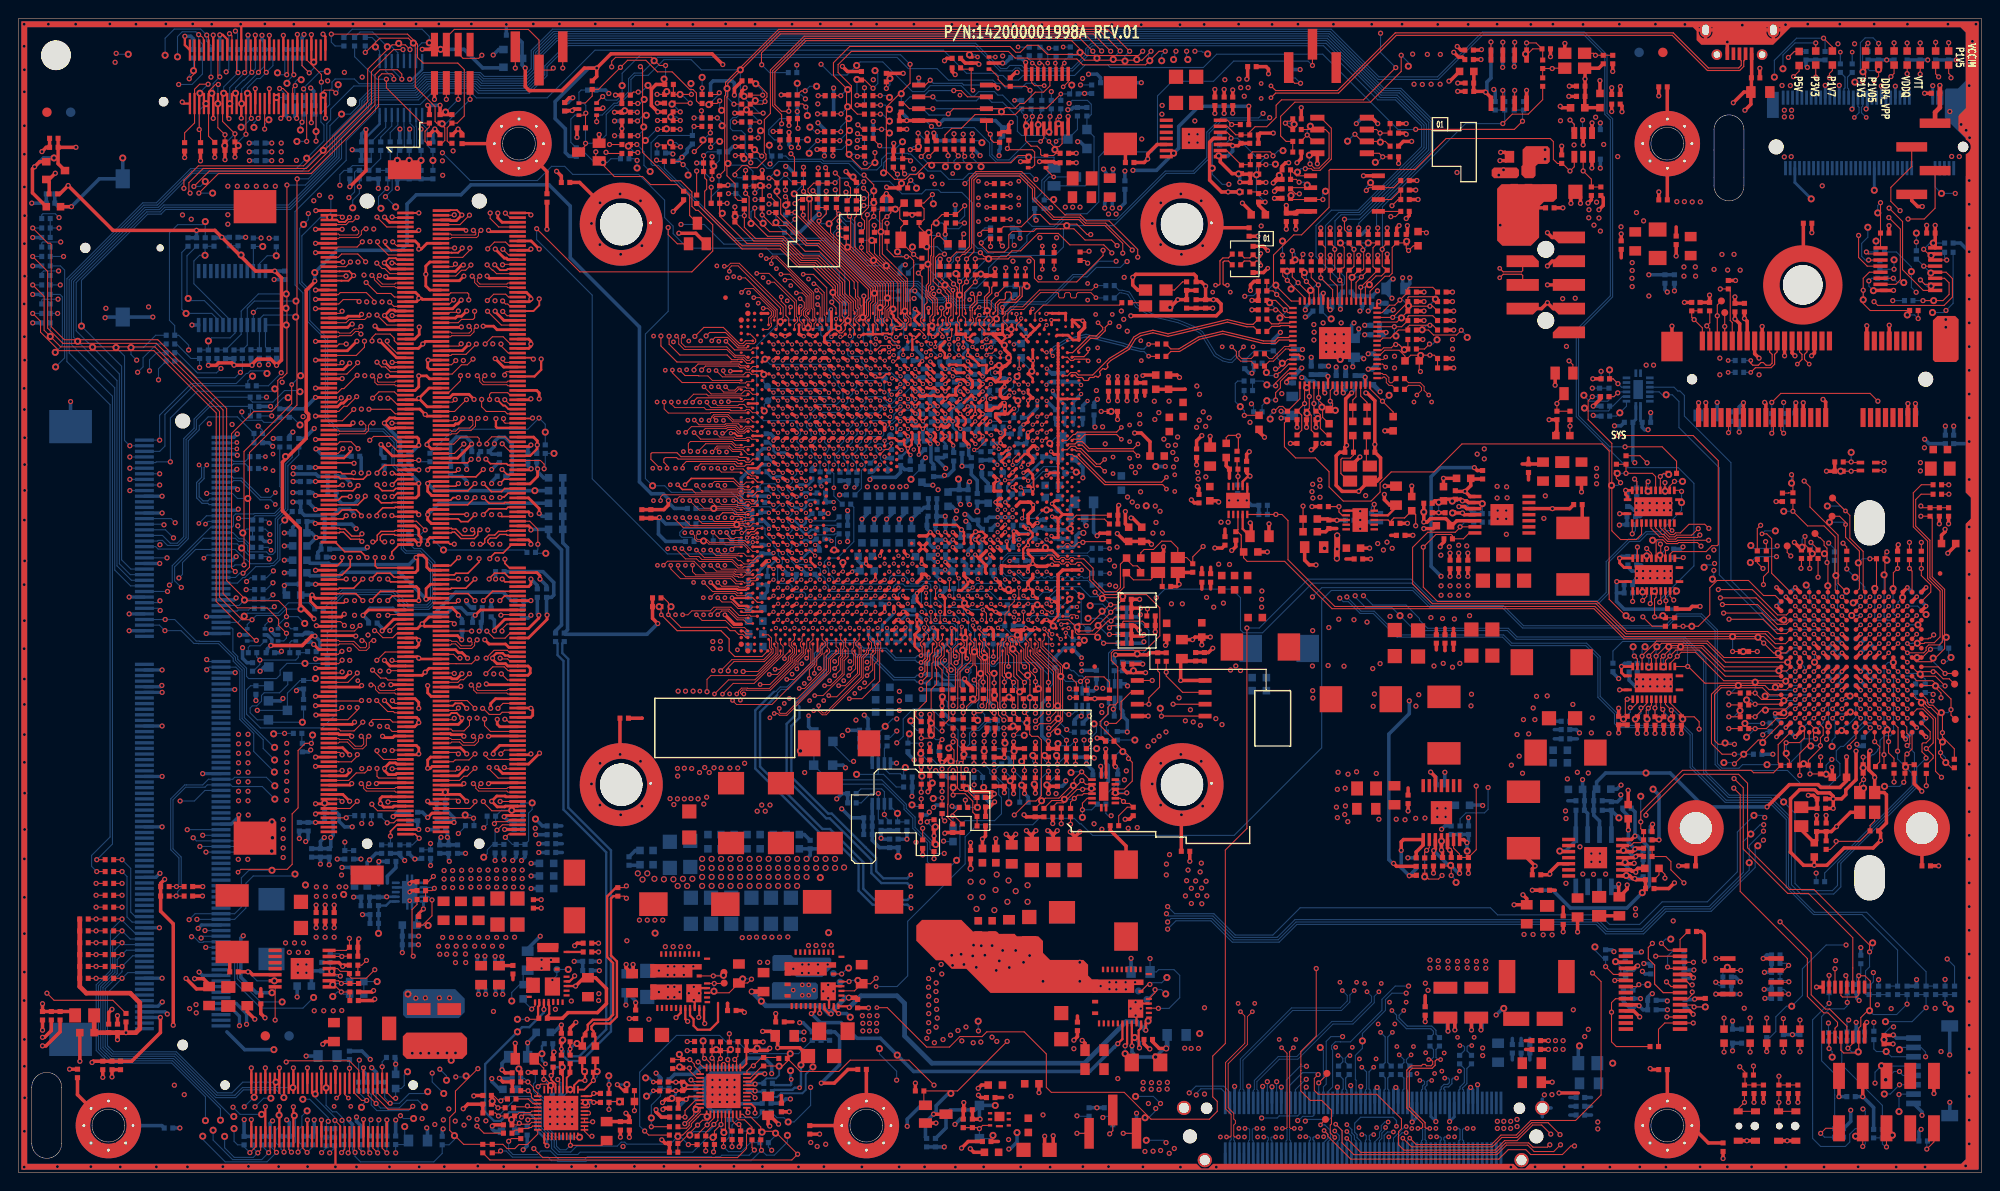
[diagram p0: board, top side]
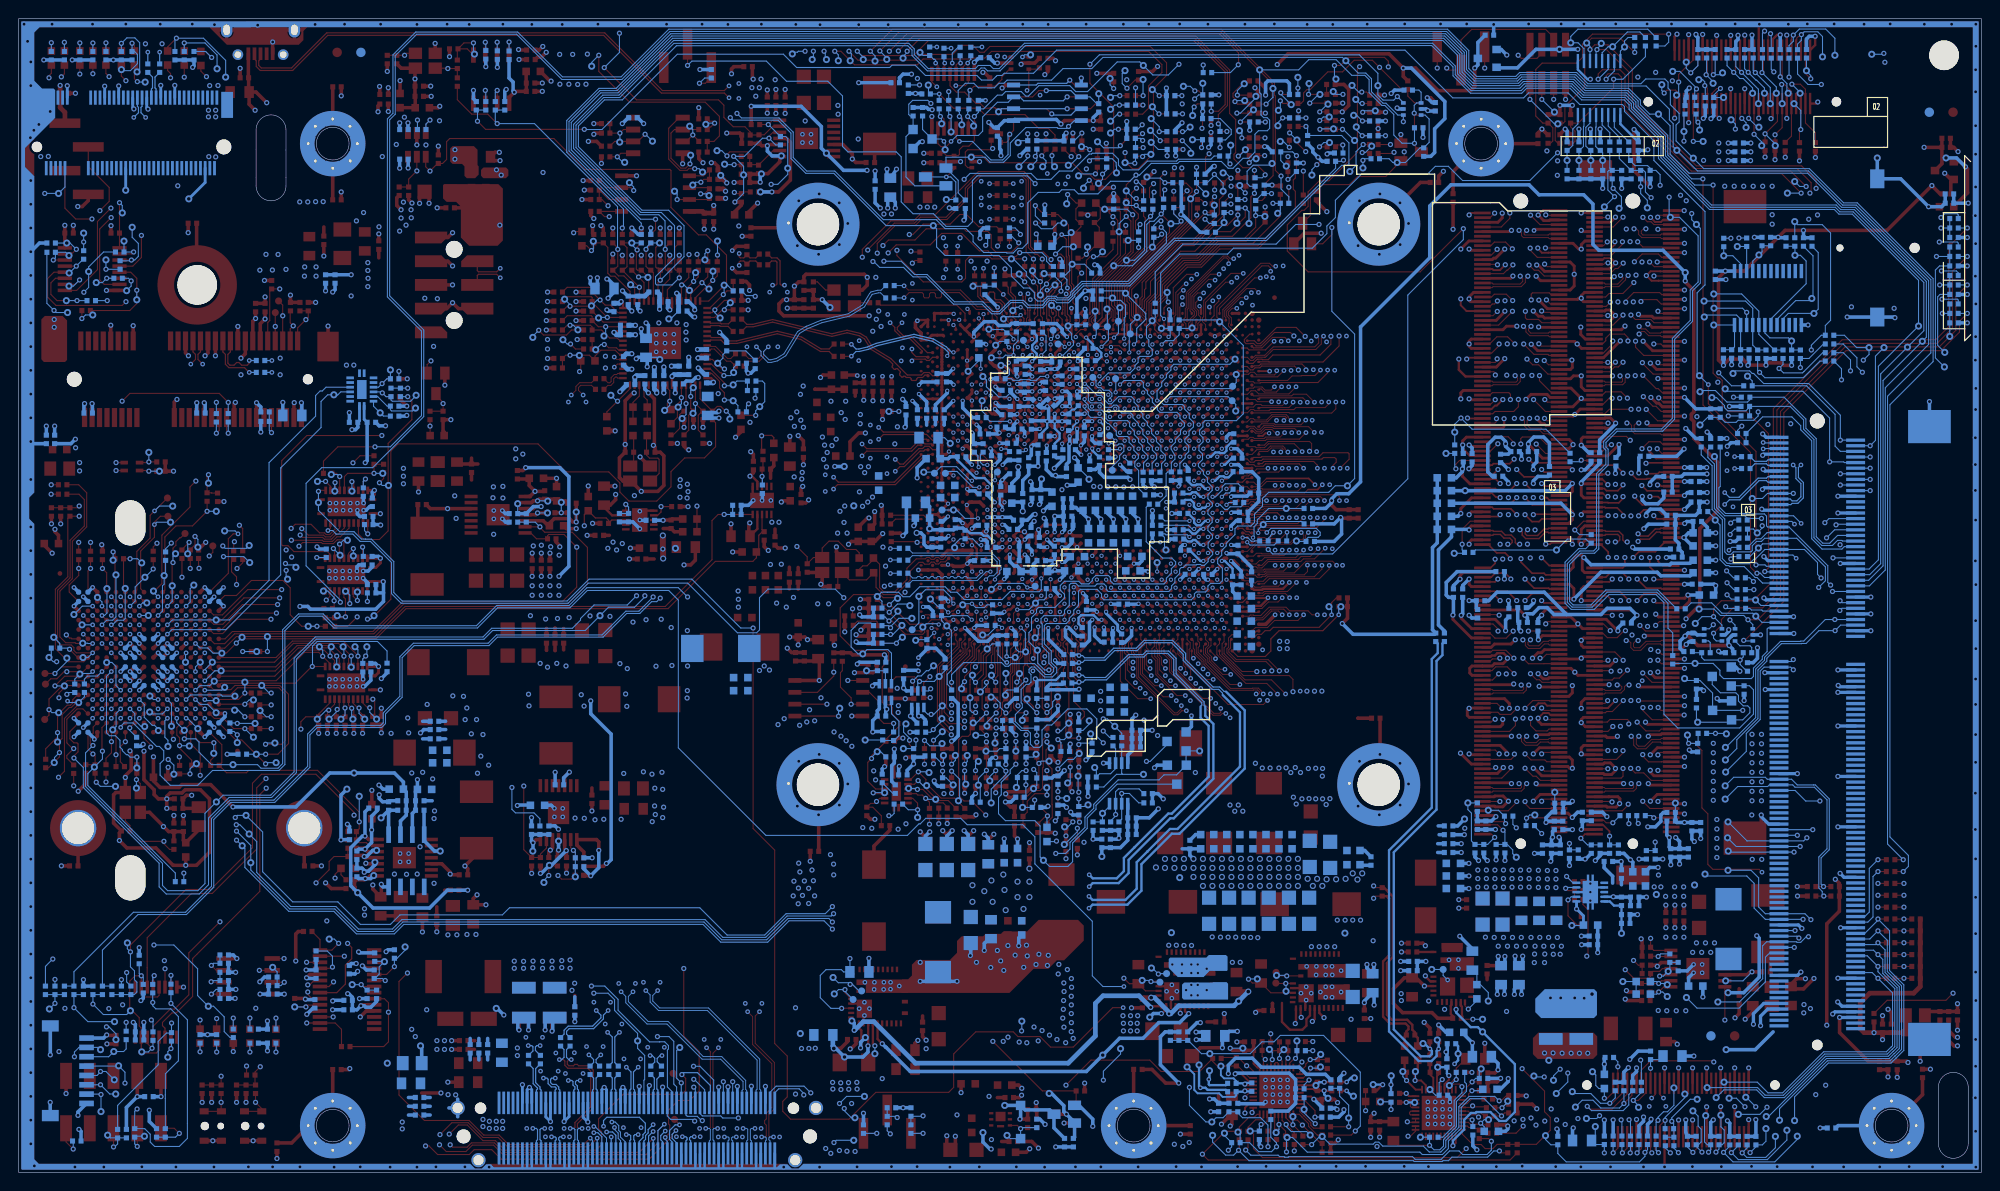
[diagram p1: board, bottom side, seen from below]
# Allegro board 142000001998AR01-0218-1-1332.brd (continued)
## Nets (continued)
GND: BA1.1(-) C1.2 C2.2 C3.2 C4.2 C5.2 C6.2 C7.2 C8.2 C9.1 C10.1 C11.2 C12.2 C13.2 C14.1 C15.2 C16.2 C17.2 C18.2 C19.2 C20.2 C21.1 C22.1 C25.1 C27.2 C28.2 C29.2 C30.2 C31.2 C33.2 C35.2 C36.2 C38.2 C39.2 C41.2 C42.1 C51.2 C52.2 C54.2 C55.2 C58.2 C59.2 C61.2 C63.2 C64.2 C65.2 C66.2 C67.2 C68.1 C69.1 C70.2 C74.1 C75.1 C76.1 C77.1 C78.1 C81.1 C82.2 C83.2 C84.2 C87.1 C88.2 C89.2 C91.2 C92.2 C93.2 C94.2 C96.2 C97.2 C98.2 C99.2 C100.2 C101.2 C102.1 C103.2 C104.2 C105.2 C106.2 C107.2 C108.2 C109.2 C111.2 C112.2 C113.2 C114.2 C115.2 C116.2 C117.2 C118.2 C119.1 C120.1 C121.2 C123.2 C124.1 C125.C C126.2 C127.2 C128.2 C130.2 C131.C C132.C C133.C C134.2 C135.2 C136.2 C137.2 C138.1 C139.2 C140.2 C141.1 C142.1 C143.2 C144.2 C145.2 C146.2 C147.2 C148.2 C149.2 C150.2 C151.2 C152.2 C153.2 C154.2 C155.1 C157.C C158.2 C161.1 C162.1 C163.1 C164.2 C165.2 C166.2 C167.C C168.2 C169.2 C170.1 C171.1 C172.2 C173.2 C174.2 C175.2 C177.1 C181.1 C182.1 C183.1 C184.1 C185.2 C186.2 C187.2 C188.2 C190.2 C191.2 C192.2 C193.2 C194.2 C195.2 C196.2 C197.2 C198.1 C199.2 C200.2 C201.2 C202.2 C203.2 C204.2 C205.1 C206.2 C207.2 C208.2 C209.2 C210.2 C211.2 C212.2 C216.2 C217.2 C218.2 C219.2 C222.2 C224.2 C225.2 C226.1 C227.2 C228.2 C233.2 C234.2 C235.2 C236.2 C239.1 C240.1 C241.2 C242.2 C248.1 C249.1 C250.2 C251.2 C252.2 C253.2 C255.1 C256.1 C257.2 C258.1 C259.2 C260.2 C262.2 C263.2 C264.2 C265.2 C266.2 C267.2 C268.2 C269.2 C270.2 C271.2 C272.1 C273.1 C274.2 C275.2 C278.2 C279.C C280.C C283.2 C284.2 C285.1 C286.1 C287.2 C289.1 C292.1 C293.1 C294.1 C295.1 C296.1 C297.1 C299.1 C300.1 C301.1 C302.1 C303.1 C304.1 C305.1 C306.1 C307.1 C308.1 C309.1 C310.1 C311.1 C312.1 C313.1 C314.1 C315.1 C316.1 C317.1 C318.2 C319.2 C320.1 C321.1 C322.2 C323.1 C324.1 C325.1 C326.1 C327.1 C328.2 C329.1 C330.1 C331.1 C332.2 C333.1 C334.1 C335.2 C336.2 C337.1 C338.1 C339.2 C341.1 C342.1 C343.2 C344.2 C345.2 C346.2 C347.2 C348.2 C349.1 C350.2 C351.1 C352.1 C353.2 C355.2 C356.2 C357.2 C358.2 C359.2 C360.2 C361.1 C362.1 C363.2 C364.1 C365.2 C366.1 C367.1 C368.1 C369.2 C370.2 C371.2 C372.1 C373.2 C374.1 C375.2 C376.2 C377.2 C378.2 C379.1 C380.1 C381.1 C382.1 C383.2 C384.1 C385.1 C386.1 C387.2 C388.1 C389.2 C390.2 C391.2 C392.2 C393.2 C394.2 C395.2 C396.2 C397.1 C398.2 C399.2 C400.2 C401.2 C402.2 C403.2 C404.1 C405.2 C406.1 C407.2 C408.2 C409.1 C410.2 C411.2 C412.2 C413.2 C414.2 C415.1 C416.1 C417.2 C418.1 C419.2 C420.2 C421.2 C422.1 C423.2 C424.2 C425.2 C426.2 C427.2 C428.2 C429.2 C430.1 C431.2 C432.1 C433.1 C434.1 C435.2 C436.2 C437.2 C438.2 C439.2 C441.2 C442.2 C443.2 C444.2 C445.2 C446.2 C447.1 C448.2 C449.2 C450.2 C452.2 C453.2 C454.2 C456.2 C457.2 C458.2 C459.2 C460.2 C461.2 C463.2 C464.2 C465.2 C466.2 C467.2 C468.2 C469.1 C470.2 C471.2 C473.2 C474.2 C475.2 C476.2 C477.2 C478.2 C479.2 C480.2 C481.1 C482.1 C483.2 C484.2 C485.2 C486.2 C487.2 C488.2 C489.1 C490.1 C491.2 C492.1 C493.1 C494.2 C495.1 C496.1 C497.1 C498.2 C499.2 C500.2 C501.2 C502.2 C503.2 C504.1 C505.2 C506.2 C507.2 C508.2 C509.2 C510.2 C511.2 C512.2 C514.2 C515.1 C516.2 C517.1 C518.2 C519.2 C520.2 C521.2 C522.2 C523.2 C524.2 C525.1 C526.2 C527.2 C528.2 C529.2 C530.1 C531.2 C532.2 C533.2 C534.2 C535.2 C536.2 C537.2 C538.2 C539.1 C540.1 C541.2 C542.2 C543.2 C544.2 C545.2 C546.2 C547.2 C548.2 C549.1 C550.2 C551.2 C552.2 C553.2 C554.2 C555.2 C556.2 C557.2 C558.2 C559.2 C560.2 C561.2 C562.2 C563.1 C564.1 C565.1 C566.1 C567.2 C568.2 C569.2 C570.2 C571.2 C572.1 C573.2 C574.2 C575.2 C576.2 C577.2 C578.2 C579.2 C580.2 C581.2 C582.1 C583.1 C584.1 C585.2 C586.2 C587.2 C588.1 C589.2 C590.1 C591.2 C592.2 C595.1 C596.2 C597.1 C598.1 C599.1 C600.2 C601.2 C602.2 C603.2 C604.2 C605.2 C606.2 C607.1 C609.2 C610.2 C611.1 C612.2 C613.1 C614.2 C615.2 C616.2 C627.2 C629.2 C631.2 C632.1 C633.2 C634.2 C635.1 C637.2 C638.1 C639.1 C640.2 C647.1 C648.2 C649.2 C650.1 C651.2 C652.2 C701.2 C702.2 C707.2 C708.2 C900.2 C901.2 C902.2 C903.C C904.2 C905.2 C906.C C907.C C908.2 C909.2 C910.2 C911.1 C912.2 C913.1 C914.1 C915.1 C925.1 C926.1 C927.1 C928.1 C929.1 C930.1 C931.1 C933.1 C934.1 C935.1 C936.1 C937.1 C938.1 C939.1 C941.1 C942.1 C943.1 C944.1 C945.1 C959.1 C960.1 C961.1 C963.2 C964.1 C965.C C966.C C967.2 C968.2 C969.2 C970.2 C971.2 C972.2 C973.2 C974.2 C975.2 C976.2 CONN1.5(GND) CONN1.G1 CONN1.G2 CONN1.G3 CONN1.G4 CONN1.G5 CONN1.G6 CONN3.2 CONN4.1 CONN4.2 CONN4.7 CONN4.8 CONN4.13 CONN4.14 CONN4.19 CONN4.20 CONN4.25 CONN4.26 CONN4.31 CONN4.32 CONN4.37 CONN4.38 CONN4.49 CONN4.50 CONN4.59 CONN4.60 CONN5.1 CONN5.3 CONN5.5 CONN5.7 CONN5.8 CONN6.4(GND1) CONN6.9(GND2) CONN6.15(GND3) CONN6.18(GND4) CONN6.21(GND5) CONN6.26(GND6) CONN6.27(GND7) CONN6.29(GND8) CONN6.34(GND9) CONN6.35(GND10) CONN6.37(GND13) CONN6.40(GND11) CONN6.50(GND12) CONN6.G1 CONN6.G2 CONN7.1(VSS_1) CONN7.2(VSS_2) CONN7.5(VSS_3) CONN7.6(VSS_4) CONN7.9(VSS_5) CONN7.10(VSS_6) CONN7.14(VSS_7) CONN7.15(VSS_8) CONN7.18(VSS_9) CONN7.19(VSS_10) CONN7.22(VSS_11) CONN7.23(VSS_12) CONN7.26(VSS_13) CONN7.27(VSS_14) CONN7.30(VSS_15) CONN7.31(VSS_16) CONN7.35(VSS_17) CONN7.36(VSS_18) CONN7.39(VSS_19) CONN7.40(VSS_20) CONN7.43(VSS_21) CONN7.44(VSS_22) CONN7.47(VSS_23) CONN7.48(VSS_24) CONN7.51(VSS_25) CONN7.52(VSS_26) CONN7.56(VSS_27) CONN7.57(VSS_28) CONN7.60(VSS_29) CONN7.61(VSS_30) CONN7.64(VSS_31) CONN7.65(VSS_32) CONN7.68(VSS_33) CONN7.69(VSS_34) CONN7.72(VSS_35) CONN7.73(VSS_36) CONN7.77(VSS_37) CONN7.78(VSS_38) CONN7.81(VSS_39) CONN7.82(VSS_40) CONN7.85(VSS_41) CONN7.86(VSS_42) CONN7.89(VSS_43) CONN7.90(VSS_44) CONN7.93(VSS_45) CONN7.94(VSS_46) CONN7.98(VSS_47) CONN7.99(VSS_48) CONN7.102(VSS_49) CONN7.103(VSS_50) CONN7.106(VSS_51) CONN7.107(VSS_52) CONN7.167(VSS_53) CONN7.168(VSS_54) CONN7.171(VSS_55) CONN7.172(VSS_56) CONN7.175(VSS_57) CONN7.176(VSS_58) CONN7.180(VSS_59) CONN7.181(VSS_60) CONN7.184(VSS_61) CONN7.185(VSS_62) CONN7.188(VSS_63) CONN7.189(VSS_64) CONN7.192(VSS_65) CONN7.193(VSS_66) CONN7.196(VSS_67) CONN7.197(VSS_68) CONN7.201(VSS_69) CONN7.202(VSS_70) CONN7.205(VSS_71) CONN7.206(VSS_72) CONN7.209(VSS_73) CONN7.210(VSS_74) CONN7.213(VSS_75) CONN7.214(VSS_76) CONN7.217(VSS_77) CONN7.218(VSS_78) CONN7.222(VSS_79) CONN7.223(VSS_80) CONN7.226(VSS_81) CONN7.227(VSS_82) CONN7.230(VSS_83) CONN7.231(VSS_84) CONN7.234(VSS_85) CONN7.235(VSS_86) CONN7.238(VSS_87) CONN7.239(VSS_88) CONN7.243(VSS_89) CONN7.244(VSS_90) CONN7.247(VSS_91) CONN7.248(VSS_92) CONN7.251(VSS_93) CONN7.252(VSS_94) CONN7.G1 CONN7.G2 CONN8.1(VSS_1) CONN8.2(VSS_2) CONN8.5(VSS_3) CONN8.6(VSS_4) CONN8.9(VSS_5) CONN8.10(VSS_6) CONN8.14(VSS_7) CONN8.15(VSS_8) CONN8.18(VSS_9) CONN8.19(VSS_10) CONN8.22(VSS_11) CONN8.23(VSS_12) CONN8.26(VSS_13) CONN8.27(VSS_14) CONN8.30(VSS_15) CONN8.31(VSS_16) CONN8.35(VSS_17) CONN8.36(VSS_18) CONN8.39(VSS_19) CONN8.40(VSS_20) CONN8.43(VSS_21) CONN8.44(VSS_22) CONN8.47(VSS_23) CONN8.48(VSS_24) CONN8.51(VSS_25) CONN8.52(VSS_26) CONN8.56(VSS_27) CONN8.57(VSS_28) CONN8.60(VSS_29) CONN8.61(VSS_30) CONN8.64(VSS_31) CONN8.65(VSS_32) CONN8.68(VSS_33) CONN8.69(VSS_34) CONN8.72(VSS_35) CONN8.73(VSS_36) CONN8.77(VSS_37) CONN8.78(VSS_38) CONN8.81(VSS_39) CONN8.82(VSS_40) CONN8.85(VSS_41) CONN8.86(VSS_42) CONN8.89(VSS_43) CONN8.90(VSS_44) CONN8.93(VSS_45) CONN8.94(VSS_46) CONN8.98(VSS_47) CONN8.99(VSS_48) CONN8.102(VSS_49) CONN8.103(VSS_50) CONN8.106(VSS_51) CONN8.107(VSS_52) CONN8.167(VSS_53) CONN8.168(VSS_54) CONN8.171(VSS_55) CONN8.172(VSS_56) CONN8.175(VSS_57) CONN8.176(VSS_58) CONN8.180(VSS_59) CONN8.181(VSS_60) CONN8.184(VSS_61) CONN8.185(VSS_62) CONN8.188(VSS_63) CONN8.189(VSS_64) CONN8.192(VSS_65) CONN8.193(VSS_66) CONN8.196(VSS_67) CONN8.197(VSS_68) CONN8.201(VSS_69) CONN8.202(VSS_70) CONN8.205(VSS_71) CONN8.206(VSS_72) CONN8.209(VSS_73) CONN8.210(VSS_74) CONN8.213(VSS_75) CONN8.214(VSS_76) CONN8.217(VSS_77) CONN8.218(VSS_78) CONN8.222(VSS_79) CONN8.223(VSS_80) CONN8.226(VSS_81) CONN8.227(VSS_82) CONN8.230(VSS_83) CONN8.231(VSS_84) CONN8.234(VSS_85) CONN8.235(VSS_86) CONN8.238(VSS_87) CONN8.239(VSS_88) CONN8.243(VSS_89) CONN8.244(VSS_90) CONN8.247(VSS_91) CONN8.248(VSS_92) CONN8.251(VSS_93) CONN8.252(VSS_94) CONN8.G1 CONN8.G2 CONN9.2 CONN9.10 CONN11.1 CONN11.2 CONN11.7 CONN11.8 CONN11.13 CONN11.14 CONN11.19 CONN11.20 CONN11.25 CONN11.26 CONN11.31 CONN11.32 CONN11.37 CONN11.38 CONN11.49 CONN11.50 CONN11.59 CONN13.1(PRESENCE_IND(GND)) CONN13.3(GND_1) CONN13.5(GND_2) CONN13.11(GND_3) CONN13.27(GND_4) CONN13.33(GND_5) CONN13.39(GND_6) CONN13.45(GND_7) CONN13.51(GND_8) CONN13.57(GND_9) CONN13.71(GND_10) CONN13.73(GND_11) CONN13.75(USB3.0_IND(OC-USB3.0/GND-OTHER)) CONN13.G1 CONN13.G2 CONN14.1 CONN14.7 CONN14.13 CONN14.19 CONN14.22 CONN14.27 CONN14.28 CONN14.45 CONN14.46 CONN14.58 CONN14.59 CONN14.64 CONN14.65 CONN14.70 CONN14.71 CONN14.76 CONN14.77 CONN14.82 CONN14.83 CONN14.84 CONN14.96 CONN14.113 CONN14.114 CONN14.131 CONN14.132 CONN14.150 CONN14.167 CONN14.168 CONN14.185 CONN14.186 CONN14.195 CONN14.196 CONN14.197 CONN14.198 CONN14.G1 CONN14.G2 CONN15.8 CONN15.G1 CONN15.G2 CONN16.11 CONN16.12 CONN16.13 CONN16.14 CONN16.15 CONN16.16 CONN16.21 CONN16.22 CONN16.23 CONN16.24 CONN16.29 CONN16.30 CONN16.31 CONN16.32 CONN16.37 CONN16.38 CONN16.39 CONN16.40 CONN16.45 CONN16.47 CONN16.53 CONN16.55 CONN16.61 CONN16.65 CONN16.71 CONN16.80 CONN16.86 CONN16.88 CONN16.90 CONN16.95 CONN16.96 CONN16.98 CONN16.99 CONN16.103 CONN16.104 CONN16.106 CONN16.109 CONN16.112 CONN16.114 CONN16.115 CONN16.120 CONN16.G1 CONN16.G2 CONN16.G3 CONN16.G4 CONN18.4 OSC1.2(GND) OSC2.2(GND) OSC4.2(GND) OSC5.2(GND1) OSC5.4(GND2) OSC6.2(GND1) OSC6.4(GND2) Q2.S Q4.S Q5.S Q6.S Q8.S Q9.2(GND) Q10.2(GND) Q11.S Q12.S Q13.S Q14.S Q16.S QFN1.1(CSIN-) QFN1.2(CSIN+) QFN1.4(PGND1) QFN1.12(PGND2) QFN1.13(PGND3) QFN1.21(LGND) QFN1.22(REFIN) R36.2 R42.1 R43.2 R64.2 R71.1 R96.1 R97.1 R99.2 R142.2 R143.2 R152.1 R153.1 R157.1 R169.1 R173.1 R196.1 R199.1 R200.2 R202.2 R211.2 R213.2 R215.2 R216.2 R217.2 R218.1 R220.2 R222.1 R232.2 R245.2 R258.2 R259.2 R260.1 R266.2 R267.1 R268.1 R274.2 R275.2 R282.1 R283.2 R287.2 R289.2 R307.2 R308.1 R310.2 R311.2 R314.1 R318.2 R319.2 R323.2 R334.2 R337.1 R367.1 R377.1 R382.1 R402.2 R417.2 R437.2 R445.2 R458.2 R468.1 R492.1 R515.2 R518.1 R519.2 R520.2 R524.1 R526.1 R527.1 R535.1 R541.2 R542.2 R544.2 R545.2 R547.2 R548.2 R549.2 R550.1 R553.2 R554.2 R555.1 R556.1 R558.1 R561.1 R564.2 R565.2 R568.2 R573.1 R575.1 R578.1 R582.1 R584.2 R586.2 R593.1 R594.2 R595.2 R596.2 R598.2 R599.2 R605.1 R609.2 R612.1 R615.2 R620.2 R623.2 R624.2 R625.2 R627.2 R630.1 R632.1 R637.2 R644.1 R645.2 R672.1 R673.1 R677.1 R679.2 R680.2 R682.2 R685.2 R688.2 R690.2 R692.2 R693.2 R694.1 R700.2 R703.2 R709.2 R720.2 R727.2 R734.2 R737.2 R743.2 R745.1 R746.2 R752.1 R755.2 R757.2 R764.2 R780.2 R785.2 R787.1 R795.2 R797.2 R799.2 R800.2 R821.1 R848.1 R855.1 R856.1 R857.1 R862.1 R863.1 R864.1 R869.2 R882.1 R902.1 R906.2 R948.1 R953.2 R954.2 R955.1 R957.1 R960.1 R970.2 R982.1 R1012.1 R1031.1 R1033.1 R1035.1 R1037.1 R1039.1 R1041.1 R1044.1 R1045.1 R1046.2 R1047.2 R1050.1 R1051.1 R1052.1 R1054.1 R1056.2 R1058.1 R1060.1 R1062.1 R1064.1 R1071.1 R1072.1 R1081.2 R1082.1 R1089.1 R1090.1 R1091.1 R1094.1 R1095.1 SW1.1 SW1.2 SW2.1 SW2.2 U1.4(GND) U2.2(GND) U4.8(PGND1) U4.9(PGND2) U4.G1(PWGD) U5.4(GND) U6.G1(GND) U7.8(GND) U8.6(GND1) U8.G1(GND2) U9.A3(VSS_4) U9.A5(VSS_6) U9.A6(VSS_7) U9.A20(VSS_3) U9.A77(VSS_9) U9.AA12(VSS_537) U9.AA14(VSS_21) U9.AA16(VSS_25) U9.AA19(VSS_518) U9.AA21(VSS_478) U9.AA23(VSS_10) U9.AA25(VSS_11) U9.AA56(VSS_14) U9.AA60(VSS_15) U9.AA62(VSS_16) U9.AA69(VSS_17) U9.AB5(VSS_18) U9.AB74(VSS_19) U9.AC2(VSS_23) U9.AC12(VSS_20) U9.AC16(VSS_22) U9.AC18(VSS_434) U9.AC27(VSS_24) U9.AC58(VSS_26) U9.AD5(VSS_28) U9.AE7(VSS_34) U9.AE11(VSS_29) U9.AE14(VSS_535) U9.AE19(VSS_30) U9.AE23(VSS_31) U9.AE64(VSS_32) U9.AE67(VSS_33) U9.AE71(VSS_35) U9.AF5(VSS_36) U9.AF9(VSS_40) U9.AF74(VSS_37) U9.AF76(VSS_38) U9.AF78(VSS_39) U9.AG12(VSS_536) U9.AG16(VSS_534) U9.AG21(VSS_2) U9.AG62(VSS_41) U9.AH3(VSS_50) U9.AH5(VSS_52) U9.AH12(VSS_42) U9.AH16(VSS_44) U9.AH18(VSS_45) U9.AH19(VSS_46) U9.AH25(VSS_47) U9.AH27(VSS_48) U9.AH28(VSS_49) U9.AH30(VSS_51) U9.AH53(VSS_53) U9.AH56(VSS_55) U9.AH66(VSS_56) U9.AH69(VSS_57) U9.AH74(VSS_58) U9.AK12(VSS_1) U9.AK16(VSS_59) U9.AK19(VSS_60) U9.AK60(VSS_63) U9.AK75(VSS_64) U9.AK77(VSS_65) U9.AL7(VSS_69) U9.AL11(VSS_66) U9.AL64(VSS_67) U9.AL67(VSS_68) U9.AL71(VSS_70) U9.AM9(VSS_75) U9.AM19(VSS_71) U9.AM21(VSS_72) U9.AM28(VSS_73) U9.AM30(VSS_74) U9.AN5(VSS_76) U9.AN74(VSS_77) U9.AN76(VSS_78) U9.AP14(VSS_79) U9.AP19(VSS_80) U9.AP23(VSS_81) U9.AP53(VSS_118) U9.AR1(VSS_84) U9.AR3(VSS_88) U9.AR5(VSS_89) U9.AR12(VSS_85) U9.AR19(VSS_86) U9.AR25(VSS_87) U9.AR53(VSS_125) U9.AR55(VSS_90) U9.AR56(VSS_431) U9.AR60(VSS_91) U9.AU1(VSS_94) U9.AU3(VSS_99) U9.AU5(VSS_101) U9.AU19(VSS_95) U9.AU23(VSS_96) U9.AU25(VSS_97) U9.AU28(VSS_98) U9.AU30(VSS_100) U9.AU53(VSS_192) U9.AU55(VSS_102) U9.AU56(VSS_103) U9.AU58(VSS_104) U9.AU62(VSS_105) U9.AU66(VSS_106) U9.AU69(VSS_107) U9.AU72(VSS_108) U9.AU74(VSS_109) U9.AU76(VSS_54) U9.AU78(VSS_541) U9.AV2(VSS_538) U9.AV64(VSS_110) U9.AV67(VSS_111) U9.AV71(VSS_112) U9.AV75(VSS_113) U9.AV77(VSS_114) U9.AW5(VSS_115) U9.AW9(VSS_116) U9.B2(VSS_117) U9.B3(VSS_530) U9.B48(VSS_531) U9.B61(VSS_5) U9.B74(VSS_93) U9.B76(VSS_256) U9.B77(VSS_119) U9.B78(VSS_120) U9.BA3(VSS_124) U9.BA12(VSS_121) U9.BA16(VSS_122) U9.BA28(VSS_123) U9.BA56(VSS_126) U9.BB2(VSS_533) U9.BB19(VSS_127) U9.BB33(VSS_8) U9.BB35(VSS_128) U9.BD1(VSS_129) U9.BD5(VSS_132) U9.BD14(VSS_130) U9.BD33(VSS_131) U9.BE9(VSS_140) U9.BE28(VSS_133) U9.BE35(VSS_134) U9.BE66(VSS_135) U9.BE69(VSS_136) U9.BE72(VSS_137) U9.BE75(VSS_138) U9.BE77(VSS_139) U9.BF5(VSS_143) U9.BF26(VSS_141) U9.BF30(VSS_142) U9.BF56(VSS_144) U9.BF64(VSS_145) U9.BF67(VSS_146) U9.BF71(VSS_147) U9.BF74(VSS_148) U9.BF76(VSS_149) U9.BF78(VSS_150) U9.BG24(VSS_151) U9.BG35(VSS_152) U9.BG62(VSS_153) U9.BG69(VSS_154) U9.BH3(VSS_158) U9.BH5(VSS_160) U9.BH11(VSS_155) U9.BH14(VSS_156) U9.BH18(VSS_157) U9.BH30(VSS_159) U9.BH60(VSS_161) U9.BH64(VSS_162) U9.BH74(VSS_163) U9.BJ24(VSS_164) U9.BJ35(VSS_165) U9.BJ58(VSS_166) U9.BJ69(VSS_167) U9.BK1(VSS_168) U9.BK5(VSS_170) U9.BK37(VSS_169) U9.BK74(VSS_171) U9.BL30(VSS_172) U9.BL56(VSS_173) U9.BL64(VSS_174) U9.BM9(VSS_182) U9.BM13(VSS_175) U9.BM16(VSS_176) U9.BM20(VSS_177) U9.BM24(VSS_178) U9.BM35(VSS_179) U9.BM58(VSS_193) U9.BM69(VSS_180) U9.BM74(VSS_181) U9.BN30(VSS_183) U9.BN37(VSS_184) U9.BN56(VSS_205) U9.BN60(VSS_185) U9.BN64(VSS_186) U9.BN75(VSS_187) U9.BN77(VSS_188) U9.BP3(VSS_190) U9.BP24(VSS_189) U9.BP35(VSS_191) U9.BP62(VSS_194) U9.BP69(VSS_195) U9.BP74(VSS_196) U9.BR11(VSS_197) U9.BR14(VSS_198) U9.BR18(VSS_199) U9.BR22(VSS_200) U9.BR30(VSS_201) U9.BR64(VSS_202) U9.BT24(VSS_203) U9.BT35(VSS_204) U9.BT56(VSS_206) U9.BT58(VSS_519) U9.BT69(VSS_207) U9.BT74(VSS_208) U9.BU2(VSS_209) U9.BU4(VSS_212) U9.BU30(VSS_210) U9.BU37(VSS_211) U9.BU64(VSS_213) U9.BV9(VSS_220) U9.BV13(VSS_214) U9.BV24(VSS_215) U9.BV35(VSS_216) U9.BV56(VSS_520) U9.BV58(VSS_217) U9.BV62(VSS_218) U9.BV69(VSS_219) U9.BW5(VSS_231) U9.BW7(VSS_238) U9.BW11(VSS_221) U9.BW14(VSS_222) U9.BW30(VSS_223) U9.BW39(VSS_224) U9.BW40(VSS_225) U9.BW42(VSS_226) U9.BW43(VSS_227) U9.BW45(VSS_228) U9.BW47(VSS_229) U9.BW49(VSS_230) U9.BW50(VSS_232) U9.BW52(VSS_233) U9.BW54(VSS_234) U9.BW55(VSS_235) U9.BW60(VSS_236) U9.BW64(VSS_237) U9.BW74(VSS_239) U9.BY16(VSS_240) U9.BY20(VSS_241) U9.BY24(VSS_242) U9.BY28(VSS_243) U9.BY35(VSS_244) U9.BY39(VSS_245) U9.BY43(VSS_246) U9.BY54(VSS_247) U9.BY58(VSS_248) U9.BY62(VSS_249) U9.BY66(VSS_250) U9.BY69(VSS_251) U9.BY72(VSS_252) U9.C1(VSS_253) U9.C2(VSS_254) U9.C20(VSS_255) U9.C77(VSS_257) U9.C78(VSS_258) U9.CA5(VSS_268) U9.CA11(VSS_259) U9.CA18(VSS_260) U9.CA22(VSS_261) U9.CA26(VSS_262) U9.CA30(VSS_263) U9.CA41(VSS_264) U9.CA45(VSS_265) U9.CA46(VSS_266) U9.CA49(VSS_267) U9.CA51(VSS_269) U9.CA52(VSS_270) U9.CA56(VSS_271) U9.CA60(VSS_272) U9.CA64(VSS_273) U9.CA67(VSS_274) U9.CA71(VSS_275) U9.CA74(VSS_276) U9.CA76(VSS_277) U9.CA78(VSS_278) U9.CB16(VSS_279) U9.CB32(VSS_280) U9.CB35(VSS_281) U9.CB47(VSS_282) U9.CB51(VSS_283) U9.CB54(VSS_284) U9.CB58(VSS_285) U9.CB62(VSS_286) U9.CC5(VSS_293) U9.CC11(VSS_287) U9.CC30(VSS_288) U9.CC33(VSS_289) U9.CC37(VSS_290) U9.CC41(VSS_291) U9.CC45(VSS_292) U9.CC74(VSS_294) U9.CD16(VSS_295) U9.CD43(VSS_296) U9.CD47(VSS_297) U9.CD62(VSS_298) U9.CE1(VSS_299) U9.CE3(VSS_300) U9.CE5(VSS_301) U9.CE74(VSS_302) U9.CF11(VSS_303) U9.CF30(VSS_304) U9.CG5(VSS_309) U9.CG16(VSS_305) U9.CG20(VSS_306) U9.CG24(VSS_307) U9.CG28(VSS_308) U9.CG62(VSS_310) U9.CG66(VSS_311) U9.CG69(VSS_312) U9.CG72(VSS_313) U9.CG74(VSS_314) U9.CH11(VSS_315) U9.CH18(VSS_316) U9.CH22(VSS_317) U9.CH26(VSS_318) U9.CH30(VSS_319) U9.CH64(VSS_320) U9.CH67(VSS_321) U9.CH71(VSS_322) U9.CH75(VSS_323) U9.CH77(VSS_324) U9.CJ5(VSS_326) U9.CJ16(VSS_325) U9.CJ62(VSS_327) U9.CJ74(VSS_328) U9.CK11(VSS_329) U9.CK30(VSS_330) U9.CL5(VSS_332) U9.CL16(VSS_331) U9.CL62(VSS_333) U9.CL74(VSS_334) U9.CM1(VSS_335) U9.CM11(VSS_336) U9.CM30(VSS_337) U9.CN5(VSS_338) U9.CN74(VSS_339) U9.CP1(VSS_340) U9.CP2(VSS_345) U9.CP7(VSS_356) U9.CP9(VSS_361) U9.CP12(VSS_341) U9.CP14(VSS_342) U9.CP16(VSS_343) U9.CP18(VSS_344) U9.CP20(VSS_346) U9.CP23(VSS_347) U9.CP25(VSS_348) U9.CP27(VSS_349) U9.CP29(VSS_350) U9.CP31(VSS_351) U9.CP34(VSS_352) U9.CP36(VSS_353) U9.CP64(VSS_354) U9.CP66(VSS_355) U9.CP70(VSS_357) U9.CP72(VSS_358) U9.CP77(VSS_359) U9.CP78(VSS_360) U9.CR1(VSS_362) U9.CR2(VSS_363) U9.CR3(VSS_365) U9.CR5(VSS_367) U9.CR21(VSS_364) U9.CR37(VSS_366) U9.CR77(VSS_368) U9.CR78(VSS_369) U9.CT14(VSS_370) U9.CT29(VSS_371) U9.CT70(VSS_372) U9.CU1(VSS_373) U9.CU2(VSS_374) U9.CU3(VSS_376) U9.CU21(VSS_375) U9.CU37(VSS_377) U9.CU77(VSS_378) U9.CU78(VSS_379) U9.CV2(VSS_381) U9.CV3(VSS_383) U9.CV5(VSS_384) U9.CV6(VSS_385) U9.CV14(VSS_380) U9.CV29(VSS_382) U9.CV70(VSS_386) U9.CV73(VSS_387) U9.CV74(VSS_388) U9.CV76(VSS_389) U9.CV77(VSS_390) U9.D5(VSS_529) U9.D48(VSS_532) U9.D61(VSS_391) U9.E1(VSS_392) U9.E2(VSS_397) U9.E5(VSS_412) U9.E7(VSS_422) U9.E9(VSS_428) U9.E12(VSS_393) U9.E14(VSS_394) U9.E16(VSS_395) U9.E18(VSS_396) U9.E20(VSS_398) U9.E23(VSS_399) U9.E25(VSS_400) U9.E27(VSS_401) U9.E29(VSS_402) U9.E31(VSS_403) U9.E34(VSS_404) U9.E36(VSS_405) U9.E38(VSS_406) U9.E40(VSS_407) U9.E42(VSS_408) U9.E44(VSS_409) U9.E47(VSS_410) U9.E49(VSS_411) U9.E51(VSS_413) U9.E53(VSS_414) U9.E58(VSS_416) U9.E60(VSS_417) U9.E62(VSS_418) U9.E64(VSS_419) U9.E66(VSS_420) U9.E68(VSS_421) U9.E70(VSS_423) U9.E74(VSS_425) U9.E77(VSS_426) U9.E78(VSS_427) U9.F1(VSS_429) U9.F3(VSS_12) U9.F72(VSS_415) U9.F78(VSS_92) U9.H56(VSS_424) U9.H60(VSS_432) U9.H67(VSS_433) U9.J3(VSS_27) U9.J72(VSS_436) U9.J74(VSS_437) U9.K4(VSS_43) U9.K56(VSS_430) U9.K60(VSS_438) U9.K67(VSS_439) U9.L1(VSS_61) U9.L3(VSS_13) U9.L5(VSS_450) U9.L9(VSS_456) U9.L13(VSS_440) U9.L16(VSS_441) U9.L20(VSS_442) U9.L24(VSS_443) U9.L28(VSS_444) U9.L32(VSS_445) U9.L35(VSS_446) U9.L39(VSS_447) U9.L43(VSS_448) U9.L47(VSS_449) U9.L51(VSS_451) U9.L58(VSS_452) U9.L62(VSS_453) U9.L66(VSS_454) U9.L69(VSS_435) U9.L74(VSS_455) U9.M7(VSS_472) U9.M11(VSS_457) U9.M14(VSS_458) U9.M18(VSS_459) U9.M22(VSS_460) U9.M26(VSS_461) U9.M30(VSS_462) U9.M33(VSS_463) U9.M37(VSS_464) U9.M41(VSS_465) U9.M45(VSS_466) U9.M49(VSS_467) U9.M52(VSS_468) U9.M56(VSS_469) U9.M60(VSS_470) U9.M64(VSS_471) U9.M71(VSS_473) U9.N5(VSS_474) U9.N66(VSS_475) U9.N74(VSS_476) U9.N76(VSS_477) U9.P52(VSS_479) U9.P60(VSS_480) U9.R35(VSS_481) U9.R37(VSS_482) U9.R40(VSS_483) U9.R42(VSS_484) U9.R46(VSS_83) U9.R54(VSS_485) U9.R66(VSS_486) U9.R69(VSS_487) U9.T5(VSS_491) U9.T11(VSS_488) U9.T33(VSS_489) U9.T39(VSS_490) U9.T60(VSS_492) U9.T74(VSS_493) U9.U9(VSS_501) U9.U13(VSS_494) U9.U16(VSS_495) U9.U20(VSS_496) U9.U24(VSS_497) U9.U28(VSS_498) U9.U32(VSS_499) U9.U66(VSS_500) U9.V1(VSS_82) U9.V3(VSS_62) U9.V5(VSS_511) U9.V7(VSS_516) U9.V14(VSS_502) U9.V18(VSS_503) U9.V22(VSS_504) U9.V26(VSS_505) U9.V30(VSS_506) U9.V35(VSS_507) U9.V42(VSS_508) U9.V44(VSS_509) U9.V46(VSS_510) U9.V55(VSS_512) U9.V60(VSS_513) U9.V62(VSS_514) U9.V64(VSS_515) U9.V71(VSS_517) U9.W13(VSS_539) U9.W16(VSS_540) U9.W24(VSS_528) U9.Y5(VSS_524) U9.Y39(VSS_521) U9.Y40(VSS_522) U9.Y42(VSS_523) U9.Y55(VSS_525) U9.Y74(VSS_526) U9.Y76(VSS_527) U10.11(GND1) U10.12(GND2) U10.13(GND3) U10.G1 U11.6(GND1) U11.G1(GND2) U12.A1(GNDIO_1) U12.A16(GNDIO_2) U12.B2(GNDIO_4) U12.B15(GNDIO_3) U12.G5(GNDIO_6) U12.G7(GNDIO_7) U12.G8(GNDIO_8) U12.G9(GNDIO_9) U12.G10(GNDIO_5) U12.H7(GNDINT_1) U12.H9(GNDINT_2) U12.J8(GNDINT_4) U12.J10(GNDINT_3) U12.K7(GNDIO_11) U12.K8(GNDIO_12) U12.K9(GNDIO_13) U12.K10(GNDIO_10) U12.R2(GNDIO_15) U12.R15(GNDIO_14) U12.T1(GNDIO_16) U12.T16(GNDIO_17) U13.11(GND1) U13.12(GND2) U13.13(GND3) U13.G1 U14.11(GND1) U14.12(GND2) U14.13(GND3) U14.G1 U15.8(PGND1) U15.9(PGND2) U15.G1(PWGD) U16.4(GND) U17.4(GND_1) U17.11(GND_2) U17.18(GND_3) U18.8(GND1) U18.9(GND2) U18.14(2O\E\) U18.15(1O\E\) U18.G1 U19.4(GND) U20.4(GND) U21.8(GND) U22.8(PGND1) U22.9(PGND2) U22.G1(PWGD) U23.8(PGND1) U23.9(PGND2) U23.G1(PWGD) U24.4(PGND1) U24.16(PGND2) U24.17(PGND3) U24.28(LGND) U24.31(PGND4) U25.4(PGND1) U25.16(PGND2) U25.17(PGND3) U25.28(LGND) U25.31(PGND4) U26.4(PGND1) U26.16(PGND2) U26.17(PGND3) U26.28(LGND) U26.31(PGND4) U27.8(PGND1) U27.9(PGND2) U27.G1(PWGD) U28.23(PWM3) U28.24(PWM4) U28.G1(GND) U29.22(PWM2) U29.23(PWM3) U29.24(PWM2_L2) U29.25(PWM1_L2) U29.G1 U31.4(GND) U32.2(GND) U33.12(GND) U34.8(GND1) U34.9(GND2) U34.14(2O\E\) U34.15(1O\E\) U34.G1 U35.5(GND1) U35.6(GND2) U35.7(GND3) U35.8(GND4) U36.4(GND) U37.4(PGND) U37.8(GND) U37.11(PWPD) U38.2(GND) U39.4(GND) U40.2(GND) U41.2(GND) U42.2(GND) U43.8(GND) U44.2(GND) U45.8(VSS)
GND_SCREW1: C234.1 C637.1 H7.1 H7.2 H7.3 H7.4 H7.5 H7.6 H7.7 H7.8
GND_SCREW2: C3.1 C36.1 H2.1 H2.2 H2.3 H2.4 H2.5 H2.6 H2.7 H2.8
GND_SCREW3: C228.1 C257.1 H8.1 H8.2 H8.3 H8.4 H8.5 H8.6 H8.7 H8.8
GND_SCREW4: C15.1 C35.1 H1.1 H1.2 H1.3 H1.4 H1.5 H1.6 H1.7 H1.8
GND_SCREW5: C227.1 C253.1 H9.1 H9.2 H9.3 H9.4 H9.5 H9.6 H9.7 H9.8
P0V6_VTT: C520.1 C521.1 C523.1 C524.1 C564.2 C566.2 C568.1 C569.1 CONN7.258(VTT) CONN8.258(VTT) U37.3(VO) U37.5(VOSNS)
P0V9_A_L_I210: C933.2 C934.2 C935.2 C936.2 C937.2 C938.2 C939.2 C959.2 U6.11(VDD0P9_11) U6.32(VDD0P9_32) U6.38(VDD0P9_OUT) U6.42(VDD0P9_42) U6.59(VDD0P9_59)
P1V2_VDD_BOOST: QFN1.17(BOOST) R710.2
P1V2_VDD_BOOST_R: C594.2 R710.1
P1V2_VDDQ: C161.2 C162.2 C163.2 C165.1 C166.1 C328.1 C335.1 C336.1 C339.1 C343.1 C344.1 C345.1 C346.1 C347.1 C348.1 C350.1 C353.1 C359.1 C360.1 C363.1 C365.1 C369.1 C370.1 C371.1 C373.1 C376.1 C377.1 C378.1 C383.1 C387.1 C389.1 C395.1 C400.1 C401.1 C403.1 C405.1 C407.1 C408.1 C410.1 C420.1 C421.1 C423.1 C429.1 C439.1 C442.1 C444.1 C446.1 C450.1 C459.1 C463.1 C465.1 C466.1 C467.1 C468.1 C470.1 C471.1 C473.1 C474.1 C475.1 C476.1 C483.1 C484.1 C485.1 C486.1 C487.1 C488.1 C491.1 C494.1 C498.1 C525.2 C530.2 C539.2 C549.2 C565.2 C572.2 C574.1 C575.1 C582.2 C583.2 C584.2 C586.1 C587.1 CONN7.111(VDD_1) CONN7.112(VDD_2) CONN7.117(VDD_3) CONN7.118(VDD_4) CONN7.123(VDD_5) CONN7.124(VDD_6) CONN7.129(VDD_7) CONN7.130(VDD_8) CONN7.135(VDD_9) CONN7.136(VDD_10) CONN7.141(VDD_11) CONN7.142(VDD_12) CONN7.147(VDD_13) CONN7.148(VDD_14) CONN7.153(VDD_15) CONN7.154(VDD_16) CONN7.159(VDD_17) CONN7.160(VDD_18) CONN7.163(VDD_19) CONN8.111(VDD_1) CONN8.112(VDD_2) CONN8.117(VDD_3) CONN8.118(VDD_4) CONN8.123(VDD_5) CONN8.124(VDD_6) CONN8.129(VDD_7) CONN8.130(VDD_8) CONN8.135(VDD_9) CONN8.136(VDD_10) CONN8.141(VDD_11) CONN8.142(VDD_12) CONN8.147(VDD_13) CONN8.148(VDD_14) CONN8.153(VDD_15) CONN8.154(VDD_16) CONN8.159(VDD_17) CONN8.160(VDD_18) CONN8.163(VDD_19) L14.2 R333.1 R350.1 R580.1 R592.1 R693.1 R699.1 U9.CF60(VCCD_14) U9.CG43(VCCD_1) U9.CG51(VCCD_2) U9.CG54(VCCD_12) U9.CG58(VCCD_3) U9.CH33(VCCD_4) U9.CH37(VCCD_5) U9.CH41(VCCD_6) U9.CH45(VCCD_7) U9.CH49(VCCD_8) U9.CH56(VCCD_10) U9.CJ39(VCCD_13) U9.CK52(VCCD_34) U9.CK60(VCCD_11) U9.CL35(VCCD_9) U9.CL58(VCCD_37) U9.CP38(VCCD_15) U9.CP40(VCCD_16) U9.CP42(VCCD_17) U9.CP44(VCCD_18) U9.CP47(VCCD_19) U9.CP49(VCCD_20) U9.CP51(VCCD_21) U9.CP53(VCCD_22) U9.CP55(VCCD_23) U9.CP58(VCCD_24) U9.CP60(VCCD_25) U9.CP62(VCCD_38) U9.CP68(VCCD_39) U9.CT55(VCCD_26) U9.CU39(VCCD_27) U9.CU43(VCCD_28) U9.CU48(VCCD_29) U9.CU52(VCCD_30) U9.CU59(VCCD_31) U9.CU63(VCCD_32) U9.CU65(VCCD_35) U9.CU67(VCCD_33) U9.CU69(VCCD_36) U37.2(VLDOIN)
P1V2_VDDQ_IRQ_VRHOT_N: U12.P11(IO_4_P11/DIFFIO_B21P) U29.16(VRHOT_CRIT)
P1V05: C52.1 C100.1 C114.1 C128.1 C143.1 C144.1 C145.1 C146.1 C147.1 C148.1 C149.1 C150.1 C151.1 C152.1 C279.A C291.1 C318.1 C385.2 C396.1 C443.1 C509.1 C510.1 C511.1 C512.1 C545.1 C546.1 C547.1 C548.1 C555.1 C556.1 C557.1 C558.1 C559.1 C560.1 C906.A C974.1 L7.1 L8.1 L9.1 L10.1 L17.2 L32.1 L33.1 Q9.6(VCCB) Q10.1(VCCA) R20.1 R58.2 R59.2 R60.2 R148.2 R203.2 R204.2 R206.2 R208.2 R209.2 R210.2 R214.2 R219.1 R237.2 R244.2 R250.2 R251.2 R261.1 R262.1 R263.1 R264.1 R269.2 R270.2 R271.2 R272.2 R276.1 R284.1 R285.2 R290.2 R291.2 R292.2 R294.2 R295.2 R296.2 R305.1 R306.2 R309.2 R369.1 R374.2 R379.2 R453.1 R463.1 R563.2 R572.1 R583.1 R587.1 R590.2 R597.2 R602.1 R604.2 R610.1 R614.1 R616.1 R617.2 R626.1 R628.2 R633.1 R635.1 R636.1 R638.1 R639.1 R642.1 R643.1 R725.1 R726.2 R730.2 R738.2 R739.2 R749.1 R760.2 R765.2 R766.2 R767.2 R768.2 R769.2 R771.2 R772.2 R773.2 R774.2 R793.2 R794.1 R796.1 R798.1 R1048.1 R1049.2 R1053.2 U10.1(VCCA) U13.23(VCCB1) U13.24(VCCB2) U14.1(VCCA) U18.16(VCCB) U34.1(VCCA) U36.1(VCCA)
P1V5_A_L_I210: C941.2 C942.2 C943.2 C944.2 C945.2 C960.2 U6.39(VDD1P5_OUT) U6.47(VDD1P5_47) U6.51(VDD3P3_51)
P1V05_PCH: C68.2 C69.2 C74.2 C75.2 C76.2 C77.2 C78.2 C299.2 C300.2 C302.2 C311.2 C313.2 C314.2 C315.2 C316.2 C317.2 C331.2 L7.2 L34.1 U9.AC23(VCCCLK_4) U9.AC25(VCCCLK_2) U9.AE21(VCCCLK_1) U9.AE25(VCCCLK_6) U9.AG25(VCCCLK_8) U9.AG27(VCCIO_5) U9.AH21(VCCIO_1) U9.AH23(VCCCLK_5) U9.AK18(VCCIO_2) U9.AK27(VCCIO_6) U9.AM14(VCCUSBPLL) U9.AM16(VCCIO_3) U9.AM18(VCCIO_4) U9.AM27(VCCIO_7) U9.AP27(VCCIO_8) U9.AR27(VCCIO_9) U9.AU27(VCCIO_10) U9.AW27(VCCIO_11)
P1V5_PCH: C87.2 C88.1 C90.2 C93.1 C94.1 C303.2 C322.1 C323.2 C325.2 C330.2 C338.2 C341.2 C349.2 C352.2 R5.1 R180.1 R192.2 R487.1 R543.1 U9.AC28(VCCVRM_10) U9.AC30(VCCVRM_2) U9.AE28(VCCVRM_5) U9.AE30(VCCVRM_6) U9.AG19(VCCADAC1_5) U9.AK28(VCCVRM_8) U9.AK30(VCCVRM_9) U9.AW28(VCCVRM_1) U9.AW30(VCCVRM_7) U9.BA30(VCCVRM_4) U9.BB30(VCCVRM_3) U9.BD30(SATA_IREF) U9.V33(SOC_IREF) U9.W20(ICLK_IREF) U9.W28(PCIE_IREF) U11.9(OUT1) U11.10(OUT2)
P1V05_PCH_FLT: C305.2 C310.2 C362.2 L33.2 U9.AC21(VCCCLK_3) U9.AG23(VCCCLK_7)
P1V05_VCC_PCH: C308.2 C309.2 C320.2 C321.2 C326.2 C334.2 L8.2 U9.AK21(VCC_1) U9.AK23(VCC_2) U9.AK25(VCC_3) U9.AM23(VCC_4) U9.AM25(VCC_5) U9.AP25(VCC_6)
P1V05_VCCGBE: C104.1 C105.1 C106.1 C107.1 C419.1 C456.1 C457.1 C458.1 C965.A C966.A C967.1 C968.1 C969.1 C970.1 C971.1 C972.1 C973.1 C975.1 C976.1 L10.2 L30.2 L35.2 U9.AA58(VCCGBE_1) U9.R58(VCCGBE_11) U9.T51(VCCGBE_6) U9.T53(VCCGBE_7) U9.V51(VCCGBE_8) U9.V53(VCCGBE_9) U9.V56(VCCGBE_2) U9.V58(VCCGBE_3) U9.Y53(VCCGBE_10) U9.Y56(VCCGBE_4) U9.Y58(VCCGBE_5)
P1V05_VCCION: C306.2 C329.2 C386.2 C397.2 C404.2 C415.2 C416.2 C422.2 C430.2 C447.2 L9.2 U9.AC53(VCCIOIN_10) U9.AC55(VCCIOIN_11) U9.AH55(VCCIOIN_6) U9.AK53(VCCIOIN_7) U9.AK55(VCCIOIN_8) U9.AM53(VCCIOIN_9) U9.AP18(VCCIOIN_5) U9.AP21(VCCIOIN_1) U9.AR18(VCCIOIN_4) U9.AR21(VCCIOIN_2) U9.AR23(VCCIOIN_3) U9.BB25(P1V05_PROC_IO)
P1V05_VCCSCSUS: C372.2 C374.2 C384.2 C406.2 L32.2 U9.R48(VCCSCSUS_1) U9.R49(VCCSCSUS_2) U9.T48(VCCSCSUS_3) U9.T49(VCCSCSUS_4) U9.V48(VCCSCSUS_5) U9.V49(VCCSCSUS_6)
P1V7_AGND: C156.2 R310.1 R698.2 U22.5(GND)
P1V7_SS: R316.1 U22.4(SS)
P1V7_SS_C: C156.1 R316.2
P1V7_SW: C159.1 L13.1 U22.10(SW1) U22.11(SW2)
P1V7_VBST: C159.2 U22.12(VBST)
P1V7_VO: C160.1 R328.1 R330.2 U22.1(VO)
P1V7_VO_R: R324.1 R328.2
P1V7_VREG: C571.1 R697.2 U22.3(VREG5)
P3V3: C11.1 C30.1 C31.1 C54.1 C58.1 C61.1 C111.1 C112.1 C113.1 C153.1 C154.1 C183.2 C184.2 C185.1 C187.1 C188.1 C262.1 C267.1 C269.1 C271.1 C280.A C319.1 C464.1 C469.2 C508.1 C515.2 C516.1 C517.2 C544.1 C589.1 C592.1 C640.1 C647.2 C901.1 C902.1 C903.A C910.1 C911.2 C912.1 C913.2 C914.2 C915.2 CONN4.43 CONN4.44 CONN6.2(3.3VAUX_0) CONN6.24(3.3VAUX_1) CONN6.39(3.3VAUX_2) CONN6.41(3.3VAUX_3) CONN6.52(3.3VAUX_4) CONN15.1 CONN18.1 L6.2 L20.2 L29.2 L31.2 L36.2 L42.1 LED11.A LED15.A Q7.A2 Q9.1(VCCA) R22.1 R24.2 R30.1 R33.1 R39.2 R50.2 R55.2 R56.2 R57.2 R90.2 R94.1 R95.2 R108.2 R109.2 R156.2 R164.2 R188.2 R201.2 R212.2 R234.2 R235.2 R249.1 R293.2 R298.1 R300.1 R312.2 R313.2 R383.1 R414.2 R415.2 R416.2 R418.2 R419.2 R420.2 R421.2 R422.2 R429.1 R430.2 R432.2 R433.2 R436.2 R438.2 R442.2 R443.2 R446.2 R447.1 R448.2 R449.2 R452.2 R454.1 R456.2 R457.2 R459.1 R461.2 R467.2 R470.2 R478.2 R481.2 R483.1 R485.1 R501.1 R502.2 R516.1 R521.1 R523.1 R577.2 R601.1 R603.1 R607.1 R618.1 R631.2 R651.2 R660.2 R661.1 R663.2 R686.1 R687.2 R717.2 R718.2 R721.2 R722.2 R761.2 R849.1 R875.1 R883.1 R901.1 R905.1 R922.1 R931.1 R932.1 R933.1 R934.1 R935.1 R942.1 R943.1 R1057.1 R1059.1 R1061.1 R1063.1 R1065.1 R1066.1 R1067.2 R1068.2 R1083.1 R1084.1 R1085.1 U2.5(VCC) U7.16(VCC) U13.1(VCCA) U16.8(VCC) U17.10(VDD_2) U17.24(VDD_4) U18.1(VCCA) U19.8(VCC) U20.8(VCC) U32.5(VCC) U34.16(VCCB) U38.1(VCCA) U42.5(VCC) U43.16(VCC) U44.5(VCC)
P3V3_A: C55.1 C59.1 C83.1 C115.1 C116.1 C117.1 C119.2 C120.2 C196.1 C197.1 C198.2 C250.1 C251.1 C278.1 C283.1 C290.2 C298.2 C355.1 C356.1 C357.1 C358.1 C398.1 C399.1 C411.1 C414.1 C435.1 C438.1 C452.1 C453.1 C477.1 C478.1 C479.1 C480.1 C500.1 C502.1 C567.1 C570.1 C590.2 C707.1 C904.1 C907.A CONN9.4 L5.1 L11.2 L22.1 L49.1 R93.1 R155.2 R187.1 R277.1 R375.1 R390.1 R391.1 R404.1 R405.1 R406.1 R407.1 R408.1 R409.1 R410.1 R411.1 R412.1 R413.1 R491.2 R494.2 R495.1 R496.1 R503.1 R525.2 R528.2 R530.2 R532.2 R533.2 R608.2 R646.1 R654.1 R657.1 R658.1 R659.1 R665.2 R675.1 R678.2 R681.2 R683.2 R684.2 R689.2 R691.2 R705.1 R707.1 R712.1 R753.2 R783.2 R910.1 R921.1 U12.A3(VCCIO2_4) U12.A14(VCCIO2_1) U12.C1(VCCIO1_1) U12.C16(VCCIO3_4) U12.F8(VCCIO2_3) U12.F9(VCCIO2_2) U12.H6(VCCIO1_2) U12.H11(VCCIO3_3) U12.J6(VCCIO1_3) U12.J11(VCCIO3_2) U12.L8(VCCIO4_2) U12.L9(VCCIO4_3) U12.P1(VCCIO1_4) U12.P16(VCCIO3_1) U12.T3(VCCIO4_1) U12.T14(VCCIO4_4) U21.16(VCC) U33.24(VDD) U35.2(VIN)
P3V3_A_L_I210: C6.1 C7.1 C16.1 C17.1 C284.1 C288.2 C290.1 C298.1 C648.1 C651.1 C708.1 C925.2 C926.2 C927.2 C928.2 C929.2 C930.2 C931.2 C961.2 C963.1 L1.1 L3.2 L49.2 LED18.A R801.2 R802.1 R807.1 R808.1 R813.2 R814.2 R815.2 R816.2 R817.2 R818.2 R822.2 R828.2 R829.2 R920.2 R961.1 R975.2 R976.2 R977.2 R978.2 R979.1 R999.1 R1001.1 R1003.1 R1005.1 R1007.1 R1009.1 R1011.1 R1034.1 R1038.1 R1040.1 R1042.1 R1043.1 U6.10(VDD3P3_10) U6.27(VDD3P3_27) U6.41(VDD3P3_41) U6.64(VDD3P3_64) U38.6(VCCB) U39.8(VCC)
P3V3_A_Q3: Q3.A2 R93.2
P3V3_AB: R391.2 R729.2 R758.2 U29.28(VCC)
P3V3_BATT: C14.2 C21.2 C297.2 Q3.C R117.1 R140.2 R499.2 R505.2 U9.AW14(VCCRTC)
P3V3_L_PCH: C236.1 C239.2 L42.2 U30.1(D1) U30.2(D2) U30.5(D3) U30.6(D4) U30.8(D5)
P3V3_LED13: LED13.A R721.1
P3V3_LED14: LED14.A R722.1
P3V3_PCH: C256.2 C259.1 C286.2 C289.2 C292.2 C293.2 C294.2 C295.2 C296.2 C304.2 C324.2 C333.2 C351.2 C375.1 C445.1 C499.1 C905.1 L41.2 Q10.6(VCCB) R9.1 R10.2 R11.2 R14.2 R17.1 R23.1 R28.2 R53.1 R63.1 R84.2 R85.2 R89.2 R91.2 R431.1 R466.2 R473.2 R567.1 U9.AC14(VCCCLK3_3_3) U9.AC19(VCCADACBG3_3) U9.AE12(VCCCLK3_3_4) U9.AE16(VCCCLK3_3_1) U9.AE18(VCCCLK3_3_2) U9.AG14(VCCCLK3_3_6) U9.AG18(VCC3_3_5) U9.AG28(VCC3_3_6) U9.AG30(VCC3_3_7) U9.AH14(VCCCLK3_3_5) U9.AM12(VCC3_3_1) U9.AU12(VCC3_3_4) U9.AW25(VCC3_3_2) U9.BA25(VCC3_3_3) U10.23(VCCB1) U10.24(VCCB2) U14.23(VCCB1) U14.24(VCCB2)
P3V3_PCH_IDT_G: C249.2 D1.A R386.1 R752.2 U30.3(G)
P3V3_PCH_L: L41.1 U30.4(S1) U30.7(S2)
P3V3_Q4_Q2: Q2.G Q4.D R94.2
P3V3_STBY: C204.1 C205.2 C207.1 C908.1 C909.1 C964.2 CONN14.199 CONN14.201 CONN14.202 CONN14.203 CONN14.204 L22.2 R317.1 R322.1 R346.1 R504.2 R510.2 R511.2 R512.2 R513.2 R514.2 R914.2 R917.1 R918.1 R940.2 R941.2 R946.1 R947.1 R1077.2 R1078.1 R1079.1 R1080.2 U40.5(VCC) U41.5(VCC) U45.16(VDD)
P3V3_STBY_CLKBUF: C18.1 C19.1 L3.1 R465.2 U5.1(VDD)
P3V3_STBY_OSC: C266.1 C268.1 C270.1 L1.2 OSC1.4(VDD) R62.1
P3V3_STBY_OSC_R: OSC1.1(\\S\T/OE) R36.1 R62.2
P3V3A_OSC: C66.1 C67.1 C70.1 L5.2 OSC4.4(VDD) R171.2
P3V3A_OSC_R: OSC4.1(OE) R171.1 R1054.2
P5V: C1.1 C2.1 C4.1 C5.1 C8.1 C9.2 C10.2 C84.1 C99.1 C172.1 C265.1 C288.1 C291.2 C595.2 C597.2 CONN1.1(VBUS) L2.2 L19.2 L28.2 R87.1 R342.1 R343.2 R715.1 U8.4(BIAS) U11.4(BIAS)
P5V_A: C193.1 C194.1 R342.2 U25.1(VCC) U25.2(VDRV) U25.27(ZCD_EN#) U26.1(VCC) U26.2(VDRV) U26.27(ZCD_EN#)
P5V_B: C199.1 R715.2 U24.1(VCC) U24.2(VDRV) U24.27(ZCD_EN#)
P5V_CONN: C609.1 C610.1 C611.2 C612.1 CONN16.1 CONN16.3 CONN16.5 L37.1
P5V_STBY: C224.1 C225.1 C226.2 C287.1 C627.1 C629.1 C631.1 C634.1 CONN14.200 L37.2 L50.2
P5VA: QFN1.3(VCC) QFN1.20(BBRK#) R343.1 R347.2
V0P6_VTT_VIN: L36.1 R1087.1 U37.10(VIN)
V1P5_FB: C90.1 R193.2 R558.2 U11.8(FB)
V1P5_FB_R: R192.1 R193.1
V1P5_SS: C89.1 U11.7(SS)
V1P8A: C109.1 C412.1 C413.1 C436.1 C437.1 C505.1 C507.1 R611.1 U12.H8(VCCINT_1) U12.H10(VCCINT_2) U12.J7(VCCINT_3) U12.J9(VCCINT_4) U35.3(VOUT)
V1P8A_EN: R608.1 U35.1(EN)
V1P35_FB: C95.1 R197.2 R555.2 U8.8(FB)
V1P35_FB_R: R197.1 R198.1
V1P35_SS: C96.1 U8.7(SS)
V3P3_EN: C626.1 R731.2 R732.2 U27.7(EN)
V3P3_PCH_EN: C241.1 D1.C Q14.D R386.2 R779.2
V3P3_PCH_EN_N: Q6.D Q14.G R778.2
V3P3_R: C636.1 R383.2 R388.1 U27.1(VO)
V3P3_R_R: R384.1 R388.2
V3P3_SF100: CONN3.1 Q7.A1
V3P3_SPI: C13.1 C260.1 C263.1 Q7.C R4.1 R6.1 R21.1 R427.1 R435.1 R440.1 R460.1 R936.1 R949.1 R950.1 R951.1 U1.8(VCC) U31.8(VCC)
V3P3_SS: R380.1 U27.4(SS)
V3P3_SS_C: C243.1 R380.2
V3P3_SW: C608.1 L20.1 U27.10(SW1) U27.11(SW2)
V3P3_VBST: C608.2 U27.12(VBST)
V3P3_VREG: C242.1 R381.2 U27.3(VREG5)
V3P3A_EN: R233.1 R1088.2 U15.7(EN)
V3P3A_R: C513.1 R277.2 R278.1 U15.1(VO)
V3P3A_R_R: R278.2 R279.1
V3P3A_SS: R280.1 U15.4(SS)
V3P3A_SS_C: C129.1 R280.2
V3P3A_SW: C110.1 L11.1 U15.10(SW1) U15.11(SW2)
V3P3A_VBST: C110.2 U15.12(VBST)
V3P3A_VREG: C514.1 R281.2 U15.3(VREG5)
V5A_PM_P1V7: C173.1 C174.1 L19.1 U22.13(VIN1) U22.14(VIN2)
V5A_SS: R92.1 U4.4(SS)
V5A_SS_C: C34.1 R92.2
V5A_SW: C23.1 L2.1 U4.10(SW1) U4.11(SW2)
V5A_VBST: C23.2 U4.12(VBST)
V5A_VO: C24.1 R77.1 R87.2 U4.1(VO)
V5A_VO_R: R74.1 R77.2
V5A_VREG: C20.1 R46.2 U4.3(VREG5)
V12A_CONN: C210.1 C212.1 C222.1 C235.1 CONN16.2 CONN16.4 CONN16.6 CONN16.7 CONN16.8 CONN16.9 CONN16.10 L23.1
V12A_CONN_R: L23.2 R340.2
V12A_DDR: C177.2 C181.2 C182.2 C202.1 C203.1 C598.2 C599.2 C602.1 C603.1 C614.1 L24.2 QFN1.14(VIN1) QFN1.15(VIN2) QFN1.16(VIN3) R362.1
V12A_PM_V3P3A: C118.1 C121.1 L12.1 L50.1 R233.2 U15.13(VIN1) U15.14(VIN2)
V12A_V3P3: C211.1 C216.1 L27.1 U27.13(VIN1) U27.14(VIN2)
V12A_V5A: C27.1 C28.1 C29.1 L4.1 R34.2 U4.13(VIN1) U4.14(VIN2)
VCC1P5_OSC25M: C51.1 OSC2.4(VDD) R148.1 R154.1
VCC12A: C33.1 C123.1 C158.1 C164.1 C175.1 C190.1 C206.1 C219.1 C573.1 C585.1 C591.1 L4.2 L12.2 L21.2 L24.1 L25.1 L26.1 L27.2 R340.1 R778.1 R779.1
VCC12A_PM_DDR4_VPP: C191.1 C192.1 L21.1 U23.13(VIN1) U23.14(VIN2)
VCC_EUSB: C264.1 C900.1 CONN5.2 L28.1 L29.1
VCCAXCK_DCB: C380.2 C381.2 L34.2 U9.AE27(VCCAXCK1_05)
VCCGBE_FLT: C388.2 C409.2 C418.2 L35.1 R569.1 U9.T56(VCCKRLCPLL)
VCCGBE_FLT2: C327.2 C342.2 C379.2 L30.1 U9.T46(VCCSCPLL)
VCCIN: C125.A C131.A C132.A C133.A C134.1 C157.A C390.1 C391.1 C392.1 C393.1 C394.1 C424.1 C425.1 C426.1 C427.1 C428.1 C432.2 C448.1 C449.1 C460.1 C461.1 C481.2 C482.2 C492.2 C493.2 C495.2 C496.2 C497.2 C501.1 C503.1 C504.2 C506.1 C531.1 C532.1 C533.1 C534.1 C535.1 C536.1 C537.1 C538.1 C540.2 C553.1 C554.1 C561.1 C562.1 C563.2 C576.1 C577.1 C578.1 C579.1 C580.1 C581.1 L15.2 L16.2 R600.1 U9.AG53(VCCIN_58) U9.AG55(VCCIN_59) U9.AV60(VCCIN_1) U9.AW55(VCCIN_2) U9.AW56(VCCIN_3) U9.AW58(VCCIN_4) U9.AW62(VCCIN_5) U9.AW66(VCCIN_6) U9.AW69(VCCIN_7) U9.AW72(VCCIN_8) U9.AW74(VCCIN_9) U9.AW76(VCCIN_10) U9.AW78(VCCIN_11) U9.AY60(VCCIN_12) U9.AY64(VCCIN_13) U9.AY67(VCCIN_14) U9.AY71(VCCIN_15) U9.AY75(VCCIN_16) U9.AY77(VCCIN_17) U9.BA58(VCCIN_18) U9.BA62(VCCIN_19) U9.BA66(VCCIN_20) U9.BA69(VCCIN_21) U9.BA72(VCCIN_22) U9.BA74(VCCIN_23) U9.BA76(VCCIN_24) U9.BA78(VCCIN_25) U9.BB36(VCCIN_26) U9.BB56(VCCIN_27) U9.BB60(VCCIN_28) U9.BB64(VCCIN_29) U9.BB67(VCCIN_30) U9.BB71(VCCIN_31) U9.BB75(VCCIN_32) U9.BB77(VCCIN_33) U9.BC58(VCCIN_34) U9.BC62(VCCIN_35) U9.BC66(VCCIN_36) U9.BC69(VCCIN_37) U9.BC72(VCCIN_38) U9.BD36(VCCIN_39) U9.BD37(VCCIN_40) U9.BD56(VCCIN_41) U9.BD60(VCCIN_42) U9.BD64(VCCIN_43) U9.BD67(VCCIN_44) U9.BD71(VCCIN_45) U9.BD74(VCCIN_46) U9.BD76(VCCIN_47) U9.BD78(VCCIN_48) U9.BE37(VCCIN_49) U9.BE58(VCCIN_50) U9.BE62(VCCIN_51) U9.BF60(VCCIN_52) U9.BG37(VCCIN_53) U9.BG58(VCCIN_54) U9.BH37(VCCIN_55) U9.BH56(VCCIN_56) U9.BJ56(VCCIN_57)
VCCIN_P1V05_VCC: C240.2 C632.2 R375.2 R735.2 R740.2 R744.2 R747.2 R750.2 U28.28(VCC)
VCCKRHV: C91.1 C92.1 C95.2 C97.1 C417.1 C433.2 C434.2 R198.2 U8.9(OUT1) U8.10(OUT2) U9.N51(VCCKX4PLL) U9.N58(VCCKRHV)
VCCSCFUSESUS: C82.1 C101.1 C135.1 C136.1 C137.1 C139.1 C140.1 C141.2 C142.2 C441.1 L13.2 R330.1 U8.1(IN1) U8.2(IN2) U9.AA53(VCCSCFUSESUS_3) U9.AA55(VCCSCFUSESUS_4) U9.AE53(VCCSCFUSESUS_1) U9.AE55(VCCSCFUSESUS_2) U11.1(IN1) U11.2(IN2)
VCCSCSUS_SENSE: U9.AR76(VCCSCSUS_SENSE)
VCCSUS3_3: C307.2 C312.2 C361.2 L31.1 U9.AP12(VCCSUS3_3_4) U9.AP16(VCCSUS3_3_7) U9.AR14(VCCSUS3_3_8) U9.AR16(VCCSUS3_3_2) U9.AR28(VCCSUS3_3_5) U9.AR30(VCCSUS3_3_6) U9.AU18(VCCSUS3_3_3) U9.AW18(VCCSUS3_3_9) U9.AW23(VCCSUS3_3_1)
VDD1P5_56: U6.56(VDD1P5_56)
VDDQ_ADDR_PROT: C254.1 R756.1 U29.18(ADDR_PROT)
VDDQ_CPU_SEN_N: R349.1 R358.2 R593.2
VDDQ_CPU_SEN_N_R: C231.2 R358.1 U29.5(VRTN)
VDDQ_CPU_SEN_P: R350.2 R359.2 R592.2
VDDQ_CPU_SEN_P_R: C231.1 R359.1 U29.4(VSEN)
VDDQ_RCSM: R320.2 R348.2 R356.2
VDDQ_RCSM_R: C232.2 R356.1 U29.2(RCSM)
VDDQ_RCSP: R320.1 R348.1 R357.2
VDDQ_RCSP_R: C232.1 R357.1 U29.1(RCSP)
VDDQ_SVADDR: C238.1 R742.1 U29.12(VDDIO/SV_ADDR)
VDDQ_TSEN_N: R326.2 R723.2
VDDQ_TSEN_P: C221.1 R326.1 R728.1 U29.7(TSEN1)
VDDQ_VINSEN: C625.1 R362.2 R363.1 U29.11(VINSEN)
VSS_VCCSCSUS_SENSE: U9.AR74(VSS_VCCSCSUS_SENSE)
1PPS_CPU: CONN16.89 U9.BA5(GPIO25)
10G_KR_C_RX0_N: C462.2 U9.N62(LAN_KR_RX0_N)
10G_KR_C_RX0_P: C472.2 U9.R62(LAN_KR_RX0_P)
10G_KR_C_RX1_N: C440.2 U9.T64(LAN_KR_RX1_N)
10G_KR_C_RX1_P: C455.2 U9.P64(LAN_KR_RX1_P)
10G_KR_RX0_N: C462.1 CONN16.108
10G_KR_RX0_P: C472.1 CONN16.110
10G_KR_RX1_N: C440.1 CONN16.100
10G_KR_RX1_P: C455.1 CONN16.102
10G_KR_TX0_N: CONN16.116 U9.J62(LAN_KR_TX0_N)
10G_KR_TX0_P: CONN16.118 U9.F62(LAN_KR_TX0_P)
10G_KR_TX1_N: CONN16.92 U9.J66(LAN_KR_TX1_N)
10G_KR_TX1_P: CONN16.94 U9.F66(LAN_KR_TX1_P)
A_VCCDUSBSUS_P1V05: C301.2 U9.AK14(DCPSUS2)
ADR_MCU_INIT: R479.1 U12.C7(IO_2_C7/DIFFIO_T5N)
ADR_STATUS_CLR: R482.1 U12.D13(IO_3_D13)
ADR_STATUS_CLR_R: R115.2 R482.2 R516.2 U9.BL2(SATA3GP_GPIO37)
ADR_STATUS_RD_R: R38.2 R450.2 R521.2 U9.BT1(SATA2GP_GPIO36)
ALL_POWER_OFF: CONN14.40 R939.1 R941.1
ALL_POWER_RESET: CONN14.38 R938.1 R940.1
B2B_PROCHOT_N: CONN16.85 U12.M7(IO_4_M7/DIFFIO_B8N)
B2B_THERMTRIP_N: CONN16.44 U12.L11(IO_3_L11/DIFFIO_R18N)
BDX_BIOS_SPI_CLK: R926.2 U43.6(2B2)
BDX_BIOS_SPI_MISO: R930.2 U43.13(4B2)
BDX_BIOS_SPI_MOSI: R928.2 U43.10(3B2)
BDX_CATERR_N: R210.1 U9.Y67(CATERR_N) U14.9(A7)
BDX_CPLD_INT_CPU: R876.1 R921.2 R937.2 U9.AV7(TACH4_GPIO68)
BDX_CPLD_INT_CPU_R: R876.2 U12.A7(IO_2_A7/DIFFIO_T10P)
BDX_CPLD_JTAG_ENABLE: R131.1 R665.1 R869.1 U21.2(1OE) U21.5(2OE) U21.12(3OE) U21.15(4OE)
BDX_CPLD_JTAG_ENABLE_R: R114.2 R500.2 U9.BJ4(GPIO8_OCS)
BDX_CPLD_JTAG_MUX_ENABLE: R500.1 R849.2 U7.1(S)
BDX_CPLD_JTAG_R_TCK: R124.2 R490.2 U9.BD3(OC7_N_GPIO14)
BDX_CPLD_JTAG_R_TDI: R104.2 R475.2 U9.BF3(OC5_N_GPIO9)
BDX_CPLD_JTAG_R_TDO: R121.2 R489.2 U9.BF1(OC6_N_GPIO10)
BDX_CPLD_JTAG_R_TMS: R27.2 R444.2 U9.BN4(SRC1CLKRQ_N_GPIO18)
BDX_CPLD_JTAG_TCK: R133.1 U21.3(1A)
BDX_CPLD_JTAG_TCK_MUX: R124.1 U7.4(1A)
BDX_CPLD_JTAG_TCK_R: R133.2 U7.3(1B2)
BDX_CPLD_JTAG_TDI: R149.1 U21.14(4A)
BDX_CPLD_JTAG_TDI_MUX: R475.1 U7.9(3A)
BDX_CPLD_JTAG_TDI_R: R149.2 U7.10(3B2)
BDX_CPLD_JTAG_TDO: R151.1 U21.6(2A)
BDX_CPLD_JTAG_TDO_MUX: R121.1 U7.12(4A)
BDX_CPLD_JTAG_TDO_R: R151.2 U7.13(4B2)
BDX_CPLD_JTAG_TMS: R135.1 U21.11(3A)
BDX_CPLD_JTAG_TMS_MUX: R27.1 U7.7(2A)
BDX_CPLD_JTAG_TMS_R: R135.2 U7.6(2B2)
BDX_CPU2PCH_THROT: R275.1 R284.2 U9.AL74(THROTTLE_PECI_ID2) U10.9(A7)
BDX_CPU_ERROR_0: R204.1 R241.1 U14.5(A3)
BDX_CPU_ERROR_1: R206.1 R254.1 U14.6(A4)
BDX_CPU_ERROR_2: R208.1 R247.1 U14.7(A5)
BDX_CPU_PROCHOT_N: Q13.D R214.1 R265.2 U14.10(A8)
BDX_CPU_RSMRST_N: R253.2 U13.18(B4)
BDX_CPU_RSTN_R: CONN11.46 R736.2
BDX_CPU_THERMTRIP_N: R209.1 U9.AF72(THERMTRIP_N) U14.8(A6)
BDX_DDR01_MEMHOT: Q12.D R219.2 U9.CC56(MEM_HOT_N) U10.8(A6)
BDX_DDR01_RCOMP0: R568.1 U9.CC52(DDR_RCOMP_0)
BDX_DDR01_RCOMP1: R565.1 U9.CD51(DDR_RCOMP_1)
BDX_DDR01_RCOMP2: R564.1 U9.CC49(DDR_RCOMP_2)
BDX_DDR01_RESET_N: R546.2 R551.2 U9.CR43(DDR_RESET_N)
BDX_DMI_RCOMP: R180.2 U9.AA28(SOC_RCOMP)
BDX_DRAM01_PWROK: R20.2 R439.2 U9.BA9(DRAMPWROK_PCH)
BDX_DRAM01_PWROK_R: R439.1 U9.CV55(DRAM_PWR_OK)
BDX_EXT_BGREF: R276.2 R623.1 U9.AK66(RSVD_16)
BDX_EXT_SC_BGREF: R217.1 R587.2 U9.E72(RSVD_17)
BDX_FIVR_FAULT: U9.AP69(FIVR_FAULT) U14.3(A1)
BDX_FM_CPU_PROCHOT_N: R86.2 R469.2 U9.BM1(SATA5GP_GPIO49)
BDX_FM_NMI_EVENT_N: R91.1 R101.2 R474.2 U9.BP1(GPIO15_NMI_N)
BDX_FM_SMI_ACTIVE_N: R73.2 R75.2 R459.2 U9.BR4(GPIO20_SMI_N)
BDX_FM_THROTTLE_N: R107.2 R477.2 U9.BN2(SATA4GP_GPIO16)
BDX_INTRUDER_N: R140.1 R916.2 U9.AK2(INTRUDER_N)
BDX_INTRUDER_N_R: CONN14.39 R916.1
BDX_INTVRMEN: R505.1 R518.2 U9.AP2(INTVRMEN)
BDX_PCI_RCOMP: R543.2 U9.AA27(PCIE_RCOMP)
BDX_PECI_CPU: R560.2 U9.AL78(PECI_CPU)
BDX_PECI_PCH: C364.2 R560.1 U9.BG16(PECI_PCH) U10.10(A8)
BDX_PECI_PCH_3V3: R915.2 U10.14(B8)
BDX_PECI_PCH_3V3_R: CONN14.35 R915.1
BDX_PECID0: R586.1 R749.2 U9.L72(PECI_ID0)
BDX_PWRGOOD_CPU: R32.1 R453.2 R537.1 U10.4(A2)
BDX_PWRGOOD_CPU_R: R32.2 U9.BU11(PROCPWRGD_PCH)
BDX_RTCRST_N: CONN17.2 R118.2 U9.AP9(RTCRST_N)
BDX_SATA1_ACTIVITY_LED1: C605.1 LED14.C U12.N14(IO_3_N14/DIFFIO_R22N)
BDX_SATA2_ACTIVITY_LED2: C604.1 LED13.C U12.P14(IO_3_P14/DIFFIO_R24N)
BDX_SC_PWRGOOD: R239.2 R609.1 R610.2 R775.2 U13.19(B3)
BDX_SCLOCK: R37.2 U12.C8(IO_2_C8/DIFFIO_T9P)
BDX_SDATAOUT0: R44.1 U12.E14(IO_3_E14/DIFFIO_R1P)
BDX_SDATAOUT1: R67.1 U12.C14(IO_3_C14/DIFFIO_R1N)
BDX_SERIRQ_DATA: Q10.3(A) U9.AE75(SERIRQ_DATA)
BDX_SERIRQ_DIR: Q10.5(DIR) R794.2 R795.1 U9.AD74(SERIRQ_DIR)
BDX_SLOAD: R451.2 U12.N10(IO_4_N10)
BDX_SLP_S3_CPU_N: R303.2 R642.2 U9.AC71(SLP_S3_CPU_N)
BDX_SLP_S3_CPU_N_R: R303.1 R307.1 R667.1
BDX_SPI_MUX_SEL: CONN14.119 R931.2 R933.2 U43.1(S) U44.6(S)
BDX_SPKR: R9.2 U9.BP20(SPKR)
BDX_SRTCRST_N: C274.1 R117.2 R118.1 U9.AP4(SRTCRST_N)
BDX_TCK_SCLK: CONN16.64 R132.1
BDX_TCK_SCLK_R: R132.2 U7.2(1B1)
BDX_TDI_MOSI: CONN16.77 R147.1
BDX_TDI_MOSI_R: R147.2 U7.11(3B1)
BDX_TDO_MISO: CONN16.66 R150.1
BDX_TDO_MISO_R: R150.2 U7.14(4B1)
BDX_TMS_CS_N: CONN16.72 R134.1
BDX_TMS_CS_N_R: R134.2 U7.5(2B1)
BIOS_CPU_SPI2_CS_TPM: TP19.1(TP) U9.BJ9(SPI_CS2_N)
BIOS_SPI1_CS: CONN2.1 R949.2 U1.1(\\C\S\) U43.4(1A)
BIOS_SPI2_CS: CONN2.3 Q1.S R936.2 U31.1(\\C\S\)
BIOS_SPI2_CS_SWITCH: Q1.D R935.2 U44.4(A)
BIOS_SPI_C_CLK: CONN3.4 U1.6(SCLK) U31.6(SCLK) U43.7(2A)
BIOS_SPI_C_MISO: CONN3.5 U1.2(SO/SIO1) U31.2(SO/SIO1) U43.12(4A)
BIOS_SPI_C_MOSI: CONN3.6 U1.5(SI/SIO0) U31.5(SI/SIO0) U43.9(3A)
BIOS_SPI_CI_N: R924.1 U2.1(B1) U32.3(B0)
BIOS_SPI_CI_N_R: R924.2 U43.3(1B2)
BIOS_SPI_CLK: R52.2 R427.2 R926.1
BIOS_SPI_CLK_R: R52.1 U9.BG13(SPI_CLK)
BIOS_SPI_CS0_N: R6.2 R15.1 U2.4(A)
BIOS_SPI_CS0_N_R: R15.2 U9.BN7(SPI_CS0_N)
BIOS_SPI_CS1_N: R70.1 R460.2 U32.4(A)
BIOS_SPI_CS1_N_R: R70.2 U9.BT13(SPI_CS1_N)
BIOS_SPI_HOLD_N: R21.2 U1.7(H\O\L\D\/SIO3) U31.7(H\O\L\D\/SIO3)
BIOS_SPI_KGI_N: U2.3(B0) U32.1(B1) U44.1(B1)
BIOS_SPI_MISO: R4.2 R930.1 U9.BJ20(SPI_MISO_IO1)
BIOS_SPI_MOSI: R435.2 R462.1 R928.1
BIOS_SPI_MOSI_R: R462.2 U9.BL11(SPI_MOSI_IO0)
BIOS_SPI_WP_N: R440.2 U1.3(W\P\/SIO2) U31.3(W\P\/SIO2)
BIST_ENABLE: R308.2 U9.AM69(BIST_ENABLE)
BMC_BTN_LOCKED_N: CONN14.184 R341.2
BMC_FAULT_LED: R336.1 R513.1 U12.P6(IO_4_P6/DIFFIO_B4P)
BMC_ID_BTN: R327.2 U12.M4(IO_1_M4/DIFFIO_L20N)
BMC_ID_LED: R338.1 R514.1 U12.N7(IO_4_N7/DIFFIO_B7N)
BMC_LOCK_BTN: R341.1 R512.1 U12.P7(IO_4_P7/DIFFIO_B6N)
BMC_NMI_BTN: R332.1 R511.1 U12.M8(IO_4_M8/DEV_OE/DIFFIO_B15P)
BMC_PRESENT_BDX_GPIO17: R913.2 U9.AN3(TACH0_GPIO17) U12.A8(IO_2_A8/DIFFIO_T11P)
BMC_PWR_BTN: R331.1 R510.1 U12.P5(IO_4_P5/DIFFIO_B2N)
BMC_READY_CPU_ENABLE: R952.2 R953.1 U12.R11(IO_4_R11/DIFFIO_B17P)
BMC_READY_CPU_ENABLE_R: CONN14.44 R952.1
BMC_RST_BTN: R329.1 R504.1 U12.M3(IO_1_M3/DIFFIO_L18P)
BMC_SPI_CLK: CONN14.135 R925.1
BMC_SPI_CLK_R: R925.2 U43.5(2B1)
BMC_SPI_CS0: R923.1 R951.2 U42.1(B1)
BMC_SPI_CS0_R: R923.2 U43.2(1B1)
BMC_SPI_CS1: R950.2 U42.3(B0) U44.3(B0)
BMC_SPI_CS_N: CONN14.133 U42.4(A)
BMC_SPI_DI: CONN14.139 R929.1
BMC_SPI_DI_R: R929.2 U43.14(4B1)
BMC_SPI_DO: CONN14.137 R927.1
BMC_SPI_DO_R: R927.2 U43.11(3B1)
BMC_SPI_OUT_SEL: CONN14.141 R922.2 U42.6(S)
BMC_UART0_DIR_SEL: R152.2 R912.2 U12.L2(IO_1_L2/DIFFIO_L16P)
BMC_UART0_DIR_SEL_R: CONN14.30 R912.1
BMC_UART0_RX: CONN14.165 R315.2
BMC_UART0_TX: CONN14.163 R321.2
BMC_UART1_RX: CONN14.166 R539.1
BMC_UART1_TX: CONN14.164 R378.1
BMCINIT: R291.1 U9.AD69(BMCINIT)
BMM_CD3_INT0: R1073.2 R1078.2 R1090.2 R1111.2
BMM_CD3_INT0_R: R1073.1 U12.N1(IO_1_N1/DIFFIO_L19P)
BMM_CLK3: R1065.2 R1069.2 R1097.1 R1098.1
BMM_CLK_I2C_BUS: R1098.2 U45.3(SCL_MST0)
BMM_CLK_I2C_MUX: R1097.2 U40.3(B0)
BMM_DATA3: R1066.2 R1070.2 R1099.1 R1100.1
BMM_DATA_I2C_BUS: R1100.2 U45.2(SDA_MST0)
BMM_DATA_I2C_MUX: R1099.2 U41.3(B0)
BMM_MB_ID0: CONN14.115 R317.2 R318.1
BMM_MB_ID1: CONN14.117 R322.2 R323.1
BMM_SCL1: CONN14.61 R581.1
BMM_SCL2: CONN14.60 R576.1
BMM_SCL3: CONN14.67 R1069.1
BMM_SCL4: CONN14.66 R786.1
BMM_SCL5: CONN14.73 R791.1
BMM_SDA1: CONN14.63 R585.1
BMM_SDA2: CONN14.62 R579.1
BMM_SDA3: CONN14.69 R1070.1
BMM_SDA4: CONN14.68 R788.1
BMM_SDA5: CONN14.75 R792.1
BUS_RESET: R1114.2 U45.4(R\E\S\E\T\)
C33_BDX_PWRGOOD_CPU: U10.20(B2) U12.H4(IO_1_H4/DIFFIO_L12P)
C33_P1V5_PCH_EN: C402.1 R561.2 U11.5(EN) U12.G1(IO_1_G1/DIFFIO_L9P)
C33_P1V05_PCH_EN: R387.2 R734.1 R735.1 U12.P10(IO_4_P10/DIFFIO_B18N)
C33_PVCCKRHV_EN: C332.1 R550.2 U8.5(EN) U12.H3(IO_1_H3/DIFFIO_L11P)
C33_PVCCSCFUSESUS_EN: R692.1 U12.F1(IO_1_F1/DIFFIO_L7P) U22.7(EN)
C33_UART_BDX_B2B_RX0: CONN16.63 CONN18.3 R842.2 R871.1
C33_UART_BDX_B2B_TX0: CONN16.75 CONN18.2 R844.2 R872.1
C33_UART_BDX_CPLD_RX0: R662.2 U12.B1(IO_2_B1/DIFFIO_T1N)
C33_UART_BDX_CPLD_TX0: R870.2 U12.A2(IO_2_A2/DIFFIO_T2P)
C33_UART_BDX_RX0: R662.1 R842.1 U13.7(A5)
C33_UART_BDX_RX1: R378.2 U13.8(A6)
C33_UART_BDX_TX0: R844.1 R870.1 U10.18(B4)
C33_UART_BDX_TX1: R539.2 R552.1
C33_UART_BDX_TX1_R: R552.2 U10.17(B5)
C105_BDX_PWRGOOD_CPU: R252.2 R537.2 R538.1 R613.2 R615.1 R776.2
C105_BDX_PWRGOOD_CPU_R: R173.2 R538.2 U34.4(1A1)
C105_CPU_PCH__R_PLTRST_N: R240.1 R517.1 U9.L76(RESET_CPU_N)
C105_CPU_PCH_PLTRST_N: R240.2 R536.1 R736.1
C105_CPU_PCH_PLTRST_N_R: R169.2 R536.2 U34.5(1A2)
C105_PCHHOT_N: R238.2 R572.2 U13.14(B8)
C105_PCHHOT_N_R: R238.1 U9.AL76(PCHHOT_CPU_N)
CI_KGI_SELECT: CONN2.2 CONN3.3
CLK_33M_BMM: CONN14.10 R128.1
CLK_33M_BMM_R: R128.2 U9.Y11(CLKOUT_PCI_4)
CLK_33M_CPLD: R123.1 R641.2 U12.F16(IO_3_F16/DIFFIO_R9P)
CLK_33M_LPC: R141.1 R507.1 U9.AC67(SERIRQ_CLK)
CLK_33M_LPC_PORT80: CONN15.3 R641.1
CLK_33M_LPC_R: R507.2 R906.1
CLK_33M_LPC_TPM: R486.1 U17.21(LCLK)
CLK_33M_R_CPLD: R123.2 U9.V11(CLKOUT_PCI_3)
CLK_33M_R_LPC: R141.2 U9.AA4(CLKOUT_PCI_2)
CLK_33M_R_TPM: R122.2 U9.Y7(CLKOUT_PCI_1)
CLK_33M_TPM: R122.1 R486.2
CLK_50M: C22.2 R78.2 U5.5(ICLK)
CLK_50M_R: OSC1.3(OUT) R78.1 R853.1
CLK_100M_XDPCPU_N: CONN11.42 R130.1
CLK_100M_XDPCPU_P: CONN11.40 R129.1
CLK_100M_XDPCPU_R_N: R130.2 U9.H2(CLKOUT_ITPXDP_DN)
CLK_100M_XDPCPU_R_P: R129.2 U9.H4(CLKOUT_ITPXDP_DP)
CLK_BUF_50M_BMM: C41.1 CONN14.47 R119.1
CLK_BUF_50M_BMM_R: R119.2 U5.3(Q1)
CLK_BUF_EN: R465.1 U5.8(OE)
CLK_BUF_Q2_RSV: R1045.2 U5.6(Q2)
CLK_BUF_Q3_RSV: R468.2 U5.7(Q3)
CLK_M2_SUSCLK: R41.2 U9.BD11(SUSCLK_GPIO62)
CLR CMOS: CONN17.3 R800.1
CONN12_GND: CONN12.1 R745.2
CPLD23_INT_CPU: CONN16.91 R48.1 U12.K6(IO_1_K6)
CPLD23_INT_CPU_R: R48.2 R501.2 U9.BA21(GPIO45)
CPLD_ADR_STATUS_RD: R450.1 U12.D11(IO_2_D11/DIFFIO_T18P)
CPLD_BDX_CPU_RSMRST: U12.J3(IO_1_J3/DIFFIO_L14P) U13.6(A4)
CPLD_BDX_PWRGOOD_CPU: U12.F7(IO_2_F7/DIFFIO_T8P) U34.13(1B1)
CPLD_CLK_25M: R172.1 U12.J12(IO_3_J12/CLK2)
CPLD_CLK_25M_R: OSC4.3(OUT) R172.2
CPLD_CONFIG_CLK: R82.1 U12.D9(IO_2_D9)
CPLD_CONFIG_CLK_R: R82.2 R83.2 R470.1 U9.BG4(OC2_N_GPIO41)
CPLD_CONFIG_DATA: R103.1 U12.C13(IO_2_C13/DIFFIO_T21P)
CPLD_CONFIG_DATA_R: R102.2 R103.2 R481.1 U9.BG2(OC3_N_GPIO42)
CPLD_CPU2PCH_THROT: U10.15(B7) U12.G4(IO_1_G4/DIFFIO_L9N)
CPLD_CPU_CATERR_N: U12.K2(IO_1_K2/DIFFIO_L14N) U14.15(B7)
CPLD_CPU_ERROR_0: U12.H2(IO_1_H2/DIFFIO_L10P) U14.19(B3)
CPLD_CPU_ERROR_1: U12.J1(IO_1_J1/DIFFIO_L11N) U14.18(B4)
CPLD_CPU_ERROR_2: U12.J2(IO_1_J2/DIFFIO_L12N) U14.17(B5)
CPLD_CPU_PCH_PLTRST_N: U12.E7(IO_2_E7/DIFFIO_T7N) U34.12(1B2)
CPLD_CPU_PROCHOT_N: CONN14.29 R567.2 U12.L1(IO_1_L1/DIFFIO_L15N) U14.14(B8)
CPLD_CPU_THERMTRIP_N: CONN14.31 U12.K1(IO_1_K1/DIFFIO_L13N) U14.16(B6)
CPLD_DDR01_MEMHOT: U10.16(B6) U12.G3(IO_1_G3/DIFFIO_L8N)
CPLD_DDR_EVENT_N: Q11.D R607.2 U12.N8(IO_4_N8/DIFFIO_B11P)
CPLD_FIVR_FAULT: U12.H1(IO_1_H1/DIFFIO_L10N) U14.21(B1)
CPLD_INTERRUPT_R: CONN14.36 R937.1
CPLD_JTAG_TCK: R664.2 U21.4(1Y)
CPLD_JTAG_TDI: R843.2 U21.13(4Y)
CPLD_JTAG_TDO: R695.2 U21.7(2Y)
CPLD_JTAG_TMS: R696.2 U21.10(3Y)
CPLD_LED1_DEBUG: TP5.1(TP) U12.J15(IO_3_J15/DIFFIO_R14N)
CPLD_LED2_DEBUG: LED19.C2 U12.K16(IO_3_K16/DIFFIO_R15P)
CPLD_LED2_DEBUG_R: LED19.A2 R883.2
CPLD_LED3_DEBUG: TP7.1(TP) U12.K15(IO_3_K15/DIFFIO_R16P)
CPLD_LED4_DEBUG: LED19.C1 U12.L16(IO_3_L16/DIFFIO_R17P)
CPLD_LED4_DEBUG_R: LED19.A1 R875.2
CPLD_PCH_APWROK: R184.1 U12.F4(IO_1_F4/DIFFIO_L5N)
CPLD_PCH_PWROK: R189.2 U12.F3(IO_1_F3/DIFFIO_L4N)
CPLD_PCH_THERMTRIP_N: R212.1 U12.K4(IO_1_K4/DIFFIO_L16N) U13.9(A7)
CPLD_PCHHOT_N: U12.K3(IO_1_K3) U13.10(A8)
CPLD_SC_PWRGOOD: U12.J4(IO_1_J4/DIFFIO_L13P) U13.5(A3)
CPU_DDR_PWRGD: R613.1 U9.CR39(DDR_PWRGOOD)
CPU_JTAG_RST: CONN16.70 R49.1 U12.L12(IO_3_L12/DIFFIO_R19N)
CPU_JTAG_RST_R: R49.2 U9.BA19(GPIO46)
CPU_PWR_DEBUG_N: C639.2 CONN11.45 R760.1 U9.U77(PWR_DEBUG_N)
CPU_PWRGD_CPU: R252.1 U9.V76(PWRGOOD_CPU)
CPU_SV: R63.2 R458.1 U9.BP16(GPIO52)
CPU_XDP_HOOK0: R754.2 R775.1 R776.1 U12.N3(IO_1_N3/DIFFIO_L21P)
CPU_XDP_SYSPWROK: CONN11.47 R761.1 U12.P13(IO_4_P13/DIFFIO_B24N)
CSN1_VDDQ_CH01: C630.1 R333.2 R368.2
CSN1_VDDQ_CH01_R: R368.1 U29.40(IRTN1)
CSP1_VDDQ_CH01: R335.2 R365.2
CSP1_VDDQ_CH01_C: C630.2 R372.1 R373.2
CSP1_VDDQ_CH01_R: R373.1 U29.39(ISEN1)
CSP1_VDDQ_CH01_R_R: R365.1 R372.2
DA/DSS: CONN6.49(DA/DSS) R97.2
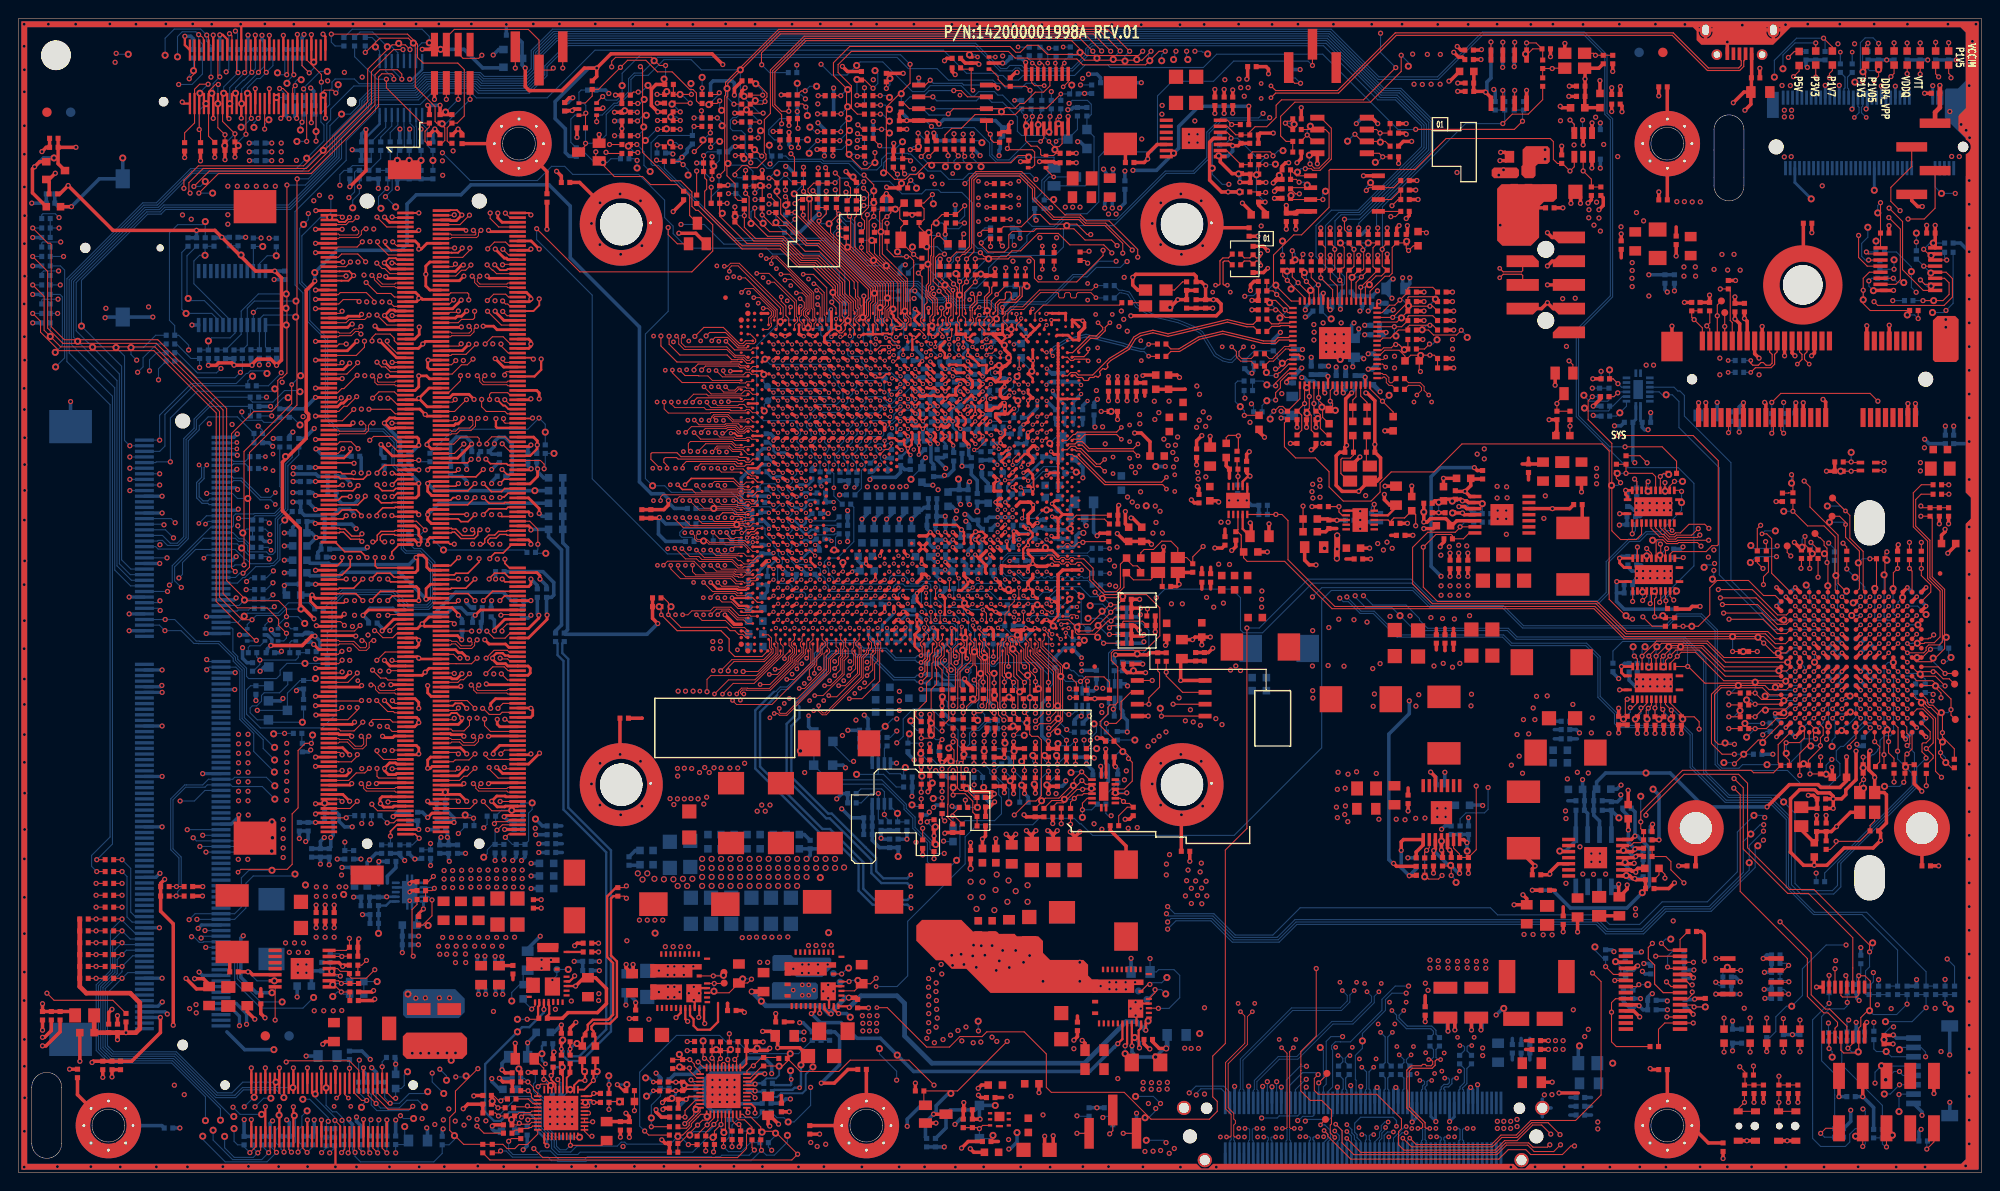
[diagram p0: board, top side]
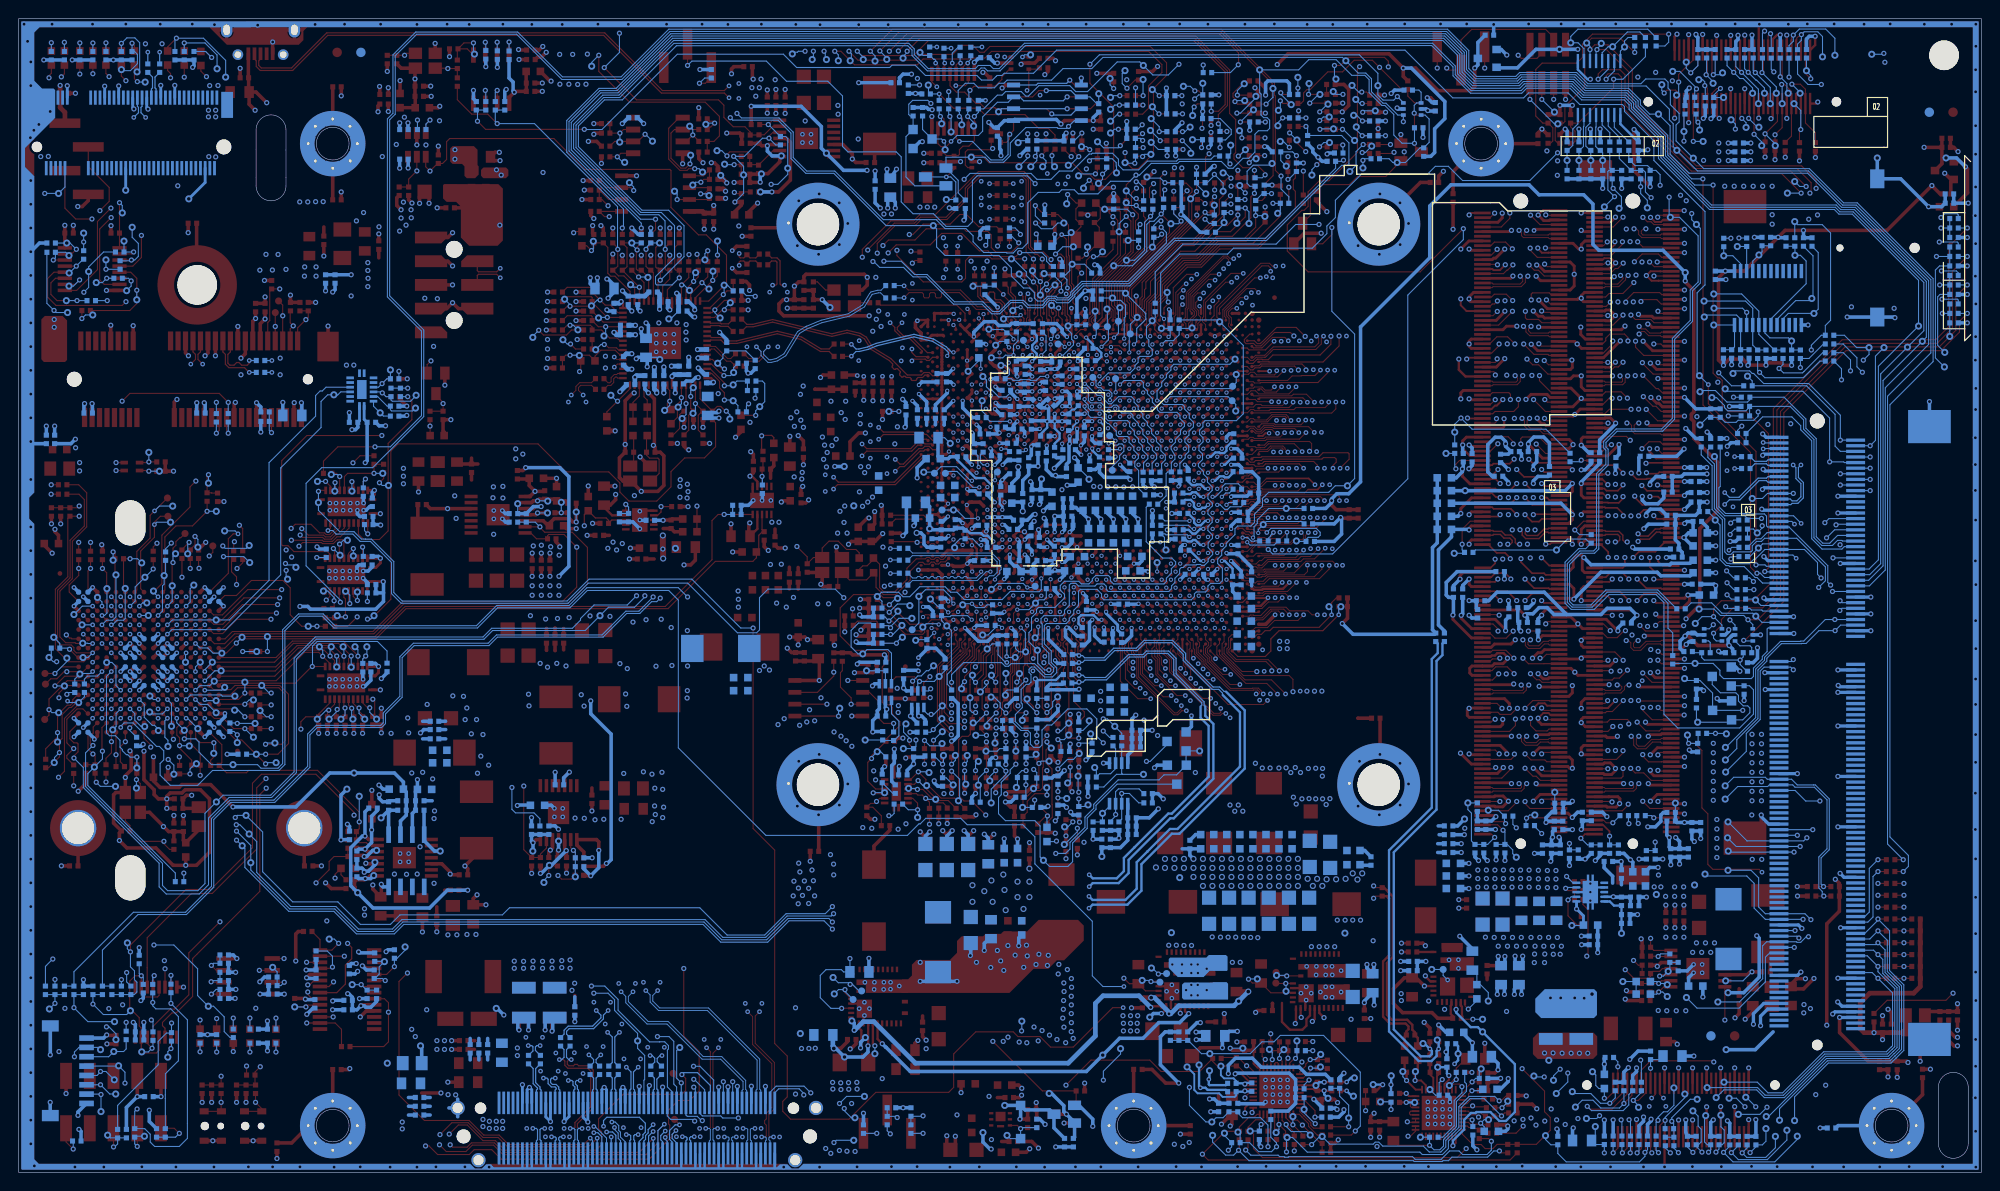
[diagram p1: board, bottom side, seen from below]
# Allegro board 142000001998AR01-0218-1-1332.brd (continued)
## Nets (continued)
DCPSUSBYP_C: C382.2 U9.AU21(DCPSUSBYP_1) U9.AW21(DCPSUSBYP_2)
DDR0_CLK_DN_1: R559.2 U9.CM45(DDR0_CLK_DN_1)
DDR0_CLK_DN_3: R557.2 U9.CL43(DDR0_CLK_DN_3)
DDR0_CLK_DP_1: R559.1 U9.CK45(DDR0_CLK_DP_1)
DDR0_CLK_DP_3: R557.1 U9.CJ43(DDR0_CLK_DP_3)
DDR1_CLK_DN_1: R571.2 U9.CR54(DDR1_CLK_DN_1)
DDR1_CLK_DN_3: R566.2 U9.CT53(DDR1_CLK_DN_3)
DDR1_CLK_DP_1: R571.1 U9.CU54(DDR1_CLK_DP_1)
DDR1_CLK_DP_3: R566.1 U9.CV53(DDR1_CLK_DP_3)
DDR01_CPU_VREFCA: R562.1 U9.CR52(DDR_VREF)
DDR01_VREFCA: C98.1 C489.2 C490.2 CONN7.164(VREFCA) CONN8.164(VREFCA) R200.1 R562.2 R580.2
DDR4_EVENT_MOS: Q8.D Q11.G R603.2
DDR4_VPP: C167.A C168.1 C169.1 C170.2 C171.2 C541.1 C542.1 C543.1 C550.1 C551.1 C552.1 CONN7.257(VPP_1) CONN7.259(VPP_2) CONN8.257(VPP_1) CONN8.259(VPP_2) L18.2 R345.1 R606.1 R652.1 R655.1 R676.1 R877.1 R878.1 R879.1 R880.2
DDR4_VPP_AGND: C176.2 R344.2 R709.1 U23.5(GND)
DDR4_VPP_SS: R339.1 U23.4(SS)
DDR4_VPP_SS_C: C176.1 R339.2
DDR4_VPP_SW: C178.1 L18.1 U23.10(SW1) U23.11(SW2)
DDR4_VPP_VBST: C178.2 U23.12(VBST)
DDR4_VPP_VO: C189.1 R345.2 R711.1 U23.1(VO)
DDR4_VPP_VO_R: R708.1 R711.2
DDR4_VPP_VREG: C596.1 R701.2 U23.3(VREG5)
DDR_EVENT_1V2_N: Q8.G R570.2 R574.2 R606.2
DEV_OFF_N_R: R960.2 R961.2 U6.28(DEV_OFF_N)
DIFF_XCLK_BIASREF: R487.2 U9.AA18(DIFFCLK_BIASREF)
DIMM1_SPD: C527.1 C528.1 CONN7.255(VDDSPD) R646.2 R652.2
DIMM2_SPD: C518.1 C519.1 CONN8.255(VDDSPD) R654.2 R655.2
EN_OSC_25M: OSC2.1(EN) R154.2
ENTER/EXIT_SLEEP: CONN6.44(ENTER/EXIT SLEEP) R156.1 R157.2
EXT_UART1_CTS: CONN16.79 TP11.1(TP)
EXT_UART1_RTS: CONN16.76 TP12.1(TP)
FAULT_LED_OUT_N: CONN14.176 R336.2
FB_V1P8A: R611.2 R612.2 U35.4(FB)
FM_BIOS_RCRV_BOOT_N: R43.1 R454.2 U9.BU22(GPIO55)
FM_CPLD_P0V6_VTT_DIMM_EN: R325.2 U12.L4(IO_1_L4/DIFFIO_L18N)
FM_CPLD_P0V9_LAN1_EN: R185.1 U12.A12(IO_2_A12/DIFFIO_T16N)
FM_CPLD_P0V9_LAN_EN: R223.1 U12.M16(IO_3_M16/DIFFIO_R19P)
FM_CPLD_P1V8_LAN1_EN: R224.2 U12.T11(IO_4_T11/DIFFIO_B17N)
FM_CPLD_P1V8_LAN_EN: R225.2 U12.R5(IO_4_R5/DIFFIO_B6P)
FM_CPLD_V3P3_PCH_EN: Q6.G R367.2 U12.N13(IO_3_N13/DIFFIO_R24P)
FM_CPU_PROCHOT_PCH_N: CONN4.30 R86.1
FM_DDR4_VPP_CPLD_EN: R334.1 U12.L3(IO_1_L3/DIFFIO_L19N) U23.7(EN)
FM_ME_RCRV_N: R30.2 R445.1 U9.BP9(GPIO57_MGPIO5)
FM_NMI_EVENT_CPLD_N: R474.1 U12.D12(IO_2_D12/DIFFIO_T19P)
FM_NMI_EVENT_PCH_N: CONN4.6 R101.1 R442.1
FM_PROCHOT_N: R469.1 U12.C11(IO_2_C11)
FM_SMI_ACTIVE_CPLD_N: R75.1 R466.1 U12.E12(IO_3_E12)
FM_SMI_ACTIVE_PCH_N: CONN4.36 R73.1
FM_THROTTLE_N: R107.1 U12.C12(IO_2_C12/DIFFIO_T20N)
FM_THROTTLE_PCH_N: CONN4.28 R473.1 R477.1
FORCE_MEMPROCHOT: Q12.G Q13.G U12.K5(IO_1_K5/DIFFIO_L15P)
FP_LED9_N: LED17.C U12.M14(IO_3_M14/DIFFIO_R23P)
FP_LED9_N_R: LED17.A R718.1
FP_LED10_N: LED16.C U12.M12(IO_4_M12)
FP_LED10_N_R: LED16.A R717.1
GPIO33: R520.1 R523.2 U9.AN11(GPIO33)
GPIO61_JTAG_EN_R: R131.2 U9.BB18(SUS_STAT_N_GPIO61)
HS1_PIN1: C25.2 HS1.1
HS1_PIN2: C42.2 HS1.2
HS1_PIN3: C124.2 HS1.3
HS1_PIN4: C138.2 HS1.4
HW_BMC_PRESENT: CONN14.32 R913.1 R914.1
I2C_BUS-A0: R1057.2 R1058.2 U45.9(AD0)
I2C_BUS-A1: R1059.2 R1060.2 U45.10(AD1)
I2C_BUS-A2: R1061.2 R1062.2 U45.11(AD2)
I2C_BUS-A3: R1063.2 R1064.2 U45.12(AD3)
I2C_BUS_RESET: R1075.2 R1080.1 R1081.1 R1114.1
I2C_BUS_RESET_R: R1075.1 U12.M2(IO_1_M2/DIFFIO_L17N)
I2C_MULTIPLEXER_SELECT: CONN14.34 R917.2 R918.2 R1071.2 R1072.2 R1109.2 R1110.2
I2C_MUX_S1: R1109.1 U40.6(S)
I2C_MUX_S2: R1110.1 U41.6(S)
I210_JTAG_CLK: R977.1 U6.19(JTAG_CLK)
I210_JTAG_TDI: R978.1 U6.29(JTAG_TDI)
I210_JTAG_TDO: R975.1 U6.4(JTAG_TDO)
I210_JTAG_TMS: R976.1 U6.18(JTAG_TMS)
I210_LAN_PWR_GOOD: R963.1 U12.R16(IO_4_R16/DIFFIO_B24P)
I210_LAN_PWR_GOOD_R: R821.2 R822.1 R963.2 U6.1(LAN_PWR_GOOD)
I210_LINK_STATUS: CONN14.56 U12.F15(IO_3_F15/DIFFIO_R8P)
I210_RESET_N_R: R957.2 U6.48(RSET)
I210_RST_L: R881.1 U12.R4(IO_4_R4)
I210_RST_L_R: R881.2 R882.2 R979.2 U6.17(PE_RST_N)
I210_SDP0: R1037.2 R1038.2 U6.63(SDP0)
I210_SDP1: R1039.2 R1040.2 U6.61(SDP1/PCIE_DIS)
I210_SDP2: R1041.2 R1042.2 U6.62(SDP2)
I210_SDP3: R1043.2 R1044.2 U6.60(SDP3)
I210_SMB_ALRT_R: R1034.2 R1035.2 U6.35(SMB_ALRT_N)
I210_SMB_SCL: R807.2 R1033.2 U6.34(SMB_CLK)
I210_SMB_SDA: R808.2 R1031.2 U6.36(SMB_DAT)
I210_XTAL_I: R956.1 R962.2 U6.46(XTAL1)
I210_XTAL_I_R: C650.2 OSC6.1 R962.1
I210_XTAL_O: R806.2 R956.2 U6.45(XTAL2)
I210_XTAL_O_R: C649.1 OSC6.3 R806.1
ID_BTN_BMC_N: CONN14.173 R327.1
ID_LED STATUS SENSE: CONN14.41 R947.2 U12.E9(IO_2_E9/DIFFIO_T12P)
ID_LED_BMC_N: CONN14.178 R338.2
INT0: R1111.1 U45.1(I\N\T\0\)
INT1: R1112.1 U45.7(I\N\T\1\)
INT-IN: R1113.1 U45.15(I\N\T\_\I\N\)
IP_UART0_SIN: CONN16.62 R12.1
IP_UART0_SIN_R: R12.2 U9.AY11(SUSWARN_N_SUSPWRDNACK_GPIO30)
IP_UART0_SOUT: CONN16.93 R26.1
IP_UART0_SOUT_R: R26.2 U9.BB12(SLP_WLAN_N_GPIO29_MGPIO3)
IR3570_RRES: R743.1 U29.6(RRES)
IR3570_V18A: C218.1 C233.1 R729.1 U29.8(V18A)
IRQ_PCH_WHEA_N: R84.1 U9.BB28(BMBUSY_N_GPIO0)
JTAG_TCK: R664.1 R702.2 U12.P3(TCK)
JTAG_TCK_R: CONN9.1 R702.1 R703.1
JTAG_TDI: CONN9.9 R707.2 R843.1 U12.L6(TDI)
JTAG_TDO: R695.1 R704.2 U12.M5(TDO)
JTAG_TDO_R: CONN9.3 R704.1
JTAG_TMS: R696.1 R706.2 U12.N4(TMS)
JTAG_TMS_R: CONN9.5 R705.2 R706.1
KR_EPHY_DFTANA_0: R271.1 R630.2 U9.H71(RSVD_2)
KR_EPHY_DFTANA_1: R222.2 R590.1 U9.K71(RSVD_1)
KR_EPHY_DFTDIG_0: R582.2 U9.J69(RSVD_4)
LAN_NCSI_CRS_DV: R785.1 U9.V74(LAN_NCSI_CRS_DV)
LAN_NCSI_TRI_EN: R787.2 R793.1 U9.AD78(LAN_NCSI_TRI_EN_PECI_ID1)
LAN_PWR_GD: R239.1 U9.AE77(LAN_PWRGOOD)
LAN_SDP0_0: R617.1 U9.G74(LAN_SDP0_0)
LAN_SDP0_1: R598.1 U9.C76(LAN_SDP0_1)
LAN_SDP1_0: R272.1 U9.F76(LAN_SDP1_0)
LAN_SDP1_1: R584.1 U9.N69(LAN_SDP1_1)
LGSPARE4_DDR_STRAP: R262.2 R524.2 U9.AK69(DDR3_4_STRAP)
LM75_A0_CH3: R313.1 R314.2 U20.7(A0)
LM75_A1_CH3: R312.1 U20.6(A1)
LM75_A2_CH3: R311.1 U20.5(A2)
LM75BD2_INT: R298.2 R299.2 U12.L13(IO_3_L13/DIFFIO_R20P)
LM75BD2_INT_R: R299.1 U20.3(OS)
LM75BD2_SCLK_C: C130.1 R297.1
LPC_DEBUG_RST: CONN14.2 U12.T6(IO_4_T6/DIFFIO_B9P)
LPC_LFRAME_N: CONN14.12 CONN15.2 R136.1 U12.C2(IO_1_C2/DIFFIO_L1N) U17.22(LFRAME#)
LPC_LFRAME_N_R: R136.2 U9.AH1(LFRAME_N)
LPC_PD: CONN14.4 R346.2
LPC_PME_N: CONN14.6 R540.2
MAC_INT_L: CONN16.73 R35.1 R910.2 U12.R10(IO_4_R10/DIFFIO_B16P)
MAC_INT_L_R: R35.2 U9.BD18(GPIO44)
MAC_MDC0: CONN16.101 R846.2
MAC_MDC0_R: R828.1 R846.1 U6.55(MDI_PLUS[1])
MAC_MDIO0: CONN16.97 R847.2
MAC_MDIO0_R: R829.1 R847.1 U6.57(MDI_MINUS[0])
MAC_SGMII_RX_N: C665.1 CONN16.107
MAC_SGMII_RX_N_R: C665.2 U6.49(MDI_MINUS[3])
MAC_SGMII_RX_P: C664.1 CONN16.105
MAC_SGMII_RX_P_R: C664.2 U6.50(MDI_PLUS[3])
MAC_SGMII_TX_N: CONN16.111 U6.52(MDI_MINUS[2])
MAC_SGMII_TX_P: CONN16.113 U6.53(MDI_PLUS[2])
MAC_WAKE_N: R801.1 U6.16(PE_WAKE_N) U38.4(B)
MANF_MODE_STRAP: R22.2 U9.BD22(MFG_MODE_STRAP)
MANU_RST: CONN16.52 R713.1 R845.1
MANU_RST_R: R845.2 U12.P15(IO_3_P15/DIFFIO_R23N)
MB_LM75BD_CLK: CONN16.119 R674.2 R686.2
MB_LM75BD_DATA: CONN16.117 R661.2 R668.2
MSATA_NC19: CONN6.43(NC19) R902.2
MSATA_SMB_PCU_CLK_P3V3: CONN6.30(SMB_CLK) R159.2
MSATA_SMB_PCU_DATA_P3V3: CONN6.32(SMB_DATA) R158.2
NC_TEST_EAR_N: R583.2 U9.AH62(EAR_N)
NIC1_DEV_OFF_N_R: TP51.1(TP) U12.A6(IO_2_A6/DIFFIO_T8N)
NIC1_LAN_PWR_GOOD: TP50.1(TP) U12.D5(IO_2_D5)
NIC1_NCSI_CLKIN: C275.1 R120.1 R853.2 R1011.2 R1012.2 U6.2(NC_SI_CLK_IN)
NIC1_NCSI_CLKIN_R: R120.2 U5.2(Q0)
NIC1_NCSI_CRS_DV: CONN14.54 R860.1
NIC1_NCSI_CRS_DV_R: R860.2 R864.2 R1009.2 U6.3(NC_SI_CRS_DV)
NIC1_NCSI_RXD0: CONN14.49 R858.1
NIC1_NCSI_RXD0_R: R858.2 R862.2 R999.2 U6.6(NC_SI_RXD0)
NIC1_NCSI_RXD1: CONN14.51 R859.1
NIC1_NCSI_RXD1_R: R859.2 R863.2 R1001.2 U6.5(NC_SI_RXD1)
NIC1_NCSI_TXD0: CONN14.50 R855.2 R1003.2 U6.9(NC_SI_TXD0)
NIC1_NCSI_TXD1: CONN14.52 R856.2 R1005.2 U6.8(NC_SI_TXD1)
NIC1_NCSI_TXEN: CONN14.48 R857.2 R1007.2 U6.7(NC_SI_TX_EN)
NIC2_CBOT: C841.2 U6.37(CBOT)
NIC2_CTOP: C841.1 U6.40(CTOP)
NIC2_LAN_PWR_GOOD: R187.2 U12.A13(IO_2_A13)
NMI_BTN_IN_BMC: CONN14.175 R908.2
NMI_BTN_IN_BMC_R: R908.1 U12.H16(IO_3_H16/DIFFIO_R12N)
NMI_BTN_OUT_BMC_N: CONN14.174 R332.2
NOUSED_IRTN1_L2: U29.31(ISEN1_L2) U29.32(IRTN1_L2)
NOUSED_IRTN2: U29.37(ISNE2) U29.38(IRTN2)
NOUSED_IRTN2_L2: U29.33(ISEN2_L2) U29.34(IRTN2_L2)
NOUSED_IRTN3: U29.35(ISEN3) U29.36(IRTN3)
NUT1_GND: C12.1 NUT1.1
NUT2_GND: C127.1 NUT2.1
NUT3_GND: C126.1 NUT3.1
NV_SAVE_CH0_D1: TP4.1(TP) U12.J16(IO_3_J16/DIFFIO_R13N)
NV_SAVE_CH1_D1: R885.2 U12.H15(IO_3_H15/DIFFIO_R11N)
P0_1_SCL_R: R531.1 R532.1 U33.5(SC0)
P0_1_SDA_R: R533.1 R534.1 U33.4(SD0)
P0_LINKLED_L: R944.1 U12.F13(IO_3_F13/DIFFIO_R4N)
P0_LINKLED_L_R: R868.1 R944.2 U6.30(LED1)
P0_SPD100LED_L: R945.1 U12.F14(IO_3_F14/DIFFIO_R3N)
P0_SPD100LED_L_R: R945.2 U6.31(LED0)
P0_SPD1000LED_L: R919.1 U12.F12(IO_3_F12/DIFFIO_R5N)
P0_SPD1000LED_L_R: R919.2 U6.33(LED2)
P1_1_SCL_R: R493.1 R494.1 U33.7(SC1)
P1_1_SDA_R: R529.1 R530.1 U33.6(SD1)
P3_SC2: R495.2 U33.9(SC2)
P3_SD2: R496.2 U33.8(SD2)
P1014_RST: CONN16.68 R231.2
P1014_RST_R: R231.1 R503.2 U12.T15(IO_4_T15/DIFFIO_B23N)
PCA9517_VCCB: C522.1 C526.1 C529.1 R675.2 R676.2 U36.8(VCCB)
PCA9548_1_A0: R527.2 R528.1 U33.1(A0)
PCA9548_1_A1: R525.1 R526.2 U33.2(A1)
PCA9548_1_A2: R491.1 R492.2 U33.21(A2)
PCA9548_RESET_N: U12.F5(IO_1_F5/DIFFIO_L6N) U33.3(R\E\S\E\T\)
PCH_A20GATE: R10.1 U9.BL14(RSVD_15)
PCH_APWROK: R184.2 U9.BE13(APWROK)
PCH_BATLOW: R478.1 U9.BB4(GPIO72)
PCH_CPU2PCH_R_THROT: R186.1 U12.C6(IO_2_C6/DIFFIO_T3N)
PCH_CPU2PCH_THROT: R65.1 R186.2
PCH_CPU2PCH_THROT_R: R65.2 U9.BL22(PIRQG_N_GPIO4)
PCH_DPWROK: R71.2 R464.1 U9.AV4(DPWROK)
PCH_PLTRST_N: R66.1 R228.1
PCH_PLTRST_N_R: R66.2 U9.BE24(PLTRST_N)
PCH_PLTRST_R_N: R228.2 U12.M10(IO_4_M10/DIFFIO_B16N)
PCH_PM_SYNC: R47.2 U9.BT9(PM_SYNC_PCH)
PCH_PM_SYNC_R: R47.1 U9.H77(PMSYNC_CPU)
PCH_PME_N: R50.1 R540.1 U9.BE16(PME_N)
PCH_PWRBTN_N: R109.1 R423.2 R759.2 U9.AW3(PWRBTN_N) U12.C5(IO_2_C5/DIFFIO_T2N)
PCH_PWROK: R189.1 U9.AN1(PCH_PWROK)
PCH_RSMRST_N: R64.1 R72.2 R464.2 U12.C4(IO_2_C4)
PCH_RSMRST_N_R: R72.1 U9.AR7(RSMRST_N)
PCH_SERIRQ: CONN14.8 Q10.4(B) R28.1 U9.BU14(SERIRQ) U17.27(SERIRQ)
PCH_SLP_S3_N: R125.1 R221.2 R667.2
PCH_SLP_S3_N_R: R125.2 U9.AY2(SLP_S3_N)
PCH_SLP_S3_R_N: R221.1 U12.P2(IO_1_P2/DIFFIO_L21N)
PCH_SLP_S4_N: R126.1 R182.1
PCH_SLP_S4_N_R: R126.2 U9.AW1(SLP_S4_N)
PCH_SLP_S4_R_N: R182.2 U12.D6(IO_2_D6/DIFFIO_T4N)
PCH_SYS_PWROK: R18.2 R218.2 R438.1 U12.E5(IO_1_E5)
PCH_SYS_PWROK_R: R18.1 U9.BP5(SYS_PWROK)
PCH_SYSRESET_N: R85.1 R105.2 R195.1
PCH_SYSRESET_N_R: R195.2 U12.B16(IO_2_B16/DIFFIO_T21N)
PCH_SYSRESET_R_N: R105.1 U9.BL4(SYS_RESET_N)
PCH_THERMTRIP_N: R69.2 R463.2 U13.15(B7)
PCH_THERMTRIP_N_R: R69.1 U9.BJ16(THERMTRIP_PCH_N)
PCH_WAKE_N: Q2.D R110.2 R447.2 R803.2
PCH_WAKE_N_R: R110.1 U9.BA1(W\A\K\E\)
PCH_WAKE_R_N: R803.1 U38.3(A)
PCH_XDP_NCLK1: CONN4.4 R114.1
PCIE2_MGMT_MAC_C_TX0_N: C57.1 U9.J9(PCIE_TX_DN_1)
PCIE2_MGMT_MAC_C_TX0_P: C60.1 U9.F9(PCIE_TX_DP_1)
PCIE2_MGMT_MAC_RX0_N: C644.2 U9.D15(PCIE_RX_DN_1)
PCIE2_MGMT_MAC_RX0_N_R: C644.1 U6.20(PE_TN)
PCIE2_MGMT_MAC_RX0_P: C643.2 U9.B15(PCIE_RX_DP_1)
PCIE2_MGMT_MAC_RX0_P_R: C643.1 U6.21(PE_TP)
PCIE2_MGMT_MAC_TX0_N: C57.2 U6.23(PE_RN)
PCIE2_MGMT_MAC_TX0_P: C60.2 U6.24(PE_RP)
PCIE3_100G_C_TX_DN_0: C620.1 U9.D30(PE1_TX_DN_0)
PCIE3_100G_C_TX_DN_1: C621.1 U9.C31(PE1_TX_DN_1)
PCIE3_100G_C_TX_DN_2: C247.1 U9.D32(PE1_TX_DN_2)
PCIE3_100G_C_TX_DN_3: C623.1 U9.C34(PE1_TX_DN_3)
PCIE3_100G_C_TX_DP_0: C619.1 U9.B30(PE1_TX_DP_0)
PCIE3_100G_C_TX_DP_1: C622.1 U9.A31(PE1_TX_DP_1)
PCIE3_100G_C_TX_DP_2: C246.1 U9.B32(PE1_TX_DP_2)
PCIE3_100G_C_TX_DP_3: C624.1 U9.A34(PE1_TX_DP_3)
PCIE3_100G_RX_DN_0: CONN16.35 U9.J24(PE1_RX_DN_0)
PCIE3_100G_RX_DN_1: CONN16.27 U9.K26(PE1_RX_DN_1)
PCIE3_100G_RX_DN_2: CONN16.26 U9.J28(PE1_RX_DN_2)
PCIE3_100G_RX_DN_3: CONN16.18 U9.K30(PE1_RX_DN_3)
PCIE3_100G_RX_DP_0: CONN16.33 U9.F24(PE1_RX_DP_0)
PCIE3_100G_RX_DP_1: CONN16.25 U9.H26(PE1_RX_DP_1)
PCIE3_100G_RX_DP_2: CONN16.28 U9.F28(PE1_RX_DP_2)
PCIE3_100G_RX_DP_3: CONN16.20 U9.H30(PE1_RX_DP_3)
PCIE3_100G_TX_DN_0: C620.2 CONN16.49
PCIE3_100G_TX_DN_1: C621.2 CONN16.43
PCIE3_100G_TX_DN_2: C247.2 CONN16.34
PCIE3_100G_TX_DN_3: C623.2 CONN16.19
PCIE3_100G_TX_DP_0: C619.2 CONN16.51
PCIE3_100G_TX_DP_1: C622.2 CONN16.41
PCIE3_100G_TX_DP_2: C246.2 CONN16.36
PCIE3_100G_TX_DP_3: C624.2 CONN16.17
PCIE_BMM_RX_N: CONN14.5 U9.C9(PCIE_RX_DN_6)
PCIE_BMM_RX_P: CONN14.3 U9.A9(PCIE_RX_DP_6)
PCIE_BMM_TX_C_N: C354.1 U9.R16(PCIE_TX_DN_6)
PCIE_BMM_TX_C_P: C340.1 U9.N16(PCIE_TX_DP_6)
PCIE_BMM_TX_N: C354.2 CONN14.11
PCIE_BMM_TX_P: C340.2 CONN14.9
PCIE_CLK_B2B_CONN_N: CONN16.58 R1092.1 R1095.2
PCIE_CLK_B2B_CONN_P: CONN16.60 R1093.1 R1094.2
PCIE_CLK_BMM_N: CONN14.17 R144.1
PCIE_CLK_BMM_P: CONN14.15 R145.1
PCIE_CLK_MAC_N: C704.2 R509.1
PCIE_CLK_MAC_N_R: C704.1 U6.25(PECLKN)
PCIE_CLK_MAC_P: C703.2 R508.1
PCIE_CLK_MAC_P_R: C703.1 U6.26(PECLKP)
PCIE_CLK_R_B2B_CONN_N: R1092.2 U9.R2(CLKOUT_PCIE_DN_5)
PCIE_CLK_R_B2B_CONN_P: R1093.2 U9.R4(CLKOUT_PCIE_DP_5)
PCIE_CLK_R_BMM_N: R144.2 U9.Y1(CLKOUT_PCIE_DN_1)
PCIE_CLK_R_BMM_P: R145.2 U9.Y3(CLKOUT_PCIE_DP_1)
PCIE_CLK_R_MAC_N: R509.2 U9.U2(CLKOUT_PCIE_DN_0)
PCIE_CLK_R_MAC_P: R508.2 U9.U4(CLKOUT_PCIE_DP_0)
PCIE_OOB_RX_N: CONN16.57 U9.D10(PCIE_RX_DN_5)
PCIE_OOB_RX_P: CONN16.59 U9.B10(PCIE_RX_DP_5)
PCIE_OOB_TX_C_N: C245.1 U9.T18(PCIE_TX_DN_5)
PCIE_OOB_TX_C_P: C244.1 U9.P18(PCIE_TX_DP_5)
PCIE_OOB_TX_N: C245.2 CONN16.67
PCIE_OOB_TX_P: C244.2 CONN16.69
PCIE_RST_N: CONN14.21 CONN16.74 Q5.G U12.P4(IO_4_P4/DIFFIO_B1N)
PD_BDX_SPARE1: R263.2 R289.1 U9.AC64(RSVD_22)
PD_BDX_SPARE2: R258.1 R616.2 U9.AN78(RSVD_21)
PD_BDX_SPARE3: R264.2 R625.1 U9.AG67(RSVD_20)
PD_BDX_SPARE4: R266.1 R626.2 U9.AJ67(RSVD_19)
PD_CPU_TSTCLK_DN: R274.1 U9.F54(RSVD_26)
PD_CPU_TSTCLK_DP: R627.1 U9.J54(RSVD_25)
PD_CPU_TSTSTRAP0: R202.1 U9.E55(RSVD_27)
PD_FIVR_CLKREF: R259.1 U9.AP75(RSVD_47)
PD_GPIO53: R554.1 U9.BT20(GPIO53)
PD_LAN_NCSI_CLKIN: R578.2 U9.AA72(LAN_NCSI_CLK_IN)
PD_N1_BB_DCMI_FRU_A0: R677.2 R687.1 U19.1(A0)
PD_N1_BB_DCMI_FRU_A1: R660.1 R672.2 U19.2(A1)
PD_N1_BB_DCMI_FRU_WP: R663.1 R673.2 U19.7(WP)
PD_NCSI_RXD1: R268.2 R293.1 U9.W72(LAN_NCSI_RXD1)
PD_TD_IREF: R535.2 U9.P11(TD_IREF)
PD_TSTCLK_SC_DN: R213.1 U9.A73(RSVD_6)
PD_TSTCLK_SC_DP: R216.1 U9.A74(RSVD_5)
PE_WAKE_R_N: R256.1 U9.AD76(WAKELAN_N)
PE_WAKELAN_N: Q4.G R256.2 R614.2
PHSFLT_VDDQ: QFN1.18(PHSFLT#) R347.1
PLD_TPM_PP: R631.1 R954.1 R1086.2 U17.7(PP)
PLD_TPM_PP_R: R1086.1 U12.R13(IO_4_R13/DIFFIO_B21N)
PM_P1V7_FB: C160.2 R324.2 R698.1 U22.2(VFB)
PM_V1P1_FB: C189.2 R344.1 R708.2 U23.2(VFB)
PM_V3P3_FB: C636.2 R384.2 R748.1 U27.2(VFB)
PM_V3P3A_FB: C513.2 R279.2 R629.1 U15.2(VFB)
PM_V5A_FB: C24.2 R68.1 R74.2 U4.2(VFB)
PM_VDDQ_EN_R: R319.1 R325.1 U37.7(EN)
PRESENSE DETECT: CONN6.51(PRESENCE DECTION) R95.1 R96.2
PRGD_PLTRST_DIR1: R542.1 U34.2(1DIR)
PRGD_PLTRST_DIR2: R541.1 U34.3(2DIR)
PS_12V_LVIN1: C186.1 C195.1 C200.1 C209.1 C600.1 C606.1 C615.1 C616.1 C652.1 C701.1 L25.2 R719.2 U25.18(VIN1) U25.19(VIN2) U25.20(VIN3) U25.21(VIN4) U25.22(VIN5) U25.23(VIN6) U26.18(VIN1) U26.19(VIN2) U26.20(VIN3) U26.21(VIN4) U26.22(VIN5) U26.23(VIN6)
PS_12V_LVIN3: C201.1 C208.1 C217.1 C702.1 L26.2 U24.18(VIN1) U24.19(VIN2) U24.20(VIN3) U24.21(VIN4) U24.22(VIN5) U24.23(VIN6)
PS_PWR_GD: R226.1 U12.R3(IO_4_R3/DIFFIO_B3P)
PS_PWROK: CONN14.37 R946.2 U12.E8(IO_2_E8)
PSHBTN_SYS_RESET_N: C601.1 R712.2 R713.2 R714.1 U12.L14(IO_3_L14/DIFFIO_R21P)
PU_ADR_IN_RSV: R290.1 R632.2 U9.AD66(ADR_IN)
PU_BDX_SPARE5: R244.1 U9.D71(RSVD_18)
PU_DSWODVREN: R127.1 U9.AL1(DSWODVREN)
PU_DSWODVREN_R: R127.2 R499.1
PU_GPIO51: R57.1 U9.BL18(GPIO51)
PU_KR_EPHY_RBIAS: R569.2 U9.P56(LAN_RBIAS)
PU_LAN_I2C_SCL0: R270.1 U9.R72(LAN_I2C_SCL0)
PU_LAN_I2C_SCL1: R269.1 U9.P71(LAN_I2C_SCL1)
PU_LAN_I2C_SDA0: R294.1 U9.U72(LAN_I2C_SDA0)
PU_LAN_I2C_SDA1: R295.1 U9.T71(LAN_I2C_SDA1)
PU_N1_BB_DCMI_FRU_A2: R644.2 R651.1 U19.3(A2)
PU_NCSI_RXD0: R267.2 R292.1 R502.1 U9.Y71(LAN_NCSI_RXD0)
PU_NIC1_NVM_HOLD: R818.1 U39.7(/HOLD)
PU_NIC1_NVM_WP: R817.1 U39.3(/WP)
PU_PCH_RI_N: R24.1 U9.BF11(RI_N)
PU_PCH_SUSACK_N: R108.1 U9.AY4(SUSACK_N)
PU_PE_HP_SCL: R309.1 U9.AR67(PE_HP_SCL)
PU_PE_HP_SDA: R306.1 U9.AN67(PE_HP_SDA)
PU_PIRQA: R17.2 U9.BG20(PIRQA_N)
PU_PIRQB: R23.2 U9.BF22(PIRQB_N)
PU_PIRQC: R53.2 U9.AR11(PIRQC_N)
PU_PIRQD: R431.2 U9.BH22(PIRQD_N)
PU_SATA_RCOMP: R5.2 U9.BB32(SATA_RCOMP)
PU_SGPIO22_SATA_CLOCK: R37.1 R449.1 U9.BN14(SCLOCK_GPIO22)
PU_SGPIO38_PCH_SLOAD_R: R39.1 R451.1 U9.BP13(SLOAD_GPIO38)
PU_SGPIO39_SATA_DATAOUT0: R44.2 U9.BU18(SDATAOUT0_GPIO39)
PU_SGPIO48_SATA_DATAOUT1: R67.2 U9.BT16(SDATAOUT1_GPIO48)
PU_TXT_AGENT: R261.2 R624.1 U9.AM72(TXT_AGENT)
PU_TXT_PLTEN: R305.2 R645.1 U9.AP72(TXT_PLTEN)
PWM1_VDDQ_CH01: QFN1.19(PWM) U29.21(PWM1)
PWR_BTN_IN_BMC_N: CONN14.171 R911.2
PWR_BTN_IN_BMC_N_R: R911.1 U12.J14(IO_3_J14/DIFFIO_R14P)
PWR_BTN_OUT_BMC_N: CONN14.172 R331.2
PWRGD_DDR4_VPP: R337.2 R701.1 U12.K12(IO_3_K12/DIFFIO_R15N) U23.6(PG)
PWRGD_DDR4_VPP_LED5: LED5.C U12.B8(IO_2_B8/DIFFIO_T10N)
PWRGD_DDR4_VPP_R: LED5.A R409.2
PWRGD_P0V6_VTT_DIMM: R1087.2 U12.K11(IO_3_K11) U37.9(PGOOD)
PWRGD_P0V6_VTT_DIMM_LED7: LED7.C U12.B10(IO_2_B10/DIFFIO_T14P)
PWRGD_P0V6_VTT_DIMM_R: LED7.A R411.2
PWRGD_P0V9_LAN: R223.2 U12.M15(IO_3_M15)
PWRGD_P0V9_LAN1: R185.2 U12.A11(IO_2_A11/DIFFIO_T15N)
PWRGD_P1V5_PCH: C102.2 R201.1 U11.3(PG) U12.G2(IO_1_G2/DIFFIO_L8P)
PWRGD_P1V05_PCH: R740.1 U12.P8(IO_4_P8/DIFFIO_B10P) U28.3(VRDY2)
PWRGD_P1V05_PCH_LED4: LED4.C U12.B7(IO_2_B7)
PWRGD_P1V5_PCH_LED8: LED8.C U12.B11(IO_2_B11/DIFFIO_T16P)
PWRGD_P1V05_PCH_R: LED4.A R408.2
PWRGD_P1V5_PCH_R: LED8.A R412.2
PWRGD_P1V8_LAN: R225.1 U12.T4(IO_4_T4/DIFFIO_B5P)
PWRGD_P1V8_LAN1: R224.1 U12.T12(IO_4_T12/DIFFIO_B18P)
PWRGD_P3V3: R381.1 R382.2 U12.E6(IO_2_E6) U27.6(PG)
PWRGD_P3V3_A: CONN14.43 R226.2 R281.1 R282.2 U12.T2(IO_4_T2/DIFFIO_B2P) U15.6(PG)
PWRGD_P3V3_LED1: LED1.C U12.B4(IO_2_B4/DIFFIO_T4P)
PWRGD_P3V3_R: LED1.A R405.2
PWRGD_P5V_STBY: R42.2 R46.1 U4.6(PG) U12.F11(IO_3_F11/DIFFIO_R6N)
PWRGD_P5V_STBY_LED10: LED10.C U12.B3(IO_2_B3/DIFFIO_T3P)
PWRGD_P5V_STBY_R: LED10.A R404.2
PWRGD_PVCCIN: R744.1 U12.L7(IO_4_L7/DIFFIO_B9N) U28.9(VRDY1)
PWRGD_PVCCIN_LED9: LED9.C U12.B12(IO_2_B12/DIFFIO_T17N)
PWRGD_PVCCIN_R: LED9.A R413.2
PWRGD_PVCCKRHV: C81.2 R188.1 U8.3(PG) U12.J5(IO_1_J5/CLK1)
PWRGD_PVCCKRHV_LED3: LED3.C U12.B6(IO_2_B6/DIFFIO_T7P)
PWRGD_PVCCKRHV_R: LED3.A R407.2
PWRGD_PVCCSCFUSESUS: R694.2 R697.1 U12.F2(IO_1_F2) U22.6(PG)
PWRGD_PVCCSCFUSESUS_LED2: LED2.C U12.B5(IO_2_B5)
PWRGD_PVCCSCFUSESUS_R: LED2.A R406.2
RESET_MAC: CONN16.46 R7.1 U12.D15(IO_3_D15/DIFFIO_R4P)
RESET_MAC_R: R7.2 R901.2 U9.BD26(LAN_PHY_PWR_CTRL_GPIO12)
RP_1.05V_BOOST: C593.1 U24.3(BOOST)
RP_1.05V_LGATE1: TP36.1 U24.5(LGATE1)
RP_1.05V_LGATE2: TP34.1 U24.32(LGATE2)
RP_1.05V_R_I2C_SCL: R397.1 R770.2 R783.1 R784.1 U28.20(SM_CLK)
RP_1.05V_R_I2C_SCL_CONN12: CONN12.3 R784.2
RP_1.05V_R_I2C_SDA: R392.2 R396.1 R751.1 R753.1 U28.19(SM_DIO)
RP_1.05V_R_I2C_SDA_CONN12: CONN12.2 R751.2
RP_1.05V_R_REG_EN: R387.1 U28.10(EN_L2/INMODE/CAT_FLT)
RP_1.05V_R_SENSE_N: C628.2 R741.2 U28.26(VRTN_L2)
RP_1.05V_R_SENSE_P: C628.1 R733.2 U28.27(VSEN_L2)
RP_1.05V_REG_IOUT: R354.1 U24.26(IOUT)
RP_1.05V_REG_PHASE: C593.2 L17.1 U24.6(SW1) U24.7(SW2) U24.8(SW3) U24.9(SW4) U24.10(SW5) U24.11(SW6) U24.12(SW7) U24.13(SW8) U24.14(SW9) U24.15(SW10)
RP_1.05V_REG_PWM: U24.29(PWM) U28.25(PWM1_L2)
RP_1.05V_REG_R_IOUT: C213.2 R352.1 R354.2 U28.31(ISEN1_L2)
RP_1.05V_REG_RCSM: C220.1 R360.2 U28.29(RCSM_L2)
RP_1.05V_REG_RSCP: C220.2 R360.1 U28.30(RCSP_L2)
RP_1.05V_SENSE_N: R605.2 R741.1 U9.AP77(VSS_VCCGBE_SENSE)
RP_1.05V_SENSE_P: R604.1 R733.1 U9.AR78(VCCGBE_SENSE)
RP_1.8V_PHASE1_BOOST: C180.1 U25.3(BOOST)
RP_1.8V_PHASE1_LGATE1: TP37.1 U25.5(LGATE1)
RP_1.8V_PHASE1_LGATE2: TP35.1 U25.32(LGATE2)
RP_1.8V_PHASE2_BOOST: C179.1 U26.3(BOOST)
RP_1.8V_PHASE2_LGATE1: TP10.1 U26.5(LGATE1)
RP_1.8V_PHASE2_LGATE2: TP9.1 U26.32(LGATE2)
RP_1.8V_REG_IOUT1: R351.1 U25.26(IOUT)
RP_1.8V_REG_IOUT2: R355.1 U26.26(IOUT)
RP_1.8V_REG_ISEN3: U28.35(ISEN3) U28.36(IRTN3)
RP_1.8V_REG_ISEN4: U28.33(ISEN4) U28.34(IRTN4)
RP_1.8V_REG_PHASE1: C180.2 L15.1 U25.6(SW1) U25.7(SW2) U25.8(SW3) U25.9(SW4) U25.10(SW5) U25.11(SW6) U25.12(SW7) U25.13(SW8) U25.14(SW9) U25.15(SW10)
RP_1.8V_REG_PHASE2: C179.2 L16.1 U26.6(SW1) U26.7(SW2) U26.8(SW3) U26.9(SW4) U26.10(SW5) U26.11(SW6) U26.12(SW7) U26.13(SW8) U26.14(SW9) U26.15(SW10)
RP_1.8V_REG_PWM1: U25.29(PWM) U28.21(PWM1)
RP_1.8V_REG_PWM2: U26.29(PWM) U28.22(PWM2)
RP_1.8V_REG_R_EN: R395.1 U28.17(EN)
RP_1.8V_REG_R_HOT_OC: R394.1 U28.16(VR_HOT_ICRIT)
RP_1.8V_REG_R_IOUT1: C214.2 R351.2 R724.1 U28.39(ISEN1)
RP_1.8V_REG_R_IOUT2: C215.2 R353.1 R355.2 U28.37(ISEN2)
RP_1.8V_REG_R_TOUT: C633.1 R371.1 R377.2 U28.7(TSEN1)
RP_1.8V_REG_R_VINSEN: R393.1 U28.11(VINSEN)
RP_1.8V_REG_SV_ADDR: C258.2 R402.1 U28.12(SV_ADDR)
RP_1.8V_REG_TOUT: R371.2 U24.25(TOUT/FLT) U25.25(TOUT/FLT) U26.25(TOUT/FLT)
RP_1.8V_REG_V18A: C213.1 C214.1 C215.1 C248.2 C635.2 R352.2 R353.2 R724.2 U24.30(REFIN) U25.30(REFIN) U26.30(REFIN) U28.8(V18A) U28.32(IRTN1_L2) U28.38(IRTN2) U28.40(IRTN1)
RP_1.8V_REG_VINSEN: C607.2 R393.2 R719.1 R720.1
RP_1.8V_SENSE_N: R366.2 R599.1 U9.AT75(VSS_VCCIN_SENSE)
RP_1.8V_SENSE_N_R: C237.1 R366.1 U28.5(VRTN)
RP_1.8V_SENSE_P: R364.2 R600.2 U9.AT77(VCCIN_SENSE)
RP_1.8V_SENSE_P_R: C237.2 R364.1 U28.4(VSEN)
RP_3.3V_LVCC: C63.1 C64.1 C65.1 CONN13.2(3.3V_1) CONN13.4(3.3V_2) CONN13.70(3.3V_3) CONN13.72(3.3V_4) CONN13.74(3.3V_5) L6.1
RP_B_ERROR0: R241.2 U9.AC77(ERROR_N_0)
RP_B_ERROR1: R254.2 U9.AC75(ERROR_N_1)
RP_B_ERROR2: R247.2 U9.AB76(ERROR_N_2)
RP_BAT_3.3V: BA1.2(+) C272.2 C273.2 R113.1
RP_BAT_3.3V_QA: Q3.A1 R113.2
RP_CLKIN_GND_1_N: R548.1 U9.Y30(CLKIN_GND1_DN)
RP_CLKIN_GND_1_P: R549.1 U9.AA30(CLKIN_GND1_DP)
RP_CLKIN_GND_2_N: R545.1 U9.N35(CLKIN_GND2_DN)
RP_CLKIN_GND_2_P: R544.1 U9.P33(CLKIN_GND2_DP)
RP_CLKIN_GND_3_N: R142.1 U9.AB1(CLKIN_GND3_DN)
RP_CLKIN_GND_3_P: R143.1 U9.AB3(CLKIN_GND3_DP)
RP_CLKIN_GND_N4: R547.1 U9.BG32(CLKIN_GND4_DN)
RP_CLKIN_GND_P4: R553.1 U9.BH33(CLKIN_GND4_DP)
RP_CORE_1.8V_REG_RCSM: C223.2 R361.1 U28.2(RCSM)
RP_CORE_1.8V_REG_RSCP: C223.1 R361.2 U28.1(RCSP)
RP_DDR4_DIMM1_ACT_L: CONN7.114(ACT _N) U9.CF33(DDR0_ACT_N_MA_15)
RP_DDR4_DIMM1_ALERT_L: CONN7.116(ALERT _N) U9.CK33(DDR0_ALERT_N_PAR_ERR_N)
RP_DDR4_DIMM1_BA0: CONN7.150(BA0) U9.CH52(DDR0_BA_0)
RP_DDR4_DIMM1_BA1: CONN7.145(BA1) U9.CL51(DDR0_BA_1)
RP_DDR4_DIMM1_BG0: CONN7.115(BG0) U9.CM33(DDR0_BG0_BA_2)
RP_DDR4_DIMM1_BG1: CONN7.113(BG1) U9.CD35(DDR0_BG1_MA_14)
RP_DDR4_DIMM1_CKE0_L: CONN7.109(CKE0) U9.CD32(DDR0_CKE_0)
RP_DDR4_DIMM1_CKE1_L: CONN7.110(CKE1) U9.CG32(DDR0_CKE_1)
RP_DDR4_DIMM1_CLK0_N: CONN7.139(CK0N) U9.CJ47(DDR0_CLK_DN_0)
RP_DDR4_DIMM1_CLK0_P: CONN7.137(CK0P) U9.CL47(DDR0_CLK_DP_0)
RP_DDR4_DIMM1_CLK1_N: CONN7.140(CK1N) U9.CG47(DDR0_CLK_DN_2)
RP_DDR4_DIMM1_CLK1_P: CONN7.138(CK1P) U9.CF45(DDR0_CLK_DP_2)
RP_DDR4_DIMM1_CS0_L: CONN7.149(CS0_N) U9.CL54(DDR0_CS_N_0)
RP_DDR4_DIMM1_CS1_L: CONN7.157(CS1_N) U9.CJ58(DDR0_CS_N_1)
RP_DDR4_DIMM1_DQ0: CONN7.8(DQ0) U9.BY2(DDR0_DQ_0)
RP_DDR4_DIMM1_DQ1: CONN7.7(DQ1) U9.BY4(DDR0_DQ_1)
RP_DDR4_DIMM1_DQ2: CONN7.20(DQ2) U9.CD2(DDR0_DQ_2)
RP_DDR4_DIMM1_DQ3: CONN7.21(DQ3) U9.CD4(DDR0_DQ_3)
RP_DDR4_DIMM1_DQ4: CONN7.4(DQ4) U9.BW1(DDR0_DQ_4)
RP_DDR4_DIMM1_DQ5: CONN7.3(DQ5) U9.BW3(DDR0_DQ_5)
RP_DDR4_DIMM1_DQ6: CONN7.16(DQ6) U9.CC1(DDR0_DQ_6)
RP_DDR4_DIMM1_DQ7: CONN7.17(DQ7) U9.CC3(DDR0_DQ_7)
RP_DDR4_DIMM1_DQ8: CONN7.28(DQ8) U9.CC7(DDR0_DQ_8)
RP_DDR4_DIMM1_DQ9: CONN7.29(DQ9) U9.CB9(DDR0_DQ_9)
RP_DDR4_DIMM1_DQ10: CONN7.41(DQ10) U9.CM7(DDR0_DQ_10)
RP_DDR4_DIMM1_DQ11: CONN7.42(DQ11) U9.CL9(DDR0_DQ_11)
RP_DDR4_DIMM1_DQ12: CONN7.24(DQ12) U9.CA7(DDR0_DQ_12)
RP_DDR4_DIMM1_DQ13: CONN7.25(DQ13) U9.BY9(DDR0_DQ_13)
RP_DDR4_DIMM1_DQ14: CONN7.38(DQ14) U9.CK7(DDR0_DQ_14)
RP_DDR4_DIMM1_DQ15: CONN7.37(DQ15) U9.CJ9(DDR0_DQ_15)
RP_DDR4_DIMM1_DQ16: CONN7.50(DQ16) U9.CB13(DDR0_DQ_16)
RP_DDR4_DIMM1_DQ17: CONN7.49(DQ17) U9.CC14(DDR0_DQ_17)
RP_DDR4_DIMM1_DQ18: CONN7.62(DQ18) U9.CL13(DDR0_DQ_18)
RP_DDR4_DIMM1_DQ19: CONN7.63(DQ19) U9.CM14(DDR0_DQ_19)
RP_DDR4_DIMM1_DQ20: CONN7.46(DQ20) U9.BY13(DDR0_DQ_20)
RP_DDR4_DIMM1_DQ21: CONN7.45(DQ21) U9.CA14(DDR0_DQ_21)
RP_DDR4_DIMM1_DQ22: CONN7.58(DQ22) U9.CJ13(DDR0_DQ_22)
RP_DDR4_DIMM1_DQ23: CONN7.59(DQ23) U9.CK14(DDR0_DQ_23)
RP_DDR4_DIMM1_DQ24: CONN7.70(DQ24) U9.CD20(DDR0_DQ_24)
RP_DDR4_DIMM1_DQ25: CONN7.71(DQ25) U9.CB20(DDR0_DQ_25)
RP_DDR4_DIMM1_DQ26: CONN7.83(DQ26) U9.CD28(DDR0_DQ_26)
RP_DDR4_DIMM1_DQ27: CONN7.84(DQ27) U9.CB28(DDR0_DQ_27)
RP_DDR4_DIMM1_DQ28: CONN7.66(DQ28) U9.CF18(DDR0_DQ_28)
RP_DDR4_DIMM1_DQ29: CONN7.67(DQ29) U9.CC18(DDR0_DQ_29)
RP_DDR4_DIMM1_DQ30: CONN7.79(DQ30) U9.CF26(DDR0_DQ_30)
RP_DDR4_DIMM1_DQ31: CONN7.80(DQ31) U9.CC26(DDR0_DQ_31)
RP_DDR4_DIMM1_DQ32: CONN7.174(DQ32) U9.CD66(DDR0_DQ_32)
RP_DDR4_DIMM1_DQ33: CONN7.173(DQ33) U9.CB66(DDR0_DQ_33)
RP_DDR4_DIMM1_DQ34: CONN7.187(DQ34) U9.CD72(DDR0_DQ_34)
RP_DDR4_DIMM1_DQ35: CONN7.186(DQ35) U9.CB72(DDR0_DQ_35)
RP_DDR4_DIMM1_DQ36: CONN7.170(DQ36) U9.CF64(DDR0_DQ_36)
RP_DDR4_DIMM1_DQ37: CONN7.169(DQ37) U9.CC64(DDR0_DQ_37)
RP_DDR4_DIMM1_DQ38: CONN7.183(DQ38) U9.CF71(DDR0_DQ_38)
RP_DDR4_DIMM1_DQ39: CONN7.182(DQ39) U9.CC71(DDR0_DQ_39)
RP_DDR4_DIMM1_DQ40: CONN7.195(DQ40) U9.CL66(DDR0_DQ_40)
RP_DDR4_DIMM1_DQ41: CONN7.194(DQ41) U9.CJ66(DDR0_DQ_41)
RP_DDR4_DIMM1_DQ42: CONN7.207(DQ42) U9.CL72(DDR0_DQ_42)
RP_DDR4_DIMM1_DQ43: CONN7.208(DQ43) U9.CJ72(DDR0_DQ_43)
RP_DDR4_DIMM1_DQ44: CONN7.191(DQ44) U9.CM64(DDR0_DQ_44)
RP_DDR4_DIMM1_DQ45: CONN7.190(DQ45) U9.CK64(DDR0_DQ_45)
RP_DDR4_DIMM1_DQ46: CONN7.203(DQ46) U9.CM71(DDR0_DQ_46)
RP_DDR4_DIMM1_DQ47: CONN7.204(DQ47) U9.CK71(DDR0_DQ_47)
RP_DDR4_DIMM1_DQ48: CONN7.216(DQ48) U9.BT72(DDR0_DQ_48)
RP_DDR4_DIMM1_DQ49: CONN7.215(DQ49) U9.BU71(DDR0_DQ_49)
RP_DDR4_DIMM1_DQ50: CONN7.228(DQ50) U9.BG72(DDR0_DQ_50)
RP_DDR4_DIMM1_DQ51: CONN7.229(DQ51) U9.BH71(DDR0_DQ_51)
RP_DDR4_DIMM1_DQ52: CONN7.211(DQ52) U9.BV72(DDR0_DQ_52)
RP_DDR4_DIMM1_DQ53: CONN7.212(DQ53) U9.BW71(DDR0_DQ_53)
RP_DDR4_DIMM1_DQ54: CONN7.224(DQ54) U9.BJ72(DDR0_DQ_54)
RP_DDR4_DIMM1_DQ55: CONN7.225(DQ55) U9.BL71(DDR0_DQ_55)
RP_DDR4_DIMM1_DQ56: CONN7.237(DQ56) U9.BU67(DDR0_DQ_56)
RP_DDR4_DIMM1_DQ57: CONN7.236(DQ57) U9.BT66(DDR0_DQ_57)
RP_DDR4_DIMM1_DQ58: CONN7.249(DQ58) U9.BH67(DDR0_DQ_58)
RP_DDR4_DIMM1_DQ59: CONN7.250(DQ59) U9.BG66(DDR0_DQ_59)
RP_DDR4_DIMM1_DQ60: CONN7.232(DQ60) U9.BW67(DDR0_DQ_60)
RP_DDR4_DIMM1_DQ61: CONN7.233(DQ61) U9.BV66(DDR0_DQ_61)
RP_DDR4_DIMM1_DQ62: CONN7.245(DQ62) U9.BL67(DDR0_DQ_62)
RP_DDR4_DIMM1_DQ63: CONN7.246(DQ63) U9.BJ66(DDR0_DQ_63)
RP_DDR4_DIMM1_DQS0_N: CONN7.11(DQS0N) U9.CB4(DDR0_DQS_DN_0)
RP_DDR4_DIMM1_DQS0_P: CONN7.13(DQS0P) U9.CB2(DDR0_DQS_DP_0)
RP_DDR4_DIMM1_DQS1_N: CONN7.32(DQS1N) U9.CH7(DDR0_DQS_DN_1)
RP_DDR4_DIMM1_DQS1_P: CONN7.34(DQS1P) U9.CG9(DDR0_DQS_DP_1)
RP_DDR4_DIMM1_DQS2_N: CONN7.53(DQS2N) U9.CG13(DDR0_DQS_DN_2)
RP_DDR4_DIMM1_DQS2_P: CONN7.55(DQS2P) U9.CH14(DDR0_DQS_DP_2)
RP_DDR4_DIMM1_DQS3_N: CONN7.74(DQS3N) U9.CD24(DDR0_DQS_DN_3)
RP_DDR4_DIMM1_DQS3_P: CONN7.76(DQS3P) U9.CB24(DDR0_DQS_DP_3)
RP_DDR4_DIMM1_DQS4_N: CONN7.177(DQS4N) U9.CD69(DDR0_DQS_DN_4)
RP_DDR4_DIMM1_DQS4_P: CONN7.179(DQS4P) U9.CB69(DDR0_DQS_DP_4)
RP_DDR4_DIMM1_DQS5_N: CONN7.198(DQS5N) U9.CL69(DDR0_DQS_DN_5)
RP_DDR4_DIMM1_DQS5_P: CONN7.200(DQS5P) U9.CJ69(DDR0_DQS_DP_5)
RP_DDR4_DIMM1_DQS6_N: CONN7.219(DQS6N) U9.BM72(DDR0_DQS_DN_6)
RP_DDR4_DIMM1_DQS6_P: CONN7.221(DQS6P) U9.BN71(DDR0_DQS_DP_6)
RP_DDR4_DIMM1_DQS7_N: CONN7.240(DQS7N) U9.BN67(DDR0_DQS_DN_7)
RP_DDR4_DIMM1_DQS7_P: CONN7.242(DQS7P) U9.BM66(DDR0_DQS_DP_7)
RP_DDR4_DIMM1_DQS8_N: CONN7.95(DQS8N) U9.CL24(DDR0_DQS_DN_8)
RP_DDR4_DIMM1_DQS8_P: CONN7.97(DQS8P) U9.CJ24(DDR0_DQS_DP_8)
RP_DDR4_DIMM1_ECC0: CONN7.92(CB0 / NC) U9.CL20(DDR0_ECC_0)
RP_DDR4_DIMM1_ECC1: CONN7.91(CB1 / NC) U9.CJ20(DDR0_ECC_1)
RP_DDR4_DIMM1_ECC2: CONN7.101(CB2 / NC) U9.CL28(DDR0_ECC_2)
RP_DDR4_DIMM1_ECC3: CONN7.105(CB3 / NC) U9.CJ28(DDR0_ECC_3)
RP_DDR4_DIMM1_ECC4: CONN7.88(CB4 / NC) U9.CM18(DDR0_ECC_4)
RP_DDR4_DIMM1_ECC5: CONN7.87(CB5 / NC) U9.CK18(DDR0_ECC_5)
RP_DDR4_DIMM1_ECC6: CONN7.100(CB6 / NC) U9.CM26(DDR0_ECC_6)
RP_DDR4_DIMM1_ECC7: CONN7.104(CB7 / NC) U9.CK26(DDR0_ECC_7)
RP_DDR4_DIMM1_MA0: CONN7.144(A0) U9.CK49(DDR0_MA_0)
RP_DDR4_DIMM1_MA1: CONN7.133(A1) U9.CK41(DDR0_MA_1)
RP_DDR4_DIMM1_MA2: CONN7.132(A2) U9.CM41(DDR0_MA_2)
RP_DDR4_DIMM1_MA3: CONN7.131(A3) U9.CF41(DDR0_MA_3)
RP_DDR4_DIMM1_MA4: CONN7.128(A4) U9.CL39(DDR0_MA_4)
RP_DDR4_DIMM1_MA5: CONN7.126(A5) U9.CG39(DDR0_MA_5)
RP_DDR4_DIMM1_MA6: CONN7.127(A6) U9.CK37(DDR0_MA_6)
RP_DDR4_DIMM1_MA7: CONN7.122(A7) U9.CD39(DDR0_MA_7)
RP_DDR4_DIMM1_MA8: CONN7.125(A8) U9.CM37(DDR0_MA_8)
RP_DDR4_DIMM1_MA9: CONN7.121(A9) U9.CJ35(DDR0_MA_9)
RP_DDR4_DIMM1_MA10: CONN7.146(A10/AP) U9.CJ51(DDR0_MA_10)
RP_DDR4_DIMM1_MA11: CONN7.120(A11) U9.CG35(DDR0_MA_11)
RP_DDR4_DIMM1_MA12: CONN7.119(A12) U9.CF37(DDR0_MA_12)
RP_DDR4_DIMM1_MA13: CONN7.158(A13) U9.CK56(DDR0_MA_13)
RP_DDR4_DIMM1_MA14: CONN7.151(A14_WE_N) U9.CM52(DDR0_MA14_WE_N)
RP_DDR4_DIMM1_MA15: CONN7.156(A15_CAS_N) U9.CJ54(DDR0_MA15_CAS_N)
RP_DDR4_DIMM1_MA16: CONN7.152(A16_RAS_N) U9.CF49(DDR0_MA16_RAS_N)
RP_DDR4_DIMM1_ODT0: CONN7.155(ODT_0) U9.CF56(DDR0_ODT_0)
RP_DDR4_DIMM1_ODT1: CONN7.161(ODT_1) U9.CM60(DDR0_ODT_1)
RP_DDR4_DIMM1_PAR: CONN7.143(PAR) U9.CM49(DDR0_PAR)
RP_DDR4_DIMM1_R_EVENT_L: CONN7.134(EVENT _N) R570.1
RP_DDR4_DIMM1_R_RST_L: CONN7.108(RESET _N) R551.1
RP_DDR4_DIMM1_SA0: CONN7.256(SA0) R682.1 R683.1
RP_DDR4_DIMM1_SA1: CONN7.260(SA1) R684.1 R685.1
RP_DDR4_DIMM1_SA2: CONN7.166(SA2) R690.1 R691.1
RP_DDR4_DIMM2_ACT_L: CONN8.114(ACT _N) U9.CU41(DDR1_ACT_N_MA_15)
RP_DDR4_DIMM2_ALERT_L: CONN8.116(ALERT _N) U9.CT42(DDR1_ALERT_N_PAR_ERR_N)
RP_DDR4_DIMM2_BA0: CONN8.150(BA0) U9.CR61(DDR1_BA_0)
RP_DDR4_DIMM2_BA1: CONN8.145(BA1) U9.CT60(DDR1_BA_1)
RP_DDR4_DIMM2_BG0: CONN8.115(BG0) U9.CR41(DDR1_BG0_BA_2)
RP_DDR4_DIMM2_BG1: CONN8.113(BG1) U9.CV42(DDR1_BG1_MA_14)
RP_DDR4_DIMM2_CKE0_L: CONN8.109(CKE0) U9.CT40(DDR1_CKE_0)
RP_DDR4_DIMM2_CKE1_L: CONN8.110(CKE1) U9.CV38(DDR1_CKE_1)
RP_DDR4_DIMM2_CLK0_N: CONN8.139(CK0N) U9.CT58(DDR1_CLK_DN_0)
RP_DDR4_DIMM2_CLK0_P: CONN8.137(CK0P) U9.CV58(DDR1_CLK_DP_0)
RP_DDR4_DIMM2_CLK1_N: CONN8.140(CK1N) U9.CR57(DDR1_CLK_DN_2)
RP_DDR4_DIMM2_CLK1_P: CONN8.138(CK1P) U9.CU57(DDR1_CLK_DP_2)
RP_DDR4_DIMM2_CS0_L: CONN8.149(CS0_N) U9.CR63(DDR1_CS_N_0)
RP_DDR4_DIMM2_CS1_L: CONN8.157(CS1_N) U9.CV66(DDR1_CS_N_1)
RP_DDR4_DIMM2_DQ0: CONN8.8(DQ0) U9.CG1(DDR1_DQ_0)
RP_DDR4_DIMM2_DQ1: CONN8.7(DQ1) U9.CG3(DDR1_DQ_1)
RP_DDR4_DIMM2_DQ2: CONN8.20(DQ2) U9.CM3(DDR1_DQ_2)
RP_DDR4_DIMM2_DQ3: CONN8.21(DQ3) U9.CN4(DDR1_DQ_3)
RP_DDR4_DIMM2_DQ4: CONN8.4(DQ4) U9.CF2(DDR1_DQ_4)
RP_DDR4_DIMM2_DQ5: CONN8.3(DQ5) U9.CF4(DDR1_DQ_5)
RP_DDR4_DIMM2_DQ6: CONN8.16(DQ6) U9.CL2(DDR1_DQ_6)
RP_DDR4_DIMM2_DQ7: CONN8.17(DQ7) U9.CK4(DDR1_DQ_7)
RP_DDR4_DIMM2_DQ8: CONN8.28(DQ8) U9.CU8(DDR1_DQ_8)
RP_DDR4_DIMM2_DQ9: CONN8.29(DQ9) U9.CR8(DDR1_DQ_9)
RP_DDR4_DIMM2_DQ10: CONN8.41(DQ10) U9.CU13(DDR1_DQ_10)
RP_DDR4_DIMM2_DQ11: CONN8.42(DQ11) U9.CR13(DDR1_DQ_11)
RP_DDR4_DIMM2_DQ12: CONN8.24(DQ12) U9.CU5(DDR1_DQ_12)
RP_DDR4_DIMM2_DQ13: CONN8.25(DQ13) U9.CT7(DDR1_DQ_13)
RP_DDR4_DIMM2_DQ14: CONN8.38(DQ14) U9.CV12(DDR1_DQ_14)
RP_DDR4_DIMM2_DQ15: CONN8.37(DQ15) U9.CT12(DDR1_DQ_15)
RP_DDR4_DIMM2_DQ16: CONN8.50(DQ16) U9.CV16(DDR1_DQ_16)
RP_DDR4_DIMM2_DQ17: CONN8.49(DQ17) U9.CT16(DDR1_DQ_17)
RP_DDR4_DIMM2_DQ18: CONN8.62(DQ18) U9.CV20(DDR1_DQ_18)
RP_DDR4_DIMM2_DQ19: CONN8.63(DQ19) U9.CT20(DDR1_DQ_19)
RP_DDR4_DIMM2_DQ20: CONN8.46(DQ20) U9.CU15(DDR1_DQ_20)
RP_DDR4_DIMM2_DQ21: CONN8.45(DQ21) U9.CR15(DDR1_DQ_21)
RP_DDR4_DIMM2_DQ22: CONN8.58(DQ22) U9.CU19(DDR1_DQ_22)
RP_DDR4_DIMM2_DQ23: CONN8.59(DQ23) U9.CR19(DDR1_DQ_23)
RP_DDR4_DIMM2_DQ24: CONN8.70(DQ24) U9.CU24(DDR1_DQ_24)
RP_DDR4_DIMM2_DQ25: CONN8.71(DQ25) U9.CR24(DDR1_DQ_25)
RP_DDR4_DIMM2_DQ26: CONN8.83(DQ26) U9.CU28(DDR1_DQ_26)
RP_DDR4_DIMM2_DQ27: CONN8.84(DQ27) U9.CR28(DDR1_DQ_27)
RP_DDR4_DIMM2_DQ28: CONN8.66(DQ28) U9.CV23(DDR1_DQ_28)
RP_DDR4_DIMM2_DQ29: CONN8.67(DQ29) U9.CT23(DDR1_DQ_29)
RP_DDR4_DIMM2_DQ30: CONN8.79(DQ30) U9.CV27(DDR1_DQ_30)
RP_DDR4_DIMM2_DQ31: CONN8.80(DQ31) U9.CT27(DDR1_DQ_31)
RP_DDR4_DIMM2_DQ32: CONN8.174(DQ32) U9.CT73(DDR1_DQ_32)
RP_DDR4_DIMM2_DQ33: CONN8.173(DQ33) U9.CU74(DDR1_DQ_33)
RP_DDR4_DIMM2_DQ34: CONN8.187(DQ34) U9.CJ78(DDR1_DQ_34)
RP_DDR4_DIMM2_DQ35: CONN8.186(DQ35) U9.CJ76(DDR1_DQ_35)
RP_DDR4_DIMM2_DQ36: CONN8.170(DQ36) U9.CU71(DDR1_DQ_36)
RP_DDR4_DIMM2_DQ37: CONN8.169(DQ37) U9.CR71(DDR1_DQ_37)
RP_DDR4_DIMM2_DQ38: CONN8.183(DQ38) U9.CL77(DDR1_DQ_38)
RP_DDR4_DIMM2_DQ39: CONN8.182(DQ39) U9.CK75(DDR1_DQ_39)
RP_DDR4_DIMM2_DQ40: CONN8.195(DQ40) U9.CF77(DDR1_DQ_40)
RP_DDR4_DIMM2_DQ41: CONN8.194(DQ41) U9.CF75(DDR1_DQ_41)
RP_DDR4_DIMM2_DQ42: CONN8.207(DQ42) U9.CB77(DDR1_DQ_42)
RP_DDR4_DIMM2_DQ43: CONN8.208(DQ43) U9.CB75(DDR1_DQ_43)
RP_DDR4_DIMM2_DQ44: CONN8.191(DQ44) U9.CG78(DDR1_DQ_44)
RP_DDR4_DIMM2_DQ45: CONN8.190(DQ45) U9.CG76(DDR1_DQ_45)
RP_DDR4_DIMM2_DQ46: CONN8.203(DQ46) U9.CC78(DDR1_DQ_46)
RP_DDR4_DIMM2_DQ47: CONN8.204(DQ47) U9.CC76(DDR1_DQ_47)
RP_DDR4_DIMM2_DQ48: CONN8.216(DQ48) U9.BW78(DDR1_DQ_48)
RP_DDR4_DIMM2_DQ49: CONN8.215(DQ49) U9.BW76(DDR1_DQ_49)
RP_DDR4_DIMM2_DQ50: CONN8.228(DQ50) U9.BP78(DDR1_DQ_50)
RP_DDR4_DIMM2_DQ51: CONN8.229(DQ51) U9.BP76(DDR1_DQ_51)
RP_DDR4_DIMM2_DQ52: CONN8.211(DQ52) U9.BY77(DDR1_DQ_52)
RP_DDR4_DIMM2_DQ53: CONN8.212(DQ53) U9.BY75(DDR1_DQ_53)
RP_DDR4_DIMM2_DQ54: CONN8.224(DQ54) U9.BR77(DDR1_DQ_54)
RP_DDR4_DIMM2_DQ55: CONN8.225(DQ55) U9.BR75(DDR1_DQ_55)
RP_DDR4_DIMM2_DQ56: CONN8.237(DQ56) U9.BL77(DDR1_DQ_56)
RP_DDR4_DIMM2_DQ57: CONN8.236(DQ57) U9.BL75(DDR1_DQ_57)
RP_DDR4_DIMM2_DQ58: CONN8.249(DQ58) U9.BG77(DDR1_DQ_58)
RP_DDR4_DIMM2_DQ59: CONN8.250(DQ59) U9.BG75(DDR1_DQ_59)
RP_DDR4_DIMM2_DQ60: CONN8.232(DQ60) U9.BM78(DDR1_DQ_60)
RP_DDR4_DIMM2_DQ61: CONN8.233(DQ61) U9.BM76(DDR1_DQ_61)
RP_DDR4_DIMM2_DQ62: CONN8.245(DQ62) U9.BH78(DDR1_DQ_62)
RP_DDR4_DIMM2_DQ63: CONN8.246(DQ63) U9.BH76(DDR1_DQ_63)
RP_DDR4_DIMM2_DQS0_N: CONN8.11(DQS0N) U9.CJ1(DDR1_DQS_DN_0)
RP_DDR4_DIMM2_DQS0_P: CONN8.13(DQS0P) U9.CJ3(DDR1_DQS_DP_0)
RP_DDR4_DIMM2_DQS1_N: CONN8.32(DQS1N) U9.CU10(DDR1_DQS_DN_1)
RP_DDR4_DIMM2_DQS1_P: CONN8.34(DQS1P) U9.CR10(DDR1_DQS_DP_1)
RP_DDR4_DIMM2_DQS2_N: CONN8.53(DQS2N) U9.CV18(DDR1_DQS_DN_2)
RP_DDR4_DIMM2_DQS2_P: CONN8.55(DQS2P) U9.CT18(DDR1_DQS_DP_2)
RP_DDR4_DIMM2_DQS3_N: CONN8.74(DQS3N) U9.CU26(DDR1_DQS_DN_3)
RP_DDR4_DIMM2_DQS3_P: CONN8.76(DQS3P) U9.CR26(DDR1_DQS_DP_3)
RP_DDR4_DIMM2_DQS4_N: CONN8.177(DQS4N) U9.CM76(DDR1_DQS_DN_4)
RP_DDR4_DIMM2_DQS4_P: CONN8.179(DQS4P) U9.CN75(DDR1_DQS_DP_4)
RP_DDR4_DIMM2_DQS5_N: CONN8.198(DQS5N) U9.CD77(DDR1_DQS_DN_5)
RP_DDR4_DIMM2_DQS5_P: CONN8.200(DQS5P) U9.CD75(DDR1_DQS_DP_5)
RP_DDR4_DIMM2_DQS6_N: CONN8.219(DQS6N) U9.BT78(DDR1_DQS_DN_6)
RP_DDR4_DIMM2_DQS6_P: CONN8.221(DQS6P) U9.BT76(DDR1_DQS_DP_6)
RP_DDR4_DIMM2_DQS7_N: CONN8.240(DQS7N) U9.BJ77(DDR1_DQS_DN_7)
RP_DDR4_DIMM2_DQS7_P: CONN8.242(DQS7P) U9.BJ75(DDR1_DQS_DP_7)
RP_DDR4_DIMM2_DQS8_N: CONN8.95(DQS8N) U9.CV34(DDR1_DQS_DN_8)
RP_DDR4_DIMM2_DQS8_P: CONN8.97(DQS8P) U9.CT34(DDR1_DQS_DP_8)
RP_DDR4_DIMM2_ECC0: CONN8.92(CB0 / NC) U9.CV31(DDR1_ECC_0)
RP_DDR4_DIMM2_ECC1: CONN8.91(CB1 / NC) U9.CT31(DDR1_ECC_1)
RP_DDR4_DIMM2_ECC2: CONN8.101(CB2 / NC) U9.CV36(DDR1_ECC_2)
RP_DDR4_DIMM2_ECC3: CONN8.105(CB3 / NC) U9.CT36(DDR1_ECC_3)
RP_DDR4_DIMM2_ECC4: CONN8.88(CB4 / NC) U9.CU30(DDR1_ECC_4)
RP_DDR4_DIMM2_ECC5: CONN8.87(CB5 / NC) U9.CR30(DDR1_ECC_5)
RP_DDR4_DIMM2_ECC6: CONN8.100(CB6 / NC) U9.CU35(DDR1_ECC_6)
RP_DDR4_DIMM2_ECC7: CONN8.104(CB7 / NC) U9.CR35(DDR1_ECC_7)
RP_DDR4_DIMM2_I2C_SCL: CONN8.253(SCL) R656.1
RP_DDR4_DIMM2_I2C_SDA: CONN8.254(SDA) R649.1
RP_DDR4_DIMM2_MA0: CONN8.144(A0) U9.CV60(DDR1_MA_0)
RP_DDR4_DIMM2_MA1: CONN8.133(A1) U9.CU50(DDR1_MA_1)
RP_DDR4_DIMM2_MA2: CONN8.132(A2) U9.CR50(DDR1_MA_2)
RP_DDR4_DIMM2_MA3: CONN8.131(A3) U9.CT49(DDR1_MA_3)
RP_DDR4_DIMM2_MA4: CONN8.128(A4) U9.CV49(DDR1_MA_4)
RP_DDR4_DIMM2_MA5: CONN8.126(A5) U9.CR48(DDR1_MA_5)
RP_DDR4_DIMM2_MA6: CONN8.127(A6) U9.CT47(DDR1_MA_6)
RP_DDR4_DIMM2_MA7: CONN8.122(A7) U9.CR46(DDR1_MA_7)
RP_DDR4_DIMM2_MA8: CONN8.125(A8) U9.CV47(DDR1_MA_8)
RP_DDR4_DIMM2_MA9: CONN8.121(A9) U9.CT44(DDR1_MA_9)
RP_DDR4_DIMM2_MA10: CONN8.146(A10/AP) U9.CU61(DDR1_MA_10)
RP_DDR4_DIMM2_MA11: CONN8.120(A11) U9.CU46(DDR1_MA_11)
RP_DDR4_DIMM2_MA12: CONN8.119(A12) U9.CV44(DDR1_MA_12)
RP_DDR4_DIMM2_MA13: CONN8.158(A13) U9.CT66(DDR1_MA_13)
RP_DDR4_DIMM2_MA14: CONN8.151(A14_WE_N) U9.CV62(DDR1_MA14_WE_N)
RP_DDR4_DIMM2_MA15: CONN8.156(A15_CAS_N) U9.CT64(DDR1_MA15_CAS_N)
RP_DDR4_DIMM2_MA16: CONN8.152(A16_RAS_N) U9.CT62(DDR1_MA16_RAS_N)
RP_DDR4_DIMM2_ODT0: CONN8.155(ODT_0) U9.CV64(DDR1_ODT_0)
RP_DDR4_DIMM2_ODT1: CONN8.161(ODT_1) U9.CR69(DDR1_ODT_1)
RP_DDR4_DIMM2_R_EVENT_L: CONN8.134(EVENT _N) R574.1
RP_DDR4_DIMM2_R_RST_L: CONN8.108(RESET _N) R546.1
RP_DDR4_DIMM2_SA0: CONN8.256(SA0) R678.1 R679.1
RP_DDR4_DIMM2_SA1: CONN8.260(SA1) R680.1 R681.1 R880.1
RP_DDR4_DIMM2_SA2: CONN8.166(SA2) R688.1 R689.1
RP_DDR4_DMIM2_PAR: CONN8.143(PAR) U9.CR59(DDR1_PAR)
RP_DDR4_I2C_SCL: R647.2 R656.2 R657.2 R877.2 U36.7(SCLB)
RP_DDR4_I2C_SDA: R648.2 R649.2 R658.2 R878.2 U36.6(SDAB)
RP_DDR4_R_0_I2C_SCL: CONN7.253(SCL) R647.1
RP_DDR4_R_0_I2C_SDA: CONN7.254(SDA) R648.1
RP_DDR_I2C_EN: R659.2 R879.2 U36.5(EN)
RP_DDR_I2C_SCL: R621.2 R638.2 U36.2(SCLA)
RP_DDR_I2C_SDA: R622.2 R633.2 U36.3(SDAA)
RP_DDR_R_I2C_SCL: R621.1 U9.CD58(DDR_SCL)
RP_DDR_R_I2C_SDA: R622.1 U9.CC60(DDR_SDA)
RP_JTAG_R_CPU_TCK: R255.1 U9.T76(JTAG_TCK_CPU)
RP_JTAG_R_CPU_TDI: R248.1 U9.V78(JTAG_TDI_CPU)
RP_JTAG_R_CPU_TDO: R243.2 U9.T78(JTAG_TDO_CPU)
RP_JTAG_R_CPU_TMS: R242.1 U9.R75(JTAG_TMS_CPU)
RP_JTAG_R_CPU_TRST_L: R246.2 U9.U75(JTAG_TRST_N_CPU)
RP_JTAG_TCK_PCH: R476.2 U9.BM3(JTAG_TCK_PCH)
RP_JTAG_TDI_PCH: R116.1 U9.BM5(JTAG_TDI_PCH)
RP_JTAG_TDO_PCH: R88.2 U9.BK3(JTAG_TDO_PCH)
RP_JTAG_TMS_PCH: R106.1 U9.BJ2(JTAG_TMS_PCH)
RP_LAN_MDIO_DIR_CTL_0: R232.1 R597.1 U9.E75(LAN_MDIO_DIR_CTL_0)
RP_LAN_MDIO_DIR_CTL_1: R296.1 R637.1 U9.N72(LAN_MDIO_DIR_CTL_1)
RP_LAN_NCSI_ARB_OUT: R245.1 R251.1 U9.AB78(LAN_NCSI_ARB_OUT)
RP_LAN_NCSI_TX0: R596.1 U9.W77(LAN_NCSI_TXD0)
RP_LAN_NCSI_TX1: R595.1 U9.Y78(LAN_NCSI_TXD1)
RP_LAN_NCSI_TX_EN: R594.1 U9.AA75(LAN_NCSI_TX_EN)
RP_LAN_XTAL_I: R205.1 R207.1 U9.J58(LAN_XTAL_IN)
RP_LAN_XTAL_O: C108.1 OSC5.3 R207.2 U9.F58(LAN_XTAL_OUT)
RP_LAN_XTAL_R_I: C103.1 OSC5.1 R205.2
RP_LPC_LAD0: CONN14.14 CONN15.7 R138.1 U12.D2(IO_1_D2/DIFFIO_L3P) U17.26(LAD0)
RP_LPC_LAD1: CONN14.16 CONN15.6 R137.1 U12.D1(IO_1_D1/DIFFIO_L4P) U17.23(LAD1)
RP_LPC_LAD2: CONN14.18 CONN15.5 R506.1 U12.E1(IO_1_E1/DIFFIO_L6P) U17.20(LAD2)
RP_LPC_LAD3: CONN14.20 CONN15.4 R139.1 U12.E2(IO_1_E2/DIFFIO_L5P) U17.17(LAD3)
RP_LPC_LCLK: R522.1 U9.AC7(CLKIN_PCILOOPBACK)
RP_LPC_R_LAD0: R138.2 U9.AF3(LAD_0)
RP_LPC_R_LAD1: R137.2 U9.AG4(LAD_1)
RP_LPC_R_LAD2: R506.2 U9.AL3(LAD_2)
RP_LPC_R_LAD3: R139.2 U9.AF1(LAD_3)
RP_LPC_R_LCLK: R522.2 U9.AA9(CLKOUT_PCI_0)
RP_MS_INT1_R_L: R13.1 U9.BH7(SMBALERT_N_GPIO11)
RP_OSC 25MHZ_I: R1096.1 U9.K2(XTAL25_IN)
RP_OSC 25MHZ_O: OSC2.3(OUT) R1096.2
RP_PROCHOT_L: R265.1 U9.AG71(PROCHOT_N)
RP_PWR_ADDR_POT: C255.2 R757.1 U28.18(ADDR_PROT)
RP_REFCLK14IN: R519.1 U9.W9(REFCLK14IN)
RP_RSMRST_CPU_R_L: R253.1 U9.R77(RSMRST_CPU_N)
RP_RTC_X1: C39.1 R100.2 U9.AT2(RTCX1) X1.1
RP_RTC_X2: R146.1 U9.AT4(RTCX2)
RP_RTC_X2_R: C38.1 R100.1 R146.2 X1.2
RP_SPI_IO2: TP21.1(TP) U9.BF18(SPI_IO2)
RP_SPI_IO3: TP22.1(TP) U9.BE20(SPI_IO3)
RP_SPI_LAN_HOLD: R235.1 U16.7(/HOLD)
RP_SPI_LAN_WP: R234.1 U16.3(/WP)
RP_SSD_LED_A: CONN13.10(\\L\E\D\1\/DAS/\D\S\S\\) R716.2
RP_SSD_LED_C: LED15.C R716.1
RP_STBY_1.05V_R: C613.2 CONN11.44 R725.2
RP_STBY_R_1.05V: C638.2 CONN11.43 R765.1
RP_SVID_R_ALERT: R286.2 U9.AK72(SVIDALERT_N)
RP_SVID_R_CLK: R634.2 U9.AH72(SVIDCLK)
RP_SVID_R_DATA: R304.2 U9.AJ71(SVIDDATA)
RP_TACH6: R11.1 U9.AU14(TACH6_GPIO70)
RP_TACH7: R89.1 U9.AM2(TACH7_GPIO71)
RP_USB_RBIAS: R515.1 U9.AG11(USB2_RBIAS) U9.AJ11(USB2_RBIAS_N)
RST_BTN_IN_BMC_N: CONN14.169 R909.2
RST_BTN_IN_BMC_N_R: R909.1 U12.J13(IO_3_J13/DIFFIO_R13P)
RST_BTN_OUT_BMC_N: CONN14.170 R329.2
RSVD_96: U9.A76(RSVD_96)
RSVD_97: U9.AR71(RSVD_97)
RSVD_98: U9.BT62(RSVD_98)
SAFE_MODE_BOOT: R635.2 U9.AF69(SAFE_MODE_BOOT)
SATA3_C_RX0_N: C32.2 U9.CA33(SATA_RX_DN_0)
SATA3_C_RX0_P: C26.2 U9.BY32(SATA_RX_DP_0)
SATA3_C_RX1_N: C40.2 U9.BW33(SATA_RX_DN_1)
SATA3_C_RX1_P: C37.2 U9.BV32(SATA_RX_DP_1)
SATA3_C_TX0_N: C277.1 U9.BV28(SATA_TX_DN_0)
SATA3_C_TX0_P: C276.1 U9.BW26(SATA_TX_DP_0)
SATA3_C_TX1_N: C282.1 U9.BT28(SATA_TX_DN_1)
SATA3_C_TX1_P: C281.1 U9.BU26(SATA_TX_DP_1)
SATA3_RX0_N: C32.1 CONN6.25(B-)
SATA3_RX0_P: C26.1 CONN6.23(B+)
SATA3_RX1_N: C40.1 CONN13.43(PERP0/SATA_B_N)
SATA3_RX1_P: C37.1 CONN13.41(PERN0/SATA_B_P)
SATA3_TX0_N: C277.2 CONN6.31(A-)
SATA3_TX0_P: C276.2 CONN6.33(A+)
SATA3_TX1_N: C282.2 CONN13.47(PETN0/SATA_A_N)
SATA3_TX1_P: C281.2 CONN13.49(PETP0/SATA_A_P)
SF100_IO3: CONN3.8 Q1.G Q16.G R934.2
SLB_GND: R1082.2 U17.25(GND_4)
SLB_GPIO: R249.2 R955.2 U17.6(GPIO)
SLB_NC-RST: R1055.1 U17.9(NC5)
SLB_TPM: R1085.2 U17.28(NC10)
SLB_VDD_1: R1083.2 U17.5(VDD_1)
SLB_VDD_3: R1084.2 U17.19(VDD_3)
SMB_10GBE_ALERT: R285.1 U9.AN71(LAN_SMBALRT_N)
SMB_10GBE_CLK: R237.1 U9.AM75(LAN_SMBCLK)
SMB_10GBE_DATA: R250.1 U9.AM77(LAN_SMBDATA)
SMB_9548_I_SCL: R497.2 U33.22(SCL)
SMB_9548_I_SDA: R498.2 U33.23(SDA)
SMB_9548_SCL0: CONN16.50 R531.2 R786.2
SMB_9548_SCL1: CONN16.87 R493.2 R791.2
SMB_9548_SDA0: CONN16.48 R534.2 R788.2
SMB_9548_SDA1: CONN16.81 R529.2 R792.2
SMB_CLK_CPLD: R900.2 U12.C10(IO_2_C10)
SMB_DATA_CPLD: R488.2 U12.C9(IO_2_C9/DIFFIO_T13N)
SMB_FRU_PCU_CLK_P3V3: R650.2 U19.6(SCL)
SMB_FRU_PCU_DATA_P3V3: R671.2 U19.5(SDA)
SMB_LM75BD_CLK_P3V3: R297.2 R666.2 R674.1 U20.2(SCLK)
SMB_LM75BD_DATA_P3V3: R668.1 R669.2 U20.1(SDA)
SMB_LVC3_ALERT: R13.2 R230.2 R432.1
SMB_LVC3_ALERT_R: R230.1 U12.D8(IO_2_D8/DIFFIO_T9N)
SMB_PCU_CD_P3V3_INT-IN: R1076.2 R1077.1 R1089.2 R1113.2
SMB_PCU_CD_P3V3_INT-IN_R: R1076.1 U12.L5(IO_1_L5)
SMB_PCU_CD_P3V3_SW_INT1: R1074.2 R1079.2 R1091.2 R1112.2
SMB_PCU_CD_P3V3_SW_INT1_R: R1074.1 U12.N2(IO_1_N2/DIFFIO_L20P)
SMB_PCU_CLK_I2C_BUS: R1105.1 U45.13(SCL_SLAVE)
SMB_PCU_CLK_I2C_MUX: R1106.1 U40.4(A)
SMB_PCU_CLK_P3V3: R159.1 R425.2 R497.1 R650.1 R653.1 R666.1 R763.2 R900.1 R1067.1 R1105.2 R1106.2
SMB_PCU_CLK_P3V3_SWITCH: R45.2 R942.2 R1101.1 R1102.1
SMB_PCU_CLK_P3V3_SWITCH_R: R45.1 U9.BN11(SMBCLK)
SMB_PCU_CLK_SW_I2C_BUS: R1102.2 U45.5(SCL_MST1)
SMB_PCU_CLK_SW_I2C_MUX: R1101.2 U40.1(B1)
SMB_PCU_DATA_I2C_BUS: R1107.1 U45.14(SDA_SLAVE)
SMB_PCU_DATA_I2C_MUX: R1108.1 U41.4(A)
SMB_PCU_DATA_P3V3: R158.1 R426.2 R488.1 R498.1 R669.1 R670.1 R671.1 R762.2 R1068.1 R1107.2 R1108.2
SMB_PCU_DATA_P3V3_SWITCH: R40.2 R943.2 R1103.1 R1104.1
SMB_PCU_DATA_P3V3_SWITCH_R: R40.1 U9.BJ13(SMBDATA)
SMB_PCU_DATA_SW_I2C_BUS: R1104.2 U45.6(SDA_MST1)
SMB_PCU_DATA_SW_I2C_MUX: R1103.2 U41.1(B1)
SMB_PWR_ALERT_N: R31.2 R194.1 R446.1
SMB_PWR_ALERT_N_R: R31.1 U9.BC9(GPIO31_MGPIO2)
SMB_PWR_ALERT_R_N: R194.2 U12.A15(IO_2_A15/DIFFIO_T20P)
SMB_VR_P1V2_SCL: R403.1 R770.1 U29.20(SM_CLK)
SMB_VR_P1V2_SDA: R392.1 R398.1 U29.19(SM_DIO)
SMB_VR_SCL: R397.2 R403.2 R653.2
SMB_VR_SDA: R396.2 R398.2 R670.2
SML0_ALERT_N_R: R485.2 U9.BL7(SML0ALERT_N_GPIO60_MGPIO4)
SML0_CLK: R8.1 R430.1 R581.2
SML0_CLK_R: R8.2 U9.BR7(SML0CLK)
SML0_DATA: R25.1 R443.1 R585.2
SML0_DATA_R: R25.2 U9.BN18(SML0DATA)
SML1_ALERT: R483.2 U9.BF7(SML1ALERT_N_PCHHOT_N_GPIO74)
SML1_CLK: R452.1 R576.2 R790.2
SML1_CLK_R: R790.1 U9.BG9(SML1CLK_GPIO58_MGPIO11)
SML1_DATA: R448.1 R579.2 R789.2
SML1_DATA_R: R789.1 U9.BB11(SML1DATA_GPIO75_MGPIO12)
SMP_TESTDDR01_VIEWDIG0: R211.1 U9.CU76(TEST0)
SMP_TESTDDR01_VIEWDIG1: R215.1 U9.CM78(TEST1)
SOC_FPGA_CLK: R51.2 R457.1 U12.C3(IO_1_C3/DIFFIO_L2P)
SOC_FPGA_CLK_R: R51.1 U9.BA23(GPIO15)
SOC_FPGA_DIN: R54.2 R456.1 U12.E3(IO_1_E3/DIFFIO_L2N)
SOC_FPGA_DIN_R: R54.1 U9.BB16(GPIO27_MGPIO6)
SOC_FPGA_DOUT: R61.2 R461.1 U12.E13(IO_3_E13/DIFFIO_R2N)
SOC_FPGA_DOUT_R: R61.1 U9.BB23(GPIO28_MGPIO7)
SPI_10GBE_1T45_DIR: Q9.5(DIR) R601.2 R602.2
SPI_10GBE_CLK: R273.2 R1052.2 R1053.1 U18.11(2B1)
SPI_10GBE_CLK_LVC3V3: R640.1 U16.6(CLK)
SPI_10GBE_CLK_LVC3V3_R: R640.2 U18.6(2A1)
SPI_10GBE_CLK_R: R273.1 U9.M67(LAN_FLSH_CLK)
SPI_10GBE_CS_N: R628.1 R1051.2 U9.P67(LAN_FLSH_CS_N) U18.13(1B1)
SPI_10GBE_CS_N_LVC3V3: R300.2 R301.1 U16.1(/CS)
SPI_10GBE_CS_N_LVC3V3_R: R301.2 U18.4(1A1)
SPI_10GBE_DIR_1: R283.1 U18.2(1DIR)
SPI_10GBE_DIR_2: R287.1 U18.3(2DIR)
SPI_10GBE_MISO: R220.1 R589.2 R1048.2 U9.D74(LAN_FLSH_DO)
SPI_10GBE_MISO_LVC3V3: Q9.3(A) R618.2 R619.2
SPI_10GBE_MISO_LVC3V3_R: R619.1 U16.2(DO)
SPI_10GBE_MISO_R: Q9.4(B) R589.1
SPI_10GBE_MOSI: R236.2 R1049.1 R1050.2 U18.12(1B2)
SPI_10GBE_MOSI_LVC3V3: R302.1 U16.5(DI)
SPI_10GBE_MOSI_LVC3V3_R: R302.2 U18.5(1A2)
SPI_10GBE_MOSI_R: R236.1 U9.C73(LAN_FLSH_DI)
SPI_CS_SELECT: R33.2 R429.2 U2.6(S) U12.M9(IO_4_M9/DEV_CLRN/DIFFIO_B15N) U32.6(S)
SPI_MUX_OE_N: Q16.D R932.2 U43.15(\\O\\E\)
SPI_NIC1_NVM_CS: R811.2 R816.1 U39.1(/CS)
SPI_NIC1_NVM_CS_R_N: R811.1 U6.15(NVM_CS_N)
SPI_NIC1_NVM_SCK: R812.2 R815.1 U39.6(CLK)
SPI_NIC1_NVM_SCK_R: R812.1 U6.13(NVM_SK)
SPI_NIC1_NVM_SI: R809.2 R813.1 R1046.1 U39.5(DI)
SPI_NIC1_NVM_SI_R: R809.1 U6.12(NVM_SI)
SPI_NIC1_NVM_SO: R814.1 R989.2 R1047.1 U39.2(DO)
SPI_NIC1_NVM_SO_R: R989.1 U6.14(NVM_SO)
SRDS_SIG_DET: R972.1 U12.R14(IO_4_R14/DIFFIO_B22N)
SRDS_SIG_DET_R: R920.1 R970.1 R972.2 U6.54(MDI_MINUS[1])
SUSCLK_32K_CPLD: R41.1 U12.H5(IO_1_H5/CLK0)
SVID_ALERT: R286.1 R369.2 R370.2 R401.2 R636.2
SVID_ALERT_DDR_R: R370.1 U29.13(SVT/SV_ALERT)
SVID_ALERT_VCORE: R401.1 U28.13(SV_ALERT#)
SVID_CLK: R374.1 R376.2 R399.1 R634.1 R639.2
SVID_CLK_DDR_R: R376.1 U29.14(SV_CLK/VIDSEL1)
SVID_CLK_VCORE: R399.2 U28.14(SV_CLK/VIDSEL1)
SVID_DATA: R304.1 R379.1 R385.2 R400.2 R643.2
SVID_DATA_CORE: R400.1 U28.15(SV_DIO/VIDSEL0)
SVID_DATA_DDR_R: R385.1 U29.15(SV_DIO/VIDSEL0)
SW1_OE_N: R848.2 U7.15(\\O\\E\)
SW1_SYS_RESET_N: R714.2 SW1.3 SW1.4
SW2_SYS_RESET_N: R389.2 SW2.3 SW2.4
SW_VDDQ_CH01: C594.1 L14.1 QFN1.6(SW1) QFN1.7(SW2) QFN1.8(SW3) QFN1.9(SW4) QFN1.10(SW5) QFN1.11(SW6) R335.1
SYS_CPLD_INT_CPU: CONN16.56 R19.1 U12.T9(IO_4_T9/DIFFIO_B13P)
SYS_CPLD_INT_CPU_R: R19.2 R905.2 U9.BB14(GPIO26)
SYS_PWRBTN_N: C252.1 R389.1 R390.2 U12.K14(IO_3_K14/DIFFIO_R17N)
SYSLED: Q5.D R163.2 R164.1
SYSLED_R: LED11.C R163.1
TEST_NET1: TP60.1(TP) U12.A10(IO_2_A10/DIFFIO_T13P)
TEST_NET2: TP61.1(TP) U12.A9(IO_2_A9/DIFFIO_T11N)
TEST_NOA_COMP: R260.2 U9.AA66(RSVD_89)
TEST_RCIN_N: R14.1 U9.BA27(NCTF/TP_5)
TGND_VDDQ_CH01: QFN1.24(TGND) TP33.1(TP)
TP_ADR_COMPLETE: TP31.1(TP) U9.AF66(ADR_COMPLETE)
TP_BDX_CPU_RESET_N: R517.2 U9.BU7(PLTRST_PROC_N)
TP_BDX_GP50: TP24.1(TP) U9.BV20(GPIO50)
TP_DDR_VREFDQ_0: C431.1 U9.CV51(DDR_VREFDQ_0)
TP_DDR_VREFDQ_1: C454.1 U9.CT51(DDR_VREFDQ_1)
TP_GPIO54: TP23.1(TP) U9.BW18(GPIO54)
TP_HDA_SYNC: TP20.1(TP) U9.AN7(NCTF/TP_7)
TP_KR_EPHY_DFTDIG_1: TP32.1(TP) U9.F69(RSVD_3)
TP_LDRQ0_N: TP18.1(TP) U9.AK4(LDRQ0_N)
TP_PE_HSCLK_DN: R196.2 U9.C49(RSVD_95)
TP_PE_HSCLK_DP: R199.2 U9.A49(RSVD_94)
TP_PMTEST_RST: TP16.1(TP) U9.BD7(NCTF/TP_14)
TP_SATA_PLLOBS0: TP26.1(TP) U9.BF33(NCTF/TP_2)
TP_SATA_PLLOBS1: TP25.1(TP) U9.BE32(NCTF/TP_1)
TP_SLP_A_N: TP14.1(TP) U9.BB7(SLP_A_N)
TP_SLP_SUS_N: TP15.1(TP) U9.AY7(SLP_SUS_N)
TP_TEST_PE_AMONI: TP29.1(TP) U9.N43(RSVD_93)
TP_TEST_PE_AMONV: TP30.1(TP) U9.N47(RSVD_92)
TP_TEST_PE_DFX_DN: TP27.1(TP) U9.R39(RSVD_91)
TP_TEST_PE_DFX_DP: TP28.1(TP) U9.N39(RSVD_90)
TP_USB2_PLLMON_DN: TP17.1(TP) U9.AD9(NCTF/TP_4)
TP_USB2_PLLMON_DP: U9.AC11(NCTF/TP_3)
TP_VCCRTCEXT: C366.2 U9.AW16(DCPRTC)
TP_VCCSST: C368.2 U9.AW19(DCPSST)
TP_VCCSUS_1P05: C367.2 U9.AU16(DCPSUS1)
TP_VCCUSB3SUS: C337.2 U9.AP28(DCPSUS3_1) U9.AP30(DCPSUS3_2)
TPM_DET_N: CONN14.33 R948.2 U12.F10(IO_2_F10/DIFFIO_T14N)
TPM_RESET_N: R229.2 R1055.2 U17.16(LRESET#)
TPM_RESET_R_N: R229.1 U12.R12(IO_4_R12/DIFFIO_B19P)
U10_DIR: R563.1 U10.2(DIR)
U10_OE_N: R556.2 U10.22(\\O\\E)
U13_DIR: R577.1 U13.2(DIR)
U13_OE_N: R573.2 U13.22(\\O\\E)
U14_DIR: R203.1 U14.2(DIR)
U14_OE_N: R575.2 U14.22(\\O\\E)
UART_BDX_RX0: U9.AG77(UART_RXD_0) U13.17(B5)
UART_BDX_RX1: U9.AH78(UART_RXD_1) U13.16(B6)
UART_BDX_TX0: R288.1 R796.2 R797.1 U10.6(A4)
UART_BDX_TX1: R257.1 R798.2 R799.1 U10.7(A5)
UART_CPLD_B2B_RX0: R871.2 U12.G15(IO_3_G15/DIFFIO_R9N)
UART_CPLD_B2B_TX0: R872.2 U12.G14(IO_3_G14/DIFFIO_R7N)
UART_CPLD_BMC_RX0: R321.1 U12.R1(IO_4_R1/DIFFIO_B1P)
UART_CPLD_BMC_TX0: R315.1 U12.M1(IO_1_M1/DIFFIO_L17P)
UART_TXD_R_0: R288.2 U9.AG75(UART_TXD_0)
UART_TXD_R_1: R257.2 U9.AH76(UART_TXD_1)
UCD9090_ALERT_L: CONN16.78 U12.N16(IO_3_N16/DIFFIO_R20N)
UIM_PWR: CONN13.36(UIM_PWR)
USB1_PWRFAULT: CONN16.54 R471.1 R939.2 U12.D14(IO_3_D14/DIFFIO_R3P)
USB1_VBUS: CONN16.42 R29.2 R938.2 U12.P9(IO_4_P9/DIFFIO_B14P)
USB1_VBUS_R: R29.1 U9.BB21(GPIO24_MGPIO0)
USB2_DEBUG_DN: CONN1.2(D-) U9.AK9(USB2_DN_1)
USB2_DEBUG_DP: CONN1.3(D+) U9.AH9(USB2_DP_1)
USB2_DN_3: CONN14.25 U9.AG7(USB2_DN_3)
USB2_DP_3: CONN14.23 U9.AJ7(USB2_DP_3)
USB2_EUSB_DN: CONN5.4 U9.AE4(USB2_DN_2)
USB2_EUSB_DP: CONN5.6 U9.AE2(USB2_DP_2)
USB2_FRONT_DN: CONN16.84 U9.AD3(USB2_DN_0)
USB2_FRONT_DP: CONN16.82 U9.AD1(USB2_DP_0)
USB2_OC0_REAR_N: R80.1 R467.1 R471.2
USB2_OC0_REAR_R_N: R79.2 R80.2 U9.BH1(OC0_N_GPIO59)
USB3_OC1_REAR_N: R90.1 R112.1
USB3_OC1_REAR_R_N: R112.2 R480.2 U9.BE2(OC1_N_GPIO40)
VENDER1: CONN6.45(VENDOR1) TP2.1
VENDER2: CONN6.47(VENDOR2) TP1.1
VR_P1V2_VDDQ_PWRGD: R758.1 U12.L10(IO_4_L10) U29.9(VR_RDY1)
VR_P1V2_VDDQ_PWRGD_LED6: LED6.C U12.B9(IO_2_B9/DIFFIO_T12N)
VR_P1V2_VDDQ_PWRGD_R: LED6.A R410.2
VR_P1V05_PCH_VRHOT_N: R777.1 U12.N12(IO_4_N12/DIFFIO_B22P)
VR_P1V05_PCH_VSP_NC: C285.2 U9.BT5(VCC_SENSE)
VR_P3V3_CPLD_EN: R732.1 U12.F6(IO_1_F6/DIFFIO_L7N)
VR_P5V_STBY_EN: R34.1 R455.2 U4.7(EN) U12.D4(IO_2_D4/DIFFIO_T1P)
VR_PVCCIN_EN: R395.2 R746.1 R747.1 U12.N9(IO_4_N9/DIFFIO_B12P)
VR_PVCCIN_VRHOT_N: R394.2 R750.1 R777.2 U12.P12(IO_4_P12/DIFFIO_B23P)
VR_PWREN_PVDDR: R755.1 U12.N11(IO_4_N11/DIFFIO_B20P) U29.17(EN)
VTT_REFIN: C588.2 R699.2 R700.1 U37.1(REFIN)
VTT_REFOUT: C155.2 U37.6(REFOUT)
WAKEL_DIR: R802.2 R982.2 U38.5(DIR)
WATCHDOG_IND: R153.2 R155.1 R885.1 U9.AM4(TACH1_GPIO1)
XDP_CPU_MBP<2>: CONN11.9 R773.1 U9.N78(BPM_N_2)
XDP_CPU_MBP<3>: CONN11.11 R774.1 U9.M75(BPM_N_3)
XDP_CPU_MBP<4>: CONN11.15 R766.1 U9.J78(BPM_N_4)
XDP_CPU_MBP<5>: CONN11.17 R767.1 U9.H75(BPM_N_5)
XDP_CPU_MBP<6>: CONN11.21 R768.1 U9.K75(BPM_N_6)
XDP_CPU_MBP<7>: CONN11.23 R769.1 U9.J76(BPM_N_7)
XDP_CPU_PRDY_N: CONN11.5 R772.1 U9.L78(PRDY_N)
XDP_CPU_PREQ_N: CONN11.3 R771.1 U9.K77(PREQ_N)
XDP_CPU_PRESENT_N: CONN11.60 R730.1 U9.M77(DEBUG_EN_N)
XDP_CPU_PWRBTN_N: CONN11.41 R759.1
XDP_CPU_SDA: CONN4.51 R426.1
XDP_CPU_TCK0: CONN11.57 R255.2 R764.1
XDP_CPU_TDI: CONN11.56 R248.2 R739.1
XDP_CPU_TDO: CONN11.52 R243.1 R738.1
XDP_CPU_TMS: CONN11.58 R242.2 R726.1
XDP_CPU_TRST_N: CONN11.54 R246.1 R737.1
XDP_NOA0_PCH: CONN4.9 R79.1
XDP_NOA1_PCH: CONN4.11 R416.1 R480.1
XDP_NOA2_PCH: CONN4.15 R83.1 R415.1
XDP_NOA3_PCH: CONN4.17 R102.1 R414.1
XDP_NOA4_PCH: CONN4.27 R111.1 R421.1
XDP_NOA4_PCH_R: R111.2 R479.2 U9.BE4(OC4_N_GPIO43)
XDP_NOA5_PCH: CONN4.29 R104.1 R420.1
XDP_NOA6_PCH: CONN4.33 R419.1 R489.1
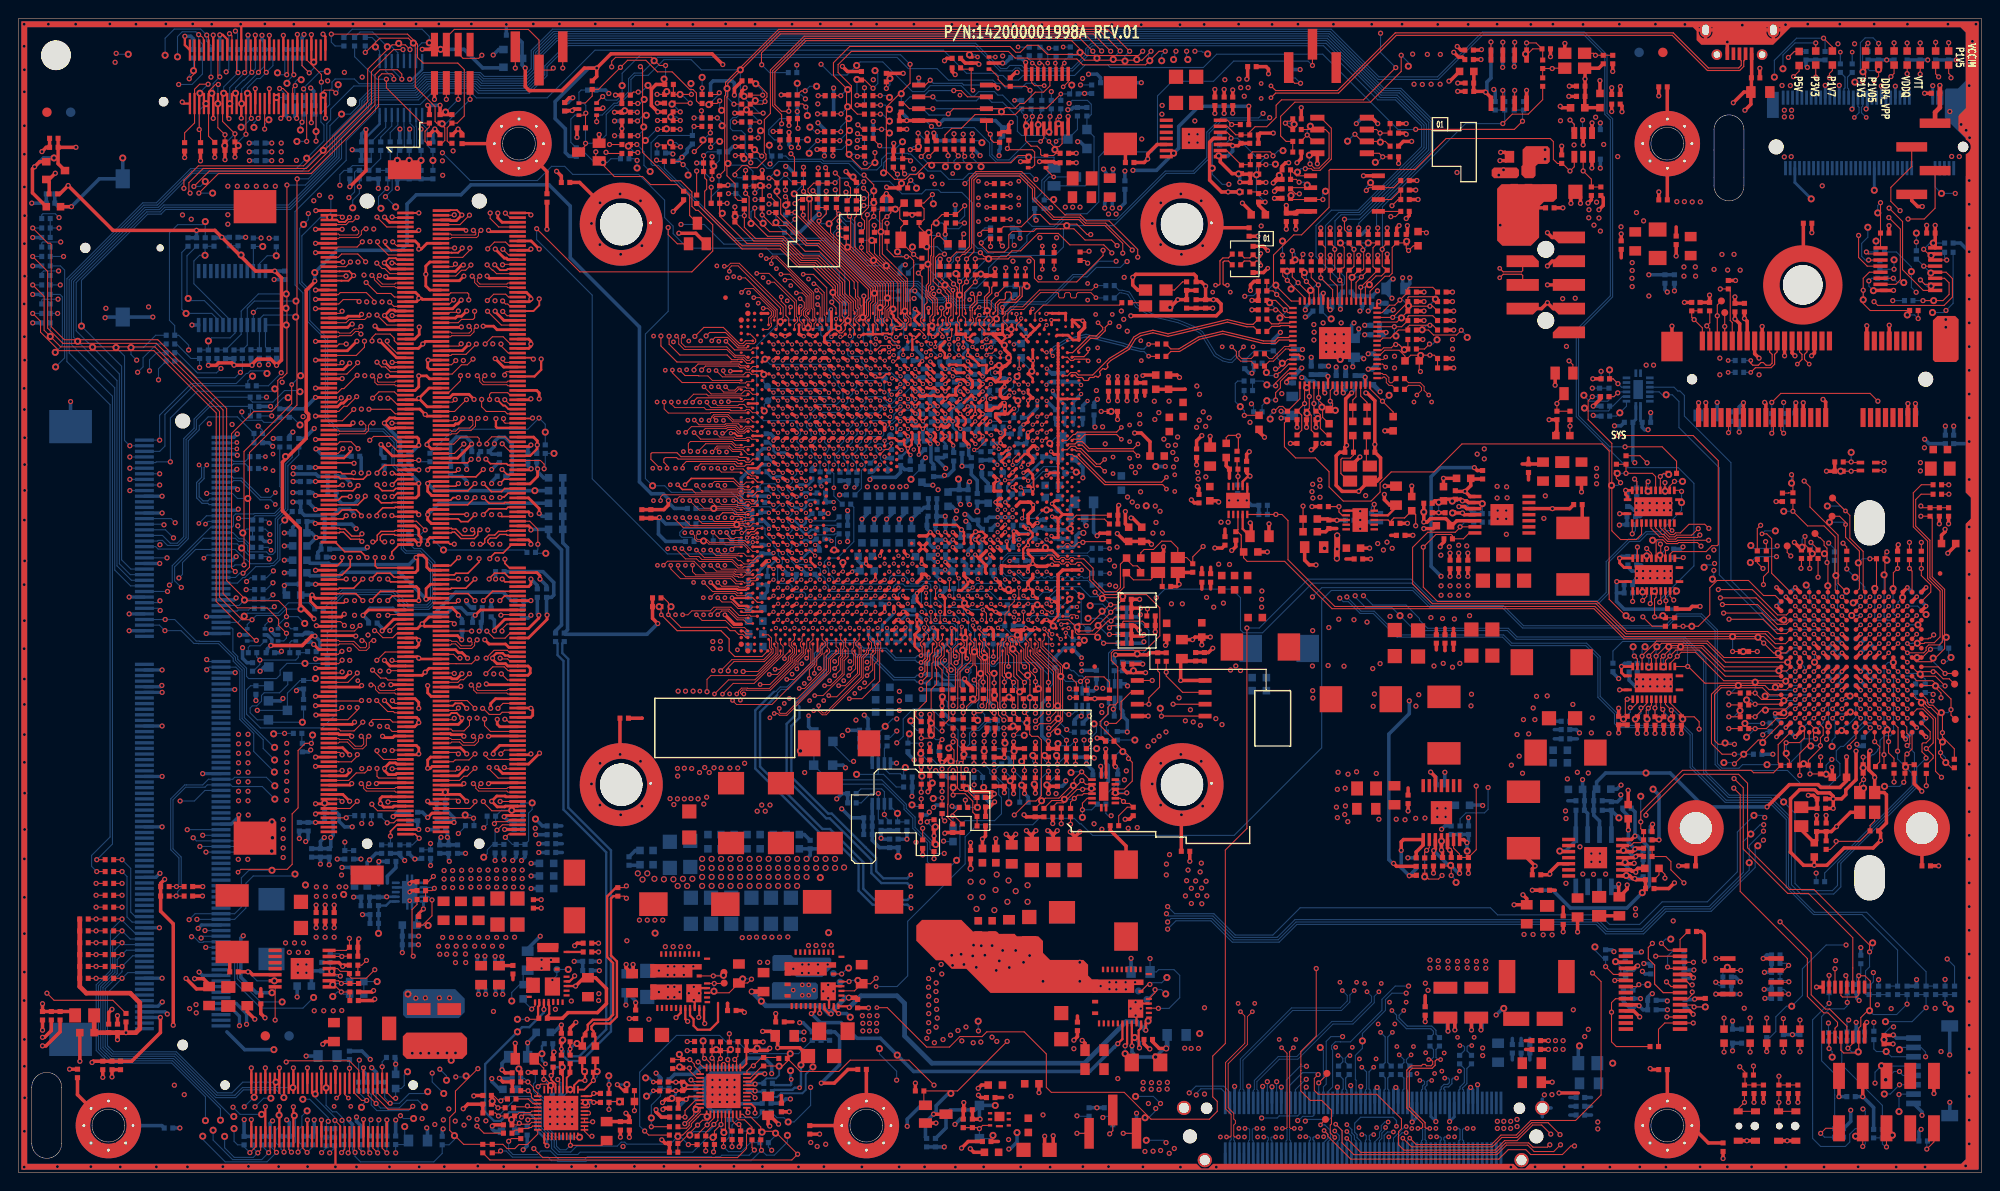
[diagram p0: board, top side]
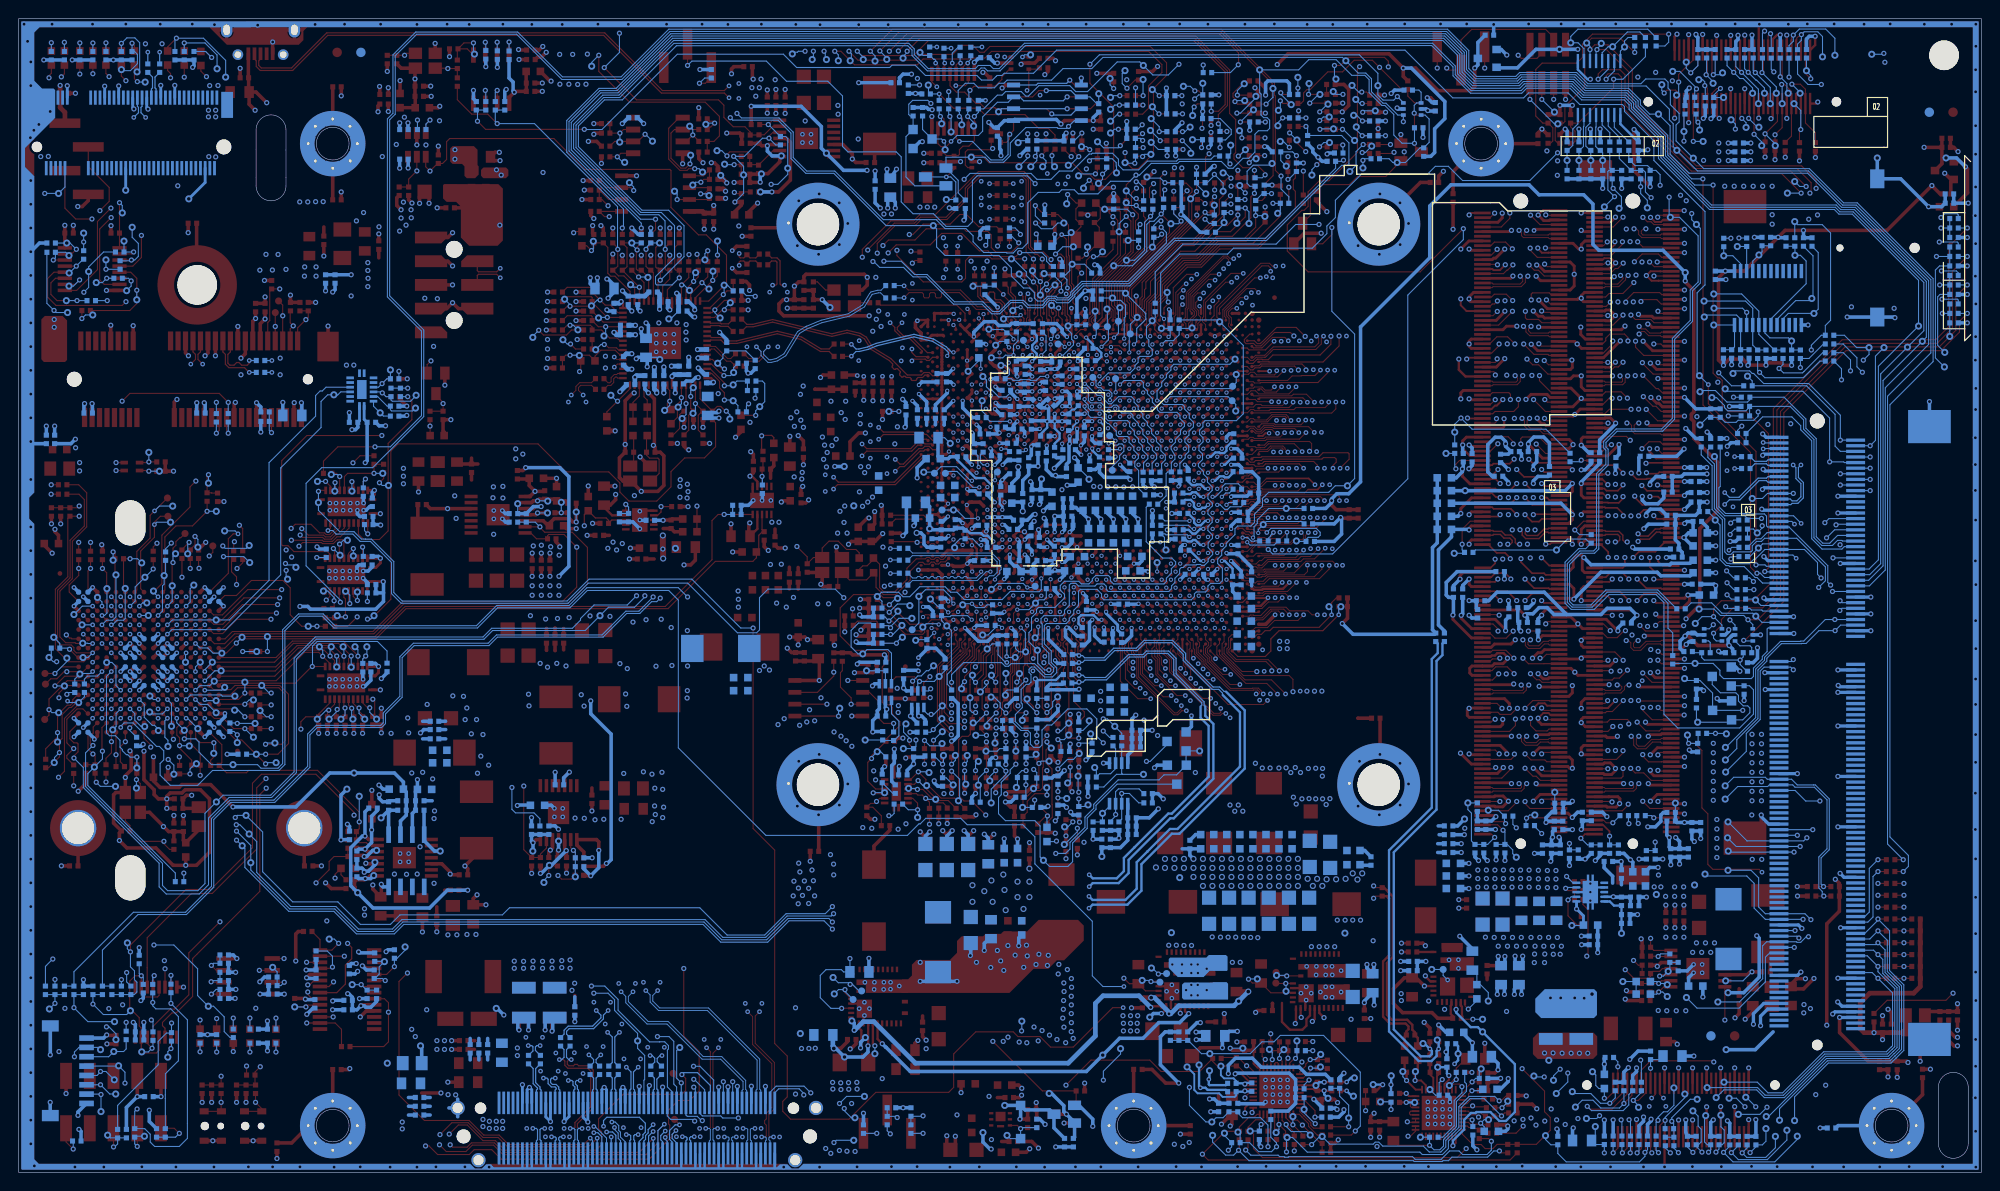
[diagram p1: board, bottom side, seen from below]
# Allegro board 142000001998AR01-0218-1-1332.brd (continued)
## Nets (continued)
XDP_NOA7_PCH: CONN4.35 R418.1 R490.1
XDP_NOA8_PCH: R98.1 U9.BR2(SATA0GP_GPIO21)
XDP_NOA8_PCH_R: CONN4.10 R98.2
XDP_NOA9_PCH: R433.1 R441.1 U9.BT3(SATA1GP_GPIO19)
XDP_NOA9_PCH_R: CONN4.12 R441.2
XDP_NOA10_PCH: CONN4.16 R38.1 R437.1
XDP_NOA11_PCH: CONN4.18 R115.1 R436.1
XDP_NOA14_PCH: CONN4.34 R444.1
XDP_PCH_CPU_PWRGD: CONN4.46 R56.1 U12.M6(IO_4_M6/DIFFIO_B5N)
XDP_PCH_PWRBTN_N: CONN4.41 R423.1
XDP_PCH_PWRGD: R424.2 U12.N5(IO_4_N5/DIFFIO_B3N)
XDP_PCH_PWRGD_R: CONN4.39 R424.1
XDP_PCH_RSMRST: CONN4.47 R422.1 U12.N6(IO_4_N6/DIFFIO_B4N)
XDP_PCH_SCL: CONN11.53 R763.1
XDP_PCH_SDA: CONN11.51 R762.1
XDP_PCH_SYSRST_N: CONN4.48 CONN11.48 R55.1 U12.M11(IO_4_M11/DIFFIO_B19N)
XDP_PCH_TCK0: CONN4.57 R417.1 R476.1
XDP_PCH_TDI: CONN4.56 R60.1 R116.2
XDP_PCH_TDO: CONN4.52 R58.1 R88.1
XDP_PCH_TMS: CONN4.58 R59.1 R106.2
XDP_PCU_SCL: CONN4.53 R425.1
XDP_SC_PWRGD_R: CONN11.39 R754.1
N21811685: LED18.C R868.2
N22142198: CONN14.53 R1056.1

Pads without a net: CONN1 4; CONN3 7; CONN4 3 5 21 22 23 24 40 42 45 54 55; CONN5 9; CONN6 1 3 5 6 7 8 10 11 12 13 14 16 17 19 20 22 28 36 38 42 46 48; CONN7 12 33 54 75 96 162 165 178 199 220 241; CONN8 12 33 54 75 96 162 165 178 199 220 241; CONN9 6 7 8; CONN11 4 6 10 12 16 18 22 24 27 28 29 30 33 34 35 36 55; CONN13 6 7 8 9 20 21 22 23 24 25 26 28 29 30 31 32 34 35 37 38 40 42 44 46 48 50 52 53 54 55 56 58 59 60 61 62 63 64 65 66 67 68 69; CONN14 24 26 42 55 57 72 74 78 79 80 81 85 86 87 88 89 90 91 92 93 94 95 97 98 99 100 101 102 103 104 105 106 107 108 109 110 111 112 116 118 120 121 122 123 124 125 126 127 128 129 130 134 136 138 140 142 143 144 145 146 147 148 149 151 152 153 154 155 156 157 158 159 160 161 162 177 179 180 181 182 183 187 188 189 190 191 192 193 194; CONN16 83; CONN17 1; QFN1 5 23 25; U6 22 43 44 58; U9 A12 A14 A16 A18 A23 A25 A27 A29 A36 A38 A40 A42 A44 A47 A51 A53 A55 A58 A60 A62 A64 A66 A68 A70 AA2 AA77 AC4 AC56 AC60 AC62 AD72 AE56 AE58 AE60 AE62 AG2 AG56 AG58 AG60 AG64 AH58 AH60 AJ64 AK56 AK58 AK62 AL5 AM55 AM56 AM58 AM60 AM62 AM66 AN64 AP55 AP56 AP58 AP60 AP62 AP66 AR64 AU9 AV11 AW12 B5 B8 B13 B17 B19 B21 B24 B26 B28 B35 B37 B39 B41 B43 B46 B50 B52 B54 B57 B59 B63 B65 B67 B69 B71 BA14 BA18 BB27 BF14 BG28 BH26 BJ28 BJ32 BJ62 BK76 BK78 BL26 BL33 BL37 BL60 BM28 BM32 BM62 BN22 BN26 BN33 BP28 BP32 BP37 BP56 BP58 BP66 BP72 BR26 BR33 BR60 BR67 BR71 BT32 BT37 BU33 BU60 BU75 BU77 BV16 BW22 BW37 C3 C7 C12 C14 C16 C18 C23 C25 C27 C29 C36 C38 C40 C42 C44 C47 C51 C53 C55 C58 C60 C62 C64 C66 C68 C70 CA1 CA3 CA37 CB39 CB43 CC22 CC67 CD9 CD13 CD54 CE76 CE78 CF7 CF14 CF22 CF52 CF67 CH2 CH4 CH60 CJ32 CK22 CK67 CL32 CM22 CM56 CM67 CR17 CR32 CR65 CR67 CR74 CR76 CT9 CT25 CT38 CT68 CU17 CU32 CV9 CV25 CV40 CV68 D8 D13 D17 D19 D21 D24 D26 D28 D35 D37 D39 D41 D43 D46 D50 D52 D54 D57 D59 D63 D65 D67 D69 E4 F13 F16 F20 F32 F35 F39 F43 F47 F51 G5 H7 H11 H14 H18 H22 H33 H37 H41 H45 H49 H52 H64 J1 J5 J13 J16 J20 J32 J35 J39 J43 J47 J51 K7 K11 K14 K18 K22 K33 K37 K41 K45 K49 K52 K64 L54 M2 M4 N1 N3 N9 N13 N20 N24 N28 N32 N54 P7 P14 P22 P26 P30 R9 R13 R20 R24 R28 R32 R44 T1 T3 T7 T14 T22 T26 T30 T35 T37 T40 T42 T44 T67 U69 V37 V39 V40 V67 W2 W4 W66 W69 W75 Y32 Y33 Y35 Y37 Y60 Y62 Y64; U10 3 5 19 21; U12 A4 A5 B13 B14 C15 D3 D7 D10 D16 E4 E10 E11 E15 E16 G6 G11 G12 G13 G16 H12 H13 H14 K13 L15 M13 N15 R6 R7 R8 R9 T5 T7 T8 T10 T13; U13 3 4 20 21; U14 4 20; U17 1 2 3 8 12 13 14 15; U18 7 10; U21 1 9; U24 24; U25 24; U26 24; U28 6; U29 3 10 26 27 29 30; U33 10 11 13 14 15 16 17 18 19 20; U34 6 7 10 11

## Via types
v1: diameter 0.762, hole 0.381, TOP to BOTTOM, 756 vias
v2: diameter 0.559, hole 0.305, TOP to BOTTOM, 3583 vias
v3: diameter 0.508, hole 0.254, TOP to BOTTOM, 849 vias
v4: diameter 0.457, hole 0.254, TOP to BOTTOM, 752 vias
v5: diameter 0.457, hole 0.203, TOP to BOTTOM, 2 vias
v6: diameter 0.66, hole 0.406, TOP to BOTTOM, 86 vias

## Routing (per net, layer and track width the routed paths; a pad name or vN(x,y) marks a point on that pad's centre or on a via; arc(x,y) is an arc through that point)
AGND_V3P3: length 6.5
  TOP w0.381: C243.2 153.28,34.32 v2(153.11,34.49) 152.88,34.72 U27.5
  BOTTOM w0.381: C626.2 152.62,37.1 v2(152.25,36.73) ; R731.1 v2(155.13,37.97) ; R748.2 v2(148.64,33.67) ; R727.1 155.27,39.32 156.59,39.32 v2(156.64,39.27)
AGND_V3P3A: length 9.5
  TOP w0.381: v2(172.24,36.65) 172.21,36.68 R620.1 ; C129.2 173.05,34.7 v2(172.95,34.59) 172.68,34.33 U15.5
  BOTTOM w0.381: R629.2 173.61,34.59 v2(172.95,34.59) 172.24,35.31 v2(172.24,36.65) 172.24,38.12 171.63,38.73 R1088.1
AGND_V5A: length 16.5
  TOP w0.114: R68.2 v2(133.5,108.76) ; v2(129.72,110.7) 129.72,110.9 129.3,111.33 U4.5
  TOP w0.381: R99.1 133.4,102.82 132.67,103.54 C34.2 v2(133.37,103.87)
  BOTTOM w0.114: v2(133.37,103.87) 132.44,104.8 v1(132.44,106.78) 132.44,107.7 v2(133.5,108.76) 132.36,108.76 130.42,110.7 v2(129.72,110.7) 129,109.98 R455.1
AGND_VDDQ: length 13.2
  TOP w0.381: C221.2 57.18,12.78 v2(57.28,12.88) ; R349.2 v2(58.06,15.77) ; C254.2 50.8,5.08 v2(50.67,4.95) ; v2(51.44,10.06) 51.82,9.68 R363.2 C238.2
  BOTTOM w0.381: v2(58.06,15.77) 57.28,14.99 R780.1 ; R742.2 51.46,8.89 50.62,9.73 v2(50.62,10.03) ; C221.2 57.18,12.78 v2(57.28,12.88) 57.15,13.01 R723.1 ; v2(50.67,4.95) 50.67,4.64 50.91,4.39 R756.2 ; C625.2 v2(51.44,10.06)
GND: length 2249.5
  TOP w0.127: U9.AC2 102.8,90.72 103.3,90.22 U9.AB5 ; U9.BD5 93.54,89.88 93.54,90.37 93.75,90.58 94.24,90.58 U9.BA3 ; U9.CV70 77.39,59.94 78.46,59.94 U9.CT70 ; 78.49,57.63 77.85,57.63 77.53,57.96 U9.CV74 ; U9.AA19 U9.AA21 ; U9.BU4 87.45,90.22 87.81,89.87 88.09,89.87 88.45,90.22 U9.BP3
  TOP w0.152: U9.AF78 101.45,55.95 101.45,56.93 U9.AF76
  TOP w0.203: CONN7.2 v2(42.81,102.7) ; CONN7.43 v2(31.76,92.45) ; CONN8.64 54.92,87.2 v2(55.07,87.06) ; CONN7.22 40.5,97.7 40.35,97.86 39.63,97.86 v2(39.13,97.36) ; CONN8.209 46.09,48.95 46.3,49.17 46.86,49.17 v2(47.42,48.61) ; v2(50.93,97.16) 51.5,96.59 52.2,96.59 52.31,96.7 CONN8.26 ; U9.U66 105.83,62 106.15,62 106.44,62.3 U9.R66 ; v2(39.14,50.51) 39.95,49.7 CONN7.206 ; v2(47.42,102.48) 46.89,103.01 46.18,103.01 46.12,102.95 CONN8.1 ; U9.CV29 76.89,78.84 76.61,79.12 v4(76.2,79.12) ; CONN8.205 46.46,49.95 46.72,50.21 47.39,50.21 v2(47.94,49.67) ; U9.BD14 92.84,85.48 92.44,85.08 91.77,85.08 v4(91.66,85.19) ; U9.AH74 100.1,58.28 v4(99.83,58.28) U9.AK75 U9.AK77 ; v3(76.15,85.77) U9.CV14 ; U9.CT14 U9.CP14 ; U9.CA78 U9.CA76 ; CONN8.44 55.08,92.2 55.7,92.83 55.7,93.49 v2(55.7,93.5) ; v2(39.21,99.63) 39.21,99.32 39.83,98.7 CONN7.18 ; v2(54.98,80.75) 54.94,80.7 CONN8.90 ; CONN8.86 52.41,81.7 52.03,82.08 51.84,82.08 v2(51.2,82.73) ; v2(54.8,102.49) 54.59,102.7 CONN8.2 ; U9.BD5 93.12,89.73 93.04,89.81 92.49,89.81 U9.BF5 ; U9.L39 108.58,74.23 108.58,73.23 v4(108.5,73.15) ; v2(47.46,98.95) 47.46,98.89 47.01,98.44 46.33,98.44 46.32,98.45 CONN8.19 ; CONN7.5 34.06,101.95 34.28,101.74 34.91,101.74 v2(35.39,102.22) ; CONN7.31 34.52,95.45 34.53,95.44 35.28,95.44 v2(35.84,96) 35.38,96.46 34.35,96.46 34.34,96.45 CONN7.27 ; CONN7.23 v2(34.68,97.45)
  TOP w0.249: QFN1.4 58.95,20.44 59.49,20.98 v2(59.49,21.03) ; U25.4 86.76,19.92 v3(86.61,20.06) ; v3(119.51,18.21) 119.65,18.07 U24.4 ; U26.4 72.38,19.72 v3(72.24,19.86) ; U26.28 72.33,18.34 v3(72.24,18.44) ; v3(119.51,16.79) 119.6,16.69 U24.28 ; U25.28 86.71,18.55 v3(86.61,18.64)
  TOP w0.254: v3(101.45,55.01) 101.32,55.14 U9.AF78 ; U9.CT29 U9.CP29 ; CONN11.25 v2(30.89,5.6) ; CONN8.106 54.72,76.7 55.47,77.46 55.47,77.85 v2(55.49,77.87) ; U9.AG12 U9.AH12 100.27,86.47 99.63,86.47 U9.AK12 ; U9.R40 106.73,73.73 v4(106.35,73.35) 106.75,72.95 U9.R42 ; U9.E2 110.52,91.24 110.52,91.24 v4(110.49,91.24) 110.49,91.21 110.51,91.19 U9.F3 ; U9.U13 U9.W13 104.28,86.08 104.04,86.08 U9.AA14 U9.AA12 U9.AC12 102.75,86.51 U9.AE11 ; U9.AH27 v4(100.75,79.59) ; U9.E38 U9.E36 ; U9.U28 105.54,79.46 105.54,78.97 105.18,78.61 U9.V30 ; CONN4.25 v2(26.82,121.71) ; U9.AA69 103.88,60.25 104.15,60.25 104.39,60.01 v4(104.54,60.01) ; U9.BH5 U9.BK5 v4(89.93,89.5) ; U9.BH5 U9.BF5 ; U9.BH5 U9.BH3 ; U9.AU28 U9.AU30 v4(96.35,77.82) 96.35,76.87 v4(96.31,76.82) ; v4(101.57,60.01) 101.44,60.14 101.38,60.14 100.94,60.58 U9.AH69 ; U9.M26 108.01,80.69 U9.L24 ; CONN11.8 v2(26.39,11.18) ; U9.AR3 U9.AR5 97.54,89.73 v4(97.84,89.43) 98.05,89.43 U9.AN5 ; CONN11.20 v2(29.39,11.18) ; U9.R35 106.88,76.13 107.65,76.89 U9.M33 ; U9.BU4 U9.BW5 ; CONN4.59 17.78,120.68 v2(17.78,121.62) ; U9.V55 v4(104.75,67.73) ; U9.AU78 95.87,56.32 U9.AV77 U9.AV75 U9.AU76 ; U9.BR14 v4(88.69,85.19) ; U9.CE1 83.5,92.57 v4(83.65,92.72) ; U9.CP36 U9.CR37 U9.CU37 ; CONN11.1 v2(24.89,5.64) ; v2(35.5,77.46) 35.5,77.15 34.8,76.45 CONN7.107 ; U9.AG21 101.15,82.43 101.49,82.77 101.52,82.77 U9.AE19 ; U9.AR1 v3(97.36,92.51) ; v4(92.16,87.77) 92.44,88.05 U9.BE9 ; CONN4.37 23.82,122.84 v2(23.75,122.91) ; CONN8.72 55.19,85.2 55.91,85.92 v2(55.91,87.06) ; CONN4.13 v2(29.82,121.82) ; U9.L16 108.5,84.98 U9.M14 ; U9.M52 U9.P52 ; U8.6 143.48,70.83 v3(143.54,70.77) ; v4(109.96,91.9) 109.98,91.92 109.98,91.95 110.01,91.98 110.57,91.98 U9.F1 ; U11.6 131.46,71.99 v3(131.4,71.93) ; CONN11.2 v2(24.89,11.18) ; CONN4.1 32.82,121.59 v2(32.56,121.84) ; U9.CB58 84.73,65.37 U9.CA60 ; v2(50.7,55.04) 50.7,55.16 51.11,55.57 51.79,55.57 52.05,55.32 52.39,55.32 52.51,55.2 CONN8.184 ; v2(17.5,114.58) 17.67,114.41 CONN4.60 ; v3(95.92,92.42) 96.37,91.97 U9.AU1 95.87,91.46 U9.AV2 U9.AU3 ; U9.AE67 101.85,61.44 v4(101.57,61.73) ; CONN11.38 v2(33.89,11.18) ; v2(51.06,80.68) 51.06,79.82 51.18,79.7 CONN8.94 ; CONN4.31 v2(25.32,121.74) ; v4(95.78,89.36) 95.62,89.2 U9.AW9 ; v4(95.78,89.36) 95.99,89.36 U9.AU5 ; v4(95.78,89.36) 95.41,89.73 U9.AW5 ; CONN4.26 v2(26.82,116) ; U9.AH5 U9.AH3 ; U9.V1 105.28,92.59 v3(105.26,92.61) ; CONN11.59 v2(39.39,5.61) ; U9.AG16 101.06,84.89 100.44,84.89 U9.AH16 ; CONN11.32 v2(32.39,11.18) ; CONN11.14 v2(27.89,11.18) ; CONN4.20 28.32,113.1 v2(28.04,112.83) ; U9.CU21 U9.CR21 ; U9.AR19 97.27,83.19 97.35,83.11 97.75,83.11 97.83,83.19 U9.AP19 98.09,83.05 98.61,83.05 U9.AM19 v4(99.15,82.79) ; U9.AK16 v4(99.15,84.39) ; CONN4.8 v2(31.32,112.37) ; v4(100.75,84.39) U9.AH18 ; U9.M22 108.01,82.62 v4(108.01,82.62) ; U9.AL71 U9.AL67 ; CONN11.49 v2(36.89,5.66) ; U9.AH30 U9.AH28 ; v4(97.87,58.32) 97.95,58.32 98.22,58.05 U9.AN74 U9.AN76 ; CONN11.50 v2(36.89,11.18) ; U9.AM9 98.74,88.05 99.09,87.7 U9.AL11 99.31,87.19 v4(99.59,87.48) ; CONN4.32 v2(25.32,116) ; CONN11.13 v2(27.89,7.04) ; U9.L1 108.25,92.2 v4(108.48,92.44) ; CONN4.14 29.82,112.9 v2(29.74,112.83) ; CONN11.26 v2(30.89,11.18) ; U9.E70 111.22,59.61 110.81,59.2 110.81,59.19 U9.F72 ; U9.B74 U9.B76 ; U9.CE3 U9.CE5 ; U9.CT70 U9.CP70 ; CONN4.2 v2(32.82,112.85) ; v4(105.77,89.5) 105.19,88.91 U9.V7 ; v4(96.12,62) U9.AV67 ; v2(39.15,86.73) 39.18,86.73 39.74,86.17 40.22,86.17 40.25,86.2 CONN7.68 ; CONN4.49 v2(20.82,121.74) ; U9.T33 105.92,76.89 105.79,76.76 105.78,76.76 U9.V35 105.54,75.74 105.55,75.74 v4(105.56,75.73) ; v2(90.43,93.8) U9.BK1 ; CONN4.50 v2(20.82,112.83) ; U9.AR25 97.15,80.79 96.77,80.4 v4(96.75,80.4) 96.71,80.4 96.35,80.77 U9.AU25 96.46,80.9 96.46,81.49 U9.AU23 ; CONN11.7 v2(26.39,7.04) ; v3(113.84,91.16) 113.76,91.24 U9.B2 ; CONN11.37 v2(33.89,0.58) ; CONN4.38 v2(23.82,112.85) ; U9.BD1 93.62,91.72 93.62,91.48 U9.BB2 U9.BA3 ; CONN11.19 v2(29.39,7.01) ; CONN4.7 v2(31.32,121.79) ; U9.A20 U9.C20 ; CONN4.19 v2(28.32,121.71) ; U9.AF9 v4(101.57,87.48) ; CONN11.31 v2(32.39,5.6)
  TOP w0.279: U9.BG62 91.66,63.63 v4(91.66,63.44) U9.BH64 ; U9.BU64 v4(87.7,63.44) ; U9.BM69 v4(90.18,60.87) ; U9.BP69 v4(89.19,60.87) ; U9.BR64 v4(88.69,63.44) ; U9.BP62 v4(89.19,64.3) ; U9.BN64 v4(89.68,63.44) ; U9.BY69 v4(86.21,60.87) ; U9.BT69 v4(88.2,60.87) ; U9.BL64 v4(90.67,63.44) ; U9.BV69 v4(87.2,60.87)
  TOP w0.305: U9.M56 108.01,66.23 U9.L58 v4(108.5,65.16) ; U9.K4 U9.L3 ; U9.K4 U9.L5 107.98,89.46 v4(107.8,89.46) ; U9.K4 U9.J3 ; U9.E49 U9.D48 ; U9.E49 111.02,70.13 110.65,70.13 v4(110.57,70.2) ; U9.E49 111.22,69.64 U9.E51 111.22,68.65 U9.E53 110.69,67.95 v4(110.52,68.12) ; U9.D48 U9.E47 v4(110.56,71.57) 110.9,71.91 U9.E44 ; U9.D48 U9.B48 ; v2(31.76,98.45) CONN7.19 ; v2(40.06,38.08) 40.18,38.2 CONN7.252 ; CONN8.193 46.24,52.95 46.35,52.83 46.89,52.83 47.42,53.36 v2(47.42,53.38) ; U9.BW7 86.21,89.48 U9.BW5 ; CONN8.103 44.14,77.45 v2(43.69,77.9) 43.69,78.04 44.1,78.45 CONN8.99 ; v2(43.17,58.71) 43.43,58.45 CONN8.171 ; v2(43.17,58.71) 43.91,59.45 CONN8.167 ; v2(43.17,58.71) 42.66,58.2 CONN7.172 ; v2(35.77,80.23) 35.5,79.95 CONN7.93 ; v2(35.42,53.49) 35.42,53.47 34.9,52.95 CONN7.193 ; CONN8.252 52.07,38.2 v2(51.94,38.07) ; CONN8.78 55.43,83.7 55.7,83.43 v2(55.7,82.8) ; v4(84.98,89.5) 85.25,89.5 U9.CA5 ; CONN8.230 54.56,43.7 v2(55.73,44.87) ; v2(54.81,82.8) 54.71,82.7 CONN8.82 ; v2(39.28,95.89) 39.46,95.7 CONN7.30 ; CONN8.61 46.12,87.95 46.12,87.96 47.47,87.96 v2(48.16,88.65) ; U9.H60 110.12,65 110.51,65 v4(110.57,65.06) 110.65,64.98 U9.E60 ; CONN7.184 42.64,55.2 v2(42.81,55.04) 42.89,54.95 CONN8.185 ; v2(50.27,100.84) 50.41,100.7 CONN8.10 ; v2(47.63,95.94) 47.15,95.45 CONN8.31 ; U9.E74 110.48,58.78 U9.F72 ; CONN8.5 46.17,101.95 46.24,101.88 46.82,101.88 v2(47.42,102.48) ; CONN8.197 47.23,51.95 v2(47.31,52.03) ; CONN8.57 43.52,88.95 v2(43.24,88.67) 42.77,88.2 CONN7.60 ; CONN7.210 42.57,48.7 42.81,48.46 v2(42.81,48.14) 42.37,47.7 CONN7.214 ; v2(38.89,57.97) 38.9,57.97 40.13,59.2 CONN7.168 ; U9.E5 111.11,89.62 U9.D5 112.29,89.62 112.8,89.11 U9.A6 ; U9.AU69 96.62,60.66 96.12,61.15 96.12,61.44 U9.AV67 ; CONN7.180 42.57,56.2 42.81,56.44 v2(42.81,56.95) 42.56,57.2 CONN7.176 ; CONN8.47 46.74,91.45 46.93,91.65 47.38,91.65 v2(47.94,92.21) ; v2(42.81,49.67) 42.81,50.31 42.42,50.7 CONN7.202 ; U9.M41 108.19,73.46 v4(108.5,73.15) ; U9.CM1 U9.CP1 ; CONN8.234 51.78,42.7 51.15,43.33 v2(51.15,43.33) ; v2(51.21,48.49) 51.21,47.97 51.47,47.7 CONN8.214 ; CONN7.235 35.04,42.45 35.42,42.84 v2(35.42,43.04) ; U9.W16 U9.U16 105.49,84.57 v4(105.49,84.1) 105.33,84.1 105.04,83.8 U9.V18 ; U9.W16 105.04,85.11 U9.V14 ; U9.W16 104.17,84.99 103.74,84.99 U9.AA16 ; v2(51.26,102.68) 51.26,102.17 51.73,101.7 CONN8.6 ; CONN7.73 34.59,84.95 v2(34.61,84.97) ; CONN7.86 42.93,81.7 v2(43.5,81.13) 43.68,80.95 CONN8.89 ; v2(36.18,88.97) 35.16,87.95 CONN7.61 ; CONN8.210 54.78,48.7 55,48.92 55,49.48 v2(54.81,49.67) 54.77,49.7 CONN8.206 ; CONN7.44 40.28,92.2 40.17,92.32 39.74,92.32 v2(39.15,91.72) 39.71,91.16 40.19,91.16 40.23,91.2 CONN7.48 ; v2(50.9,57.98) 50.9,58.09 52.01,59.2 CONN8.168 ; U9.AU72 96.33,59.15 v4(96.12,59.15) ; v4(107.8,89.46) 107.8,89.12 U9.M7 ; v4(107.8,89.46) 107.53,89.46 U9.N5 ; v2(49.7,90.58) 50.81,90.58 51.18,90.2 CONN8.52 ; CONN7.26 39.78,96.7 v2(39.13,97.36) ; v2(31.76,80.95) CONN7.89 ; v2(31.76,94.45) CONN7.35 ; v2(54.81,44.79) 54.72,44.7 CONN8.226 ; U9.AH25 100.53,80.61 100.53,80.18 U9.AH27 ; U9.V14 105.04,85.84 U9.U13 ; U9.V14 104.89,85.62 v4(104.5,85.62) ; CONN7.196 39.82,52.2 v2(39.83,52.2) ; CONN7.82 42.66,82.7 v2(42.81,82.85) ; v2(55.49,77.87) 55.49,78.3 55.09,78.7 CONN8.98 ; U9.B3 U9.B2 U9.A3 ; CONN8.248 52.08,39.2 52,39.13 51.2,39.13 v2(50.6,39.72) 51.16,40.28 52.04,40.28 52.13,40.2 CONN8.244 ; CONN7.102 42.67,77.7 v2(42.81,77.84) 42.81,78.51 42.61,78.7 CONN7.98 ; v2(48.46,77.96) 46.95,76.45 CONN8.107 ; CONN8.239 47.47,41.45 v2(47.63,41.61) ; U9.BA12 94.76,86.39 v4(95.16,85.99) ; v2(47.94,43.26) 47.84,43.26 47.03,42.45 CONN8.235 ; v2(38.93,46.68) 39.07,46.54 40.03,46.54 40.19,46.7 CONN7.218 ; v2(34.84,59.76) 34.54,59.45 CONN7.167 ; U9.E58 110.59,66.6 110,66.6 U9.H56 ; CONN8.22 52.34,97.7 52.18,97.87 51.96,97.87 51,98.83 v2(51,98.84) ; CONN7.223 34.66,45.45 v2(35.42,44.7) ; CONN8.202 51.02,50.7 50.5,50.18 v2(50.5,49.67) ; CONN7.106 39.97,76.7 v2(38.76,77.91) ; CONN7.14 42.41,99.7 42.81,99.31 v2(42.81,98.84) 43.07,98.84 43.69,99.45 CONN8.15 ; U9.M37 108.5,74.68 U9.L39 ; U9.E42 U9.E40 111.22,74.18 U9.E38 110.36,74.88 110.08,74.6 v4(109.98,74.6) ; CONN8.9 47.74,100.95 v3(47.86,100.83) ; v2(42.86,90.48) 42.86,89.69 42.37,89.2 CONN7.56 ; v4(96.12,59.15) U9.AV71 ; v4(96.12,59.15) 96.12,58.46 96.37,58.22 U9.AU74 U9.AV75 ; v2(35.94,48.19) 35.69,47.95 CONN7.213 ; v2(43.76,52.1) 43.76,51.33 44.13,50.95 CONN8.201 ; v2(31.57,56.51) 32.13,55.95 CONN7.181 ; v2(35.41,86.62) 34.74,85.95 CONN7.69 ; v2(49.87,57.01) 50.33,56.55 52.09,56.55 52.45,56.2 CONN8.180 ; U9.AF5 101.32,89.45 v4(101.57,89.2) 102.1,89.73 U9.AD5 ; v2(43.76,39.72) 43.76,39.69 44,39.45 CONN8.247 ; CONN7.47 35.05,91.45 35.24,91.65 36.48,91.65 v2(36.68,91.85) ; CONN8.175 46.96,57.45 v2(47.4,57.01) ; CONN8.30 50.37,95.7 v2(50.12,95.95) ; v2(42.81,93.58) 42.81,93.85 42.45,94.2 CONN7.36 ; v2(42.81,93.58) 42.81,93.44 42.57,93.2 CONN7.40 ; v2(42.81,93.58) 43.07,93.58 43.2,93.45 CONN8.39 ; CONN8.77 43.91,83.95 v2(42.81,82.85) ; v2(47.94,44.79) 47.28,45.45 CONN8.223 ; CONN8.189 43.91,53.95 v2(43.5,53.54) 43.16,53.2 CONN7.192 ; v2(47.52,80.74) 47.52,80.62 47.03,80.13 46.75,80.13 46.58,79.95 CONN8.93 ; CONN8.36 54.32,94.2 54.81,93.72 v2(54.81,93.5) 54.81,93.37 54.64,93.2 CONN8.40 ; CONN8.102 54.65,77.7 v2(54.81,77.86) ; v2(31.85,58.52) 31.92,58.45 CONN7.171 ; v2(56.54,59.65) 56.54,59.2 54.55,57.2 CONN8.176 ; CONN7.248 40.14,39.2 40.03,39.09 39.08,39.09 v2(38.7,39.47) 38.67,39.51 38.67,39.99 38.89,40.21 39.85,40.21 39.86,40.2 CONN7.244 ; v2(31.76,50.95) CONN7.201 ; v4(110.46,77.17) 110.77,76.86 U9.E34 ; U9.F1 U9.E1 U9.C1 U9.C2 ; v2(54.81,98.84) 54.67,98.7 CONN8.18 ; CONN8.68 51.9,86.2 51,87.11 v2(50.99,87.11) ; CONN7.78 42.42,83.7 42.81,84.09 v2(42.81,85.26) 43.64,85.26 43.95,84.95 CONN8.73 ; v2(31.79,102.95) CONN7.1 ; v2(39.13,54.81) 39.74,54.2 CONN7.188 ; v2(42.81,100.84) 42.67,100.7 CONN7.10 ; v2(31.76,78.45) CONN7.99 ; CONN7.238 38.36,41.7 v2(38.27,41.61) ; U9.V3 U9.V5 105.51,89.5 v4(105.77,89.5) 106.04,89.5 U9.T5 ; CONN7.251 31.85,38.45 v2(31.76,38.36) ; v2(47.57,97.13) 47.42,97.13 46.74,96.45 CONN8.27 ; CONN8.238 50.36,41.7 v2(50.27,41.61) ; v4(108.53,86.9) 108.31,86.9 U9.M11 ; v4(108.53,86.9) 108.53,86.36 U9.L13 108.5,85.97 U9.M14 ; v4(108.53,86.9) 108.5,86.92 U9.L9 ; U9.E68 110.97,61.02 110.87,61.11 v4(110.54,61.11) 110.54,61.16 110.26,61.44 U9.H67 ; v2(48.72,82.74) 48.18,83.28 46.46,83.28 46.13,82.95 CONN8.81 ; U9.V7 105.04,88.84 105.53,88.35 U9.U9 ; v2(47.35,93.37) 46.42,92.45 CONN8.43 ; CONN7.6 39.68,101.7 39.15,102.24 v2(39.15,102.25) ; U9.E34 U9.E31 111.22,78.14 U9.E29 111.22,79.54 U9.E27 111.22,80.12 U9.E25 U9.E23 U9.E20 ; U9.E34 U9.E36 ; v4(101.57,63.44) 101.57,62.98 100.88,62.3 U9.AH66 ; v2(55.65,59.63) 55.65,59.32 54.53,58.2 CONN8.172 ; v2(42.81,82.85) 43.71,81.95 CONN8.85 ; v2(31.76,100.95) CONN7.9 v2(34.61,100.95) ; v2(35.63,46.68) 35.46,46.85 34.29,46.85 34.19,46.95 CONN7.217 ; v2(36.69,52.11) 36.53,51.95 CONN7.197 ; CONN8.218 50.3,46.7 v2(50.27,46.68) ; v2(31.76,93.45) CONN7.39 ; CONN8.196 50.11,52.2 v2(50.04,52.28) ; CONN8.222 51.48,45.7 50.77,45 v2(50.77,44.79) ; v2(35.36,82.95) 34.75,82.35 34.51,82.35 34.12,81.95 CONN7.85 ; U9.E20 U9.E18 111.22,84.08 111.22,84.49 111.22,84.49 U9.E16 U9.E14 111.22,86.06 111.22,86.47 111.22,86.47 U9.E12 111.22,87.05 U9.E9 111.22,88.04 U9.E7 ; U9.E20 U9.C20 ; v2(31.76,99.45) CONN7.15 ; v2(50.7,55.04) 50.7,54.92 51.18,54.45 52.09,54.45 52.34,54.2 CONN8.188 54.5,54.2 54.74,53.96 54.74,53.46 54.48,53.2 CONN8.192 ; v2(50.98,92.19) 50.98,92.14 51.92,91.2 CONN8.48 ; CONN7.72 39.53,85.2 v2(39.47,85.26) ; CONN7.234 40.45,42.7 40.33,42.58 39.57,42.58 39.15,43 v2(39.15,43.23) 39.15,43.29 39.69,43.83 40.32,43.83 40.45,43.7 CONN7.230 ; CONN7.239 35.47,41.45 v2(35.63,41.61) ; CONN7.226 42.72,44.7 v2(42.81,44.79) 42.81,44.8 42.81,45.43 42.54,45.7 CONN7.222 ; U9.L69 108.51,60.57 108.51,60.05 v4(108.48,60.02) 108.18,59.72 U9.M71 ; v4(106.52,81.75) 106.41,81.75 105.85,81.19 U9.U24 ; v2(31.76,86.95) CONN7.65 ; v4(86.92,92.38) 86.96,92.34 U9.BU2 U9.BU4 ; CONN7.175 36.01,57.45 v2(36.06,57.4) ; v2(35.69,90.81) 35.56,90.81 35.21,90.45 CONN7.51 ; CONN8.35 43.99,94.45 43.56,94.88 v2(43.56,96.14) 43.56,97.02 44,97.45 CONN8.23 ; CONN8.56 54.58,89.2 54.81,88.97 v2(54.81,88.67) 54.81,88.44 54.57,88.2 CONN8.60 ; v2(31.76,88.95) CONN7.57 ; U9.AF74 U9.AF76 ; v2(35.41,39.73) 34.68,40.45 CONN7.243 ; v2(47.94,39.72) 47.21,40.45 CONN8.243 ; v2(38.62,89.01) 38.63,89.01 40.43,87.2 CONN7.64 ; v2(55.7,98.84) 54.83,99.7 CONN8.14 ; CONN8.217 46.19,46.95 46.29,46.85 47.46,46.85 v2(47.63,46.68) ; CONN8.65 v2(43.81,86.95) 43.76,86.9 43.76,86.15 43.96,85.95 CONN8.69 ; v2(31.76,44.45) CONN7.227 ; CONN8.51 47.32,90.45 v2(47.37,90.5) ; U9.Y5 104.25,89.76 103.33,89.76 U9.AB5 ; U9.M18 108.01,83.4 U9.L20 ; v2(31.76,54.95) CONN7.185 ; CONN8.181 46.74,55.95 47.06,55.63 47.44,55.63 v2(48.03,55.04) ; v2(38.13,90.59) 38.51,90.2 CONN7.52 ; v2(31.76,43.45) CONN7.231 ; CONN7.103 31.81,77.45 v2(31.8,77.44) ; v2(31.76,39.45) CONN7.247 ; v2(43.76,37.99) 44.23,38.45 CONN8.251 ; v2(31.76,83.95) CONN7.77 ; CONN8.227 44.08,44.45 43.76,44.13 v2(43.76,43.26) 44.05,43.26 44.25,43.45 CONN8.231 ; U9.AH18 100.23,83.87 100.23,83.31 U9.AH19 U9.AK19 ; v2(31.76,49.95) CONN7.205 ; CONN7.90 40.31,80.7 40.25,80.76 39.69,80.76 v2(39.13,80.2) 39.15,80.2 39.71,79.64 40.22,79.64 40.27,79.7 CONN7.94 ; CONN7.209 v2(31.8,48.95) ; v2(31.76,53.95) CONN7.189 ; CONN8.213 47.05,47.95 47.42,48.32 v2(47.42,48.61) ; 108.01,69.49 108.17,69.49 U9.L51 ; v2(31.76,82.95) CONN7.81
  TOP w0.33: U9.L35 v4(108.01,75.75) ; U9.V30 105,78.58 105,78.11 v4(105.07,78.05) 105.36,77.75 U9.U32 ; U9.BA56 94.75,66.37 v4(95.13,65.99) ; v4(101.55,84.39) U9.AG16 ; U9.T39 v4(106.35,74.93) U9.R37 ; U9.BA28 v4(95.15,78.79) ; v4(104.75,74.13) 104.75,74.13 U9.Y40 ; U9.K67 v4(108.5,61.73) ; U9.AM28 v4(99.15,78.79) ; U9.BF64 92.64,63.44 v4(92.65,63.44) ; U9.Y55 v4(103.95,67.73) ; U9.AR19 97.09,83.19 96.96,83.07 96.47,83.07 U9.AU19 ; U9.BF56 92.16,66.05 v4(92.16,66) ; U9.M26 v4(107.51,80.04) ; U9.AA62 103.43,64.25 103.43,64.81 U9.AA60 U9.AC58 v4(102.35,66.13) ; U9.AP23 v4(98.34,81.21) ; v4(99.95,66.93) U9.AH56 ; U9.BB19 93.95,83.21 94.32,83.58 v4(94.34,83.58) ; v4(99.15,82.79) U9.AK19 ; v4(92.65,61.73) U9.BF67 ; U9.U66 v4(105.04,62.58) ; v4(108.01,62.58) U9.L66 ; U9.AG12 v4(101.55,85.99) ; U9.BA16 95.14,84.41 v4(95.14,84.39) ; U9.AC16 v4(103.15,84.39) ; v4(103.15,80.39) U9.AC27 ; v4(108,79.19) 108.03,79.19 U9.L28 ; U9.AR12 v4(97.55,85.99) U9.AP14 ; U9.BE69 92.65,60.58 v4(92.65,60.01) U9.BF71 ; U9.AR53 v4(97.55,68.53) U9.AP53 ; v4(102.35,82.79) U9.AE19 ; U9.L43 v4(108.5,73.15) ; U9.AE23 v4(101.55,81.19) ; U9.K60 v4(108.5,65.16) U9.M60 U9.P60 U9.T60 105.62,64.87 105.57,64.93 U9.V60 ; U9.M37 v4(107.51,74.89)
  TOP w0.356: U9.CG69 v4(83.24,60.87) ; U9.R69 106.76,60.58 v4(107.04,60.86) ; U9.N76 U9.N74 ; U9.V42 U9.Y42 U9.Y40 ; U9.AF5 100.8,89.73 100.8,89.73 100.36,89.73 100.35,89.73 U9.AH5 ; U9.CJ16 v4(82.25,84.33) ; U9.CG24 v4(83.24,80.9) ; v4(107.75,58.28) U9.L74 ; U9.CG66 v4(83.24,62.58) ; U9.CL16 v4(81.26,84.33) ; U9.CH64 v4(82.75,63.44) ; v4(109.99,59.15) U9.F72 ; U9.CG20 v4(83.24,82.62) ; U9.CA71 v4(85.72,60.01) ; U9.N66 107.72,62.3 v4(108.01,62.58) ; U9.CH71 v4(82.75,60.01) ; U9.J74 v4(108.74,58.28) ; U9.AL7 98.6,88.42 U9.AM9 ; U9.CH18 v4(82.75,83.47) ; U9.Y76 U9.Y74 104.06,58.28 v4(103.79,58.28) 103.56,58.05 U9.AB74 ; U9.CH22 v4(82.75,81.76) ; U9.CH67 v4(82.75,61.73) ; U9.CG16 v4(83.24,84.33) ; U9.H56 U9.K56 ; U9.B61 U9.D61 ; U9.AA25 v4(103.15,80.39)
  TOP w0.381: v4(96.75,66.93) U9.AR56 ; v4(96.75,66.93) 96.35,67.33 U9.AU55 ; v4(96.75,66.93) U9.AU56 ; v4(96.75,66.93) 97.15,67.33 U9.AR55 ; R268.1 R267.1 v2(106.45,46.08) ; R319.2 42,30.16 v3(41.83,30) ; U9.BM13 v4(90.18,86.05) ; U9.V46 105,71.48 104.78,71.48 v4(104.52,71.73) 104.92,72.13 U9.V44 ; U9.BT24 v4(88.2,80.9) ; v4(85.72,78.32) 86.01,78.61 U9.BW30 ; C96.2 v2(138.38,71.27) ; U9.U9 106.03,87.56 U9.T11 106.03,86.75 105.62,86.34 U9.U13 ; v2(25.27,16.39) 24.46,17.2 C191.2 ; v2(192.13,32.87) C70.2 ; v2(192.13,32.87) 193.47,32.87 195.33,34.72 198.42,34.72 v2(199.22,35.52) 199.22,36.33 R1054.1 199.85,37.39 199.85,40.42 199.61,40.66 OSC4.2 v2(198.59,42.27) 198.59,42.45 197.97,43.08 197.97,44.98 v2(198.09,45.11) ; v2(192.13,32.87) 190.98,32.87 189.59,34.26 189.59,39.98 190.56,40.96 192.18,40.96 192.52,40.61 193.79,40.61 194.16,40.25 v2(194.16,39.98) ; C102.1 v2(133.6,66.41) ; U9.BY20 v4(86.21,82.62) ; 166.87,8.49 v2(164.82,8.49) ; v2(142.62,83.44) 141.99,82.8 141.99,77.93 v2(142.09,77.83) 141.91,77.65 C649.2 141.35,77.09 140.97,76.71 140.97,73.53 141.6,72.9 v2(143.38,72.9) 144.49,74 OSC6.4 145.34,74 145.72,74.38 145.72,76.48 C650.1 v2(145.11,77.92) 145.11,82.6 144.27,83.44 v2(144.15,83.44) ; v2(147.7,101.35) 147.45,101.09 R821.1 ; CONN5.3 164.09,97.54 v2(163.58,97.03) ; U12.G7 v3(194.09,56.61) ; C155.1 42.03,31.11 v3(41.83,30.91) ; v4(108.01,62.58) 108.01,62.58 U9.M64 108.5,63.65 U9.L62 ; U12.J8 v3(195.09,53.61) ; R173.1 169.26,82.8 v2(168.48,82.02) ; CONN6.15 v2(197.75,90.63) ; U9.V26 104.54,80.82 U9.W24 U9.U24 105.53,81.71 v4(105.54,81.71) 105.54,82.3 v4(105.46,82.37) 105.28,82.37 105.04,82.13 U9.V22 104.83,81.84 104.34,81.84 104.1,81.59 U9.AA23 U9.AA21 ; C152.2 112.98,35.89 ; 112.98,35.89 v2(113.54,36.45) ; 112.98,35.89 112.98,35.99 v2(112.52,36.45) ; C182.1 52.86,22.12 C177.1 ; CONN6.50 180.55,82.37 v2(180.52,82.4) ; v4(84.23,84.33) 84.02,84.33 U9.CD16 ; C59.2 v2(194.16,38.96) v2(194.16,39.98) ; v4(86.71,78.32) 87,78.61 U9.BU30 ; C204.2 9.63,17.1 v2(9.98,17.45) ; U9.CA11 85.01,87.19 v4(84.73,86.91) ; v2(194.16,39.98) 195.05,39.98 195.5,40.44 195.5,40.94 196.6,42.04 v2(196.6,45.09) ; v2(194.16,39.98) C55.2 ; U9.CJ5 v4(82.01,89.5) U9.CG5 ; v2(156.46,15.24) 156.46,16.26 156.16,16.56 C175.2 155.75,16.56 155.45,16.26 v2(155.45,15.24) ; U9.AH53 v4(99.95,68.53) ; C970.2 122.83,56.54 v2(122.71,56.41) ; C208.2 114.1,13.82 v2(113.79,14.12) ; C38.2 95.48,102.59 v2(95.61,102.46) 95.73,102.59 C39.2 ; v2(106.68,36.2) 106.25,35.77 106.25,35.61 ; U12.K9 v3(197.09,52.61) ; R202.2 115.67,68.42 v2(115.39,68.15) ; v3(75.56,59.68) 76.57,58.67 U9.CV73 ; C283.2 177.35,101.2 ; C201.2 113.28,14.53 v2(112.9,14.15) ; U12.H9 v3(197.09,55.61) ; v2(118.39,37.8) 118.87,37.8 R1052.1 ; v2(2.55,13.54) 2.92,13.54 4.43,15.05 C198.1 ; C169.2 v2(31.83,26.19) ; R1091.1 46.4,111.07 v2(47.02,111.68) 47.44,111.26 C15.2 ; v2(117.35,43.43) 117.22,43.56 C128.2 ; CONN18.4 202.55,104.03 203.19,103.39 v2(203.68,103.39) ; v2(160.01,28.64) C287.2 161.36,29.3 v2(160.95,29.71) ; v2(183.64,93.71) C30.2 C31.2 ; C17.2 156.46,120.14 v2(156.51,120.19) ; C616.2 83.57,13.34 v2(81.2,13.34) 81.2,14.35 C209.2 80.47,15.09 v2(79.6,15.09) ; C8.2 v2(127.99,113.36) ; C183.1 151.69,58.22 ; C82.2 v2(149.17,68.19) ; v2(2.55,14.45) 2.77,14.45 3.49,15.17 C197.2 ; v4(86.71,86.91) 86.42,87.19 U9.BW11 86.01,87.19 v4(85.72,86.91) ; v4(82.75,78.32) 83.03,78.61 U9.CF30 ; U9.BF30 91.95,78.61 v4(91.66,78.32) ; v2(2.49,109.27) 2.95,109.73 C21.1 C14.1 ; U9.BW7 v4(86.71,88.63) ; U1.4 104.39,116.4 104.72,116.08 v2(104.78,116.08) ; R36.2 v2(170.56,117.86) ; v2(99.09,36.3) 99.16,36.38 R524.1 R307.2 ; U9.CC30 84.02,78.61 v4(83.74,78.32) ; v4(83.24,79.18) 82.96,79.47 U9.CG28 ; C142.1 v2(155.06,66.28) ; R289.2 101.54,41.33 102.13,40.74 104.17,40.74 v2(104.39,40.51) 104.01,40.13 R799.2 ; U9.A6 U9.A5 113.44,89.82 114.05,90.42 114.05,90.96 v3(113.84,91.16) ; v4(87.7,78.32) 87.99,78.61 U9.BR30 ; R1039.1 v2(150.37,92.2) ; U9.CH11 82.04,87.19 v4(81.76,86.91) ; C173.2 162.9,75.83 C174.2 ; R797.2 103.45,36.01 v2(103.12,35.69) C146.2 ; C206.2 32.82,14 v2(32.54,13.72) ; U9.AL67 99.09,61.47 98.84,61.73 v4(98.6,61.73) ; U9.AM21 v4(99.15,82.79) ; v2(172.11,30.76) 172.11,30.33 C123.2 171.2,29.56 v2(171.2,30.84) ; R308.1 v2(96.72,33.99) ; U19.4 v2(186.66,22.89) ; v4(104.75,74.13) 104.35,74.53 U9.Y39 ; v4(85.72,80.04) 85.43,80.33 U9.CA26 ; 108.41,35.99 108.41,36.15 v2(108.84,36.58) ; 108.41,35.99 C150.2 ; 108.41,35.99 v2(107.82,36.58) ; C196.2 v2(2.55,15.21) ; U5.4 v2(161.34,115.82) ; U9.L35 108.5,76.4 U9.M33 108.01,77.26 U9.L32 108.71,77.75 v4(109,77.46) ; C469.1 v2(204.16,101.38) ; U9.BJ24 v4(91.17,80.9) ; U9.V18 105.04,83.14 105.28,82.9 U9.U20 105.74,82.9 v4(105.99,83.16) ; U12.B15 v3(203.09,61.61) ; v2(118.41,70.74) 118.41,69.42 C967.2 ; U9.M30 107.98,78.64 107.98,79.17 v4(108,79.19) ; 187.75,121.31 CONN1.G6 ; CONN1.G6 188.54,122.3 ; CONN1.G6 186.96,122.3 ; U12.G9 v3(197.09,56.61) ; v2(119,91.69) 128.14,91.69 128.65,92.2 128.65,92.96 128.2,93.42 v2(127.84,93.42) C52.2 ; v4(107.98,64.31) 108.01,64.34 U9.M60 ; v2(131.8,94.41) 131.8,95 132.18,95.38 R882.1 ; C94.2 125.8,71.66 v2(125.48,71.98) ; R287.2 R283.2 107.79,38.05 v2(107.57,38.28) ; 110.69,36.15 110.26,36.58 v2(110.11,36.58) ; 110.69,36.15 v2(111.12,36.58) ; 110.69,36.15 C151.2 ; U44.2 v2(107.19,108.2) ; C87.1 126.03,78.31 v2(126.59,78.87) ; U9.AR60 v4(96.61,65.16) 96.62,65.16 U9.AU58 ; U9.BY24 v4(86.21,80.9) ; v2(103.31,46.81) 103.61,47.11 R245.2 ; R311.2 v2(147.65,108) ; v2(190.06,87.41) 189.75,87.72 CONN6.27 ; v2(101.82,2.52) 102.2,2.15 C259.2 ; C109.2 194.06,43.31 v2(194.01,43.36) ; U9.BV9 v4(87.2,87.77) ; R232.2 R222.1 ; R222.1 R220.2 119.41,58.52 v2(119.89,58.04) ; R222.1 119.22,57.4 120.24,57.4 v2(120.4,57.56) ; v2(152.1,66.96) 152.1,67.09 152.5,67.49 R692.2 ; U9.K56 U9.M56 ; v4(90.67,78.32) 90.96,78.61 U9.BH30 ; v2(36.4,24.99) 36.29,24.89 R334.2 R337.1 ; U38.2 v2(167.4,109.99) ; v2(173.23,22.1) 173.1,22.1 172.84,21.84 U17.4 ; R71.1 93.59,109.33 R64.2 v2(93.63,110.16) ; C252.2 v2(189.36,7.49) ; C963.2 v2(136.65,100.97) ; v4(108.74,58.28) 108.51,58.05 U9.L74 ; 124.46,57.02 v2(125.6,57.02) 125.88,57.3 C975.2 ; U9.BH11 v4(91.66,86.91) ; v2(115.39,46.48) 115.95,46.48 R1051.1 ; C140.2 v2(154.08,66.28) ; C184.1 152.61,58.26 152.6,58.27 ; U16.4 v2(120.86,48.84) ; 66.7,48.62 66.7,48.61 C138.1 ; U9.AE64 v4(101.57,63.44) 101.15,63.86 U9.AG62 ; v2(127.76,56.11) 127.3,55.65 C113.2 C112.2 ; C89.2 131.39,76.86 v2(131.67,77.15) ; C974.2 C52.2 ; C52.2 v2(127,94.87) 126.55,95.32 C51.2 125.98,95.91 125.76,96.14 119.53,96.14 v2(119.2,95.81) 119.2,94.98 119.74,94.45 OSC2.2 ; v2(121.03,13.21) 120.95,13.21 120.41,13.75 C199.2 ; C257.2 v2(182.37,1.48) ; Q5.S v2(164.4,84.27) ; R96.1 R97.1 v2(180.92,93.91) ; U12.G10 v3(198.09,56.61) ; v2(143.51,76.58) 142.53,75.6 OSC6.2 ; U12.K10 v3(198.09,52.61) ; C258.1 R402.2 69.19,3.1 v2(68.81,3.48) ; C912.2 v2(113.16,108.08) ; U9.R46 107.16,71.74 U9.M45 108.26,71.74 v4(108.55,71.44) 108.55,70.93 U9.L47 108.01,70.39 U9.M49 108.01,69.49 ; CONN5.8 162.94,92.46 v2(163.58,93.09) 164.21,92.46 CONN5.7 ; C92.2 v2(144.55,66.82) ; CONN6.35 v2(186.55,90.55) ; C640.2 v2(203.93,115.52) ; C88.2 v2(127.49,78.79) ; R1031.1 v2(138.81,79.76) ; C174.2 161.55,76.46 ; C174.2 160.87,75.83 ; U9.V60 U9.V62 ; U12.T16 v3(204.09,46.61) ; v2(65.74,22.25) 65.74,21.36 C186.2 65,21.89 v2(65,22.25) ; C12.2 v2(191.87,100.59) ; v4(85.22,77.46) 84.94,77.75 U9.CB32 ; U9.BM24 v4(90.18,80.9) ; v4(97.11,62.63) 96.86,62.63 96.62,62.39 U9.AU66 96.42,62.3 v4(96.12,62) ; R864.1 v2(145.41,98.17) ; v2(158.5,108.31) 159.11,108.31 C265.2 159.03,109.19 v2(158.57,109.19) ; v2(104.47,96.71) R143.2 R142.2 ; C651.2 v2(135.64,100.97) ; v2(173.45,16.63) 172.8,17.28 U17.11 ; CONN6.26 v2(190.15,82.39) ; C141.1 v2(153.16,66.28) ; U9.BJ58 90.67,65.26 90.67,65.25 90.67,65.16 v4(90.67,65.16) 90.96,64.87 U9.BH60 ; C1.2 v2(186.31,118.19) ; U9.K60 U9.H60 ; v2(130.94,103.76) 131.87,102.82 R99.2 ; C105.2 127.54,64.77 ; U9.AE7 v4(101.57,89.2) ; C205.1 v2(10.57,16.77) ; v2(57.56,107.16) 58.06,106.66 C124.1 ; C68.1 120.43,85.35 120.37,85.29 v3(120.27,85.29) ; C227.2 88.74,11.01 87.27,9.55 v2(85.88,9.55) ; C108.2 123.93,62.71 v2(124.17,62.95) 124.03,63.1 OSC5.4 125.61,64.22 C103.2 ; C195.2 v2(65.33,16.46) ; CONN1.5 v2(182.82,121.01) ; C83.2 207.26,67.13 v2(206.42,66.28) ; v2(70.64,100.53) 72.44,100.53 Q4.S ; C218.2 v2(53.13,13.82) ; v2(119.02,70.05) 119.18,70.05 C968.2 ; R857.1 v2(141.35,98.17) ; v2(127.99,66.83) 128.77,66.83 C101.2 ; OSC1.2 165.43,120.84 v2(165.44,120.85) ; U9.CK11 81.05,87.19 v4(80.77,86.91) ; v2(148.46,111.12) 148.34,111.25 R314.1 ; U12.A1 v3(188.09,62.61) ; C25.1 v2(132.59,100.21) ; CONN6.40 v2(184.55,82.39) ; R855.1 v2(139.32,98.17) ; U9.BL30 89.97,78.61 v4(89.68,78.32) ; R1047.2 v2(149.48,105.16) ; v4(93.12,62.59) 92.83,62.3 U9.BE66 ; C67.2 v2(193.4,38.2) ; C234.2 v2(5.44,11.04) ; v2(186.22,87.16) 185.75,87.63 CONN6.37 ; C171.1 v2(33.76,26.19) ; C256.1 101.6,3.3 v2(100.89,2.59) ; v3(133.65,98.67) 133.19,99.13 R1094.1 ; C78.1 v3(116.61,85.22) ; U12.R2 v3(189.09,47.61) ; R982.1 168.28,104.11 v2(167.92,103.76) ; C93.2 128.27,71.89 v2(128.4,71.75) ; U9.D61 U9.E62 U9.E64 111.22,62.71 U9.E66 111.22,61.72 U9.E68 111.22,60.73 U9.E70 ; v2(179.17,16.92) 178.8,17.28 U17.18 ; C97.2 137.6,65.53 138.11,65.02 v2(138.81,65.02) ; C228.2 174.68,11 v2(174.57,11.1) ; C20.2 R42.1 132.84,111.25 v2(134.24,111.25) ; v3(133.65,96.78) 133.19,96.32 R1095.1 ; U9.V7 104.29,89.66 U9.Y5 104.58,89.73 U9.V5 ; C255.1 77.25,2.9 v2(77.09,2.74) ; C6.2 171.55,114.16 v2(171.55,113.54) ; C185.2 153.53,58.21 153.52,58.22 ; v4(80.77,78.32) 81.05,78.61 U9.CK30 ; C100.2 v2(171.2,49.68) ; v2(167.11,103.73) 167.11,104.43 C900.2 166.09,104.49 v2(166.09,103.73) ; CONN9.10 v2(204.93,8.43) ; C210.2 v2(163.68,14.1) ; CONN9.2 v2(194.77,8.1) ; U9.BM16 v4(90.18,84.33) ; v4(109.99,59.15) 109.78,59.15 U9.J72 ; v2(68.55,70.1) 68.48,70.03 R200.2 C98.2 ; U9.R54 106.46,67.51 106.46,68.59 v4(106.48,68.61) 106.72,68.61 U9.P52 ; C3.2 v2(175.49,115.24) ; v2(102.67,8.99) 103.02,9.34 C236.2 ; v2(9.99,10.21) C225.2 C226.1 ; C170.1 v2(32.79,26.19) ; U12.K8 v3(195.09,52.61) ; C99.2 v2(133.78,69.42) ; C147.2 106.25,35.61 ; 106.25,35.61 v2(105.66,36.2) ; C77.1 v3(118.59,85.21) ; v2(166.8,25.73) C121.2 ; C19.2 v2(153.97,116.61) ; v2(68.38,58.75) 67.82,59.31 R215.2 R211.2 ; v2(62.51,113.94) 62.4,113.83 U2.2 ; C266.2 165.11,113.96 v2(164.95,114.12) ; C69.1 123.94,85.35 v2(124.21,85.09) ; v2(200.56,13.74) C153.2 ; v2(189.99,67.44) 190.75,66.67 R218.1 ; C239.1 102.95,8 v2(102.69,8.26) ; U12.G8 v3(195.09,56.61) ; U20.4 v2(138.96,107.97) ; U9.AL64 v4(98.6,63.44) ; v4(104.55,63.5) 104.89,63.16 U9.V64 v4(105.04,62.58) ; C172.2 v2(167.22,72.83) ; SW1.1 v2(184.91,3.38) SW1.2 ; v4(84.73,78.32) 85.01,78.61 U9.CA30 ; R43.2 v2(82.42,111.33) ; U12.R15 v3(203.09,47.61) ; U9.BW14 v4(86.71,85.19) ; v2(120.57,53.49) 118.59,53.49 118.19,53.89 C114.2 ; C66.2 v2(192.38,38.2) ; CONN6.4 v2(202.15,82.3) ; C81.1 v2(149.06,73.47) ; v2(68.2,6.71) 68.2,6.48 68.76,5.91 C248.1 ; C200.2 v2(81,16.99) ; R260.1 v2(105.46,44.4) 104.42,44.4 R266.2 ; C545.2 v2(101.84,35.3) ; v4(87.2,86.05) 86.92,86.34 U9.BV13 ; U12.K7 v3(194.09,52.61) ; CONN6.18 193.35,82.46 v2(193.07,82.74) ; R1041.1 v2(150.37,93.22) ; v4(81.76,78.32) 82.04,78.61 U9.CH30 ; C36.2 v2(175.49,104.95) ; R216.2 R213.2 v2(119.94,61.34) ; R216.2 v2(120.02,60.4) ; R216.2 R217.2 ; v2(97.49,49.02) 97.48,49.02 R259.2 R258.2 ; C35.2 v2(56.52,100.96) ; U9.AM30 v4(99.15,78.79) ; C235.2 v2(164.08,9.65) ; U9.BN30 88.98,78.61 v4(88.69,78.32) ; C975.2 v2(126.59,56.46) ; C975.2 v2(127.51,57.3) ; C250.2 v2(64.38,3.76) ; SW2.1 v2(189.23,3.38) SW2.2 ; v4(82.75,86.91) 83.03,87.19 U9.CF11 ; C601.2 v2(185.67,7.49) ; U43.8 v2(112.29,113.03) ; v2(18.82,20.73) 19.76,20.73 20.37,20.12 C190.2 20.12,19.63 19.02,19.63 v2(17.91,20.75) ; U12.T1 v3(188.09,46.61) ; CONN7.G2 23.55,37.28 v2(23.55,38.25) ; C126.2 v2(205.43,32.81) ; v4(91.66,85.19) U9.BH14 ; C253.2 v2(85.7,4.09) ; U9.BV24 v4(87.2,80.9) ; U9.AK60 v4(99.15,65.33) ; C22.1 v2(163.9,119.43) ; U7.8 v2(200.61,94.41) ; U9.T74 U9.N74 107.52,58.05 v4(107.75,58.28) ; v2(135.89,108.08) 135.56,108.08 135.18,107.7 R1046.2 ; v4(84.98,89.5) U9.CC5 ; C216.2 v2(148.67,38.68) ; R323.2 v2(19.67,29.57) ; R153.1 v2(206.5,69.42) ; U12.B2 v3(189.09,61.61) ; C264.2 v2(165.23,103.25) ; R318.2 v2(19.69,30.59) ; R1090.1 45.09,111.12 v2(44.53,111.68) 43.94,111.1 R1081.2 ; C284.2 171.47,97.9 ; U9.BM20 v4(90.18,82.62) ; U9.U16 105.75,84.62 v4(106.02,84.89) ; U9.BG24 v4(92.16,80.9) ; C192.2 25.91,16.99 v2(26.36,16.54) ; R199.1 R196.1 117.62,71.31 v2(117.7,71.4) ; C13.2 v2(95.02,111.66) ; U9.BE28 92.65,79.47 v4(92.65,80.04) U9.BF26 ; v4(101.57,87.48) U9.AE11 ; C194.2 77.45,17.32 v2(77.65,17.12) ; C143.2 v2(104.55,35.71) ; v4(101.57,60.01) U9.AE71 ; C240.1 v2(82.45,6.48) ; R169.1 v2(168.43,84.95) ; R863.1 v2(143.38,98.17) ; v2(191.84,87.41) 192.15,87.72 CONN6.21 ; CONN6.29 v2(188.95,87.41) ; R274.2 114.98,44.45 v2(115.09,44.35) ; C7.2 171.36,116.22 v2(171.39,116.24) ; R1035.1 v2(137.79,79.76) ; U9.L20 108.29,82.9 v4(108.01,82.62) ; v2(99.06,119) 99.31,119.25 C910.2 ; U9.L51 108.83,69.49 v4(109,69.49) ; C212.2 v2(163.68,13.16) ; U9.CC11 84.02,87.19 v4(83.74,86.91) ; C130.2 v2(137.23,113.97) ; C9.1 v2(128.98,113.36) ; C207.2 v2(6.54,11.89) ; U9.BR22 v4(88.69,81.76) ; C42.1 v2(125.31,33.3) ; C224.2 v2(9,10.17) ; v2(122.5,66.95) 122.5,66.41 OSC5.2 ; Q2.S v2(62.11,111.1) ; v2(110.69,3.91) 110.69,2.79 C905.2 109.78,2.94 v2(109.78,3.86) ; C268.2 v2(165.87,115.19) ; R856.1 v2(140.34,98.17) ; C242.2 v2(151.38,32.03) ; C233.2 v2(54.51,10.7) ; R282.1 174.77,37.21 v2(174.83,37.26) ; R275.2 v2(97.49,45.85) ; v4(97.36,63.68) 97.02,64.01 U9.AU62 96.62,63.65 U9.AV64 ; C251.2 v2(65.34,3.75) ; R310.2 151.38,68.91 v2(150.34,68.91) ; U9.CB16 v4(85.22,84.33) ; U9.BR18 v4(88.69,83.47) ; R1012.1 v2(146.43,98.3) ; CONN3.2 v2(44.49,114.86) ; C76.1 v3(117.57,85.22) ; U9.AC58 U9.AA56 ; v2(153.67,15.24) 153.67,16.05 153.16,16.56 C164.2 152.93,16.29 v2(152.93,15.11) ; v4(103.15,84.39) U9.AC18 ; CONN6.9 v2(200.15,90.68) ; Q6.S v2(98.15,5.27) ; R1044.1 v2(150.37,91.19) ; R1037.1 v2(150.37,94.23) ; U9.AE14 v4(101.55,85.99) ; CONN6.G2 v2(176.9,90.59) ; C158.2 v2(150.5,16.13) ; U12.G5 v3(192.09,56.61) ; C10.1 v2(129.9,113.39) ; R970.2 v2(153.42,87.12) ; 179.71,122.3 CONN1.G3 ; CONN1.G3 180.5,121.31 ; CONN1.G3 181.29,122.3 ; R902.1 v2(183.7,95.48) ; v2(186.82,82.42) 186.95,82.29 CONN6.34 ; U9.BY28 85.93,79.47 v4(86.21,79.18) ; U9.BM9 v4(90.18,87.77) ; U9.BY16 v4(86.21,84.33) ; C104.2 126.6,64.75 ; R620.2 v2(172.21,40.89) ; U9.BH18 v4(91.66,83.47) ; v2(163.58,100.58) 164.08,100.08 CONN5.1 ; U42.2 v2(105.28,118.75) ; C16.2 v2(156.46,119.13) ; C249.1 101.07,6.64 C241.2 v2(101.13,7.47) ; v4(80.98,89.5) 80.97,89.51 80.96,89.53 U9.CL5 ; CONN5.5 v2(163.58,95) ; R367.1 v2(95.94,9.55) ; R862.1 v2(142.37,98.17) ; U12.J10 v3(198.09,53.61) ; R377.1 69.07,6.87 v2(68.94,6.73) ; v2(165.26,25.75) C118.2 ; U9.AU53 U9.AR53 ; U21.8 v2(192.37,19.83) ; v3(119.58,85.21) C75.1 C74.1 ; U39.4 v2(143.89,106.68) ; U9.BR11 v4(88.69,86.91) ; U9.L66 v4(108.5,61.73) ; C18.2 v2(153.97,115.72) ; U9.CA22 v4(85.72,81.76) ; U12.A16 v3(204.09,62.61) ; R1033.1 v2(136.78,79.76) ; U12.H7 v3(194.09,55.61) ; v2(59.28,115.04) 58.91,115.04 C11.2 ; v3(113.73,64.48) U9.B61 ; C127.2 v2(177.61,32.8) ; R382.1 v2(155.12,32.01) ; U9.BP24 v4(89.19,80.9) ; C270.2 v2(165.92,116.28) ; U9.V71 v4(104.54,60.01) ; v2(90.93,17.6) C193.2 ; C91.2 v2(144.65,65.66) ; C84.2 v2(146.2,73.46) ; U9.CA18 v4(85.72,83.47) ; U9.CE5 v4(83.99,89.5)
  TOP w0.508: R957.1 v2(146.18,79.38)
  G2 w0.381: 179.71,122.3 CONN1.G3 ; CONN1.G3 180.5,121.31 ; CONN1.G3 181.29,122.3 ; 162.09,6.89 CONN16.G4 ; CONN16.G4 163.97,6.89 ; CONN16.G4 163.03,7.83 ; CONN16.G4 163.03,5.95 ; 123.75,6.89 CONN16.G3 ; CONN16.G3 124.69,5.95 ; CONN16.G3 124.69,7.83 ; CONN16.G3 125.63,6.89 ; CONN1.G1 181.7,120.4 ; CONN1.G1 182.45,119.65 ; CONN1.G1 180.95,119.65 ; CONN1.G1 181.7,118.9 ; CONN16.G1 160.8,2.24 ; CONN16.G1 161.74,1.3 ; CONN16.G1 159.86,1.3 ; 125.97,1.3 CONN16.G2 ; CONN16.G2 126.91,2.24 ; CONN16.G2 127.85,1.3 ; CONN1.G6 188.54,122.3 ; CONN1.G6 186.96,122.3 ; CONN1.G6 187.75,121.31 ; 185.8,119.65 CONN1.G2 ; CONN1.G2 187.3,119.65 ; CONN1.G2 186.55,120.4 ; CONN1.G2 186.55,118.9
  G4 w0.381: CONN1.G3 181.29,122.3 ; CONN1.G3 180.5,121.31 ; CONN1.G3 179.71,122.3 ; 124.69,5.95 CONN16.G3 ; CONN16.G3 125.63,6.89 ; CONN16.G3 123.75,6.89 ; CONN16.G3 124.69,7.83 ; CONN16.G1 160.8,2.24 ; CONN16.G1 159.86,1.3 ; CONN16.G1 161.74,1.3 ; 185.8,119.65 CONN1.G2 ; CONN1.G2 187.3,119.65 ; CONN1.G2 186.55,120.4 ; CONN1.G2 186.55,118.9 ; CONN1.G6 188.54,122.3 ; CONN1.G6 186.96,122.3 ; CONN1.G6 187.75,121.31 ; CONN16.G4 163.97,6.89 ; CONN16.G4 163.03,7.83 ; CONN16.G4 163.03,5.95 ; CONN16.G4 162.09,6.89 ; 125.97,1.3 CONN16.G2 ; CONN16.G2 126.91,2.24 ; CONN16.G2 127.85,1.3 ; CONN1.G1 181.7,120.4 ; CONN1.G1 181.7,118.9 ; CONN1.G1 182.45,119.65 ; CONN1.G1 180.95,119.65
  G9 w0.381: 186.55,118.9 CONN1.G2 ; CONN1.G2 187.3,119.65 ; CONN1.G2 186.55,120.4 ; CONN1.G2 185.8,119.65 ; CONN16.G3 125.63,6.89 ; CONN16.G3 124.69,7.83 ; CONN16.G3 124.69,5.95 ; CONN16.G3 123.75,6.89 ; 180.5,121.31 CONN1.G3 ; CONN1.G3 181.29,122.3 ; CONN1.G3 179.71,122.3 ; 162.09,6.89 CONN16.G4 ; CONN16.G4 163.97,6.89 ; CONN16.G4 163.03,7.83 ; CONN16.G4 163.03,5.95 ; CONN16.G2 126.91,2.24 ; CONN16.G2 125.97,1.3 ; CONN16.G2 127.85,1.3 ; 180.95,119.65 CONN1.G1 ; CONN1.G1 181.7,120.4 ; CONN1.G1 181.7,118.9 ; CONN1.G1 182.45,119.65 ; 159.86,1.3 CONN16.G1 ; CONN16.G1 160.8,2.24 ; CONN16.G1 161.74,1.3 ; 187.75,121.31 CONN1.G6 ; CONN1.G6 188.54,122.3 ; CONN1.G6 186.96,122.3
  G11 w0.381: CONN16.G1 160.8,2.24 ; CONN16.G1 161.74,1.3 ; CONN16.G1 159.86,1.3 ; CONN16.G4 163.03,7.83 ; CONN16.G4 162.09,6.89 ; CONN16.G4 163.03,5.95 ; CONN16.G4 163.97,6.89 ; 180.5,121.31 CONN1.G3 ; CONN1.G3 179.71,122.3 ; CONN1.G3 181.29,122.3 ; 181.7,118.9 CONN1.G1 ; CONN1.G1 180.95,119.65 ; CONN1.G1 182.45,119.65 ; CONN1.G1 181.7,120.4 ; 186.96,122.3 CONN1.G6 ; CONN1.G6 187.75,121.31 ; CONN1.G6 188.54,122.3 ; CONN1.G2 186.55,120.4 ; CONN1.G2 185.8,119.65 ; CONN1.G2 187.3,119.65 ; CONN1.G2 186.55,118.9 ; 125.97,1.3 CONN16.G2 ; CONN16.G2 127.85,1.3 ; CONN16.G2 126.91,2.24 ; CONN16.G3 124.69,7.83 ; CONN16.G3 124.69,5.95 ; CONN16.G3 125.63,6.89 ; CONN16.G3 123.75,6.89
  BOTTOM w0.203: v4(96.75,80.4) 96.75,80.29 97.21,79.83 97.21,79.58 97.38,79.4 C321.1 ; C312.1 97.61,81.34 97.28,81.66 97.03,81.66 C307.1
  BOTTOM w0.254: CONN16.86 137.6,0.44 ; CONN16.22 153.6,0.44 ; v4(95.78,89.36) 95.05,88.62 C289.1 94.64,88.21 94.16,87.73 94.16,87.33 94.59,86.89 C292.1 ; CONN16.88 137.1,0.45 ; CONN16.112 131.1,0.42 ; U37.8 v3(41.83,30) 41.33,30.5 U37.4 ; CONN16.90 136.6,0.46 ; CONN16.32 151.1,0.5 ; CONN16.14 155.6,0.5 ; CONN16.80 139.1,0.44 ; CONN16.30 151.6,0.47 ; CONN16.96 135.1,0.47 ; CONN16.16 155.1,0.54 ; CONN16.12 156.1,0.45 ; CONN16.40 149.1,0.45 ; v2(41.83,117.02) 42.14,117.02 43.17,118.05 U45.8 ; CONN16.106 132.6,0.48 ; CONN16.38 149.6,0.51 ; CONN16.98 134.6,0.48 ; CONN16.104 133.1,0.46 ; CONN16.24 153.1,0.46
  BOTTOM w0.305: CONN16.53 145.6,8.84 v2(145.35,9.09) 145.1,8.84 CONN16.55 ; CONN16.109 v2(131.6,9.22) ; CONN13.11 v2(204.8,116.32) ; CONN16.45 147.6,8.84 v2(147.35,9.09) 147.1,8.84 CONN16.47 ; 151.6,5.47 v2(151.64,5.44) ; 151.6,5.47 151.1,5.97 CONN16.31 ; 151.6,5.47 CONN16.29 ; CONN13.57 v2(193.3,116.36) ; CONN16.99 v2(134.1,9.15) ; CONN16.103 v2(133.1,9.2) ; CONN13.45 196.3,113.96 v2(196.16,113.82) ; CONN16.95 v2(135.1,9.12) ; CONN13.39 197.8,113.98 197.67,113.85 v2(197.67,113.84) ; CONN16.61 v2(143.6,9.19) ; CONN16.15 155.1,8.84 v2(155.35,9.09) 155.6,8.84 CONN16.13 ; CONN16.120 129.1,0.45 ; CONN16.37 149.6,5.88 v2(149.1,5.38) CONN16.39 ; CONN16.21 153.6,5.94 v2(153.1,5.44) CONN16.23 ; CONN16.11 v2(156.1,9.38) ; CONN16.71 v2(141.1,9.12) ; CONN16.115 v2(130.1,9.2) ; CONN16.65 142.6,9.2 v2(142.52,9.28) ; CONN13.27 v2(200.8,116.27) ; CONN13.51 v2(194.8,116.36) ; CONN16.114 130.6,0.48 ; CONN13.33 v2(199.3,116.3)
  BOTTOM w0.356: CONN14.131 22.75,37.28 23.55,38.07 v2(23.55,38.25) ; v2(23.5,70.99) 23.38,70.88 CONN14.27 ; CONN14.76 v2(15.35,53.78) ; CONN14.65 v2(20.09,59.48) ; CONN14.46 v2(15.09,65.18) ; v2(15.11,32) 14.69,31.58 CONN14.150 ; CONN14.186 v2(15.35,20.78) ; CONN14.167 19.57,26.48 v2(19.2,26.11) ; CONN14.7 23.27,76.88 v2(23.39,76.76) ; CONN14.114 v2(15.35,42.38) ; CONN14.113 v2(19.68,42.68) ; CONN14.59 23.05,61.28 v2(23.27,61.49) ; CONN14.1 23.03,78.68 v2(23.39,79.04) ; CONN14.82 15.18,51.98 v2(15.32,52.12) ; CONN14.96 v2(15.35,47.78) ; v2(23.62,15.7) 23.62,16.71 22.86,17.48 CONN14.197 ; CONN14.132 v2(15.35,36.98) ; v2(23.27,65.91) 22.83,65.48 CONN14.45 ; CONN14.22 v2(15.35,72.38) ; CONN14.71 v2(20.07,57.68) ; v2(15.37,18.24) 14.91,17.78 CONN14.196 ; CONN14.83 v2(23.11,51.68) ; CONN14.28 v2(15.35,70.58) ; CONN14.185 19.66,21.08 v2(19.3,21.44) ; v2(15.9,16.94) 15.66,17.18 CONN14.198 ; CONN14.84 v2(15.35,51.38) ; CONN14.58 v2(11.82,61.58) ; v2(23.34,75.26) 23.16,75.08 CONN14.13 ; v2(24.38,15.85) 24.38,16.97 23.28,18.08 CONN14.195 ; v2(23.42,73.1) 23.24,73.28 CONN14.19 ; CONN14.77 23.15,53.48 v2(23.16,53.49) ; CONN14.64 v2(11.82,59.78) ; CONN14.70 v2(11.82,57.98) ; CONN14.168 v2(15.05,26.18)
  BOTTOM w0.381: v2(173.23,22.1) 172.79,21.66 R955.1 ; v3(195.09,53.61) U12.K7 ; v3(194.09,56.61) C411.2 ; v3(152.68,38.96) 153.01,39.29 R727.2 ; C614.2 v2(54.46,13.87) 55.37,14.78 R780.2 ; C154.2 143.76,112.9 v2(143.13,112.27) ; C271.2 v2(24.69,108.31) ; CONN15.G2 206.63,6.08 v2(206.63,7.49) ; v2(135.08,81.48) 135.1,81.48 135.25,81.33 135.86,81.33 136.17,81.03 C959.1 135.99,80.75 v2(135.08,80.75) ; C943.1 143,83.85 142.62,83.46 v2(142.62,83.44) ; v2(88.06,38.91) 89.02,37.95 90.42,37.95 C522.2 C526.2 C529.2 ; C483.2 28.42,62.03 v2(28.42,62.81) 28.57,62.96 C473.2 ; C561.2 65.98,34.45 C563.1 ; v3(95.92,92.42) 95.83,92.34 R520.2 ; v4(92.9,58.28) 92.94,58.24 C493.1 C496.1 ; C322.2 104.22,79.58 C323.1 103.55,79.99 v4(103.15,80.39) ; v2(51.94,38.07) 52.41,37.61 C523.2 C524.2 R680.2 ; U12.A16 v3(204.09,62.61) ; C432.1 100.67,66.93 v4(99.95,66.93) ; R734.2 68.66,10.16 v2(68.2,10.62) ; v4(99.15,84.39) 99.11,84.35 C302.1 ; v2(30.03,35.73) C527.2 C528.2 30.97,35.67 v2(30.71,35.41) ; v2(168.48,81.03) 168.55,80.96 R542.2 ; C368.1 89.69,73.58 v4(89.41,73.31) ; v2(106.68,23.75) 106.68,24.51 106.18,25.01 C148.2 ; C311.1 115.06,79.88 v2(115.16,79.78) ; C294.1 103.12,86.97 102.29,86.97 101.77,87.48 v4(101.57,87.48) ; v3(105.26,92.61) 106.6,93.95 R906.2 ; R637.2 111.65,41.33 112.04,41.71 v2(112.04,41.91) ; C913.1 v2(176.41,17.4) ; v4(98.6,61.73) 99.14,62.27 R578.1 ; C909.2 31.26,56.82 v2(31.57,56.51) ; v4(101.55,85.99) 101.88,86.33 C296.1 ; v2(99.19,75.36) 98.27,76.28 C337.1 98.32,76.5 98.96,76.5 C334.1 ; R468.1 v2(158.78,118.29) ; C454.2 69.24,69.42 v2(68.55,70.1) 68.45,70 68.45,68.33 69.24,67.54 C431.2 ; v2(28.42,68.45) C423.2 29.31,69.06 C408.2 ; C647.1 v2(169.24,112.34) ; v4(96.31,76.82) 96.38,76.82 C331.1 ; v4(99.15,65.33) 99.15,66.08 C447.1 ; v4(99.15,65.33) 99.3,65.48 C458.2 ; v4(99.15,65.33) 99.9,64.58 C976.2 99.34,64.31 v4(99.14,64.52) 99.01,64.39 C461.2 98.09,63.94 v4(98.6,63.44) ; v2(117.35,43.43) 117.6,43.18 R1050.1 ; v2(97.49,45.85) 97.56,45.77 R624.2 ; v2(68.2,6.71) 68.2,6.48 68.76,5.91 C248.1 ; C295.1 99.53,86.81 C293.1 99.46,87.35 v4(99.59,87.48) ; C908.2 27.96,55.63 v2(28.11,55.78) ; v4(82.75,63.44) 82.95,63.44 83.21,63.7 C466.2 ; C491.2 47.44,57.06 v2(47.4,57.01) ; C465.2 85.19,63.97 v4(85.72,63.44) ; v3(195.09,56.61) C398.2 ; C443.2 172.19,64.8 172.61,64.37 v3(173.15,64.37) ; v2(43.66,4.75) 43.74,4.67 C638.1 ; v2(55.65,59.63) 55.49,59.79 C474.2 ; v2(203.94,78.48) 204.41,78 C64.2 ; v2(115.39,68.15) 115.01,68.53 C388.1 ; v2(143.38,90.3) 143.38,89.79 C960.1 142.62,89.53 142.62,90.68 v2(142.88,90.93) ; C610.2 160.76,14.33 ; R518.1 94.29,96.83 94.61,97.15 94.87,97.15 v2(94.87,97.15) ; C414.2 v3(198.09,56.61) ; CONN14.G1 v2(5.55,82.51) ; v3(56.86,7.53) 56.86,8.01 R743.2 ; v4(105.07,78.05) 105.06,78.05 C330.1 ; R547.2 92.79,76.46 v4(92.64,76.61) ; C332.2 R550.1 144.28,69.63 v3(143.54,68.89) ; C383.2 v2(29.34,72.77) ; C541.2 C542.2 45.99,33.38 v2(46.08,33.3) ; R544.2 R545.2 107.87,78.13 107.87,79.07 v4(108,79.19) ; v2(65.74,22.25) 65.74,21.87 C600.2 65,21.39 v2(65,22.25) ; C303.1 100.54,84.6 v4(100.75,84.39) ; v4(110.52,68.12) 110.81,67.83 C433.1 C434.1 ; C346.2 50.62,76.88 C336.2 50.9,77.72 v2(50.9,77.99) 50.9,78.23 51.36,78.69 52.02,78.69 52.81,77.9 52.81,74.98 52.34,74.52 C365.2 ; C495.1 91.64,56.72 90.92,57.44 v4(90.92,58.28) ; Q12.S 84.52,47.71 v3(84.52,48.88) ; v2(179.17,16.92) 178.51,17.58 C914.1 ; C353.2 v2(29.39,75.45) ; v4(95.15,78.79) 95.15,78.36 94.85,78.06 C329.1 ; v2(56.54,59.65) 56.48,59.71 C475.2 57,61.55 57.25,61.8 57.25,63.14 56.09,64.31 C463.2 ; v4(104.55,63.5) 104.27,63.78 C971.2 ; C425.2 v2(91.53,69.92) 92.12,70.51 C391.2 ; R625.2 v2(102.21,46.05) ; R953.2 31.04,45.01 v2(31.24,45.21) ; C490.1 38.89,58.26 v2(38.89,57.97) ; v4(107.51,80.04) 107.14,79.67 C325.1 ; U40.2 27.41,57.53 27.03,57.92 v2(27.03,58.09) ; C456.2 108.18,65.49 v4(108.5,65.16) ; C333.1 v2(100.94,75.6) C351.1 101.93,74.7 102.57,74.07 C385.1 ; C597.1 v2(62.13,21.59) ; C352.1 94.79,75.24 C349.1 94.36,74.93 93.82,74.4 91.31,74.4 v2(91.08,74.17) ; v4(98.38,66.9) 97.79,66.9 97.33,67.36 C430.1 ; C117.2 166.78,46.41 ; C596.2 31.47,21.57 v3(30.78,22.25) ; v2(137.67,91.57) 137.85,91.57 C937.1 ; C285.1 86.79,92.25 v4(86.92,92.38) ; v4(106.48,68.61) 106.4,68.68 C417.2 ; v4(103.15,84.39) 103.14,84.4 C304.1 101.55,84.4 v4(101.55,84.39) ; R672.1 R677.1 v2(186.77,19.58) ; v2(51.69,23.11) 51.69,22.43 C182.1 50.98,22.53 v2(50.98,23.11) ; R737.2 37.3,10.38 36.89,10.78 v2(36.89,11.18) ; v4(80.27,77.46) 79.62,77.46 79.1,76.94 C345.2 ; v2(208.7,98.55) 207.77,99.48 R848.1 ; v2(38.76,77.91) 38.76,76.86 C350.2 ; C418.1 111.09,69.69 v4(110.57,70.2) ; v4(85.22,67.16) 85.44,67.16 85.67,66.93 C446.2 ; v2(116.2,103.23) 116.2,103.86 C27.2 117.02,104.11 v2(117.02,103.23) ; R535.1 106.58,88.72 v4(106.48,88.62) ; v4(110.54,61.11) 110.54,61.16 110.84,61.47 R582.1 ; v2(88.69,70.84) R564.2 88.69,70.16 R565.2 ; C422.1 101.68,69.36 v2(101.35,69.7) ; v3(194.09,52.61) C435.2 ; v2(202.15,82.3) 202.11,82.26 C54.2 ; C448.2 89.81,65.46 90.11,65.16 v4(90.67,65.16) ; R594.2 103.33,57.81 v4(103.79,58.28) ; v4(102.35,66.13) 102.03,65.81 C139.2 ; C152.2 112.98,35.99 v2(112.52,36.45) ; C286.1 103.22,90.85 R519.2 103.76,90.88 103.98,90.65 105.13,90.65 105.54,91.06 106.68,91.06 107.8,89.94 v4(107.8,89.46) ; R795.2 110.87,55.12 111.86,56.11 R598.2 112.83,55.99 v3(113.73,55.09) ; v3(173.15,52.78) 173.18,52.82 R575.1 ; v2(144.4,92.2) 144.78,92.58 C929.1 ; 58.17,35.18 C539.1 ; v2(208.7,78.23) 208.48,78 C65.2 ; 98.43,82.88 99.06,82.88 v4(99.15,82.79) ; 98.43,82.88 98.43,82.67 99.02,82.08 C308.1 ; 98.43,82.88 C306.1 ; C450.2 32,66.37 C442.2 32.36,67.34 32.74,67.72 C410.2 C403.2 30.58,70.33 R1056.2 30.17,71.74 C395.2 v2(29.34,71.75) ; v2(59.28,115.04) 58.77,114.52 C11.2 ; v2(196.02,6.65) 196.02,5.45 R703.2 ; v2(176.4,18.34) 176.33,18.41 C517.1 ; R437.2 29.54,113.03 v2(29.74,112.83) ; U31.4 v2(96.3,117.14) ; C508.2 117.22,49.48 v2(117.12,49.58) 117.26,49.72 Q9.2 ; R685.2 42.34,33.53 v2(42.39,33.53) 43.05,33.53 R688.2 ; R673.1 C544.2 v2(184.18,19.08) ; C58.2 190.05,82.28 v2(190.15,82.39) ; v2(88.72,47.32) C510.2 C511.2 C512.2 ; C255.1 77.25,2.9 v2(77.09,2.74) ; R644.1 187.04,23.27 v2(186.66,22.89) ; Q16.S 113.57,110.33 v2(113.31,110.33) ; R568.2 v2(88.69,67.54) ; C320.1 100.79,79.55 v4(100.75,79.59) ; C519.2 C518.2 43.97,39.52 v2(43.76,39.72) ; 111.63,21.34 111.63,20.95 112.14,20.45 v2(113.54,20.45) ; 111.63,21.34 110.74,20.45 v2(109.6,20.45) ; 111.63,21.34 C906.C ; C569.2 37.29,33.2 v2(37.54,33.45) 38.23,34.14 R682.2 ; C502.2 165.76,39.78 ; Q14.S 96.56,7.17 95.07,5.69 v2(95.07,4.93) ; C402.2 R561.1 131.92,71.4 v3(131.4,71.93) ; C409.1 109.38,69.87 v4(109,69.49) ; v2(100.18,5.13) 100.74,5.69 C249.1 ; C589.2 v2(42.79,25.29) ; C314.1 111.91,80.04 111.91,80.04 ; v4(85.9,73.43) 85.78,73.56 R554.2 C364.1 ; C392.2 93.45,70.51 v2(92.87,69.92) C426.2 ; v4(99.15,78.79) 99.17,78.82 C326.1 ; R1064.1 40.77,111.66 v2(40.79,111.68) ; C468.2 78.08,64.77 C444.2 80.68,66.22 v4(80.77,66.3) ; v2(95.81,44.15) 95.15,44.81 R623.2 ; C486.2 50.9,59.12 v2(50.9,57.98) ; R746.2 79.5,7.34 76.78,7.34 v3(76.59,7.53) ; C120.1 166.78,48.29 ; v2(153.67,15.24) 153.67,16.26 153.37,16.56 C585.2 152.86,16.35 152.86,15.19 v2(152.93,15.11) ; C359.2 46.21,78.09 46.84,78.71 47.88,78.71 48.46,78.13 v2(48.46,77.96) 48.48,77.94 C335.2 ; R584.2 104.7,59.85 v4(104.54,60.01) ; v2(63.75,112.55) R445.2 ; C549.1 58.17,34.24 ; Q10.2 113.79,48.95 v2(113.69,48.84) 113.39,48.84 112.98,48.44 C509.2 ; R553.2 91.42,75.01 v4(92.16,75.75) ; C639.1 45.31,4.54 v2(45.42,4.64) ; C363.2 84.86,75.39 v4(85.22,75.75) ; C568.2 35.47,32.64 v2(34.59,32.64) ; C300.1 C299.1 110.52,85.52 v4(110.01,86.03) ; v4(90.18,60.87) 90.22,60.82 C481.1 ; R690.2 v2(34.09,33.53) ; C404.1 97.18,70.11 C416.1 97.18,68.89 v4(97.55,68.53) ; C566.1 38.51,33.25 v2(38.54,33.28) C564.1 ; v2(147.07,92.33) 146.94,92.2 146.38,92.2 C925.1 ; C119.1 166.65,47.4 v2(167,47.04) ; v2(96.55,51.71) 96.6,51.66 R609.2 99.98,51.94 99.67,52.25 98.34,52.25 R605.1 ; v2(117.81,103.23) 118.36,103.78 C29.2 ; C390.2 90.81,70.51 v2(90.22,69.92) C424.2 ; v2(171.2,30.84) 171.2,30.73 171.02,30.56 U35.5 ; R645.2 97.21,38.25 97.43,38.48 v2(97.43,38.56) ; C459.2 v2(28.42,65.53) ; U33.12 v2(18.54,90.71) ; v2(29.36,74.76) 31.79,74.76 32.06,74.49 C369.2 C376.2 ; v3(197.09,56.61) C399.2 ; C499.2 113.8,53.74 v3(113.73,53.67) ; C274.2 100.23,103.53 v2(100.2,103.56) ; R1060.1 v2(43.05,111.68) ; v4(105.46,82.37) 105.08,81.99 C310.1 ; v3(173.1,71.64) 173.13,71.67 R556.1 ; v2(106.68,36.2) 106.25,35.77 C147.2 ; C263.2 105.03,110.67 105.03,109.56 104.9,109.44 v2(104.9,108.84) ; v3(203.09,61.61) U12.B15 ; C445.2 172.32,52.67 172.98,52.02 v3(173.15,52.02) ; v2(42.81,77.84) 42.01,77.04 C348.2 ; C305.1 105.11,83.72 v4(105.49,84.1) ; C492.1 96.75,57.41 97.66,58.32 v4(97.87,58.32) 97.99,58.19 97.99,57.34 C497.1 ; 163.03,5.95 CONN16.G4 ; CONN16.G4 163.03,7.83 ; CONN16.G4 163.97,6.89 ; v2(49.89,23.14) 49.89,22.53 C181.1 49.07,22.53 v2(49.07,23.14) ; C272.1 C273.1 v2(1.4,103.75) ; v3(188.09,62.61) U12.A1 ; C530.1 58.01,36.14 ; v4(97.55,85.99) 97.54,86 C297.1 ; v2(137.29,85.09) 137.54,85.09 137.92,84.71 138.56,84.71 C934.1 ; C41.2 161.34,114.93 v2(161.34,115.82) ; C441.2 101.59,66.58 v4(101.59,66.13) ; v2(100.79,71.5) 100.63,71.65 C380.1 ; v4(108.01,75.75) 108.66,76.4 C342.1 ; C516.2 174.42,22.35 v2(173.89,22.35) ; R417.2 18.71,121.32 18.41,121.62 v2(17.78,121.62) ; C315.1 112.85,79.99 ; v2(101.74,71.48) 101.58,71.64 C381.1 ; C543.2 v2(47.81,34.14) ; C476.2 80.11,62.18 C471.2 C470.2 ; R954.2 v2(173.54,18.6) ; C911.1 105.83,119.02 105.56,118.75 v2(105.28,118.75) ; C551.2 C552.2 v2(33.23,32.92) ; C551.2 v2(32.29,33) ; C551.2 C550.2 ; C278.2 v2(27.33,95.57) ; C362.1 104.1,74.78 v4(104.75,74.13) 104.92,73.96 C374.1 ; C421.2 v2(87.1,68.78) ; C520.2 40.53,38.55 v2(40.06,38.08) ; C592.2 v2(42.77,24.36) ; v2(174.83,37.26) 174.6,37.03 C514.2 ; C401.2 v2(86.61,70.54) ; C482.1 95.75,61.62 v4(96.12,62) ; C540.1 84.07,36.16 C538.2 ; v2(41.83,111.68) 41.78,111.63 R1062.1 ; U12.T16 v3(204.09,46.61) ; C438.2 v3(198.09,52.61) ; Q13.S 88.19,43.59 v2(88.47,43.31) ; v2(196.61,16.05) C567.2 C570.2 ; C487.2 54.52,59.34 v2(54.81,59.63) ; R377.1 69.07,6.87 v2(68.94,6.73) ; v4(113.23,60.53) 112.62,60.53 112.16,60.07 R586.2 ; R515.2 98.96,90.85 98.35,90.25 98.35,89.94 v4(97.84,89.43) ; v2(183.38,16.2) C604.2 C605.2 ; v2(100.28,70.03) 100.08,69.83 C415.1 ; C371.2 v2(29.36,73.95) ; R764.2 v2(39.39,5.61) ; v2(143.51,92.2) 143.76,92.46 C926.1 ; R615.2 103.81,47.32 v2(103.31,46.81) ; v2(203.66,6.1) 203.66,6.46 CONN15.8 ; R541.2 v2(168.48,82.02) ; v3(30.78,21.36) 31.32,20.83 R709.2 ; v4(105.54,81.71) 104.93,81.1 C317.1 ; v4(96.35,77.82) 95.97,78.2 C324.1 ; R152.1 v2(187.69,44.76) ; v4(80.27,75.75) 79.46,75.75 79.15,75.44 C360.2 78.03,75.01 77.32,74.3 C377.2 77.32,71.81 C400.2 C407.2 ; v2(103,24.26) 103,25.08 C145.2 ; C151.2 110.69,35.99 v2(110.11,36.58) ; C419.2 102.64,69.32 C406.1 102.07,69.81 101.45,70.43 v2(101.24,70.43) ; R800.2 v2(137.11,118.06) ; C240.1 v2(82.45,6.48) ; C571.2 157.92,70.52 v3(158.25,70.84) ; C347.2 40.84,78.39 39.13,80.1 v2(39.13,80.2) ; v2(36.79,27.59) R700.2 C588.1 ; C629.2 165.97,8.01 ; C429.2 86.77,67.79 v4(86.97,67.59) ; C396.2 173.48,70.21 173.76,70.48 v3(173.76,70.88) ; C464.2 172.69,63.15 v3(173.15,63.61) ; R527.1 v2(26.72,86.46) ; C158.2 v2(150.5,16.13) ; v4(89.19,64.3) 89.27,64.39 C460.2 ; v2(148.84,95.76) 148.84,95.12 C961.1 148.08,94.87 v2(148.08,95.76) ; C379.1 107.35,72.63 107.67,72.95 108.31,72.95 v4(108.5,73.15) ; C312.1 98.28,81.15 v4(98.34,81.21) ; C375.2 172.44,71.28 172.84,70.88 v3(173.1,70.88) ; R1082.1 C915.1 v2(179.25,21.66) ; v4(99.83,58.28) 99.83,57.09 R599.2 ; U32.2 62.4,113.83 v2(62.51,113.94) ; U12.R2 v3(189.09,47.61) ; U12.R15 v3(203.09,47.61) ; U12.G7 v3(194.09,55.61) ; C341.1 100.05,75.23 99.42,74.6 v2(99.06,74.6) 98.93,74.48 C361.1 ; v3(197.09,55.61) U12.G10 ; R948.1 v2(27.23,78.56) ; R1089.1 36.7,108.4 C964.1 35.76,109.4 v2(35.69,109.47) ; v2(31.8,77.44) 32.59,76.65 C339.2 ; C393.2 94.79,70.51 v2(94.21,69.92) C427.2 ; R745.1 v2(119.61,6.32) ; v4(107.06,67.77) 106.98,67.69 106.55,67.69 106.37,67.51 C457.2 ; R526.1 v2(25.76,86.44) ; v4(108.74,58.28) 107.31,56.85 106.33,56.85 105.69,57.48 R596.2 R595.2 ; C505.2 170.31,39.78 R612.1 171.07,39.67 171.42,40.02 v2(171.42,40.41) ; v2(171.45,41.45) 171.02,41.02 C507.2 ; C439.2 v2(28.42,67.06) ; U41.2 v2(23.63,57.53) ; v3(198.09,53.61) U12.K10 ; v2(68.38,58.75) 67.23,57.6 58.5,57.6 R593.1 58.72,58.08 58.72,66.88 58.22,67.39 C420.2 C405.2 C389.2 C373.2 C370.2 ; C386.1 97.34,71.2 C397.1 96.88,71.17 96.57,70.87 C394.2 96.12,70.51 v2(95.53,69.92) C428.2 ; v2(135,89.92) 134.24,89.15 R960.1 ; v4(104.72,75.73) 104.2,76.25 R548.2 R549.2 ; R694.1 157.9,69.6 v3(158.25,69.95) ; v2(49.28,57.94) 49.48,58.14 C489.1 49.6,59 C484.2 ; C313.1 110.97,80.01 110.97,80.01 ; C366.1 C367.1 88.8,73.69 v2(88.49,73.38) ; R458.2 v2(86.21,108.81) ; R630.1 113.16,44.45 R274.2 v2(114.25,43.71) 114.94,43.03 C515.1 ; R869.2 v2(197.1,24.05) ; C590.1 v2(194.77,8.1) ; v4(102.35,82.79) 101.55,82.79 C309.1 ; C343.2 54.49,77.54 v2(54.81,77.86) ; v4(80.77,78.32) 80.77,78.75 80.44,79.07 C328.2 ; C595.1 v2(62.13,22.58) ; v4(106.02,84.89) 105.94,84.96 C301.1 ; C609.2 159.82,14.33 ; v4(105.56,75.73) 105.01,76.28 C338.1 ; R679.2 v2(51.92,33.45) ; v2(137.67,92.33) 137.67,92.58 138.3,93.22 C936.1 ; U12.T1 v3(188.09,46.61) ; C61.2 v2(181.74,82.42) ; C382.1 v2(87.83,72.52) ; v4(87.2,71.75) C387.2 C378.2 ; v2(25.83,53.64) 26.28,54.1 Q8.S ; C267.2 v2(24.66,110.19) ; C319.2 v2(174.62,81.33) ; R157.1 184.1,81.93 v2(184.55,82.39) ; C318.2 171.43,79.91 v2(170.75,79.91) ; C613.1 v2(30.76,12.45) ; v4(98.35,65.34) 98.05,65.34 C449.2 97.69,66.12 v4(98.35,66.12) ; v2(108.84,36.58) 108.41,36.15 C150.2 ; R555.1 143.51,69.8 v3(143.54,69.83) ; v2(79.6,15.09) 80.47,15.09 C209.2 81.2,14.35 v2(81.2,13.34) ; C648.2 v2(169.24,107.5) ; v2(156.46,15.24) 156.59,15.37 156.59,16.26 156.29,16.56 C591.2 155.75,16.56 155.45,16.26 v2(155.45,15.24) ; v3(195.09,52.61) C452.2 ; R558.1 130.43,71.96 v3(130.46,71.93) ; C146.2 v2(103.12,35.69) ; v2(206.62,12.57) CONN15.G1 ; v2(9.25,91.49) 9.31,91.56 BA1.1 v2(14.35,91.56) ; C269.2 v2(24.66,109.25) ; U36.4 v2(93.93,43.81) ; R1071.1 R1072.1 30.54,81.73 v2(31.76,82.95) ; C467.2 v2(28.42,64.19) ; v2(104.29,49.91) 103.47,50.73 R787.1 ; R1045.1 v2(160.02,118.36) ; R1058.1 44.32,111.48 v2(44.53,111.68) ; C525.1 58.12,37.08 ; v2(43.76,37.99) 43.2,38.55 C521.2 ; v3(173.81,64.37) 173.81,64.82 173.61,65.03 R573.1 ; Q11.S 28.02,50.47 v2(28.27,50.72) ; C575.2 C574.2 v2(35.84,29.47) ; C260.2 v2(52.18,122.89) ; C143.2 v2(104.55,35.71) ; R720.2 C607.1 87.32,15.03 87.84,14.52 87.84,11.51 v2(85.88,9.55) ; C634.2 165.97,6.13 ; R632.1 106.09,44.15 105.84,44.4 v2(105.46,44.4) ; v2(53.98,2.41) 54.41,2.84 R755.2 ; C344.2 55.49,77.02 v2(55.49,77.87) ; v4(107.75,58.28) 107.48,58.55 R785.2 ; v2(157.84,115.93) 157.99,115.77 C275.2 ; v2(108.17,23.21) 108.13,23.25 C149.2 ; C611.1 161.69,14.33 ; v3(189.09,61.61) U12.B2 ; R492.1 v2(24.28,100.1) ; C316.1 113.84,79.99 ; v3(197.09,52.61) C453.2 ; C631.2 165.97,7.07 ; C637.2 v2(17.24,4.75)
  BOTTOM w0.508: C945.1 v2(140.15,86.31) ; C944.1 144.98,84.25 v2(145.67,83.57) ; C941.1 v2(138.3,87.25) ; v2(144.4,87.63) 144.98,87.63 C942.1 ; v2(141.42,92.4) C930.1 141.42,94 C927.1 ; C928.1 v2(140.97,86.21) ; C939.1 v2(144.02,90.68) ; C931.1 v2(137.37,88.08) ; v2(137.29,86.11) 136.6,85.42 C935.1 ; C938.1 v2(144.02,89.66) ; C933.1 v2(141.99,86.18)
  vias: v1(46.28,11.99) v2(0.58,122.91) v2(0.58,120.55) v2(0.61,118.03) v2(0.61,115.67) v2(0.61,112.04) v2(0.61,108.99) v2(0.61,105.49) v2(0.64,102.41) v2(0.61,99.42) v2(0.64,95.94) v2(0.58,92.96) v2(0.61,89.46) v2(0.64,86.94) v2(0.58,83.92) v2(0.61,81.66) v2(0.64,78.64) v2(0.64,75.77) v2(0.64,73) v2(0.61,69.82) v2(0.64,65.46) v2(0.58,62.92) v2(0.61,59.05) v2(0.58,56.06) v2(0.61,52.81) v2(0.61,50.09) v2(0.61,46.86) v2(0.61,43.89) v2(0.64,40.59) v2(0.64,36.7) v2(0.61,33.55) v2(0.61,29.44) v2(0.61,25.55) v2(0.61,21.44) v2(0.58,18.39) v2(0.61,14.22) v2(0.61,11.35) v2(0.64,7.98) v2(0.61,4.39) v2(0.58,0.56) v2(3.17,122.91) v2(4.14,0.61) v2(6.1,122.91) v2(7.72,0.61) v2(9.33,92.49) v2(9.75,122.94) v2(10.87,0.58) v2(12.55,122.91) v2(13.9,92.65) v2(14.73,0.58) v2(15.75,122.94) v2(18.06,0.58) v2(18.62,122.94) v2(20.65,122.91) v2(21.84,0.61) v2(22.38,105.56) v2(22.38,102.51) v2(22.38,101.5) v2(23.39,105.56) v2(23.5,33.5) v2(24.41,105.56) v2(24.51,33.5) v2(24.56,38.25) v2(24.59,0.64) v2(25.43,105.56) v2(26.34,122.94) v2(26.44,105.56) v2(27.46,105.56) v2(27.81,0.61) v2(28.3,37.77) v2(28.3,36.75) v2(28.3,35.74) v2(28.3,34.72) v2(28.3,33.71) v2(28.55,24.56) v2(28.96,23.55) v2(29.44,122.91) v2(29.51,24.56) v2(29.92,23.55) v2(30.48,24.56) v2(30.89,23.55) v2(30.91,0.61) v2(31.83,25.17) v2(32.79,25.17) v2(33.15,122.94) v2(33.76,25.17) v2(34.54,31.83) v2(35.37,55.97) v2(35.42,54.8) v2(35.4,49.77) v2(35.71,58.43) v2(35.76,122.94) v2(36.14,0.58) v2(36.31,97.45) v2(36.67,81.7) v2(36.71,43.22) v2(36.95,96.05) v2(37.03,85.28) v2(37.23,93.18) v2(37.38,57.52) v2(37.5,50.51) v2(37.58,99.63) v2(37.99,100.98) v2(38.62,47.74) v2(38.7,82.87) v2(38.67,53.67) v2(38.88,93.18) v2(39.12,122.94) v2(39.15,45.16) v2(39.67,0.58) v2(42.11,12.75) v2(42.52,122.94) v2(42.85,0.58) v2(43,12.75) v2(43.89,12.75) v2(44.93,24.21) v2(44.86,12.75) v2(44.96,122.94) v2(45.06,23.34) v2(45.34,108.28) v2(45.36,106.73) v2(45.36,25.15) v2(45.54,0.61) v2(45.8,23.34) v2(45.82,12.78) v2(45.87,24.21) v2(46.3,25.15) v2(46.71,23.37) v2(46.74,22.45) v2(46.74,12.78) v2(46.81,24.21) v2(47.24,25.15) v2(47.58,86.91) v2(47.75,24.21) v2(47.8,23.37) v2(47.83,22.45) v2(48.09,85.31) v2(48.18,25.15) v2(48.44,122.94) v2(48.79,24.21) v2(49.04,48.63) v2(49.12,0.66) v2(49.23,25.15) v2(49.73,24.21) v2(49.96,80.71) v2(50.16,25.15) v2(50.72,88.69) v2(50.7,24.21) v2(50.78,85.34) v2(50.83,53.35) v2(50.97,93.31) v2(51.13,25.15) v2(51.69,24.21) v2(51.89,0.61) v2(52.12,25.15) v2(53.06,25.17) v2(55.07,122.94) v2(55.47,0.58) v2(57.43,17.45) v2(57.86,122.94) v2(59.13,18.34) v2(59.16,0.61) v2(61.7,122.94) v2(61.75,0.64) v2(65.71,122.91) v2(65.89,0.64) v2(67.44,16.38) v2(69.04,0.64) v2(69.39,122.89) v2(69.7,40.01) v2(70.1,39.37) v2(70.48,43.23) v2(70.51,42.42) v2(70.48,39.98) v2(70.56,51.51) v2(71.22,43.26) v2(71.22,39.98) v2(71.35,51.51) v2(71.93,40.01) v2(72.01,43.23) v2(72.14,122.89) v2(72.16,51.51) v2(72.69,39.98) v2(72.85,42.8) v2(72.92,0.64) v2(73.3,39.42) v2(73.41,43.33) v2(73.61,40.16) v2(73.89,42.8) v2(74.4,43.31) v2(75.16,43.28) v2(75.64,122.94) v2(76.1,43.28) v2(76.53,0.64) v2(76.94,43.28) v2(77.42,25.12) v2(77.67,43.79) v2(78.18,25.15) v2(78.79,122.91) v2(78.94,25.17) v2(79.02,38.66) v2(79.5,39.32) v2(79.58,0.61) v2(79.78,25.17) v2(79.88,38.66) v2(80.39,39.32) v2(80.59,25.17) v2(81.41,25.17) v2(82.3,25.2) v2(82.75,122.91) v2(83.44,0.58) v2(84.1,42.8) v2(85.5,114.38) v2(85.78,122.94) v2(86.16,0.61) v2(88.14,46.76) v2(89.08,122.91) v2(90.22,0.58) v2(91.8,122.91) v2(94.21,0.58) v2(95.78,122.91) v2(96.93,0.58) v2(99.85,122.89) v2(99.83,23.23) v2(99.92,22.15) v2(100.23,0.56) v2(100.84,23.34) v2(101.14,22.25) v2(102.08,23.16) v2(102.17,24.32) v2(102.46,21.95) v2(102.57,122.91) v2(103.25,0.58) v2(103.38,23.24) v2(104.16,24.27) v2(104.6,21.62) v2(104.93,22.63) v2(105.28,23.75) v2(105.99,21.93) v2(106.43,122.89) v2(106.38,97.54) v2(107.21,0.58) v2(107.52,22.48) v2(108.1,97.54) v2(109.27,100.05) v2(109.27,95.78) v2(109.47,122.86) v2(110.36,0.56) v2(111.05,100.05) v2(111.05,95.78) v2(111,40.54) v2(112.9,13.23) v2(113.08,122.86) v2(113.54,22.48) v2(113.87,0.61) v2(115.32,83.69) v2(115.98,79.81) v2(116.26,77.98) v2(116.61,102.59) v2(116.61,0.61) v2(116.97,122.86) v2(117.25,64.9) v2(117.42,102.59) v2(117.37,62.74) v2(117.53,66.93) v2(118.31,42.01) v2(118.52,42.98) v2(120.12,122.86) v2(120.29,0.58) v2(122.35,114.21) v2(122.32,113.27) v2(124.26,122.86) v2(124.31,0.56) v2(125.85,112.56) v2(126.85,122.89) v2(128.14,0.56) v2(128.4,65.1) v2(129.56,65.07) v2(130.53,122.91) v2(131.75,80.29) v2(132.95,101.31) v2(134.11,122.89) v2(136.88,122.91) v2(138.43,54.2) v2(138.46,57.99) v2(138.46,51.56) v2(138.48,50.77) v2(138.58,90.75) v2(138.61,89.94) v2(138.58,89.1) v2(139.57,90.93) v2(140.11,54.25) v2(140.18,58.32) v2(140.68,122.91) v2(141.25,59.21) v2(141.5,90.93) v2(141.81,54.18) v2(142.88,59.16) v2(144.12,72.44) v2(144.27,58.9) v2(144.77,122.9) v2(145.54,37.8) v2(146.74,59.51) v2(147.22,87.36) v2(147.22,86.11) v2(147.4,37.8) v2(148.02,122.91) v2(148.34,37.74) v2(148.87,59.56) v2(149.48,37.9) v2(150.47,37.92) v2(151.1,59.39) v2(151.84,122.89) v2(152.17,66.07) v2(152.35,59.28) v2(153.08,66.97) v2(153.42,89.15) v2(153.42,88.14) v2(153.62,59.23) v2(154.08,67.13) v2(154.94,67.06) v2(155.09,122.89) v2(155.24,59.59) v2(158.19,122.91) v2(158.19,73.43) v2(158.19,72.19) v2(159.21,73.38) v2(159.18,68.3) v2(159.26,72.21) v2(159.66,0.56) v2(161.8,122.89) v2(162.26,0.58) v2(163.25,8.29) v2(164.06,8.32) v2(164.16,122.91) v2(164.44,14.1) v2(164.44,13.16) v2(165.25,14.1) v2(165.25,13.16) v2(165.35,0.58) v2(165.51,38.68) v2(165.56,37.87) v2(165.71,42.11) v2(166.29,50.09) v2(166.42,109.98) v2(166.78,42.82) v2(167.06,34.85) v2(167.39,122.89) v2(167.36,31.93) v2(167.39,0.56) v2(167.94,42.75) v2(168.28,47.04) v2(168.38,48.64) v2(168.5,31.9) v2(169.8,31.93) v2(170.15,46.99) v2(170.26,0.56) v2(171.27,122.91) v2(172.64,97.38) v2(172.64,96.55) v2(172.62,95.71) v2(172.64,94.82) v2(173.46,0.58) v2(174.14,86.41) v2(174.43,93.82) v2(174.93,86.41) v2(175.13,122.91) v2(176.25,0.56) v2(177.42,103.91) v2(178.23,103.91) v2(178.28,122.89) v2(179.07,103.89) v2(179.93,103.89) v2(179.91,0.58) v2(182.02,87.16) v2(182.02,85.38) v2(182.83,0.58) v2(184.43,122.81) v2(185.42,0.58) v2(186.22,85.38) v2(188.68,116.35) v2(188.93,113.7) v2(188.93,112.99) v2(189.05,122.86) v2(189.11,0.57) v2(189.57,116.34) v2(189.7,113.7) v2(189.7,112.99) v2(191.43,122.92) v2(193.17,0.57) v2(194.66,120.81) v2(194.86,122.92) v2(196.44,120.81) v2(196.82,0.59) v2(198.54,122.92) v2(200.89,0.57) v2(202.1,122.91) v2(203.91,77.57) v2(203.98,0.57) v2(205.69,12.93) v2(206.2,91.3) v2(206.2,90.46) v2(206.43,122.91) v2(206.63,113.56) v2(207.84,112.18) v2(208.32,0.69) v2(208.38,111.55) v2(208.7,118.87) v2(208.7,116.33) v2(208.75,110.76) v2(208.7,106.17) v2(208.7,103.63) v2(208.7,101.09) v2(208.7,96.01) v2(208.7,93.47) v2(208.7,90.93) v2(208.7,88.39) v2(208.7,85.85) v2(208.7,83.31) v2(208.7,80.77) v2(208.7,74.17) v2(208.7,69.09) v2(208.7,66.55) v2(208.7,64.01) v2(208.7,61.47) v2(208.7,58.93) v2(208.7,56.39) v2(208.7,53.85) v2(208.7,51.31) v2(208.7,48.77) v2(208.7,46.23) v2(208.7,43.69) v2(208.7,41.15) v2(208.7,38.61) v2(208.7,36.07) v2(208.7,33.53) v2(208.7,30.99) v2(208.7,28.45) v2(208.7,25.91) v2(208.7,23.37) v2(208.7,20.83) v2(208.7,18.29) v2(208.7,15.75) v2(208.7,13.21) v2(208.7,10.67) v2(208.7,8.13) v2(208.7,5.59) v2(208.7,3.05) v2(209.05,121.07) v2(209.43,122.91) v3(26.57,73.02) v3(26.57,71.24) v3(27.21,76.89) v3(27.21,75.12) v3(29.87,22.25) v3(29.87,21.36) v3(33.75,7.06) v3(35.53,7.06) v3(41.83,29.08) v3(55.95,22.75) v3(55.95,21.84) v3(56.86,6.74) v3(56.86,5.96) v3(56.86,5.17) v3(56.95,22.74) v3(57.64,7.53) v3(57.64,6.74) v3(57.64,5.96) v3(57.64,5.17) v3(58.43,7.53) v3(58.43,6.74) v3(58.43,5.96) v3(58.43,5.17) v3(59.22,7.53) v3(59.22,6.74) v3(59.22,5.96) v3(59.22,5.17) v3(67.84,75.37) v3(67.93,89.52) v3(68.3,82.46) v3(68.5,21.59) v3(69.18,85.87) v3(69.44,21.13) v3(69.47,22.05) v3(70.05,88.9) v3(70.15,22.05) v3(70.15,21.13) v3(70.28,75.37) v3(70.28,59.68) v3(70.59,82.46) v3(70.61,79.22) v3(71.12,77.15) v3(71.15,22.05) v3(71.17,21.13) v3(71.47,85.92) v3(71.6,80.51) v3(71.7,88.99) v3(71.7,19.18) v3(72.19,22.05) v3(72.8,19.18) v3(72.88,82.44) v3(72.88,51.51) v3(72.97,89) v3(73.05,80.53) v3(73.28,75.37) v3(73.28,59.68) v3(73.43,77.15) v3(73.79,79.18) v3(73.86,85.84) v3(74.11,84.09) v3(74.23,9.89) v3(74.23,9.11) v3(74.23,8.32) v3(74.23,7.53) v3(74.32,53.71) v3(74.7,97.03) v3(74.91,88.97) v3(75.02,9.89) v3(75.02,9.11) v3(75.02,8.32) v3(75.02,7.53) v3(75.18,82.48) v3(75.41,80.49) v3(75.56,75.37) v3(75.74,77.12) v3(75.82,95.76) v3(75.81,9.89) v3(75.81,9.11) v3(75.81,8.32) v3(75.81,7.53) v3(76.07,51.22) v3(76.5,95.89) v3(76.59,9.89) v3(76.59,9.11) v3(76.59,8.32) v3(76.73,53.63) v3(76.9,55.93) v3(77.22,50.54) v3(77.99,92.83) v3(78.1,94.17) v3(79.13,93.05) v3(79.43,98.17) v3(79.65,95.79) v3(80.38,48.66) v3(81.07,96.73) v3(81.92,50.2) v3(82.23,93.3) v3(82.61,94.93) v3(82.75,53.33) v3(82.88,21.79) v3(83.79,54.45) v3(83.85,22.25) v3(83.82,21.33) v3(84.06,52.34) v3(84.51,95.63) v3(84.53,22.25) v3(84.53,21.33) v3(84.63,50.5) v3(85.5,93.66) v3(85.52,22.25) v3(85.55,21.33) v3(85.67,53.95) v3(86.14,50.5) v3(86.08,19.38) v3(86.56,22.25) v3(86.77,52.63) v3(87.17,19.38) v3(87.3,54.7) v3(88.28,52.63) v3(88.94,54.7) v3(89.46,51.27) v3(90.52,52.41) v3(90.77,54.62) v3(96.55,53.92) v3(101.75,93.42) v3(102.69,106.1) v3(102.69,104.32) v3(102.69,103.56) v3(102.69,101.78) v3(107.01,106.1) v3(107.01,104.32) v3(107.01,103.56) v3(107.01,101.78) v3(113.73,54.41) v3(114.38,95.15) v3(114.38,93.38) v3(115.23,91.84) v3(115.44,88.27) v3(115.57,86.87) v3(115.77,19.94) v3(116.71,20.35) v3(116.71,19.61) v3(117.01,91.84) v3(117.09,76.57) v3(117.09,74.8) v3(117.42,20.35) v3(117.45,19.58) v3(118.44,20.35) v3(118.47,19.58) v3(118.87,80) v3(118.87,78.22) v3(118.87,76.45) v3(118.97,17.52) v3(119.46,20.35) v3(120.07,89.03) v3(120.12,86.89) v3(120.07,17.52) v3(123.7,74.67) v3(123.7,72.89) v3(125.22,111.12) v3(125.22,110.24) v3(126.14,111.12) v3(126.14,110.24) v3(127.75,94.23) v3(128.58,3.78) v3(128.78,88.37) v3(129.52,71.93) v3(129.64,94.23) v3(130.48,18.08) v3(130.56,4.7) v3(131.16,3.78) v3(132.08,88.37) v3(132.26,18.08) v3(132.56,3.78) v3(132.94,116.56) v3(132.94,114.96) v3(133.14,4.7) v3(134.56,4.7) v3(134.87,14.22) v3(135.14,3.78) v3(136.65,14.22) v3(137.14,4.7) v3(137.08,3.81) v3(139.62,3.81) v3(139.9,89.71) v3(139.9,88.77) v3(139.9,87.83) v3(140.84,89.71) v3(140.84,88.77) v3(140.84,87.83) v3(140.92,13.39) v3(141.37,20.35) v3(141.78,89.71) v3(141.78,88.77) v3(141.78,87.83) v3(142.69,13.39) v3(143.15,20.35) v3(143.41,4.78) v3(143.46,12.14) v3(144.02,20.22) v3(145.24,12.14) v3(145.3,4.78) v3(145.46,15.88) v3(145.79,20.22) v3(146.68,18.21) v3(147.24,15.88) v3(147.46,13.46) v3(148.46,18.21) v3(149.06,4.7) v3(149.24,13.46) v3(149.3,82.46) v3(149.61,10.58) v3(150.55,12.8) v3(151.06,3.8) v3(151.18,82.46) v3(151.5,10.58) v3(151.64,4.7) v3(151.79,38.96) v3(151.79,38.05) v3(152.28,10.83) v3(152.53,12.78) v3(152.68,38.05) v3(153.06,4.7) v3(153.64,3.8) v3(153.95,14.45) v3(154.16,10.83) v3(155.64,4.7) v3(155.73,14.45) v3(159.16,70.84) v3(159.16,69.95) v3(168.28,34.12) v3(168.28,33.24) v3(169.19,34.12) v3(169.19,33.24) v3(173.76,71.64) v3(173.81,63.61) v3(173.81,52.78) v3(173.81,52.02) v3(174.52,71.64) v3(174.52,70.88) v3(174.57,64.37) v3(174.57,63.61) v3(174.57,52.78) v3(174.57,52.02) v3(175.28,71.64) v3(175.28,70.88) v3(175.33,64.37) v3(175.33,63.61) v3(175.33,52.78) v3(175.33,52.02) v3(176.04,71.64) v3(176.04,70.88) v3(176.1,64.37) v3(176.1,63.61) v3(176.1,52.78) v3(176.1,52.02) v3(176.71,71.64) v3(176.71,70.88) v3(176.76,64.37) v3(176.76,63.61) v3(176.76,52.78) v3(176.76,52.02) v4(81.02,58.28) v4(82.01,58.28) v4(82.75,80.04) v4(83,58.28) v4(83.24,59.15) v4(83.99,58.28) v4(84.23,72.31) v4(84.23,70.6) v4(84.73,76.61) v4(84.73,73.17) v4(84.73,71.45) v4(84.98,58.28) v4(85.72,65.16) v4(85.72,61.73) v4(85.97,58.28) v4(86.21,75.74) v4(86.21,64.3) v4(86.21,62.58) v4(86.21,59.15) v4(86.71,65.16) v4(86.71,63.44) v4(86.96,58.28) v4(87.2,75.75) v4(87.25,71.07) v4(87.2,64.3) v4(87.86,67.46) v4(87.93,58.32) v4(88.2,75.75) v4(88.94,58.28) v4(89.19,75.75) v4(89.93,58.28) v4(90.18,75.75) v4(91.91,58.28) v4(95.77,77.37) v4(106.01,79.79)
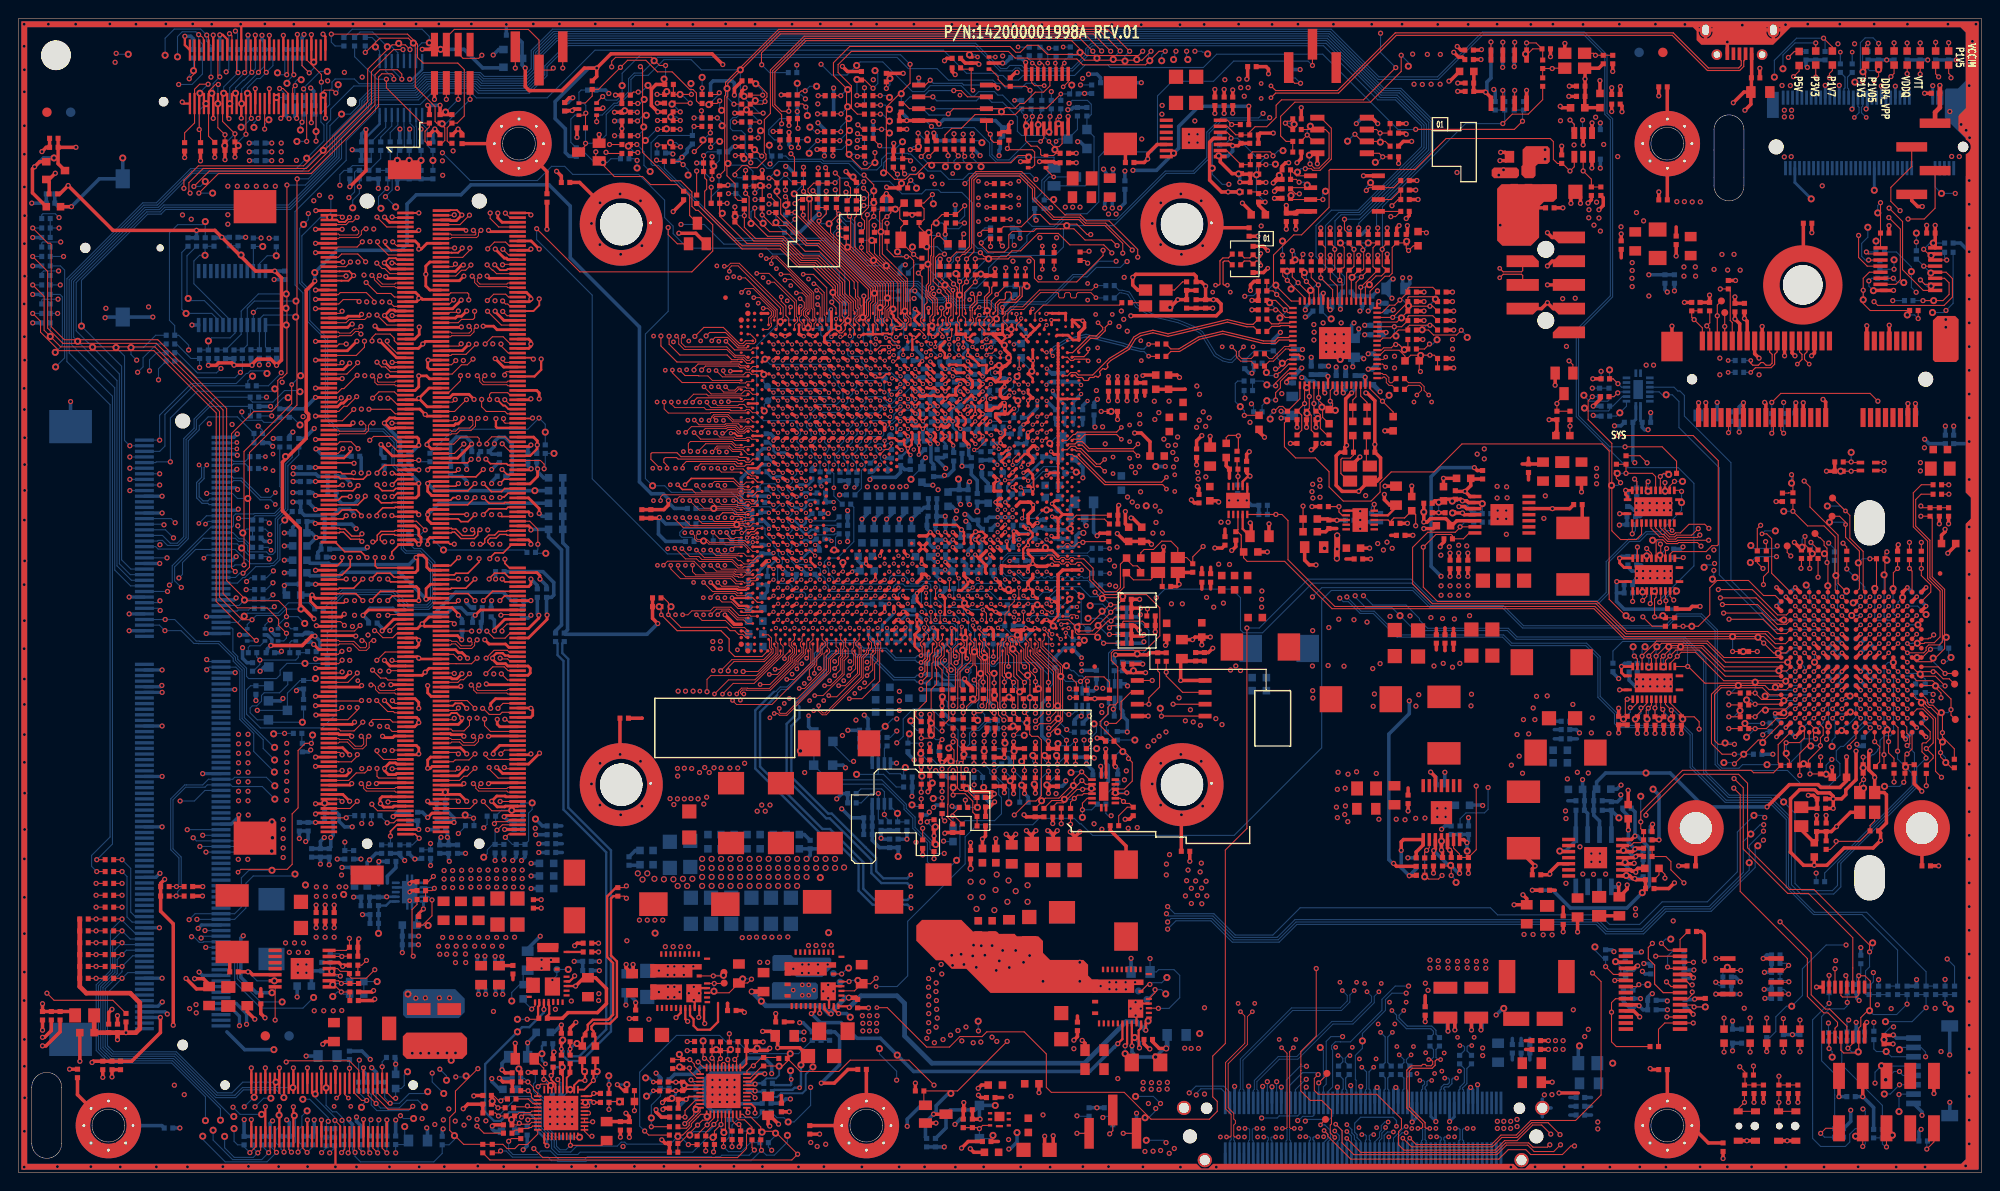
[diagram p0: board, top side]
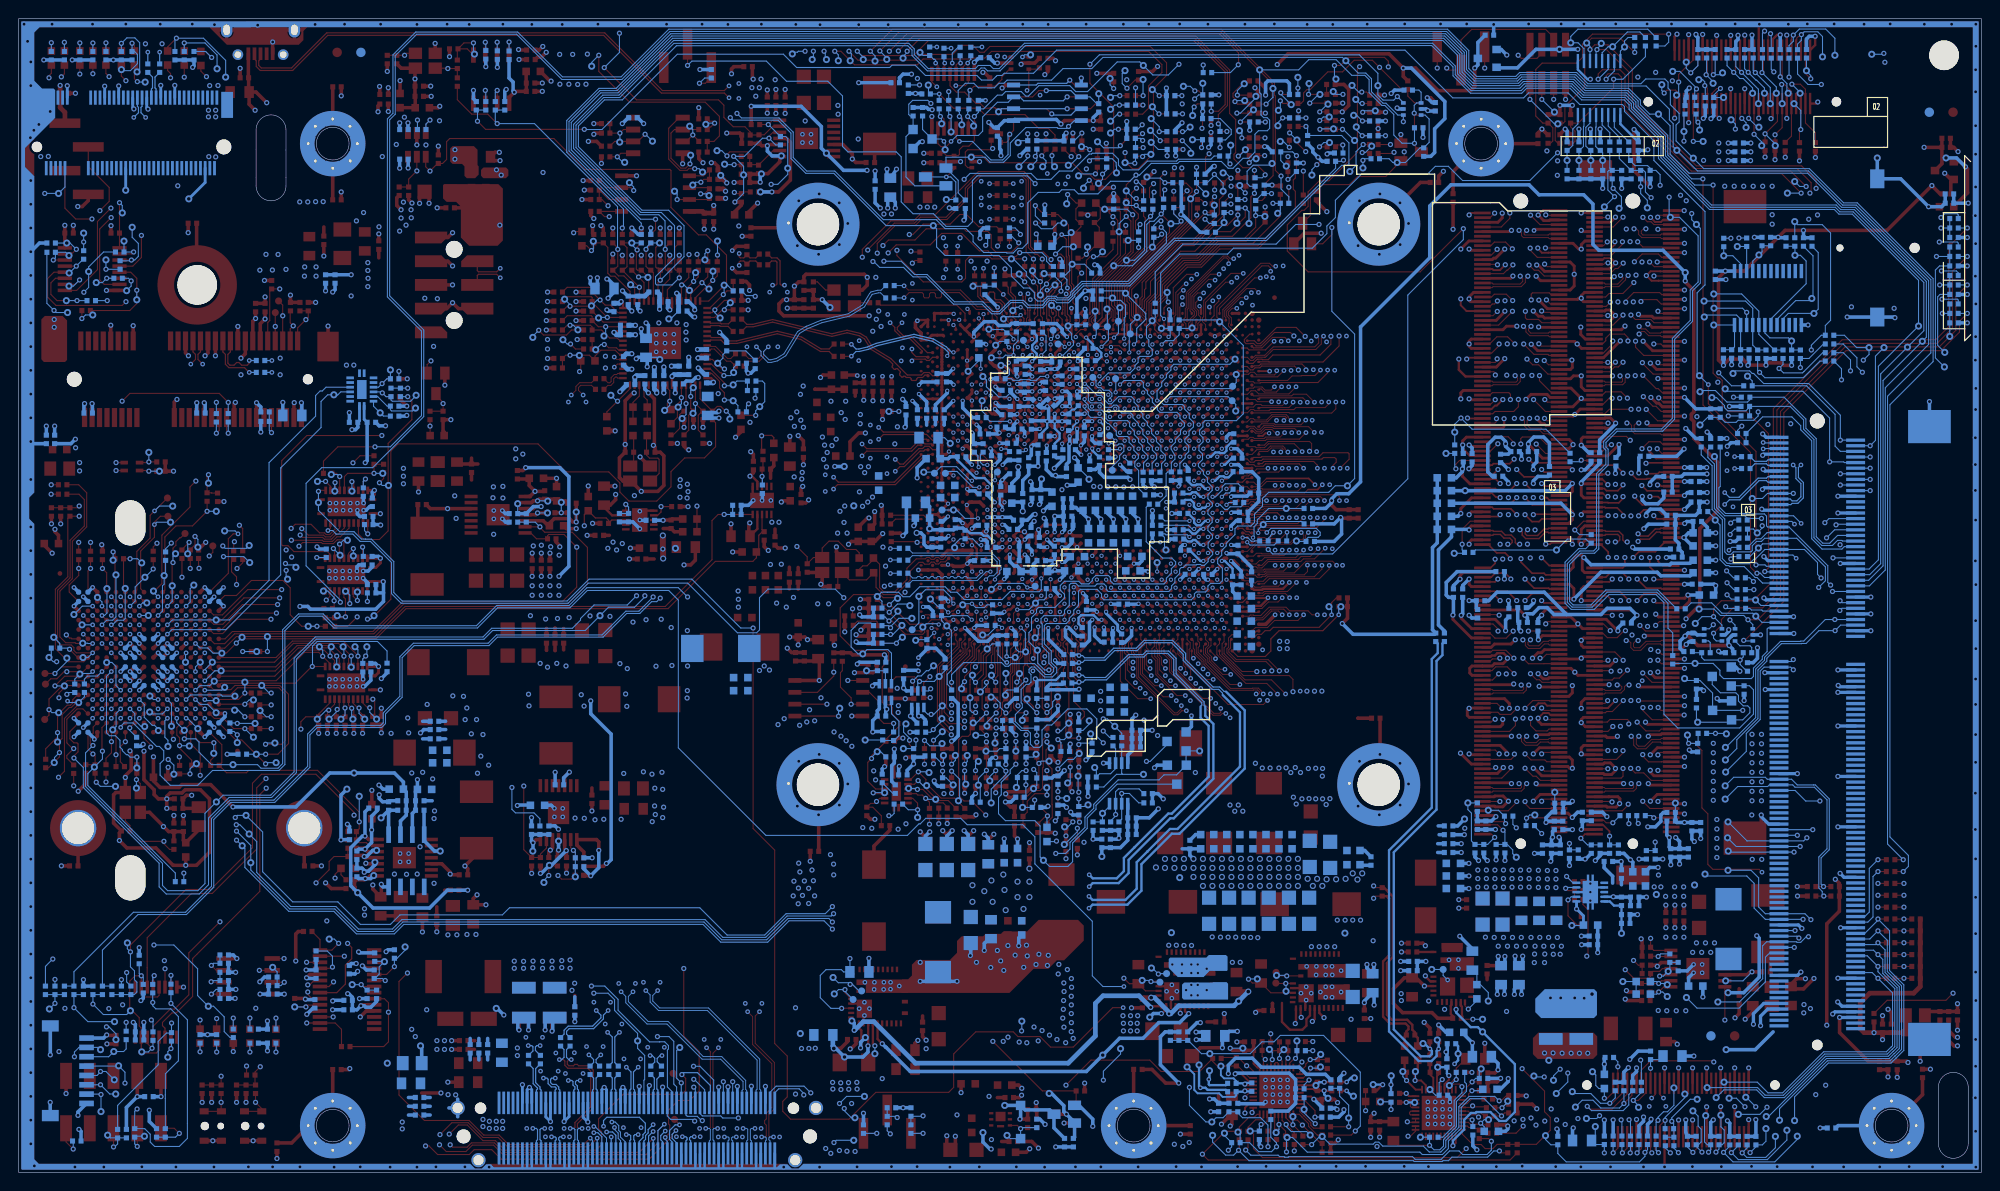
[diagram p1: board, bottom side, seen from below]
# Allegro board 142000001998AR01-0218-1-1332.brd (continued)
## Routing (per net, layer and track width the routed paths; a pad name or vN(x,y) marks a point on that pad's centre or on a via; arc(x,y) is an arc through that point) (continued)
GND_SCREW1: length 7.5
  TOP w0.381: C234.1 6.29,8.31 H7.8 7.8,6.8
  BOTTOM w0.381: 12.14,5 H7.3 15.32,5 C637.1
GND_SCREW2: length 7
  TOP w0.381: C36.1 H2.5 176.4,107.58 ; C3.1 176.4,112.66
GND_SCREW3: length 7.7
  TOP w0.381: C228.1 H8.1 176.4,7.54 ; 178.94,5 180.79,3.15 C257.1
GND_SCREW4: length 7.6
  TOP w0.381: 50.98,110.12 H1.7 C15.1 ; C35.1 56.52,107.12 H1.4 55.32,108.33
GND_SCREW5: length 7
  TOP w0.381: C253.1 H9.7 88.16,5 ; 90.7,7.54 H9.1 C227.1
P0V6_VTT: length 10.1
  TOP w0.305: v2(42.81,36.7) CONN7.258 ; v2(51.99,36.7) CONN8.258
  BOTTOM w0.381: v2(51.99,36.7) C523.1 C524.1 ; 39.45,30.96 39.45,31.7 40.36,32.61 C564.2 ; v2(42.81,36.7) 42.69,36.82 C521.1 C520.1 ; C566.2 38.51,30.78
  vias: v1(34.77,29.74) v2(34.29,30.56) v2(35,30.56)
P0V9_A_L_I210: length 12.6
  TOP w0.254: v2(135.66,84.58) 135.66,84.77 135.92,85.02 U6.32 ; U6.42 141.59,83.58 v2(141.73,83.44) ; U6.59 146.2,90.02 v2(146.3,89.92) ; v2(139.75,83.44) 139.75,83.52 139.59,83.67 U6.38 ; U6.11 v2(139.59,94.11)
  BOTTOM w0.127: C937.2 140.23,91.36 v1(140.44,91.36)
  BOTTOM w0.381: v2(139.75,83.44) 139.77,83.46 C934.2
  BOTTOM w0.508: C939.2 C938.2 146.05,89.66 v2(146.3,89.92) ; C933.2 141.99,83.85 141.73,83.59 v2(141.73,83.44) ; C935.2 135.73,84.51 v2(135.66,84.58) ; v2(139.59,94.11) 139.39,93.91 C936.2 C937.2
  vias: v2(135.15,83.36)
P1V2_VDD_BOOST: length 2.4
  TOP w0.114: v2(54.89,17.48) 55.25,17.83 QFN1.17
  BOTTOM w0.114: R710.2 53.98,18.39 v2(54.89,17.48)
P1V2_VDD_BOOST_R: length 4.2
  BOTTOM w0.114: C594.2 53.98,21.16 R710.1 53.59,20.09 52.76,19.25 v1(52.76,18.34)
P1V2_VDDQ: length 283.8
  TOP w0.127: U9.CP58 79.05,65.97 78.61,65.53 78.11,65.53 U9.CU59 ; U9.CU39 78.14,74.3 78.64,74.3 79.05,73.89 U9.CP40 ; v3(74.8,70.08) 75.34,70.61 76.45,70.61 76.64,70.42 U9.CU48 ; U9.CU67 78.54,61.51 79.04,61.02 U9.CP68 ; U9.CU63 78.16,63.6 78.66,63.6 79.05,63.99 U9.CP62 ; U9.CU52 78.2,68.44 78.33,68.58 78.68,68.58 79.04,68.94 U9.CP51 ; U9.CU43 78.55,72.4 79.04,72.9 U9.CP42
  TOP w0.203: v3(76.33,61.51) 76.35,61.47 78.01,61.47 U9.CU67
  TOP w0.254: U9.CU65 77.98,62.5 77.84,62.36 76.95,62.36 76.85,62.46 74.73,62.46 v3(74.04,63.15) ; U9.CT55 U9.CP55 ; v3(76.33,61.51) 76.31,61.42 77.09,60.64 77.93,60.64 U9.CU69
  TOP w0.305: v2(31.76,73.95) CONN7.117 ; CONN7.142 42.34,67.7 v2(42.81,67.24) 43.05,67.48 43.05,67.94 42.81,68.19 42.81,68.83 42.43,69.2 CONN7.136 ; CONN8.124 54.54,72.2 55.7,71.05 v2(55.7,70.53) ; v2(54.81,61.21) 54.8,61.2 CONN8.160 ; v2(54.81,70.41) 54.81,70.46 54.57,70.7 CONN8.130 ; CONN8.129 44,70.95 43.76,70.71 v2(43.76,70.41) 43.76,69.85 44.16,69.45 CONN8.135 ; v2(31.76,70.95) CONN7.129 ; v2(42.81,70.41) 42.81,70.46 42.57,70.7 CONN7.130 ; CONN8.117 43.98,73.95 v2(43.76,73.74) 43.76,72.9 44.19,72.47 44.19,72.45 CONN8.123 ; CONN7.154 42.53,62.7 42.81,62.43 v2(42.81,61.21) 42.81,61.2 42.8,61.2 CONN7.160 ; CONN7.118 42.77,73.7 v2(42.81,73.74) 42.81,72.5 42.51,72.2 CONN7.124 ; v2(31.76,75.45) CONN7.111 ; v2(43.76,75.2) 44.01,75.45 CONN8.111 ; v2(55.52,75.3) 55.52,74.51 54.71,73.7 CONN8.118 ; CONN8.136 54.57,69.2 54.81,68.97 v2(54.81,68.77) ; v2(54.81,63.51) 54.81,62.94 54.57,62.7 CONN8.154 ; CONN8.141 44,67.95 43.76,67.71 v2(43.76,67.24) ; v2(31.74,69.46) 31.74,69.45 CONN7.135 ; CONN8.147 44,64.45 43.67,64.79 43.67,65.65 43.26,66.07 42.78,66.07 v2(42.53,65.82) 42.7,65.65 42.7,64.47 42.44,64.2 CONN7.148 ; v2(31.76,62.95) CONN7.153 ; CONN7.163 31.91,60.45 31.23,61.13 31.23,61.64 v2(31.39,61.8) 31.74,61.46 CONN7.159 ; CONN7.112 v2(42.81,75.2) ; CONN8.153 44.05,62.95 43.59,62.49 v2(43.59,61.36) 43.81,61.36 43.9,61.45 CONN8.159 ; CONN7.141 v2(31.83,67.95) ; v2(47.05,59.64) 47.05,59.76 46.35,60.45 CONN8.163 ; CONN8.112 54.72,75.2 v2(54.83,75.31) ; v2(31.76,72.45) CONN7.123 ; v2(55.78,63.51) 55.78,63.51 55.78,63.87 55.45,64.2 CONN8.148 ; v2(31.76,64.45) CONN7.147 ; CONN8.142 54.55,67.7 54.81,67.44 v2(54.81,67.24)
  TOP w0.356: U9.CH49 v4(82.75,69.74) ; U9.CG43 v4(83.24,72.31) ; v4(82.75,66.3) U9.CH56 ; U9.CG58 v4(83.24,65.45) ; U9.CL35 v4(81.26,75.75) ; U9.CG51 v4(83.24,68.88) ; U9.CH37 v4(82.75,74.89) ; U9.CH41 v4(82.75,73.17) ; U9.CH33 v4(82.75,76.61) ; U9.CK52 v4(81.76,68.02) ; U9.CJ39 v4(82.25,74.03) ; U9.CG54 v4(83.24,67.16) ; U9.CH45 v4(82.75,71.45) ; U9.CF60 v4(83.74,64.59)
  TOP w0.381: R350.1 59,15.44 v2(59.61,16.05) ; U9.CP60 80,65.45 v4(80.27,65.45) ; U9.CK60 81.47,64.87 v4(81.76,64.59) ; v2(59.49,24.26) 59.76,24.53 R333.1 ; v4(81.26,65.45) 80.97,65.73 U9.CL58
  BOTTOM w0.254: C387.1 85.19,71.98 84.58,71.98 84.25,71.65 84.25,71.27 83.97,70.99 83.54,70.99 83.39,71.15 83.06,71.15 v4(82.75,71.45) ; C421.1 84.81,68.78 84.4,68.38 84.07,68.38 83.57,68.88 v4(83.24,68.88) ; C328.1 80.24,78.16 80.77,77.62 80.77,77.24 81.01,77 81.47,77 81.53,77.06 81.97,77.06 82.42,76.61 v4(82.75,76.61) ; v4(82.25,74.03) 81.98,74.03 81.5,74.51 81.06,74.51 80.95,74.4 80.54,74.4 80.06,74.88 C360.1 ; C345.1 80.21,76.45 80.92,75.75 v4(81.26,75.75) ; C471.1 80.11,64.62 80.94,65.45 v4(81.26,65.45) ; v4(83.24,67.16) 83.57,67.16 84.1,67.69 84.35,67.69 84.51,67.54 84.94,67.54 85.19,67.79 C429.1 ; C446.1 84.71,66.6 83.56,65.45 v4(83.24,65.45) ; v4(82.75,73.17) 83.05,73.17 83.52,73.63 83.95,73.63 84.01,73.57 84.47,73.57 84.86,73.97 C363.1 ; C401.1 84.86,70.54 84.23,69.9 84.23,69.55 83.95,69.27 83.52,69.27 83.04,69.74 v4(82.75,69.74) ; C378.1 85.32,72.62 84.61,72.62 84.43,72.8 84.05,72.8 83.57,72.31 v4(83.24,72.31)
  BOTTOM w0.279: U37.2 v2(39.37,29.5)
  BOTTOM w0.381: C444.1 80.24,67.13 v4(80.27,67.16) ; v4(83.74,64.59) 84.28,64.04 C465.1 ; C530.2 v2(55.32,36.14) ; C483.1 v2(31.39,61.8) ; C565.2 v2(54.83,33.07) ; v2(42.53,65.82) 41.76,65.05 33.32,65.05 33.17,65.2 31.17,65.2 C459.1 ; C549.2 v2(55.65,34.24) ; v4(81.76,64.59) 82.3,64.04 C466.1 ; C467.1 31.17,63.86 34.29,63.86 34.67,64.24 40.72,64.24 v2(43.59,61.36) ; v2(55.7,70.53) 56,70.23 C405.1 ; C407.1 79.7,69.77 80.27,69.21 v4(80.27,68.88) ; C370.1 56.18,74.35 55.52,75.01 v2(55.52,75.3) 55.43,75.4 C344.1 ; v2(47.05,59.64) 47.44,59.24 C491.1 ; v2(43.76,70.41) 44.98,71.63 C389.1 ; C365.1 50.6,73.91 v2(50.6,73.74) ; v2(37.3,66.92) 37.11,66.72 C442.1 ; v2(31.76,62.95) 31.75,62.96 C473.1 ; C487.1 54.03,60.39 R580.1 54.79,61.19 v2(54.81,61.21) ; C474.1 55.49,62.82 v2(54.81,63.51) ; C410.1 35.62,69.39 v2(36.11,68.9) ; C575.1 C574.1 R699.1 39.34,29.47 v2(39.37,29.5) ; v4(80.27,70.6) 80.2,70.66 C400.1 ; C371.1 v2(31.76,73.95) ; C348.1 41.75,75.85 42.4,75.2 v2(42.81,75.2) ; C373.1 v1(55.23,72.97) 44.52,72.97 v2(43.76,73.74) ; v2(42.81,73.74) 42.81,73.91 40.84,75.87 C347.1 ; v2(55.78,63.51) 56.48,62.8 C475.1 ; v2(31.76,72.45) 31.44,72.77 C383.1 ; v2(35.46,73.61) 35.46,73.84 34.8,74.49 C369.1 ; v2(50.6,61.21) 50.55,61.16 C486.1 ; R592.1 57.45,57.96 58.08,58.59 58.08,66.63 56.69,68.02 C420.1 54.87,68.83 v2(54.81,68.77) ; v2(47.94,75.24) 47.94,75.69 47.57,76.05 C335.1 ; v2(54.83,75.31) 54.49,75.66 C343.1 ; v2(35.86,70.3) 35.86,70.54 35.41,70.99 34.31,70.99 C403.1 ; v2(31.76,70.95) 31.06,71.65 C395.1 ; v2(31.74,69.46) 31.52,69.67 C408.1 C423.1 31.33,68.45 v2(31.83,67.95) 30.93,67.06 C439.1 ; C353.1 v2(31.76,75.45) ; C346.1 51.33,75.97 v2(50.6,75.24) ; C470.1 79.2,64.37 v4(80.27,65.45) ; C572.2 v2(54.83,30.38) ; v2(36.64,74.87) 36.64,76.5 C339.1 ; C463.1 v2(51.03,63.51) ; v2(33.7,65.82) 33.66,65.86 C450.1 ; C377.1 78.56,72.39 80.19,72.39 v4(80.27,72.31) ; C525.2 56.03,37.08 v1(55.3,37.82) ; C336.1 49.2,76.93 v2(49.2,76.34) ; C359.1 46.36,74.5 47.45,74.5 47.94,74.01 v2(47.94,73.74) ; C484.1 48.42,60.45 47.91,60.95 v2(47.91,61.21) ; C539.2 v2(55.65,35.18) ; v2(36.27,72.35) 36.27,71.94 35.92,71.58 34.59,71.58 33.98,72.19 C376.1 ; C468.1 78.08,62.79 ; R693.1 v2(54.83,31.73) ; v2(39.15,74.82) 39.15,75.56 C350.1
  vias: v2(23.52,46.89) v2(23.52,45.87) v2(23.52,44.86) v2(23.52,43.84) v2(23.52,42.82) v2(23.52,41.81) v2(23.52,40.79) v2(23.52,39.78) v2(24.54,46.89) v2(24.54,45.87) v2(24.54,44.86) v2(24.54,43.84) v2(24.54,42.82) v2(24.54,41.81) v2(24.54,40.79) v2(24.54,39.78) v2(28.68,45.92) v2(28.68,44.91) v2(28.68,43.89) v2(28.68,42.88) v2(28.68,41.86) v2(28.68,40.84) v2(28.68,39.83) v2(35.94,63.51) v2(35.94,61.21) v2(35.94,59.63) v2(36.37,65.82) v2(37.5,70.27) v2(38.53,59.61) v2(38.6,63.51) v2(38.6,61.21) v2(39.03,65.82) v2(39.15,73.65) v2(39.12,70.3) v2(39.16,72.3) v2(39.97,67.5) v2(45.52,32.31) v2(45.52,31.39) v2(45.52,30.48) v2(46.43,32.31) v2(46.43,31.39) v2(46.43,30.48) v2(47.4,32.33) v2(47.4,31.42) v2(47.4,30.51) v2(47.75,68.77) v2(47.94,72.23) v2(47.93,63.51) v2(48.26,65.78) v2(48.39,32.36) v2(48.39,31.45) v2(48.39,30.53) v2(48.56,67.25) v2(49.3,32.36) v2(49.3,31.45) v2(49.3,30.53) v2(50.19,68.77) v2(50.22,32.36) v2(50.22,31.45) v2(50.22,30.53) v2(50.6,72.23) v2(50.6,70.41) v2(51.13,32.36) v2(51.13,31.45) v2(51.13,30.53) v2(51.21,65.65) v2(51.49,67.24) v2(52.04,32.36) v2(52.04,31.45) v2(52.04,30.53) v2(52.96,32.36) v2(52.96,31.45) v2(52.96,30.53) v2(53.87,32.36) v2(53.87,31.45) v2(53.87,30.53) v2(55.27,36.83) v2(74.27,56.82) v2(74.27,56.06) v2(75.08,56.85) v2(75.08,56.06) v3(67.92,71.91) v3(68.35,64.98) v3(69.44,66.75) v3(69.52,70.08) v3(69.72,73.6) v3(71.04,71.91) v3(71.27,68.47) v3(71.34,64.98) v3(71.8,70.1) v3(71.77,66.77) v3(72.21,63.15) v3(73.28,73.54) v3(73.28,71.91) v3(73.28,70.08) v3(73.28,66.61) v3(73.28,64.98) v3(73.25,61.51) v3(73.53,68.49) v3(74.1,75.36) v3(75.06,68.52) v3(75.56,73.54) v3(75.56,71.91) v3(75.56,70.08) v3(75.56,66.61) v3(75.56,64.98) v3(75.56,63.15) v3(75.56,61.51)
P1V2_VDDQ_IRQ_VRHOT_N: length 182.7
  TOP w0.114: U29.16 54.03,6.15 v2(53.8,5.92) ; U12.P11 v3(199.09,48.61)
  S3 w0.102: v2(53.8,5.92) 53.95,6.07 54.94,6.07 55.24,5.77 55.24,5.32 56.33,4.24 60.07,4.24 61.1,3.21 64.46,3.21 64.47,3.22 66.01,3.22 66.9,2.34 70.23,2.34 71.63,3.73 81.38,3.73 88.67,11.02 98.6,11.02 102.69,15.11 v2(102.69,15.14)
  S8 w0.102: v3(199.09,48.61) 199.09,48.17 198.7,47.78 198.7,46.84 198.18,46.32 198.18,45.79 198.55,45.42 198.55,44.91 198.08,44.44 198.08,44.21 197.53,43.66 196.49,43.66 189.94,37.11 189.94,31.95 183.28,25.3 179.27,25.3 177.14,23.17 177.14,21.89 175.62,20.37 174.41,20.37 173.65,19.62 172.9,19.62 171.89,18.6 171.89,17.85 166.33,12.29 160.17,12.29 156.51,8.63 139.4,8.63 138.46,9.58 138.46,10.24 138.05,10.64 136.04,10.64 131.24,15.44 125.68,15.44 125.37,15.75 105.88,15.75 105.57,15.44 103,15.44 v2(102.69,15.14)
  BOTTOM w0.114: v2(102.69,15.14) 102.67,15.16 v1(102.67,16.18)
P1V05: length 142.2
  TOP w0.305: C128.1 116.34,44.44 U18.16 ; U14.1 v2(171.3,51.65) ; U10.1 v2(171.3,70.51) ; U13.24 171.79,64.74 171.3,65.23 v2(171.3,65.74) U13.23
  TOP w0.381: v2(47.57,6.81) 48.05,7.29 R374.2 R379.2 ; v2(105.46,40.64) R291.2 R290.2 ; R296.2 R295.2 v2(110.18,40.57) ; R276.1 v2(96.57,43.38) R285.2 ; v2(171.2,47.04) C100.1 R203.2 ; v2(48.69,8.18) 48.74,8.23 R369.1 ; R206.2 v2(174.14,46.99) ; v2(101.06,46.05) R263.1 R264.1 ; R272.2 v2(112.12,43.74) ; v2(121.61,57.86) R1048.1 R219.1 ; R58.2 v2(20.98,108.66) ; R793.2 101.98,51.92 101.22,52.68 v2(101.22,52.83) ; R294.2 v2(108.79,40.59) ; R269.2 v2(108.79,46.04) ; R1053.2 116.79,36.62 118.48,34.93 L17.2 ; v2(127.76,92.51) C52.1 C974.1 R148.2 ; R237.2 v2(98.8,49.93) R250.2 ; R796.1 R798.1 103.89,39.12 v2(104.42,39.65) ; v6(101.85,32.51) 101.84,32.52 C545.1 ; R208.2 v2(175.08,46.99) ; R309.2 v2(97.94,36.02) R306.2 ; R292.2 v2(106.45,40.54) ; R209.2 v2(176.02,46.99) ; v2(104.39,46.81) 104.47,46.88 R251.2 ; R210.2 v2(176.96,46.99) ; v2(110.18,46.15) R270.2 R271.2 ; R244.2 v2(115.14,50.7) 115.16,50.73 R794.1 ; R305.1 96.57,37.57 v2(96.49,37.49) ; R262.1 98.96,43.89 v2(98.8,43.89) 98.55,44.14 R261.1 ; R20.1 v2(89.71,114.25) ; R214.2 v2(177.9,46.99) ; R59.2 v2(17.75,108.64) ; v2(97.29,40.74) 97.31,40.75 97.31,40.84 97.49,41.01 R284.1 ; C114.1 v2(120.27,54.41) ; R60.2 v2(19.46,108.28) ; v2(116.31,45.31) 116.31,45.31 C128.1 ; R204.2 v2(173.2,46.99)
  BOTTOM w0.254: R604.2 98.43,53.29 99.01,52.7 101.09,52.7
  BOTTOM w0.305: U34.1 173.03,80.61 C318.1
  BOTTOM w0.381: R773.2 R774.2 26.91,5.26 v2(27.17,5.51) ; R643.1 98.16,39.32 97.91,39.07 v2(97.89,39.07) ; R1049.2 116.59,41.86 116.59,43.54 116.31,43.81 C128.1 116.31,45.31 v2(116.31,45.31) ; v2(24.13,5.64) 24.12,5.63 R771.2 R772.2 ; v2(118.64,52.07) 118.41,52.3 Q9.6 ; C396.1 R563.2 171.32,69.34 v2(171.27,69.29) ; v2(90.47,48.95) 90.88,48.54 C510.1 C511.1 C512.1 90.88,45.11 91.33,44.66 U36.1 ; R760.2 35.71,5.13 35.33,5.51 v2(35.33,5.69) ; v2(104.42,39.65) 103.82,39.65 R639.1 ; Q10.1 114.44,48.98 v2(114.58,48.84) 113.89,48.15 C509.1 ; v2(120.02,59.69) 119.79,59.46 R587.1 R583.1 ; R616.1 v2(96.57,49.05) ; v2(28.68,5.61) 28.96,5.33 R767.2 R766.2 ; R463.1 70.54,108.23 v2(70.97,108.66) 71.53,109.22 71.53,109.53 R453.1 ; v2(95.58,40.25) 95.6,40.27 R638.1 R633.1 ; R572.1 177.85,66.72 v2(178.08,66.95) ; v2(120.4,56.79) 120.24,56.64 R597.2 R590.2 ; v2(37.62,12.09) 36.73,12.98 R725.1 ; R768.2 R769.2 31.62,4.29 v2(31.62,5.61) ; R626.1 v2(104.37,43.66) ; v2(99.87,39.19) 100,39.07 R642.1 ; R635.1 99.44,42.21 99.22,42.44 R636.1 98.68,42.44 v2(98.12,43) ; R610.1 101.06,52.68 v2(101.22,52.83) ; R749.1 110.04,50.73 109.47,50.16 109.47,46.73 109.96,46.24 110.09,46.24 v2(110.18,46.15) ; C318.1 172.72,76.18 v2(172.92,75.97) ; C443.1 171.5,65.94 v2(171.3,65.74) ; R617.2 v2(114.63,47.12) ; v2(122.68,75.56) v1(121.67,75.56) ; v2(120.27,54.41) 120.07,54.61 R602.1 ; v2(114.47,117.56) 115.37,117.56 115.76,117.18 C291.1 ; L33.1 103.61,71.76 C385.2 v6(102.57,70.76) ; v2(98.8,49.93) 98.8,49.36 99.7,48.46 R614.1 ; R730.2 v2(40.34,11.58) 40.34,12.21 R726.2 ; R739.2 R738.2 38.24,10.73 v2(37.77,11.2) ; R765.2 v2(40.34,5.6)
  vias: v2(121.62,71.32) v2(121.69,69.57) v2(122.12,70.76) v2(122.53,78.49) v2(122.99,77.8) v2(123.49,77.06) v2(123.57,75.51) v2(123.77,77.85) v2(123.88,76.33) v2(124,78.71) v2(126.03,79.76) v2(126.31,80.52) v2(126.75,81.41) v2(127,79.86) v2(127.38,80.77) v2(133.02,62.23) v2(132.99,61.34) v2(132.99,60.5) v6(101.85,31.11) v6(101.85,29.46) v6(102.49,28.19) v6(103.12,31.11) v6(103.12,29.46) v6(104.39,28.07) v6(104.52,30.23) v6(104.65,31.88) v6(105.79,28.96) v6(105.92,31.24) v6(106.68,30.1) v6(107.95,30.73) v6(107.95,28.96)
P1V5_A_L_I210: length 11.4
  TOP w0.254: U6.47 144.09,85.1 v2(144.07,85.12) ; v2(144.4,85.98) 144.44,86.02 U6.51 ; U6.39 v2(140.09,85.2)
  BOTTOM w0.127: v1(141.4,87.02) 141.48,87.02 141.71,87.25 C960.2
  BOTTOM w0.381: v2(142.75,86.23) 142.75,87.12 C960.2 143.76,87.25 v2(143.92,87.1)
  BOTTOM w0.508: C943.2 143.9,85.29 v2(144.07,85.12) C944.2 ; v2(140.09,85.2) 139.9,85.4 C945.2 C941.2 ; v2(144.4,85.98) 144.85,85.98 C942.2
P1V05_PCH: length 35
  TOP w0.203: U9.AE21 102.35,81.99 v4(102.35,81.19)
  TOP w0.254: U9.AM27 v4(98.35,79.59) U9.AP27 ; v4(100.75,81.19) U9.AG25 101.33,80.61 101.33,80.17 U9.AG27 ; U9.AE25 101.95,80.8 102.33,81.19 v4(102.35,81.19) ; U9.AR27 v4(96.75,79.59) 96.71,79.59 96.35,79.95 U9.AU27 96.21,79.86 95.69,79.86 U9.AW27 ; U9.AK18 v4(99.15,83.59)
  TOP w0.33: U9.AH21 v4(100.75,82.79) ; v4(99.15,85.19) U9.AM14 ; U9.AC25 v4(103.15,81.19) U9.AC23 ; U9.AH23 v4(100.75,81.19) ; v4(99.15,83.59) U9.AM18
  TOP w0.381: U9.AM27 98.96,79.78 99.34,79.78 U9.AK27 ; C78.2 v2(116.61,82.6) ; C76.2 v2(117.57,82.6) ; U9.AM16 v4(99.15,85.19) ; C77.2 v2(118.59,82.6) ; 121.61,83.77 C68.2 C69.2 124.81,83.83 124.79,83.85 ; C75.2 v2(119.58,82.66) ; C74.2 120.49,83.09
  BOTTOM w0.381: C315.2 112.85,82.49 v4(113.68,83.32) ; C302.2 99.08,85.26 v4(99.15,85.19) ; v4(96.75,79.59) 96.75,78.45 C331.2 ; v4(110.64,83.67) 110.64,83.43 111.91,82.17 C314.2 ; v4(109.97,84.31) 110.27,84.61 C299.2 ; v2(115.42,82.75) 115.06,82.4 C311.2 ; L34.1 99.87,71.3 v2(100.36,70.82) ; v4(113.68,84.28) 113.35,84.61 C300.2 ; C317.2 103.24,81.1 v4(103.15,81.19) ; v4(114.36,82.58) 113.84,82.06 C316.2 ; v4(109.99,82.58) 110.94,81.63 C313.2
  vias: v2(121.51,82.55) v2(123.09,82.55)
P1V5_PCH: length 58
  TOP w0.254: U9.AG19 v4(100.75,83.59) ; v4(106.03,77.49) 105.87,77.34 105.84,77.34 105.77,77.27 105.64,77.27 105.3,76.93 U9.V33 ; v4(95.14,77.48) 94.75,77.87 U9.BA30 94.63,78.27 94.07,78.27 U9.BB30 93.76,78.59 93.17,78.59 U9.BD30 ; v4(95.14,77.48) 95.14,77.09 v4(95.43,76.8) ; v4(95.14,77.48) 95.55,77.89 U9.AW30 95.63,78.48 95.63,79.11 U9.AW28 ; U9.AC30 102.78,78.39 103.15,78.76 v4(103.15,78.79) 103.15,78.87 102.82,79.19 U9.AC28 ; U9.W20 104.09,82.9 v4(103.99,82.8) ; U9.AK28 99.64,79.1 99.64,78.49 U9.AK30 100,77.94 v4(100,77.8) ; v4(105.05,79.17) 105,79.17 104.71,79.47 U9.W28 ; U9.AE30 v4(102.37,77.97) ; v4(102.36,78.79) 101.96,79.19 U9.AE28
  TOP w0.381: 129.55,74.3 C90.2 129.2,75.62 R192.2 ; v2(126.11,73.43) 126.29,73.25 C94.1 ; R180.1 v2(117.57,80.59) ; R5.1 v2(94.64,117.65) ; C87.2 v2(126.03,75.74)
  S10 w0.381: v2(107.14,100) 106.48,100 104.72,101.75 104.72,106.5 103.58,107.65 99.14,107.65 98.17,108.61 98.17,109.22 97.41,109.98 96.52,109.98 95.63,110.87 95.63,115.32 94.64,116.31 v2(94.64,117.65)
  BOTTOM w0.254: C349.2 94.41,76.58 95.14,77.3 v4(95.14,77.48)
  BOTTOM w0.381: C330.2 103.15,78.18 v4(103.15,78.79) ; v2(107.14,100) 107.14,100.74 106.78,101.1 R487.1 ; v4(100.75,83.59) 100.65,83.69 C303.2 ; v4(102.36,78.79) 102.36,79.3 C323.2 ; R543.1 107.95,80.8 108.99,81.84 v4(108.99,82.6) ; v4(95.43,76.8) 95.4,76.78 C352.2 ; v4(106.03,77.49) 105.92,77.38 C338.2 ; v4(100,77.8) 100,77.11 C341.2 ; C325.2 105.18,79.04 v4(105.05,79.17) 105.33,79.44 C322.1
  vias: v2(126.16,74.93) v2(126.21,74.22) v2(127.03,74.45)
P1V05_PCH_FLT: length 25.8
  TOP w0.254: v4(101.55,81.99) 101.15,81.59 U9.AG23
  TOP w0.33: U9.AC21 102.77,82.39 103.14,82.77 103.14,82.78 v4(103.15,82.79)
  S5 w0.381: v4(101.55,81.99) 101.55,82.75 102.13,83.34 102.6,83.34 v4(103.15,82.79)
  S10 w0.508: v6(103.05,75.51) 102.29,75.51 100.91,76.89 100.91,78.69 101.8,79.58 104.04,79.58 104.62,80.16 104.62,80.67 103.89,81.41 103.89,82.05 v4(103.15,82.79)
  BOTTOM w0.127: 103.86,83.49 103.86,83.48 104.34,83.01 105.13,83.01 105.87,83.74 106.1,83.74 106.45,84.1 106.45,84.81 v1(106.83,85.19)
  BOTTOM w0.381: v4(101.55,81.99) 101.55,81.99 C310.2 ; C305.2 103.86,83.49 103.16,82.79 v4(103.15,82.79) ; v6(103.05,75.51) C362.2 103.05,74.45 103.73,73.76 L33.2
P1V05_VCC_PCH: length 17.9
  TOP w0.254: v4(99.15,80.39) U9.AK25 ; U9.AP25 v4(98.35,80.39)
  TOP w0.33: U9.AK21 v4(99.95,81.99) U9.AK23 ; U9.AK25 v4(99.95,80.39) ; U9.AM25 v4(99.15,80.39) ; U9.AM23 v4(99.15,81.19)
  BOTTOM w0.254: C326.2 100.66,79.02 99.95,79.73 v4(99.95,80.39) ; v4(99.15,80.39) 99.15,79.64 98.63,79.12 98.63,78.54 99.16,78 C334.2
  BOTTOM w0.381: C308.2 100.05,82.72 100.71,82.07 C309.2 100.59,81.84 100.1,81.84 v4(99.95,81.99) 99.8,81.84 99.8,80.55 v4(99.95,80.39) ; v4(99.15,80.39) v4(98.35,80.39) 97.75,80.39 C321.2 ; v4(99.15,80.39) v4(99.95,80.39) ; v4(99.15,80.39) v4(99.15,81.19) ; C320.2 100.02,80.46 v4(99.95,80.39)
  vias: v2(119.94,81.13) v2(119.96,80.14) v2(121.56,80.59) v2(122,81.33)
P1V05_VCCGBE: length 19.3
  TOP w0.381: U9.Y58 v4(103.95,66.13) ; v2(117.55,68.38) 118.39,67.54 C967.1 C968.1 120.9,67.54 v2(121.21,67.23) ; U9.V51 v4(105.55,69.33) ; U9.V53 v4(105.55,68.53) ; C104.1 126.6,62.43 ; C105.1 127.54,62.45 ; U9.V56 v4(104.75,66.93) ; U9.Y56 v4(103.95,66.93)
  BOTTOM w0.381: L35.2 114.06,69.38 v2(114.22,69.22) ; v4(106.03,65.45) 106.07,65.49 C456.1 ; v4(104.75,66.93) 104.78,66.9 C457.1 ; C458.1 101.42,65.1 C976.1 C971.1 102.74,64.48 103.17,64.91 103.47,64.91 103.95,65.39 v4(103.95,66.13) ; v2(113.87,74.35) 113.87,75.44 L30.2 ; C419.1 104.53,69.33 v4(104.75,69.33)
  vias: v2(123.34,60.86) v2(124.51,60.86) v2(127.1,61.54) v2(127.86,60.5) v2(128.91,60.93) v2(129.67,53.77) v2(130.23,54.2) v2(130.73,53.72) v4(104.75,68.53)
P1V05_VCCION: length 24.7
  TOP w0.254: U9.AP18 97.83,83.99 97.75,83.91 97.35,83.91 97.27,83.99 U9.AR18 ; v4(97.54,82.01) 97.54,82.01 97.16,82.39 U9.AR21 ; U9.AH55 v4(99.95,67.73) ; U9.BB25 93.95,80.78 94.32,80.41 94.32,80.41 v4(94.33,80.4) ; U9.AM53 v4(98.35,68.53) ; U9.AK55 v4(99.15,67.73) ; U9.AC55 v4(102.35,67.73) U9.AC53 ; U9.AK53 v4(99.15,68.53)
  TOP w0.305: U9.AR23 97.15,81.62 v4(97.54,82.01)
  TOP w0.33: v4(98.34,82.01) U9.AP21 ; v4(98.34,83.61) U9.AP18
  TOP w0.381: L9.2 121.05,78.21 120.12,79.15 v2(119.41,79.15)
  BOTTOM w0.203: v4(94.33,80.4) 93.88,79.94 93.88,79.32 94.24,78.97 C329.2
  BOTTOM w0.381: C404.2 98.22,69.4 C416.2 98.09,68.79 v4(98.35,68.53) ; C404.2 98.22,71.17 C397.2 98.24,71.2 C386.2 ; C404.2 v2(99.14,70.23) 99.17,70.21 C415.2 99.17,68.55 v4(99.15,68.53) ; v4(99.95,67.73) 99.95,67.72 99.26,67.03 C447.2 ; v4(102.35,67.73) 101.95,68.13 C422.2 ; v4(99.15,67.73) 99.11,67.69 C430.2 ; v4(98.34,83.61) 97.83,83.61 97.51,83.29 C306.2 97.54,82.85 v4(97.54,82.01) 97.54,82.01 v4(98.34,82.01)
  vias: v2(119.08,75.54) v2(119.48,74.9) v2(119.91,75.54)
P1V05_VCCSCSUS: length 4.7
  BOTTOM w0.254: C374.2 105.03,72.39 105.03,71.55 104.75,71.27 v4(104.75,70.93)
  BOTTOM w0.381: C406.2 103.87,70.13 v4(104.75,70.13) v4(105.55,70.13) v4(106.35,70.13)
  vias: v1(120.65,71.35) v2(118.64,72.29) v2(119.15,71.75) v2(119.71,71.3) v2(120.04,72.85) v4(105.55,70.93) v4(106.35,70.93)
P1V7_AGND: length 9.4
  TOP w0.381: U22.5 153.87,69.75 153.34,69.22 R310.1 153.21,69.47 152.7,69.98 151.07,69.98 150.71,69.62 v2(150.35,69.62) C156.2 R698.2
  BOTTOM w0.114: v2(150.35,69.62) v1(150.35,70.69)
P1V7_SS: length 3.4
  TOP w0.381: R316.1 153.57,70.59 v2(154.48,70.59) 154.67,70.4 U22.4
  BOTTOM w0.114: v2(154.48,70.59) v1(153.42,70.59)
P1V7_SS_C: length 2.5
  TOP w0.381: C156.1 v2(151.94,70.61) R316.2
  BOTTOM w0.114: v2(151.94,70.61) v1(151.94,71.73)
P1V7_SW: length 2.9
  TOP w0.381: L13.1 167.29,69.98 C159.1
  vias: v2(163.19,70)
P1V7_VBST: length 5
  TOP w0.381: C159.2 165.95,71.05 v2(164.11,71.05) U22.12
P1V7_VO: length 5.3
  TOP w0.381: v2(154.75,72.9) 153.79,72.9 C160.1 ; v2(154.75,72.9) 155.37,73.52 R328.1 155.45,74.22 R330.2 ; v2(154.75,72.9) 155.3,72.35 U22.1
P1V7_VO_R: length 2.3
  TOP w0.381: R328.2 v2(152.45,74.3) R324.1
P1V7_VREG: length 5.7
  TOP w0.381: v2(154.1,71.27) 154.71,71.27 154.93,71.05 U22.3
  BOTTOM w0.114: C571.1 v1(156.61,71.58)
  BOTTOM w0.381: v2(154.1,71.27) 154.93,71.27 R697.2 156.6,70.51 C571.1
P3V3: length 269.4
  TOP w0.254: v2(22.5,112.8) 22.32,112.99 CONN4.44 ; v2(21.52,121.77) 21.84,121.77 22.32,121.29 CONN4.43
  TOP w0.305: v2(115.77,43.46) 115.84,43.39 U18.1 ; U13.1 v2(170.99,63.24)
  TOP w0.381: 152.6,55.85 152.61,55.86 C184.2 ; v2(97.92,111.25) 97.92,110.69 R50.2 ; U17.24 178.84,21.19 v2(179.2,20.83) ; R1084.1 179.4,18.62 v2(179.32,18.54) ; R849.1 v2(200.12,101.34) ; v2(202.95,82.3) CONN6.2 ; R108.2 92.41,104.34 v2(92.84,104.78) 93.32,104.29 R109.2 ; R875.1 R883.1 v2(193.43,75.06) ; v2(179.91,60.58) 179.07,60.58 178.78,60.29 177.4,60.29 R212.2 ; U19.8 v2(181.59,19.08) ; R383.1 147.43,32.76 v2(147.12,33.07) ; v2(109.22,108.2) U44.5 110.75,108.2 110.87,108.08 C912.1 ; R931.1 v2(113.16,109.09) ; v2(163.76,80.57) R164.2 164.59,79.36 164.48,79.25 LED11.A ; v2(148.46,112.27) R313.2 ; R24.2 v2(76.61,113.39) ; C31.1 v2(184.65,91.4) 184.95,91.11 CONN6.39 ; R901.1 68.2,116.46 67.69,115.95 67.69,114.21 v2(68.38,113.52) R22.1 ; CONN6.41 184.15,90.84 v2(183.64,91.35) C30.1 ; R201.2 130.23,66.99 129.82,66.57 v2(129.79,66.57) ; R33.1 v2(59.74,110.79) ; v2(70.03,102.84) 71.15,103.96 R94.1 ; C113.1 C112.1 124.71,54.74 C111.1 124.33,54.86 v2(124.33,52.65) U16.8 ; R55.2 v2(22.07,108.41) ; R298.1 137.23,108.53 v2(136.78,108.08) ; R293.2 v2(107.62,40.56) ; R56.2 v2(23.14,108.69) ; U20.8 144.78,112.9 v2(145.41,112.27) ; R1085.1 180.09,25.78 180.36,25.51 v2(180.36,22.62) ; R90.2 89.64,106.02 v2(88.52,107.14) ; R188.2 v2(148.6,69.48) ; L42.1 v2(109.17,8.53) ; R95.2 v2(178.23,93.13) ; R235.2 R234.2 121,55.62 120.78,55.4 v2(117.37,55.4) ; v2(205.06,101.38) C469.2 U7.16 ; U17.10 173.28,17.93 v2(173.38,17.83) ; R300.1 v2(110.65,37.34) ; v2(102.74,118.62) 102.61,118.75 U42.5 101.29,118.75 C910.1 ; CONN6.52 v2(179.75,82.39) ; C185.1 153.53,55.89 153.52,55.88 ; v2(76.58,115.32) 76.58,116.02 R905.1 ; R30.1 v2(64.55,111.73) 64.54,111.73 R39.2 ; C183.2 151.69,55.93 ; C153.1 200.53,14.65 v2(200.58,14.71) ; R57.2 v2(76.69,109.81) ; U2.5 59.4,113.83 v2(59.23,113.67) 58.78,113.67 58.73,113.61 C11.1 ; R922.1 99.88,117.84 v2(100.2,117.51) ; LED15.A v2(187.04,12.93) ; R312.2 148.16,110.36 v2(149.05,110.36) ; U43.16 v2(107.74,118.82) ; CONN6.24 v2(190.95,82.39) ; U38.1 v2(168.35,112.34)
  TOP w0.508: v2(205.56,116.35) C640.1 205.56,113.99 205.05,113.48 CONN18.1
  S8 w0.381: v2(38.48,105.33) 39.08,105.93 39.92,105.93 v2(40.51,105.33)
  S10 w0.381: v2(38.48,105.33) 34.57,109.25 v2(28.09,109.25)
  BOTTOM w0.114: v2(200.61,15.57) 200.33,15.57 199.59,14.83 v1(199.59,14.2)
  BOTTOM w0.305: U34.16 173.53,80.47 C319.1
  BOTTOM w0.381: v2(31.24,116.08) 31.57,115.75 R433.2 31.7,114.96 R442.2 ; R156.2 v2(184.1,79.25) ; R943.1 v2(1.5,90.93) ; v2(85.52,112.35) 86.24,111.64 R449.2 ; R717.2 v2(189.79,14.74) R718.2 ; C271.1 v2(27.08,108.31) ; v2(36.14,5.92) 36.14,5.46 36.63,4.98 R761.2 ; v2(107.62,40.56) 108.02,40.16 R502.2 ; v2(40.51,105.33) R1063.1 R1061.1 R1059.1 R1057.1 ; v2(203.07,20.62) R661.1 R686.1 ; C267.1 v2(27.08,110.19) ; v2(112.26,113.75) 112.3,113.79 112.65,113.79 112.85,113.99 R932.1 R934.1 ; U32.5 59.4,113.83 v2(59.23,113.67) 59.18,113.61 C11.1 ; v2(147.12,33.07) 147.02,33.07 146.61,33.48 146.61,46.91 148.79,49.1 v2(148.79,50.47) ; v2(117.37,55.4) 117.22,55.24 R601.1 ; R631.2 171.7,18.29 172.32,17.67 172.86,17.67 173.02,17.83 v2(173.38,17.83) 173.81,17.4 C913.2 C517.2 174.3,18.74 174.68,19.12 v2(174.8,19.12) ; R687.2 v2(186.84,18.62) ; 170.97,62.03 170.97,61.11 171.79,60.29 178.78,60.29 179.07,60.58 v2(179.91,60.58) ; 170.97,62.03 170.97,63.21 v2(170.99,63.24) ; 170.97,62.03 R577.2 C464.1 ; v2(179.32,18.54) 179.27,18.49 C914.2 ; R1083.1 170.49,23.82 v2(170.69,23.62) ; R422.2 v2(21.52,121.77) ; R446.2 v2(78.28,111.56) ; L36.2 C589.1 C592.1 v2(41.05,23.52) ; C515.2 115.84,43.39 v2(115.77,43.46) ; v2(97.82,73.56) 96.98,73.56 L31.2 ; R1068.2 R1067.2 v2(38.48,105.33) ; C58.1 190.95,82.38 v2(190.95,82.39) ; v2(82.68,109.73) 82.42,109.98 R454.1 ; C647.2 168.35,111.65 v2(168.35,112.34) ; v2(174.35,79.5) 173.97,79.5 173.71,79.76 C319.1 ; R436.2 28.63,113.11 v2(28.93,112.8) ; R935.1 110.35,103.18 v2(110.43,103.25) ; R483.1 R485.1 v2(95.89,94.36) 96.77,93.47 R523.1 ; Q7.A2 51.37,120.2 v2(50.77,119.61) ; v2(76.58,115.32) 76.58,116.6 76.34,116.84 74.31,116.84 74.03,116.56 R430.2 ; R516.1 83.59,100.63 85.38,102.43 85.53,102.43 v2(85.65,102.54) 85.57,102.62 85.57,103.21 R481.2 85.6,103.38 R470.2 ; C544.1 v2(181.59,19.08) ; R651.2 R660.2 v2(186.79,21.41) ; v2(173.74,21.51) 174.01,21.24 C516.1 ; Q9.1 117.91,49.63 118.13,49.41 C508.1 118.62,48.35 118.62,47.2 118.61,47.19 v2(118.61,47.14) 118.57,47.19 R618.1 ; R443.2 87.2,113.34 R432.2 v2(87.2,116.08) ; 98.17,110.44 R456.2 ; 98.17,110.44 R501.1 ; 98.17,110.44 98.17,111 v2(97.92,111.25) ; R1066.1 v2(1.5,93.98) ; v2(183.38,13) R721.2 R722.2 ; R457.2 102.18,109.53 v2(102.87,108.84) ; R461.2 69.89,109.12 v2(70,109.01) ; v2(179.2,20.83) 179.12,20.75 C915.2 ; R1065.1 v2(1.5,100.08) ; R478.2 v2(92.84,104.78) ; R603.1 R607.1 29.9,51.74 v2(29.72,51.56) ; v2(30.53,121.82) 30.53,121.69 30.33,121.48 R416.2 R415.2 R414.2 ; v2(82.07,107.7) 82.22,107.7 R467.2 ; R663.2 183.69,20.9 v2(184.2,20.4) ; C61.1 179.71,82.34 v2(179.75,82.39) ; v2(26.04,121.72) 26.04,121.29 26.27,121.06 R420.2 R421.2 ; R438.2 v2(83.31,113.56) 83.33,113.54 R521.1 ; R942.1 v2(1.5,97.03) ; R419.2 R418.2 24.54,120.32 v2(24.54,121.74) ; v2(200.58,14.71) 200.92,14.37 CONN15.1 ; v2(202.95,82.3) 203.02,82.23 C54.1 ; v2(173.63,23.6) 173.53,23.49 R249.1 ; v2(63.14,115.49) 62.78,115.86 R429.1 ; v2(76.69,109.81) 76.43,109.81 R459.1 ; v2(107.74,118.82) 107.34,119.23 C911.2 ; R33.1 v2(59.74,110.79) ; C269.1 v2(27.08,109.25) ; R933.1 v3(106.55,114.75) ; v2(91.44,112.5) R448.2 91.44,110.69 R452.2 ; C154.1 144.78,112.9 v2(145.41,112.27)
  vias: v2(28.09,110.19) v2(28.09,108.31) v2(98.37,73.08) v2(126.06,84.18) v2(126.35,83.29) v2(144.88,53.92) v2(144.93,49.89) v2(145.06,51.21) v2(145.67,54.46) v2(149.5,49.91) v2(149.81,51.13) v2(151.43,54.2) v2(152.43,54.48) v2(153.42,54.08) v2(154.2,54.48) v2(155.45,51.18) v2(155.4,49.94) v2(158.37,106.76) v2(158.88,107.31) v2(200.36,17.53) v2(203.48,75.98) v2(203.48,75.09) v2(205.05,17.55)
P3V3_A: length 154.1
  TOP w0.381: R187.1 201.04,67.11 v2(201.12,67.19) ; v2(206.12,68.83) 206.12,68.58 205.74,68.2 C83.1 ; R155.2 v2(205.51,69.42) ; R503.1 202.82,41.61 v2(203.63,40.79) ; U12.H6 v3(193.09,55.61) ; R391.1 C250.1 C251.1 65.34,5.96 v2(64.97,6.32) ; C283.1 v2(177.35,98.09) ; v2(20.3,86.39) 21.13,86.39 21.39,86.65 22.8,86.65 v2(23.04,86.41) 24.95,86.41 v2(24.97,86.39) 24.97,86.49 25.53,87.05 26.96,87.05 27.59,86.43 ; v2(191.49,40.36) 192.05,40.36 C55.1 C59.1 190.86,38.96 L5.1 ; U12.L9 v3(197.09,51.61) ; U12.T14 201.59,46.7 201.9,46.38 v3(201.9,46.35) ; U12.C16 v3(204.09,60.61) ; 27.59,86.43 v2(27.59,86.39) ; 27.59,86.43 28.12,86.96 28.12,95.76 v2(27.39,96.48) 25.35,96.48 v2(21.74,100.1) 21,100.84 v2(19.03,100.84) 10.09,100.84 v2(5.29,105.63) 4.4,104.74 R93.1 ; L22.1 5.62,17.21 C198.2 C197.1 C196.1 v2(2.55,18.05) ; v2(177.16,30.99) 176.56,30.38 R277.1 ; U12.F8 v3(195.09,57.61) ; v2(197.74,16.05) 197.52,15.83 U21.16 ; v2(80.37,4.95) 80.19,5.13 R375.1 80.37,6.1 v2(81.31,5.16) ; U12.F9 v3(197.09,57.61) ; U12.P16 v3(204.09,48.61) ; R921.1 v2(188.04,71.81) ; U12.C1 v3(188.09,60.61) ; U12.H11 v3(199.09,55.61) ; U12.T3 v3(190.09,46.61) ; CONN9.4 v2(197.31,8.1) ; U12.P1 187.95,49.11 v3(187.93,49.12) ; U12.J6 v3(193.09,53.61) ; R712.1 v2(186.69,7.49) ; U12.A3 v3(190.09,62.61) ; U12.A14 v3(202.09,62.61) ; U12.J11 v3(199.09,53.61) ; U12.L8 v3(195.09,51.61) ; R390.1 v2(190.37,7.49)
  BOTTOM w0.381: R495.1 R496.1 v2(19.03,100.84) ; v3(188.09,60.61) C355.1 ; v2(204.27,119.08) R411.1 R410.1 ; R681.2 54.18,33.76 v2(53.8,33.38) ; U33.24 v2(27.39,96.48) C278.1 ; C478.1 201.93,46.45 201.93,46.38 v3(201.9,46.35) ; R659.1 R658.1 R657.1 v2(92.27,35.77) 92.37,35.67 R675.1 ; v2(203.56,4.6) 203.33,4.37 R707.1 ; R528.2 v2(27.59,86.39) ; R654.1 v2(43.75,36.69) ; v2(23.04,86.41) R533.2 R532.2 ; v3(202.09,62.61) C358.1 ; C290.2 v2(177.16,94.36) ; v2(35.69,36.98) 34.87,36.98 34.29,37.57 34.29,38.25 34.01,38.53 R646.1 ; U35.2 167.88,38.42 R608.2 C502.1 167.54,40.8 C500.1 v2(167.34,42.04) ; C479.1 187.93,48.76 v3(187.93,49.12) ; R753.2 v2(115.37,6.91) R783.2 ; C119.2 164.31,47.4 ; R491.2 v2(21.74,100.1) 21.69,100.05 R494.2 ; C117.1 164.31,46.41 ; C356.1 v3(204.09,60.61) ; R689.2 v2(44.07,32.84) ; R683.2 R684.2 40.79,33.89 v2(41.3,33.38) ; C477.1 v3(190.09,46.61) ; R691.2 v2(36.62,33.53) ; U12.F9 v3(197.09,57.61) ; v3(190.09,62.61) C357.1 ; C570.1 C567.1 197.52,15.83 v2(197.74,16.05) ; v2(176.4,94.23) 176.15,94.49 C298.2 ; C480.1 v3(204.09,48.61) ; U12.L9 v3(197.09,51.61) ; R407.1 R408.1 v2(199.87,119.08) R409.1 ; R412.1 R413.1 v2(207.31,119.08) ; U12.F8 v3(195.09,57.61) ; v2(191.39,118.29) 191.24,118.43 R404.1 R405.1 R406.1 ; U12.H6 v3(193.09,55.61) ; v2(196.93,18.39) 196.67,18.64 R665.2 ; R678.2 v2(50.97,33.38) ; R910.1 197.33,45.61 196.9,45.61 v2(196.69,45.82) ; C590.2 v2(197.31,8.1) 198.48,6.94 R705.1 ; U12.L8 v3(195.09,51.61) ; R530.2 v2(20.3,86.39) ; U12.J6 v3(193.09,53.61) ; U12.J11 v3(199.09,53.61) ; R525.2 24.85,86.5 v2(24.97,86.39) ; U12.H11 v3(199.09,55.61) ; C120.2 164.31,48.29
  vias: v2(159.72,43.59) v2(160.32,46.86) v2(160.55,44.55) v2(160.91,42.72) v2(161.01,48.46) v2(161.57,46.94) v2(162.05,49.71) v2(162.23,48.46) v2(162.41,50.95) v2(163.55,51) v2(178.18,96.93) v2(178.18,95.94) v2(179.4,96.93) v2(179.43,95.94) v2(192.98,105.61)
P3V3_A_L_I210: length 61.2
  TOP w0.254: U6.27 136.96,87.52 v2(137.31,87.17) ; U6.10 140.09,92.57 v2(140.34,92.33) ; U6.41 141.09,83.59 140.97,83.46 v2(140.97,83.44) ; U6.64 145.34,93.02 v2(145.54,93.22)
  TOP w0.381: R814.2 v2(149.73,104.14) ; LED18.A 132.72,79.27 v2(133.3,78.69) ; R975.2 v2(144.4,98.17) ; R822.2 148.59,100.53 v2(148.59,101.35) ; C17.1 154.31,120.14 v2(153.92,120.52) ; L1.1 v2(169.19,116.87) ; R1038.1 v2(153.42,94.23) ; R802.1 169.54,104.32 169.54,103.5 v2(169.09,103.05) ; R977.2 v2(131.95,92.33) ; R1009.1 v2(144.4,101.09) ; C284.1 v2(171.47,100.46) ; v2(133.73,117.6) 133.73,118.11 133.48,118.36 C288.2 ; R1005.1 v2(140.34,101.09) ; R801.2 v2(165.1,109.86) ; v2(153.56,119.9) 154.08,119.38 154.49,119.38 C16.1 ; R1040.1 v2(153.54,92.2) ; U38.6 168.35,107.53 v2(168.33,107.52) ; R1007.1 v2(141.35,101.09) ; R1003.1 v2(139.32,101.09) ; R1042.1 v2(153.42,93.22) ; R1043.1 v2(153.54,91.19) ; R1011.1 v2(146.43,101.09) ; v2(153.03,116.81) 153.14,116.81 L3.2 ; v2(138.3,77.34) 138.43,77.34 138.81,77.72 R1034.1 ; R828.2 v2(150.24,89.15) ; R817.2 v2(149.61,106.17) ; R816.2 148.79,102.44 v2(148.46,102.11) ; R807.1 v2(136.07,78.03) ; R829.2 v2(153.54,90.17) ; C6.1 v2(170.45,113.56) ; R920.2 v2(153.54,86.11) ; R979.1 R976.2 v2(131.95,93.34) ; C7.1 v2(170.45,116.11) ; R808.1 v2(139.52,78.03)
  TOP w0.508: R813.2 134.62,106.3 v2(134.24,105.92) ; U39.8 136.83,102.87 C963.1 C651.1 v2(135.64,103.5) ; R818.2 v2(134.37,104.27) ; R815.2 134.62,105.28 v2(134.37,105.03)
  BOTTOM w0.127: v2(134.24,105.92) 134.24,106.08 v1(134.89,106.73)
  BOTTOM w0.381: R961.1 131.19,86.01 131.65,85.55 v2(131.95,85.55) 131.95,85.6 132.13,85.78 R978.2 ; R999.1 v2(142.37,101.09) ; R1001.1 143.71,100.4 v2(144.4,101.09) ; v2(174.42,96.09) C298.1 C290.1 ; C648.1 v2(168.33,107.52) ; v2(147.07,95.63) 146.94,95.63 146.3,95 C961.2 146.3,94.21 v2(146.94,93.57) ; v2(145.39,94.36) 144.83,93.8 C929.2 C926.2
  BOTTOM w0.508: C925.2 145.72,93.04 v2(145.54,93.22) ; v2(137.31,87.17) 137.31,87.18 C931.2 ; C928.2 v2(140.97,83.44) ; C926.2 143,93.8 C927.2 ; C930.2 140.52,92.51 v2(140.34,92.33)
  vias: v2(168.02,103.05) v2(168,102.18) v2(168.55,101.4) v2(169.09,102.16) v2(169.24,100.76) v2(171.45,101.22) v2(173.1,102.74) v2(173.86,101.85)
P3V3_A_Q3: length 2.9
  TOP w0.381: R93.2 3.26,105.98 Q3.A2 3.25,106.29 v2(3.92,106.96)
P3V3_AB: length 17.7
  TOP w0.114: R391.2 62.4,2.89 v2(59.04,2.89) U29.28
  BOTTOM w0.114: v1(60.02,3.76) R758.2 v2(59.04,2.89) 58.56,2.41 57.94,2.41 57.54,2.81 57.54,3.51 56.16,4.89 56.16,7.59 55.09,8.66 55.09,9.47 55.28,9.66 R729.2
P3V3_BATT: length 160.1
  TOP w0.33: U9.AW14 v4(95.94,85.21)
  TOP w0.381: v2(99.14,100.41) 99.14,101.5 R117.1 ; C14.2 C21.2 ; C21.2 v2(6.12,109.73) ; C21.2 4.22,107.98 Q3.C ; R140.2 v2(98.61,97.76)
  S5 w0.381: v2(99.14,100.41) 99.14,100.2 98.32,99.39 98.32,98.05 v2(98.61,97.76) ; v2(105.28,119.51) 105.63,119.51 106.01,119.13 106.01,116.04 105.41,115.44 105.41,114.2 107.65,111.96 107.65,109.31 108.2,108.75 108.2,104.83 109.63,103.4 109.63,101.55 107.92,99.85 107.92,99.19 107.24,98.5 105,98.5 102.84,96.34 100.03,96.34 v2(98.61,97.76) ; v2(98.61,97.76) 97.03,96.19 97.03,94.61 95.96,93.55 v2(95.81,93.55)
  V6 w0.381: v2(6.12,109.73) 16.21,119.81 33.43,119.81 35.81,122.2 102.59,122.2 v2(105.28,119.51)
  BOTTOM w0.381: v2(99.14,100.41) 99.14,99.44 R499.2 ; v4(95.94,85.21) 96.05,85.09 C297.2 ; v2(98.61,97.76) 98.35,97.51 R505.2
P3V3_L_PCH: length 0.8
  TOP w0.381: C239.2 105.28,8
  vias: v2(106.17,8.13)
P3V3_LED13: length 1.9
  TOP w0.114: v2(182.47,12.88) LED13.A
  BOTTOM w0.114: v2(182.47,12.88) LED13.A
P3V3_LED14: length 1.9
  TOP w0.114: LED14.A v2(185.26,12.88)
  BOTTOM w0.114: LED14.A v2(185.26,12.88)
P3V3_PCH: length 51.8
  TOP w0.305: U9.AU12 96.35,86.5 v4(96.68,86.84) ; U10.24 172.15,72.35 171.94,72.56 v2(171.94,73.01) U10.23 ; U14.23 v2(171.5,54.15) 171.5,53.5 171.84,53.15 U14.24 ; U9.AE18 102.06,84.1 102.06,84.69 U9.AE16 v4(101.55,85.19) ; U9.AG14 U9.AH14 100.35,85.6 99.96,85.99 v4(99.96,85.99) ; v4(101.56,86.82) 101.95,86.44 U9.AE12
  TOP w0.33: U9.AG18 v4(101.55,83.59) ; v4(95.97,80.39) 95.96,80.39 U9.AW25 95.16,80.41 v4(95.15,80.41) 95.14,80.41 U9.BA25 ; v4(103.15,83.59) 103.08,83.59 102.75,83.27 U9.AC19 ; U9.AC14 v4(103.15,85.19) ; U9.AM12 v4(99.15,85.99)
  TOP w0.381: R91.2 75.81,105.61 v2(75.89,105.69) ; R89.2 92.94,105.38 v2(92.86,105.46) ; R84.2 R85.2 v2(79.55,107.26) ; R11.2 77.37,115.75 v2(77.72,116.1) ; v2(63.86,115.32) R10.2 64.54,115.32 R17.1 ; R23.1 v2(63.75,113.48) ; R28.2 v2(82.42,112.07) ; v4(101.65,77.7) 101.65,77.89 U9.AG30 U9.AG28 ; R9.1 v2(81.58,115.34) ; R53.1 v2(97.2,111.25) ; C256.2 104.83,3.3 ; R14.2 v2(68.33,114.46) ; R63.1 v2(85.42,109.5)
  BOTTOM w0.254: C286.2 101.07,89.56 101.07,89.03 101.55,88.54 101.55,88.11 101.07,87.63 101.07,87.32 v4(101.56,86.82)
  BOTTOM w0.381: v2(171.94,73.01) 172.16,72.79 C375.1 ; R466.2 v2(72.54,108.05) ; v1(106.82,4.26) 106.82,3.24 106.07,2.49 v2(105.94,2.49) ; v2(171.5,54.15) 171.83,54.48 C445.1 ; v4(103.15,85.19) 103.25,85.3 C294.2 ; C499.1 v2(115.32,51.84) 115.01,51.54 Q10.6 ; v4(103.15,83.59) 102.49,83.59 C304.2 102.28,83.59 v4(101.55,83.59) ; C333.2 101.47,77.87 v4(101.65,77.7) 101.65,76.78 C351.2 ; v2(171.2,52.86) 170.59,53.47 R567.1 ; v4(101.55,85.19) 101.78,85.42 C296.2 ; R473.2 v2(75.89,105.69) ; C295.2 100.05,85.9 v4(99.96,85.99) 99.95,85.99 v4(99.15,85.99) 98.87,85.99 98.55,86.31 C293.2 ; C292.2 96.62,86.89 v4(96.68,86.84) 96.68,87.39 95.96,88.11 C289.2 ; R9.1 v2(81.58,115.34) ; C324.2 v4(95.97,80.39) 95.96,80.41 v4(95.15,80.41)
  vias: v2(105.92,3.51) v2(115.87,49.96) v2(115.9,49.23) v2(116,51.82) v2(117.73,90.55) v2(117.98,92.2) v2(118.24,91.31) v2(118.62,90.04) v2(138.38,72.87) v2(138.46,73.66) v2(138.48,72.19) v2(139.22,74.14) v2(139.24,73.43) v2(139.24,72.26)
P3V3_PCH_IDT_G: length 7.5
  TOP w0.114: U30.3 103.14,5.02 v2(102.79,4.67) 102.69,4.78 R386.1 C249.2
  BOTTOM w0.114: v1(104.25,3.95) 103.9,3.61 D1.A v2(102.79,4.67) 102.69,4.78 C249.2
P3V3_PCH_L:
  vias: v2(109.6,6.15)
P3V3_Q4_Q2: length 15.7
  TOP w0.114: v2(61.75,109.25) 61.75,108.63 Q2.G 63.72,106.6 66.75,106.6 67.61,105.74 70.43,105.74 R94.2 71.35,105.03 71.79,104.58 71.79,102.43 Q4.D
P3V3_STBY: length 193.2
  TOP w0.381: v2(45.09,114.22) R1078.1 R1079.1 ; v2(37.16,111.63) 37.16,107.24 v2(35.43,105.51) ; v2(26.98,56.39) 30.33,56.39 31.34,57.4 v2(31.7,57.4) ; R346.1 v2(11.48,14.95) ; v2(15.62,31.37) 15.19,30.94 R317.1 R322.1 15.19,27.95 16.54,26.6 v2(16.54,15.75) ; R1080.2 43.94,114.05 v2(43.76,114.22)
  TOP w0.508: L22.2 C207.1 C204.1 C205.2 ; C205.2 v2(10.57,14.2) ; C205.2 v2(11.48,14.95) 12.54,14.95 12.95,15.37 12.95,18.16 11.94,19.18 7.24,19.18 6.53,19.89 R512.2 R514.2 R513.2 R511.2 R510.2 R504.2
  S3 w0.381: v2(27.18,77.72) 27.81,77.72 v2(29.34,79.25) 31.24,79.25 v2(31.62,79.63) ; v2(43.76,114.22) 39.75,114.22 v2(37.16,111.63)
  S8 w0.381: v2(31.62,79.63) 32.54,80.54 32.54,101.02 34.62,103.1 34.62,104.55 35.43,105.36 v2(35.43,105.51) ; v2(23.95,56.16) 26.74,56.16 v2(26.98,56.39) 26.98,56.84 26.2,57.62 26.2,66.87 v2(26.87,67.54) 26.77,67.54 25.22,69.08 25.22,76.5 26.06,77.34 26.8,77.34 v2(27.18,77.72) 26.48,78.42 26.48,81.52 v2(26.95,81.99)
  S10 w0.381: v2(31.7,57.4) 31.37,57.4 30.7,56.73 30.7,55.69 29.77,54.76 29.77,54.58 26.64,51.46 24.59,51.46 18.47,45.34 18.47,38.68 15.34,35.56 15.34,32.62 15.71,32.25 15.71,31.46 v2(15.62,31.37)
  BOTTOM w0.254: U45.16 38.62,112.23 C964.2
  BOTTOM w0.381: R940.2 v2(26.95,81.99) ; R914.2 26.29,67.54 v2(26.87,67.54) ; R1077.2 v2(35.43,105.51) ; v2(29.34,79.25) 28.96,78.87 R946.1 ; v2(31.62,79.63) 30.55,78.56 R947.1 ; R917.1 24.42,54.56 23.95,55.03 v2(23.95,56.16) ; v1(27.3,13.13) 24.18,13.13 22.28,15.04 ; U41.5 26.59,57.53 26.73,57.39 26.74,57.39 27.09,57.04 27.09,56.5 v2(26.98,56.39) 26.61,56.02 26.61,55.76 C908.1 ; R918.1 31.9,55.75 32.23,56.08 32.23,56.87 v2(31.7,57.4) 31.37,57.73 C909.1 30.6,57.73 30.4,57.53 U40.5 ; R941.2 26.8,78.11 v2(27.18,77.72) ; v2(45.09,114.22) v2(43.76,114.22) ; v2(37.16,111.63) 36.7,111.18 C964.2
P3V3_STBY_CLKBUF: length 8.6
  TOP w0.381: L3.1 155.7,116.63 C19.1 C18.1 156.88,115.72 v2(156.97,115.62) 157.53,115.06 U5.1
  BOTTOM w0.381: v2(156.97,115.62) 157.1,115.75 157.1,116.71 157.53,117.14 R465.2
P3V3_STBY_OSC: length 8.1
  TOP w0.381: R62.1 169.07,118.2 OSC1.4 167.6,118.16 v2(167.6,117.05) C270.1 C268.1 167.57,115.16 C266.1 167.58,113.97 L1.2
P3V3_STBY_OSC_R: length 3.1
  TOP w0.114: OSC1.1 168.49,119.8 v2(168.71,119.58) R62.2 R36.1
P3V3A_OSC: length 10.2
  TOP w0.381: L5.2 190.73,36.68 C70.1 192.38,35.53 C66.1 C67.1 ; R171.2 C67.1 ; C67.1 193.96,36.48 194.49,37.01 v2(194.51,37.01) 194.51,37.06 195.99,38.54 OSC4.4
P3V3A_OSC_R: length 7.9
  TOP w0.114: OSC4.1 198.59,37.63 198.1,37.14 R1054.2 196.98,35.43 v2(194.46,35.43) 194.46,35.18 193.86,34.57 R171.1
P5V: length 27.7
  TOP w0.254: C99.1 130.96,68.89 U11.4 ; U8.4 146.51,70.33 147.37,71.2 C84.1
  TOP w0.381: C99.1 131.88,68.22 131.88,69.42 v2(131.78,69.52) ; R87.1 v2(133.45,105.97) ; C9.2 v2(128.98,115.93) ; v2(183.46,114.5) 184.61,115.65 C2.1 ; C2.1 185.34,114.34 v2(184.7,113.7) ; C2.1 185.4,115.7 C1.1 185.42,117.2 CONN1.1 ; C8.1 v2(127.99,115.93) ; C84.1 146.71,71.42 146.13,72.01 v2(146.13,72.57) ; C10.2 v2(129.9,115.87) ; C288.1 131.5,117.11 v2(131.41,117.03)
  BOTTOM w0.381: C597.2 C595.2 v2(59.44,22.58) ; C291.2 v2(120.12,116.65)
  vias: v1(126.36,14.86) v2(62.08,19.13) v2(62.05,18.39) v2(79.3,22.48) v2(80.14,22.48) v2(124.84,29.59) v2(124.76,13.28) v2(124.97,31.22) v2(125.12,32.36) v2(125.48,30.4) v2(125.48,28.78) v2(125.45,13.26) v2(125.93,31.19) v2(126.14,29.64) v2(126.24,13.26) v2(126.42,32.16) v2(126.54,33.1) v2(126.57,30.43) v2(126.59,28.75) v2(127.05,31.17) v2(127.13,29.59) v2(129.06,116.97) v2(130.57,117.03) v2(130.75,116.11) v2(131.13,115.2) v2(131.55,116.12) v2(153.9,107.04) v2(163.32,109.47) v2(163.32,108.46) v2(168.83,75.36) v2(168.83,74.52) v2(168.83,73.71)
P5V_A: length 23.7
  TOP w0.249: 74.83,18.14 74.83,16.1 73.99,15.27 72.64,15.27 72.21,15.7 72.21,16.41 71.83,16.79 U26.27 ; U25.27 86.21,17.47 86.72,16.97 v2(86.92,16.97)
  TOP w0.381: 75.84,18.08 75.85,18.08 C194.1
  TOP w0.508: C193.1 89.58,18.69 v6(88.82,18.69) ; R342.2 v6(78.44,19.35)
  BOTTOM w0.508: v6(88.82,18.69) 88.47,18.69 86.92,17.14 v2(86.92,16.97) 86.74,16.97 85.88,17.83 79.95,17.83 v1(79.46,18.32) v6(78.44,19.35)
P5V_B: length 10.8
  TOP w0.249: U24.27 119.1,13.56 v2(119.13,13.54)
  TOP w0.381: C199.1 121.32,13.99 122.05,13.26 v6(122.78,13.26)
  BOTTOM w0.381: v2(119.13,13.54) 119.13,12.88 119.66,12.34 v1(121.64,12.34) 122.56,13.26 v6(122.78,13.26)
  BOTTOM w0.508: v6(122.78,13.26) 122.78,13.41 122.89,13.51 R715.2
P5V_CONN: length 4.1
  BOTTOM w0.381: C609.1 159.82,12.04 ; C610.1 160.76,12.04 ; L37.1 166.88,13.41 v1(167,13.54) ; C611.2 161.69,12.04
P5V_STBY: length 376.2
  TOP w0.381: v2(15.16,16.58) 15.16,14.96 12.1,11.9 C226.2 C225.1 C224.1 7.98,11.9 v2(7.85,11.76)
  V6 w0.508: v2(168.96,5.38) v2(168.96,4.65) 168.91,4.7 165.91,4.7 165.48,5.13 161.67,5.13 161.16,4.62 161.11,4.58 161.03,4.53 160.94,4.5 160.72,4.28 160.72,4.26 160.68,4.17 160.63,4.09 158.78,2.24 128.73,2.24 128.22,2.74 126.39,2.74 125.91,2.26 124.54,2.26 124.31,2.48 124.31,2.77 124.3,2.79 124.3,2.83 123.93,3.21 123.43,3.21 123.43,3.46 123.04,3.85 122.49,3.85 122.11,3.46 122.11,3.02 111.94,3.02 110.36,1.45 98.35,1.45 97,2.79 97,5.44 93.4,9.04 88.49,9.04 83.44,3.99 83.44,3.17 81.66,1.4 15.82,1.4 13.79,3.43 13.79,6.65 11.25,9.19 8.71,9.19 7.85,10.06 v2(7.85,11.76)
  V7 w0.508: v2(7.85,11.76) 7.85,10.06 8.71,9.19 11.25,9.19 13.79,6.65 13.79,3.45 15.85,1.4 81.66,1.4 86.54,6.27 86.54,7.09 88.52,9.07 93.37,9.07 97,5.44 97,2.79 98.37,1.42 110.34,1.42 111.96,3.05 122.11,3.05 122.11,3.46 122.49,3.85 123.04,3.85 123.43,3.46 123.43,3.21 123.93,3.21 124.93,2.21 125.88,2.21 126.45,2.77 128.22,2.77 128.78,2.21 158.75,2.21 161.7,5.16 165.46,5.16 165.96,4.65 v2(168.96,4.65)
  BOTTOM w0.356: CONN14.200 v2(15.16,16.58)
  BOTTOM w0.381: C634.1 168.29,6.13 ; C631.1 168.29,7.07 ; C629.1 168.29,8.01
  vias: v1(170.56,11.68) v2(161.07,25.46) v2(162.04,25.46) v2(163.12,25.43) v2(164.08,25.42)
P5VA: length 15.6
  TOP w0.249: QFN1.20 56.7,17.91 56.77,17.84 56.77,16.95 56.56,16.74 R347.2 ; QFN1.3 v2(59.59,19.94)
  TOP w0.381: R347.2 58.17,16.49 58.78,17.09 61.93,17.09 62.89,18.06 62.89,19.66 61.72,20.83 R343.1 60.48,20.83 v2(59.59,19.94)
V0P6_VTT_VIN: length 5.1
  TOP w0.305: R1087.1 42.8,27.69 v2(43.31,28.2)
  BOTTOM w0.114: v1(43.81,26.42) 42.61,26.42 L36.1
  BOTTOM w0.305: L36.1 42.57,27.46 v2(43.31,28.2) U37.10
V1P5_FB: length 3.8
  TOP w0.127: U11.8 v2(130.46,74.5) 130.46,74.5 C90.1 130.36,75.37 R193.2
  BOTTOM w0.127: v2(130.46,74.5) 130.43,74.47 R558.2
V1P5_FB_R: length 3.7
  TOP w0.127: R192.1 129.2,78.66 129.43,78.89 130.45,78.89 v2(130.51,78.84) 130.51,77.34 R193.1
V1P5_SS: length 2.4
  TOP w0.254: U11.7 130.96,73.94 131.55,74.52 v2(131.75,74.52)
  TOP w0.381: v2(131.75,74.52) 131.39,74.89 C89.1
V1P8A: length 44.3
  TOP w0.381: U12.J7 v3(194.09,53.61) ; v2(195.58,44.48) C109.1 195.58,41.91 194.87,41.2 192.84,41.2 192.53,41.5 189.46,41.5 v2(187.07,39.12) ; U12.H8 v3(195.09,55.61) ; U12.H10 v3(198.09,55.61) ; U12.J9 v3(197.09,53.61)
  BOTTOM w0.381: U12.H10 v3(198.09,55.61) ; v2(187.07,39.12) 180.34,39.12 176.71,42.75 v1(174.12,42.75) 169.8,42.75 168.83,41.78 C507.1 168.53,40.72 C505.1 R611.1 168.53,38.22 169.15,37.61 U35.3 ; v3(197.09,53.61) C437.1 ; U12.J7 v3(194.09,53.61) ; v3(195.09,55.61) C412.1
V1P8A_EN: length 5.4
  BOTTOM w0.381: R608.1 166.63,36.17 U35.1 166.61,35.49 165.51,34.39 v1(164.9,34.39)
V1P35_FB: length 4.1
  TOP w0.254: v2(141.05,69.8) 141.08,69.83 U8.8
  TOP w0.381: v2(141.05,69.8) 141.02,69.83 C95.1 140.08,69.94 R197.2
  BOTTOM w0.381: R555.2 v2(141.05,69.8)
V1P35_FB_R: length 2.7
  TOP w0.127: R198.1 R197.1 v2(137.43,71.32)
V1P35_SS: length 2.6
  TOP w0.127: U8.7 141.63,70.33 141.27,70.69 v2(141.27,71.27) C96.1
V3P3_EN: length 4.6
  TOP w0.381: v2(154.97,35.28) 154.63,35.62 U27.7
  BOTTOM w0.381: v1(154.99,34.39) 154.97,34.41 v2(154.97,35.28) 155.13,35.44 R731.2 155.13,36.17 R732.2 C626.1
V3P3_PCH_EN: length 12.1
  TOP w0.381: v2(102.87,5.69) R386.2 102.04,6.69 C241.1
  BOTTOM w0.381: v2(102.87,5.69) 102.79,5.77 D1.C ; R779.2 99.22,4.76 Q14.D 99.68,6.68 102.31,6.68 D1.C ; D1.C v1(104.5,7.16)
V3P3_PCH_EN_N: length 7.5
  TOP w0.381: Q6.D v2(97.89,6.22)
  BOTTOM w0.381: v1(99.74,8.45) 99.48,8.45 98.17,7.14 98.17,6.5 v2(97.89,6.22) 97.02,5.35 Q14.G 97.02,3.76 R778.2
V3P3_R: length 10.8
  TOP w0.381: v2(147.93,34.47) 147.93,35.38 148.17,35.62 U27.1 150.28,35.04 149.53,34.29 R383.2 ; R388.1 149.51,31.75 v2(148.79,31.75)
  BOTTOM w0.381: C636.1 149.53,32.49 v2(148.79,31.75) 147.93,32.61 v2(147.93,34.47)
V3P3_R_R: length 3.1
  TOP w0.114: R384.1 R388.2 150.87,31.39 151.92,31.39 v2(152.3,31.78)
V3P3_SF100: length 11.1
  TOP w0.381: CONN3.1 43.98,120.22 v2(43.18,120.22)
  BOTTOM w0.381: v2(43.18,120.22) v1(45.14,120.22) 47.65,120.22 49.63,118.23 51.8,118.23 Q7.A1
V3P3_SPI: length 136.1
  TOP w0.381: v2(54.2,118.21) 54.2,116.23 54.64,115.8 58.12,115.8 60.53,118.21 v2(61.85,118.21) ; R6.1 61.85,117.32 v2(61.85,118.21) ; v2(106.83,117.75) 106.68,117.75 R951.1 ; R4.1 88.68,117.85 v2(88.14,118.39) ; v2(61.85,118.21) 63.37,119.74 74.19,119.74 v2(75.34,118.59) ; R949.1 105.18,111.4 R950.1 105.94,112.14 v2(106.2,112.39) ; v2(98.48,112.22) 98.1,112.59 U1.8 v2(95.02,112.59) 95,112.57 C13.1 94.23,113.3 R21.1
  S3 w0.381: v2(114.05,115.5) 113.71,115.5 113.4,115.81 113.36,115.81 111.15,118.02 107.1,118.02 v2(106.83,117.75) 104.93,117.75 104.66,118.02 102.5,118.02 101.42,119.1 100.01,119.1 99.31,118.4 98.81,118.4 98,119.21 88.96,119.21 v2(88.14,118.39)
  S5 w0.381: v2(108.86,101.93) 108.71,101.93 107.58,103.06 107.58,106.36 106.55,107.39 106.55,112.04 v2(106.2,112.39)
  S10 w0.381: v2(75.34,118.59) 76.33,117.6 87.35,117.6 v2(88.14,118.39) 88.73,118.39 88.96,118.62 94.53,118.62 95.63,117.52 95.63,116.59 96.77,115.44 96.77,113.28 97.28,112.78 97.92,112.78 v2(98.48,112.22)
  BOTTOM w0.381: v2(61.85,118.21) 60.99,118.21 57.4,114.63 57.4,112.8 58.49,111.71 58.49,109.17 58.9,108.77 R460.1 ; R435.1 v2(114.05,115.5) 113.41,115.5 R427.1 ; C260.1 53.87,120.96 Q7.C 53.87,118.55 v2(54.2,118.21) ; v2(95.02,112.59) 95.02,112.91 R21.1 ; v2(106.2,112.39) 105.64,111.83 C263.1 104.53,112.59 U31.8 103.43,112.71 98.97,112.71 v2(98.48,112.22) ; R936.1 108.71,102.08 v2(108.86,101.93)
V3P3_SS: length 2.9
  TOP w0.381: R380.1 152.35,34.38 v2(152.23,34.49) U27.4
  BOTTOM w0.381: v2(152.23,34.49) v1(152.23,35.46)
V3P3_SS_C: length 2.9
  TOP w0.114: R380.2 C243.1 v2(153.28,31.78)
  BOTTOM w0.114: v1(153.8,31.03) 153.8,31.26 v2(153.28,31.78)
V3P3_SW: length 1.3
  BOTTOM w0.381: C608.1 v2(152.6,42.82)
V3P3_VBST: length 3.3
  TOP w0.381: v2(151.08,42.84) 151.58,42.34 U27.12
  BOTTOM w0.381: C608.2 151.69,42.23 v2(151.08,42.84)
V3P3_VREG: length 6.6
  TOP w0.381: U27.3 151.58,34.62 v2(151.41,34.44) 151.38,34.42 C242.1 ; R381.2 v2(154.18,32)
  BOTTOM w0.381: v2(154.18,32) 154.07,32 v1(153.21,32.86) 152.99,32.86 v2(151.41,34.44)
V3P3A_EN: length 26
  TOP w0.381: U15.7 172.56,35.63 172.92,35.99 v2(172.95,35.99) ; R233.1 v2(161.96,30.2)
  BOTTOM w0.381: R1088.2 172.95,38.58 v2(172.95,35.99) 173.22,35.99 174.47,34.74 174.47,30.68 v1(173.72,29.94) 172.09,28.3 166.04,28.3 164.13,30.2 v2(161.96,30.2)
V3P3A_R: length 5.6
  TOP w0.381: U15.1 172.4,31.73 172.68,31.45 v2(172.92,31.45) 173.05,31.32 R278.1 R277.2
  BOTTOM w0.381: C513.1 173.61,31.45 v2(172.92,31.45) 172.34,31.45 v1(172.01,31.77)
V3P3A_R_R: length 2.7
  TOP w0.114: v2(176.15,31.5) 176.15,31.9 R279.1 175.51,31.85 R278.2
V3P3A_SS: length 4
  TOP w0.381: R280.1 173.74,33.93 173.15,33.93 v2(173.02,33.81) 172.9,33.68 U15.4
  BOTTOM w0.381: v1(171.7,34.47) 172.11,34.47 172.77,33.81 v2(173.02,33.81)
V3P3A_SS_C: length 6
  TOP w0.114: C129.1 R280.2 176.25,33.81 176.78,33.27 176.78,32.38 v2(178.18,30.99)
V3P3A_SW: length 3.5
  TOP w0.381: L11.1 161.01,34.04 v2(162.26,32.79) 161.95,32.49 C110.1
V3P3A_VBST: length 3.6
  TOP w0.381: U15.12 164.73,33.03 163.83,32.13 v2(163.83,31.93) 163.75,31.85 C110.2
V3P3A_VREG: length 12.6
  TOP w0.381: R281.2 v2(175.51,35.59) ; U15.3 172.8,33.03 v2(172.86,33.08)
  S8 w0.381: v2(172.86,33.08) 173.55,33.08 175.51,35.05 v2(175.51,35.59)
  BOTTOM w0.381: C514.1 175.49,35.61 v2(175.51,35.59) 175.51,40.39 v1(174.88,41.02)
V5A_PM_P1V7: length 0.8
  TOP w0.381: C174.1 161.55,74.12
  vias: v2(163.35,72.42)
V5A_SS: length 10.5
  TOP w0.381: R92.1 v2(129.41,104.95) 128.7,104.95 127.43,106.22 127.43,110.28 127.83,110.68 U4.4
  BOTTOM w0.381: v1(130.63,104.95) v2(129.41,104.95)
V5A_SS_C: length 1.8
  TOP w0.114: R92.2 132.5,104.95 C34.1 133.3,104.78 v2(133.43,104.9)
V5A_SW: length 2.2
  TOP w0.381: C23.1 118.42,109.56 L2.1
  vias: v2(120.17,110.62)
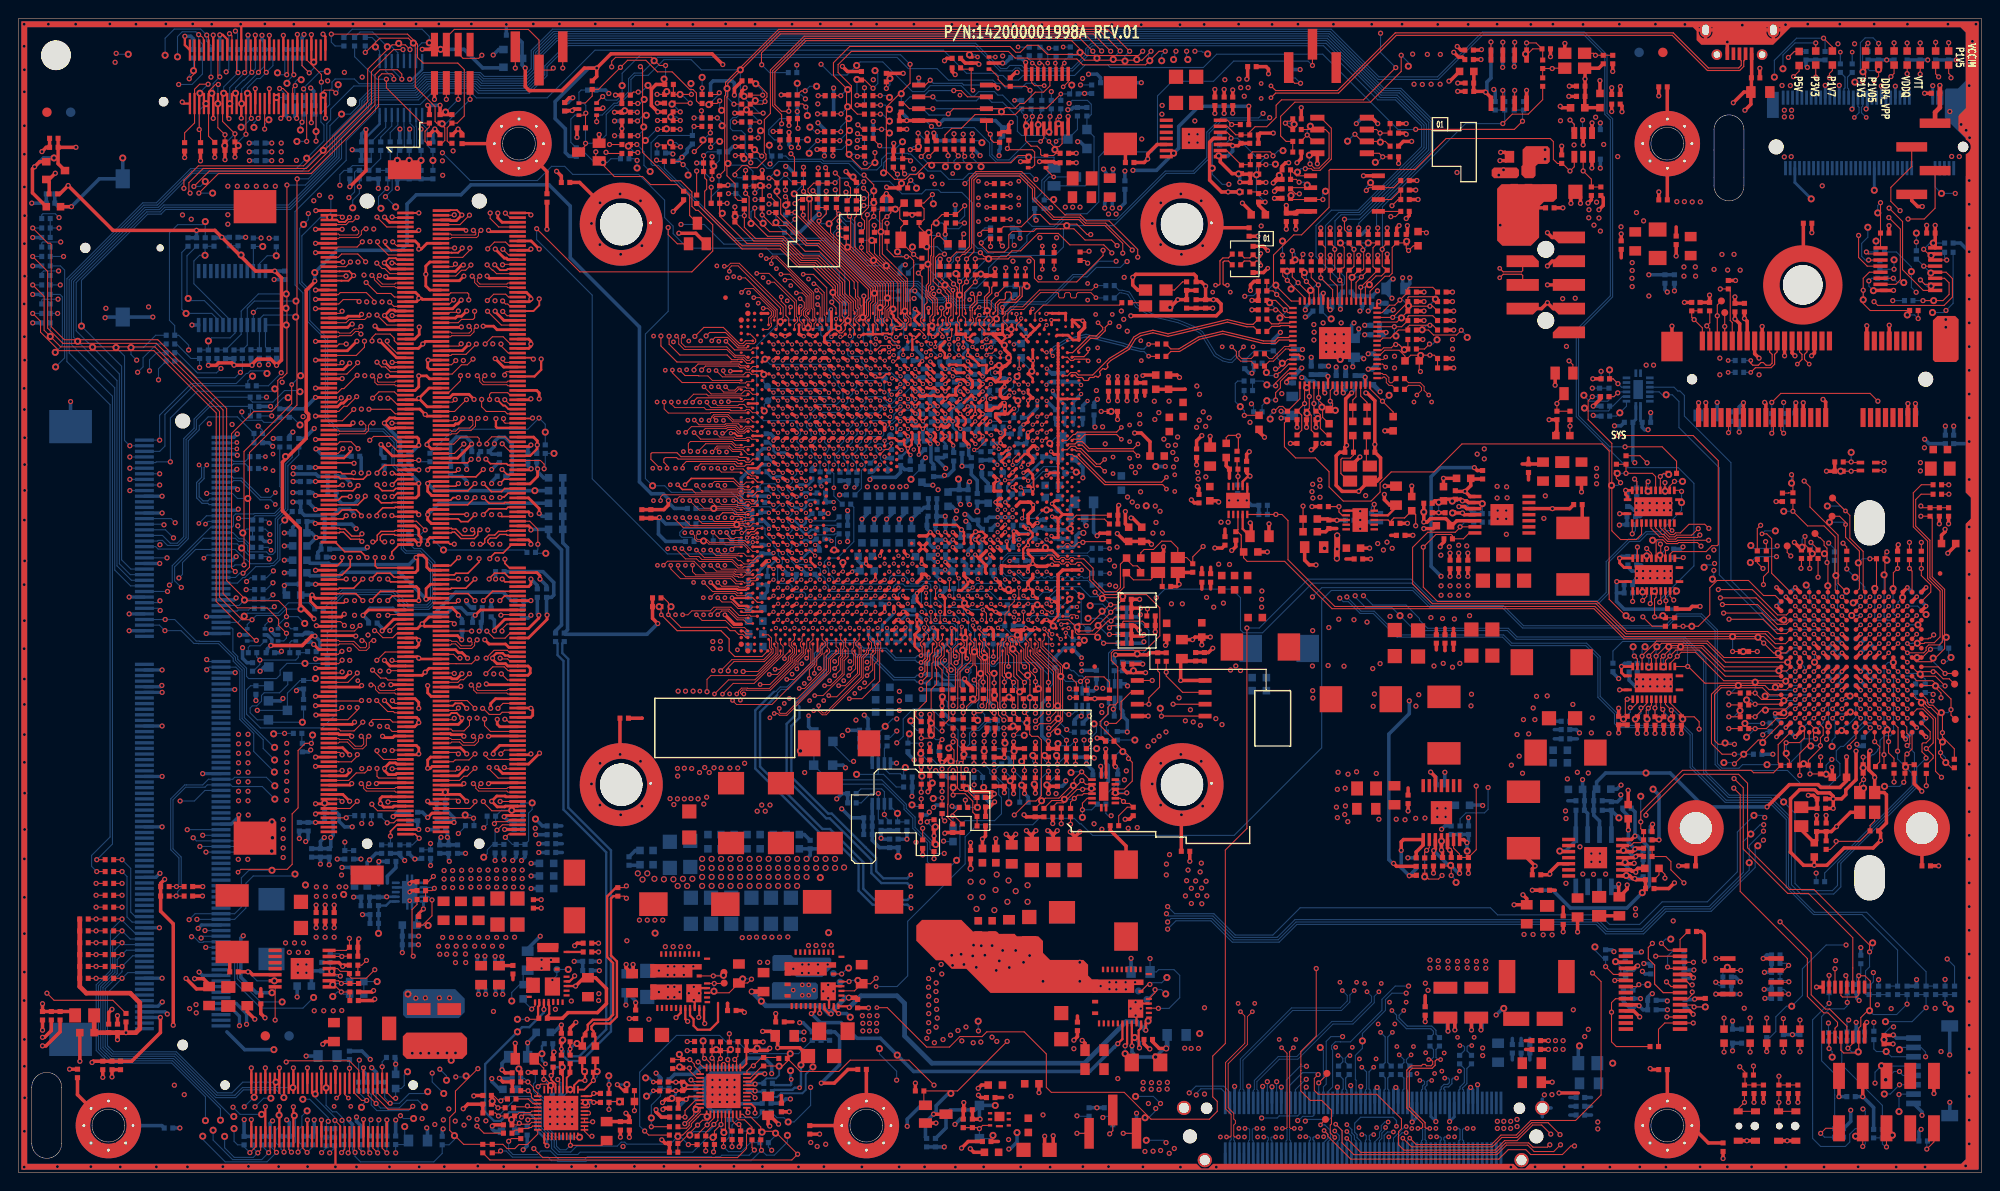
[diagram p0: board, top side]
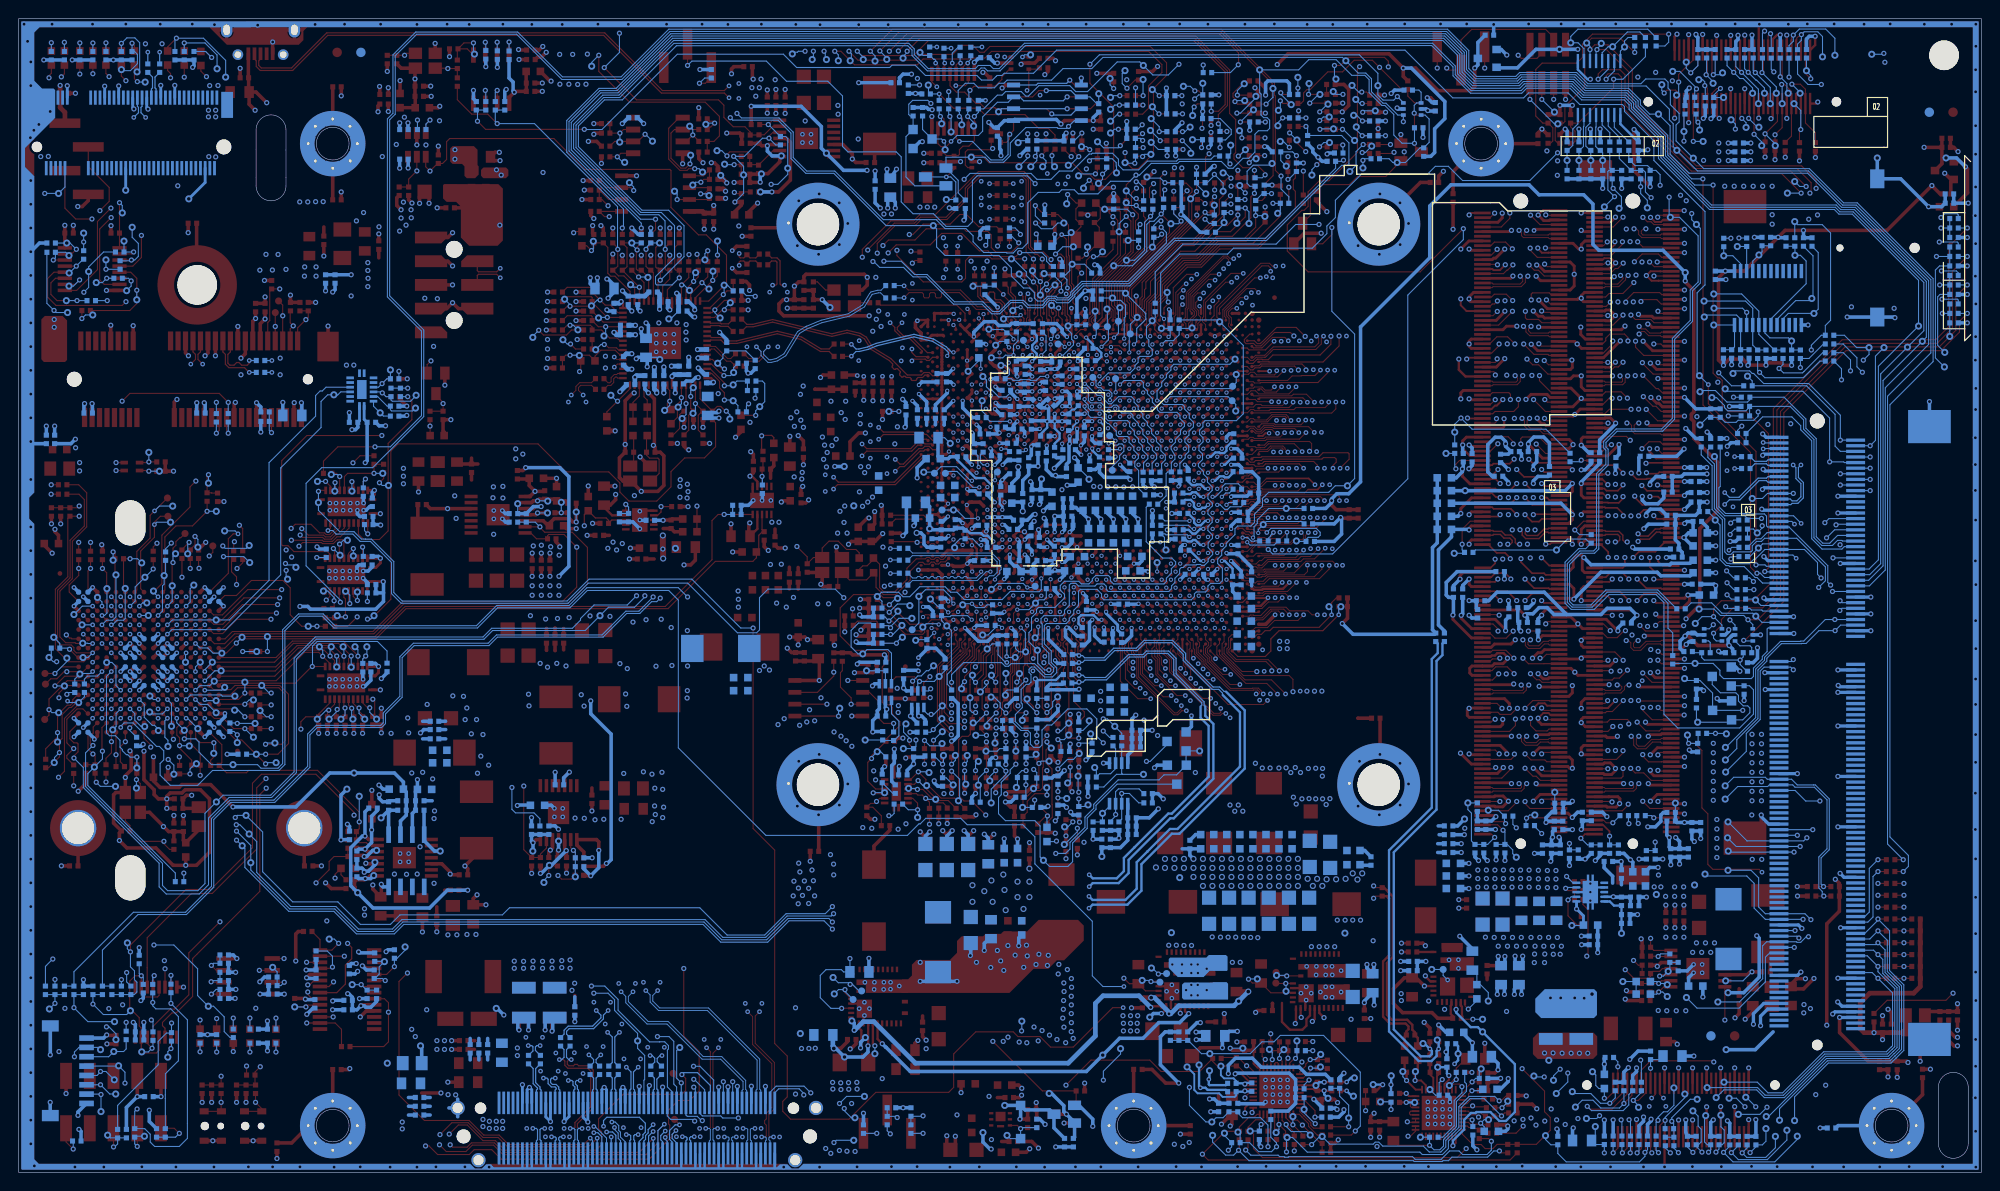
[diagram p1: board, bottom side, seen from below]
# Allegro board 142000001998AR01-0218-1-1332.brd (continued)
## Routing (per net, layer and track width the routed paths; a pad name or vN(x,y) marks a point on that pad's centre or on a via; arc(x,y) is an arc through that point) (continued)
V5A_VBST: length 4.6
  TOP w0.381: U4.12 121.81,110.03 120.8,109.02 v2(120.8,108.48) 120.42,108.1 C23.2
V5A_VO: length 7.3
  TOP w0.381: v2(130.66,105.99) 130.71,105.99 130.73,105.97 R87.2 R77.1 130.89,106.86 C24.1 129.83,106.91 128.57,108.18 U4.1
  BOTTOM w0.381: v2(130.66,105.99) 130.66,106.76 v1(130.53,106.88)
V5A_VO_R: length 2.8
  TOP w0.114: v2(133.45,107.87) R74.1 R77.2
  BOTTOM w0.114: v2(133.45,107.87) 134.42,107.87 v1(134.47,107.92)
V5A_VREG: length 5.6
  TOP w0.381: C20.1 R46.2 130.49,109.9 v2(129.89,109.9) 129.76,110.03 U4.3
  BOTTOM w0.381: v1(128.4,108.81) 129.39,108.81 129.89,109.32 v2(129.89,109.9)
V12A_CONN: length 2.5
  TOP w0.381: C210.1 161.19,14.1 ; C212.1 161.24,13.16
  BOTTOM w0.381: v1(158.9,17.55) 158.8,17.55 v2(158.09,16.84)
  vias: v2(156.64,13.31) v2(156.64,12.5) v2(158.22,5.46) v2(158.22,4.7) v2(158.9,5.46) v2(158.9,4.7) v2(159.64,5.46) v2(159.64,4.7) v2(160.32,5.66) v2(160.32,4.9)
V12A_CONN_R:
  vias: v2(166.34,17.4)
V12A_DDR: length 18.4
  TOP w0.381: v2(51.71,10.97) 52.04,10.64 R362.1 ; C177.2 52.88,20.62
  S8 w0.381: v2(51.71,10.97) 51.71,11.48 46.1,17.09 v2(46.1,18.67)
  BOTTOM w0.381: C614.1 51.71,11.66 v2(51.71,10.97) ; v2(49.96,19.05) 49.96,19.61 C181.2 49.2,19.81 v2(49.2,19.05) ; v2(51.79,19.05) 51.79,19.69 C182.2 51.03,19.74 v2(51.03,19.05)
  vias: v1(41.65,19.08) v2(42.49,18.64) v2(43.51,18.67) v2(45.01,18.67)
V12A_PM_V3P3A: length 1.6
  TOP w0.381: R233.2 164.41,30.2 ; C118.1 165.26,28.42
  vias: v2(165.56,30.94)
V12A_V3P3: length 0.8
  TOP w0.381: C216.1 148.67,41.15
  vias: v2(145.26,42.7)
V12A_V5A: length 21.9
  TOP w0.381: R34.2 v2(131.62,114.12)
  BOTTOM w0.381: v2(119.23,107.26) 121.74,107.26 v1(123.58,109.1) 124.12,109.64 124.12,111.96 126.28,114.12 v2(131.62,114.12) ; v2(116.08,107.39) 116.64,106.53 C27.1 117.09,106.78 v2(117.09,107.39) ; v2(118.36,107.19) C29.1
VCC1P5_OSC25M: length 5.7
  TOP w0.381: C51.1 R154.1 R148.1 v2(124.03,93.42) 123.36,92.75 OSC2.4
  BOTTOM w0.381: v1(123.19,92.59) 123.19,92.59 v2(124.03,93.42)
VCC12A: length 6.3
  TOP w0.381: L12.2 C123.1 ; C158.1 150.5,18.92
  BOTTOM w0.381: R778.1 R779.1 v2(99.04,2.72) ; C158.1 150.5,18.8
  vias: v2(18.29,17.53) v2(18.97,17.96) v2(19,17.07) v2(31.62,17.3) v2(32.64,17.3) v2(33.66,17.3) v2(34.57,17.32) v2(90.27,16.76) v2(90.32,15.95) v2(90.32,15.14) v2(91.03,16.76) v2(91.03,15.95) v2(91.03,15.14) v2(91.85,16.76) v2(91.8,15.95) v2(91.8,15.14) v2(111.99,103.33) v2(112.78,103.33) v2(113.56,103.33) v2(120.32,9.63) v2(120.29,8.92) v2(121.21,9.6) v2(121.18,8.89) v2(122.05,9.58) v2(122.02,8.86) v2(122.91,9.63) v2(122.89,8.92) v2(141,39.09) v2(141.1,41) v2(141.1,37.97) v2(141.17,42.82) v2(141.94,41.12) v2(141.88,38.3) v2(141.96,39.22) v2(142.24,42.62) v2(142.21,37.54) v2(143.15,42.88) v2(150.51,20.24) v2(150.8,19.48) v2(151,22.73) v2(151,21.84) v2(151.89,22.66) v2(151.89,21.92) v2(152.93,22.61) v2(152.93,21.87) v2(153.95,22.58) v2(153.95,21.84) v2(154.97,22.61) v2(154.99,21.89) v2(155.98,22.58) v2(155.98,21.84) v2(156.97,22.61) v2(156.97,21.84) v2(173,28.22) v2(173,27.53)
VCC12A_PM_DDR4_VPP: length 4.3
  TOP w0.114: U23.14 v2(27.44,16.3)
  TOP w0.381: C192.1 25.91,19.66
VCC_EUSB: length 0.8
  TOP w0.381: C264.1 162.56,103.25
  vias: v2(158.52,101.4)
VCCAXCK_DCB: length 12.4
  TOP w0.254: U9.AE27 101.96,79.99 v4(102.35,80.39)
  S5 w0.508: v4(102.35,80.39) 102.35,80.15 100.99,78.79 100.99,77.04 101.88,76.15 101.88,74.07 v2(101.74,73.93)
  BOTTOM w0.381: v2(101.74,73.93) 101.58,73.78 C381.2 C380.2 ; C380.2 100.63,74.14 v1(100.56,74.22) ; C380.2 99.69,73.08 L34.2
VCCGBE_FLT: length 11.6
  TOP w0.254: U9.T56 105.77,66.85 105.77,67.49 v4(105.71,67.54)
  BOTTOM w0.254: R569.1 108.53,68.73 108.23,68.43 107.04,68.43 106.96,68.35 106.95,68.35 106.75,68.15 106.33,68.15 v4(105.71,67.54)
  BOTTOM w0.381: R569.1 108.97,68.96 C409.2 109.96,68.78 C418.2 112.42,68.78 v1(112.53,68.9) L35.1 112.53,71.28 C388.2
VCCGBE_FLT2: length 14
  TOP w0.254: v4(105.56,71.73) 105.95,71.34 U9.T46
  BOTTOM w0.114: v1(110.32,78.04) 110.92,78.64 C327.2
  BOTTOM w0.254: C342.2 109.57,76.27 107.62,74.32 106.65,74.32 105.77,73.43 105.77,73 106.14,72.63 C379.2
  BOTTOM w0.381: C327.2 111.63,76.65 L30.1 110.54,76.4 110.34,76.6 C342.2 ; v4(105.56,71.73) 106.32,72.49 C379.2
VCCIN: length 34.4
  TOP w0.254: 97.94,69.32 100.36,69.32 v2(100.88,68.8) 101.15,68.52 U9.AG53 U9.AG55
  TOP w0.381: U9.BC66 93.85,62.3 v4(94.14,62.58) ; v4(94.63,61.73) 94.92,61.44 U9.AY67 ; v4(95.13,59.15) 95.42,58.86 U9.AW72 ; U9.BC69 v4(93.64,60.01) ; U9.BB71 94.35,59.72 v4(94.63,60.01) 94.84,60.01 U9.AY71 ; v4(94.14,60.87) 94.43,60.58 U9.BA69 ; U9.BD64 93.36,63.16 v4(93.64,63.44) ; v4(94.88,58.33) 94.59,58.05 U9.BA74 ; U9.BB67 93.93,61.44 v4(93.64,61.73) ; U9.BA72 94.43,58.86 v4(94.14,59.15) 93.93,59.15 U9.BC72 ; U9.BD74 93.6,58.05 v4(93.89,58.33)
  BOTTOM w0.254: C492.2 96.6,58.71 96.6,59.36 96.32,59.64 94.97,59.64 94.48,59.15 v4(94.14,59.15)
  BOTTOM w0.305: v4(93.64,60.01) 93.64,59.84 92.41,58.6 92.41,58.05 C495.2
  BOTTOM w0.381: C563.2 66.42,32.87 C561.1 ; C540.2 84.68,33.93 v6(84.3,33.55) ; C540.2 85.51,34.63 ; C540.2 C538.1 ; C481.2 93.1,60.82 v4(93.15,60.87) ; v4(93.89,58.33) 93.85,58.29 C493.2 ; C496.2 94.2,56.76 94.88,57.44 v4(94.88,58.33) ; v4(94.63,60.01) 94.83,60.2 C482.2 ; C497.2 95.93,56.45 95.43,56.95 95.43,58.85 v4(95.13,59.15) ; v4(99.11,54.81) 99.11,54.76 98.83,54.48 R600.1 ; v2(100.88,68.8) 100.8,68.72 C432.2
  vias: v1(85.77,31.55) v2(89.59,48.41) v2(90.81,73.38) v2(91.75,73.36) v2(92.61,73.38) v2(93.48,73.38) v2(94.23,51.49) v2(94.23,50.47) v2(94.23,49.45) v2(94.29,73.38) v2(94.97,73.43) v4(92.65,65.16) v4(93.15,64.3) v4(93.64,65.16) v4(94.14,66) v4(94.14,64.3) v4(94.63,65.16) v4(94.63,63.44) v4(95.13,64.3) v4(95.13,60.87) v4(95.62,65.16) v4(95.62,63.44) v6(66.24,32) v6(66.75,31.34) v6(67.26,32) v6(68.02,31.42) v6(69.04,31.37) v6(70.05,31.37) v6(70.51,30.66) v6(71.07,31.42) v6(71.53,30.66) v6(72.09,31.42) v6(73.13,33.55) v6(73.13,32.59) v6(73.13,31.62) v6(73.13,30.66) v6(74.14,33.55) v6(74.14,32.59) v6(74.14,31.62) v6(74.14,30.66) v6(75.16,33.55) v6(75.16,32.59) v6(75.16,31.62) v6(75.16,30.66) v6(76.17,33.55) v6(76.17,32.59) v6(76.17,31.62) v6(76.17,30.66) v6(77.19,33.55) v6(77.19,32.59) v6(77.19,31.62) v6(77.19,30.66) v6(78.21,33.55) v6(78.21,32.59) v6(78.21,31.62) v6(78.21,30.66) v6(79.22,33.55) v6(79.22,32.59) v6(79.22,31.62) v6(79.22,30.66) v6(80.24,33.55) v6(80.24,32.59) v6(80.24,31.62) v6(80.24,30.66) v6(81.25,33.55) v6(81.25,32.59) v6(81.25,31.62) v6(81.25,30.66) v6(82.27,33.55) v6(82.27,32.59) v6(82.27,31.62) v6(82.27,30.66) v6(83.29,33.55) v6(83.29,32.59) v6(83.29,31.62) v6(83.29,30.66) v6(84.3,32.59) v6(84.3,31.62) v6(85.32,33.55) v6(85.32,32.59) v6(86.33,33.55) v6(86.33,32.59) v6(87.35,33.55) v6(87.35,32.59) v6(88.32,32.64)
VCCIN_P1V05_VCC: length 30.8
  TOP w0.203: U28.28 78.35,9.71 79.18,10.54 v2(79.83,10.54)
  TOP w0.381: C240.2 81.61,8.2 81.61,8.2
  BOTTOM w0.381: R735.2 70.18,10.49 72.21,10.49 72.97,11.25 77.04,11.25 78,12.22 79.81,12.22 80.57,11.46 v2(80.57,10.57) ; v2(79.83,10.54) 79.76,10.62 74.07,10.62 73.37,9.92 R740.2 R744.2 73.37,7.38 74.19,6.56 R750.2 ; R747.2 C240.2 82.07,7.85 v2(82.58,7.85)
VCCKRHV: length 29.6
  TOP w0.254: U9.N58 107.49,65.76 107.49,66.28 107.48,66.28 107.48,66.74 107.82,67.08 107.95,67.08 v4(108,67.13) 108,67.59 108.48,68.07 108.48,68.43 v4(108,68.91)
  TOP w0.305: v4(108,68.91) 107.77,68.91 U9.N51
  TOP w0.381: R198.2 139.84,68.57 C95.2 141.04,68.92 ; C91.1 142.01,65.66
  TOP w0.635: v6(141.05,65.71) 141.05,66.7 v2(141.08,66.73) v6(141.08,68.17)
  S8 w0.381: v6(113.92,68.45) 112.19,68.45 110.87,67.13 109.91,67.13 109.32,66.55 108.58,66.55 v4(108,67.13)
  S8 w0.635: v6(113.92,68.45) 114.48,68.45 115.11,69.09 117.3,69.09 117.32,69.1 117.92,69.1 117.93,69.09 118.49,69.09 119.15,68.43 v2(121.36,68.43)
  BOTTOM w0.381: C433.2 C434.2 112.82,66.92 113.13,67.23 113.13,68.12 113.46,68.45 v6(113.92,68.45) ; v4(108,68.91) 107.64,69.27 C417.1
  vias: v1(139.73,66.8) v2(122.38,68.43)
VCCSCFUSESUS: length 27.4
  TOP w0.254: U9.AE55 101.87,67.41 101.87,68.05 U9.AE53 102.39,68.57 v2(102.39,68.57) 103.1,68.57 U9.AA53
  TOP w0.305: U9.AA53 103.16,67.74 v4(103.12,67.74) 103.54,67.33 U9.AA55
  TOP w0.381: v2(155.75,75.44) 156.06,75.13 R330.1 ; C101.1 129.07,68.87 ; C141.2 v2(153.16,63.8) ; C142.2 v2(155.06,63.8) ; C140.1 v2(154.08,63.8) ; C82.1 146.8,68.19
  BOTTOM w0.381: v2(155.75,75.44) 152.1,75.44 151.13,74.47 151.13,64.87 v2(152.19,63.8) ; v4(103.12,67.74) 102.95,67.57 C441.1 102.95,65.49 C139.1
  vias: v2(128.65,69.6) v2(129.41,69.6) v2(145.41,67.31) v2(146.02,66.62) v2(146.41,67.46) v2(146.96,66.8) v2(152.19,62.79) v2(152.19,61.77) v2(153.16,62.79) v2(153.16,61.77) v2(154.08,62.79) v2(154.08,61.77) v2(155.06,62.79) v2(155.06,61.77)
VCCSCSUS_SENSE: length 1.5
  TOP w0.089: v4(96.88,58.32) 96.88,58.03 97.36,57.55 U9.AR76
VCCSUS3_3: length 13.9
  TOP w0.33: U9.AW23 95.92,81.22 v4(95.95,81.22) ; U9.AR28 v4(97.55,78.79) ; U9.AR30 v4(97.55,77.99) ; U9.AP12 v4(97.55,86.79) ; U9.AR16 v4(97.55,84.39)
  TOP w0.381: U9.AW18 v4(95.95,83.59) ; U9.AR14 97.15,85.58 v4(97.55,85.18) 97.94,84.79 U9.AP16 ; U9.AU18 v4(96.75,83.59)
  BOTTOM w0.114: L31.1 96.6,75.41 95.48,74.3 v1(95.48,74.19)
  BOTTOM w0.381: C312.2 96.01,81.15 v4(95.95,81.22) ; L31.1 96.65,76.12 v2(97.03,76.5) ; C307.2 96.75,83.11 v4(96.75,83.59) v4(95.95,83.59) ; v4(97.55,78.79) v4(97.55,77.99) 97.61,77.93 97.61,76.07 97.89,75.79 C361.2
VDDQ_ADDR_PROT: length 5
  TOP w0.114: C254.1 53.39,5.08 v2(53.57,5.26) 53.68,5.15 54.68,5.15 54.88,5.35 U29.18
  BOTTOM w0.114: R756.1 53.19,4.88 v2(53.57,5.26) 53.19,5.64 v1(52.73,5.64)
VDDQ_CPU_SEN_N: length 53.9
  TOP w0.254: R349.1 v3(58.06,13.21) R358.2
  BOTTOM w0.254: R593.2 58.17,56.61 58.17,55.58 58.8,54.95 58.8,39.04 63.37,34.47 63.37,15.09 60.2,11.91 58.83,11.91 58.28,12.46 58.28,12.99 v3(58.06,13.21) 58.06,14.02 v1(58.21,14.17)
VDDQ_CPU_SEN_N_R: length 2.9
  TOP w0.203: U29.5 58.24,10.31 58.07,10.48 C231.2
  TOP w0.254: R358.1 58.07,11.65 C231.2
VDDQ_CPU_SEN_P: length 52.2
  TOP w0.254: R359.2 v3(59,13.21) R350.2
  BOTTOM w0.254: v1(59.74,13.79) 59.58,13.79 v3(59,13.21) 58.79,12.99 58.79,12.67 59.04,12.42 59.99,12.42 62.87,15.3 62.87,34.26 58.29,38.83 58.29,54.74 57.66,55.37 57.66,56.61 R592.2
VDDQ_CPU_SEN_P_R: length 2.9
  TOP w0.203: U29.4 58.64,10.12 58.98,10.47 C231.1
  TOP w0.254: C231.1 59,10.73 R359.1
VDDQ_RCSM: length 21.1
  TOP w0.114: R320.2 64.84,30.48 v2(65.02,30.66)
  TOP w0.254: R356.2 60.3,14.39 R348.2 60.61,14.99 60.88,15.27 60.88,15.79 61.43,16.33 63.07,16.33 63.6,16.87 63.6,22.4 62.97,23.04 62.97,29.54 63.9,30.48 R320.2
VDDQ_RCSM_R: length 5.1
  TOP w0.203: U29.2 59.44,9.32 59.94,9.83 v2(60.59,9.83)
  TOP w0.254: v2(60.59,9.83) C232.2 60.3,11 R356.1
  BOTTOM w0.114: v1(60.55,10.79) 60.55,9.87 v2(60.59,9.83)
VDDQ_RCSP: length 20.2
  TOP w0.114: v2(65.02,29.34) 64.79,29.57 R320.1
  TOP w0.254: R320.1 63.63,29.57 63.37,29.31 63.37,23.22 64.01,22.58 64.01,16.66 63.27,15.93 61.59,15.93 61.29,15.62 61.29,15.32 61.52,15.08 R348.1 61.7,14.52 R357.2
VDDQ_RCSP_R: length 5.4
  TOP w0.203: U29.1 60.52,8.85 v2(61.5,9.83)
  TOP w0.254: v2(61.5,9.83) C232.1 61.7,10.92 R357.1
  BOTTOM w0.114: v1(61.9,10.79) 61.9,10.23 v2(61.5,9.83)
VDDQ_SVADDR: length 3.7
  TOP w0.114: C238.1 v2(54.51,8.74) 54.86,8.38 54.86,7.99 55.11,7.75 U29.12
  BOTTOM w0.114: R742.1 53.49,8.74 v2(54.51,8.74)
VDDQ_TSEN_N: length 25.5
  TOP w0.254: R326.2 v2(55.91,28.28)
  S8 w0.254: v3(56.36,11.61) 56.18,11.43 55.47,11.43 54.03,12.88 53.02,12.88 51.84,14.05 51.84,16.45 53.8,18.41 53.8,21.74 55.01,22.95 55.01,28.18 55.31,28.48 55.7,28.48 v2(55.91,28.28)
  BOTTOM w0.254: R723.2 55.98,13.51 v1(55.98,12.7) 55.98,11.99 v3(56.36,11.61)
VDDQ_TSEN_P: length 30.2
  TOP w0.203: C221.1 57.18,10.57 v2(56.97,10.36) 56.97,9.91 57.44,9.44 U29.7
  TOP w0.254: R326.1 v2(55.91,29.19)
  S8 w0.254: v2(55.91,29.19) 55.7,28.99 55.1,28.99 54.5,28.39 54.5,23.16 53.29,21.95 53.29,18.62 51.33,16.66 51.33,13.84 52.81,12.37 53.82,12.37 55.26,10.92 56.41,10.92 v2(56.97,10.36)
  BOTTOM w0.254: v2(56.97,10.36) 57.18,10.57 C221.1 v1(58.17,11.25)
VDDQ_VINSEN: length 5.7
  TOP w0.114: U29.11 55.54,8.44 55.07,8.92 55.07,9.09 v2(54.48,9.68) R363.1 R362.2
  BOTTOM w0.114: v1(53.52,11.07) 53.72,10.88 C625.1 54.1,10.06 v2(54.48,9.68)
VSS_VCCSCSUS_SENSE: length 1.2
  TOP w0.089: v4(97.11,59.16) 97.12,59.15 97.12,58.66 97.36,58.42 U9.AR74
1PPS_CPU: length 288.6
  TOP w0.114: v2(121.16,120.02) 120.2,119.06 114.05,119.06 113.43,119.68 110.06,119.68 109.09,120.65 107.91,120.65 107.17,119.9 106.7,119.9 106.08,120.52 88.92,120.52 87.18,118.79 87.18,117.42 88.58,116.01 88.58,109.06 90.21,107.44 90.82,107.44 91.62,108.23 v2(91.62,109.17) ; v4(93.88,89.41) 94.06,89.41 U9.BA5
  S5 w0.102: v2(167.56,14.53) 167.36,14.73 163.58,14.73 156.97,8.13 139.6,8.13 v2(137.77,9.96)
  S10 w0.102: v2(91.62,109.17) 91.87,108.92 91.87,104.22 93.5,102.59 93.5,89.79 v4(93.88,89.41) ; v2(121.16,120.02) 122.5,121.36 143.51,121.36 144.35,120.52 152.22,120.52 153.47,119.28 155.97,119.28 156.27,119.58 161.75,119.58 163.98,117.35 166.55,117.35 169.85,114.05 169.85,113.18 171.58,111.45 171.58,107.12 170.91,106.45 170.91,93.81 177.75,86.97 177.75,83.42 185.34,75.83 185.34,35.87 187.3,33.91 187.3,17.9 183.34,13.94 168.15,13.94 v2(167.56,14.53)
  BOTTOM w0.114: v1(121.03,119) 120.9,119.13 120.9,119.76 v2(121.16,120.02) ; CONN16.89 136.6,8.4 136.6,8.4 136.6,8.84 137.72,9.96 v2(137.77,9.96)
10G_KR_C_RX0_N: length 10
  TOP w0.094: U9.N62 107.23,64.3 v4(107.02,64.3)
  BOTTOM w0.102: v4(107.02,64.3) 107.02,64.16 107.55,63.63 108.46,63.63 108.62,63.78 108.82,63.78 108.97,63.63 109.17,63.63 109.33,63.78 109.53,63.78 109.68,63.63 109.89,63.63 110.04,63.78 110.24,63.78 110.39,63.63 110.6,63.63 110.75,63.78 110.95,63.78 111.1,63.63 111.31,63.63 111.46,63.78 111.66,63.78 111.82,63.63 112.02,63.63 112.17,63.78 112.37,63.78 112.53,63.63 112.73,63.63 112.88,63.78 113.09,63.78 113.24,63.63 113.44,63.63 113.59,63.78 113.8,63.78 113.95,63.63 114.35,63.63 C462.2
10G_KR_C_RX0_P: length 10
  TOP w0.094: U9.R62 106.23,64.3 v4(106.03,64.3)
  BOTTOM w0.102: v4(106.03,64.3) 106.48,64.3 107.43,63.35 114.38,63.35 C472.2
10G_KR_C_RX1_N: length 13.3
  TOP w0.109: U9.T64 105.72,63.46 v4(105.54,63.46)
  BOTTOM w0.102: v4(105.54,63.46) 105.54,63.6 105.03,64.11 105.03,64.4 104.88,64.55 104.88,64.76 105.03,64.91 105.03,65.47 105.85,66.29 114.35,66.29 C440.2
10G_KR_C_RX1_P: length 13.3
  TOP w0.102: v4(106.5,63.46) 106.71,63.46 U9.P64
  BOTTOM w0.102: v4(106.5,63.46) 106.5,63.49 106.13,63.86 105.67,63.86 105.31,64.22 105.31,65.36 105.97,66.01 114.38,66.01 C455.2
10G_KR_RX0_N: length 77.2
  S3 w0.102: v3(132.49,4.7) 132.19,4.7 132.09,4.8 132.09,5.5 130.98,6.6 129.46,6.6 128.17,7.9 128.17,20.07 130.23,22.12 130.23,48.95 127.3,51.87 122.91,51.87 122.73,52.04 120.32,52.04 118.34,54.03 118.34,63.17 117.77,63.74 117.1,63.74 v3(116.73,64.11)
  BOTTOM w0.102: C462.1 116.7,64.13 v3(116.73,64.11) ; v3(132.49,4.7) 132.09,4.7 131.99,4.6 131.99,3.47 132.1,3.36 CONN16.108
10G_KR_RX0_P: length 77.2
  S3 w0.102: v3(131.22,4.7) 131.51,4.7 131.61,4.8 131.61,5.3 130.78,6.12 129.26,6.12 127.69,7.7 127.69,8.31 127.58,8.41 127.58,8.64 127.69,8.74 127.69,8.97 127.58,9.07 127.58,9.3 127.69,9.4 127.69,9.63 127.58,9.73 127.58,9.96 127.69,10.06 127.69,10.29 127.58,10.39 127.58,10.62 127.69,10.72 127.69,10.95 127.58,11.05 127.58,11.28 127.69,11.38 127.69,11.61 127.58,11.71 127.58,11.94 127.69,12.04 127.69,12.27 127.58,12.37 127.58,12.6 127.69,12.7 127.69,12.93 127.58,13.03 127.58,13.26 127.69,13.36 127.69,13.59 127.58,13.69 127.58,13.92 127.69,14.02 127.69,20.27 129.74,22.32 129.74,48.75 127.1,51.38 122.71,51.38 122.53,51.56 120.12,51.56 117.86,53.83 117.86,62.97 117.57,63.26 117.1,63.26 v3(116.73,62.89)
  BOTTOM w0.102: v3(116.73,62.89) 115.79,62.89 C472.1 ; v3(131.22,4.7) 131.61,4.7 131.71,4.6 131.71,3.47 131.6,3.36 CONN16.110
10G_KR_RX1_N: length 80.1
  S3 w0.102: v3(134.49,3.78) 134.19,3.78 134.09,3.89 134.09,6.29 132.51,7.87 130.38,7.87 129.49,8.76 129.49,18.92 131.7,21.13 131.7,49.83 126.26,55.27 121.21,55.27 119.43,57.05 119.43,64.54 117.56,66.41 117.1,66.41 v3(116.73,66.78)
  BOTTOM w0.102: v3(116.73,66.78) 116.7,66.8 C440.1 ; CONN16.100 134.1,3.36 133.99,3.47 133.99,3.68 134.09,3.78 v3(134.49,3.78)
10G_KR_RX1_P: length 80
  S3 w0.102: v3(133.22,3.78) 133.51,3.78 133.61,3.89 133.61,6.09 132.31,7.39 130.18,7.39 129.01,8.56 129.01,8.95 128.88,9.08 128.88,9.31 129.01,9.44 129.01,9.67 128.88,9.79 128.88,10.02 129.01,10.15 129.01,10.38 128.88,10.5 128.88,10.73 129.01,10.86 129.01,11.09 128.88,11.22 128.88,11.44 129.01,11.57 129.01,11.8 128.88,11.93 128.88,12.15 129.01,12.28 129.01,12.51 128.88,12.64 128.88,12.87 129.01,12.99 129.01,13.22 128.88,13.35 128.88,13.58 129.01,13.7 129.01,19.12 131.22,21.33 131.22,49.63 126.06,54.79 121.01,54.79 118.95,56.85 118.95,64.34 117.36,65.92 117.1,65.92 v3(116.73,65.55)
  BOTTOM w0.102: v3(133.22,3.78) 133.61,3.78 133.71,3.68 133.71,3.47 133.6,3.36 CONN16.102 ; v3(116.73,65.55) 115.79,65.55 C455.1
10G_KR_TX0_N: length 83.8
  TOP w0.094: v4(109,64.3) U9.J62
  TOP w0.102: v3(132,17.2) 131.47,16.67 131.47,13.69 129.42,11.64 129.42,6.9 130.01,6.31 130.01,5.71 130.19,5.54 130.19,5.23 130.01,5.05 130.01,3.89 130.11,3.78 v3(130.51,3.78)
  S10 w0.102: v3(132,17.2) 131.61,16.8 131.61,16.22 131.14,15.75 130.41,15.75 129.29,16.87 129.29,50.14 124.06,55.37 119.84,55.37 117.75,57.46 117.75,61.09 117.36,61.48 116.52,61.48 115.24,62.76 113.19,62.76 112.4,63.55 109.75,63.55 v4(109,64.3)
  BOTTOM w0.102: CONN16.116 130.1,3.36 130.01,3.45 130.01,3.68 130.11,3.78 v3(130.51,3.78)
10G_KR_TX0_P: length 83.7
  TOP w0.094: v4(109.99,64.3) U9.F62
  TOP w0.102: v3(130.73,17.2) 131.19,16.74 131.19,13.81 129.14,11.75 129.14,6.79 129.73,6.2 129.73,3.89 129.63,3.78 v3(129.24,3.78)
  S10 w0.102: v3(130.73,17.2) 131.12,16.8 131.12,16.42 130.94,16.23 130.61,16.23 129.77,17.07 129.77,18.88 130,19.11 130,19.34 129.77,19.57 129.77,19.79 130,20.02 130,20.25 129.77,20.48 129.77,20.71 130,20.94 130,21.17 129.77,21.4 129.77,21.62 130,21.85 130,22.08 129.77,22.31 129.77,22.54 130,22.77 130,23 129.77,23.22 129.77,23.45 130,23.68 130,23.91 129.77,24.14 129.77,24.37 130,24.6 130,24.82 129.77,25.05 129.77,25.28 130,25.51 130,25.74 129.77,25.97 129.77,26.2 130,26.42 130,26.65 129.77,26.88 129.77,27.11 130,27.34 130,27.57 129.77,27.8 129.77,28.02 130,28.25 130,28.48 129.77,28.71 129.77,50.34 124.26,55.85 120.04,55.85 118.24,57.66 118.24,61.29 117.56,61.97 116.72,61.97 115.44,63.25 113.39,63.25 112.6,64.03 110.26,64.03 v4(109.99,64.3)
  BOTTOM w0.102: v3(129.24,3.78) 129.63,3.78 129.73,3.68 129.73,3.49 129.6,3.36 CONN16.118
10G_KR_TX1_N: length 80.3
  TOP w0.102: v3(136.49,4.7) 136.09,4.7 135.99,4.8 135.99,12.85 135.97,12.88 135.97,12.88 135.99,12.91 135.99,12.93 v3(136.4,13.34) ; U9.J66 109.26,62.3 v4(109,62.56)
  S10 w0.102: v3(136.4,13.34) 135.99,13.74 135.99,14.58 135.38,15.19 128.11,15.19 124.16,19.15 124.16,34.82 119.68,39.29 119.68,52.37 115.52,56.54 115.52,59.46 114.1,60.88 114.1,60.89 113.59,61.39 113.59,61.39 111.94,63.04 109.48,63.04 v4(109,62.56)
  BOTTOM w0.102: v3(136.49,4.7) 136.09,4.7 135.99,4.6 135.99,3.47 136.1,3.36 CONN16.92
10G_KR_TX1_P: length 80.3
  TOP w0.102: v3(135.22,4.7) 135.61,4.7 135.71,4.8 135.71,12.75 v3(135.13,13.34) ; U9.F66 110.25,62.3 v4(109.99,62.56)
  S10 w0.102: v4(109.99,62.56) 111.74,62.56 113.39,60.91 113.39,60.91 113.61,60.69 113.61,60.68 115.04,59.26 115.04,56.34 119.2,52.17 119.2,39.09 123.67,34.62 123.67,18.95 124.44,18.18 124.44,18.08 124.44,18.08 124.44,17.98 124.6,17.82 124.7,17.82 124.8,17.82 124.96,17.66 124.96,17.56 124.96,17.56 124.96,17.45 125.12,17.29 125.23,17.29 125.23,17.29 125.33,17.29 125.49,17.13 125.49,17.03 125.49,16.93 125.65,16.77 125.75,16.77 125.75,16.77 125.85,16.77 126.02,16.6 126.02,16.5 126.02,16.4 126.18,16.24 126.28,16.24 126.28,16.24 126.38,16.24 126.54,16.08 126.54,15.98 126.54,15.88 126.7,15.71 126.8,15.71 126.81,15.71 126.91,15.71 127.07,15.55 127.07,15.45 127.07,15.45 127.07,15.35 127.23,15.19 127.33,15.19 127.43,15.19 127.91,14.71 128.65,14.71 128.9,14.45 129.13,14.45 129.38,14.71 129.61,14.71 129.87,14.45 130.09,14.45 130.35,14.71 130.58,14.71 130.83,14.45 131.06,14.45 131.31,14.71 131.54,14.71 131.8,14.45 132.03,14.45 132.28,14.71 132.51,14.71 132.76,14.45 132.99,14.45 133.24,14.71 133.47,14.71 133.73,14.45 133.96,14.45 134.21,14.71 135.18,14.71 135.51,14.38 135.51,13.72 v3(135.13,13.34)
  BOTTOM w0.102: CONN16.94 135.6,3.36 135.71,3.47 135.71,4.6 135.61,4.7 v3(135.22,4.7)
A_VCCDUSBSUS_P1V05: length 7.7
  TOP w0.108: v4(99.95,85.21) 99.95,85.25 99.61,85.59 U9.AK14
  BOTTOM w0.114: v1(104.9,86.39) 104.42,86.39 103.99,85.95 103.99,85.42 C301.2 103.78,84.96 103.61,84.79 102.92,84.79 102.84,84.86 101.83,84.86 101.75,84.79 101.12,84.79 100.7,85.21 v4(99.95,85.21)
ADR_MCU_INIT: length 161.4
  TOP w0.114: U12.C7 v3(194.09,60.61)
  S3 w0.102: v3(194.09,60.61) 194.09,61.02 193.71,61.4 193.71,64.85 193.95,65.09 193.95,65.99 193.17,66.77 193.17,69.56 184.67,78.05 183.43,78.05 177.72,83.76 177.72,87.35 173.51,91.56 173.51,100.41 169.17,104.75 154.25,104.75 150.85,108.15 149.62,108.15 148.09,109.68 132.81,109.68 131.75,108.61 122.6,108.61 120.5,106.5 116,106.5 114.43,108.07 114.43,109.87 113.42,110.87 108.43,110.87 102.64,116.66 98.44,116.66 98.01,116.23 94.87,116.23 93.27,117.83 91,117.83 88.47,115.3 88.47,110.08 88.06,109.68 88.06,105.38 v2(88.52,104.93)
  BOTTOM w0.114: v3(194.09,60.61) 193.57,61.12 v1(193.57,62.79) ; v2(88.52,104.93) 88.65,104.8 R479.1
ADR_STATUS_CLR: length 220.5
  TOP w0.114: U12.D13 v3(201.09,59.61)
  S3 w0.102: v3(201.09,59.61) 201.6,60.12 201.6,63.09 202.44,63.93 203.61,63.93 204.34,64.67 204.34,67.41 202.28,69.47 202.28,78.46 201.48,79.27 200.78,79.97 200.78,92.85 201.12,93.2 201.12,98.28 195.98,103.42 190.86,103.42 185.63,108.65 185.63,113.77 183.26,116.14 175.73,116.14 174.96,116.92 170.41,116.92 169.67,116.18 166.66,116.18 166.11,116.73 157.99,116.73 156.77,117.96 153.03,117.96 152.37,117.3 144.4,117.3 140.29,121.41 69.14,121.41 68.74,121.01 67.72,119.99 67.72,119.61 67.72,117.94 70.51,115.14 70.51,114.81 71.6,113.72 72.39,113.72 72.77,114.1 73.51,114.1 73.79,113.82 73.79,112.8 76,110.59 76,109.85 76.52,109.32 76.86,109.32 77.29,108.89 77.29,106.91 78.28,105.92 78.28,102.97 78.49,102.77 79.02,102.77 79.91,103.66 v2(80.29,103.66)
  BOTTOM w0.114: v3(201.09,59.61) 200.82,59.61 200.56,59.87 v1(200.56,62.48) ; R482.1 v2(80.29,103.66)
ADR_STATUS_CLR_R: length 20.3
  TOP w0.102: U9.BL2 90.13,91.42 90.13,92.75
  TOP w0.114: 90.13,92.75 90.02,92.87 90.02,93.52 89.79,93.75 89.79,95.28 85.61,99.45 85.61,99.45 84.34,99.45 82.14,101.65 81.86,101.65 81.03,102.49 R115.2 v2(80.29,102.75)
  BOTTOM w0.114: v2(80.29,102.75) R115.2 v1(81.03,101.68) 81.03,101.55 R516.2
ADR_STATUS_RD_R: length 28.5
  TOP w0.114: R38.2 v2(81.46,109.7) ; v2(87,93.17) 87,92.99 87.46,92.53 U9.BT1
  S10 w0.102: v2(81.46,109.7) 81.46,109.19 82.58,108.08 82.58,104.84 83.52,103.9 83.52,103.52 83.22,103.23 82.87,103.23 82.6,102.96 82.6,100.37 87,95.98 v2(87,93.17)
  BOTTOM w0.114: v1(87.12,94.2) 87.12,93.29 v2(87,93.17) ; R521.2 81.44,112.81 80.26,111.62 80.26,111.13 80.87,110.52 R38.2 v2(81.46,109.7)
ALL_POWER_OFF: length 25.8
  BOTTOM w0.114: R941.1 R939.1 23.4,80.87 20.27,80.87 19.32,79.93 19.32,79.49 18.15,78.32 18.15,67.83 17.04,66.72 14.92,66.72 14.66,66.98 CONN14.40
ALL_POWER_RESET: length 30.4
  BOTTOM w0.114: R938.1 24.79,81.92 ; 24.79,81.92 R940.1 20.46,81.99 19.01,80.55 19.01,79.55 17.91,78.45 17.91,67.94 17.07,67.11 15.93,67.11 15.39,67.65 14.92,67.65 14.85,67.58 CONN14.38 ; 24.79,81.92 25.19,81.53 27.14,81.53 27.48,81.86 27.48,82.08 28.33,82.93 v1(28.83,82.93)
B2B_PROCHOT_N: length 88.6
  TOP w0.114: U12.M7 v3(194.09,50.61)
  S5 w0.102: v3(194.09,50.61) 193.55,50.07 193.55,48.44 192.96,47.85 191.97,47.85 190.52,46.41 190.52,45.41 188.62,43.51 188.62,35.33 180.12,26.82 179.96,26.82 178.89,25.75 178.89,25.6 176.81,23.52 176.81,23.04 174.75,20.99 174.75,20.78 173.46,19.48 172.1,19.48 169.89,17.27 169.89,14.77 166.98,11.87 161.41,11.87 157.12,7.58 139.31,7.58 v2(137.77,9.12)
  BOTTOM w0.114: v1(193.65,47.75) 193.65,50.17 v3(194.09,50.61) ; v2(137.77,9.12) 137.6,8.95 CONN16.85
B2B_THERMTRIP_N: length 95.8
  TOP w0.114: v3(148.1,3.66) 149.03,2.73 157.7,2.73 158.7,3.73 160.32,3.73 161.9,5.31 163.65,5.31 v2(164.92,4.04) ; U12.L11 v3(199.09,51.61)
  S10 w0.102: v2(164.92,4.04) 165.1,4.04 172.77,11.71 183.26,11.71 185.12,13.56 185.39,13.56 188.36,16.54 188.36,16.65 190.68,18.97 190.68,37.92 194.39,41.63 195.81,41.63 197.78,43.6 199.36,43.6 200.05,44.29 200.05,45.12 199.49,45.67 199.49,51.18 199.09,51.58 v3(199.09,51.61)
  BOTTOM w0.114: v3(199.09,51.61) 199.59,52.12 199.59,54.15 200.03,54.58 v1(200.58,54.58)
  BOTTOM w0.127: CONN16.44 v3(148.1,3.66)
BDX_BIOS_SPI_CLK: length 3.2
  TOP w0.114: v2(111.38,113.03) 111.25,113.03 110.99,112.77 U43.6
  BOTTOM w0.114: v1(111.25,112.25) 111.26,112.27 111.26,112.92 v2(111.38,113.03) 111.51,113.16 R926.2
BDX_BIOS_SPI_MISO: length 2.3
  TOP w0.114: U43.13 109.69,118.54 109.49,118.75 v3(109.22,118.75)
  BOTTOM w0.114: R930.2 109.27,118.8 v3(109.22,118.75)
BDX_BIOS_SPI_MOSI: length 3.6
  TOP w0.114: v3(111.89,118.75) 111.64,118.5 U43.10
  BOTTOM w0.114: v3(111.89,118.75) 111.89,119.05 112,119.16 112.11,119.16 112.51,119.56 R928.2 113.23,119.56 v1(113.56,119.89)
BDX_CATERR_N: length 90.8
  TOP w0.108: U9.Y67 103.74,61.75 v4(103.58,61.75)
  TOP w0.114: U14.9 176.2,50.1 v2(176.83,49.48) 176.96,49.34 R210.1
  S5 w0.102: v4(103.58,61.75) 103.96,62.13 112.7,62.13 113.56,61.26 118.85,61.26 119.23,60.88 121.01,60.88 125.88,56.01 125.88,52.63 128.83,49.68 128.83,48.01 v2(128.75,47.93)
  S8 w0.102: v2(176.83,49.48) 175.44,48.08 170.14,48.08 166.11,52.12 132.94,52.12 v2(128.75,47.93)
  BOTTOM w0.114: v1(178.05,48.51) 177.09,49.48 v2(176.83,49.48)
BDX_CPLD_INT_CPU: length 285.4
  TOP w0.114: U9.AV7 96.31,88.91 v4(96.62,88.6) ; v2(189.69,74.68) 189.84,74.53 R876.1 189.38,72.75 189.35,72.72 R921.2
  S3 w0.102: v2(36.75,117.25) 36.75,113.64 36.37,113.26 36.37,109.65 40.01,106.02 40.01,103.48 39.27,102.74 33.35,102.74 32.18,101.57 26.54,101.57 23.83,98.86 23.83,91.36 26.21,88.98 26.21,86.31 26.52,86.01 v2(26.52,82.98) ; v4(96.62,88.6) 97.32,89.3 97.32,91.9 96.54,92.69 96.54,94.76 96.85,95.07 96.85,96.57 96.57,96.85 96.57,106.22 97.16,106.81 97.16,106.81 97.48,107.14 97.49,107.14 98.07,107.72 103.59,107.72 104.56,106.76 107.41,106.76 107.97,106.2 107.97,101.7 108.46,101.22 112.22,101.22 112.67,100.76 113.61,100.76 115.54,98.83 115.54,96.48 121.4,90.63 125.48,90.63 130.28,85.84 130.28,85.37 133.43,82.22 135.61,82.22 136.42,81.41 148.92,81.41 152.88,77.44 v2(156.82,77.44)
  S5 w0.102: v4(96.62,88.6) 96.62,89.16 95.63,90.15 95.63,90.2 95.53,90.3 94.74,90.3 92.3,92.73 92.3,101.24 91.95,101.6 91.95,107.95 93.09,109.09 93.09,115.32 92.84,115.57 92.65,115.57 91.44,116.78 v2(91.44,116.97)
  S8 w0.102: v2(189.69,74.68) 182.98,74.68 174.4,83.26 174.4,85.22 172.44,87.17 168.3,87.17 165.2,84.07 165.2,81 161.65,77.44 v2(156.82,77.44)
  S10 w0.102: v2(91.44,116.97) 74.9,116.97 74.11,117.75 57.01,117.75 56.1,118.67 54.01,118.67 53.59,118.25 53.59,118.02 53.33,117.75 52.08,117.75 51.8,117.47 36.98,117.47 v2(36.75,117.25)
  BOTTOM w0.114: R937.2 v2(26.52,82.98) ; v1(189.69,73.78) v2(189.69,74.68)
BDX_CPLD_INT_CPU_R: length 13.7
  TOP w0.114: R876.2 v2(189.84,70.76) 191.41,69.19 193.18,69.19 194.36,68.01 194.36,62.34 U12.A7
  BOTTOM w0.114: v1(188.86,70.76) v2(189.84,70.76)
BDX_CPLD_JTAG_ENABLE: length 279.9
  TOP w0.114: U21.5 194.98,18.94 195.15,18.77 196.65,18.77 196.88,19 U21.2 ; v2(69.22,118.49) 68.58,118.49 67.71,119.36 63.86,119.36 63.45,118.95 v2(63.45,118.34) ; v2(196.88,21.04) 197.55,21.04 198.12,20.47 198.12,17.58 197.1,16.56 197.1,15.67 196.88,15.45 U21.15
  TOP w0.127: U21.2 v2(196.88,21.04) ; U21.15 196.88,13.19 196.47,12.78 195.28,12.78 194.98,13.07 U21.12
  S3 w0.102: v2(196.88,21.04) 196.88,21.22 200.05,24.39 200.05,41.74 199.13,42.67 199.13,44.89 197.7,46.32 197.7,61.86 197.61,61.95 197.61,66.32 195.01,68.92 195.01,79.77 185.3,89.47 182.98,89.47 175.81,96.64 175.81,101.16 170.29,106.68 163.6,106.68 158.55,111.73 157.56,111.73 156.29,113 139.49,113 134.18,118.31 113.64,118.31 112.52,119.43 108.11,119.43 108.03,119.51 106.64,119.51 105.93,120.22 70.94,120.22 v2(69.22,118.49) ; v2(63.45,118.34) 63.27,118.16 63.27,116.75 65.68,114.33 65.68,108.17 70.94,102.91 70.94,102.05 70.87,101.97 v2(70.87,101.47)
  BOTTOM w0.114: R131.1 88.39,96.39 85.42,99.36 75.46,99.36 73.35,101.47 v2(70.87,101.47) ; v2(69.22,118.49) 69.22,117.2 v1(69.05,117.03) ; R869.1 197.1,21.26 v2(196.88,21.04) 196.67,20.83 R665.1
BDX_CPLD_JTAG_ENABLE_R: length 19.2
  TOP w0.102: 91.16,93.37 90.93,93.14 90.93,91.69 90.58,91.34 90.58,91.07 90.92,90.72
  TOP w0.114: R114.2 v2(83.06,102.77) 83.06,102.7 91.16,94.6 91.16,93.37 ; U9.BJ4 90.92,90.72
  BOTTOM w0.114: v1(82.07,103.53) R500.2 82.77,102.49 v2(83.06,102.77)
BDX_CPLD_JTAG_MUX_ENABLE: length 151.9
  TOP w0.114: v2(199.21,103.8) R849.2 U7.1
  S5 w0.102: v2(199.21,103.8) 192.01,103.8 191.2,104.61 191.2,114.21 190.14,115.27 188.98,115.27 186.51,117.73 182.09,117.73 181.86,117.96 181.29,117.96 177.53,121.72 163.53,121.72 162.03,120.22 157.48,120.22 156.36,121.34 114.86,121.34 113.84,120.31 v2(113.84,117.1)
  S8 w0.102: v2(83.06,102.03) 83.07,102.02 84.37,102.02 85.39,103.05 88.11,103.05 88.34,102.82 89.66,102.82 90.6,101.88 91.68,101.88 93.24,103.44 93.24,103.48 94.97,105.21 95.76,105.21 97.28,106.73 97.28,106.76 97.53,107.01 97.66,107.01 98.98,108.33 98.98,109.4 99.44,109.86 104.65,109.86 105.95,111.15 112.03,111.15 113.54,112.66 113.54,115.08 113.51,115.1 113.15,115.47 113.15,116.59 113.66,117.1 v2(113.84,117.1)
  BOTTOM w0.114: v2(199.21,103.8) 198.92,103.51 v1(198.92,102.71) ; v2(83.06,102.03) 82.6,101.58 R500.1
BDX_CPLD_JTAG_R_TCK: length 12.7
  TOP w0.102: v2(90.17,99.01) 90.17,98.68 93.6,95.26 93.6,92.66 93.11,92.17 93.11,91.55 93.4,91.26 U9.BD3
  TOP w0.114: R124.2 v2(90.17,99.01)
  BOTTOM w0.114: v1(91.29,99.77) R124.2 v2(90.17,99.01)
BDX_CPLD_JTAG_R_TDI: length 25.5
  TOP w0.102: 92.46,92.84 92.12,92.5 92.12,91.5 92.26,91.36 92.26,91.35 92.33,91.29 92.33,90.8 U9.BF3
  TOP w0.114: 92.46,92.84 92.46,95.01 86.87,100.6 86.87,101.7 v2(87.76,102.59) 87.5,102.85 R104.2
  BOTTOM w0.114: R104.2 87.5,102.85 v2(87.76,102.59) 88.53,101.82 88.96,101.82 89.29,101.49 89.29,98.6 90.84,97.05 v1(92.84,97.05)
BDX_CPLD_JTAG_R_TDO: length 13.1
  TOP w0.102: 92.74,92.81 92.41,92.48 U9.BF1
  TOP w0.114: 92.74,92.81 92.74,95.07 88.55,99.26 R121.2 88.04,100.1 v2(87.71,100.43)
  BOTTOM w0.114: v1(88.7,99.04) 88.55,99.19 R121.2 88.04,100.1 v2(87.71,100.43)
BDX_CPLD_JTAG_R_TMS: length 34.3
  TOP w0.114: v4(88.93,89.51) 88.93,90.22 U9.BN4 ; R27.2 v2(74.75,112.88)
  S5 w0.102: v2(74.75,112.88) 74.87,112.75 74.87,112.01 75.71,111.18 75.71,106.15 75.34,105.78 75.34,103.39 77.26,101.48 78.23,101.48 79.61,100.09 80.08,100.09 81.51,98.66 83.2,96.97 84.39,96.97 88.06,93.3 88.06,90.39 v4(88.93,89.51)
  BOTTOM w0.114: v1(75.26,112.04) 75.26,112.37 v2(74.75,112.88) R27.2
BDX_CPLD_JTAG_TCK: length 150.6
  TOP w0.114: v2(183.54,42.15) 184.53,41.16 184.53,34.61 189.28,29.86 191.5,29.86 196.25,25.11 196.25,21.89
  TOP w0.127: 196.25,21.89 U21.3
  S5 w0.102: v2(200.66,96.68) 199.3,95.31 199.3,92.97 198.69,92.37 197.3,92.37 196.65,93.02 196.65,96.83 192.29,101.19 176.56,101.19 174.17,103.58 174.17,105.66 171.6,108.22 171.6,109.13 171.2,109.52 170.84,109.52 170.13,108.81 170.13,107.01 168.83,105.71 v2(168.83,103.86)
  S10 w0.102: v2(183.54,42.15) 184.4,43.01 184.4,75.44 176.1,83.74 176.1,86.26 169.72,92.63 169.72,103.17 169.04,103.86 v2(168.83,103.86)
  BOTTOM w0.114: R133.1 v2(200.66,96.68) v1(200.66,97.68)
BDX_CPLD_JTAG_TCK_MUX: length 141.7
  TOP w0.114: R124.1 90.5,101 90.5,101.85 90.2,102.16 90.2,102.57 90.93,103.3 90.93,104.83 v2(90.4,105.36) ; v2(196.87,100.3) 196.87,97.93 197.79,97.01 U7.4
  S5 w0.102: v2(196.87,100.3) 195.28,101.89 176.82,101.89 174.85,103.86 174.85,105.94 172.44,108.36 172.44,110.82 170.31,112.95 v2(168.73,112.95)
  S8 w0.102: v2(125.86,120.02) 124.92,120.95 114.58,120.95 112.73,119.1 112.73,117.14 112.66,117.07 112.47,116.88 112.47,115.18 112.73,114.92 112.85,114.8 112.85,112.94 111.75,111.84 105.66,111.84 104.37,110.54 99.16,110.54 98.37,109.76 98.09,109.48 98.09,108.48 97.31,107.7 97.25,107.7 96.51,106.96 95.53,106.96 95.15,107.34 92.38,107.34 v2(90.4,105.36)
  S10 w0.102: v2(125.86,120.02) 126.16,120.32 143.55,120.32 144.74,119.13 148.76,119.13 149.45,118.44 157.09,118.44 157.52,118.87 161.45,118.87 164.53,115.8 165.9,115.8 166.32,115.37 166.32,115.36 v2(168.73,112.95)
  BOTTOM w0.114: v2(125.86,120.02) 126.57,120.02 126.68,119.91 127.04,119.91 v1(127.22,119.73)
BDX_CPLD_JTAG_TCK_R: length 6.8
  TOP w0.114: U7.3 v2(197.94,97.66)
  BOTTOM w0.114: v1(197.86,101.17) 197.86,100.1 197.2,99.45 197.2,98.05 197.58,97.66 v2(197.94,97.66) 198.02,97.58 R133.2
BDX_CPLD_JTAG_TDI: length 3.6
  TOP w0.114: U21.14 196.25,13.8 v2(195.73,13.28)
  BOTTOM w0.114: R149.1 195.63,13.39 v2(195.73,13.28) 196.13,12.89 v1(196.84,12.89)
BDX_CPLD_JTAG_TDI_MUX: length 155.4
  TOP w0.114: v2(200.13,103.22) 201.57,101.78 201.57,96.63 203.79,94.41 U7.9
  S5 w0.102: v2(200.13,103.22) 192.14,103.22 190.97,104.39 190.97,114.12 190.05,115.04 188.88,115.04 186.42,117.5 181.42,117.5 177.43,121.49 163.62,121.49 162.12,119.99 157.39,119.99 156.32,121.06 123.93,121.06 123.83,120.95 v2(123.83,120.02)
  S8 w0.102: v2(123.83,120.02) 123.34,120.5 114.77,120.5 113.18,118.91 113.18,116.95 112.93,116.69 112.93,115.37 113.18,115.11 113.31,114.99 113.31,112.75 111.94,111.38 105.85,111.38 104.56,110.08 99.35,110.08 98.76,109.49 98.76,108.49 97.5,107.24 97.44,107.24 97.05,106.85 97.05,106.83 95.74,105.51 93.78,105.51 93.37,105.92 92.67,105.92 91.8,105.04 91.8,104.23 90.61,103.05 89.51,103.05 v2(87.38,105.18)
  BOTTOM w0.114: v2(123.83,120.02) 123.7,119.89 123.7,119.25 v1(123.57,119.13) ; R475.1 87.5,105.06 v2(87.38,105.18)
BDX_CPLD_JTAG_TDI_R: length 94.4
  TOP w0.114: U7.10 203.95,95.06 v2(203.48,95.53)
  S10 w0.102: v2(203.48,95.53) 202.36,94.41 202.36,93.06 203.73,91.69 203.73,89.82 201.12,87.21 201.12,82.07 204.95,78.23 204.95,69.17 207.34,66.79 207.34,30.84 203.25,26.75 203.25,25.43 200.96,23.14 198.98,23.14 197.46,21.62 197.46,17.96 v2(195.81,16.31)
  BOTTOM w0.114: v2(203.48,95.53) 204.14,94.87 v1(204.62,94.87) ; R149.2 195.63,16.13 v2(195.81,16.31)
BDX_CPLD_JTAG_TDO: length 96.1
  TOP w0.114: U21.6 v2(194.34,21.79)
  S10 w0.102: v2(194.34,21.79) 193.8,22.34 193.8,25.04 196.24,27.48 201.22,27.48 206.43,32.69 206.43,47.65 203.61,50.47 203.61,54.31 206.3,57 206.3,60.58 205.44,61.44 205.44,67.41 204.04,68.8 204.04,76.21 201.4,78.86 201.4,79.73 200.1,81.03 200.1,87.63 201.22,88.75 201.22,97.76 v2(203.05,99.6)
  BOTTOM w0.114: R151.1 v2(203.05,99.6) v1(203.05,100.55)
BDX_CPLD_JTAG_TDO_MUX: length 159.1
  TOP w0.114: R121.1 87.92,101.01 v2(87.76,101.17) ; v2(198.52,93.21) 198.92,92.81 206.02,92.81 206.91,93.7 206.91,95.68 206.23,96.36 U7.12
  S5 w0.102: v2(164.97,112.57) 165.86,111.68 171.25,111.68 172.21,110.73 172.21,108.26 174.62,105.85 174.62,103.77 176.75,101.64 192.58,101.64 198.52,95.7 v2(198.52,93.21)
  S10 w0.102: v2(133.86,112.9) 133.93,112.98 134.97,112.98 139.59,117.6 162.08,117.6 164.49,115.19 164.49,113.06 v2(164.97,112.57)
  BOTTOM w0.114: v2(133.86,112.9) 133.59,112.64 128.75,112.64 127.37,111.25 127.37,108.54 125.78,106.95 122.78,106.95 117.18,101.35 v1(112.14,101.35) 111.79,100.99 111.79,99.06 110.88,98.15 105.11,98.15 103.78,96.82 103.78,95.96 102.49,94.67 101.83,94.67 101.32,94.16 101.32,93.6 100.99,93.27 100.41,93.27 99.89,93.78 99.01,93.78 98.84,93.61 97.75,93.61 97.43,93.94 97.43,94.21 96.27,95.38 91.31,95.38 87.2,99.49 87.2,100.61 v2(87.76,101.17)
BDX_CPLD_JTAG_TDO_R: length 3.4
  TOP w0.114: U7.13 v2(203.84,97.01)
  BOTTOM w0.114: v1(204.6,96.27) 204.57,96.27 v2(203.84,97.01) 203.1,97.75 R151.2
BDX_CPLD_JTAG_TMS: length 145.9
  TOP w0.114: 194.61,15.7 194.61,16.05 193.6,17.07 193.14,17.07 191.39,18.82 191.39,22.89 184.2,30.07 184.2,40.44 v2(183.51,41.12)
  TOP w0.127: 194.61,15.7 194.34,15.43 U21.11
  S5 w0.102: v2(169.6,110.03) 171.02,110.03 171.83,109.22 171.83,108.32 174.4,105.75 174.4,103.67 176.65,101.41 192.39,101.41 197.97,95.83 v2(197.97,95.43)
  S10 w0.102: v2(183.51,41.12) 184.63,42.24 184.63,75.53 176.35,83.81 176.35,86.33 169.95,92.74 169.95,109.68 v2(169.6,110.03)
  BOTTOM w0.114: R135.1 198.25,95.71 v2(197.97,95.43) 197.97,94.87 v1(198.45,94.38)
BDX_CPLD_JTAG_TMS_MUX: length 173.3
  TOP w0.114: v2(200.11,102.21) 201.33,100.98 201.33,95.54 200.86,95.06 U7.7 ; R27.1 73.11,113.58 v2(73.05,113.64)
  S5 w0.102: v2(200.11,102.21) 192.83,102.21 190.74,104.3 190.74,114.02 189.95,114.81 188.79,114.81 186.32,117.27 181.33,117.27 177.34,121.26 166.12,121.26 165.9,121.04 165.9,120.66 165.63,120.4 165.25,120.4 164.99,120.66 164.99,121.04 164.77,121.26 164,121.26 162.38,119.63 158.55,119.63 157.35,118.44 154.36,118.44 152.04,120.75 125.7,120.75 v2(124.97,120.02)
  S8 w0.102: v2(73.05,113.64) 75.56,111.12 75.56,108.83 79.28,105.11 81.13,105.11 82.42,106.4 88.67,106.4 90.17,104.9 90.79,104.9 92.03,106.15 93.47,106.15 93.87,105.74 95.64,105.74 96.82,106.92 96.82,106.95 97.35,107.47 97.41,107.47 98.53,108.59 98.53,109.59 99.25,110.31 104.46,110.31 105.76,111.61 111.84,111.61 113.08,112.85 113.08,114.89 112.95,115.02 112.7,115.28 112.7,116.78 112.89,116.98 112.95,117.04 112.95,119 114.68,120.73 124.26,120.73 v2(124.97,120.02)
  BOTTOM w0.114: v2(124.97,120.02) 124.97,119.24 125.08,119.13 v1(125.09,119.13)
BDX_CPLD_JTAG_TMS_R: length 3.4
  TOP w0.114: U7.6 v2(200.58,95.71)
  BOTTOM w0.114: v1(201.7,95.25) 201.05,95.25 v2(200.58,95.71) R135.2
BDX_CPU2PCH_THROT: length 143.6
  TOP w0.108: U9.AL74 99.34,58.05 99.05,58.34 v4(98.83,58.34)
  TOP w0.114: R284.2 v2(97.49,43.38) R275.1 ; U10.9 176.15,68.85 176.73,68.27 177.09,68.27 177.28,68.45 177.8,68.45 178.72,69.37 180.41,69.37 v2(180.85,68.94)
  S8 w0.102: v2(97.49,43.38) 97.49,42.7 98.27,41.91 98.27,39.71 98.48,39.51 98.48,38.96 99.47,37.97 99.47,37.96 99.73,37.69 99.75,37.69 101.39,36.05 101.39,35.11 101.8,34.7 123.61,34.7 124.12,35.2 132.04,35.2 138.75,41.91 155.82,41.91 159.53,45.62 178.99,45.62 179.09,45.72 179.1,45.72 180.85,47.47 180.85,47.48 180.9,47.53 180.9,63.3 180.19,64.01 180.19,65.9 180.92,66.64 180.92,66.81 181.33,67.22 181.33,68.45 v2(180.85,68.94)
  S10 w0.102: v2(97.49,43.38) 97.03,43.84 97.03,46.81 97.1,46.89 97.1,48.69 97.03,48.77 97.03,51.38 97.26,51.61 97.26,56.44 98.83,58.01 v4(98.83,58.34)
  BOTTOM w0.114: v2(97.49,43.38) 97.49,41.96 v1(97.76,41.68)
BDX_CPU_ERROR_0: length 84.4
  TOP w0.114: v2(103.08,49.94) 103.2,50.07 R241.1 ; U14.5 174.2,50.2 173.71,49.71 v2(173.58,49.71) 173.58,49.35 173.2,48.97 R204.1
  S3 w0.102: v2(125.68,48.21) 125.68,48.16 125.35,47.83 120.35,47.83 120.12,47.6 118.42,47.6 118.16,47.33 118.16,47.26 117.53,46.63 116.33,46.63 115.27,45.57 104.11,45.57 103.84,45.85 103.84,49.68 103.58,49.94 v2(103.08,49.94)
  S8 w0.102: v2(173.58,49.71) 173.58,49.68 172.67,48.77 170.43,48.77 166.39,52.81 130.3,52.81 125.7,48.21 v2(125.68,48.21)
  BOTTOM w0.114: v1(172.97,48.51) 173.58,49.12 v2(173.58,49.71)
BDX_CPU_ERROR_1: length 82.2
  TOP w0.114: R254.1 v2(102.21,46.84) ; R206.1 174.14,49.45 v2(174.37,49.68) 174.7,50.01 U14.6
  S3 w0.102: v2(102.21,46.84) 102.85,46.2 102.85,45.93 103.12,45.67 103.5,45.67 103.69,45.67 104.02,45.34 115.36,45.34 116.43,46.41 117.62,46.41 117.74,46.52 119.36,46.52 120.44,47.6 126.19,47.6 v2(126.44,47.85)
  S8 w0.102: v2(126.44,47.85) 126.47,47.85 131.19,52.58 166.3,52.58 170.33,48.54 173.2,48.54 174.35,49.68 v2(174.37,49.68)
  BOTTOM w0.114: v1(174.24,48.51) 174.37,48.64 v2(174.37,49.68)
BDX_CPU_ERROR_2: length 84.5
  TOP w0.114: R208.1 v2(175.08,49.71) 175.2,49.83 U14.7 ; v2(105.41,48.41) 105.19,48.63 104.84,48.99 104.84,49.56 104.75,49.65 104.75,50.3 R247.1
  S3 w0.102: v2(124.83,48.34) 124.55,48.06 120.63,48.06 120.63,48.06 120.43,48.06 119.97,48.51 116.19,48.51 115.86,48.18 113.39,48.18 113.03,48.54 113.03,49.43 111.51,50.95 106.71,50.95 105.99,50.24 105.99,49 v2(105.41,48.41)
  S8 w0.102: v2(124.83,48.34) 124.84,48.34 129.54,53.04 166.49,53.04 170.52,49 172.42,49 172.97,49.56 172.97,49.96 173.38,50.37 174.88,50.37 175.08,50.16 v2(175.08,49.71)
  BOTTOM w0.114: v1(175.51,48.51) 175.08,48.95 v2(175.08,49.71)
BDX_CPU_PROCHOT_N: length 130.8
  TOP w0.114: R265.2 v2(103.31,43.69) ; U14.10 176.7,50.26 177.9,49.06 R214.1 179.27,48.77 179.81,48.23 v2(179.81,47.45)
  S8 w0.102: v2(179.81,47.45) 179.81,47.42 178.46,46.08 159.31,46.08 156.57,43.33 139.52,43.33 131.85,35.66 123.93,35.66 123.42,35.15 104.34,35.15 103.68,35.81 103.68,43.31 v2(103.31,43.69)
  BOTTOM w0.114: v2(103.31,43.69) 103.91,43.09 103.91,42.71 104.86,41.76 104.86,40.42 105.16,40.13 105.16,38.38 104.42,37.64 101.27,37.64 100.71,37.08 100.71,33.76 v1(100.36,33.4) 99.69,32.74 97.74,32.74 97.23,33.25 97.23,35.26 95.67,36.82 95.67,37.92 94.73,38.86 94.73,39.3 92.47,41.55 Q13.D
BDX_CPU_RSMRST_N: length 117.5
  TOP w0.114: U13.18 175.2,67.61 175.3,67.72 175.92,67.72 176.33,67.3 177.49,67.3 177.61,67.42 179.62,67.42 v2(180.01,67.03) ; R253.2 106.96,47.29 v2(106.45,46.79)
  S8 w0.102: v2(180.01,67.03) 180.01,66.37 179.81,66.17 179.73,66.09 179.73,63.82 180.42,63.13 180.42,48.84 177.88,46.3 159.22,46.3 156.48,43.56 139.1,43.56 131.42,35.89 123.83,35.89 123.55,35.61 108.14,35.61 107.01,36.74 107.01,46.23 v2(106.45,46.79)
  BOTTOM w0.114: v1(107.59,46.79) v2(106.45,46.79)
BDX_CPU_RSTN_R: length 5.1
  TOP w0.114: CONN11.46 35.89,8.51 36.7,7.7 v2(37.24,7.7)
  BOTTOM w0.114: v1(36.68,6.96) 36.68,7.14 v2(37.24,7.7) 36.37,8.56 R736.2
BDX_CPU_THERMTRIP_N: length 88.6
  TOP w0.114: R209.1 176.02,49.45 v2(175.92,49.56) 175.7,49.77 U14.8 ; U9.AF72 101.3,59.13 v4(101.07,59.13)
  S5 w0.102: v4(101.07,59.13) 101.07,58.88 102.13,57.81 106.05,57.81 107.87,55.98 110.79,55.98 111.73,55.04 112.57,55.04 113.39,55.85 122.17,55.85 128.09,49.93 v2(128.09,48.56)
  S8 w0.102: v2(128.09,48.56) 131.88,52.35 166.2,52.35 170.24,48.31 174.68,48.31 v2(175.92,49.56)
  BOTTOM w0.114: v1(176.78,48.51) 175.92,49.38 v2(175.92,49.56)
BDX_DDR01_MEMHOT: length 197.6
  TOP w0.114: v2(120.78,60.33) 120.78,59.64 R219.2 ; U10.8 175.65,69.01 176.63,68.03 177.19,68.03 177.38,68.21 179.01,68.21 v2(179.71,68.91) ; v4(85.22,66.01) 84.64,66.59 U9.CC56
  S3 w0.102: v2(89.33,43.99) 90.12,43.21 94.42,43.21 95.76,41.86 100.41,41.86 103.09,39.18 112.46,39.18 114.33,37.31 v2(115.06,37.31)
  S5 w0.102: v4(85.22,66.01) 85.6,66.01 86.13,65.48 86.13,65.07 86.72,64.49 86.72,64.14 86.97,63.88 96.24,63.88 97.1,63.02 101.02,63.02 102.06,61.98 102.06,61.54 102.34,61.26 108.71,61.26 109.55,60.43 110.97,60.43 112.39,59 116.08,59 116.08,59.05 116.51,59.49 117.37,59.49 117.86,59 120.22,59 120.78,59.56 v2(120.78,60.33)
  S8 w0.102: v2(115.06,37.31) 116.28,37.31 116.94,36.66 117.24,36.36 130.92,36.36 138.58,44.02 156.29,44.02 160.12,47.85 176.15,47.85 179.15,50.85 179.15,68.35 v2(179.71,68.91)
  S10 w0.102: v2(89.33,43.99) 89.79,43.99 92.02,46.23 92.02,56.16 90.29,57.9 89.77,57.9 89.55,58.12 89.55,58.63 89.2,58.98 89.2,60.35 89.57,60.71 89.57,61.03 89.2,61.39 89.2,62.06 89.57,62.43 89.57,62.74 89.2,63.1 89.2,63.78 89.57,64.14 89.57,64.56 88.52,65.61 85.62,65.61 v4(85.22,66.01)
  BOTTOM w0.114: Q12.D 87.12,45.8 88.93,43.99 v2(89.33,43.99)
BDX_DDR01_RCOMP0: length 5.7
  TOP w0.114: U9.CC52 v4(84.73,68.02)
  BOTTOM w0.114: R568.1 87.78,68.35 ; 87.78,68.35 87.35,68.35 87.25,68.25 84.96,68.25 v4(84.73,68.02) ; 87.78,68.35 87.4,67.97 87.4,66.78 v1(87.25,66.62)
BDX_DDR01_RCOMP1: length 4.3
  TOP w0.114: U9.CD51 v4(84.23,68.88)
  BOTTOM w0.114: v4(84.23,68.88) 84.45,68.88 84.84,69.27 R565.1
BDX_DDR01_RCOMP2: length 3.8
  TOP w0.114: U9.CC49 84.23,70.02 v4(84.73,69.74)
  BOTTOM w0.114: v4(84.73,69.74) 87.35,69.74 R564.1
BDX_DDR01_RESET_N: length 49.4
  TOP w0.114: U9.CR43 79.04,71.92 78.68,71.56 78.39,71.56 78.16,71.79 77.86,71.79 77.68,71.62 77.09,71.62 76.8,71.91 v3(76.48,71.91)
  S3 w0.089: 77.59,73.57 77.59,72.15 77.35,71.91 v3(76.48,71.91)
  S3 w0.102: 77.59,73.57 77.59,75.95 77.06,76.48 73.71,76.48 73.48,76.71 70.84,76.71 70.13,77.42 65.35,77.42 64.01,78.76 56.6,78.76 55.68,79.68 v2(55.68,80.75)
  BOTTOM w0.114: R551.2 46.58,79.55 54.48,79.55 v2(55.68,80.75) 56.34,80.08 v1(56.34,79.24) R546.2
BDX_DMI_RCOMP: length 15.3
  TOP w0.108: U9.AA28 103.83,78.92 v4(104.06,78.92)
  TOP w0.114: R180.2 v2(115.82,81.46)
  S5 w0.102: v4(104.06,78.92) 105.09,79.95 105.47,79.95 106.55,81.03 107.42,81.03 107.85,81.46 v2(115.82,81.46)
  BOTTOM w0.114: v1(116.89,81.46) v2(115.82,81.46)
BDX_DRAM01_PWROK: length 33.8
  TOP w0.114: v4(94.65,87.5) 94.63,87.52 U9.BA9 ; R20.2 v2(92.22,114.25)
  S10 w0.102: v2(92.22,114.25) 94.08,112.39 94.08,108.1 93.34,107.36 93.34,106.28 97.18,102.44 97.18,95.64 96.34,94.8 96.34,90.07 96.16,89.89 96.16,89.02 v4(94.65,87.5)
  BOTTOM w0.114: v1(93.17,113.8) 92.73,114.25 v2(92.22,114.25) R20.2
BDX_DRAM01_PWROK_R: length 121.4
  TOP w0.114: v2(76.3,66.67) 76.58,66.96 U9.CV55 ; v2(55.42,101.02) 60.05,96.39 72.03,96.39 74.26,98.63 74.26,101.43 72.71,102.98 72.46,102.98 72.03,103.41 72.03,104.95 70.84,106.15 69.8,106.15 66.76,109.19 66.76,118.13 v2(66.52,118.36)
  S5 w0.102: v2(66.52,118.36) 66.85,118.03 69.73,118.03 70.29,118.59 74.37,118.59 75.05,117.91 75.62,117.91 75.65,117.93 79.17,117.93 79.24,117.86 88.74,117.86 v2(90.5,116.1)
  BOTTOM w0.114: v2(55.42,101.02) 55.42,99.85 61.37,93.9 61.37,74.24 69.41,66.2 75.83,66.2 v2(76.3,66.67) ; R439.1 v2(90.5,116.1)
BDX_EXT_BGREF: length 24.2
  TOP w0.108: U9.AK66 v4(99.59,63.49)
  TOP w0.114: R276.2 v2(96.57,45.8)
  S10 w0.102: v4(99.59,63.49) 99.01,62.91 99.01,61.14 98.2,60.33 98.2,59.74 98.5,59.44 98.5,58.9 98.45,58.85 98.45,57.96 95.94,55.45 95.94,46.43 v2(96.57,45.8)
  BOTTOM w0.114: v1(95.3,46.94) 95.15,46.79 R623.1 96.42,45.95 v2(96.57,45.8)
BDX_EXT_SC_BGREF: length 11.1
  TOP w0.114: R217.1 117.32,59.46 v2(116.88,59.02) 116.55,59.02 115.13,57.6 113.27,57.6 113.06,57.8 113.06,58.44 112.34,59.16 111.34,59.16 U9.E72
  BOTTOM w0.114: R587.2 117.32,59.46 v2(116.88,59.02) 115.93,59.97 v1(115.93,60.07)
BDX_FIVR_FAULT: length 91.5
  TOP w0.108: v4(97.11,60.87) 97.4,60.58 U9.AP69
  TOP w0.114: U14.3 173.2,50.27 172.67,49.73 v2(172.44,49.73)
  S3 w0.102: v2(125.37,49.52) 125.36,49.52 124.22,48.37 120.43,48.37 117.5,51.31 112.09,51.31 111.1,52.3 111.1,54.71 109.25,56.57 109.25,58.37 108.51,59.11 108.51,59.39 108.08,59.82 108.08,60.15 107.77,60.45 106.15,60.45 105.31,59.61 102.95,59.61 102.13,60.43 97.55,60.43 v4(97.11,60.87)
  S8 w0.102: v2(125.37,49.52) 129.12,53.26 166.58,53.26 170.62,49.23 171.98,49.23 172.44,49.68 v2(172.44,49.73)
  BOTTOM w0.114: v2(172.44,49.73) 172.44,49.25 v1(171.7,48.51)
BDX_FM_CPU_PROCHOT_N: length 26.5
  TOP w0.114: R86.2 v2(77.78,104.8) 78.16,104.42 78.16,102.18 80.14,100.2 81.84,100.2 83.94,98.11 85.66,98.11 88.39,95.38 88.39,94.11 89.31,93.19 89.31,92.25 89.44,92.12 U9.BM1
  BOTTOM w0.114: v2(77.78,104.8) 77.7,104.88 R469.2 78.25,105.56 78.56,105.87 78.56,107.16 77.9,107.82 76.07,107.82 v1(75.9,108)
BDX_FM_NMI_EVENT_N: length 24.2
  TOP w0.114: U9.BP1 88.45,93.04 87.63,93.85 87.63,95 85.24,97.38 83.64,97.38 81.58,99.44 77.93,99.44 75.01,102.36 R101.2 ; R91.1 R101.2 ; R101.2 v2(75.79,103.73)
  BOTTOM w0.114: v1(75.29,102.67) 75.01,102.95 R101.2 v2(75.79,103.73)
BDX_FM_SMI_ACTIVE_N: length 32.1
  TOP w0.114: v2(73.28,108.84) R73.2 R75.2 73.4,107.02 73.4,106.45 73.62,106.24 73.62,105.24 73.4,105.03 73.4,103.2 77.41,99.19 81.49,99.19 83.54,97.14 85.1,97.14 87.38,94.87 87.38,93.8 88.11,93.06 88.11,91.69 88.29,91.52 88.29,91.06 87.95,90.72 U9.BR4
  BOTTOM w0.114: v2(73.28,108.84) 73.69,109.25 R459.2 74.96,108.31 v1(74.37,107.72)
BDX_FM_THROTTLE_N: length 21.1
  TOP w0.114: U9.BN2 89.05,91.33 89.05,93.12 88.14,94.03 88.14,95.25 85.52,97.87 83.84,97.87 81.76,99.95 78.87,99.95 77.65,101.17 v2(77.65,102.42) R107.2
  BOTTOM w0.114: v1(76.66,102.34) 76.74,102.42 v2(77.65,102.42) R107.2
BDX_INTRUDER_N: length 179.6
  TOP w0.114: U9.AK2 100,91.38 100,94.4 v3(99.97,94.44) 99.97,94.44 98.61,95.8 R140.1
  S3 w0.102: v3(99.94,106.92) 99.94,106.82 99.52,106.4 99.52,102.16 99.69,101.98 99.69,100.03 98.15,98.48 98.15,97.58 99.57,96.16 99.57,94.86 99.59,94.84 99.59,94.64 99.8,94.44 v3(99.97,94.44) ; v2(26.8,65.66) 26.8,65.72 26.16,66.35 26.16,68.39 26.63,68.86 26.87,68.86 27.3,69.29 27.3,69.93 26.65,70.58 26.29,70.58 25.76,71.12 25.76,71.73 22.48,75.01 22.48,78.05 v2(20.4,80.14)
  S5 w0.102: v3(99.94,106.92) 99.94,108.51 100.03,108.6 100.03,110.06 100.53,110.57 100.53,114.43 99.57,115.39 99.57,117.09 95.96,120.7 35.38,120.7 34.82,120.14 30.08,120.14 30.04,120.1 24.65,120.1 23.98,119.43 16.99,119.43 13.4,115.84 13.4,105.14 13.4,104.57 20.76,97.21 20.76,80.5 v2(20.4,80.14)
  BOTTOM w0.114: R916.2 26.6,65.91 26.8,65.72 v2(26.8,65.66) ; v3(99.97,94.44) 99.75,94.44 99.2,94.99 v1(99.12,94.99)
BDX_INTRUDER_N_R: length 3.9
  BOTTOM w0.114: R916.1 24.77,65.91 v1(23.85,66.83) 23.4,67.28 CONN14.39
BDX_INTVRMEN: length 10
  TOP w0.114: U9.AP2 97.85,91.55 98.04,91.74 98.04,93.42 97.84,93.62 97.75,93.62 97.51,93.86 97.51,94.2 97.79,94.48 v3(97.79,94.67)
  BOTTOM w0.114: R518.2 95.2,96.47 95.94,97.21 v1(97.28,97.21) 97.41,97.21 97.54,97.09 97.54,96.52 97.99,96.07 R505.1 97.84,95.56 97.84,94.72 v3(97.79,94.67)
BDX_PCI_RCOMP: length 5.3
  TOP w0.33: v4(103.95,80.39) U9.AA27
  BOTTOM w0.114: v4(103.95,80.39) 106.08,80.39 R543.2 106.48,81.05 106.98,81.56 106.98,82.52 v1(106.91,82.6)
BDX_PECI_CPU: length 38.7
  TOP w0.114: v2(99.77,53.77) 99.54,54 99.54,55.62 U9.AL78
  BOTTOM w0.114: v2(99.77,53.77) 100.23,53.77 100.97,54.51 100.97,55.86 v1(101,55.89) 101.9,56.8 101.9,57.78 101.63,58.06 101.63,59.39 101.09,59.92 101.09,60.25 100.86,60.48 99.11,60.48 98.09,61.49 98.09,61.87 98.55,62.33 98.55,62.81 98.09,63.27 96.57,63.27 96.29,62.99 95.48,62.99 95.12,63.35 95.12,63.53 94.77,63.88 93.4,63.88 93.19,63.68 93.19,63.32 92.86,62.99 87.45,62.99 87.2,63.25 87.2,63.6 86.66,64.14 86.66,64.62 86.21,65.07 86.21,65.35 86.61,65.76 87.6,65.76 89.36,67.51 89.36,71.19 R560.2
BDX_PECI_PCH: length 137.3
  TOP w0.114: v3(176.91,68.71) 176.65,68.97 U10.10 ; U9.BG16 v4(92.16,84.33)
  S8 w0.102: v2(121.72,61.52) 121.39,61.84 119.14,61.84 118.8,61.49 110.38,61.49 110.15,61.26 102.91,61.26 102.76,61.11 102.39,61.11 101.98,61.52 101.98,62.16 101.69,62.45 101.69,62.76 101.98,63.05 101.98,63.98 98.73,67.23 98.73,72.86 98.78,72.91 98.78,73.89 97.64,75.03 87.91,75.03 87.22,74.35 v3(87.22,73.28)
  BOTTOM w0.114: R560.1 87.22,72.42 v3(87.22,73.28) 87.22,74.8 87.05,74.98 C364.2 86.66,75.96 86.28,76.34 86.28,76.75 86.69,77.44 86.69,77.7 86.23,78.16 86.23,78.47 85.69,79.01 85.69,79.44 85.27,79.87 85.27,80.22 85.75,80.7 85.75,81.04 86.07,81.36 87.89,81.36 88.16,81.64 88.16,81.92 88.7,82.45 88.7,82.83 89.23,83.36 89.23,83.64 89.66,84.07 89.66,84.53 89.89,84.76 91.73,84.76 v4(92.16,84.33) ; v2(121.72,61.52) 122.63,62.43 129.82,62.43 130.73,61.52 130.73,58.06 131.04,57.76 133.1,57.76 138.41,63.08 149.05,63.08 151.21,60.92 169.08,60.92 170.1,61.95 170.1,65.28 172.36,67.54 173.46,67.54 174.24,68.33 176.02,68.33 176.4,68.71 v3(176.91,68.71)
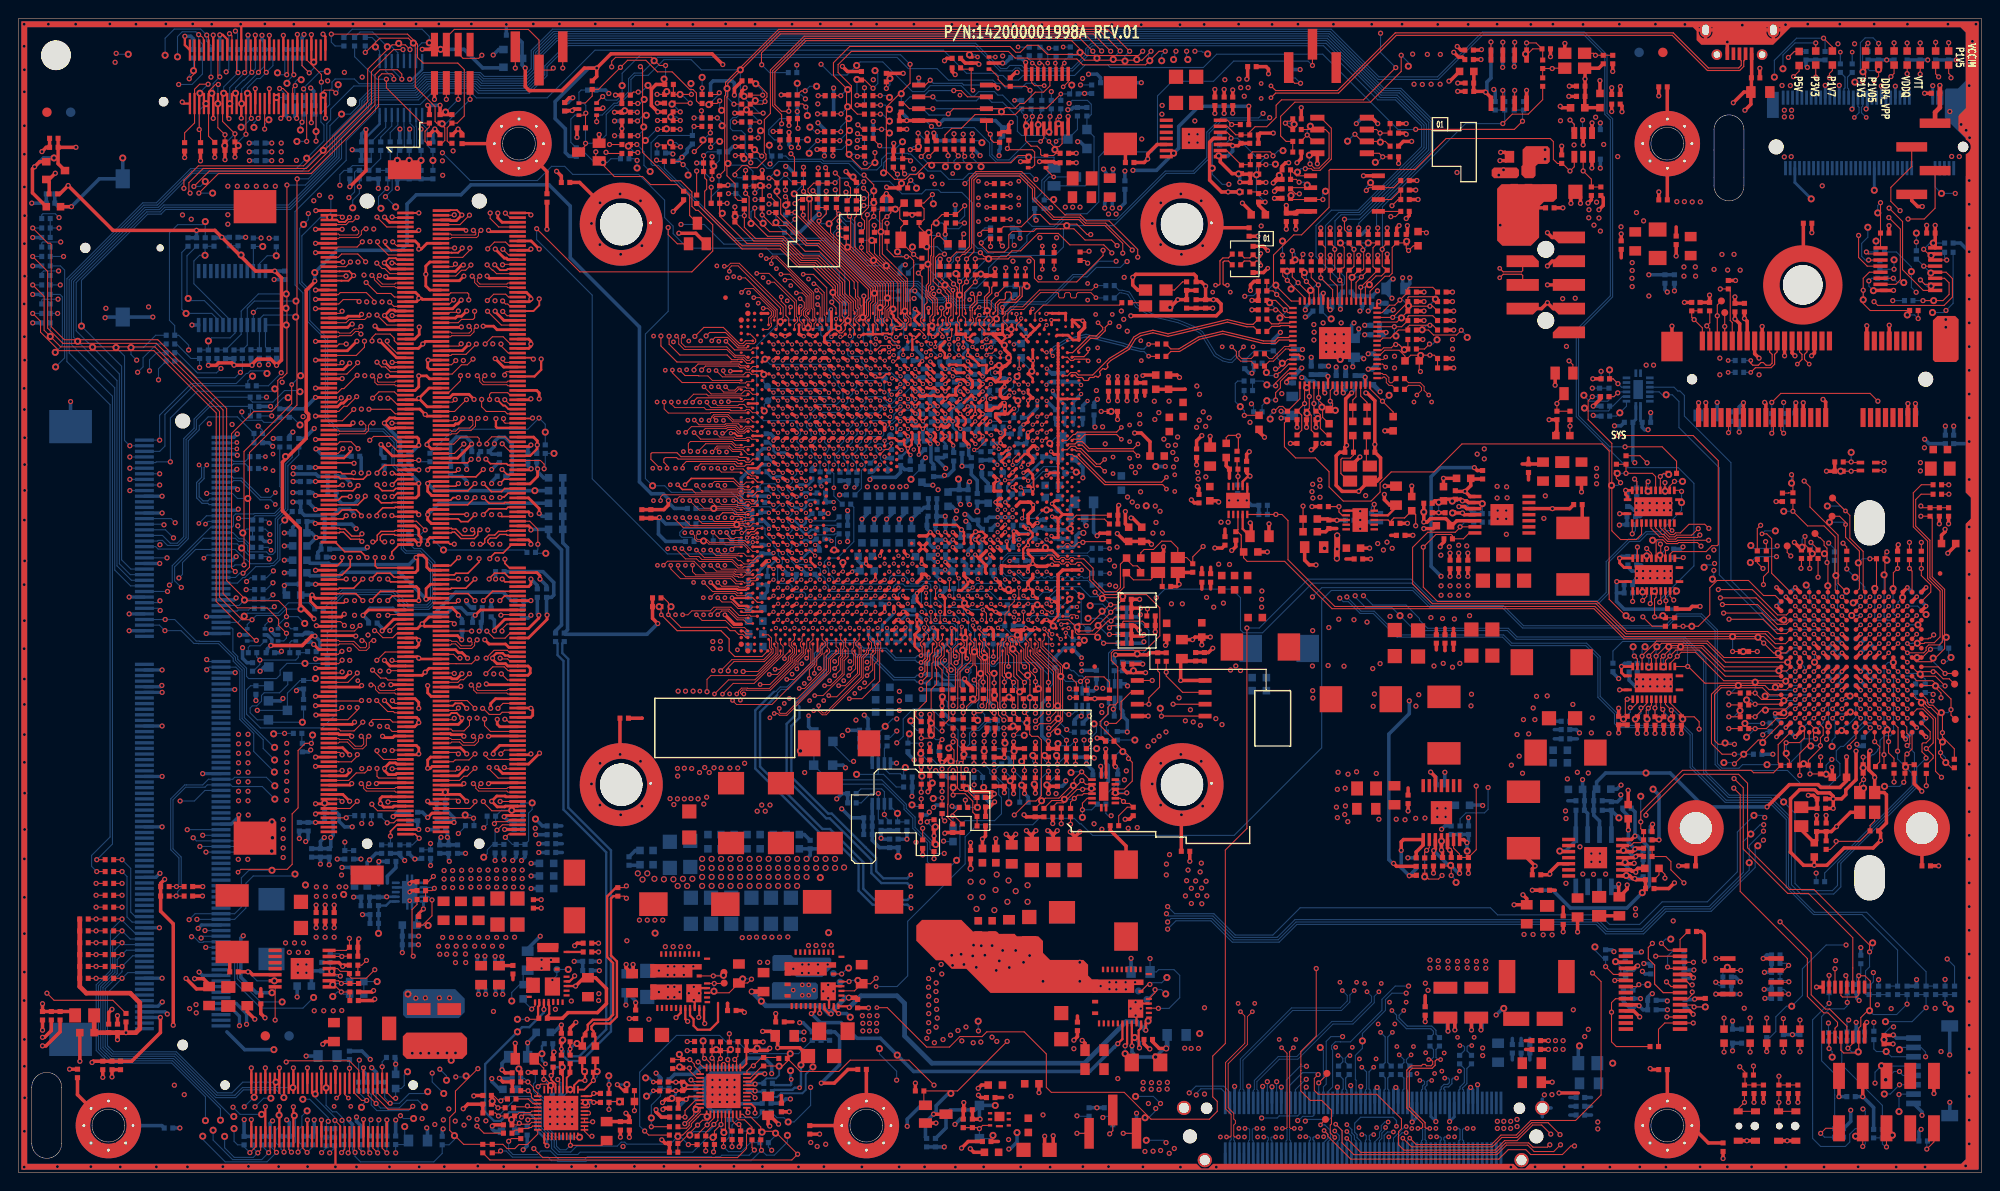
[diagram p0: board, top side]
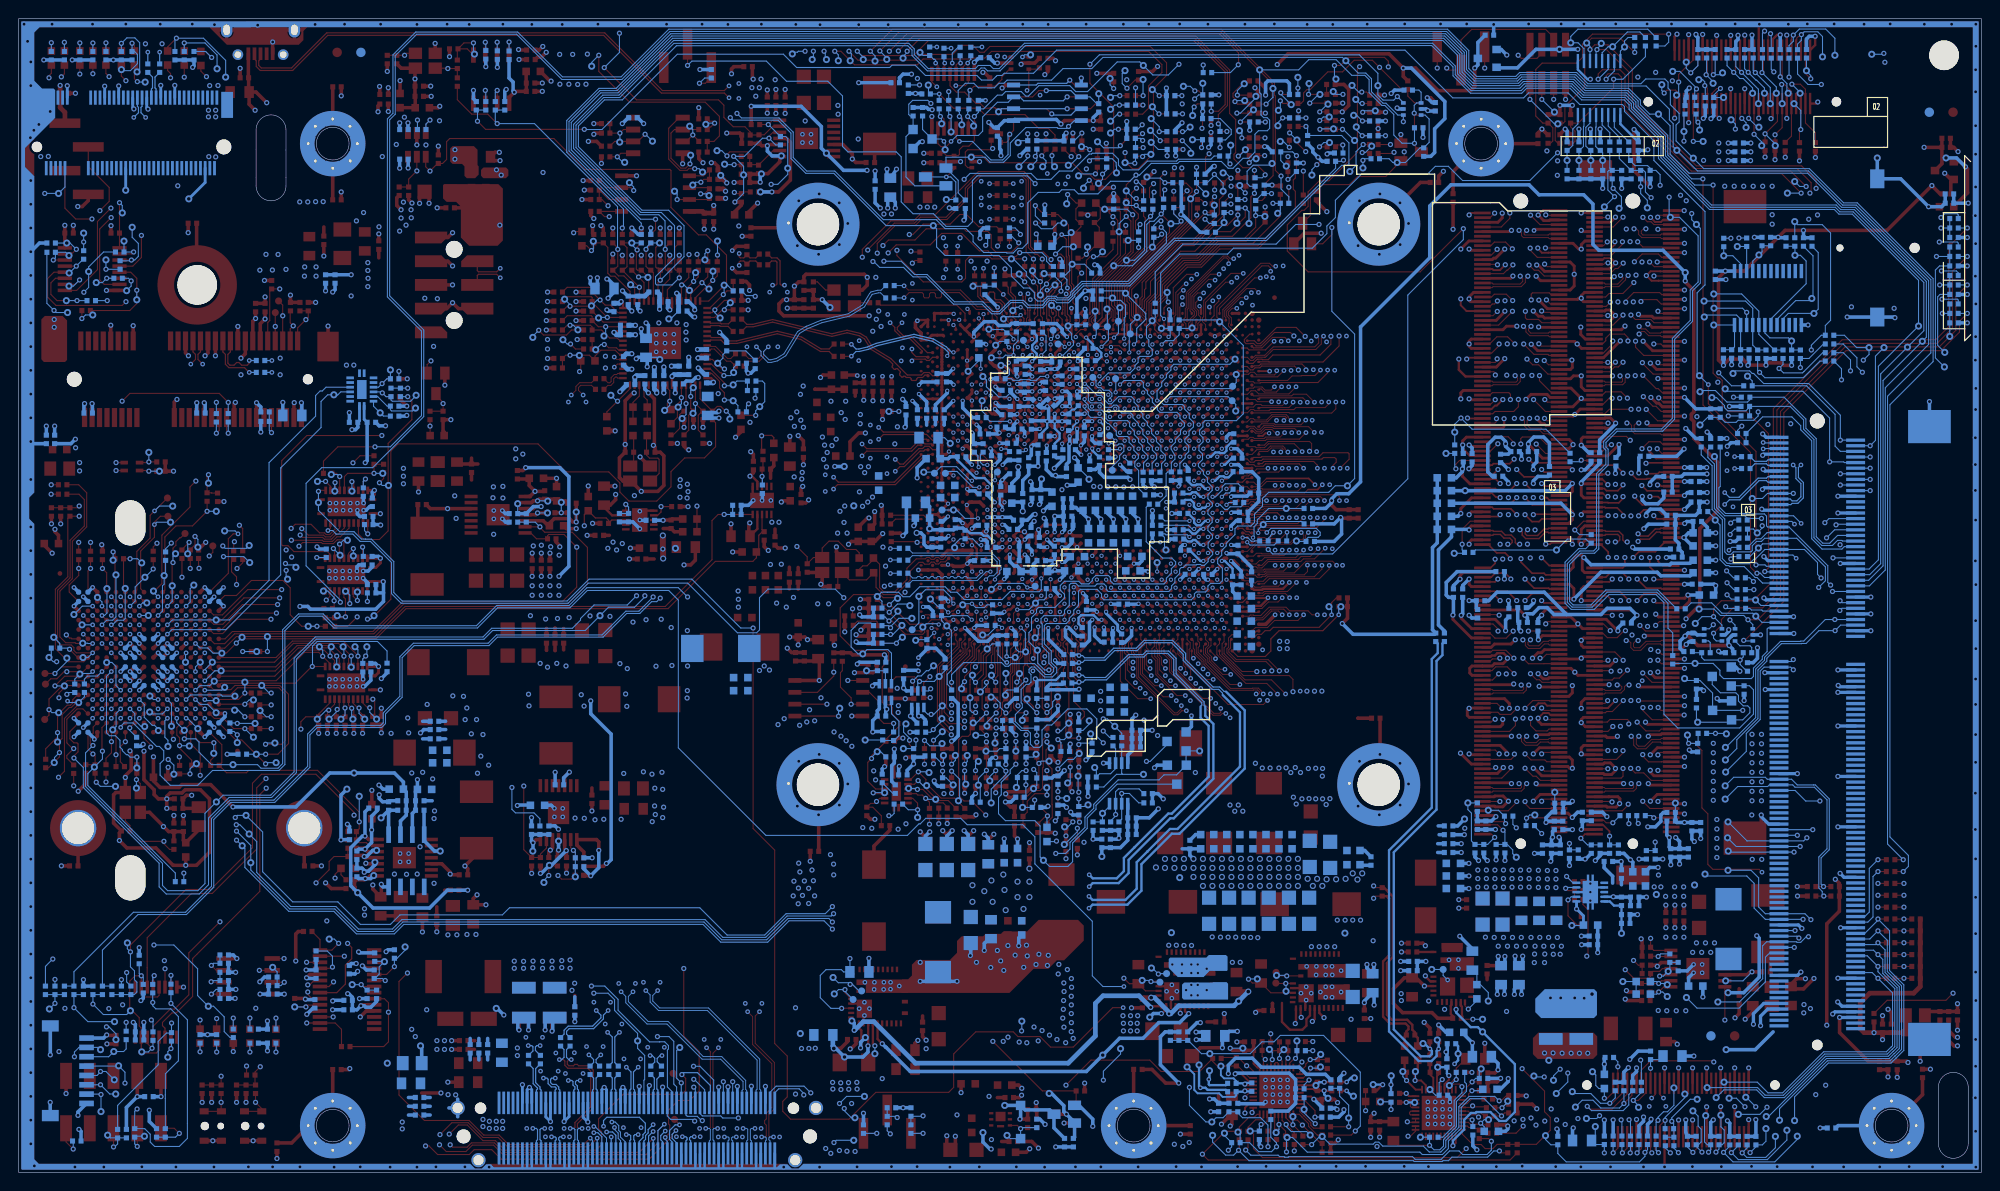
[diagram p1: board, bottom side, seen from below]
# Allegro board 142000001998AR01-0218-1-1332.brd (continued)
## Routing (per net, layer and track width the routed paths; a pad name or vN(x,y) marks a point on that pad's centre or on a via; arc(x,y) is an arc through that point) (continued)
BDX_PECI_PCH_3V3: length 270
  TOP w0.114: U10.14 177.82,73.01 v2(177.93,72.9) ; v2(131.42,58.27) 131.42,36.8 129.11,34.49 129.11,13.79 127.76,12.45 127.76,8.08 128.24,7.59 128.24,6.53 127.41,5.69 121.16,5.69 118.29,8.56 110.49,8.56 109.96,9.09 109.96,12.67 107.59,15.04 103.58,15.04 103.07,14.53 101.11,14.53 101.11,14.54 100.72,14.54 99.59,13.41 97.16,13.41 92.94,17.63 v3(91.82,17.63)
  S3 w0.102: v3(36.28,52.63) 34.87,52.63 33.27,51.03 33.27,39.37 34.01,38.63 43.97,38.63 44.81,37.8 44.81,36.13 44.73,36.05 44.73,31.96 44.93,31.76 44.93,30.21 44.81,30.09 44.81,29.67 45.49,28.98 52.2,28.98 54.23,26.95 62.92,26.95 v2(65.07,24.79)
  S8 w0.102: v3(91.82,17.63) 91.82,18.72 89.99,20.55 89.99,24.69 89,25.68 65.96,25.68 v2(65.07,24.79)
  S10 w0.102: v3(36.28,52.63) 33.6,52.63 32.89,53.34 32.89,58.61 30.16,61.34 28.85,61.34 27.97,62.23 27.97,65.63 v3(27,66.6)
  BOTTOM w0.114: R915.2 26.7,66.9 v3(27,66.6) ; v2(177.93,72.9) v1(177.93,71.7) 177.93,70.87 175.64,68.58 174.12,68.58 173.33,67.79 172.89,67.79 172.89,67.79 172.27,67.79 169.86,65.38 169.86,62.06 168.96,61.16 151.31,61.16 148.97,63.5 137.97,63.5 132.74,58.27 v2(131.42,58.27)
BDX_PECI_PCH_3V3_R: length 4
  BOTTOM w0.114: CONN14.35 22.92,68.48 23.58,67.82 24.11,67.82 R915.1
BDX_PECID0: length 12.9
  TOP w0.114: U9.L72 108.29,58.86 108.03,59.13 v4(108.03,59.16)
  BOTTOM w0.114: R749.2 110.18,51.8 110.64,52.26 110.64,53.31 110.2,53.75 110.2,58.01 v1(110.69,58.5) 111.25,59.06 R586.1 111.15,59.49 110.34,59.49 110.24,59.59 108.46,59.59 v4(108.03,59.16)
BDX_PWRGOOD_CPU: length 157.1
  TOP w0.114: U10.4 173.65,68.32 173.08,67.74 171.4,67.74 170.47,68.67 170.47,78.03 167.93,80.57 167.93,82.59 v2(168.38,83.04) ; R32.1 v2(72.26,111.96)
  S3 w0.102: v2(168.38,83.04) 168.37,83.04 166.93,84.48 166.93,87 168.81,88.88 168.81,94 165.32,97.49 162.1,97.49 161.87,97.71 157.13,97.71 156,96.58 135.75,96.58 134.32,95.15 130.81,95.15 130,95.96 121.94,95.96 120.68,97.23 118.87,97.23 v2(118.6,97.51)
  BOTTOM w0.114: v2(118.6,97.51) 118.51,97.51 117.88,96.88 115.32,96.88 114.3,95.86 112.89,95.86 109.97,92.94 106.92,92.94 105.89,91.91 105.02,91.91 103.82,93.1 102.59,93.1 102.04,92.56 100.43,92.56 100.03,92.96 100.03,93.04 99.72,93.35 99.19,93.35 98.93,93.09 97.66,93.09 97.47,93.29 97,93.76 97,93.96 96.07,94.89 91.11,94.89 86.26,99.75 76.49,99.75 68.44,107.8 67.82,107.8 67.67,107.95 67.67,110.21 68.45,111 R453.2 72.09,111.79 v2(72.26,111.96) ; R537.1 v2(168.38,83.04)
BDX_PWRGOOD_CPU_R: length 34.8
  TOP w0.114: U9.BU11 v4(87.7,86.91) ; R32.2 v2(74.01,111.27)
  S5 w0.102: v2(74.01,111.27) 75.48,109.79 75.48,106.25 75.11,105.87 75.11,103.3 77.16,101.25 78.14,101.25 79.52,99.87 79.98,99.87 81.35,98.5 83.1,96.74 84.3,96.74 87.83,93.21 87.83,90.14 88.32,89.66 88.32,89.11 88.09,88.89 88.09,88.34 87.81,88.06 87.81,87.3 87.7,87.19 v4(87.7,86.91)
  BOTTOM w0.114: v1(73.23,110.52) 73.25,110.52 v2(74.01,111.27)
BDX_RTCRST_N: length 91.6
  TOP w0.114: R118.2 100.36,101.63 v2(101.19,101.63) ; v4(97.08,87.78) 97.35,88.05 U9.AP9 ; CONN17.2 v2(138.43,118.49)
  S3 w0.102: v2(101.19,101.63) 101.83,102.26 101.83,105.26 v2(101.24,105.84)
  S10 w0.102: v4(97.08,87.78) 97.08,86.67 97.37,86.39 99.29,86.39 100.05,87.14 100.05,87.86 99.97,87.93 99.97,89.53 100.18,89.74 100.18,93.8 101.19,94.82 101.2,94.82 101.25,94.87 101.61,94.87 101.88,95.13 101.88,95.49 104.47,98.09 104.47,100.2 103.43,101.24 101.57,101.24 v2(101.19,101.63)
  BOTTOM w0.114: v1(98.17,101.63) 98.81,101.63 99.42,101.02 100.58,101.02 v2(101.19,101.63) ; v2(101.24,105.84) 102.08,106.68 107.44,106.68 107.95,106.17 107.95,101.77 108.45,101.27 110.77,101.27 112.12,102.62 114.3,102.62 115.57,103.89 115.57,108.71 116.1,109.24 121.27,109.24 121.85,109.82 121.85,115.23 123.42,116.8 127.85,116.8 130,118.96 137.96,118.96 v2(138.43,118.49)
BDX_SATA1_ACTIVITY_LED1: length 45.6
  TOP w0.114: U12.N14 v3(202.09,49.61) ; LED14.C v2(185.26,16.51)
  S8 w0.102: v3(202.09,49.61) 202.52,49.18 202.52,48.92 202.52,48.91 202.52,48.79 202.52,48.79 202.52,48.43 202.32,48.23 202.32,47.24 203.01,46.55 203.01,41.86 199.9,38.74 199.9,37.59 197.46,35.15 196.31,35.15 194.46,33.31 194.46,24.18 190.14,19.86 189.15,19.86 185.8,16.51 v2(185.26,16.51)
  BOTTOM w0.114: LED14.C v2(185.26,16.51)
BDX_SATA2_ACTIVITY_LED2: length 47.8
  TOP w0.114: LED13.C v2(182.47,16.51) ; U12.P14 v3(202.09,48.61)
  S8 w0.102: v3(202.09,48.61) 202.09,47.15 202.78,46.45 202.78,41.95 199.67,38.84 199.67,37.69 197.36,35.38 196.22,35.38 194.23,33.4 194.23,24.28 190.89,20.93 185.38,20.93 184.66,20.21 184.66,20.21 184.39,19.94 182.47,18.02 v2(182.47,16.51)
  BOTTOM w0.114: LED13.C v2(182.47,16.51)
BDX_SC_PWRGOOD: length 209.9
  TOP w0.114: R239.2 101.06,49.98 v2(100.97,49.89) ; v2(174.19,66.78) 174.7,66.27 U13.19
  S3 w0.102: v2(100.97,49.89) 100.2,50.65 99.77,50.65 99.47,50.34 99.47,48.82 98.22,47.57 98.22,45.9 99.24,44.88 115.24,44.88 115.44,44.68 116.54,44.68 117.93,46.06 119.55,46.06 120.17,46.69 v2(122.02,46.69)
  S5 w0.102: v2(100.97,49.89) 100.97,49.82 100.51,49.36 100.51,44.78 99.31,43.59 99.31,38.99 97.66,37.34 97.66,37.33 97.18,36.85 97.18,36.64 97.18,36.64 97.18,34.18 97.18,34.18 97.18,33.8 97.18,33.8 97.18,28.37 93.4,24.59 93.4,14.73 91.24,12.57 77.59,12.57 77.18,12.98 72.85,12.98 72.31,13.51 60.42,13.51 59.1,12.19 57.56,12.19 56.54,11.18 56.18,11.18 56.01,11.35 53.94,11.35 51.89,9.3 48.03,9.3 46.71,7.98 v2(46.71,5.49)
  S8 w0.102: v2(122.02,46.69) 122.02,47.28 123.53,48.79 123.53,49.46 129.91,55.85 155.05,55.85 155.53,55.37 165.49,55.37 170.31,60.19 170.31,65.88 170.9,66.47 173.89,66.47 v2(174.19,66.78)
  S10 w0.102: v2(32.41,2.11) 33.45,3.15 44.66,3.15 46.71,5.2 v2(46.71,5.49)
  BOTTOM w0.114: v2(100.97,49.89) 101.06,49.98 R239.2 101.04,50.75 R609.1 ; v1(174.19,65.99) v2(174.19,66.78) ; R775.2 32.89,2.59 v2(32.41,2.11)
BDX_SCLOCK: length 155.1
  TOP w0.114: U12.C8 v3(195.09,60.61) ; R37.2 v2(85.47,111.4)
  S3 w0.102: v3(195.09,60.61) 195.47,60.99 195.47,64.08 195.15,64.4 195.15,66.73 193.73,68.15 193.73,72.33 173.97,92.09 173.97,100.6 169.15,105.41 154.24,105.41 151.04,108.61 149.81,108.61 148.28,110.13 132.63,110.13 131.74,109.25 122.59,109.25 121.37,108.03 117.41,108.03 114.11,111.33 108.62,111.33 102.83,117.12 101.24,117.12 100.39,117.97 100.01,117.97 99.85,117.81 95.16,117.81 94.67,118.29 90.68,118.29 89.21,116.81 86.45,116.81 85.01,115.38 85.01,111.86 v2(85.47,111.4)
  BOTTOM w0.114: v2(85.47,111.4) 85.2,111.4 84.71,111.89 v1(84.66,111.89)
BDX_SDATAOUT0: length 210.4
  TOP w0.114: U12.E14 v3(202.09,58.61) ; v2(72.29,109.27) 73.13,110.11 R44.1
  S3 w0.102: v3(202.09,58.61) 202.7,58.61 203.48,59.39 203.48,62.56 205.03,64.11 205.03,67.7 202.97,69.76 202.97,78.75 201.76,79.95 201.46,80.25 201.46,92.57 201.83,92.93 201.83,98.54 196.27,104.1 191.15,104.1 186.32,108.93 186.32,114.05 183.55,116.82 176.16,116.82 171.45,121.54 164.46,121.54 163.06,120.14 158.75,120.14 157.28,118.67 156.27,118.67 156.13,118.81 144.09,118.81 140.8,122.1 68.85,122.1 67.03,120.28 67.03,117.65 69.32,115.37 69.32,112.46 72.29,109.49 v2(72.29,109.27)
  BOTTOM w0.114: v3(202.09,58.61) v1(203.23,58.61)
BDX_SDATAOUT1: length 208.3
  TOP w0.114: U12.C14 v3(202.09,60.61) ; R67.1 v2(76.68,108.84)
  S3 w0.102: v3(202.09,60.61) 202.09,62.06 204.57,64.54 204.57,67.51 202.51,69.57 202.51,78.56 201.57,79.49 201.01,80.06 201.01,92.76 201.37,93.12 201.37,98.35 196.08,103.64 190.96,103.64 185.86,108.74 185.86,113.86 183.36,116.37 175.83,116.37 175.05,117.14 170.31,117.14 169.58,116.41 166.76,116.41 166.2,116.96 158.09,116.96 156.86,118.19 152.94,118.19 152.28,117.53 144.63,117.53 144.6,117.55 144.58,117.55 140.49,121.64 69.04,121.64 68.51,121.11 67.49,120.09 67.49,119.52 67.49,117.84 67.76,117.57 70.28,115.05 70.28,114.71 71.56,113.42 72.56,113.42 72.97,113 73.25,113 75.77,110.48 75.77,109.75 v2(76.68,108.84)
  BOTTOM w0.114: v3(202.09,60.61) 203.19,60.61 v1(204.09,59.72)
BDX_SERIRQ_DATA: length 22.5
  TOP w0.114: v3(101.48,53.68) 102.11,54.31 102.11,55.53 101.98,55.66 101.98,56.13 102.21,56.36 102.21,56.64 101.81,57.04 U9.AE75
  S5 w0.102: v2(112.37,49.02) 112.29,49.02 111.05,50.27 111.05,53.06 109.52,54.58 107.24,54.58 106.33,53.68 v3(101.48,53.68)
  BOTTOM w0.114: v1(111.17,49.94) 112.09,49.02 v2(112.37,49.02) 112.39,49.05 112.75,49.05 113.14,49.44 Q10.3
BDX_SERIRQ_DIR: length 27.4
  TOP w0.114: v4(102.1,58.53) 102.1,58.26 U9.AD74 ; R794.2 116.71,52.45 116.12,53.04 114.16,53.04 113.67,52.55 v2(113.61,52.55)
  S8 w0.102: v4(102.1,58.53) 102.54,58.98 102.54,59.54 102.77,59.77 103.3,59.77 103.58,59.49 103.58,59 103.86,58.72 104.09,58.72 104.27,58.55 104.27,56.34 104.95,55.65 104.95,54.1 105.94,53.11 111.1,53.11 111.66,52.55 v2(113.61,52.55)
  BOTTOM w0.114: R795.1 110.87,53.72 v1(111.51,53.09) 112.04,52.55 v2(113.61,52.55) 113.79,52.37 Q10.5
BDX_SLOAD: length 393.1
  TOP w0.114: U12.N10 v3(198.09,49.61)
  S3 w0.102: v2(63.75,110.97) 63.75,111.61 61.49,113.87 61.49,116.23 56.49,121.23 40.97,121.23 38.89,119.15 37.23,119.15 34.39,116.31 34.39,115.11 33.58,114.3 33.58,110.45 30.57,107.45 8.14,107.45 3.29,102.6 2.87,102.18 2.87,24.14 4.39,22.62 4.39,18.49 10.89,11.99 11.54,11.99 25.58,11.99 25.71,12.13 25.71,12.13 26.08,12.5 29.91,12.5 30.63,11.79 30.93,11.79 31.6,11.12 31.6,11 32.41,10.19 42.6,10.19 43.92,8.86 53.09,8.86 54.13,7.82 54.89,7.82 55.03,7.96 59.4,7.96 61.29,6.07 62.05,6.07 62.94,5.18 66.58,5.18 66.96,5.56 69.39,5.56 70.55,6.73 76.82,6.73 77.35,7.26 83.55,7.26 85.19,8.9 85.19,9.83 85.67,10.31 86.66,10.31 88.29,11.94 97.28,11.94 99.71,14.36 v2(99.71,14.69)
  S8 w0.102: v2(99.71,14.69) 99.71,15.11 100.95,16.36 105.19,16.36 105.5,16.66 111.97,16.66 114.18,18.87 114.37,18.87 123.95,18.87 126.47,16.36 148.68,16.36 152.67,20.35 162.46,20.35 164.67,22.56 171.11,22.56 171.38,22.83 174.53,22.83 174.8,22.56 175.23,22.56 178.6,25.93 178.89,26.21 182.91,26.21 188.19,31.5 188.19,38.12 193.52,43.45 193.52,44.42 194.84,45.75 195.08,45.75 195.97,46.63 195.97,47.14 196.47,47.64 196.47,48.64 196.98,49.15 197.63,49.15 v3(198.09,49.61)
  BOTTOM w0.114: v1(196.52,47.73) 196.9,47.73 197.58,48.4 197.58,49.1 v3(198.09,49.61) ; R451.2 v2(63.75,110.97)
BDX_SLP_S3_CPU_N: length 26.4
  TOP w0.108: v4(103.05,59.13) U9.AC71
  TOP w0.114: R303.2 101.29,39.32 v2(101.29,39.85)
  S8 w0.102: v4(103.05,59.13) 103.3,58.88 103.3,54.43 103.89,53.85 103.89,50.16 103.83,50.1 103.83,48.06 104.93,46.96 104.93,45.64 104.39,45.11 103.63,45.11 102.84,44.32 102.84,43.51 103.38,42.97 103.38,41.15 102.08,39.85 v2(101.29,39.85)
  BOTTOM w0.114: v2(101.29,39.85) 101.29,39.32 R303.2 v1(102.59,39.07)
BDX_SLP_S3_CPU_N_R: length 3.9
  TOP w0.114: R307.1 100.1,38.15 v2(99.92,38.15) 99.92,38.35 R303.1
  BOTTOM w0.114: v2(99.92,38.15) 99.97,38.1 R667.1
BDX_SPI_MUX_SEL: length 191.9
  TOP w0.114: R931.2 110.98,109.09 110.74,108.85 U44.6 109.91,108.84 109.47,108.84 109.35,108.97 109.35,109.47 108.97,109.86 108.33,109.86 107.74,110.44 U43.1 v2(107.74,113.03)
  S8 w0.102: v2(33.06,116.85) 33.02,116.81 33.02,116.38 31.95,115.32 19.81,115.32 9.91,105.41 9.91,87.38 7.49,84.96 7.49,51.82 17.27,42.04 v2(17.27,39.75)
  S10 w0.102: v2(33.06,116.85) 35.59,116.85 36.45,117.7 51.7,117.7 53.05,119.05 75.77,119.05 76.73,118.08 85.32,118.08 v2(85.85,118.62)
  BOTTOM w0.114: v2(85.85,118.62) 87,117.47 88.65,117.47 v1(89.66,118.49) 90.04,118.87 92.46,118.87 95.63,115.7 96.9,115.7 97.54,116.33 100.84,116.33 101.96,115.21 102.23,115.21 102.72,115.7 104.39,115.7 104.78,115.32 105.28,115.32 106.75,113.85 R933.2 107.31,113.46 v2(107.74,113.03) ; CONN14.119 19.93,40.88 18.8,39.75 v2(17.27,39.75)
BDX_SPKR: length 39.2
  TOP w0.114: v4(89.19,82.62) 88.9,82.9 U9.BP20 ; R9.2 83.74,115.77 v2(84.15,115.77)
  S10 w0.102: v2(84.15,115.77) 84.91,115.01 84.91,108.62 84.86,108.57 84.86,106.18 85.67,105.36 85.67,104.7 86.11,104.26 86.11,98.82 89.15,95.78 89.15,90.2 89.32,90.03 89.32,89.29 89.08,89.05 89.08,88.39 88.81,88.12 88.81,87.37 89.07,87.1 89.07,86.61 88.81,86.34 88.81,85.64 89.07,85.38 89.07,84.88 88.81,84.61 88.81,84.07 89.19,83.69 v4(89.19,82.62)
  BOTTOM w0.114: v1(85.38,116.26) 84.64,116.26 v2(84.15,115.77)
BDX_SRTCRST_N: length 18.6
  TOP w0.114: U9.AP4 97.85,90.72 97.5,91.07 97.5,91.58 97.79,91.87 97.79,93.27 97.29,93.77 97.29,94.29 97.35,94.35 97.35,94.85 97.59,95.08 97.59,98.09 97.67,98.18 97.67,101.4 98.81,102.54 R117.2 R118.1 100.36,102.59 101.22,103.45 v2(101.22,103.48)
  BOTTOM w0.114: v2(101.22,103.48) 101.22,102.39 100.46,101.63 C274.1
BDX_TCK_SCLK: length 159.5
  S8 w0.102: v3(142.11,5.11) 143.31,6.3 157.99,6.3 162.36,10.67 170.55,10.67 173.83,13.94 190.86,13.94 193.73,16.81 197.76,16.81 v2(198.88,17.93)
  S10 w0.102: v2(198.88,17.93) 199.72,18.77 205.54,18.77 207.82,21.06 207.82,69.81 205.44,72.2 205.44,78.22 201.6,82.06 201.6,87.01 204.08,89.49 204.08,91.92 203.03,92.97 v2(203.03,94.21)
  BOTTOM w0.114: R132.1 200.92,98.52 202.51,96.93 v1(202.51,96.43) 202.51,94.73 v2(203.03,94.21)
  BOTTOM w0.127: CONN16.64 143.1,3.35 142.93,3.53 142.93,3.94 142.65,4.22 142.65,4.57 v3(142.11,5.11)
BDX_TCK_SCLK_R: length 3.8
  TOP w0.114: v2(197.7,98.52) 197.91,98.31 U7.2
  BOTTOM w0.114: v2(197.7,98.52) R132.2 v1(198.73,99.69)
BDX_TDI_MOSI: length 131.6
  S5 w0.102: v2(141.66,14.53) 142.06,14.12 147.42,14.12 151.21,17.91 170.21,17.91 172.01,19.71 172.33,19.71 173.29,20.68 174.12,20.68 176.56,23.11 176.56,23.58 178.66,25.69 178.66,25.85 179.87,27.05 180.02,27.05 184.53,31.56 184.53,40.41 184.15,40.79 184.15,52.83 185.32,54 185.32,77.06 186.21,77.95 186.21,83.01 186.97,83.77 190.1,83.77 197.61,91.28 198.49,91.28 v2(200.53,93.32)
  BOTTOM w0.114: CONN16.77 139.6,9.14 139.9,9.45 139.9,14.02 140.41,14.53 v2(141.66,14.53) ; R147.1 v2(200.53,93.32)
BDX_TDI_MOSI_R: length 8.2
  TOP w0.114: v2(203.76,93.32) 205.89,93.32 206.55,93.98 206.55,95.22 206.06,95.71 U7.11
  BOTTOM w0.114: v1(204.9,93.32) v2(203.76,93.32) R147.2
BDX_TDO_MISO: length 145.8
  S5 w0.102: v2(206.22,92.27) 206.66,91.82 206.66,89.47 206.21,89.01 206.21,84.74 207.58,83.37 207.58,58.3 203.55,54.26 203.55,44.25 201.17,41.87 201.17,40.62 199.36,38.82 199.36,38.48 195.35,34.47 191.78,34.47 188.73,31.42 187.92,31.42 180.11,23.61 179.35,23.61 178.51,22.77 178.51,15.6 176.95,14.04 173.58,14.04 169.65,10.12 162.04,10.12 157.84,5.91 141.83,5.91 141.6,5.69 141.6,4.88 v3(142.11,4.37)
  BOTTOM w0.114: R150.1 206.98,93.03 v2(206.22,92.27) 206,92.04 v1(204.77,92.04)
  BOTTOM w0.127: v3(142.11,4.37) 142.6,3.88 CONN16.66
BDX_TDO_MISO_R: length 3.8
  TOP w0.114: U7.14 v2(206.3,97.66)
  BOTTOM w0.114: v2(206.3,97.66) 206.07,97.89 R150.2 204.97,98.49 v1(204.62,98.15)
BDX_TMS_CS_N: length 151.6
  TOP w0.114: R134.1 v2(203.24,91.4)
  S8 w0.102: v3(140.82,4.42) 141.6,5.21 141.6,5.69 142.49,6.58 157.62,6.58 161.94,10.9 170.46,10.9 173.74,14.17 189.87,14.17 190.25,14.55 190.25,14.55 191.52,15.82 191.52,20.16 194.01,22.66 v2(194.41,22.66)
  S10 w0.102: v2(194.41,22.66) 194.41,24.77 196.62,26.97 201.78,26.97 206.88,32.08 206.88,47.84 204.71,50.01 204.47,50.01 204.37,50.11 204.37,54.42 206.76,56.81 206.76,60.77 205.89,61.63 205.89,67.5 204.39,68.99 204.39,76.31 201.85,78.85 201.85,79.92 200.56,81.22 200.56,87.44 201.68,88.56 201.68,89.46 203.24,91.03 v2(203.24,91.4)
  BOTTOM w0.114: v2(203.24,91.4) 202.86,91.78 v1(202.08,91.78)
  BOTTOM w0.127: v3(140.82,4.42) 141.3,3.94 141.3,3.48 141.1,3.28 CONN16.72
BDX_TMS_CS_N_R: length 11.1
  TOP w0.114: U7.5 198.02,96.36 197.36,95.71 v2(197.36,94.43) 197.36,93 198.11,92.26 R134.2
  BOTTOM w0.114: v1(197.36,93.41) v2(197.36,94.43)
BIOS_CPU_SPI2_CS_TPM: length 4.7
  TOP w0.114: U9.BJ9 90.88,88.05 v4(91.17,87.77)
  BOTTOM w0.114: v1(90.32,91.53) 91.06,90.79 TP19.1 91.17,89.66 v4(91.17,87.77)
BIOS_SPI1_CS: length 70.4
  TOP w0.114: U43.4 109.69,110.71 v3(109.35,110.36) ; R949.2 104.32,110.26 103.99,110.59 103.99,111.1 v2(103.96,111.12) ; CONN2.1 v2(53.14,118.21)
  TOP w0.127: U1.1 103.55,111.54 v2(103.96,111.12)
  S8 w0.102: v2(53.14,118.21) 53.85,118.92 66.75,118.92 67.74,117.93 69.3,117.93 69.51,118.14 75.53,118.14 75.88,118.49 78.61,118.49 79.24,117.86 92.41,117.86 96.86,113.4 98.07,113.4 99.2,112.27 100.7,112.27 102.82,112.27 v2(103.96,111.12)
  BOTTOM w0.114: v2(103.96,111.12) 104.14,110.95 104.14,108.95 104.71,108.38 105.96,108.38 107.95,110.36 v3(109.35,110.36)
BIOS_SPI2_CS: length 67.8
  TOP w0.114: CONN2.3 v2(58.22,118.21)
  S8 w0.102: v2(97.66,111.96) 97.66,112.17 92.21,117.63 79.15,117.63 78.51,118.26 75.98,118.26 75.75,118.04 75.62,117.91 69.6,117.91 69.4,117.7 58.72,117.7 v2(58.22,118.21)
  BOTTOM w0.114: R936.2 109.47,104.85 109.47,106.2 Q1.S 110.78,108.67 v1(108.08,108.67) 106.6,108.67 106.06,108.13 104.61,108.13 103.9,108.85 103.9,110.19 102.25,111.84 98.89,111.84 98.8,111.75 97.87,111.75 v2(97.66,111.96)
  BOTTOM w0.127: U31.1 97.04,112.59 v2(97.66,111.96)
BIOS_SPI2_CS_SWITCH: length 7.8
  TOP w0.114: v3(110.74,106.56) 109.92,107.38 U44.4
  BOTTOM w0.114: Q1.D v3(110.74,106.56) 110.27,106.56 109.73,106.02 R935.2 109.78,104.14 v1(110.74,104.14)
BIOS_SPI_C_CLK: length 79.2
  TOP w0.114: v3(110.24,110.36) 110.24,110.33 110.76,109.8 111.32,109.8 111.64,110.12 U43.7 ; CONN3.4 v2(45.76,114.86)
  TOP w0.127: U1.6 v2(97.82,115.13)
  S8 w0.102: v2(45.76,114.86) 46.34,114.28 47.27,114.28 47.7,114.71 47.7,115.09 52.24,119.63 93.3,119.63 95.78,117.15 95.78,116.71 97.36,115.13 v2(97.82,115.13)
  BOTTOM w0.114: v3(110.24,110.36) 109.6,111 107.31,111 106.86,111.46 106.86,112.98 105.28,114.55 104.13,114.55 U31.6
  BOTTOM w0.127: U31.6 102.89,115.13 102.46,114.71 98.24,114.71 v2(97.82,115.13)
BIOS_SPI_C_MISO: length 75.8
  TOP w0.114: 102.58,113.86 100.02,113.86 v2(99.47,113.31) ; CONN3.5 47.03,119.77 47.55,119.26 49.23,119.26 v2(49.56,119.58) ; U43.12 110.34,116.31 109.66,115.63 108.78,115.63 107.56,114.41 107.11,114.41 106.61,113.92 106.08,113.92 106.03,113.97 105.56,113.97
  TOP w0.127: 105.56,113.97 105.45,113.86 U1.2 102.58,113.86
  S8 w0.102: v2(49.56,119.58) 50.32,120.35 94.8,120.35 100.12,115.03 100.12,113.96 v2(99.47,113.31)
  BOTTOM w0.127: U31.2 96.73,113.86 97.41,113.18 99.34,113.18 v2(99.47,113.31)
BIOS_SPI_C_MOSI: length 86.8
  TOP w0.114: CONN3.6 v2(47.03,114.86) ; U43.9 112.29,116.74 v3(111.76,116.2)
  TOP w0.127: v2(97.54,116.92) 97.02,116.4 U1.5
  S8 w0.102: v3(111.76,116.2) 111.94,116.03 111.94,115.26 111,114.32 102.11,114.32 100.51,112.73 99.39,112.73 98.63,113.49 98.63,115.82 v2(97.54,116.92) 95.83,118.62 95.83,118.81 94.53,120.12 52.04,120.12 47.03,115.1 v2(47.03,114.86)
  BOTTOM w0.114: v2(47.03,114.86) v1(45.67,113.51)
  BOTTOM w0.127: U31.5 101.12,116.4 100.94,116.58 97.87,116.58 v2(97.54,116.92)
BIOS_SPI_CI_N: length 55.3
  TOP w0.114: U2.1 v2(61.84,112.47)
  BOTTOM w0.114: v2(61.84,112.47) U32.3 62.43,113.18 63.7,114.45 64.02,114.45 65.25,115.69 65.25,117.07 65.86,117.68 66.67,117.68 v1(67.99,119) 68.35,119.35 93.98,119.35 95.18,118.15 98.25,118.15 99.49,116.92 104.24,116.92 104.58,116.59 105.11,116.59 105.59,116.1 107.31,116.1 107.8,116.59 108.71,116.59 109.47,115.82 R924.1
BIOS_SPI_CI_N_R: length 3.4
  TOP w0.114: U43.3 109.04,112.85 109.22,113.03 v2(109.35,113.03)
  BOTTOM w0.114: v1(109.09,112.14) 109.09,112.78 v2(109.35,113.03) 109.35,113.49 109.47,113.62 R924.2
BIOS_SPI_CLK: length 17.5
  TOP w0.114: v3(111.51,115.44) 109.98,113.92 107.31,113.92 106.63,113.23 102.33,113.23 100.86,111.77 99.83,111.77 99.11,111.05 R52.2
  BOTTOM w0.114: v1(112.68,116.39) 112.65,116.36 112.65,115.64 R427.2 v3(111.51,115.44) R926.1
BIOS_SPI_CLK_R: length 45.7
  TOP w0.114: v2(99.44,108.84) 99.44,109.2 R52.1 ; U9.BG13 v4(92.16,86.05)
  S5 w0.102: v2(99.44,108.84) 99.44,108.2 99.31,108.07 99.31,106.74 99.52,106.54 99.52,105.43 99.19,105.11 98.73,105.11 98.6,105.23 97.18,105.23 94.5,102.56 94.5,100.96 93.47,99.93 93.47,96.32 93.47,96.32 93.47,92.96 95.33,91.11 98.37,91.11 99.87,89.61 99.87,89.42 99.93,89.36 99.93,88.82 99.97,88.78 99.97,88.46 99.87,88.37 99.87,88.34 99.03,87.5 99.03,86.56 98.76,86.28 98.76,84.91 97.05,83.2 94.14,83.2 93.45,83.9 92.06,83.9 91.78,84.17 91.78,84.64 92.16,85.02 v4(92.16,86.05)
  BOTTOM w0.114: v1(99.16,107.66) 99.44,107.93 v2(99.44,108.84)
BIOS_SPI_CS0_N: length 17.9
  TOP w0.114: R15.1 72.8,114.43 72.52,114.71 72.52,115.54 72.15,115.91 71.82,115.91 69.93,117.81 68.35,117.81 67.11,119.05 65.15,119.05 v2(64.39,118.29) 62.03,115.93 R6.2 61.37,115.21 60.64,114.48 U2.4
BIOS_SPI_CS0_N_R: length 36.4
  TOP w0.114: v4(89.68,88.63) U9.BN7 ; v2(75.01,114.71) 74.73,114.43 R15.2
  S5 w0.102: v4(89.68,88.63) 90.32,89.27 90.32,89.76 88.75,91.33 88.75,93.98 84.79,97.94 83.6,97.94 82.19,99.34 80.47,101.06 80.01,101.06 78.87,102.2 78.87,102.48 78.3,103.04 78.3,107.46 77.87,107.89 77.87,110.49 75.84,112.52 75.84,113.87 v2(75.01,114.71)
  BOTTOM w0.114: v2(75.01,114.71) 75.01,113.89 v1(75.21,113.69)
BIOS_SPI_CS1_N: length 9.9
  BOTTOM w0.114: R70.1 63.37,108.51 62.97,108.1 v1(62.51,108.1) 61.62,108.1 60.05,109.67 R460.2 59.08,110.26 59.08,112.75 59.51,113.18 U32.4
BIOS_SPI_CS1_N_R: length 39.3
  TOP w0.114: U9.BT13 87.91,86.34 v4(88.2,86.05)
  S3 w0.102: v2(66.17,108.33) 66.17,108.1 67.44,106.83 68.02,106.83 76,98.86 79.83,98.86 82.17,96.52 84.61,96.52 87.66,93.47 87.66,92.51 86.51,91.36 86.51,89.28 86.74,89.05 86.92,89.05 87.1,88.87 87.1,88.47 86.74,88.11 86.74,87.68 87.22,87.2 87.22,86.66 87.84,86.05 v4(88.2,86.05)
  BOTTOM w0.114: v1(66.17,107.52) v2(66.17,108.33) 65.99,108.51 R70.2
BIOS_SPI_HOLD_N: length 11.1
  TOP w0.114: R21.2 94.76,114.41 95.31,113.86 U1.7
  TOP w0.127: U1.7 v2(97.82,113.86)
  BOTTOM w0.114: U31.7 104.83,113.86 v1(105.16,113.54)
  BOTTOM w0.127: U31.7 v2(97.82,113.86)
BIOS_SPI_KGI_N: length 67.8
  TOP w0.114: v2(62.48,115.16) 61.84,114.52 U2.3 ; U44.1 106.95,108.85 106.17,108.08 97.28,108.08 96.01,106.81 95.38,106.81 94.87,106.3 93.73,106.3 92.84,107.19 92.84,114.05 95.38,116.59 v2(95.38,118.62)
  BOTTOM w0.114: U32.1 61.84,114.52 v2(62.48,115.16) 62.87,114.78 64.01,114.78 64.57,115.34 v1(64.57,116.33) 64.57,117.65 66.55,119.63 94.36,119.63 v2(95.38,118.62)
BIOS_SPI_MISO: length 68.7
  TOP w0.114: v2(91.41,116.05) 90.53,116.94 R4.2 ; v4(91.17,82.62) 91.15,82.63 U9.BJ20
  S3 w0.102: v3(100.71,115.32) 99.89,115.32 99.51,115.7 98.63,115.7 98.27,115.34 98.27,114.94 98,114.67 95.28,114.67 92.99,116.97 92.33,116.97 v2(91.41,116.05)
  S8 w0.102: v3(100.71,115.32) 107.82,115.32 108.2,114.94 110.62,114.94 111,115.32 111,117.86 v3(110.11,118.75)
  S10 w0.102: v4(91.17,82.62) 91.17,83.7 91.67,84.2 91.67,84.58 92.04,84.96 92.04,85.4 91.78,85.67 91.78,86.39 92.05,86.66 92.05,87.02 92.54,87.51 92.54,88.84 92.41,88.98 92.41,96.07 89.56,98.91 89.56,101.68 89.81,101.93 89.81,102.86 89.71,102.96 89.71,107.95 90.35,108.58 90.35,114.99 v2(91.41,116.05)
  BOTTOM w0.114: v2(91.41,116.05) 91.92,116.56 91.92,117.64 v1(91.63,117.94) ; R930.1 109.48,120.44 110.11,119.81 v3(110.11,118.75)
BIOS_SPI_MOSI: length 54.1
  S5 w0.102: v2(108.84,106.3) 108.84,107.94 108.77,108.01 108.77,111.8 109.8,112.84 109.8,114.83 108.84,115.8 108.84,117.55 109.68,118.39 109.68,118.92 111.22,120.47 v3(111.76,120.47)
  S10 w0.102: v3(111.76,120.47) 113.16,119.07 113.16,116.86 v2(113.61,116.41)
  BOTTOM w0.114: v2(108.84,106.3) 108.2,106.93 101.68,106.93 101.05,106.3 99.54,106.3 98.65,107.19 97.28,107.19 95.46,109.01 95.21,109.01 95.13,109.09 92.96,109.09 92.33,108.46 92.33,107.82 91.82,107.31 90.17,107.31 89.24,108.25 86.12,108.25 85.91,108.46 82.42,108.46 82.08,108.8 R462.1 ; R928.1 v3(111.76,120.47) ; R435.2 v2(113.61,116.41)
BIOS_SPI_MOSI_R: length 29.7
  TOP w0.114: U9.BL11 v4(90.67,86.91)
  S5 w0.102: v2(80.39,107.95) 80.9,107.44 80.9,106.71 81.58,106.03 81.58,100.93 83.88,98.63 85.15,98.63 90.02,93.76 90.02,93.63 90.73,92.93 90.73,91.99 91.26,91.46 91.26,88.29 91.57,87.99 91.57,87.55 90.92,86.91 v4(90.67,86.91)
  BOTTOM w0.114: v2(80.39,107.95) 80.59,108.15 R462.2 80.31,109.08 v1(80.31,109.96)
BIOS_SPI_WP_N: length 11
  TOP w0.114: v2(100.05,115.8) 100.85,115.8 101.52,115.13 U1.3
  BOTTOM w0.114: v1(94.43,115.47) R440.2 94.64,114.41 95.37,115.13 U31.3
  BOTTOM w0.127: U31.3 96.74,115.13 97.41,115.8 v2(100.05,115.8)
BIST_ENABLE: length 30.8
  TOP w0.108: v4(98.1,60.87) 98.11,60.87 98.4,60.58 U9.AM69
  TOP w0.114: R308.2 v2(96.72,36.83)
  S10 w0.102: v4(98.1,60.87) 97.8,60.87 97.23,60.3 97.23,59.64 97.51,59.36 97.51,58.95 97.28,58.72 97.28,58.17 95.22,56.11 95.22,45.42 95.07,45.26 95.07,39.83 95.86,39.04 95.86,37.31 96.34,36.83 v2(96.72,36.83)
  BOTTOM w0.114: v2(96.72,36.83) 96.72,36.47 98.09,35.11 98.11,35.11 v1(98.12,35.1)
BMC_BTN_LOCKED_N: length 32
  TOP w0.114: R341.2 v2(11.06,20.77)
  BOTTOM w0.114: v1(27.53,9.65) 23.97,9.65 22.83,8.51 21.26,8.51 16.87,12.9 10.16,12.9 9.63,13.44 9.61,13.44 9.5,13.55 9.5,19.21 v2(11.06,20.77) 11.67,21.38 CONN14.184
BMC_FAULT_LED: length 215.3
  TOP w0.114: R336.1 v2(8.28,23.31) R513.1 ; U12.P6 v3(193.09,48.61)
  S3 w0.102: v2(97.37,17.92) 96.97,17.92 93.27,14.22 87.34,14.22 85.95,12.83 79.91,12.83 79.49,13.25 76.76,13.25 75.54,14.46 70.38,14.46 69.86,13.94 55.86,13.94 55.05,13.13 51.64,13.13 50.83,13.94 48.25,13.94 47.01,15.19 43.92,15.19 41.1,18.01 31.04,18.01 30.66,17.63 22.67,17.63 20.99,19.3 10.91,19.3 8.81,21.4 8.81,22.77 v2(8.28,23.31)
  S8 w0.102: v2(97.37,17.92) 99.26,17.92 99.98,18.64 104.24,18.64 104.55,18.95 106.65,18.95 111.15,23.44 147.48,23.44 149.9,25.86 160.3,25.86 163.37,28.93 180.93,28.93 185.09,33.09 185.09,40.26 190.75,45.92 190.75,46.98 191.65,47.88 192.63,47.88 193.09,48.33 v3(193.09,48.61)
  BOTTOM w0.114: v3(193.09,48.61) 193.09,48.13 v1(192.28,47.32)
BMC_ID_BTN: length 220.6
  TOP w0.114: R327.2 v2(8.28,28.39) ; U12.M4 v3(191.09,50.61)
  S3 w0.102: v2(8.28,28.39) 9.73,26.94 9.73,22.72 11.09,21.36 11.61,21.36 12.7,20.27 31.98,20.27 33.17,21.46 34.9,21.46 35.59,20.78 39.62,20.78 44.3,16.1 47.38,16.1 48.63,14.86 67.32,14.86 67.93,15.47 71.86,15.47 72.52,16.13 72.96,16.13 73.21,16.38 76.54,16.38 76.87,16.05 80.6,16.05 82.91,13.74 85.57,13.74 86.96,15.14 87.48,15.14 90.76,18.42 93.77,18.42 95.17,19.81 v2(97.34,19.81)
  S8 w0.102: v2(97.34,19.81) 97.35,19.82 104.13,19.82 104.17,19.86 106.26,19.86 110.76,24.36 147.1,24.36 149.52,26.77 159.92,26.77 162.46,29.31 162.59,29.44 163,29.84 180.55,29.84 184.18,33.47 184.18,40.68 184.58,41.08 187.24,43.74 187.24,46.3 189.28,48.34 189.28,50.41 189.92,51.05 190.63,51.05 191.07,50.61 v3(191.09,50.61)
  BOTTOM w0.114: v3(191.09,50.61) 190.57,50.09 189.76,50.09 v1(188.87,49.2)
BMC_ID_LED: length 216.1
  TOP w0.114: R514.1 v2(8.28,22.04) R338.1 ; U12.N7 v3(194.09,49.61)
  S3 w0.102: v2(8.28,22.04) 8.28,21.58 10.78,19.08 20.9,19.08 22.57,17.4 30.76,17.4 31.14,17.78 41,17.78 43.82,14.96 46.91,14.96 48.16,13.72 50.73,13.72 51.54,12.9 55.14,12.9 55.88,13.64 71.25,13.64 71.34,13.55 76.14,13.55 76.73,12.95 79.34,12.95 79.69,12.6 86.04,12.6 87.44,14 93.36,14 96.82,17.45 v2(98.22,17.45)
  S8 w0.102: v3(194.09,49.61) 194.09,49.33 193.55,48.79 193.55,48.46 193.52,48.44 193.52,48.43 193.27,48.18 193.26,48.18 192.74,47.65 191.75,47.65 190.98,46.88 190.98,45.82 185.32,40.16 185.32,32.99 181.03,28.7 163.54,28.7 160.06,25.22 149.58,25.22 147.58,23.22 122.03,23.22 121.25,22.43 114.63,22.43 114.18,21.97 110.19,21.97 110,21.97 106.75,18.72 104.64,18.72 104.34,18.41 100.08,18.41 99.54,17.88 99.11,17.45 v2(98.22,17.45)
  BOTTOM w0.114: v1(195.99,49.28) 195.83,49.12 195.71,49.12 195.66,49.07 194.63,49.07 v3(194.09,49.61)
BMC_LOCK_BTN: length 217.4
  TOP w0.114: U12.P7 v3(194.09,48.61) ; R512.1 v2(8.28,20.77) R341.1
  S3 w0.102: v2(97.37,16.99) 96.68,16.99 93.46,13.77 87.53,13.77 86.13,12.37 79.52,12.37 79.22,12.67 71.83,12.67 71.72,12.57 69.13,12.57 68.99,12.42 57.09,12.42 57.01,12.5 51.63,12.5 50.64,13.49 48.06,13.49 46.82,14.73 43.73,14.73 40.96,17.5 35.39,17.5 34.73,16.84 31.06,16.84 30.07,15.84 25.17,15.84 24.71,16.31 21.73,16.31 19.19,18.85 10.2,18.85 v2(8.28,20.77)
  S8 w0.102: v2(97.37,16.99) 98.98,16.99 99.77,17.78 100.17,18.19 104.43,18.19 104.74,18.49 106.84,18.49 110.1,21.74 114.27,21.74 114.73,22.2 121.34,22.2 122.13,22.99 148.15,22.99 150.08,24.91 168.55,24.91 170.21,26.57 174.6,26.57 176.12,28.09 181.74,28.09 185.95,32.31 185.95,33.04 185.81,33.18 185.55,33.45 185.55,40.03 191.21,45.69 191.21,46.79 191.84,47.42 192.86,47.42 194.05,48.61 v3(194.09,48.61)
  BOTTOM w0.114: v3(194.09,48.61) 194.36,48.34 194.36,46.58 194.03,46.25 v1(194.03,45.59)
BMC_NMI_BTN: length 220.8
  TOP w0.114: R511.1 v2(8.28,24.58) R332.1 ; U12.M8 v3(195.09,50.61)
  S3 w0.102: v2(8.28,24.58) 9.04,23.81 9.04,21.49 11,19.53 21.09,19.53 22.76,17.86 30.55,17.86 30.96,18.26 35.43,18.26 37.08,19.91 39.52,19.91 44.01,15.42 47.1,15.42 48.35,14.17 51.46,14.17 52.27,13.36 54.95,13.36 55.77,14.17 69.77,14.17 70.38,14.78 73.56,14.78 74.06,15.29 76.66,15.29 77.47,14.48 81.2,14.48 82.63,13.06 85.85,13.06 87.25,14.45 93.09,14.45 97.03,18.39 v2(98.2,18.39)
  S8 w0.102: v2(98.2,18.39) 99.41,18.39 99.89,18.87 104.15,18.87 104.45,19.18 106.54,19.18 111.04,23.67 147.39,23.67 149.8,26.09 160.21,26.09 163.15,29.03 163.28,29.16 180.84,29.16 184.86,33.18 184.86,40.36 190.53,46.02 190.53,47.07 191.61,48.16 192.55,48.16 192.66,48.26 192.66,48.79 193.02,49.15 193.55,49.15 193.66,49.26 193.66,49.79 193.98,50.11 194.59,50.11 v3(195.09,50.61)
  BOTTOM w0.114: v3(195.09,50.61) 195.58,50.61 v1(195.96,50.99)
BMC_PRESENT_BDX_GPIO17: length 300.5
  TOP w0.114: U12.A8 194.68,63.02 194.68,68.21 191.67,71.22 191.67,73.38 v2(191.04,74) ; v2(98.73,92.53) 98.73,91.69 98.35,91.31 U9.AN3
  S3 w0.102: v2(98.73,92.53) 97.13,94.13 97.13,96.94 96.8,97.27 96.8,105.66 v3(97.71,106.58) 98.49,107.35 101.35,107.35 102.11,106.59 102.11,101.47 102.33,101.25 105.06,101.25 105.32,100.99 111.89,100.99 112.39,100.48 113.3,100.48 115.19,98.59 115.19,96.51 121.34,90.36 125.43,90.36 130,85.79 130,85.24 133.24,81.99 135.5,81.99 136.4,81.1 148.91,81.1 153.12,76.89 v2(156.06,76.89) ; v2(26.87,68.28) 27.53,68.94 27.53,70.02 26.75,70.81 26.39,70.81 25.98,71.21 25.98,71.96 22.83,75.11 v2(22.83,80.06)
  S5 w0.102: v2(22.83,80.06) 22.83,85.55 23.5,86.22 23.5,96.49 19.94,100.05 19.94,101.78 16.13,105.59 16.13,114.09 16.32,114.28 16.32,116.65 17.93,118.26 24.46,118.26 25.14,118.93 30.52,118.93 30.56,118.97 35.03,118.97 35.56,118.44 51.22,118.44 51.83,119.05 74.26,119.05 74.88,118.43 74.88,118.4 75.15,118.14 75.53,118.14 75.55,118.16 79.26,118.16 79.34,118.08 87.1,118.08 87.86,118.85 90.66,118.85 95.76,113.75 95.76,111.01 97.84,108.93 97.84,108.25 97.71,108.13 v3(97.71,106.58)
  S8 w0.102: v2(191.04,74) 183.33,74 173.86,83.47 173.86,83.61 171.01,86.46 168.66,86.46 165.63,83.43 165.63,81.11 161.41,76.89 v2(156.06,76.89)
  BOTTOM w0.114: v1(99.49,92.81) 99.21,92.53 v2(98.73,92.53) ; v2(26.87,68.28) 26.87,68.37 26.38,68.86 R913.2
BMC_PWR_BTN: length 217.5
  TOP w0.114: R331.1 v2(8.28,25.85) R510.1 ; U12.P5 v3(192.09,48.61)
  S3 w0.102: v2(97.37,18.85) 96.49,18.85 92.33,14.68 87.15,14.68 85.76,13.28 82.72,13.28 80.46,15.54 74,15.54 73.46,15.01 70.28,15.01 69.67,14.4 48.44,14.4 47.2,15.65 44.11,15.65 39.61,20.14 36.99,20.14 35.34,18.49 30.86,18.49 30.45,18.08 22.86,18.08 21.18,19.76 11.09,19.76 9.27,21.59 9.27,24.86 v2(8.28,25.85)
  S8 w0.102: v2(97.37,18.85) 99.47,18.85 99.73,19.1 104.05,19.1 104.36,19.41 106.45,19.41 110.95,23.9 147.29,23.9 149.71,26.31 160.11,26.31 162.92,29.12 163.05,29.25 163.18,29.39 180.74,29.39 184.63,33.28 184.63,40.49 185.04,40.89 189.59,45.44 189.59,46.89 190.74,48.04 191.17,48.04 191.74,48.61 v3(192.09,48.61)
  BOTTOM w0.114: v3(192.09,48.61) 191.94,48.61 v1(190.83,47.5)
BMC_READY_CPU_ENABLE: length 273.5
  TOP w0.114: v3(23.47,32.13) 23.77,32.44 28.73,32.44 29.26,32.97 29.26,38.38 29.9,39.01 29.9,45.16 30.66,45.92 v2(31.32,45.92) ; v3(199.09,47.62) 198.6,48.11 U12.R11
  S10 w0.102: v3(91.74,19.89) 88.44,19.89 87.5,20.83 81.86,20.83 81.08,21.62 76.43,21.62 75.11,22.94 68.45,22.94 66.34,20.83 64.29,20.83 63.47,20.02 60.31,20.02 59.78,19.48 55.88,19.48 55.14,20.22 42.32,20.22 38.56,16.46 28.63,16.46 25.81,19.28 25.81,29.79 v3(23.47,32.13)
  BOTTOM w0.114: R952.2 30.3,45.97 R953.1 v2(31.32,45.92) 31.45,46.05 v1(31.45,46.81) ; v3(91.74,19.89) 93.98,19.89 95.12,21.03 95.12,26.87 101.27,33.02 101.27,35.92 102.57,37.21 108.51,37.21 109.19,37.9 112.94,37.9 113.53,37.31 113.67,37.31 114.91,36.07 130.05,36.07 139.42,45.44 139.42,61.26 140.45,62.29 149.16,62.29 151.01,60.44 158.75,60.44 160.92,58.27 176.26,58.27 177.52,59.54 179.96,59.54 181.52,57.98 181.52,43.66 182.15,43.02 189.25,43.02 190.85,41.43 193.78,41.43 194.87,42.52 194.87,43.76 194.48,44.15 194.48,45.13 194.94,45.59 195.25,45.59 197.76,48.11 198.73,48.11 199.09,47.75 v3(199.09,47.62)
BMC_READY_CPU_ENABLE_R: length 30.3
  S3 w0.102: v2(28.45,46.99) 27.81,47.62 27.81,50.8 24.38,54.23 22.61,54.23 18.92,57.91 18.92,64.01 17.15,65.78 v2(15.87,65.78)
  BOTTOM w0.114: R952.1 v2(28.45,46.99) 27.33,46.99 v1(27.28,46.94) ; CONN14.44 v2(15.87,65.78)
BMC_RST_BTN: length 218.5
  TOP w0.114: U12.M3 v3(190.09,50.61) ; R329.1 v2(8.28,27.12) R504.1
  S3 w0.102: v2(98.15,19.35) 95.03,19.35 93.87,18.19 90.85,18.19 87.57,14.91 87.06,14.91 85.66,13.51 82.82,13.51 80.56,15.77 73.9,15.77 73.37,15.24 68.02,15.24 67.41,14.63 48.53,14.63 47.29,15.88 44.2,15.88 39.71,20.37 36.89,20.37 35.24,18.72 30.77,18.72 30.36,18.31 22.95,18.31 21.28,19.99 11.19,19.99 9.5,21.68 9.5,25.9 v2(8.28,27.12)
  S8 w0.102: v2(98.15,19.35) 98.17,19.33 103.96,19.33 104.27,19.63 106.35,19.63 110.85,24.13 147.2,24.13 149.61,26.54 160.02,26.54 162.69,29.21 162.69,29.22 162.82,29.35 163.09,29.62 180.65,29.62 184.4,33.37 184.4,40.58 184.81,40.99 188.7,44.87 188.7,46.53 189.53,47.37 189.53,50.06 v3(190.09,50.61)
  BOTTOM w0.114: v3(190.09,50.61) 189.97,50.5 v1(188.87,50.5)
BMC_SPI_CLK: length 182.5
  S8 w0.102: v2(110.49,115.7) 110.36,115.57 109.6,115.57 108.46,116.71 102.36,116.71 100.53,118.54 98.63,118.54 96.37,120.8 49.2,120.8 43.69,115.29 38.13,115.29 30.51,107.67 15.42,107.67 11.14,103.39 11.14,49.65 19.68,41.1 v2(19.68,36.08)
  BOTTOM w0.114: CONN14.135 v2(19.68,36.08) ; R925.1 v2(110.49,115.7)
BMC_SPI_CLK_R: length 3.9
  TOP w0.114: v2(110.36,113.03) 110.34,113.01 U43.5
  BOTTOM w0.114: R925.2 110.49,113.16 v2(110.36,113.03) 110.24,112.9 v1(110.24,111.38)
BMC_SPI_CS0: length 6.6
  TOP w0.114: U42.1 103.97,118.1 104.8,117.27 104.8,116.99 105.51,116.28 106.07,116.28 R951.2 107.79,116.26 v2(108.21,115.83)
  BOTTOM w0.114: v2(108.21,115.83) 108.33,115.72 R923.1
BMC_SPI_CS0_R: length 3.5
  TOP w0.114: v2(108.46,113.03) 108.39,112.97 U43.2
  BOTTOM w0.114: v1(107.82,112.01) 107.82,112.39 v2(108.46,113.03) 108.46,113.49 108.33,113.62 R923.2
BMC_SPI_CS1: length 17.7
  TOP w0.114: U44.3 108.44,107.55 108.71,107.82 108.71,109.22 108.46,109.47 105.92,109.47 v2(105.79,109.6) 105.94,109.75 R950.2 ; U42.3 v3(104.5,119.4)
  S5 w0.102: v2(105.79,109.6) 105.03,110.36 105.03,112.14 104.01,113.16 104.01,118.91 v3(104.5,119.4)
BMC_SPI_CS_N: length 177.1
  TOP w0.114: U42.4 v3(102.6,119.4)
  S8 w0.102: v3(102.6,119.4) 101.58,119.4 99.43,121.55 99.03,121.95 41.2,121.95 39.04,119.79 39.04,118.52 36.99,116.47 33.61,116.47 31.95,114.81 21.2,114.81 10.45,104.06 10.45,49.37 18.03,41.78 v2(18.03,36.68)
  BOTTOM w0.114: CONN14.133 v2(18.03,36.68) ; v3(102.6,119.4) 102.36,119.63 v1(101.73,119.63)
BMC_SPI_DI: length 189.7
  S8 w0.102: v3(106.93,120.47) 106.93,119.75 105.34,118.16 102.49,118.16 98.93,121.72 41.29,121.72 39.27,119.7 39.27,118.43 37.09,116.24 35.28,116.24 33.59,114.55 21.27,114.55 10.68,103.96 10.68,49.46 18.49,41.65 18.49,36.49 18.21,36.21 18.21,35.62 18.61,35.23 19.04,35.23 v2(19.39,34.88)
  BOTTOM w0.114: v2(19.39,34.88) CONN14.139 26.22,34.88 v1(27.15,35.81) ; R929.1 v3(106.93,120.47)
BMC_SPI_DI_R: length 2.4
  TOP w0.114: U43.14 109.04,118.25 108.55,118.75 v3(108.46,118.75)
  BOTTOM w0.114: v3(108.46,118.75) 108.46,118.81 108.13,119.14 R929.2
BMC_SPI_DO: length 191.3
  S8 w0.102: v3(110.24,120.34) 107.85,120.34 105.44,117.93 102.4,117.93 98.84,121.49 41.39,121.49 39.5,119.6 39.5,118.33 37.18,116.01 35.37,116.01 33.41,114.05 21.08,114.05 10.91,103.87 10.91,49.56 18.72,41.74 18.72,36.4 18.67,36.35 v2(18.67,35.81)
  BOTTOM w0.114: v2(18.67,35.81) 19,35.48 CONN14.137 25.07,35.48 v1(27.1,37.52) ; R927.1 v3(110.24,120.34)
BMC_SPI_DO_R: length 1.9
  TOP w0.114: v3(110.92,118.75) 110.99,118.67 U43.11
  BOTTOM w0.114: v3(110.92,118.75) 111,118.83 R927.2
BMC_SPI_OUT_SEL: length 183.1
  TOP w0.114: R922.2 100.92,118.1 U42.6 101.92,116.01 v3(102.11,115.82)
  S8 w0.102: v3(102.11,115.82) 100.84,115.82 96.09,120.57 49.33,120.57 43.82,115.07 38.25,115.07 30.62,107.44 15.69,107.44 11.36,103.11 11.36,49.75 20.14,40.97 20.14,34.38 v2(20.04,34.28)
  BOTTOM w0.114: v2(20.04,34.28) CONN14.141 26.96,34.28 v1(27.08,34.39)
BMC_UART0_DIR_SEL: length 299.2
  TOP w0.114: U12.L2 189.15,51.67 187.3,51.67 186.85,52.12 182.07,52.12 181.13,51.18 181.13,45.9 182.27,44.76 v2(183.58,44.76)
  S3 w0.102: v2(26.82,69.5) 26.56,69.5 24.56,71.5 16.92,71.5 14.76,69.34 14.76,67.54 v2(15.11,67.18)
  S5 w0.102: v2(98.7,22.26) 97.44,22.26 95.95,20.77 95.95,13.03 94.86,11.94 94.86,9.76 94.2,9.1 88.88,9.1 83.61,3.84 77.61,3.84 77.56,3.89 72.69,3.89 72.39,4.19 67.72,4.19 67.26,3.73 66.36,3.73 65.57,4.52 63.23,4.52 62.08,3.37 61.66,3.37 61.53,3.23 59.92,1.62 23.88,1.62 21.84,3.67 21.84,7.63 14.46,15 14.46,31.16 10.72,34.9 10.72,62.79 v2(15.11,67.18)
  S8 w0.102: v2(183.58,44.76) 182.39,43.57 177.93,43.57 176.07,41.71 176.07,37.54 175.51,36.98 173.82,35.29 171.94,35.29 171.3,34.64 171.3,32.07 170.42,31.19 166.93,31.19 166.37,31.75 165.03,31.75 164.43,31.16 161.27,31.16 157.79,27.69 149.14,27.69 146.72,25.27 99.89,25.27 99.75,25.14 98.7,24.08 v2(98.7,22.26)
  BOTTOM w0.114: v2(183.58,44.76) v1(184.58,44.76) R152.2 ; v2(26.82,69.5) 26.49,69.82 R912.2
BMC_UART0_DIR_SEL_R: length 21.9
  S3 w0.102: v2(16.74,69.55) 17.6,70.41 23.11,70.41 v2(23.52,70)
  BOTTOM w0.114: v2(23.52,70) 24.87,70 R912.1 25.05,70.03 25.3,70.29 27.45,70.29 28.32,71.15 28.32,76.4 28.55,76.63 v1(28.55,76.63) ; v2(16.74,69.55) 16.3,69.98 CONN14.30
BMC_UART0_RX: length 24.6
  TOP w0.114: R315.2 v2(11.06,30.93)
  S10 w0.102: v2(19.07,27.08) 18.03,28.12 13.87,28.12 v2(11.06,30.93)
  BOTTOM w0.114: v1(29.57,31.93) 29.36,31.72 25.1,31.72 24.31,30.94 24.31,28.28 23.1,27.08 CONN14.165 v2(19.07,27.08)
BMC_UART0_TX: length 22
  TOP w0.114: R321.2 v2(11.06,29.66)
  S10 w0.102: v2(11.06,29.66) 13.67,27.05 v2(18.24,27.05)
  BOTTOM w0.114: v2(18.24,27.05) 18.87,27.68 CONN14.163 23.1,27.68 23.83,28.4 23.83,31.52 24.64,32.33 v1(27.1,32.33)
BMC_UART1_RX: length 39.8
  TOP w0.114: R539.1 v2(11.06,32.2)
  S5 w0.102: v2(11.06,32.2) 9.59,32.2 9.02,31.63 7.93,31.63 7.6,31.29 7.6,28.3 8.02,27.88 11.76,27.88 13.78,25.87 13.78,12.2 v2(16.66,9.32)
  BOTTOM w0.114: v2(11.06,32.2) 11.59,31.67 11.59,27.34 12.15,26.78 CONN14.166
BMC_UART1_TX: length 44.1
  TOP w0.114: R378.1 v2(11.06,33.47)
  S5 w0.102: v2(11.06,33.47) 10.46,32.86 8.09,32.86 7.13,31.9 7.13,27.23 7.83,26.53 12.19,26.53 13.55,25.17 13.55,11.67 16.9,8.32 v2(17.72,8.32)
  BOTTOM w0.114: CONN14.164 12.47,27.38 11.99,27.86 11.99,32.54 v2(11.06,33.47)
BMCINIT: length 21.9
  TOP w0.108: v4(103.05,60.86) 102.77,60.58 U9.AD69
  TOP w0.114: R291.1 v2(105.46,43)
  S10 w0.102: v2(105.46,43) 104.95,43.51 104.95,52.68 103.4,54.23 103.4,58.83 103.45,58.88 103.45,59.92 103.66,60.12 103.66,60.48 103.28,60.86 v4(103.05,60.86)
  BOTTOM w0.114: v1(106.1,41.91) 106.1,42.37 v2(105.46,43)
BMM_CD3_INT0: length 219.5
  TOP w0.114: R1073.2 v2(182.98,50.04) ; v2(37.08,119.89) 37.11,119.89 38.63,121.41 41.7,121.41 42.43,120.68 42.43,116.22 44.55,114.1 44.55,112.5 44.73,112.32 R1078.2 45.59,111.81 45.59,110.46 45.29,110.16 R1090.2
  S8 w0.102: v2(37.08,119.89) 38.29,119.89 40.58,122.18 99.12,122.18 99.13,122.17 141.92,122.17 146.85,117.25 150.37,117.25 v2(151.13,116.48)
  S10 w0.102: v2(151.13,116.48) 153.16,114.45 155.08,114.45 160.81,108.72 160.81,105.35 168.26,97.89 168.26,90.88 183.95,75.19 183.95,51 v2(182.98,50.04)
  BOTTOM w0.114: R1111.2 v2(37.08,119.89)
BMM_CD3_INT0_R: length 4.6
  TOP w0.114: U12.N1 v2(185.8,50.11) 185.18,50.11 R1073.1
  BOTTOM w0.114: v2(185.8,50.11) 185.34,50.57 v1(184.89,50.57)
BMM_CLK3: length 108.2
  S3 w0.102: v2(4.32,101.09) 3.56,100.33 3.56,93.19 4.06,92.68 6.63,92.68 17.17,103.23 30.4,103.23 v2(30.99,102.64)
  BOTTOM w0.114: R1098.1 R1097.1 ; R1097.1 R1065.2 ; R1097.1 v2(4.32,101.09) ; R1069.2 32.59,60.33 34.61,62.34 40.17,62.34 41.77,60.74 43.68,60.74 44.06,61.12 44.06,65.07 42.85,66.28 41.38,66.28 40.93,66.73 40.93,74.7 39.93,75.71 39.93,77.41 40.17,77.65 40.17,78.14 38.97,79.34 34.1,79.34 32.82,80.62 32.82,89.18 30.91,91.09 30.91,94.36 30.06,95.2 30.06,101.05 v1(30.48,101.47) 30.99,101.98 v2(30.99,102.64)
BMM_CLK_I2C_BUS: length 52.4
  TOP w0.114: v2(18.75,105.54) 20.4,107.19 31.03,107.19 38.13,114.28 38.13,117.5 38.66,118.03 40.54,118.03 41,117.58 v2(41,117.02)
  S3 w0.102: v2(4.32,102.21) 5.41,102.21 9.04,105.84 18.44,105.84 v2(18.75,105.54)
  BOTTOM w0.114: v2(4.32,102.21) 3.91,102.62 2.59,102.62 2.47,102.49 R1098.2 ; U45.3 39.92,118.09 v2(41,117.02) ; v2(18.75,105.54) 19.43,105.54 v1(19.96,106.07)
BMM_CLK_I2C_MUX: length 65.7
  TOP w0.114: v2(1.5,101.09) 3.12,99.47 3.37,99.47 3.48,99.35 3.48,90.53 4.88,89.13 14.88,89.13 22.25,81.76 22.25,63.35 24.41,61.19 27.81,61.19 28.65,60.35 v2(28.65,59.49)
  BOTTOM w0.114: U40.3 27.75,58.59 v2(28.65,59.49) 29.88,59.49 v1(30.61,58.76) ; R1097.2 v2(1.5,101.09)
BMM_DATA3: length 116.5
  S3 w0.102: v2(33.4,104.39) 32.54,103.53 16.43,103.53 7.9,95 v2(4.45,95)
  BOTTOM w0.114: R1070.2 33.02,57.75 33.53,58.26 33.53,60.92 34.71,62.1 40.03,62.1 41.63,60.5 43.78,60.5 44.3,61.02 44.3,65.17 42.95,66.52 41.48,66.52 41.17,66.83 41.17,74.8 40.17,75.81 40.17,77.31 40.41,77.55 40.41,78.24 39.07,79.58 34.2,79.58 33.06,80.72 33.06,89.28 31.15,91.19 31.15,94.46 30.3,95.3 30.3,100.25 32.28,102.23 v1(33.27,102.23) 33.4,102.36 v2(33.4,104.39) ; R1099.1 R1066.2 4.42,93.98 4.67,93.73 4.67,88.54 v1(3.91,87.78) ; R1099.1 v2(4.45,95) ; R1099.1 R1100.1
BMM_DATA_I2C_BUS: length 54
  TOP w0.114: v2(40.14,117.02) 40.14,117.39 39.93,117.6 38.86,117.6 38.51,117.25 38.51,114.12 31.3,106.91 21.37,106.91 v2(19.28,104.83)
  S3 w0.102: v2(4.27,96.49) 4.27,98.45 10.16,104.34 18.8,104.34 v2(19.28,104.83)
  BOTTOM w0.114: v2(40.14,117.02) 39.27,117.89 U45.2 ; v2(4.27,96.49) 2.67,96.49 2.47,96.29 R1100.2 ; v2(19.28,104.83) v1(20.75,104.83)
BMM_DATA_I2C_MUX: length 59.9
  TOP w0.114: v2(1.5,95) 2.72,93.78 2.72,90.14 4.5,88.37 14.57,88.37 21.49,81.45 21.49,61.57 23.9,59.16 v2(24.97,59.16)
  BOTTOM w0.114: R1099.2 v2(1.5,95) ; U41.3 24.45,58.64 v2(24.97,59.16) 25.43,59.61 27.91,59.61 28.6,60.3 v1(30.2,60.3)
BMM_MB_ID0: length 23.9
  TOP w0.114: R318.1 v2(16.88,30.59) R317.2
  BOTTOM w0.114: v1(27.41,41.38) 26.49,42.29 23.11,42.29 22.9,42.08 CONN14.115 20.3,42.08 19.69,41.47 17.96,41.47 17.76,41.47 16.27,39.98 16.27,34.53 17.14,33.66 17.14,30.85 v2(16.88,30.59)
BMM_MB_ID1: length 24.7
  TOP w0.114: R323.1 v2(16.86,29.57) R322.2
  BOTTOM w0.114: v1(27.41,39.95) 26.06,41.3 22.86,41.3 22.68,41.48 CONN14.117 20.18,41.48 19.93,41.23 17.86,41.23 16.51,39.88 16.51,34.63 17.39,33.76 17.39,30.44 17.02,30.07 17.02,29.74 v2(16.86,29.57)
BMM_SCL1: length 3.9
  BOTTOM w0.114: CONN14.61 23.57,60.68 v1(24.16,61.26) 24.25,61.36 R581.1
BMM_SCL2: length 12.9
  S10 w0.102: v2(24.38,63.25) 23.91,63.25 23.43,62.76 22.86,62.76 21.29,61.19 v2(15.11,61.19)
  BOTTOM w0.114: R576.1 24.79,63.65 v2(24.38,63.25) ; v2(15.11,61.19) 14.9,60.98 CONN14.60
BMM_SCL3: length 11.2
  BOTTOM w0.114: CONN14.67 23.47,58.88 v1(24.13,59.54) 24.45,59.86 27.75,59.86 28.85,60.96 31.04,60.96 R1069.1
BMM_SCL4: length 61.7
  S5 w0.102: v2(15.67,59.18) 18.03,61.54 18.03,76.34 11.84,82.54 11.84,87.24 12.43,87.83 13.28,87.83 14,87.12 v2(14,85.8)
  BOTTOM w0.114: CONN14.66 v2(15.67,59.18) 16.69,59.18 19,56.87 19.32,56.87 19.36,56.83 21.49,56.83 23.19,55.13 23.19,54.82 24.14,53.87 24.14,48.68 27.33,45.49 v1(27.38,45.49) ; v2(14,85.8) 14,86.97 14.76,87.74 R786.1
BMM_SCL5: length 42.9
  S5 w0.102: v2(20.12,54.89) 18.52,56.49 18.52,61.05 18.72,61.26 18.72,76.62 13.23,82.11 13.23,86.33 v2(12.62,86.94)
  BOTTOM w0.114: v2(12.62,86.94) 12.01,87.55 v1(12.01,88.29) 13.34,88.29 14.66,89.61 R791.1 ; v2(20.12,54.89) 20.33,54.68 CONN14.73
BMM_SDA1: length 3.7
  BOTTOM w0.114: R585.1 24.77,60.37 24.6,60.2 23.49,60.2 23.37,60.08 CONN14.63
BMM_SDA2: length 12.8
  S10 w0.102: v2(24.34,62.38) 22.98,62.38 20.75,60.15 v2(15.14,60.15)
  BOTTOM w0.114: R579.1 v2(24.34,62.38) ; v2(15.14,60.15) 14.91,60.38 CONN14.62
BMM_SDA3: length 16.7
  BOTTOM w0.114: CONN14.69 22.8,58.28 22.92,58.16 22.92,55.74 23.43,55.23 23.43,54.92 24.38,53.97 24.38,53.09 24.61,52.86 27.58,52.86 27.97,53.24 27.97,53.75 28.7,54.48 v1(30.63,54.48) 32.95,54.48 R1070.1
BMM_SDA4: length 64.3
  S5 w0.102: v2(15.65,57.99) 18.06,60.4 18.06,61.24 18.26,61.45 18.26,76.44 12.06,82.63 12.06,87.15 12.52,87.6 13.18,87.6 13.46,87.33 13.46,85.17 13.79,84.84 v2(14.96,84.84)
  BOTTOM w0.114: CONN14.68 15.05,58.58 v2(15.65,57.99) 17.37,57.99 18.75,56.62 19.23,56.62 19.26,56.59 21.39,56.59 22.95,55.03 22.95,54.72 23.9,53.77 23.9,48.58 26.16,46.32 26.16,45.36 v1(27.38,44.15) ; v2(14.96,84.84) 14.96,86.02 R788.1
BMM_SDA5: length 56.1
  S5 w0.102: v2(20.12,53.8) 18.29,55.63 18.29,61.15 18.49,61.35 18.49,76.53 12.73,82.3 v2(12.73,85.65)
  BOTTOM w0.114: v2(20.12,53.8) 20.4,54.08 CONN14.75 23.24,54.08 23.66,53.66 23.66,48.48 25.15,46.99 25.15,45.06 v1(27.36,42.85) ; R792.1 14.79,88.68 13.31,87.2 13.31,86.23 v2(12.73,85.65)
BUS_RESET: length 6.7
  BOTTOM w0.114: R1114.2 36.53,122.07 37.87,122.07 v1(39.45,120.5) 39.45,120.5 39.92,120.5 40.56,119.86 40.57,119.86 U45.4
C33_BDX_PWRGOOD_CPU: length 30.3
  TOP w0.114: U12.H4 v3(191.09,55.61) ; U10.20 174.15,73.75 v2(174.35,73.94)
  S3 w0.102: v2(174.35,73.94) 175.84,72.44 178.85,72.44 184.99,66.3 184.99,60.75 189.66,56.08 190.61,56.08 v3(191.09,55.61)
  BOTTOM w0.114: v1(174.35,72.92) v2(174.35,73.94)
C33_P1V05_PCH_EN: length 164.1
  TOP w0.114: U12.P10 v3(198.09,48.61) ; R387.2 v2(67.69,4.88)
  S3 w0.102: v2(101.36,15.55) 101.36,15.24 97.61,11.48 88.48,11.48 81.19,4.19 68.38,4.19 v2(67.69,4.88)
  S8 w0.102: v3(198.09,48.61) 197.41,47.93 197.41,45.25 188.65,36.49 188.65,31.31 183.1,25.76 179.08,25.76 174.15,20.83 172.68,20.83 172.25,21.25 169.1,21.25 168.68,20.83 163.59,20.83 162.65,19.89 153.1,19.89 147.39,14.17 143.7,14.17 141.98,15.9 125.9,15.9 125.51,16.28 112.24,16.28 112.16,16.21 105.69,16.21 105.38,15.9 101.7,15.9 v2(101.36,15.55)
  BOTTOM w0.114: R735.1 R734.1 68.66,8.16 67.69,7.19 v1(67.69,5.82) v2(67.69,4.88)
C33_P1V5_PCH_EN: length 67.4
  TOP w0.114: v2(134.52,70.43) 135.16,70.43 135.81,69.77 135.81,65.58 140.82,60.58 168.65,60.58 171.88,57.36 186.71,57.36 187.96,56.11 U12.G1
  TOP w0.127: U11.5 v2(134.52,70.43)
  BOTTOM w0.114: C402.1 v2(134.52,70.43)
  BOTTOM w0.127: C402.1 R561.2
C33_PVCCKRHV_EN: length 64.3
  TOP w0.114: U12.H3 v3(190.09,55.61)
  TOP w0.127: U8.5 v2(145.04,71.51)
  S3 w0.102: v3(190.09,55.61) 189.04,55.61 184.76,59.89 184.76,66.21 180.99,69.98 170.92,69.98 169.04,71.86 166.92,71.86 165.09,73.69 162.49,73.69 161.98,73.17 161.98,70.28 161.16,69.47 158.51,69.47 158.12,69.09 157.62,69.09 156.63,70.08 146.47,70.08 v2(145.04,71.51)
  BOTTOM w0.127: C332.1 R550.2 144.74,71.21 v2(145.04,71.51)
C33_PVCCSCFUSESUS_EN: length 51.6
  TOP w0.114: U12.F1 187.92,57.11 187.14,57.89 172.1,57.89 168.88,61.11 151.82,61.11 150.29,62.64 v2(150.29,66.93) 151.64,68.28 153.28,68.28 153.41,68.15 R692.1 154.58,67.82 155.22,68.45 U22.7
C33_UART_BDX_B2B_RX0: length 184.9
  TOP w0.114: v2(202.16,102.05) 203.89,102.05 205.05,103.22 CONN18.3 ; v2(173.78,59.46) 174.79,58.46 R842.2 ; R871.1 v2(206.52,73.61)
  S3 w0.102: v2(206.52,73.61) 205.35,74.77 205.35,82.03 202.57,84.81 202.57,88.78 204.72,90.93 204.72,99.19 202.16,101.75 v2(202.16,102.05)
  S8 w0.102: v2(173.78,59.46) 174.52,60.2 177.03,60.2 178.56,61.72 178.56,66 178.07,66.5 177.89,66.5 175.22,69.17 173.64,69.17 170.62,72.19 170.62,76.16 171.45,76.99 175.55,76.99 179.53,73.01 200.25,73.01 202.41,70.85 203.76,70.85 v2(206.52,73.61)
  S10 w0.102: v2(173.78,59.46) 173.84,59.46 174.88,58.42 176.78,58.42 178.31,56.9 178.31,55.54 179.34,54.51 179.34,48.99 178.58,48.23 178.58,43.74 174.2,39.35 170.34,39.35 164.75,33.76 159.03,33.76 147.97,22.7 147.97,19.67 v2(148.46,19.18)
  BOTTOM w0.114: CONN16.63 143.1,9.86 143.02,9.94 143.02,12.52 143.78,13.27 v1(143.78,14.07) 143.78,14.87 146.24,17.34 146.24,18.48 146.94,19.18 v2(148.46,19.18)
C33_UART_BDX_B2B_TX0: length 185.2
  TOP w0.114: v2(201.31,102.95) 200.32,103.94 200.32,105.44 202.55,107.67 CONN18.2 ; R872.1 v2(206.53,72.59) ; v2(171.4,73.83) 170.95,74.27 R844.2
  S3 w0.102: v2(201.31,102.95) 201.31,102.22 204.5,99.03 204.5,91.03 202.29,88.82 202.29,84.77 205.12,81.93 205.12,74 v2(206.53,72.59)
  S8 w0.102: v2(171.4,73.83) 171.4,76.05 172.03,76.68 175.39,76.68 179.45,72.62 200.17,72.62 203.33,69.46 204.7,69.46 206.53,71.29 v2(206.53,72.59)
  S10 w0.102: v2(148.72,19.94) 148.21,20.45 148.21,22.61 159.13,33.53 164.85,33.53 170.43,39.12 174.29,39.12 178.82,43.64 178.82,48.13 179.58,48.9 179.58,54.61 178.59,55.6 178.59,71.58 177.39,72.77 173.23,72.77 172.17,73.83 v2(171.4,73.83)
  BOTTOM w0.114: v2(171.4,73.83) 171.11,73.53 v1(170.43,73.53) ; CONN16.75 140.1,8.66 140.59,9.14 140.59,13.09 140.48,13.2 140.48,13.57 140.88,13.97 141.42,13.97 141.42,13.96 142.49,13.96 145.87,17.34 145.87,18.52 147.29,19.94 v2(148.72,19.94)
C33_UART_BDX_CPLD_RX0: length 17
  TOP w0.114: R662.2 v2(178.09,58.46) 179.72,58.46 180.95,59.69 180.95,62.58 181.73,63.36 185.1,63.36 186.71,61.75 187.95,61.75 U12.B1
  BOTTOM w0.114: v1(179.02,58.46) v2(178.09,58.46)
C33_UART_BDX_CPLD_TX0: length 27.4
  TOP w0.114: U12.A2 187.57,64.13 187.57,67.83 187.05,68.35 v3(186.53,68.35) ; R870.2 173.48,76.71 v2(174.23,75.95)
  S3 w0.102: v2(174.23,75.95) 174.51,75.68 178.41,75.68 185.73,68.35 v3(186.53,68.35)
  BOTTOM w0.114: v1(187.97,68.67) 186.85,68.67 v3(186.53,68.35)
C33_UART_BDX_RX0: length 6
  TOP w0.114: U13.7 175.2,61.54 175.04,61.38 v2(175.04,59.46) 175.13,59.36 R842.1 R662.1
  BOTTOM w0.114: v1(175.92,59.59) 175.79,59.46 v2(175.04,59.46)
C33_UART_BDX_RX1: length 321.1
  TOP w0.114: U13.8 175.7,61.23 175.62,61.14 175.62,61.06 v2(175.58,61.03) ; R378.2 v2(8.35,33.47)
  BOTTOM w0.114: v2(8.35,33.47) 10.03,35.15 10.03,79.31 10.03,83.08 5.4,87.72 5.4,95.56 13.38,103.54 14.83,103.54 18.49,107.2 30.37,107.2 v1(32.58,109.41) 32.97,109.8 32.97,112.27 33.38,112.67 33.38,113.81 35.86,116.29 42.2,116.29 43.4,117.5 49.3,117.5 49.72,117.07 54.11,117.07 55.08,118.04 55.08,119.99 57.22,122.13 140.32,122.13 145.46,116.99 151.88,116.99 156.72,121.83 167.41,121.83 169.71,119.53 169.71,113.27 170.31,112.67 170.31,93.83 166.66,90.18 166.66,80.9 172.12,75.44 177.57,75.44 179.25,73.76 179.25,64.92 175.58,61.26 v2(175.58,61.03)
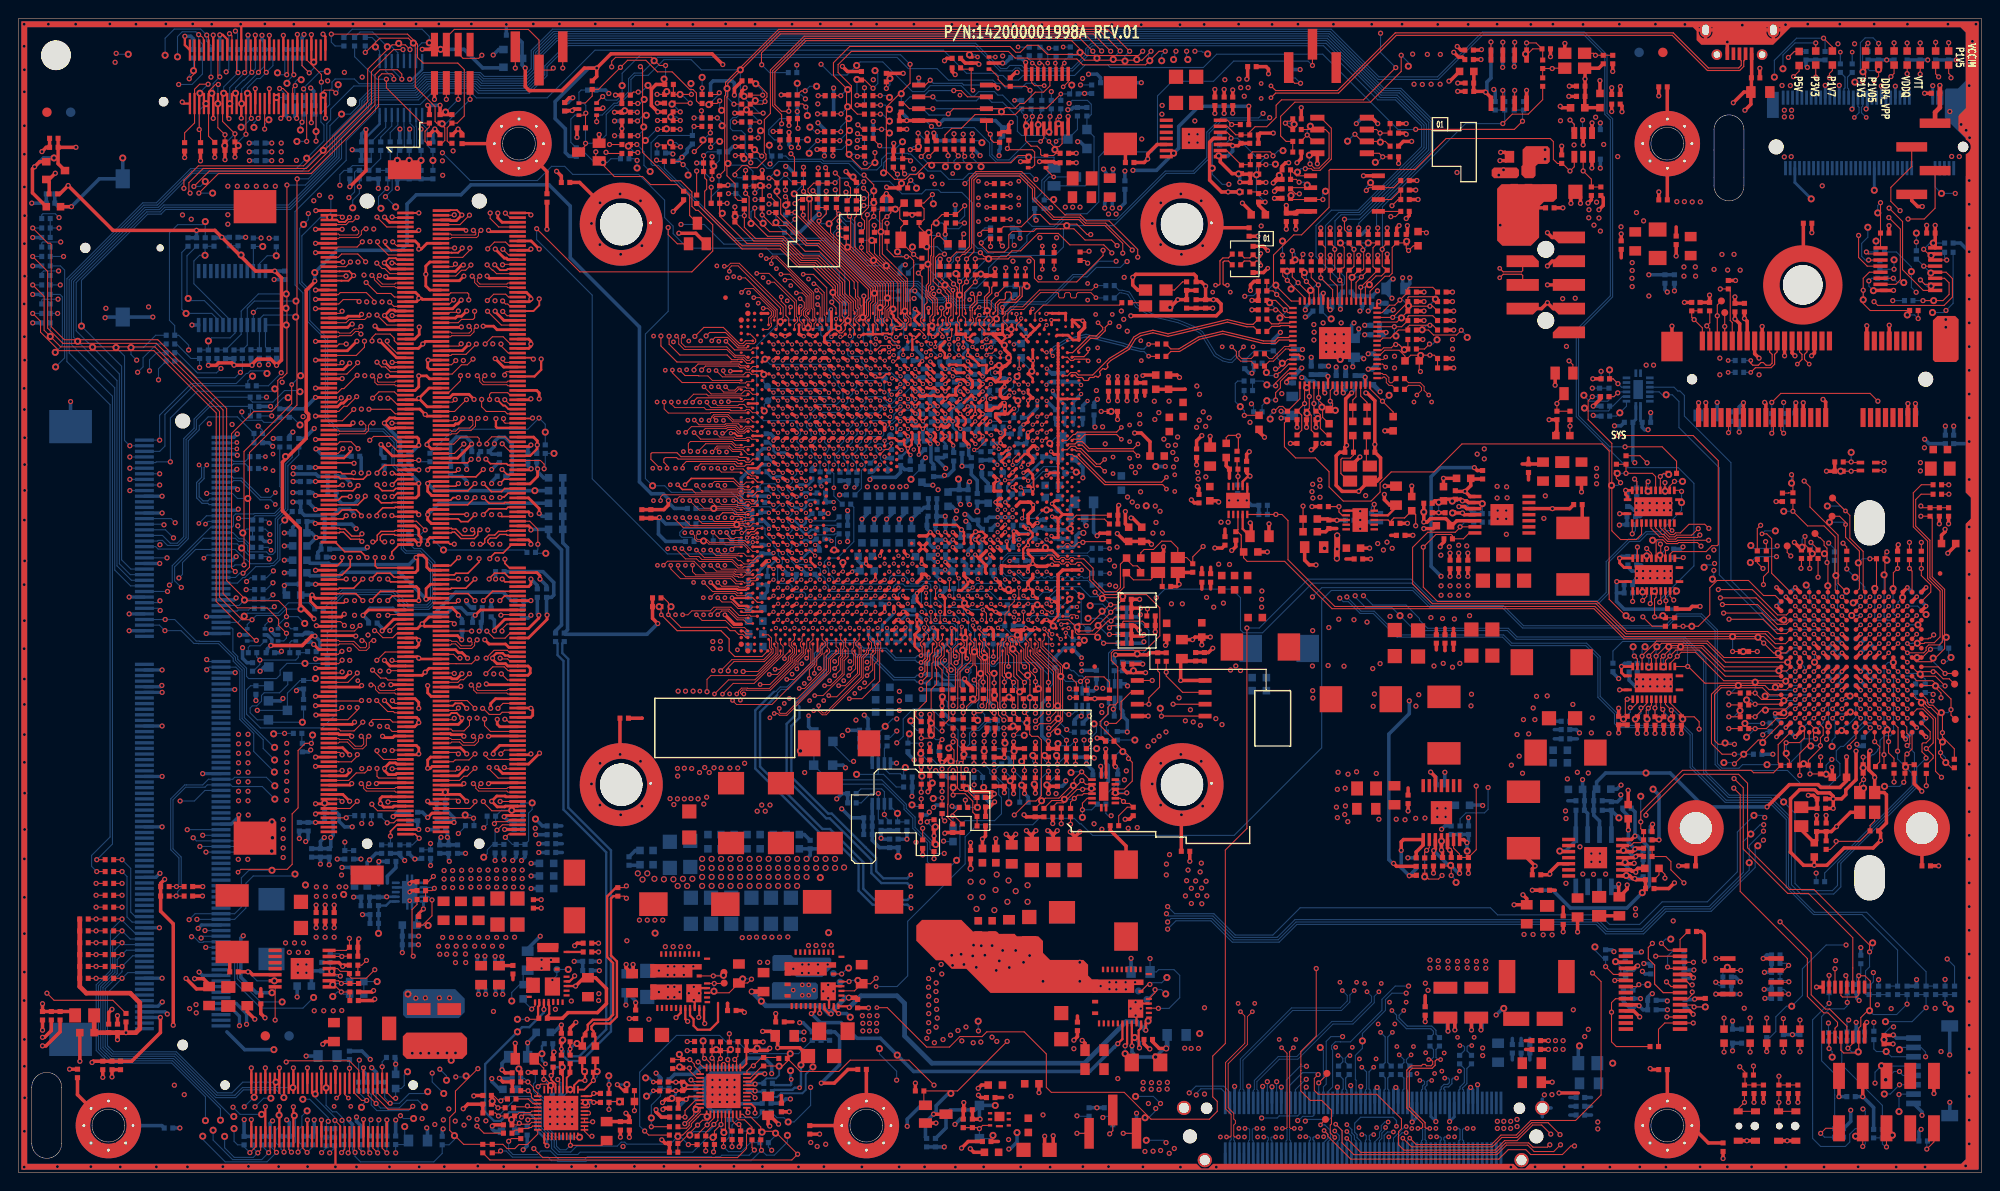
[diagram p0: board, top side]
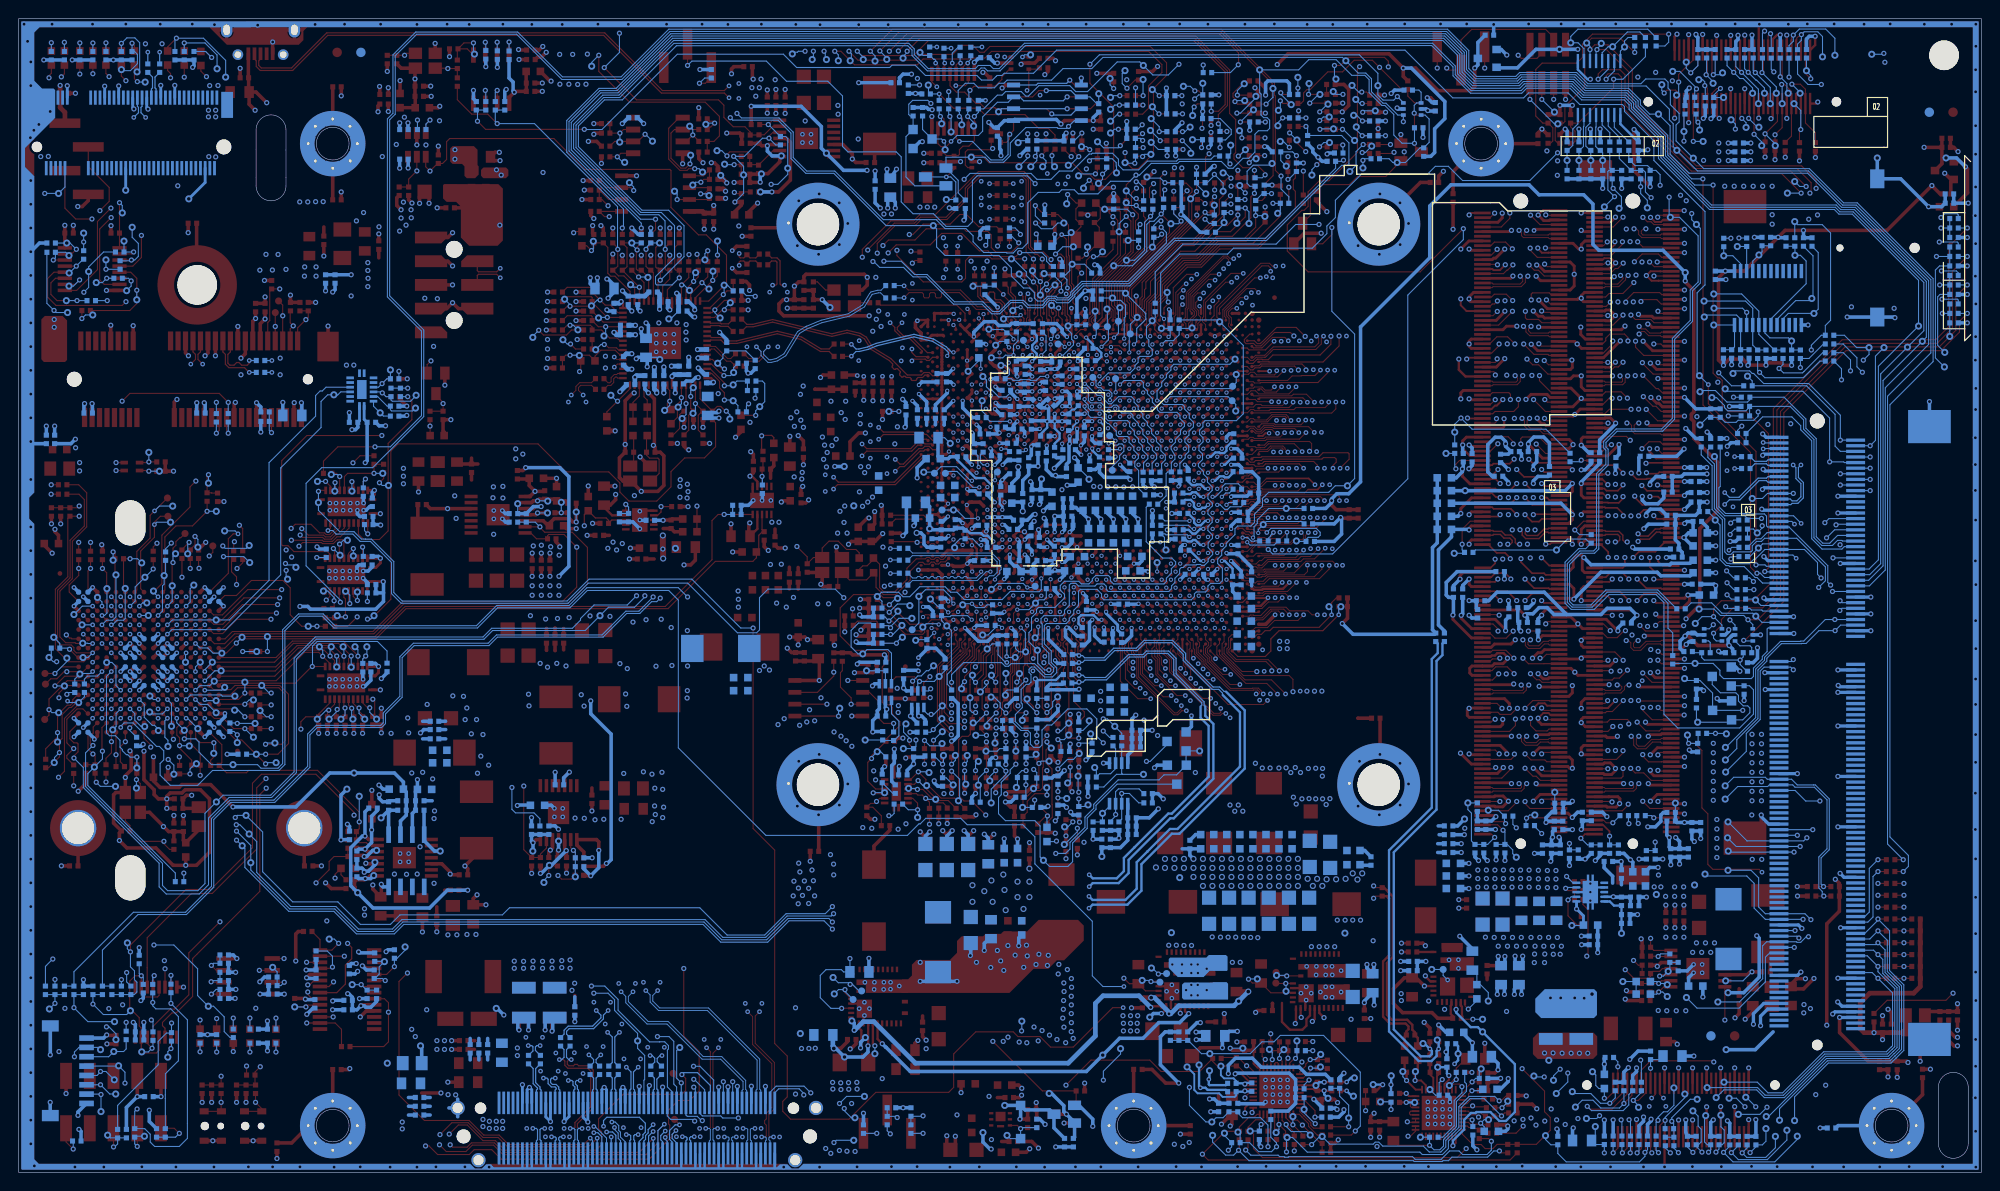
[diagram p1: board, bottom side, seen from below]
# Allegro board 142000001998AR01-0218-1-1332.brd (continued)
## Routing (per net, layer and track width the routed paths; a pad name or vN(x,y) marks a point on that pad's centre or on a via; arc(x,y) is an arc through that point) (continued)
C33_UART_BDX_TX0: length 7.7
  TOP w0.114: U10.18 175.15,74.48 174.8,74.83 v2(171.98,74.83) R870.1 R844.1
  BOTTOM w0.114: v1(171.05,74.83) v2(171.98,74.83)
C33_UART_BDX_TX1: length 307.8
  TOP w0.114: v2(171.88,77.67) 175.85,77.67 177.39,76.13 R552.1 ; R539.2 v2(8.35,32.2)
  BOTTOM w0.114: v2(171.88,77.67) 170.24,77.67 166.9,81 166.9,90.07 170.55,93.71 170.55,112.77 169.95,113.37 169.95,119.63 167.51,122.07 156.62,122.07 151.82,117.27 145.54,117.27 140.44,122.38 57.12,122.38 54.84,120.09 54.84,118.16 54,117.32 49.81,117.32 49.4,117.74 43.3,117.74 42.1,116.54 36.42,116.54 35.92,117.04 33.86,117.04 33.52,116.71 33.52,116.07 33.27,115.82 33.27,114.3 32.33,113.36 32.33,112.45 32.66,112.12 32.66,110.41 v1(30.82,108.57) 29.69,107.44 18.39,107.44 14.73,103.78 13.28,103.78 5.16,95.66 5.16,86.79 9.78,82.17 9.78,35.9 7.8,33.93 7.8,32.75 v2(8.35,32.2)
C33_UART_BDX_TX1_R: length 3.4
  TOP w0.114: U10.17 v2(175.65,74.49) 175.99,74.83 R552.2
  BOTTOM w0.114: v1(176.56,74.7) 175.87,74.7 v2(175.65,74.49)
C105_BDX_PWRGOOD_CPU: length 211.2
  TOP w0.114: v2(105.41,47.58) R252.2
  S5 w0.102: v2(105.41,47.58) 105.44,47.58 104.98,47.12 104.98,45.52 103.84,44.37 103.84,41.26 99.68,37.11 98.12,37.11 97.41,36.4 97.41,34.27 97.41,34.27 97.41,33.7 97.41,33.7 97.41,28.28 93.62,24.49 93.62,14.63 91.34,12.34 77.5,12.34 77.11,12.73 72.82,12.73 72.62,12.52 71.12,12.52 70.36,13.28 60.51,13.28 59.19,11.96 57.65,11.96 56.64,10.95 55.4,10.95 54.7,10.24 53.15,10.24 51.98,9.07 48.18,9.07 46.99,7.87 46.99,6.15 47.65,5.49 v2(47.65,5.05)
  S8 w0.102: v2(105.41,47.58) 105.41,47.58 105.92,48.08 105.92,50.13 106.31,50.52 110.13,50.52 110.18,50.47 110.37,50.47 110.64,50.2 110.64,50.09 112.92,47.8 115.87,47.8 116.41,47.27 117.81,47.27 119.84,49.3 121.69,49.3 122.38,49.99 122.38,50.64 123.68,51.94 124.33,51.94 128.67,56.29 129.06,56.29 129.54,56.76 155.43,56.76 155.91,56.29 165.11,56.29 169.39,60.57 169.39,82.93 v2(168.38,83.95)
  S10 w0.102: v2(47.65,5.05) 47.65,4.42 46.15,2.92 34.11,2.92 v2(33.27,2.08)
  BOTTOM w0.114: R538.1 R537.2 v2(168.38,83.95) ; v2(33.27,2.08) 33.81,2.62 R776.2 ; v2(105.41,47.58) 105.33,47.5 R615.1 R613.2
C105_BDX_PWRGOOD_CPU_R: length 6.6
  TOP w0.114: R173.2 170.69,83.04 v2(171.09,83.44)
  BOTTOM w0.114: v1(167.47,83.19) 167.49,83.17 167.49,83.13 168.07,82.55 170.03,82.55 170.17,82.69 R173.2 170.69,83.04 v2(171.09,83.44) 171.2,83.55 U34.4
C105_CPU_PCH__R_PLTRST_N: length 87.5
  TOP w0.102: 110.18,53.83 108.53,55.47 108.53,56 108.33,56.21 108.33,56.97 U9.L76
  TOP w0.114: R240.1 v2(110.18,52.45) 110.18,53.83
  BOTTOM w0.114: R517.1 81.7,91.25 v1(81.5,91.05) 78.97,88.52 78.97,81.2 79.71,80.47 83.06,80.47 83.29,80.24 83.29,79.81 83.64,79.45 83.64,79 83.27,78.63 83.27,78.2 83.71,77.77 83.71,77.27 83.33,76.89 83.33,76.3 83.77,75.86 83.77,75.56 83.24,75.03 83.24,74.75 82.8,74.32 82.8,73.89 82.3,73.38 82.3,73 82.75,72.54 82.75,72.11 82.27,71.63 82.27,71.35 82.75,70.87 82.75,70.48 82.3,70.03 82.3,69.6 82.75,69.14 82.75,68.71 82.27,68.22 82.27,67.87 82.73,67.41 82.73,66.88 82.25,66.4 82.25,66.14 82.73,65.66 82.73,65.38 83.13,64.97 83.44,64.97 83.54,65.07 83.95,65.07 84,65.02 85.12,65.02 85.39,64.74 85.6,64.74 85.78,64.57 85.78,64.11 86.28,63.6 86.28,63.14 86.64,62.79 86.64,62.48 86.94,62.18 93.42,62.18 93.62,62.38 93.62,62.74 93.88,62.99 94.61,62.99 94.84,62.76 96.6,62.76 96.89,63.06 97.41,63.06 97.59,62.88 97.59,60.68 98.09,60.17 98.09,59.82 98.32,59.59 100.3,59.59 100.61,59.28 100.61,58.83 100.48,58.7 100.48,56.29 99.77,55.58 99.77,54.51 99.26,54 99.26,53.62 99.59,53.29 100.13,53.29 101.3,54.46 103.81,54.46 104.1,54.17 104.44,54.17 104.83,54.56 108.88,54.56 110.18,53.27 v2(110.18,52.45)
C105_CPU_PCH_PLTRST_N: length 206.1
  TOP w0.114: R240.2 v2(110.18,50.01)
  S5 w0.102: v2(110.18,50.01) 108.68,51.51 98.35,51.51 97.31,50.47 96.67,50.47 95.89,49.68 95.89,47.99 94.41,46.51 94.41,42.03 93.6,41.22 93.6,31.59 93.31,31.3 92.81,30.8 92.81,25.69 90.58,23.45 90.58,19.11 89.69,18.22 89.69,17.65 85.75,13.72 83.25,13.72 80.94,16.03 80.85,16.03 80.85,16.03 80.47,16.03 79.13,16.03 77.23,14.12 73.68,14.12 72.34,15.47 70.4,15.47 69.59,14.66 57.34,14.66 55.18,12.5 48.54,12.5 48.11,12.06 38.71,12.06 38.15,12.62 37.06,12.62 v2(36.45,12.01)
  S8 w0.102: v2(169.32,85.75) 169.62,85.45 169.62,60.47 165.21,56.06 155.82,56.06 155.34,56.54 129.63,56.54 129.15,56.06 128.77,56.06 124.42,51.71 123.78,51.71 122.61,50.54 122.61,49.9 119.27,46.56 116.74,46.56 115.72,47.57 112.83,47.57 110.39,50.01 v2(110.18,50.01)
  BOTTOM w0.114: v2(36.45,12.01) 36.37,11.94 R736.1 ; R536.1 v2(169.32,85.75)
C105_CPU_PCH_PLTRST_N_R: length 4.2
  TOP w0.114: R169.2 170.6,84.95 v2(171.12,84.43)
  BOTTOM w0.114: v1(170.23,85.9) R169.2 170.6,84.95 v2(171.12,84.43) 171.5,84.05 U34.5
C105_PCHHOT_N: length 99.7
  TOP w0.114: R238.2 v2(99.98,49.96) ; U13.14 178.03,65.74 v2(178.1,65.81)
  S3 w0.102: v2(122.76,47.14) 120.31,47.14 119.46,46.29 117.83,46.29 117.72,46.18 116.52,46.18 115.46,45.11 103.93,45.11 103.6,45.44 103.02,45.44 102.86,45.6 100.87,45.6 100.61,45.86 100.61,46.16 100.44,46.33 100.44,46.95 100.17,47.22 99.54,47.22 99.44,47.32 99.44,47.52 100.53,48.62 100.53,49.41 v2(99.98,49.96)
  S8 w0.102: v2(122.76,47.14) 122.76,47.7 123.76,48.7 123.76,49.37 130.01,55.62 154.96,55.62 155.44,55.14 165.59,55.14 170.54,60.09 170.54,65.79 170.99,66.24 177.86,66.24 178.1,66 v2(178.1,65.81)
  BOTTOM w0.114: R572.2 v2(178.1,65.81)
C105_PCHHOT_N_R: length 5.9
  TOP w0.114: R238.1 100.23,51.91 100.23,54 99.77,54.46 99.77,56.06 99.34,56.49 U9.AL76
CI_KGI_SELECT: length 16.3
  TOP w0.114: v2(57.2,118.21) 56.99,118 CONN2.2 55.68,121.21 54.53,122.35 46.61,122.35 45.76,121.5 CONN3.3
CLK_33M_BMM: length 203.4
  TOP w0.114: R128.1 114.45,98.52 v2(114.53,98.6)
  S5 w0.102: v2(16.23,76.06) 16.55,75.73 16.55,71.94 15.83,71.21 12.01,71.21 10.21,73.01 10.21,114.95 16.36,121.11 23.06,121.11 24.28,122.33 110.69,122.33 112.85,120.17 112.85,114.48 114.02,113.32 114.02,99.11 v2(114.53,98.6)
  BOTTOM w0.114: v1(27.41,83.87) 27.15,83.61 19.09,83.61 16.23,80.75 v2(16.23,76.06) 14.73,76.06 14.65,75.98 CONN14.10
CLK_33M_BMM_R: length 18.1
  TOP w0.114: v4(104.06,86.66) 104.04,86.68 U9.Y11 ; R128.2 114.09,97.62 v2(114.38,97.33)
  S5 w0.102: v4(104.06,86.66) 105.23,86.66 107.37,88.8 107.37,89.66 107.77,90.06 107.77,92.35 109.25,93.83 110.52,93.83 114.02,97.34 114.37,97.34 v2(114.38,97.33)
CLK_33M_CPLD: length 217.5
  TOP w0.114: U12.F16 204.31,57.11 204.39,57.19 204.56,57.19 v2(204.9,57.53) ; R123.1 105.36,101.23 107.27,101.23 108.58,102.54 109.3,102.54 110.33,101.51 113.21,101.51 114.33,100.39 v2(114.71,100.39)
  S3 w0.102: v2(204.9,57.53) 207.21,55.22 207.21,29.84 199.69,22.32 199.69,17.25 v2(198.5,16.05)
  S10 w0.102: v2(204.9,57.53) 204.9,67.18 198.86,73.23 196.93,73.23 189.08,81.08 186.51,81.08 184.74,82.84 183.91,82.84 180.75,86.01 180.75,88.98 175.64,94.08 175.64,97.76 172.57,100.84 172.57,119.41 169.9,122.07 155.6,122.07 155.02,121.49 144.88,121.49 144.04,122.33 120.56,122.33 119.51,121.27 119.51,118.62 118.5,117.61 116.33,117.61 114.71,115.99 v2(114.71,100.39)
  BOTTOM w0.114: R641.2 v2(198.5,16.05)
CLK_33M_LPC: length 46.3
  TOP w0.108: v4(102.56,61.73) 102.85,61.44 U9.AC67
  TOP w0.114: R141.1 v2(105.61,96.83)
  S8 w0.102: v4(102.56,61.73) 102.68,61.73 103.4,62.45 103.4,62.89 104.39,63.88 105,63.88 106.41,65.29 106.41,67.88 106.86,68.33 106.86,71.88 105.54,73.2 105.54,73.55 105.92,73.93 105.92,74.25 105.17,74.99 105.17,75.89 105.54,76.25 105.54,79.5 105.03,80.01 105.03,84.71 105.8,85.48 105.8,88.15 101.07,92.89 101.07,94.18 101.68,94.79 103.58,94.79 105.61,96.82 v2(105.61,96.83)
  BOTTOM w0.114: R507.1 v2(105.61,96.83)
CLK_33M_LPC_PORT80: length 5.6
  BOTTOM w0.114: CONN15.3 200.38,12.37 v1(199.82,12.93) 198.78,12.93 198.5,13.21 R641.1
CLK_33M_LPC_R: length 2.3
  BOTTOM w0.114: v1(107.89,94.86) R906.1 105.73,94.86 R507.2
CLK_33M_LPC_TPM: length 172.6
  TOP w0.114: v2(117.53,99.21) 116.93,99.8 114.1,99.8 112.9,101 111.45,101 111.45,101.01 108.87,101.01 108.59,100.73 106.32,100.73 105.94,100.35 105.94,99.01 105.45,98.52 103.74,98.52 103,99.27 v2(103,99.5)
  TOP w0.127: U17.21 175.96,19.23 175.05,20.15 175.05,22.19 174.37,22.86 174.37,24.07 v2(174.8,24.51)
  S5 w0.102: v2(174.8,24.51) 174.8,25.33 175.79,26.31 177.55,26.31 179.41,28.17 179.46,28.17 183.41,32.12 183.41,38.91 180.77,41.55 180.77,63.02 182.78,65.02 182.78,67.21 182.12,67.87 182.12,77.63 166.55,93.2 v2(166.55,93.57)
  S10 w0.102: v2(166.55,93.57) 166.55,94.11 164.82,95.83 161.95,95.83 157.02,100.76 152.22,100.76 143.13,109.86 132.61,109.86 130.3,107.54 120.83,107.54 118.41,105.13 118.41,101.98 117.53,101.09 v2(117.53,99.21)
  BOTTOM w0.114: v2(103,99.5) 103.04,99.5 103.72,100.19 R486.1
CLK_33M_R_CPLD: length 19
  TOP w0.109: U9.V11 105.04,87.56 105.05,87.57 v4(105.05,87.76)
  TOP w0.114: v2(105.26,99.16) 104.98,99.44 R123.2
  S8 w0.102: v4(105.05,87.76) 105.05,88.37 99.39,94.03 99.39,95.61 100.05,96.27 102.36,96.27 v2(105.26,99.16)
CLK_33M_R_LPC: length 5.8
  TOP w0.109: U9.AA4 103.79,90.72 104.17,91.09 104.17,91.46 103.91,91.72 103.91,92.23 104.06,92.38 104.06,93.29 104.65,93.88 v3(104.65,93.98)
  TOP w0.114: v3(104.65,93.98) 105.61,94.95 R141.2
CLK_33M_R_TPM: length 18.1
  TOP w0.109: U9.Y7 103.83,88.7 103.42,88.7 103.08,88.35 v4(103.08,88.33)
  TOP w0.114: R122.2 v2(103.99,99.11)
  S8 w0.102: v2(103.99,99.11) 103.99,98.57 102.52,97.1 100.08,97.1 98.91,95.94 98.91,93.95 103.08,89.78 v4(103.08,88.33)
CLK_33M_TPM: length 3
  TOP w0.114: v2(102.82,100.41) 102.82,100.53 103.13,100.85 R122.1
  BOTTOM w0.114: v2(102.82,100.41) 102.82,100.53 103.39,101.1 R486.2
CLK_50M: length 6.3
  TOP w0.114: v2(161.34,120.9) 162.36,120.9 C22.2 ; U5.5 162,120.27 C22.2 ; C22.2 163.07,120.2 R78.2
  BOTTOM w0.114: v2(161.34,120.9) 161.34,119.82 v1(161.23,119.71)
CLK_50M_R: length 3.4
  TOP w0.114: R853.1 R78.1 v2(164.08,118.16) 164.12,118.2 OSC1.3
CLK_100M_XDPCPU_N: length 278.4
  TOP w0.127: v3(35.28,7.95) 34.89,8.34 CONN11.42 ; R130.1 v3(110.79,99.16)
  S10 w0.102: v3(35.28,7.95) 34.85,7.95 34.74,7.85 34.74,6.87 34.15,6.27 14.83,6.27 6.35,14.76 6.35,61.32 13.72,68.68 24.36,68.68 24.71,69.04 24.71,73.16 25.87,74.32 27.43,74.32 27.69,74.57 27.69,78.37 27.69,78.37 27.69,78.75 27.69,78.75 27.69,82.62 26.74,83.57 19.91,83.57 11.86,91.61 11.86,116.29 14.98,119.41 47.77,119.41 48.63,120.27 51.57,120.27 52.08,120.78 96.29,120.78 101.55,115.52 101.55,114.99 109.63,106.91 109.63,102.13 110.26,101.5 110.26,99.26 110.36,99.16 v3(110.79,99.16)
CLK_100M_XDPCPU_P: length 278.4
  TOP w0.127: CONN11.40 34.39,8.34 v3(34.01,7.95) ; R129.1 v3(109.52,99.16)
  S10 w0.102: v3(34.01,7.95) 34.44,7.95 34.54,7.85 34.54,6.96 34.06,6.48 14.92,6.48 6.55,14.84 6.55,61.23 13.8,68.48 24.44,68.48 24.92,68.95 24.92,73.08 25.96,74.12 27.52,74.12 27.89,74.49 27.89,78.28 27.89,78.29 27.89,78.83 27.89,78.84 27.89,82.71 26.83,83.77 19.99,83.77 12.06,91.69 12.06,116.2 15.06,119.2 47.85,119.2 48.72,120.07 51.66,120.07 52.17,120.57 96.21,120.57 101.35,115.44 101.35,114.9 109.42,106.82 109.42,104.58 109.32,104.48 109.07,104.48 108.97,104.38 108.97,103.97 109.07,103.87 109.32,103.87 109.42,103.77 109.42,103.36 109.32,103.26 109.07,103.26 108.97,103.16 108.97,102.75 109.07,102.65 109.32,102.65 109.42,102.55 109.42,102.05 110.06,101.41 110.06,99.26 109.96,99.16 v3(109.52,99.16)
CLK_100M_XDPCPU_R_N: length 9.1
  TOP w0.127: R130.2 v3(110.79,96.67) ; v4(109.37,91.26) 109.42,91.21 U9.H2
  S10 w0.102: v3(110.79,96.67) 110.36,96.67 110.26,96.57 110.26,95.57 109.19,94.51 109.19,94.06 109.3,93.96 109.52,93.96 109.63,93.86 109.63,93.45 109.52,93.35 109.3,93.35 109.19,93.25 109.19,92.84 109.3,92.74 109.52,92.74 109.63,92.64 109.63,92.23 109.52,92.13 109.3,92.13 109.19,92.03 109.19,91.44 v4(109.37,91.26)
CLK_100M_XDPCPU_R_P: length 9.1
  TOP w0.127: R129.2 v3(109.52,96.67) ; v4(109.98,90.7) 109.73,90.45 U9.H4
  S10 w0.102: v3(109.52,96.67) 109.96,96.67 110.06,96.57 110.06,95.66 108.99,94.59 108.99,91.06 109.35,90.7 v4(109.98,90.7)
CLK_BUF_50M_BMM: length 192.4
  TOP w0.114: v2(160.91,112.52) 160.04,111.65 v2(149.48,111.65) ; v2(24.11,65.03) 24.11,65.03 24.11,77.17 29.21,82.27 v3(29.21,84.33)
  BOTTOM w0.114: v3(29.21,84.33) v1(30.16,85.28) 30.41,85.53 30.41,94.15 29.57,95 29.57,102.86 35.04,108.33 35.04,110.43 38.18,113.57 38.18,114.08 38.41,114.31 42.96,114.31 44.2,115.55 48.44,115.55 48.97,115.02 56.55,115.02 61.66,120.13 98.94,120.13 101.41,117.66 104.55,117.66 104.79,117.42 105.31,117.42 105.41,117.32 105.41,117.32 105.8,116.93 106.98,116.93 107.47,117.42 107.88,117.42 112.98,117.42 114.08,118.52 116.56,118.52 116.8,118.27 126.76,118.27 128.18,119.7 139.53,119.7 147.59,111.63 149.46,111.63 v2(149.48,111.65) ; v2(24.11,65.03) 23.14,65.03 23,64.88 CONN14.47 ; R119.1 C41.1 160.91,113.59 v2(160.91,112.52)
CLK_BUF_50M_BMM_R: length 2.6
  TOP w0.114: U5.3 v2(160.07,115.82)
  BOTTOM w0.114: R119.2 160.02,115.77 v2(160.07,115.82)
CLK_BUF_EN: length 8.3
  TOP w0.114: U5.8 v2(157.53,121.01)
  S3 w0.102: v2(152.12,119.67) 153.45,121.01 v2(157.53,121.01)
  BOTTOM w0.114: v2(157.53,121.01) 157.53,120.91 157.53,120.9 R465.1
CLK_BUF_Q2_RSV: length 14.5
  TOP w0.114: U5.6 v2(160.07,120.98)
  S3 w0.102: v2(149.15,119.71) 151.33,121.88 159.17,121.88 v2(160.07,120.98)
  BOTTOM w0.114: R1045.2 160.02,120.93 v2(160.07,120.98)
CLK_BUF_Q3_RSV: length 11.5
  TOP w0.114: U5.7 v2(158.8,120.98)
  S3 w0.102: v2(158.8,120.98) 158.13,121.65 152.7,121.65 v2(150.73,119.68)
  BOTTOM w0.114: v2(158.8,120.98) 158.8,120.08 R468.2
CLK_M2_SUSCLK: length 28
  TOP w0.114: R41.2 91.43,110.6 v2(92.13,109.91) ; v4(93.63,87.48) 93.43,87.48 U9.BD11
  S10 w0.102: v4(93.63,87.48) 93.63,88.57 94.26,89.2 94.26,102.54 92.35,104.44 92.35,109.68 v2(92.13,109.91)
  BOTTOM w0.114: v2(92.13,109.91) 92.35,109.68 93.92,109.68 v1(94.57,110.32)
CLR CMOS: length 4.1
  TOP w0.114: CONN17.3 135.89,117.22 136.53,116.59 v2(137.16,116.59)
  BOTTOM w0.114: v2(137.16,116.59) 136.6,117.15 R800.1
CONN12_GND: length 2.8
  TOP w0.114: CONN12.1 v2(118.19,4.17)
  BOTTOM w0.114: CONN12.1 v2(118.19,4.17)
CPLD23_INT_CPU: length 256.4
  TOP w0.114: R48.1 v2(101.06,111.13) ; U12.K6 v3(193.09,52.61) ; v2(163.93,4.09) 162.95,5.07 162,5.07 160.32,3.39 158.99,3.39 157.97,2.37 148.22,2.37 147.65,2.95 147.65,4.37 147.96,4.67 147.96,5.71 145.31,8.36 139.04,8.36 138.63,8.76 138.63,10.06 v2(139.04,10.46)
  S3 w0.102: v2(101.06,111.13) 102.01,110.19 103.86,110.19 104.17,109.88 104.17,108.86 105.29,107.74 107.99,107.74 108.33,107.4 110.92,107.4 114.68,103.64 114.68,102.74 115.57,101.85 117.02,101.85 122.23,96.65 130.37,96.65 131.18,95.84 134.01,95.84 135.61,97.43 155.74,97.43 157.09,98.78 160.68,98.78 163.27,101.37 165.75,101.37 170.36,96.77 170.36,82.41 175.81,76.96 180.53,76.96 188.16,69.33 v2(188.16,67.06)
  S10 w0.102: v2(188.16,67.06) 188.14,67.06 187.2,66.12 187.2,55.7 189.76,53.14 192.56,53.14 v3(193.09,52.61) 193.09,52.15 192.71,51.77 192.71,51.45 192.41,51.16 191.92,51.16 191.47,50.71 191.47,50.45 191.05,50.04 188.06,50.04 187.24,49.21 187.24,40.93 189.03,39.14 189.03,26.04 187.78,24.79 187.78,16.61 185.2,14.02 184.79,14.02 184.23,13.46 169.09,13.46 168.76,13.13 168.76,8.92 v2(163.93,4.09)
  BOTTOM w0.114: v1(185.34,67.11) 185.64,66.8 187.91,66.8 v2(188.16,67.06)
  BOTTOM w0.127: CONN16.91 136.1,8.56 135.99,8.67 135.99,9.3 137.36,10.67 138.84,10.67 v2(139.04,10.46)
CPLD23_INT_CPU_R: length 43.1
  TOP w0.114: v2(101.22,108.76) 101.09,108.89 101.09,109.01 101.06,109.04 R48.2 ; v4(95.16,81.98) 94.75,82.39 U9.BA21
  S5 w0.102: v4(95.16,81.98) 95.53,81.61 98.51,81.61 99.9,83 99.9,84.62 101.12,85.84 101.12,87.66 101.43,87.97 101.43,88.77 100.91,89.28 100.91,89.33 98.5,91.74 95.77,91.74 94.18,93.33 94.18,99.09 100.33,105.24 100.33,106.22 100.76,106.65 100.76,108.31 v2(101.22,108.76)
  BOTTOM w0.114: R48.2 101.06,109.04 101.09,109.01 101.09,108.89 v2(101.22,108.76) 101.06,108.61 101.06,108.3 v1(101.7,107.66)
CPLD_ADR_STATUS_RD: length 176.7
  TOP w0.114: v2(81.64,112.24) 81.64,113.23 80.67,114.2 80.67,117.91 84.15,121.39 113.56,121.39 v2(114.94,120.02) ; U12.D11 v3(199.09,59.61)
  S3 w0.102: v2(114.94,120.02) 116.41,118.54 134.32,118.54 139.63,113.23 158.93,113.23 159.61,112.55 159.61,111.25 162.86,108 169.47,108 176.26,101.21 192.32,101.21 195.48,98.04 195.48,82.68 200.45,77.71 200.45,68.16 199.18,66.88 199.18,65.23 198.63,64.68 198.63,60.1 199.09,59.64 v3(199.09,59.61)
  BOTTOM w0.114: R450.1 81.46,112.06 v2(81.64,112.24) ; v2(114.94,120.02) 114.94,119.89 115.37,119.45 v1(115.37,119.27)
CPLD_BDX_CPU_RSMRST: length 25.9
  TOP w0.114: v2(174.57,60.88) 174.7,61.01 U13.6 ; U12.J3 v3(190.09,53.61)
  S3 w0.102: v2(174.57,60.88) 175.69,62 177.37,62 179.88,59.49 179.88,57.07 183.35,53.61 v3(190.09,53.61)
  BOTTOM w0.114: v2(174.57,60.88) 174.57,61.8 174.98,62.21 v1(175.03,62.21) ; v3(190.09,53.61) 190.09,53.8 v1(189.28,54.61)
CPLD_BDX_PWRGOOD_CPU: length 39.4
  TOP w0.114: U12.F7 v3(194.09,57.61)
  BOTTOM w0.114: v3(194.09,57.61) 193.61,58.09 187.83,58.09 181.97,63.96 181.97,75.41 177.65,79.73 177.65,82.52 176.94,83.24 v1(176.28,83.24) 176.25,83.21 175.87,83.21 175.53,83.55 U34.13
CPLD_CLK_25M: length 14.3
  TOP w0.114: R172.1 v2(197.36,44.45) ; U12.J12 v3(200.09,53.61)
  BOTTOM w0.114: v1(197.36,43.29) v2(197.36,44.45) 198.07,44.45 198.33,44.71 198.48,44.71 198.91,45.14 198.91,45.26 199.16,45.52 199.16,46.25 199.64,46.74 200.28,46.74 200.61,47.07 200.61,53.09 v3(200.09,53.61)
CPLD_CLK_25M_R: length 3.2
  TOP w0.114: OSC4.3 196.99,41.63 v2(197.4,42.04) 197.4,42.68 R172.2
  BOTTOM w0.114: v1(197.4,41.13) v2(197.4,42.04)
CPLD_CONFIG_CLK: length 171.2
  TOP w0.114: R82.1 v2(85.55,107.52) ; U12.D9 v3(197.09,59.61)
  S3 w0.102: v3(197.09,59.61) 196.66,60.04 196.66,66.63 194.55,68.73 194.55,79.48 185.01,89.01 180.57,89.01 175.35,94.23 175.35,99.53 169.25,105.64 154.33,105.64 151.13,108.84 149.9,108.84 148.25,110.49 135.89,110.49 134.06,112.32 133.1,112.32 132.69,112.73 127.97,112.73 126.75,113.96 126.75,116.59 125.68,117.65 116.2,117.65 115.47,116.92 115.47,115.42 114.99,114.94 111.23,114.94 110.61,114.32 106.37,114.32 105.23,115.46 105.23,116.27 104.13,117.37 101.85,117.37 101.03,118.2 99.83,118.2 99.67,118.03 95.25,118.03 94.77,118.52 89.76,118.52 88.87,117.63 85.36,117.63 81.94,114.21 81.94,113.4 82.21,113.13 82.66,113.13 84.18,111.62 84.18,108.89 v2(85.55,107.52)
  BOTTOM w0.114: v1(196.13,59.61) 197.08,59.61 v3(197.09,59.61)
CPLD_CONFIG_CLK_R: length 24.6
  TOP w0.102: 91.56,91.07 91.56,91.63 91.71,91.78 91.71,92.8 91.92,93.01
  TOP w0.114: 91.56,91.07 91.91,90.72 U9.BG4 ; 91.92,93.01 91.92,94.86 84.79,102 84.79,104.62 84.45,104.95 84.45,105.28 85.07,105.89 R82.2 R83.2 87.3,105.89 v2(87.35,105.95)
  BOTTOM w0.114: R470.1 v2(87.35,105.95) 87.84,106.43 89.16,106.43 v1(89.28,106.55)
CPLD_CONFIG_DATA: length 209.4
  TOP w0.114: U12.C13 v3(201.09,60.61) ; R103.1 v2(86.41,105.03)
  S3 w0.102: v2(86.41,105.03) 85.67,105.77 84.83,105.77 82.07,108.53 82.07,110.95 80.39,112.62 80.39,115.18 78.5,117.07 69.67,117.07 68.53,118.21 68.53,118.78 70.43,120.68 106.12,120.68 106.83,119.97 108.22,119.97 108.27,119.91 113.43,119.91 114.25,120.73 140,120.73 145.36,115.37 148.51,115.37 149.22,114.66 160.96,114.66 164.13,111.48 165.24,111.48 165.59,111.13 169.35,111.13 172.14,108.34 172.14,107.01 176.5,102.65 192.62,102.65 196.63,98.64 196.63,86.4 200.09,82.94 200.09,79.68 201.2,78.58 201.6,78.18 201.6,68.44 201.81,68.24 201.81,63.92 201.09,63.2 v3(201.09,60.61)
  BOTTOM w0.114: v1(201.57,61.54) 201.09,61.06 v3(201.09,60.61)
CPLD_CONFIG_DATA_R: length 19.2
  TOP w0.102: U9.BG2 91.91,92.65 92.18,92.91
  TOP w0.114: 92.18,92.91 92.18,94.95 85.62,101.5 v2(85.62,101.83) 86.41,102.62 R103.2 R102.2
  BOTTOM w0.114: v1(86.72,101.55) 85.9,101.55 v2(85.62,101.83) 86.41,102.62 R103.2
CPLD_CPU2PCH_THROT: length 30.4
  TOP w0.114: v2(177.16,73.96) 176.65,73.45 U10.15 ; U12.G4 v3(191.09,56.61)
  S3 w0.102: v2(177.16,73.96) 177.97,73.96 185.45,66.49 185.45,60.94 189.31,57.07 190.62,57.07 v3(191.09,56.61)
  BOTTOM w0.114: v1(178.03,73.96) v2(177.16,73.96) ; v3(191.09,56.61) 191.08,56.61 190.6,56.13 189.76,56.13 189.2,55.58 v1(188.26,55.58)
CPLD_CPU_CATERR_N: length 16.3
  TOP w0.114: U14.15 176.7,54.48 v2(177.47,55.24) 177.89,55.66 179.41,55.66 182.45,52.63 189.11,52.63 U12.K2
  BOTTOM w0.114: v2(177.47,55.24) 177.47,55.91 v1(177.83,56.26)
CPLD_CPU_ERROR_0: length 19.2
  TOP w0.114: U14.19 174.7,54.99 v2(174.42,55.27) 175.78,56.63 180.61,56.63 182.63,54.61 189.1,54.61 189.59,55.09 U12.H2
  BOTTOM w0.114: v1(174.42,54.08) v2(174.42,55.27)
CPLD_CPU_ERROR_1: length 16.9
  TOP w0.114: U14.18 v2(175.2,55.25) 176.34,56.39 180.21,56.39 182.49,54.11 U12.J1
  BOTTOM w0.114: v1(175.29,56.26) 175.2,56.18 v2(175.2,55.25)
CPLD_CPU_ERROR_2: length 17.6
  TOP w0.114: U14.17 175.7,55 v2(175.97,55.27) 176.85,56.15 180.07,56.15 182.55,53.67 189.18,53.67 189.59,54.08 U12.J2
  BOTTOM w0.114: v1(175.97,54.1) v2(175.97,55.27)
CPLD_CPU_PCH_PLTRST_N: length 39.5
  TOP w0.114: U12.E7 v3(194.09,58.61)
  BOTTOM w0.114: v3(194.09,58.61) 193.57,59.13 v1(188.87,59.13) 187.45,59.13 183.21,63.37 183.21,75.97 178.23,80.95 178.23,83.16 177.75,83.64 177.52,83.64 177.11,84.05 U34.12
CPLD_CPU_PROCHOT_N: length 239.8
  TOP w0.114: U12.L1 188.34,52.36 180.43,52.36 178.64,54.15 v2(178.59,54.15) U14.14
  S3 w0.102: v3(19.28,69.47) 21.55,67.2 21.55,61.47 25.88,57.14 25.88,56.08 26.82,55.14 26.82,53.26 29.36,50.72 29.36,39.54 29.34,39.52 29.34,35.3 33.32,31.32 35.58,31.32 39.39,27.51 43.75,27.51 45.12,26.14 61.82,26.14 64.94,23.01 68.93,23.01 69.03,23.11 72.63,23.11 72.73,23.01 93.99,23.01 99.06,28.08 99.06,31.38 101.39,33.71 116.48,33.71 v2(119.68,36.91)
  S8 w0.102: v2(119.68,36.91) 119.68,43.25 122.89,46.46 123.04,46.46 124.22,47.64 124.22,49.01 130.15,54.94 154.98,54.94 155.23,54.69 172.06,54.69 172.6,54.15 v2(178.59,54.15)
  BOTTOM w0.114: CONN14.29 20.09,70.28 v3(19.28,69.47) ; v2(178.59,54.15) 178.56,54.17 178.56,56.32 178.06,56.83 171.61,56.83 170.59,55.8 R567.2
CPLD_CPU_THERMTRIP_N: length 227.9
  TOP w0.114: U14.16 176.2,54.79 v2(176.68,55.27) 177.32,55.91 179.81,55.91 182.6,53.11 U12.K1
  S3 w0.102: v2(118.72,36.83) 115.82,33.93 101.29,33.93 98.83,31.47 98.83,28.17 93.9,23.24 72.82,23.24 72.72,23.34 68.93,23.34 68.83,23.24 65.04,23.24 61.91,26.37 45.22,26.37 43.84,27.74 41.78,27.74 39.41,30.1 38.48,30.1 34.21,34.37 30.75,34.37 29.57,35.54 29.57,39.43 29.59,39.45 29.59,50.81 27.05,53.35 27.05,55.23 26.14,56.15 26.14,59.92 21.79,64.26 21.79,67.59 v3(19.99,69.39)
  S8 w0.102: v2(118.72,36.83) 119.08,37.19 119.08,42.99 122.78,46.69 122.95,46.69 123.99,47.72 123.99,49.26 130.11,55.38 154.87,55.38 155.34,54.91 166.59,54.91 166.96,55.29 171.84,55.29 172.34,54.79 176.21,54.79 v2(176.68,55.27)
  BOTTOM w0.114: v3(19.99,69.39) 20.28,69.68 CONN14.31 ; v1(176.56,56.26) 176.68,56.13 v2(176.68,55.27)
CPLD_DDR01_MEMHOT: length 26.8
  TOP w0.114: U12.G3 v3(190.09,56.61) ; U10.16 v2(176.15,73.84)
  S3 w0.102: v2(176.15,73.84) 176.64,73.36 178.26,73.36 185.22,66.4 185.22,60.85 189.45,56.61 v3(190.09,56.61)
  BOTTOM w0.114: v2(176.15,73.84) 176.17,73.82 v1(176.17,72.92)
CPLD_DDR_EVENT_N: length 273.8
  TOP w0.114: U12.N8 v3(195.09,49.61)
  S3 w0.102: v2(98.29,16.51) 96.6,16.51 93.62,13.54 87.63,13.54 86.05,11.96 79.47,11.96 79.09,12.35 77.7,12.35 76.95,11.61 73.14,11.61 72.23,10.7 70.92,10.7 70.33,10.11 64.25,10.11 63.38,10.97 58.4,10.97 57.26,12.12 52.33,12.12 52.23,12.22 51.58,12.22 50.54,13.26 47.97,13.26 46.72,14.5 43.63,14.5 42.83,15.31 40.87,17.27 35.49,17.27 34.83,16.61 31.16,16.61 30.16,15.61 25.15,15.61 24.7,15.17 21.21,15.17 20,16.38 18.42,16.38 17.02,17.78 15.18,17.78 14.34,18.62 9.19,18.62 6.65,21.16 6.65,23.55 6.05,24.16 6.05,24.17 4.83,25.39 4.83,44.4 9.88,49.45 v2(25.53,49.45)
  S8 w0.102: v3(195.09,49.61) 194.52,49.04 194.52,48.43 194.27,48.18 193.94,48.18 192.96,47.19 191.94,47.19 191.44,46.69 191.44,45.6 185.78,39.93 185.78,33.54 185.91,33.41 186.04,33.27 186.18,33.14 186.18,32.21 181.83,27.86 176.22,27.86 174.69,26.34 170.3,26.34 168.65,24.69 150.17,24.69 148.25,22.76 122.22,22.76 121.44,21.97 114.82,21.97 114.34,21.49 111.58,21.49 108.36,18.26 104.83,18.26 104.53,17.96 100.27,17.96 100,17.69 100,17.69 98.82,16.51 v2(98.29,16.51)
  BOTTOM w0.114: v1(31.75,52.86) 31.54,52.65 R607.2 30.1,52.65 28.75,51.31 Q11.D v2(25.53,49.45)
CPLD_FIVR_FAULT: length 18.6
  TOP w0.114: U12.H1 182.47,55.11 180.71,56.87 175.26,56.87 173.7,55.31 v2(173.7,55.25) U14.21
  BOTTOM w0.114: v2(173.7,55.25) 173.7,55.95 v1(174.02,56.26)
CPLD_INTERRUPT_R: length 31.1
  BOTTOM w0.114: v1(30.1,83.57) 29.97,83.69 28.45,83.69 27.21,82.45 25.02,82.45 24.77,82.71 R937.1 21.11,82.98 18.77,80.64 18.77,79.65 17.66,78.55 17.66,68.05 16.97,67.35 16.22,67.35 15.39,68.18 CONN14.36
CPLD_JTAG_TCK: length 2.3
  TOP w0.127: v2(195.5,21.06) 195.61,20.95 U21.4
  BOTTOM w0.114: R664.2 195.66,20.9 v2(195.5,21.06)
CPLD_JTAG_TDI: length 38.1
  TOP w0.114: 195.61,15.64 193.78,17.48 193.32,17.48 191.8,19 191.8,23.5 v2(188.47,26.82)
  TOP w0.127: 195.61,15.64 U21.13
  S10 w0.102: v2(186.61,46.84) 186.61,40.72 188.47,38.86 v2(188.47,26.82)
  BOTTOM w0.114: R843.2 186.97,47.2 v2(186.61,46.84) v1(186.61,46)
CPLD_JTAG_TDO: length 2.2
  TOP w0.127: U21.7 v2(193.71,21.08)
  BOTTOM w0.114: R695.2 v2(193.71,21.08)
CPLD_JTAG_TMS: length 3.1
  TOP w0.127: U21.10 v2(193.71,13.25)
  BOTTOM w0.114: v2(193.71,13.25) 194.04,12.92 v1(194.04,12.33)
  BOTTOM w0.127: R696.2 193.65,13.31 v2(193.71,13.25)
CPLD_LED1_DEBUG: length 5.3
  TOP w0.114: U12.J15 203.1,53.59 v2(204.85,53.59) 205.16,53.59 205.92,52.83 206.57,52.83 TP5.1
CPLD_LED2_DEBUG: length 36.6
  TOP w0.114: LED19.C2 v2(199.58,75.13) ; U12.K16 205.08,53.11 v2(206.12,52.07)
  S8 w0.102: v2(206.12,52.07) 206.7,52.64 206.7,54.98 205.58,56.1 205.58,67.53 207.22,69.17 207.22,73.98 206.52,74.69 205.12,74.69 204.65,74.21 200.5,74.21 v2(199.58,75.13)
  BOTTOM w0.114: v1(205.1,52.07) v2(206.12,52.07)
CPLD_LED2_DEBUG_R: length 3
  TOP w0.114: R883.2 v2(196.07,75.06) 196.15,75.13 LED19.A2
  BOTTOM w0.114: v1(194.94,75.06) v2(196.07,75.06)
CPLD_LED3_DEBUG: length 8.7
  TOP w0.114: U12.K15 203.07,52.63 204.8,52.63 206.76,50.67 v2(206.76,49.53) 206.76,48.94 TP7.1
  BOTTOM w0.114: v1(205.72,49.21) 206.44,49.21 v2(206.76,49.53)
CPLD_LED4_DEBUG: length 37.8
  TOP w0.114: LED19.C1 v2(199.58,75.98) ; v2(205.69,50.8) 205.69,51.31 204.89,52.11 U12.L16
  S8 w0.102: v2(199.58,75.98) 201.12,74.44 204.55,74.44 205.03,74.91 206.61,74.91 207.45,74.08 207.45,68.98 205.81,67.34 205.81,56.19 206.92,55.07 206.92,52.03 v2(205.69,50.8)
CPLD_LED4_DEBUG_R: length 2.9
  TOP w0.114: LED19.A1 196.15,75.98 v2(196.07,76.05) R875.2
  BOTTOM w0.114: v1(196.07,77.08) v2(196.07,76.05)
CPLD_PCH_APWROK: length 11.7
  TOP w0.114: U12.F4 v3(191.09,57.61) ; R184.1 187.22,65.38 187.22,64.29 186.69,63.75 v2(186.69,62.92)
  S3 w0.102: v2(186.69,62.92) 186.69,60.6 189.13,58.17 190.53,58.17 191.08,57.61 v3(191.09,57.61)
CPLD_PCH_PWROK: length 11.4
  TOP w0.114: v2(186.64,64.64) 186.03,65.25 R189.2 ; U12.F3 v3(190.09,57.61)
  S3 w0.102: v2(186.64,64.64) 186.08,64.08 186.08,60.63 189.1,57.61 v3(190.09,57.61)
CPLD_PCH_THERMTRIP_N: length 24.7
  TOP w0.114: U13.9 176.2,61.24 v2(176.25,61.19) 176.25,60.53 R212.1 ; U12.K4 v3(191.09,52.61)
  S3 w0.102: v3(191.09,52.61) 190.61,53.09 183.46,53.09 179.6,56.95 179.6,59.41 177.29,61.72 176.78,61.72 v2(176.25,61.19)
  BOTTOM w0.114: v1(177.39,62.23) 176.94,62.23 176.25,61.54 v2(176.25,61.19)
CPLD_PCHHOT_N: length 22
  TOP w0.114: U12.K3 v3(190.09,52.61) ; v2(177.09,61.26) 176.7,61.65 U13.10
  S3 w0.102: v2(177.09,61.26) 177.14,61.26 179.32,59.08 179.32,56.74 183.46,52.61 v3(190.09,52.61)
  BOTTOM w0.114: v3(190.09,52.61) 189,53.7 v1(188.34,53.7)
CPLD_SC_PWRGOOD: length 26.7
  TOP w0.114: v2(173.76,61.21) 174.2,61.65 U13.5 ; U12.J4 v3(191.09,53.61)
  S3 w0.102: v2(173.76,61.21) 174.78,62.23 177.46,62.23 180.16,59.53 180.16,57.2 183.21,54.15 190.55,54.15 v3(191.09,53.61)
  BOTTOM w0.114: v1(173.76,62.13) v2(173.76,61.21) ; v3(191.09,53.61) 191.09,54.1 v1(190.58,54.61)
CPU_DDR_PWRGD: length 86.6
  TOP w0.102: U9.CR39 78.88,74.55 78.41,74.55 78.22,74.73 78.09,74.73 77.52,75.3 76.4,75.3 v3(76.33,75.37)
  S3 w0.102: v3(76.33,75.37) 76.33,72.82 76.02,72.52 76.02,71.27 76.16,71.13 77.61,71.13 79.73,73.25 79.73,74.04 80.16,74.47 85.22,74.47 85.55,74.8 97.38,74.8 99.77,72.42 99.77,69.85 100.1,69.52 100.84,69.52 101.47,68.88 101.47,68.05 101.21,67.78 101.21,64.63 102.06,63.78 102.06,63.32 101.09,62.36 101.09,61.59 100.81,61.32 96.88,61.32 96.67,61.11 96.67,60.71 97.1,60.27 97.1,59.77 97.61,59.26 97.61,58.98 97.84,58.75 98.12,58.75 98.45,58.42 98.45,58.18 98.6,58.03 98.6,51.79 95.89,49.07 95.89,47.9 v2(93.95,45.97)
  BOTTOM w0.114: R613.1 102.75,47.3 102.02,47.3 101.75,47.03 101.75,45.84 101.4,45.49 100.76,45.49 100.51,45.75 100.51,47.35 99.97,47.88 99.47,47.88 97.74,49.61 95.71,49.61 94.64,48.54 94.64,46.66 v2(93.95,45.97)
CPU_JTAG_RST: length 255
  TOP w0.114: U12.L12 v3(200.09,51.61) ; R49.1 v2(100.08,111.18) ; v2(164.97,2.95) 164.25,2.22 162.15,2.22 161.46,2.91 159.19,2.91 158.17,1.89 142.86,1.89 141.6,3.15 141.6,4.47 v3(140.92,5.15)
  S3 w0.102: v2(188.09,65.91) 188.09,65.94 187.6,66.42 187.6,69.56 180.43,76.73 175.71,76.73 170.13,82.31 170.13,96.67 165.71,101.09 163.35,101.09 160.81,98.55 157.18,98.55 155.75,97.12 135.62,97.12 134.11,95.61 131.08,95.61 130.27,96.42 122.13,96.42 116.93,101.63 115.48,101.63 114.45,102.65 114.45,103.54 110.82,107.18 108.23,107.18 107.89,107.52 105.19,107.52 103.94,108.77 103.94,109.79 103.77,109.96 101.3,109.96 v2(100.08,111.18)
  S10 w0.102: v2(164.97,2.95) 172.57,10.54 182.74,10.54 184.6,12.4 185.43,12.4 191.15,18.12 191.15,35.04 191.2,35.09 191.2,35.11 194.61,38.52 194.61,40.06 197.78,43.23 199.31,43.23 200.33,44.25 200.33,45.31 200.61,45.59 200.61,51.1 200.1,51.61 v3(200.09,51.61) 200.09,51.63 199.57,52.15 199.57,57.86 199.26,58.17 188.29,58.17 187.53,58.93 187.53,65.35 v2(188.09,65.91)
  BOTTOM w0.114: v1(185.29,65.28) 185.92,65.91 v2(188.09,65.91)
  BOTTOM w0.127: CONN16.70 141.6,4.47 v3(140.92,5.15)
CPU_JTAG_RST_R: length 40.4
  TOP w0.114: R49.2 100.08,109.35 100.54,108.89 v2(100.54,108.82) ; v4(95.16,82.79) 94.76,83.19 U9.BA19
  S5 w0.102: v4(95.16,82.79) 95.56,82.39 97.38,82.39 98.17,83.18 99.27,83.18 99.53,83.44 99.53,86.12 100.17,86.76 100.17,89.06 100.16,89.07 100.16,89.6 98.25,91.52 95.71,91.52 93.96,93.27 93.96,99.19 100.1,105.33 100.1,106.32 100.54,106.75 v2(100.54,108.82)
  BOTTOM w0.114: v2(100.54,108.82) 100.54,108.74 100.08,108.28 100.08,108.02 v1(100.43,107.66)
CPU_PWR_DEBUG_N: length 142.3
  TOP w0.102: 105.92,55.32 105.77,55.47 105.77,56.55
  TOP w0.114: CONN11.45 35.89,2.23 v2(35.99,2.13) ; U9.U77 105.77,56.55 ; 105.92,55.32 v3(105.92,54.15)
  S5 w0.102: v3(105.92,54.15) 106.6,54.84 109.83,54.84 111.33,53.34 111.33,51.16 112.83,49.66 112.83,48.41 112.52,48.11 111.84,48.11 111.1,47.37 111.1,45.31 109.7,43.92 109.7,39.88 108.66,38.84 106.26,38.84 105.05,37.63 102.79,37.63 100.92,35.76 100.92,35.54 100.91,35.54 100.91,29.2 95.49,23.78 95.49,13.22 92.68,10.41 89.21,10.41 84.67,5.87 81.22,5.87 80.76,5.41 80.18,5.41 79.91,5.14 79.91,4.9 79.68,4.67 76.87,4.67 75.6,5.94 73.59,5.94 72.88,6.65 70.62,6.65 69.52,5.56 67.72,5.56 67.42,5.87 62.52,5.87 61.61,4.95 60.62,4.95 59.72,4.05 56.39,4.05 55.87,4.57 52.23,4.57 51.24,3.58 37.44,3.58 v2(35.99,2.13)
  BOTTOM w0.114: v1(46.63,3.93) 46.63,3.52 46.06,2.95 C639.2 45.31,2.02 44.41,1.12 36.58,1.12 35.99,1.7 v2(35.99,2.13) 35.71,2.41 R760.1
CPU_PWRGD_CPU: length 10.9
  TOP w0.114: R252.1 106.1,48.49 v2(105.41,49.17) 105.41,49.33 104.99,49.75 104.99,56.29 105.12,56.42 105.12,56.9 U9.V76
  BOTTOM w0.114: v2(105.41,49.17) 106.4,48.19 v1(106.4,47.78)
CPU_SV: length 32.3
  TOP w0.114: U9.BP16 88.9,84.62 v4(89.19,84.33) ; R63.2 v2(87.12,108.81)
  S10 w0.102: v2(87.12,108.81) 86.66,108.36 85.74,108.36 85.09,107.71 85.09,106.27 85.9,105.46 85.9,104.79 86.33,104.36 86.33,98.92 89.38,95.87 89.38,90.27 89.52,90.14 89.52,89.11 89.3,88.89 89.3,88.25 89.57,87.98 89.57,87.51 89.3,87.24 89.3,86.52 89.57,86.25 89.57,85.83 89.28,85.55 89.28,84.43 v4(89.19,84.33)
  BOTTOM w0.114: v2(87.12,108.81) R63.2 88.06,109.5 v1(88.82,110.26)
CPU_XDP_HOOK0: length 208.2
  TOP w0.114: U12.N3 v3(190.09,49.61)
  S3 w0.102: v2(33.12,5.46) 33.48,5.11 39.39,5.11 43.3,1.19 81.1,1.19 88.46,8.56 92.59,8.56 97.61,3.53 103.76,3.53 104.19,3.96 106.63,3.96 109.48,1.12 125.19,1.12 126.23,2.15 127.28,2.15 128.35,1.09 158.83,1.09 159.89,2.15 161.29,2.15 161.65,1.8 166.76,1.8 172.09,7.13 172.09,22.81 186.16,36.88 186.16,42.42 188.64,44.91 188.64,48.16 v3(190.09,49.61)
  BOTTOM w0.114: v1(30.4,7.82) 31.14,7.82 33.12,5.84 v2(33.12,5.46) 32.92,5.26 R754.2 32.89,4.64 R775.1 R776.1
CPU_XDP_SYSPWROK: length 210.2
  TOP w0.114: v2(36.83,2.08) 36.39,2.52 CONN11.47 ; v3(201.09,48.61) U12.P13
  S3 w0.102: v2(93.94,9.87) 94.13,10.06 100.71,10.06 104.66,14 v2(104.66,14.02)
  S5 w0.102: v2(36.83,2.08) 38.1,3.35 51.34,3.35 52.33,4.34 55.78,4.34 56.3,3.82 59.82,3.82 60.72,4.72 61.7,4.72 62.62,5.64 67.32,5.64 67.63,5.33 69.62,5.33 70.71,6.43 72.78,6.43 73.5,5.71 75.51,5.71 76.88,4.34 77.75,4.34 77.8,4.29 83.42,4.29 88.99,9.87 v2(93.94,9.87)
  S8 w0.102: v2(104.66,14.02) 105.15,14.5 105.92,14.5 106.26,14.83 118.84,14.83 119.65,14.02 131.29,14.02 138.09,7.21 156.39,7.21 160.55,11.38 170.23,11.38 175,16.15 175,17.93 176.32,19.24 176.79,19.24 177.46,19.91 177.46,20.92 178.16,21.62 178.16,22.79 179.67,24.31 188.11,24.31 190.86,27.05 190.86,34.58 195.65,39.37 195.65,41.51 196.88,42.74 197.91,42.74 198.12,42.95 199.13,42.95 200.54,44.36 200.54,45.35 201.15,45.95 201.15,46.76 201.09,46.82 v3(201.09,48.61)
  BOTTOM w0.114: v1(92.1,13.24) 92.1,12.66 93.94,10.82 v2(93.94,9.87) ; v2(36.83,2.08) 36.63,2.29 R761.1
CSN1_VDDQ_CH01: length 25.3
  TOP w0.254: R368.2 63.16,9.37 v2(63.17,9.38) ; R333.2 v2(62.04,24.53)
  S8 w0.254: v2(62.04,24.53) 62.26,24.31 62.96,24.31 63.58,23.7 63.58,12.29 65.68,10.19 65.68,8.73 64.83,7.87 63.91,7.87 63.36,8.43 63.36,9.19 v2(63.17,9.38)
  BOTTOM w0.254: C630.1 63.16,9.37 v2(63.17,9.38) 63.14,9.41 v1(63.14,10.33)
CSN1_VDDQ_CH01_R: length 1.8
  TOP w0.203: v2(61.53,8.45) 61.24,8.15 U29.40
  TOP w0.254: R368.1 v2(61.53,8.45)
CSP1_VDDQ_CH01: length 22.1
  TOP w0.254: R335.2 v2(62.04,23.59) ; v2(64.06,9.38) 64.69,8.75 R365.2
  S8 w0.254: v2(62.04,23.59) 62.26,23.81 62.75,23.81 63.07,23.49 63.07,12.08 65.18,9.97 65.18,8.94 64.62,8.38 64.12,8.38 63.87,8.64 63.87,9.19 v2(64.06,9.38)
  BOTTOM w0.254: v2(64.06,9.38) 64.07,9.39 v1(65.07,9.39)
CSP1_VDDQ_CH01_C: length 3.9
  TOP w0.114: R372.1 63.26,7.58 R373.2 v2(63.16,6.72)
  BOTTOM w0.114: v2(63.16,6.72) C630.2 63.19,7.54 v1(64.28,7.54)
CSP1_VDDQ_CH01_R: length 2.7
  TOP w0.203: U29.39 61.26,7.75 v2(61.53,7.48)
  TOP w0.254: R373.1 v2(61.53,7.48)
  BOTTOM w0.254: v1(60.63,7.48) v2(61.53,7.48)
CSP1_VDDQ_CH01_R_R: length 2.1
  TOP w0.114: v2(65.88,6.6) R372.2 R365.1
DA/DSS: length 3.5
  TOP w0.114: R97.2 180.95,92.19 180.95,90.94 v2(180.62,90.61) 180.95,90.29 CONN6.49
DCPSUSBYP_C: length 15
  TOP w0.254: U9.AW21 v4(95.95,81.99)
  TOP w0.305: v4(95.95,81.99) U9.AU21
  BOTTOM w0.114: C382.2 90.17,73.21 90.17,75.13 90.58,75.54 90.58,76.07 90.2,76.45 90.2,76.81 90.68,77.29 90.68,77.65 91.19,78.16 91.19,78.61 91.34,78.77 92.38,78.77 92.56,78.94 92.56,79.35 93.37,80.16 93.5,80.16 94.16,80.82 95.3,80.82 95.56,81.08 95.56,81.38 95.95,81.77 v4(95.95,81.99)
DDR0_CLK_DN_1: length 1.6
  TOP w0.114: U9.CM45 v4(80.77,71.45)
  BOTTOM w0.114: R559.2 80.52,71.71 v4(80.77,71.45)
DDR0_CLK_DN_3: length 2.1
  TOP w0.114: U9.CL43 v4(81.26,72.31)
  BOTTOM w0.114: v4(81.26,72.31) 80.85,72.72 80.47,72.72 R557.2
DDR0_CLK_DP_1: length 4
  TOP w0.114: U9.CK45 v4(81.76,71.45)
  BOTTOM w0.114: v4(81.76,71.45) 81.44,71.45 80.95,70.97 80.64,70.97 80.37,71.25 79.22,71.25 78.92,71.55 R559.1
DDR0_CLK_DP_3: length 4.8
  TOP w0.114: U9.CJ43 v4(82.25,72.31)
  BOTTOM w0.114: R557.1 79.15,73.36 79.5,73.71 80.9,73.71 81.23,73.38 81.23,73.03 81.94,72.31 v4(82.25,72.31)
DDR1_CLK_DN_1: length 4.1
  TOP w0.102: U9.CR54 v4(78.54,67.45)
  BOTTOM w0.114: v4(78.54,67.45) 78.24,67.15 75.67,67.15 R571.2
DDR1_CLK_DN_3: length 2.5
  TOP w0.102: U9.CT53 v4(79.04,67.95)
  BOTTOM w0.114: v4(79.04,67.95) 78.49,67.95 78.1,67.56 77.77,67.56 77.74,67.59 R566.2
DDR1_CLK_DP_1: length 5.1
  TOP w0.102: v3(74.29,68.52) 74.29,68.51 74.96,67.84 75.92,67.84 76.12,67.64 77.7,67.64 77.89,67.45 U9.CU54
  BOTTOM w0.114: v3(74.29,68.52) 74.29,67.62 R571.1
DDR1_CLK_DP_3: length 3.1
  TOP w0.102: v3(75.74,68.49) 75.74,68.31 76.21,67.84 76.57,67.84 76.67,67.95 U9.CV53
  BOTTOM w0.114: R566.1 76.3,67.87 76.04,68.13 76.04,68.19 v3(75.74,68.49)
DDR01_CPU_VREFCA: length 8.9
  TOP w0.102: v4(77.93,67.95) 78.05,68.07 78.18,68.07 78.41,68.3 78.74,68.3 78.88,68.44 U9.CR52
  BOTTOM w0.114: R562.1 74.37,71.07 v1(74.37,71.07) 74.37,71.07 76.25,71.07 77.47,69.85 77.47,69.47 77.82,69.12 77.82,68.06 v4(77.93,67.95)
DDR01_VREFCA: length 157.9
  TOP w0.305: v2(48.84,59.64) 49.41,60.2 CONN8.164 ; v2(36.84,59.63) 37.42,60.2 CONN7.164
  TOP w0.381: v2(31.6,59.26) 30.12,60.73 30.12,68.91 28.22,70.82 28.22,76.02 30.76,78.56 30.76,80.38 31.03,80.65 31.03,81.15 30.76,81.41 30.76,94.41 31.68,95.33 v2(31.68,95.42) ; v2(69.52,71.91) 69.52,71.42 69.03,70.94 R200.1 C98.1
  S3 w0.381: v2(36.84,59.63) 36.35,59.14 36.29,59.14 36.18,59.03 35.69,59.03 35.57,59.15 31.91,59.15 31.8,59.26 v2(31.6,59.26)
  BOTTOM w0.381: C490.2 37.44,59.03 v2(36.84,59.63) 37.59,60.38 40.03,60.38 40.69,59.72 44.37,59.72 ; C489.2 48.57,59.36 v2(48.84,59.64) 48.69,59.79 47.98,59.79 47.32,60.45 46.46,60.45 45.72,59.72 44.37,59.72 ; 44.37,59.72 46.76,62.1 51.82,62.1 52.73,61.19 R580.2 ; R562.2 70.36,71.07 70.15,71.07 69.52,71.71 v2(69.52,71.91) 69.52,72.09 68.96,72.64 67.69,72.64 66.42,73.92 66.42,90.5 59.02,97.9 59.02,103.44 56.74,105.71 48.39,105.71 47.32,104.65 42.54,104.65 41.55,103.66 41.55,99.34 40.92,98.7 34.06,98.7 v1(31.68,96.32) v2(31.68,95.42)
DDR4_EVENT_MOS: length 14.4
  BOTTOM w0.114: R603.2 30.48,48.31 v1(30.35,48.18) 26.97,48.18 Q11.G 25.53,48.44 24.77,49.2 24.77,49.71 24.99,49.94 25.47,49.94 25.98,50.45 25.98,51.05 26.26,51.33 27.91,51.33 28.79,52.21 Q8.D
DDR4_VPP: length 115.3
  TOP w0.381: C170.2 v2(32.79,28.6) ; C171.2 v2(33.76,28.6) ; C169.1 v2(31.83,28.6) ; R345.1 37.95,18.39 v2(38.1,18.54)
  S3 w0.508: v2(52.86,33.38) 52.86,33.71 52.2,34.37 50.22,34.37 49.1,33.25 47.42,33.25 45.87,34.8 v2(45.87,35.86) 45.87,37.68 46.93,38.73 55.27,38.73 59.87,34.14 62.31,34.14 63.22,33.22 63.22,28.04 65.71,25.55 70.08,25.55 70.46,25.93 83.08,25.93 84.05,24.97 87.22,24.97 87.27,24.92 94.32,24.92 96.11,26.71 96.11,32.77 95.04,33.84 v2(95.04,35.67)
  S10 w0.508: v2(87.53,39.98) 89.1,41.55 92.86,41.55 93.78,40.64 93.78,36.93 v2(95.04,35.67)
  BOTTOM w0.381: R655.1 45.87,36.51 v2(45.87,35.86) 45.99,35.74 C542.1 ; R877.1 R878.1 88.09,40.54 v2(87.53,39.98) ; C551.1 C552.1 33.39,34.81 v2(33.39,35.84) 33.64,36.09 R652.1 ; C551.1 32.29,35.42 v2(32.7,35.84) ; C551.1 C550.1 ; C542.1 C543.1 ; C542.1 C541.1 45.05,35.73 v2(45.19,35.86) ; v2(52.86,33.38) 53.23,33.75 R880.2 ; R606.1 v2(25.38,50.5) ; R879.1 v2(95.04,35.67) R676.1
  vias: v1(30.68,30.76) v2(31.85,30.56) v2(31.85,29.54) v2(32.82,30.56) v2(32.82,29.54) v2(33.78,29.54)
DDR4_VPP_AGND: length 5.2
  TOP w0.381: v2(37.97,19.46) 37.82,19.31 R344.2 ; U23.5 34.26,22.46 v2(34.67,22.05) 34.8,22.17 C176.2
  BOTTOM w0.381: R709.1 v2(29.79,18.77)
DDR4_VPP_SS: length 5.8
  TOP w0.114: v2(38.1,21.69) 37.19,20.78 35.61,20.78 35.38,21 R339.1 35.15,21.51 34.42,21.51 34.12,21.81 U23.4
DDR4_VPP_SS_C: length 2
  TOP w0.114: v2(37.21,22.68) 36.7,22.17 C176.1 R339.2
DDR4_VPP_SW: length 10.8
  TOP w0.381: L18.1 22.58,23.33 C178.1
  BOTTOM w0.381: v2(24.03,25.32) 23.77,25.06 23.77,20.88 25.42,19.23 v1(27.1,19.23)
DDR4_VPP_VBST: length 7.3
  TOP w0.381: C178.2 v2(24.54,21.46) 24.71,21.46 25.02,21.16 U23.12
  BOTTOM w0.114: v2(24.54,21.46) 25.5,20.5 v1(27.36,20.5)
DDR4_VPP_VO: length 5.5
  TOP w0.114: R345.2 C189.1 v2(34.52,19.31) 33.97,19.86 U23.1
  BOTTOM w0.114: v1(33.6,18.82) 34.09,19.31 v2(34.52,19.31) 34.75,19.08 R711.1
DDR4_VPP_VO_R: length 2.8
  BOTTOM w0.114: R711.2 R708.1 v1(38.35,20.42)
DDR4_VPP_VREG: length 4.3
  TOP w0.114: U23.3 34.27,21.16 v2(34.42,21.01)
  BOTTOM w0.114: C596.1 R701.2 33.32,21.69 v1(33.5,21.51) 34.01,21.01 v2(34.42,21.01)
DDR_EVENT_1V2_N: length 61.3
  BOTTOM w0.114: R574.2 54.13,66.62 v1(45.45,66.62) 44.28,67.79 42.32,67.79 41.88,67.35 R570.2 42.33,66.76 43.09,66.76 44.54,65.32 44.54,60.92 43.88,60.26 41.42,60.26 39.83,61.85 34.8,61.85 33.96,61.01 33.96,49.05 32.49,47.57 25.86,47.57 24.38,49.05 24.38,51.66 24.81,52.09 R606.2 26.74,52.09 Q8.G
DEV_OFF_N_R: length 8.5
  TOP w0.114: v2(134.48,86) 134.74,86 135.77,87.02 U6.28
  BOTTOM w0.114: v2(134.48,86) 134.56,86.08 134.67,86.08 v1(135.2,86.61) 134.65,87.17 134.65,87.54 134.25,87.94 R960.2 132.2,87.94 131.2,86.94 R961.2
DIFF_XCLK_BIASREF: length 20.6
  TOP w0.108: U9.AA18 103.63,83.99 v4(104.01,84.38)
  S10 w0.102: v4(104.01,84.38) 104.01,85.52 102.18,87.34 102.18,87.55 101.52,88.21 101.52,88.54 101.04,89.03 101.04,93.83 101.65,94.44 102.16,94.44 103.89,96.16 103.89,97.03 106.1,99.24 v2(106.53,99.24)
  BOTTOM w0.114: v2(106.53,99.24) 106.32,99.44 R487.2
DIMM1_SPD: length 6.1
  TOP w0.305: v2(31.76,37.45) CONN7.255
  BOTTOM w0.114: v1(32.74,39.53) R646.2
  BOTTOM w0.381: R646.2 R652.2 32.58,37.45 v2(31.76,37.45) C528.1 C527.1
DIMM2_SPD: length 7.1
  TOP w0.305: CONN8.255 v2(46.58,37.45)
  BOTTOM w0.114: C518.1 45.64,39.52 v1(45.64,40.69)
  BOTTOM w0.381: R654.2 R655.2 46.43,37.6 v2(46.58,37.45) 46.58,37.95 45.95,38.58 C519.1 C518.1
EN_OSC_25M: length 2.6
  TOP w0.114: R154.2 124.53,95.32 123.66,94.45 OSC2.1
ENTER/EXIT_SLEEP: length 3.9
  TOP w0.114: CONN6.44 v2(182.95,79.18)
  BOTTOM w0.114: R157.2 R156.1 183.19,79.42 v2(182.95,79.18)
EXT_UART1_CTS: length 7.6
  TOP w0.114: TP11.1 139.98,10.45 v2(139.1,9.58)
  BOTTOM w0.114: v1(139.27,13.36) 139.6,13.03 139.6,10.07 v2(139.1,9.58) CONN16.79
EXT_UART1_RTS: length 4.7
  TOP w0.114: v3(139.29,5.08) 139.29,5.13 TP12.1
  BOTTOM w0.127: CONN16.76 140.1,3.27 140.36,3.53 140.36,4.47 139.75,5.08 v3(139.29,5.08)
FAULT_LED_OUT_N: length 36.5
  TOP w0.114: R336.2 v2(11.06,23.31)
  BOTTOM w0.114: v1(28.37,8) 27.55,8.83 24.04,8.83 23.22,8 21.09,8 16.67,12.42 9.96,12.42 9.43,12.95 9.41,12.95 9.02,13.35 9.02,19.77 10.54,21.3 10.54,22.79 v2(11.06,23.31) 11.53,23.78 CONN14.176
FB_V1P8A: length 4.7
  BOTTOM w0.381: 170.42,38.75 R612.2 R611.2 ; 170.42,38.75 U35.4 ; 170.42,38.75 v1(171.22,37.94)
FM_BIOS_RCRV_BOOT_N: length 34.8
  TOP w0.114: v2(83.44,109.7) 83.44,110.44 R43.1 ; v4(87.7,81.76) 87.41,82.04 U9.BU22
  S10 w0.102: v4(87.7,81.76) 87.7,82.68 87.32,83.06 87.32,83.76 87.59,84.03 87.59,84.65 87.32,84.92 87.32,85.49 87.59,85.76 87.59,86.23 87.32,86.49 87.32,87.14 87.59,87.41 87.59,88.06 87.22,88.42 87.22,88.65 86.82,89.05 86.81,89.05 86.58,89.28 86.58,91.23 87.43,92.08 87.43,95.87 84.4,98.89 84.4,102.67 83.74,103.33 83.74,103.99 83.06,104.68 83.06,108.43 83.44,108.81 v2(83.44,109.7)
  BOTTOM w0.114: v1(84.4,110.54) R43.1 83.33,109.8 v2(83.44,109.7)
FM_CPLD_P0V6_VTT_DIMM_EN: length 188.5
  TOP w0.114: U12.L4 v3(191.09,51.61) ; v2(42.21,23.14) 42.09,23.27 42.09,28.13 42.63,28.67 R325.2
  S3 w0.102: v2(97.36,20.74) 95.45,20.74 93.58,18.87 90.56,18.87 89.87,18.19 87.49,18.19 86.46,17.16 86.46,17.13 85.86,16.54 77.03,16.54 76.29,17.27 72.33,17.27 71.85,16.79 71.21,16.79 70.52,16.1 67.91,16.1 67.13,15.32 48.82,15.32 47.37,16.76 46.27,16.76 44.45,18.58 44.45,20.9 v2(42.21,23.14)
  S8 w0.102: v2(97.36,20.74) 97.37,20.75 106.5,20.75 110.57,24.82 146.91,24.82 149.33,27.23 159.73,27.23 162,29.5 162.14,29.63 162.14,29.63 162.81,30.3 180.36,30.3 183.72,33.66 183.72,39.29 182.88,40.13 182.88,42.16 184.76,44.04 184.76,49.78 185.78,50.8 188.26,50.8 189.53,52.07 190.63,52.07 191.09,51.61 v3(191.09,51.61)
  BOTTOM w0.114: v3(191.09,51.61) 190.6,52.1 189.56,52.1 v1(189.08,52.58)
FM_CPLD_P0V9_LAN1_EN: length 5.3
  TOP w0.114: v2(199.9,66.42) 199.69,66.22 R185.1 199.69,62.21 U12.A12
  BOTTOM w0.114: v2(199.9,66.42) v1(199.9,65.53)
FM_CPLD_P0V9_LAN_EN: length 9.6
  TOP w0.114: R223.1 207.11,45.34 205.84,46.61 v2(205.84,47.07) 205.84,48.97 204.81,50.01 204.47,50.01 204.27,50.2 204.27,50.39 204.21,50.45 204.21,50.6 203.7,51.11 U12.M16
  BOTTOM w0.114: v2(205.84,47.07) v1(205.84,46.07)
FM_CPLD_P1V8_LAN1_EN: length 4.1
  TOP w0.114: U12.T11 v2(198.59,46.1) 199.14,45.55 199.14,44.91 199.12,44.9 199.12,43.95 198.68,43.51 R224.2
FM_CPLD_P1V8_LAN_EN: length 6.4
  TOP w0.114: U12.R5 193.08,47.62 193.08,46.81 192.78,46.51 v2(192.78,45.68) 192.78,45.41 191.49,44.12 R225.2
  BOTTOM w0.114: v2(192.78,45.68) 192.77,45.67 191.77,45.67 v1(191.74,45.64)
FM_CPLD_V3P3_PCH_EN: length 141.5
  TOP w0.114: v2(105.77,14.02) 100.46,8.71 R367.2 96.85,7.34 Q6.G ; U12.N13 v3(201.09,49.61)
  S8 w0.102: v2(105.77,14.02) 106.35,14.61 118.74,14.61 119.56,13.79 131.19,13.79 138,6.99 156.48,6.99 160.65,11.15 170.32,11.15 175.23,16.06 175.23,17.83 176.41,19.01 176.88,19.01 177.68,19.82 177.68,20.82 178.45,21.59 178.45,22.76 179.7,24.01 188.13,24.01 191.08,26.96 191.08,34.48 195.88,39.27 195.88,41.41 196.98,42.51 198.01,42.51 198.22,42.72 199.57,42.72 201.55,44.7 201.55,46.05 201.37,46.23 201.37,48.21 201.55,48.39 201.55,49.15 v3(201.09,49.61)
FM_CPU_PROCHOT_PCH_N: length 63.4
  TOP w0.114: CONN4.30 25.82,113.02 v2(25.63,112.83) ; R86.1 v2(77.78,107.26)
  S10 w0.102: v2(77.78,107.26) 77.78,108.39 76.82,109.35 76.5,109.35 74.8,111.05 74.8,111.44 73.6,112.65 73.39,112.65 72.44,113.6 72.44,114.52 72.03,114.94 71.75,114.94 70.84,115.85 67.15,115.85 66.48,115.19 64.69,115.19 64.14,114.63 62.03,114.63 61.98,114.58 58.19,114.58 57.45,115.32 51.21,115.32 51.17,115.28 48.72,112.83 34.9,112.83 33.93,113.8 26.6,113.8 v2(25.63,112.83)
  BOTTOM w0.114: v2(25.63,112.83) 25.17,112.37 v1(25.17,111.86)
FM_DDR4_VPP_CPLD_EN: length 189.5
  TOP w0.114: v2(35.38,25.04) R334.1 35.05,23.76 U23.7 ; U12.L3 v3(190.09,51.61)
  S3 w0.102: v2(98.17,20.28) 95.31,20.28 93.68,18.65 90.66,18.65 87.58,15.57 81.41,15.57 80.69,16.28 76.96,16.28 76.2,17.04 72.58,17.04 72.03,16.5 72.03,15.96 71.77,15.7 67.83,15.7 67.22,15.09 48.72,15.09 47.28,16.54 46.17,16.54 44.22,18.49 44.22,18.6 41.82,21.01 38.14,21.01 35.38,23.76 v2(35.38,25.04)
  S8 w0.102: v3(190.09,51.61) 189,50.52 189,48.39 187.01,46.39 187.01,43.83 184.35,41.18 183.95,40.77 183.95,33.56 180.46,30.07 162.9,30.07 162.37,29.54 162.23,29.4 159.83,27 149.42,27 147.01,24.59 110.66,24.59 106.35,20.28 v2(98.17,20.28)
  BOTTOM w0.114: v3(190.09,51.61) 188.27,51.61 v1(187.96,51.92)
FM_ME_RCRV_N: length 41.8
  TOP w0.114: v2(66.22,112.55) R30.2 ; U9.BP9 v4(89.19,87.77)
  S3 w0.102: v4(89.19,87.77) 89.19,88.08 89.08,88.19 89.08,88.95 89.33,89.2 89.33,93.2 87.52,95.01 85.1,97.43 82.55,97.43 80.2,99.78 76.38,99.78 68.41,107.75 67.92,107.75 67.34,108.33 67.34,111.43 v2(66.22,112.55)
  BOTTOM w0.114: R30.2 v2(66.22,112.55) 66.83,113.16 v1(67.16,113.16)
FM_NMI_EVENT_CPLD_N: length 190.2
  TOP w0.114: U12.D12 v3(200.09,59.61) ; v2(118.87,120.02) 116.54,122.35 81.31,122.35 75.63,116.68 75.63,115.31 75.54,115.22 75.54,107.26 v2(74.93,106.65)
  S3 w0.102: v3(200.09,59.61) 200.58,60.11 200.58,60.78 200.76,60.96 200.76,63.2 201.58,64.02 201.58,67.49 201.37,67.7 201.37,78.08 201.1,78.35 201.1,78.35 199.86,79.59 199.86,82.84 196.4,86.31 196.4,98.55 192.62,102.32 176.49,102.32 171.16,107.65 169.9,108.92 169.47,108.92 167.84,110.54 165.53,110.54 165.13,110.95 164.01,110.95 160.75,114.2 149.03,114.2 148.32,114.91 145.16,114.91 140.61,119.46 119.43,119.46 v2(118.87,120.02)
  BOTTOM w0.114: v2(118.87,120.02) 118.36,119.51 118.36,118.99 118.37,118.98 v1(118.37,118.97) ; v2(74.93,106.65) 74.93,105.27 74.1,104.44 R474.1
FM_NMI_EVENT_PCH_N: length 57.4
  TOP w0.114: CONN4.6 v2(31.82,110.39) ; R101.1 v2(74.1,105.46)
  S10 w0.102: v2(31.82,110.39) 32.05,110.16 47.99,110.16 48.6,110.77 48.87,111.04 48.87,111.04 51.74,113.91 56.09,113.91 58.37,111.63 60.4,111.63 60.48,111.56 63.93,111.56 64.21,111.28 65.23,111.28 65.38,111.43 66.52,111.43 67.34,110.62 70.62,110.62 71.7,109.54 71.7,109.21 72.3,108.61 72.63,108.61 73.73,107.51 73.73,105.82 v2(74.1,105.46)
  BOTTOM w0.114: R442.1 31.82,113.17 v1(31.82,111.43) v2(31.82,110.39)
FM_PROCHOT_N: length 182.9
  TOP w0.114: v2(115.87,120.04) 114.29,121.63 84.05,121.63 80.43,118.01 80.43,113.35 79.78,112.7 79.78,109.16 79.97,108.98 79.97,108.49 79.02,107.54 78.21,107.54 77.98,107.77 77.42,107.77 76.63,106.98 v2(76.63,106.78) ; U12.C11 v3(199.09,60.61)
  S3 w0.102: v3(199.09,60.61) 199.47,60.99 199.47,61.45 199.47,61.45 199.47,61.77 199.47,61.77 199.47,66.21 199.44,66.23 199.44,66.61 199.47,66.64 199.47,66.85 200.68,68.06 200.68,77.8 195.71,82.77 195.71,98.14 192.41,101.43 176.36,101.43 169.56,108.23 165.28,108.23 163.22,110.29 162.2,110.29 159.03,113.46 140.93,113.46 135.62,118.77 117.14,118.77 v2(115.87,120.04)
  BOTTOM w0.114: R469.1 76.94,106.47 v2(76.63,106.78)
FM_SMI_ACTIVE_CPLD_N: length 221.6
  TOP w0.114: U12.E12 v3(200.09,58.61) ; R75.1 v2(74.19,106.29)
  S3 w0.102: v2(74.19,106.29) 74.19,106.56 74.96,107.33 74.96,110.23 74.44,110.74 73.76,110.74 73.28,111.23 72.31,111.23 71.81,111.73 71.81,112.35 71.1,113.06 70.46,113.06 70.05,113.46 70.05,114.95 67.66,117.35 67.26,117.75 67.26,119.42 67.26,119.42 67.26,120.18 68.28,121.2 68.95,121.87 140.59,121.87 144.68,117.78 152.21,117.78 152.85,118.41 157.63,118.41 159.13,119.91 163.16,119.91 164.55,121.31 171.36,121.31 176.07,116.6 183.45,116.6 186.09,113.96 186.09,108.84 191.05,103.87 196.17,103.87 201.6,98.45 201.6,93.03 201.24,92.66 201.24,80.16 201.67,79.72 202.74,78.65 202.74,69.66 204.8,67.6 204.8,64.45 204.77,64.42 204.77,64.39 202.62,62.23 202.62,59.39 202.36,59.13 200.61,59.13 v3(200.09,58.61)
  BOTTOM w0.114: v3(200.09,58.61) 199.96,58.61 199.47,59.11 198.78,59.11 198.6,59.28 v1(198.6,62.51) ; v2(74.19,106.29) 74.12,106.29 R466.1
FM_SMI_ACTIVE_PCH_N: length 59.6
  TOP w0.114: CONN4.36 v2(24.32,111.12) ; R73.1 v2(74.19,108.74)
  S10 w0.102: v2(74.19,108.74) 72.97,109.96 72.24,109.96 71.01,111.19 67.54,111.19 67.04,111.68 65.56,111.68 65.05,112.19 64.14,112.19 63.73,111.79 60.58,111.79 60.45,111.91 58.42,111.91 56.2,114.14 51.65,114.14 48.64,111.13 48.15,110.64 33.35,110.64 32.99,111 24.44,111 v2(24.32,111.12)
  BOTTOM w0.114: v2(24.32,111.12) 23.5,110.3 v1(23.5,109.91)
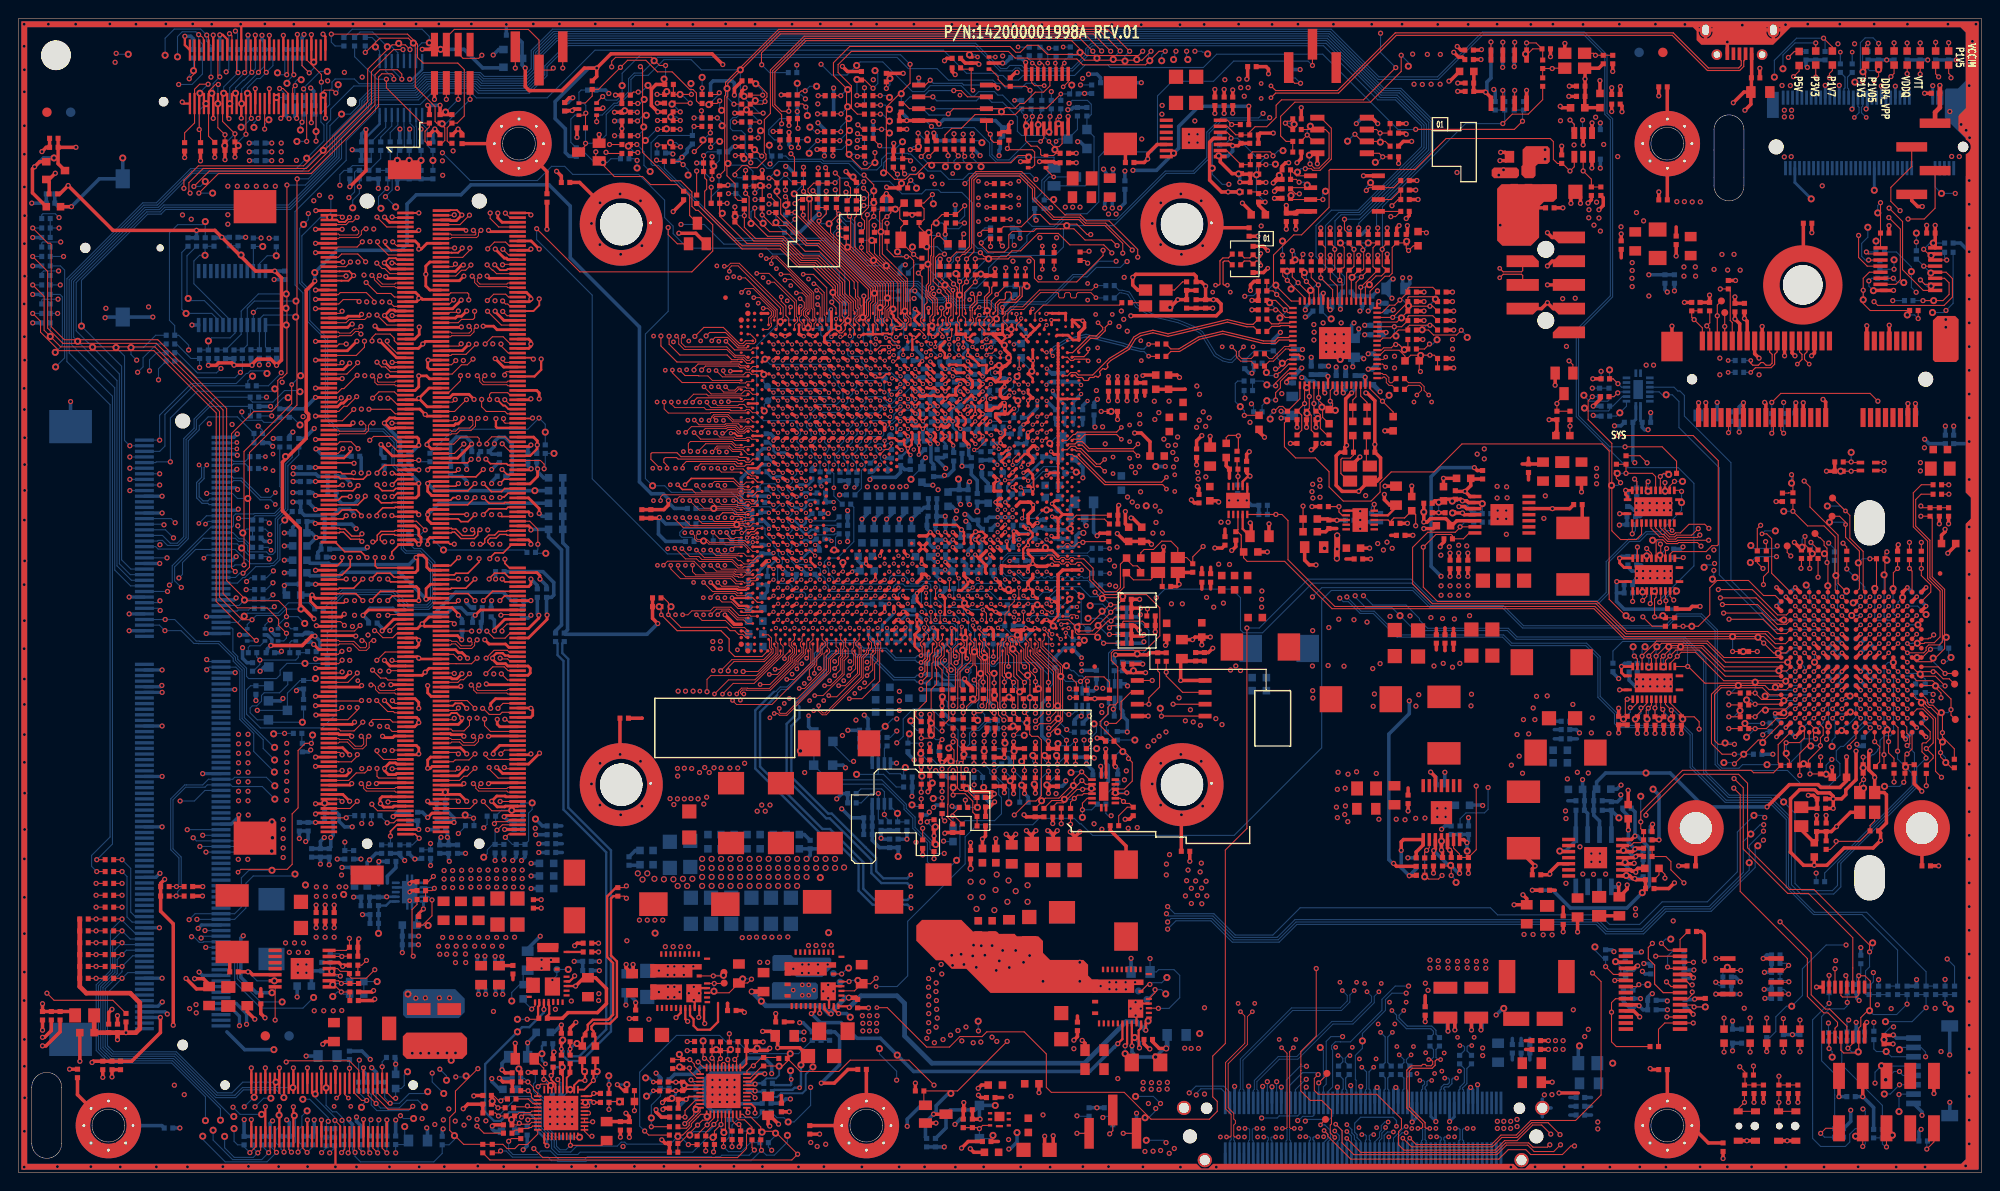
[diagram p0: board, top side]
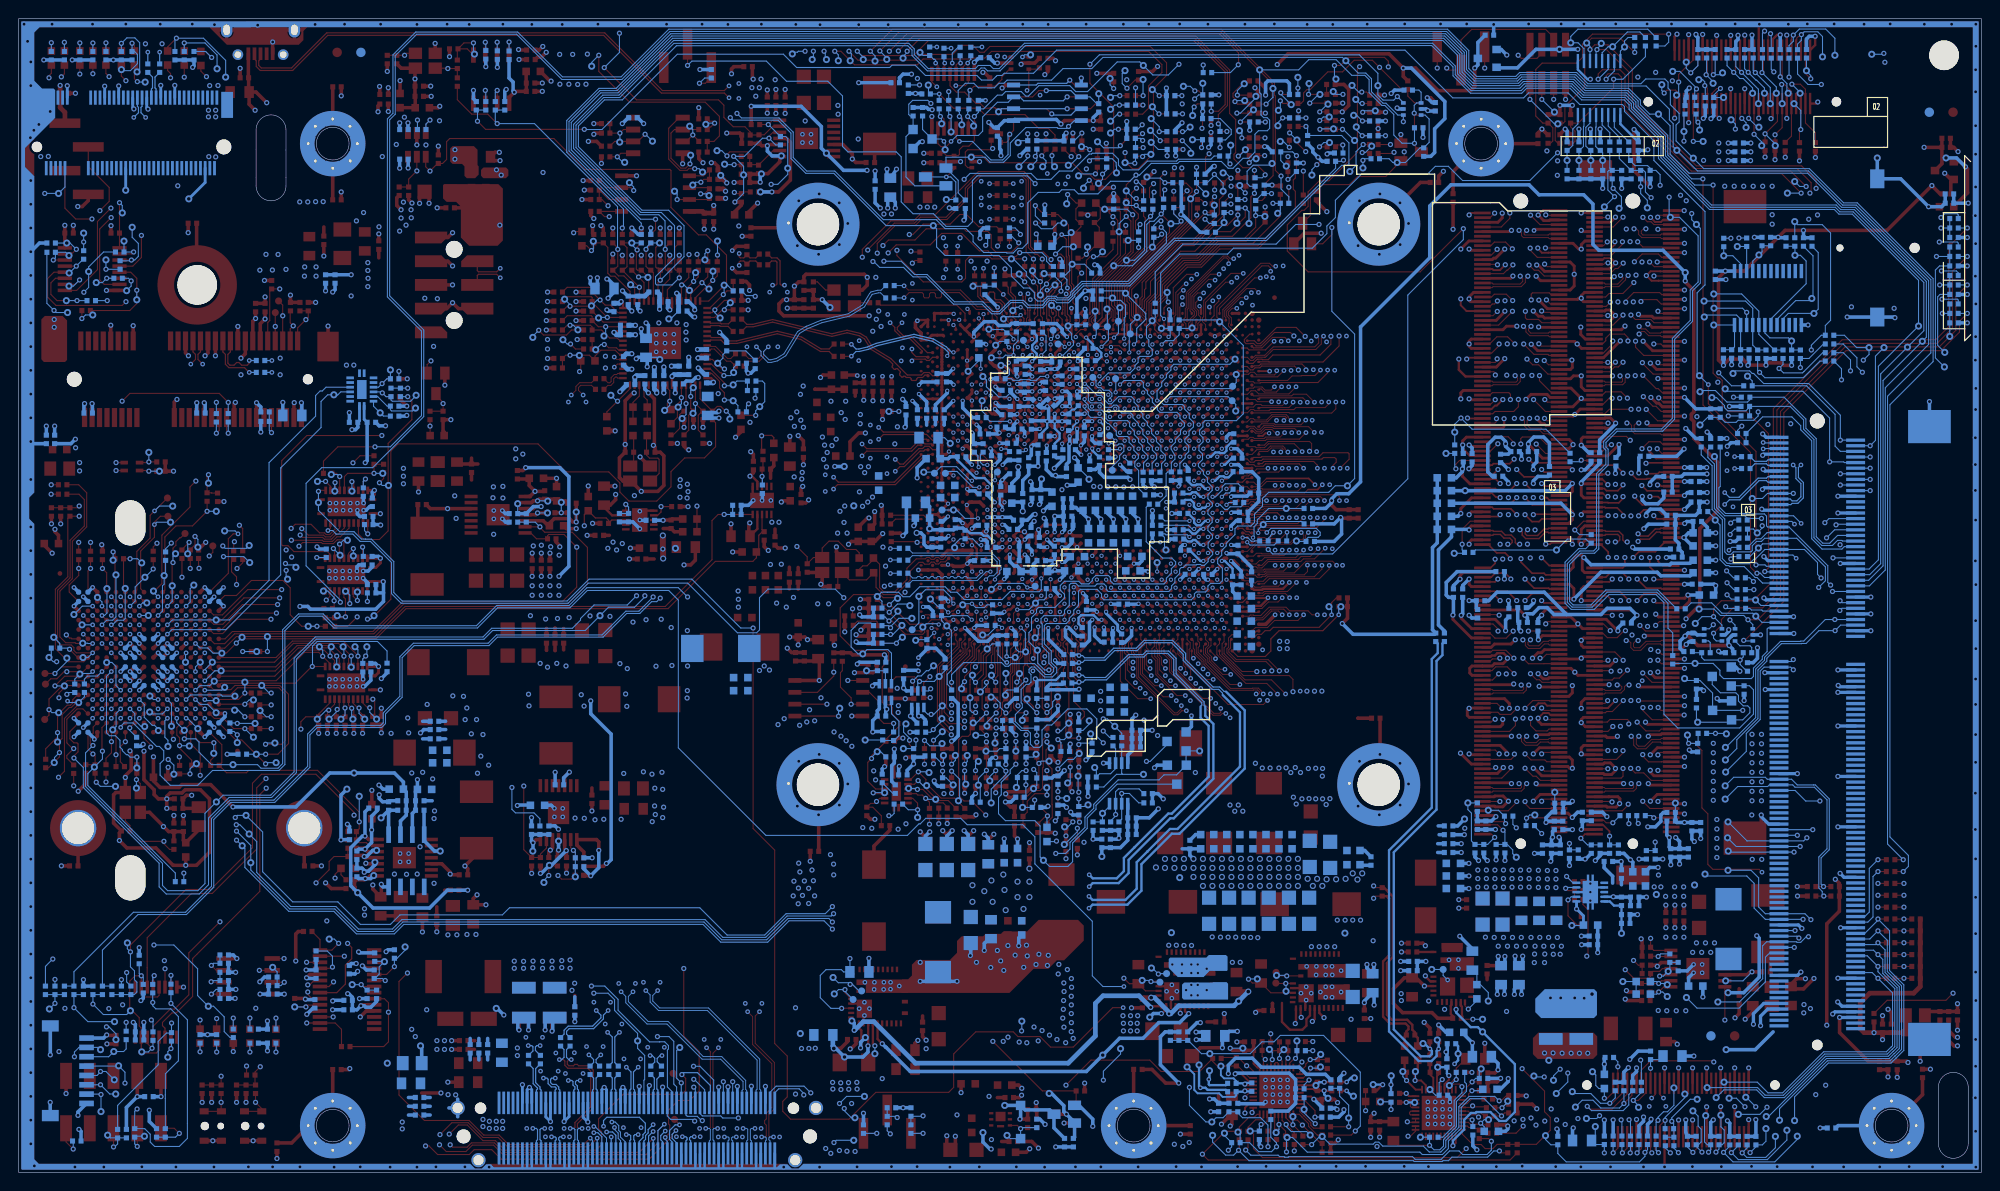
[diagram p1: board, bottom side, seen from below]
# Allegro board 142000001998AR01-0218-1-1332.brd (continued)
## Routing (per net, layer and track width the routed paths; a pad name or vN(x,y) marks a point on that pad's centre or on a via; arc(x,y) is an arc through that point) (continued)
FM_THROTTLE_N: length 188.4
  TOP w0.114: U12.C12 v3(200.09,60.61) ; R107.1 76.96,104.04 76.66,104.34 76.66,105.81 75.78,106.69 75.78,115.11 75.88,115.21 75.88,116.58 81.41,122.11 115.79,122.11 v2(117.86,120.04)
  S3 w0.102: v3(200.09,60.61) 200.53,61.05 200.53,64.93 200.65,65.05 200.65,67.38 201.14,67.87 201.14,77.99 201.01,78.12 199.64,79.49 199.64,82.75 196.17,86.21 196.17,98.46 192.73,101.89 176.6,101.89 172.27,106.23 169.81,108.69 166.95,108.69 165.28,110.36 164.27,110.36 160.71,113.92 145.83,113.92 140.52,119.23 118.67,119.23 v2(117.86,120.04)
  BOTTOM w0.114: v2(117.86,120.04) 117.22,119.41 117.22,119.25 v1(117.12,119.14)
FM_THROTTLE_PCH_N: length 65.2
  TOP w0.114: CONN4.28 v2(26.32,111.68)
  S10 w0.102: v2(26.32,111.68) 26.55,111.46 31.61,111.46 32.3,112.14 49,112.14 51.46,114.59 56.39,114.59 58.51,112.47 58.7,112.47 58.89,112.47 61.19,112.47 61.7,112.98 62.59,112.98 63.55,113.94 64.29,113.94 65.21,113.03 67.66,113.03 67.69,113.06 70.98,113.06 71.4,112.64 71.4,112.18 72.89,110.69 74.04,110.69 75.62,109.12 75.62,106.63 76.35,105.9 76.35,105.18 v2(75.95,104.78)
  BOTTOM w0.114: R477.1 76.91,104.78 R473.1 v2(75.95,104.78) ; v2(26.32,111.68) 26.32,112.22 v1(26.77,112.67)
FORCE_MEMPROCHOT: length 126.8
  TOP w0.114: U12.K5 v3(192.09,52.61)
  S8 w0.102: v3(192.09,52.61) 192.09,52.64 191.62,53.11 186.49,53.11 184.38,51.01 184.38,47.27 181.36,44.25 171.06,44.25 166.83,40.02 166.77,40.02 166.74,40.06 137.86,40.06 132.33,34.52 124.4,34.52 123.43,33.55 122.95,33.55 122.26,34.24 99.14,34.24 v2(99.03,34.14)
  BOTTOM w0.114: v2(99.03,34.14) 98.18,34.14 98.18,34.14 97.97,34.14 97.51,34.6 97.51,35.32 95.91,36.92 95.91,38.02 94.97,38.96 94.97,39.4 92.35,42.01 87.99,42.01 87.45,42.55 86.11,42.55 Q13.G 85.09,43.61 Q12.G v1(83.64,45.11)
FP_LED9_N: length 43
  TOP w0.114: U12.M14 v3(202.09,50.61) ; LED17.C v2(190.6,16.31)
  S8 w0.102: v2(190.6,16.31) 190.6,19.57 194.92,23.89 194.92,33.12 196.5,34.7 197.68,34.7 200.36,37.37 200.36,38.55 203.47,41.67 203.47,48.39 203.56,48.48 203.56,48.82 203.47,48.91 203.47,49.4 203.07,49.79 203.07,49.86 203.07,50.17 202.63,50.61 v3(202.09,50.61)
FP_LED9_N_R: length 1.9
  TOP w0.114: v2(190.6,12.9) LED17.A
  BOTTOM w0.114: LED17.A v2(190.6,12.9)
FP_LED10_N: length 45.2
  TOP w0.114: U12.M12 v3(200.09,50.61) ; LED16.C v2(188.82,16.46)
  S8 w0.102: v2(188.82,16.46) 189.84,17.48 189.84,19.23 194.69,24.09 194.69,33.21 196.4,34.92 197.59,34.92 200.13,37.47 200.13,38.65 203.24,41.76 203.24,46.64 202.56,47.32 202.56,47.95 202.75,48.13 202.75,49.85 202.44,50.16 200.53,50.16 v3(200.09,50.61)
FP_LED10_N_R: length 1.9
  TOP w0.114: v2(188.82,12.88) LED16.A
  BOTTOM w0.114: LED16.A v2(188.82,12.88)
GPIO33: length 6.8
  TOP w0.114: v4(98.61,87.48) 98.32,87.19 U9.AN11
  BOTTOM w0.114: R520.1 R523.2 97.66,90.73 97.72,90.68 v1(97.72,90.61) 97.72,90.17 97.34,89.79 97.34,89.18 97.14,88.99 97.14,88.57 98.23,87.48 v4(98.61,87.48)
GPIO61_JTAG_EN_R: length 13.3
  TOP w0.114: U9.BB18 94.3,84.35 94.34,84.38 v4(94.34,84.38)
  BOTTOM w0.114: R131.2 88.39,91.48 v1(88.71,91.16) 89.32,90.55 89.32,89.35 89.08,89.11 89.08,88.46 88.71,88.09 88.71,87.53 88.89,87.35 90.05,87.35 90.22,87.17 90.22,86.71 90.56,86.36 90.56,86.09 91.08,85.58 93.41,85.58 94.34,84.65 v4(94.34,84.38)
HS1_PIN1: length 4.2
  TOP w0.381: C25.2 128.15,101.12 HS1.1
  vias: v2(121.29,101.58) v2(122.2,103.79) v2(122.19,99.32) v2(124.35,104.74) v2(124.41,98.27) v2(126.53,104) v2(126.69,99.2)
HS1_PIN2: length 3.9
  TOP w0.381: C42.2 124.4,38.26 v2(124.41,38.27)
  vias: v2(121.29,41.58) v2(122.2,43.79) v2(122.19,39.32) v2(124.35,44.74) v2(126.53,44) v2(126.69,39.2)
HS1_PIN3: length 4.1
  TOP w0.381: C124.2 60.02,105.97 v2(62.2,103.79)
  vias: v2(61.29,101.58) v2(62.19,99.32) v2(64.35,104.74) v2(64.41,98.27) v2(66.53,104) v2(66.69,99.2)
HS1_PIN4: length 3.9
  TOP w0.381: C138.2 64.34,44.75 v2(64.35,44.74)
  vias: v2(61.29,41.58) v2(62.2,43.79) v2(62.19,39.32) v2(64.41,38.27) v2(66.53,44) v2(66.69,39.2)
HW_BMC_PRESENT: length 14.3
  S3 w0.102: v2(23.44,69.22) 22.48,70.18 18.41,70.18 17.17,68.94 15.93,68.94 v2(15.54,69.32)
  BOTTOM w0.114: v2(15.54,69.32) 15.48,69.38 CONN14.32 ; R914.1 R913.1 24.38,68.86 v1(23.98,68.45) 23.44,68.99 v2(23.44,69.22)
I2C_BUS-A0: length 6.4
  BOTTOM w0.114: R1057.2 v1(44.32,108.33) R1058.2 44.25,109.4 43.71,109.94 43.71,111.68 43.17,112.22 U45.9
I2C_BUS-A1: length 6.2
  BOTTOM w0.114: R1059.2 v1(43.05,108.33) R1060.2 42.98,109.4 42.57,109.81 42.57,111.94 42.52,112 U45.10
I2C_BUS-A2: length 6.4
  BOTTOM w0.114: U45.11 41.87,112.3 42.32,111.86 42.32,109.86 41.85,109.4 R1062.2 v1(41.78,108.33) R1061.2
I2C_BUS-A3: length 6.3
  BOTTOM w0.114: R1063.2 v1(40.51,108.33) 40.51,109.15 R1064.2 40.84,109.4 41.26,109.82 41.26,111.88 41.22,111.91 U45.12
I2C_BUS_RESET: length 216.8
  TOP w0.114: R1081.1 43.69,110.16 43.48,110.37 43.48,111.45 43.94,111.92 R1080.1 43.13,112.32 39.34,116.1 v2(39.34,117.02) ; R1075.2 v2(182.98,51.31)
  S8 w0.102: v2(149.3,116.48) 149,116.79 146.66,116.79 141.73,121.72 114.88,121.72 112.45,119.28 107.55,119.28 105.75,117.47 102.21,117.47 98.65,121.04 43.23,121.04 42.47,120.27 42.47,119.38 41,117.91 40.23,117.91 v2(39.34,117.02)
  S10 w0.102: v2(182.98,51.31) 182.93,51.36 182.93,56.72 183.49,57.28 183.49,75 167.81,90.69 167.81,97.7 160.35,105.16 160.35,108.53 155.14,113.74 152.04,113.74 v2(149.3,116.48)
  BOTTOM w0.114: R1114.1 35.94,119.43 38.35,117.02 v2(39.34,117.02) ; v1(184,52.12) 183.18,51.31 v2(182.98,51.31)
I2C_BUS_RESET_R: length 6.1
  TOP w0.114: R1075.1 v2(185.8,51.31) 186.49,50.62 189.1,50.62 U12.M2
  BOTTOM w0.114: v1(185.8,52.48) v2(185.8,51.31)
I2C_MULTIPLEXER_SELECT: length 67.3
  S3 w0.102: v2(16.56,67.92) 19.15,65.33 19.15,59.46 23.77,54.84 v2(25.81,54.84)
  S8 w0.102: v2(23.88,81.41) 23.88,80.26 22.48,78.87 22.48,55.75 23.39,54.84 v2(25.81,54.84)
  BOTTOM w0.114: v2(25.81,54.84) 25.81,54.36 25.09,53.65 R917.2 ; v2(25.81,54.84) 25.47,55.17 R1110.2 ; v2(25.81,54.84) 29.64,54.84 29.92,55.11 R1109.2 30.79,55.63 R918.2 ; v2(23.88,81.41) 23.88,80.98 24.34,80.51 26.02,80.51 26.24,80.29 27.4,80.29 R1071.2 R1072.2 29.28,80.83 v1(30.1,80.01) ; v2(16.56,67.92) 15.7,68.78 CONN14.34
I2C_MUX_S1: length 1.8
  BOTTOM w0.114: R1109.1 29.01,56.72 29.18,56.9 29.64,56.9 U40.6
I2C_MUX_S2: length 2.6
  BOTTOM w0.114: U41.6 25.83,56.36 24.74,56.36 24.56,56.19 R1110.1
I210_JTAG_CLK: length 4.2
  TOP w0.114: R977.1 v2(134.49,92.33) 134.72,92.33 135.53,91.52 U6.19
  BOTTOM w0.114: v2(134.49,92.33) 134.49,92.46 v1(133.86,93.09)
I210_JTAG_TDI: length 4.7
  TOP w0.114: v2(134.54,85.29) 134.85,85.6 134.95,85.6 135.88,86.52 U6.29
  BOTTOM w0.114: R978.1 133.5,86.15 v1(133.5,85.62) 133.83,85.29 v2(134.54,85.29)
I210_JTAG_TDO: length 4.9
  TOP w0.114: R975.1 v2(143.67,95.85) 143.09,95.27 U6.4
  BOTTOM w0.114: v2(143.67,95.85) 142.71,95.85 v1(142.67,95.81)
I210_JTAG_TMS: length 4.4
  TOP w0.114: U6.18 135.82,92.02 v2(135.51,92.33) 134.49,93.34 R976.1
  BOTTOM w0.114: v2(135.51,92.33) 135.51,92.02 v1(134.95,91.47)
I210_LAN_PWR_GOOD: length 142.3
  TOP w0.114: U12.R16 204.53,47.17 204.53,46.41 204.09,45.97 203.77,45.97 203.65,45.86 203.65,45.02 204.09,44.58 v2(204.09,44.35) ; v2(150.62,100.58) 150.5,100.71 R963.1
  S8 w0.102: v2(143,61.72) 147.56,66.28 147.56,81.39 148.11,81.94 148.11,84.42 149.51,85.82 149.51,99.47 v2(150.62,100.58)
  BOTTOM w0.114: v2(204.09,44.35) 203.09,43.35 203.09,41.2 194.97,33.09 194.97,30.56 194.21,29.79 190.68,29.79 189.69,30.78 189.69,37.92 187.48,40.13 182.93,40.13 180.29,42.77 180.29,54.94 178.16,57.07 160.22,57.07 159.29,58 149.39,58 v1(147.8,59.59) 146.9,60.49 144.11,60.49 143,61.59 v2(143,61.72)
I210_LAN_PWR_GOOD_R: length 11.9
  TOP w0.114: R963.2 149.22,99.19 v2(148.72,98.68) 148.46,98.93 R822.1 R821.2 146.96,99.01 146.96,96.24 146.65,95.93 146.2,95.93 144.59,94.33 U6.1
  BOTTOM w0.114: v2(148.72,98.68) 148.51,98.88 v1(148.51,99.67)
I210_LINK_STATUS: length 262.2
  TOP w0.114: U12.F15 v3(203.09,57.61)
  S3 w0.102: v2(15.92,62.18) 16.35,61.76 16.35,55.95 20.11,52.19 24.34,52.19 26.11,50.42 26.11,32.7 31.89,26.92 34.86,26.92 35.5,26.28 40.12,26.28 50.71,15.7 56.65,15.7 57.97,17.02 71.75,17.02 72.57,17.83 86.79,17.83 88.39,19.43 92.96,19.43 98.31,24.77 122.97,24.77 123.85,25.66 123.85,27.53 v2(122.94,28.45)
  S5 w0.102: v2(186.83,37.98) 185.45,39.37 185.45,40.79 185.06,41.17 185.06,51.49 187.68,54.1 202.12,54.1 203.09,55.07 v3(203.09,57.61)
  BOTTOM w0.114: v2(186.83,37.98) 186.6,38.21 v1(185.67,38.21) 183.9,36.43 183.9,32.17 180.68,28.96 175.85,28.96 173.44,26.54 170.22,26.54 169.2,27.56 158.24,27.56 157.48,28.32 137.12,28.32 134.2,25.4 130.18,25.4 127.89,27.69 123.7,27.69 v2(122.94,28.45) ; CONN14.56 v2(15.92,62.18)
I210_RESET_N_R: length 5.4
  TOP w0.114: R957.2 147.07,81.41 v2(145.92,82.55) 144.59,83.88 U6.48
  BOTTOM w0.114: v1(146.63,83.19) 146,82.55 v2(145.92,82.55)
I210_RST_L: length 115.4
  TOP w0.114: v2(192.28,46.41) 192.23,46.41 192.05,46.58 192.05,47.6 191.59,48.06 U12.R4
  S8 w0.102: v2(131.19,93.78) 131.19,90.2 132.59,88.8 132.59,80.31 136.32,76.58 139.32,76.58 139.83,76.07 139.83,69.17 139.52,68.86 139.52,62.69 v2(138.43,61.59)
  BOTTOM w0.114: v2(192.28,46.41) 191.06,46.41 190.7,46.05 190.7,44.98 189.36,43.64 v1(187.07,43.64) 184.45,43.64 184.07,43.26 182.25,43.26 181.76,43.76 181.76,58.08 180.06,59.78 177.42,59.78 176.16,58.52 161.02,58.52 158.85,60.68 151.11,60.68 149.2,62.59 139.42,62.59 v2(138.43,61.59) ; R881.1 132.13,93.85 131.27,93.85 v2(131.19,93.78)
I210_RST_L_R: length 6.8
  TOP w0.114: R882.2 R979.2 134.21,94.36 v2(134.61,93.97) 136.05,92.52 U6.17
  BOTTOM w0.114: v2(134.61,93.97) 134.52,94.06 v1(134.52,94.97) 134.16,94.97 R979.2
I210_SDP0: length 9.2
  TOP w0.114: R1038.2 151.31,94.74 148.76,94.74 148.64,94.63 R1037.2 v2(147.79,93.38) 147.25,92.84 146.69,92.84 145.87,92.02 U6.63
  BOTTOM w0.114: v1(148.72,92.76) 148.1,93.38 v2(147.79,93.38)
I210_SDP1: length 8.6
  TOP w0.114: U6.61 147.46,91.02 R1039.2 148.64,92.64 148.72,92.72 v2(151,92.72) 151.3,92.72 R1040.2
  BOTTOM w0.114: v2(151,92.72) 151,92.89 v1(151.59,93.47)
I210_SDP2: length 8.9
  TOP w0.114: R1042.2 151.3,93.73 148.72,93.73 148.64,93.65 R1041.2 148.64,93.14 v2(147.02,91.52) U6.62
  BOTTOM w0.114: v2(147.02,91.52) 147.9,91.52 v1(147.96,91.47)
I210_SDP3: length 8.5
  TOP w0.114: R1043.2 151.3,91.7 148.72,91.7 148.64,91.62 R1044.2 147.98,90.52 v2(147.19,90.52) U6.60
  BOTTOM w0.114: v2(147.19,90.52) 147.19,89.71 v1(147.37,89.53)
I210_SMB_ALRT_R: length 7
  TOP w0.114: U6.35 v2(138.09,83.06) 138.09,81.78 R1035.2 137.87,81.48 138.3,81.05 138.3,79.45 R1034.2
  BOTTOM w0.114: v2(138.09,83.06) 138.09,83.73 v1(137.82,84)
I210_SMB_SCL: length 7.3
  TOP w0.114: U6.34 v2(137.59,82.29) R1033.2 136.86,81.48 137.29,81.05 137.29,79.45 R807.2
  BOTTOM w0.114: v2(137.59,82.29) 137.59,81.51 v1(137.85,81.25)
I210_SMB_SDA: length 8
  TOP w0.114: R808.2 139.97,78.94 139.28,79.63 139.28,81.1 138.9,81.48 R1031.2 138.59,81.7 v2(138.59,82.3) U6.36
  BOTTOM w0.114: v2(138.59,82.3) 138.59,81.12 v1(139.01,80.7)
I210_XTAL_I: length 4.2
  TOP w0.114: U6.46 143.59,83.1 144.27,82.42 R956.1 R962.2
I210_XTAL_I_R: length 3.4
  TOP w0.114: R962.1 144.2,78.79 C650.2 144.2,75.97 OSC6.1
I210_XTAL_O: length 4
  TOP w0.114: U6.45 143.09,83.02 142.75,82.68 R956.2 R806.2
I210_XTAL_O_R: length 6.5
  TOP w0.114: R806.1 142.82,78.79 C649.1 142.82,76.78 142.49,76.45 141.6,76.45 141.48,76.33 141.48,74.8 142.28,74 OSC6.3
ID_BTN_BMC_N: length 24.3
  TOP w0.114: R327.1 v2(11.06,28.39)
  S10 w0.102: v2(11.06,28.39) 14.22,25.22 v2(18.49,25.22)
  BOTTOM w0.114: v1(28.19,18.24) 25.88,18.24 23.39,20.73 23.39,24.26 22.97,24.68 CONN14.173 19.77,24.68 19.71,24.62 19.33,24.62 18.72,25.22 v2(18.49,25.22)
ID_LED STATUS SENSE: length 280.6
  TOP w0.114: U12.E9 v3(197.09,58.61)
  S3 w0.102: v2(17.14,63.63) 17.14,63 16.94,62.8 16.94,56 20.21,52.73 24.45,52.73 27.08,50.1 27.08,32.38 32,27.46 35.08,27.46 35.72,26.82 42.23,26.82 44.09,24.96 44.09,22.96 50.52,16.54 53.11,16.54 54.51,17.93 58.14,17.93 58.42,17.65 63.88,17.65 66.52,20.29 73.05,20.29 74.73,18.61 80.71,18.61 82.68,20.57 86.75,20.57 87.87,21.69 88.25,21.69 88.95,20.98 89.87,20.98 90.38,21.49 94.3,21.49 98.39,25.58 123.13,25.58 123.39,25.85 123.39,26.34 v2(122.94,26.8)
  S5 w0.102: v2(186.69,36.53) 184.99,38.23 184.99,40.6 184.61,40.98 184.61,51.71 187.76,54.86 194.88,54.86 196.22,56.2 196.22,57.74 v3(197.09,58.61)
  BOTTOM w0.114: v2(17.14,63.63) 17.53,64.01 17.53,65.28 18.93,66.68 CONN14.41 23.16,66.68 24.22,65.62 24.35,65.62 24.82,65.15 26.88,65.15 26.92,65.19 27.19,65.19 27.71,65.71 27.71,69.86 28.8,70.95 28.8,75.64 29.97,76.81 R947.2 ; v2(186.69,36.53) 185.17,35 v1(185.17,33.15) 185.17,32.36 181,28.19 176.17,28.19 173.76,25.78 169.9,25.78 168.89,26.8 136.67,26.8 134.77,24.89 129.96,24.89 127.68,27.18 123.32,27.18 v2(122.94,26.8)
ID_LED_BMC_N: length 35.7
  TOP w0.114: R338.2 v2(11.06,22.04)
  BOTTOM w0.114: v1(29.34,9.07) 23.94,9.07 23.13,8.26 21.17,8.26 16.77,12.66 10.06,12.66 9.53,13.2 9.51,13.2 9.26,13.45 9.26,19.67 11.06,21.47 v2(11.06,22.04) 12.2,23.18 CONN14.178
INT0: length 3.6
  BOTTOM w0.114: U45.1 38.62,120.03 v1(38.18,120.47) 38.18,121.11 37.8,121.49 R1111.1
INT1: length 13.5
  BOTTOM w0.114: R1112.1 35.69,122.38 43.15,122.38 43.93,121.6 v1(43.93,120.92) 43.14,120.92 42.52,120.29 U45.7
INT-IN: length 3.5
  BOTTOM w0.114: U45.15 39.27,111.86 R1113.1
IP_UART0_SIN: length 314.8
  TOP w0.114: R12.1 v2(89.69,115.26)
  S8 w0.102: v2(89.69,115.26) 90.25,114.71 90.25,108.6 89.93,108.28 88.61,108.28 88.54,108.36 85.92,108.36 84.33,109.94 84.33,113.24 81.77,115.8 78.07,115.8 77.91,115.65 77.53,115.65 76.92,116.26 73.95,116.26 73.32,115.62 72.94,115.62 72.45,116.1 62.04,116.1 61.19,115.26 61.12,115.19 60.36,114.43 51.58,114.43 47.57,110.41 37.64,110.41 32.64,105.41 32.64,103.07 32.03,102.46 31.66,102.46 30.1,100.91 30.1,83.96 29.97,83.83 29.97,79.91 30.25,79.63 30.25,76.96 29.99,76.69 29.85,76.55 29.85,58.08 28.23,56.47 27.83,56.47 26.47,55.11 26.47,20.02 30.59,15.9 40.16,15.9 41.25,14.81 43.45,14.81 45.35,12.9 45.35,12.48 49.45,8.38 51.5,8.38 52.04,7.84 52.04,5.81 53.36,4.5 55.84,4.5 56.29,4.05 59.72,4.05 59.99,4.32 65.79,4.32 66.6,3.51 67.61,3.51 68.04,3.94 70.6,3.94 70.7,3.84 76.1,3.84 76.4,3.53 78.27,3.53 78.32,3.58 81.35,3.58 84.28,6.51 84.28,9.28 84.54,9.55 84.66,9.55 85.52,10.41 86.86,10.41 87.46,11.02 89,11.02 92.97,11.02 93.32,11.37 94.56,11.37 95.59,10.34 109.97,10.34 115.39,4.92 122.44,4.92 123.8,3.55 124.03,3.55 125.01,2.57 127.44,2.57 127.8,2.21 144.68,2.21 146.13,3.66 146.13,3.99 147.07,4.93 v3(147.42,4.93)
  BOTTOM w0.114: v2(89.69,115.26) v1(89.69,116.99)
  BOTTOM w0.127: CONN16.62 143.6,3.31 143.21,3.71 143.21,4.04 142.95,4.29 142.95,5.26 143.59,5.89 147.07,5.89 147.42,5.54 v3(147.42,4.93)
IP_UART0_SIN_R: length 33.7
  TOP w0.114: R12.2 v2(92.18,115.26) ; U9.AY11 95.28,87.19 v4(95.59,87.5)
  S10 w0.102: v2(92.18,115.26) 94.31,113.13 94.31,108 93.57,107.26 93.57,106.4 97.41,102.56 97.41,95.54 96.62,94.75 96.62,89.94 96.37,89.69 96.37,88.93 95.59,88.15 v4(95.59,87.5)
  BOTTOM w0.114: v1(93.17,115.07) 92.98,115.26 v2(92.18,115.26)
IP_UART0_SOUT: length 257.1
  TOP w0.114: R26.1 89.74,113.28 89.1,113.92 89.1,116.31 87.67,117.74 87.67,118.58 89.09,120 105.91,120 106.62,119.29 107.94,119.29 108.04,119.18 113.23,119.18 113.85,118.56 120.57,118.56 122.02,120.02 v2(122.68,120.02)
  S5 w0.102: v2(137.79,11.35) 137.82,11.35 138.13,11.66 141.94,11.66 144.98,8.61 156.77,8.61 163.46,15.3 v2(167.95,15.3)
  S10 w0.102: v2(167.95,15.3) 169.99,15.3 170.87,14.43 182.47,14.43 185.67,17.63 185.67,34.85 184.86,35.67 184.86,75.63 176.81,83.68 176.81,86.52 170.41,92.92 170.41,111.94 169.37,112.98 169.37,113.85 166.35,116.87 163.78,116.87 161.55,119.1 157.43,119.1 157,118.67 149.54,118.67 148.17,120.04 144.15,120.04 143.31,120.88 123.55,120.88 v2(122.68,120.02)
  BOTTOM w0.114: v2(122.68,120.02) 122.3,119.63 v1(122.3,119) ; v2(137.79,11.35) 137.11,11.35 135.64,9.88 135.64,8.53 135.6,8.5 CONN16.93
IP_UART0_SOUT_R: length 33
  TOP w0.114: v4(94.34,86) 94.34,86.01 94.3,86.04 U9.BB12 ; R26.2 v2(92.2,113.28)
  S10 w0.102: v4(94.34,86) 94.34,86.59 94.27,86.66 94.27,87.66 95.35,88.75 95.35,94.4 96.53,95.58 96.55,95.58 96.95,95.98 96.95,102.35 93.12,106.18 93.12,112.37 v2(92.2,113.28)
  BOTTOM w0.114: v2(92.2,113.28) 92.42,113.28 v1(93.17,112.53)
IR3570_RRES: length 4.2
  TOP w0.114: v2(57.68,9.93) 57.84,9.78 U29.6
  BOTTOM w0.114: v2(57.68,9.93) 58.01,9.6 R743.1 58.39,8.26 v1(59,8.86)
IR3570_V18A: length 6
  TOP w0.114: U29.8 57.04,9.31 56.41,9.93 v2(56.18,9.93) C233.1 56.18,11.18 56.14,11.18 C218.1
  BOTTOM w0.114: C233.1 v2(56.18,9.93) 56.82,9.3 v1(56.92,9.3)
IRQ_PCH_WHEA_N: length 39.6
  TOP w0.114: R84.1 78.77,105.49 v2(78.77,104.85) ; U9.BB28 94.32,79.57 v4(94.35,79.57)
  S3 w0.102: v2(78.77,104.85) 78.97,105.05 80.52,105.05 81.06,104.51 81.06,101.83 83.4,99.49 86.07,99.49 89.04,96.52 90.55,96.52 93.14,93.93 93.14,92.15 94.46,90.83 94.46,89.03 94.61,88.88 94.61,88.17 94.22,87.77 94.22,87.05 94.7,86.57 95.38,86.57 95.55,86.4 95.55,81.43 94.74,80.62 94.74,79.96 v4(94.35,79.57)
  BOTTOM w0.114: v2(78.77,104.85) 79.35,105.44 v1(79.35,105.64)
JTAG_TCK: length 60.3
  TOP w0.114: U12.P3 v3(190.09,48.61)
  S3 w0.102: v2(195.66,18.19) 195.18,17.71 195.18,15.04 194.82,14.68 192.58,14.68 191.63,15.63 191.63,20.61 193.32,22.3 193.32,32.44 191.03,34.72 191.03,40.55 191.04,40.55 191.04,47.66 v3(190.09,48.61)
  BOTTOM w0.114: R664.1 v2(195.66,18.19) 195.66,17.83 195.33,17.5 193.74,17.5 192.91,16.68 192.91,11.94 194.31,10.54 194.31,8.3 194.31,8.29 194.31,7.91 R702.2
JTAG_TCK_R: length 4.8
  TOP w0.114: v2(192.81,4.17) 193.36,4.71 CONN9.1
  BOTTOM w0.114: R703.1 R702.1 193.22,3.76 v2(192.81,4.17)
JTAG_TDI: length 89
  TOP w0.114: U12.L6 v3(193.09,51.61) ; v2(204.17,2.49) 204.93,3.26 CONN9.9
  S5 w0.102: v3(193.09,51.61) 192.61,51.13 191.87,51.13 191.62,50.88 191.62,48.39 191.29,48.06 v2(186.61,48.06)
  S8 w0.102: v3(193.09,51.61) 193.09,51.61 192.71,51.99 192.71,55.77 193.15,56.21 202.39,56.21 203.28,55.32 203.28,52.07 204.22,51.13 204.22,50.34 204.57,49.98 205.37,49.98 207.34,48.01 207.34,27.53 204.98,25.17 204.98,20.73 202.95,18.69 202.95,3.71 v2(204.17,2.49)
  BOTTOM w0.114: v1(184.71,48.06) v2(186.61,48.06) 186.66,48.1 R843.1 ; R707.2 204.17,3.28 v2(204.17,2.49)
JTAG_TDO: length 100.8
  TOP w0.114: U12.M5 v3(192.09,50.61)
  S8 w0.102: v2(197.33,6.78) 199.62,9.07 199.62,10.59 202.72,13.69 202.72,18.79 203.56,19.63 203.56,24.13 207.09,27.66 207.09,47.75 205.09,49.75 204.48,49.75 203.99,50.24 203.99,50.85 203,51.84 203,54.46 202.34,55.12 194.06,55.12 193.68,54.74 193.68,51.41 193.4,51.13 192.56,51.13 192.09,50.66 v3(192.09,50.61)
  BOTTOM w0.114: v2(197.33,6.78) 197.35,6.78 197.59,6.54 R704.2 196.52,4.67 195.93,4.08 195.93,3.24 195.45,2.77 192.81,2.77 191.95,3.63 191.95,16.32 v2(193.71,18.08) R695.1 ; v1(186.87,50.98) 188.21,50.98 188.34,51.1 191.59,51.1 v3(192.09,50.61)
JTAG_TDO_R: length 4.1
  TOP w0.114: CONN9.3 v2(197.31,2.77)
  BOTTOM w0.114: v2(197.31,2.77) 197.59,3.04 R704.1 197.48,3.87 v1(196.55,3.87)
JTAG_TMS: length 50.2
  TOP w0.114: U12.N4 v3(191.09,49.61)
  S3 w0.102: v2(193.64,15.98) 193.17,16.46 193.17,21.56 193.65,22.05 193.65,32.56 191.67,34.54 191.67,38.14 192.13,38.6 192.13,43.38 191.69,43.82 191.69,49 v3(191.09,49.61)
  BOTTOM w0.114: v2(193.64,15.98) 193.65,15.97 R696.1 193.7,14.91 194.18,14.91 195.07,14.02 195.07,11.51 199.42,7.16 R706.2
JTAG_TMS_R: length 5.3
  TOP w0.114: CONN9.5 v2(199.85,2.72)
  BOTTOM w0.114: R705.2 R706.1 ; R706.1 199.42,3.03 199.73,2.72 v2(199.85,2.72) ; R706.1 200.19,3.69 v1(200.48,3.98)
KR_EPHY_DFTANA_0: length 21.3
  TOP w0.114: R271.1 v2(111.15,43.69) ; v4(109.48,60) 109.48,59.98 109.75,59.72 U9.H71
  S10 w0.102: v2(111.15,43.69) 111.66,44.2 111.66,46.53 110.9,47.29 110.9,55.62 109.27,57.24 109.27,58.7 109.48,58.91 v4(109.48,60)
  BOTTOM w0.114: R630.2 112.04,44.58 v2(111.15,43.69) 111.05,43.79 v1(111.05,44.63)
KR_EPHY_DFTANA_1: length 13.1
  TOP w0.114: U9.K71 v4(109,59.16) ; R222.2 v2(116.71,57.58)
  S8 w0.102: v4(109,59.16) 109.37,59.16 109.8,58.72 110.49,58.72 111.86,57.35 112.24,57.35 112.47,57.58 v2(116.71,57.58)
  BOTTOM w0.114: R590.1 v2(116.71,57.58) 116.46,57.58 v1(115.49,58.55)
KR_EPHY_DFTDIG_0: length 3.8
  TOP w0.114: U9.J69 109.98,60.09 110.14,60.09 110.29,59.94 v4(110.54,59.94)
  BOTTOM w0.114: v4(110.54,59.94) 111.15,60.56 R582.2 111.64,60.56 v1(112.45,61.37)
LAN_NCSI_CRS_DV: length 3.4
  TOP w0.114: U9.V74 105.02,58.05 v4(104.78,58.28)
  BOTTOM w0.114: v4(104.78,58.28) 105.05,58.55 R785.1 105.51,58.29 106.28,57.52 v1(106.86,57.52)
LAN_NCSI_TRI_EN: length 8.8
  TOP w0.114: R793.1 102.17,50.73 102.5,51.05 102.5,52.44 v2(102.23,52.7) 102.5,52.97 102.5,54.14 102.32,54.31 102.32,55.62 102.31,55.64 U9.AD78
  BOTTOM w0.114: v2(102.23,52.7) 103.25,51.69 R787.2 104.24,51.64 104.42,51.46 v1(104.42,51.08)
LAN_PWR_GD: length 5.6
  TOP w0.114: R239.1 100.72,51.98 100.72,53.61 101.88,54.76 101.88,55.43 101.73,55.58 101.73,56.48 U9.AE77
LAN_SDP0_0: length 15.1
  TOP w0.114: v4(110.59,57.61) 110.23,57.97 U9.G74
  S10 w0.102: v4(110.59,57.61) 111.58,57.61 112.01,57.18 112.01,55.78 111.33,55.09 111.33,53.36 111.35,53.33 111.35,48.18 v2(112.14,47.4)
  BOTTOM w0.114: R617.1 112.42,47.12 v2(112.14,47.4) 111.22,48.31 v1(111.22,48.57)
LAN_SDP0_1: length 2.8
  TOP w0.114: U9.C76 112.04,57.27 v4(112.04,57.76)
  BOTTOM w0.114: v4(112.04,57.76) 112.78,57.02 R598.1 113.95,57.02 v1(114.02,56.95)
LAN_SDP1_0: length 16.9
  TOP w0.114: v4(109.75,58.19) 109.75,58.06 110.13,57.68 110.13,57.43 U9.F76 ; R272.1 v2(112.12,46.25)
  S10 w0.102: v4(109.75,58.19) 109.75,57.61 110.19,57.18 110.79,57.18 111.12,56.85 111.12,47.52 112.12,46.53 v2(112.12,46.25)
  BOTTOM w0.114: v2(112.12,46.25) 111.2,47.17 v1(111.17,47.17)
LAN_SDP1_1: length 4.2
  TOP w0.114: v4(108.01,60.87) 107.8,60.87 U9.N69
  BOTTOM w0.114: R584.1 106.38,60.75 106.68,60.45 107.59,60.45 v4(108.01,60.87) 108.88,60.87 v1(108.99,60.75)
LGSPARE4_DDR_STRAP: length 27.7
  TOP w0.108: v4(100.05,60.88) 100.03,60.86 100.03,60.83 99.77,60.58 U9.AK69
  TOP w0.114: v2(99.98,46.08) 99.57,45.67 R262.2 99.88,45.41 100.08,45.21 100.08,43.81 99.44,43.18 99.44,39.42 99.41,39.38 99.41,38.01 99.95,37.47 R524.2
  S10 w0.102: v2(99.98,46.08) 99.52,46.54 99.52,52.37 98.5,53.39 98.5,56.01 100.43,57.94 100.43,58.88 100.48,58.93 100.48,59.46 100.05,59.89 v4(100.05,60.88)
  BOTTOM w0.114: v1(99.52,45.42) 99.98,45.88 v2(99.98,46.08)
LM75_A0_CH3: length 4.6
  TOP w0.114: 144.25,111.63 145.29,111.63 v2(145.67,111.25) R314.2 R313.1
  BOTTOM w0.114: v2(145.67,111.25) 145.67,110.31 v1(145.69,110.29)
LM75_A1_CH3: length 5.4
  TOP w0.114: R312.1 146.23,110.36 U20.6 143.74,110.36 v2(142.98,111.12)
  BOTTOM w0.114: v2(142.98,111.12) 142.93,111.12 v1(142.19,110.39)
LM75_A2_CH3: length 3.7
  TOP w0.114: R311.1 v2(145.95,108.71) 145.57,109.09 U20.5
  BOTTOM w0.114: v2(145.95,108.71) 145.36,108.13 v1(145.16,108.13)
LM75BD2_INT: length 144.5
  TOP w0.114: v2(147.93,119.58) 147.93,117.86 144.64,114.57 136.55,114.57 135.03,113.04 135.03,110.95 135.61,110.36 R299.2 R298.2 ; U12.L13 v3(201.09,51.61)
  S3 w0.102: v3(201.09,51.61) 201.57,52.1 201.57,56.77 201.93,57.12 203.33,57.12 205.59,59.39 205.59,68.25 204.77,69.06 204.77,81.44 202.06,84.16 202.06,91.69 202.44,92.08 202.44,99.31 200.79,100.97 200.79,102.49 200.53,102.74 198.5,102.74 196.68,104.56 191.34,104.56 186.78,109.12 186.78,114.24 183.74,117.28 176.35,117.28 171.64,122 159.94,122 159.77,122.17 150.52,122.17 v2(147.93,119.58)
  BOTTOM w0.114: v2(147.93,119.58) 148.69,118.82 v1(148.69,118.41)
LM75BD2_INT_R: length 3.4
  TOP w0.114: R299.1 137.23,110.41 v2(137.87,111.05) 138.56,110.36 U20.3
  BOTTOM w0.114: v1(138.2,111.99) 137.87,111.66 v2(137.87,111.05)
LM75BD2_SCLK_C: length 3
  TOP w0.114: R297.1 136.05,111.91 135.94,111.91 v2(135.53,112.32) 135.74,112.52 136.07,112.52 C130.1
  BOTTOM w0.114: v2(135.53,112.32) 136.35,112.32 v1(136.47,112.19)
LPC_DEBUG_RST: length 302.6
  TOP w0.114: U12.T6 193.59,46.5 v2(193.45,46.35)
  S3 w0.102: v2(15.08,78.38) 11.85,78.38 3.84,70.37 3.84,24.15 5.08,22.9 5.08,18.92 11.32,12.68 25.07,12.68 25.76,13.36 32.11,13.36 32.92,12.55 41.55,12.55 44.55,9.55 53.96,9.55 54.29,9.22 54.88,9.22 55.39,8.71 59.62,8.71 61.57,6.76 62.33,6.76 63.22,5.87 66.29,5.87 66.67,6.25 69.1,6.25 69.82,6.97 69.82,7.19 71.83,9.19 72.22,9.19 73.66,10.64 78.94,10.64 79.58,11.28 86.34,11.28 87.91,12.85 94.08,12.85 96.29,15.06 v2(97.38,15.06)
  S8 w0.102: v2(97.38,15.06) 98.35,15.06 100.42,17.14 100.56,17.27 104.81,17.27 105.12,17.58 111.4,17.58 115.08,21.26 147.72,21.26 150.46,24 168.93,24 170.58,25.65 176.49,25.65 178.24,27.41 182.02,27.41 186.64,32.02 186.64,33.32 186.23,33.73 186.23,39.74 186.7,40.21 187.92,40.21 189.15,41.44 189.15,42.67 191.72,45.23 192.97,45.23 193.24,45.49 193.24,46.15 v2(193.45,46.35)
  BOTTOM w0.114: CONN14.2 v2(15.08,78.38) 15.08,81.05 18.47,84.44 23.28,84.44 24.36,85.52 24.51,85.52 24.78,85.8 26.29,85.8 v1(26.57,85.52)
LPC_LFRAME_N: length 399.5
  TOP w0.114: v2(119.74,97.97) 119.74,98.8 116.68,101.85 114.25,101.85 113.61,102.49 111.96,102.49 107.32,107.13 102.42,107.13 101.73,106.43 101.73,99.09 101.15,98.51 100.34,98.51 v2(99.54,97.71) R136.1 ; v2(181.86,62.38) 185.5,62.38 188.21,59.67 189.15,59.67 U12.C2
  TOP w0.127: U17.22 176.81,19.89 v2(176.31,20.38)
  S3 w0.102: v2(204.04,12.37) 204.04,10.53 201.15,7.65 193.14,7.65 192.43,8.36 183.66,8.36 175.67,16.35 175.67,19.74 v2(176.31,20.38)
  S5 w0.102: v2(11.89,75.38) 11.21,74.69 11.21,72.7 12.21,71.69 15.63,71.69 16.03,72.1 16.03,75.38 11.61,79.81 11.61,114.37 16.94,119.71 23.94,119.71 24.56,120.34 29.95,120.34 29.98,120.37 34.63,120.37 35.19,120.93 97.85,120.93 102.62,116.17 102.62,109.74 103.33,109.03 103.33,108.57 100.79,106.03 100.79,105.65 100.81,105.63 100.81,104.44 100.74,104.36 100.74,101.3 99.54,100.1 v2(99.54,97.71)
  S10 w0.102: v2(176.31,20.38) 177.44,21.52 177.44,23.42 182.42,28.4 182.42,39.5 181.51,40.41 181.51,62.03 v2(181.86,62.38) 181.91,62.43 181.91,74.68 166.63,89.97 159.98,89.97 150.41,99.54 146.08,99.54 144.91,100.71 144.91,101.73 141.78,104.85 141.78,106.13 139.38,108.53 135.33,108.53 133.32,106.53 122.96,106.53 119.74,103.3 v2(119.74,97.97)
  BOTTOM w0.114: v1(201.24,13.13) 201.48,13.37 CONN15.2 203.54,13.37 204.04,12.88 v2(204.04,12.37) ; CONN14.12 v2(11.89,75.38)
LPC_LFRAME_N_R: length 6
  TOP w0.114: U9.AH1 100.33,94.12 100.44,94.23 100.44,94.52 100.42,94.54 100.42,94.7 v2(100.03,95.1) 100.03,95.22 99.54,95.71 R136.2
  BOTTOM w0.114: v1(100.69,93.91) 100.69,94.44 v2(100.03,95.1)
LPC_PD: length 84.3
  TOP w0.114: R346.2 10.08,18.41 3.78,18.41 v2(3.02,19.18)
  S10 w0.102: v2(11.89,77.78) 3.02,68.91 v2(3.02,19.18)
  BOTTOM w0.114: v1(10.41,88.29) 11.33,87.38 11.33,78.34 v2(11.89,77.78) CONN14.4
LPC_PME_N: length 17.2
  BOTTOM w0.114: CONN14.6 15.08,77.18 15.65,77.74 15.65,81.14 18.71,84.2 R540.2 24.51,84.73 v1(25.02,85.23)
MAC_INT_L: length 347.1
  TOP w0.114: R35.1 v2(68.36,111.65) ; v2(198.12,47.58) 197.59,48.11 U12.R10
  S5 w0.102: v2(137.67,5.48) 138.62,6.43 157.63,6.43 161.79,10.59 169.41,10.59 173.38,14.55 176.64,14.55 177.96,15.87 177.96,22.93 180.04,25.01 180.04,25.28 180.44,25.68 180.7,25.68 192.22,37.2 193.35,37.2 195.33,39.18 195.33,43.22 194.49,44.06 194.49,45.37 195.62,46.51 197.05,46.51 v2(198.12,47.58)
  S8 w0.102: v2(68.36,111.65) 66.2,111.65 65.66,112.19 64.19,112.19 63.98,111.99 60.29,111.99 58.04,109.74 58.04,109.61 54.22,105.79 43.54,105.79 41.33,103.58 38.89,103.58 36.87,101.56 34,101.56 32.97,100.53 32.97,80.33 31.17,78.53 31.17,76.58 31.11,76.53 30.76,76.17 30.76,57.51 29.26,56.01 29.26,55.54 27.39,53.67 27.39,20.4 30.97,16.81 40.97,16.81 41.99,15.8 45.92,15.8 48.29,13.43 48.29,10.84 49.83,9.3 52.98,9.3 54.22,8.05 59.35,8.05 61.06,6.34 62.25,6.34 62.78,5.81 67.48,5.81 67.73,5.56 70.27,5.56 71.08,4.75 71.48,4.75 72.31,5.58 75.64,5.58 76.78,4.45 77.67,4.45 77.72,4.5 80.56,4.5 80.82,4.76 80.82,5.87 80.97,6.02 80.97,8.88 82.84,10.74 84.56,10.74 85.14,11.33 86.48,11.33 87.09,11.93 89.38,11.93 89.38,11.93 92.59,11.93 92.94,12.28 94.94,12.28 95.93,11.29 110.45,11.29 114.32,7.42 116.03,7.42 117.61,5.83 122.81,5.83 122.96,5.69 129.68,5.69 130.29,6.3 136.86,6.3 v2(137.67,5.48)
  BOTTOM w0.114: v2(198.12,47.58) 198.12,47.31 R910.2 ; v2(137.67,5.48) 137.85,5.66 140.23,5.66 140.6,6.03 CONN16.73 ; v1(67.06,110.46) 67.08,110.46 68.27,111.65 v2(68.36,111.65)
MAC_INT_L_R: length 45.8
  TOP w0.114: U9.BD18 93.15,83.51 v4(93.42,83.25) ; R35.2 v2(70.77,111.65)
  S3 w0.102: v2(70.77,111.65) 70.82,111.65 72.75,109.73 72.75,108.97 72.03,108.25 72.03,106.42 77.03,101.42 80.5,101.42 83.12,98.8 85.73,98.8 89.53,95 90.81,95 92.1,93.7 92.1,88.41 91.77,88.09 91.77,87.51 92.19,87.09 92.19,86.74 92.68,86.25 92.68,84.15 93.42,83.42 v4(93.42,83.25)
  BOTTOM w0.114: v1(69.32,111.71) 70.71,111.71 v2(70.77,111.65)
MAC_MDC0: length 161.9
  TOP w0.114: v2(150.95,88.67) 150.42,88.14 R846.2
  S3 w0.102: v2(165.61,88.42) 154.15,88.42 153.92,88.65 150.98,88.65 v2(150.95,88.67)
  S5 w0.102: v2(165.61,88.42) 165.84,88.65 165.84,93.69 166.31,94.16 171.45,94.16 172.47,93.14 175.54,93.14 180.19,88.5 180.19,85.24 181.08,84.36 181.08,79.81 182.78,78.1 182.78,67.89 183.26,67.41 183.26,64.82 181.38,62.94 181.38,41.83 183.9,39.32 183.9,31.92 179.66,27.69 179.61,27.69 178.03,26.11 178.03,26.05 175.73,23.75 174.88,23.75 173.94,22.81 172.92,22.81 171.88,21.77 171.88,20.48 169.94,18.54 150.6,18.54 148.62,16.56 140.51,16.56 133.65,9.7 v2(133.6,9.7)
  BOTTOM w0.114: v2(150.95,88.67) 151.31,88.67 v1(151.76,89.13) ; CONN16.101 v2(133.6,9.7)
MAC_MDC0_R: length 5.9
  TOP w0.114: R828.1 R846.1 148.16,88.14 147.68,88.62 v2(147.35,88.62) 147.22,88.62 146.86,88.27 146.05,88.27 145.81,88.02 U6.55
  BOTTOM w0.114: v1(148.26,88.06) 147.7,88.62 v2(147.35,88.62)
MAC_MDIO0: length 160.6
  TOP w0.114: v2(154.36,90.14) 153.85,89.64 151.39,89.64 150.85,90.17 R847.2
  S3 w0.102: v2(165.2,93.52) 164.92,93.8 158.01,93.8 v2(154.36,90.14)
  S5 w0.102: v2(134.6,9.7) 134.65,9.7 139.93,14.99 142.77,14.99 143.41,14.35 147.33,14.35 151.11,18.14 170.11,18.14 171.91,19.94 172.21,19.94 173.2,20.93 174.04,20.93 176.28,23.17 176.28,23.64 178.44,25.8 178.44,25.94 179.77,27.28 179.92,27.28 184.3,31.67 184.3,39.67 181.99,41.99 181.99,56.77 183.67,58.45 183.67,67.57 183.51,67.73 183.51,77.6 184.89,78.97 184.89,81.12 180.59,85.41 180.59,88.67 174.93,94.33 172.11,94.33 171.65,94.79 165.74,94.79 165.2,94.26 v2(165.2,93.52)
  BOTTOM w0.114: v1(154.99,89.38) 154.99,89.51 v2(154.36,90.14) ; CONN16.97 v2(134.6,9.7)
MAC_MDIO0_R: length 8.6
  TOP w0.114: R829.1 151.31,90.68 v2(151,90.68) 148.82,90.68 148.64,90.5 R847.1 147.62,90.17 146.77,89.32 145.96,89.32 145.66,89.02 U6.57
  BOTTOM w0.114: v1(150.16,90.2) 150.65,90.68 v2(151,90.68)
MAC_SGMII_RX_N: length 99.7
  TOP w0.102: v3(149.6,83.21) 150.1,83.71 150.1,84.01 149.86,84.25 148.71,84.25 C665.1
  S10 w0.107: v3(149.6,83.21) 150.06,82.75 150.06,82.3 148.06,80.3 142.46,80.3 136.63,74.46 136.63,32.01 142.58,26.07 142.58,25.83 142.88,25.52 143.13,25.52 143.35,25.29 143.35,25.05 143.66,24.74 143.9,24.74 144.68,23.96 144.68,23.64 144.45,23.42 144.45,23.1 144.68,22.87 144.68,19.74 v3(144.27,19.33)
  BOTTOM w0.102: v3(144.27,19.33) 144.76,18.83 144.76,18.27 142.65,16.15 140.52,16.15 136.75,12.39 134.77,12.39 132.21,9.83 132.21,8.87 132.1,8.76 CONN16.107
MAC_SGMII_RX_N_R: length 2.9
  TOP w0.102: C665.2 146.95,84.24 146.63,84.24 146.33,84.54 146.33,84.95 146.15,85.13 146.01,85.13 145.9,85.02 U6.49
MAC_SGMII_RX_P: length 99.8
  TOP w0.102: C664.1 148.71,84.53 149.97,84.53 150.38,84.12 150.38,83.7 v3(150.87,83.21)
  S10 w0.107: v3(150.87,83.21) 150.4,82.74 150.4,82.16 148.2,79.96 142.6,79.96 136.97,74.33 136.97,32.15 145.01,24.1 145.01,19.86 v3(145.54,19.33)
  BOTTOM w0.102: CONN16.105 132.6,8.76 132.49,8.87 132.49,9.72 134.89,12.11 136.87,12.11 140.63,15.87 142.76,15.87 145.04,18.15 145.04,18.83 v3(145.54,19.33)
MAC_SGMII_RX_P_R: length 2.9
  TOP w0.102: U6.50 145.9,85.52 146.01,85.41 146.27,85.41 146.61,85.07 146.61,84.66 146.75,84.52 146.93,84.52 C664.2
MAC_SGMII_TX_N: length 104.2
  TOP w0.102: v3(146.27,86.2) 145.94,86.52 U6.52
  S10 w0.107: v3(146.27,86.2) 146.64,86.57 146.79,86.57 146.88,86.57 146.89,86.56 147.03,86.56 147.41,86.57 147.75,86.57 148.59,85.72 148.59,84.25 146.11,81.77 141.6,81.77 137.11,77.28 137.11,76.58 135.79,75.26 135.79,30.2 140.07,25.91 140.07,19.44 141.43,18.09 141.99,18.09 142.43,18.53 142.43,18.99 v3(142.9,19.46)
  BOTTOM w0.102: CONN16.111 131.1,8.79 130.99,8.9 130.99,12.01 136.3,17.32 141.53,17.32 142.43,18.22 142.43,18.99 v3(142.9,19.46)
MAC_SGMII_TX_P: length 104.2
  TOP w0.102: v3(146.28,87.28) 146.02,87.02 U6.53
  S10 w0.107: v3(146.28,87.28) 146.65,86.9 146.8,86.9 146.8,86.9 147.02,86.9 147.03,86.9 147.41,86.9 147.89,86.9 148.93,85.86 148.93,84.11 146.25,81.43 141.74,81.43 137.45,77.14 137.45,76.44 136.13,75.12 136.13,30.34 140.41,26.05 140.41,25.73 140.64,25.51 140.64,25.19 140.41,24.96 140.41,24.64 140.64,24.41 140.64,24.09 140.41,23.86 140.41,23.54 140.64,23.31 140.64,22.99 140.41,22.76 140.41,19.58 141.57,18.43 141.85,18.43 142.09,18.67 142.09,18.99 v3(141.63,19.46)
  BOTTOM w0.102: v3(141.63,19.46) 142.15,18.93 142.15,18.34 141.41,17.6 136.19,17.6 130.71,12.12 130.71,8.9 130.6,8.79 CONN16.113
MAC_WAKE_N: length 50.1
  TOP w0.114: U38.4 166.45,107.65 v2(165.99,107.19) 165.17,108 R801.1 164.64,108 164.21,108.43 164.21,110.34 163.88,110.67 152.73,110.67 149.43,107.37 140.32,107.37 140.21,107.25 140.21,103.3 137.26,100.36 136.42,100.36 134.26,98.2 134.26,95.17 136.17,93.27 U6.16
MANF_MODE_STRAP: length 51.3
  TOP w0.114: R22.2 v2(70.79,113.52) ; U9.BD22 93.34,81.85 v4(93.34,81.51)
  S3 w0.102: v2(70.79,113.52) 70.96,113.52 72.06,112.42 73.51,112.42 75.54,110.39 75.54,107.04 77.22,105.36 77.22,104.01 77.77,103.45 77.77,103 78.89,101.88 80.69,101.88 83.31,99.26 85.98,99.26 89.76,95.48 91.08,95.48 92.84,93.73 92.84,91.87 93.5,91.21 93.5,88.8 93.6,88.7 93.6,88.23 94.02,87.81 94.02,86.97 94.74,86.24 94.74,85.65 94.95,85.45 94.95,85.09 94.74,84.89 94.74,81.03 94.51,80.8 94.05,80.8 v4(93.34,81.51)
  BOTTOM w0.114: v2(70.79,113.52) 69.96,114.35 v1(69.9,114.35)
MANU_RST: length 90.8
  TOP w0.114: R845.1 v2(204.11,41.38) ; R713.1 v2(185.62,11.38)
  S10 w0.102: v3(147.09,4.32) 147.09,3.91 148.23,2.77 161.9,2.77 162.53,2.14 166.75,2.14 167.88,3.26 167.88,3.45 168.62,4.19 169.15,4.19 169.65,4.69 169.65,5.44 173.89,9.68 183.92,9.68 v2(185.62,11.38) 189.96,11.38 192.56,13.97 192.56,18.41 193.14,19 193.14,32.33 196.57,35.76 197.76,35.76 203.38,41.38 v2(204.11,41.38)
  BOTTOM w0.127: v3(147.09,4.32) 146.46,4.32 146.1,3.96 CONN16.52
MANU_RST_R: length 8.8
  TOP w0.114: U12.P15 202.63,49.11 203.12,49.61 203.75,49.61 204.85,48.51 204.85,45.97 204.24,45.36 v2(204.11,45.36) 204.85,44.63 204.85,44.35 R845.2
MB_LM75BD_CLK: length 106.2
  S10 w0.102: v2(126,8.28) 125.95,8.23 125.95,6.34 127.93,4.36 127.93,2.83 129.16,1.6 158.44,1.6 159.38,2.54 161.8,2.54 163.02,1.33 180.04,1.33 181.51,2.79 196.69,2.79 197.12,3.23 197.61,3.23 202.06,7.67 v2(202.06,18.01)
  BOTTOM w0.114: v1(198.04,17.3) 198.45,16.89 200.94,16.89 v2(202.06,18.01) R686.2 R674.2 ; CONN16.119 129.1,8.52 128.67,8.94 126.49,8.94 126,8.45 v2(126,8.28)
MB_LM75BD_DATA: length 111
  S10 w0.102: v2(125.25,8.51) 125.25,7.96 125.26,7.95 125.27,7.95 125.72,7.5 125.72,6.25 127.7,4.27 127.7,2.74 129.06,1.37 158.7,1.37 159.61,2.29 161.74,2.29 162.92,1.1 180.27,1.1 181.36,2.18 197.51,2.18 198.2,2.87 198.2,3.33 205.18,10.31 205.18,16.54 v2(204.09,17.63)
  BOTTOM w0.114: R661.2 R668.2 v2(204.09,17.63) 202.59,16.13 v1(199.75,16.13) ; v2(125.25,8.51) 125.96,9.22 128.95,9.22 129.6,8.57 CONN16.117
MSATA_NC19: length 6.6
  TOP w0.114: CONN6.43 183.35,90.97 183.13,91.19 183.13,94.36 R902.2 v2(182.07,94.57)
MSATA_SMB_PCU_CLK_P3V3: length 3
  TOP w0.114: CONN6.30 188.55,79.42 v2(188.85,79.12)
  BOTTOM w0.114: R159.2 v2(188.85,79.12)
MSATA_SMB_PCU_DATA_P3V3: length 2.9
  TOP w0.114: v2(187.58,79.12) 187.75,79.29 CONN6.32
  BOTTOM w0.114: R158.2 v2(187.58,79.12)
NC_TEST_EAR_N: length 22.7
  TOP w0.114: U9.AH62 100.35,63.81 v4(100.58,63.58)
  BOTTOM w0.114: v4(100.58,63.58) 100.58,62.38 100.81,62.15 102.11,62.15 102.14,62.19 103.91,62.19 104.78,61.32 108.81,61.32 109.6,62.1 110.29,62.1 110.87,62.69 113.59,62.69 114.66,61.62 115.38,61.62 115.85,62.09 117.06,62.09 117.07,62.1 117.68,62.1 v1(118.13,61.65) 117.62,61.14 R583.2
Net_111: length 0.7
  TOP w0.114: 190.59,59.11 v3(190.09,59.61)
Net_112: length 0.7
  TOP w0.114: 191.59,58.11 v3(191.09,58.61)
Net_113: length 0.7
  TOP w0.114: 193.59,56.11 v3(193.09,56.61)
Net_118: length 0.7
  TOP w0.114: 197.59,59.11 v3(198.09,59.61)
Net_119: length 0.7
  TOP w0.114: 194.59,59.11 v3(194.09,59.61)
Net_120: length 0.7
  TOP w0.114: 197.59,58.11 v3(198.09,58.61)
Net_121: length 0.7
  TOP w0.114: 198.59,58.11 v3(199.09,58.61)
Net_126: length 0.7
  TOP w0.114: 198.59,56.11 v3(199.09,56.61)
Net_127: length 0.7
  TOP w0.114: 199.59,56.11 v3(200.09,56.61)
Net_128: length 0.7
  TOP w0.114: 200.59,56.11 v3(201.09,56.61)
Net_131: length 0.7
  TOP w0.114: 201.59,55.11 v3(202.09,54.61)
Net_132: length 0.7
  TOP w0.114: 200.59,53.11 v3(201.09,52.61)
Net_134: length 0.7
  TOP w0.114: 200.59,51.11 v3(201.09,50.61)
Net_142: length 0.7
  TOP w0.114: 199.59,55.11 v3(200.09,55.61)
Net_192: length 14.4
  BOTTOM w0.114: 21.65,23.48 22.65,23.48 23.11,23.03 23.11,20.38 25.91,17.58 30.42,17.58 v1(31.55,18.71)
Net_1784: length 0.6
  TOP w0.108: 102.56,58.86 102.25,59.17 v4(102.1,59.17)
Net_1852: length 0.6
  TOP w0.114: 86.21,82.04 86.36,81.96 v4(86.71,81.76)
Net_1853: length 0.6
  TOP w0.114: 89.19,82.04 89.48,81.87 v4(89.68,81.76)
Net_1854: length 0.6
  TOP w0.114: 86.71,84.62 v4(87.2,84.33)
Net_1874: length 0.6
  TOP w0.127: 91.17,80.33 v4(91.66,80.04)
Net_1875: length 0.6
  TOP w0.127: v4(90.67,80.04) 90.52,80.13 90.18,80.33
Net_1876: length 0.6
  TOP w0.127: v4(89.68,80.04) 89.48,80.15 89.19,80.33
Net_1877: length 0.6
  TOP w0.127: 88.2,80.33 v4(88.69,80.04)
Net_1878: length 0.6
  TOP w0.127: 91.66,79.47 v4(92.16,79.18)
Net_1879: length 0.6
  TOP w0.127: 90.67,79.47 v4(91.17,79.18)
Net_1880: length 0.6
  TOP w0.127: v4(90.18,79.18) 89.79,79.4 89.68,79.47
Net_1881: length 0.6
  TOP w0.127: 88.69,79.47 v4(89.19,79.18)
Net_1882: length 0.6
  TOP w0.127: 90.67,77.75 v4(91.17,77.46)
Net_1883: length 0.6
  TOP w0.127: 89.68,77.75 v4(90.18,77.46)
Net_1884: length 0.6
  TOP w0.127: 88.69,77.75 v4(89.19,77.46)
Net_1885: length 0.6
  TOP w0.127: 87.7,77.75 v4(88.2,77.46)
Net_1886: length 0.6
  TOP w0.127: 90.18,76.89 v4(90.67,76.61)
Net_1887: length 0.6
  TOP w0.127: v4(89.68,76.61) 89.48,76.72 89.19,76.89
Net_1888: length 0.6
  TOP w0.127: 88.2,76.89 v4(88.69,76.61)
Net_1889: length 0.6
  TOP w0.127: 87.2,76.89 v4(87.7,76.61)
Net_1901: length 0.6
  TOP w0.108: 104.54,60.58 104.33,60.58 v4(104.06,60.85)
Net_1903: length 0.6
  TOP w0.108: 105.53,60.58 105.28,60.58 v4(105.02,60.83)
Net_2059: length 0.6
  TOP w0.114: 82.25,64.87 v4(82.75,64.59)
Net_2062: length 0.6
  TOP w0.114: 80.27,82.04 v4(80.77,81.76)
Net_2063: length 0.6
  TOP w0.165: 88.2,61.44 v4(88.69,61.73)
Net_2065: length 0.6
  TOP w0.114: 80.27,61.44 80.48,61.44 v4(80.77,61.73)
Net_2066: length 0.6
  TOP w0.127: 83.24,61.44 v4(83.74,61.73)
Net_2067: length 0.6
  TOP w0.127: 83.24,82.04 v4(83.74,81.76)
Net_2068: length 0.6
  TOP w0.127: 83.74,86.34 v4(84.23,86.05)
Net_2069: length 0.6
  TOP w0.114: 83.24,88.91 v4(83.74,88.63)
Net_2071: length 0.6
  TOP w0.114: 81.26,82.04 v4(81.76,81.76)
Net_2072: length 0.6
  TOP w0.165: 88.69,62.3 v4(89.19,62.58)
Net_2073: length 0.6
  TOP w0.127: 88.2,59.72 v4(88.69,60.01)
Net_2074: length 0.6
  TOP w0.114: 81.26,61.44 81.47,61.44 v4(81.76,61.73)
Net_2075: length 0.6
  TOP w0.127: 84.23,61.44 v4(84.73,61.73)
Net_2076: length 0.6
  TOP w0.127: 84.23,82.04 v4(84.73,81.76)
Net_2077: length 0.6
  TOP w0.127: 83.24,85.48 v4(83.74,85.19)
Net_2078: length 0.6
  TOP w0.114: 83.74,88.05 v4(84.23,87.77)
Net_2079: length 0.6
  TOP w0.114: 83.24,68.31 v4(83.74,68.02)
Net_2080: length 0.6
  TOP w0.114: 83.74,67.45 v4(84.23,67.16)
Net_2081: length 0.6
  TOP w0.114: 81.76,77.75 v4(82.25,77.46)
Net_2082: length 0.6
  TOP w0.114: 80.77,77.75 v4(81.26,77.46)
NIC1_DEV_OFF_N_R: length 8
  TOP w0.114: U12.A6 193.59,65.18 v2(193.49,65.28) 193.49,66.81 193.18,67.12 193.18,67.51 192.76,67.93 192.66,67.93 TP51.1
  BOTTOM w0.114: v1(193.22,66.22) 193.49,65.95 v2(193.49,65.28)
NIC1_LAN_PWR_GOOD: length 9.4
  TOP w0.114: TP50.1 189.23,66.36 v2(189.61,65.98) ; U12.D5 v3(192.09,59.61)
  S3 w0.102: v2(189.61,65.98) 189.61,64.62 191.54,62.69 191.54,61.93 191.48,61.86 191.48,61.36 191.54,61.29 191.54,60.17 192.09,59.63 v3(192.09,59.61)
NIC1_NCSI_CLKIN: length 38.5
  TOP w0.114: U6.2 144.09,94.82 145.24,95.96 145.82,95.96 R1012.2 146.21,96.8 146.1,96.8 145.9,97 v2(145.9,98.81) 145.9,98.96 R1011.2 ; v2(158.8,112.27) 159.82,113.28 161.52,113.28 163.07,114.83 R853.2
  BOTTOM w0.114: v2(145.9,98.81) 145.92,98.83 145.92,103.38 154.81,112.27 v2(158.8,112.27) 159,112.47 R120.1 C275.1
NIC1_NCSI_CLKIN_R: length 2.7
  TOP w0.114: U5.2 v2(158.8,115.82)
  BOTTOM w0.114: v2(158.8,115.82) 159,115.62 R120.2
NIC1_NCSI_CRS_DV: length 215.6
  TOP w0.114: R860.1 v2(145.41,101.09)
  BOTTOM w0.114: CONN14.54 11.97,62.78 10.27,64.48 10.27,83.99 5.64,88.62 5.64,95.46 13.48,103.3 14.93,103.3 18.59,106.96 31.26,106.96 33.3,109 33.3,112.04 v1(34.54,113.28) 35.48,113.28 36.48,114.28 36.48,114.79 37.74,116.05 42.3,116.05 43.5,117.26 49.2,117.26 49.62,116.83 54.22,116.83 55.32,117.93 55.32,119.89 57.32,121.89 140.22,121.89 146.07,116.04 147.91,116.04 151.36,112.6 151.36,109.19 145.29,103.12 145.29,101.22 v2(145.41,101.09)
NIC1_NCSI_CRS_DV_R: length 9.5
  TOP w0.114: U6.3 v2(143.59,94.75) R864.2 145.21,96.77 145.08,96.77 144.91,96.95 144.91,98.99 R860.2 R1009.2
  BOTTOM w0.114: v1(144.53,95.02) 144.26,94.75 v2(143.59,94.75)
NIC1_NCSI_RXD0: length 199.1
  TOP w0.114: v2(28.7,105.69) 28.7,85.55 28.2,85.05 28,85.05 27.72,84.77 27.72,82.11 27.05,81.44 25.13,81.44 22.78,79.08 22.78,64.71 v2(23.17,64.32) ; R858.1 141.86,100.91 v2(141.86,102.03)
  BOTTOM w0.114: v2(23.17,64.32) 23.04,64.32 23.01,64.28 CONN14.49 ; v2(28.7,105.69) 30.67,105.69 33.79,108.81 33.79,110.91 36.96,114.08 36.96,114.59 37.93,115.56 42.48,115.56 43.7,116.77 49,116.77 49.44,116.33 54.44,116.33 55.8,117.69 55.8,119.69 57.52,121.41 140.02,121.41 145.87,115.56 147.71,115.56 150.88,112.39 150.88,109.45 143.46,102.03 v2(141.86,102.03)
NIC1_NCSI_RXD0_R: length 8.7
  TOP w0.114: U6.6 142.09,96.3 R862.2 142.57,96.77 142.67,96.77 142.88,96.98 v2(142.88,98.81) 142.37,99.31 R858.2
  BOTTOM w0.114: v1(141.43,99.49) 141.43,99.49 R858.2 142.75,99.11 142.75,98.93 v2(142.88,98.81)
NIC1_NCSI_RXD1: length 197
  TOP w0.114: v2(29.79,106.35) 29.78,106.33 29.78,82.14 24.7,77.06 24.7,64.78 24.05,64.14 v2(24,64.14)
  TOP w0.508: R859.1 v2(143.38,101.09)
  BOTTOM w0.114: v2(29.79,106.35) 30.99,106.35 33.55,108.91 33.55,111.01 36.72,114.18 36.72,114.69 37.83,115.8 42.38,115.8 43.6,117.01 49.1,117.01 49.52,116.59 54.36,116.59 55.56,117.79 55.56,119.79 57.42,121.65 140.12,121.65 145.97,115.8 147.81,115.8 151.12,112.5 151.12,109.33 143.38,101.6 v2(143.38,101.09) ; CONN14.51 23.19,63.68 23.65,64.14 v2(24,64.14)
NIC1_NCSI_RXD1_R: length 9.2
  TOP w0.114: R859.2 143.83,99.05 v2(143.83,98.74) 143.92,98.65 143.92,96.7 143.79,96.57 R863.2 142.59,95.78 U6.5
  BOTTOM w0.114: R859.2 144.4,99.49 v1(144.4,99.49) 144.4,99.31 v2(143.83,98.74)
NIC1_NCSI_TXD0: length 232.7
  TOP w0.114: U6.9 140.59,94.48 v2(139.32,95.76) R855.2 139.68,96.57 139.8,96.7 139.8,99.01 R1003.2
  BOTTOM w0.114: CONN14.50 11.94,63.98 10.77,65.15 10.77,85.47 v1(7.9,88.34) 6.15,90.09 6.15,95.26 13.71,102.82 15.13,102.82 15.63,103.31 28.98,103.31 34.28,108.61 34.28,110.71 37.44,113.88 37.44,114.39 38.13,115.07 42.68,115.07 43.9,116.29 48.75,116.29 49.24,115.8 54.59,115.8 56.29,117.49 56.29,118.44 58.71,120.87 102.38,120.87 105.1,118.15 105.71,118.15 106.05,118.49 107.31,118.49 107.65,118.15 108.19,118.15 112.67,118.15 114.17,119.66 114.17,120.27 114.76,120.86 139.89,120.86 145.69,115.06 147.41,115.06 150.37,112.1 150.37,109.7 143.42,102.76 141.24,102.76 139.83,101.35 139.83,97.92 141.86,95.89 141.86,95.12 141.73,95 140.08,95 v2(139.32,95.76)
NIC1_NCSI_TXD1: length 224
  TOP w0.114: U6.8 141.09,94.87 140.34,95.63 R856.2 140.7,96.57 140.82,96.69 v2(140.82,98.81) 140.82,99.01 R1005.2
  BOTTOM w0.114: v2(140.82,98.81) 140.84,98.83 140.84,101.85 141.5,102.51 143.54,102.51 150.62,109.6 150.62,112.19 147.49,115.32 145.77,115.32 139.92,121.16 57.62,121.16 56.05,119.59 56.05,117.59 54.51,116.05 49.37,116.05 48.9,116.53 43.8,116.53 42.58,115.32 38.03,115.32 37.2,114.49 37.2,113.98 34.04,110.81 34.04,108.71 28.88,103.56 15.53,103.56 15.03,103.06 13.58,103.06 5.88,95.36 5.88,89.4 v1(6.31,88.97) 10.52,84.76 10.52,64.92 12.06,63.38 CONN14.52
NIC1_NCSI_TXEN: length 228
  TOP w0.114: U6.7 141.59,95.26 v2(141.35,95.5) R857.2 141.58,96.8 141.72,96.8 141.83,96.91 141.83,99.01 R1007.2
  BOTTOM w0.114: v2(141.35,95.5) 141.33,95.5 138.81,98.02 138.81,101.35 140.46,103 143.31,103 150.11,109.8 150.11,112.01 147.32,114.81 145.42,114.81 139.62,120.61 114.87,120.61 114.41,120.15 114.41,119.56 112.77,117.91 108.09,117.91 107.33,117.91 107.02,118.22 106.64,118.22 106.34,117.91 104.99,117.91 104.99,117.92 102.28,120.62 58.81,120.62 56.53,118.34 56.53,117.39 54.65,115.52 49.18,115.52 48.65,116.05 44,116.05 42.76,114.81 38.21,114.81 37.69,114.29 37.69,113.78 34.54,110.63 34.54,108.54 29.08,103.07 15.73,103.07 15.23,102.58 13.81,102.58 6.72,95.49 v1(6.72,90.59) 11.01,86.3 11.01,65.57 12,64.58 CONN14.48
NIC2_CBOT: length 5.8
  TOP w0.114: C841.2 139.52,80.82 139.52,82.22 139.09,82.65 v2(139.09,82.93) U6.37
  BOTTOM w0.114: v1(139.45,81.92) 139.09,82.27 v2(139.09,82.93)
NIC2_CTOP: length 4.2
  TOP w0.114: C841.1 140.59,82.05 140.59,82.29 v2(140.34,82.55) 140.34,83.69 140.59,83.95 U6.40
  BOTTOM w0.114: v2(140.34,82.55) 140.34,82.12 v1(140.88,81.57)
NIC2_LAN_PWR_GOOD: length 3.7
  TOP w0.114: R187.2 v2(201.04,64.64) 200.59,64.19 U12.A13
NMI_BTN_IN_BMC: length 259.5
  S5 w0.102: v2(64.66,2.77) 65.06,2.37 68.92,2.37 69.71,3.15 71.19,3.15 71.46,3.42 71.84,3.42 72.12,3.15 75.17,3.15 75.22,3.2 77.28,3.2 77.33,3.15 82.6,3.15 83.01,2.74 84.94,2.74 84.97,2.77 v2(85.44,2.77) ; v2(123.11,2.03) 123.22,1.92 125.59,1.92 126.41,2.73 127.56,2.73 128.45,1.84 146.81,1.84 147.67,2.69 159.67,2.69 162.25,5.27 163.9,5.27 167.18,8.55 170.59,8.55 174.69,12.65 178.44,12.65 180.37,14.58 180.37,20.09 181.15,20.88 181.15,23.68 188.2,30.73 193.02,30.73 203.17,40.89 203.17,41.08 205.3,43.21 205.3,43.95 206.3,44.95 206.3,50.84 205.66,51.47 205.66,54.39 v2(205.94,54.66)
  S8 w0.102: v2(123.11,2.03) 123.11,1.9 122.76,1.55 120.22,1.55 120.14,1.63 97.52,1.63 95.83,3.32 95.83,5.84 92.75,8.92 88.33,8.92 86.64,7.23 86.64,3.98 v2(85.44,2.77)
  S10 w0.102: v2(64.66,2.77) 63.92,3.5 63.92,6.43 64.62,7.12 64.62,14.37 61.9,17.09 58.78,17.09 57.73,18.13 53.92,18.13 53.65,17.87 50.39,17.87 46.47,13.95 32.95,13.95 32.73,14.17 32.35,14.17 32.12,13.95 22.08,13.95 21.28,14.76 21.28,23.89 21.09,24.08 v2(20.01,24.08)
  BOTTOM w0.114: CONN14.175 v2(20.01,24.08) ; v2(205.94,54.66) 206.3,54.66 v1(206.76,55.12) 206.51,55.36 R908.2
NMI_BTN_IN_BMC_R: length 3.9
  TOP w0.114: U12.H16 203.68,55.11 v2(204.56,55.99)
  BOTTOM w0.114: v1(206.25,57.28) 205.6,56.63 R908.1 204.68,56.12 v2(204.56,55.99)
NMI_BTN_OUT_BMC_N: length 32.9
  TOP w0.114: R332.2 v2(11.06,24.58)
  BOTTOM w0.114: CONN14.174 11.26,24.38 v2(11.06,24.58) 10.3,23.82 10.3,21.4 8.78,19.87 8.78,13.25 9.31,12.71 9.33,12.71 9.86,12.18 16.57,12.18 22.77,5.97 v1(23.01,5.97)
NOUSED_IRTN1_L2: length 1.6
  TOP w0.114: v2(61.34,3.86) 61.09,3.86 60.54,4.41 U29.31 U29.32
NOUSED_IRTN2: length 1.4
  TOP w0.114: U29.38 60.55,7.34 61.01,7.34 61.09,7.26 61.09,7.06 60.98,6.95 U29.37
NOUSED_IRTN2_L2: length 1.3
  TOP w0.114: U29.34 U29.33 61.36,5.35 v2(61.42,5.41)
NOUSED_IRTN3: length 1.5
  TOP w0.114: U29.36 61.04,6.55 61.17,6.42 61.17,6.26 61.06,6.15 U29.35
NUT1_GND: length 3.9
  TOP w0.381: C12.1 190.96,97.74
NUT2_GND: length 4.1
  TOP w0.381: C127.1 179.45,32.83 NUT2.1
NUT3_GND: length 4
  TOP w0.381: C126.1 NUT3.1
NV_SAVE_CH0_D1: length 6.1
  TOP w0.114: U12.J16 205.41,54.11 v2(206.12,53.4) TP4.1
  BOTTOM w0.114: v1(204.85,55.05) 204.85,54.68 v2(206.12,53.4)
NV_SAVE_CH1_D1: length 20.1
  TOP w0.114: U12.H15 203.04,54.66 204.68,54.66 206.08,56.06 206.08,62.42 204.74,63.75 204.74,70.01 R885.2 v2(203.53,70.24)
P0_1_SCL_R: length 11.4
  BOTTOM w0.114: R531.1 R532.1 23.81,89.71 U33.5 23.81,92.19 25.64,94.03 v1(28.63,94.03)
P0_1_SDA_R: length 11.1
  BOTTOM w0.114: v1(29.67,93.27) 25.22,93.27 24.46,92.5 U33.4 24.46,88.56 R534.1 R533.1
P0_LINKLED_L: length 94.2
  TOP w0.114: U12.F13 v3(201.09,57.61)
  S3 w0.102: v2(131.21,82.88) 131.37,82.71 131.37,82.14 131.84,81.67 131.84,80.96 137.19,75.62 139.04,75.62 139.95,74.7 139.95,73.61 141.3,72.26 142.88,72.26 143.43,71.7 143.77,71.7 147.28,68.2 147.98,68.2 148.72,67.46 150.72,67.46 151.1,67.84 157.89,67.84 158.8,68.76 161.52,68.76 162.69,69.93 162.69,72.87 162.79,72.97 164.8,72.97 166.73,71.04 168.53,71.04 172.03,67.54 172.03,66.85 173.81,65.07 180.75,65.07 v2(181.38,64.44)
  S8 w0.102: v3(201.09,57.61) 201.09,58.07 200.7,58.46 200.7,61.79 199.39,63.1 194.31,63.1 193.37,62.16 191.34,62.16 190.4,63.1 187.15,63.1 186.88,63.37 186.5,63.37 186.31,63.19 182.64,63.19 v2(181.38,64.44)
  BOTTOM w0.114: v1(181.23,63.5) 181.38,63.65 v2(181.38,64.44) ; R944.1 131.12,82.97 v2(131.21,82.88)
P0_LINKLED_L_R: length 6.5
  TOP w0.114: U6.30 136.01,86.02 134.49,84.51 v2(134.49,84.2)
  BOTTOM w0.114: v2(134.49,84.2) 133.65,84.2 v1(133.55,84.3) 133.15,84.71 R868.1 R944.2
P0_SPD100LED_L: length 94.6
  TOP w0.114: U12.F14 v3(202.09,57.61)
  S3 w0.102: v2(131.9,82.27) 132.18,81.99 132.18,80.94 137.28,75.84 139.17,75.84 140.18,74.83 140.18,73.7 141.39,72.49 142.97,72.49 143.53,71.93 143.87,71.93 147.35,68.45 148.09,68.45 148.82,67.72 150.62,67.72 151,68.1 157.78,68.1 158.7,69.01 161.41,69.01 162.43,70.03 162.43,72.98 162.68,73.23 164.9,73.23 166.83,71.3 168.63,71.3 170.81,69.12 170.81,69.1 171.08,68.83 171.1,68.83 172.29,67.64 172.29,66.96 173.92,65.33 181.31,65.33 v2(181.46,65.18)
  S8 w0.102: v2(181.46,65.18) 182.45,64.19 189.64,64.19 191.43,62.39 193.28,62.39 194.22,63.33 200.57,63.33 201.57,62.33 201.57,58.58 202.09,58.07 v3(202.09,57.61)
  BOTTOM w0.114: v2(131.9,82.27) 132.13,82.04 R945.1 ; v2(181.46,65.18) 181.31,65.02 180.59,65.02 v1(180.34,64.77)
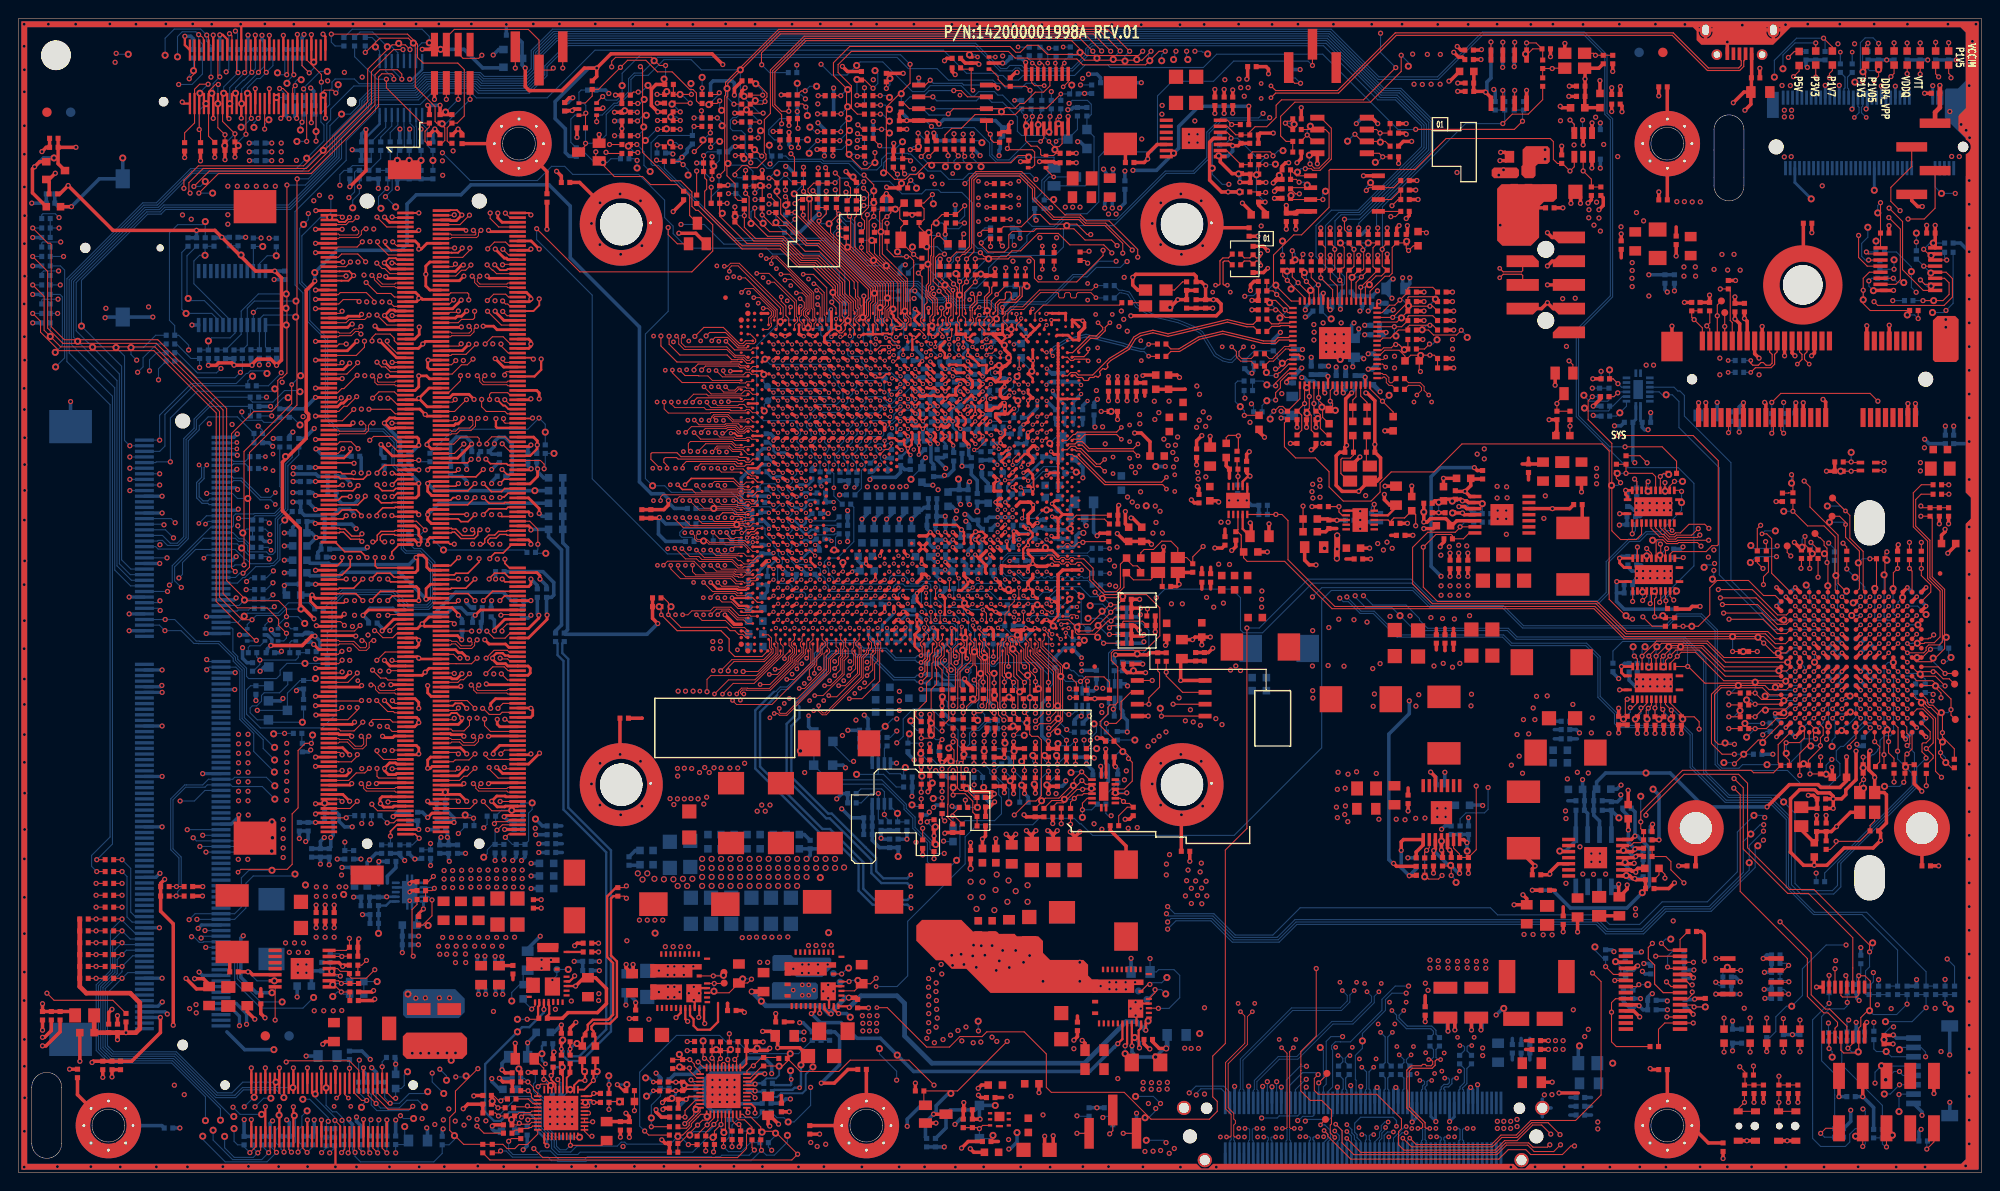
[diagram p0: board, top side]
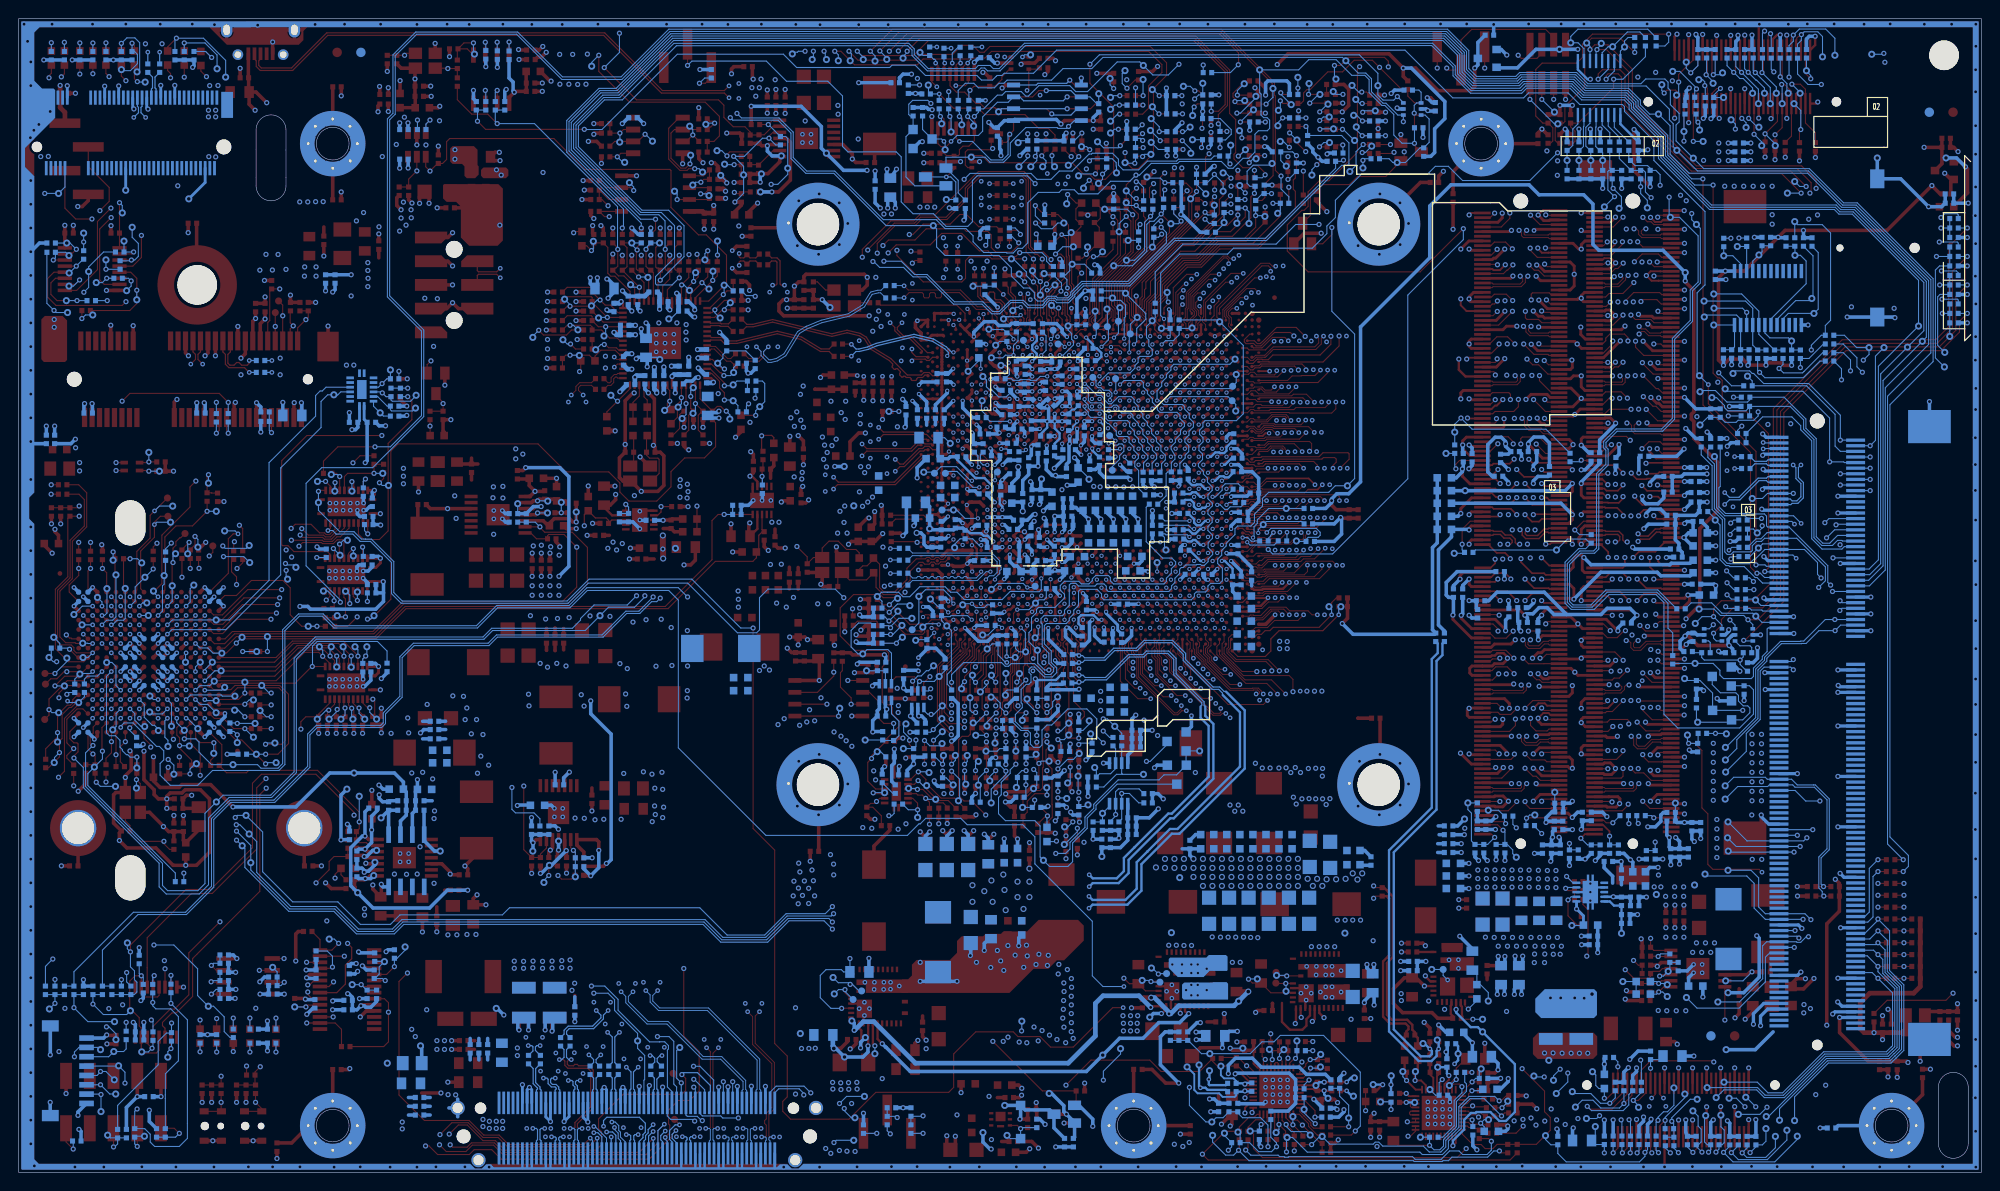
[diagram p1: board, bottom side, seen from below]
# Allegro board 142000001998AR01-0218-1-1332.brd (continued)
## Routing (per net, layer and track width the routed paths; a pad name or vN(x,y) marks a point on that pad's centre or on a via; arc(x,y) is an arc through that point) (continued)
P0_SPD100LED_L_R: length 6.3
  TOP w0.114: U6.31 135.85,85.52 135,84.68 135,83.97 134.49,83.46 v2(134.49,82.68)
  BOTTOM w0.114: R945.2 133.04,82.09 v1(133.55,82.6) 133.63,82.68 v2(134.49,82.68)
P0_SPD1000LED_L: length 121.2
  TOP w0.114: R919.1 135.43,80.24 135.43,77.67 136.63,76.48 138.73,76.48 140.21,75.01 140.21,73.38 141.73,71.86 144.7,71.86 145.67,72.82 145.67,73.79 146.86,74.98 151.43,74.98 154.43,77.98 169.42,77.98 170.18,77.22 170.18,61.34 172.3,59.22 v2(172.68,59.22) ; U12.F12 v3(200.09,57.61)
  S8 w0.102: v3(200.09,57.61) 200.09,57.6 200.66,57.02 203.58,57.02 204.72,58.17 204.72,64.15 203.59,65.28 198.32,65.28 198.27,65.23 194.19,65.23 193.68,65.74 193.3,65.74 192.84,65.28 191.39,65.28 190.23,66.44 189.42,66.44 189.4,66.42 186.69,66.42 183.39,69.72 179.58,69.72 178.56,68.71 178.56,66.33 178.79,66.1 178.79,60.81 176.78,58.8 173.3,58.8 173.15,58.95 172.83,58.95 172.68,59.1 v2(172.68,59.22)
  BOTTOM w0.114: v2(172.68,59.22) 172.35,59.22 v1(171.98,59.59)
P0_SPD1000LED_L_R: length 6.2
  TOP w0.114: v2(134.29,81.48) 134.37,81.48 134.87,81.99 135.25,81.99 R919.2 137.09,82.81 U6.33
  BOTTOM w0.114: v2(134.29,81.48) 133.91,81.1 v1(133.91,80.64)
P1_1_SCL_R: length 11.8
  BOTTOM w0.114: U33.7 22.51,91.36 18.75,95.12 18.75,97.56 19.35,98.17 v1(19.94,98.17) 19.94,99.12 R493.1 R494.1
P1_1_SDA_R: length 6
  BOTTOM w0.114: R529.1 R530.1 v1(20.3,89) 20.63,89.33 22.63,89.33 23.16,89.86 U33.6
P3_SC2: length 11.9
  BOTTOM w0.114: R495.2 17.45,98.47 17.45,92.41 v1(17.91,91.95) 20.65,91.95 21.21,91.39 U33.9
P3_SD2: length 11.3
  BOTTOM w0.114: U33.8 21.86,91.33 19.86,93.32 18.36,93.32 v1(18.14,93.55) 18.01,93.68 18.01,98.12 R496.2
P1014_RST: length 96.1
  TOP w0.114: R231.2 201.83,41.88 v2(201.7,41.76) ; v3(142.1,3.63) 143.6,2.13 158.07,2.13 159.09,3.15 161.56,3.15 162.02,2.69 163.58,2.69 v2(163.83,2.95)
  S10 w0.102: v2(201.7,41.76) 201.7,40.11 197.89,36.29 192.7,36.29 191.61,35.19 191.61,15.02 188.52,11.94 185.54,11.94 185.16,11.57 185.16,11.35 183.8,9.98 172.91,9.98 167.65,4.72 167.65,3.36 166.66,2.36 164.41,2.36 v2(163.83,2.95)
  BOTTOM w0.114: v1(199.64,41.32) 201.26,41.32 v2(201.7,41.76)
  BOTTOM w0.127: CONN16.68 v3(142.1,3.63)
P1014_RST_R: length 4.8
  TOP w0.114: U12.T15 202.59,45.31 v2(202.06,44.78) 201.98,44.7 201.94,44.7 201.83,44.59 R231.1 R503.2
PCA9517_VCCB: length 8
  BOTTOM w0.381: v1(94.1,33.81) R676.2 R675.2 92.12,34.76 91.33,35.54 C529.1 C526.1 C522.1 U36.8
PCA9548_1_A0: length 5.9
  BOTTOM w0.114: v1(28.63,90.71) U33.1 26.41,88.37 R527.2 R528.1
PCA9548_1_A1: length 8.3
  BOTTOM w0.114: v1(29.64,91.57) 29.44,91.77 26.19,91.77 25.76,91.34 U33.2 R526.2 R525.1
PCA9548_1_A2: length 4
  BOTTOM w0.114: U33.21 24.46,97.54 v1(23.79,98.2) 23.47,98.53 R492.2 R491.1
PCA9548_RESET_N: length 256.5
  TOP w0.114: U12.F5 v3(192.09,57.61)
  S3 w0.102: v2(25.11,92.06) 30.61,86.56 30.61,83.2 32.51,81.3 32.51,67.04 30.23,64.75 30.23,36.74 32.37,34.59 34.31,34.59 34.89,34.01 42.56,34.01 43.13,33.44 43.13,29.13 44.11,28.15 44.11,27.79 45.31,26.59 62.01,26.59 65.13,23.47 67.78,23.47 67.93,23.62 72.77,23.62 72.92,23.47 93.8,23.47 98.6,28.27 98.6,31.57 101.2,34.16 101.82,34.16 102.88,35.23 115.92,35.23 118,37.3 118.78,37.3 118.85,37.36 119.87,37.36 123.14,34.1 v2(123.14,34.01)
  S8 w0.102: v2(123.14,34.01) 123.27,34.14 123.7,34.14 124.31,34.75 132.23,34.75 137.77,40.28 166.77,40.28 170.96,44.48 181.27,44.48 184.04,47.25 184.04,51.1 190.11,57.18 191.65,57.18 v3(192.09,57.61)
  BOTTOM w0.114: U33.3 v2(25.11,92.06) 25.55,92.51 v1(28.6,92.51)
PCH_A20GATE: length 48.6
  TOP w0.114: U9.BL14 90.39,85.48 v4(90.67,85.19) ; v2(66.29,115.65) 65.77,115.65 R10.1
  S3 w0.102: v2(66.29,115.65) 66.9,115.65 67.61,114.94 68.5,114.94 69.09,114.35 69.09,109.37 69.49,108.97 69.49,107.67 76.68,100.48 80.47,100.48 82.84,98.12 85.38,98.12 85.52,97.98 85.71,97.79 86.41,97.09 86.73,96.77 88.66,94.84 90.55,92.95 90.55,89.1 90.27,88.82 90.27,88.37 90.58,88.06 90.58,87.43 90.27,87.12 90.27,86.59 90.58,86.28 90.58,85.29 v4(90.67,85.19)
  BOTTOM w0.114: v1(67.34,116.36) 66.62,115.65 v2(66.29,115.65)
PCH_APWROK: length 147.8
  TOP w0.114: R184.2 186.99,67.44 v2(186.92,67.51) ; U9.BE13 92.94,86.05 v4(93.15,86.05)
  S3 w0.102: v2(95.76,107.42) 96.44,108.1 103.54,108.1 104.58,107.06 107.43,107.06 109.44,105.05 109.7,105.05 111.2,103.56 111.2,103 113.03,101.17 114.94,101.17 116.5,99.61 116.5,97.57 117.31,96.76 120.5,96.76 121.75,95.51 129.79,95.51 130.63,94.67 130.63,93.42 131.27,92.79 132.72,92.79 133.15,93.22 144.58,93.22 145.36,92.43 145.36,89.66 145.75,89.28 147.93,89.28 152.15,85.06 152.15,80.31 153.8,78.66 168.76,78.66 170.26,77.17 174.27,77.17 175.16,76.28 180.25,76.28 187.08,69.44 187.08,67.67 v2(186.92,67.51)
  S10 w0.102: v2(95.76,107.42) 95.76,107.19 95,106.43 95,106.01 99.59,101.41 99.59,99.54 98.15,98.1 98.15,95.27 99.13,94.29 99.13,90.7 98.44,90 98.44,89.09 98.46,89.07 98.46,88.21 98.23,87.98 97.51,87.98 97.33,88.16 96.84,88.16 95.42,86.74 95.37,86.74 94.77,86.14 94.77,85.89 94.49,85.62 93.58,85.62 v4(93.15,86.05)
PCH_BATLOW: length 17.8
  TOP w0.114: U9.BB4 94.39,90.22 94.74,90.57 94.74,90.87 94.08,91.53 94.08,95.18 90.75,98.5 90.75,102.46 v2(90.81,102.51)
  BOTTOM w0.114: v2(90.81,102.51) 91.4,103.11 R478.1 v1(93.8,103.11)
PCH_CPU2PCH_R_THROT: length 6.1
  TOP w0.114: U12.C6 v3(193.09,60.61) ; R186.1 v2(192.53,63.71)
  S3 w0.102: v3(193.09,60.61) 192.79,60.91 192.79,61.37 192.71,61.45 192.71,61.77 192.79,61.85 192.79,62.99 192.53,63.25 v2(192.53,63.71)
PCH_CPU2PCH_THROT: length 140.4
  TOP w0.114: v2(191.77,67.44) 192.53,66.67 R186.2 ; R65.1 v2(89.69,109.7)
  S3 w0.102: v2(191.77,67.44) 191.77,69.81 184.81,76.76 183.14,76.76 172.06,87.85 172.06,97.01 166.3,102.77 163.12,102.77 161.95,103.94 153.91,103.94 150.51,107.34 149.28,107.34 147.86,108.76 147.38,108.76 146.84,108.23 140.44,108.23 139.9,108.76 135.18,108.76 133.81,107.39 122.53,107.39 120.83,105.69 114.79,105.69 110.98,109.5 107.83,109.5 102.89,114.44 95.18,114.44 93.15,116.48 92.65,116.48 90.65,114.49 90.65,110.66 v2(89.69,109.7)
  BOTTOM w0.114: v1(191.91,66.22) 191.91,67.29 v2(191.77,67.44)
PCH_CPU2PCH_THROT_R: length 31.9
  TOP w0.114: v4(90.67,81.76) 90.39,82.04 U9.BL22 ; v2(89.74,108.74) 89.79,108.79 R65.2
  S10 w0.102: v4(90.67,81.76) 90.67,82.78 90.29,83.17 90.29,83.71 90.58,84 90.58,84.43 91.06,84.91 91.06,85.34 91.55,85.83 91.55,86.3 91.28,86.57 91.28,87.27 91.57,87.55 91.57,87.96 92.09,88.48 92.09,96.06 89.33,98.82 89.33,101.78 89.59,102.04 89.59,102.76 89.48,102.86 89.48,108.48 v2(89.74,108.74)
  BOTTOM w0.114: v2(89.74,108.74) 89.5,108.98 v1(88.85,108.98)
PCH_DPWROK: length 23.8
  TOP w0.114: v4(96.9,89.42) 96.9,89.69 96.37,90.22 U9.AV4 ; R71.2 93.59,107.3 v2(94.03,106.86)
  S10 w0.102: v2(94.03,106.86) 94.03,106.26 97.64,102.66 97.64,95.45 96.9,94.71 v4(96.9,89.42)
  BOTTOM w0.114: R71.2 93.59,107.3 v2(94.03,106.86) 94.03,106.3 v1(94.46,105.87)
PCH_PLTRST_N: length 379.9
  TOP w0.114: R66.1 62.97,109.07 v2(62.84,109.19) ; R228.1 v2(191.67,42.65)
  S3 w0.102: v2(97.98,13.88) 96.49,12.4 88.1,12.4 86.47,10.77 82.3,10.77 79.02,7.49 77.26,7.49 76.77,7.01 70.51,7.01 69.29,5.79 66.86,5.79 66.48,5.41 63.03,5.41 62.14,6.3 61.39,6.3 59.49,8.19 54.93,8.19 54.79,8.05 54.22,8.05 53.18,9.09 44.01,9.09 42.69,10.41 32.51,10.41 31.83,11.1 31.83,12.03 30.95,12.9 26.16,12.9 25.48,12.22 11.45,12.22 11.02,12.22 4.62,18.62 4.62,22.71 3.1,24.24 3.1,102.09 3.38,102.37 3.39,102.37 8.2,107.18 30.63,107.18 33.78,110.33 33.78,110.33 33.81,110.36 33.81,114.19 34.62,115 34.62,116.21 37.33,118.92 39.01,118.92 41.1,121.01 56.39,121.01 61.26,116.13 61.26,110.77 v2(62.84,109.19)
  S8 w0.102: v2(191.67,42.65) 191.67,42.62 187.73,38.68 187.73,32.47 182.21,26.95 178.43,26.95 176.68,25.2 170.89,25.2 169.24,23.54 150.65,23.54 147.91,20.8 115.47,20.8 111.79,17.12 105.31,17.12 105,16.81 100.76,16.81 100.63,16.68 97.98,14.03 v2(97.98,13.88)
  BOTTOM w0.114: v1(190.98,43.74) 191.11,43.74 191.67,43.18 v2(191.67,42.65)
PCH_PLTRST_N_R: length 49
  TOP w0.114: v2(66.24,109.17) 65.55,109.17 R66.2 ; v4(93.24,80.88) 92.96,80.88 U9.BE24
  S3 w0.102: v2(66.24,109.17) 66.65,108.76 66.65,108.05 67.64,107.06 68.12,107.06 76.09,99.09 79.93,99.09 82.27,96.74 84.81,96.74 88.6,92.96 88.6,91.36 87.5,90.27 87.5,89.18 87.3,88.98 87.3,88.32 87.81,87.81 87.81,87.6 88.29,87.12 88.29,86.74 88.7,86.33 88.7,85.9 89.08,85.52 89.08,84.9 88.73,84.56 88.73,84.17 89.28,83.62 89.28,83.24 89.69,82.83 89.69,82.4 90.09,81.99 90.09,81.79 90.55,81.33 92.53,81.33 92.98,80.88 v4(93.24,80.88)
  BOTTOM w0.114: v1(65.23,109.86) 65.91,109.17 v2(66.24,109.17)
PCH_PLTRST_R_N: length 10.7
  TOP w0.114: R228.2 192.79,44.45 v2(192.81,44.48) ; U12.M10 v3(198.09,50.61)
  S8 w0.102: v3(198.09,50.61) 197.64,50.16 196.34,50.16 195.96,49.78 195.96,48.47 194.26,46.77 194.26,45.87 192.87,44.48 v2(192.81,44.48)
PCH_PM_SYNC: length 40.7
  TOP w0.114: U9.BT9 v4(88.2,87.77) ; R47.2 v2(66.14,110.03)
  S3 w0.102: v4(88.2,87.77) 88.2,88.13 88.09,88.24 88.09,88.95 88.32,89.18 88.32,89.81 88.67,90.17 88.67,90.78 88.8,90.91 88.8,93.08 84.91,96.97 82.36,96.97 80.02,99.31 76.19,99.31 68.21,107.29 67.73,107.29 66.88,108.14 66.88,109.29 v2(66.14,110.03)
  BOTTOM w0.114: v2(66.14,110.03) 66.9,109.27 66.9,107.8 v1(67.56,107.14)
PCH_PM_SYNC_R: length 88.8
  TOP w0.114: R47.1 v2(63.22,110.03) ; U9.H77 110.49,56.56 v4(110.59,56.46)
  S3 w0.102: v2(63.22,110.03) 63.75,109.5 63.75,108.97 69.38,103.34 69.38,102.3 70,101.68 70,99.62 79.5,90.12 79.5,76.58 79.95,76.13 86.61,76.13 86.79,75.95 86.79,75.36 87.12,75.03 97.5,75.03 98.09,74.44 99.12,73.41 100.41,73.41 101.27,72.54 101.27,71.12 101.8,70.59 101.8,67.59 101.97,67.42 101.97,65.52 103.56,63.93 103.56,62.44 104.73,61.26 108.92,61.26 109.98,60.2 109.98,59.87 111.02,58.83 111.02,56.89 v4(110.59,56.46)
PCH_PME_N: length 137.6
  TOP w0.114: v2(97.38,108.74) 98.18,109.53 R50.1 ; v4(93.19,84.39) 92.96,84.62 U9.BE16
  S5 w0.102: v4(93.19,84.39) 93.56,84.39 93.95,84 96.91,84 97.14,84.24 97.14,84.53 97.42,84.8 97.71,84.8 98.12,85.21 98.12,87.58 98.66,88.12 98.66,88.61 98.46,88.81 98.46,89.64 97.19,90.91 95.24,90.91 92.99,93.16 92.99,100.13 93.83,100.97 93.83,102.84 96.77,105.79 96.77,108.13 v2(97.38,108.74)
  S8 w0.102: v2(97.38,108.74) 95.61,110.52 94.32,110.52 90.96,113.88 90.96,114.64 88.43,117.17 78.96,117.17 78.94,117.19 78.32,117.81 76.17,117.81 75.81,117.45 69.79,117.45 69.59,117.25 51.71,117.25 47.95,113.49 47.76,113.49 47.76,113.49 37.31,113.49 31.19,107.37 31.19,105.92 28.09,102.81 v2(28.09,85.6)
  BOTTOM w0.114: v2(28.09,85.6) 28.09,85.58 26.72,84.2 R540.1
PCH_PWRBTN_N: length 414.4
  TOP w0.102: 93.41,97.32 95.08,95.65 95.08,95.4 95.08,95.4 95.08,91.8 95.48,91.4 95.48,90.82
  TOP w0.114: 93.41,97.32 92.41,98.32 92.41,101.9 92.81,102.31 v2(92.91,102.31) 93.32,102.72 R109.1 ; U9.AW3 95.48,90.82 ; U12.C5 v3(192.09,60.61)
  S3 w0.102: v2(92.91,102.31) 92.91,103.76 92.38,104.29 92.38,107.92 93.07,108.61 93.07,110.71 93.52,111.16 93.52,111.74 94.83,113.05 98.56,113.05 99.28,113.77 102.92,113.77 107.64,109.04 110.79,109.04 114.6,105.23 121.02,105.23 122.72,106.93 138.56,106.93 139.14,107.52 148.39,107.52 149.02,106.88 150.22,106.88 153.63,103.48 161.76,103.48 162.95,102.29 166.13,102.29 171.6,96.82 171.6,87.57 190.45,68.72 190.45,66.5 190.25,66.29 190.25,64.34 191.77,62.81 191.77,61.83 191.71,61.77 191.71,61.45 192.09,61.07 v3(192.09,60.61)
  S10 w0.102: v2(34.59,5.56) 34.59,5.66 35.23,6.3 35.84,6.3 35.96,6.42 35.96,8.05 34.8,9.22 28.68,9.22 27.95,8.49 19.75,8.49 9.35,18.9 9.35,40.3 19.58,50.54 19.58,51.49 21.34,53.24 21.77,53.24 24.61,56.08 24.61,57.28 25.55,58.22 25.55,61.55 25.38,61.72 25.38,63.46 24.61,64.22 24.61,67.66 25.43,68.47 25.43,69.56 26.55,70.69 29.13,70.69 29.82,71.37 29.82,75.24 29.84,75.26 29.84,75.64 29.82,75.67 29.82,80.22 29.51,80.52 29.51,81.28 29.82,81.58 29.82,88.21 14.27,103.76 14.27,115.85 16.41,117.98 22.02,117.98 v2(22.2,117.81) 23.04,116.97 31.11,116.97 31.83,116.26 33.2,116.26 33.43,116.49 36.17,116.49 36.57,116.09 49.68,116.09 50.56,116.97 51.61,116.97 52.12,117.47 74.06,117.47 75.05,116.48 76.7,116.48 77.53,115.65 77.91,115.65 78.83,116.56 91.2,116.56 91.25,116.51 91.6,116.51 91.87,116.24 91.87,115.62 90.98,114.73 90.98,108.41 91.19,108.2 91.19,104.04 v2(92.91,102.31)
  BOTTOM w0.114: v1(191.26,62.87) 191.65,62.48 191.65,61.05 v3(192.09,60.61) ; R759.2 34.8,5.36 v2(34.59,5.56) 34.59,5.89 34.01,6.48 33.58,6.48 32.89,7.16 v1(32.89,9.04) ; v2(22.2,117.81) 22.48,118.08 R423.2
PCH_PWROK: length 111.3
  TOP w0.114: v2(186.39,69.27) 186.03,68.91 R189.1 ; U9.AN1 98.3,92 98.3,92.32 98.27,92.35 98.27,92.71 98.3,92.74 98.3,93.47 97.97,93.8 97.97,93.98 v3(97.92,94.03)
  S3 w0.102: v2(118.29,95.81) 118.92,95.17 125.91,95.17 126.36,94.72 126.36,90.07 131.35,85.09 133.63,85.09 134,84.72 134.86,84.72 135.64,83.95 144.4,83.95 145.29,83.06 146.56,83.06 147.83,81.79 148.97,81.79 152.37,78.38 168.53,78.38 170.03,76.89 174.22,76.89 175.06,76.05 180.15,76.05 186.39,69.81 v2(186.39,69.27)
  S5 w0.102: v2(118.29,95.81) 117.6,95.81 115.39,98.02 114.02,98.02 110.84,94.84 110.84,94.56 110.52,94.23 105.71,94.23 104.46,92.99 101.24,92.99 100.56,93.67 98.35,93.67 97.99,94.03 v3(97.92,94.03)
PCH_RSMRST_N: length 138.9
  TOP w0.114: R64.1 94.54,108.46 R72.2 95.2,108.51 v2(95.43,108.28) ; U12.C4 v3(191.09,60.61)
  S3 w0.102: v2(95.43,108.28) 94.95,108.76 94.95,110.6 97.02,112.67 103.69,112.67 107.55,108.81 110.69,108.81 114.5,105 121.12,105 122.79,106.68 138.28,106.68 138.84,106.12 146.94,106.12 149.81,103.25 161.66,103.25 162.86,102.06 166.04,102.06 171.37,96.72 171.37,87.47 189.15,69.69 189.15,64.75 190.7,63.2 190.7,60.99 v3(191.09,60.61)
  BOTTOM w0.114: v1(92.53,107) 92.53,107.69 92.57,107.72 92.57,108.09 92.99,108.51 R464.2 95.2,108.51 v2(95.43,108.28)
PCH_RSMRST_N_R: length 23.3
  TOP w0.114: U9.AR7 97.4,88.91 v4(97.61,88.7) ; R72.1 94.59,107.09 v2(94.79,106.88)
  S10 w0.102: v2(94.79,106.88) 94.77,106.86 94.77,105.91 97.87,102.81 97.87,95.35 97.36,94.84 97.36,93.85 97.74,93.47 97.74,91.29 97.46,91.01 97.46,88.85 v4(97.61,88.7)
  BOTTOM w0.114: v1(96.6,106.68) 96.39,106.88 v2(94.79,106.88)
PCH_SERIRQ: length 335.6
  TOP w0.114: U9.BU14 v4(87.7,85.19) ; v2(83.39,111.76) 83.33,111.82 R28.1
  TOP w0.127: v2(175.16,23.14) U17.27
  S3 w0.102: v2(112.42,51.77) 112.95,52.3 112.95,58.7 111.67,59.98 111.67,60.52 110.06,62.13 104.95,62.13 104.48,62.6 104.48,62.83 104.11,63.2 104.11,63.74 102.74,65.1 102.74,68.33 102.79,68.38 102.79,68.88 102.11,69.57 102.11,71.15 102.14,71.18 102.14,71.96 100.31,73.79 99.16,73.79 97.71,75.23 88.17,75.23 87.81,75.59 87.81,76.03 88.11,76.33 88.11,76.61 88.59,77.09 88.59,77.59 89.07,78.07 89.07,78.71 88.81,78.97 88.81,79.48 89.07,79.74 89.07,80.32 88.78,80.61 88.78,80.92 88.19,81.51 88.19,81.94 87.81,82.31 87.81,82.9 88.08,83.17 88.08,83.8 87.7,84.18 v4(87.7,85.19) ; v2(126.88,17.61) 126.88,22.39 129.1,24.6 129.1,46.76 125.06,50.8 v2(124.16,50.8)
  S5 w0.102: v2(124.16,50.8) 124.16,51.26 120.55,54.86 117.5,54.86 114.4,51.77 v2(112.42,51.77)
  S8 w0.102: v2(126.88,17.61) 127.78,18.52 139.4,18.52 141.15,16.77 148.77,16.77 153.21,21.21 161.85,21.21 163.7,23.06 175.08,23.06 v2(175.16,23.14) ; v2(11.89,76.58) 15.65,80.33 15.65,96.72 16.08,97.16 16.08,104.95 18.26,107.14 30.64,107.14 37.22,113.72 47.85,113.72 51.61,117.47 69.49,117.47 69.7,117.68 75.72,117.68 75.98,117.95 76.07,118.03 78.42,118.03 79.05,117.4 90.36,117.4 91.25,116.51 93,116.51 96.72,112.79 96.72,111 97.84,109.88 97.84,108.55 97.57,108.28 96.14,108.28 95.68,108.74 92.58,108.74 91.41,107.57 89,107.57 88.44,108.13 85.82,108.13 83.39,110.56 v2(83.39,111.76)
  S10 w0.102: v4(87.7,85.19) 87.81,85.3 87.81,86.44 88.08,86.71 88.08,87.2 87.81,87.47 87.81,88.17 88.08,88.44 88.08,88.78 87.86,89 87.83,89 87.54,89.29 87.54,90.31 87.83,90.6 87.83,95.78 84.63,98.99 84.63,102.76 83.97,103.42 83.97,104.09 83.29,104.77 83.29,107.98 83.89,108.58 83.89,111.26 v2(83.39,111.76)
  BOTTOM w0.114: v2(112.42,51.77) 112.65,51.54 Q10.4 ; CONN14.8 v2(11.89,76.58)
PCH_SLP_S3_N: length 304.3
  TOP w0.114: v2(91.54,101.37) 91.57,101.35 R125.1 ; R221.2 v2(182.98,47.5)
  S3 w0.102: v2(171.09,108.74) 170.69,109.14 169.67,109.14 167.99,110.83 165.57,110.83 165.17,111.22 164.08,111.22 164.07,111.21 160.85,114.43 149.13,114.43 148.42,115.14 145.27,115.14 139.91,120.5 114.39,120.5 113.58,119.68 108.18,119.68 108.12,119.74 106.73,119.74 106.02,120.45 70.52,120.45 68.76,118.68 68.76,118.3 69.76,117.3 78.59,117.3 80.62,115.27 80.62,114.38 82.27,112.74 82.4,112.74 82.88,112.25 82.88,111.2 83.89,110.19 83.89,109.17 83.52,108.79 83.52,107.4 84.93,105.99 86.09,105.99 86.89,105.19 86.89,105.02 87.49,104.42 87.93,104.42 90.98,101.37 v2(91.54,101.37)
  S5 w0.102: v2(171.09,108.74) 171.09,103.05 174.96,99.19 174.96,94.95 181.05,88.86 181.05,85.7 182.15,84.61 183.49,84.61 185.27,82.83 185.27,78.46 184.4,77.6 184.4,53.7 182.42,51.71 182.42,48.06 v2(182.98,47.5)
  S8 w0.102: v2(98.96,35.46) 99.9,35.46 100.89,34.47 123.7,34.47 124.21,34.98 132.14,34.98 137.67,40.51 166.67,40.51 170.87,44.7 180.19,44.7 v2(182.98,47.5)
  BOTTOM w0.114: R667.2 99.01,35.41 v2(98.96,35.46)
PCH_SLP_S3_N_R: length 9.9
  TOP w0.102: R125.2 91.57,98.37 94.67,95.27 94.67,91.43 U9.AY2
PCH_SLP_S3_R_N: length 6.4
  TOP w0.114: R221.1 v2(185.8,47.5) 186.99,47.5 188.09,48.59 189.07,48.59 U12.P2
  BOTTOM w0.114: v2(185.8,47.5) v1(184.89,46.58)
PCH_SLP_S4_N: length 142.3
  TOP w0.114: v2(191.13,68.07) 191.13,67.18 191.64,66.67 R182.1 ; R126.1 v2(92.91,101.6)
  S3 w0.102: v2(92.91,101.6) 92.46,102.06 92.46,103.9 92.16,104.2 92.16,108.02 92.84,108.7 92.84,110.8 93.29,111.26 93.29,111.83 94.74,113.28 98.46,113.28 99.18,114 103.01,114 107.74,109.27 110.88,109.27 114.69,105.46 120.93,105.46 122.63,107.16 133.96,107.16 135.33,108.53 139.65,108.53 140.18,108 146.94,108 147.47,108.53 147.76,108.53 149.19,107.11 150.32,107.11 153.72,103.71 161.85,103.71 163.02,102.54 166.2,102.54 171.83,96.91 171.83,87.75 183.16,76.43 184.83,76.43 191.13,70.12 v2(191.13,68.07)
  BOTTOM w0.114: v1(190.82,66.93) 190.82,67.76 v2(191.13,68.07)
PCH_SLP_S4_N_R: length 11.2
  TOP w0.114: U9.AW1 95.38,93.36 95.37,93.37 95.37,94.47 95.76,94.85 95.76,97 95.76,97 95.76,97.39 95.76,97.39 95.76,97.62 95.36,98.02 v2(95,98.02) 93.68,98.02 92.91,98.78 R126.2
  BOTTOM w0.114: v1(94.03,98.55) 94.56,98.02 v2(95,98.02)
PCH_SLP_S4_R_N: length 7.4
  TOP w0.114: U12.D6 v3(193.09,59.61) ; R182.2 v2(191.64,64.64)
  S3 w0.102: v3(193.09,59.61) 192.53,60.17 192.53,60.84 192.47,60.91 192.47,62.79 191.64,63.62 v2(191.64,64.64)
PCH_SYS_PWROK: length 174.4
  TOP w0.114: R218.2 190.75,64.71 v2(190.7,64.66) ; R18.2 v2(82.4,113.59) 81.62,113.59 80.91,114.3 80.91,117.81 84.25,121.15 112.67,121.15 114.25,119.56 114.74,119.56 114.74,119.55 119.06,119.55 119.07,119.56 119.81,119.56 v2(120.27,120.02) ; U12.E5 v3(192.09,58.61)
  S10 w0.102: v2(120.27,120.02) 122.1,121.84 143.84,121.84 144.68,121.01 155.22,121.01 155.8,121.59 169.7,121.59 172.09,119.21 172.09,100.64 175.01,97.72 175.01,94.03 180.26,88.78 180.26,85.72 186.89,79.09 186.89,75.74 190.68,71.96 190.68,64.94 190.7,64.91 v2(190.7,64.66) 190.7,64.59 191.62,63.68 191.62,59.11 192.09,58.64 v3(192.09,58.61)
  BOTTOM w0.114: v2(82.4,113.59) R18.2 ; v2(120.27,120.02) 119.63,119.38 v1(119.63,119.13)
PCH_SYS_PWROK_R: length 29.5
  TOP w0.114: U9.BP5 88.17,89.45 v4(87.92,89.45) ; v2(84.23,114.05) 83.9,114.38 R18.1
  S10 w0.102: v4(87.92,89.45) 87.92,89.95 88.04,90.07 88.04,95.91 84.86,99.08 84.86,102.86 84.43,103.29 84.43,105.19 83.52,106.11 83.52,107.87 84.23,108.58 v2(84.23,114.05)
  BOTTOM w0.114: v2(84.23,114.05) 84.39,113.89 v1(84.39,113.13)
PCH_SYSRESET_N: length 200
  TOP w0.114: R105.2 R85.1 v2(80.27,105.57) ; R195.1 v2(203.58,67.44)
  S3 w0.102: v2(203.58,67.44) 203.58,67.8 202.05,69.33 202.05,78.37 201.39,79.04 200.55,79.87 200.55,87.36 199.55,88.36 199.55,98.89 195.3,103.14 176.66,103.14 172.59,107.2 172.59,108.94 169.88,111.66 165.71,111.66 165.35,112.01 164.25,112.01 161.15,115.11 149.44,115.11 148.73,115.82 145.55,115.82 140.19,121.18 69.23,121.18 67.94,119.9 67.94,118.03 71.18,114.79 71.18,114.48 71.67,114 72.19,114 72.52,114.33 73.95,114.33 75.54,112.74 75.54,112.3 76.23,111.61 76.43,111.61 78.87,109.17 78.87,106.97 v2(80.27,105.57)
PCH_SYSRESET_N_R: length 5.3
  TOP w0.114: R195.2 v2(203.58,64.64) 203.58,63.89 204.59,62.87 204.59,62.12 U12.B16
PCH_SYSRESET_R_N: length 20.1
  TOP w0.102: 89.8,92.62 89.93,92.5 89.93,91.69 89.58,91.34 89.58,91.07 89.93,90.72
  TOP w0.114: U9.BL4 89.93,90.72 ; R105.1 v2(79.55,102.49) 80.7,101.35 82.1,101.35 84.24,99.21 85.49,99.21 89.4,95.31 89.4,94.63 89.53,94.49 89.53,93.65 89.8,93.38 89.8,92.62
  BOTTOM w0.114: v2(79.55,102.49) 79.55,101.7 v1(79.65,101.6)
PCH_THERMTRIP_N: length 160.6
  TOP w0.114: R69.2 68.38,108.23 v2(68.25,108.36) ; U13.15 176.7,66.19 176.96,66.45 180.55,66.45 181.19,67.09 181.75,67.09 181.86,67.19 181.86,76.18 179.16,78.88 v2(171.15,78.88)
  S3 w0.102: v2(171.15,78.88) 169.23,78.88 166.7,81.41 166.7,87.1 168.58,88.98 168.58,93.9 165.94,96.55 162.71,96.55 161.77,97.49 157.23,97.49 156.1,96.35 135.85,96.35 134.39,94.89 130.74,94.89 129.9,95.73 121.85,95.73 120.59,96.99 117.97,96.99 v2(117.42,97.54)
  BOTTOM w0.114: v2(117.42,97.54) 115.57,97.54 114.15,96.11 112.8,96.11 109.88,93.19 106.83,93.19 105.79,92.15 105.08,92.15 103.89,93.34 102.49,93.34 101.98,92.84 100.46,92.84 100.25,93.05 100.25,93.13 99.81,93.57 99.1,93.57 98.93,93.4 97.66,93.4 97.21,93.85 97.21,94.09 96.17,95.14 91.21,95.14 86.36,99.99 76.59,99.99 69.09,107.49 R69.2 68.38,108.23 v2(68.25,108.36)
PCH_THERMTRIP_N_R: length 40.2
  TOP w0.114: v2(71.09,107.87) 70.74,108.23 R69.1 ; U9.BJ16 v4(91.17,84.33)
  S3 w0.102: v2(71.09,107.87) 71.09,106.39 76.77,100.71 80.56,100.71 82.93,98.34 85.48,98.34 85.68,98.14 85.87,97.95 86.57,97.26 86.89,96.93 89.62,94.21 90.6,94.21 91.59,93.22 91.59,90.12 91.06,89.59 91.06,88.27 90.78,87.99 90.78,87.6 91.06,87.33 91.06,86.56 90.78,86.28 90.78,85.67 91.06,85.39 91.06,84.44 v4(91.17,84.33)
  BOTTOM w0.114: v1(71.63,106.76) 71.63,107.34 v2(71.09,107.87)
PCH_WAKE_N: length 151.2
  TOP w0.114: v2(90.45,106.76) 91.49,105.71 R110.2 ; v2(60.65,110.16) 60.65,109.92 Q2.D
  S10 w0.102: v2(133.15,113.36) 135.03,113.36 140.56,118.9 148.67,118.9 149.74,117.83 162.17,117.83 167.33,112.67 v2(167.33,112.65)
  BOTTOM w0.114: v2(133.15,113.36) 132.66,112.88 128.65,112.88 127.13,111.35 127.13,108.64 125.68,107.19 122.68,107.19 117.47,101.98 111.82,101.98 110.87,101.03 108.65,101.03 107.88,100.26 107.88,99.61 106.74,98.47 104.33,98.47 104.27,98.42 103.58,98.42 103.09,98.91 102.61,98.91 102.03,99.49 102.03,103.78 100.91,104.9 98.68,104.9 98.4,105.18 97.05,105.18 96.62,104.75 94.51,104.75 93.17,106.1 91.11,106.1 v2(90.45,106.76) 90.07,106.76 88.82,108.01 86,108.01 85.79,108.22 81.31,108.22 80.58,107.49 80.07,107.49 78.99,108.56 78.38,108.56 77.72,109.22 77.72,111.12 77.34,111.51 76.4,111.51 76.15,111.76 76.15,112.63 76.42,112.9 76.78,112.9 77.07,113.2 77.07,113.58 77.06,113.6 77.06,115.42 77.22,115.58 v1(77.22,118.02) 73.05,118.02 71.96,119.11 69.04,119.11 67.36,117.44 65.96,117.44 65.51,116.98 65.51,115.58 64.13,114.21 63.82,114.21 62.87,113.26 62.87,111.05 61.98,110.16 v2(60.65,110.16) 60.65,110.16 R447.2 ; R803.2 v2(167.33,112.65)
PCH_WAKE_N_R: length 14.7
  TOP w0.114: R110.1 v2(91.49,102.34) 91,101.84 91,98.6 94.39,95.21 U9.BA1
  BOTTOM w0.114: v2(91.49,102.34) 92.25,101.57 v1(92.25,100.69)
PCH_WAKE_R_N: length 2.8
  TOP w0.114: v2(165.99,112.65) 166.45,112.19 U38.3
  BOTTOM w0.114: v2(165.99,112.65) 166.42,112.21 R803.1
PCH_XDP_NCLK1: length 62.8
  TOP w0.114: v2(33.93,115.54) 33.63,115.85 32.72,115.85 32.32,115.44 CONN4.4 ; R114.1 82.3,104.19 v2(82.04,104.44)
  S10 w0.102: v2(33.93,115.54) 33.93,115.09 35.28,113.74 48.31,113.74 50.85,116.28 51.9,116.28 52.41,116.79 73.39,116.79 74.4,115.78 74.4,114.66 75.99,113.06 75.99,112.41 76.52,111.89 77.1,111.89 81.23,107.76 81.23,105.26 v2(82.04,104.44)
  BOTTOM w0.114: v2(33.93,115.54) 34.19,115.8 v1(34.19,116.43)
PCIE2_MGMT_MAC_C_TX0_N: length 13.4
  TOP w0.127: U9.J9 109.76,87.78 v4(109.98,87.78) ; v3(120.9,88.64) 120.93,88.67 C57.1
  BOTTOM w0.127: v3(120.9,88.64) 120.4,88.14 120.09,88.14 119.16,88.36 118.28,88.73 114.2,89.71 112.11,89.21 110.76,88.38 110.16,87.78 v4(109.98,87.78)
PCIE2_MGMT_MAC_C_TX0_P: length 13.4
  TOP w0.127: v4(110.64,87.4) 110.39,87.65 110.39,87.96 U9.F9 ; v3(120.9,87.37) 120.92,87.35 C60.1
  BOTTOM w0.127: v4(110.64,87.4) 110.53,87.52 110.53,87.77 110.92,88.17 112.21,88.96 114.2,89.44 118.17,88.48 119.08,88.11 120.06,87.87 120.4,87.87 v3(120.9,87.37)
PCIE2_MGMT_MAC_RX0_N: length 23.5
  TOP w0.127: U9.D15 112.22,85.27 112.56,85.62 113.14,85.62 113.4,85.36 114.92,85.36 116.69,87.12 118.63,88.31 119.3,89.41 119.96,89.81 121.36,90.15 122.98,89.76 129.33,91.29 131.45,90.78 132.08,90.78 C644.2
PCIE2_MGMT_MAC_RX0_N_R: length 3.1
  TOP w0.127: U6.20 136.11,91.02 135.99,90.91 134.9,90.91 134.82,90.83 134.06,90.83 C644.1
PCIE2_MGMT_MAC_RX0_P: length 23.5
  TOP w0.127: U9.B15 112.78,85.35 113.02,85.35 113.29,85.09 113.77,85.09 113.92,84.94 113.92,84.86 114.01,84.77 114.41,84.77 114.5,84.86 114.5,84.96 114.63,85.09 115.03,85.09 115.16,85.22 115.32,85.22 115.39,85.14 115.52,85.14 115.73,85.36 115.73,85.54 115.66,85.61 115.66,85.71 115.97,86.03 116.13,86.03 116.2,85.95 116.31,85.95 116.54,86.18 116.54,86.31 116.48,86.36 116.48,86.54 116.85,86.91 118.82,88.12 119.5,89.21 120.07,89.56 121.36,89.88 122.98,89.49 129.33,91.01 131.42,90.51 132.15,90.51 C643.2
PCIE2_MGMT_MAC_RX0_P_R: length 3.1
  TOP w0.127: C643.1 134.1,90.56 134.93,90.56 135.01,90.64 135.93,90.64 136.05,90.52 U6.21
PCIE2_MGMT_MAC_TX0_N: length 14.6
  TOP w0.127: U6.23 136.04,89.52 135.88,89.37 134.75,89.37 134.39,89 133.18,89 128.84,90.05 126.22,89.42 124.14,88.14 123.28,88.14 C57.2
PCIE2_MGMT_MAC_TX0_P: length 14.5
  TOP w0.127: C60.2 123.28,87.88 124.21,87.88 126.32,89.17 128.84,89.77 133.15,88.74 134.5,88.74 134.86,89.1 135.94,89.1 136.02,89.02 U6.24
PCIE3_100G_C_TX_DN_0: length 98.2
  TOP w0.127: v3(117.98,79.75) 117.48,79.25 113.28,79.25 113.03,78.99 112.85,78.99 112.2,78.34 U9.D30
  S3 w0.102: v3(117.98,79.75) 117.98,79.32 117.88,79.22 116.55,79.22 115.19,77.85 115.19,74.57 116.86,72.9 119,72.9 121.84,70.05 123.87,70.05 125.04,68.88 129.46,68.88 135.38,62.96 135.38,24.02 145.28,14.12 146.21,14.12 146.45,14.37 146.45,14.88 146.56,14.99 v3(146.99,14.99)
  BOTTOM w0.127: v3(146.99,14.99) 146.49,14.48 146.49,11.75 C620.1
PCIE3_100G_C_TX_DN_1: length 101.5
  TOP w0.127: U9.C31 112.34,77.98 113.03,77.98 113.28,78.23 113.79,78.23 114.55,77.47 119.26,77.47 v3(119.76,77.97)
  S3 w0.102: v3(147.72,12.57) 148.25,12.04 148.25,11.63 148.56,11.33 149.07,11.33 150.04,12.29 150.04,20.78 147.85,22.96 140.55,22.96 137.11,26.4 137.11,67.11 132.92,71.3 125.4,71.3 124.64,72.06 123.01,72.06 121.23,73.84 121.23,76.73 120.53,77.44 119.86,77.44 119.76,77.54 v3(119.76,77.97)
  BOTTOM w0.127: v3(147.72,12.57) 148.22,12.07 148.22,11.75 C621.1
PCIE3_100G_C_TX_DN_2: length 94
  TOP w0.127: U9.D32 112.2,77.35 112.57,77.72 113.04,77.72 113.28,77.48 113.67,77.48 115.34,75.82 115.7,75.82 v3(116.2,76.32)
  S3 w0.102: v3(116.2,76.32) 116.2,75.89 116.31,75.79 117.36,75.79 119.15,73.99 119.67,73.99 120,73.99 122.7,71.3 123.16,71.3 123.99,71.3 124.83,70.46 132,70.46 136.35,66.12 136.35,25.63 140.46,21.51 146.66,21.51 147.67,20.5 147.67,17.86 v3(148.2,17.32)
  BOTTOM w0.127: v3(148.2,17.32) 147.7,16.82 147.7,16.54 148.59,15.65 151.2,15.65 151.64,15.21 151.64,14.8 C247.1
PCIE3_100G_C_TX_DN_3: length 98.1
  TOP w0.127: U9.C34 112.73,76.86 112.96,76.63 113.18,76.63 113.25,76.56 116.19,73.62 122.39,73.62 122.81,73.2 v3(122.81,73.14)
  S3 w0.102: v3(122.81,73.14) 123.25,73.58 123.25,73.58 123.35,73.69 123.91,73.69 125.03,72.57 133.82,72.57 137.67,68.72 137.67,26.64 140.53,23.77 148.02,23.77 154.74,17.06 154.74,13.67 154.64,13.56 v3(154.21,13.56)
  BOTTOM w0.127: C623.1 154.71,13.05 154.71,13.42 154.57,13.56 v3(154.21,13.56)
PCIE3_100G_C_TX_DP_0: length 98.3
  TOP w0.127: U9.B30 112.85,78.48 113.58,78.48 114.08,78.98 117.48,78.98 v3(117.98,78.48)
  S3 w0.102: v3(117.98,78.48) 117.98,78.91 117.88,79.01 116.64,79.01 115.39,77.77 115.39,74.65 116.94,73.1 119.08,73.1 121.93,70.26 123.95,70.26 125.12,69.09 129.54,69.09 135.59,63.04 135.59,24.1 136.43,23.26 136.57,23.26 136.71,23.26 136.87,23.09 136.87,22.96 136.87,22.95 136.87,22.82 137.04,22.65 137.18,22.65 137.32,22.65 137.48,22.49 137.48,22.35 137.48,22.35 137.48,22.21 137.64,22.05 137.78,22.05 137.92,22.05 138.08,21.89 138.08,21.75 138.08,21.61 138.66,21.03 138.91,21.03 139.07,20.87 139.07,20.62 139.24,20.45 139.49,20.45 139.65,20.29 139.65,20.04 139.81,19.88 140.07,19.88 140.23,19.71 140.23,19.46 140.39,19.3 140.64,19.3 140.81,19.14 140.81,18.88 140.97,18.72 141.22,18.72 141.38,18.56 141.38,18.31 141.54,18.15 141.8,18.15 141.96,17.98 141.96,17.73 142.12,17.57 142.38,17.57 142.54,17.41 142.54,17.15 142.7,16.99 142.95,16.99 143.11,16.83 143.11,16.58 143.28,16.41 143.53,16.41 143.69,16.25 143.69,16 143.85,15.84 144.11,15.84 144.27,15.68 144.27,15.42 144.43,15.26 144.68,15.26 144.85,15.1 144.85,14.84 145.36,14.33 146.13,14.33 146.25,14.45 146.25,14.88 146.15,14.99 v3(145.72,14.99)
  BOTTOM w0.127: C619.1 146.22,11.75 146.22,14.48 v3(145.72,14.99)
PCIE3_100G_C_TX_DP_1: length 101.6
  TOP w0.127: U9.A31 113.8,77.85 114.44,77.2 119.26,77.2 v3(119.76,76.7)
  S3 w0.102: v3(148.99,12.57) 148.45,12.04 148.45,11.72 148.64,11.53 148.99,11.53 149.83,12.38 149.83,13.95 149.66,14.12 149.66,14.35 149.83,14.53 149.83,14.76 149.66,14.94 149.66,15.17 149.83,15.34 149.83,15.57 149.66,15.75 149.66,15.98 149.83,16.16 149.83,16.38 149.66,16.56 149.66,16.79 149.83,16.97 149.83,17.2 149.66,17.38 149.66,17.6 149.83,17.78 149.83,18.01 149.66,18.19 149.66,18.42 149.83,18.59 149.83,18.82 149.66,19 149.66,19.23 149.83,19.41 149.83,19.64 149.66,19.81 149.66,20.04 149.83,20.22 149.83,20.69 147.77,22.76 147.46,22.76 147.25,22.56 147.02,22.56 146.82,22.76 146.59,22.76 146.39,22.56 146.16,22.56 145.96,22.76 145.73,22.76 145.53,22.56 145.3,22.56 145.09,22.76 144.87,22.76 144.66,22.56 144.43,22.56 144.23,22.76 144,22.76 143.8,22.56 143.57,22.56 143.37,22.76 143.14,22.76 142.94,22.56 142.71,22.56 142.5,22.76 142.27,22.76 142.07,22.56 141.84,22.56 141.64,22.76 141.41,22.76 141.21,22.56 140.98,22.56 140.78,22.76 140.47,22.76 136.91,26.32 136.91,67.02 132.83,71.09 125.32,71.09 124.55,71.86 122.93,71.86 121.03,73.75 121.03,76.65 120.45,77.23 119.86,77.23 119.76,77.13 v3(119.76,76.7)
  BOTTOM w0.127: C622.1 148.49,11.75 148.49,12.07 v3(148.99,12.57)
PCIE3_100G_C_TX_DP_2: length 94
  TOP w0.127: v3(116.2,75.05) 115.7,75.55 115.23,75.55 113.56,77.21 113.16,77.21 113.02,77.35 U9.B32
  S3 w0.102: v3(116.2,75.05) 116.2,75.48 116.31,75.58 117.27,75.58 119.07,73.79 119.75,73.79 119.75,73.79 119.92,73.79 122.61,71.09 123.24,71.09 123.91,71.09 124.75,70.26 131.92,70.26 136.14,66.03 136.14,25.54 140.38,21.31 140.69,21.31 140.86,21.13 141.09,21.13 141.27,21.31 141.5,21.31 141.68,21.13 141.91,21.13 142.08,21.31 142.31,21.31 142.49,21.13 142.72,21.13 142.9,21.31 143.12,21.31 143.3,21.13 143.53,21.13 143.71,21.31 143.94,21.31 144.12,21.13 144.34,21.13 144.52,21.31 144.75,21.31 144.93,21.13 145.16,21.13 145.33,21.31 145.56,21.31 145.74,21.13 145.97,21.13 146.15,21.31 146.58,21.31 146.81,21.07 146.81,20.88 146.97,20.72 147.17,20.72 147.47,20.42 147.47,20.1 147.32,19.96 147.32,19.73 147.47,19.58 147.47,19.36 147.32,19.21 147.32,18.98 147.47,18.83 147.47,18.61 147.32,18.46 147.32,18.23 147.47,18.09 147.47,17.86 v3(146.93,17.32)
  BOTTOM w0.127: v3(146.93,17.32) 147.43,16.82 147.43,16.42 148.48,15.38 151.09,15.38 151.38,15.09 151.38,14.8 C246.1
PCIE3_100G_C_TX_DP_3: length 98.1
  TOP w0.127: U9.A34 113.44,76.75 116.3,73.89 122.3,73.89 122.81,74.4 v3(122.81,74.41)
  S3 w0.102: v3(155.48,13.56) 155.05,13.56 154.94,13.67 154.94,14.1 155.05,14.2 155.05,14.5 154.94,14.61 154.94,15.52 155.05,15.62 155.05,15.92 154.94,16.02 154.94,16.33 155.05,16.43 155.05,16.73 154.94,16.84 154.94,17.14 154.67,17.42 154.67,17.56 154.45,17.77 154.31,17.77 154.09,17.99 154.09,18.17 153.93,18.33 153.76,18.33 153.59,18.49 153.59,18.67 153.43,18.83 153.25,18.83 153.04,19.05 153.04,19.19 152.82,19.41 152.68,19.41 152.46,19.62 152.46,19.76 152.25,19.98 152.11,19.98 151.89,20.2 151.89,20.34 151.67,20.55 151.53,20.55 151.31,20.77 151.31,20.91 151.1,21.13 150.96,21.13 150.43,21.65 150.43,21.8 150.22,22.01 150.07,22.01 148.11,23.98 140.61,23.98 137.87,26.72 137.87,68.81 133.91,72.77 125.11,72.77 124,73.89 123.34,73.89 v3(122.81,74.41)
  BOTTOM w0.127: C624.1 154.98,12.99 154.98,13.44 155.1,13.56 v3(155.48,13.56)
PCIE3_100G_RX_DN_0: length 100.9
  TOP w0.127: U9.J24 v4(109,80.9)
  S3 w0.102: v4(109,80.9) 109.39,81.29 109.39,81.63 109.75,81.99 113.53,81.99 114.64,80.88 114.64,73.7 116.2,72.14 117.96,72.14 120.98,69.11 123.45,69.11 134.82,57.74 134.82,23.52 149.01,9.33 150.35,9.33 150.46,9.43 150.46,9.73 150.35,9.83 v3(149.92,9.83)
  BOTTOM w0.127: CONN16.35 150.1,8.8 150.22,8.92 150.22,9.25 150.42,9.45 150.42,9.71 150.3,9.83 v3(149.92,9.83)
PCIE3_100G_RX_DN_1: length 106.8
  TOP w0.127: U9.K26 v4(108.5,80.04)
  S3 w0.102: v4(108.5,80.04) 108.92,80.04 109.32,80.45 110.16,80.45 110.21,80.39 111.38,80.39 113.41,78.36 113.41,73.58 116.18,70.82 117.58,70.82 120.45,67.94 123.32,67.94 134.06,57.2 134.06,22.23 140.03,16.26 140.03,11.13 142.6,8.56 152.48,8.56 153.12,9.2 153.12,9.98 153.02,10.09 v3(152.58,10.09)
  BOTTOM w0.127: v3(152.58,10.09) 152.96,10.09 153.09,9.96 153.09,9.6 152.9,9.41 152.5,9.41 152.22,9.13 152.22,8.92 152.1,8.8 CONN16.27
PCIE3_100G_RX_DN_2: length 118.6
  TOP w0.127: U9.J28 109.28,79.47 v4(109,79.18)
  S3 w0.102: v4(109,79.18) 109.39,79.18 109.8,78.77 111.7,78.77 112.32,78.15 112.32,73.22 116.3,69.24 117.72,69.24 121.01,65.96 121.01,63.02 122.43,61.59 125.37,61.59 133.1,53.87 133.1,20.64 138.3,15.44 138.3,9.01 140.12,7.19 156.16,7.19 157.45,5.89 157.45,3.78 156.21,2.54 152.91,2.54 152.45,2.99 152.45,3.7 152.56,3.8 v3(152.99,3.8)
  BOTTOM w0.127: CONN16.26 152.6,3.37 152.49,3.49 152.49,3.67 152.61,3.8 v3(152.99,3.8)
PCIE3_100G_RX_DN_3: length 115.2
  TOP w0.127: U9.K30 v4(108.5,78.32)
  S3 w0.102: v4(108.5,78.32) 108.82,78.32 109.22,77.93 110.89,77.93 111.38,77.44 111.38,72.99 116.73,67.64 117.62,67.64 119.99,65.27 119.99,62.15 123.05,59.08 126.59,59.08 132.33,53.34 132.33,19.45 137.11,14.67 137.11,8.59 139.7,5.99 155.67,5.99 156.64,5.02 156.64,4.09 155.85,3.3 154.77,3.3 154.45,3.62 154.45,4.6 154.56,4.7 v3(154.99,4.7)
  BOTTOM w0.127: v3(154.99,4.7) 154.61,4.7 154.49,4.57 154.49,3.49 154.6,3.37 CONN16.18
PCIE3_100G_RX_DP_0: length 100.9
  TOP w0.127: U9.F24 v4(109.99,80.9)
  S3 w0.102: v3(151.19,9.83) 150.76,9.83 150.66,9.73 150.66,9.35 150.44,9.13 148.93,9.13 134.62,23.44 134.62,57.66 123.37,68.91 120.9,68.91 117.87,71.93 116.12,71.93 114.44,73.61 114.44,80.8 113.45,81.79 109.84,81.79 109.59,81.55 109.59,81.29 v4(109.99,80.9)
  BOTTOM w0.127: v3(151.19,9.83) 150.82,9.83 150.69,9.71 150.69,9.34 150.49,9.13 150.49,8.92 150.6,8.8 CONN16.33
PCIE3_100G_RX_DP_1: length 106.8
  TOP w0.127: U9.H26 v4(109.49,80.04)
  S3 w0.102: v4(109.49,80.04) 110.22,80.04 110.36,80.19 111.29,80.19 113.21,78.27 113.21,73.5 116.09,70.61 117.49,70.61 120.36,67.74 123.23,67.74 133.86,57.12 133.86,22.14 139.83,16.17 139.83,11.04 142.51,8.36 145.78,8.36 145.91,8.23 146.14,8.23 146.27,8.36 146.5,8.36 146.62,8.23 146.85,8.23 146.98,8.36 147.21,8.36 147.33,8.23 147.56,8.23 147.69,8.36 147.92,8.36 148.05,8.23 148.27,8.23 148.4,8.36 148.63,8.36 148.76,8.23 148.99,8.23 149.11,8.36 149.34,8.36 149.47,8.23 149.7,8.23 149.82,8.36 150.05,8.36 150.18,8.23 150.41,8.23 150.53,8.36 150.76,8.36 150.89,8.23 151.12,8.23 151.25,8.36 152.56,8.36 153.32,9.12 153.32,9.98 153.42,10.09 v3(153.85,10.09)
  BOTTOM w0.127: v3(153.85,10.09) 153.48,10.09 153.35,9.96 153.35,9.49 153.01,9.14 152.61,9.14 152.49,9.02 152.49,8.92 152.6,8.8 CONN16.25
PCIE3_100G_RX_DP_2: length 118.5
  TOP w0.127: v4(109.99,79.18) 110.28,79.47 U9.F28
  S3 w0.102: v4(109.99,79.18) 110.2,78.97 111.79,78.97 112.52,78.23 112.52,73.3 116.38,69.44 117.81,69.44 121.21,66.04 121.21,63.1 122.51,61.8 125.45,61.8 133.3,53.95 133.3,20.73 138.51,15.52 138.51,9.09 140.21,7.39 156.24,7.39 157.66,5.98 157.66,3.7 156.29,2.34 152.82,2.34 152.25,2.91 152.25,3.7 152.15,3.8 v3(151.72,3.8)
  BOTTOM w0.127: v3(151.72,3.8) 152.09,3.8 152.22,3.67 152.22,3.49 152.1,3.37 CONN16.28
PCIE3_100G_RX_DP_3: length 115.2
  TOP w0.127: U9.H30 v4(109.49,78.32)
  S3 w0.102: v4(109.49,78.32) 109.69,78.13 110.97,78.13 111.58,77.52 111.58,73.08 116.81,67.84 117.7,67.84 120.19,65.35 120.19,62.23 123.14,59.28 126.68,59.28 132.54,53.42 132.54,19.53 137.31,14.76 137.31,8.67 139.78,6.2 155.75,6.2 156.84,5.11 156.84,4.01 155.94,3.1 154.69,3.1 154.25,3.53 154.25,4.6 154.15,4.7 v3(153.72,4.7)
  BOTTOM w0.127: CONN16.20 154.1,3.37 154.22,3.49 154.22,4.57 154.09,4.7 v3(153.72,4.7)
PCIE3_100G_TX_DN_0: length 3.2
  BOTTOM w0.127: C620.2 146.49,10.09 146.49,8.92 146.6,8.8 CONN16.49
PCIE3_100G_TX_DN_1: length 3.2
  BOTTOM w0.127: CONN16.43 148.1,8.8 148.22,8.92 148.22,10.09 C621.2
PCIE3_100G_TX_DN_2: length 16.5
  TOP w0.127: v3(150.99,4.7) 150.61,4.7 150.49,4.83 150.49,5.32 148.79,7.01 148.79,10.82 149.11,11.14 151.24,11.14 151.56,11.46 151.56,11.91 151.71,12.06 v3(152.15,12.06)
  BOTTOM w0.127: CONN16.34 150.6,3.37 150.49,3.49 150.49,4.57 150.61,4.7 v3(150.99,4.7) ; v3(152.15,12.06) 151.89,12.06 151.65,12.31 151.65,13.15 C247.2
PCIE3_100G_TX_DN_3: length 4.6
  BOTTOM w0.127: C623.2 154.69,11.1 154.69,9.6 154.22,9.13 154.22,8.92 154.1,8.8 CONN16.19
PCIE3_100G_TX_DP_0: length 3.2
  BOTTOM w0.127: CONN16.51 146.1,8.8 146.22,8.92 146.22,10.09 C619.2
PCIE3_100G_TX_DP_1: length 3.2
  BOTTOM w0.127: CONN16.41 148.6,8.8 148.49,8.92 148.49,10.09 C622.2
PCIE3_100G_TX_DP_2: length 16.5
  TOP w0.127: v3(150.88,12.06) 151.1,12.06 151.3,11.87 151.3,11.57 151.13,11.4 150.64,11.4 150.49,11.56 150.24,11.56 150.08,11.4 149,11.4 148.53,10.93 148.53,6.9 150.22,5.21 150.22,4.83 150.09,4.7 v3(149.72,4.7)
  BOTTOM w0.127: v3(149.72,4.7) 150.09,4.7 150.22,4.57 150.22,3.49 150.1,3.37 CONN16.36 ; v3(150.88,12.06) 151.13,12.06 151.38,12.32 151.38,13.13 C246.2
PCIE3_100G_TX_DP_3: length 4.6
  BOTTOM w0.127: C624.2 154.95,11.12 154.95,9.49 154.49,9.02 154.49,8.92 154.6,8.8 CONN16.17
PCIE_BMM_RX_N: length 190.7
  TOP w0.127: v3(115.49,90.95) 115.99,90.45 115.99,90.2 115.33,89.55 114.57,89.55 112.77,87.75 U9.C9
  S10 w0.102: v3(115.49,90.95) 115.92,90.95 116.02,91.05 116.02,91.82 115.43,92.41 114.02,92.41 113.36,93.07 113.36,102.18 114.02,102.84 114.02,109.12 113.59,109.55 112.75,109.55 111.25,111.05 108.53,111.05 103.99,115.6 103.99,118.71 100.75,121.95 34.75,121.95 33.71,120.9 13.69,120.9 10.26,117.47 10.26,90.83 20.22,80.87 24.46,80.87 24.92,80.42 24.92,78.27 24.29,77.65 23.65,77.65 23.57,77.57 23.47,77.57 v3(23.34,77.44)
  BOTTOM w0.127: CONN14.5 23.31,77.48 v3(23.34,77.44)
PCIE_BMM_RX_P: length 190.7
  TOP w0.127: v3(116.76,90.95) 116.26,90.45 116.26,90.09 115.44,89.28 114.68,89.28 113.31,87.91 113.31,87.88 U9.A9
  S10 w0.102: v3(23.34,78.13) 23.47,78 23.57,78 23.73,77.85 24.21,77.85 24.71,78.36 24.71,78.59 24.59,78.72 24.59,78.94 24.71,79.07 24.71,79.3 24.59,79.43 24.59,79.65 24.71,79.78 24.71,80.33 24.38,80.67 20.14,80.67 10.06,90.75 10.06,117.56 13.61,121.11 33.62,121.11 34.66,122.15 100.84,122.15 104.19,118.8 104.19,115.68 108.62,111.25 111.34,111.25 112.83,109.75 113.67,109.75 114.22,109.2 114.22,102.76 113.56,102.1 113.56,93.15 114.1,92.61 115.52,92.61 116.22,91.9 116.22,91.05 116.33,90.95 v3(116.76,90.95)
  BOTTOM w0.127: CONN14.3 23.29,78.08 v3(23.34,78.13)
PCIE_BMM_TX_C_N: length 208.5
  TOP w0.127: U9.R16 v4(107.02,84.33)
  S10 w0.102: v3(26.4,75.35) 26.4,75.78 26.3,75.88 25.66,75.88 25.25,76.29 25.25,77.12 26.21,78.09 26.21,81.55 25.67,82.09 19.75,82.09 11.05,90.8 11.05,117.14 14.22,120.32 33.99,120.32 35.13,121.46 98.86,121.46 103.02,117.3 103.02,114.73 107.9,109.86 110.24,109.86 111.81,108.28 111.81,106.02 111.25,105.46 111.25,102.32 112.19,101.38 112.19,95.5 111.35,94.67 111.35,90.63 110.67,89.94 108.46,89.94 107.82,90.58 107.82,92.05 106.73,93.14 102.42,93.14 102.01,92.73 102.01,91.08 102.39,90.7 103.45,90.7 108.94,85.22 108.94,84.2 108.69,83.95 107.4,83.95 v4(107.02,84.33)
  BOTTOM w0.127: C354.1 v3(26.4,75.35)
PCIE_BMM_TX_C_P: length 208.5
  TOP w0.114: U9.N16 v4(108.01,84.33)
  S10 w0.102: v3(26.4,76.62) 26.4,76.18 26.3,76.08 25.75,76.08 25.45,76.38 25.45,77.04 26.42,78 26.42,78.23 26.57,78.38 26.57,78.61 26.42,78.77 26.42,78.99 26.57,79.15 26.57,79.38 26.42,79.53 26.42,79.76 26.57,79.91 26.57,80.14 26.42,80.29 26.42,80.52 26.57,80.67 26.57,80.9 26.42,81.05 26.42,81.64 25.76,82.3 25.47,82.3 25.24,82.52 25.01,82.52 24.78,82.3 24.56,82.3 24.33,82.52 24.1,82.52 23.87,82.3 23.64,82.3 23.41,82.52 23.18,82.52 22.96,82.3 22.73,82.3 22.5,82.52 22.27,82.52 22.04,82.3 21.81,82.3 21.58,82.52 21.36,82.52 21.13,82.3 20.9,82.3 20.67,82.52 20.44,82.52 20.21,82.3 19.84,82.3 19.51,82.62 19.51,82.85 19.35,83.01 19.12,83.01 18.96,83.17 18.96,83.4 18.8,83.56 18.57,83.56 18.41,83.73 18.41,83.95 18.25,84.12 18.02,84.12 17.86,84.28 17.86,84.5 17.7,84.67 17.47,84.67 17.31,84.83 17.31,85.06 17.14,85.22 16.92,85.22 16.75,85.38 16.75,85.61 16.59,85.77 16.36,85.77 11.25,90.88 11.25,117.06 14.31,120.12 34.07,120.12 35.21,121.26 98.77,121.26 102.82,117.21 102.82,114.65 107.81,109.65 110.15,109.65 111.61,108.2 111.61,106.1 111.05,105.55 111.05,102.23 111.99,101.3 111.99,95.59 111.15,94.75 111.15,90.71 110.58,90.14 108.54,90.14 108.03,90.66 108.03,92.13 106.82,93.34 102.34,93.34 101.8,92.81 101.8,91 102.3,90.5 103.37,90.5 108.74,85.13 108.74,84.29 108.6,84.15 108.19,84.15 v4(108.01,84.33)
  BOTTOM w0.127: C340.1 v3(26.4,76.62)
PCIE_BMM_TX_N: length 3.4
  BOTTOM w0.127: C354.2 24.24,75.85 22.99,75.85 22.82,75.68 CONN14.11
PCIE_BMM_TX_P: length 3.4
  BOTTOM w0.127: CONN14.9 22.82,76.28 22.99,76.11 24.24,76.11 C340.2
PCIE_CLK_B2B_CONN_N: length 165.4
  TOP w0.127: R1092.1 130.76,97.18 131.13,97.56 131.75,97.56 R1095.2 132.41,97.56 132.78,97.56 132.91,97.43 v3(132.91,97.09)
  S10 w0.102: v3(144.99,4.04) 144.57,4.04 144.47,3.94 144.47,3.45 144.21,3.2 143.1,3.2 142.67,3.63 142.67,5.73 143.16,6.22 145.74,6.22 147.8,8.28 157.28,8.28 159.24,10.24 163.6,10.24 165.76,12.4 165.76,16 166.85,17.09 166.85,24.38 173.94,31.47 173.94,35.28 175.29,36.63 175.29,39.21 180.26,44.19 180.26,54.89 178.97,56.18 178.97,76.3 174.68,80.59 170.18,80.59 169.67,80.09 167.65,80.09 166.4,81.33 163.07,81.33 155.37,89.03 155.37,93.5 151.79,97.08 134.7,97.08 134.17,97.61 133.01,97.61 132.91,97.51 v3(132.91,97.09)
  BOTTOM w0.127: CONN16.58 144.6,3.41 144.52,3.49 144.52,3.91 144.64,4.04 v3(144.99,4.04)
PCIE_CLK_B2B_CONN_P: length 165
  TOP w0.127: R1093.1 130.76,98.27 131.13,97.89 131.75,97.89 R1094.2 132.41,97.89 132.78,97.89 132.91,98.02 v3(132.91,98.36)
  S10 w0.102: v3(143.72,4.04) 144.14,4.04 144.24,3.94 144.24,3.55 144.12,3.43 143.2,3.43 142.9,3.73 142.9,5.64 143.26,5.99 145.84,5.99 147.9,8.05 157.38,8.05 159.33,10.01 163.7,10.01 165.99,12.3 165.99,15.91 167.08,17 167.08,24.29 174.17,31.38 174.17,35.19 175.51,36.53 175.51,39.12 180.49,44.09 180.49,54.98 179.2,56.28 179.2,76.4 174.77,80.82 170.09,80.82 169.58,80.31 167.74,80.31 166.5,81.56 163.17,81.56 155.6,89.13 155.6,93.59 151.89,97.31 134.8,97.31 134.26,97.84 133.01,97.84 132.91,97.94 v3(132.91,98.36)
  BOTTOM w0.127: v3(143.72,4.04) 144.06,4.04 144.19,3.91 144.19,3.49 144.1,3.41 CONN16.60
PCIE_CLK_BMM_N: length 177.6
  TOP w0.127: R144.1 v3(106.76,96.78)
  S10 w0.102: v3(27.46,71.49) 27.46,71.93 27.56,72.03 27.97,72.03 28.88,72.94 28.88,83.12 27.24,84.76 20.02,84.76 13.06,91.73 13.06,115.74 15.78,118.47 51.46,118.47 52.88,119.89 95.61,119.89 98.65,116.84 98.65,115.77 102.9,111.53 102.9,110.77 103.91,109.75 104.67,109.75 108.18,106.25 108.18,99.09 107.92,98.83 107.77,98.83 107.72,98.88 107.57,98.88 107.28,98.6 107.28,98.45 107.34,98.39 107.34,98.25 107.14,98.05 107.14,97.15 v3(106.76,96.78)
  BOTTOM w0.127: v3(27.46,71.49) 26.96,72 25.82,72 23.77,74.05 22.99,74.05 22.82,73.88 CONN14.17
PCIE_CLK_BMM_P: length 177.6
  TOP w0.127: R145.1 v3(107.72,96.78)
  S10 w0.102: v3(107.72,96.78) 107.34,97.15 107.34,97.96 108.38,99 108.38,106.33 104.76,109.96 104,109.96 103.1,110.85 103.1,111.62 98.86,115.86 98.86,116.92 95.69,120.09 52.8,120.09 51.38,118.67 15.69,118.67 12.85,115.83 12.85,91.64 19.94,84.56 27.15,84.56 28.68,83.03 28.68,73.03 27.88,72.23 27.56,72.23 27.46,72.33 v3(27.46,72.76)
  BOTTOM w0.127: CONN14.15 22.82,74.48 22.99,74.31 23.88,74.31 25.93,72.26 26.96,72.26 v3(27.46,72.76)
PCIE_CLK_MAC_N: length 21.2
  TOP w0.102: v3(131.06,88.37) 130.57,87.88 130.57,87.41 130.87,87.11 131.87,87.11 C704.2
  BOTTOM w0.102: v3(131.06,88.37) 130.57,87.88 130.57,87.44 129.83,86.7 129.49,86.7 128.82,86.86 127.92,87.42 126.45,89.8 125.68,90.27 124.06,90.95 121.13,91.65 119.5,92.65 118.72,93.92 118.66,93.99 118,94.15 117.78,94.15 R509.1
PCIE_CLK_MAC_N_R: length 3.8
  TOP w0.102: U6.25 136.04,88.52 135.94,88.42 135.45,88.42 134.14,87.11 133.82,87.11 C704.1
PCIE_CLK_MAC_P: length 21.2
  TOP w0.102: v3(129.79,88.37) 130.29,87.87 130.29,87.29 130.75,86.83 131.87,86.83 C703.2
  BOTTOM w0.102: R508.1 117.73,94.43 118.08,94.43 118.82,94.24 118.95,94.09 119.71,92.85 121.24,91.91 124.14,91.22 125.69,90.57 125.7,90.57 125.79,90.54 126.66,90 128.12,87.62 128.93,87.12 129.52,86.98 129.71,86.98 130.29,87.56 130.29,87.88 v3(129.79,88.37)
PCIE_CLK_MAC_P_R: length 3.9
  TOP w0.102: U6.26 136.02,88.02 135.9,88.14 135.56,88.14 134.25,86.83 133.82,86.83 C703.1
PCIE_CLK_R_B2B_CONN_N: length 30.1
  TOP w0.114: v4(106.76,91.87) U9.R2
  TOP w0.127: R1092.2 129.44,97.56 128.99,97.56 128.86,97.43 128.86,95.1 128.99,94.97 v3(129.33,94.97)
  S8 w0.102: v4(106.76,91.87) 106.9,91.74 107.04,91.74 107.27,91.97 109.13,91.97 113.09,95.94 116.51,95.94 117.12,95.33 120.85,95.33 121.39,95.86 128.39,95.86 128.81,95.44 128.81,95.07 128.91,94.97 v3(129.33,94.97)
PCIE_CLK_R_B2B_CONN_P: length 30.7
  TOP w0.127: R1093.2 129.44,97.89 128.85,97.89 128.53,97.57 128.53,95.1 128.41,94.97 v3(128.06,94.97) ; v4(107.26,91.41) 107.26,91.21 106.76,90.71 U9.R4
  S8 w0.102: v3(128.06,94.97) 128.48,94.97 128.58,95.07 128.58,95.34 128.3,95.63 121.48,95.63 120.95,95.1 117.02,95.1 116.42,95.71 113.18,95.71 109.22,91.74 107.37,91.74 107.26,91.64 v4(107.26,91.41)
PCIE_CLK_R_BMM_N: length 6.8
  TOP w0.127: R144.2 107.11,94.72 107.11,93.88 106.64,93.41 106.33,93.41 106.21,93.54 106.21,94.11 106.08,94.23 105.7,94.23 105.57,94.11 105.57,93.54 105.44,93.41 104.94,93.41 104.51,92.98 104.51,92.17 U9.Y1
PCIE_CLK_R_BMM_P: length 6.8
  TOP w0.127: R145.2 107.37,94.72 107.37,93.77 106.75,93.14 105.05,93.14 104.78,92.87 104.78,91.82 104.42,91.47 104.42,90.85 U9.Y3
PCIE_CLK_R_MAC_N: length 14
  TOP w0.102: U9.U2 105.84,91.28 105.84,91.96 106.26,92.38 107.54,92.38 109.34,94.17 111.15,94.17 111.28,94.05 111.28,93.74 111.4,93.61 111.78,93.61 111.91,93.74 111.91,94.03 112.05,94.17 112.42,94.17 112.55,94.05 112.55,93.74 112.67,93.61 113.05,93.61 113.18,93.74 113.18,94.01 113.34,94.17 114.72,94.17 v3(115.27,93.63)
  BOTTOM w0.102: R509.2 115.29,93.61 v3(115.27,93.63)
PCIE_CLK_R_MAC_P: length 14.1
  TOP w0.102: v3(115.27,94.9) 114.82,94.45 109.22,94.45 107.43,92.66 106.14,92.66 105.56,92.08 105.56,91.79 105.32,91.55 105.32,91.15 105.77,90.69 U9.U4
  BOTTOM w0.102: v3(115.27,94.9) 115.29,94.93 R508.2
PCIE_OOB_RX_N: length 104.9
  TOP w0.127: U9.D10 112.22,87.25 112.56,86.91 112.85,86.91 112.99,87.05 114.24,87.05 v3(114.43,86.87)
  S10 w0.102: v3(144.98,11.25) 144.55,11.25 144.45,11.35 144.45,13.26 134.54,23.16 134.54,67.49 133.07,68.96 127.36,68.96 124.74,71.58 124.74,81.87 120.68,85.93 114.25,85.93 113.44,86.74 113.44,87.1 113.74,87.4 114.33,87.4 114.43,87.3 v3(114.43,86.87)
  BOTTOM w0.127: CONN16.57 144.6,8.8 144.49,8.92 144.49,10.75 v3(144.98,11.25)
PCIE_OOB_RX_P: length 105
  TOP w0.127: U9.B10 112.81,87.25 112.88,87.32 113.99,87.32 114.43,87.76 v3(114.43,88.14)
  S10 w0.102: v3(114.43,88.14) 114.43,87.71 114.33,87.6 113.66,87.6 113.23,87.18 113.23,86.66 114.16,85.72 120.6,85.72 124.54,81.79 124.54,71.49 127.27,68.76 132.99,68.76 134.34,67.4 134.34,23.08 142.39,15.03 142.39,14.81 142.55,14.65 142.77,14.65 142.93,14.49 142.93,14.27 143.1,14.1 143.32,14.1 143.48,13.94 143.48,13.72 143.64,13.56 143.86,13.56 144.25,13.17 144.25,11.35 144.15,11.25 v3(143.71,11.25)
  BOTTOM w0.127: v3(143.71,11.25) 144.22,10.75 144.22,8.92 144.1,8.8 CONN16.59
PCIE_OOB_TX_C_N: length 101.2
  TOP w0.127: U9.T18 v4(106.52,83.47)
  S10 w0.102: v4(106.52,83.47) 106.96,83.03 112.41,83.03 113.56,81.89 120.31,81.89 120.9,81.3 120.9,73.45 126.59,67.77 130.71,67.77 133.63,64.85 133.63,21.35 139.88,15.1 139.88,11.86 140.67,11.07 141.43,11.07 141.91,11.55 141.91,12.4 142.01,12.5 v3(142.44,12.5)
  BOTTOM w0.127: C245.1 141.95,11.8 141.95,12.23 142.21,12.5 v3(142.44,12.5)
PCIE_OOB_TX_C_P: length 101.2
  TOP w0.114: U9.P18 v4(107.51,83.47)
  S10 w0.102: v4(107.51,83.47) 107.75,83.24 112.5,83.24 113.64,82.09 120.4,82.09 121.11,81.38 121.11,73.53 126.67,67.97 130.79,67.97 133.83,64.93 133.83,21.44 135.03,20.24 135.34,20.24 135.5,20.08 135.5,19.77 135.66,19.61 135.96,19.61 136.13,19.45 136.13,19.14 136.29,18.98 136.59,18.98 136.75,18.82 136.75,18.52 136.92,18.35 137.22,18.35 137.38,18.19 137.38,17.89 137.54,17.73 137.85,17.73 138.01,17.56 138.01,17.26 138.17,17.1 138.48,17.1 138.64,16.94 138.64,16.63 138.8,16.47 139.11,16.47 139.27,16.31 139.27,16 139.43,15.84 139.73,15.84 139.9,15.68 139.9,15.37 140.08,15.19 140.08,11.95 140.75,11.28 141.34,11.28 141.7,11.64 141.7,12.4 141.6,12.5 v3(141.17,12.5)
  BOTTOM w0.127: C244.1 141.68,11.83 141.68,12.19 141.38,12.5 v3(141.17,12.5)
PCIE_OOB_TX_N: length 3.2
  BOTTOM w0.127: C245.2 141.99,10.09 141.99,8.92 142.1,8.8 CONN16.67
PCIE_OOB_TX_P: length 3.3
  BOTTOM w0.127: CONN16.69 141.6,8.8 141.72,8.92 141.72,9.97 C244.2
PCIE_RST_N: length 386.7
  TOP w0.114: v2(165.89,86.87) 166.3,86.45 Q5.G ; v2(138.84,21.82) 138.84,14.58 137.19,12.93 137.19,11.56 137.19,10.9 137.19,10.89 137.19,10.21 137.18,10.2 137.18,9.71 137.19,9.71 137.19,8.71 138.2,7.7 139.42,7.7 140.46,6.65 140.46,5.18 140.34,5.05 140.34,4.23 v3(140.82,3.74) ; U12.P4 v3(191.09,48.61)
  S3 w0.102: v2(98.16,15.54) 98.16,15.53 96.33,15.53 93.88,13.08 87.82,13.08 86.24,11.51 79.36,11.51 78.8,10.95 73.65,10.95 72.12,9.42 71.64,9.42 70.5,8.28 70.12,8.28 70.12,8.29 62.86,8.29 61.77,9.37 60.4,9.37 60.25,9.53 59.61,9.53 58.95,10.19 58.08,10.19 57.09,11.18 52.16,11.18 51.9,11.43 51.26,11.43 49.66,13.03 47.87,13.03 47.57,13.34 33.78,13.34 32.29,14.83 25.47,14.83 25.03,14.38 20.88,14.38 19.67,15.6 18.09,15.6 17.3,16.38 15.61,16.38 15.35,16.12 14.97,16.12 14.97,16.13 9.78,16.13 5.87,20.04 5.87,23.23 5.26,23.84 5.26,23.84 4.06,25.03 4.06,68.02 7.77,71.73 19.17,71.73 v2(20.12,72.68) ; v2(177.03,26.91) 179.64,26.91 188.49,35.76 188.49,38.61 189.56,39.67 189.56,48.69 189.99,49.12 190.57,49.12 v3(191.09,48.61)
  S5 w0.102: v2(165.89,86.87) 171.86,86.87 181.53,77.19 181.53,67.77 181.86,67.44 181.86,66.28 180.99,65.41 180.77,65.41 178.97,63.6 178.97,59.16 180.29,57.84 180.29,40.92 182.93,38.28 182.93,32.81 v2(177.03,26.91)
  S8 w0.102: v2(98.16,15.54) 98.5,15.54 100.46,17.5 104.72,17.5 105.02,17.81 108.64,17.81 111.86,21.03 114.53,21.03 115.01,21.51 121.62,21.51 121.93,21.82 v2(138.84,21.82) 147.95,21.82 150.36,24.23 168.84,24.23 170.49,25.88 176.01,25.88 177.03,26.9 v2(177.03,26.91)
  BOTTOM w0.114: v3(140.82,3.74) 140.82,3.73 140.82,3.53 140.6,3.32 CONN16.74 ; v2(20.12,72.68) CONN14.21 22.87,72.68 23.42,72.14 v1(24.51,72.14)
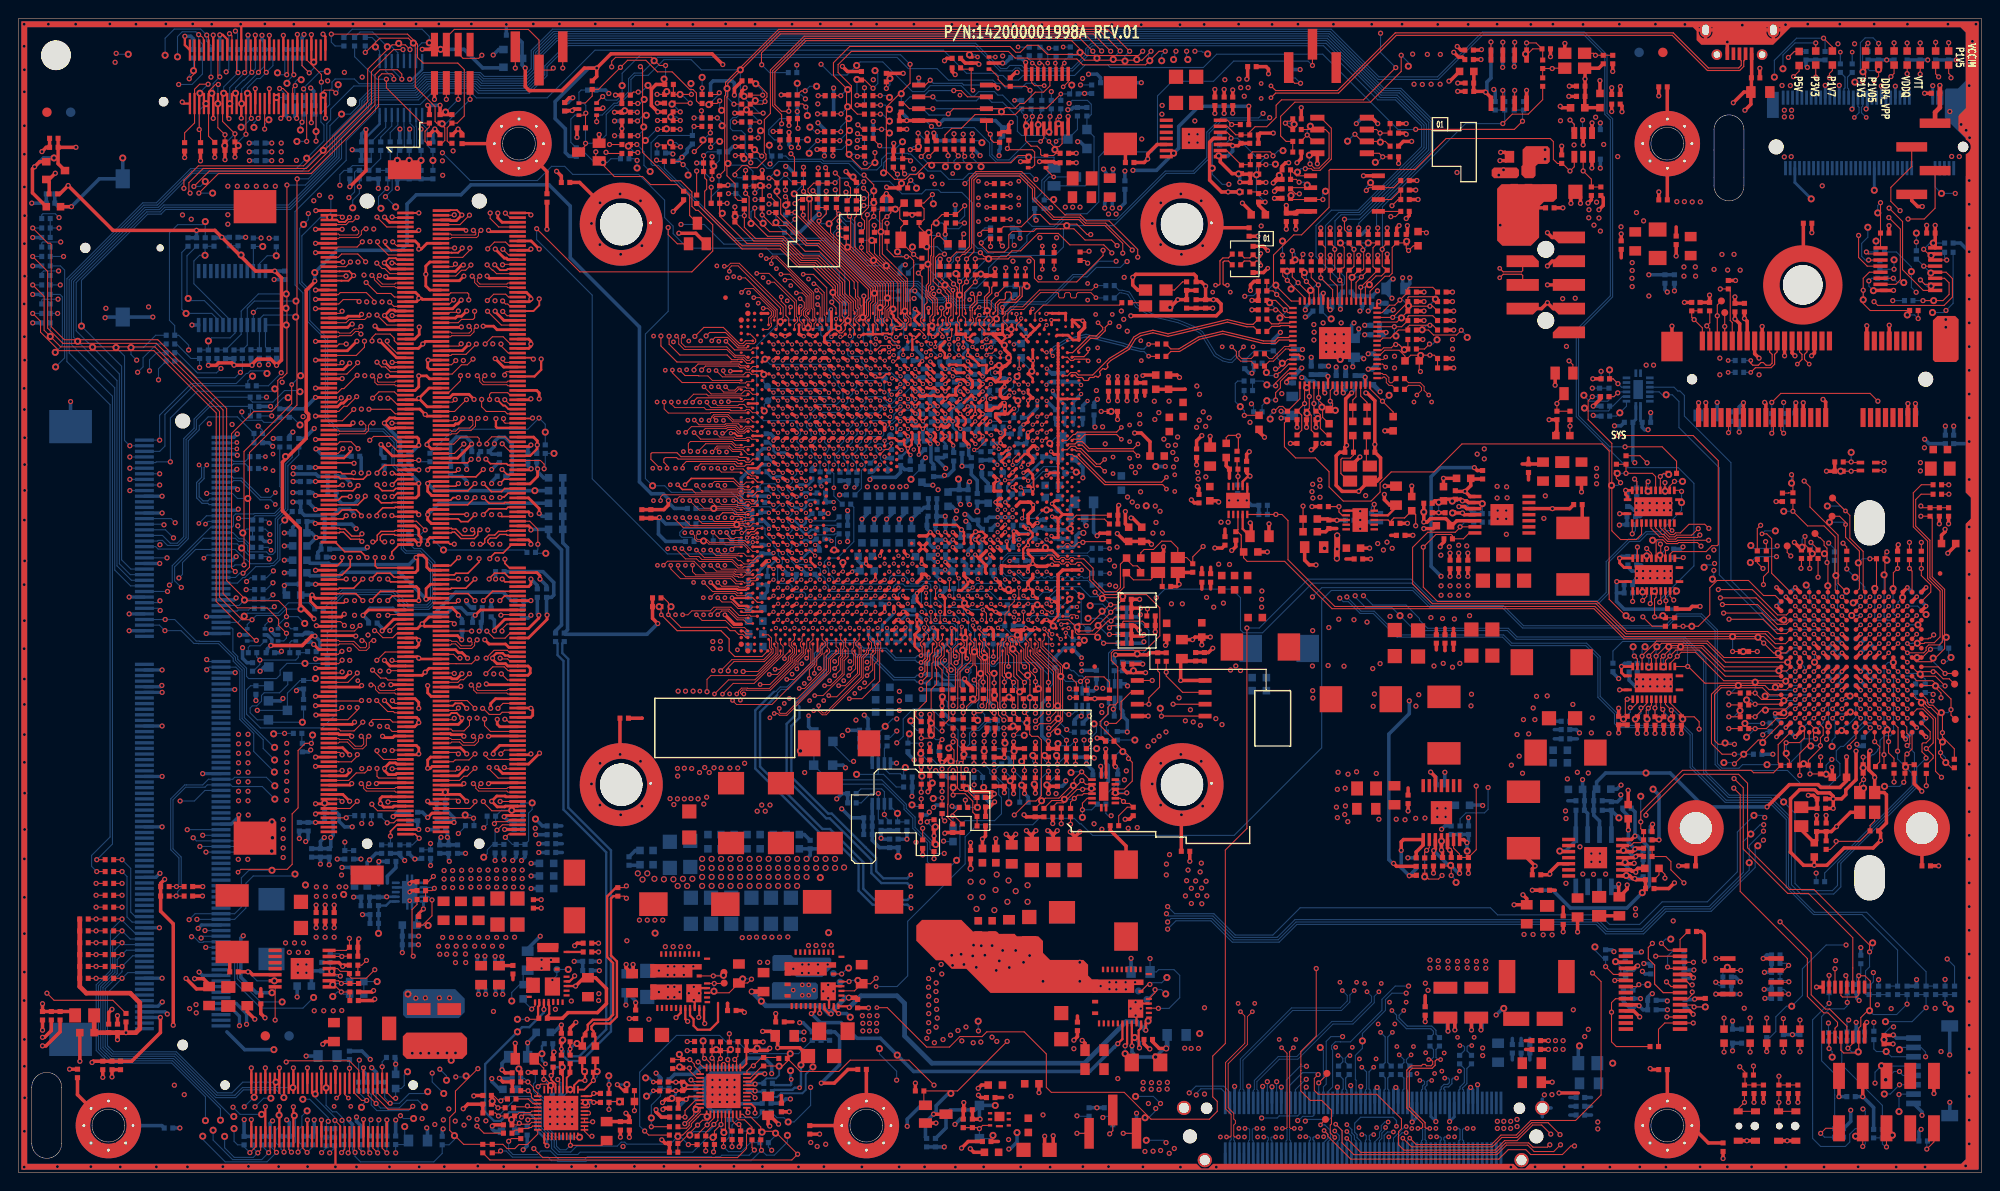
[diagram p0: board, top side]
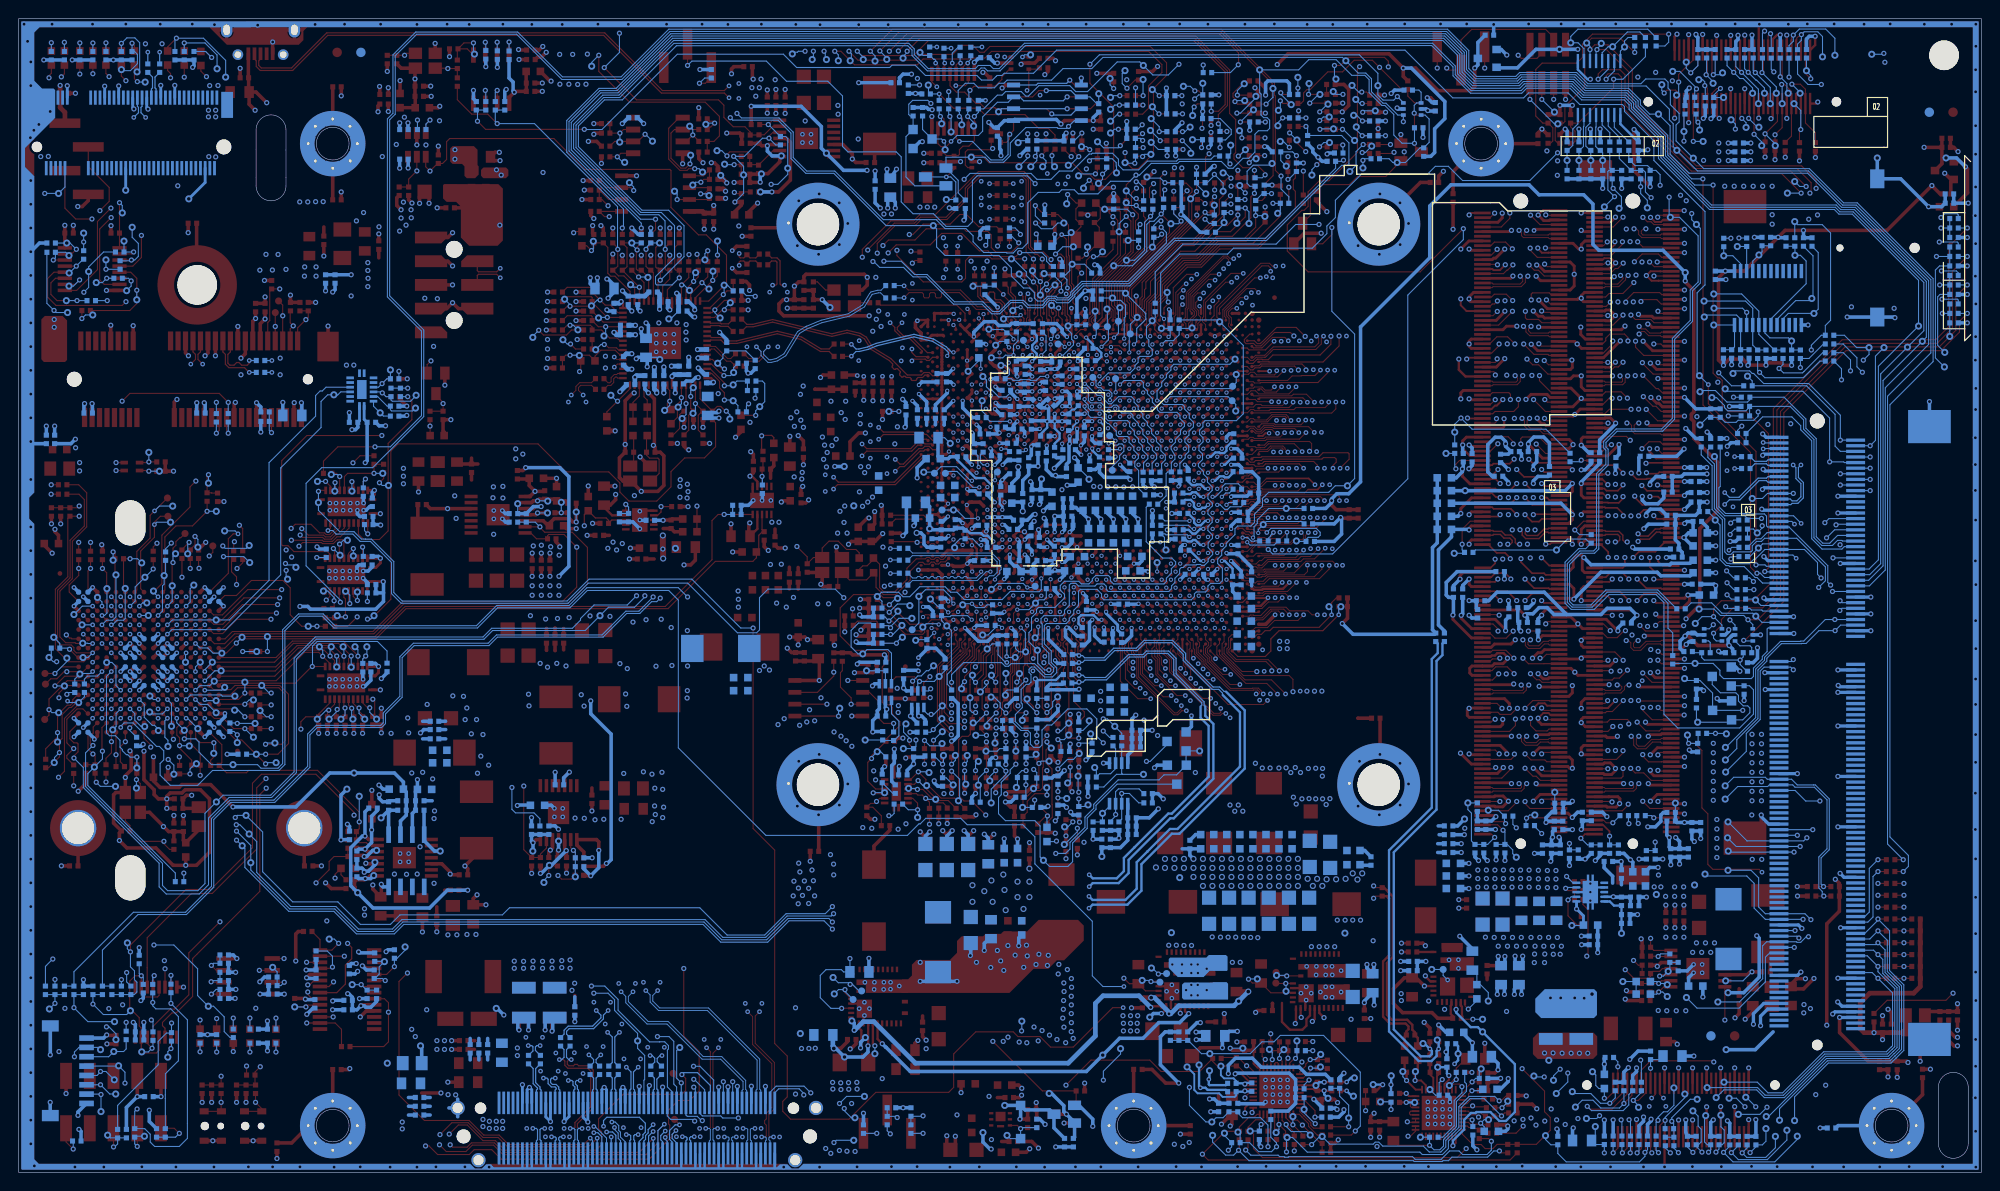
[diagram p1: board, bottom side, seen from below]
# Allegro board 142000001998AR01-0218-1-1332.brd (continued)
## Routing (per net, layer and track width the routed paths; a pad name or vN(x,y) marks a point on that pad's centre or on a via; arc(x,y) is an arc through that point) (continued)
PD_BDX_SPARE1: length 25.6
  TOP w0.108: U9.AC64 102.93,63.16 102.62,63.47 v4(102.62,63.52)
  TOP w0.114: R289.1 100.83,42.46 v2(100.83,43.78) 101.06,44 R263.2
  S10 w0.102: v2(100.83,43.78) 100.83,44.65 101.65,45.47 101.65,50.8 101.68,50.83 101.68,52.79 102.03,53.15 102.03,54.03 101.83,54.23 101.83,55.37 101.5,55.7 101.5,59.41 101.14,59.77 101.14,62.38 102.28,63.52 v4(102.62,63.52)
  BOTTOM w0.114: v2(100.83,43.78) 100.59,44.02 v1(99.75,44.02)
PD_BDX_SPARE2: length 14.5
  TOP w0.114: U9.AN78 98.35,55.35 98.09,55.09 98.09,53.98 98.22,53.85 98.22,52.27 97.63,51.69 97.63,49.53 97.95,49.21 97.95,46.64 97.79,46.48 v2(96.57,46.48) 96.57,46.48 R258.1
  BOTTOM w0.114: v2(96.57,46.48) R616.2 96.14,47.3 95.45,47.98 v1(95.45,48.34)
PD_BDX_SPARE3: length 22.8
  TOP w0.108: U9.AG67 100.86,61.44 v4(100.58,61.73)
  TOP w0.114: R264.2 v2(102.21,43.73)
  S8 w0.102: v4(100.58,61.73) 100.58,60.7 100.18,60.3 100.18,59.84 100.63,59.39 100.63,59 100.43,58.8 100.43,56.08 100.97,55.55 100.97,53.8 100.46,53.29 100.46,45.49 v2(102.21,43.73)
  BOTTOM w0.114: v2(102.21,43.73) R264.2 101.45,44.45 v1(101.14,44.75)
PD_BDX_SPARE4: length 23.8
  TOP w0.108: v4(99.59,61.73) 99.87,61.44 U9.AJ67
  TOP w0.114: R266.1 v2(104.37,46.08)
  S8 w0.102: v2(104.37,46.08) 103.84,46.62 103.84,47.4 102.67,48.56 102.67,49.39 102.62,49.44 102.62,52.44 102.74,52.57 102.74,52.67 102.77,52.69 102.77,55.91 101.68,57 101.68,59.39 102.03,59.74 102.03,60.22 101.04,61.21 101.04,62.05 100.81,62.28 100.14,62.28 v4(99.59,61.73)
  BOTTOM w0.114: v1(106.5,45.09) 105.31,45.09 105.03,45.36 R266.1 v2(104.37,46.08)
PD_CPU_TSTCLK_DN: length 31.6
  TOP w0.108: v4(109.98,67.75) 110.28,67.45 U9.F54
  TOP w0.114: R274.1 114.71,45.82 114.71,46.23 v2(114.68,46.25)
  S10 w0.102: v4(109.98,67.75) 109.98,67.61 108.03,65.65 108.03,64.91 108.41,64.53 108.41,62.36 109.04,61.72 110.85,61.72 112.5,60.07 113.49,60.07 114.45,59.11 114.45,54.03 115.09,53.39 115.09,52.3 114.2,51.41 114.2,50.14 115.09,49.25 115.09,46.89 114.68,46.48 v2(114.68,46.25)
  BOTTOM w0.114: v1(115.06,48.01) 115.32,47.75 115.32,47.12 114.68,46.48 v2(114.68,46.25)
PD_CPU_TSTCLK_DP: length 30.4
  TOP w0.108: U9.J54 v4(109,67.16)
  S10 w0.102: v4(109,67.16) 107.57,65.73 107.57,62.48 107.95,62.1 107.95,61.74 108.34,61.34 108.66,61.34 108.81,61.49 110.74,61.49 112.39,59.84 113.38,59.84 114.15,59.08 114.15,53.9 114.81,53.24 114.81,52.37 113.13,50.7 113.13,47.91 114,47.05 v2(114,46.28)
  BOTTOM w0.114: v2(114,46.28) 114,45.61 R627.1 v1(115.34,45.36)
PD_CPU_TSTSTRAP0: length 5.9
  TOP w0.089: 112.99,67.03 112.63,67.03 112.35,67.31 112.06,67.31 111.71,66.96 U9.E55
  TOP w0.109: v2(113.87,67.44) 113.39,67.44 112.99,67.03
  TOP w0.114: R202.1 113.95,67.52 v2(113.87,67.44)
PD_FIVR_CLKREF: length 10.7
  TOP w0.114: R259.1 96.52,48.26 95.98,48.8 95.98,49.29 97.14,50.45 97.14,52.36 97.72,52.94 97.72,54.49 97.84,54.61 97.84,55.27 98.02,55.45 98.02,56.03 98.25,56.26 98.25,56.66 97.85,57.05 U9.AP75
PD_GPIO53: length 23.5
  TOP w0.114: U9.BT20 v4(88.2,82.62)
  BOTTOM w0.114: v1(79.85,87.05) 80.4,86.5 86.42,86.5 86.71,86.21 86.71,85.89 87.19,85.4 87.19,85.08 87.7,84.58 87.7,84.16 88.2,83.66 v4(88.2,82.62) 87.92,82.62 87.5,82.19 85.47,82.19 85.24,81.97 85.24,81.7 84.75,81.2 84.75,80.75 84.31,80.3 84.31,79.8 84.78,79.33 84.78,78.93 85.22,78.49 85.22,78.18 84.81,77.77 84.81,77.15 85.19,76.77 85.19,76.47 85.75,75.91 R554.1
PD_LAN_NCSI_CLKIN: length 6.1
  TOP w0.114: v4(103.15,60.24) 103.55,59.84 U9.AA72
  BOTTOM w0.114: v4(103.15,60.24) 101.9,60.24 v1(101.2,60.94) 100.85,61.29 100.28,61.29 100.05,61.52 R578.2
PD_N1_BB_DCMI_FRU_A0: length 3.4
  TOP w0.114: U19.1 v2(189.38,19.08)
  BOTTOM w0.114: R687.1 R677.2 188.87,19.58 v2(189.38,19.08)
PD_N1_BB_DCMI_FRU_A1: length 3.3
  TOP w0.114: U19.2 189.35,20.35 v2(189.41,20.4)
  BOTTOM w0.114: R660.1 R672.2 189.28,20.52 v2(189.41,20.4)
PD_N1_BB_DCMI_FRU_WP: length 4.4
  TOP w0.114: U19.7 v2(181.59,20.35)
  BOTTOM w0.114: v2(181.59,20.35) 181.95,19.99 R673.2 R663.1 182.35,21.47 v1(182.83,21.94)
PD_NCSI_RXD1: length 21.2
  TOP w0.108: v4(105.03,59.16) 104.74,58.86 U9.W72
  TOP w0.114: R293.1 v2(107.62,43) R268.2
  S10 w0.102: v2(107.62,43) 107.16,43.47 107.16,54.46 105.18,56.44 105.18,59 v4(105.03,59.16)
  BOTTOM w0.114: v2(107.62,43) 107.62,43.69 v1(107.31,43.99)
PD_TD_IREF: length 4.4
  TOP w0.114: U9.P11 107.06,87.15 v4(107.06,86.03)
  BOTTOM w0.114: v1(108.41,85.75) 107.26,86.89 R535.2 107.06,87 v4(107.06,86.03)
PD_TSTCLK_SC_DN: length 7
  TOP w0.114: U9.A73 114.65,58.67 116.74,60.76 v2(116.84,60.76) 117.55,60.76 R213.1
  BOTTOM w0.114: v1(115.96,61.44) 116.15,61.44 v2(116.84,60.76)
PD_TSTCLK_SC_DP: length 8.4
  TOP w0.114: U9.A74 114.88,57.96 116.85,59.93 v2(116.85,59.96) 116.88,59.96 117.32,60.4 R216.1
  BOTTOM w0.114: v2(116.85,59.96) 115.98,60.83 114.81,60.83 v1(114.65,60.67)
PE_WAKE_R_N: length 11.9
  TOP w0.102: 102.45,56.14 102.59,56.01 102.59,55.6
  TOP w0.114: R256.1 v2(101.06,49.21) 101.43,49.58 101.43,49.87 101.83,50.27 102.34,50.27 102.74,50.67 102.74,52.67 102.97,52.9 102.97,53.34 102.97,53.34 102.97,54.84 102.58,55.23 102.58,55.59 102.59,55.6 ; 102.45,56.14 102.45,56.91 U9.AD76
  BOTTOM w0.114: v2(101.06,49.21) 102.11,50.25 v1(102.11,50.67)
PE_WAKELAN_N: length 97.7
  TOP w0.114: Q4.G 70.47,99.4 69.49,100.38 v2(69.49,101.14) ; R256.2 v2(101.06,46.77)
  BOTTOM w0.114: v2(69.49,101.14) 69.49,92.18 67.06,89.74 67.06,74.27 v1(67.83,73.5) 69.12,73.5 69.82,72.8 76.25,72.8 76.91,72.14 76.91,71.32 77.77,70.46 77.77,69.57 78.16,69.19 79.58,69.19 79.86,68.91 79.86,68.28 80.8,67.34 80.8,67.06 81.28,66.57 81.28,66.07 81.71,65.63 81.71,65.18 81.2,64.67 81.2,63.32 81.48,63.04 82.47,63.04 82.75,62.76 82.75,62.38 83.01,62.13 84,62.13 84.2,61.93 84.2,61.62 84.53,61.29 93.88,61.29 94.13,61.54 94.13,61.93 94.61,62.41 96.39,62.41 96.6,62.2 96.6,60.68 97.1,60.17 97.1,59.79 97.59,59.31 97.59,59.08 97.92,58.75 100.03,58.75 100.25,58.52 100.25,56.57 99.52,55.83 99.52,54.58 98.93,54 98.93,53.49 99.39,53.04 100.25,53.04 101.31,54.09 101.65,54.09 101.89,53.85 101.89,53.51 101.68,53.3 101.68,52.47 101.92,52.24 102.19,52.24 102.74,51.69 102.74,50.26 102.61,50.13 102.61,49.75 103.36,49 103.36,48.25 102.66,47.55 R256.2 v2(101.06,46.77)
PHSFLT_VDDQ: length 4.2
  TOP w0.114: R347.1 55.54,16.38 v2(54.41,16.38)
  TOP w0.249: R347.1 55.58,16.57 55.58,17.73 55.7,17.86 QFN1.18
  BOTTOM w0.114: v1(53.37,16.38) v2(54.41,16.38)
PLD_TPM_PP: length 29.2
  TOP w0.114: U17.7 173.17,19.89 173.35,20.07 v2(173.35,20.09)
  S3 w0.102: v2(173.35,20.09) 174.47,20.09 175.62,21.23 177.14,21.23 179.71,23.8 184.1,23.8 v2(192.33,32.03)
  BOTTOM w0.114: R631.1 R954.1 172.77,19.5 v2(173.35,20.09) v1(174.32,20.09) ; R1086.2 v2(192.33,32.03)
PLD_TPM_PP_R: length 21.7
  TOP w0.114: U12.R13 201.09,47.61 201.09,45.14 v2(201.04,45.09)
  BOTTOM w0.114: R1086.1 193.24,32.04 202.6,41.4 202.6,42.68 v1(201.9,43.38) 201.04,44.25 v2(201.04,45.09)
PM_P1V7_FB: length 6
  TOP w0.381: U22.2 155.12,71.7 154.93,71.88 v2(154.48,71.88) 154.3,72.06 C160.2 152.63,72.06 R324.2 151.51,71.88 R698.1
  BOTTOM w0.114: v2(154.48,71.88) 153.42,71.88 v1(153.39,71.86)
PM_V1P1_FB: length 5.2
  TOP w0.114: U23.2 34.23,20.51 v2(34.52,20.22) C189.2 R344.1
  BOTTOM w0.114: v1(33.6,20.09) 33.73,20.22 v2(34.52,20.22) 34.73,20.42 R708.2
PM_V3P3_FB: length 5.1
  TOP w0.114: R384.2 150.44,34.26 v2(150.65,34.47) 150.93,34.75 U27.2
  BOTTOM w0.114: v2(150.65,34.47) 150.44,34.26 R748.1 C636.2 v1(150.44,31.64)
PM_V3P3A_FB: length 6.5
  TOP w0.381: U15.2 172.49,32.38 172.64,32.23 172.9,32.23 173.01,32.12 v2(173.03,32.12) 173.03,32.31 173.25,32.54 R279.2
  BOTTOM w0.381: v1(171.89,33.19) 171.89,32.92 172.57,32.23 172.9,32.23 173.01,32.12 v2(173.03,32.12) 173.03,32.31 173.27,32.56 C513.2 R629.1
PM_V5A_FB: length 9.1
  TOP w0.114: v2(134.21,108.81) 134.21,108.94 133.91,109.25 132.03,109.25 131.78,108.99 R68.1 R74.2 130.89,107.87 C24.2 129.28,109.38 U4.2
  BOTTOM w0.114: v2(134.21,108.81) 134.77,109.37 v1(135.28,109.37)
PM_VDDQ_EN_R: length 3.2
  TOP w0.114: R325.1 R319.1 44.23,30.16 v2(44.48,30.4)
  BOTTOM w0.114: v2(44.48,30.4) 44.38,30.5 U37.7
PRESENSE DETECT: length 4.6
  TOP w0.114: CONN6.51 180.15,90.4 v2(179.27,91.28) 179.02,91.54 R95.1 R96.2
PRGD_PLTRST_DIR1: length 2.8
  BOTTOM w0.114: U34.2 172.03,82.02 v1(171.32,81.31) 170.97,80.96 R542.1
PRGD_PLTRST_DIR2: length 5.5
  BOTTOM w0.114: U34.3 171.59,83.05 170.57,82.02 R541.1 170.23,81.64 170.1,81.51 167.84,81.51 v1(167.54,81.81)
PS_12V_LVIN1: length 8.7
  TOP w0.381: C195.1 v2(66.01,18.16) ; C200.1 82.85,16.1
  BOTTOM w0.381: v2(84,14.2) 83.39,14.2 C209.1 83.39,15.01 v2(84.02,15.01) ; v2(83.57,16.02) 83.92,16.02 R719.2 ; v2(64.97,17.91) 64.97,19.07 C600.1 66.01,18.34 v2(66.01,18.16)
  vias: v3(68.5,19.3) v3(69.47,19.86) v3(69.47,18.74) v3(70.15,19.86) v3(70.15,18.74) v3(70.71,19.3) v3(82.88,19.51) v3(83.85,20.06) v3(83.85,18.95) v3(84.53,20.06) v3(84.53,18.95) v3(85.09,19.51)
PS_12V_LVIN3: length 0.7
  TOP w0.381: C201.1 113.28,16.74
  vias: v2(117.6,10.03)
PS_PWR_GD: length 7.8
  TOP w0.114: U12.R3 191.06,47.64 191.06,46.51 190.55,46 189.13,46 v2(189.12,45.98) 189.1,45.97 189.1,45.94 188.93,45.76 188.93,44.65 189.46,44.12 R226.1
  BOTTOM w0.114: v1(189.13,44.86) 189.13,45.97 v2(189.12,45.98)
PS_PWROK: length 278.4
  TOP w0.114: U12.E8 v3(195.09,58.61)
  S3 w0.102: v2(17.4,62.61) 17.4,55.87 20.31,52.96 24.54,52.96 27.3,50.2 27.3,32.47 32.09,27.69 35.18,27.69 35.81,27.05 42.32,27.05 44.32,25.05 44.32,23.05 50.61,16.76 53.02,16.76 54.41,18.16 58.24,18.16 58.51,17.88 63.79,17.88 66.43,20.52 73.15,20.52 74.83,18.84 80.58,18.84 82.57,20.83 86.69,20.83 87.77,21.91 88.34,21.91 89.05,21.21 89.78,21.21 90.29,21.72 94.17,21.72 98.49,26.04 v2(122.94,26.04)
  S5 w0.102: v2(186.69,35.56) 184.76,37.49 184.76,40.51 184.38,40.89 184.38,51.87 187.63,55.12 194.13,55.12 194.69,55.67 194.69,58.21 v3(195.09,58.61)
  BOTTOM w0.114: v2(122.94,26.04) 123.83,26.92 127.57,26.92 129.86,24.64 134.87,24.64 136.78,26.54 168.78,26.54 169.8,25.53 173.86,25.53 176.28,27.94 181.1,27.94 185.8,32.64 185.8,34.67 v1(186.09,34.96) v2(186.69,35.56) ; v2(17.4,62.61) 16.68,63.33 16.68,64.81 19.75,67.88 CONN14.37 23.18,67.88 23.52,67.54 24.05,67.54 24.51,67.07 24.51,66.55 24.64,66.42 26.52,66.42 26.8,66.15 27.18,66.15 27.45,66.42 27.45,69.94 28.56,71.05 28.56,75.83 29.26,76.53 29.26,77.35 R946.2
PSHBTN_SYS_RESET_N: length 62.9
  TOP w0.114: v2(184.15,11.3) 184.71,10.74 R713.2 184.71,9.4 R714.1 C601.1 R712.2 ; U12.L14 v3(202.09,51.61)
  S8 w0.102: v3(202.09,51.61) 202.43,51.61 203.53,50.51 203.53,50.24 203.53,50.24 203.53,50.05 204.8,48.78 204.8,46.81 206.63,44.98 206.63,29.63 199.67,22.67 199.67,16.14 195.41,11.89 184.91,11.89 184.33,11.3 v2(184.15,11.3)
PU_ADR_IN_RSV: length 27.2
  TOP w0.114: U9.AD66 102.71,62.3 v4(103.02,62.6) ; R290.1 v2(104.37,42.95)
  S10 w0.102: v2(104.37,42.95) 103.78,43.54 103.78,52.96 103.17,53.57 103.17,58.47 102.92,58.72 102.84,58.72 102.51,59.05 102.51,61.01 103.02,61.51 v4(103.02,62.6)
  BOTTOM w0.114: v1(105.94,39.55) 105.94,41.02 104.37,42.59 v2(104.37,42.95) 105.14,43.71 R632.2
PU_BDX_SPARE5: length 13.3
  TOP w0.108: U9.D71 112.42,59.53 112.58,59.69 112.99,59.69 v4(113.23,59.45)
  TOP w0.114: v2(114.35,52.58) 114.22,52.45 R244.1
  S10 w0.102: v2(114.35,52.58) 113.85,53.08 113.62,53.08 113.2,53.5 113.2,55.18 113.43,55.42 113.43,59.25 v4(113.23,59.45)
  BOTTOM w0.114: v2(114.35,52.58) 113.79,53.14 113.44,53.14 112.88,53.7 112.64,53.7 v1(112.11,54.23)
PU_DSWODVREN: length 12.2
  TOP w0.114: U9.AL1 99.49,92.11 99.49,93.88 99.14,94.23 99.14,94.36 98.69,94.81 98.44,94.81 97.84,95.4 97.84,98 97.91,98.07 97.91,99.89 v3(98.4,100.38) 99.38,99.4 R127.1
  BOTTOM w0.114: v3(98.4,100.38) 98.31,100.29 97.7,100.29 v1(97.38,100.61)
PU_DSWODVREN_R: length 2.5
  TOP w0.114: R127.2 100.96,100.3 v2(101.12,100.46)
  BOTTOM w0.114: v2(101.12,100.46) 100.96,100.3 R499.1
PU_GPIO51: length 36.2
  TOP w0.114: U9.BL18 v4(90.67,83.47) ; v2(79.5,108.79) 79.1,109.19 78.94,109.19 R57.1
  S5 w0.102: v4(90.67,83.47) 90.29,83.47 89.66,84.1 89.66,84.56 89.26,84.96 89.26,85.39 89.71,85.85 89.71,86.23 90.22,86.74 90.22,87.12 90.73,87.63 90.73,88.04 91.06,88.37 91.06,91.37 90.53,91.91 90.53,92.84 89.82,93.55 89.82,93.64 85.06,98.4 83.79,98.4 80.8,101.39 80.8,104.74 80.53,105 80.16,105 79.71,105.46 79.71,106.58 80.09,106.96 80.09,107.52 79.86,107.75 79.86,108.43 v2(79.5,108.79)
  BOTTOM w0.114: v2(79.5,108.79) 79.43,108.79 v1(78.74,109.47)
PU_KR_EPHY_RBIAS: length 4.3
  TOP w0.108: U9.P56 107.01,66.6 v4(107.01,67.13)
  BOTTOM w0.114: v4(107.01,67.13) 107.24,67.13 107.93,67.82 R569.2 109.27,67.82 109.86,67.23 v1(109.86,66.88)
PU_LAN_I2C_SCL0: length 19.5
  TOP w0.114: U9.R72 106.72,58.86 v4(107.01,59.16) ; R270.1 v2(110.18,43.69)
  S10 w0.102: v4(107.01,59.16) 107.01,58.89 107.37,58.53 107.37,58.01 107.57,57.81 107.95,57.81 109.6,56.16 109.6,44.27 v2(110.18,43.69)
  BOTTOM w0.114: v1(109.78,44.63) 109.78,44.09 v2(110.18,43.69)
PU_LAN_I2C_SCL1: length 20.8
  TOP w0.114: R269.1 v2(108.79,43.68) ; v4(106.55,60.02) 106.65,60.02 106.95,59.72 U9.P71
  S10 w0.102: v2(108.79,43.68) 108.33,44.15 108.33,56.74 107.72,57.35 106.73,57.35 106.39,57.7 106.39,58.77 106.1,59.05 106.1,59.82 106.3,60.02 v4(106.55,60.02)
  BOTTOM w0.114: v1(108.51,44.63) 108.51,43.97 v2(108.79,43.68)
PU_LAN_I2C_SDA0: length 25.8
  TOP w0.108: v4(106.53,61.72) 106.53,61.11 105.96,60.55 105.96,60.19 105.53,59.75 U9.U72
  TOP w0.114: R294.1 v2(108.79,42.98)
  S10 w0.102: v4(106.53,61.72) 105.77,60.95 105.77,59.03 106.18,58.61 106.18,57.37 108.08,55.47 108.08,43.69 v2(108.79,42.98)
  BOTTOM w0.114: v2(108.79,42.98) 108.79,41.68 v1(108.66,41.55)
PU_LAN_I2C_SDA1: length 23.1
  TOP w0.114: v4(106.48,59.41) 106.17,59.72 U9.T71 ; R295.1 v2(110.18,42.95)
  S10 w0.102: v2(110.18,42.95) 109.35,43.77 109.35,56.07 107.81,57.61 107.47,57.61 107.16,57.91 107.16,58.45 106.48,59.13 v4(106.48,59.41)
  BOTTOM w0.114: v2(110.18,42.95) 109.32,42.09 109.32,39.9 v1(109.45,39.78)
PU_N1_BB_DCMI_FRU_A2: length 3.5
  TOP w0.114: U19.3 188.85,21.62 v2(189.38,22.15)
  BOTTOM w0.114: R644.2 R651.1 189.15,22.38 v2(189.38,22.15)
PU_NCSI_RXD0: length 24.4
  TOP w0.108: U9.Y71 v4(104.04,59.16)
  TOP w0.114: R292.1 v2(106.45,43.03) R267.2
  S10 w0.102: v4(104.04,59.16) 104.39,58.81 104.39,56.59 105.21,55.78 105.21,54.15 105.82,53.54 106.27,53.54 106.91,52.91 106.91,43.48 v2(106.45,43.03)
  BOTTOM w0.114: v2(106.45,43.03) 107.31,42.16 v1(107.31,41.45) 107.11,41.25 R502.1
PU_NIC1_NVM_HOLD: length 4.5
  TOP w0.114: R818.1 136.22,104.14 U39.7 v2(139.55,104.14)
  BOTTOM w0.114: v2(139.55,104.14) 139.55,104.75 v1(139.83,105.03)
PU_NIC1_NVM_WP: length 5.2
  TOP w0.114: v2(144.2,105.11) 144.5,105.41 U39.3 147.12,105.41 R817.1
  BOTTOM w0.114: v2(144.2,105.11) 144.2,105.49 v1(144.65,105.94)
PU_PCH_RI_N: length 39.6
  TOP w0.114: U9.BF11 92.45,86.9 92.67,86.9 v4(92.68,86.9) ; R24.1 v2(79.65,113.39)
  S5 w0.102: v2(79.65,113.39) 79.88,113.16 79.88,110.57 83.11,107.35 83.11,104.9 83.69,104.32 84.52,104.32 86.17,102.67 86.17,99.87 91.39,94.64 91.39,92.19 93.45,90.14 93.45,89.15 93.7,88.9 93.7,88.04 94.01,87.73 94.01,86.73 93.72,86.44 93.32,86.44 92.86,86.9 v4(92.68,86.9)
  BOTTOM w0.114: v2(79.65,113.39) 79.27,113.39 77.62,115.04 v1(77.62,115.19)
PU_PCH_SUSACK_N: length 14.5
  TOP w0.102: 92.13,99.26 92.13,98.15 94.87,95.4 94.87,91.7 95.23,91.34 95.23,91.07
  TOP w0.114: 92.13,99.26 92.13,102.85 R108.1 ; 95.23,91.07 95.02,90.86 95.02,90.36 U9.AY4
PU_PE_HP_SCL: length 32.6
  TOP w0.114: R309.1 v2(97.94,33.58) ; v4(97.09,62.03) 97.11,62.01 U9.AR67
  S10 w0.102: v4(97.09,62.03) 96.19,61.14 96.19,59.74 96.52,59.41 96.52,58.95 94.74,57.18 94.74,45.66 94.49,45.41 94.49,37.62 97.94,34.16 v2(97.94,33.58)
PU_PE_HP_SDA: length 34
  TOP w0.114: U9.AN67 v4(98.1,62.62) ; R306.1 97.44,37.75 v2(97.21,37.52)
  S10 w0.102: v2(97.21,37.52) 97.21,36.6 96.9,36.3 96.19,36.3 94.72,37.77 94.72,45.31 94.97,45.57 94.97,57 96.72,58.75 96.72,59.39 97,59.66 97,60.27 96.65,60.63 96.65,61.14 97.03,61.52 97.38,61.52 98.1,62.24 v4(98.1,62.62)
  BOTTOM w0.114: v1(98.09,36.98) 97.74,36.98 v2(97.21,37.52)
PU_PIRQA: length 49.7
  TOP w0.114: R17.2 v2(66.24,114.42) ; U9.BG20 91.87,82.9 v4(92.16,82.62)
  S3 w0.102: v4(92.16,82.62) 91.83,82.62 91.21,83.24 91.21,83.69 90.78,84.12 90.78,84.43 90.14,85.06 90.14,85.5 89.79,85.85 89.79,86.33 90.07,86.61 90.07,87.17 89.79,87.45 89.79,88.06 90.07,88.34 90.07,88.93 90.35,89.2 90.35,92.83 86.24,96.93 85.29,97.89 82.74,97.89 80.38,100.25 76.58,100.25 69.27,107.57 69.27,108.64 68.78,109.12 68.3,109.12 67.79,109.63 67.79,112.87 v2(66.24,114.42)
  BOTTOM w0.114: v1(66.93,114.85) 66.5,114.42 v2(66.24,114.42)
PU_PIRQB: length 51.1
  TOP w0.114: U9.BF22 92.37,82.04 92.4,82.01 v4(92.67,81.74) ; R23.2 v2(66.19,113.48)
  S3 w0.102: v4(92.67,81.74) 92.5,81.74 92.02,82.22 90.93,82.22 90.73,82.42 90.73,82.8 90.17,83.36 90.17,83.74 89.66,84.25 89.66,84.58 89.28,84.96 89.28,85.42 89.59,85.72 89.59,86.28 89.28,86.59 89.28,87.12 89.59,87.43 89.59,88.09 89.28,88.39 89.28,88.85 89.53,89.1 89.53,89.71 89.64,89.81 89.64,93.22 87.44,95.41 85.19,97.66 82.65,97.66 80.28,100.03 76.48,100.03 69.04,107.47 69.04,108.51 68.68,108.86 68.13,108.86 67.56,109.43 67.56,112.12 66.2,113.48 v2(66.19,113.48)
  BOTTOM w0.114: v2(66.19,113.48) 66.04,113.64 v1(64.85,113.64)
PU_PIRQC: length 30.1
  TOP w0.114: v2(96.57,108.74) 97.2,109.37 R53.2 ; v4(97.61,87.48) 97.33,87.19 U9.AR11
  S5 w0.102: v2(96.57,108.74) 96.57,108.25 96.55,108.22 96.55,105.89 93.57,102.92 93.57,101.15 92.76,100.34 92.76,96.34 92.76,96.34 92.76,92.85 94.91,90.7 97.11,90.7 98.22,89.59 98.22,88.76 98.46,88.52 98.46,88.21 97.73,87.48 v4(97.61,87.48)
  BOTTOM w0.114: v1(97.69,107.81) 97.5,107.81 v2(96.57,108.74)
PU_PIRQD: length 42
  TOP w0.114: U9.BH22 v4(91.66,81.76)
  S10 w0.102: v2(84.18,114.91) 84.68,114.4 84.68,108.72 84.63,108.67 84.63,106.08 85.45,105.27 85.45,103.94 85.17,103.66 85.17,99.44 88.31,96.3 88.31,88.32 88.58,88.06 88.58,87.54 88.31,87.27 88.31,86.57 88.58,86.3 88.58,85.76 88.21,85.39 88.21,85.04 87.81,84.64 87.81,84.02 88.19,83.64 88.19,83.31 88.62,82.88 88.62,82.49 89.11,82 89.11,81.79 89.52,81.38 91.28,81.38 v4(91.66,81.76)
  BOTTOM w0.114: v2(84.18,114.91) 83.74,115.34 R431.2 v1(83.3,116.59)
PU_SATA_RCOMP: length 60
  TOP w0.114: R5.2 v2(92.84,116.03)
  TOP w0.254: U9.BB32 94.32,77.33 v4(94.48,77.33)
  S3 w0.102: v2(92.84,116.03) 92.84,111.48 92.61,111.25 92.61,109.12 91.49,108 91.49,104.22 92.08,103.63 92.08,101.12 91.87,100.91 89.89,100.91 89.55,101.26 89.55,102.48 88.65,103.38 87.45,103.38 86.84,102.77 86.84,99.95 89.28,97.51 91.52,97.51 93.9,95.12 93.9,92.99 96.37,90.53 96.37,89.06 96.11,88.8 96.11,88.41 96.35,88.17 97.56,88.17 98.09,87.64 98.09,87.1 97.94,86.94 97.94,81.69 97.69,81.43 97.69,79.83 97,79.15 96.11,79.15 95.5,78.54 95.5,78.54 94.69,77.73 94.69,77.72 94.48,77.51 v4(94.48,77.33)
  BOTTOM w0.114: v2(92.84,116.03) 93.23,116.42 v1(93.23,117.1)
PU_SGPIO22_SATA_CLOCK: length 32.7
  TOP w0.114: v4(89.68,85.19) 89.48,85.31 U9.BN14 ; R37.1 v2(87.96,111.4)
  S10 w0.102: v2(87.96,111.4) 88.32,111.05 88.32,107.58 88.06,107.33 88.06,103.54 87.25,102.73 87.25,99.19 90.02,96.42 90.02,93.63 90.52,93.14 90.52,89.14 90.29,88.92 90.29,88.22 90.56,87.95 90.56,87.48 90.07,87 90.07,86.66 89.79,86.39 89.79,85.3 v4(89.68,85.19)
  BOTTOM w0.114: v1(88.82,112.8) 87.96,111.94 v2(87.96,111.4) R37.1
PU_SGPIO38_PCH_SLOAD_R: length 42.4
  TOP w0.114: U9.BP13 v4(89.19,86.05) ; R39.1 v2(66.24,110.97)
  S3 w0.102: v4(89.19,86.05) 89.08,86.16 89.08,87.27 88.8,87.55 88.8,87.88 88.29,88.39 88.29,88.85 88.54,89.1 88.54,89.71 88.98,90.14 88.98,90.8 89,90.82 89,93.2 85,97.2 82.46,97.2 80.11,99.55 76.29,99.55 68.32,107.52 67.82,107.52 67.11,108.24 67.11,110.11 v2(66.24,110.97)
  BOTTOM w0.114: R39.1 v2(66.24,110.97) 66.88,111.61 v1(66.88,111.91)
PU_SGPIO39_SATA_DATAOUT0: length 37.7
  TOP w0.114: R44.2 v2(74.04,109.73) ; U9.BU18 v4(87.7,83.47)
  S5 w0.102: v4(87.7,83.47) 87.7,84.44 87.27,84.86 87.27,85.42 87.6,85.75 87.6,86.23 87.25,86.59 87.25,87.15 87.6,87.5 87.6,88.06 87.22,88.44 87.22,89 87.45,89.23 87.45,90.6 86.97,91.08 86.97,91.47 85.86,92.58 85.86,93.49 85.88,93.51 85.88,94.85 85.23,95.5 85.22,95.5 84.2,96.52 83.01,96.52 79.89,99.64 79.42,99.64 78.04,101.02 77.07,101.02 73.61,104.48 73.61,106.76 74.68,107.82 74.68,109.09 v2(74.04,109.73)
  BOTTOM w0.114: v2(74.04,109.73) 74.67,110.36 v1(75.01,110.36)
PU_SGPIO48_SATA_DATAOUT1: length 33.3
  TOP w0.114: U9.BT16 v4(88.2,84.33) ; R67.2 v2(78.33,108.08)
  S5 w0.102: v4(88.2,84.33) 88.2,85.38 88.7,85.88 88.7,86.18 89.18,86.66 89.18,87.05 89.66,87.53 89.66,87.83 90.27,88.44 90.27,88.77 90.53,89.03 90.53,91.34 89.41,92.46 89.41,93.73 84.96,98.17 83.69,98.17 79.83,102.03 79.36,102.03 79.1,102.3 79.1,102.68 79.48,103.06 79.48,106.69 78.33,107.84 v2(78.33,108.08)
  BOTTOM w0.114: v2(78.33,108.08) 77.9,108.51 v1(77.6,108.51)
PU_TXT_AGENT: length 20.3
  TOP w0.108: U9.AM72 v4(98.6,60)
  TOP w0.114: R261.2 98.55,46.08 v2(98.8,46.33)
  S10 w0.102: v2(98.8,46.33) 98.25,46.88 98.25,50.83 98.68,51.26 98.68,52.48 98.02,53.14 98.02,56.54 99.44,57.96 99.44,58.7 99.49,58.75 99.49,59.36 98.85,60 v4(98.6,60)
  BOTTOM w0.114: v1(97.64,46.81) 98.13,46.33 v2(98.8,46.33) 98.47,46 R624.1
PU_TXT_PLTEN: length 25.4
  TOP w0.108: v4(97.61,59.99) 97.61,59.86 97.61,59.86 U9.AP72
  TOP w0.114: R305.2 v2(96.57,39.98)
  S10 w0.102: v2(96.57,39.98) 95.33,41.22 95.33,45.16 95.48,45.31 95.48,56.06 97.49,58.06 97.49,58.6 97.71,58.83 97.71,59.54 97.61,59.64 v4(97.61,59.99)
  BOTTOM w0.114: v1(95.58,39.33) 95.79,39.33 95.97,39.16 R305.2 v2(96.57,39.98)
PWM1_VDDQ_CH01: length 25.8
  TOP w0.203: v2(56.54,2.84) 56.24,3.15 U29.21
  TOP w0.249: QFN1.19 v2(56.2,17.44)
  BOTTOM w0.254: v2(56.2,17.44) 56.2,17.11 54.63,15.54 53.87,15.54 v1(53.37,15.04) 49.91,11.58 49.91,6.45 50.86,5.5 51.57,5.5 52.53,6.45 54.02,6.45 54.12,6.35 54.61,6.35 55.34,5.62 55.34,4.59 56.54,3.39 v2(56.54,2.84)
PWR_BTN_IN_BMC_N: length 256
  S5 w0.102: v2(122.77,3.19) 124.49,3.19 124.5,3.17 124.65,3.02 124.89,2.79 125.76,2.79 126.16,3.18 126.16,3.19 127.75,3.19 128.63,2.3 146.62,2.3 147.47,3.15 159.48,3.15 162.05,5.73 163.71,5.73 166.99,9.01 170.4,9.01 174.5,13.11 178.24,13.11 179.91,14.78 179.91,22.42 179.9,22.43 179.9,22.81 179.91,22.82 179.91,23.09 188.01,31.19 192.4,31.19 199.59,38.38 199.59,38.72 204.22,43.35 204.22,43.69 204.57,44.04 204.57,45.55 204.47,45.66 204.47,48.77 204.31,48.92 204.31,50.63 v2(204.85,51.17)
  S8 w0.102: v2(84.75,3.2) 85.04,3.2 85.19,3.35 85.67,3.35 86.4,4.08 86.4,5.29 86.4,7.33 88.23,9.16 92.85,9.16 96.08,5.94 96.08,3.42 97.62,1.88 120.22,1.88 120.32,1.78 122.27,1.78 122.64,2.15 122.64,2.23 122.77,2.36 v2(122.77,3.19)
  S10 w0.102: v2(84.75,3.2) 84.43,3.52 84.36,3.59 82.66,3.59 82.27,3.2 74.84,3.2 74.79,3.25 73.4,3.25 72.39,2.24 71.31,2.24 70.79,2.77 67.5,2.77 64.85,5.41 64.85,5.8 64.52,6.14 64.52,6.51 64.85,6.85 64.85,14.47 62,17.32 58.87,17.32 57.83,18.36 53.82,18.36 53.56,18.1 50.29,18.1 46.37,14.18 33.04,14.18 32.82,14.4 32.25,14.4 32.03,14.18 23.27,14.18 22.28,15.17 22.28,24.31 21.5,25.08 v2(19.52,25.08)
  BOTTOM w0.114: v2(204.85,51.17) 204.65,51.36 R911.2 ; CONN14.171 19.72,25.28 v2(19.52,25.08) ; v2(122.77,3.19) 122.52,3.43 v1(120.65,3.43)
PWR_BTN_IN_BMC_N_R: length 3.5
  TOP w0.114: U12.J14 v3(202.09,53.61)
  BOTTOM w0.114: v3(202.09,53.61) 202.29,53.4 203.39,53.4 v1(203.45,53.34) 204,52.79 R911.1
PWR_BTN_OUT_BMC_N: length 34.3
  TOP w0.114: R331.2 v2(11.06,25.85)
  BOTTOM w0.114: CONN14.172 11.93,24.98 v2(11.06,25.85) 10.06,24.85 10.06,21.5 8.53,19.97 8.53,13.15 9.21,12.47 9.23,12.47 9.76,11.94 16.47,11.94 21.59,6.81 v1(21.59,5.58)
PWRGD_DDR4_VPP: length 219.3
  TOP w0.114: U23.6 v2(34.58,23.11) 34.61,23.14 R337.2 ; U12.K12 v3(200.09,52.61)
  S5 w0.102: v2(120.88,7.37) 120.88,6.91 121.85,5.94 126.19,5.94 126.61,5.52 129.02,5.52 130.17,6.67 157.5,6.67 161.67,10.83 169.32,10.83 173.3,14.81 176.53,14.81 177.72,16 177.72,23.14 179.81,25.22 179.81,25.37 180.34,25.91 180.5,25.91 189.53,34.95 189.53,43.08 193.39,46.94 196.51,46.94 197.62,48.05 199.06,48.05 199.57,48.55 199.57,52.09 v3(200.09,52.61)
  S8 w0.102: v2(120.88,7.37) 120.32,7.92 114.46,7.92 110.64,11.75 96.12,11.75 95.13,12.74 92.75,12.74 92.4,12.39 89.57,12.39 89.57,12.39 86.9,12.39 86.29,11.79 84.95,11.79 84.39,11.23 82.6,11.23 80.52,9.14 80.52,6.21 79.33,5.03 78.09,5.03 76.48,6.64 73.86,6.64 73.6,6.9 70.4,6.9 69.29,5.79 67.82,5.79 67.47,6.14 65.69,6.14 65.42,6.41 65.42,6.52 65.16,6.78 64.21,6.78 63.47,6.04 62.88,6.04 62.35,6.57 61.15,6.57 59.24,8.48 55.39,8.48 55.18,8.28 54.32,8.28 53.07,9.53 49.92,9.53 48.51,10.93 48.51,13.52 46.01,16.03 42.67,16.03 35.59,23.11 v2(34.58,23.11)
  BOTTOM w0.114: R701.1 34.3,23.39 v2(34.58,23.11)
PWRGD_DDR4_VPP_LED5: length 65.1
  TOP w0.114: U12.B8 v3(195.09,61.61) ; v2(200.33,117.3) 200.67,117.63 LED5.C
  S5 w0.102: v3(195.09,61.61) 194.75,61.95 194.75,72.17 198.15,75.56 198.15,76.81 199.64,78.31 199.64,86.24 204.29,90.88 204.29,99.95 203.24,101 203.24,101.76 204.14,102.65 204.14,105.94 200.33,109.75 v2(200.33,117.3)
  BOTTOM w0.114: v1(195.58,62.23) 195.58,62.1 v3(195.09,61.61)
PWRGD_DDR4_VPP_R: length 37.8
  TOP w0.114: LED5.A v2(200.67,120.91)
  S10 w0.102: v2(181.4,96.66) 181.4,98.11 192.45,109.16 197.95,109.16 201.29,112.5 201.29,120.29 v2(200.67,120.91)
  BOTTOM w0.114: R409.2 v2(200.67,120.91)
PWRGD_P0V6_VTT_DIMM: length 220.9
  TOP w0.114: v2(44.22,29.16) 44.22,27.46 43.23,26.47 R1087.2 ; U12.K11 v3(199.09,52.61)
  S5 w0.102: v3(199.09,52.61) 198.7,52.23 198.7,49.52 198.3,49.12 197.92,49.12 197.54,48.73 197.54,48.4 196.31,47.17 192.26,47.17 191.21,46.12 191.21,45.1 189.31,43.19 189.31,35.04 180.4,26.14 180.25,26.14 179.58,25.47 179.58,25.31 177.5,23.23 177.5,16.1 176.43,15.04 173.2,15.04 169.23,11.06 161.57,11.06 157.41,6.9 139.02,6.9 138.17,7.75 130.93,7.75 128.93,5.75 126.82,5.75 125.54,7.03 125.54,7.24 125.04,7.74 123.68,7.74 122.77,6.83 v2(121.67,6.83)
  S8 w0.102: v2(121.67,6.83) 121.51,6.99 121.51,7.49 120.85,8.15 114.56,8.15 110.73,11.98 96.21,11.98 95.22,12.97 92.66,12.97 92.31,12.62 89.66,12.62 86.8,12.62 86.2,12.01 84.86,12.01 84.3,11.46 82.51,11.46 80.29,9.24 80.29,6.31 79.24,5.26 78.19,5.26 76.58,6.87 73.96,6.87 73.7,7.13 70.3,7.13 69.19,6.02 67.91,6.02 66.8,7.14 64.24,7.14 63.37,6.27 62.97,6.27 62.44,6.8 61.25,6.8 59.33,8.71 55.39,8.71 54.88,9.22 54.29,9.22 53.66,9.86 52.32,9.86 51.66,10.52 51.13,10.52 48.74,12.9 48.74,13.62 44.22,18.14 v2(44.22,29.16)
  BOTTOM w0.114: v2(121.67,6.83) 121.67,6.6 120.9,5.84 v1(120.52,5.84) ; v2(44.22,29.16) 43.88,29.5 U37.9
PWRGD_P0V6_VTT_DIMM_LED7: length 61.7
  TOP w0.114: U12.B10 v3(198.09,61.61) ; LED7.C v2(203.46,117.57)
  S5 w0.102: v3(198.09,61.61) 199.36,62.89 199.36,64.79 200.61,66.03 200.61,86.27 204.75,90.41 204.75,100.14 203.7,101.19 203.7,101.57 204.59,102.47 204.59,106.17 203.46,107.3 v2(203.46,117.57)
PWRGD_P0V6_VTT_DIMM_R: length 37.8
  TOP w0.114: LED7.A v2(203.46,120.9)
  S10 w0.102: v2(182.86,96.59) 182.86,98.92 192.64,108.7 198.14,108.7 201.75,112.31 201.75,115.91 202.74,116.89 202.74,120.18 v2(203.46,120.9)
  BOTTOM w0.114: R411.2 v2(203.46,120.9)
PWRGD_P0V9_LAN: length 11.7
  TOP w0.114: R223.2 206.8,43.31 205.64,44.48 v2(205.64,44.93) 205.64,46.15 205.36,46.43 205.36,49 204.59,49.76 204.37,49.76 204.03,50.1 204.03,50.29 203.97,50.35 203.97,50.39 203.73,50.62 203.08,50.62 U12.M15
  BOTTOM w0.114: v1(206.2,43.87) 206.17,43.89 206.17,44.4 v2(205.64,44.93)
PWRGD_P0V9_LAN1: length 5.8
  TOP w0.114: U12.A11 198.78,62.31 R185.2 v2(198.08,65.68)
  BOTTOM w0.114: v2(198.08,65.68) 197.28,65.68 v1(196.84,65.24)
PWRGD_P1V05_PCH: length 148.1
  TOP w0.114: U28.3 72.1,9.71 v2(71.93,9.88) ; U12.P8 v3(195.09,48.61)
  S3 w0.102: v2(97.37,16.02) 96.43,16.02 93.72,13.31 87.72,13.31 86.15,11.73 79.17,11.73 78.82,12.08 77.91,12.08 77.16,11.33 73.41,11.33 71.97,9.88 v2(71.93,9.88)
  S8 w0.102: v3(195.09,48.61) 195.05,48.61 194.35,47.9 193.99,47.9 193.03,46.95 192.04,46.95 191.69,46.6 191.69,45.53 186,39.84 186,33.64 186.14,33.5 186.41,33.23 186.41,32.12 181.93,27.64 176.35,27.64 174.83,26.11 170.39,26.11 168.74,24.46 150.27,24.46 148.34,22.53 122.32,22.53 121.53,21.74 114.92,21.74 114.43,21.26 111.71,21.26 108.48,18.03 104.93,18.03 104.62,17.73 100.36,17.73 100.23,17.59 98.66,16.02 v2(97.37,16.02)
  BOTTOM w0.114: v2(71.93,9.88) 72.46,9.35 R740.1
PWRGD_P1V5_PCH: length 69
  TOP w0.114: 131.06,65.79 131.44,65.41 135.46,65.41 140.53,60.34 168.55,60.34 171.78,57.12 186.25,57.12 v2(186.71,56.65) 187.77,55.6 189.08,55.6 U12.G2
  TOP w0.127: U11.3 130.46,68.81 R201.1 130.43,68.58 130.81,68.2 130.81,66.67 C102.2 131.06,66.41 131.06,65.79
  BOTTOM w0.114: v1(186.1,57.28) 186.71,56.67 v2(186.71,56.65)
PWRGD_P1V05_PCH_LED4: length 63.8
  TOP w0.114: LED4.C 199.02,117.35 v2(198.53,116.87) ; U12.B7 v3(194.09,61.61)
  S5 w0.102: v3(194.09,61.61) 194.38,61.9 194.38,72.15 197.89,75.67 197.89,76.92 199.39,78.41 199.39,86.34 202.56,89.52 202.56,96.11 203.37,96.92 203.37,99 203.51,99.14 203.51,100.41 203.01,100.91 203.01,106.71 199.39,110.33 199.39,114.73 198.53,115.6 v2(198.53,116.87)
PWRGD_P1V5_PCH_LED8: length 61.2
  TOP w0.114: U12.B11 v3(199.09,61.61) ; v2(205.44,117.27) 205.11,117.6 LED8.C
  S5 w0.102: v2(205.44,117.27) 206.02,116.69 206.02,114.97 205.52,114.47 205.52,101.19 205.13,100.8 205.13,90.46 201.24,86.57 201.24,79.3 201.57,78.96 201.57,64.1 v3(199.09,61.61)
PWRGD_P1V05_PCH_R: length 7.3
  TOP w0.114: LED4.A v2(199.02,120.86)
  BOTTOM w0.114: R408.2 v2(199.02,120.86) 198.43,121.45 197.57,121.45 197.06,120.93 197.06,118.09 v1(197.34,117.81)
PWRGD_P1V5_PCH_R: length 36.8
  TOP w0.114: v2(205.11,120.97) LED8.A
  S10 w0.102: v2(205.11,120.97) 205.11,118.42 201.98,115.28 201.98,112.21 198.23,108.47 192.73,108.47 183.54,99.28 v2(183.54,98.27)
  BOTTOM w0.114: R412.2 v2(205.11,120.97)
PWRGD_P1V8_LAN: length 5
  TOP w0.114: U12.T4 191.59,45.87 190.58,44.86 R225.1 v2(190.58,42.49)
PWRGD_P1V8_LAN1: length 3.7
  TOP w0.114: U12.T12 v2(199.59,44.7) 199.59,44.7 R224.1
PWRGD_P3V3: length 61.4
  TOP w0.114: U12.E6 v3(193.09,58.61) ; v2(155.96,41.35) 155.96,34.54 R382.2 R381.1 154.18,34.06 153.53,34.71 U27.6
  S8 w0.102: v3(193.09,58.61) 192.57,59.13 184.96,59.13 181.13,55.3 181.13,47.43 179.12,45.42 179.11,45.42 179.08,45.39 159.63,45.39 155.96,41.72 v2(155.96,41.35)
PWRGD_P3V3_A: length 227.7
  TOP w0.114: U12.T2 188.27,45.79 188.27,43.84 R226.2 187.76,42.77 185.63,42.77 185.37,43.03 178.03,43.03 173.56,38.57 v2(173.56,37.52) 173.56,36.78 R282.2 R281.1 173.57,35.29 172.8,35.29 172.49,34.98 U15.6
  S3 w0.102: v2(122.81,32.99) 122.33,33.48 101.48,33.48 99.29,31.28 99.29,27.98 94.03,22.73 81.35,22.73 80.65,22.02 78.79,22.02 78.02,22.78 72.63,22.78 72.53,22.88 69.12,22.88 69.02,22.78 64.85,22.78 61.72,25.91 45.03,25.91 43.66,27.28 39.29,27.28 35.48,31.09 33.23,31.09 29.11,35.2 29.11,39.62 29.13,39.64 29.13,50.62 26.59,53.16 26.59,55.04 24.08,57.55 24.08,57.72 19.81,61.99 v3(19.81,65.74)
  S8 w0.102: v2(173.56,37.52) 173.24,37.84 166.17,37.84 165.75,37.41 165.24,37.41 159.11,31.29 135.88,31.29 132.88,34.29 124.49,34.29 123.41,33.2 123.01,33.2 v2(122.81,32.99)
  BOTTOM w0.114: v3(19.81,65.74) 20.16,66.08 CONN14.43 ; v2(173.56,37.52) v1(173.56,40.26)
PWRGD_P3V3_LED1: length 66
  TOP w0.114: U12.B4 v3(191.09,61.61) ; LED1.C v2(192.28,117.24)
  S5 w0.102: v3(191.09,61.61) 191.09,63.05 192.53,64.49 192.53,75.23 197.92,80.62 197.92,86.95 201.48,90.51 201.48,102.34 201.76,102.63 201.76,105.87 192.28,115.35 v2(192.28,117.24)
PWRGD_P3V3_R: length 7.3
  TOP w0.114: v2(192.28,120.9) LED1.A
  BOTTOM w0.114: v1(188.78,118.14) 188.78,119.62 190.06,120.9 v2(192.28,120.9) R405.2
PWRGD_P5V_STBY: length 156.6
  TOP w0.114: U12.F11 v3(199.09,57.61) ; U4.6 129.31,111.98 130.23,111.07 R46.1 130.8,111.05 R42.2 131.73,111.37 132.29,111.93 133.54,111.93 134.54,112.93 134.54,114.24 135.12,114.81 143.89,114.81 v2(147.35,118.26)
  S5 w0.102: v3(199.09,57.61) 199.57,58.09 200.11,58.09 200.58,58.57 200.58,60.64 202.17,62.23 202.25,62.23 203,62.98 203,78.18 201.69,79.49 201.69,86.38 205.59,90.27 205.59,100.43 206.03,100.88 206.03,113.61 207.37,114.95 207.37,117.44 206.73,118.07 191.81,118.07 191.58,117.83 187.31,117.83 186.5,118.64 180.92,118.64 177.62,121.95 v2(145.72,121.95)
  BOTTOM w0.114: v2(147.35,118.26) 145.72,119.89 v2(145.72,121.95)
PWRGD_P5V_STBY_LED10: length 67
  TOP w0.114: LED10.C 190.51,117.89 v2(189.91,117.29) ; U12.B3 v3(190.09,61.61)
  S5 w0.102: v3(190.09,61.61) 190.5,62.02 190.5,62.78 192.3,64.59 192.3,75.33 197.69,80.71 197.69,87.05 201.12,90.48 201.12,102.49 200.85,102.76 200.85,106.35 v2(189.91,117.29)
PWRGD_P5V_STBY_R: length 3.6
  TOP w0.114: LED10.A 190,119.99 v2(189.35,119.35)
  BOTTOM w0.114: v2(189.35,119.35) 190,119.99 R404.2
PWRGD_PVCCIN: length 171.4
  TOP w0.114: U12.L7 v3(194.09,51.61) ; v2(71.27,5.21) 71.3,5.21 72.24,6.15 72.24,7.04 72.51,7.31 U28.9
  S5 w0.102: v2(126.88,8.38) 130.48,8.38 130.61,8.26 138.31,8.26 139.21,7.35 157.22,7.35 161.38,11.52 169.04,11.52 173.01,15.49 176.24,15.49 177.04,16.29 177.04,23.42 179.12,25.5 179.12,25.66 180.06,26.59 180.21,26.59 188.85,35.23 188.85,43.38 190.75,45.29 190.75,46.31 192.07,47.62 194.18,47.62 194.59,48.03 194.59,51.1 194.09,51.61 v3(194.09,51.61)
  S8 w0.102: v2(126.88,8.38) 125.95,7.45 125.95,6.75 125.12,5.92 123.05,5.92 122.91,6.06 121.48,6.06 119.84,7.7 114.37,7.7 110.54,11.52 96.02,11.52 95.03,12.51 92.84,12.51 92.5,12.16 89.47,12.16 86.99,12.16 86.39,11.56 85.05,11.56 84.46,10.97 82.67,10.97 80.74,9.05 80.74,6.12 79.43,4.8 77.38,4.8 77.25,4.67 76.87,4.67 75.13,6.41 72.48,6.41 v2(71.27,5.21)
  BOTTOM w0.114: v2(71.27,5.21) 71.3,5.21 72.46,6.37 v1(72.46,6.73) R744.1
PWRGD_PVCCIN_LED9: length 61.7
  TOP w0.114: U12.B12 v3(200.09,61.61) ; LED9.C 206.51,117.65 206.76,117.4 v2(206.76,117.17)
  S5 w0.102: v2(206.76,117.17) 206.91,117.02 206.91,115.47 205.75,114.31 205.75,101.09 205.36,100.7 205.36,90.37 201.46,86.47 201.46,79.39 202.77,78.09 202.77,64.29 v3(200.09,61.61)
PWRGD_PVCCIN_R: length 38.6
  TOP w0.114: v2(206.51,120.93) LED9.A
  S10 w0.102: v2(206.51,120.93) 206.51,119.49 202.2,115.19 202.2,112.12 198.33,108.24 192.83,108.24 184.2,99.61 v2(184.2,96.58)
  BOTTOM w0.114: R413.2 v2(206.51,120.93)
PWRGD_PVCCKRHV: length 66.2
  TOP w0.114: U12.J5 v3(192.09,53.61)
  TOP w0.127: U8.3 146.53,69.83 R188.1 146.89,69.8 147.14,70.05 148.29,70.05 C81.2 149.48,70.4 v2(149.48,69.22)
  S3 w0.102: v3(192.09,53.61) 190.58,55.12 188.98,55.12 184.53,59.56 184.53,66.11 180.9,69.75 170.82,69.75 168.94,71.63 166.82,71.63 165,73.46 162.59,73.46 162.2,73.07 162.2,70.19 161.26,69.24 158.6,69.24 157.81,68.45 150.06,68.45 149.48,69.04 v2(149.48,69.22)
PWRGD_PVCCKRHV_LED3: length 65.1
  TOP w0.114: v2(197.31,116.76) 197.62,117.07 LED3.C ; U12.B6 v3(193.09,61.61)
  S5 w0.102: v2(197.31,116.76) 197.31,115.72 198.55,114.48 198.55,109.84 202.62,105.77 202.62,101.78 202.26,101.42 202.26,90.54 198.45,86.73 198.45,80.29 195.5,77.34 195.5,74.19 193.03,71.72 193.03,65.01 193.38,64.66 193.38,61.9 v3(193.09,61.61)
  BOTTOM w0.114: v2(197.31,116.76) 197.26,116.71 v1(196.47,116.71)
PWRGD_PVCCKRHV_R: length 5.6
  TOP w0.114: v2(197.87,120.87) 197.62,120.62 LED3.A
  BOTTOM w0.114: v1(199.01,118.05) 198.95,118.05 198.84,117.94 198.04,117.94 197.3,118.68 197.3,119.68 197.61,119.99 R407.2 v2(197.87,120.87)
PWRGD_PVCCSCFUSESUS: length 57.4
  TOP w0.114: U12.F2 189.57,57.11 189.05,56.59 187.96,56.59 186.9,57.65 172,57.65 168.78,60.87 151.27,60.87 149.15,62.99 149.15,66.9 150.77,68.52 153.71,68.52 154.23,69.04 v2(154.23,69.1) U22.6
  BOTTOM w0.114: R694.2 155.69,69.6 R697.1 154.73,69.6 v2(154.23,69.1)
PWRGD_PVCCSCFUSESUS_LED2: length 65.4
  TOP w0.114: LED2.C 194.06,117.95 193.75,117.63 v2(193.75,117.17) ; U12.B5 v3(192.09,61.61)
  S5 w0.102: v2(193.75,117.17) 194.08,116.84 194.08,113.99 201.99,106.08 201.99,102.53 201.71,102.24 201.71,90.31 198.22,86.82 198.22,80.38 195.28,77.44 195.28,74.29 192.8,71.82 192.8,64.91 192.99,64.73 192.99,62.51 v3(192.09,61.61)
PWRGD_PVCCSCFUSESUS_R: length 11.3
  TOP w0.114: LED2.A 194.06,120.47 v2(193.12,121.41)
  BOTTOM w0.114: R406.2 193.28,121.25 v2(193.12,121.41) 190.23,121.41 187.86,119.04 v1(187.86,117.24)
RESET_MAC: length 391.5
  TOP w0.114: R7.1 v2(68.31,115.4) ; U12.D15 v3(203.09,59.61)
  S5 w0.102: v2(46.48,109.35) 46.48,109.98 50.9,114.4 65.62,114.4 66.05,113.97 66.87,113.97 v2(68.31,115.4)
  S8 w0.102: v2(46.48,109.35) 46.1,109.73 37.92,109.73 34.87,106.68 34.87,105.49 34.11,104.72 34.11,103.38 32.51,101.78 31.94,101.78 31.11,100.95 31.11,80.44 30.94,80.26 30.94,76.67 30.53,76.27 30.53,57.6 29.03,56.1 29.03,55.73 27.16,53.85 27.16,20.3 30.87,16.59 40.88,16.59 41.89,15.57 45.82,15.57 48.06,13.33 48.06,10.74 49.73,9.07 52.88,9.07 54.13,7.82 54.69,7.82 56.43,6.09 56.43,4.99 56.68,4.74 59.44,4.74 60.79,6.1 62.17,6.1 62.69,5.58 67.38,5.58 67.63,5.33 70.18,5.33 70.99,4.52 76.38,4.52 76.68,4.22 77.77,4.22 77.82,4.27 81.06,4.27 81.76,4.97 81.76,8.19 84.08,10.52 84.65,10.52 85.24,11.1 86.58,11.1 87.18,11.7 89.28,11.7 92.69,11.7 93.03,12.05 94.84,12.05 95.84,11.06 110.36,11.06 115.04,6.38 116.51,6.38 117.28,5.6 122.72,5.6 122.97,5.36 127.24,5.36 127.99,4.61 127.99,3.62 128.72,2.9 142.27,2.9 142.93,3.56 142.93,5.33 143.59,5.99 147.65,5.99 147.93,5.71 147.93,4.78 v3(148.46,4.24) ; v3(203.09,59.61) 203.09,61.07 203.47,61.45 203.47,61.77 203.09,62.15 203.09,63.6 202.78,63.91 193.98,63.91 193.04,62.97 191.67,62.97 189.18,65.46 182.55,65.46 v2(181.38,66.62)
  S10 w0.102: v2(181.38,66.62) 181.38,65.75 180.62,64.98 180.62,56.35 181.23,55.74 181.23,43.66 176.29,38.72 176.29,35 175.31,34.02 175.31,31.37 167.74,23.8 167.74,16.48 166.75,15.49 166.75,8.79 163.42,5.46 161.93,5.46 159.51,3.05 150.11,3.05 148.92,4.24 v3(148.46,4.24)
  BOTTOM w0.114: v2(68.31,115.4) 69.04,115.4 v1(69.34,115.7)
  BOTTOM w0.127: v3(148.46,4.24) 148.03,4.24 147.6,3.81 CONN16.46
RESET_MAC_R: length 62.6
  TOP w0.114: R901.2 70.05,115.42 R7.2 v2(71.98,115.4) ; v4(93.45,79.65) 93.15,79.95 U9.BD26
  S3 w0.102: v2(71.98,115.4) 71.98,116.18 72.64,116.84 76.23,116.84 77.29,115.77 77.29,111.58 79.02,109.86 79.83,109.86 81.46,108.23 81.46,106.53 81.97,106.02 82.3,106.02 84.68,103.63 84.68,101.52 89.23,96.98 91.31,96.98 93.62,94.67 93.62,92.43 96.16,89.89 96.16,89.14 95.84,88.82 95.84,88.01 96.41,87.45 96.75,87.45 97.16,87.05 97.16,83.13 96.93,82.91 96.93,81.31 97.26,80.98 97.26,80.31 96.95,80.01 96.43,80.01 95.59,79.17 94.99,79.17 94.99,79.17 93.93,79.17 v4(93.45,79.65)
  BOTTOM w0.114: v1(71.93,116.56) 71.93,115.45 v2(71.98,115.4)
RP_1.05V_BOOST: length 11.1
  TOP w0.114: v2(121.95,17.55) 121.93,17.57 U24.3
  BOTTOM w0.114: v2(121.95,17.55) 123.09,17.55 124.23,18.69 124.23,21.08 123.62,21.69 121.97,21.69 121.73,21.45 C593.1 v2(121.06,22.89)
RP_1.05V_LGATE1: length 4
  TOP w0.114: U24.5 121.59,19.23 v2(121.59,19.56)
  BOTTOM w0.114: TP36.1 121.59,19.37 v2(121.59,19.56) 122.28,19.56 v1(122.73,19.1)
RP_1.05V_LGATE2: length 4.9
  TOP w0.114: U24.32 120.83,20.12 v2(121.03,20.12)
  BOTTOM w0.114: v1(122.86,20.85) 122.3,20.29 121.21,20.29 v2(121.03,20.12) 120.78,20.12 120.08,19.42 TP34.1
RP_1.05V_R_I2C_SCL: length 80.1
  TOP w0.114: U28.20 77.48,6.21 77.77,5.92 78.33,5.92 79.4,4.85 R397.1 80.89,4.39 v2(83.35,1.94) 82.73,1.32 50.42,1.32 R770.2
  S10 w0.102: v2(83.35,1.94) 83.96,1.33 84.39,1.33 84.57,1.14 92.75,1.14 93.25,1.65 113.15,1.65 114.05,2.54 114.05,5.23 v2(113.23,6.05)
  BOTTOM w0.114: R784.1 R783.1 113.27,6 v2(113.23,6.05)
RP_1.05V_R_I2C_SCL_CONN12: length 2.6
  TOP w0.114: CONN12.3 v2(113.23,4.17)
  BOTTOM w0.114: CONN12.3 v2(113.23,4.17)
RP_1.05V_R_I2C_SDA: length 108.5
  TOP w0.114: U28.19 76.81,5.84 77.03,5.62 77.67,5.62 78.46,4.83 R396.1 78.18,4.39 77.88,4.09 77.88,2.54 76.91,1.57 56.08,1.57 v2(55.12,2.54) ; v2(49.02,4.95) 49.78,4.19 R392.2
  S10 w0.102: v2(116,5.87) 115.24,5.87 113.99,7.12 113.17,7.12 112.47,6.42 112.47,4.14 110.21,1.87 93.16,1.87 92.65,1.37 84.67,1.37 84.48,1.56 84.38,1.56 83.53,2.4 83.16,2.4 82.6,1.84 82.13,1.84 81.72,1.42 81.28,1.42 81.05,1.19 78.26,1.19 78.02,1.42 72.93,1.42 72.79,1.28 62.66,1.28 60.44,3.5 56.08,3.5 v2(55.12,2.54) 53.84,3.82 50.16,3.82 v2(49.02,4.95)
  BOTTOM w0.114: R753.1 R751.1 116.13,6 v2(116,5.87)
RP_1.05V_R_I2C_SDA_CONN12: length 3.8
  TOP w0.114: CONN12.2 117.07,4.45 v2(116.74,4.11)
  BOTTOM w0.114: v2(116.74,4.11) 117.07,4.45 R751.2
RP_1.05V_R_REG_EN: length 3.8
  TOP w0.114: U28.10 72.91,6.49 72.48,6.06 72.48,6.05 71.74,5.3 71.74,5.01 71.45,4.72 70.69,4.72 R387.1
RP_1.05V_R_SENSE_N: length 10.7
  TOP w0.203: v2(78.8,8.71) 78.6,8.91 U28.26
  BOTTOM w0.203: v1(84.98,11.28) 84.21,10.51 84.21,8.82 83.85,8.46 81.56,8.46 81.18,8.08 79.88,8.08 79.73,8.23 R741.2
  BOTTOM w0.254: R741.2 78.88,8.63 v2(78.8,8.71) 78.75,8.66 C628.2
RP_1.05V_R_SENSE_P: length 5.8
  TOP w0.203: U28.27 78.67,9.31 v2(78.8,9.45)
  BOTTOM w0.203: v1(81.37,11.36) 81.37,10.4 81.03,10.06 80.01,10.06 79.73,9.78 R733.2
  BOTTOM w0.254: C628.1 78.67,9.57 v2(78.8,9.45) 78.88,9.53 R733.2
RP_1.05V_REG_IOUT: length 50.1
  TOP w0.249: v2(118.39,13.54) 118.6,13.75 U24.26
  TOP w0.381: R354.1 v2(79.65,13.96)
  S8 w0.381: v2(118.39,13.54) 117.22,12.37 112.73,12.37 111.96,13.13 96.62,13.13 95.68,14.07 92.2,14.07 91.97,13.84 90.2,13.84 89.23,14.81 89.23,16.45 87.85,17.83 86.89,17.83 86.31,17.25 86.31,14.96 84.91,13.56 83.16,13.56 82.76,13.96 v2(79.65,13.96)
  BOTTOM w0.114: v1(118.39,12.7) v2(118.39,13.54)
RP_1.05V_REG_PHASE: length 1.5
  BOTTOM w0.381: C593.2 v2(119.02,22.9)
RP_1.05V_REG_PWM: length 52.1
  TOP w0.114: U28.25 78.33,8.51 78.79,8.05 v2(78.79,7.98)
  TOP w0.249: v2(119.92,13.32) 119.91,13.33 119.91,13.39 119.84,13.46 119.84,15.19 120.1,15.45 U24.29
  S8 w0.381: v2(119.92,13.32) 119.91,13.32 119.91,13.31 119.84,13.31 118.31,11.79 112.29,11.79 111.51,12.57 96.46,12.57 95.47,13.56 92.41,13.56 92.06,13.22 89.91,13.22 89.91,13.22 86.55,13.22 85.95,12.61 84.61,12.61 84.06,12.06 80.26,12.06 78.99,10.79 78.99,10.29 79.5,9.78 79.5,8.48 78.99,7.98 v2(78.79,7.98)
  BOTTOM w0.381: v1(119.41,14.43) 119.91,13.92 119.91,13.33 v2(119.92,13.32)
RP_1.05V_REG_R_IOUT: length 7.1
  TOP w0.203: U28.31 77.46,11.21 77.86,11.62 C213.2
  TOP w0.381: R352.1 C213.2 R354.2 80.13,13.05 v2(80.37,13.28)
  BOTTOM w0.114: v1(79.02,13.28) v2(80.37,13.28)
RP_1.05V_REG_RCSM: length 23.3
  TOP w0.114: U28.29 78.29,10.11 79.56,11.38 C220.1 81.74,11.38 82.24,11.88 R360.2 83.64,10.79 87.76,10.79 88.97,12.01 95.26,12.01 v2(97.94,9.33)
RP_1.05V_REG_RSCP: length 4.4
  TOP w0.114: R360.1 81.23,12.29 C220.2 79.5,12.29 v2(78.61,11.4) 78.47,11.4 77.91,10.84 U28.30
RP_1.05V_SENSE_N: length 90
  TOP w0.127: v2(96.55,52.48) 97.22,53.15 97.22,54.57 97.49,54.83 97.49,55.37 97.76,55.65 97.76,56.47 U9.AP77
  S10 w0.254: v3(95.45,31.85) 95.83,31.47 97.16,31.47 98.55,30.08 98.55,26.16 94.44,22.05 94.44,14.15 91.63,11.34 85.31,11.34 83.56,9.59 v3(83.56,9.05)
  BOTTOM w0.127: 83.54,49.85 83.54,49.88 83.41,50.01 83.41,50.26 86.41,53.26 86.41,54.91 87.05,55.55 89.23,55.55 89.61,55.17 91.16,55.17 93.61,52.72 95.88,52.72 96.12,52.48 v2(96.55,52.48)
  BOTTOM w0.254: v1(83.7,11.49) 83.7,9.2 v3(83.56,9.05) 83.02,9.05 82.79,8.82 80.84,8.82 R741.1 ; R605.2 96.64,52.38 v2(96.55,52.48) ; 83.54,49.85 83.54,48.66 82.68,47.8 82.68,42.34 86.61,38.4 87,38.4 91.74,33.66 91.74,32.24 92.51,31.47 95.07,31.47 v3(95.45,31.85)
RP_1.05V_SENSE_P: length 86.3
  TOP w0.127: U9.AR78 97.23,55.7 97.23,54.94 96.96,54.67 96.96,53.63 v2(96.55,53.21)
  S10 w0.254: v3(95.45,30.58) 95.83,30.96 96.95,30.96 98.04,29.87 98.04,26.37 93.93,22.26 93.93,14.36 91.42,11.85 85.1,11.85 83.2,9.95 v3(82.66,9.95)
  BOTTOM w0.127: 83.03,49.85 83.03,49.88 83.16,50.01 83.16,50.37 86.16,53.37 86.16,55.02 86.94,55.8 89.33,55.8 89.71,55.42 91.26,55.42 93.71,52.97 95.88,52.97 96.12,53.21 v2(96.55,53.21)
  BOTTOM w0.254: R604.1 96.62,53.29 v2(96.55,53.21) ; 83.03,49.85 83.03,48.87 82.17,48.01 82.17,42.13 86.4,37.9 86.78,37.9 91.24,33.44 91.24,32.03 92.3,30.96 95.07,30.96 v3(95.45,30.58) ; R733.1 80.84,9.33 82.58,9.33 82.66,9.41 v3(82.66,9.95) 82.59,10.02 v1(82.59,10.88)
RP_1.8V_PHASE1_BOOST: length 4.3
  TOP w0.114: U25.3 89.43,19.42 C180.1 91.16,20.19 v2(91.74,20.78)
RP_1.8V_PHASE1_LGATE1: length 2.8
  TOP w0.114: U25.5 v2(88.85,20.42)
  BOTTOM w0.114: TP37.1 88.79,20.36 v2(88.85,20.42) 88.97,20.54 v1(89.79,20.54)
RP_1.8V_PHASE1_LGATE2: length 2.8
  TOP w0.114: U25.32 v2(88.06,21.23)
  BOTTOM w0.114: TP35.1 88.01,21.28 v2(88.06,21.23) 88.69,21.87 v1(88.8,21.87)
RP_1.8V_PHASE2_BOOST: length 6.3
  TOP w0.114: U26.3 76.01,19.22 C179.1 78,20.27 v2(78.41,20.68)
  BOTTOM w0.114: v1(77.47,20.7) 78.38,20.7 v2(78.41,20.68)
RP_1.8V_PHASE2_LGATE1: length 2.7
  TOP w0.114: U26.5 v2(74.42,20.22) 75.45,20.22 TP10.1
  BOTTOM w0.114: v2(74.42,20.22) 74.39,20.19 v1(74.39,19.38)
RP_1.8V_PHASE2_LGATE2: length 3.9
  TOP w0.114: U26.32 v2(74.32,21.03) 75.08,21.03 TP9.1
  BOTTOM w0.114: v1(75.41,21.09) 74.38,21.09 v2(74.32,21.03)
RP_1.8V_REG_IOUT1: length 21.1
  TOP w0.114: R351.1 v2(71.53,14)
  TOP w0.249: U25.26 v2(85.71,17.03)
  S8 w0.381: v2(71.53,14) 70.94,14.59 70.94,16.59 71.58,17.22 73.36,17.22 74.52,18.39 82.19,18.39 84.23,16.36 85.19,16.36 85.71,16.87 v2(85.71,17.03)
RP_1.8V_REG_IOUT2: length 7.6
  TOP w0.114: R355.1 v2(76.04,14.83)
  TOP w0.249: U26.26 71.33,16.4 v2(71.58,16.15)
  S8 w0.102: v2(71.58,16.15) 71.58,15.93 72.67,14.83 v2(76.04,14.83)
RP_1.8V_REG_ISEN3: length 1.3
  TOP w0.114: U28.35 75.61,11.64 75.51,11.73 75.31,11.73 75.21,11.64 U28.36
RP_1.8V_REG_ISEN4: length 2.5
  TOP w0.114: v2(75.87,12.06) 76.01,11.92 U28.34 U28.33
  BOTTOM w0.114: v1(76.17,13.16) 75.87,12.85 v2(75.87,12.06)
RP_1.8V_REG_PHASE1:
  vias: v1(86.66,25.66) v2(84.51,24.28) v2(85.32,24.28) v2(86.13,24.31) v2(86.94,24.31)
RP_1.8V_REG_PHASE2:
  vias: v1(68.09,25.61) v2(66.42,27) v2(67.26,27) v2(68.07,27) v2(68.91,27) v2(69.19,24.16) v2(70.03,24.16) v2(70.84,24.16) v2(71.68,24.16)
RP_1.8V_REG_PWM1: length 24.7
  TOP w0.203: U28.21 77.91,6.52 v2(78.03,6.4)
  TOP w0.249: v2(87.73,17) 87.67,17 87.21,17.46 U25.29
  S8 w0.254: v2(87.73,17) 87.73,14.58 86.81,13.66 86.37,13.66 85.76,13.06 84.42,13.06 83.94,12.57 78.77,12.57 78,11.81 78,7.95 78.71,7.24 79.07,7.24 79.5,6.81 79.5,6.3 78.99,5.79 78.41,5.79 78.03,6.17 v2(78.03,6.4)
  BOTTOM w0.381: v2(87.73,17) 88.58,17 v1(88.98,16.61)
RP_1.8V_REG_PWM2: length 17.6
  TOP w0.203: v2(78.79,6.35) 78.79,6.91 78.39,7.31 U28.22
  TOP w0.249: U26.29 72.83,16.65 v2(72.77,16.59)
  S8 w0.254: v2(72.77,16.59) 76.56,16.59 77.44,15.7 77.44,7.8 78.79,6.45 v2(78.79,6.35)
RP_1.8V_REG_R_EN: length 1.9
  TOP w0.114: R395.1 76.01,4.73 U28.17
RP_1.8V_REG_R_HOT_OC: length 1.9
  TOP w0.114: R394.1 75.61,4.61 U28.16
RP_1.8V_REG_R_IOUT1: length 5.1
  TOP w0.114: R351.2 C214.2 73.23,12.34 v2(73.38,12.19) 73.51,12.19 74.01,11.69 U28.39
  BOTTOM w0.114: v1(73.23,14.07) C214.2 73.23,12.34 v2(73.38,12.19)
RP_1.8V_REG_R_IOUT2: length 5
  TOP w0.114: C215.2 R353.1 ; C215.2 v2(75.1,12.18) 74.81,11.9 U28.37 ; C215.2 R355.2
  BOTTOM w0.114: v2(75.1,12.18) 75.1,12.66 v1(74.63,13.13)
RP_1.8V_REG_R_TOUT: length 4.7
  TOP w0.203: v2(71.42,7.82) 71.71,8.11 U28.7
  TOP w0.381: R377.2 R371.1 v2(71.42,7.82)
  BOTTOM w0.381: R377.2 70.56,6.96 v2(71.42,7.82)
RP_1.8V_REG_R_VINSEN: length 4.2
  TOP w0.114: U28.11 72.97,6.21 72.72,5.96 72.72,5.95 71.98,5.2 71.98,4.91 71.05,3.99 R393.1
RP_1.8V_REG_SV_ADDR: length 5.9
  TOP w0.114: U28.12 74.01,5.84 73.76,5.59 73.18,5.59 v2(72.64,5.05) 70.69,3.1 R402.1 C258.2
RP_1.8V_REG_TOUT: length 69.7
  TOP w0.249: U25.25 85.21,17.24 84.96,16.99 v2(84.81,16.99) ; v2(70.33,16.56) 70.83,17.06 U26.25 ; v2(117.6,13.77) 118.1,14.27 U24.25
  TOP w0.381: v2(68.88,7.47) 69.23,7.82 R371.2
  S8 w0.381: v2(68.88,7.47) 68.88,15.54 69.9,16.56 v2(70.33,16.56) 70.33,17.14 71.02,17.83 72.77,17.83 73.99,19.05 76.86,19.05 77.88,20.07 81.31,20.07 84.38,16.99 v2(84.81,16.99)
  BOTTOM w0.381: v2(117.6,13.77) 117.22,13.39 117.2,13.39 114.6,10.79 95.76,10.79 v1(94.01,12.55) 92.2,14.35 89.69,14.35 88.01,16.03 85.78,16.03 v2(84.81,16.99)
RP_1.8V_REG_V18A: length 57
  TOP w0.114: U28.32 76.81,11.89 v2(76.62,12.08) 76.96,12.42 C213.1 R352.2 ; R353.2 C215.1 v2(74.19,12.22) 74.41,11.99 U28.38 ; v2(72.69,11.81) 73.29,11.21 U28.40 ; v2(71.53,13.03) C214.1 ; U28.8 72.41,7.71 71.3,6.6 v2(71.3,5.91) C248.2
  TOP w0.249: v2(73.41,15.93) 73.33,16 U26.30 ; v2(88.87,17.65) 88.76,17.77 U25.30 ; U24.30 v2(120.6,15.21)
  BOTTOM w0.114: C248.2 v2(71.3,5.91) ; C214.1 v2(71.53,13.03)
  BOTTOM w0.381: v1(120.85,16.21) 120.6,15.96 v2(120.6,15.21)
  BOTTOM w0.508: v2(120.6,15.21) 120.57,15.24 120.52,15.24 119.63,16.13 118.49,16.13 114.05,11.68 97.7,11.68 94.79,14.6 94.79,18.08 93.98,18.9 90.12,18.9 v2(88.87,17.65)
RP_1.8V_REG_VINSEN: length 32.7
  TOP w0.114: R393.2 67.41,3.99 v2(66.98,4.42)
  BOTTOM w0.114: C607.2 R720.1 R719.1 84.86,14.12 83.44,12.7 v1(82.55,12.7) 78.23,12.7 76.96,13.97 75.69,13.97 75.01,14.66 70.38,14.66 66.45,10.72 66.45,4.95 v2(66.98,4.42)
RP_1.8V_SENSE_N: length 110.1
  TOP w0.127: U9.AT75 96.86,57.05 96.49,56.69 96.49,56.43 96.67,56.26 96.67,55.44 v3(96.55,55.32)
  TOP w0.254: R366.2 v3(67.91,8.73)
  S10 w0.254: v3(95.48,28.27) 95.86,28.65 96.26,28.65 96.55,28.36 96.55,26.98 92.46,22.89 92.46,14.76 90.73,13.04 83.16,13.04 81.2,11.08 81.2,7.78 77.97,4.54 73.9,4.54 73.88,4.52 70.74,4.52 69.24,6.02 67.47,6.02 67.06,6.43 67.06,8.73 67.27,8.94 67.69,8.94 v3(67.91,8.73)
  BOTTOM w0.127: v3(96.55,55.32) 96.17,55.32 95.93,55.08 93.87,55.08 92.84,56.11 90.42,56.11 89.59,56.95 86.53,56.95 85.14,55.55 85.14,54.89 82.2,51.96 81.49,51.96 81.01,51.47 80.83,51.47 80.81,51.45
  BOTTOM w0.254: R599.1 96.65,55.42 v3(96.55,55.32) ; v3(95.48,28.27) 95.1,28.65 91.36,28.65 89.87,30.15 89.87,32.99 86.61,36.25 85.79,36.25 78.82,43.22 78.82,49.46 80.81,51.45 ; v3(67.91,8.73) 67.34,8.15 v1(67.18,8.15)
RP_1.8V_SENSE_N_R: length 4.5
  TOP w0.203: U28.5 71.47,8.91 71.3,8.74 C237.1
  TOP w0.254: C237.1 v2(70.31,8.74) 70.3,8.73 R366.1
  BOTTOM w0.254: v2(70.31,8.74) 70.31,8.33 v1(69.9,7.92)
RP_1.8V_SENSE_P: length 111.7
  TOP w0.127: v3(96.55,54.58) 96.97,55.01 96.97,56.46 U9.AT77
  TOP w0.254: R364.2 v3(67.91,9.66)
  S10 w0.254: v3(95.48,29.54) 95.86,29.16 96.47,29.16 97.05,28.57 97.05,26.77 92.96,22.68 92.96,14.55 90.94,12.53 83.37,12.53 81.71,10.87 81.71,7.57 78.18,4.04 74.11,4.04 74.09,4.01 70.53,4.01 69.03,5.51 67.26,5.51 66.55,6.22 66.55,8.94 67.06,9.45 67.69,9.45 v3(67.91,9.66)
  BOTTOM w0.127: 81.17,51.09 81.19,51.11 81.19,51.29 81.6,51.7 82.31,51.7 85.39,54.79 85.39,55.45 86.64,56.69 89.48,56.69 90.32,55.85 92.73,55.85 93.76,54.83 95.93,54.83 96.17,54.58 v3(96.55,54.58)
  BOTTOM w0.254: R600.2 96.65,54.48 v3(96.55,54.58) ; v3(67.91,9.66) 67.46,10.11 v1(67.08,10.11) ; 81.17,51.09 79.32,49.25 79.32,43.43 86,36.75 86.82,36.75 90.37,33.2 90.37,30.36 91.57,29.16 95.1,29.16 v3(95.48,29.54)
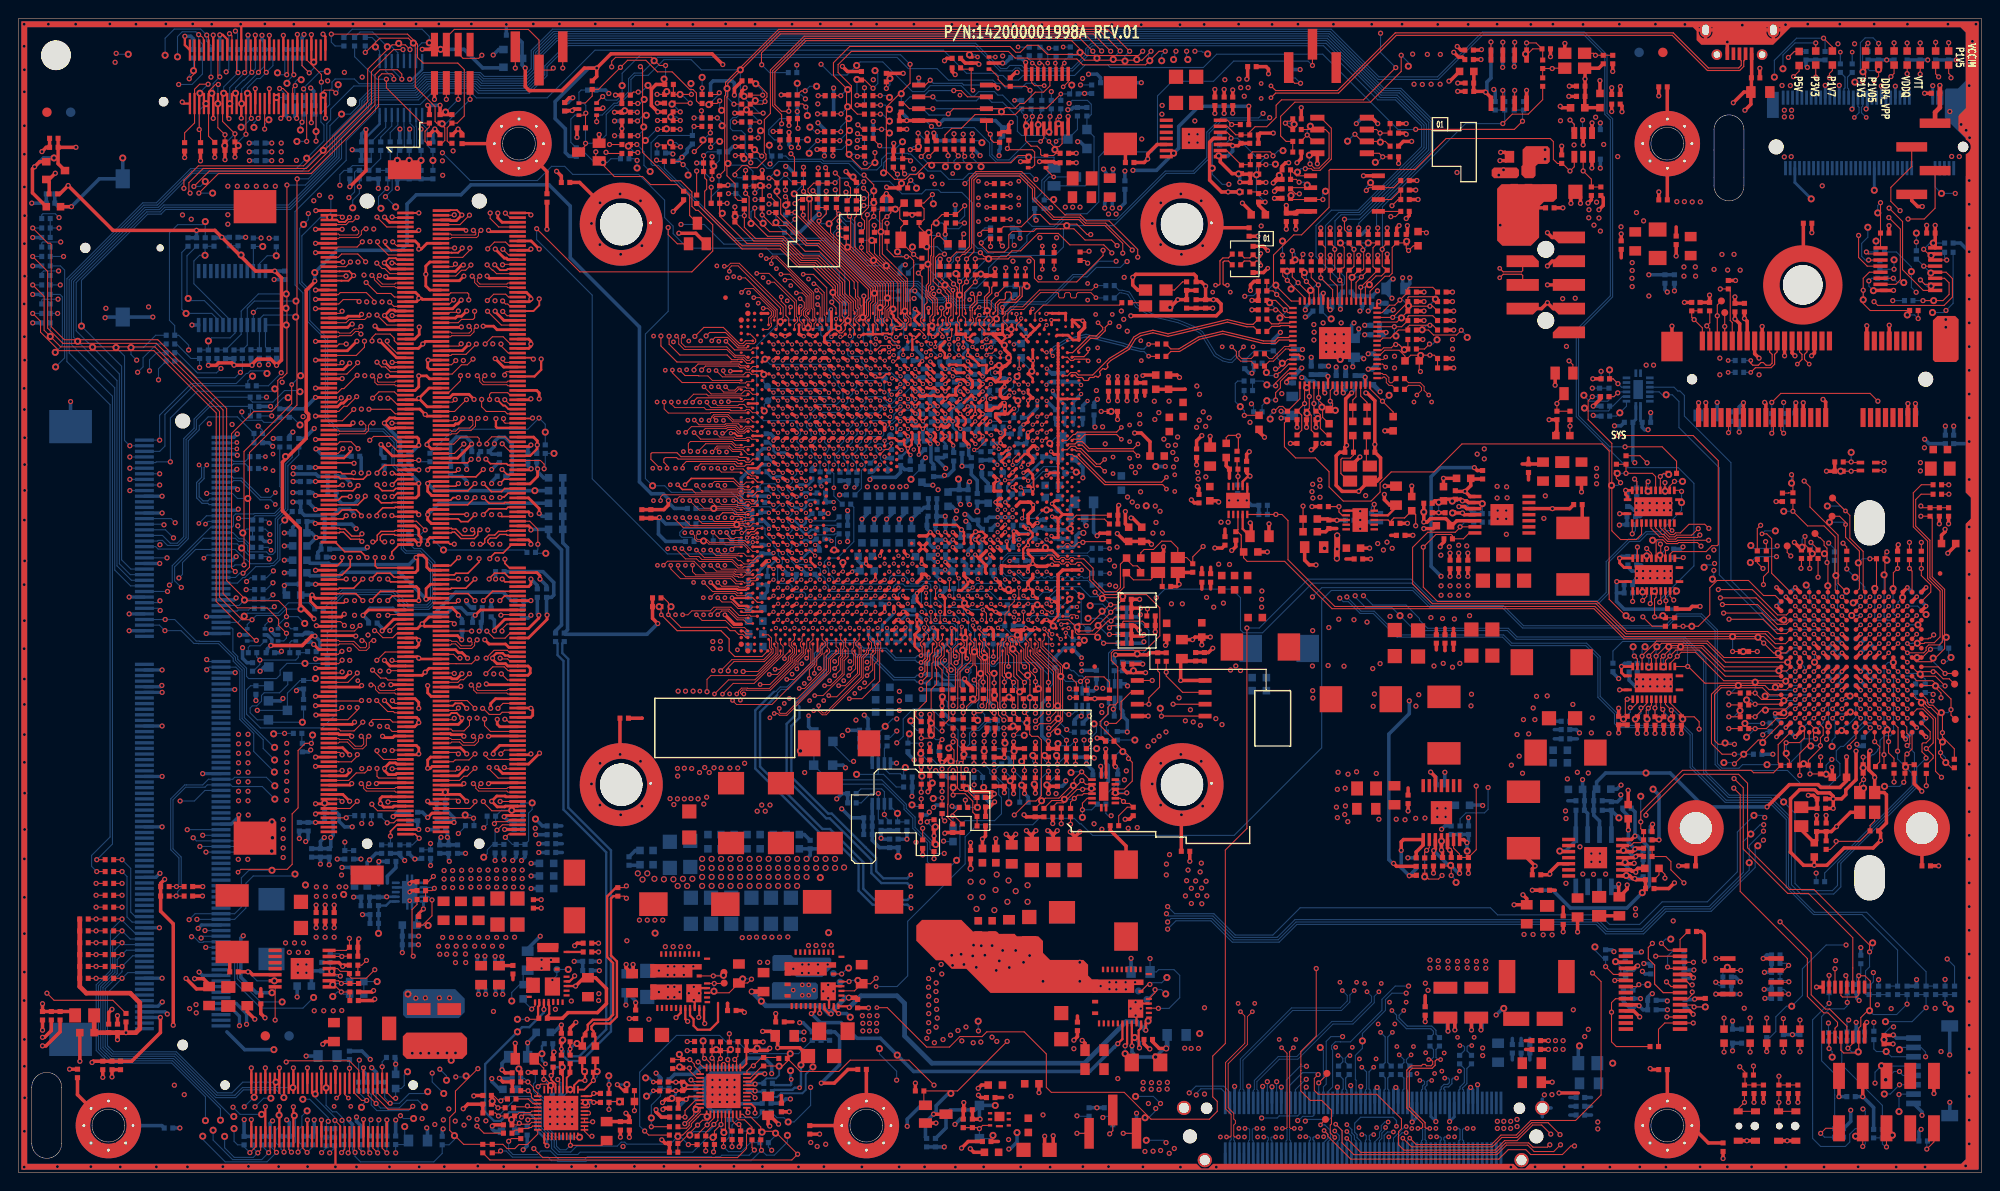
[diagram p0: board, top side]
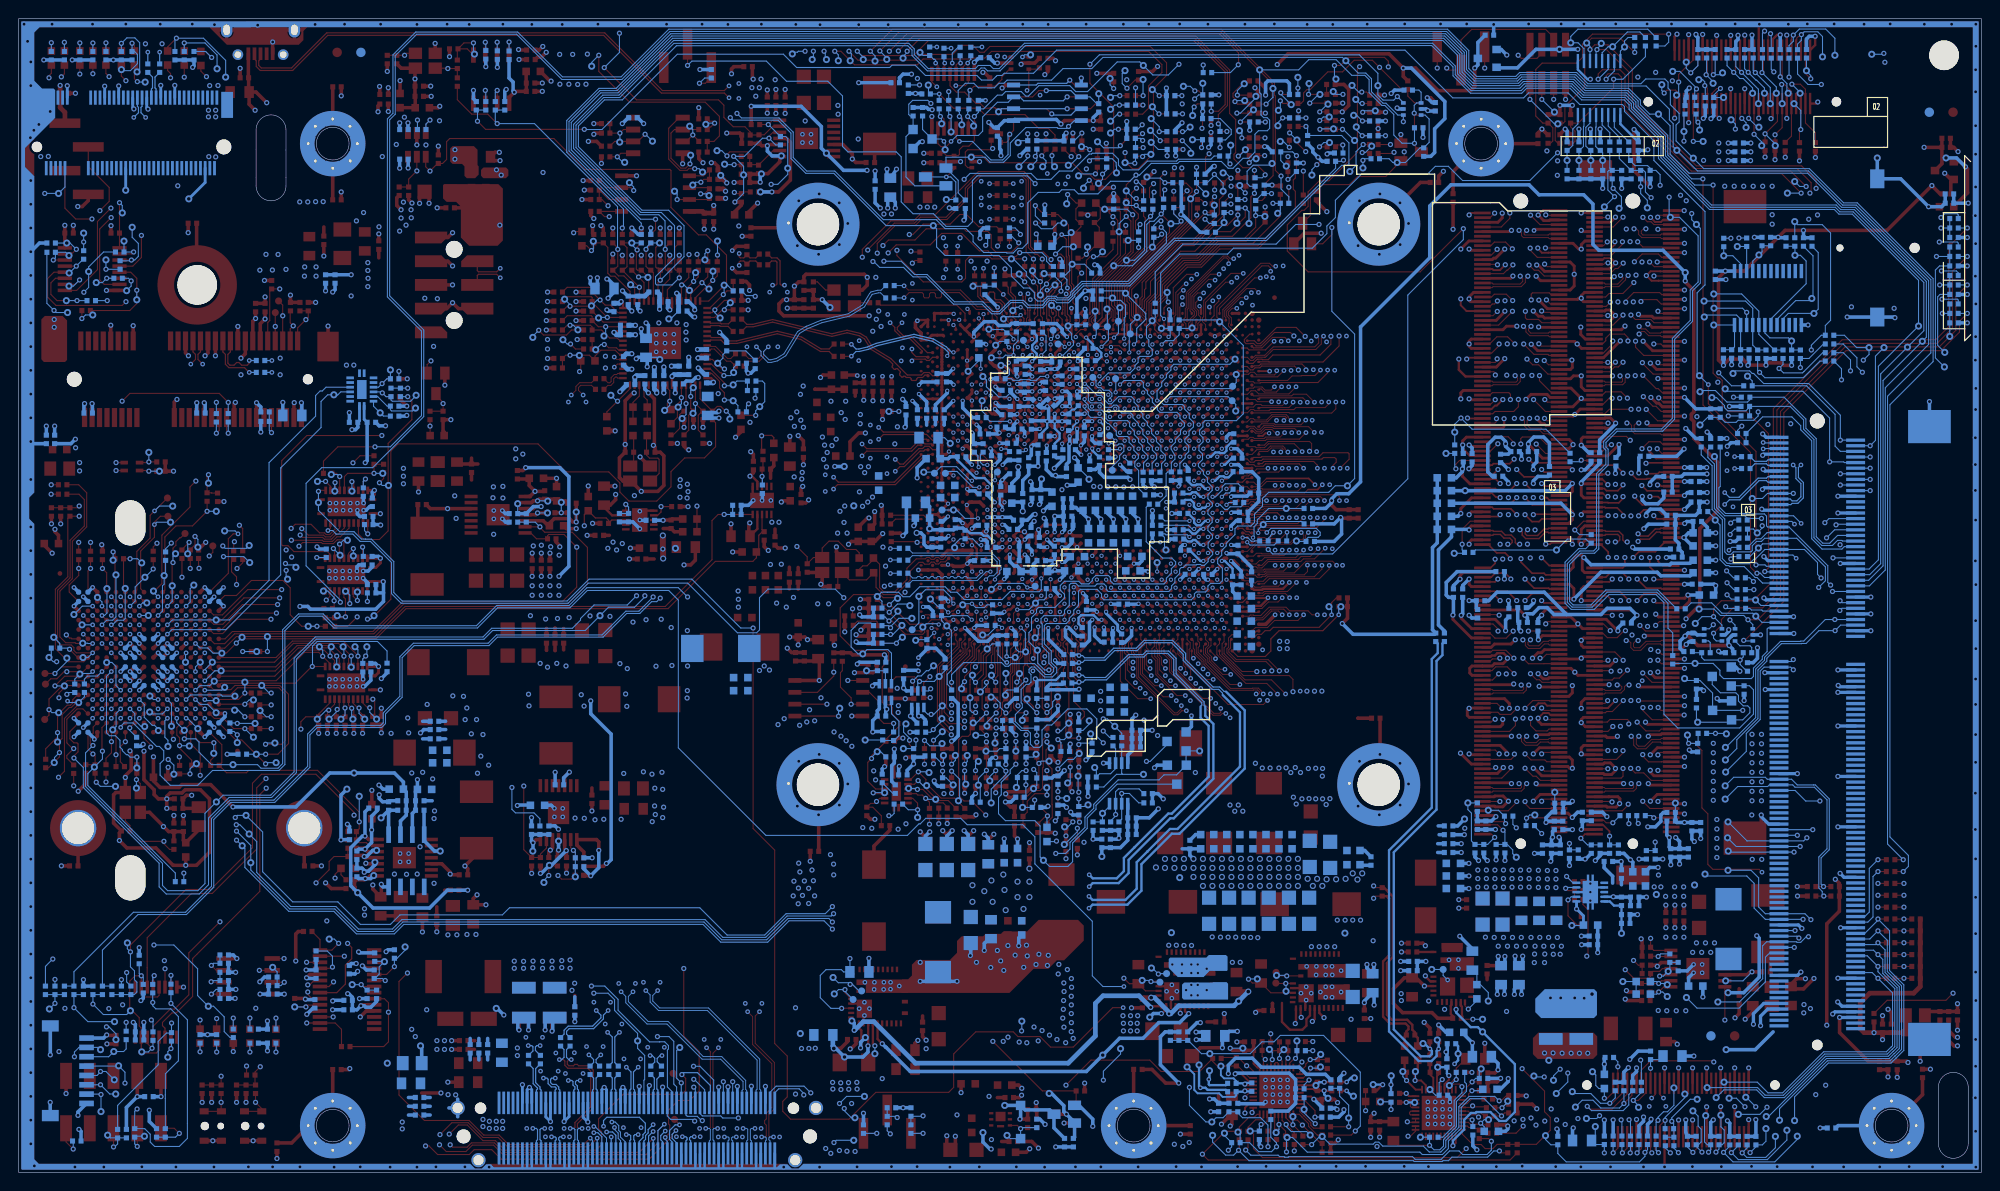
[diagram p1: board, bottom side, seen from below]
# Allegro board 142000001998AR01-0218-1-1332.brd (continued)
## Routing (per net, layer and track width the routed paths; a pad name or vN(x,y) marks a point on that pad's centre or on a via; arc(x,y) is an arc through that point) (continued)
RP_1.8V_SENSE_P_R: length 4.6
  TOP w0.203: U28.4 71.63,9.31 71.3,9.65 C237.2
  TOP w0.254: C237.2 v2(70.31,9.65) 70.3,9.66 R364.1
  BOTTOM w0.254: v2(70.31,9.65) 70.84,9.65 v1(71.2,9.3)
RP_3.3V_LVCC: length 6
  BOTTOM w0.305: v1(191.8,104.21) 190.05,105.96 CONN13.70
  BOTTOM w0.381: C65.1 v2(207.04,79.88) ; C64.1 v2(206.15,79.88)
  vias: v2(188.92,108.7) v2(189.66,108.73) v2(206.83,108.75) v2(207.65,108.74)
RP_B_ERROR0: length 6.1
  TOP w0.102: U9.AC77 102.8,55.33
  TOP w0.114: 102.8,55.33 102.79,55.32 103.21,54.91 103.21,52.48 v2(103.2,52.48) 103.2,52.47 R241.2
  BOTTOM w0.114: v2(103.2,52.48) 102.92,52.76 v1(102.92,53.39)
RP_B_ERROR1: length 11.6
  TOP w0.102: 103.05,55.55 103.02,55.58 103.02,56.01 103.15,56.14
  TOP w0.114: 103.05,55.55 103.42,55.18 103.42,53.33 103.67,53.09 103.67,50.33 103.54,50.2 103.54,49.74 103,49.2 v2(102.21,49.2) R254.2 ; U9.AC75 102.8,57.05 103.15,56.71 103.15,56.14
  BOTTOM w0.114: v2(102.21,49.2) 102.62,48.79 v1(102.62,48.39)
RP_B_ERROR2: length 6.9
  TOP w0.114: R247.2 v2(104.37,52.4) 104.37,53.11 103.85,53.63 103.85,56.02 103.43,56.44 103.43,56.92 U9.AB76
  BOTTOM w0.114: v1(104.37,53.42) v2(104.37,52.4)
RP_BAT_3.3V: length 13
  TOP w0.381: R113.1 v2(5.64,103.37)
  BOTTOM w0.381: v1(11.13,108.58) BA1.2 8.63,106.36 v2(5.64,103.37) 4.24,103.37 C273.2 C272.2
RP_BAT_3.3V_QA: length 8.9
  TOP w0.381: R113.2 1.47,104.85 1.47,107.42 v2(1.7,107.65) 2.25,108.19 Q3.A1
  BOTTOM w0.381: v1(3.78,108.59) 2.65,108.59 v2(1.7,107.65)
RP_CLKIN_GND_1_N: length 2.2
  TOP w0.108: U9.Y30 104.27,78.27 104.66,77.88 104.66,77.88 104.82,77.71 104.82,77.48 v4(104.87,77.44)
  BOTTOM w0.127: v4(104.87,77.44) 104.26,77.44 R548.1
RP_CLKIN_GND_1_P: length 2.6
  TOP w0.108: v4(102.23,77.34) 102.34,77.44 102.6,77.44 U9.AA30
  BOTTOM w0.127: R549.1 102.44,77.14 v4(102.23,77.34)
RP_CLKIN_GND_2_N: length 2.4
  TOP w0.108: U9.N35 107.28,75.81 v4(107.28,75.49)
  BOTTOM w0.127: v4(107.28,75.49) 107.37,75.58 107.37,76.71 R545.1
RP_CLKIN_GND_2_P: length 3.5
  TOP w0.108: U9.P33 106.94,76.89 106.36,76.31 v4(106.36,75.73)
  BOTTOM w0.127: R544.1 107.1,76.8 107.1,76.01 106.82,75.73 v4(106.36,75.73)
RP_CLKIN_GND_3_N: length 3.5
  TOP w0.127: R142.1 103.85,94.74 103.85,94.23 103.34,93.71 103.34,91.99 U9.AB1
RP_CLKIN_GND_3_P: length 4.9
  TOP w0.127: U9.AB3 103.3,91.26 103.61,91.57 103.61,93.6 104.12,94.12 104.12,94.74 R143.1
RP_CLKIN_GND_N4: length 1.9
  TOP w0.114: v4(92.16,77.47) 91.94,77.47 U9.BG32
  BOTTOM w0.127: R547.1 92.26,77.37 v4(92.16,77.47)
RP_CLKIN_GND_P4: length 1.5
  TOP w0.114: U9.BH33 v4(91.66,76.61)
  BOTTOM w0.127: v4(91.66,76.61) 91.66,76.47 R553.1
RP_CORE_1.8V_REG_RCSM: length 4.7
  TOP w0.114: U28.2 72.54,10.11 71.78,10.88 v2(71.78,11.16) C223.2 70.03,11.16 R361.1
  BOTTOM w0.114: v1(70.71,11.28) 70.84,11.16 v2(71.78,11.16)
RP_CORE_1.8V_REG_RSCP: length 5.2
  TOP w0.114: U28.1 72.91,10.76 72.29,11.38 72.29,11.58 v2(71.81,12.06) C223.1 70.03,12.06 R361.2
  BOTTOM w0.114: v1(70.69,12.62) 71.25,12.06 v2(71.81,12.06)
RP_DDR4_DIMM1_ACT_L: length 50.6
  TOP w0.178: v2(39.96,74.84) 40.2,74.84 40.34,74.7 CONN7.114 ; U9.CF33 v4(83.74,76.61)
  S10 w0.152: v4(83.74,76.61) 83.46,76.61 82.97,76.11 82.58,76.11 82.3,76.39 82.3,76.82 82.1,77.02 78.72,77.02 77.37,75.67 77.01,75.67 76.52,76.16 59.79,76.16 57.56,73.93 53.01,73.93 52.21,73.14 45.63,73.14 45.48,73.29 45.48,73.79 45.33,73.94 44.97,73.94 44.82,73.79 44.82,73.29 44.67,73.14 41.99,73.14 40.29,74.84 v2(39.96,74.84)
RP_DDR4_DIMM1_ALERT_L: length 59.1
  TOP w0.178: v2(39.96,73.61) 40.55,74.2 CONN7.116 ; U9.CK33 v4(81.76,76.61)
  S10 w0.152: v4(81.76,76.61) 81.55,76.61 81.11,76.17 79.25,76.17 77.24,74.16 69.04,74.16 68.88,74 68.88,73.57 68.75,73.45 68.05,73.45 67.92,73.57 67.92,74.3 67.79,74.42 67.09,74.42 66.96,74.3 66.96,73.57 66.84,73.45 66.13,73.45 66,73.57 66,75.06 65.88,75.18 65.17,75.18 65.05,75.06 65.05,73.57 64.92,73.45 64.21,73.45 64.09,73.57 64.09,75.06 63.96,75.18 63.25,75.18 63.13,75.06 63.13,73.57 63,73.45 62.3,73.45 62.17,73.57 62.17,74 62.01,74.16 61.37,74.16 61.21,74 61.21,73.57 61.08,73.45 60.38,73.45 60.25,73.57 60.25,74.45 60.02,74.68 59.69,74.68 57.17,72.16 53.2,72.16 51.94,70.89 47.2,70.89 46.77,70.45 46.38,70.45 46.14,70.69 46.14,71.3 45.89,71.55 42.14,71.55 40.07,73.61 v2(39.96,73.61)
RP_DDR4_DIMM1_BA0: length 61.3
  TOP w0.178: CONN7.150 40.18,63.7 39.75,64.13 38.34,64.13 v2(37.71,63.51) ; U9.CH52 v4(82.75,68.02)
  S10 w0.152: v2(37.71,63.51) 37.71,63.1 37.91,62.9 42.25,62.9 42.66,62.49 43.15,62.49 43.3,62.64 43.3,62.89 43.45,63.04 43.81,63.04 43.96,62.89 43.96,62.64 44.11,62.49 44.47,62.49 44.62,62.64 44.62,62.89 44.77,63.04 45.13,63.04 45.28,62.89 45.28,62.64 45.43,62.49 64.16,62.49 64.33,62.65 64.33,64.16 64.68,64.52 65.13,64.52 65.29,64.36 65.29,63.77 65.45,63.62 66.09,63.62 66.25,63.77 66.25,65.05 66.37,65.17 67.08,65.17 67.2,65.05 67.2,63.77 67.36,63.62 68,63.62 68.16,63.77 68.16,64.4 68.29,64.53 69,64.53 69.12,64.4 69.12,63.67 69.25,63.54 69.95,63.54 70.08,63.67 70.08,64.36 70.24,64.52 75.82,64.52 76.32,65.01 77.37,65.01 78.37,66.01 79.43,66.01 80.14,66.73 81.57,66.73 81.81,66.96 81.81,67.48 82.35,68.02 v4(82.75,68.02)
RP_DDR4_DIMM1_BA1: length 62
  TOP w0.178: CONN7.145 34.12,64.95 34.59,65.42 v2(34.59,65.82) ; U9.CL51 v4(81.26,68.88)
  S8 w0.089: 80.46,65.86 80.87,65.86 81.15,66.15 81.15,66.52 81.77,67.14 81.77,67.38 81.3,67.85 81.3,68.84 v4(81.26,68.88)
  S8 w0.152: v2(34.59,65.82) 34.38,65.61 34.38,64.8 35.05,64.12 39.56,64.12 41.77,61.91 44.78,61.91 44.93,61.76 44.93,61.33 45.06,61.21 45.76,61.21 45.89,61.33 45.89,61.76 46.05,61.91 52.36,61.91 52.51,61.76 52.51,61.33 52.64,61.21 53.34,61.21 53.47,61.33 53.47,61.76 53.62,61.91 56.39,61.91 56.55,61.76 56.55,61.33 56.68,61.21 57.38,61.21 57.51,61.33 57.51,61.76 57.66,61.91 58.31,61.91 58.46,61.76 58.46,61.33 58.59,61.21 59.29,61.21 59.42,61.33 59.42,61.76 59.57,61.91 60.22,61.91 60.37,61.76 60.37,61.33 60.5,61.21 61.2,61.21 61.33,61.33 61.33,61.76 61.48,61.91 71.31,61.91 72.09,62.69 76.94,62.69 80.11,65.86 80.46,65.86
RP_DDR4_DIMM1_BG0: length 58.7
  TOP w0.178: v2(37.46,74.86) 37.46,74.79 36.86,74.2 35.83,74.2 35.78,74.26 34.4,74.26 34.21,74.45 CONN7.115 ; U9.CM33 v4(80.77,76.61)
  S10 w0.152: v2(37.46,74.86) 37.41,74.82 37.41,74.36 37.63,74.14 37.95,74.14 38.03,74.23 40.22,74.23 41.96,72.48 42.58,72.48 42.73,72.33 42.73,72.16 42.89,72.01 43.24,72.01 43.39,72.16 43.39,72.33 43.55,72.48 43.9,72.48 44.05,72.33 44.05,72.16 44.21,72.01 44.56,72.01 44.71,72.16 44.71,72.33 44.87,72.48 46.21,72.48 46.58,72.11 46.58,71.81 47,71.38 51.43,71.38 52.7,72.65 53.45,72.65 53.61,72.8 53.61,73.29 53.77,73.45 54.41,73.45 54.57,73.29 54.57,72.8 54.73,72.65 55.37,72.65 55.53,72.8 55.53,73.29 55.69,73.45 56.33,73.45 56.49,73.29 56.49,72.8 56.65,72.65 56.96,72.65 59.99,75.67 61.37,75.67 61.53,75.51 61.53,74.8 61.67,74.65 62.34,74.65 62.49,74.8 62.49,75.51 62.65,75.67 66.63,75.67 67.39,74.91 77.3,74.91 78.99,76.61 v4(80.77,76.61)
RP_DDR4_DIMM1_BG1: length 59
  TOP w0.178: CONN7.113 34.44,74.95 34.6,74.79 35.73,74.79 v2(35.83,74.89) ; U9.CD35 v4(84.23,75.75)
  S8 w0.152: v2(35.83,74.89) 35.32,74.89 35.08,74.66 35.08,74.38 35.32,74.13 41.63,74.13 42.51,73.25 61.7,73.25 61.87,73.08 76.55,73.08 78.04,74.58 78.04,76.1 79.87,77.94 80.48,77.94 80.65,77.76 80.92,77.76 81.11,77.95 81.42,77.95 81.55,77.82 82.06,77.82 82.16,77.92 82.46,77.92 82.76,77.63 82.76,77.3 83.09,76.97 83.39,76.97 83.49,77.07 83.89,77.07 84.23,76.72 v4(84.23,75.75)
RP_DDR4_DIMM1_CKE0_L: length 57.4
  TOP w0.178: v2(35.88,75.9) 35.83,75.95 CONN7.109 ; U9.CD32 v4(84.23,77.46)
  S8 w0.152: v2(35.88,75.9) 35.88,75.86 36.38,75.35 37.34,75.35 37.49,75.51 37.49,75.77 37.64,75.92 38,75.92 38.15,75.77 38.15,75.51 38.3,75.35 41.36,75.35 42.49,74.22 61.42,74.22 62.03,73.61 68.99,73.61 69.44,74.06 76.76,74.06 77.46,74.76 77.46,76.59 79.66,78.79 80.97,78.79 81.12,78.63 81.43,78.63 81.54,78.73 82.51,78.73 82.56,78.78 82.92,78.78 83.21,78.49 83.21,78.27 84.02,77.46 v4(84.23,77.46)
RP_DDR4_DIMM1_CKE1_L: length 57.1
  TOP w0.178: CONN7.110 39.15,75.7 38.34,74.89 v2(38.34,74.84) ; U9.CG32 v4(83.24,77.46)
  S10 w0.152: v2(38.34,74.84) 38.34,75.5 38.55,75.71 40.26,75.71 41.55,74.42 42.2,74.42 42.32,74.55 42.32,75.56 42.45,75.69 44.16,75.69 44.29,75.56 44.29,74.61 44.48,74.42 44.96,74.42 45.11,74.58 45.11,75.56 45.26,75.72 45.62,75.72 45.77,75.56 45.77,74.58 45.92,74.42 52.57,74.42 52.72,74.58 52.72,74.73 52.88,74.88 53.23,74.88 53.38,74.73 53.38,74.58 53.54,74.42 57.36,74.42 59.59,76.65 76.19,76.65 77.52,77.99 80.26,77.99 80.33,77.91 81.39,77.91 81.53,77.77 81.91,77.77 82.16,78.03 82.45,78.03 83.01,77.46 v4(83.24,77.46)
RP_DDR4_DIMM1_CLK0_N: length 62.7
  TOP w0.114: U9.CJ47 v4(82.25,70.6)
  TOP w0.152: v2(36.73,67.54) 36.48,67.78 35.51,67.78 34.75,68.54 34.38,68.54 34.3,68.45 CONN7.139
  S8 w0.089: 80.11,69.96 80.16,70.01 80.49,70.01 80.7,70.22 81.87,70.22 v4(82.25,70.6)
  S8 w0.102: 38.37,68.04 38.34,68.04 38.32,68.06 37.61,68.06 37.39,67.85 37.03,67.85 v2(36.73,67.54)
  S8 w0.127: 38.37,68.04 40.44,68.04 42.04,66.45 44.34,66.45 46.56,64.23 52.97,64.23 54.1,65.36 61.54,65.36 61.67,65.23 61.67,64.21 61.94,63.94 62.52,63.94 62.78,64.21 62.78,65.23 62.91,65.36 63.29,65.36 63.42,65.23 63.42,64.21 63.69,63.94 64.27,63.94 64.54,64.21 64.54,65.23 64.66,65.36 65.05,65.36 65.17,65.23 65.17,64.21 65.44,63.94 66.02,63.94 66.29,64.21 66.29,65.23 66.42,65.36 67.44,65.36 67.79,65.71 77.1,65.71 78.06,66.67 78.69,66.67 79.71,67.69 79.71,69.55 80.11,69.96
RP_DDR4_DIMM1_CLK0_P: length 62.8
  TOP w0.114: U9.CL47 v4(81.26,70.6)
  TOP w0.152: v2(36.73,68.35) 36.48,68.11 35.65,68.11 34.89,68.87 34.38,68.87 34.3,68.95 CONN7.137
  S8 w0.089: v4(81.26,70.6) 80.8,70.6 80.41,70.2 80.01,70.2
  S8 w0.102: 38.37,68.28 38.34,68.28 38.32,68.27 37.52,68.27 37.31,68.05 37.03,68.05 v2(36.73,68.35)
  S8 w0.127: 80.01,70.2 79.46,69.65 79.46,67.79 78.59,66.92 77.96,66.92 77,65.95 67.69,65.95 67.34,65.6 66.32,65.6 66.05,65.33 66.05,64.31 65.92,64.18 65.54,64.18 65.41,64.31 65.41,65.33 65.15,65.6 64.56,65.6 64.3,65.33 64.3,64.31 64.17,64.18 63.79,64.18 63.66,64.31 63.66,65.33 63.39,65.6 62.81,65.6 62.54,65.33 62.54,64.31 62.42,64.18 62.04,64.18 61.91,64.31 61.91,65.33 61.64,65.6 54,65.6 52.87,64.47 49.4,64.47 49.27,64.6 49.27,64.77 49.14,64.9 48.76,64.9 48.64,64.77 48.64,64.6 48.51,64.47 48.13,64.47 48,64.6 48,64.77 47.87,64.9 47.49,64.9 47.37,64.77 47.37,64.6 47.24,64.47 46.66,64.47 44.44,66.69 42.14,66.69 40.54,68.28 38.37,68.28
RP_DDR4_DIMM1_CLK1_N: length 60.4
  TOP w0.114: U9.CG47 v4(83.24,70.6)
  TOP w0.152: v2(39.16,67.49) 38.89,67.49 38.69,67.69 38.69,68.07 38.91,68.29 40.18,68.29 40.27,68.2 CONN7.140
  S10 w0.127: v2(39.16,67.49) 38.84,67.49 38.64,67.68 38.64,67.94 38.86,68.16 40.38,68.16 42.12,66.42 43,66.42 43.13,66.29 43.13,66.19 43.25,66.07 43.63,66.07 43.76,66.19 43.76,66.29 43.89,66.42 44.51,66.42 44.64,66.29 44.64,66.14 44.76,66.01 45.14,66.01 45.27,66.14 45.27,66.29 45.4,66.42 45.78,66.42 45.91,66.29 45.91,66.14 46.03,66.01 46.41,66.01 46.54,66.14 46.54,66.29 46.67,66.42 58.07,66.42 59.16,67.51 59.34,67.51 59.71,67.14 60.09,67.14 60.5,67.56 60.5,67.94 60.13,68.3 60.13,68.48 60.96,69.31 61.42,69.31 61.55,69.18 61.55,68.57 61.81,68.3 62.39,68.3 62.66,68.57 62.66,69.18 62.79,69.31 63.17,69.31 63.3,69.18 63.3,68.57 63.57,68.3 64.15,68.3 64.42,68.57 64.42,69.18 64.54,69.31 64.92,69.31 65.05,69.18 65.05,68.57 65.32,68.3 65.9,68.3 66.17,68.57 66.17,69.18 66.3,69.31 76.62,69.31 78.63,71.33 80.18,71.33 80.49,71.01 82.83,71.01 v4(83.24,70.6)
RP_DDR4_DIMM1_CLK1_P: length 60.4
  TOP w0.102: U9.CF45 v4(83.74,71.45)
  TOP w0.152: v2(37.89,67.49) 38.15,67.49 38.36,67.7 38.36,68.2 38.77,68.62 40.18,68.62 40.27,68.7 CONN7.138
  S10 w0.127: v2(37.89,67.49) 38.21,67.49 38.4,67.68 38.4,68.04 38.76,68.4 40.48,68.4 42.22,66.66 57.97,66.66 59.06,67.75 59.44,67.75 59.81,67.39 59.99,67.39 60.26,67.66 60.26,67.84 59.89,68.2 59.89,68.58 60.86,69.55 61.52,69.55 61.79,69.28 61.79,68.67 61.91,68.54 62.29,68.54 62.42,68.67 62.42,69.28 62.69,69.55 63.27,69.55 63.54,69.28 63.54,68.67 63.67,68.54 64.05,68.54 64.17,68.67 64.17,69.28 64.44,69.55 65.02,69.55 65.29,69.28 65.29,68.67 65.42,68.54 65.8,68.54 65.93,68.67 65.93,69.28 66.19,69.55 76.51,69.55 78.53,71.57 80.17,71.57 80.47,71.86 83.33,71.86 v4(83.74,71.45)
RP_DDR4_DIMM1_CS0_L: length 57.2
  TOP w0.178: v2(35.48,65.82) 35.48,64.82 34.61,63.95 CONN7.149 ; U9.CL54 v4(81.26,67.16)
  S8 w0.152: v2(35.48,65.82) 35.33,65.67 35.33,65 35.72,64.61 40.27,64.61 42.43,62.45 68.52,62.45 68.65,62.58 68.65,63.9 68.78,64.03 69.46,64.03 69.58,63.9 69.58,62.58 69.71,62.45 71.16,62.45 71.49,62.78 71.49,63.34 71.97,63.82 77.06,63.82 79.86,66.62 80.41,66.62 80.95,67.16 v4(81.26,67.16)
RP_DDR4_DIMM1_CS1_L: length 56.6
  TOP w0.178: CONN7.157 36.08,61.95 v2(36.82,61.21) ; U9.CJ58 v4(82.25,65.45)
  S10 w0.152: v4(82.25,65.45) 82.16,65.53 81.9,65.53 81.51,65.92 81.1,65.92 81.05,65.87 79.98,65.87 79.69,65.58 79.23,65.58 78.84,65.19 78.84,64.23 78.22,63.61 71.76,63.61 71.2,63.05 65.42,63.05 64.36,62 42.34,62 41.93,62.41 41.37,62.41 41.19,62.23 41.19,61.34 41.06,61.21 40.36,61.21 40.23,61.34 40.23,62.23 40.05,62.41 39.01,62.41 38.85,62.26 38.85,61.95 38.7,61.8 38.35,61.8 38.19,61.95 38.19,62.26 38.04,62.41 37.01,62.41 36.7,62.1 36.7,61.33 v2(36.82,61.21)
RP_DDR4_DIMM1_DQ0: length 67.8
  TOP w0.102: U9.BY2 85.96,91.22 85.96,93.96 85.51,94.42 v3(85.38,94.42)
  TOP w0.114: v2(38.34,102.25) 39.39,101.2 CONN7.8
  S10 w0.102: v2(38.34,102.25) 38.96,101.63 40.93,101.63 41.13,101.83 44.56,101.83 47.85,105.12 50.95,105.12 51.05,105.02 51.05,104.57 51.15,104.47 51.56,104.47 51.66,104.57 51.66,105.02 51.76,105.12 52.17,105.12 52.27,105.02 52.27,104.57 52.37,104.47 52.78,104.47 52.88,104.57 52.88,105.02 52.98,105.12 53.39,105.12 53.49,105.02 53.49,104.57 53.59,104.47 54,104.47 54.1,104.57 54.1,105.02 54.2,105.12 54.61,105.12 54.71,105.02 54.71,104.57 54.81,104.47 55.22,104.47 55.32,104.57 55.32,105.02 55.42,105.12 55.83,105.12 55.93,105.02 55.93,104.57 56.03,104.47 56.44,104.47 56.54,104.57 56.54,105.02 56.64,105.12 59.07,105.12 60.62,106.68 67.69,106.68 73.76,100.61 79.98,100.61 83.27,97.32 83.27,95.85 84.81,94.31 85.27,94.31 v3(85.38,94.42)
RP_DDR4_DIMM1_DQ1: length 67.7
  TOP w0.102: U9.BY4 85.97,90.69 85.64,91.02 85.64,91.35 85.76,91.47 85.76,92.62 v3(85.48,92.9)
  TOP w0.114: CONN7.7 35.03,101.45 35.33,101.76 35.74,101.76 v2(36.21,102.23)
  S10 w0.102: v3(85.48,92.9) 85.43,92.9 82.51,95.82 82.51,96.91 81.63,97.79 81.63,98.27 79.78,100.12 73.54,100.12 67.5,106.16 61.36,106.16 58.81,103.61 58.67,103.61 58.2,104.08 58.06,104.08 57.77,103.79 57.77,103.65 58.24,103.18 58.24,103.04 57.95,102.75 57.8,102.75 57.34,103.22 57.19,103.22 56.91,102.93 56.91,102.79 57.37,102.32 57.37,102.18 57.03,101.83 45.47,101.83 44.97,101.33 41.81,101.33 41.56,101.07 38.67,101.07 37.38,102.36 36.34,102.36 v2(36.21,102.23)
RP_DDR4_DIMM1_DQ2: length 68
  TOP w0.102: U9.CD2 83.99,91 84.04,90.95 84.04,90.7 84.35,90.39 84.62,90.39 84.82,90.58 84.82,90.89 84.65,91.06 84.65,91.35 84.33,91.68 84.32,91.68 84.21,91.79 84.21,92.12 84.46,92.37 84.46,93.81 82.68,95.59 82.07,95.59 v3(81.99,95.52)
  TOP w0.114: v2(38.4,99.62) 38.4,99.35 39.55,98.2 CONN7.20
  S10 w0.102: v2(38.4,99.62) 38.4,99.5 38.89,99.01 40.32,99.01 42.71,96.62 50.37,96.62 50.72,96.27 50.72,95.99 50.83,95.89 51.31,95.89 51.41,95.99 51.41,96.44 51.51,96.55 51.92,96.55 52.02,96.44 52.02,95.99 52.12,95.89 52.53,95.89 52.63,95.99 52.63,96.44 52.73,96.55 53.14,96.55 53.24,96.44 53.24,95.99 53.34,95.89 53.75,95.89 53.85,95.99 53.85,96.44 53.95,96.55 54.36,96.55 54.46,96.44 54.46,95.99 54.56,95.89 54.97,95.89 55.07,95.99 55.07,96.44 55.17,96.55 55.58,96.55 55.68,96.44 55.68,95.99 55.78,95.89 56.87,95.89 57.73,95.02 58.22,95.02 58.32,95.12 58.32,96.01 58.42,96.11 58.83,96.11 58.93,96.01 58.93,95.12 59.03,95.02 59.44,95.02 59.54,95.12 59.54,96.01 59.64,96.11 60.05,96.11 60.15,96.01 60.15,95.12 60.25,95.02 71.94,95.02 74.57,97.66 78.46,97.66 80.41,95.71 80.56,95.71 80.76,95.52 v3(81.99,95.52)
RP_DDR4_DIMM1_DQ3: length 68
  TOP w0.102: U9.CD4 83.83,90.39 83.83,90.87 83.53,91.17 83.53,91.55 83.78,91.79 83.78,92.26 84.05,92.54 84.05,93.13 83.66,93.52 v3(83.61,93.52)
  TOP w0.114: v2(37.12,97.47) 36.29,98.31 34.55,98.31 34.2,97.95 CONN7.21
  S10 w0.102: v2(37.12,97.47) 36.65,97.94 33.43,97.94 33.15,97.66 33.15,95.5 33.38,95.28 33.99,95.28 34.29,95.58 34.29,96.09 34.81,96.61 39.42,96.61 41.14,94.89 56.31,94.89 57.23,93.98 76.1,93.98 76.74,94.62 79.32,94.62 79.72,94.23 81.76,94.23 82.08,93.91 82.6,93.91 82.98,93.52 v3(83.61,93.52)
RP_DDR4_DIMM1_DQ4: length 67.8
  TOP w0.102: U9.BW1 86.47,94.69
  TOP w0.114: CONN7.4 40.03,102.2 v2(39.96,102.27) ; v3(83.94,96.13) 85.02,96.13 86.47,94.69
  S10 w0.102: v2(39.96,102.27) 39.96,102.5 43.08,105.62 58.44,105.62 59.98,107.16 69.83,107.16 70.99,106.01 70.99,105.86 70.4,105.28 70.4,105.14 70.69,104.85 70.84,104.85 71.42,105.43 71.56,105.43 71.85,105.14 71.85,105 71.27,104.42 71.27,104.27 71.55,103.99 71.7,103.99 72.28,104.57 72.42,104.57 72.71,104.28 72.71,104.14 72.13,103.55 72.13,103.41 72.42,103.12 72.56,103.12 73.14,103.71 73.29,103.71 73.57,103.42 73.57,103.27 72.99,102.69 72.99,102.55 73.28,102.26 73.42,102.26 74.01,102.84 74.15,102.84 74.44,102.56 74.44,102.41 73.85,101.83 73.85,101.68 74.14,101.4 74.29,101.4 74.87,101.98 75.01,101.98 75.87,101.12 80.16,101.12 83.94,97.34 v3(83.94,96.13)
RP_DDR4_DIMM1_DQ5: length 67.7
  TOP w0.102: U9.BW3 86.36,90.83 86.36,91.62 86.19,91.79 86.19,94.19 85.26,95.12 v3(85.08,95.12)
  TOP w0.114: CONN7.3 34.43,102.45 v2(34.63,102.25)
  S10 w0.102: v3(85.08,95.12) 85.08,96.89 80.28,101.69 76.02,101.69 70.07,107.65 59.53,107.65 58.02,106.14 42.25,106.14 41.91,105.79 41.91,105.65 42.1,105.46 42.1,105.32 41.81,105.03 41.66,105.03 41.47,105.22 41.33,105.22 41.04,104.93 41.04,104.79 41.23,104.6 41.23,104.45 40.95,104.17 40.8,104.17 40.61,104.36 40.47,104.36 40.18,104.07 40.18,103.93 40.37,103.74 40.37,103.59 40.08,103.3 39.94,103.3 39.75,103.49 39.61,103.49 38.98,102.87 35.1,102.87 34.63,102.4 v2(34.63,102.25)
RP_DDR4_DIMM1_DQ6: length 68
  TOP w0.102: U9.CC1 84.49,92.03 84.66,92.21 84.66,93.97 82.49,96.14 v3(81.55,96.14)
  TOP w0.114: v2(40.02,99.61) 40.43,99.2 CONN7.16
  S10 w0.102: v3(81.55,96.14) 81.48,96.07 80.89,96.07 78.68,98.28 74.38,98.28 71.73,95.63 61.47,95.63 58.78,98.32 55.37,98.32 55.27,98.22 55.27,97.23 55.17,97.13 54.76,97.13 54.66,97.23 54.66,98.22 54.56,98.32 54.15,98.32 54.05,98.22 54.05,97.23 53.95,97.13 53.54,97.13 53.44,97.23 53.44,98.22 53.34,98.32 52.27,98.32 52.17,98.22 52.17,97.76 52.07,97.66 51.66,97.66 51.56,97.76 51.56,98.22 51.46,98.32 51.05,98.32 50.95,98.22 50.95,97.76 50.85,97.66 50.44,97.66 50.34,97.76 50.34,98.22 50.24,98.32 49.83,98.32 49.73,98.22 49.73,97.76 49.63,97.66 49.22,97.66 49.12,97.76 49.12,98.22 49.02,98.32 48.61,98.32 48.51,98.22 48.51,97.76 48.41,97.66 48,97.66 47.9,97.76 47.9,98.22 47.8,98.32 47.32,98.32 47.22,98.22 47.22,97.84 47.11,97.74 46.71,97.74 46.61,97.84 46.61,98.22 46.5,98.32 46.02,98.32 45.92,98.22 45.92,97.21 45.82,97.1 45.41,97.1 45.31,97.21 45.31,98.22 45.21,98.32 44.8,98.32 44.7,98.22 44.7,97.21 44.6,97.1 44.19,97.1 44.09,97.21 44.09,98.22 43.99,98.32 43.51,98.32 43.41,98.22 43.41,97.69 43.3,97.59 42.9,97.59 42.8,97.69 42.8,98.22 42.69,98.32 41.72,98.32 40.44,99.61 v2(40.02,99.61)
RP_DDR4_DIMM1_DQ7: length 67.7
  TOP w0.102: U9.CC3 84.44,90.76 84.44,91.27 83.98,91.73 83.98,92.18 84.26,92.46 84.26,93.73 83.85,94.14 v3(83.21,94.14)
  TOP w0.114: v2(36.77,99.62) 36.21,99.05 34.16,99.05 34.06,98.95 CONN7.17
  S10 w0.102: v2(36.77,99.62) 33.32,99.62 33.13,99.43 33.13,98.68 33.3,98.51 34.8,98.51 34.9,98.62 34.9,98.91 35,99.01 35.41,99.01 35.51,98.91 35.51,98.62 35.61,98.51 36.02,98.51 36.12,98.62 36.12,98.91 36.22,99.01 36.63,99.01 36.73,98.91 36.73,98.62 36.83,98.51 37.24,98.51 37.34,98.62 37.34,98.91 37.44,99.01 37.85,99.01 37.95,98.91 37.95,98.62 38.05,98.51 39.64,98.51 42.75,95.4 56.54,95.4 57.43,94.51 75.77,94.51 76.47,95.22 79.57,95.22 79.97,94.82 82.01,94.82 82.33,94.5 82.85,94.5 v3(83.21,94.14)
RP_DDR4_DIMM1_DQ8: length 64.2
  TOP w0.114: U9.CC7 v4(84.73,88.63) ; v2(38.32,97.33) 38.89,96.76 39.16,96.76 39.72,96.2 CONN7.28
  S5 w0.102: v2(38.32,97.33) 38.32,97.37 39.22,98.28 43.58,98.28 43.68,98.38 43.68,98.65 43.79,98.76 44.19,98.76 44.29,98.65 44.29,98.38 44.4,98.28 59.63,98.28 61.65,96.27 67.82,96.27 69.25,97.69 69.96,97.69 70.06,97.59 70.06,97.16 70.16,97.05 70.57,97.05 70.67,97.16 70.67,97.59 70.77,97.69 71.17,97.69 71.28,97.59 71.28,97.16 71.38,97.05 71.78,97.05 71.89,97.16 71.89,97.59 71.99,97.69 72.39,97.69 72.5,97.59 72.5,97.16 72.6,97.05 73,97.05 73.11,97.16 73.11,97.59 73.21,97.69 78.74,97.69 83.11,93.32 83.11,92.07 84.84,90.34 84.84,90.26 86.11,88.99 86.11,88.4 85.85,88.14 85.41,88.14 84.92,88.63 v4(84.73,88.63)
RP_DDR4_DIMM1_DQ9: length 64.3
  TOP w0.114: U9.CB9 v4(85.22,87.77) ; CONN7.29 v2(35.03,95.95)
  S5 w0.102: v2(35.03,95.95) 35.03,94.97 34.68,94.62 33.02,94.62 32.8,94.84 32.8,96.43 33.03,96.67 55.7,96.67 57.28,95.1 70.77,95.1 71.13,94.73 78.76,94.73 83.26,90.23 83.26,89.63 83.88,89.02 84.1,89.02 84.19,88.93 84.19,88.5 84.93,87.77 v4(85.22,87.77)
RP_DDR4_DIMM1_DQ10: length 64
  TOP w0.114: v2(36.42,93.22) 36.22,93.42 34.72,93.42 34.25,92.95 CONN7.41 ; U9.CM7 v4(80.77,88.63)
  S5 w0.102: v2(36.42,93.22) 37.05,93.85 41.64,93.85 44.31,91.19 53.8,91.19 53.91,91.29 53.91,91.54 54.01,91.64 54.41,91.64 54.52,91.54 54.52,91.29 54.62,91.19 55.26,91.19 55.36,91.29 55.36,91.59 55.47,91.69 55.87,91.69 55.97,91.59 55.97,91.29 56.08,91.19 56.48,91.19 56.58,91.29 56.58,91.59 56.68,91.69 57.09,91.69 57.19,91.59 57.19,91.29 57.29,91.19 57.7,91.19 57.8,91.29 57.8,91.59 57.9,91.69 58.31,91.69 58.41,91.59 58.41,91.29 58.51,91.19 58.92,91.19 59.02,91.29 59.02,91.59 59.12,91.69 59.53,91.69 59.63,91.59 59.63,91.29 59.73,91.19 60.14,91.19 60.24,91.29 60.24,91.59 60.34,91.69 60.75,91.69 60.85,91.59 60.85,91.29 60.95,91.19 61.36,91.19 61.46,91.29 61.46,91.59 61.56,91.69 61.97,91.69 62.07,91.59 62.07,91.29 62.17,91.19 62.58,91.19 62.68,91.29 62.68,91.59 62.78,91.69 63.19,91.69 63.29,91.59 63.29,91.29 63.39,91.19 63.8,91.19 63.9,91.29 63.9,91.59 64,91.69 64.41,91.69 64.51,91.59 64.51,91.29 64.61,91.19 65.02,91.19 65.12,91.29 65.12,91.59 65.22,91.69 65.63,91.69 65.73,91.59 65.73,91.29 65.83,91.19 66.24,91.19 66.34,91.29 66.34,91.59 66.44,91.69 66.84,91.69 66.95,91.59 66.95,91.29 67.05,91.19 67.45,91.19 67.56,91.29 67.56,91.59 67.66,91.69 68.06,91.69 68.17,91.59 68.17,91.29 68.27,91.19 68.67,91.19 68.78,91.29 68.78,91.59 68.88,91.69 69.28,91.69 69.38,91.59 69.38,91.29 69.49,91.19 69.89,91.19 69.99,91.29 69.99,91.59 70.1,91.69 70.5,91.69 70.6,91.59 70.6,91.29 70.71,91.19 71.11,91.19 71.21,91.29 71.21,91.59 71.32,91.69 71.72,91.69 71.82,91.59 71.82,91.29 71.92,91.19 72.33,91.19 72.43,91.29 72.43,91.59 72.53,91.69 72.94,91.69 73.04,91.59 73.04,91.29 73.14,91.19 73.55,91.19 73.65,91.29 73.65,91.59 73.75,91.69 74.16,91.69 74.26,91.59 74.26,91.29 74.36,91.19 74.69,91.19 75.2,90.68 76.17,90.68 76.85,89.99 79.43,89.99 80.77,88.66 v4(80.77,88.63)
RP_DDR4_DIMM1_DQ11: length 64.3
  TOP w0.114: v2(39.69,93.15) 40.14,92.7 CONN7.42 ; U9.CL9 v4(81.26,87.77)
  S5 w0.102: v2(39.69,93.15) 39.74,93.19 41.46,93.19 44.83,89.81 45.67,89.81 45.78,89.92 45.78,90.12 45.88,90.22 46.28,90.22 46.39,90.12 46.39,89.92 46.49,89.81 50.7,89.81 50.8,89.92 50.8,90.47 50.9,90.58 51.31,90.58 51.41,90.47 51.41,89.92 51.51,89.81 51.92,89.81 52.02,89.92 52.02,90.47 52.12,90.58 52.53,90.58 52.63,90.47 52.63,89.92 52.73,89.81 53.14,89.81 53.24,89.92 53.24,90.47 53.34,90.58 53.75,90.58 53.85,90.47 53.85,89.92 53.95,89.81 54.36,89.81 54.46,89.92 54.46,90.47 54.56,90.58 54.97,90.58 55.07,90.47 55.07,89.92 55.17,89.81 55.58,89.81 55.68,89.92 55.68,90.47 55.78,90.58 56.18,90.58 56.29,90.47 56.29,89.92 56.39,89.81 56.79,89.81 56.9,89.92 56.9,90.47 57,90.58 57.4,90.58 57.51,90.47 57.51,89.92 57.61,89.81 58.01,89.81 58.12,89.92 58.12,90.47 58.22,90.58 58.62,90.58 58.72,90.47 58.72,89.92 58.83,89.81 59.23,89.81 59.33,89.92 59.33,90.47 59.44,90.58 59.84,90.58 59.94,90.47 59.94,89.92 60.05,89.81 60.45,89.81 60.55,89.92 60.55,90.47 60.66,90.58 61.06,90.58 61.16,90.47 61.16,89.92 61.26,89.81 61.67,89.81 61.77,89.92 61.77,90.47 61.87,90.58 62.28,90.58 62.38,90.47 62.38,89.92 62.48,89.81 62.89,89.81 62.99,89.92 62.99,90.47 63.09,90.58 63.5,90.58 63.6,90.47 63.6,89.92 63.7,89.81 64.11,89.81 64.21,89.92 64.21,90.47 64.31,90.58 64.72,90.58 64.82,90.47 64.82,89.92 64.92,89.81 65.33,89.81 65.43,89.92 65.43,90.47 65.53,90.58 65.94,90.58 66.04,90.47 66.04,89.92 66.14,89.81 66.62,89.81 67.49,90.68 74.37,90.68 74.97,90.08 76.04,90.08 76.62,89.5 77.92,89.5 78.64,88.78 79.86,88.78 80.87,87.77 v4(81.26,87.77)
RP_DDR4_DIMM1_DQ12: length 64.3
  TOP w0.114: v2(39.94,97.35) 40.25,97.35 40.4,97.2 CONN7.24 ; U9.CA7 85.52,88.74 v4(85.72,88.63)
  S5 w0.102: v4(85.72,88.63) 85.31,89.03 84.7,89.03 84.46,89.27 84.46,89.89 79.13,95.22 75.37,95.22 75.27,95.32 75.27,96.34 75.17,96.44 74.76,96.44 74.66,96.34 74.66,95.32 74.56,95.22 74.15,95.22 74.05,95.32 74.05,96.34 73.95,96.44 73.54,96.44 73.44,96.34 73.44,95.32 73.34,95.22 72.93,95.22 72.83,95.32 72.83,96.34 72.73,96.44 72.32,96.44 72.22,96.34 72.22,95.32 72.12,95.22 71.49,95.22 71.03,95.68 60.73,95.68 58.71,97.71 57.46,97.71 57.35,97.6 57.35,97.43 57.25,97.33 56.85,97.33 56.74,97.43 56.74,97.6 56.64,97.71 56.24,97.71 56.14,97.6 56.14,97.43 56.03,97.33 55.63,97.33 55.53,97.43 55.53,97.6 55.42,97.71 55.02,97.71 54.92,97.6 54.92,97.43 54.81,97.33 54.41,97.33 54.31,97.43 54.31,97.6 54.2,97.71 53.8,97.71 53.7,97.6 53.7,97.43 53.6,97.33 53.19,97.33 53.09,97.43 53.09,97.6 52.99,97.71 45.52,97.71 45.42,97.6 45.42,97.25 45.32,97.15 44.91,97.15 44.81,97.25 44.81,97.6 44.71,97.71 44.3,97.71 44.2,97.6 44.2,97.25 44.1,97.15 43.69,97.15 43.59,97.25 43.59,97.6 43.49,97.71 43.08,97.71 42.98,97.6 42.98,97.25 42.88,97.15 42.47,97.15 42.37,97.25 42.37,97.6 42.27,97.71 41.86,97.71 41.76,97.6 41.76,97.25 41.66,97.15 41.25,97.15 41.15,97.25 41.15,97.6 41.05,97.71 40.25,97.71 39.94,97.4 v2(39.94,97.35)
RP_DDR4_DIMM1_DQ13: length 64
  TOP w0.114: U9.BY9 v4(86.21,87.77) ; v2(35.49,97.45) 34.99,96.95 CONN7.25
  S5 w0.102: v4(86.21,87.77) 86.31,87.86 86.31,90.65 84.3,92.66 84.3,94.21 79.59,98.93 69,98.93 66.85,96.77 62.13,96.77 59.49,99.41 41.65,99.41 41.15,98.91 36.95,98.91 v2(35.49,97.45)
RP_DDR4_DIMM1_DQ14: length 64.1
  TOP w0.114: CONN7.38 40.2,93.7 39.82,94.08 38.35,94.08 v2(37.18,95.25) ; U9.CK7 v4(81.76,88.63)
  S5 w0.102: v4(81.76,88.63) 81.58,88.8 81.58,89.52 81.14,89.97 80.88,89.97 80.28,90.57 77.12,90.57 76.42,91.27 75.62,91.27 74.61,92.28 56.49,92.28 56.01,92.76 44.78,92.76 43.2,94.34 36.61,94.34 35.1,92.84 34.49,92.84 34.39,92.94 34.39,93.24 34.29,93.34 33.88,93.34 33.78,93.24 33.78,92.94 33.68,92.84 33.2,92.84 32.96,93.08 32.96,93.81 33.2,94.06 34.98,94.06 35.81,94.89 36.86,94.89 37.18,95.22 v2(37.18,95.25)
RP_DDR4_DIMM1_DQ15: length 64
  TOP w0.114: U9.CJ9 v4(82.25,87.77) ; CONN7.37 34.19,93.95 34.41,94.17 37.2,94.17 38.05,93.33 v2(38.05,93.15)
  S5 w0.102: v2(38.05,93.15) 38.05,93.12 38.61,92.55 40.23,92.55 40.49,92.3 40.49,91.39 40.13,91.03 39.09,91.03 38.94,90.88 38.94,89.81 39.26,89.5 39.94,89.5 40.21,89.23 41.05,89.23 41.15,89.33 41.15,92 41.26,92.1 41.66,92.1 41.76,92 41.76,89.33 41.87,89.23 42.98,89.23 43.09,89.33 43.09,89.64 43.19,89.74 43.59,89.74 43.7,89.64 43.7,89.33 43.8,89.23 66.9,89.23 67.69,90.02 74.09,90.02 74.63,89.48 75.79,89.48 76.43,88.84 77.82,88.84 78.53,88.12 79.76,88.12 80.52,87.36 81.76,87.36 82.16,87.77 v4(82.25,87.77)
RP_DDR4_DIMM1_DQ16: length 60.6
  TOP w0.114: CONN7.50 39.41,90.7 v2(38.34,91.77) ; U9.CB13 v4(85.22,86.05)
  S10 w0.102: v2(38.34,91.77) 38.34,91.93 38.76,92.35 39.89,92.35 40.24,92.7 40.72,92.7 40.83,92.8 40.83,93.45 40.93,93.56 41.33,93.56 41.44,93.45 41.44,92.8 41.54,92.7 48.46,92.7 48.7,92.94 48.7,93.34 48.79,93.43 49.21,93.43 49.3,93.34 49.3,92.75 49.39,92.66 52.16,92.66 52.25,92.75 52.25,93.34 52.34,93.43 52.76,93.43 52.85,93.34 52.85,92.75 52.94,92.66 53.36,92.66 53.44,92.75 53.44,93.34 53.53,93.43 53.95,93.43 54.04,93.34 54.04,92.75 54.13,92.66 76.45,92.66 77.91,91.2 79.68,91.2 80.23,90.64 81.35,90.64 82.07,89.92 83.06,89.92 83.48,89.5 83.48,89.43 84.15,88.76 84.15,88.52 84.81,87.85 84.81,87.6 85.31,87.1 85.31,86.14 v4(85.22,86.05)
RP_DDR4_DIMM1_DQ17: length 60.2
  TOP w0.114: U9.CC14 v4(84.73,85.19) ; CONN7.49 35.02,90.95 35.37,91.3 37.02,91.3 v2(37.49,91.77)
  S10 w0.102: v4(84.73,85.19) 84.43,85.19 83.76,85.86 83.76,86.26 83.21,86.81 83.21,87.04 82.92,87.34 82.1,87.34 81.67,87.76 81.67,87.94 81.18,88.43 81.18,88.81 80.93,89.06 79.28,89.06 78.51,89.83 77.01,89.83 75.55,91.29 68.54,91.29 68.37,91.12 42.7,91.12 42.24,90.67 39.03,90.67 38.53,91.17 36.52,91.17 36.12,91.56 36.12,92.19 36.36,92.43 37.15,92.43 37.49,92.09 v2(37.49,91.77)
RP_DDR4_DIMM1_DQ18: length 60.5
  TOP w0.114: U9.CL13 v4(81.26,86.05) ; v2(39.44,88.99) 39.44,88.72 40.45,87.7 CONN7.62
  S10 w0.102: v2(39.44,88.99) 41.61,88.99 42.4,88.19 44.3,88.19 44.39,88.28 44.39,88.91 44.48,89 44.89,89 44.98,88.91 44.98,88.28 45.07,88.19 45.49,88.19 45.58,88.28 45.58,88.91 45.67,89 46.09,89 46.94,88.15 51.89,88.15 52.09,88.35 52.09,89.07 52.31,89.3 52.59,89.3 52.82,89.07 52.82,88.28 52.91,88.19 53.33,88.19 53.41,88.28 53.41,89.1 53.59,89.27 53.84,89.27 54.01,89.1 54.01,88.28 54.1,88.19 55.1,88.19 55.23,88.33 55.72,88.33 55.82,88.43 55.82,89.34 55.92,89.45 56.33,89.45 56.43,89.34 56.43,88.43 56.53,88.33 56.94,88.33 57.04,88.43 57.04,89.34 57.14,89.45 57.55,89.45 57.65,89.34 57.65,88.43 57.75,88.33 58.16,88.33 58.26,88.43 58.26,89.34 58.36,89.45 58.76,89.45 58.87,89.34 58.87,88.43 58.97,88.33 59.37,88.33 59.48,88.43 59.48,89.34 59.58,89.45 59.98,89.45 60.09,89.34 60.09,88.43 60.19,88.33 76.37,88.33 77.46,87.24 79.06,87.24 79.45,86.85 80.24,86.85 81.03,86.05 v4(81.26,86.05)
RP_DDR4_DIMM1_DQ19: length 60.3
  TOP w0.114: U9.CM14 v4(80.77,85.19) ; CONN7.63 36.12,87.45 37,88.33 v2(37,88.98)
  S10 w0.102: v4(80.77,85.19) 80.57,85.38 79.6,85.38 78.87,86.11 77.18,86.11 76.07,87.22 68.88,87.22 68.33,86.67 67.85,86.67 67.74,86.77 67.74,87.23 67.64,87.33 67.24,87.33 67.13,87.23 67.13,86.77 67.03,86.67 66.63,86.67 66.53,86.77 66.53,87.23 66.42,87.33 66.02,87.33 65.92,87.23 65.92,86.77 65.81,86.67 65.41,86.67 65.31,86.77 65.31,87.23 65.2,87.33 64.8,87.33 64.7,87.23 64.7,86.77 64.59,86.67 64.19,86.67 64.09,86.77 64.09,87.23 63.99,87.33 63.58,87.33 63.48,87.23 63.48,86.77 63.38,86.67 56.43,86.67 56.21,86.45 55.68,86.45 55.59,86.36 55.59,85.83 55.41,85.65 55.17,85.65 54.99,85.83 54.99,86.36 54.9,86.45 54.48,86.45 54.39,86.36 54.39,85.83 54.22,85.65 53.97,85.65 53.26,86.36 42.55,86.36 41.01,87.9 40.34,87.9 40.24,87.8 40.24,87.38 40.14,87.28 39.73,87.28 39.63,87.38 39.63,87.8 39.53,87.9 39.12,87.9 39.02,87.8 39.02,87.38 38.92,87.28 38.52,87.28 38.41,87.38 38.41,87.8 38.31,87.9 37.55,87.9 37,88.45 v2(37,88.98)
RP_DDR4_DIMM1_DQ20: length 60.2
  TOP w0.114: CONN7.46 39.98,91.7 v2(39.96,91.72) ; U9.BY13 v4(86.21,86.05)
  S10 w0.102: v4(86.21,86.05) 85.8,85.63 84.98,85.63 84.68,85.93 84.68,86.38 84.15,86.91 84.15,87.08 83.65,87.57 83.65,87.94 83.37,88.22 82.45,88.22 82.17,88.5 82.17,88.78 81.88,89.06 81.72,89.06 81.49,89.29 81.49,89.76 81.21,90.05 79.98,90.05 79.65,90.38 77.31,90.38 75.63,92.06 68.47,92.06 68.03,91.63 67.5,91.63 67.41,91.72 67.41,91.97 67.32,92.06 66.9,92.06 66.81,91.97 66.81,91.72 66.73,91.63 66.31,91.63 66.22,91.72 66.22,91.97 66.13,92.06 65.71,92.06 65.62,91.97 65.62,91.72 65.53,91.63 65.11,91.63 65.02,91.72 65.02,91.97 64.93,92.06 64.52,92.06 64.43,91.97 64.43,91.72 64.34,91.63 63.92,91.63 63.83,91.72 63.83,91.97 63.74,92.06 63.32,92.06 63.23,91.97 63.23,91.72 63.14,91.63 62.72,91.63 62.64,91.72 62.64,91.97 62.55,92.06 62.13,92.06 62.04,91.97 62.04,91.72 61.95,91.63 61.53,91.63 61.44,91.72 61.44,91.97 61.35,92.06 60.93,92.06 60.85,91.97 60.85,91.72 60.76,91.63 60.34,91.63 60.25,91.72 60.25,91.97 60.16,92.06 59.74,92.06 59.65,91.97 59.65,91.72 59.56,91.63 59.14,91.63 59.05,91.72 59.05,91.97 58.97,92.06 58.55,92.06 58.46,91.97 58.46,91.72 58.37,91.63 57.95,91.63 57.86,91.72 57.86,91.97 57.77,92.06 57.35,92.06 57.26,91.97 57.26,91.72 57.17,91.63 56.76,91.63 56.67,91.72 56.67,91.97 56.58,92.06 56.16,92.06 56.07,91.97 56.07,91.72 55.98,91.63 55.56,91.63 55.47,91.72 55.47,91.97 55.38,92.06 54.97,92.06 54.88,91.97 54.88,91.72 54.79,91.63 54.37,91.63 54.28,91.72 54.28,91.97 54.19,92.06 53.77,92.06 53.68,91.97 53.68,91.72 53.59,91.63 40.06,91.63 v2(39.96,91.72)
RP_DDR4_DIMM1_DQ21: length 60.5
  TOP w0.114: CONN7.45 34.37,91.95 v2(34.6,92.18) ; U9.CA14 v4(85.72,85.19)
  S10 w0.102: v2(34.6,92.18) 36.51,94.09 56.08,94.09 56.91,93.25 76.82,93.25 78.15,91.93 79.79,91.93 80.48,91.24 81.59,91.24 82.36,90.47 83.68,90.47 84.4,89.75 84.4,89.49 85.14,88.76 85.14,88.47 85.8,87.8 85.8,87.6 86.16,87.24 86.16,86.77 86.67,86.26 86.67,85.87 85.99,85.19 v4(85.72,85.19)
RP_DDR4_DIMM1_DQ22: length 60.2
  TOP w0.114: U9.CJ13 v4(82.25,86.05) ; CONN7.58 40.51,88.7 40.18,89.03 40.18,89.3 39.75,89.74 38.18,89.74 37.81,89.37 v2(37.81,89)
  S10 w0.102: v4(82.25,86.05) 81.91,86.05 81.5,85.64 80.45,85.64 79.99,86.1 79.29,86.1 78.75,86.64 77.52,86.64 76.35,87.81 62.42,87.81 62.33,87.73 62.33,87.45 62.24,87.36 61.82,87.36 61.73,87.45 61.73,87.73 61.64,87.81 61.22,87.81 61.13,87.73 61.13,87.45 61.05,87.36 60.63,87.36 60.54,87.45 60.54,87.73 60.45,87.81 60.03,87.81 59.94,87.73 59.94,87.45 59.85,87.36 59.43,87.36 59.34,87.45 59.34,87.73 59.25,87.81 58.84,87.81 58.75,87.73 58.75,87.45 58.66,87.36 58.24,87.36 58.15,87.45 58.15,87.73 58.06,87.81 57.64,87.81 57.55,87.73 57.55,87.45 57.46,87.36 57.04,87.36 56.96,87.45 56.96,87.73 56.87,87.81 56.05,87.81 55.84,87.6 54.28,87.6 54.19,87.51 54.19,87.14 54.11,87.05 53.69,87.05 53.6,87.14 53.6,87.51 53.51,87.6 53.09,87.6 53,87.51 53,87.14 52.91,87.05 52.49,87.05 52.4,87.14 52.4,87.51 52.32,87.6 50.25,87.6 50.16,87.51 50.16,87.14 50.07,87.05 49.65,87.05 49.56,87.14 49.56,87.51 49.47,87.6 46.26,87.6 46.16,87.5 46.16,86.95 46.06,86.85 45.65,86.85 45.55,86.95 45.55,87.5 45.45,87.6 45.04,87.6 44.94,87.5 44.94,86.95 44.84,86.85 44.43,86.85 44.33,86.95 44.33,87.5 44.23,87.6 42.2,87.6 41.4,88.39 38.38,88.39 37.81,88.96 v2(37.81,89)
RP_DDR4_DIMM1_DQ23: length 60.3
  TOP w0.114: CONN7.59 34.07,88.45 34.29,88.67 v2(35.05,88.67) ; U9.CK14 v4(81.76,85.19)
  S10 w0.102: v2(35.05,88.67) 35.05,89.01 34.82,89.23 34.34,89.23 34.18,89.07 34.18,87.74 34.36,87.56 36.16,87.56 37.87,85.86 40.17,85.86 40.27,85.75 40.27,85.32 40.37,85.21 40.78,85.21 40.88,85.32 40.88,85.75 40.98,85.86 41.39,85.86 41.49,85.75 41.49,85.32 41.59,85.21 42,85.21 42.1,85.32 42.1,85.75 42.2,85.86 44.32,85.86 44.41,85.77 44.41,85.14 44.5,85.05 44.92,85.05 45.01,85.14 45.01,85.77 45.09,85.86 45.51,85.86 45.6,85.77 45.6,85.14 45.69,85.05 46.11,85.05 46.2,85.14 46.2,85.77 46.29,85.86 52.17,85.86 52.98,85.05 55.66,85.05 56.77,86.17 68.6,86.17 69.05,86.62 75.9,86.62 76.76,85.76 78.74,85.76 79.63,84.87 80.2,84.87 80.26,84.8 81.37,84.8 v4(81.76,85.19)
RP_DDR4_DIMM1_DQ24: length 56.5
  TOP w0.114: U9.CD20 v4(84.23,82.62) ; CONN7.70 39.77,85.7 39.25,86.22 38.84,86.22 v2(38.34,86.73)
  S5 w0.102: v4(84.23,82.62) 83.94,82.62 83.48,82.15 82.13,82.15 81.75,82.53 81.75,82.84 81.3,83.28 81.3,83.49 80.67,84.12 78.69,84.12 76.59,86.22 76.04,86.22 75.82,86.44 64.86,86.44 64.28,85.86 63.79,85.86 63.69,85.96 63.69,86.23 63.59,86.33 63.18,86.33 63.08,86.23 63.08,85.96 62.98,85.86 62.57,85.86 62.47,85.96 62.47,86.23 62.37,86.33 61.96,86.33 61.86,86.23 61.86,85.96 61.76,85.86 61.35,85.86 61.25,85.96 61.25,86.23 61.15,86.33 60.74,86.33 60.64,86.23 60.64,85.96 60.54,85.86 60.14,85.86 60.03,85.96 60.03,86.23 59.93,86.33 59.53,86.33 59.42,86.23 59.42,85.96 59.32,85.86 58.92,85.86 58.81,85.96 58.81,86.23 58.71,86.33 58.31,86.33 58.2,86.23 58.2,85.96 58.1,85.86 39.06,85.86 38.34,86.58 v2(38.34,86.73)
RP_DDR4_DIMM1_DQ25: length 56.6
  TOP w0.114: U9.CB20 v4(85.22,82.62) ; CONN7.71 35.11,85.45 36.27,86.61 v2(36.27,86.67)
  S5 w0.102: v2(36.27,86.67) 36.27,87.37 36.5,87.61 76.12,87.61 76.64,87.08 77.44,87.08 78.42,86.1 80.5,86.1 80.95,85.64 81.96,85.64 82.29,85.31 82.29,85.03 82.81,84.51 82.81,84.2 83.11,83.9 83.94,83.9 84.29,83.55 84.29,83.22 84.89,82.62 v4(85.22,82.62)
RP_DDR4_DIMM1_DQ26: length 56.6
  TOP w0.114: U9.CD28 v4(84.23,79.18) ; v2(34.51,82.9) 34.5,82.9 34.05,82.45 CONN7.83
  S5 w0.102: v2(34.51,82.9) 34.41,83.01 33.7,83.01 33.58,82.9 33.58,82.13 33.77,81.95 34.98,81.95 35.32,82.29 37.62,82.29 38.24,81.67 67.39,81.67 67.81,81.25 75.42,81.25 76.81,79.86 78.07,79.86 78.76,79.17 80.69,79.17 81.09,78.77 81.45,78.77 81.55,78.88 81.94,78.88 82.03,78.79 82.48,78.79 82.6,78.91 82.94,78.91 83.08,78.77 83.62,78.77 84.03,79.18 v4(84.23,79.18)
RP_DDR4_DIMM1_DQ27: length 56.6
  TOP w0.114: v2(39.51,82.86) 39.83,82.86 40.49,82.2 CONN7.84 ; U9.CB28 v4(85.22,79.18)
  S5 w0.089: 80.68,80.41 80.93,80.41 81.02,80.33 81.5,80.33 81.58,80.41 81.91,80.41 82.06,80.26 82.44,80.26 82.6,80.42 82.9,80.42 83.28,80.04 83.28,79.97 83.58,79.67 83.89,79.67 84.11,79.88 84.11,79.97 84.57,80.42 84.94,80.42 85.22,80.14 v4(85.22,79.18)
  S5 w0.102: v2(39.51,82.86) 40,83.35 40.49,83.35 40.59,83.25 40.59,82.89 40.69,82.79 41.09,82.79 41.2,82.89 41.2,83.25 41.3,83.35 43.03,83.35 43.13,83.25 54.2,83.25 54.3,83.35 63.26,83.35 63.36,83.25 63.36,82.9 63.46,82.8 63.87,82.8 63.97,82.9 63.97,83.25 64.07,83.35 64.48,83.35 64.58,83.25 64.58,82.9 64.68,82.8 65.09,82.8 65.19,82.9 65.19,83.25 65.29,83.35 65.7,83.35 65.8,83.25 65.8,82.9 65.9,82.8 66.31,82.8 66.41,82.9 66.41,83.25 66.51,83.35 66.92,83.35 67.02,83.25 67.02,82.9 67.12,82.8 67.53,82.8 67.63,82.9 67.63,83.25 67.73,83.35 68.41,83.35 68.75,83.02 76.31,83.02 76.62,82.7 76.62,82.16 78.04,80.74 80.35,80.74 80.68,80.41
RP_DDR4_DIMM1_DQ28: length 56.5
  TOP w0.114: U9.CF18 v4(83.74,83.47) ; v2(39.96,86.7) CONN7.66
  S5 w0.102: v2(39.96,86.7) 40.27,86.4 40.75,86.4 40.85,86.5 40.85,87.03 40.95,87.13 41.36,87.13 41.46,87.03 41.46,86.5 41.56,86.4 41.97,86.4 42.07,86.5 42.07,87.03 42.17,87.13 42.58,87.13 42.68,87.03 42.68,86.5 42.78,86.4 44.17,86.4 44.28,86.5 44.28,87.03 44.38,87.13 44.78,87.13 44.89,87.03 44.89,86.5 44.99,86.4 45.39,86.4 45.5,86.5 45.5,87.03 45.6,87.13 46,87.13 46.1,87.03 46.1,86.5 46.21,86.4 49.35,86.4 49.45,86.5 49.45,87.03 49.55,87.13 49.96,87.13 50.06,87.03 50.06,86.5 50.16,86.4 52.49,86.4 52.6,86.5 52.6,86.91 52.7,87.01 53.1,87.01 53.2,86.91 53.2,86.5 53.31,86.4 53.71,86.4 53.81,86.5 53.81,86.91 53.92,87.01 54.32,87.01 54.42,86.91 54.42,86.5 54.53,86.4 56.25,86.4 56.8,86.94 76.12,86.94 76.44,86.62 77.06,86.62 78.58,85.11 80.2,85.11 80.53,84.78 81.64,84.78 81.84,84.58 81.84,84.14 82.3,83.69 82.3,83.33 82.57,83.06 83.37,83.06 83.74,83.43 v4(83.74,83.47)
RP_DDR4_DIMM1_DQ29: length 56.6
  TOP w0.114: CONN7.67 34.38,86.45 v2(34.6,86.68) ; U9.CC18 v4(84.73,83.47)
  S5 w0.102: v4(84.73,83.47) 84.72,83.48 84.72,84.49 84.45,84.75 83.57,84.75 83.27,85.05 83.27,85.25 82.72,85.81 82.72,86.18 82.37,86.53 81.97,86.53 81.9,86.46 81.57,86.46 81.5,86.53 80.97,86.53 80.91,86.48 80.61,86.48 80.17,86.92 78.54,86.92 77.61,87.85 76.49,87.85 76.19,88.15 34.94,88.15 34.4,87.61 34.4,86.88 v2(34.6,86.68)
RP_DDR4_DIMM1_DQ30: length 56.8
  TOP w0.114: U9.CF26 v4(83.74,80.04) ; v2(36.22,85.32) 34.79,83.9 34.57,83.9 34.13,83.45 CONN7.79
  S5 w0.089: v4(83.74,80.04) 83.56,80.04 82.94,80.67 82.55,80.67 82.41,80.52 82.1,80.52 81.96,80.66 81.55,80.66 81.42,80.52 81.11,80.52 80.48,81.15
  S5 w0.102: v2(36.22,85.32) 35.58,85.32 35.34,85.08 35.34,84.34 35.8,83.89 43.23,83.89 43.37,83.74 53.9,83.74 54.04,83.89 68.71,83.89 68.98,83.61 76.46,83.61 77.58,82.5 77.58,82.22 78.65,81.15 80.48,81.15
RP_DDR4_DIMM1_DQ31: length 56.6
  TOP w0.114: U9.CC26 v4(84.73,80.04) ; v2(37.87,82.88) 38.54,83.55 40.2,83.55 40.55,83.2 CONN7.80
  S5 w0.089: 83.59,79.36 83.35,79.61 82.57,79.61 ; 84.73,79.91 84.39,79.58 84.1,79.58 83.88,79.36
  S5 w0.102: 83.88,79.36 83.59,79.36 ; v2(37.87,82.88) 38.5,82.25 43.72,82.25 43.82,82.35 43.82,82.47 43.92,82.58 44.33,82.58 44.43,82.47 44.43,82.35 44.53,82.25 44.94,82.25 45.04,82.35 45.04,82.47 45.14,82.58 45.55,82.58 45.65,82.47 45.65,82.35 45.75,82.25 58.17,82.25 58.55,82.63 58.68,82.63 58.82,82.49 58.82,82.35 58.91,82.26 59.27,82.26 59.36,82.35 59.36,82.63 59.45,82.72 59.82,82.72 59.91,82.63 59.91,82.35 60,82.26 60.37,82.26 60.46,82.35 60.46,82.63 60.54,82.72 60.91,82.72 61,82.63 61,82.35 61.09,82.26 61.46,82.26 61.55,82.35 61.55,82.63 61.64,82.72 62.01,82.72 62.09,82.63 62.09,82.35 62.18,82.26 67.64,82.26 68.06,81.84 75.67,81.84 77.34,80.17 79.86,80.17 79.88,80.16 80.02,80.16 80.52,79.65 80.91,79.65 80.98,79.72 81.44,79.72 81.53,79.63 81.88,79.63 81.95,79.7 82.48,79.7 82.57,79.61 ; v4(84.73,80.04) 84.73,79.91
RP_DDR4_DIMM1_DQ32: length 57.8
  TOP w0.114: CONN7.174 40.48,57.7 40.01,57.23 38.97,57.23 38.22,57.98 v2(38.08,57.98) ; U9.CD66 v4(84.23,62.58)
  S10 w0.089: 83.31,61.82 83.67,62.19 84.01,62.19 84.23,62.41 v4(84.23,62.58)
  S10 w0.102: 83.31,61.82 83.31,61.6 83.03,61.32 80.83,61.32 80.34,60.83 79.52,60.83 77.42,58.72 70.61,58.72 70.51,58.62 70.51,57.53 70.41,57.43 70,57.43 69.9,57.53 69.9,58.62 69.8,58.72 69.32,58.72 67.98,57.39 55.39,57.39 54.48,56.48 54,56.48 53.9,56.58 53.9,56.91 53.8,57.01 53.39,57.01 53.29,56.9 53.29,56.58 53.19,56.48 52.78,56.48 52.68,56.58 52.68,56.88 52.58,56.98 52.17,56.98 52.07,56.88 52.07,56.58 51.97,56.48 42.09,56.48 41.37,57.2 38.86,57.2 v2(38.08,57.98)
RP_DDR4_DIMM1_DQ33: length 57.9
  TOP w0.114: U9.CB66 v4(85.22,62.58) ; CONN7.173 35.94,57.95 v2(36.53,58.54)
  S10 w0.102: v4(85.22,62.58) 85.22,62.41 85.06,62.26 84.89,62.26 84.71,62.43 84.71,62.91 84.2,63.42 84.2,63.56 83.92,63.83 83.52,63.83 83.21,63.52 83.21,63.19 83.03,63.02 82.55,63.02 82.47,63.09 82.06,63.09 81.94,62.97 81.56,62.97 81.46,63.07 81.07,63.07 80.92,62.91 80.43,62.91 80.19,62.67 79.84,62.67 77.36,60.19 66.08,60.19 64.47,58.58 54.98,58.58 54.98,58.58 47.41,58.58 47.04,58.21 45.81,58.21 45.71,58.31 45.71,58.45 45.61,58.55 45.2,58.55 45.1,58.45 45.1,58.31 45,58.21 44.59,58.21 44.49,58.31 44.49,58.45 44.39,58.55 43.98,58.55 43.88,58.45 43.88,58.31 43.78,58.21 42.1,58.21 41.68,58.62 36.61,58.62 v2(36.53,58.54)
RP_DDR4_DIMM1_DQ34: length 57.9
  TOP w0.114: U9.CD72 v4(84.23,59.15) ; CONN7.187 34.23,54.45 v2(34.61,54.83)
  S10 w0.102: v2(34.61,54.83) 34.61,54.77 35.22,54.17 36.56,54.17 37.72,53.01 40.06,53.01 41.53,51.54 44.46,51.54 44.56,51.64 44.56,51.71 44.66,51.82 45.07,51.82 45.17,51.71 45.17,51.64 45.27,51.54 45.68,51.54 45.78,51.64 45.78,51.71 45.88,51.82 46.29,51.82 46.39,51.71 46.39,51.64 46.49,51.54 54,51.54 54.61,52.15 78.43,52.15 84.47,58.19 84.47,58.92 v4(84.23,59.15)
RP_DDR4_DIMM1_DQ35: length 57.8
  TOP w0.114: v2(39.95,54.81) 40.05,54.7 CONN7.186 ; U9.CB72 v4(85.22,59.15)
  S10 w0.089: 82.75,59.21 83.17,59.63 83.89,59.63 84.35,60.09 ; 84.35,60.16 84.57,60.38 84.88,60.38 85.22,60.04 v4(85.22,59.15)
  S10 w0.102: v2(39.95,54.81) 39.95,54.74 40.69,54 44.08,54 44.18,53.9 44.18,53.7 44.28,53.59 44.69,53.59 44.79,53.7 44.79,53.9 44.89,54 45.3,54 45.4,53.9 45.4,53.7 45.5,53.59 45.91,53.59 46.01,53.7 46.01,53.9 46.11,54 55.63,54 55.8,54.18 56.48,54.18 56.58,54.08 56.58,53.95 56.68,53.85 57.09,53.85 57.19,53.95 57.19,54.08 57.29,54.18 57.7,54.18 57.8,54.08 57.8,53.95 57.9,53.85 58.31,53.85 58.41,53.95 58.41,54.08 58.51,54.18 58.92,54.18 59.02,54.08 59.02,53.95 59.12,53.85 59.53,53.85 59.63,53.95 59.63,54.08 59.73,54.18 60.14,54.18 60.24,54.08 60.24,53.95 60.34,53.85 60.75,53.85 60.85,53.95 60.85,54.08 60.95,54.18 61.36,54.18 61.46,54.08 61.46,53.95 61.56,53.85 61.97,53.85 62.07,53.95 62.07,54.08 62.17,54.18 62.58,54.18 62.68,54.08 62.68,53.95 62.78,53.85 63.19,53.85 63.29,53.95 63.29,54.08 63.39,54.18 63.8,54.18 63.9,54.08 63.9,53.95 64,53.85 64.41,53.85 64.51,53.95 64.51,54.08 64.61,54.18 65.02,54.18 65.12,54.08 65.12,53.95 65.22,53.85 65.62,53.85 65.73,53.95 65.73,54.08 65.83,54.18 66.23,54.18 66.34,54.08 66.34,53.95 66.44,53.85 66.84,53.85 66.95,53.95 66.95,54.08 67.05,54.18 67.45,54.18 67.56,54.08 67.56,53.95 67.66,53.85 68.06,53.85 68.16,53.95 68.16,54.08 68.27,54.18 68.67,54.18 68.77,54.08 68.77,53.95 68.88,53.85 69.28,53.85 69.38,53.95 69.38,54.08 69.49,54.18 78.75,54.18 82.5,57.94 82.5,58.47 82.75,58.71 82.75,59.21 ; 84.35,60.16 84.35,60.09
RP_DDR4_DIMM1_DQ36: length 57.9
  TOP w0.114: v2(39.7,57.98) 40.42,58.7 CONN7.170 ; U9.CF64 v4(83.74,63.44)
  S10 w0.089: v4(83.74,63.44) 83.74,62.54 83.41,62.21 82.58,62.21
  S10 w0.102: 82.58,62.21 82.4,62.03 82.12,62.03 81.87,62.28 81.61,62.28 81.35,62.03 81.1,62.03 80.9,62.23 80.49,62.23 79.94,61.68 79.61,61.68 77.16,59.22 67.86,59.22 67.75,59.32 67.75,59.6 67.65,59.71 67.25,59.71 67.14,59.6 67.14,59.32 67.04,59.22 66.37,59.22 66.28,59.13 66.28,58.82 66.39,58.71 67.53,58.71 67.64,58.59 67.64,58.12 67.51,57.98 53.91,57.98 53.81,57.88 53.81,57.64 53.71,57.53 53.3,57.53 53.2,57.64 53.2,57.88 53.1,57.98 52.62,57.98 52.11,57.48 51.27,57.48 51.17,57.38 51.17,57.09 51.06,56.99 50.66,56.99 50.56,57.09 50.56,57.38 50.45,57.48 46.42,57.48 46.34,57.39 46.34,57.17 46.25,57.08 45.88,57.08 45.79,57.17 45.79,57.54 45.66,57.67 45.37,57.67 45.25,57.54 45.25,57.17 45.16,57.08 44.79,57.08 44.7,57.17 44.7,57.54 44.57,57.67 44.28,57.67 44.15,57.54 44.15,57.17 44.06,57.08 43.7,57.08 43.61,57.17 43.61,57.39 43.52,57.48 41.98,57.48 41.48,57.98 v2(39.7,57.98)
RP_DDR4_DIMM1_DQ37: length 57.7
  TOP w0.114: CONN7.169 34.44,58.95 v2(34.85,58.55) ; U9.CC64 84.44,63.16 v4(84.73,63.44)
  S10 w0.102: v4(84.73,63.44) 84.73,63.7 84.25,64.17 83.38,64.17 83.04,63.83 80.54,63.83 79.59,62.87 79.51,62.87 77.72,61.09 76.72,61.09 76.63,61 76.63,60.79 76.54,60.7 76.17,60.7 76.08,60.79 76.08,61 75.99,61.09 75.63,61.09 75.54,61 75.54,60.79 75.45,60.7 75.08,60.7 74.99,60.79 74.99,61 74.9,61.09 74.53,61.09 74.44,61 74.44,60.79 74.36,60.7 73.99,60.7 73.9,60.79 73.9,61 73.81,61.09 73.44,61.09 73.35,61 73.35,60.79 73.26,60.7 71.96,60.7 71.86,60.81 71.86,61.09 71.76,61.19 71.35,61.19 71.25,61.09 71.25,60.81 71.15,60.7 65.89,60.7 64.3,59.12 53.91,59.12 53.85,59.18 42.7,59.18 42.65,59.13 35.42,59.13 v2(34.85,58.55)
RP_DDR4_DIMM1_DQ38: length 57.6
  TOP w0.114: U9.CF71 v4(83.74,60.01) ; CONN7.183 34.2,55.45 34.52,55.77 v2(34.58,55.77)
  S10 w0.089: 82.57,59.63 82.9,59.63 83.28,60.01 v4(83.74,60.01)
  S10 w0.102: 82.57,59.63 82.47,59.73 82.09,59.73 81.75,59.39 81.75,59 81.55,58.81 81.55,57.78 78.87,55.09 62.61,55.09 62.51,55.19 62.51,55.37 62.41,55.47 62,55.47 61.9,55.37 61.9,55.19 61.8,55.09 61.39,55.09 61.29,55.19 61.29,55.37 61.19,55.47 60.78,55.47 60.68,55.37 60.68,55.19 60.58,55.09 60.17,55.09 60.07,55.19 60.07,55.37 59.97,55.47 59.56,55.47 59.46,55.37 59.46,55.19 59.36,55.09 58.96,55.09 58.85,55.19 58.85,55.37 58.75,55.47 58.35,55.47 58.24,55.37 58.24,55.19 58.14,55.09 57.74,55.09 57.63,55.19 57.63,55.37 57.53,55.47 57.13,55.47 57.02,55.37 57.02,55.19 56.92,55.09 55.61,55.09 55.08,54.56 41.07,54.56 40.22,55.41 34.77,55.41 34.58,55.6 v2(34.58,55.77)
RP_DDR4_DIMM1_DQ39: length 57.9
  TOP w0.114: U9.CC71 v4(84.73,60.01) ; CONN7.182 39.21,55.7 v2(38.32,54.81)
  S10 w0.089: v4(84.73,60.01) 84.73,59.98 84.27,59.52 84.08,59.52 83.62,59.06
  S10 w0.102: v2(38.32,54.81) 38.32,54.72 38.81,54.23 39.78,54.23 40.61,53.39 42.76,53.39 43.34,52.81 44.46,52.81 44.56,52.71 44.56,52.53 44.66,52.43 45.07,52.43 45.17,52.53 45.17,52.71 45.27,52.81 45.68,52.81 45.78,52.71 45.78,52.53 45.88,52.43 46.29,52.43 46.39,52.53 46.39,52.71 46.49,52.81 54.39,52.81 54.49,52.91 54.49,52.96 54.59,53.06 55,53.06 55.1,52.96 55.1,52.91 55.2,52.81 55.61,52.81 55.71,52.91 55.71,52.96 55.81,53.06 56.22,53.06 56.32,52.96 56.32,52.91 56.42,52.81 56.83,52.81 56.93,52.91 56.93,52.96 57.03,53.06 57.44,53.06 57.54,52.96 57.54,52.91 57.64,52.81 58.05,52.81 58.15,52.91 58.15,52.96 58.25,53.06 58.66,53.06 58.76,52.96 58.76,52.91 58.86,52.81 59.27,52.81 59.37,52.91 59.37,52.96 59.47,53.06 59.87,53.06 59.98,52.96 59.98,52.91 60.08,52.81 60.48,52.81 60.59,52.91 60.59,52.96 60.69,53.06 61.09,53.06 61.2,52.96 61.2,52.91 61.3,52.81 61.7,52.81 61.81,52.91 61.81,52.96 61.91,53.06 62.31,53.06 62.41,52.96 62.41,52.91 62.52,52.81 62.92,52.81 63.02,52.91 63.02,52.96 63.13,53.06 63.53,53.06 63.63,52.96 63.63,52.91 63.74,52.81 78.09,52.81 83.4,58.13 83.4,58.65 83.62,58.87 83.62,59.06
RP_DDR4_DIMM1_DQ40: length 57.5
  TOP w0.114: U9.CL66 v4(81.26,62.58) ; CONN7.195 35.23,52.45 v2(36.23,53.45)
  S3 w0.102: v2(36.23,53.45) 36.23,54.05 36.57,54.39 36.71,54.39 36.8,54.3 36.94,54.3 37.23,54.59 37.23,54.73 37.14,54.82 37.14,54.97 38.06,55.88 40.24,55.88 41.83,57.48 43.18,57.48 43.28,57.37 43.28,56.88 43.38,56.78 43.79,56.78 43.89,56.88 43.89,57.37 43.99,57.48 44.4,57.48 44.5,57.37 44.5,56.88 44.6,56.78 45.01,56.78 45.11,56.88 45.11,57.37 45.21,57.48 45.62,57.48 45.72,57.37 45.72,56.88 45.82,56.78 46.22,56.78 46.33,56.88 46.33,57.37 46.43,57.48 63.23,57.48 67.21,61.45 72.32,61.45 72.88,62 77.13,62 78.05,62.92 79.86,62.92 79.98,63.03 80.81,63.03 v4(81.26,62.58)
RP_DDR4_DIMM1_DQ41: length 57.7
  TOP w0.114: U9.CJ66 v4(82.25,62.58) ; v2(37.86,53.76) 38.71,52.91 39.29,52.91 39.5,52.7 CONN7.194
  S3 w0.089: v4(82.25,62.58) 81.82,62.58 81.37,62.14 81.15,62.14 81,62.29 80.56,62.29 80.49,62.36
  S3 w0.102: 80.49,62.36 78.26,62.36 77.1,61.19 76.8,61.19 76.56,60.96 67.56,60.96 62.87,56.26 57.51,56.26 57.41,56.37 57.41,56.7 57.31,56.8 56.9,56.8 56.8,56.7 56.8,56.37 56.7,56.26 56.29,56.26 56.19,56.37 56.19,56.7 56.09,56.8 55.68,56.8 55.58,56.7 55.58,56.37 55.48,56.26 55.07,56.26 54.97,56.37 54.97,56.7 54.87,56.8 54.46,56.8 54.36,56.7 54.36,56.37 54.26,56.26 53.85,56.26 53.75,56.37 53.75,56.7 53.65,56.8 53.24,56.8 53.14,56.7 53.14,56.37 53.04,56.26 52.63,56.26 52.53,56.37 52.53,56.7 52.43,56.8 52.02,56.8 51.92,56.7 51.92,56.37 51.82,56.26 51.41,56.26 51.31,56.37 51.31,56.7 51.21,56.8 50.81,56.8 50.7,56.7 50.7,56.37 50.6,56.26 42.06,56.26 40.08,54.28 38.33,54.28 37.86,53.81 v2(37.86,53.76)
RP_DDR4_DIMM1_DQ42: length 57.7
  TOP w0.114: U9.CL72 v4(81.26,59.15) ; v2(34.58,49.76) 34.27,49.45 CONN7.207
  S3 w0.102: v2(34.58,49.76) 35.32,49.02 43.36,49.02 43.46,49.13 43.46,49.5 43.57,49.6 43.97,49.6 44.07,49.5 44.07,49.13 44.17,49.02 44.99,49.02 46.52,50.55 65.21,50.55 69.09,54.43 77.83,54.43 81.54,58.15 81.54,58.39 81.86,58.71 82.43,58.71 82.68,58.95 82.68,59.32 82.44,59.57 82.05,59.57 81.77,59.28 81.39,59.28 v4(81.26,59.15)
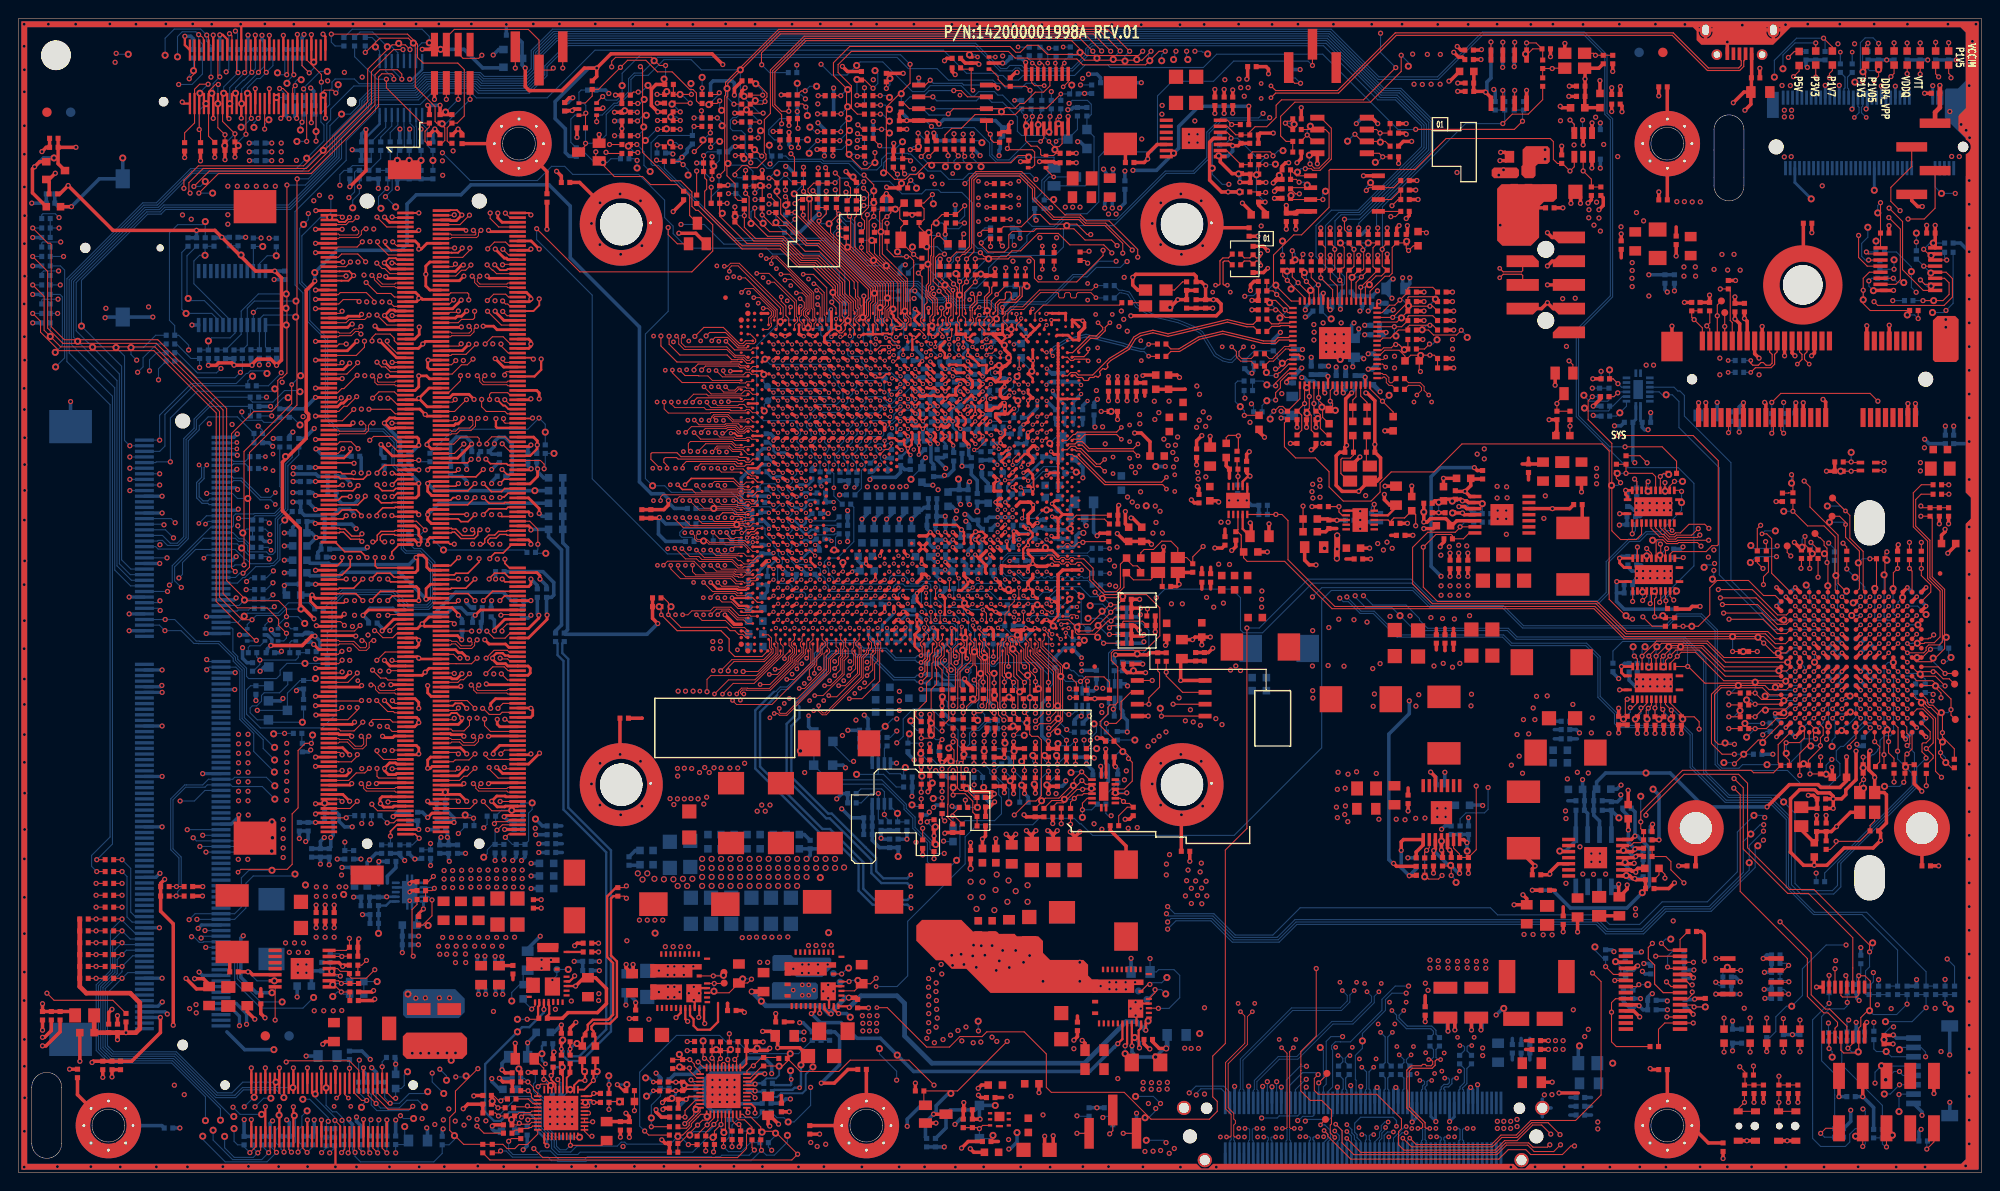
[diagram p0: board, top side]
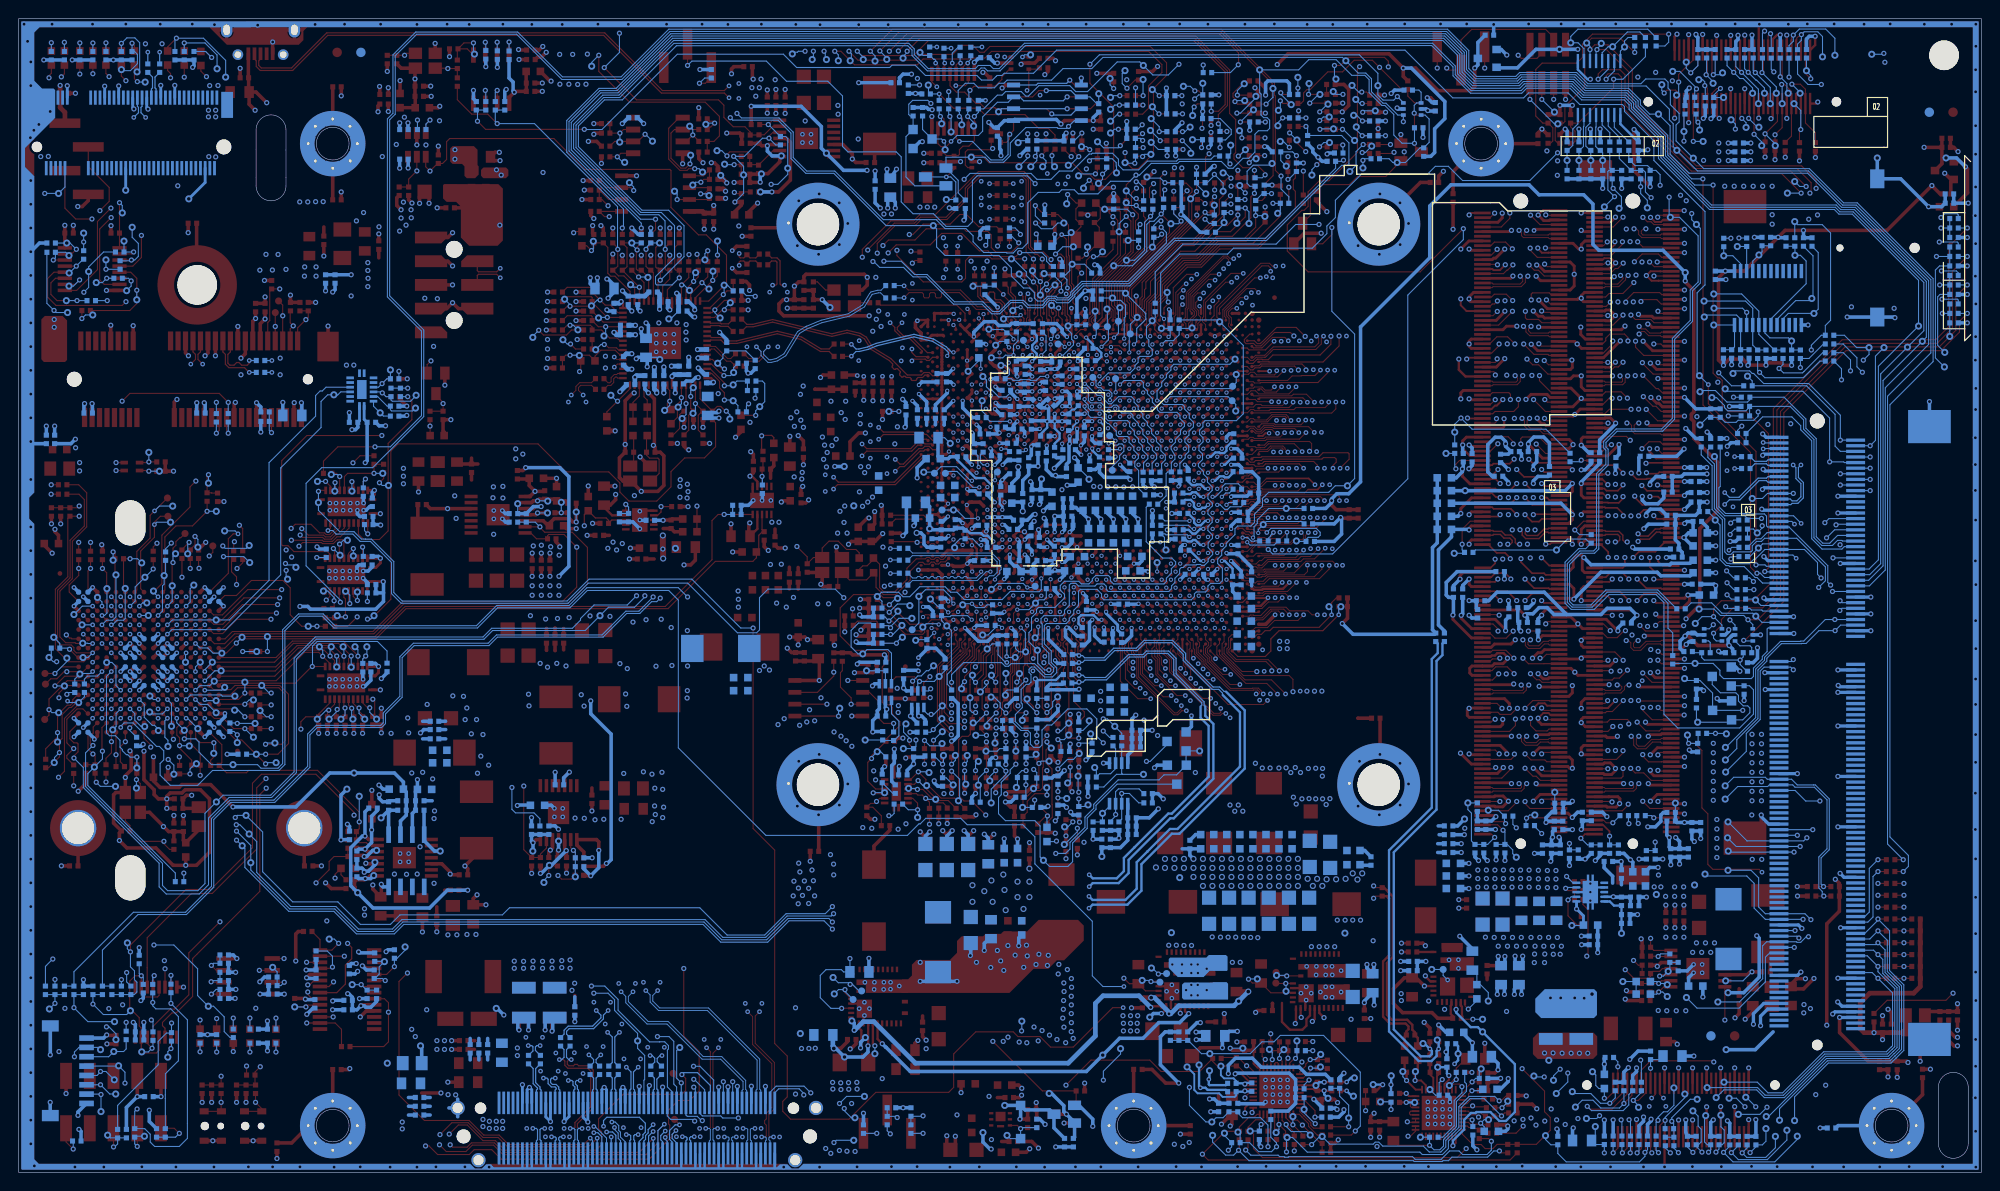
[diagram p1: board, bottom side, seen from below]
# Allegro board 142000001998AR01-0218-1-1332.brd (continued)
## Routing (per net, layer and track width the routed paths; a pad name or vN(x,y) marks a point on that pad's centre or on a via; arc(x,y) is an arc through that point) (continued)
RP_DDR4_DIMM1_DQ43: length 57.7
  TOP w0.114: CONN7.208 40.22,49.2 40.09,49.33 39.49,49.33 v2(38.31,50.51) ; U9.CJ72 v4(82.25,59.15)
  S3 w0.102: v4(82.25,59.15) 82.14,59.15 81.96,58.96 81.67,58.96 81.46,58.75 80.93,58.75 80.14,57.96 80.14,57.43 77.7,54.99 68.8,54.99 64.87,51.06 64.38,51.06 64.28,51.16 64.28,51.49 64.18,51.59 63.77,51.59 63.67,51.49 63.67,51.16 63.57,51.06 63.16,51.06 63.06,51.16 63.06,51.49 62.96,51.59 62.55,51.59 62.45,51.49 62.45,51.16 62.35,51.06 61.95,51.06 61.84,51.16 61.84,51.49 61.74,51.59 61.34,51.59 61.23,51.49 61.23,51.16 61.13,51.06 45.91,51.06 45.81,50.95 45.81,50.58 45.71,50.48 45.31,50.48 45.2,50.58 45.2,50.95 45.1,51.06 44.7,51.06 44.59,50.95 44.59,50.58 44.49,50.48 44.09,50.48 43.98,50.58 43.98,50.95 43.88,51.06 43.48,51.06 43.37,50.95 43.37,50.58 43.27,50.48 42.87,50.48 42.77,50.58 42.77,50.95 42.66,51.06 42.18,51.06 41.02,49.9 38.92,49.9 v2(38.31,50.51)
RP_DDR4_DIMM1_DQ44: length 57.6
  TOP w0.114: U9.CM64 v4(80.77,63.44) ; CONN7.191 34.49,53.45 v2(34.61,53.57)
  S3 w0.102: v2(34.61,53.57) 35.13,54.09 35.52,54.09 37.86,56.43 39.95,56.43 41.59,58.08 43.79,58.08 43.9,58.18 43.9,58.34 44,58.44 44.4,58.44 44.5,58.34 44.5,58.18 44.61,58.08 47.04,58.08 47.47,58.51 48.71,58.51 48.81,58.61 48.81,58.73 48.92,58.83 49.32,58.83 49.42,58.73 49.42,58.61 49.53,58.51 49.93,58.51 50.03,58.61 50.03,58.73 50.13,58.83 50.54,58.83 50.64,58.73 50.64,58.61 50.74,58.51 51.15,58.51 51.25,58.61 51.25,58.73 51.35,58.83 51.76,58.83 51.86,58.73 51.86,58.61 51.96,58.51 52.37,58.51 52.47,58.61 52.47,58.73 52.57,58.83 52.98,58.83 53.08,58.73 53.08,58.61 53.18,58.51 53.59,58.51 53.69,58.61 53.69,58.73 53.79,58.83 54.2,58.83 54.3,58.73 54.3,58.61 54.4,58.51 54.81,58.51 54.91,58.61 54.91,58.73 55.01,58.83 55.42,58.83 55.52,58.73 55.52,58.61 55.62,58.51 56.03,58.51 56.13,58.61 56.13,58.73 56.23,58.83 56.64,58.83 56.74,58.73 56.74,58.61 56.84,58.51 57.25,58.51 57.35,58.61 57.35,58.73 57.45,58.83 57.86,58.83 57.96,58.73 57.96,58.61 58.06,58.51 58.47,58.51 58.57,58.61 58.57,58.73 58.67,58.83 59.08,58.83 59.18,58.73 59.18,58.61 59.28,58.51 59.69,58.51 59.79,58.61 59.79,58.73 59.89,58.83 60.29,58.83 60.4,58.73 60.4,58.61 60.5,58.51 60.9,58.51 61.01,58.61 61.01,58.73 61.11,58.83 61.51,58.83 61.62,58.73 61.62,58.61 61.72,58.51 63.42,58.51 66.93,62.02 72.05,62.02 72.54,62.51 76.69,62.51 78.09,63.91 80.3,63.91 v4(80.77,63.44)
RP_DDR4_DIMM1_DQ45: length 57.7
  TOP w0.114: CONN7.190 39.67,53.7 v2(39.61,53.65) ; U9.CK64 v4(81.76,63.44)
  S3 w0.089: 80.24,61.73 80.61,62.1 80.92,62.1 81.11,61.92 81.42,61.92 81.6,62.1 82.46,62.1 82.63,62.27 82.63,62.83 82.02,63.44 v4(81.76,63.44)
  S3 w0.102: v2(39.61,53.65) 39.72,53.76 40.25,53.76 42.15,55.67 43.53,55.67 43.63,55.57 43.63,55.31 43.73,55.21 44.14,55.21 44.24,55.31 44.24,55.57 44.34,55.67 44.75,55.67 44.85,55.57 44.85,55.31 44.95,55.21 45.35,55.21 45.46,55.31 45.46,55.57 45.56,55.67 63.11,55.67 63.81,56.37 63.95,56.37 64.38,55.94 64.53,55.94 64.82,56.22 64.82,56.37 64.39,56.8 64.39,56.94 64.67,57.23 64.82,57.23 65.25,56.8 65.39,56.8 65.68,57.09 65.68,57.23 65.25,57.66 65.25,57.8 65.54,58.09 65.68,58.09 66.11,57.66 66.25,57.66 66.54,57.95 66.54,58.09 66.11,58.52 66.11,58.67 66.4,58.95 66.54,58.95 66.97,58.52 67.12,58.52 67.4,58.81 67.4,58.95 66.97,59.38 66.97,59.53 67.68,60.24 76.69,60.24 76.94,60.49 77.56,60.49 78.79,61.73 80.24,61.73
RP_DDR4_DIMM1_DQ46: length 57.7
  TOP w0.114: U9.CM71 v4(80.77,60.01) ; v2(36.68,50.51) 36.63,50.45 CONN7.203
  S3 w0.102: v4(80.77,60.01) 80.69,60.01 79.72,59.04 79.31,59.04 78.11,57.84 69.96,57.84 65.11,52.99 56.61,52.99 56.5,53.09 56.5,53.68 56.4,53.78 56,53.78 55.89,53.68 55.89,53.09 55.79,52.99 55.39,52.99 55.28,53.09 55.28,53.68 55.18,53.78 54.78,53.78 54.68,53.68 54.68,53.09 54.57,52.99 54.17,52.99 54.07,53.09 54.07,53.68 53.96,53.78 53.56,53.78 53.46,53.68 53.46,53.09 53.35,52.99 52.39,52.99 52.19,52.79 46.55,52.79 46.45,52.69 46.45,52.43 46.35,52.32 45.94,52.32 45.84,52.43 45.84,52.69 45.74,52.79 45.33,52.79 45.23,52.69 45.23,52.43 45.13,52.32 44.72,52.32 44.62,52.43 44.62,52.69 44.52,52.79 42.2,52.79 40.58,51.17 37.1,51.17 36.68,50.75 v2(36.68,50.51)
RP_DDR4_DIMM1_DQ47: length 57.7
  TOP w0.114: v2(39.98,50.5) 40.28,50.2 CONN7.204 ; U9.CK71 v4(81.76,60.01)
  S3 w0.102: v4(81.76,60.01) 81.53,60.01 77,55.47 68.44,55.47 65.35,52.39 60.42,52.39 60.33,52.3 60.33,51.66 60.24,51.57 59.82,51.57 59.73,51.66 59.73,52.3 59.65,52.39 59.23,52.39 59.14,52.3 59.14,51.66 59.05,51.57 58.63,51.57 58.54,51.66 58.54,52.3 58.45,52.39 58.03,52.39 57.94,52.3 57.94,51.66 57.85,51.57 57.44,51.57 57.35,51.66 57.35,52.3 57.26,52.39 56.84,52.39 56.75,52.3 56.75,51.66 56.66,51.57 56.24,51.57 56.15,51.66 56.15,52.3 56.06,52.39 55.65,52.39 54.82,51.56 54.2,51.56 54.09,51.66 54.09,52.17 53.99,52.27 53.59,52.27 53.49,52.17 53.49,51.66 53.38,51.56 52.98,51.56 52.88,51.66 52.88,52.17 52.77,52.27 52.37,52.27 52.27,52.17 52.27,51.66 52.16,51.56 51.76,51.56 51.66,51.66 51.66,52.17 51.55,52.27 51.15,52.27 51.05,52.17 51.05,51.66 50.95,51.56 43.23,51.56 43.13,51.66 43.13,51.92 43.03,52.02 42.62,52.02 42.52,51.92 42.52,51.66 42.42,51.56 41.81,51.56 40.75,50.5 v2(39.98,50.5)
RP_DDR4_DIMM1_DQ48: length 85.2
  TOP w0.114: U9.BT72 v4(88.2,59.15) ; CONN7.216 39.95,47.2 v2(39.43,47.73)
  S8 w0.102: v4(88.2,59.15) 88.2,58.62 88.34,58.47 88.34,58.12 88.09,57.87 88.09,55.48 87.93,55.33 87.93,54.36 87.99,54.31 87.99,53.18 83.76,48.96 83.76,47.45 83.37,47.06 83.23,47.06 82.95,47.34 82.8,47.34 82.51,47.06 82.51,46.91 82.8,46.63 82.8,46.49 82.51,46.2 82.37,46.2 82.08,46.48 81.94,46.48 81.65,46.19 81.65,46.05 81.94,45.77 81.94,45.62 81.46,45.14 80.88,45.14 80.78,45.25 80.78,46.17 80.68,46.27 80.27,46.27 80.17,46.17 80.17,45.25 80.07,45.14 79.66,45.14 79.56,45.25 79.56,46.17 79.46,46.27 79.05,46.27 78.95,46.17 78.95,45.25 78.85,45.14 78.45,45.14 78.34,45.25 78.34,46.17 78.24,46.27 77.84,46.27 77.73,46.17 77.73,45.25 77.63,45.14 77.23,45.14 77.12,45.25 77.12,46.17 77.02,46.27 76.62,46.27 76.51,46.17 76.51,45.25 76.41,45.14 76.01,45.14 75.91,45.25 75.91,46.17 75.8,46.27 75.4,46.27 75.3,46.17 75.3,45.25 75.19,45.14 74.79,45.14 74.69,45.25 74.69,46.17 74.58,46.27 74.18,46.27 74.08,46.17 74.08,45.25 73.97,45.14 73.57,45.14 73.47,45.25 73.47,46.17 73.37,46.27 72.96,46.27 72.86,46.17 72.86,45.25 72.76,45.14 72.35,45.14 72.25,45.25 72.25,46.17 72.15,46.27 71.74,46.27 71.64,46.17 71.64,45.25 71.54,45.14 71.13,45.14 71.03,45.25 71.03,46.17 70.93,46.27 70.52,46.27 70.42,46.17 70.42,45.25 70.32,45.14 69.83,45.14 69.54,45.44 69.54,46.08 67.8,47.83 58.08,47.83 57.28,47.03 57.28,46.46 56.76,45.94 46.17,45.94 44.51,47.6 40.52,47.6 40.39,47.73 v2(39.43,47.73)
RP_DDR4_DIMM1_DQ49: length 84.9
  TOP w0.114: U9.BU71 v4(87.7,60.01) ; v2(36.82,48.19) 35.88,47.25 34.45,47.25 34.25,47.45 CONN7.215
  S8 w0.102: v2(36.82,48.19) 36.82,47.99 37.44,47.38 38.28,47.38 38.51,47.14 39.4,47.14 39.54,47 44.26,47 45.92,45.34 56.85,45.34 57.81,46.3 57.81,46.76 58.39,47.35 58.88,47.35 58.98,47.24 58.98,46.99 59.08,46.89 59.49,46.89 59.59,46.99 59.59,47.24 59.69,47.35 60.1,47.35 60.2,47.24 60.2,46.99 60.3,46.89 60.71,46.89 60.81,46.99 60.81,47.24 60.91,47.35 67.6,47.35 69.06,45.88 69.06,45.19 69.61,44.64 71.23,44.64 71.33,44.54 71.33,43.93 71.43,43.83 71.84,43.83 71.94,43.93 71.94,44.54 72.04,44.64 72.45,44.64 72.55,44.54 72.55,43.93 72.65,43.83 73.06,43.83 73.16,43.93 73.16,44.54 73.26,44.64 73.67,44.64 73.77,44.54 73.77,43.93 73.87,43.83 74.28,43.83 74.38,43.93 74.38,44.54 74.48,44.64 74.89,44.64 74.99,44.54 74.99,43.93 75.09,43.83 75.5,43.83 75.6,43.93 75.6,44.54 75.7,44.64 76.11,44.64 76.21,44.54 76.21,43.93 76.31,43.83 76.72,43.83 76.82,43.93 76.82,44.54 76.92,44.64 78.54,44.64 78.65,44.54 78.65,43.93 78.75,43.83 79.44,43.83 79.54,43.93 79.54,44.53 79.64,44.63 80.05,44.63 80.15,44.53 80.15,43.93 80.25,43.83 81.32,43.83 85.17,47.68 85.17,47.82 85.07,47.92 85.07,48.06 85.36,48.35 85.5,48.35 85.6,48.26 85.74,48.26 86.03,48.54 86.03,48.69 85.93,48.78 85.93,48.93 86.22,49.21 86.37,49.21 86.46,49.12 86.61,49.12 89.51,52.02 89.51,55.93 88.55,56.89 88.55,58.98 88.64,59.06 88.64,59.38 88.37,59.64 88.07,59.64 v4(87.7,60.01)
RP_DDR4_DIMM1_DQ50: length 85.2
  TOP w0.114: CONN7.228 39.04,44.2 38.34,44.9 v2(38.34,45.14) ; v4(92.16,59.15) 91.87,58.86 U9.BG72
  S8 w0.102: v2(38.34,45.14) 38.34,45.03 38.97,44.39 40.6,44.39 42.78,42.21 44.34,42.21 44.44,42.11 44.44,41.71 44.54,41.61 44.95,41.61 45.05,41.71 45.05,42.11 45.15,42.21 45.56,42.21 45.66,42.11 45.66,41.71 45.76,41.61 46.17,41.61 46.27,41.71 46.27,42.11 46.37,42.21 50.91,42.21 51.01,42.11 51.01,41.67 51.11,41.57 51.52,41.57 51.62,41.67 51.62,42.11 51.72,42.21 52.13,42.21 52.23,42.11 52.23,41.67 52.33,41.57 52.74,41.57 52.84,41.67 52.84,42.11 52.94,42.21 53.35,42.21 53.45,42.11 53.45,41.67 53.55,41.57 53.96,41.57 54.06,41.67 54.06,42.11 54.16,42.21 54.68,42.21 55.63,41.26 55.63,41.11 55.48,40.96 55.48,40.82 55.76,40.53 55.91,40.53 56.06,40.68 56.2,40.68 56.49,40.39 56.49,40.25 56.34,40.1 56.34,39.95 56.63,39.66 56.77,39.66 56.92,39.82 57.07,39.82 57.35,39.53 57.35,39.39 57.2,39.23 57.2,39.09 57.49,38.8 57.63,38.8 57.79,38.96 57.93,38.96 58.22,38.67 58.22,38.52 58.06,38.37 58.06,38.23 58.35,37.94 58.5,37.94 58.65,38.09 58.79,38.09 59.08,37.81 59.08,37.66 58.93,37.51 58.93,37.36 59.21,37.08 59.36,37.08 59.51,37.23 59.66,37.23 60.56,36.32 78.69,36.32 92.68,50.32 92.68,57.01 92.33,57.36 92.33,58.49 92.16,58.66 v4(92.16,59.15)
RP_DDR4_DIMM1_DQ51: length 85.2
  TOP w0.114: v2(36.23,44.72) 36.23,44.56 35.61,43.94 34.25,43.94 34.23,43.95 CONN7.229 ; U9.BH71 v4(91.66,60.01)
  S8 w0.102: v4(91.66,60.01) 91.97,60.01 92.74,59.24 92.74,59.06 93.34,58.46 93.34,57.75 93.17,57.58 93.17,50.09 78.91,35.83 59.44,35.83 54.18,41.09 43.14,41.09 42.36,41.87 42.22,41.87 41.61,41.26 41.47,41.26 41.18,41.55 41.18,41.69 41.79,42.3 41.79,42.44 41.5,42.73 41.35,42.73 40.75,42.12 40.61,42.12 40.32,42.41 40.32,42.55 40.92,43.16 40.92,43.3 40.44,43.79 37.16,43.79 v2(36.23,44.72)
RP_DDR4_DIMM1_DQ52: length 85.2
  TOP w0.114: v2(36.21,49.75) 36.21,49.44 35.22,48.45 CONN7.211 ; U9.BV72 v4(87.2,59.15)
  S8 w0.102: v4(87.2,59.15) 86.47,58.41 86.47,58.15 86.19,57.87 86.19,53.72 80.35,47.88 69.14,47.88 68.22,48.79 57.53,48.79 56.62,47.88 45.93,47.88 42.16,51.65 41.68,51.65 41.57,51.54 41.57,51.1 41.47,51 41.07,51 40.96,51.1 40.96,51.54 40.86,51.65 40.46,51.65 40.36,51.54 40.36,51.1 40.25,51 39.85,51 39.75,51.1 39.75,51.54 39.64,51.65 39.24,51.65 39.14,51.54 39.14,51.1 39.03,51 38.63,51 38.53,51.1 38.53,51.54 38.42,51.65 38.02,51.65 37.92,51.54 37.92,51.1 37.82,51 37.41,51 37.31,51.1 37.31,51.54 37.21,51.65 36.8,51.65 36.7,51.54 36.7,51.1 36.6,51 36.19,51 36.09,51.1 36.09,51.54 35.99,51.65 35.58,51.65 35.48,51.54 35.48,51.1 35.38,51 34.97,51 34.87,51.1 34.87,51.54 34.77,51.65 33.94,51.65 33.2,50.9 33.2,47.68 33.38,47.5 33.86,47.5 33.96,47.6 33.96,48.84 34.06,48.95 34.47,48.95 34.57,48.84 34.57,47.6 34.67,47.5 35.2,47.5 35.38,47.68 35.38,48.93 v2(36.21,49.75)
RP_DDR4_DIMM1_DQ53: length 85.1
  TOP w0.114: CONN7.212 40.01,48.2 39.74,48.48 37.86,48.48 37.72,48.34 v2(37.72,48) ; U9.BW71 86.36,59.81 v4(86.71,60.01)
  S8 w0.102: v4(86.71,60.01) 87.03,59.69 87.34,59.69 87.61,59.41 87.61,58.85 87.43,58.67 87.43,57.15 86.72,56.43 86.72,55.28 86.77,55.22 86.77,53.24 80.88,47.35 78.93,47.35 78.83,47.25 78.83,47.19 78.72,47.09 78.32,47.09 78.22,47.19 78.22,47.25 78.11,47.35 77.71,47.35 77.61,47.25 77.61,47.19 77.5,47.09 77.1,47.09 77,47.19 77,47.25 76.89,47.35 76.49,47.35 76.39,47.25 76.39,47.19 76.29,47.09 75.88,47.09 75.78,47.19 75.78,47.25 75.68,47.35 75.27,47.35 75.17,47.25 75.17,47.19 75.07,47.09 74.66,47.09 74.56,47.19 74.56,47.25 74.46,47.35 74.05,47.35 73.95,47.25 73.95,47.19 73.85,47.09 73.44,47.09 73.34,47.19 73.34,47.25 73.24,47.35 72.83,47.35 72.73,47.25 72.73,47.19 72.63,47.09 72.22,47.09 72.12,47.19 72.12,47.25 72.02,47.35 71.61,47.35 71.51,47.25 71.51,47.19 71.41,47.09 71,47.09 70.9,47.19 70.9,47.25 70.8,47.35 68.96,47.35 68,48.31 57.88,48.31 56.92,47.35 56.43,47.35 56.33,47.25 56.33,46.56 56.23,46.46 55.83,46.46 55.72,46.56 55.72,47.25 55.62,47.35 55.22,47.35 55.11,47.25 55.11,46.56 55.01,46.46 54.61,46.46 54.5,46.56 54.5,47.25 54.4,47.35 54,47.35 53.89,47.25 53.89,46.56 53.79,46.46 53.39,46.46 53.29,46.56 53.29,47.25 53.18,47.35 52.78,47.35 52.68,47.25 52.68,46.56 52.57,46.46 52.17,46.46 52.07,46.56 52.07,47.25 51.96,47.35 51.56,47.35 51.46,47.25 51.46,46.56 51.35,46.46 50.95,46.46 50.85,46.56 50.85,47.25 50.75,47.35 47.02,47.35 46.92,47.25 46.92,46.69 46.82,46.59 46.41,46.59 46.31,46.69 46.31,47.25 46.21,47.35 45.57,47.35 44.3,48.62 43.39,48.62 43.29,48.72 43.29,49.07 43.19,49.17 42.78,49.17 42.68,49.07 42.68,48.72 42.58,48.62 42.08,48.62 41.98,48.72 41.98,49.92 41.88,50.03 41.47,50.03 41.37,49.92 41.37,48.72 41.27,48.62 40.86,48.62 40.76,48.72 40.76,49.92 40.66,50.03 40.25,50.03 40.15,49.92 40.15,48.72 40.05,48.62 39.64,48.62 39.54,48.72 39.54,49.92 39.44,50.03 39.03,50.03 38.93,49.92 38.93,48.72 38.83,48.62 38.28,48.62 37.72,48.06 v2(37.72,48)
RP_DDR4_DIMM1_DQ54: length 85
  TOP w0.114: CONN7.224 40.01,45.2 v2(39.96,45.15) ; U9.BJ72 v4(91.17,59.15)
  S8 w0.102: v4(91.17,59.15) 91.17,58.62 91.5,58.28 91.5,57.21 92.2,56.51 92.2,51.75 80.48,40.03 75.69,40.03 72.48,36.81 71.91,36.81 71.81,36.92 71.81,37.59 71.71,37.69 71.3,37.69 71.2,37.59 71.2,36.92 71.1,36.81 70.69,36.81 70.59,36.92 70.59,37.59 70.49,37.69 70.08,37.69 69.98,37.59 69.98,36.92 69.88,36.81 69.47,36.81 69.37,36.92 69.37,37.59 69.27,37.69 68.86,37.69 68.76,37.59 68.76,36.92 68.66,36.81 60.92,36.81 59.66,38.08 59.66,38.22 60.13,38.68 60.13,38.83 59.84,39.12 59.7,39.12 59.23,38.65 59.09,38.65 58.71,39.03 58.71,39.18 59.36,39.83 59.36,39.98 59.08,40.26 58.93,40.26 58.28,39.61 58.13,39.61 57.84,39.9 57.84,40.04 58.5,40.7 58.5,40.84 58.21,41.13 58.07,41.13 57.41,40.47 57.27,40.47 56.98,40.76 56.98,40.9 57.64,41.56 57.64,41.7 57.35,41.99 57.21,41.99 56.55,41.33 56.41,41.33 55.9,41.84 55.9,41.98 56.25,42.33 56.25,42.48 55.97,42.76 55.82,42.76 55.47,42.41 55.33,42.41 54.99,42.75 43.4,42.75 41,45.15 v2(39.96,45.15)
RP_DDR4_DIMM1_DQ55: length 85
  TOP w0.114: U9.BL71 v4(90.67,60.01) ; v2(34.61,44.69) 34.34,44.95 CONN7.225
  S8 w0.102: v2(34.61,44.69) 36.14,43.15 36.14,43.08 36.8,42.42 38.38,42.42 38.83,41.97 39.11,41.97 39.4,41.68 39.4,41.4 40.23,40.57 53.99,40.57 59.22,35.34 79.11,35.34 93.65,49.89 93.65,56.84 94.28,57.48 94.28,58.5 94.02,58.77 93.94,58.77 93.46,59.25 93.46,59.33 93.21,59.58 93.21,60.05 92.85,60.4 91.06,60.4 v4(90.67,60.01)
RP_DDR4_DIMM1_DQ56: length 78.6
  TOP w0.114: CONN7.237 35.32,41.95 36.12,42.76 37.03,42.76 v2(37.52,43.25) ; U9.BU67 v4(87.7,61.73)
  S5 w0.089: 87.58,60.64 87.58,61.18 87.7,61.3 v4(87.7,61.73)
  S5 w0.102: 87.58,60.64 87.22,60.29 87.22,59.87 86.67,59.31 86.67,58.87 86.43,58.63 86.43,58.16 86.13,57.87 86.01,57.87 82.53,54.4 82.53,54.03 77.85,49.35 68.78,49.35 67.85,50.28 67.37,50.28 67.27,50.18 67.27,49.79 67.17,49.69 66.76,49.69 66.66,49.79 66.66,50.18 66.56,50.28 66.15,50.28 66.05,50.18 66.05,49.79 65.95,49.69 65.54,49.69 65.44,49.79 65.44,50.18 65.34,50.28 64.93,50.28 64.83,50.18 64.83,49.79 64.73,49.69 64.32,49.69 64.22,49.79 64.22,50.18 64.12,50.28 63.71,50.28 63.61,50.18 63.61,49.79 63.51,49.69 63.1,49.69 63,49.79 63,50.18 62.9,50.28 62.49,50.28 62.39,50.18 62.39,49.79 62.29,49.69 61.88,49.69 61.78,49.79 61.78,50.18 61.68,50.28 61.28,50.28 61.17,50.18 61.17,49.79 61.07,49.69 60.67,49.69 60.56,49.79 60.56,50.18 60.46,50.28 60.06,50.28 59.95,50.18 59.95,49.79 59.85,49.69 59.45,49.69 59.34,49.79 59.34,50.18 59.24,50.28 58.84,50.28 58.74,50.18 58.74,49.79 58.63,49.69 58.23,49.69 58.13,49.79 58.13,50.18 58.02,50.28 57.62,50.28 57.52,50.18 57.52,49.79 57.41,49.69 57.01,49.69 56.91,49.79 56.91,50.18 56.8,50.28 56.4,50.28 56.3,50.18 56.3,49.79 56.2,49.69 55.79,49.69 55.69,49.79 55.69,50.18 55.59,50.28 54.5,50.28 53.89,49.67 53.89,48.38 51.63,46.12 47.46,46.12 46.69,46.89 46.18,46.89 46.08,46.79 46.08,46.51 45.97,46.41 45.57,46.41 45.47,46.51 45.47,46.79 45.36,46.89 44.96,46.89 44.86,46.79 44.86,46.51 44.75,46.41 44.35,46.41 44.25,46.51 44.25,46.79 44.15,46.89 43.74,46.89 43.64,46.79 43.64,46.51 43.54,46.41 43.13,46.41 43.03,46.51 43.03,46.79 42.93,46.89 42.44,46.89 40.17,44.61 38.82,44.61 37.52,43.31 v2(37.52,43.25)
RP_DDR4_DIMM1_DQ57: length 78.3
  TOP w0.114: v2(38.34,43.23) 38.34,42.4 38.53,42.2 CONN7.236 ; U9.BT66 v4(88.2,62.58)
  S5 w0.089: v4(88.2,62.58) 88.2,62.25 88.07,62.13 88.07,61.41 87.82,61.15 87.82,60.44 88.08,60.18 88.08,59.66
  S5 w0.102: v2(38.34,43.23) 39.11,44.01 40.73,44.01 42.11,45.39 43.09,45.39 43.19,45.49 43.19,45.75 43.29,45.85 43.7,45.85 43.8,45.75 43.8,45.49 43.9,45.39 44.31,45.39 44.41,45.49 44.41,45.75 44.51,45.85 44.92,45.85 45.02,45.75 45.02,45.49 45.12,45.39 51.93,45.39 55.16,48.63 56.36,48.63 56.46,48.73 56.46,49.11 56.57,49.21 56.97,49.21 57.07,49.11 57.07,48.73 57.18,48.63 57.58,48.63 57.68,48.73 57.68,49.11 57.79,49.21 58.19,49.21 58.29,49.11 58.29,48.73 58.4,48.63 58.8,48.63 58.9,48.73 58.9,49.11 59,49.21 59.41,49.21 59.51,49.11 59.51,48.73 59.61,48.63 60.02,48.63 60.12,48.73 60.12,49.11 60.22,49.21 60.63,49.21 60.73,49.11 60.73,48.73 60.83,48.63 61.24,48.63 61.34,48.73 61.34,49.11 61.44,49.21 61.85,49.21 61.95,49.11 61.95,48.73 62.05,48.63 62.46,48.63 62.56,48.73 62.56,49.11 62.66,49.21 63.07,49.21 63.17,49.11 63.17,48.73 63.27,48.63 63.68,48.63 63.78,48.73 63.78,49.11 63.88,49.21 64.29,49.21 64.39,49.11 64.39,48.73 64.49,48.63 64.9,48.63 65,48.73 65,49.11 65.1,49.21 65.51,49.21 65.61,49.11 65.61,48.73 65.71,48.63 66.12,48.63 66.22,48.73 66.22,49.11 66.32,49.21 66.73,49.21 66.83,49.11 66.83,48.73 66.93,48.63 67.45,48.63 67.56,48.73 67.56,48.93 67.66,49.03 68.06,49.03 68.17,48.93 68.17,48.73 68.27,48.63 78.67,48.63 79.69,49.65 79.69,49.79 79.41,50.07 79.41,50.21 79.7,50.5 79.84,50.5 80.12,50.22 80.26,50.22 80.55,50.51 80.55,50.65 80.27,50.93 80.27,51.08 80.56,51.36 80.7,51.36 80.98,51.09 81.13,51.09 81.41,51.37 81.41,51.52 81.13,51.8 81.13,51.94 81.42,52.23 81.57,52.23 81.84,51.95 81.99,51.95 84.94,54.9 84.94,55.67 87.54,58.27 87.54,58.91 87.72,59.09 87.72,59.3 88.08,59.66
RP_DDR4_DIMM1_DQ58: length 78.4
  TOP w0.114: CONN7.249 35.45,38.95 v2(36.22,39.73) ; U9.BH67 v4(91.66,61.73)
  S5 w0.089: v4(91.66,61.73) 91.5,61.73 90.79,61.02 90.79,60.68 90.3,60.19 90.3,59.83 90.36,59.76 90.74,59.38 90.74,58.92 90.54,58.71 90.54,58.04
  S5 w0.102: 90.54,58.04 90.84,57.74 90.84,57.1 89.39,55.64 89.39,53.07 72.61,36.3 60.17,36.3 56.08,40.39 46.41,40.39 46.31,40.29 46.31,39.88 46.21,39.78 45.8,39.78 45.7,39.88 45.7,40.29 45.6,40.39 45.19,40.39 45.09,40.29 45.09,39.88 44.99,39.78 44.58,39.78 44.48,39.88 44.48,40.29 44.38,40.39 39.17,40.39 39.08,40.3 36.61,40.3 36.22,39.91 v2(36.22,39.73)
RP_DDR4_DIMM1_DQ59: length 78.5
  TOP w0.114: U9.BG66 v4(92.16,62.58) ; v2(37.78,39.41) 37.79,39.4 37.79,39.32 38.4,38.7 CONN7.250
  S5 w0.102: v2(37.78,39.41) 37.8,39.41 38.61,38.6 41.03,38.6 41.13,38.5 41.13,38.23 41.23,38.13 41.64,38.13 41.74,38.23 41.74,38.5 41.84,38.6 56.42,38.6 59.79,35.23 74.06,35.23 92.48,53.64 92.48,58.51 92.59,58.62 92.59,59.39 92.23,59.74 92.23,60.31 92.25,60.33 92.25,62.49 v4(92.16,62.58)
RP_DDR4_DIMM1_DQ60: length 78.6
  TOP w0.114: v4(86.71,61.73) 86.36,61.52 U9.BW67 ; v2(39.96,43.2) CONN7.232
  S5 w0.089: 88.31,59.82 88.31,60.28 88.64,60.61 88.64,61.09 88.3,61.44 88.3,61.89 88.64,62.24 88.64,62.74 88.39,62.99 86.98,62.99 86.71,62.72 v4(86.71,61.73)
  S5 w0.102: 88.31,59.82 88.64,59.48 88.64,58.77 88.45,58.57 88.45,58.26 85.43,55.24 85.43,54.57 78.76,47.9 57.97,47.9 57.87,47.8 57.87,47.37 57.77,47.27 57.37,47.27 57.26,47.37 57.26,47.8 57.16,47.9 56.76,47.9 56.65,47.8 56.65,47.37 56.55,47.27 56.15,47.27 56.04,47.37 56.04,47.8 55.94,47.9 55.46,47.9 54.98,47.42 54.98,47.28 55.64,46.62 55.64,46.48 55.36,46.19 55.21,46.19 54.55,46.85 54.41,46.85 54.12,46.56 54.12,46.42 54.78,45.76 54.78,45.61 54.49,45.33 54.35,45.33 53.69,45.99 53.54,45.99 53.26,45.7 53.26,45.56 53.92,44.89 53.92,44.75 53.63,44.46 53.49,44.46 52.83,45.12 52.68,45.12 52.39,44.84 52.39,44.69 53.06,44.03 53.06,43.89 52.77,43.6 52.63,43.6 51.96,44.26 51.82,44.26 51.46,43.91 46.28,43.91 46.18,44.01 46.18,44.68 46.08,44.78 45.67,44.78 45.57,44.68 45.57,44.01 45.47,43.91 44.51,43.91 44.41,44.01 44.41,44.65 44.31,44.75 43.9,44.75 43.8,44.65 43.8,44.01 43.7,43.91 43.12,43.91 42.5,43.28 40.04,43.28 v2(39.96,43.2)
RP_DDR4_DIMM1_DQ61: length 78.6
  TOP w0.114: U9.BV66 v4(87.2,62.58) ; CONN7.233 34.54,42.95 v2(34.61,43.02)
  S5 w0.102: v2(34.61,43.02) 33.52,43.02 33.28,43.26 33.28,45.09 33.46,45.27 33.88,45.27 33.98,45.37 33.98,46.07 34.08,46.17 34.49,46.17 34.59,46.07 34.59,45.37 34.69,45.27 35.1,45.27 35.2,45.37 35.2,46.07 35.3,46.17 35.71,46.17 35.81,46.07 35.81,45.37 35.91,45.27 36.32,45.27 36.42,45.37 36.42,46.07 36.52,46.17 36.93,46.17 37.03,46.07 37.03,45.37 37.13,45.27 37.61,45.27 38.5,46.16 40.7,46.16 41.95,47.41 43.34,47.41 43.44,47.51 43.44,47.92 43.54,48.03 43.95,48.03 44.05,47.92 44.05,47.51 44.15,47.41 44.56,47.41 44.66,47.51 44.66,47.92 44.76,48.03 45.17,48.03 45.27,47.92 45.27,47.51 45.37,47.41 46.57,47.41 46.68,47.51 46.68,47.65 46.78,47.75 47.18,47.75 47.29,47.65 47.29,47.51 47.39,47.41 47.79,47.41 47.9,47.51 47.9,47.65 48,47.75 48.4,47.75 48.51,47.65 48.51,47.51 48.61,47.41 49.01,47.41 49.11,47.51 49.11,47.65 49.22,47.75 49.62,47.75 49.72,47.65 49.72,47.51 49.83,47.41 51.77,47.41 52.82,48.46 52.82,50.04 53.58,50.8 68.14,50.8 68.87,50.07 77.88,50.07 81.54,53.74 81.54,55.55 82,56.01 83.12,56.01 84.99,57.88 85.17,57.88 85.45,58.16 85.45,58.7 85.79,59.04 85.79,59.39 86.17,59.77 86.17,60.14 86.62,60.59 86.62,60.97 87.2,61.56 v4(87.2,62.58)
RP_DDR4_DIMM1_DQ62: length 78.8
  TOP w0.114: v2(34.6,39.7) 34.35,39.95 CONN7.245 ; U9.BL67 v4(90.67,61.73)
  S5 w0.089: v4(90.67,61.73) 90.55,61.6 90.55,60.71 90.06,60.22 90.06,59.8 90.55,59.31 90.55,58.99 90.31,58.75 90.31,58.02
  S5 w0.102: 90.31,58.02 90.12,57.83 90.12,56.92 88.25,55.06 88.25,53.48 71.55,36.78 71.07,36.78 70.97,36.88 70.97,37.69 70.87,37.8 70.46,37.8 70.36,37.69 70.36,36.88 70.26,36.78 69.85,36.78 69.75,36.88 69.75,37.69 69.65,37.8 69.24,37.8 69.14,37.69 69.14,36.88 69.04,36.78 60.43,36.78 56.09,41.12 38.87,41.12 38.78,41.02 35.1,41.02 34.6,40.52 v2(34.6,39.7)
RP_DDR4_DIMM1_DQ63: length 78.3
  TOP w0.114: v2(39.51,39.65) 39.56,39.7 CONN7.246 ; U9.BJ66 v4(91.17,62.58)
  S5 w0.102: v2(39.51,39.65) 39.94,39.23 40.42,39.23 40.52,39.33 40.52,39.65 40.62,39.75 41.03,39.75 41.13,39.65 41.13,39.33 41.23,39.23 56.53,39.23 59.99,35.76 73.15,35.76 83.35,45.97 83.48,45.97 83.72,45.73 83.84,45.73 84.11,45.99 84.11,46.11 83.86,46.36 83.86,46.48 84.13,46.74 84.25,46.74 84.49,46.5 84.62,46.5 84.88,46.76 84.88,46.89 84.64,47.13 84.64,47.25 84.9,47.52 85.02,47.52 85.26,47.27 85.39,47.27 85.65,47.53 85.65,47.66 85.41,47.9 85.41,48.03 85.67,48.29 85.8,48.29 86.04,48.05 86.16,48.05 86.42,48.31 86.42,48.43 86.18,48.67 86.18,48.8 86.44,49.06 86.57,49.06 86.81,48.82 86.94,48.82 87.2,49.08 87.2,49.21 86.96,49.45 86.96,49.57 90.16,52.77 90.16,55.39 91.56,56.8 91.56,58.08 91.35,58.29 91.35,58.58 91.58,58.81 91.58,59.36 91.22,59.72 91.22,60.27 91.62,60.67 91.62,61.07 92.05,61.5 92.05,61.97 91.44,62.58 v4(91.17,62.58)
RP_DDR4_DIMM1_DQS0_N: length 68
  TOP w0.102: U9.CB4 85.11,90.35 85.11,90.83 85.31,91.03 85.31,91.39 85.17,91.52 85.17,92.45 85.07,92.55 85.07,94.15 81.13,98.09 80.65,98.09 80.37,97.81 v3(79.99,97.81) ; v2(35.89,101.01) 36.14,101.01 36.39,100.77 36.39,100.52 36.21,100.34 34.33,100.34 34.22,100.45 CONN7.11
  S10 w0.089: v2(35.89,101.01) 36.34,101.01 36.43,100.92 36.43,100.55 36.69,100.29 41.08,100.29 41.33,100.04 41.33,99.84 41.35,99.82
  S10 w0.102: v3(79.99,97.81) 80.19,97.81 80.37,97.98 80.37,98.14 79.53,98.98 73.89,98.98 71.17,96.27 70.27,96.27 69.89,96.65 69.89,98.15 69.78,98.25 69.38,98.25 69.28,98.15 69.28,96.65 68.89,96.27 61.6,96.27 60.43,97.44 60.43,98.07 58.96,99.54 45.75,99.54 45.51,99.3 41.87,99.3 41.35,99.82
RP_DDR4_DIMM1_DQS0_P: length 67.9
  TOP w0.102: v2(37.16,101.01) 36.91,101.01 36.67,100.77 36.67,100.4 36.32,100.06 34.33,100.06 34.22,99.95 CONN7.13 ; U9.CB2 84.97,91.22 84.97,92.36 84.87,92.47 84.87,94.07 81.05,97.89 80.73,97.89 80.55,97.7 80.55,97.29 v3(80.53,97.27)
  S10 w0.089: v2(37.16,101.01) 36.71,101.01 36.62,100.92 36.62,100.63 36.77,100.48 41.16,100.48 41.47,100.18 41.68,100.18 41.69,100.16
  S10 w0.102: v3(80.53,97.27) 80.53,97.47 80.85,97.78 80.85,98.34 79.73,99.46 73.69,99.46 70.97,96.75 70.47,96.75 70.37,96.85 70.37,98.35 69.98,98.73 69.18,98.73 68.79,98.35 68.79,96.85 68.69,96.75 61.8,96.75 60.91,97.64 60.91,98.27 59.16,100.02 45.55,100.02 45.31,99.78 44.32,99.78 44.22,99.88 44.22,100.08 44.12,100.18 43.71,100.18 43.61,100.08 43.61,99.88 43.51,99.78 42.07,99.78 41.69,100.16
RP_DDR4_DIMM1_DQS1_N: length 64.6
  TOP w0.102: v2(38.6,96.01) 38.34,95.75 38.34,95.66 38.91,95.09 40.24,95.09 40.35,95.2 CONN7.32
  TOP w0.114: U9.CH7 v4(82.75,88.63)
  S5 w0.102: v2(38.6,96.01) 38.3,95.71 38.3,95.49 38.53,95.27 40.64,95.27 41,95.62 41.96,95.62 42.1,95.76 43.12,95.76 43.53,95.36 44.15,95.36 44.25,95.46 44.25,95.84 44.36,95.95 44.76,95.95 44.86,95.84 44.86,95.46 44.97,95.36 45.37,95.36 45.47,95.46 45.47,95.84 45.57,95.95 45.98,95.95 46.08,95.84 46.08,95.46 46.18,95.36 49.67,95.36 50.08,94.95 51.09,94.95 51.19,95.05 51.19,95.48 51.57,95.86 52.38,95.86 52.76,95.48 52.76,95.05 52.87,94.95 55.75,94.95 57.39,93.31 58.54,93.31 58.65,93.41 58.65,93.88 59.03,94.27 59.84,94.27 60.22,93.88 60.22,93.41 60.32,93.31 60.73,93.31 60.83,93.41 60.83,93.88 61.21,94.27 62.02,94.27 62.41,93.88 62.41,93.41 62.51,93.31 62.91,93.31 63.01,93.41 63.01,93.88 63.4,94.27 64.21,94.27 64.59,93.88 64.59,93.41 64.69,93.31 65.1,93.31 65.2,93.41 65.2,93.88 65.58,94.27 66.39,94.27 66.77,93.88 66.77,93.41 66.88,93.31 67.28,93.31 67.38,93.41 67.38,93.88 67.77,94.27 68.57,94.27 68.96,93.88 68.96,93.41 69.06,93.31 69.47,93.31 69.57,93.41 69.57,93.88 69.95,94.27 70.76,94.27 71.14,93.88 71.14,93.41 71.24,93.31 76.03,93.31 77.53,91.81 80.8,91.81 81.76,90.85 81.76,90.65 82.75,89.67 v4(82.75,88.63)
RP_DDR4_DIMM1_DQS1_P: length 64.5
  TOP w0.102: v2(37.79,96.01) 38.06,95.75 38.06,95.55 38.79,94.81 40.24,94.81 40.35,94.7 CONN7.34
  TOP w0.114: U9.CG9 v4(83.24,87.77)
  S5 w0.102: v4(83.24,87.77) 82.89,87.77 82.35,88.31 82.35,88.83 82.54,89.03 82.54,89.58 81.62,90.51 81.42,90.51 80.6,91.33 77.33,91.33 75.83,92.83 71.04,92.83 70.66,93.21 70.66,93.68 70.56,93.78 70.15,93.78 70.05,93.68 70.05,93.21 69.67,92.83 68.86,92.83 68.48,93.21 68.48,93.68 68.37,93.78 67.97,93.78 67.87,93.68 67.87,93.21 67.48,92.83 66.68,92.83 66.29,93.21 66.29,93.68 66.19,93.78 65.78,93.78 65.68,93.68 65.68,93.21 65.3,92.83 64.49,92.83 64.11,93.21 64.11,93.68 64.01,93.78 63.6,93.78 63.5,93.68 63.5,93.21 63.11,92.83 62.31,92.83 61.92,93.21 61.92,93.68 61.82,93.78 61.41,93.78 61.31,93.68 61.31,93.21 60.93,92.83 60.12,92.83 59.74,93.21 59.74,93.68 59.64,93.78 59.23,93.78 59.13,93.68 59.13,93.21 58.74,92.83 57.19,92.83 55.55,94.47 52.67,94.47 52.28,94.85 52.28,95.28 52.18,95.38 51.77,95.38 51.67,95.28 51.67,94.85 51.29,94.47 49.88,94.47 49.47,94.88 43.33,94.88 42.92,95.28 42.1,95.28 41.96,95.42 41.08,95.42 40.72,95.06 38.44,95.06 38.1,95.41 38.1,95.71 v2(37.79,96.01)
RP_DDR4_DIMM1_DQS2_N: length 59.4
  TOP w0.102: v2(36.62,90.55) 36.35,90.29 35.92,90.29 35.47,89.84 34.33,89.84 34.22,89.95 CONN7.53
  TOP w0.114: U9.CG13 v4(83.24,86.05)
  S10 w0.089: 40.58,90 40.55,90 40.41,89.86 40.12,89.86 39.9,90.07 37.59,90.07 37.42,90.24 36.93,90.24 v2(36.62,90.55) ; 80.34,87.98 80.35,87.97 80.35,87.76 80.6,87.51 80.98,87.51 81.34,87.14 81.34,86.78 81.62,86.5 81.89,86.5 82.01,86.62 82.49,86.62 82.67,86.45 82.72,86.39 83.01,86.1 83.06,86.05 v4(83.24,86.05)
  S10 w0.102: 40.58,90 44.02,90 44.17,90.16 44.63,90.16 44.78,90 50.3,90 50.89,90.59 61.1,90.59 61.49,90.21 61.49,89.52 61.59,89.42 61.99,89.42 62.1,89.52 62.1,90.21 62.48,90.59 63.29,90.59 63.67,90.21 63.67,89.52 63.77,89.42 64.18,89.42 64.28,89.52 64.28,90.21 64.66,90.59 65.47,90.59 65.86,90.21 65.86,89.52 65.96,89.42 66.36,89.42 66.47,89.52 66.47,90.21 66.85,90.59 75.51,90.59 77.64,88.46 79.86,88.46 80.34,87.98
RP_DDR4_DIMM1_DQS2_P: length 59.4
  TOP w0.102: v2(36.62,89.74) 36.35,90.01 36.03,90.01 35.59,89.56 34.33,89.56 34.22,89.45 CONN7.55
  TOP w0.114: U9.CH14 v4(82.75,85.19)
  S10 w0.089: 80,87.64 80.01,87.62 80.22,87.62 80.53,87.32 80.9,87.32 81.15,87.06 81.15,86.7 81.54,86.31 81.97,86.31 82.09,86.43 82.41,86.43 82.53,86.31 82.82,86.02 82.82,85.26 v4(82.75,85.19) ; v2(36.62,89.74) 36.93,90.05 37.34,90.05 37.51,89.88 39.82,89.88 40.04,89.67 40.41,89.67 40.55,89.52 40.58,89.52
  S10 w0.102: 40.58,89.52 50.5,89.52 51.09,90.11 60.9,90.11 61,90.01 61,89.32 61.39,88.93 62.19,88.93 62.58,89.32 62.58,90.01 62.68,90.11 63.09,90.11 63.19,90.01 63.19,89.32 63.57,88.93 64.38,88.93 64.76,89.32 64.76,90.01 64.86,90.11 65.27,90.11 65.37,90.01 65.37,89.32 65.76,88.93 66.56,88.93 66.95,89.32 66.95,90.01 67.05,90.11 75.31,90.11 77.44,87.98 79.66,87.98 80,87.64
RP_DDR4_DIMM1_DQS3_N: length 57.2
  TOP w0.102: v2(38.66,85.26) 38.39,85 38.39,84.69 38.48,84.59 40.24,84.59 40.35,84.7 CONN7.74
  TOP w0.114: U9.CD24 v4(84.23,80.9)
  S5 w0.089: v2(38.66,85.26) 38.34,84.95 38.34,84.74 38.43,84.66 43.3,84.66 43.44,84.8 43.46,84.8 ; 79.7,82.71 79.73,82.71 79.87,82.57 80.42,82.57 80.63,82.36 80.98,82.36 81.37,81.96 81.37,81.6 81.61,81.36 81.91,81.36 82.06,81.51 82.45,81.51 82.66,81.3 82.84,81.3 83.01,81.47 83.47,81.47 84.05,80.9 v4(84.23,80.9)
  S5 w0.102: 79.7,82.71 79.14,82.71 76.82,85.03 66.74,85.03 66.64,85.13 66.64,85.57 66.25,85.95 65.44,85.95 65.06,85.57 65.06,85.13 64.96,85.03 59.07,85.03 58.97,85.13 58.97,85.26 58.87,85.36 58.47,85.36 58.36,85.26 58.36,85.13 58.26,85.03 57.86,85.03 57.75,85.13 57.75,85.26 57.65,85.36 57.25,85.36 57.14,85.26 57.14,85.13 57.04,85.03 56.64,85.03 56.53,85.13 56.53,85.26 56.43,85.36 56.03,85.36 55.93,85.26 55.93,85.13 55.82,85.03 55.42,85.03 55.32,85.13 55.32,85.26 55.21,85.36 54.81,85.36 54.71,85.26 54.71,85.13 54.6,85.03 54.2,85.03 54.1,85.13 54.1,85.26 53.99,85.36 53.59,85.36 53.49,85.26 53.49,85.13 53.39,85.03 52.81,85.03 52.59,84.8 45.79,84.8 45.69,84.9 45.69,84.99 45.3,85.37 44.49,85.37 44.11,84.99 44.11,84.9 44.01,84.8 43.46,84.8
RP_DDR4_DIMM1_DQS3_P: length 57.2
  TOP w0.102: CONN7.76 40.35,84.2 40.24,84.31 38.37,84.31 38.11,84.57 38.11,85 v2(37.84,85.26)
  TOP w0.114: U9.CB24 v4(85.22,80.9)
  S5 w0.089: v2(37.84,85.26) 38.15,84.95 38.15,84.66 38.35,84.47 43.3,84.47 43.44,84.32 43.46,84.32 ; v4(85.22,80.9) 84.77,80.9 84.35,80.47 84.08,80.47 83.8,80.75 83.8,80.88 83.64,81.04 83.4,81.28 83.09,81.28 82.92,81.11 82.58,81.11 82.37,81.32 82.14,81.32 81.99,81.17 81.53,81.17 81.18,81.52 81.18,81.88 80.9,82.17 80.55,82.17 80.35,82.38 79.87,82.38 79.73,82.23 79.7,82.23
  S5 w0.102: 43.46,84.32 44.21,84.32 44.59,84.7 44.59,84.79 44.69,84.89 45.1,84.89 45.2,84.79 45.2,84.7 45.59,84.32 52.79,84.32 53.01,84.54 65.16,84.54 65.54,84.93 65.54,85.37 65.65,85.47 66.05,85.47 66.15,85.37 66.15,84.93 66.54,84.54 76.62,84.54 78.94,82.23 79.7,82.23
RP_DDR4_DIMM1_DQS4_N: length 58.6
  TOP w0.102: v2(36.73,56.93) 36.92,56.93 37.22,56.63 37.22,56.28 37.1,56.16 36.55,56.16 35.87,56.84 34.33,56.84 34.22,56.95 CONN7.177
  TOP w0.114: U9.CD69 v4(84.23,60.87)
  S10 w0.089: v4(84.23,60.87) 84.23,61.08 84.15,61.16 83.92,61.16 83.83,61.07 83.83,60.63 83.48,60.28 83,60.28 82.91,60.38 82.58,60.38 82.46,60.27 82.04,60.27 81.9,60.42 81.62,60.42 81.37,60.17 81.37,59.81 80.92,59.35 80.18,59.35 80.03,59.21 80.01,59.21 ; 39.26,56.06 39.24,56.06 39.09,56.21 37.51,56.21 37.26,56.45 37.26,56.84 37.18,56.93 v2(36.73,56.93)
  S10 w0.102: 80.01,59.21 79.63,59.21 78.03,57.61 72.31,57.61 71.1,56.4 55.79,56.4 54.91,55.51 45.76,55.51 45.66,55.41 45.66,55.22 45.55,55.12 45.15,55.12 45.05,55.22 45.05,55.41 44.95,55.51 44.54,55.51 44.44,55.41 44.44,55.22 44.34,55.12 43.93,55.12 43.83,55.22 43.83,55.41 43.73,55.51 41.55,55.51 41,56.06 39.26,56.06
RP_DDR4_DIMM1_DQS4_P: length 58.7
  TOP w0.102: CONN7.179 34.22,56.45 34.33,56.56 35.75,56.56 36.43,55.88 37.21,55.88 37.5,56.17 37.5,56.69 37.74,56.93 v2(38,56.93)
  TOP w0.114: U9.CB69 v4(85.22,60.87)
  S10 w0.089: 39.26,56.54 39.24,56.54 39.09,56.4 37.59,56.4 37.46,56.53 37.46,56.84 37.54,56.93 v2(38,56.93) ; 80.01,59.69 80.03,59.69 80.18,59.55 80.84,59.55 81.18,59.89 81.18,60.25 81.54,60.61 81.98,60.61 82.12,60.46 82.38,60.46 82.5,60.57 82.98,60.57 83.08,60.47 83.4,60.47 83.64,60.71 83.64,61.15 83.84,61.35 84.23,61.35 84.36,61.22 84.87,61.22 v4(85.22,60.87)
  S10 w0.102: 80.01,59.69 79.43,59.69 77.83,58.09 72.11,58.09 70.9,56.88 55.59,56.88 54.71,56 41.75,56 41.2,56.54 39.26,56.54
RP_DDR4_DIMM1_DQS5_N: length 57.7
  TOP w0.102: v2(38.96,52.17) 38.66,52.17 38.47,51.98 38.47,51.79 38.67,51.59 40.24,51.59 40.35,51.7 CONN7.198
  TOP w0.114: U9.CL69 v4(81.26,60.87)
  S3 w0.089: 79.48,60.28 79.5,60.3 79.5,60.5 80.05,61.05 81.07,61.05 v4(81.26,60.87) ; v2(38.96,52.17) 38.51,52.17 38.42,52.26 38.42,52.51 38.77,52.85 40.52,52.85 40.67,52.71 40.69,52.71
  S3 w0.102: 40.69,52.71 41.05,52.71 42.38,54.05 43.89,54.05 43.99,53.94 43.99,53.59 44.09,53.49 44.5,53.49 44.6,53.59 44.6,53.94 44.7,54.05 45.1,54.05 45.21,53.94 45.21,53.59 45.31,53.49 45.71,53.49 45.82,53.59 45.82,53.94 45.92,54.05 52.7,54.05 53.09,54.43 57.98,54.43 58.08,54.33 58.08,53.85 58.46,53.47 59.27,53.47 59.65,53.85 59.65,54.33 59.75,54.43 60.16,54.43 60.26,54.33 60.26,53.85 60.65,53.47 61.45,53.47 61.84,53.85 61.84,54.33 61.94,54.43 62.34,54.43 62.45,54.33 62.45,53.85 62.83,53.47 63.64,53.47 64.02,53.85 64.02,54.33 64.12,54.43 65.76,54.43 70.01,58.69 76.35,58.69 76.91,59.25 78.45,59.25 79.48,60.28
RP_DDR4_DIMM1_DQS5_P: length 57.6
  TOP w0.102: v2(37.69,52.17) 38,52.17 38.19,51.98 38.19,51.68 38.55,51.31 40.24,51.31 40.35,51.2 CONN7.200
  TOP w0.114: U9.CJ69 v4(82.25,60.87)
  S3 w0.089: 79.14,60.62 79.16,60.64 79.36,60.64 79.97,61.24 81.15,61.24 81.18,61.27 81.85,61.27 v4(82.25,60.87) ; 40.69,53.19 40.67,53.19 40.52,53.05 38.69,53.05 38.23,52.59 38.23,52.26 38.14,52.17 v2(37.69,52.17)
  S3 w0.102: 40.69,53.19 40.84,53.19 42.18,54.53 52.5,54.53 52.89,54.92 58.18,54.92 58.56,54.53 58.56,54.05 58.66,53.95 59.07,53.95 59.17,54.05 59.17,54.53 59.55,54.92 60.36,54.92 60.74,54.53 60.74,54.05 60.85,53.95 61.25,53.95 61.35,54.05 61.35,54.53 61.74,54.92 62.54,54.92 62.93,54.53 62.93,54.05 63.03,53.95 63.44,53.95 63.54,54.05 63.54,54.53 63.92,54.92 65.55,54.92 69.81,59.17 76.15,59.17 76.71,59.73 78.25,59.73 79.14,60.62
RP_DDR4_DIMM1_DQS6_N: length 86.2
  TOP w0.102: v2(36.65,46.68) 36.92,46.41 36.92,45.85 36.69,45.62 36.01,45.62 35.28,46.34 34.33,46.34 34.22,46.45 CONN7.219
  TOP w0.114: U9.BM72 v4(90.18,59.15)
  S8 w0.102: v4(90.18,59.15) 90.38,58.95 90.38,58.14 90.07,57.83 90.07,57.13 91.7,55.5 91.7,52.21 80.16,40.67 78.8,40.67 78.42,41.05 78.42,41.61 78.32,41.71 77.91,41.71 77.81,41.61 77.81,41.05 77.43,40.67 76.62,40.67 76.24,41.05 76.24,41.61 76.13,41.71 75.73,41.71 75.63,41.61 75.63,41.05 75.24,40.67 74.44,40.67 74.05,41.05 74.05,41.61 73.95,41.71 73.54,41.71 73.44,41.61 73.44,41.05 73.06,40.67 72.25,40.67 71.87,41.05 71.87,41.61 71.77,41.71 71.36,41.71 71.26,41.61 71.26,41.05 70.87,40.67 69.82,40.67 69.16,41.33 69.16,43.49 66.35,46.3 62.61,46.3 59.84,43.54 58.5,43.54 58.12,43.92 58.12,43.99 58.02,44.09 57.61,44.09 57.51,43.99 57.51,43.92 57.13,43.54 52.51,43.54 52.26,43.79 45.42,43.79 43.47,45.74 37.28,45.74 36.81,46.2 36.81,46.51 v2(36.65,46.68)
RP_DDR4_DIMM1_DQS6_P: length 86.1
  TOP w0.102: U9.BN71 v4(89.68,60.01) ; v2(37.46,46.68) 37.19,46.41 37.19,45.73 36.8,45.34 35.89,45.34 35.17,46.06 34.33,46.06 34.22,45.95 CONN7.221
  S8 w0.102: v2(37.46,46.68) 37.3,46.51 37.3,46.4 37.48,46.22 43.67,46.22 44.29,45.61 44.43,45.61 44.46,45.63 44.6,45.63 44.89,45.35 44.89,45.2 44.86,45.17 44.86,45.03 45.62,44.28 52.46,44.28 52.71,44.02 56.93,44.02 57.03,44.12 57.03,44.19 57.41,44.58 58.22,44.58 58.6,44.19 58.6,44.12 58.7,44.02 59.64,44.02 62.41,46.79 66.55,46.79 69.65,43.69 69.65,41.53 70.02,41.15 70.67,41.15 70.78,41.25 70.78,41.81 71.16,42.19 71.97,42.19 72.35,41.81 72.35,41.25 72.45,41.15 72.86,41.15 72.96,41.25 72.96,41.81 73.34,42.19 74.15,42.19 74.53,41.81 74.53,41.25 74.64,41.15 75.04,41.15 75.14,41.25 75.14,41.81 75.53,42.19 76.33,42.19 76.72,41.81 76.72,41.25 76.82,41.15 77.23,41.15 77.33,41.25 77.33,41.81 77.71,42.19 78.52,42.19 78.9,41.81 78.9,41.25 79,41.15 79.96,41.15 91.22,52.41 91.22,55.3 89.59,56.93 89.59,57.83 89.45,57.97 89.45,58.98 89.68,59.22 v4(89.68,60.01)
RP_DDR4_DIMM1_DQS7_N: length 78.4
  TOP w0.102: U9.BN67 v4(89.68,61.73) ; CONN7.240 40.35,41.2 40.24,41.09 37.31,41.09 37.19,41.2 37.19,41.35 v2(37.46,41.61)
  S5 w0.089: v2(37.46,41.61) 37.15,41.93 37.15,42.09 37.27,42.21 39.16,42.21 39.38,41.99 40.1,41.99 40.24,41.85 40.26,41.85 ; 89.03,57.2 89.04,57.22 89.04,57.43 89.54,57.92 89.54,59.47 89.29,59.72 89.29,60.17 89.77,60.64 89.77,61.15 89.68,61.24 v4(89.68,61.73)
  S5 w0.102: 40.26,41.85 41.1,41.85 41.42,42.17 42.99,42.17 43.09,42.07 43.09,41.73 43.2,41.63 43.6,41.63 43.7,41.73 43.7,42.07 43.81,42.17 44.21,42.17 44.31,42.07 44.31,41.73 44.42,41.63 44.82,41.63 44.92,41.73 44.92,42.07 45.03,42.17 54.51,42.17 56.82,44.48 56.97,44.48 57.29,44.16 57.83,44.16 58.4,44.74 58.4,45.28 58.08,45.6 58.08,45.74 59.04,46.7 68.49,46.7 68.59,46.6 68.59,46.29 68.98,45.91 69.78,45.91 70.17,46.29 70.17,46.6 70.27,46.7 70.68,46.7 70.78,46.6 70.78,46.29 71.16,45.91 71.97,45.91 72.35,46.29 72.35,46.6 72.45,46.7 72.86,46.7 72.96,46.6 72.96,46.29 73.35,45.91 74.15,45.91 74.54,46.29 74.54,46.6 74.64,46.7 75.05,46.7 75.15,46.6 75.15,46.29 75.53,45.91 76.34,45.91 76.72,46.29 76.72,46.6 76.82,46.7 77.23,46.7 77.33,46.6 77.33,46.29 77.72,45.91 78.52,45.91 78.91,46.29 78.91,46.6 79.01,46.7 80,46.7 86.68,53.38 86.68,54.85 89.03,57.2
RP_DDR4_DIMM1_DQS7_P: length 78.4
  TOP w0.102: v2(36.65,41.61) 36.92,41.35 36.92,41.09 37.19,40.81 40.24,40.81 40.35,40.7 CONN7.242 ; U9.BM66 v4(90.18,62.58)
  S5 w0.089: v2(36.65,41.61) 36.96,41.93 36.96,42.17 37.19,42.4 39.24,42.4 39.46,42.18 40.1,42.18 40.24,42.33 40.26,42.33 ; 88.69,57.54 88.7,57.56 88.91,57.56 89.35,58 89.35,59.39 89.1,59.64 89.1,60.25 89.58,60.72 89.58,61.07 89.29,61.36 89.29,61.93 89.95,62.58 v4(90.18,62.58)
  S5 w0.102: 88.69,57.54 86.2,55.05 86.2,53.58 79.8,47.18 78.81,47.18 78.42,46.8 78.42,46.49 78.32,46.39 77.92,46.39 77.81,46.49 77.81,46.8 77.43,47.18 76.62,47.18 76.24,46.8 76.24,46.49 76.14,46.39 75.73,46.39 75.63,46.49 75.63,46.8 75.25,47.18 74.44,47.18 74.05,46.8 74.05,46.49 73.95,46.39 73.55,46.39 73.44,46.49 73.44,46.8 73.06,47.18 72.25,47.18 71.87,46.8 71.87,46.49 71.77,46.39 71.36,46.39 71.26,46.49 71.26,46.8 70.88,47.18 70.07,47.18 69.69,46.8 69.69,46.49 69.58,46.39 69.18,46.39 69.08,46.49 69.08,46.8 68.69,47.18 58.84,47.18 57.6,45.94 57.6,45.4 57.92,45.08 57.92,44.94 57.63,44.65 57.49,44.65 57.17,44.97 56.62,44.97 54.31,42.65 41.22,42.65 40.9,42.33 40.26,42.33
RP_DDR4_DIMM1_DQS8_N: length 53.9
  TOP w0.102: v2(36.65,80.21) 36.9,80.21 37.14,79.97 37.14,79.52 36.97,79.34 34.33,79.34 34.22,79.45 CONN7.95
  TOP w0.114: U9.CL24 v4(81.26,80.9)
  S10 w0.089: v4(81.26,80.9) 81.05,81.11 80.36,81.11 80.21,80.96 80.19,80.96
  S10 w0.102: v2(36.65,80.21) 37.04,79.82 37.04,79.52 37.48,79.08 40.96,79.08 41.51,79.64 57.23,79.64 59.09,81.5 60.18,81.5 60.28,81.39 60.28,81.29 60.38,81.19 60.79,81.19 60.89,81.29 60.89,81.39 60.99,81.5 61.4,81.5 61.5,81.39 61.5,81.29 61.6,81.19 62.01,81.19 62.11,81.29 62.11,81.39 62.21,81.5 63.7,81.5 64.09,81.88 64.09,81.9 64.19,82 64.6,82 64.7,81.9 64.7,81.88 65.08,81.5 65.89,81.5 66.27,81.88 66.27,81.9 66.37,82 66.78,82 66.88,81.9 66.88,81.88 67.27,81.5 77.76,81.5 78.29,80.96 80.19,80.96
RP_DDR4_DIMM1_DQS8_P: length 53.9
  TOP w0.102: CONN7.97 34.22,78.95 34.33,79.06 37.08,79.06 37.42,79.4 37.42,79.97 37.67,80.21 v2(37.92,80.21)
  TOP w0.114: U9.CJ24 v4(82.25,80.9)
  S10 w0.089: v4(82.25,80.9) 81.85,81.3 81.67,81.3 81.66,81.3 80.36,81.3 80.21,81.45 80.19,81.45
  S10 w0.102: v2(37.92,80.21) 37.53,79.82 37.53,79.72 37.68,79.57 40.76,79.57 41.31,80.12 57.03,80.12 58.89,81.98 63.5,81.98 63.61,82.08 63.61,82.1 63.99,82.48 64.8,82.48 65.18,82.1 65.18,82.08 65.28,81.98 65.69,81.98 65.79,82.08 65.79,82.1 66.17,82.48 66.98,82.48 67.37,82.1 67.37,82.08 67.47,81.98 77.96,81.98 78.49,81.45 80.19,81.45
RP_DDR4_DIMM1_ECC0: length 53.6
  TOP w0.114: U9.CL20 v4(81.26,82.62) ; CONN7.92 v2(39.94,80.2)
  S10 w0.102: v2(39.94,80.2) 40,80.15 40.6,80.15 42.14,81.69 44.28,81.69 44.38,81.58 44.38,80.89 44.49,80.79 44.89,80.79 44.99,80.89 44.99,81.58 45.09,81.69 46.24,81.69 46.34,81.58 46.34,81.52 46.45,81.42 46.85,81.42 46.95,81.52 46.95,81.58 47.06,81.69 47.46,81.69 47.56,81.58 47.56,81.52 47.67,81.42 48.07,81.42 48.17,81.52 48.17,81.58 48.27,81.69 48.68,81.69 48.78,81.58 48.78,81.52 48.88,81.42 49.29,81.42 49.39,81.52 49.39,81.58 49.49,81.69 49.9,81.69 50,81.58 50,81.52 50.1,81.42 50.51,81.42 50.61,81.52 50.61,81.58 50.71,81.69 52.17,81.69 52.36,81.49 52.36,80.86 52.45,80.77 52.82,80.77 52.91,80.86 52.91,81.49 53,81.58 53.37,81.58 53.46,81.49 53.46,80.86 53.54,80.77 53.91,80.77 54,80.86 54,81.49 54.09,81.58 56.03,81.58 57.44,83 57.62,83 57.83,82.79 57.83,82.61 57.09,81.87 57.09,81.7 57.3,81.49 57.48,81.49 59.04,83.05 78.05,83.05 78.85,82.25 80.89,82.25 v4(81.26,82.62)
RP_DDR4_DIMM1_ECC1: length 53.6
  TOP w0.114: CONN7.91 34.64,80.45 v2(35.85,81.67) ; U9.CJ20 v4(82.25,82.62)
  S10 w0.102: v2(35.85,81.67) 35.65,81.46 35.65,81.2 35.83,81.02 40.63,81.02 41.79,82.18 53.34,82.18 53.42,82.27 53.42,82.67 53.51,82.76 53.88,82.76 53.97,82.67 53.97,82.27 54.06,82.18 55.78,82.18 57.25,83.64 78.61,83.64 79.36,82.89 80.87,82.89 81.02,83.03 81.53,83.03 81.95,82.62 v4(82.25,82.62)
RP_DDR4_DIMM1_ECC2: length 53.5
  TOP w0.114: CONN7.101 34.11,77.95 34.37,78.21 35.57,78.21 v2(36.31,77.47) ; U9.CL28 v4(81.26,79.18)
  S10 w0.102: v4(81.26,79.18) 79.72,79.18 79.39,79.51 77.22,79.51 76.4,78.69 69.9,78.69 69.81,78.78 69.81,79.14 69.72,79.22 69.35,79.22 69.27,79.14 69.27,78.78 69.18,78.69 68.81,78.69 68.72,78.78 68.72,79.14 68.63,79.22 68.26,79.22 68.17,79.14 68.17,78.78 68.08,78.69 67.72,78.69 67.63,78.78 67.63,79.14 67.54,79.22 59.49,79.22 57.1,76.83 53.34,76.83 52.87,77.3 44.88,77.3 44.78,77.4 44.78,77.57 44.68,77.68 44.27,77.68 44.17,77.57 44.17,77.4 44.07,77.3 36.48,77.3 v2(36.31,77.47)
RP_DDR4_DIMM1_ECC3: length 53.5
  TOP w0.114: U9.CJ28 v4(82.25,79.18) ; CONN7.105 34.17,76.95 v2(34.68,77.46)
  S10 w0.102: v4(82.25,79.18) 82.18,79.18 81.78,78.79 80.99,78.79 80.85,78.93 77.07,78.93 76.14,78 67.08,78 66.99,78.09 66.99,78.48 66.86,78.6 66.22,78.6 66.1,78.48 66.1,78.09 66.01,78 59.08,78 57.29,76.21 51.89,76.21 51.79,76.32 51.79,76.45 51.69,76.55 51.28,76.55 51.18,76.45 51.18,76.32 51.08,76.21 50.59,76.21 50.24,75.87 47.97,75.87 47.14,76.7 35.19,76.7 34.68,77.2 v2(34.68,77.46)
RP_DDR4_DIMM1_ECC4: length 53.5
  TOP w0.114: v2(37.48,81.69) 39.8,81.69 40.29,81.2 CONN7.88 ; U9.CM18 v4(80.77,83.47)
  S10 w0.102: v4(80.77,83.47) 80.42,83.13 79.79,83.13 78.27,84.64 57.4,84.64 56.11,83.35 45.75,83.35 45.66,83.27 45.66,82.87 45.57,82.78 45.21,82.78 45.12,82.87 45.12,83.27 45.03,83.35 44.66,83.35 44.57,83.27 44.57,82.87 44.48,82.78 44.16,82.78 43.59,83.35 42.12,83.35 41.97,83.2 41.84,83.2 41.57,83.48 41.44,83.48 41.18,83.22 41.18,83.09 41.45,82.82 41.45,82.69 41.19,82.43 41.07,82.43 40.79,82.7 40.67,82.7 40.41,82.44 40.41,82.32 40.68,82.04 40.68,81.92 40.45,81.69 v2(37.48,81.69)
RP_DDR4_DIMM1_ECC5: length 53.6
  TOP w0.114: U9.CK18 v4(81.76,83.47) ; CONN7.87 34.25,81.45 34.8,82.01 35.13,82.01 v2(36.16,83.04)
  S10 w0.102: v2(36.16,83.04) 37.25,84.13 37.78,84.13 37.87,84.04 37.87,83.75 37.96,83.66 38.33,83.66 38.42,83.75 38.42,84.04 38.51,84.13 38.88,84.13 38.97,84.04 38.97,83.75 39.05,83.66 39.42,83.66 39.51,83.75 39.51,84.04 39.6,84.13 39.97,84.13 40.06,84.04 40.06,83.75 40.15,83.66 40.51,83.66 40.6,83.75 40.6,84.04 40.69,84.13 56.04,84.13 57.15,85.24 78.44,85.24 79.77,83.91 81.32,83.91 v4(81.76,83.47)
RP_DDR4_DIMM1_ECC6: length 53.5
  TOP w0.114: v2(37.56,78.37) 37.97,78.78 40,78.78 40.58,78.2 CONN7.100 ; U9.CM26 v4(80.77,80.04)
  S10 w0.102: v4(80.77,80.04) 80.77,80.3 80.58,80.49 77.48,80.49 77.19,80.79 75.92,80.79 75.74,80.97 64.01,80.97 63.35,80.31 62.85,80.31 62.75,80.41 62.75,80.58 62.65,80.69 62.24,80.69 62.14,80.58 62.14,80.41 62.04,80.31 61.63,80.31 61.53,80.41 61.53,80.58 61.43,80.69 61.02,80.69 60.92,80.58 60.92,80.41 60.82,80.31 60.41,80.31 60.31,80.41 60.31,80.58 60.21,80.69 59.8,80.69 59.7,80.58 59.7,80.41 59.6,80.31 58.89,80.31 57.15,78.57 56.36,78.57 56.26,78.67 56.26,79.05 56.16,79.15 55.75,79.15 55.65,79.05 55.65,78.67 55.55,78.57 55.14,78.57 55.04,78.67 55.04,79.05 54.94,79.15 54.53,79.15 54.43,79.05 54.43,78.67 54.33,78.57 53.85,78.57 53.36,79.06 42.21,79.06 41.64,78.49 37.68,78.49 v2(37.56,78.37)
RP_DDR4_DIMM1_ECC7: length 53.5
  TOP w0.114: U9.CK26 v4(81.76,80.04) ; CONN7.104 40.53,77.2 40.22,77.51 40.21,77.51 39.83,77.89 v2(39.58,77.89)
  S10 w0.102: v2(39.58,77.89) 41.89,77.89 42.46,78.46 43.92,78.46 44.02,78.36 44.02,78.28 44.12,78.18 44.53,78.18 44.63,78.28 44.63,78.36 44.73,78.46 46.01,78.46 46.11,78.36 46.11,78.03 46.21,77.93 46.61,77.93 46.72,78.03 46.72,78.36 46.82,78.46 52.89,78.46 54.03,77.33 56.75,77.33 59.25,79.82 64.37,79.82 64.46,79.91 64.46,80.28 64.55,80.37 64.91,80.37 65,80.28 65,79.91 65.09,79.82 65.46,79.82 65.55,79.91 65.55,80.28 65.64,80.37 66.01,80.37 66.1,80.28 66.1,79.91 66.18,79.82 66.55,79.82 66.64,79.91 66.64,80.28 66.73,80.37 67.1,80.37 67.19,80.28 67.19,79.91 67.28,79.82 67.64,79.82 67.73,79.91 67.73,80.28 67.82,80.37 68.19,80.37 68.28,80.28 68.28,79.91 68.37,79.82 68.74,79.82 68.83,79.91 68.83,80.28 68.91,80.37 69.28,80.37 69.37,80.28 69.37,79.91 69.46,79.82 69.83,79.82 69.92,79.91 69.92,80.28 70.01,80.37 70.38,80.37 70.46,80.28 70.46,79.91 70.55,79.82 75.86,79.82 75.95,79.92 80.22,79.92 80.55,79.58 80.93,79.58 81.39,80.04 v4(81.76,80.04)
RP_DDR4_DIMM1_MA0: length 63
  TOP w0.178: v2(39.92,65.82) 39.92,66.42 40.71,67.2 CONN7.144 ; U9.CK49 v4(81.76,69.74)
  S8 w0.152: v2(39.92,65.82) 39.92,65.61 40.33,65.21 44.28,65.21 44.41,65.08 44.41,64.4 44.28,64.28 42.42,64.28 42.23,64.08 42.23,63.34 42.63,62.94 44.63,62.94 44.79,63.1 44.79,63.76 44.95,63.91 45.59,63.91 45.75,63.76 45.75,63.1 45.9,62.94 53.29,62.94 54.49,64.15 56.65,64.15 56.8,63.99 56.8,63.12 56.95,62.97 57.59,62.97 57.76,63.14 57.76,64.09 58.03,64.36 59.09,64.36 60.51,62.94 68.04,62.94 68.16,63.07 68.16,64.39 68.29,64.52 69.94,64.52 70.07,64.39 70.07,63.1 70.22,62.94 70.84,62.94 71,63.11 71,64.22 71.3,64.52 76.99,64.52 80.31,67.84 80.31,68.18 80.77,68.64 80.77,69.09 81.05,69.37 81.56,69.37 81.76,69.56 v4(81.76,69.74)
RP_DDR4_DIMM1_MA1: length 58.3
  TOP w0.178: U9.CK41 81.5,73.32 v4(81.76,73.17) ; v2(35.05,70.3) 34.7,69.95 CONN7.133
  S8 w0.089: v4(81.76,73.17) 82.07,73.17 82.74,72.5 82.74,72.17 82.26,71.69 82.26,71.3 81.89,70.94 81.64,70.94 81.49,71.08 81.05,71.08 80.85,70.88 80.59,70.88 80.46,71.01 79.87,71.01 78.51,69.65 78.51,68 77.73,67.21
  S8 w0.152: 77.73,67.21 72.36,67.21 72.2,67.38 67.41,67.38 66.61,66.58 46.17,66.58 45.03,67.72 42.4,67.72 40.92,69.2 37.99,69.2 37.63,69.56 34.84,69.56 34.61,69.8 34.61,70.07 34.84,70.3 v2(35.05,70.3)
RP_DDR4_DIMM1_MA2: length 58.1
  TOP w0.178: v2(39.94,70.3) 40.03,70.2 CONN7.132 ; v4(80.77,73.17) U9.CM41
  S8 w0.152: v2(39.94,70.3) 39.99,70.36 41.48,70.36 42.4,69.44 53.19,69.44 54.37,68.26 55.05,68.26 55.44,68.65 55.98,68.65 56.13,68.5 56.13,68.12 56.29,67.97 56.64,67.97 56.8,68.12 56.8,68.5 56.95,68.65 57.3,68.65 57.46,68.5 57.46,68.12 57.61,67.97 57.96,67.97 58.12,68.12 58.12,68.5 58.27,68.65 58.75,68.65 58.9,68.5 58.9,67.8 59.06,67.65 59.41,67.65 59.56,67.8 59.56,68.5 59.72,68.65 60.07,68.65 60.22,68.5 60.22,67.8 60.38,67.65 60.73,67.65 60.88,67.8 60.88,68.5 61.04,68.65 61.39,68.65 61.54,68.5 61.54,67.8 61.7,67.65 62.05,67.65 62.21,67.8 62.21,68.5 62.36,68.65 62.71,68.65 62.87,68.5 62.87,67.8 63.02,67.65 63.37,67.65 63.53,67.8 63.53,68.5 63.68,68.65 64.03,68.65 64.19,68.5 64.19,67.8 64.34,67.65 64.69,67.65 64.85,67.8 64.85,68.5 65,68.65 65.35,68.65 65.51,68.5 65.51,67.8 65.66,67.65 66.02,67.65 66.17,67.8 66.17,68.5 66.32,68.65 69.38,68.65 69.73,68.99 76.58,68.99 78.69,71.1 78.69,71.71 80.16,73.17 v4(80.77,73.17)
RP_DDR4_DIMM1_MA3: length 59.8
  TOP w0.178: U9.CF41 v4(83.74,73.17) ; v2(36.67,70.28) 36.67,70.37 36.12,70.92 34.62,70.92 34.15,70.45 CONN7.131
  S10 w0.152: v4(83.74,73.17) 83.33,72.76 78.86,72.76 76.64,70.54 75.54,70.54 75.25,70.83 74.88,70.83 74.59,70.54 74.22,70.54 73.93,70.83 73.56,70.83 73.27,70.54 72.9,70.54 72.61,70.83 70.92,70.83 70.63,70.54 70.26,70.54 69.97,70.83 69.6,70.83 69.31,70.54 68.94,70.54 68.65,70.83 68.28,70.83 67.99,70.54 67.14,70.54 66.98,70.7 66.98,71.31 66.86,71.44 66.15,71.44 66.02,71.31 66.02,70.7 65.87,70.54 65.22,70.54 65.07,70.7 65.07,71.29 64.91,71.44 64.26,71.44 64.11,71.29 64.11,70.7 63.95,70.54 60.52,70.54 57.73,67.74 42.92,67.74 41.21,69.45 36.59,69.45 36.4,69.65 36.4,70.01 v2(36.67,70.28)
RP_DDR4_DIMM1_MA4: length 59.5
  TOP w0.178: CONN7.128 40.29,71.2 40.22,71.13 38.96,71.13 38.31,70.49 v2(38.31,70.28) ; U9.CL39 v4(81.26,74.03)
  S8 w0.152: v4(81.26,74.03) 81.31,73.98 81.31,73.05 80.8,72.54 80.8,72.15 80.28,71.63 79.79,71.63 76.94,68.77 76.94,67.82 76.76,67.64 76.35,67.64 76.01,67.98 67.33,67.98 66.41,67.07 56.45,67.07 55.75,67.77 52.97,67.77 52.82,67.92 52.82,68.83 52.67,68.98 52.31,68.98 52.16,68.83 52.16,67.92 52.01,67.77 51.65,67.77 51.5,67.92 51.5,68.83 51.35,68.98 50.99,68.98 50.84,68.83 50.84,67.92 50.69,67.77 49.13,67.77 48.62,68.28 46.73,68.28 46.58,68.43 46.58,68.83 46.43,68.98 46.07,68.98 45.92,68.83 45.92,68.43 45.77,68.28 45.41,68.28 45.26,68.43 45.26,68.83 45.11,68.98 44.75,68.98 44.6,68.83 44.6,68.43 44.44,68.28 42.64,68.28 42.44,68.48 42.44,68.79 42.23,69 41.8,69 41.11,69.69 38.74,69.69 38.31,70.12 v2(38.31,70.28)
RP_DDR4_DIMM1_MA5: length 60.2
  TOP w0.178: U9.CG39 v4(83.24,74.03) ; v2(38.34,72.34) 38.34,72.13 38.8,71.67 39.92,71.67 39.96,71.71 41.38,71.71 CONN7.126
  S8 w0.089: v4(83.24,74.03) 82.87,74.03 82.25,74.65 82.25,74.95 81.83,75.37 80.52,75.37
  S8 w0.152: 80.52,75.37 79.84,74.7 79.84,74.31 77.8,72.27 77.8,71.8 76.96,70.97 67.71,70.97 67.56,70.82 67.56,70.1 67.41,69.95 67.05,69.95 66.9,70.1 66.9,70.82 66.75,70.97 66.26,70.97 66.11,70.82 66.11,69.82 65.96,69.67 65.6,69.67 65.45,69.82 65.45,70.82 65.3,70.97 64.94,70.97 64.79,70.82 64.79,69.82 64.64,69.67 64.28,69.67 64.13,69.82 64.13,70.82 63.98,70.97 63.5,70.97 63.31,70.78 56.68,70.78 55.94,70.04 55.34,70.04 55.23,69.92 54.22,69.92 54.06,70.08 54.06,70.58 53.86,70.78 52.15,70.78 51.66,71.26 47.18,71.26 46.81,70.89 42.4,70.89 41.89,71.4 39.27,71.4 v2(38.34,72.34)
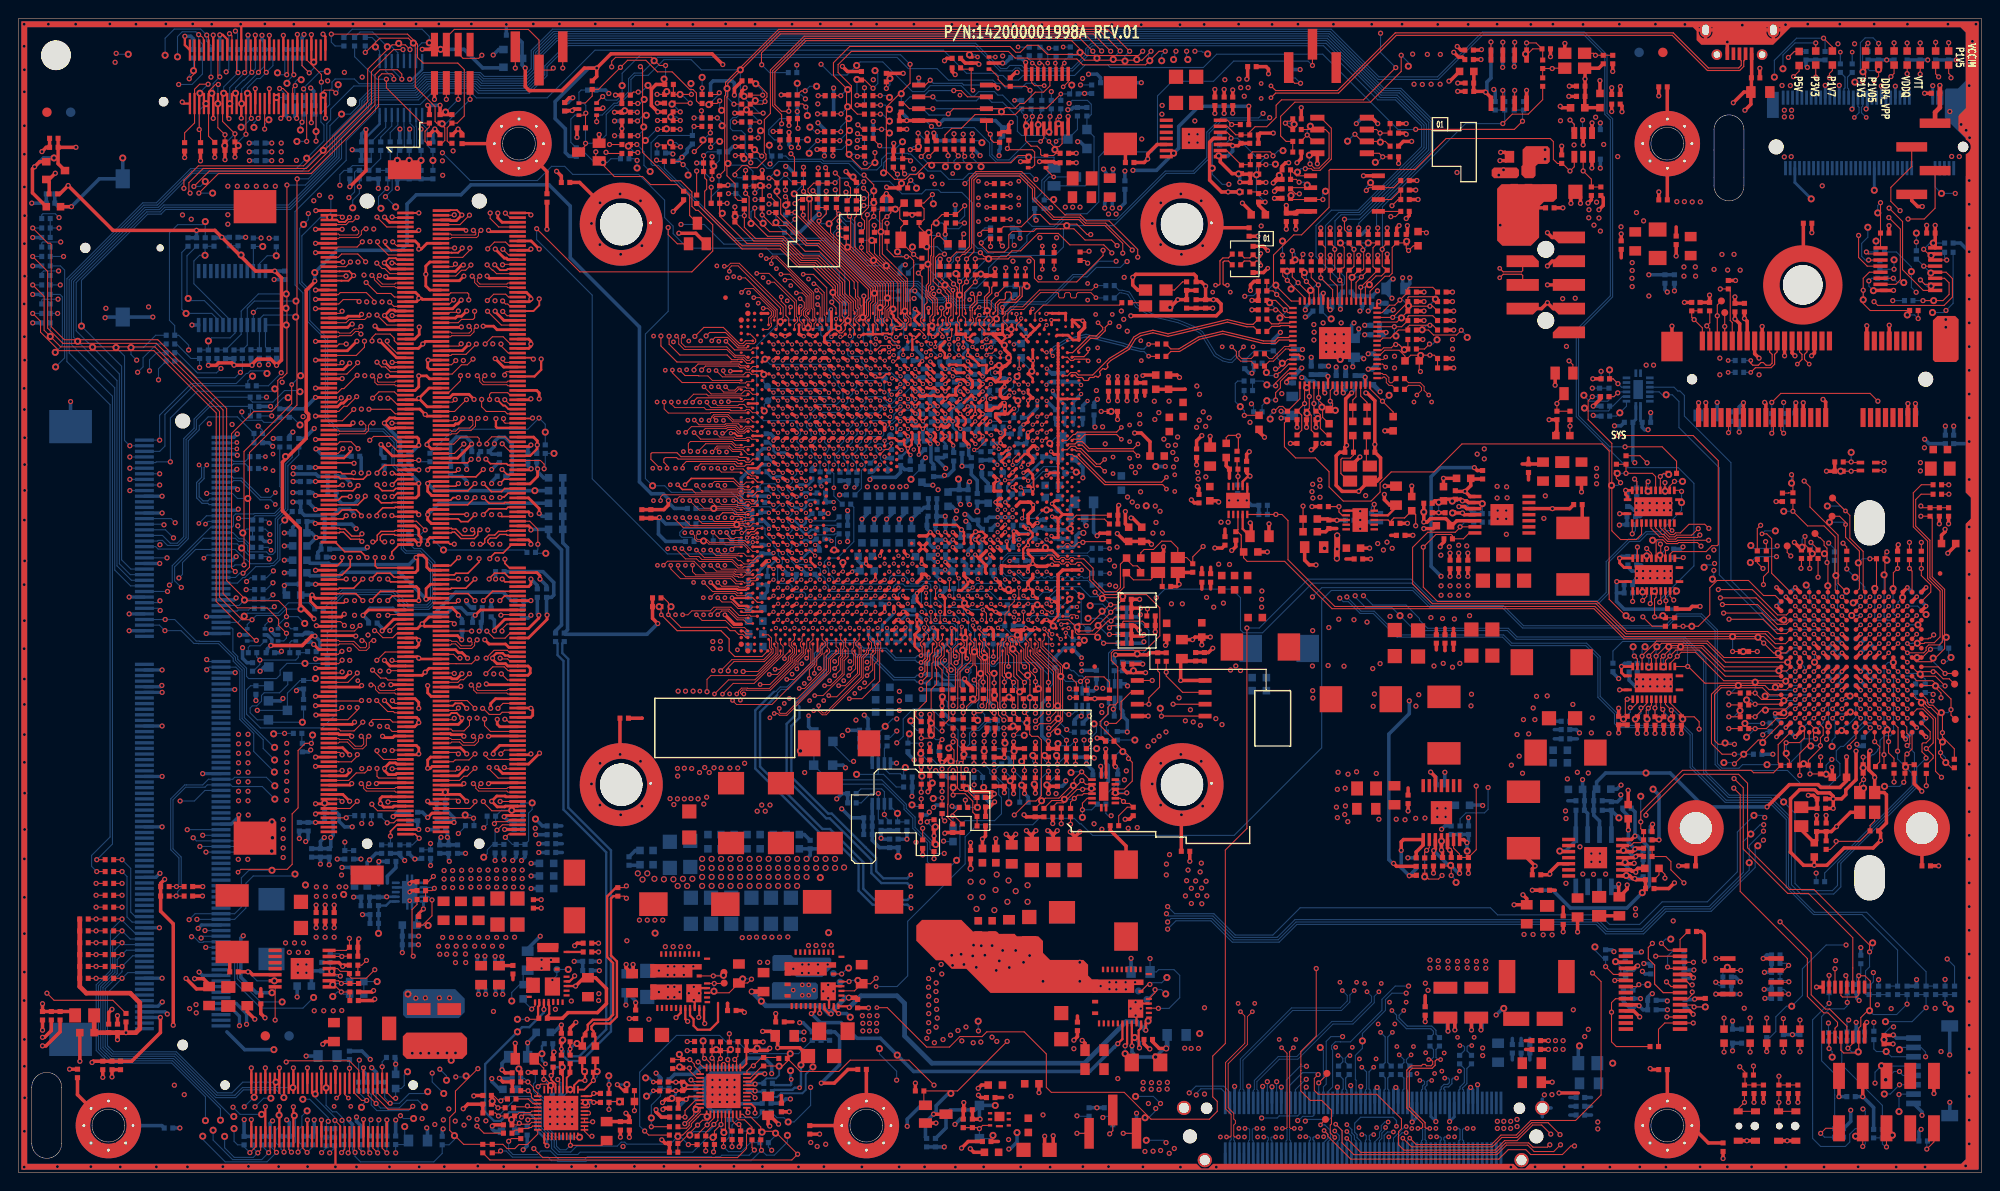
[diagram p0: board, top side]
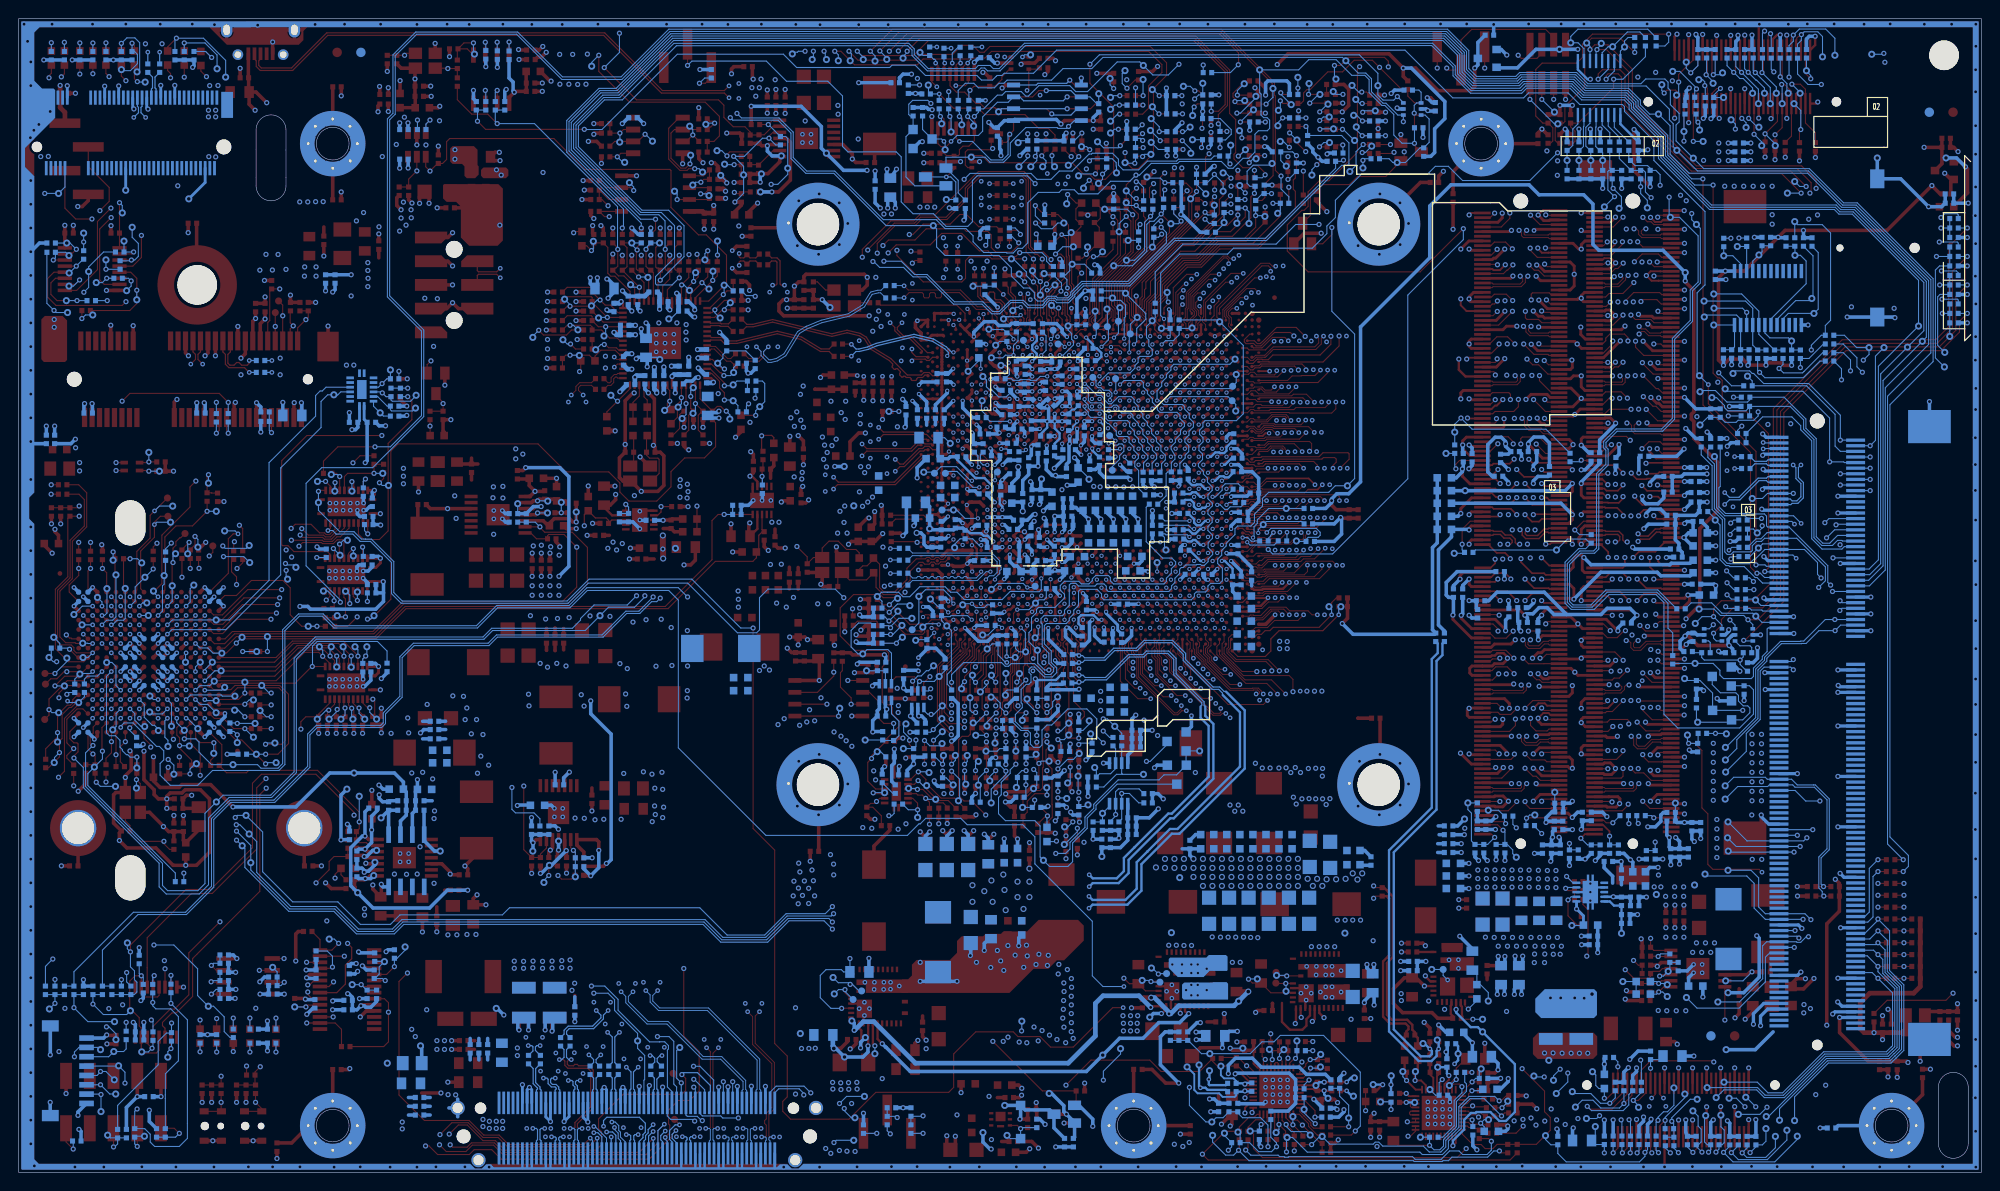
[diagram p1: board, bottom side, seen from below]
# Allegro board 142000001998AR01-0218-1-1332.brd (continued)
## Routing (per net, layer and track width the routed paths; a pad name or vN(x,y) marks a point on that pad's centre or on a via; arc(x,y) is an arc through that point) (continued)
RP_DDR4_DIMM1_MA6: length 60.1
  TOP w0.178: CONN7.127 36.27,71.45 37.09,72.27 v2(37.09,72.39) ; U9.CK37 v4(81.76,74.89)
  S8 w0.152: v2(37.09,72.39) 37.09,71.22 37.4,70.91 41.61,70.91 42.61,69.92 53.53,69.92 54.2,69.25 55.22,69.25 55.52,69.55 56.92,69.55 57.22,69.25 57.84,69.25 57.99,69.4 57.99,69.95 58.15,70.1 58.5,70.1 58.65,69.95 58.65,69.4 58.81,69.25 59.16,69.25 59.31,69.4 59.31,69.95 59.47,70.1 59.82,70.1 59.97,69.95 59.97,69.4 60.13,69.25 60.48,69.25 60.64,69.4 60.64,69.95 60.79,70.1 61.14,70.1 61.3,69.95 61.3,69.4 61.45,69.25 61.8,69.25 61.96,69.4 61.96,69.95 62.11,70.1 62.46,70.1 62.62,69.95 62.62,69.4 62.77,69.25 63.3,69.25 63.3,69.25 63.6,69.25 63.71,69.13 67.58,69.13 68.02,69.57 76.55,69.57 78.2,71.22 78.2,71.82 79.48,73.1 79.48,73.23 80.22,73.98 80.22,74.06 80.47,74.3 80.86,74.3 81.45,74.89 v4(81.76,74.89)
RP_DDR4_DIMM1_MA7: length 61.7
  TOP w0.178: v2(39.96,72.35) 40.14,72.35 40.5,72.7 CONN7.122 ; U9.CD39 v4(84.23,74.03)
  S8 w0.089: v4(84.23,74.03) 84.75,74.03 85.17,74.45 85.17,75.11 84.9,75.37 82.1,75.37 81.79,75.68
  S8 w0.152: 81.79,75.68 81.79,75.99 81.54,76.23 81.06,76.23 80.92,76.09 80.67,76.09 80.46,76.3 80.06,76.3 79.01,75.24 79.01,74.08 77.28,72.35 77.28,72 76.71,71.42 62.15,71.42 61.87,71.7 61.46,71.7 61.02,71.26 59.53,71.26 59.38,71.42 59.38,72.15 59.25,72.28 58.55,72.28 58.42,72.15 58.42,71.42 58.27,71.26 57.62,71.26 57.47,71.42 57.47,72.15 57.34,72.28 56.64,72.28 56.51,72.15 56.51,71.42 56.36,71.26 55.71,71.26 55.56,71.42 55.56,72.15 55.43,72.28 54.73,72.28 54.6,72.15 54.6,71.42 54.44,71.26 53.8,71.26 53.64,71.42 53.64,72.15 53.52,72.28 52.56,72.28 52.03,71.75 46.69,71.75 46.46,71.51 44.15,71.51 43.99,71.67 43.99,72.04 43.84,72.19 43.48,72.19 43.33,72.04 43.33,71.67 43.18,71.51 42.7,71.51 42.32,71.89 41.86,71.89 41.71,72.05 41.71,72.33 41.56,72.48 41.2,72.48 41.05,72.33 41.05,72.05 40.9,71.89 40.17,71.89 39.96,72.1 v2(39.96,72.35)
RP_DDR4_DIMM1_MA8: length 60.2
  TOP w0.178: CONN7.125 34.2,71.95 34.59,72.34 v2(35.46,72.34) ; U9.CM37 v4(80.77,74.89)
  S10 w0.152: v4(80.77,74.89) 80.06,74.18 78.84,74.18 77.07,72.42 60.25,72.42 59.8,71.97 59.59,71.97 59.12,72.44 58.9,72.44 58.65,72.18 58.65,71.97 59.12,71.5 59.12,71.28 58.87,71.03 58.65,71.03 58.18,71.5 57.97,71.5 57.72,71.25 57.72,71.04 58.19,70.56 58.19,70.35 57.56,69.72 56.61,69.72 56.46,69.58 56.46,68.96 56.3,68.8 55.66,68.8 55.5,68.96 55.5,69.58 55.34,69.73 54.41,69.73 54.25,69.58 54.25,68.94 54.09,68.77 53.6,68.77 53.45,68.92 53.45,69.49 53.3,69.64 52.94,69.64 52.79,69.49 52.79,68.92 52.64,68.77 51.16,68.77 50.65,69.28 46.69,69.28 46.54,69.13 46.54,68.99 46.38,68.83 46.03,68.83 45.88,68.99 45.88,69.13 45.72,69.28 45.37,69.28 45.22,69.13 45.22,68.99 45.06,68.83 44.71,68.83 44.55,68.99 44.55,69.13 44.4,69.28 42.76,69.28 40.66,71.38 35.78,71.38 35.46,71.7 v2(35.46,72.34)
RP_DDR4_DIMM1_MA9: length 58.4
  TOP w0.178: CONN7.121 34.47,72.95 34.48,72.96 35.76,72.96 v2(36.32,73.52) ; U9.CJ35 v4(82.25,75.75)
  S8 w0.152: v2(36.32,73.52) 36.32,73.33 36.56,73.09 41.99,73.09 42.31,72.77 44.83,72.77 44.99,72.61 44.99,72.36 45.11,72.24 45.82,72.24 45.94,72.36 45.94,72.61 46.1,72.77 59.84,72.77 59.99,72.61 59.99,71.88 60.12,71.75 60.82,71.75 60.95,71.88 60.95,72.26 61.19,72.5 63.2,72.5 63.35,72.35 63.35,72.14 63.51,71.98 63.86,71.98 64.02,72.14 64.02,72.35 64.17,72.5 64.52,72.5 64.68,72.35 64.68,72.14 64.83,71.98 65.18,71.98 65.34,72.14 65.34,72.35 65.49,72.5 65.84,72.5 66,72.35 66,72.14 66.15,71.98 66.5,71.98 66.66,72.14 66.66,72.35 66.81,72.5 76.76,72.5 78.52,74.27 78.52,75.59 79.74,76.81 80.24,76.81 80.51,77.09 81,77.09 81.14,76.95 81.39,76.95 81.52,77.09 81.91,77.09 82.25,76.75 v4(82.25,75.75)
RP_DDR4_DIMM1_MA10: length 62
  TOP w0.178: CONN7.146 38.37,64.7 38.14,64.93 v2(38.14,65.82) ; U9.CJ51 v4(82.25,68.88)
  S10 w0.089: 76.63,67.58 76.99,67.94 76.99,68.71 77.19,68.91 78.46,68.91 78.71,69.16 78.71,69.29 78.24,69.76 78.24,69.88 78.54,70.18 78.66,70.18 79.14,69.71 79.26,69.71 79.63,70.08 80.35,70.08 80.53,70.26 80.98,70.26 81.07,70.18 81.48,70.18 81.61,70.31 81.92,70.31 82.25,69.98 v4(82.25,68.88)
  S10 w0.152: v2(38.14,65.82) 38.14,65.36 38.4,65.1 40.54,65.1 40.69,65.25 40.69,65.56 40.84,65.71 41.2,65.71 41.35,65.56 41.35,65.25 41.5,65.1 53.04,65.1 53.19,65.25 53.19,65.36 53.34,65.51 53.7,65.51 53.85,65.36 53.85,65.25 54,65.1 54.98,65.1 55.29,65.42 59.17,65.42 59.59,65.83 60.34,65.83 60.49,65.99 60.49,66.27 60.64,66.42 61,66.42 61.15,66.27 61.15,65.99 61.3,65.83 61.78,65.83 61.94,65.99 61.94,67.23 62.09,67.39 62.44,67.39 62.6,67.23 62.6,65.99 62.75,65.83 63.23,65.83 64.53,67.13 66.77,67.13 66.92,67.28 66.92,67.69 67.07,67.84 67.43,67.84 67.58,67.69 67.58,67.28 67.73,67.13 68.21,67.13 68.75,67.66 68.75,68.27 68.87,68.4 69.58,68.4 69.71,68.27 69.71,67.92 69.87,67.77 74.17,67.77 74.36,67.58 76.63,67.58
RP_DDR4_DIMM1_MA11: length 57.7
  TOP w0.178: CONN7.120 40.34,73.2 40.1,72.97 38.9,72.97 38.34,73.53 v2(38.34,73.6) ; U9.CG35 v4(83.24,75.75)
  S10 w0.152: v4(83.24,75.75) 83.24,75.57 83,75.33 79.1,75.33 78.73,74.96 77.58,73.81 76.73,72.96 60.18,72.96 59.62,73.52 59.22,73.52 56.59,70.89 56.29,70.89 56.13,71.05 56.13,71.51 55.97,71.67 55.33,71.67 55.17,71.51 55.17,71.05 55.01,70.89 54.37,70.89 54.21,71.05 54.21,71.51 54.05,71.67 53.41,71.67 53.25,71.51 53.25,70.73 52.44,69.92 44.44,69.92 44.31,70.06 44.31,70.73 44.14,70.89 42.1,70.89 40.12,72.88 37.92,72.88 37.77,73.03 37.77,73.3 38.06,73.6 v2(38.34,73.6)
RP_DDR4_DIMM1_MA12: length 60.1
  TOP w0.178: v2(34.65,73.58) 34.37,73.58 34.24,73.45 CONN7.119 ; U9.CF37 v4(83.74,74.89)
  S10 w0.152: v2(34.65,73.58) 34.44,73.58 34.26,73.41 34.26,71.07 34.44,70.89 40.46,70.89 43.07,68.28 57.57,68.28 61.22,71.93 62.17,71.93 62.33,71.77 62.33,71.19 62.49,71.03 63.13,71.03 63.29,71.19 63.29,71.77 63.45,71.93 67.06,71.93 67.54,71.45 76.73,71.45 79.06,73.78 80.37,73.78 81.07,74.48 83.33,74.48 v4(83.74,74.89)
RP_DDR4_DIMM1_MA13: length 61.2
  TOP w0.178: v4(81.76,66.3) U9.CK56 ; v2(39.49,61.21) 39.99,61.7 CONN7.158
  S8 w0.152: v2(39.49,61.21) 39.29,61.21 38.9,60.81 38.9,60.31 39.08,60.13 40.06,60.13 40.26,60.33 40.26,60.86 40.42,61.02 40.98,61.02 41.22,60.78 41.22,59.61 41.36,59.47 42.11,59.47 42.28,59.63 42.28,60.08 42.43,60.23 43.21,60.23 43.36,60.08 43.36,59.63 43.52,59.48 44.16,59.48 44.32,59.63 44.32,60.08 44.48,60.23 45.12,60.23 45.28,60.08 45.28,59.63 45.43,59.48 46.08,59.48 46.23,59.63 46.23,60.08 46.39,60.23 64.87,60.23 65.03,60.08 65.03,59.79 65.18,59.64 65.53,59.64 65.69,59.79 65.69,60.08 65.84,60.23 67.5,60.23 67.65,60.39 67.65,60.78 67.81,60.94 68.45,60.94 68.61,60.78 68.61,60.39 68.76,60.23 69.41,60.23 69.56,60.39 69.56,60.78 69.72,60.94 70.36,60.94 70.52,60.78 70.52,60.39 70.68,60.23 71.91,60.23 72.06,60.39 72.06,60.58 72.21,60.73 72.57,60.73 72.72,60.58 72.72,60.39 72.87,60.23 73.23,60.23 73.38,60.39 73.38,60.58 73.53,60.73 73.89,60.73 74.04,60.58 74.04,60.39 74.19,60.23 77.31,60.23 78.58,61.51 79.53,61.51 80.23,62.2 81,62.2 81.15,62.05 81.43,62.05 81.79,62.41 81.79,62.74 82.19,63.14 82.19,64.85 81.76,65.28 v4(81.76,66.3)
RP_DDR4_DIMM1_MA14: length 60.6
  TOP w0.178: CONN7.151 34.99,63.45 v2(35.05,63.51) ; U9.CM52 v4(80.77,68.02)
  S10 w0.152: v2(35.05,63.51) 34.73,63.83 33.63,63.83 33.33,63.53 33.33,61.5 33.21,61.39 32.51,61.39 32.37,61.53 32.37,64.34 32.5,64.46 36.27,64.46 36.61,64.12 55.39,64.12 55.7,64.44 59.58,64.44 60,64.86 63.64,64.86 64.93,66.15 77.11,66.15 77.93,66.98 78.79,66.98 79.88,68.07 80.72,68.07 v4(80.77,68.02)
RP_DDR4_DIMM1_MA15: length 62
  TOP w0.178: CONN7.156 38.71,62.2 v2(37.71,61.21) ; U9.CJ54 v4(82.25,67.16)
  S10 w0.152: v2(37.71,61.21) 38.2,60.72 43.95,60.72 44.11,60.87 44.11,61.22 44.26,61.37 44.61,61.37 44.77,61.22 44.77,60.87 44.92,60.72 45.27,60.72 45.43,60.87 45.43,61.22 45.58,61.37 45.93,61.37 46.09,61.22 46.09,60.87 46.24,60.72 52.62,60.72 52.77,60.87 52.77,61.39 52.92,61.54 53.28,61.54 53.43,61.39 53.43,60.87 53.58,60.72 55.45,60.72 55.61,60.87 55.61,61.29 55.76,61.44 56.11,61.44 56.27,61.29 56.27,60.87 56.42,60.72 56.77,60.72 56.93,60.87 56.93,61.29 57.08,61.44 57.43,61.44 57.59,61.29 57.59,60.87 57.74,60.72 58.09,60.72 58.25,60.87 58.25,61.29 58.4,61.44 58.76,61.44 58.91,61.29 58.91,60.87 59.06,60.72 59.42,60.72 59.57,60.87 59.57,61.29 59.72,61.44 60.08,61.44 60.23,61.29 60.23,60.87 60.38,60.72 63.78,60.72 65.62,62.56 77.83,62.56 80.29,65.02 82.5,65.02 82.73,65.24 82.73,65.61 83.22,66.11 83.22,66.52 82.92,66.82 82.6,66.82 v4(82.25,67.16)
RP_DDR4_DIMM1_MA16: length 61.2
  TOP w0.178: v2(39.49,63.51) 39.8,63.2 CONN7.152 ; U9.CF49 v4(83.74,69.74)
  S10 w0.152: v2(39.49,63.51) 39.49,63.51 46.08,63.51 46.61,62.97 52.59,62.97 52.74,63.13 52.74,63.5 52.9,63.65 53.25,63.65 53.41,63.5 53.41,63.13 53.56,62.97 56.31,62.97 56.46,63.13 56.46,63.83 56.61,63.98 56.97,63.98 57.12,63.83 57.12,63.13 57.27,62.97 57.63,62.97 57.78,63.13 57.78,63.83 57.93,63.98 58.29,63.98 58.44,63.83 58.44,63.13 58.59,62.97 58.95,62.97 59.1,63.13 59.1,63.83 59.25,63.98 59.61,63.98 59.76,63.83 59.76,63.13 59.91,62.97 60.88,62.97 61.04,63.13 61.04,64.01 61.19,64.16 61.54,64.16 61.7,64.01 61.7,63.13 61.85,62.97 62.2,62.97 62.36,63.13 62.36,64.01 62.51,64.16 62.86,64.16 63.02,64.01 63.02,63.13 63.17,62.97 63.65,62.97 63.84,63.16 63.84,64.36 65.14,65.66 77.33,65.66 78.26,66.6 79.08,66.6 80.08,67.6 81.06,67.6 81.35,67.89 81.35,68.27 81.62,68.54 81.84,68.54 81.99,68.4 82.45,68.4 82.82,68.76 82.82,69.2 83.36,69.74 v4(83.74,69.74)
RP_DDR4_DIMM1_ODT0: length 58.4
  TOP w0.178: v4(83.74,66.3) U9.CF56 ; CONN7.155 34.21,62.45 34.29,62.54 35.85,62.54 v2(36.82,63.51)
  S8 w0.089: 80.85,65.41 80.85,65.57 81.37,66.09 81.37,66.45 81.69,66.76 83.28,66.76 v4(83.74,66.3)
  S8 w0.152: v2(36.82,63.51) 37.43,62.9 39.84,62.9 42.03,60.72 61.6,60.72 62.31,61.43 63.05,61.43 63.2,61.27 63.2,60.88 63.36,60.72 64,60.72 64.16,60.88 64.16,61.27 64.31,61.43 64.96,61.43 65.11,61.27 65.11,60.88 65.27,60.72 65.91,60.72 66.07,60.88 66.07,61.27 66.22,61.43 71.47,61.43 72.07,62.03 78.38,62.03 80.29,63.93 80.29,64.82 80.85,65.38 80.85,65.41
RP_DDR4_DIMM1_ODT1: length 57.3
  TOP w0.178: U9.CM60 v4(80.77,64.59) ; v2(35.05,61.21) 34.79,60.95 CONN7.161
  S10 w0.152: v2(35.05,61.21) 35.71,61.87 35.71,62.56 35.52,62.75 34.22,62.75 33.92,62.46 33.92,60.54 34.22,60.24 63.99,60.24 65.83,62.07 66.63,62.07 66.78,61.92 66.78,61.82 66.94,61.67 67.29,61.67 67.44,61.82 67.44,61.92 67.6,62.07 78.16,62.07 79.29,63.2 79.29,63.22 80.66,64.59 v4(80.77,64.59)
RP_DDR4_DIMM1_PAR: length 62.4
  TOP w0.178: U9.CM49 v4(80.77,69.74) ; v2(37.26,65.82) 36.63,66.44 34.89,66.44 33.87,67.45 CONN7.143
  S10 w0.089: v4(80.77,69.74) 80.51,69.48 80.02,69.48 78.01,67.47 77.71,67.47 77.35,67.11
  S10 w0.152: v2(37.26,65.82) 36.59,66.49 32.62,66.49 32.34,66.2 32.34,65.46 32.58,65.21 36.21,65.21 36.81,64.61 55.18,64.61 55.5,64.93 59.38,64.93 59.79,65.34 63.43,65.34 64.73,66.64 68.42,66.64 69.05,67.28 72.37,67.28 72.54,67.11 77.35,67.11
RP_DDR4_DIMM1_R_EVENT_L: length 4.5
  TOP w0.114: CONN7.134 42.56,69.7 v2(43.5,68.77)
  BOTTOM w0.114: v2(43.5,68.77) 42.99,68.26 R570.1
RP_DDR4_DIMM1_R_RST_L: length 2.7
  TOP w0.114: CONN7.108 42.77,76.2 v2(42.81,76.24)
  BOTTOM w0.114: v2(42.81,76.24) 42.97,76.07 R551.1
RP_DDR4_DIMM1_SA0: length 4.3
  TOP w0.178: CONN7.256 40.48,37.2 39.78,36.5 v2(39.78,35.99)
  BOTTOM w0.114: R682.1 R683.1 v2(39.78,35.99)
RP_DDR4_DIMM1_SA1: length 4
  TOP w0.178: CONN7.260 42.41,36.2 v2(42.85,35.76)
  BOTTOM w0.114: R684.1 R685.1 42.14,35.05 v2(42.85,35.76)
RP_DDR4_DIMM1_SA2: length 40.5
  TOP w0.114: v2(39.49,59.63) 39.57,59.7 CONN7.166
  S3 w0.102: v2(34.9,35.35) 32.26,35.35 30.68,36.93 30.68,59.13 31.95,60.4 37.54,60.4 37.82,60.12 39,60.12 v2(39.49,59.63)
  BOTTOM w0.114: R691.1 R690.1 v2(34.9,35.35)
RP_DDR4_DIMM2_ACT_L: length 35.1
  TOP w0.102: v3(74.04,73.54) 74.45,73.95 76.47,73.95 77.03,73.39 U9.CU41
  TOP w0.178: CONN8.114 52.26,74.7 v2(51.72,75.24)
  S3 w0.152: v2(51.72,75.24) 52.17,74.79 53.12,74.79 53.27,74.95 53.27,75.42 53.43,75.58 54.07,75.58 54.23,75.42 54.23,74.95 54.38,74.79 57.11,74.79 57.26,74.94 57.26,75.29 57.41,75.44 57.77,75.44 57.92,75.29 57.92,74.94 58.07,74.79 58.43,74.79 58.58,74.94 58.58,75.29 58.73,75.44 59.09,75.44 59.24,75.29 59.24,74.94 59.39,74.79 59.75,74.79 59.9,74.94 59.9,75.29 60.05,75.44 60.41,75.44 60.56,75.29 60.56,74.94 60.71,74.79 61.07,74.79 61.22,74.94 61.22,75.29 61.38,75.44 61.73,75.44 61.88,75.29 61.88,74.94 62.04,74.79 63.61,74.79 65.01,73.39 69.11,73.39 69.66,72.84 73.68,72.84 74.04,73.2 v3(74.04,73.54)
RP_DDR4_DIMM2_ALERT_L: length 44.9
  TOP w0.102: 72.04,73.09 72.4,72.73 77.04,72.73 77.15,72.62 77.47,72.62 77.66,72.81 78.46,72.81 U9.CT42
  TOP w0.178: v2(51.49,73.74) 51.96,74.2 CONN8.116 ; 72.04,73.09 71.02,73.09 v3(70.51,73.6)
  S5 w0.152: v3(70.51,73.6) 70.02,74.09 67.51,74.09 66.57,75.03 66.57,75.92 66.42,76.07 65.84,76.07 65.68,76.23 65.68,76.58 65.84,76.73 66.42,76.73 66.57,76.89 66.57,77.37 65.23,78.71 64.17,78.71 64.01,78.87 64.01,79.48 63.86,79.63 63.51,79.63 63.35,79.48 63.35,78.87 63.2,78.71 62.84,78.71 62.69,78.87 62.69,79.48 62.54,79.63 62.18,79.63 62.03,79.48 62.03,78.87 61.88,78.71 61.52,78.71 61.37,78.87 61.37,79.48 61.22,79.63 60.86,79.63 60.71,79.48 60.71,78.87 60.56,78.71 60.2,78.71 60.05,78.87 60.05,79.48 59.9,79.63 59.54,79.63 59.39,79.48 59.39,78.87 59.24,78.71 58.88,78.71 58.73,78.87 58.73,79.48 58.58,79.63 58.22,79.63 58.07,79.48 58.07,78.87 57.92,78.71 54.85,78.71 53.97,77.83 53.97,76.21 v2(51.49,73.74)
RP_DDR4_DIMM2_BA0: length 33.8
  TOP w0.102: U9.CR61 78.56,64.48 78.22,64.14 77.85,64.14 77.72,64.27 76.71,64.27 76.61,64.37 74.65,64.37 v3(74.04,64.98)
  TOP w0.178: v2(50.34,63.51) 50.34,63.56 50.93,64.14 52,64.14 52.44,63.7 CONN8.150
  S5 w0.152: v3(74.04,64.98) 73.08,64.02 72.23,64.02 71.12,62.9 50.95,62.9 v2(50.34,63.51)
RP_DDR4_DIMM2_BA1: length 44.4
  TOP w0.102: U9.CT60 78.4,64.83 77.61,64.83 77.47,64.7 76.98,64.7 76.29,65.38 72.82,65.38 72.53,65.67 71.34,65.67 v3(70.2,66.82)
  TOP w0.178: v2(47.07,65.79) 46.23,64.95 CONN8.145
  S3 w0.152: v3(70.2,66.82) 69.78,67.23 68.63,67.23 68.09,66.69 61.78,66.69 61.62,66.54 61.62,66.07 61.47,65.91 61.12,65.91 60.96,66.07 60.96,66.54 60.81,66.69 60.45,66.69 60.3,66.54 60.3,66.07 60.15,65.91 59.79,65.91 59.64,66.07 59.64,66.54 59.49,66.69 59.01,66.69 58.85,66.54 58.85,66.04 58.7,65.89 58.35,65.89 58.19,66.04 58.19,66.54 58.04,66.69 57.69,66.69 57.53,66.54 57.53,66.04 57.38,65.89 57.03,65.89 56.87,66.04 56.87,66.54 56.72,66.69 56.37,66.69 56.21,66.54 56.21,66.04 56.06,65.89 55.7,65.89 55.55,66.04 55.55,66.54 55.4,66.69 55.04,66.69 54.89,66.54 54.89,66.04 54.74,65.89 54.38,65.89 54.23,66.04 54.23,66.54 54.08,66.69 53.72,66.69 53.57,66.54 53.57,66.04 53.42,65.89 53.06,65.89 52.91,66.04 52.91,66.54 52.76,66.69 47.56,66.69 47.07,66.2 v2(47.07,65.79)
RP_DDR4_DIMM2_BG0: length 45
  TOP w0.102: v3(74.8,73.54) 75.21,73.14 76.91,73.14 76.96,73.19 77.54,73.19 77.67,73.06 78.22,73.06 78.55,73.39 U9.CR41
  TOP w0.178: v2(49.71,75.24) 48.93,74.45 CONN8.115
  S3 w0.152: v3(74.8,73.54) 74.8,73.66 74.33,74.13 72.35,74.13 71.63,74.85 67.61,74.85 66.15,76.32 65.16,76.32 64.24,77.24 52.49,77.24 52.28,77.02 46.17,77.02 45.94,76.8 45.94,76.07 46.15,75.86 48,75.86 48.62,75.24 v2(49.71,75.24)
RP_DDR4_DIMM2_BG1: length 43.9
  TOP w0.102: v3(72.52,73.54) 73.13,72.93 77.28,72.93 U9.CV42
  TOP w0.178: v2(47.05,75.24) 46.76,74.95 CONN8.113
  S5 w0.152: v3(72.52,73.54) 72.52,73.79 72.77,74.04 73.15,74.04 73.33,74.22 73.33,74.65 73.15,74.83 67.51,74.83 67.11,75.23 67.11,76.18 67.26,76.34 67.84,76.34 68,76.49 68,76.84 67.84,77 67.26,77 67.11,77.15 67.11,77.7 64.67,80.14 57.16,80.14 56.4,79.38 53.72,79.38 52.91,78.57 52.91,77.79 51.09,75.97 51.09,74.8 50.8,74.51 47.77,74.51 v2(47.05,75.24)
RP_DDR4_DIMM2_CKE0_L: length 44.2
  TOP w0.102: 76.48,74.28 77.15,73.61 77.57,73.61 77.85,73.89 U9.CT40
  TOP w0.178: CONN8.109 48.03,75.95 v2(48.41,76.33) ; v3(71.3,73.6) 71.97,74.28 76.48,74.28
  S3 w0.152: v2(48.41,76.33) 48.41,76.27 48.83,75.85 50.42,75.85 50.63,76.07 52.82,76.07 52.97,76.22 52.97,76.53 53.12,76.68 53.48,76.68 53.63,76.53 53.63,76.22 53.79,76.07 54.14,76.07 54.29,76.22 54.29,76.53 54.45,76.68 54.8,76.68 54.95,76.53 54.95,76.22 55.11,76.07 55.46,76.07 55.61,76.22 55.61,76.53 55.77,76.68 56.12,76.68 56.27,76.53 56.27,76.22 56.43,76.07 56.78,76.07 56.93,76.22 56.93,76.53 57.09,76.68 57.44,76.68 57.6,76.53 57.6,76.22 57.75,76.07 58.1,76.07 58.26,76.22 58.26,76.53 58.41,76.68 58.76,76.68 58.92,76.53 58.92,76.22 59.07,76.07 59.42,76.07 59.58,76.22 59.58,76.53 59.73,76.68 60.08,76.68 60.24,76.53 60.24,76.22 60.39,76.07 60.74,76.07 60.9,76.22 60.9,76.53 61.05,76.68 61.41,76.68 61.56,76.53 61.56,76.22 61.71,76.07 62.07,76.07 62.22,76.22 62.22,76.53 62.37,76.68 62.73,76.68 62.88,76.53 62.88,76.22 63.03,76.07 64.55,76.07 64.83,75.79 64.83,74.48 65.05,74.25 65.68,74.25 65.84,74.4 65.84,74.73 65.99,74.88 66.34,74.88 66.5,74.73 66.5,74.4 66.65,74.25 70.65,74.25 v3(71.3,73.6)
RP_DDR4_DIMM2_CKE1_L: length 40.9
  TOP w0.102: v3(74.8,75.37) 75.2,74.97 77.22,74.97 U9.CV38
  TOP w0.178: v2(49.99,76.35) 49.99,76.34 50.47,75.86 52.2,75.86 52.36,75.7 CONN8.110
  S5 w0.152: v3(74.8,75.37) 74.8,75.46 74.02,76.25 69.85,76.25 68.66,77.44 68.66,77.65 69.18,78.17 69.18,78.39 68.93,78.64 68.72,78.64 68.2,78.12 67.98,78.12 67.73,78.37 67.73,78.59 68.25,79.11 68.25,79.32 68,79.58 67.78,79.58 67.26,79.05 67.05,79.05 66.79,79.31 66.79,79.52 67.32,80.04 67.32,80.26 67.06,80.51 66.85,80.51 66.33,79.99 66.11,79.99 65.41,80.7 56.96,80.7 56.16,79.89 53.55,79.89 52.42,78.76 52.42,77.99 50.78,76.35 v2(49.99,76.35)
RP_DDR4_DIMM2_CLK0_N: length 44.7
  TOP w0.102: v3(74.8,66.61) 75.21,66.21 76.96,66.21 77.02,66.27 77.57,66.27 77.87,65.97 U9.CT58
  TOP w0.152: CONN8.139 46.3,68.45 46.38,68.54 46.64,68.54 47.34,67.84 48.75,67.84 49.12,68.21 49.12,68.56 v2(49.36,68.79)
  S3 w0.127: v3(74.8,66.61) 74.8,66.64 74.54,66.9 74.54,67.37 73.99,67.92 70.93,67.92 70.27,68.58 67.07,68.58 66.57,69.08 65.99,69.08 65.73,68.81 65.73,68.2 65.6,68.07 65.22,68.07 65.09,68.2 65.09,68.81 64.82,69.08 64.24,69.08 63.97,68.81 63.97,68.2 63.85,68.07 63.46,68.07 63.34,68.2 63.34,68.81 63.07,69.08 62.49,69.08 62.22,68.81 62.22,68.2 62.09,68.07 61.71,68.07 61.58,68.2 61.58,68.81 61.32,69.08 60.74,69.08 60.47,68.81 60.47,68.2 60.34,68.07 59.96,68.07 59.83,68.2 59.83,68.81 59.56,69.08 58.98,69.08 58.71,68.81 58.71,68.2 58.59,68.07 57.96,68.07 57.83,68.2 57.83,68.44 57.57,68.71 56.98,68.71 56.72,68.44 56.72,68.2 56.59,68.07 49.24,68.07 49.07,68.23 49.07,68.51 v2(49.36,68.79)
RP_DDR4_DIMM2_CLK0_P: length 44.7
  TOP w0.102: U9.CV58 77.28,66 75.12,66 75.1,66.02 74.63,66.02 v3(74.04,66.61)
  TOP w0.152: v2(48.55,68.79) 48.79,68.55 48.79,68.35 48.62,68.17 47.47,68.17 46.78,68.87 46.38,68.87 46.3,68.95 CONN8.137
  S3 w0.127: v2(48.55,68.79) 48.83,68.51 48.83,68.13 49.14,67.83 52.2,67.83 52.44,67.59 52.84,67.59 53.07,67.83 53.47,67.83 53.71,67.59 54.11,67.59 54.34,67.83 56.69,67.83 56.96,68.1 56.96,68.34 57.08,68.47 57.47,68.47 57.59,68.34 57.59,68.1 57.86,67.83 58.69,67.83 58.96,68.1 58.96,68.71 59.08,68.83 59.46,68.83 59.59,68.71 59.59,68.1 59.86,67.83 60.44,67.83 60.71,68.1 60.71,68.71 60.84,68.83 61.22,68.83 61.34,68.71 61.34,68.1 61.61,67.83 62.19,67.83 62.46,68.1 62.46,68.71 62.59,68.83 62.97,68.83 63.1,68.71 63.1,68.1 63.36,67.83 63.95,67.83 64.21,68.1 64.21,68.71 64.34,68.83 64.72,68.83 64.85,68.71 64.85,68.1 65.12,67.83 65.7,67.83 65.97,68.1 65.97,68.71 66.09,68.83 66.47,68.83 66.97,68.34 70.17,68.34 70.83,67.68 72.36,67.68 72.49,67.55 72.49,67.34 72.62,67.21 73,67.21 73.12,67.34 73.12,67.55 73.25,67.68 73.89,67.68 74.3,67.27 74.3,66.9 74.04,66.64 v3(74.04,66.61)
RP_DDR4_DIMM2_CLK1_N: length 43
  TOP w0.089: v3(72.77,68.49) 72.49,68.21 72.49,67.91 72.65,67.75 73.62,67.75 73.94,67.44 77.57,67.44 78.55,66.46 U9.CR57
  TOP w0.152: CONN8.140 52.27,68.2 52.18,68.29 51.47,68.29 51.08,67.89 50.44,67.89 50.2,67.65 50.2,67.43 50.39,67.24 v2(50.67,67.24)
  S5 w0.127: v2(50.67,67.24) 50.44,67.24 50.15,67.53 50.15,67.82 50.29,67.96 55.91,67.96 56.67,67.19 57.7,67.19 57.96,67.46 57.96,67.86 58.09,67.98 58.47,67.98 58.6,67.86 58.6,67.46 58.87,67.19 60.34,67.19 60.61,67.46 60.61,67.93 60.73,68.06 61.11,68.06 61.24,67.93 61.24,67.46 61.51,67.19 62.09,67.19 62.36,67.46 62.36,67.93 62.48,68.06 62.87,68.06 62.99,67.93 62.99,67.46 63.26,67.19 63.84,67.19 64.11,67.46 64.11,67.93 64.24,68.06 64.62,68.06 64.75,67.93 64.75,67.46 65.01,67.19 65.59,67.19 65.86,67.46 65.86,67.93 65.99,68.06 66.37,68.06 66.5,67.93 66.5,67.46 66.77,67.19 68.51,67.19 68.86,67.54 72.11,67.54 72.51,67.94 72.51,68.21 72.77,68.47 v3(72.77,68.49)
RP_DDR4_DIMM2_CLK1_P: length 42.9
  TOP w0.089: v3(72.01,68.49) 72.3,68.2 72.3,67.83 72.57,67.56 73.54,67.56 73.86,67.25 77.49,67.25 78.05,66.69 U9.CU57
  TOP w0.152: v2(49.4,67.24) 49.68,67.24 49.87,67.42 49.87,67.79 50.3,68.22 50.94,68.22 51.34,68.62 52.18,68.62 52.27,68.7 CONN8.138
  S5 w0.127: v3(72.01,68.49) 72.01,68.47 72.27,68.21 72.27,68.04 72.01,67.78 68.76,67.78 68.41,67.43 66.87,67.43 66.74,67.56 66.74,68.03 66.47,68.3 65.89,68.3 65.62,68.03 65.62,67.56 65.49,67.43 65.11,67.43 64.99,67.56 64.99,68.03 64.72,68.3 64.14,68.3 63.87,68.03 63.87,67.56 63.74,67.43 63.36,67.43 63.23,67.56 63.23,68.03 62.97,68.3 62.38,68.3 62.12,68.03 62.12,67.56 61.99,67.43 61.61,67.43 61.48,67.56 61.48,68.03 61.21,68.3 60.63,68.3 60.36,68.03 60.36,67.56 60.24,67.43 58.97,67.43 58.84,67.56 58.84,67.96 58.57,68.22 57.99,68.22 57.72,67.96 57.72,67.56 57.6,67.43 56.77,67.43 56.01,68.2 50.19,68.2 49.91,67.92 49.91,67.46 49.68,67.24 v2(49.4,67.24)
RP_DDR4_DIMM2_CS0_L: length 44.4
  TOP w0.102: U9.CR63 78.88,63.33 78.38,63.33 78.15,63.1 77.65,63.1 77.47,63.28 76.84,63.28 76.35,63.76 71.37,63.76 70.55,64.57 v3(70.55,64.98)
  TOP w0.178: v2(49.26,65.69) 49.26,65.32 48.07,64.13 46.79,64.13 46.61,63.95 CONN8.149
  S3 w0.152: v3(70.55,64.98) 70.55,65.21 70.2,65.56 68.03,65.56 67.14,64.67 65.49,64.67 63.57,62.76 56.97,62.76 56.85,62.88 56.85,63.59 56.97,63.71 59.09,63.71 59.24,63.86 59.24,64.57 59.14,64.67 50.23,64.67 49.26,65.64 v2(49.26,65.69)
RP_DDR4_DIMM2_CS1_L: length 41.7
  TOP w0.102: v3(73.28,63.15) 74.24,62.18 76.71,62.18 76.88,62.01 U9.CV66
  TOP w0.178: v2(48.82,61.21) 48.08,61.95 CONN8.157
  S5 w0.152: v3(73.28,63.15) 73.28,62.38 72.54,61.65 71.47,61.65 70.84,62.28 59.83,62.28 59.56,62.01 50.67,62.01 49.78,62.9 46.2,62.9 45.98,62.68 45.98,62.02 46.16,61.84 48.58,61.84 48.82,61.59 v2(48.82,61.21)
RP_DDR4_DIMM2_DQ0: length 51.9
  TOP w0.102: v3(82.59,92.63) 82.6,92.63 82.51,92.54 U9.CG1
  TOP w0.114: v2(50.45,102.7) 50.45,102.12 51.36,101.2 CONN8.8
  S8 w0.102: v3(82.59,92.63) 82.65,92.69 82.65,94.22 78.77,98.11 78.77,99.34 70.33,107.77 59.66,107.77 55.65,103.76 55.24,103.76 55.14,103.86 55.14,104.62 55.04,104.72 54.63,104.72 54.53,104.62 54.53,103.86 54.43,103.76 54.02,103.76 53.92,103.86 53.92,104.62 53.82,104.72 53.42,104.72 53.31,104.62 53.31,103.86 53.21,103.76 52.81,103.76 52.7,103.86 52.7,104.62 52.6,104.72 52.2,104.72 52.09,104.62 52.09,103.86 51.99,103.76 51.51,103.76 v2(50.45,102.7)
RP_DDR4_DIMM2_DQ1: length 51.7
  TOP w0.114: CONN8.7 47.22,101.45 v2(48.23,102.47) ; v3(81.59,93.71) 81.59,93.26 82.09,92.75 82.09,91.71 82.4,91.4 82.4,90.83 U9.CG3
  S8 w0.102: v2(48.23,102.47) 48.23,102.42 49.12,101.52 55.75,101.52 56.73,102.5 56.88,102.5 57.15,102.23 57.29,102.23 57.58,102.51 57.58,102.66 57.31,102.93 57.31,103.08 57.59,103.36 57.74,103.36 58.01,103.09 58.16,103.09 58.44,103.38 58.44,103.52 58.17,103.8 58.17,103.94 58.46,104.23 58.6,104.23 58.88,103.95 59.02,103.95 59.31,104.24 59.31,104.38 59.03,104.66 59.03,104.8 59.32,105.09 59.46,105.09 59.74,104.81 59.88,104.81 60.17,105.1 60.17,105.25 59.89,105.52 59.89,105.67 60.5,106.27 68.09,106.27 80.76,93.6 81.47,93.6 v3(81.59,93.71)
RP_DDR4_DIMM2_DQ2: length 51.9
  TOP w0.102: v3(79.66,92.5) 80.15,92.5 80.54,92.1 80.54,91.77 80.24,91.47 U9.CM3
  TOP w0.114: CONN8.20 52.42,98.2 v2(51.81,98.81)
  S8 w0.102: v3(79.66,92.5) 79.66,93.47 78.34,94.79 73.71,94.79 73.36,95.15 72.85,95.15 72.74,95.05 72.74,94.49 72.64,94.39 72.24,94.39 72.13,94.49 72.13,95.05 72.03,95.15 71.63,95.15 71.52,95.05 71.52,94.49 71.42,94.39 71.02,94.39 70.91,94.49 70.91,95.05 70.81,95.15 70.41,95.15 70.31,95.05 70.31,94.49 70.2,94.39 69.8,94.39 69.7,94.49 69.7,95.05 69.59,95.15 69.19,95.15 69.09,95.05 69.09,94.49 68.98,94.39 68.58,94.39 68.48,94.49 68.48,95.05 68.37,95.15 67.97,95.15 67.87,95.05 67.87,94.49 67.77,94.39 67.36,94.39 67.26,94.49 67.26,95.05 67.16,95.15 66.75,95.15 66.65,95.05 66.65,94.49 66.55,94.39 66.14,94.39 66.04,94.49 66.04,95.05 65.94,95.15 59.41,95.15 57,97.56 56.52,97.56 56.41,97.46 56.41,96.11 56.31,96.01 55.91,96.01 55.8,96.11 55.8,97.46 55.7,97.56 55.3,97.56 55.19,97.46 55.19,96.11 55.09,96.01 54.69,96.01 54.58,96.11 54.58,97.46 54.48,97.56 54.08,97.56 53.98,97.46 53.98,96.11 53.87,96.01 53.47,96.01 53.37,96.11 53.37,97.46 53.26,97.56 52.73,97.56 51.81,98.48 v2(51.81,98.81)
RP_DDR4_DIMM2_DQ3: length 52.1
  TOP w0.102: U9.CN4 80.18,90.22 80.55,90.59 80.55,90.85 80.49,90.9 80.49,91.43 80.75,91.69 80.75,92.19 79.3,93.64 v3(78.65,93.64)
  TOP w0.114: CONN8.21 47.51,97.95 48.27,98.71 v2(48.27,98.94)
  S8 w0.102: v2(48.27,98.94) 48.27,98.64 47.37,97.74 46.18,97.74 45.39,96.95 45.39,94.72 46.1,94.01 64.62,94.01 65.38,93.24 66.09,93.24 66.19,93.14 66.19,93.07 66.3,92.96 66.7,92.96 66.8,93.07 66.8,93.14 66.91,93.24 67.31,93.24 67.41,93.14 67.41,93.07 67.52,92.96 67.92,92.96 68.02,93.07 68.02,93.14 68.13,93.24 68.53,93.24 68.63,93.14 68.63,93.07 68.73,92.96 69.14,92.96 69.24,93.07 69.24,93.14 69.34,93.24 69.75,93.24 69.85,93.14 69.85,93.07 69.95,92.96 70.36,92.96 70.46,93.07 70.46,93.14 70.56,93.24 70.97,93.24 71.07,93.14 71.07,93.07 71.17,92.96 71.58,92.96 71.68,93.07 71.68,93.14 71.78,93.24 72.19,93.24 72.29,93.14 72.29,93.07 72.39,92.96 72.8,92.96 72.9,93.07 72.9,93.14 73,93.24 73.41,93.24 73.51,93.14 73.51,93.07 73.61,92.96 74.02,92.96 74.12,93.07 74.12,93.14 74.22,93.24 74.63,93.24 74.73,93.14 74.73,93.07 74.83,92.96 75.24,92.96 75.34,93.07 75.34,93.14 75.44,93.24 75.85,93.24 75.95,93.14 75.95,93.07 76.05,92.96 76.46,92.96 76.56,93.07 76.56,93.14 76.66,93.24 77.5,93.24 77.89,93.64 v3(78.65,93.64)
RP_DDR4_DIMM2_DQ4: length 51.7
  TOP w0.102: U9.CF2 83,93.14 80.85,95.29 v3(80.23,95.29)
  TOP w0.114: CONN8.4 52.56,102.2 v2(52.08,102.68)
  S8 w0.102: v3(80.23,95.29) 80.23,95.83 77.79,98.27 77.79,98.41 78.1,98.72 78.1,98.86 77.81,99.15 77.67,99.15 77.36,98.84 77.22,98.84 76.93,99.13 76.93,99.27 77.24,99.58 77.24,99.72 76.95,100.01 76.81,100.01 76.5,99.7 76.35,99.7 76.07,99.99 76.07,100.13 76.37,100.44 76.37,100.59 76.09,100.87 75.94,100.87 75.63,100.57 75.49,100.57 75.2,100.85 75.2,101 75.51,101.31 75.51,101.45 75.22,101.74 75.08,101.74 74.77,101.43 74.63,101.43 74.34,101.72 74.34,101.86 74.65,102.17 74.65,102.31 74.36,102.6 74.22,102.6 73.91,102.29 73.77,102.29 73.48,102.58 73.48,102.72 73.79,103.03 73.79,103.17 73.5,103.46 73.36,103.46 73.05,103.15 72.9,103.15 72.62,103.44 72.62,103.59 72.92,103.89 72.92,104.04 72.64,104.32 72.49,104.32 72.18,104.02 72.04,104.02 71.75,104.3 71.75,104.45 72.06,104.76 72.06,104.9 71.77,105.19 71.63,105.19 71.32,104.88 71.18,104.88 70.84,105.22 70.84,105.36 71.11,105.64 71.11,105.78 70.82,106.07 70.68,106.07 70.4,105.8 70.26,105.8 68.82,107.24 59.94,107.24 55.81,103.1 52.49,103.1 v2(52.08,102.68)
RP_DDR4_DIMM2_DQ5: length 51.8
  TOP w0.102: U9.CF4 83,90.75 83.33,91.08 83.33,91.48 83.2,91.61 83.2,93.32 80.28,96.24 v3(78.97,96.24)
  TOP w0.114: CONN8.3 46.56,102.45 v2(46.61,102.5)
  S8 w0.102: v3(78.97,96.24) 68.45,106.76 60.2,106.76 55.47,102.03 49.51,102.03 48.06,103.48 46.04,103.48 45.81,103.24 45.81,102.68 45.99,102.5 v2(46.61,102.5)
RP_DDR4_DIMM2_DQ6: length 51.9
  TOP w0.102: v3(77.34,94.2) 77.75,94.6 78.62,94.6 80.95,92.27 80.95,91.6 80.84,91.49 U9.CL2
  TOP w0.114: v2(50.18,98.86) 50.9,99.58 52.1,99.58 52.48,99.2 CONN8.16
  S8 w0.102: v3(77.34,94.2) 76.95,93.8 65.81,93.8 65.05,94.56 57.51,94.56 57.4,94.67 57.4,95.38 57.3,95.48 56.9,95.48 56.79,95.38 56.79,94.67 56.69,94.56 56.29,94.56 56.18,94.67 56.18,95.38 56.08,95.48 55.68,95.48 55.58,95.38 55.58,94.67 55.47,94.56 55.07,94.56 54.97,94.67 54.97,95.38 54.86,95.48 54.46,95.48 54.36,95.38 54.36,94.67 54.25,94.56 53.85,94.56 53.75,94.67 53.75,95.38 53.64,95.48 53.24,95.48 53.14,95.38 53.14,94.67 53.04,94.56 52.55,94.56 52.45,94.67 52.45,96.44 52.35,96.55 51.94,96.55 51.84,96.44 51.84,94.67 51.74,94.56 51.03,94.56 50.77,94.82 50.77,96.16 50.42,96.52 49.89,96.52 49.45,96.95 49.45,98.13 v2(50.18,98.86)
RP_DDR4_DIMM2_DQ7: length 51.8
  TOP w0.102: v3(77.14,95.75) 77.76,95.75 81.15,92.36 81.15,90.36 U9.CK4
  TOP w0.114: CONN8.17 v2(46.64,98.95)
  S8 w0.102: v3(77.14,95.75) 76.67,95.28 74.11,95.28 73.66,95.73 59.61,95.73 57.23,98.12 54.14,98.12 52.73,99.53 48.79,99.53 48.79,99.53 48.33,99.53 46.51,101.35 45.12,101.35 44.9,101.13 44.9,100.34 45,100.24 46.46,100.24 46.56,100.14 46.56,99.73 46.46,99.63 45,99.63 44.9,99.53 44.9,98.67 45.09,98.49 46.46,98.49 46.64,98.67 v2(46.64,98.95)
RP_DDR4_DIMM2_DQ8: length 40.7
  TOP w0.114: v3(74.15,89.01) 74.52,89.38 75.85,89.38 76.97,88.26 77.88,88.26 U9.CU8 ; CONN8.28 51.13,96.2 50.75,96.59 50.68,96.59 v2(50.12,97.14)
  S3 w0.102: v3(74.15,89.01) 74.65,89.51 74.65,89.89 71.7,92.84 71.56,92.84 71.36,92.64 71.22,92.64 70.93,92.93 70.93,93.07 71.13,93.27 71.13,93.41 70.84,93.7 70.7,93.7 70.5,93.5 70.35,93.5 70.07,93.79 70.07,93.93 70.27,94.13 70.27,94.28 69.98,94.56 69.83,94.56 69.63,94.36 69.49,94.36 69.2,94.65 69.2,94.8 69.4,94.99 69.4,95.14 69.11,95.43 68.97,95.43 68.77,95.23 68.63,95.23 67.61,96.24 59.51,96.24 57.43,98.32 50.45,98.32 50.12,97.99 v2(50.12,97.14)
RP_DDR4_DIMM2_DQ9: length 40.7
  TOP w0.114: v3(75.67,88.97) 76.6,88.04 78.35,88.04 78.55,88.24 U9.CR8 ; v2(48.39,97.13) 47.83,96.57 47.38,96.57 46.76,95.95 CONN8.29
  S3 w0.102: v2(48.39,97.13) 48.39,97.74 49.99,99.34 58.52,99.34 61.04,96.82 68.43,96.82 75.67,89.58 v3(75.67,88.97)
RP_DDR4_DIMM2_DQ10: length 40.4
  TOP w0.114: CONN8.41 46.09,92.95 v2(46.53,93.39) ; U9.CU13 77.87,86.26 77.8,86.34 77.28,86.34 77.09,86.53 72.69,86.53 72.26,86.1 v2(72.26,85.89)
  S3 w0.102: v2(46.53,93.39) 47.25,92.68 53.83,92.68 55.58,90.93 65.08,90.93 68.41,87.6 69.02,87.6 69.12,87.5 69.12,86.79 69.22,86.69 69.63,86.69 69.73,86.79 69.73,87.5 69.83,87.6 70.24,87.6 70.34,87.5 70.34,86.79 70.44,86.69 70.85,86.69 70.95,86.79 70.95,87.5 71.05,87.6 71.64,87.6 72.26,86.97 v2(72.26,85.89)
RP_DDR4_DIMM2_DQ11: length 40.7
  TOP w0.114: CONN8.42 52.58,92.7 52.33,92.96 52.09,92.96 51.78,93.27 v2(51.78,93.28) ; v2(73.07,85.89) 73.49,86.31 77,86.31 77.19,86.12 77.71,86.12 77.93,85.9 78.19,85.9 78.56,86.26 U9.CR13
  S3 w0.102: v2(73.07,85.89) 73.66,86.48 75.38,86.48 75.61,86.7 75.61,87.97 75.32,88.25 74.36,88.25 74.25,88.15 74.25,87.68 74.15,87.58 73.75,87.58 73.64,87.68 73.64,88.15 73.54,88.25 73.14,88.25 73.03,88.15 73.03,87.68 72.93,87.58 72.53,87.58 72.43,87.68 72.43,88.15 72.32,88.25 68.46,88.25 65.27,91.44 55.95,91.44 54.11,93.28 v2(51.78,93.28)
RP_DDR4_DIMM2_DQ12: length 40.5
  TOP w0.114: U9.CU5 78.28,89.73 78.86,89.15 78.86,88.89 78.67,88.71 78.21,88.71 78.18,88.74 77.87,88.74 77.6,88.47 77.07,88.47 75.64,89.91 73.93,89.91 v2(73.55,89.53) ; v2(51.77,97.16) 51.82,97.2 CONN8.24
  S3 w0.102: v2(73.55,89.53) 73.55,89.53 72.85,90.23 72.85,90.37 73.01,90.53 73.01,90.67 72.72,90.96 72.57,90.96 72.42,90.81 72.28,90.81 71.99,91.09 71.99,91.24 72.14,91.39 72.14,91.53 71.86,91.82 71.71,91.82 71.56,91.67 71.41,91.67 67.4,95.68 59.28,95.68 58.39,96.57 57.31,96.57 57.21,96.67 57.21,97.23 57.1,97.33 56.7,97.33 56.6,97.23 56.6,96.67 56.5,96.57 56.09,96.57 55.99,96.67 55.99,97.23 55.89,97.33 55.48,97.33 55.38,97.23 55.38,96.67 55.28,96.57 54.87,96.57 54.77,96.67 54.77,97.23 54.67,97.33 54.26,97.33 54.16,97.23 54.16,96.67 54.06,96.57 53.65,96.57 53.55,96.67 53.55,97.23 53.45,97.33 53.04,97.33 52.94,97.23 52.94,96.67 52.84,96.57 52.35,96.57 v2(51.77,97.16)
RP_DDR4_DIMM2_DQ13: length 40.6
  TOP w0.114: v2(72.35,89.48) 73.31,90.45 75.4,90.45 76.91,88.94 76.93,88.94 77.05,88.81 77.15,88.72 77.47,88.72 77.78,89.02 U9.CT7 ; CONN8.25 46.45,96.95 v2(46.73,97.23)
  S3 w0.102: v2(46.73,97.23) 46.1,97.23 45.92,97.05 45.92,96.47 46.28,96.11 46.91,96.11 47.33,96.53 51.19,96.53 51.65,96.07 57.9,96.07 58.8,95.17 67.22,95.17 72.36,90.03 72.36,89.5 v2(72.35,89.48)
RP_DDR4_DIMM2_DQ14: length 40.6
  TOP w0.114: v2(50.14,93.32) 50.82,94 52.11,94 52.41,93.7 CONN8.38 ; U9.CV12 77.3,86.77 76.23,86.77 76.21,86.75 70.43,86.75 68.72,88.46 v2(68.72,89.53)
  S3 w0.102: v2(50.14,93.32) 50.14,93.48 50.63,93.96 56.26,93.96 56.72,93.5 56.72,93.36 56.58,93.22 56.58,93.08 56.87,92.79 57.01,92.79 57.15,92.93 57.3,92.93 57.74,92.48 58.23,92.48 58.33,92.38 58.33,92.02 58.43,91.92 58.84,91.92 58.94,92.02 58.94,92.38 59.04,92.48 59.45,92.48 59.55,92.38 59.55,92.02 59.65,91.92 60.06,91.92 60.16,92.02 60.16,92.38 60.26,92.48 60.67,92.48 60.77,92.38 60.77,92.02 60.87,91.92 61.27,91.92 61.38,92.02 61.38,92.38 61.48,92.48 61.88,92.48 61.99,92.38 61.99,92.02 62.09,91.92 62.49,91.92 62.6,92.02 62.6,92.38 62.7,92.48 63.1,92.48 63.21,92.38 63.21,92.02 63.31,91.92 63.71,91.92 63.81,92.02 63.81,92.38 63.92,92.48 64.32,92.48 64.42,92.38 64.42,92.02 64.53,91.92 64.93,91.92 65.03,92.02 65.03,92.38 65.14,92.48 65.77,92.48 v2(68.72,89.53)
RP_DDR4_DIMM2_DQ15: length 40.7
  TOP w0.114: U9.CT12 78.39,86.6 77.92,86.6 77.48,87.04 77.41,87.04 76.96,87.04 76.91,86.99 76.31,86.99 75.8,87.5 70.74,87.5 69.59,88.65 v2(69.59,89.5) ; CONN8.37 46.03,93.95 46.23,94.15 48.03,94.15 48.16,94.02 v2(48.16,93.39)
  S3 w0.102: v2(48.16,93.39) 48.04,93.51 48.04,94.27 48.23,94.46 48.76,94.46 48.86,94.36 48.86,93.68 48.96,93.57 49.37,93.57 49.47,93.68 49.47,94.36 49.57,94.46 56.55,94.46 57.96,93.04 66.14,93.04 69.59,89.59 v2(69.59,89.5)
RP_DDR4_DIMM2_DQ16: length 37.9
  TOP w0.102: U9.CV16 74.22,84.78 73.74,85.26 72.77,85.26
  TOP w0.114: CONN8.50 51.64,90.7 v2(50.17,92.18) ; 72.77,85.26 72.73,85.29 71.3,85.29 v3(70.71,85.88)
  S8 w0.102: v3(70.71,85.88) 70.71,86.72 70.21,87.22 67.95,87.22 65.4,89.77 65.39,89.77 64.98,90.18 59.82,90.18 59.69,90.31 59.69,90.6 59.82,90.73 61.06,90.73 61.19,90.86 61.19,91.21 61.06,91.33 58.18,91.33 55.24,91.33 51.01,91.33 v2(50.17,92.18)
RP_DDR4_DIMM2_DQ17: length 37.9
  TOP w0.102: 72.87,84.55 77.11,84.55 77.15,84.5 77.76,84.5 77.9,84.63 78.4,84.63 U9.CT16
  TOP w0.114: v3(69.94,85.89) 69.94,85.59 70.99,84.55 72.87,84.55 ; v2(48.78,92.18) 48.78,91.48 48.61,91.31 47.38,91.31 47.02,90.95 CONN8.49
  S8 w0.102: v3(69.94,85.89) 69.94,86.23 69.55,86.62 67.85,86.62 64.89,89.59 59.57,89.59 58.43,90.74 50.83,90.74 50.41,91.16 49.8,91.16 v2(48.78,92.18)
RP_DDR4_DIMM2_DQ18: length 38.2
  TOP w0.114: v3(72.11,82.43) 72.59,82.91 77.2,82.91 U9.CV20 ; v2(51.6,88.67) 51.6,88.5 52.39,87.7 CONN8.62
  S8 w0.102: v3(72.11,82.43) 72.11,82.68 71.31,83.48 67.94,83.48 63.88,87.54 63.4,87.54 63.3,87.43 63.3,86.8 63.19,86.7 62.79,86.7 62.69,86.8 62.69,87.43 62.59,87.54 62.18,87.54 62.08,87.43 62.08,86.8 61.98,86.7 61.57,86.7 61.47,86.8 61.47,87.43 61.37,87.54 60.96,87.54 60.86,87.43 60.86,86.8 60.76,86.7 60.35,86.7 60.25,86.8 60.25,87.43 60.15,87.54 59.74,87.54 59.64,87.43 59.64,86.8 59.54,86.7 59.13,86.7 59.03,86.8 59.03,87.43 58.93,87.54 58.52,87.54 58.42,87.43 58.42,86.8 58.32,86.7 57.91,86.7 57.81,86.8 57.81,87.43 57.71,87.54 52.84,87.54 51.7,88.67 v2(51.6,88.67)
RP_DDR4_DIMM2_DQ19: length 38.1
  TOP w0.102: U9.CT20 78.49,82.74 77.7,82.74 77.46,82.5 v3(75.94,82.5)
  TOP w0.114: v2(48.97,88.67) 47.86,87.57 46.37,87.57 46.26,87.45 CONN8.63
  S8 w0.102: v2(48.97,88.67) 48.97,87.6 49.43,87.13 49.43,86.5 49.91,86.02 52.15,86.02 52.66,85.51 64.22,85.51 67.89,81.84 75.28,81.84 v3(75.94,82.5)
RP_DDR4_DIMM2_DQ20: length 37.9
  TOP w0.102: U9.CU15 77.94,85.16 75.29,85.16 v3(74.62,85.83)
  TOP w0.114: v2(51.79,92.16) 52.25,91.7 CONN8.46
  S8 w0.102: v2(51.79,92.16) 63.85,92.16 63.97,92.03 63.97,91.74 63.85,91.61 61.91,91.61 61.79,91.49 61.79,91.2 61.91,91.07 64.94,91.07 68.27,87.73 71.29,87.73 71.38,87.64 71.38,86.63 71.46,86.55 71.83,86.55 71.92,86.64 71.92,87.64 72.01,87.73 72.72,87.73 v3(74.62,85.83)
RP_DDR4_DIMM2_DQ21: length 37.9
  TOP w0.102: U9.CR15 78.88,85.43 78.44,85.43 78.43,85.44 78.41,85.44 78.2,85.65 77.81,85.65 77.52,85.36 75.64,85.36 75.39,85.61 v3(75.39,85.82)
  TOP w0.114: v2(47.05,92.21) 46.9,92.06 46.15,92.06 46.04,91.95 CONN8.45
  S8 w0.102: v2(47.05,92.21) 47.62,92.78 64.05,92.78 68.49,88.34 73.34,88.34 75.39,86.29 v3(75.39,85.82)
RP_DDR4_DIMM2_DQ22: length 38
  TOP w0.102: U9.CU19 77.88,83.12 73.79,83.12 73.61,83.3 72.21,83.3 v3(71.35,82.44)
  TOP w0.114: v2(49.91,88.67) 50.69,89.45 51.84,89.45 52.58,88.7 CONN8.58
  S8 w0.102: v3(71.35,82.44) 71.35,82.47 70.86,82.96 67.61,82.96 64.46,86.11 57.63,86.11 57.16,86.58 56.68,86.58 56.57,86.48 56.57,86.19 56.47,86.09 56.07,86.09 55.96,86.19 55.96,86.48 55.86,86.58 55.46,86.58 55.35,86.48 55.35,86.19 55.25,86.09 54.85,86.09 54.74,86.19 54.74,86.48 54.64,86.58 54.24,86.58 54.14,86.48 54.14,86.19 54.03,86.09 53.63,86.09 53.53,86.19 53.53,86.48 53.42,86.58 53,86.58 51.81,87.77 50.16,87.77 49.91,88.03 v2(49.91,88.67)
RP_DDR4_DIMM2_DQ23: length 37.8
  TOP w0.102: v3(73.32,84.09) 74.09,83.33 77.32,83.33 77.66,83.67 78.14,83.67 78.52,83.29 U9.CR19
  TOP w0.114: v2(47.34,88.7) 47.1,88.45 CONN8.59
  S8 w0.102: v3(73.32,84.09) 73.32,83.65 73.11,83.43 72.41,83.43 71.75,84.09 68.02,84.09 64.06,88.05 53.17,88.05 51.95,89.27 47.92,89.27 v2(47.34,88.7)
RP_DDR4_DIMM2_DQ24: length 43
  TOP w0.102: v3(69.07,82.46) 69.07,81.72 69.51,81.28 74.03,81.28 74.08,81.34 75.99,81.34 76.04,81.29 78.03,81.29 U9.CU24
  TOP w0.114: CONN8.70 52.17,85.7 52,85.53 v2(52,85.36)
  S3 w0.102: v3(69.07,82.46) 68.17,83.36 68.02,83.36 67.27,82.61 67.12,82.61 66.84,82.9 66.84,83.04 67.59,83.79 67.59,83.94 67.3,84.23 67.16,84.23 66.41,83.47 66.26,83.47 65.97,83.76 65.97,83.9 66.73,84.66 66.73,84.8 66.44,85.09 66.3,85.09 65.54,84.33 65.4,84.33 65.11,84.62 65.11,84.76 65.87,85.52 65.87,85.66 65.52,86 63.92,86 63.82,86.11 63.82,86.48 63.72,86.58 63.31,86.58 63.21,86.48 63.21,86.11 63.11,86 62.7,86 62.6,86.11 62.6,86.48 62.5,86.58 62.09,86.58 61.99,86.48 61.99,86.11 61.89,86 61.48,86 61.38,86.11 61.38,86.48 61.28,86.58 60.87,86.58 60.77,86.48 60.77,86.11 60.67,86 60.26,86 60.16,86.11 60.16,86.48 60.06,86.58 59.65,86.58 59.55,86.48 59.55,86.11 59.45,86 59.04,86 58.94,86.11 58.94,86.48 58.84,86.58 58.43,86.58 58.33,86.48 58.33,86.11 58.23,86 57.82,86 57.72,86.11 57.72,86.48 57.62,86.58 57.21,86.58 57.11,86.48 57.11,86.11 57.01,86 52.27,86 52,85.73 v2(52,85.36)
RP_DDR4_DIMM2_DQ25: length 43.2
  TOP w0.102: v3(69.83,82.46) 69.83,82.26 70.22,81.86 73.34,81.86 73.55,81.65 76.09,81.65 76.21,81.53 77.73,81.53 77.85,81.65 78.18,81.65 78.52,81.31 U9.CR24
  TOP w0.114: v2(48.62,87.06) 48,86.44 47.37,86.44 46.38,85.45 CONN8.71
  S3 w0.102: v3(69.83,82.46) 69.83,82.49 64.42,87.9 56.78,87.9 56.56,87.68 56.56,86.99 56.06,86.49 53.59,86.49 53.49,86.59 53.49,86.79 53.39,86.89 52.98,86.89 52.88,86.79 52.88,86.59 52.78,86.49 51.49,86.49 51.4,86.4 51.4,86.08 51.31,85.99 50.94,85.99 50.85,86.08 50.85,86.4 50.77,86.49 50.11,86.49 50.01,86.59 50.01,87.95 49.91,88.05 49.5,88.05 49.4,87.95 49.4,86.59 49.3,86.49 48.82,86.49 48.62,86.69 v2(48.62,87.06)
RP_DDR4_DIMM2_DQ26: length 43.1
  TOP w0.102: v3(75.31,79.12) 75.5,79.12 75.9,79.52 76.6,79.52 77,79.13 77.67,79.13 77.87,79.33 U9.CU28
  TOP w0.114: CONN8.83 46.44,82.45 v2(46.71,82.73)
  S3 w0.102: v2(46.71,82.73) 45.47,82.73 45.27,82.52 45.27,81.61 45.42,81.46 45.82,81.46 45.92,81.56 45.92,81.89 46.02,81.99 46.43,81.99 46.53,81.89 46.53,81.56 46.63,81.46 47.04,81.46 47.14,81.56 47.14,81.89 47.24,81.99 47.65,81.99 47.75,81.89 47.75,81.56 47.85,81.46 48.25,81.46 48.36,81.56 48.36,81.89 48.46,81.99 48.86,81.99 48.97,81.89 48.97,81.56 49.07,81.46 49.47,81.46 49.58,81.56 49.58,81.89 49.68,81.99 50.08,81.99 50.19,81.89 50.19,81.56 50.29,81.46 51.84,81.46 51.93,81.37 56.21,81.37 56.41,81.17 56.41,80.05 56.7,79.76 64.07,79.76 65.68,78.16 74.35,78.16 v3(75.31,79.12)
RP_DDR4_DIMM2_DQ27: length 43.1
  TOP w0.102: U9.CR28 78.52,79.33 78.19,79.66 77.91,79.66 77.58,79.33 77.08,79.33 76.69,79.72 75.82,79.72 75.71,79.62 73.46,79.62 v3(73.03,79.19)
  TOP w0.114: v2(52.01,82.71) 52.52,82.2 CONN8.84
  S3 w0.102: v2(52.01,82.71) 52.17,82.71 52.54,82.34 53.02,82.34 53.12,82.45 53.12,83.06 53.23,83.16 53.63,83.16 53.73,83.06 53.73,82.45 53.84,82.34 56.25,82.34 56.35,82.45 56.35,83.06 56.45,83.16 56.86,83.16 56.96,83.06 56.96,82.45 57.06,82.34 57.47,82.34 57.57,82.45 57.57,83.06 57.67,83.16 58.08,83.16 58.18,83.06 58.18,82.45 58.28,82.34 58.69,82.34 58.79,82.45 58.79,83.06 58.89,83.16 59.3,83.16 59.4,83.06 59.4,82.45 59.5,82.34 59.91,82.34 60.01,82.45 60.01,83.06 60.11,83.16 60.52,83.16 60.62,83.06 60.62,82.45 60.72,82.34 61.13,82.34 61.23,82.45 61.23,83.06 61.33,83.16 61.74,83.16 61.84,83.06 61.84,82.45 61.94,82.34 62.93,82.34 63.27,82 63.27,81.86 63.04,81.63 63.04,81.48 63.33,81.2 63.47,81.2 63.7,81.43 63.85,81.43 65.49,79.78 65.98,79.78 66.08,79.88 66.08,80.19 66.18,80.29 66.59,80.29 66.69,80.19 66.69,79.88 66.79,79.78 67.2,79.78 67.3,79.88 67.3,80.19 67.4,80.29 67.81,80.29 67.91,80.19 67.91,79.88 68.01,79.78 68.41,79.78 68.52,79.88 68.52,80.19 68.62,80.29 69.02,80.29 69.13,80.19 69.13,79.88 69.23,79.78 69.63,79.78 69.74,79.88 69.74,80.19 69.84,80.29 70.24,80.29 70.35,80.19 70.35,79.88 70.45,79.78 72.43,79.78 v3(73.03,79.19)
RP_DDR4_DIMM2_DQ28: length 43.1
  TOP w0.102: v3(73.64,82.45) 73.64,82.31 74.08,81.87 77.26,81.87 U9.CV23
  TOP w0.114: CONN8.66 52.02,86.7 51.81,86.92 v2(51.81,87.09)
  S3 w0.102: v3(73.64,82.45) 73.64,82.69 73.33,82.99 72.92,82.99 72.74,83.17 71.72,83.17 71.62,83.27 71.62,84.01 71.51,84.11 71.11,84.11 71.01,84.01 71.01,83.27 70.9,83.17 70.34,83.17 69.75,83.76 69.75,83.91 69.9,84.05 69.9,84.2 69.61,84.49 69.47,84.49 69.32,84.34 69.18,84.34 64.24,89.27 63.12,89.27 63.02,89.17 63.02,88.51 62.91,88.41 62.51,88.41 62.41,88.51 62.41,89.17 62.31,89.27 61.9,89.27 61.8,89.17 61.8,88.51 61.7,88.41 61.29,88.41 61.19,88.51 61.19,89.17 61.09,89.27 60.68,89.27 60.58,89.17 60.58,88.51 60.48,88.41 60.07,88.41 59.97,88.51 59.97,89.17 59.87,89.27 59.46,89.27 59.36,89.17 59.36,88.51 59.26,88.41 58.85,88.41 58.75,88.51 58.75,89.17 58.65,89.27 58.24,89.27 58.14,89.17 58.14,88.51 58.04,88.41 57.63,88.41 57.53,88.51 57.53,89.17 57.43,89.27 57.02,89.27 56.92,89.17 56.92,88.51 56.82,88.41 56.41,88.41 56.31,88.51 56.31,89.17 56.21,89.27 53.42,89.27 51.81,87.66 v2(51.81,87.09)
RP_DDR4_DIMM2_DQ29: length 42.9
  TOP w0.089: 76.95,82.07 74.8,82.07 v3(74.42,82.45)
  TOP w0.102: 76.95,82.07 77.09,82.21 77.61,82.21 77.89,81.92 78.43,81.92 U9.CT23
  TOP w0.114: CONN8.67 46.32,86.45 v2(46.77,86.9)
  S3 w0.102: v2(46.77,86.9) 45.68,86.9 45.37,87.21 45.37,89.83 45.57,90.03 64.34,90.03 69.19,85.18 71.42,85.18 73.12,83.48 73.72,83.48 74.42,82.78 v3(74.42,82.45)
RP_DDR4_DIMM2_DQ30: length 42.9
  TOP w0.102: U9.CV27 77.01,80.13 75.65,80.13 75.54,80.02 72.8,80.02 v3(72.29,80.53)
  TOP w0.114: v2(47.27,85.29) 47.27,84.74 45.99,83.45 CONN8.79
  S3 w0.102: v2(47.27,85.29) 45.67,85.29 45.38,85 45.38,83.85 45.59,83.64 45.92,83.64 46.02,83.74 46.02,84.28 46.12,84.38 46.53,84.38 46.63,84.28 46.63,83.74 46.73,83.64 47.14,83.64 47.24,83.74 47.24,84.28 47.34,84.38 47.75,84.38 47.85,84.28 47.85,83.74 47.95,83.64 63,83.64 65.82,80.82 70.59,80.82 71.3,80.11 71.87,80.11 v3(72.29,80.53)
RP_DDR4_DIMM2_DQ31: length 43.3
  TOP w0.102: v3(71.37,79.21) 71.98,79.82 75.63,79.82 75.74,79.93 76.77,79.93 77.16,79.54 77.46,79.54 77.79,79.87 78.27,79.87 78.31,79.83 U9.CT27
  TOP w0.114: CONN8.80 52.58,83.2 52.32,83.46 50.56,83.46 50.39,83.29 v2(50.39,82.73)
  S3 w0.102: v2(50.39,82.73) 50.99,82.12 51.92,82.12 52.18,81.86 56.5,81.86 56.92,81.45 56.92,80.49 57.12,80.28 57.61,80.28 57.71,80.39 57.71,81.4 57.81,81.51 58.22,81.51 58.32,81.4 58.32,80.39 58.42,80.28 58.83,80.28 58.93,80.39 58.93,81.4 59.03,81.51 59.44,81.51 59.54,81.4 59.54,80.39 59.64,80.28 60.05,80.28 60.15,80.39 60.15,81.4 60.25,81.51 60.66,81.51 60.76,81.4 60.76,80.39 60.86,80.28 61.26,80.28 61.37,80.39 61.37,81.18 61.47,81.28 61.87,81.28 61.98,81.18 61.98,80.39 62.08,80.28 64.27,80.28 65.33,79.22 69.37,79.22 69.88,78.71 70.87,78.71 v3(71.37,79.21)
RP_DDR4_DIMM2_DQ32: length 43.5
  TOP w0.102: v3(74.8,59.68) 75.21,60.09 75.93,60.09 76.88,59.14 77.56,59.14 77.96,58.75 U9.CT73
  TOP w0.114: CONN8.174 52.56,57.7 52.04,57.18 50.84,57.18 v2(50.09,57.94)
  S5 w0.102: v2(50.09,57.94) 50.97,57.05 53.48,57.05 54.54,55.99 73.13,55.99 73.48,56.34 73.48,57.12 73.89,57.53 75.69,57.53 76.43,56.79 77.06,56.79 77.48,57.21 77.48,59.58 76.96,60.1 75.22,60.1 v3(74.8,59.68)
RP_DDR4_DIMM2_DQ33: length 43.5
  TOP w0.102: v3(72.52,59.68) 73.12,59.08 75.62,59.08 76.38,58.32 77.66,58.32 U9.CU74
  TOP w0.114: v2(48.46,57.94) 48.45,57.95 CONN8.173
  S5 w0.102: v2(48.46,57.94) 47.9,57.94 47.78,58.06 47.78,58.45 47.91,58.58 51.91,58.58 52.2,58.29 53.94,58.29 55.04,57.18 55.54,57.18 55.64,57.29 55.64,57.35 55.75,57.45 56.15,57.45 56.25,57.35 56.25,57.29 56.35,57.18 56.76,57.18 56.86,57.29 56.86,57.35 56.96,57.45 57.37,57.45 57.47,57.35 57.47,57.29 57.57,57.18 57.98,57.18 58.08,57.29 58.08,57.35 58.18,57.45 58.59,57.45 58.69,57.35 58.69,57.29 58.79,57.18 59.2,57.18 59.3,57.29 59.3,57.35 59.4,57.45 59.81,57.45 59.91,57.35 59.91,57.29 60.01,57.18 60.42,57.18 60.52,57.29 60.52,57.35 60.62,57.45 61.03,57.45 61.13,57.35 61.13,57.29 61.23,57.18 61.64,57.18 61.74,57.29 61.74,57.35 61.84,57.45 62.25,57.45 62.35,57.35 62.35,57.29 62.45,57.18 62.86,57.18 62.96,57.29 62.96,57.35 63.06,57.45 63.47,57.45 63.57,57.35 63.57,57.29 63.67,57.18 64.08,57.18 64.18,57.29 64.18,57.35 64.28,57.45 64.69,57.45 64.79,57.35 64.79,57.29 64.89,57.18 65.3,57.18 65.4,57.29 65.4,57.35 65.5,57.45 65.91,57.45 66.01,57.35 66.01,57.29 66.11,57.18 66.51,57.18 66.62,57.29 66.62,57.35 66.72,57.45 67.12,57.45 67.23,57.35 67.23,57.29 67.33,57.18 67.73,57.18 67.84,57.29 67.84,57.35 67.94,57.45 68.34,57.45 68.45,57.35 68.45,57.29 68.55,57.18 69.34,57.18 69.44,57.29 69.44,58.52 69.55,58.62 70.03,58.62 70.13,58.52 70.13,57.4 70.23,57.3 70.64,57.3 70.74,57.4 70.74,58.5 71.93,59.68 v3(72.52,59.68)
RP_DDR4_DIMM2_DQ34: length 43.4
  TOP w0.102: U9.CJ78 81.52,55.45 81.07,55 81.06,55 78.78,52.72 75.96,52.72 v3(74.45,51.21)
  TOP w0.114: v2(49.05,55.04) 48.46,54.45 46.8,54.45 46.8,54.45 CONN8.187
  S5 w0.102: v3(74.45,51.21) 74.1,50.86 69.79,50.86 68.6,52.05 52.04,52.05 51.94,52.15 51.94,52.73 51.83,52.83 51.43,52.83 51.33,52.73 51.33,52.15 51.22,52.05 50.74,52.05 50.57,52.22 50.57,52.43 50.2,52.8 49.23,52.8 48.82,53.21 48.82,54.81 v2(49.05,55.04)
RP_DDR4_DIMM2_DQ35: length 43.5
  TOP w0.102: U9.CJ76 81.52,56.59 81.8,56.31 81.8,55.44 81.15,54.79 81.15,54.79 78.69,52.34 76.45,52.34 v3(75.31,51.19)
  TOP w0.114: v2(51.52,55.04) 51.59,54.96 52.3,54.96 52.57,54.7 CONN8.186
  S5 w0.102: v2(51.52,55.04) 51.52,54.97 53.36,53.12 69.09,53.12 69.47,52.74 69.95,52.74 70.05,52.84 70.05,53.01 70.15,53.11 70.56,53.11 70.66,53.01 70.66,52.84 70.76,52.74 71.17,52.74 71.27,52.84 71.27,53.01 71.37,53.11 71.78,53.11 71.88,53.01 71.88,52.84 71.98,52.74 73.32,52.74 73.57,52.49 74.66,52.49 74.76,52.39 74.76,52.16 74.86,52.06 75.27,52.06 75.58,52.37 77.4,52.37 77.53,52.24 77.53,51.96 77.4,51.83 75.79,51.83 75.31,51.35 v3(75.31,51.19)
RP_DDR4_DIMM2_DQ36: length 43.5
  TOP w0.102: U9.CU71 76.96,59.35 76.02,60.29 74.65,60.29 v3(74.04,59.68)
  TOP w0.114: v2(51.71,57.94) 51.71,58.16 52.25,58.7 CONN8.170
  S5 w0.102: v2(51.71,57.94) 51.96,57.69 53.69,57.69 54.89,56.49 55.37,56.49 55.52,56.64 55.98,56.64 56.13,56.49 56.59,56.49 56.74,56.64 57.2,56.64 57.35,56.49 57.81,56.49 57.96,56.64 58.42,56.64 58.57,56.49 71.32,56.49 71.42,56.59 71.42,58.29 71.98,58.85 72.95,58.85 73.15,58.65 73.15,58.34 72.95,58.14 72.21,58.14 72.03,57.96 72.03,56.59 72.13,56.49 72.8,56.49 73,56.69 73,57.43 73.58,58.01 76.5,58.01 76.68,58.19 76.68,58.6 76.48,58.8 74.92,58.8 v3(74.04,59.68)
RP_DDR4_DIMM2_DQ37: length 43.2
  TOP w0.102: U9.CR71 78.34,59.53 78.22,59.65 77.89,59.65 77.85,59.61 77.09,59.61 76.21,60.5 74.4,60.5 74.01,60.11 72.03,60.11 71.61,59.68 v3(71.04,59.68)
  TOP w0.114: CONN8.169 46.37,58.95 v2(46.61,58.71)
  S5 w0.102: v2(46.61,58.71) 46.4,58.92 45,58.92 44.72,58.64 44.72,57.82 44.91,57.63 45.39,57.63 45.49,57.73 45.49,58.06 45.59,58.17 46,58.17 46.1,58.06 46.1,57.73 46.2,57.63 46.94,57.63 47.26,57.95 47.26,58.83 47.55,59.13 52.21,59.13 52.45,58.88 54.18,58.88 55.13,57.94 68.53,57.94 68.83,58.24 68.83,58.9 69.07,59.14 70.5,59.14 v3(71.04,59.68)
RP_DDR4_DIMM2_DQ38: length 43.6
  TOP w0.102: v2(77.52,53.61) 79.1,53.61 80.02,54.53 81.03,55.54 81.03,56.16 80.84,56.35 U9.CL77
  TOP w0.114: v2(47.21,55.04) 46.94,55.04 46.53,55.45 CONN8.183
  S5 w0.102: v2(47.21,55.04) 47.21,55.72 47.42,55.93 48.1,55.93 48.39,55.64 51.76,55.64 53.77,53.63 54.61,53.63 54.71,53.74 54.71,53.92 54.81,54.03 55.22,54.03 55.32,53.92 55.32,53.74 55.42,53.63 55.83,53.63 55.93,53.74 55.93,53.92 56.03,54.03 56.44,54.03 56.54,53.92 56.54,53.74 56.64,53.63 57.05,53.63 57.15,53.74 57.15,53.92 57.25,54.03 57.66,54.03 57.76,53.92 57.76,53.74 57.86,53.63 58.27,53.63 58.37,53.74 58.37,53.92 58.47,54.03 58.88,54.03 58.98,53.92 58.98,53.74 59.08,53.63 73.21,53.63 73.76,53.09 77.98,53.09 78.09,53.2 78.09,53.48 77.96,53.61 v2(77.52,53.61)
RP_DDR4_DIMM2_DQ39: length 43.5
  TOP w0.102: U9.CK75 81.02,56.81 81.24,56.59 81.24,55.45 80.98,55.2 80.98,55.2 78.95,53.18 74.06,53.18 73.65,52.77 v2(73.65,51.45)
  TOP w0.114: v2(50.02,55.04) 50.86,55.88 52.29,55.88 52.47,55.7 CONN8.182
  S5 w0.102: v2(73.65,51.45) 73.65,51.57 72.97,52.25 69.12,52.25 68.82,52.54 53.25,52.54 51.92,53.88 51.12,53.88 51.02,53.98 51.02,54.43 50.92,54.53 50.52,54.53 50.41,54.43 50.41,53.98 50.31,53.88 49.83,53.88 49.58,54.13 49.58,54.76 49.86,55.04 v2(50.02,55.04)
RP_DDR4_DIMM2_DQ40: length 47
  TOP w0.102: v3(79.33,52.22) 80.38,52.22 82.76,54.6 82.76,55.01 83.22,55.46 83.22,56.35 U9.CF77
  TOP w0.114: v2(48.24,53.38) 47.59,52.73 47.27,52.73 46.99,52.45 CONN8.195
  S8 w0.102: v3(79.33,52.22) 79.33,52.62 79.25,52.71 77.99,52.71 77.86,52.84 77.86,53.13 77.99,53.26 79.25,53.26 79.33,53.35 79.33,53.52 78.67,54.18 74.09,54.18 73.5,53.59 55.91,53.59 55.09,52.77 48.14,52.77 47.94,52.97 47.94,53.08 v2(48.24,53.38)
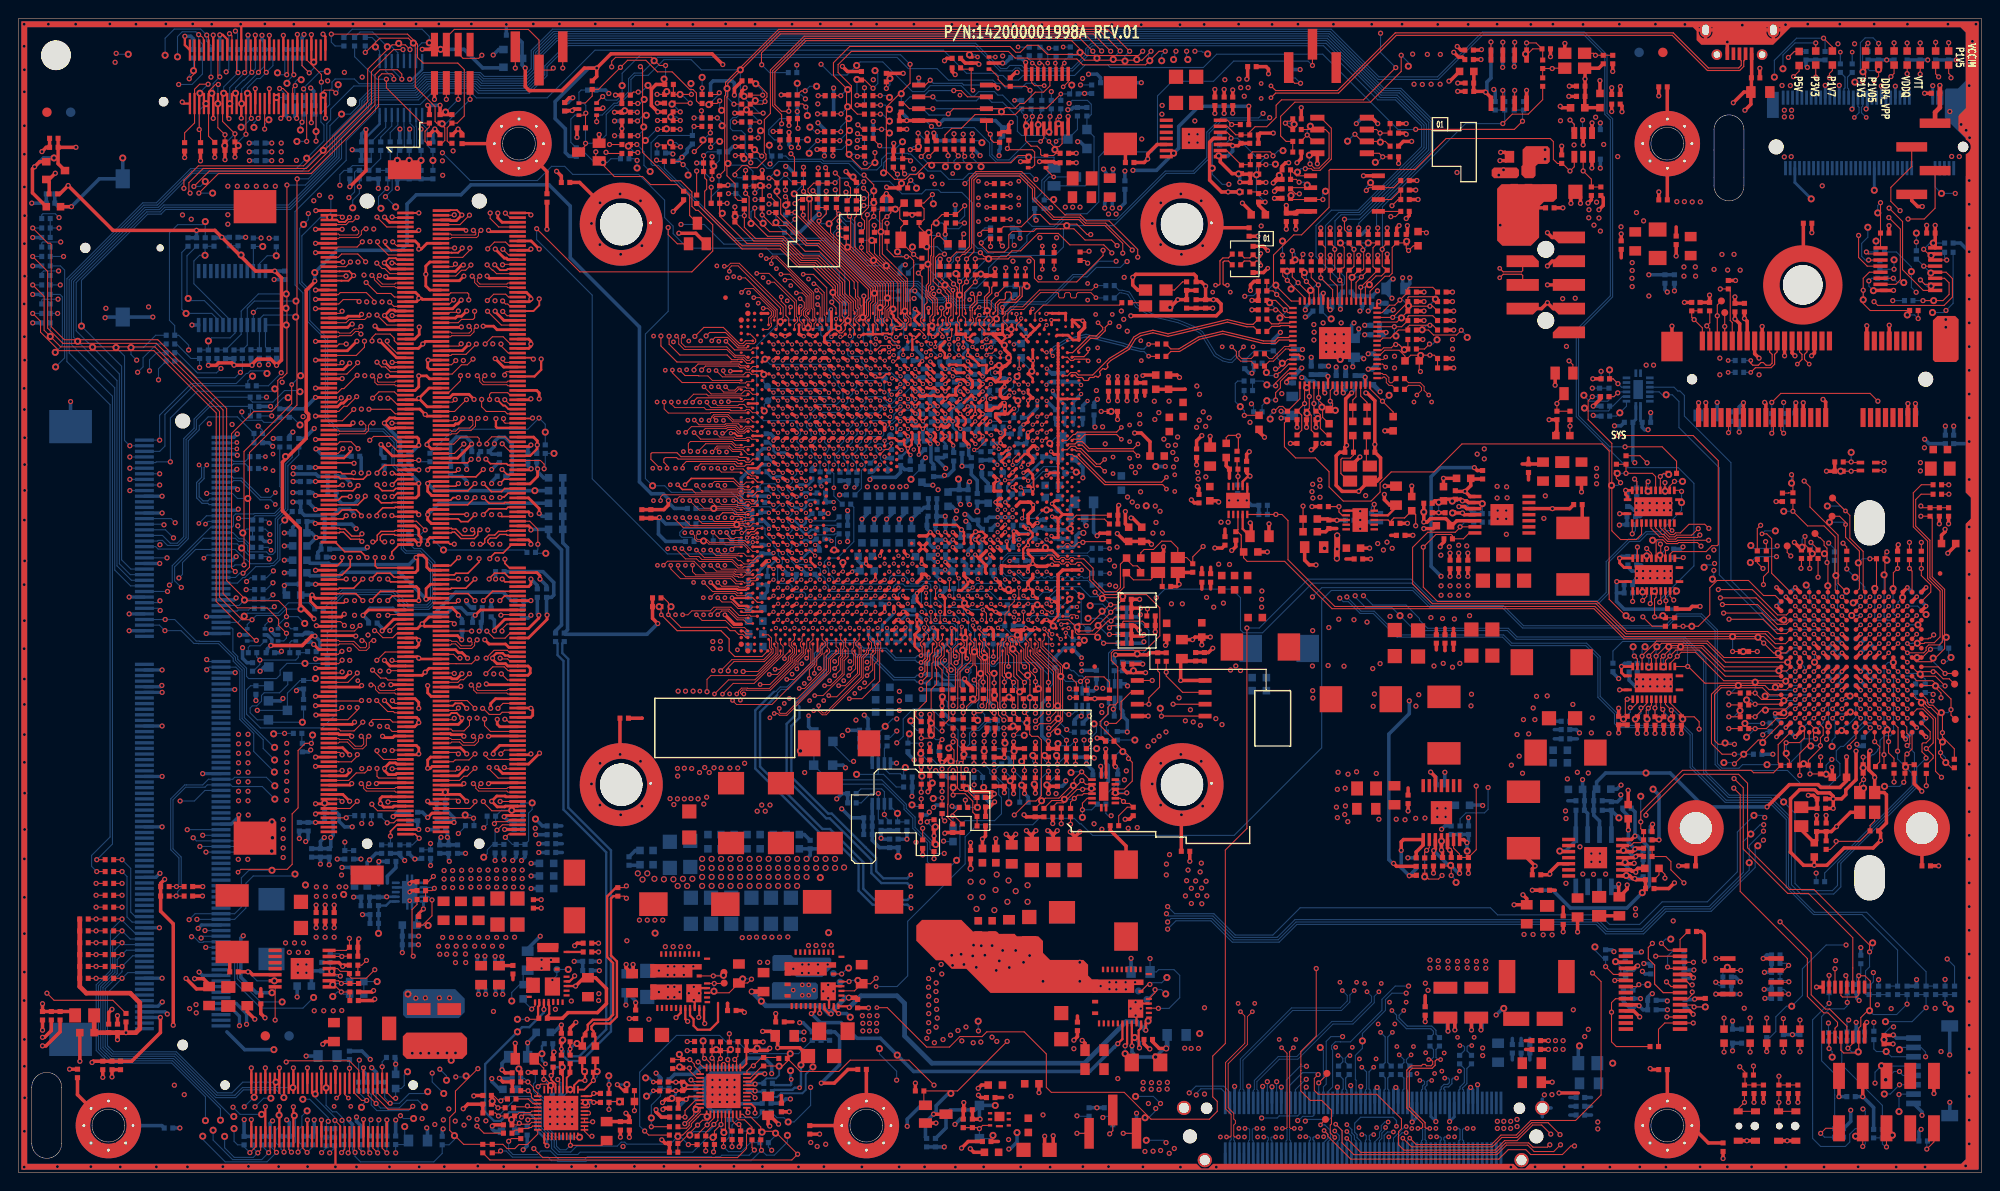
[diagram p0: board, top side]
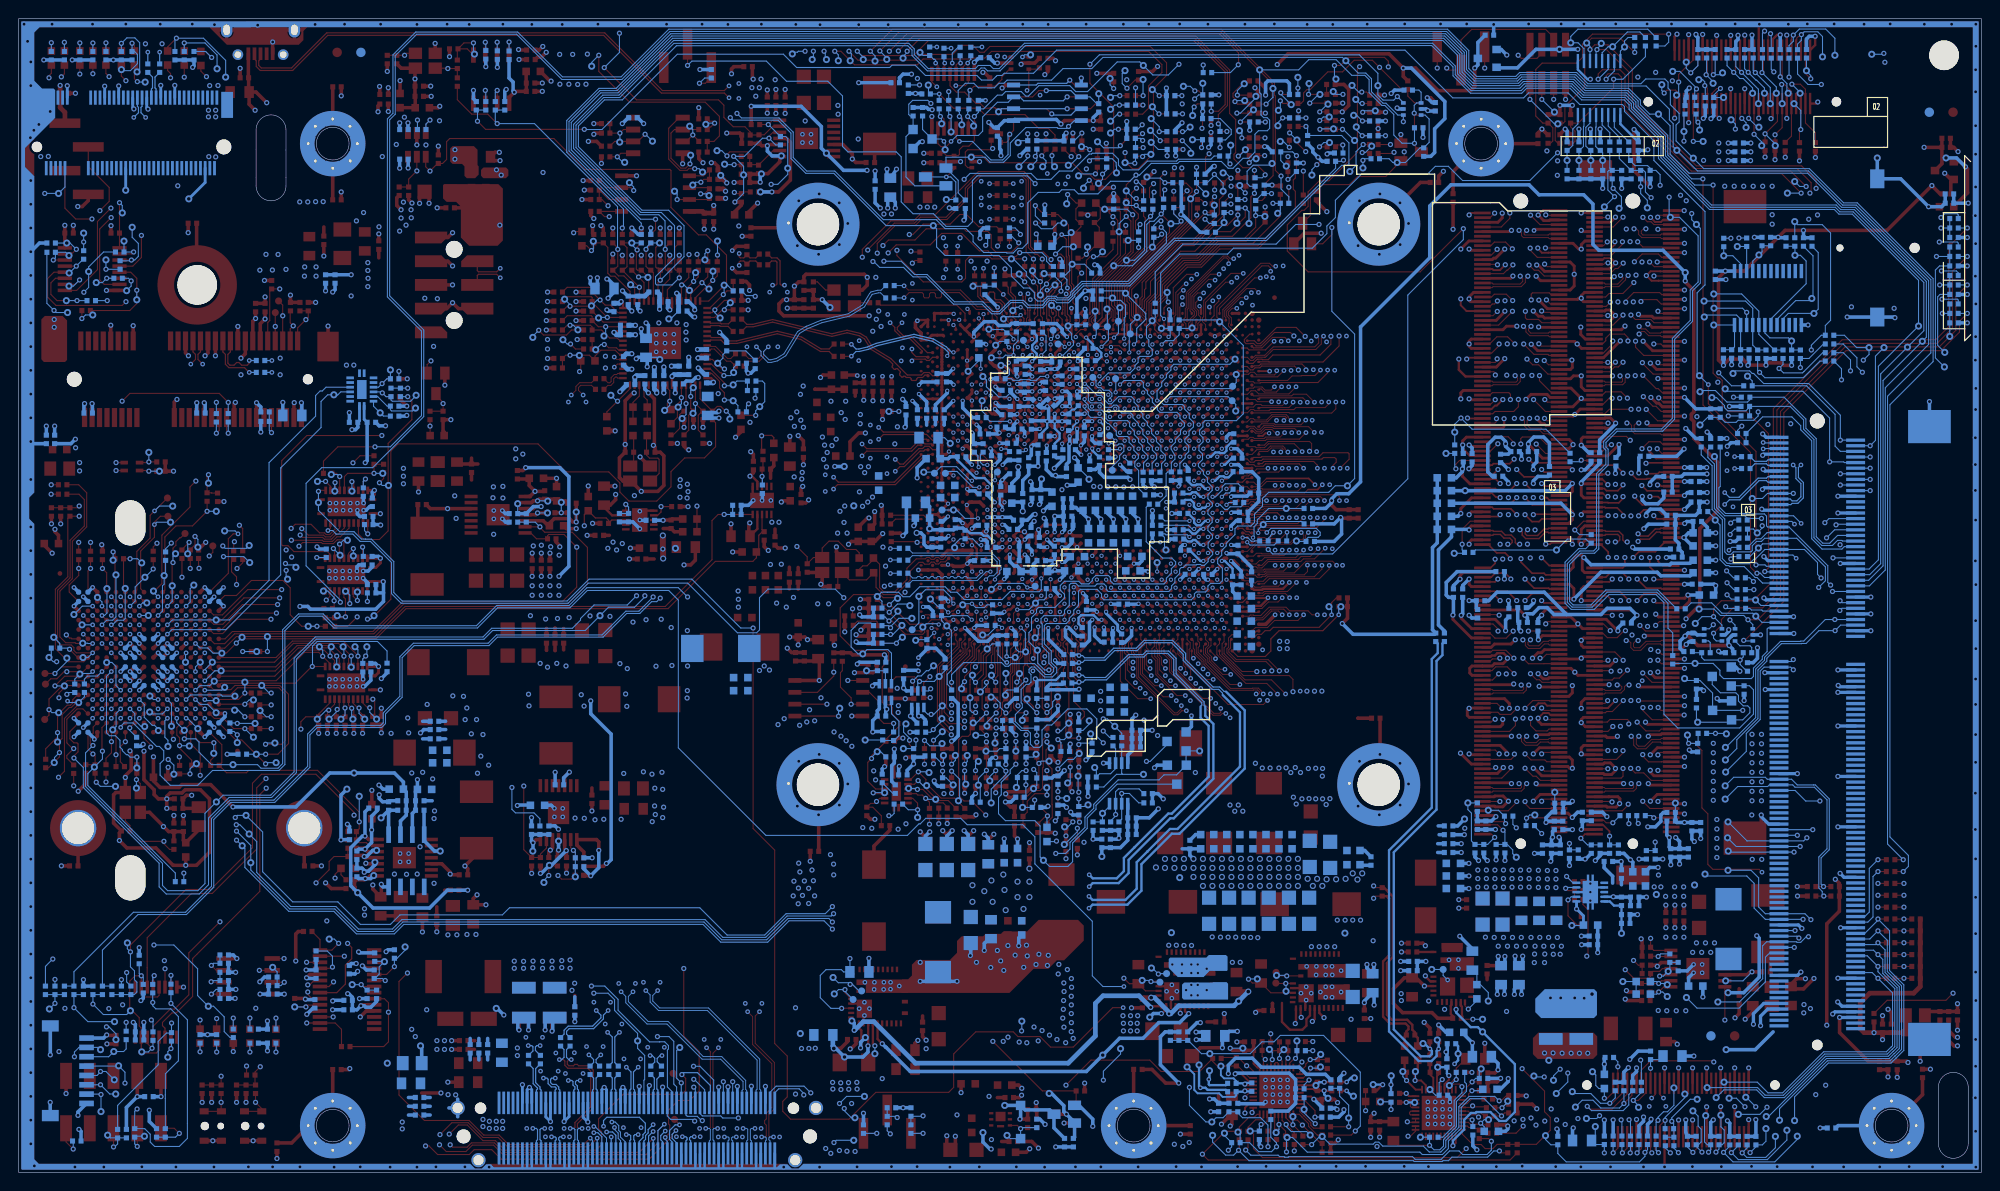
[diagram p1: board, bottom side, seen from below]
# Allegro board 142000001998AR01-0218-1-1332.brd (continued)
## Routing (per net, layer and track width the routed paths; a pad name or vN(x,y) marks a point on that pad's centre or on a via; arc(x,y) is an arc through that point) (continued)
RP_DDR4_DIMM2_DQ41: length 47.3
  TOP w0.102: v3(80.31,53.3) 81.17,53.3 82.56,54.69 82.56,55.1 83.01,55.56 83.01,56.08 82.67,56.42 82.67,56.7 83,57.03 U9.CF75
  TOP w0.114: CONN8.194 52.3,52.7 v2(51.64,53.36)
  S8 w0.102: v2(51.64,53.36) 54.84,53.36 55.66,54.19 63.33,54.19 63.42,54.28 63.42,54.71 63.51,54.8 63.88,54.8 63.97,54.71 63.97,54.28 64.06,54.19 64.43,54.19 64.52,54.28 64.52,54.71 64.6,54.8 64.97,54.8 65.06,54.71 65.06,54.28 65.15,54.19 65.52,54.19 65.61,54.28 65.61,54.71 65.7,54.8 66.07,54.8 66.15,54.71 66.15,54.28 66.24,54.19 66.61,54.19 66.7,54.28 66.7,54.71 66.79,54.8 67.16,54.8 67.25,54.71 67.25,54.28 67.34,54.19 67.7,54.19 67.79,54.28 67.79,54.71 67.88,54.8 68.25,54.8 68.34,54.71 68.34,54.28 68.43,54.19 68.8,54.19 68.88,54.28 68.88,54.71 68.97,54.8 69.34,54.8 69.43,54.71 69.43,54.28 69.52,54.19 69.89,54.19 69.98,54.28 69.98,54.71 70.07,54.8 70.43,54.8 70.52,54.71 70.52,54.28 70.61,54.19 70.98,54.19 71.07,54.28 71.07,54.71 71.16,54.8 71.53,54.8 71.62,54.71 71.62,54.28 71.7,54.19 72.07,54.19 72.16,54.28 72.16,54.71 72.25,54.8 72.62,54.8 72.71,54.71 72.71,54.28 72.8,54.19 73.33,54.19 73.94,54.8 78.9,54.8 80.31,53.39 v3(80.31,53.3)
RP_DDR4_DIMM2_DQ42: length 47.3
  TOP w0.102: U9.CB77 84.98,54.47 80.59,50.08 76.82,50.08 v3(76.38,50.52)
  TOP w0.114: v2(47.05,49.7) 46.8,49.45 CONN8.207
  S8 w0.102: v3(76.38,50.52) 70.46,50.52 69.36,51.62 56.74,51.62 55.86,50.74 46.43,50.74 46.2,50.51 46.2,49.88 46.38,49.7 v2(47.05,49.7)
RP_DDR4_DIMM2_DQ43: length 47.2
  TOP w0.102: U9.CB75 84.98,57.03 84.65,56.7 84.65,56.1 84.77,55.98 84.77,54.54 82.99,52.77 v3(82.19,52.77)
  TOP w0.114: CONN8.208 52.47,49.2 52.43,49.25 51.73,49.25 51.5,49.02 50.34,49.02 49.7,49.67 v2(49.64,49.67)
  S8 w0.102: v3(82.19,52.77) 80.89,52.77 78.04,49.92 70.24,49.92 69.19,50.98 68.78,50.98 68.67,50.87 68.67,50.62 68.57,50.52 68.17,50.52 68.06,50.62 68.06,50.87 67.96,50.98 67.56,50.98 67.45,50.87 67.45,50.62 67.35,50.52 66.95,50.52 66.84,50.62 66.84,50.87 66.74,50.98 66.09,50.98 65.98,50.87 65.98,50.77 65.88,50.67 65.48,50.67 65.37,50.77 65.37,50.87 65.27,50.98 56.94,50.98 56.21,50.25 50.05,50.25 49.64,49.84 v2(49.64,49.67)
RP_DDR4_DIMM2_DQ44: length 47
  TOP w0.102: U9.CG78 81.94,55.26 v3(81.94,54.98)
  TOP w0.114: CONN8.191 46.56,53.45 v2(46.61,53.41)
  S8 w0.102: v2(46.61,53.41) 46.61,53.46 47.64,54.5 52.17,54.5 52.27,54.6 52.27,55.17 52.38,55.27 52.78,55.27 52.88,55.17 52.88,54.6 52.99,54.5 54.29,54.5 55.11,55.32 56.14,55.32 57.18,56.36 62.76,56.36 62.87,56.26 62.87,56.03 62.97,55.93 63.37,55.93 63.47,56.03 63.47,56.26 63.58,56.36 63.98,56.36 64.08,56.26 64.08,56.03 64.19,55.93 64.59,55.93 64.69,56.03 64.69,56.26 64.8,56.36 65.2,56.36 65.3,56.26 65.3,56.03 65.41,55.93 65.81,55.93 65.91,56.03 65.91,56.26 66.01,56.36 66.42,56.36 66.52,56.26 66.52,56.03 66.62,55.93 67.03,55.93 67.13,56.03 67.13,56.26 67.23,56.36 67.64,56.36 67.74,56.26 67.74,56.03 67.84,55.93 68.25,55.93 68.35,56.03 68.35,56.26 68.45,56.36 68.86,56.36 68.96,56.26 68.96,56.03 69.06,55.93 69.47,55.93 69.57,56.03 69.57,56.26 69.67,56.36 70.08,56.36 70.18,56.26 70.18,56.03 70.28,55.93 70.69,55.93 70.79,56.03 70.79,56.26 70.89,56.36 71.3,56.36 71.4,56.26 71.4,56.03 71.5,55.93 71.91,55.93 72.01,56.03 72.01,56.26 72.11,56.36 72.59,56.36 73.86,57.63 77.79,57.63 79.17,56.25 80.68,56.25 v3(81.94,54.98)
RP_DDR4_DIMM2_DQ45: length 47.3
  TOP w0.102: U9.CG76 82.42,56.97 82.42,56.38 82.81,56 82.81,55.65 82.35,55.19 82.35,54.77 81.43,53.85 v3(80.93,53.85)
  TOP w0.114: v2(49.99,53.38) 50.72,54.11 51.95,54.11 52.36,53.7 CONN8.190
  S8 w0.102: v2(49.99,53.38) 50.6,53.99 54.62,53.99 55.42,54.78 57.03,54.78 57.11,54.87 57.11,55.45 57.2,55.54 57.57,55.54 57.66,55.45 57.66,54.87 57.75,54.78 58.12,54.78 58.21,54.87 58.21,55.45 58.3,55.54 58.66,55.54 58.75,55.45 58.75,54.87 58.84,54.78 59.21,54.78 59.3,54.87 59.3,55.45 59.39,55.54 59.76,55.54 59.84,55.45 59.84,54.87 59.93,54.78 60.3,54.78 60.39,54.87 60.39,55.45 60.48,55.54 60.85,55.54 60.94,55.45 60.94,54.87 61.03,54.78 61.39,54.78 61.48,54.87 61.48,55.45 61.57,55.54 61.94,55.54 62.03,55.45 62.03,54.87 62.12,54.78 62.65,54.78 63.27,55.4 79.38,55.4 v3(80.93,53.85)
RP_DDR4_DIMM2_DQ46: length 47.2
  TOP w0.102: v3(84.31,55.03) 84.49,55.21 U9.CC78
  TOP w0.114: v2(48.82,49.67) 48,50.5 46.22,50.5 46.18,50.45 CONN8.203
  S8 w0.102: v2(48.82,49.67) 48.82,49.63 49.39,49.07 53.17,49.07 53.61,48.62 56.16,48.62 57.07,49.53 68.53,49.53 69.33,48.73 79.74,48.73 85.27,54.25 85.27,55.3 84.99,55.58 84.63,55.58 84.31,55.25 v3(84.31,55.03)
RP_DDR4_DIMM2_DQ47: length 47.3
  TOP w0.102: U9.CC76 84.32,56.89 84.32,56.1 84.21,55.98 84.21,55.51 83.39,54.69 83.39,54 v3(83.27,53.89)
  TOP w0.114: v2(51.29,49.67) 51.82,50.2 CONN8.204
  S8 w0.102: v2(51.29,49.67) 51.3,49.68 53.97,49.68 54.53,49.12 55.86,49.12 56.78,50.04 57.77,50.04 57.87,50.14 57.87,50.34 57.97,50.44 58.38,50.44 58.48,50.34 58.48,50.14 58.58,50.04 58.98,50.04 59.09,50.14 59.09,50.34 59.19,50.44 59.59,50.44 59.7,50.34 59.7,50.14 59.8,50.04 60.2,50.04 60.31,50.14 60.31,50.34 60.41,50.44 60.81,50.44 60.92,50.34 60.92,50.14 61.02,50.04 68.87,50.04 69.58,49.33 79.59,49.33 79.88,49.62 79.88,49.74 79.43,50.19 79.43,50.35 79.64,50.55 79.84,50.55 80.27,50.13 80.39,50.13 80.65,50.39 80.65,50.51 80.22,50.95 80.22,51.07 80.48,51.33 80.6,51.33 81.04,50.9 81.16,50.9 81.42,51.16 81.42,51.29 80.99,51.72 80.99,51.85 81.25,52.11 81.38,52.11 81.81,51.67 81.94,51.67 83.39,53.12 83.39,53.77 v3(83.27,53.89)
RP_DDR4_DIMM2_DQ48: length 60.9
  TOP w0.102: U9.BW78 86.17,55.53 86.17,53.87 84.09,51.8 v3(83.52,51.8)
  TOP w0.114: v2(49.85,48.52) 49.85,47.83 50.48,47.2 CONN8.216
  S3 w0.102: v2(49.85,48.52) 50.65,47.73 56.25,47.73 56.35,47.83 56.35,47.88 56.45,47.98 56.86,47.98 56.96,47.88 56.96,47.83 57.06,47.73 57.95,47.73 58.05,47.83 58.05,48.21 58.15,48.31 58.56,48.31 58.66,48.21 58.66,47.83 58.76,47.73 59.17,47.73 59.27,47.83 59.27,48.21 59.37,48.31 59.78,48.31 59.88,48.21 59.88,47.83 59.98,47.73 60.39,47.73 60.49,47.83 60.49,48.21 60.59,48.31 61,48.31 61.1,48.21 61.1,47.83 61.2,47.73 61.6,47.73 61.71,47.83 61.71,48.21 61.81,48.31 62.21,48.31 62.32,48.21 62.32,47.83 62.42,47.73 62.82,47.73 62.93,47.83 62.93,48.21 63.03,48.31 63.43,48.31 63.54,48.21 63.54,47.83 63.64,47.73 64.04,47.73 64.14,47.83 64.14,48.21 64.25,48.31 64.65,48.31 64.75,48.21 64.75,47.83 64.86,47.73 65.26,47.73 65.36,47.83 65.36,48.21 65.47,48.31 65.87,48.31 65.97,48.21 65.97,47.83 66.08,47.73 66.48,47.73 66.58,47.83 66.58,48.21 66.68,48.31 67.09,48.31 67.19,48.21 67.19,47.83 67.29,47.73 67.7,47.73 67.8,47.83 67.8,48.21 67.9,48.31 68.31,48.31 68.41,48.21 68.41,47.83 68.51,47.73 68.92,47.73 69.02,47.83 69.02,48.21 69.12,48.31 69.53,48.31 69.63,48.21 69.63,47.83 69.73,47.73 70.14,47.73 70.24,47.83 70.24,48.21 70.34,48.31 70.75,48.31 70.85,48.21 70.85,47.83 70.95,47.73 71.36,47.73 71.46,47.83 71.46,48.21 71.56,48.31 71.97,48.31 72.07,48.21 72.07,47.83 72.17,47.73 72.58,47.73 72.68,47.83 72.68,48.21 72.78,48.31 73.19,48.31 73.29,48.21 73.29,47.83 73.39,47.73 73.8,47.73 73.9,47.83 73.9,48.21 74,48.31 74.41,48.31 74.51,48.21 74.51,47.83 74.61,47.73 75.02,47.73 75.12,47.83 75.12,48.21 75.22,48.31 75.63,48.31 75.73,48.21 75.73,47.83 75.83,47.73 76.24,47.73 76.34,47.83 76.34,48.21 76.44,48.31 76.84,48.31 76.95,48.21 76.95,47.83 77.05,47.73 77.68,47.73 81.29,51.34 83.05,51.34 v3(83.52,51.8)
RP_DDR4_DIMM2_DQ49: length 61.1
  TOP w0.102: U9.BW76 86.52,57 86.52,56.21 86.75,55.98 86.75,55.66 86.41,55.32 86.41,53.83 83.32,50.74 v3(82.46,50.74)
  TOP w0.114: v2(48.23,48.6) 48.23,47.84 47.65,47.25 46.45,47.25 46.25,47.45 CONN8.215
  S3 w0.102: v3(82.46,50.74) 81.54,50.74 78.05,47.24 50.3,47.24 50.2,47.35 47.6,47.35 45.16,44.91 43.76,44.91 43.51,45.16 43.51,46.13 43.74,46.35 45.72,46.35 47.47,48.11 47.74,48.11 v2(48.23,48.6)
RP_DDR4_DIMM2_DQ50: length 61
  TOP w0.102: U9.BP78 88.45,55.24 88.12,54.91 88.12,53.38 86.84,52.09 v3(86.23,52.09)
  TOP w0.114: CONN8.228 50.33,44.2 49.96,44.57 v2(49.96,44.77)
  S3 w0.102: v3(86.23,52.09) 86.24,52.09 87.15,51.19 87.15,50.8 72.18,35.84 60.63,35.84 55.19,41.27 54.13,41.27 54.03,41.38 54.03,41.83 53.92,41.94 53.52,41.94 53.42,41.83 53.42,41.38 53.31,41.27 52.83,41.27 52.53,41.58 52.53,43.61 52.26,43.88 49.75,43.88 49.5,44.12 49.5,44.64 49.64,44.77 v2(49.96,44.77)
RP_DDR4_DIMM2_DQ51: length 61.1
  TOP w0.102: v3(85.17,51.03) 86.06,51.03 88.32,53.29 88.32,54.78 88.75,55.21 88.75,56.04 88.48,56.31 88.48,56.81 88.45,56.85 U9.BP76
  TOP w0.114: v2(48.82,44.79) 48.18,44.15 46.7,44.15 46.5,43.95 CONN8.229
  S3 w0.102: v2(48.82,44.79) 49.42,45.39 52.86,45.39 53.98,44.27 57.18,44.27 59.11,42.34 59.11,40.06 62.33,36.83 66.7,36.83 69.11,39.24 69.11,40.23 69.95,41.07 76.05,41.07 83.16,48.18 83.16,48.97 84.01,49.82 84.01,50.66 84.48,51.13 85.07,51.13 v3(85.17,51.03)
RP_DDR4_DIMM2_DQ52: length 61
  TOP w0.102: v3(84.6,52.88) 84.6,53.8 85.19,54.38 85.19,54.99 85.76,55.57 85.76,56.35 U9.BY77
  TOP w0.114: v2(46.61,48.6) 46.46,48.45 CONN8.211
  S3 w0.102: v2(46.61,48.6) 46.61,47.95 45.52,46.86 44.81,46.86 44.7,46.96 44.7,47.29 44.6,47.4 44.2,47.4 44.09,47.29 44.09,46.96 43.99,46.86 43.51,46.86 43.31,47.07 43.31,48.03 43.51,48.23 45.26,48.23 46.22,49.19 55.41,49.19 56.06,49.83 65.53,49.83 68.73,53.04 79.07,53.04 79.34,52.76 81.03,52.76 83.73,55.46 84.77,55.46 86.1,54.13 86.1,53.6 85.36,52.86 84.91,52.86 84.89,52.88 v3(84.6,52.88)
RP_DDR4_DIMM2_DQ53: length 61
  TOP w0.102: U9.BY75 85.97,57.05 86.31,56.71 86.31,56.41 85.97,56.06 85.97,55.48 85.39,54.91 85.39,54.3 85.13,54.05 v3(85.13,53.42)
  TOP w0.114: CONN8.212 52.44,48.2 52.14,48.5 v2(52.02,48.5)
  S3 w0.102: v2(52.02,48.5) 52.02,48.5 57.6,48.5 57.91,48.82 66.65,48.82 66.75,48.92 66.75,49.02 66.85,49.12 67.26,49.12 67.36,49.02 67.36,48.92 67.46,48.82 67.95,48.82 68.05,48.92 68.05,50.06 68.15,50.16 68.56,50.16 68.66,50.06 68.66,48.92 68.76,48.82 69.17,48.82 69.27,48.92 69.27,50.06 69.37,50.16 69.78,50.16 69.88,50.06 69.88,48.92 69.98,48.82 70.39,48.82 70.49,48.92 70.49,50.06 70.59,50.16 71,50.16 71.1,50.06 71.1,48.92 71.2,48.82 71.61,48.82 71.71,48.92 71.71,50.06 71.81,50.16 72.22,50.16 72.32,50.06 72.32,48.92 72.42,48.82 72.83,48.82 72.93,48.92 72.93,50.06 73.03,50.16 73.44,50.16 73.54,50.06 73.54,48.92 73.64,48.82 74.05,48.82 74.15,48.92 74.15,50.06 74.25,50.16 74.66,50.16 74.76,50.06 74.76,48.92 74.86,48.82 75.37,48.82 75.47,48.92 75.47,49.86 75.57,49.96 75.98,49.96 76.08,49.86 76.08,48.92 76.18,48.82 76.59,48.82 76.69,48.92 76.69,49.86 76.79,49.96 77.2,49.96 77.3,49.86 77.3,48.92 77.4,48.82 77.93,48.82 81.04,51.93 82.8,51.93 83.21,52.34 83.21,52.76 83.5,53.05 83.92,53.05 84.44,53.57 84.98,53.57 v3(85.13,53.42)
RP_DDR4_DIMM2_DQ54: length 61.3
  TOP w0.102: 87.93,55.33 87.71,55.1 87.71,54.34 v3(87.3,53.93)
  TOP w0.114: v2(51.59,44.79) 52,45.2 CONN8.224 ; U9.BR77 87.96,56.55 87.96,55.35 87.93,55.33
  S3 w0.102: v2(51.59,44.79) 51.59,44.73 51.9,44.42 52.67,44.42 54.42,42.67 55.32,42.67 61.65,36.35 69.49,36.35 69.6,36.45 69.6,38.43 69.7,38.53 70.1,38.53 70.21,38.43 70.21,36.45 70.31,36.35 70.71,36.35 70.82,36.45 70.82,38.43 70.92,38.53 71.32,38.53 71.42,38.43 71.42,36.45 71.53,36.35 72.01,36.35 83.64,47.98 83.64,48.64 85.77,50.76 85.77,51.23 85.39,51.6 85.39,52.02 v3(87.3,53.93)
RP_DDR4_DIMM2_DQ55: length 61.1
  TOP w0.102: v3(87.3,53.17) 87.91,53.78 87.91,55 88.17,55.25 88.17,55.98 88.28,56.1 88.28,56.73 87.95,57.06 U9.BR75
  TOP w0.114: CONN8.225 46.89,44.95 v2(47.05,44.79)
  S3 w0.102: v2(47.05,44.79) 47.05,44.44 47.47,44.02 48.8,44.02 52.03,40.79 54.91,40.79 60.53,35.18 72.77,35.18 87.7,50.11 87.7,51.37 87.25,51.81 87.25,53.12 v3(87.3,53.17)
RP_DDR4_DIMM2_DQ56: length 60.5
  TOP w0.102: v3(86.68,51.03) 86.8,50.91 87.54,50.91 89.96,53.33 89.96,55.17 90.13,55.34 90.13,56.17 90.12,56.18 90.12,56.37 U9.BL77
  TOP w0.114: v2(48.82,43.26) 47.97,42.4 47.62,42.4 47.17,41.95 CONN8.237
  S10 w0.102: v2(48.82,43.26) 48.82,43.15 49.22,42.75 49.81,42.75 50.24,42.32 50.74,42.32 51,42.06 54.4,42.06 59.56,47.22 59.98,47.22 60.08,47.32 60.08,47.52 60.18,47.62 60.59,47.62 60.69,47.52 60.69,47.32 60.79,47.22 61.2,47.22 61.3,47.32 61.3,47.52 61.4,47.62 61.81,47.62 61.91,47.52 61.91,47.32 62.01,47.22 62.42,47.22 62.52,47.32 62.52,47.52 62.62,47.62 63.03,47.62 63.13,47.52 63.13,47.32 63.23,47.22 63.64,47.22 63.74,47.32 63.74,47.52 63.84,47.62 64.25,47.62 64.35,47.52 64.35,47.32 64.45,47.22 64.86,47.22 64.96,47.32 64.96,47.52 65.06,47.62 65.47,47.62 65.57,47.52 65.57,47.32 65.67,47.22 66.08,47.22 66.18,47.32 66.18,47.52 66.28,47.62 66.69,47.62 66.79,47.52 66.79,47.32 66.89,47.22 67.3,47.22 67.4,47.32 67.4,47.52 67.5,47.62 67.91,47.62 68.01,47.52 68.01,47.32 68.11,47.22 68.52,47.22 68.62,47.32 68.62,47.52 68.72,47.62 69.12,47.62 69.23,47.52 69.23,47.32 69.33,47.22 69.73,47.22 69.84,47.32 69.84,47.52 69.94,47.62 70.34,47.62 70.45,47.52 70.45,47.32 70.55,47.22 71.03,47.22 71.13,47.32 71.13,47.5 71.23,47.6 71.64,47.6 71.74,47.5 71.74,47.32 71.84,47.22 72.33,47.22 72.43,47.32 72.43,47.42 72.53,47.52 72.93,47.52 73.04,47.42 73.04,47.32 73.14,47.22 80.63,47.22 84,50.59 84.1,50.59 84.98,51.47 85.36,51.47 85.79,51.04 85.82,51.04 85.82,51.03 v3(86.68,51.03)
RP_DDR4_DIMM2_DQ57: length 60.4
  TOP w0.102: U9.BL75 89.93,57.05 89.56,56.67 89.56,56.45 89.93,56.08 89.93,55.42 89.75,55.25 89.75,53.41 88.44,52.09 v3(87.74,52.09)
  TOP w0.114: CONN8.236 51.31,42.2 50.34,43.18 v2(50.34,43.34)
  S10 w0.102: v2(50.34,43.34) 50.34,43.21 50.74,42.81 51.1,42.81 51.19,42.71 54.37,42.71 56.61,44.95 56.61,45.1 56.07,45.64 56.07,45.78 56.36,46.07 56.5,46.07 57.04,45.53 57.19,45.53 57.47,45.82 57.47,45.96 56.93,46.5 56.93,46.65 57.22,46.93 57.36,46.93 57.9,46.39 58.05,46.39 58.34,46.68 58.34,46.82 57.8,47.36 57.8,47.51 58.08,47.8 58.23,47.8 58.77,47.25 58.91,47.25 59.79,48.13 74.28,48.13 74.38,48.03 74.38,47.85 74.48,47.75 74.89,47.75 74.99,47.85 74.99,48.03 75.09,48.13 75.5,48.13 75.6,48.03 75.6,47.85 75.7,47.75 76.11,47.75 76.21,47.85 76.21,48.03 76.31,48.13 76.72,48.13 76.82,48.03 76.82,47.85 76.92,47.75 77.33,47.75 77.43,47.85 77.43,48.03 77.53,48.13 77.94,48.13 78.04,48.03 78.04,47.85 78.14,47.75 78.55,47.75 78.65,47.85 78.65,48.03 78.75,48.13 79.16,48.13 79.26,48.03 79.26,47.85 79.36,47.75 79.77,47.75 79.87,47.85 79.87,48.03 79.97,48.13 80.66,48.13 83.36,50.84 83.5,50.84 84.73,52.06 85.6,52.06 86.04,51.63 86.42,51.63 86.88,52.09 v3(87.74,52.09)
RP_DDR4_DIMM2_DQ58: length 60.5
  TOP w0.102: v3(90,51.83) 90.59,51.83 91.58,52.82 91.58,54.43 91.92,54.77 91.92,56.55 U9.BG77
  TOP w0.114: v2(48.82,39.7) 48.82,39.48 48.29,38.95 CONN8.249
  S10 w0.102: v3(90,51.83) 90,50.98 74.3,35.28 58.27,35.28 56.08,37.47 51.69,37.47 50.9,38.25 49.94,38.25 48.82,39.36 v2(48.82,39.7)
RP_DDR4_DIMM2_DQ59: length 60.3
  TOP w0.102: U9.BG75 91.91,57.03 92.24,56.7 92.24,56.1 92.13,55.98 92.13,52.59 90.24,50.7 v3(88.88,50.7)
  TOP w0.114: v2(49.71,39.7) 49.71,39.62 50.63,38.7 CONN8.250
  S10 w0.102: v3(88.88,50.7) 73.96,35.79 58.51,35.79 55.36,38.94 50.34,38.94 49.71,39.57 v2(49.71,39.7)
RP_DDR4_DIMM2_DQ60: length 60.5
  TOP w0.102: v3(88.81,53.17) 89.55,53.91 89.55,55.5 89.44,55.62 U9.BM78
  TOP w0.114: v2(51.96,43.33) 52.09,43.2 CONN8.232
  S10 w0.102: v3(88.81,53.17) 88.58,53.17 87.77,53.99 87.77,54.89 87.53,55.12 86.19,55.12 80.47,49.4 78.32,49.4 78.21,49.3 78.21,49 78.11,48.9 77.71,48.9 77.61,49 77.61,49.3 77.5,49.4 77.1,49.4 77,49.3 77,49 76.89,48.9 76.49,48.9 76.39,49 76.39,49.3 76.28,49.4 75.88,49.4 75.78,49.3 75.78,49 75.67,48.9 75.27,48.9 75.17,49 75.17,49.3 75.07,49.4 74.66,49.4 74.56,49.3 74.56,49 74.46,48.9 72.96,48.9 72.86,49 72.86,49.33 72.76,49.43 72.35,49.43 72.25,49.33 72.25,49 72.15,48.9 71.74,48.9 71.64,49 71.64,49.33 71.54,49.43 71.13,49.43 71.03,49.33 71.03,49 70.93,48.9 70.44,48.9 70.34,49 70.34,49.35 70.24,49.45 69.83,49.45 69.73,49.35 69.73,49 69.63,48.9 69.22,48.9 69.12,49 69.12,49.35 69.02,49.45 68.62,49.45 68.51,49.35 68.51,49 68.41,48.9 68.01,48.9 67.9,49 67.9,49.35 67.8,49.45 67.4,49.45 67.29,49.35 67.29,49 67.19,48.9 66.79,48.9 66.68,49 66.68,49.35 66.58,49.45 66.18,49.45 66.08,49.35 66.08,49 65.97,48.9 65.57,48.9 65.47,49 65.47,49.35 65.36,49.45 64.96,49.45 64.86,49.35 64.86,49 64.75,48.9 64.35,48.9 64.25,49 64.25,49.35 64.14,49.45 63.74,49.45 63.64,49.35 63.64,49 63.54,48.9 63.13,48.9 63.03,49 63.03,49.35 62.93,49.45 62.52,49.45 62.42,49.35 62.42,49 62.32,48.9 61.91,48.9 61.81,49 61.81,49.35 61.71,49.45 61.3,49.45 61.2,49.35 61.2,49 61.1,48.9 60.69,48.9 60.59,49 60.59,49.35 60.49,49.45 60.08,49.45 59.98,49.35 59.98,49 59.88,48.9 59.47,48.9 59.37,49 59.37,49.35 59.27,49.45 58.86,49.45 58.76,49.35 58.76,49 58.66,48.9 57.91,48.9 52.35,43.33 v2(51.96,43.33)
RP_DDR4_DIMM2_DQ61: length 60.3
  TOP w0.102: v3(88.94,53.93) 89.35,54.34 89.35,55.42 89.16,55.61 89.16,55.98 89.34,56.16 89.34,56.75 89.44,56.85 U9.BM76
  TOP w0.114: v2(47.05,43.26) 46.74,42.95 CONN8.233
  S10 w0.102: v2(47.05,43.26) 46.43,43.26 46.08,43.61 46.08,45.12 46.33,45.37 47.45,45.37 47.55,45.47 47.55,45.85 47.65,45.95 48.06,45.95 48.16,45.85 48.16,45.47 48.26,45.37 48.67,45.37 48.77,45.47 48.77,45.85 48.87,45.95 49.28,45.95 49.38,45.85 49.38,45.47 49.48,45.37 49.89,45.37 49.99,45.47 49.99,45.85 50.09,45.95 50.5,45.95 50.6,45.85 50.6,45.47 50.7,45.37 51.11,45.37 51.21,45.47 51.21,45.85 51.31,45.95 51.72,45.95 51.82,45.85 51.82,45.47 51.92,45.37 52.87,45.37 57.68,50.19 73.81,50.19 74.09,49.91 80.13,49.91 85.94,55.72 87.78,55.72 88.36,55.14 88.36,54.51 v3(88.94,53.93)
RP_DDR4_DIMM2_DQ62: length 60.4
  TOP w0.102: U9.BH78 91.42,55.73 91.18,55.49 91.18,54.34 v3(90.77,53.93)
  TOP w0.114: CONN8.245 46.82,39.95 v2(47.05,39.72)
  S10 w0.102: v2(47.05,39.72) 45.82,39.72 45.64,39.9 45.64,40.67 45.82,40.84 47.04,40.84 47.58,40.3 55.56,40.3 59.09,36.77 66.92,36.77 67.89,37.74 74.23,37.74 90.42,53.93 v3(90.77,53.93)
RP_DDR4_DIMM2_DQ63: length 60.7
  TOP w0.102: v3(90.77,53.17) 91.38,53.78 91.38,55.3 91.7,55.62 91.7,56.31 91.58,56.42 91.58,56.89 U9.BH76
  TOP w0.114: CONN8.246 v2(51.51,39.7)
  S10 w0.102: v2(51.51,39.7) 55.43,39.7 58.85,36.28 68.58,36.28 68.69,36.38 68.69,37.11 68.79,37.21 69.19,37.21 69.3,37.11 69.3,36.38 69.4,36.28 69.88,36.28 69.98,36.38 69.98,37.16 70.08,37.26 70.49,37.26 70.59,37.16 70.59,36.38 70.69,36.28 71.1,36.28 71.2,36.38 71.2,37.16 71.3,37.26 71.71,37.26 71.81,37.16 71.81,36.38 71.91,36.28 72.32,36.28 72.42,36.38 72.42,37.16 72.52,37.26 72.93,37.26 73.03,37.16 73.03,36.38 73.13,36.28 73.61,36.28 90.5,53.17 v3(90.77,53.17)
RP_DDR4_DIMM2_DQS0_N: length 52.2
  TOP w0.102: v3(76.04,96.46) 76.04,96.8 76.28,97.04 76.98,97.04 81.52,92.5 U9.CJ1 ; CONN8.11 46.22,100.45 46.33,100.34 48.83,100.34 48.92,100.43 48.92,100.57 v2(48.65,100.84)
  S8 w0.089: v2(48.65,100.84) 48.96,100.53 48.96,100.25 49.17,100.04 53.44,100.04 53.58,99.89 53.61,99.89
  S8 w0.102: 53.61,99.89 54.06,99.89 54.16,99.79 54.16,99.42 54.26,99.31 54.66,99.31 54.77,99.42 54.77,99.79 54.87,99.89 55.27,99.89 55.38,99.79 55.38,99.42 55.48,99.31 55.88,99.31 55.99,99.42 55.99,99.79 56.09,99.89 56.55,99.89 60.17,96.27 69.53,96.27 69.91,96.65 69.91,98.42 70.01,98.53 70.42,98.53 70.52,98.42 70.52,96.65 70.91,96.27 71.71,96.27 72.1,96.65 72.1,98.42 72.2,98.53 72.6,98.53 72.71,98.42 72.71,96.65 73.09,96.27 73.97,96.27 74.33,95.91 75.29,95.91 75.84,96.46 v3(76.04,96.46)
RP_DDR4_DIMM2_DQS0_P: length 52.2
  TOP w0.102: U9.CJ3 81.52,91.27 81.8,91.55 81.8,92.62 77.09,97.32 76.17,97.32 75.84,97 v3(75.5,97) ; CONN8.13 46.22,99.95 46.33,100.06 49,100.06 49.19,100.26 49.19,100.57 v2(49.46,100.84)
  S8 w0.089: 53.61,100.37 53.58,100.37 53.44,100.23 49.25,100.23 49.15,100.33 49.15,100.53 v2(49.46,100.84)
  S8 w0.102: v3(75.5,97) 75.5,96.8 75.09,96.39 74.53,96.39 74.17,96.75 73.29,96.75 73.19,96.85 73.19,98.63 72.8,99.01 72,99.01 71.61,98.63 71.61,96.85 71.51,96.75 71.11,96.75 71,96.85 71,98.63 70.62,99.01 69.81,99.01 69.43,98.63 69.43,96.85 69.33,96.75 60.37,96.75 56.75,100.37 53.61,100.37
RP_DDR4_DIMM2_DQS1_N: length 41
  TOP w0.092: 76.67,87.46 76.66,87.46 76.08,88.05
  TOP w0.102: 76.67,87.46 77.66,87.46 77.87,87.25 U9.CU10 ; v2(49.33,95.94) 49.07,95.67 49.07,95.37 49.35,95.09 52.24,95.09 52.35,95.2 CONN8.32 ; 76.08,88.05 75.76,88.37 71.32,88.37 70.9,88.79 70.9,89.27 v3(71.14,89.51)
  S3 w0.102: v3(71.14,89.51) 71,89.65 71,90.12 70.61,90.51 70.61,90.66 70.74,90.78 70.74,90.93 70.46,91.22 70.31,91.22 70.18,91.09 70.04,91.09 69.75,91.37 69.75,91.52 69.88,91.65 69.88,91.79 69.59,92.08 69.45,92.08 69.32,91.95 69.18,91.95 68.89,92.24 68.89,92.38 69.02,92.51 69.02,92.65 68.73,92.94 68.59,92.94 68.46,92.81 68.31,92.81 68.03,93.1 68.03,93.24 68.16,93.37 68.16,93.52 67.87,93.8 67.72,93.8 67.6,93.68 67.45,93.68 66.74,94.39 58.7,94.39 57.59,95.49 49.35,95.49 49.17,95.67 49.17,95.77 v2(49.33,95.94)
RP_DDR4_DIMM2_DQS1_P: length 41
  TOP w0.092: 76.06,87.79 76.47,87.38 76.59,87.27 76.65,87.27 76.65,87.26 76.67,87.26
  TOP w0.102: v3(70.38,89.51) 70.62,89.27 70.62,88.67 71.21,88.09 75.77,88.09 76.06,87.79 ; U9.CR10 78.53,87.25 78.2,86.92 77.92,86.92 77.58,87.26 76.67,87.26 ; CONN8.34 52.35,94.7 52.24,94.81 49.23,94.81 48.79,95.25 48.79,95.67 v2(48.52,95.94)
  S3 w0.102: v3(70.38,89.51) 70.52,89.65 70.52,89.92 66.54,93.9 58.5,93.9 57.39,95.01 49.15,95.01 48.69,95.47 48.69,95.77 v2(48.52,95.94)
RP_DDR4_DIMM2_DQS2_N: length 38.2
  TOP w0.102: CONN8.53 46.22,89.95 46.33,89.84 48.2,89.84 48.44,90.09 48.44,90.3 v2(48.18,90.56) ; v3(74.87,84.1) 75.44,83.53 76.71,83.53 77.05,83.87 77.23,83.87 U9.CV18
  S8 w0.089: v2(48.18,90.56) 48.49,90.25 48.49,90 48.69,89.79 52.83,89.79 52.98,89.65 53,89.65
  S8 w0.102: v3(74.87,84.1) 75.01,84.23 75.01,84.51 74.8,84.72 73.32,84.72 73.2,84.84 68.15,84.84 64.37,88.61 59.02,88.61 57.99,89.65 57.42,89.65 57.32,89.55 57.32,89.28 57.22,89.17 56.81,89.17 56.71,89.28 56.71,89.55 56.61,89.65 56.2,89.65 56.1,89.55 56.1,89.28 56,89.17 55.59,89.17 55.49,89.28 55.49,89.55 55.39,89.65 53,89.65
RP_DDR4_DIMM2_DQS2_P: length 38.2
  TOP w0.102: v3(75.63,84.1) 76,83.73 76.63,83.73 76.97,84.07 77.76,84.07 77.89,83.95 78.39,83.95 U9.CT18 ; CONN8.55 46.22,89.45 46.33,89.56 48.31,89.56 48.72,89.97 48.72,90.3 v2(48.99,90.56)
  S8 w0.089: 53,90.13 52.98,90.13 52.83,89.98 48.77,89.98 48.68,90.08 48.68,90.25 v2(48.99,90.56)
  S8 w0.102: v3(75.63,84.1) 75.5,84.23 75.5,84.71 75,85.2 73.52,85.2 73.4,85.32 68.35,85.32 64.57,89.1 59.22,89.1 58.19,90.13 53,90.13
RP_DDR4_DIMM2_DQS3_N: length 43.8
  TOP w0.102: CONN8.74 52.35,84.7 52.24,84.59 49.79,84.59 49.62,84.77 49.62,85.02 v2(49.88,85.29) ; U9.CU26 78.04,80.33 76.39,80.33 75.82,80.9 74.46,80.9 74.37,80.82 74.37,80.74 v3(74.62,80.49)
  S3 w0.102: v3(74.62,80.49) 74.48,80.63 74.48,81.29 73.98,81.79 66.27,81.79 66.03,82.03 66.03,82.17 66.34,82.49 66.34,82.63 66.05,82.92 65.91,82.92 65.59,82.6 65.45,82.6 65.16,82.89 65.16,83.03 65.48,83.35 65.48,83.49 65.19,83.78 65.05,83.78 64.73,83.47 64.59,83.47 64.29,83.76 64.29,84.26 63.81,84.74 63.17,84.74 63.07,84.84 63.07,85.14 62.69,85.52 61.88,85.52 61.5,85.14 61.5,84.84 61.39,84.74 60.99,84.74 60.89,84.84 60.89,85.14 60.5,85.52 59.69,85.52 59.31,85.14 59.31,84.84 59.21,84.74 58.8,84.74 58.7,84.84 58.7,85.14 58.32,85.52 57.51,85.52 57.13,85.14 57.13,84.84 57.02,84.74 56.62,84.74 56.52,84.84 56.52,85.14 56.13,85.52 55.33,85.52 54.94,85.14 54.94,84.84 54.84,84.74 54.43,84.74 54.33,84.84 54.33,85.14 53.95,85.52 53.14,85.52 52.76,85.14 52.76,84.84 52.66,84.74 49.92,84.74 49.72,84.95 49.72,85.12 v2(49.88,85.29)
RP_DDR4_DIMM2_DQS3_P: length 43.7
  TOP w0.102: v2(49.07,85.29) 49.34,85.02 49.34,84.65 49.67,84.31 52.24,84.31 52.35,84.2 CONN8.76 ; v3(73.86,80.49) 74.17,80.79 74.17,80.9 74.37,81.1 75.91,81.1 76.47,80.54 77.74,80.54 77.89,80.68 78.21,80.68 78.57,80.32 U9.CR26
  S3 w0.102: v2(49.07,85.29) 49.23,85.12 49.23,84.75 49.72,84.26 52.86,84.26 53.24,84.64 53.24,84.94 53.34,85.04 53.75,85.04 53.85,84.94 53.85,84.64 54.23,84.26 55.04,84.26 55.42,84.64 55.42,84.94 55.53,85.04 55.93,85.04 56.03,84.94 56.03,84.64 56.42,84.26 57.22,84.26 57.61,84.64 57.61,84.94 57.71,85.04 58.12,85.04 58.22,84.94 58.22,84.64 58.6,84.26 59.41,84.26 59.79,84.64 59.79,84.94 59.89,85.04 60.3,85.04 60.4,84.94 60.4,84.64 60.79,84.26 61.59,84.26 61.98,84.64 61.98,84.94 62.08,85.04 62.49,85.04 62.59,84.94 62.59,84.64 62.97,84.26 63.61,84.26 63.81,84.06 63.81,83.56 66.07,81.31 73.78,81.31 74,81.09 74,80.63 v3(73.86,80.49)
RP_DDR4_DIMM2_DQS4_N: length 43.3
  TOP w0.102: CONN8.177 46.22,56.95 46.33,56.84 46.87,56.84 47.35,56.36 48.36,56.36 48.51,56.51 48.51,56.74 v2(48.24,57) ; v2(75.11,53.69) 76.3,54.88 79.7,54.88 80.52,55.7 80.52,55.95 80.33,56.14 80.33,56.97 U9.CM76
  S5 w0.089: v2(48.24,57) 48.55,56.69 48.55,56.4 48.83,56.12 52.5,56.12 52.75,55.87 52.75,55.78 52.7,55.73 52.7,55.71 52.71,55.7
  S5 w0.102: 52.71,55.7 53.53,54.88 66.14,54.88 66.25,54.78 66.25,54.62 66.35,54.52 66.75,54.52 66.86,54.62 66.86,54.78 66.96,54.88 67.36,54.88 67.47,54.78 67.47,54.62 67.57,54.52 67.97,54.52 68.08,54.62 68.08,54.78 68.18,54.88 68.58,54.88 68.68,54.78 68.68,54.62 68.79,54.52 69.19,54.52 69.29,54.62 69.29,54.78 69.4,54.88 70.46,54.88 70.57,54.78 70.57,54.67 70.95,54.28 71.76,54.28 72.14,54.67 72.14,54.78 72.24,54.88 74.85,54.88 75.27,54.46 75.27,53.85 v2(75.11,53.69)
RP_DDR4_DIMM2_DQS4_P: length 43.3
  TOP w0.102: U9.CN75 80.2,57.55 80.55,57.2 80.55,56.94 80.53,56.92 80.53,56.22 80.72,56.03 80.72,55.61 79.78,54.68 76.54,54.68 75.92,54.06 v2(75.92,53.69) ; v2(49.06,57) 48.79,56.74 48.79,56.39 48.48,56.08 47.23,56.08 46.75,56.56 46.33,56.56 46.22,56.45 CONN8.179
  S5 w0.089: 53.05,56.05 53.04,56.06 52.83,56.06 52.58,56.31 48.91,56.31 48.74,56.48 48.74,56.69 v2(49.06,57)
  S5 w0.102: 53.05,56.05 53.73,55.37 70.66,55.37 71.05,54.98 71.05,54.87 71.15,54.76 71.56,54.76 71.66,54.87 71.66,54.98 72.04,55.37 75.05,55.37 75.76,54.66 75.76,53.85 v2(75.92,53.69)
RP_DDR4_DIMM2_DQS5_N: length 47.6
  TOP w0.102: U9.CD77 84,56.55 84,55.59 83.17,54.76 83.17,54.37 80.41,51.6 77.92,51.6 77.89,51.63 77.43,51.63 77.24,51.43 77.24,51.32 77.35,51.21 v3(77.59,51.21) ; v2(49.23,52.17) 48.97,51.9 48.97,51.73 49.11,51.59 52.24,51.59 52.35,51.7 CONN8.198
  S8 w0.102: v2(49.23,52.17) 49.15,52.08 49.15,51.92 49.36,51.71 50.81,51.71 50.91,51.81 50.91,52.01 51.01,52.11 51.42,52.11 51.52,52.01 51.52,51.81 51.62,51.71 52.03,51.71 52.13,51.81 52.13,52.01 52.23,52.11 52.64,52.11 52.74,52.01 52.74,51.81 52.84,51.71 53.25,51.71 53.35,51.81 53.35,52.01 53.45,52.11 53.86,52.11 53.96,52.01 53.96,51.81 54.06,51.71 55.13,51.71 56.41,53 73.66,53 73.89,52.77 76.87,52.77 77.45,52.18 77.45,51.35 v3(77.59,51.21)
RP_DDR4_DIMM2_DQS5_P: length 47.5
  TOP w0.102: v2(48.42,52.17) 48.69,51.9 48.69,51.62 48.99,51.31 52.24,51.31 52.35,51.2 CONN8.200 ; v3(76.83,51.21) 77.03,51.41 77.03,51.52 77.35,51.84 77.97,51.84 78,51.81 80.33,51.81 82.97,54.45 82.97,54.85 83.8,55.68 83.8,56.18 83.64,56.33 83.64,56.7 83.83,56.88 83.83,57.39 U9.CD75
  S8 w0.102: v2(48.42,52.17) 48.59,52 48.59,51.62 48.98,51.23 55.33,51.23 56.61,52.51 73.46,52.51 73.69,52.29 76.67,52.29 76.97,51.98 76.97,51.35 v3(76.83,51.21)
RP_DDR4_DIMM2_DQS6_N: length 60.7
  TOP w0.102: CONN8.219 46.22,46.45 46.33,46.34 47.28,46.34 47.62,46 48.68,46 48.92,46.24 48.92,46.41 v2(48.65,46.68) ; U9.BT78 87.46,55.74 86.67,54.95 86.67,53.68 82.12,49.14 81.49,49.14 81.38,49.24 v3(81.38,49.66)
  S3 w0.089: v2(48.65,46.68) 48.96,46.37 48.96,46.15 49.21,45.9 50.98,45.9 51.14,46.06 51.97,46.06 52.12,45.91 52.14,45.91
  S3 w0.102: 52.14,45.91 57.87,45.91 58.22,46.25 58.99,46.25 59.09,46.15 59.09,46.02 59.19,45.92 59.6,45.92 59.7,46.02 59.7,46.15 59.8,46.25 60.21,46.25 60.31,46.15 60.31,46.02 60.41,45.92 60.82,45.92 60.92,46.02 60.92,46.15 61.02,46.25 68.92,46.25 69.02,46.15 69.02,45.22 69.4,44.83 70.21,44.83 70.59,45.22 70.59,46.15 70.7,46.25 71.1,46.25 71.2,46.15 71.2,45.22 71.59,44.83 72.39,44.83 72.78,45.22 72.78,46.15 72.88,46.25 73.29,46.25 73.39,46.15 73.39,45.22 73.77,44.83 74.58,44.83 74.96,45.22 74.96,46.15 75.06,46.25 75.47,46.25 75.57,46.15 75.57,45.22 75.96,44.83 76.76,44.83 77.15,45.22 77.15,46.15 77.25,46.25 79.58,46.25 81.74,48.42 81.74,49.1 81.38,49.46 v3(81.38,49.66)
RP_DDR4_DIMM2_DQS6_P: length 60.7
  TOP w0.102: v3(80.84,49.12) 81.21,49.12 81.4,48.93 82.2,48.93 86.87,53.6 86.87,54.87 87.43,55.43 87.52,55.43 87.74,55.64 87.74,56.03 87.46,56.31 U9.BT76 ; CONN8.221 46.22,45.95 46.33,46.06 47.17,46.06 47.51,45.72 48.79,45.72 49.19,46.12 49.19,46.41 v2(49.46,46.68)
  S3 w0.089: 52.14,46.39 52.12,46.39 51.97,46.25 51.06,46.25 50.9,46.09 49.29,46.09 49.15,46.23 49.15,46.37 v2(49.46,46.68)
  S3 w0.102: 52.14,46.39 57.67,46.39 58.02,46.74 69.12,46.74 69.5,46.35 69.5,45.42 69.6,45.31 70.01,45.31 70.11,45.42 70.11,46.35 70.5,46.74 71.3,46.74 71.69,46.35 71.69,45.42 71.79,45.31 72.19,45.31 72.3,45.42 72.3,46.35 72.68,46.74 73.49,46.74 73.87,46.35 73.87,45.42 73.97,45.31 74.38,45.31 74.48,45.42 74.48,46.35 74.86,46.74 75.67,46.74 76.06,46.35 76.06,45.42 76.16,45.31 76.56,45.31 76.67,45.42 76.67,46.35 77.05,46.74 79.38,46.74 81.26,48.62 81.26,48.9 81.04,49.12 v3(80.84,49.12)
RP_DDR4_DIMM2_DQS7_N: length 61.8
  TOP w0.102: U9.BJ77 90.92,56.09 90.72,55.9 90.72,55.65 90.16,55.08 90.16,53.02 86.32,49.18 86.06,49.18 85.6,49.64 v3(85.6,49.96) ; CONN8.240 52.35,41.2 52.24,41.09 49.32,41.09 49.19,41.22 49.19,41.35 v2(49.46,41.61)
  S10 w0.089: v2(49.46,41.61) 49.15,41.3 49.15,41.14 49.27,41.02 55.17,41.02 55.57,41.43 55.57,41.63 55.59,41.65 ; 83.45,49.21 83.47,49.22 83.67,49.22 84.24,49.79 84.51,49.79 84.79,50.08 85.08,50.08 85.19,49.96 v3(85.6,49.96)
  S10 w0.102: 55.59,41.65 56.31,42.37 56.31,42.52 56.09,42.74 56.09,42.88 56.38,43.17 56.52,43.17 56.74,42.95 56.89,42.95 57.17,43.24 57.17,43.38 56.95,43.6 56.95,43.75 57.24,44.03 57.38,44.03 57.61,43.81 57.75,43.81 58.04,44.1 58.04,44.24 57.81,44.47 57.81,44.61 58.1,44.9 58.24,44.9 58.47,44.67 58.61,44.67 60.57,46.63 69.66,46.63 70.04,46.25 70.04,45.69 70.14,45.59 70.55,45.59 70.65,45.69 70.65,46.25 71.04,46.63 71.84,46.63 72.23,46.25 72.23,45.69 72.33,45.59 72.73,45.59 72.84,45.69 72.84,46.25 73.22,46.63 80.88,46.63 83.45,49.21
RP_DDR4_DIMM2_DQS7_P: length 61.7
  TOP w0.102: CONN8.242 52.35,40.7 52.24,40.81 49.2,40.81 48.92,41.1 48.92,41.35 v2(48.65,41.61) ; U9.BJ75 90.92,57.03 91.25,56.7 91.25,56.13 91.13,56.01 91.12,56.01 90.93,55.81 90.93,55.56 90.36,55 90.36,52.94 86.4,48.98 85.98,48.98 85.54,49.41 85.52,49.41 85.52,49.42 v3(85.06,49.42)
  S10 w0.089: 55.93,41.31 55.91,41.29 55.71,41.29 55.25,40.83 49.19,40.83 48.96,41.06 48.96,41.3 v2(48.65,41.61) ; v3(85.06,49.42) 85.06,49.82 85,49.88 84.87,49.88 84.58,49.6 84.32,49.6 83.81,49.09 83.81,48.88 83.79,48.87
  S10 w0.102: 55.93,41.31 60.77,46.15 69.46,46.15 69.56,46.05 69.56,45.49 69.94,45.11 70.75,45.11 71.13,45.49 71.13,46.05 71.24,46.15 71.64,46.15 71.74,46.05 71.74,45.49 72.13,45.11 72.93,45.11 73.32,45.49 73.32,46.05 73.42,46.15 81.08,46.15 83.79,48.87
RP_DDR4_DIMM2_DQS8_N: length 44.4
  TOP w0.102: U9.CV34 77.31,76.86 77.31,77.08 77.24,77.16 76.36,77.16 75.97,77.54 74.81,77.54 74.71,77.45 74.71,77.35 v3(74.96,77.11) ; CONN8.95 46.22,79.45 46.33,79.34 46.75,79.34 47.09,79.68 48.27,79.68 48.6,80.01 48.6,80.45 v2(48.34,80.71)
  S8 w0.102: v3(74.96,77.11) 74.82,77.25 74.82,77.99 74.22,78.59 70.15,78.59 69.17,79.57 66.93,79.57 64.71,81.79 62.79,81.79 62.69,81.89 62.69,82.72 62.31,83.11 61.5,83.11 61.12,82.72 61.12,81.89 61.02,81.79 60.61,81.79 60.51,81.89 60.51,82.72 60.12,83.11 59.32,83.11 58.93,82.72 58.93,81.89 58.83,81.79 58.42,81.79 58.32,81.89 58.32,82.72 57.94,83.11 57.13,83.11 56.75,82.72 56.75,81.89 56.65,81.79 53.5,81.79 53.4,81.89 53.4,82.02 53.3,82.12 52.9,82.12 52.79,82.02 52.79,81.89 52.69,81.79 48.99,81.79 48.5,81.3 48.5,80.88 v2(48.34,80.71)
RP_DDR4_DIMM2_DQS8_P: length 44.4
  TOP w0.102: v2(49.15,80.71) 48.88,80.45 48.88,79.9 48.39,79.4 47.21,79.4 46.87,79.06 46.33,79.06 46.22,78.95 CONN8.97 ; U9.CT34 78.02,76.86 77.65,77.22 77.65,77.22 77.51,77.36 76.44,77.36 76.06,77.75 74.73,77.75 74.51,77.53 74.51,77.43 v3(74.2,77.11)
  S8 w0.102: v2(49.15,80.71) 48.98,80.88 48.98,81.1 49.19,81.31 56.85,81.31 57.23,81.69 57.23,82.52 57.33,82.63 57.74,82.63 57.84,82.52 57.84,81.69 58.22,81.31 59.03,81.31 59.41,81.69 59.41,82.52 59.52,82.63 59.92,82.63 60.02,82.52 60.02,81.69 60.41,81.31 61.22,81.31 61.6,81.69 61.6,82.52 61.7,82.63 62.11,82.63 62.21,82.52 62.21,81.69 62.59,81.31 64.51,81.31 66.73,79.08 68.97,79.08 69.95,78.1 74.02,78.1 74.34,77.79 74.34,77.25 v3(74.2,77.11)
RP_DDR4_DIMM2_ECC0: length 44.2
  TOP w0.102: U9.CV31 76.71,77.85 76.32,78.23 71.87,78.23 71.65,78.02 71.65,77.42 v2(71.88,77.19)
  TOP w0.114: v2(51.88,80.68) 51.88,80.37 52.04,80.2 CONN8.92
  S8 w0.102: v2(71.88,77.19) 71.47,77.6 69.64,77.6 69.36,77.88 68.22,77.88 68.12,77.98 68.12,78.49 68.02,78.59 67.61,78.59 67.51,78.49 67.51,77.98 67.41,77.88 66.78,77.88 64.71,79.94 64.35,79.94 64.25,80.04 64.25,80.66 64.15,80.76 63.74,80.76 63.64,80.66 63.64,80.04 63.54,79.94 63.13,79.94 63.03,80.04 63.03,80.66 62.93,80.76 62.52,80.76 62.42,80.66 62.42,80.04 62.32,79.94 61.91,79.94 61.81,80.04 61.81,80.66 61.71,80.76 61.3,80.76 61.2,80.66 61.2,80.04 61.1,79.94 60.69,79.94 60.59,80.04 60.59,80.66 60.49,80.76 60.08,80.76 59.98,80.66 59.98,80.04 59.88,79.94 59.47,79.94 59.37,80.04 59.37,80.66 59.27,80.76 58.86,80.76 58.76,80.66 58.76,80.04 58.66,79.94 58.25,79.94 58.15,80.04 58.15,80.66 58.05,80.76 57.64,80.76 57.54,80.66 57.54,80.04 57.44,79.94 57.04,79.94 56.93,80.04 56.93,80.66 56.83,80.76 56.43,80.76 56.32,80.66 56.32,80.04 56.22,79.94 54.57,79.94 54.47,80.04 54.47,80.54 54.37,80.64 53.96,80.64 53.86,80.54 53.86,80.04 53.76,79.94 53.28,79.94 53.17,80.04 53.17,80.7 53.07,80.8 52.67,80.8 52.57,80.7 52.57,80.04 52.46,79.94 52.01,79.94 51.88,80.08 v2(51.88,80.68)
RP_DDR4_DIMM2_ECC1: length 44
  TOP w0.102: U9.CT31 78.38,77.68 77.69,77.68 77.58,77.57 77.15,77.57 77.15,77.57 76.69,77.57 76.27,78 73.51,78 v3(72.67,77.15)
  TOP w0.114: CONN8.91 46.48,80.45 v2(46.74,80.71)
  S8 w0.102: v2(46.74,80.71) 46.74,81.31 46.56,81.48 45.01,81.48 44.79,81.27 44.79,79.72 45.07,79.44 45.55,79.44 45.66,79.54 45.66,79.93 45.76,80.04 46.16,80.04 46.27,79.93 46.27,79.54 46.37,79.44 46.77,79.44 46.87,79.54 46.87,79.93 46.98,80.04 47.38,80.04 47.48,79.93 47.48,79.54 47.59,79.44 64.25,79.44 66.29,77.39 69.15,77.39 69.78,76.76 70.79,76.76 71.09,76.46 72.26,76.46 72.67,76.87 v3(72.67,77.15)
RP_DDR4_DIMM2_ECC2: length 43.9
  TOP w0.114: CONN8.101 46.55,77.95 47.31,78.72 49.11,78.72 49.28,78.55 v2(49.28,77.97) ; U9.CV36 76.96,75.87 76.73,76.1 71.43,76.1 71.04,75.71 v3(71.04,75.37)
  S8 w0.102: v3(71.04,75.37) 71.12,75.45 71.12,75.72 70.8,76.03 69.8,76.03 68.92,76.91 66.02,76.91 64.21,78.72 63.73,78.72 63.63,78.61 63.63,77.88 63.53,77.77 63.12,77.77 63.02,77.88 63.02,78.61 62.92,78.72 62.51,78.72 62.41,78.61 62.41,77.88 62.31,77.77 61.9,77.77 61.8,77.88 61.8,78.61 61.7,78.72 61.29,78.72 61.19,78.61 61.19,77.88 61.09,77.77 60.68,77.77 60.58,77.88 60.58,78.61 60.48,78.72 59.75,78.72 59.65,78.82 59.65,78.86 59.55,78.96 59.14,78.96 59.04,78.86 59.04,78.82 58.94,78.72 58.53,78.72 58.43,78.82 58.43,78.86 58.33,78.96 57.92,78.96 57.82,78.86 57.82,78.82 57.72,78.72 57.31,78.72 57.21,78.82 57.21,78.86 57.11,78.96 56.7,78.96 56.6,78.86 56.6,78.82 56.5,78.72 56.09,78.72 55.99,78.82 55.99,78.86 55.89,78.96 55.48,78.96 55.38,78.86 55.38,78.82 55.28,78.72 54.87,78.72 54.77,78.82 54.77,78.86 54.67,78.96 54.26,78.96 54.16,78.86 54.16,78.82 54.06,78.72 53.66,78.72 53.55,78.82 53.55,78.86 53.45,78.96 53.05,78.96 52.94,78.86 52.94,78.82 52.84,78.72 52.44,78.72 52.33,78.82 52.33,78.86 52.23,78.96 51.83,78.96 51.72,78.86 51.72,78.82 51.62,78.72 51.22,78.72 51.12,78.82 51.12,78.86 51.01,78.96 48.91,78.96 48.74,78.79 48.74,78.59 48.92,78.41 49.1,78.41 49.28,78.23 v2(49.28,77.97)
RP_DDR4_DIMM2_ECC3: length 44.2
  TOP w0.114: v3(72.52,75.37) 72.99,75.84 76.58,75.84 76.84,75.58 77.67,75.58 77.84,75.76 78.43,75.76 U9.CT36 ; CONN8.105 46.61,76.95 v2(47.62,77.97)
  S8 w0.102: v3(72.52,75.37) 71.94,74.8 69.03,74.8 68.68,74.45 63.8,74.45 62.69,75.56 57.16,75.56 56.94,75.78 51.26,75.78 49.8,77.24 46.56,77.24 46.45,77.14 46.45,76.38 46.35,76.28 45.95,76.28 45.85,76.38 45.85,77.14 45.74,77.24 45.26,77.24 45.05,77.45 45.05,78.36 45.24,78.55 47.5,78.55 47.62,78.42 v2(47.62,77.97)
RP_DDR4_DIMM2_ECC4: length 44.1
  TOP w0.102: U9.CU30 78.05,78.35 76.59,78.35 76.45,78.49 72.96,78.49 v3(72.26,79.19)
  TOP w0.114: CONN8.88 52.27,81.2 52.02,81.45 50.03,81.45 49.53,81.95 v2(49.53,82.74)
  S8 w0.102: v2(49.53,82.74) 49.53,83.18 50.1,83.74 50.58,83.74 50.68,83.64 50.68,83.34 50.78,83.24 51.19,83.24 51.29,83.34 51.29,83.64 51.39,83.74 51.8,83.74 51.9,83.64 51.9,83.34 52,83.24 52.41,83.24 52.51,83.34 52.51,83.64 52.61,83.74 53.2,83.74 53.3,83.64 53.3,82.75 53.4,82.65 53.81,82.65 53.91,82.75 53.91,83.64 54.01,83.74 54.53,83.74 54.63,83.64 54.63,83.44 54.73,83.34 55.14,83.34 55.24,83.44 55.24,83.64 55.34,83.74 55.74,83.74 55.85,83.64 55.85,83.44 55.95,83.34 56.35,83.34 56.46,83.44 56.46,83.64 56.56,83.74 63.97,83.74 67.65,80.07 68.13,80.07 68.23,80.17 68.23,80.53 68.33,80.63 68.74,80.63 68.84,80.53 68.84,80.17 68.94,80.07 69.35,80.07 69.45,80.17 69.45,80.53 69.55,80.63 69.96,80.63 70.06,80.53 70.06,80.17 70.16,80.07 72.61,80.07 72.77,79.91 72.77,79.76 72.64,79.63 72.44,79.63 72.26,79.45 v3(72.26,79.19)
RP_DDR4_DIMM2_ECC5: length 44.3
  TOP w0.089: 76.59,78.71 75.02,78.71 v3(74.55,79.18)
  TOP w0.102: U9.CR30 78.91,78.48 78.44,78.48 78.23,78.68 77.92,78.68 77.79,78.55 76.75,78.55 76.59,78.71
  TOP w0.114: v2(47.91,82.72) 46.64,81.45 CONN8.87
  S8 w0.102: v3(74.55,79.18) 75.28,79.92 76.76,79.92 77,80.16 77,80.79 76.68,81.12 67.3,81.12 64.11,84.3 47.9,84.3 47.47,83.87 47.47,83.01 47.76,82.72 v2(47.91,82.72)
RP_DDR4_DIMM2_ECC6: length 44.1
  TOP w0.114: CONN8.100 52.58,78.2 52.04,78.74 50.62,78.74 50.09,78.21 v2(50.09,77.97) ; v3(68.61,75.37) 67.65,76.33 67.65,76.92 67.76,77.03 70.44,77.03 70.87,76.6 77.01,76.6 77.09,76.53 77.88,76.53 U9.CU35
  S8 w0.102: v3(68.61,75.37) 68.61,75.16 68.38,74.93 67.15,74.93 67.05,75.03 67.05,75.46 66.95,75.56 66.54,75.56 66.44,75.46 66.44,75.03 66.34,74.93 65.33,74.93 65.23,75.03 65.23,75.62 65.13,75.72 64.72,75.72 64.62,75.62 64.62,75.03 64.52,74.93 64.03,74.93 62.92,76.05 62.43,76.05 62.33,76.15 62.33,76.63 62.23,76.73 61.82,76.73 61.72,76.63 61.72,76.15 61.62,76.05 61.21,76.05 61.11,76.15 61.11,76.63 61.01,76.73 60.6,76.73 60.5,76.63 60.5,76.15 60.4,76.05 59.99,76.05 59.89,76.15 59.89,76.63 59.79,76.73 59.39,76.73 59.28,76.63 59.28,76.15 59.18,76.05 58.67,76.05 58.56,76.15 58.56,76.42 58.46,76.53 57.71,76.53 57.61,76.42 57.61,76.37 57.51,76.27 57.1,76.27 57,76.37 57,76.42 56.9,76.53 56.49,76.53 56.39,76.42 56.39,76.37 56.29,76.27 55.88,76.27 55.78,76.37 55.78,76.42 55.68,76.53 55.27,76.53 55.17,76.42 55.17,76.37 55.07,76.27 54.66,76.27 54.56,76.37 54.56,76.42 54.46,76.53 54.05,76.53 53.95,76.42 53.95,76.37 53.85,76.27 53.44,76.27 53.34,76.37 53.34,76.42 53.24,76.53 52.83,76.53 52.73,76.42 52.73,76.37 52.63,76.27 52.22,76.27 52.12,76.37 52.12,76.42 52.02,76.53 51.54,76.53 v2(50.09,77.97)
RP_DDR4_DIMM2_ECC7: length 44.1
  TOP w0.114: v3(69.37,75.37) 69.37,75.67 69.03,76.01 69.03,76.35 69.19,76.51 70.4,76.51 70.56,76.35 76.86,76.35 77.01,76.2 77.65,76.2 77.83,76.02 78.21,76.02 78.55,76.37 79.04,76.37 U9.CR35 ; v2(51.73,77.99) 52.52,77.2 CONN8.104
  S8 w0.102: v2(51.73,77.99) 51.73,77.2 51.91,77.03 52.39,77.03 52.49,77.13 52.49,78.13 52.6,78.23 53,78.23 53.1,78.13 53.1,77.13 53.21,77.03 53.61,77.03 53.71,77.13 53.71,78.13 53.81,78.23 54.22,78.23 54.32,78.13 54.32,77.13 54.42,77.03 56.07,77.03 56.17,77.13 56.17,77.97 56.27,78.07 56.68,78.07 56.78,77.97 56.78,77.13 56.88,77.03 57.29,77.03 57.39,77.13 57.39,77.97 57.49,78.07 57.9,78.07 58,77.97 58,77.13 58.1,77.03 58.51,77.03 58.61,77.13 58.61,77.97 58.71,78.07 59.12,78.07 59.22,77.97 59.22,77.43 59.4,77.25 63.4,77.25 63.5,77.14 63.5,76.48 63.6,76.38 64.01,76.38 64.11,76.48 64.11,77.14 64.21,77.25 64.7,77.25 65.85,76.1 68.97,76.1 69.37,75.7 v3(69.37,75.37)
RP_DDR4_DIMM2_I2C_SCL: length 5.4
  TOP w0.114: CONN8.253 48.63,37.95 v2(48.67,37.91)
  BOTTOM w0.114: v1(47.77,38.26) 48.32,38.26 v2(48.67,37.91) 48.72,37.86 R656.1
RP_DDR4_DIMM2_I2C_SDA: length 5.5
  TOP w0.114: v2(50.9,37.33) 51.12,37.54 52.27,37.54 52.43,37.7 CONN8.254
  BOTTOM w0.114: v1(52.76,38.76) 51.66,38.76 R649.1 51.03,37.45 v2(50.9,37.33)
RP_DDR4_DIMM2_MA0: length 44.4
  TOP w0.102: U9.CV60 76.99,64.98 76.37,65.59 73.11,65.59 72.78,65.93 71.8,65.93 v3(70.96,66.77)
  TOP w0.178: CONN8.144 52.74,67.2 51.85,66.31 50.95,66.31 50.4,65.76 v2(50.4,65.69)
  S3 w0.152: v2(50.4,65.69) 50.94,65.15 62.55,65.15 62.68,65.02 62.68,64.32 62.56,64.2 60.35,64.2 60.22,64.07 60.22,63.37 60.35,63.24 63.37,63.24 63.53,63.4 63.53,66.08 63.66,66.2 64.36,66.2 64.48,66.08 64.48,65.28 64.61,65.15 65.31,65.15 65.44,65.28 65.44,66.08 65.57,66.2 66.27,66.2 66.4,66.08 66.4,65.23 66.48,65.15 66.94,65.15 67.83,66.05 70.47,66.05 70.96,66.54 v3(70.96,66.77)
RP_DDR4_DIMM2_MA1: length 39.9
  TOP w0.102: v3(71.04,70.08) 71.87,69.25 76.9,69.25 77.08,69.43 U9.CU50
  TOP w0.178: v2(48.82,70.41) 48.82,70.4 48.08,69.66 47.33,69.66 47.03,69.95 CONN8.133
  S3 w0.152: v3(71.04,70.08) 71.04,69.7 70.84,69.49 68.28,69.49 67.55,70.23 60.78,70.23 60.28,70.73 59.56,70.73 59.41,70.58 59.41,70.33 59.25,70.18 58.9,70.18 58.74,70.33 58.74,70.58 58.59,70.73 56.64,70.73 55.31,69.41 54.38,69.41 54.23,69.56 54.23,70.31 54.08,70.46 53.72,70.46 53.57,70.31 53.57,69.56 53.42,69.41 53.06,69.41 52.91,69.56 52.91,70.31 52.76,70.46 52.4,70.46 52.25,70.31 52.25,69.56 52.1,69.41 49.82,69.41 v2(48.82,70.41)
RP_DDR4_DIMM2_MA2: length 41.1
  TOP w0.102: U9.CR50 78.54,69.43 78.21,69.1 77.71,69.1 77.58,69.23 77.16,69.23 76.99,69.05 71.08,69.05 70.28,69.85 v3(70.28,70.08)
  TOP w0.178: CONN8.132 51.69,70.2 v2(51.49,70.41)
  S5 w0.152: v2(51.49,70.41) 51.49,70.28 51.98,69.79 56.22,69.79 56.49,70.06 56.49,71.51 56.65,71.68 57.29,71.68 57.46,71.51 57.46,70.79 57.61,70.64 58.37,70.64 58.5,70.76 58.5,71.92 58.73,72.15 59.28,72.15 59.56,71.87 59.56,70.88 59.67,70.77 60.34,70.77 60.52,70.94 60.52,71.99 60.68,72.15 61.32,72.15 61.48,71.99 61.48,70.92 61.63,70.77 62.28,70.77 62.44,70.92 62.44,71.96 62.6,72.12 63.24,72.12 63.4,71.96 63.4,70.75 64.02,70.13 67.26,70.13 67.82,69.57 69.77,69.57 v3(70.28,70.08)
RP_DDR4_DIMM2_MA3: length 42.8
  TOP w0.102: v3(72.52,70.08) 73.14,69.46 76.82,69.46 77.01,69.65 77.47,69.65 77.56,69.65 77.67,69.76 78.38,69.76 U9.CT49
  TOP w0.178: CONN8.131 47.89,70.45 v2(47.94,70.41)
  S5 w0.152: v2(47.94,70.41) 47.06,70.41 46.37,71.09 45.01,71.09 44.7,70.79 44.7,69.55 44.95,69.3 56.59,69.3 56.77,69.49 67.19,69.49 67.72,68.96 70.46,68.96 70.85,69.36 71.79,69.36 v3(72.52,70.08)
RP_DDR4_DIMM2_MA4: length 43.6
  TOP w0.102: U9.CV49 76.92,69.93 76.67,69.67 74.45,69.67 v3(74.04,70.08)
  TOP w0.178: v2(49.71,70.41) 50.34,71.03 52.18,71.03 52.36,71.2 CONN8.128
  S5 w0.152: v2(49.71,70.41) 49.71,70.59 50.14,71.02 53.22,71.02 53.38,71.18 53.38,72.07 53.5,72.2 54.21,72.2 54.34,72.07 54.34,71.18 54.49,71.02 55.14,71.02 55.29,71.18 55.29,72.07 55.42,72.2 57.91,72.2 58.38,72.67 59.37,72.67 59.52,72.83 59.52,73.76 59.68,73.91 60.03,73.91 60.18,73.76 60.18,72.83 60.34,72.67 60.69,72.67 60.85,72.83 60.85,73.76 61,73.91 61.35,73.91 61.51,73.76 61.51,72.83 61.66,72.67 62.01,72.67 62.17,72.83 62.17,73.76 62.32,73.91 62.67,73.91 62.83,73.76 62.83,72.83 62.98,72.67 63.48,72.67 63.89,72.26 63.89,71.01 64.12,70.79 73.33,70.79 v3(74.04,70.08)
RP_DDR4_DIMM2_MA5: length 43.1
  TOP w0.102: U9.CR48 78.93,70.32 78.44,70.32 78.19,70.07 77.61,70.07 77.47,70.21 76.45,70.21 v3(76.33,70.08)
  TOP w0.178: v2(49.71,72.23) 50.34,71.61 51.94,71.61 52.04,71.71 53.38,71.71 CONN8.126
  S5 w0.152: v2(49.71,72.23) 49.71,71.83 49.98,71.56 52.17,71.56 53.3,72.69 57.63,72.69 58.15,73.2 58.65,73.2 58.84,73.39 58.84,75.02 59.36,75.54 59.88,75.54 60.03,75.39 60.03,75.29 60.18,75.13 60.54,75.13 60.69,75.29 60.69,75.39 60.84,75.54 61.2,75.54 61.35,75.39 61.35,75.29 61.5,75.13 61.86,75.13 62.01,75.29 62.01,75.39 62.16,75.54 63.02,75.54 64.03,74.52 64.03,73 64.45,72.59 64.45,71.72 64.72,71.45 73.66,71.45 73.9,71.21 76.91,71.21 77.08,71.03 77.08,70.42 76.74,70.08 v3(76.33,70.08)
RP_DDR4_DIMM2_MA6: length 43.6
  TOP w0.089: U9.CT47 78.38,70.75 77.91,70.75 77.8,70.64 76.85,70.64 76.59,70.89 72.82,70.89 v3(71.8,71.91)
  TOP w0.178: v2(48.82,72.23) 48.04,71.45 CONN8.127
  S3 w0.152: v2(48.82,72.23) 49.31,71.75 52.8,71.75 52.95,71.9 52.95,72.48 53.1,72.63 53.46,72.63 53.61,72.48 53.61,71.9 53.76,71.75 54.12,71.75 54.27,71.9 54.27,72.48 54.43,72.63 54.78,72.63 54.93,72.48 54.93,71.9 55.09,71.75 55.44,71.75 55.59,71.9 55.59,72.48 55.75,72.63 56.1,72.63 56.25,72.48 56.25,71.9 56.41,71.75 56.76,71.75 56.91,71.9 56.91,72.48 57.07,72.63 57.42,72.63 57.57,72.48 57.57,71.9 57.73,71.75 58.08,71.75 58.24,71.9 58.24,72.48 58.39,72.63 58.74,72.63 58.9,72.48 58.9,71.9 59.05,71.75 60.75,71.75 61.25,71.25 62.37,71.25 62.52,71.4 62.52,71.53 62.67,71.68 63.03,71.68 63.18,71.53 63.18,71.4 63.33,71.25 63.69,71.25 63.84,71.4 63.84,71.53 64,71.68 64.35,71.68 64.5,71.53 64.5,71.4 64.66,71.25 65.01,71.25 65.16,71.4 65.16,71.53 65.32,71.68 65.67,71.68 65.82,71.53 65.82,71.4 65.98,71.25 71.15,71.25 v3(71.8,71.91)
RP_DDR4_DIMM2_MA7: length 44.3
  TOP w0.089: U9.CR46 78.91,71.28 78.41,71.28 78.16,71.03 77.64,71.03 77.47,71.2 76.86,71.2 76.76,71.3 74.65,71.3 v3(74.04,71.91)
  TOP w0.178: CONN8.122 52.36,72.7 51.95,72.29 51.55,72.29 v2(51.49,72.23)
  S5 w0.152: v3(74.04,71.91) 74.04,72.14 73.71,72.47 65.35,72.47 64.62,73.2 64.62,74.68 62.6,76.7 61.76,76.7 61.6,76.54 61.6,76.25 61.45,76.1 61.1,76.1 60.94,76.25 60.94,76.54 60.79,76.7 60.44,76.7 60.28,76.54 60.28,76.25 60.13,76.1 59.78,76.1 59.62,76.25 59.62,76.54 59.47,76.7 57.63,76.7 57.42,76.49 57.42,75.88 57.64,75.67 58.11,75.67 58.34,75.43 58.34,73.88 58.16,73.7 57.47,73.7 57.3,73.88 57.3,74.5 57.12,74.68 56.52,74.68 56.34,74.49 56.34,73.4 56.14,73.2 55.54,73.2 55.38,73.36 55.38,74.59 55.22,74.75 54.58,74.75 54.42,74.59 54.42,73.36 54.27,73.2 53.01,73.2 52.04,72.23 v2(51.49,72.23)
RP_DDR4_DIMM2_MA8: length 43.3
  TOP w0.089: v3(72.54,71.9) 73.35,71.09 76.68,71.09 76.85,70.92 U9.CV47
  TOP w0.178: CONN8.125 46.2,71.95 46.21,71.96 46.22,71.96 46.42,72.16 46.42,72.17 46.48,72.23 v2(47.05,72.23)
  S3 w0.152: v3(72.54,71.9) 72.54,71.39 71.89,70.75 61.06,70.75 60.55,71.26 51.92,71.26 51.67,71.02 47.42,71.02 46.71,70.31 44.88,70.31 44.52,70.67 44.52,71.49 44.67,71.64 45.16,71.64 45.31,71.8 45.31,72.15 45.16,72.3 44.67,72.3 44.52,72.46 44.52,72.94 44.85,73.27 46.01,73.27 47.04,72.23 v2(47.05,72.23)
RP_DDR4_DIMM2_MA9: length 45
  TOP w0.102: v3(68.68,71.91) 68.68,72.3 68.91,72.53 76.89,72.53 77,72.41 77.24,72.41 77.65,72.01 78.45,72.01 U9.CT44
  TOP w0.178: v2(48.82,73.74) 48.04,72.95 CONN8.121
  S3 w0.152: v3(68.68,71.91) 68.22,72.37 64.61,72.37 63.27,73.7 62.03,73.7 61.88,73.55 61.88,72.39 61.72,72.24 61.37,72.24 61.22,72.39 61.22,73.55 61.06,73.7 60.71,73.7 60.56,73.55 60.56,72.39 60.4,72.24 60.05,72.24 59.9,72.39 59.9,73.55 59.74,73.7 59.26,73.7 59.11,73.55 59.11,73.33 58.96,73.18 58.6,73.18 58.45,73.33 58.45,73.55 58.3,73.7 57.94,73.7 57.79,73.55 57.79,73.33 57.63,73.18 57.28,73.18 57.13,73.33 57.13,73.55 56.97,73.7 56.49,73.7 56.34,73.55 56.34,73.38 56.19,73.23 55.83,73.23 55.68,73.38 55.68,73.55 55.53,73.7 55.17,73.7 55.02,73.55 55.02,73.38 54.87,73.23 54.51,73.23 54.36,73.38 54.36,73.55 54.21,73.7 53.85,73.7 53.7,73.55 53.7,73.38 53.55,73.23 53.19,73.23 53.04,73.38 53.04,73.55 52.88,73.7 52.32,73.7 51.55,72.92 48.69,72.92 48.51,73.1 48.51,73.5 48.75,73.74 v2(48.82,73.74)
RP_DDR4_DIMM2_MA10: length 43.8
  TOP w0.102: v3(74.8,64.98) 75.21,64.57 76.69,64.57 76.78,64.48 U9.CU61
  TOP w0.178: v2(52.02,65.64) 52.02,65.19 52.51,64.7 CONN8.146
  S5 w0.152: v3(74.8,64.98) 74.8,64.19 75.21,63.78 76.5,63.78 76.66,63.93 76.66,65.3 76.81,65.46 77.16,65.46 77.32,65.3 77.32,63.93 77.47,63.78 78.46,63.78 78.84,64.16 78.84,66.38 78.11,67.11 77.42,67.11 77.08,66.77 77.08,66.39 76.77,66.08 73.15,66.08 72.86,65.79 52.17,65.79 v2(52.02,65.64)
RP_DDR4_DIMM2_MA11: length 44.1
  TOP w0.089: U9.CU46 78.04,71.4 76.95,71.4 76.85,71.5 75.21,71.5 v3(74.8,71.91)
  TOP w0.178: CONN8.120 52,73.2 51.67,72.88 50.57,72.88 v2(49.71,73.74)
  S5 w0.152: v3(74.8,71.91) 74.8,72.47 74.31,72.96 69.07,72.96 68.92,73.11 68.92,73.46 68.77,73.61 68.41,73.61 68.26,73.46 68.26,73.11 68.11,72.96 67.75,72.96 67.6,73.11 67.6,73.46 67.45,73.61 67.09,73.61 66.94,73.46 66.94,73.11 66.79,72.96 65.68,72.96 65.23,73.41 65.23,77.14 64.19,78.18 62.48,78.18 62.33,78.03 62.33,77.9 62.17,77.75 61.82,77.75 61.67,77.9 61.67,78.03 61.51,78.18 61.16,78.18 61,78.03 61,77.9 60.85,77.75 60.5,77.75 60.34,77.9 60.34,78.03 60.19,78.18 59.84,78.18 59.68,78.03 59.68,77.9 59.53,77.75 59.18,77.75 59.02,77.9 59.02,78.03 58.87,78.18 58.52,78.18 58.36,78.03 58.36,77.9 58.21,77.75 57.86,77.75 57.7,77.9 57.7,78.03 57.55,78.18 56.82,78.18 51.74,73.1 50.35,73.1 v2(49.71,73.74)
RP_DDR4_DIMM2_MA12: length 34.9
  TOP w0.102: v3(70.28,71.91) 70.7,72.32 76.81,72.32 77.22,71.91 U9.CV44
  TOP w0.178: CONN8.119 46.76,73.45 v2(47.05,73.74)
  S3 w0.152: v2(47.05,73.74) 46.99,73.74 46.7,74.02 46.7,74.31 47,74.6 48.95,74.6 49.32,74.23 63.43,74.23 64.81,72.85 68.58,72.85 69.01,72.42 69.77,72.42 v3(70.28,71.91)
RP_DDR4_DIMM2_MA13: length 45.6
  TOP w0.102: v3(74.02,61.51) 74.48,61.98 76.61,61.98 76.87,61.73 77.75,61.73 78.03,62.01 U9.CT66
  TOP w0.178: CONN8.158 51.99,61.7 v2(51.49,61.21)
  S5 w0.152: v3(74.02,61.51) 73.51,61.01 68.12,61.01 67.86,60.74 67.3,60.74 67.05,60.48 67.05,59.37 66.93,59.26 66.25,59.26 66.09,59.42 66.09,60.97 65.92,61.14 65.28,61.14 65.13,60.99 65.13,59.42 64.97,59.26 64.33,59.26 64.17,59.42 64.17,60.95 64.01,61.12 63.36,61.12 63.22,60.97 63.22,59.42 63.06,59.26 62.42,59.26 62.26,59.42 62.26,60.72 62.1,60.88 61.46,60.88 61.3,60.72 61.3,59.42 61.14,59.26 60.5,59.26 60.34,59.42 60.34,60.62 60.18,60.78 59.54,60.78 59.38,60.62 59.38,59.42 59.22,59.26 58.58,59.26 58.43,59.41 58.43,60.42 58.25,60.6 56.43,60.6 56.28,60.76 56.28,61.04 56.13,61.19 55.77,61.19 55.62,61.04 55.62,60.76 55.47,60.6 52.09,60.6 v2(51.49,61.21)
RP_DDR4_DIMM2_MA14: length 43.4
  TOP w0.102: v3(68.99,64.99) 69.42,65.42 72.26,65.42 73.52,64.16 76.52,64.16 76.67,64.01 77.29,64.01 U9.CV62
  TOP w0.178: v2(47.05,63.51) 46.99,63.45 CONN8.151
  S5 w0.152: v2(47.05,63.51) 47.05,63.57 46.54,64.07 44.26,64.07 44.14,64.2 44.14,64.9 44.26,65.03 44.83,65.03 45.04,65.24 45.04,65.86 45.2,66.02 45.84,66.02 46,65.85 46,65.24 46.22,65.03 48.21,65.03 48.37,64.87 48.37,64.23 48.53,64.07 49.17,64.07 49.33,64.23 49.33,64.75 49.56,64.98 67.33,64.98 67.87,64.44 68.63,64.44 68.99,64.8 v3(68.99,64.99)
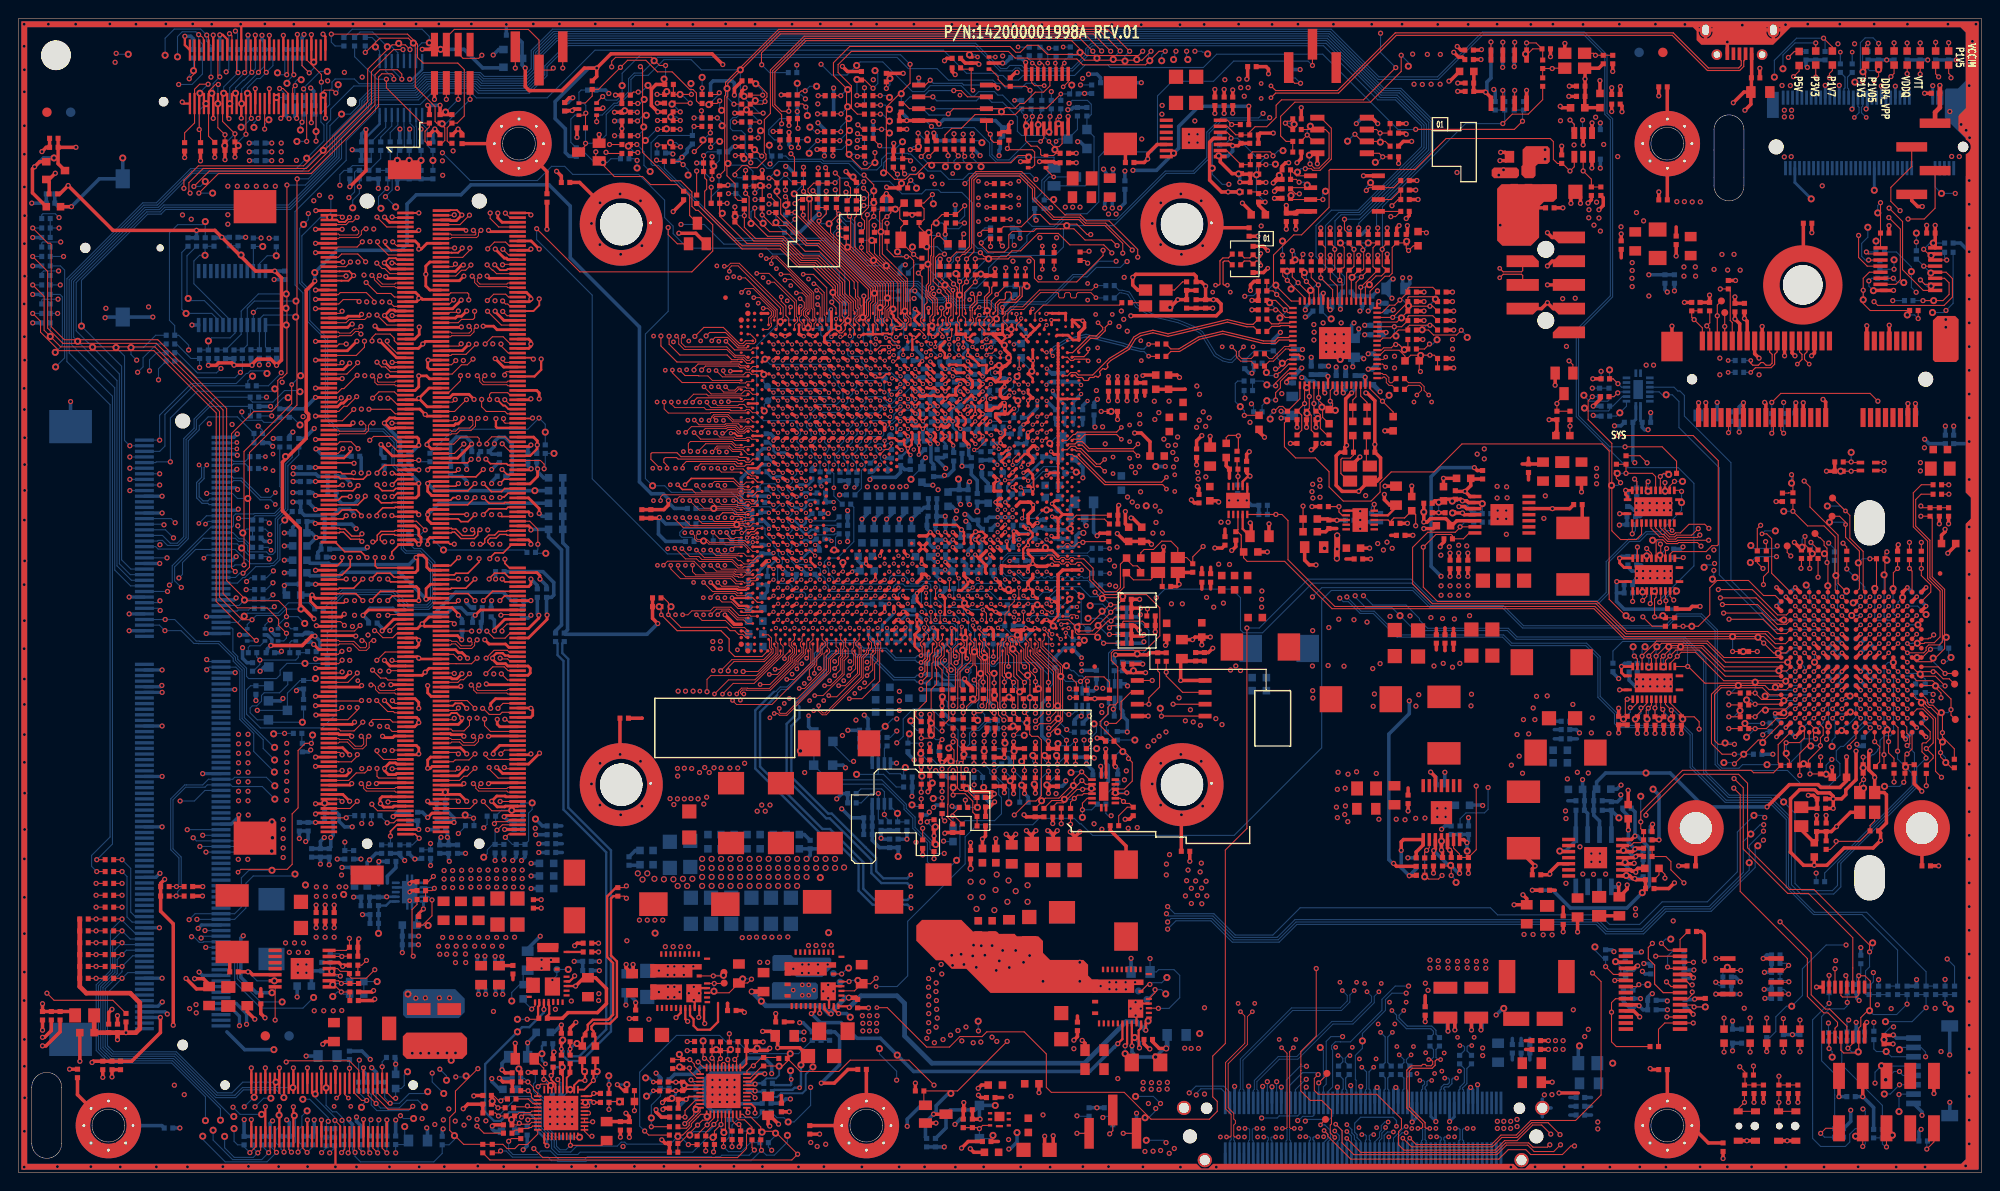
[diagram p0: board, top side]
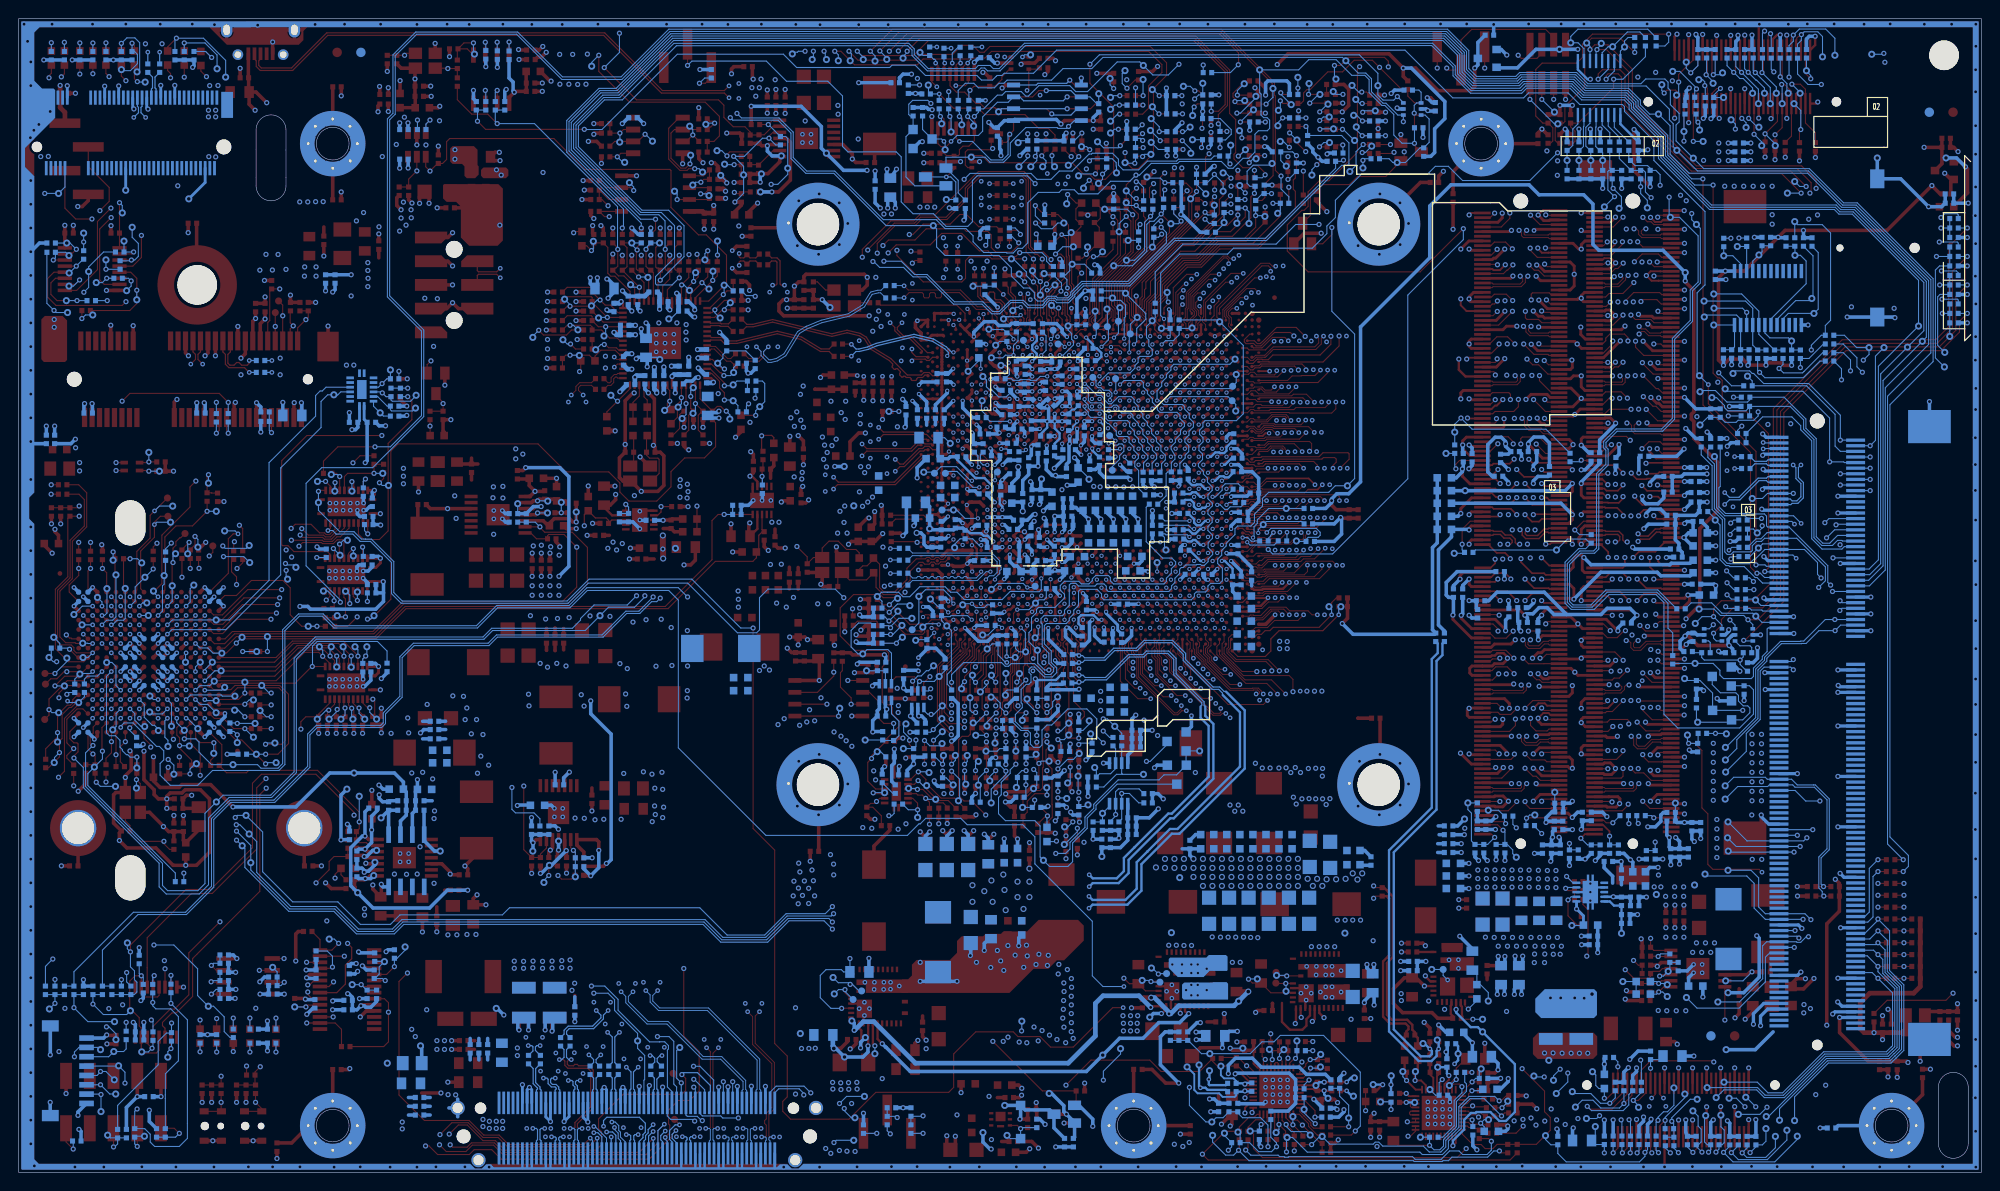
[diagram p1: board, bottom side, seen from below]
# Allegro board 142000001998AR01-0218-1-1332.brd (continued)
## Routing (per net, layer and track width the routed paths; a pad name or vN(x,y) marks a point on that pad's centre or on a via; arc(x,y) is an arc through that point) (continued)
RP_DDR4_DIMM2_MA15: length 44.3
  TOP w0.102: v3(74.8,63.15) 75.21,62.74 76.96,62.74 77.06,62.64 77.72,62.64 77.91,62.83 78.38,62.83 U9.CT64
  TOP w0.178: CONN8.156 50.71,62.2 v2(49.71,61.21)
  S3 w0.152: v2(49.71,61.21) 49.71,61.49 49.38,61.82 48.94,61.82 48.82,61.94 48.82,62.64 48.95,62.77 50.46,62.77 50.73,62.51 50.73,61.91 50.85,61.78 51.5,61.78 51.66,61.94 51.66,62.9 51.79,63.03 52.49,63.03 52.62,62.9 52.62,61.94 52.77,61.78 53.46,61.78 53.61,61.94 53.61,62.69 53.77,62.84 54.12,62.84 54.27,62.69 54.27,61.94 54.43,61.78 54.78,61.78 54.94,61.94 54.94,62.69 55.09,62.84 55.44,62.84 55.6,62.69 55.6,61.94 55.75,61.78 63.98,61.78 65.89,63.7 67.54,63.7 67.88,64.03 74.39,64.03 74.8,63.62 v3(74.8,63.15)
RP_DDR4_DIMM2_MA16: length 42.3
  TOP w0.102: U9.CT62 78.5,63.94 77.71,63.94 77.47,63.71 77.03,63.71 76.96,63.78 76.93,63.81 76.59,63.81 76.44,63.96 72.45,63.96 72.1,64.31 v3(72.1,65)
  TOP w0.178: CONN8.152 52.04,63.2 v2(51.73,63.51)
  S5 w0.152: v3(72.1,65) 70.58,63.48 67.17,63.48 67.02,63.64 67.02,64.34 66.87,64.49 66.51,64.49 66.36,64.34 66.36,63.64 66.21,63.48 65.85,63.48 65.7,63.64 65.7,64.34 65.55,64.49 65.19,64.49 65.04,64.34 65.04,63.64 64.89,63.48 64.53,63.48 64.38,63.64 64.38,64.34 64.22,64.49 63.87,64.49 63.72,64.34 63.72,63.64 63.56,63.48 63.21,63.48 63.06,63.64 63.06,64.34 62.9,64.49 62.55,64.49 62.4,64.34 62.4,63.64 62.24,63.48 61.89,63.48 61.74,63.64 61.74,64.34 61.58,64.49 61.23,64.49 61.08,64.34 61.08,63.64 60.92,63.48 60.57,63.48 60.41,63.64 60.41,64.34 60.26,64.49 59.91,64.49 59.75,64.34 59.75,63.64 59.6,63.48 59.25,63.48 59.09,63.64 59.09,64.34 58.94,64.49 58.59,64.49 58.43,64.34 58.43,63.64 58.28,63.48 56.73,63.48 56.21,64.01 52.23,64.01 v2(51.73,63.51)
RP_DDR4_DIMM2_ODT0: length 43.2
  TOP w0.102: U9.CV64 76.74,63 76.18,63.55 70.81,63.55 69.77,64.59 v3(69.77,64.98)
  TOP w0.178: v2(48.82,63.51) 47.85,62.54 46.29,62.54 46.21,62.45 CONN8.155
  S3 w0.152: v2(48.82,63.51) 48.03,62.71 46.61,62.71 46.3,63.02 46.3,64.08 46.71,64.49 49.54,64.49 49.85,64.18 56.07,64.18 56.26,63.99 56.26,62.65 56.64,62.27 63.78,62.27 65.69,64.18 67.34,64.18 67.65,64.49 69.29,64.49 v3(69.77,64.98)
RP_DDR4_DIMM2_ODT1: length 40.8
  TOP w0.102: v3(74.8,61.51) 75.26,61.06 76.28,61.06 76.97,60.36 77.61,60.36 77.78,60.19 78.2,60.19 78.54,60.52 U9.CR69
  TOP w0.178: v2(47.05,61.21) 46.79,60.95 CONN8.161
  S5 w0.152: v3(74.8,61.51) 74.8,60.93 74.32,60.45 68.37,60.45 67.55,59.63 67.55,59.11 67.22,58.77 58.2,58.77 56.82,60.14 54.37,60.14 54.1,59.87 52.6,59.87 52.32,60.14 45.95,60.14 45.66,60.44 45.66,61 45.86,61.21 v2(47.05,61.21)
RP_DDR4_DIMM2_R_EVENT_L: length 6.2
  TOP w0.114: CONN8.134 54.69,69.7 55.55,68.84 v2(55.55,67.23)
  BOTTOM w0.114: v1(56.4,66.27) 55.39,66.27 R574.1 55.55,66.62 v2(55.55,67.23)
RP_DDR4_DIMM2_R_RST_L: length 6.1
  TOP w0.114: CONN8.108 55.84,76.2 56.22,75.81 v2(56.22,75.31)
  BOTTOM w0.114: v2(56.22,75.31) 56.34,75.44 R546.1 v1(57.28,76.96)
RP_DDR4_DIMM2_SA0: length 7
  TOP w0.114: v2(51.18,36.63) 51.75,37.2 CONN8.256
  BOTTOM w0.114: v2(51.18,36.63) 50.97,36.42 R678.1 ; R678.1 50.72,35.1 50.14,34.52 50.14,34.11 v1(49.76,33.73) ; R678.1 R679.1
RP_DDR4_DIMM2_SA1: length 9.7
  TOP w0.114: CONN8.260 52.42,36.2 v2(52.07,35.85)
  BOTTOM w0.114: R680.1 v1(54.94,39.55) 54.94,38.84 54.56,38.46 54.56,35.48 R681.1 R880.1 52.82,35.1 v2(52.07,35.85)
RP_DDR4_DIMM2_SA2: length 63.1
  TOP w0.114: CONN8.166 51.65,59.7 v2(51.59,59.64)
  S3 w0.102: v2(51.59,59.64) 50.88,60.35 37.92,60.35 37.64,60.63 31.86,60.63 30.45,59.23 30.45,36.84 32.47,34.82 34.4,34.82 34.99,34.24 43.1,34.24 v2(44.07,35.2)
  BOTTOM w0.114: R688.1 R689.1 v2(44.07,35.2)
RP_DDR4_DMIM2_PAR: length 44.9
  TOP w0.102: U9.CR59 78.88,65.32 78.39,65.32 78.2,65.12 77.61,65.12 77.24,65.48 77.01,65.48 76.7,65.8 73.37,65.8 72.55,66.61 v3(72.52,66.61)
  TOP w0.178: v2(46.61,67.25) 46.15,67.25 45.94,67.45 CONN8.143
  S5 w0.152: v3(72.52,66.61) 72.15,66.25 48.78,66.25 48.53,66.5 47.84,66.5 47.56,66.78 47.56,67.98 46.72,68.83 46.08,68.83 45.93,68.68 45.93,68.03 45.77,67.87 45.42,67.87 45.27,68.01 45.27,68.68 45.12,68.83 44.64,68.83 44.3,68.49 44.3,66.98 44.66,66.61 45.97,66.61 v2(46.61,67.25)
RP_DDR4_I2C_SCL: length 101.2
  S10 w0.102: v2(36.71,37.35) 37.3,36.75 39.78,36.75 41.61,38.58 44.09,38.58 46.41,36.27 v2(47.04,36.27) 47.04,35.92 45.03,33.91 45.03,33.12 44.24,32.33 43.75,32.33 43.19,31.78 43.19,29.08 45.15,27.13 52.83,27.13 54.18,25.78 54.18,22.26 55.28,21.16 56.36,21.16 56.79,21.59 60.15,21.59 60.87,20.88 62.59,20.88 67.26,25.55 72.26,25.55 73.4,26.7 83.06,26.7 84.15,25.6 89.2,25.6 90.65,27.05 90.65,35.59 93.17,38.1 93.17,39.37 v2(91.98,40.56)
  BOTTOM w0.114: R656.2 47.81,37.04 v2(47.04,36.27) ; R647.2 36.86,37.5 v2(36.71,37.35) ; R877.2 90.14,39.55 91.15,40.56 v2(91.98,40.56) U36.7 91.98,37.81 R657.2
RP_DDR4_I2C_SDA: length 102.3
  S10 w0.102: v2(92.63,38.3) 90.42,36.1 90.42,27.18 89.08,25.83 84.24,25.83 83.15,26.92 73.3,26.92 72.16,25.78 67.16,25.78 62.49,21.11 60.96,21.11 60.25,21.82 56.69,21.82 56.26,21.39 55.37,21.39 54.41,22.35 54.41,25.88 52.93,27.36 45.24,27.36 43.42,29.18 43.42,30.59 43.85,31.02 44.56,31.02 44.96,31.42 44.96,32.72 45.26,33.03 45.26,33.43 47.27,35.43 48.31,35.43 v2(49.76,36.88) 48.08,36.88 46.66,38.3 45.14,38.3 44.4,39.04 39.42,39.04 v2(37.71,37.33)
  BOTTOM w0.114: v2(49.76,36.88) 50.12,37.24 R649.2 ; R878.2 90.12,41.05 92.33,41.05 92.63,40.75 U36.6 v2(92.63,38.3) 92.63,38.14 93.16,37.61 R658.2 ; R648.2 37.76,37.38 v2(37.71,37.33)
RP_DDR4_R_0_I2C_SCL: length 2.9
  TOP w0.114: CONN7.253 v2(35.05,37.95)
  BOTTOM w0.114: R647.1 35.28,38.18 v2(35.05,37.95)
RP_DDR4_R_0_I2C_SDA: length 3.2
  TOP w0.114: v2(39.43,37.41) 40.13,37.41 40.42,37.7 CONN7.254
  BOTTOM w0.114: v2(39.43,37.41) 38.67,38.18 R648.1
RP_DDR_I2C_EN: length 3.3
  BOTTOM w0.114: U36.5 93.28,39.18 v1(94.03,38.43) 94.03,37.53 R659.2 R879.2
RP_DDR_I2C_SCL: length 8.7
  BOTTOM w0.114: 91.87,42.61 v1(89.65,42.61) ; 91.87,42.61 92.54,42.61 93.89,41.25 R638.2 ; 91.87,42.61 91.98,42.71 U36.2 91.98,45.64 R621.2
RP_DDR_I2C_SDA: length 6.1
  BOTTOM w0.114: v1(94.87,43.33) 94.69,43.16 R633.2 94.34,42.67 93.17,42.67 92.63,43.21 U36.3 92.63,45.36 R622.2
RP_DDR_R_I2C_SCL: length 29.6
  TOP w0.114: U9.CD58 v4(84.23,65.45)
  S10 w0.102: v4(84.23,65.45) 84.23,66.15 84.81,66.73 88.39,66.73 91.08,64.03 91.08,63.21 91.55,62.74 91.55,62.43 91.08,61.96 91.08,59.77 91.55,59.31 91.55,59.18 92.29,58.43 92.29,57.56 92.89,56.96 92.89,49.61 v2(93.95,48.54)
  BOTTOM w0.114: R621.1 91.97,47 v1(92.72,47.75) 93.51,48.54 v2(93.95,48.54)
RP_DDR_R_I2C_SDA: length 29.2
  TOP w0.114: U9.CC60 v4(84.73,64.59)
  S10 w0.102: v2(93.95,47.24) 92.41,48.79 92.41,56.95 91.3,58.05 91.3,58.43 90.63,59.11 90.63,59.51 90.29,59.85 90.29,60.17 90.63,60.5 90.63,61.23 90.29,61.57 90.29,61.88 90.63,62.22 90.63,62.95 90.29,63.28 90.29,64.27 88.09,66.47 85.04,66.47 84.73,66.16 v4(84.73,64.59)
  BOTTOM w0.114: R622.1 93.27,46.56 v2(93.95,47.24)
RP_JTAG_R_CPU_TCK: length 12
  TOP w0.102: 106.4,56.18 106.4,56.92 U9.T76
  TOP w0.114: 106.4,56.18 107.04,55.55 107.04,53.74 107.73,53.04 107.86,53.04 108.21,52.7 108.21,52.21 108.2,52.2 108.2,49.66 107.86,49.32 107.72,49.32 107.62,49.23 ; 107.62,49.23 107.98,48.87 R255.1 ; 107.62,49.23 v2(107.61,49.23)
  BOTTOM w0.114: v2(107.61,49.23) 107.62,49.22 107.96,49.22 108.2,49.46 v1(108.2,50.8)
RP_JTAG_R_CPU_TDI: length 5.3
  TOP w0.114: U9.V78 105.28,54.48 105.23,54.43 105.23,53.16 105.46,52.93 v2(105.46,52.48) R248.1
  BOTTOM w0.114: v2(105.46,52.48) 105.92,52.93 v1(105.92,53.21)
RP_JTAG_R_CPU_TDO: length 5.7
  TOP w0.114: U9.T78 106.78,55.31 106.78,53.29 v2(107.62,52.45) 107.49,52.32 R243.2
  BOTTOM w0.114: v2(107.62,52.45) 107.95,52.78 v1(107.95,53.21)
RP_JTAG_R_CPU_TMS: length 7.7
  TOP w0.102: U9.R75 106.91,57.41 106.91,56.91 107.11,56.71 107.11,56.43 107.54,56 107.54,54.94
  TOP w0.114: 107.54,54.94 108.15,54.33 108.15,53.71 108.79,53.07 v2(108.79,52.53) R242.1
  BOTTOM w0.114: v2(108.79,52.53) 109.12,52.2 v1(109.12,51.77)
RP_JTAG_R_CPU_TRST_L: length 8
  TOP w0.102: U9.U75 105.64,57.42 105.64,56.93 105.38,56.67 105.38,56.31 105.56,56.13 105.56,54.43
  TOP w0.114: 105.56,54.43 105.49,54.36 105.49,53.42 v2(106.45,52.45) 106.32,52.32 R246.2
  BOTTOM w0.114: v2(106.45,52.45) 106.45,52.12 107.1,51.47 v1(107.1,51.43)
RP_JTAG_TCK_PCH: length 21.8
  TOP w0.102: 89.31,90.85 89.31,91.38 89.72,91.79 89.72,92.33 89.55,92.5
  TOP w0.114: U9.BM3 89.31,90.85 ; 89.55,92.5 89.55,93.28 88.9,93.93 88.9,95.38 85.67,98.6 84.14,98.6 82.05,100.7 80.34,100.7 78.76,102.28 v2(78.76,103.23)
  BOTTOM w0.114: v1(78.36,101.57) 78.36,102.83 v2(78.76,103.23) R476.2
RP_JTAG_TDI_PCH: length 20.2
  TOP w0.114: U9.BM5 89.44,90.23 88.59,91.07 88.59,91.51 88.82,91.74 88.82,93.01 87.88,93.95 87.88,95.12 85.38,97.62 83.74,97.62 81.67,99.69 78.67,99.69 R116.1
RP_JTAG_TDO_PCH: length 22.4
  TOP w0.102: 90.35,90.8 90.35,91.41 90.72,91.78 90.72,93.37
  TOP w0.114: U9.BK3 90.35,90.8 ; v2(80.29,106.43) 80.62,106.43 R88.2 81.13,104.54 81.53,104.14 81.53,102.6 84.37,99.76 85.66,99.76 90.91,94.51 90.91,93.55 90.72,93.37
  BOTTOM w0.114: v2(80.29,106.43) 80.86,106.99 v1(81.13,106.99)
RP_JTAG_TMS_PCH: length 15.3
  TOP w0.102: U9.BJ2 91.14,91.43 91.14,92.96 91.41,93.24
  TOP w0.114: R106.1 83.87,102.55 v2(83.95,102.48) 83.95,102.15 91.41,94.69 91.41,93.24
RP_LAN_MDIO_DIR_CTL_0: length 9.9
  TOP w0.114: v4(111.51,57.07) 111.11,57.47 U9.E75 ; R232.1 v2(116.08,56.64)
  S8 w0.102: v2(116.08,56.64) 115.65,57.07 v4(111.51,57.07)
  BOTTOM w0.114: R597.1 v2(116.08,56.64) 116.08,56.73 115.53,57.28 v1(115.44,57.28)
RP_LAN_MDIO_DIR_CTL_1: length 22.6
  TOP w0.114: R296.1 v2(111.15,42.95) ; U9.N72 v4(107.51,60.02)
  S10 w0.102: v4(107.51,60.02) 107.59,59.94 107.59,59.03 108.15,58.47 108.15,57.94 110.67,55.42 110.67,43.43 v2(111.15,42.95)
  BOTTOM w0.114: v2(111.15,42.95) R296.1 110.77,42.24 v1(110.01,41.48)
RP_LAN_NCSI_ARB_OUT: length 11.5
  TOP w0.114: U9.AB78 103.31,55.82 103.64,55.5 103.64,53.54 103.91,53.27 103.91,50.23 103.82,50.14 103.82,49.47 104.11,49.17 v2(104.37,49.17) 104.47,49.08 R251.1 R245.1
  BOTTOM w0.114: v1(105.96,50.87) 105.94,50.85 105.59,50.85 104.98,50.24 104.98,49.78 v2(104.37,49.17)
RP_LAN_NCSI_TX0: length 6.1
  TOP w0.114: U9.W77 104.72,56.5 104.72,54.86 104.44,54.58 v3(104.27,54.58)
  BOTTOM w0.114: v1(106.38,56.03) 105.84,56.57 R596.1 105.21,55.4 104.39,54.58 v3(104.27,54.58)
RP_LAN_NCSI_TX1: length 2.9
  TOP w0.114: U9.Y78 v3(104.29,55.22)
  BOTTOM w0.114: v1(103.38,55.12) 104.19,55.12 v3(104.29,55.22) 104.27,55.24 R595.1
RP_LAN_NCSI_TX_EN: length 6
  TOP w0.114: v4(102.78,58.31) 102.78,58.07 103.31,57.55 U9.AA75
  BOTTOM w0.114: v4(102.78,58.31) 102.29,57.81 102.29,55.74 v1(102.26,55.72) 102.98,55.72 103.33,56.06 R594.1
RP_LAN_XTAL_I: length 17.3
  TOP w0.114: R207.1 120.04,64.57 119.68,64.92 119.23,64.92 118.54,65.61 R205.1 117.88,65.1 117.88,62.59 117.45,62.15 116.26,62.15 114.96,63.45 114.96,64.67 113.96,65.67 113,65.67 112.85,65.82 112.56,65.82 112.55,65.81 112.36,65.62 112.06,65.62 111.86,65.82 111.57,65.82 111.36,65.61 111.08,65.61 110.84,65.85 110.84,65.88 110.63,66.09 110.14,66.09 109.78,65.73 U9.J58
RP_LAN_XTAL_O: length 18
  TOP w0.114: U9.F58 110.86,65.35 111.34,65.35 111.57,65.12 111.86,65.12 112.07,65.33 112.35,65.33 112.58,65.1 113.06,65.1 113.26,65.3 113.66,65.3 114.6,64.36 114.6,63.4 116.15,61.85 117.48,61.85 118.26,62.63 118.26,63.96 118.49,64.19 R207.2 119.28,63.42 121.11,63.42 OSC5.3 122.35,63.77 C108.1
RP_LAN_XTAL_R_I: length 10.5
  TOP w0.114: R205.2 120.07,66.33 120.41,66.67 121.41,66.67 122.3,67.57 123.29,67.57 124.03,66.83 OSC5.1 124.96,65.82 C103.1 125.63,65.89 v2(126.73,67)
RP_LPC_LAD0: length 380.5
  TOP w0.114: v2(182.3,60.78) 186.06,60.78 188.17,58.67 189.15,58.67 U12.D2 ; v2(118.14,98.4) 118.14,99.44 116.2,101.37 114.05,101.37 113.42,102 110.68,102 108.47,104.21 108.47,105.26 107.08,106.65 102.62,106.65 102.21,106.23 102.21,98.56 v2(101.42,97.76) R138.1
  TOP w0.127: U17.26 v2(179.2,22.49)
  S3 w0.102: v2(179.2,22.49) 175.9,19.18 175.9,16.45 183.25,9.09 200.43,9.09 v2(201.19,8.33)
  S5 w0.102: v2(15.08,74.78) 15.08,75.68 11.42,79.35 11.15,79.62 11.15,114.56 16.75,120.17 16.94,120.17 23.75,120.17 24.38,120.8 28.69,120.8 28.73,120.83 34.44,120.83 35,121.39 98.04,121.39 103.07,116.36 103.07,109.93 103.78,109.22 103.78,108.12 101.98,106.32 101.98,100.25 101.42,99.69 v2(101.42,97.76)
  S10 w0.102: v2(179.2,22.49) 179.2,24.52 182.88,28.21 182.88,39.69 181.97,40.6 181.97,60.45 v2(182.3,60.78) 182.55,61.04 182.55,74.78 165.89,91.44 165.89,93.48 164.96,94.41 162.69,94.41 158.3,98.81 153.21,98.81 142.75,109.27 132.71,109.27 130.5,107.06 122.85,107.06 118.92,103.13 118.92,99.19 v2(118.14,98.4)
  BOTTOM w0.114: v1(201.19,6.5) v2(201.19,8.33) 201.23,8.37 CONN15.7 ; CONN14.14 v2(15.08,74.78)
RP_LPC_LAD1: length 385.2
  TOP w0.114: R137.1 v2(100.48,97.76) 100.99,98.27 101.25,98.27 101.97,98.99 101.97,106.33 102.52,106.89 107.18,106.89 108.71,105.36 108.71,104.31 110.77,102.25 113.51,102.25 114.15,101.61 116.3,101.61 119.15,98.76 v2(119.15,98.73) ; U12.D1 188.29,59.11 185.9,61.49 v2(182.08,61.49)
  TOP w0.127: v2(179.07,20.07) 178.87,20.07 178.4,20.54 U17.23
  S3 w0.102: v2(179.07,20.07) 178.82,20.07 178.49,19.74 178.49,15.71 184.37,9.83 198.26,9.83 198.44,10.01 200.61,10.01 v2(201.24,9.37)
  S5 w0.102: v2(100.48,97.76) 100.48,99.08 101.75,100.36 101.75,106.41 103.56,108.22 103.56,109.12 102.84,109.83 102.84,116.26 97.95,121.16 35.09,121.16 34.53,120.6 28.82,120.6 28.79,120.57 24.47,120.57 23.84,119.94 16.85,119.94 11.38,114.47 11.38,79.71 11.51,79.58 11.51,79.58 15.8,75.29 15.8,72.19 15.54,71.92 12.3,71.92 11.44,72.79 11.44,73.72 v2(11.89,74.18)
  S10 w0.102: v2(119.15,98.73) 119.15,103.04 122.87,106.76 132.98,106.76 134.99,108.76 139.48,108.76 142.82,105.41 142.82,104.4 145.92,101.3 145.92,100.2 146.35,99.77 150.55,99.77 156.54,93.78 163.54,93.78 164.03,93.28 164.03,92.91 182.32,74.63 182.32,61.73 v2(182.08,61.49) 181.74,61.15 181.74,40.51 182.65,39.59 182.65,28.3 178.74,24.39 178.74,20.27 178.94,20.07 v2(179.07,20.07)
  BOTTOM w0.114: CONN15.6 v2(201.24,9.37) 200.26,8.38 v1(199.62,8.38) ; CONN14.16 v2(11.89,74.18)
RP_LPC_LAD2: length 378.7
  TOP w0.114: v2(182.42,59.87) 186.51,59.87 188.27,58.11 U12.E1 ; v2(116.97,98.42) 116.1,99.29 112.47,99.29 111.24,100.51 109.08,100.51 107.21,98.65 106.28,98.65 105.66,98.02 103.32,98.02 v2(102.9,98.45)
  TOP w0.127: v2(179.07,19.3) 179.07,19.05 178.6,18.58 U17.20
  S3 w0.102: v2(179.07,19.3) 179.07,19.05 178.71,18.69 178.71,15.8 183.72,10.79 v2(201.24,10.79)
  S5 w0.102: v2(102.9,98.45) 103.97,98.45 104.44,98.92 104.44,112.4 103.53,113.32 103.53,116.54 98.23,121.84 34.81,121.84 34.25,121.28 28.54,121.28 28.5,121.25 24.19,121.25 23.56,120.62 16.56,120.62 10.69,114.75 10.69,78.33 11.78,77.24 11.88,77.24 14.2,74.92 14.2,74.46 v2(15.08,73.58)
  S10 w0.102: v2(116.97,98.42) 115.62,99.77 115.62,107.58 116.98,108.94 130.86,108.94 132.26,110.34 143.41,110.34 146.81,106.93 152.15,106.93 153.24,105.84 158.96,105.84 167.26,97.55 167.26,90.45 182.8,74.91 182.8,60.25 v2(182.42,59.87) 182.19,59.64 182.19,40.7 183.11,39.78 183.11,28.02 180.95,25.86 180.95,20.34 179.92,19.3 v2(179.07,19.3)
  BOTTOM w0.114: R506.1 99.47,97.16 99.64,97.16 100.02,97.53 100.02,97.96 100.51,98.45 v2(102.9,98.45) ; v1(199.77,9.91) 200.66,10.79 v2(201.24,10.79) 201.24,10.74 201.62,10.37 CONN15.5 ; CONN14.18 v2(15.08,73.58)
RP_LPC_LAD3: length 385.1
  TOP w0.114: v2(116.03,98.7) 116.03,98.14 113.21,95.32 109.08,95.32 108.69,95.71 108.69,97.61 108.29,98.01 106.1,98.01 105.87,97.78 103.26,97.78 103.25,97.79 v2(102.36,97.79) R139.1 ; v2(183.01,59.21) 186.64,59.21 188.17,57.67 189.15,57.67 U12.E2
  TOP w0.127: U17.17 v2(176.35,16.63)
  S3 w0.102: v2(176.35,16.63) 183.44,9.55 v2(198.63,9.55)
  S5 w0.102: v2(11.89,72.98) 15.13,72.98 15.54,73.39 15.54,73.77 15.12,74.19 15.02,74.19 14.43,74.79 14.43,76.02 10.92,79.52 10.92,114.66 16.66,120.4 17.04,120.4 23.65,120.4 24.28,121.03 28.6,121.03 28.63,121.06 34.34,121.06 34.9,121.62 98.14,121.62 103.3,116.45 103.3,110.02 104.01,109.31 104.01,108.03 102.21,106.22 102.21,100.13 102.03,99.95 102.03,98.11 v2(102.36,97.79)
  S10 w0.102: v2(116.03,98.7) 115.39,99.34 115.39,107.68 116.96,109.24 130.58,109.24 131.9,110.57 146.3,110.57 149.43,107.44 152.27,107.44 153.44,106.27 158.86,106.27 167.53,97.6 167.53,90.56 183.03,75.06 183.03,59.23 v2(183.01,59.21) 182.42,58.62 182.42,40.79 183.36,39.85 183.36,20.21 179.62,16.46 176.53,16.46 v2(176.35,16.63)
  BOTTOM w0.114: CONN14.20 v2(11.89,72.98) ; CONN15.4 199.35,11.37 v1(199.31,11.4) 198.63,10.72 v2(198.63,9.55)
RP_LPC_LCLK: length 3.8
  TOP w0.109: v4(103.56,89.18) 103.32,89.18 U9.AC7
  BOTTOM w0.114: v4(103.56,89.18) 103.56,89.31 104.11,89.86 R522.1 104.63,90.22 106.16,90.22 v1(106.19,90.25)
RP_LPC_R_LAD0: length 9.3
  TOP w0.114: U9.AF3 101.32,91.39 100.97,91.74 100.97,94.87 v2(101.42,95.32) R138.2
  BOTTOM w0.114: v2(101.42,95.32) 101.49,95.32 102.18,96.01 102.18,96.39 103.58,97.79 v1(103.78,97.79)
RP_LPC_R_LAD1: length 7.7
  TOP w0.114: U9.AG4 100.68,90.36 100.68,90.86 100.46,91.08 100.46,91.51 100.66,91.71 100.66,95.33 v2(100.69,95.35) 100.48,95.56 R137.2
  BOTTOM w0.114: v2(100.69,95.35) 101.52,96.19 v1(101.52,96.52)
RP_LPC_R_LAD2: length 7.4
  TOP w0.114: U9.AL3 99.21,90.84 99.21,91.52 98.99,91.74 98.99,92.13 99.26,92.41 99.26,93.55 v2(98.48,94.34)
  BOTTOM w0.114: v1(100.28,96.22) 100.13,96.07 R506.2 98.42,95.2 98.42,94.39 v2(98.48,94.34)
RP_LPC_R_LAD3: length 5.7
  TOP w0.114: U9.AF1 101.32,92.31 101.22,92.4 101.22,94.18 v2(102.36,95.32) R139.2
  BOTTOM w0.114: v1(102.95,96.16) 102.95,95.91 v2(102.36,95.32)
RP_LPC_R_LCLK: length 2.7
  TOP w0.108: U9.AA9 103.81,88.31 v4(104.05,88.31)
  BOTTOM w0.114: v4(104.05,88.31) 104.27,88.54 R522.2 105.05,88.95 v1(105.46,88.54)
RP_MS_INT1_R_L: length 30.8
  TOP w0.114: v4(91.66,88.63) 91.45,88.63 U9.BH7 ; R13.1 v2(87.96,115.26)
  S10 w0.102: v2(87.96,115.26) 89.23,113.99 89.23,109.51 89.26,109.49 89.26,102.77 89.36,102.67 89.36,102.13 89.1,101.88 89.1,98.72 91.29,96.54 91.29,89 v4(91.66,88.63)
  BOTTOM w0.114: v2(87.96,115.26) 88.61,115.91 v1(88.7,115.91)
RP_OSC 25MHZ_I: length 10.5
  TOP w0.114: U9.K2 108.74,91.95 109.63,92.84 117.78,92.84 R1096.1
RP_OSC 25MHZ_O: length 1.8
  TOP w0.114: R1096.2 120.22,93.09 OSC2.3
RP_PROCHOT_L: length 17.9
  TOP w0.108: U9.AG71 v4(100.58,60.01)
  TOP w0.114: R265.1 v2(103.31,46.12)
  S8 w0.102: v4(100.58,60.01) 100.9,60.01 101.47,59.44 101.47,56.62 102.08,56.01 102.08,53.37 101.73,53.01 101.73,48.41 102.69,47.45 102.69,46.74 v2(103.31,46.12)
  BOTTOM w0.114: v1(103.31,45.09) v2(103.31,46.12)
RP_PWR_ADDR_POT: length 4.1
  TOP w0.114: C255.2 77.25,4.95 v2(77.06,5.13) 76.76,5.13 76.41,5.48 U28.18
  BOTTOM w0.114: v2(77.06,5.13) 77.25,4.95 C255.2 v1(78.23,4.41)
RP_REFCLK14IN: length 6.5
  TOP w0.108: v4(103.56,87.48) 103.76,87.68 104.17,87.68 U9.W9
  BOTTOM w0.114: v1(105.92,87.2) 104.7,87.2 104.42,87.48 v4(103.56,87.48) 103.56,88.52 103.07,89 103.07,89.79 R519.1
RP_RSMRST_CPU_R_L: length 13.1
  TOP w0.102: U9.R77 106.76,56.74 106.62,56.88 106.62,57.18 106.4,57.4 106.12,57.4 105.93,57.21 105.93,56.91 106.12,56.72 106.12,56.34 105.98,56.2 105.98,55.65 106.48,55.16
  TOP w0.114: R253.1 106.96,48.67 v2(106.45,49.17) 106.91,49.64 106.91,52.64 106.48,53.08 106.48,55.16
  BOTTOM w0.114: v1(107.87,48.11) 107.52,48.11 v2(106.45,49.17)
RP_RTC_X1: length 16.8
  TOP w0.114: v2(97.76,104.67) 96.85,103.76 R100.2 96.88,103.15 96.88,102.01 96.55,101.68 C39.1 96.34,101.22 96.88,100.68 X1.1 97.33,99.37 97.33,95.17 97.11,94.95 97.11,94.42 97.07,94.38 97.07,93.68 97.19,93.56 97.19,93.1 96.93,92.84 96.93,91.28 U9.AT2
  BOTTOM w0.114: v1(97.87,103.68) 97.76,103.78 v2(97.76,104.67)
RP_RTC_X2: length 7.3
  TOP w0.114: U9.AT4 96.86,90.72 96.51,91.07 96.51,91.39 96.67,91.54 96.67,95.87 v2(96.27,96.27) 96.65,96.65 R146.1
RP_RTC_X2_R: length 8.7
  TOP w0.114: R146.2 96.17,97.86 v2(95.76,98.27) 95.73,98.27 94.38,99.62 X1.2 94.38,101.16 C38.1 94.71,101.68 94.27,102.12 94.27,103.29 R100.1
  BOTTOM w0.114: v2(95.76,98.27) 95.63,98.4 v1(95.63,99.06)
RP_SPI_IO2: length 2.1
  TOP w0.114: v4(92.63,83.5) 92.37,83.76 U9.BF18
  BOTTOM w0.114: v4(92.63,83.5) 92.61,83.52 92.61,84.94 TP21.1
RP_SPI_IO3: length 4.6
  TOP w0.114: v4(93.24,82.66) 92.89,82.66 U9.BE20
  BOTTOM w0.114: TP22.1 94.73,84.76 94.73,84.22 94.5,84 94.2,84 93.93,83.72 93.34,83.72 93.03,83.41 93.03,83.08 93.24,82.88 v4(93.24,82.66)
RP_SPI_LAN_HOLD: length 6.5
  TOP w0.114: R235.1 v2(122.79,53.54) 122.79,53.13 124.54,51.38 U16.7
RP_SPI_LAN_WP: length 6.4
  TOP w0.114: U16.3 v2(120.93,50.11) 120.93,50.8 122.07,51.94 122.07,53.49 121.87,53.69 R234.1
RP_SSD_LED_A: length 110.9
  S5 w0.102: v2(195.53,24.33) 195.78,24.59 203.28,24.59 206.07,27.38 206.07,38.56 204.85,39.78 204.85,42.24 207.81,45.2 207.81,104.2 v2(207.21,104.79)
  BOTTOM w0.114: CONN13.10 205.05,105.48 v1(205.74,104.79) v2(207.21,104.79) ; R716.2 187.37,14.42 188.01,15.06 188.01,16.64 189.15,17.78 v1(189.71,17.78) 190.86,18.92 190.86,21.79 193.4,24.33 v2(195.53,24.33)
RP_SSD_LED_C: length 2.4
  TOP w0.114: LED15.C v2(187.04,16.51)
  BOTTOM w0.114: v2(187.04,16.51) LED15.C
RP_STBY_1.05V_R: length 4
  TOP w0.114: CONN11.44 v2(35.39,11.14)
  BOTTOM w0.114: v2(35.39,11.14) R725.2 34.44,12.07 C613.2
RP_STBY_R_1.05V: length 11.5
  TOP w0.114: v2(35.26,2.08) 35.39,2.22 CONN11.43
  S10 w0.102: v2(35.26,2.08) 35.86,2.69 39.73,2.69 v2(40.34,2.08)
  BOTTOM w0.114: v2(40.34,2.08) R765.1 41.28,2.97 C638.2 41.3,3.81 v1(41.3,4.9)
RP_SVID_R_ALERT: length 21.6
  TOP w0.108: U9.AK72 99.38,58.86 v4(99.09,59.15)
  TOP w0.114: R286.2 v2(98.8,43.18)
  S10 w0.102: v4(99.09,59.15) 99.21,59.03 99.21,58.04 97.69,56.52 97.69,53.14 98.2,52.63 98.2,51.92 97.94,51.66 97.94,44.04 v2(98.8,43.18)
  BOTTOM w0.114: v2(98.8,43.18) 97.79,44.2 97.16,44.2 v1(96.52,44.83)
RP_SVID_R_CLK: length 23.5
  TOP w0.108: v4(100.08,59.15) 100.37,58.86 U9.AH72
  S8 w0.102: v4(100.08,59.15) 99.44,58.51 99.44,56.13 99.62,55.96 99.62,54.46 99.26,54.1 99.26,42.67 99.67,42.27 101.47,42.27 v2(102.21,43)
  BOTTOM w0.114: v2(102.21,43) 102.67,43 103.14,42.53 R634.2 103.14,41.31 v1(103.25,41.2)
RP_SVID_R_DATA: length 24.1
  TOP w0.108: U9.AJ71 100.08,59.88 99.96,60.01 v4(99.59,60.01)
  TOP w0.114: R304.2 v2(98.8,40.08)
  S10 w0.102: v2(98.8,40.08) 99.26,40.54 99.26,52.25 98.25,53.26 98.25,56.08 100.23,58.06 100.23,58.42 99.69,58.95 99.69,59.9 v4(99.59,60.01)
  BOTTOM w0.114: v2(98.8,40.08) 97.92,40.08 v1(97.86,40.02)
RP_TACH6: length 41.5
  TOP w0.114: U9.AU14 96.34,85.59 v4(95.94,86) ; R11.1 v2(79.6,115.32)
  S5 w0.102: v2(79.6,115.32) 80.54,115.32 81,114.86 82.66,114.86 84.96,112.56 84.96,107.21 85.75,106.43 85.75,105.04 86.85,103.94 86.85,100.32 92.08,95.09 92.08,92.38 94.49,89.97 95.05,89.97 95.31,89.7 95.31,88.75 96.1,87.97 96.1,87.13 95.94,86.97 v4(95.94,86)
  BOTTOM w0.114: v2(79.6,115.32) 79.6,115.8 v1(78.87,116.54)
RP_TACH7: length 23.2
  TOP w0.114: R89.1 95.12,105.87 v2(95.45,106.2) ; U9.AM2 98.84,90.71 98.48,90.35 98.48,90.09 98.84,89.73 v3(98.84,89.46)
  S10 w0.102: v3(98.84,89.46) 99.52,90.13 99.52,96.7 100,97.18 100,101.65 v2(95.45,106.2)
  BOTTOM w0.114: v2(95.45,106.2) 96.06,105.59 v1(96.06,105.36)
RP_USB_RBIAS: length 4.1
  TOP w0.114: U9.AG11 100.8,87.47 v4(100.59,87.47) 100.35,87.47 U9.AJ11
  BOTTOM w0.114: R515.1 100.08,89.56 100.08,87.98 v4(100.59,87.47)
RST_BTN_IN_BMC_N: length 254.8
  S5 w0.102: v2(123.65,2.55) 124.06,2.14 125.5,2.14 126.31,2.96 127.65,2.96 128.54,2.07 146.72,2.07 147.57,2.92 159.57,2.92 162.15,5.49 163.81,5.49 167.09,8.78 170.49,8.78 174.6,12.88 178.34,12.88 180.14,14.68 180.14,20.42 180.92,21.21 180.92,23.78 188.11,30.96 192.82,30.96 200.05,38.19 200.05,38.53 204.44,42.93 204.44,43.54 204.8,43.89 204.8,45.65 204.77,45.68 v3(204.77,50.44)
  S8 w0.102: v2(123.65,2.55) 123.85,2.36 123.85,1.85 123.31,1.32 120.13,1.32 120.08,1.37 97.41,1.37 95.57,3.21 95.57,5.73 92.64,8.66 88.44,8.66 86.91,7.12 86.91,3.87 86.34,3.31 v2(86.34,3)
  S10 w0.102: v2(86.34,3) 86.14,3 85.12,4.02 82.64,4.02 82.05,3.43 74.93,3.43 74.88,3.48 73.28,3.48 72.29,2.48 71.41,2.48 70.89,3.01 67.64,3.01 65.13,5.51 65.13,5.84 65.43,6.14 65.43,6.51 65.13,6.81 65.13,14.59 62.12,17.6 58.99,17.6 57.95,18.64 53.7,18.64 53.44,18.38 50.17,18.38 46.26,14.47 33.08,14.47 32.92,14.63 32.16,14.63 31.99,14.47 24.11,14.47 23.08,15.5 23.08,24.64 21.83,25.88 v2(19.93,25.88)
  BOTTOM w0.114: v3(204.77,50.44) 204.62,50.29 v1(203.58,50.29) 202.97,50.9 R909.2 ; CONN14.169 20.12,25.88 20.12,25.88 v2(19.93,25.88)
RST_BTN_IN_BMC_N_R: length 3.4
  TOP w0.114: U12.J13 v3(201.09,53.61)
  BOTTOM w0.114: R909.1 202.97,52.79 202.64,53.13 201.57,53.13 v3(201.09,53.61)
RST_BTN_OUT_BMC_N: length 35.5
  TOP w0.114: R329.2 v2(11.06,27.12)
  BOTTOM w0.114: CONN14.170 12.47,25.58 11.06,26.99 v2(11.06,27.12) 9.82,25.87 9.82,21.6 8.29,20.07 8.29,13.05 9.11,12.23 9.13,12.23 9.66,11.7 16.37,11.7 19.98,8.08 v1(19.98,5.53)
RSVD_97: length 0.6
  TOP w0.109: U9.AR71 96.89,59.72 v4(96.62,59.99)
RSVD_98: length 1.6
  TOP w0.114: v4(88.19,64.31) 88,64.31 U9.BT62
  BOTTOM w0.114: v1(88.19,65.28) v4(88.19,64.31)
SAFE_MODE_BOOT: length 21.8
  TOP w0.108: U9.AF69 101.78,60.58 102.03,60.83 v4(102.06,60.83)
  S10 w0.102: v4(102.06,60.83) 102.06,59.82 101.7,59.46 101.7,55.83 102.08,55.45 102.08,54.69 102.69,54.08 102.69,52.52 102.62,52.44 102.62,49.49 102.77,49.33 102.77,45.95 101.4,44.58 v2(101.4,43.13)
  BOTTOM w0.114: v2(101.4,43.13) 101.06,42.8 R635.2 101.06,41.43 v1(101.41,41.08)
SATA3_C_RX0_N: length 42
  TOP w0.127: C32.2 v3(103.58,104.57) ; U9.CA33 v4(85.72,76.61)
  S8 w0.089: v4(85.72,76.61) 86.08,76.61 86.35,76.87 86.79,77.6 87.29,78.09 87.29,78.45 87.54,78.7 87.85,78.7 87.97,78.58 88.42,78.58 88.8,78.96 88.8,79.32 89.28,79.81 89.28,80.19 89.79,80.7 89.79,81.1 89.31,81.58 89.31,81.92 89.79,82.4 89.79,82.83 89.31,83.31 89.31,83.64 89.79,84.12 89.79,84.53 89.31,85.01 89.31,85.37 89.76,85.83 89.76,86.28 89.31,86.74 89.31,87.07 89.76,87.53 89.76,88.01 89.31,88.47 89.31,88.8 89.53,89.03 89.53,89.74 90.32,90.53 90.32,90.93 91.41,92.02 91.41,93.06 91.42,93.07 91.42,93.09
  S8 w0.102: 91.42,93.09 91.42,95.48 101.04,105.11 103.48,105.11 103.58,105 v3(103.58,104.57)
SATA3_C_RX0_P: length 42
  TOP w0.127: U9.BY32 v4(86.21,77.46) ; C26.2 v3(103.58,105.84)
  S8 w0.089: v4(86.21,77.46) 86.39,77.46 87.1,78.17 87.1,78.52 87.46,78.89 87.93,78.89 88.05,78.77 88.34,78.77 88.61,79.04 88.61,79.4 89.09,79.89 89.09,80.27 89.6,80.77 89.6,81.02 89.12,81.51 89.12,81.99 89.6,82.48 89.6,82.75 89.12,83.23 89.12,83.72 89.6,84.2 89.6,84.45 89.12,84.93 89.12,85.45 89.57,85.91 89.57,86.2 89.12,86.66 89.12,87.15 89.57,87.61 89.57,87.93 89.12,88.39 89.12,88.88 89.34,89.11 89.34,89.82 90.13,90.6 90.13,91.01 91.22,92.1 91.22,93.06 91.22,93.07 91.22,93.09
  S8 w0.102: v3(103.58,105.84) 103.58,105.41 103.48,105.31 100.96,105.31 94.45,98.8 94.34,98.8 94.34,98.8 94.23,98.8 94.08,98.66 94.08,98.55 94.08,98.44 93.94,98.29 93.83,98.29 93.72,98.29 93.58,98.15 93.58,98.04 93.58,97.93 93.43,97.78 93.32,97.78 93.21,97.78 93.07,97.64 93.07,97.53 93.07,97.42 92.92,97.28 92.82,97.28 92.81,97.28 92.7,97.28 92.56,97.13 92.56,97.02 92.56,97.02 92.56,96.91 92.42,96.77 92.31,96.77 92.31,96.77 92.2,96.77 92.05,96.63 92.05,96.52 92.05,96.41 91.91,96.26 91.8,96.26 91.69,96.26 91.55,96.12 91.55,96.01 91.55,95.9 91.22,95.57 91.22,93.09
SATA3_C_RX1_N: length 41.6
  TOP w0.127: C40.2 v3(103.58,102.03) ; v4(86.71,76.61) 86.36,76.81 U9.BW33
  S8 w0.089: 92.26,92.96 92.26,92.94 92.25,92.93 92.25,91.87 91.31,90.93 91.31,90.53 90.53,89.74 90.53,89.03 90.3,88.8 90.3,88.47 90.75,88.01 90.75,87.53 90.3,87.07 90.3,86.74 90.75,86.28 90.75,85.83 90.3,85.37 90.3,85.01 90.78,84.53 90.78,84.12 90.3,83.64 90.3,83.31 90.78,82.83 90.78,82.4 90.3,81.92 90.3,81.58 90.78,81.1 90.78,80.7 90.27,80.19 90.27,79.81 89.79,79.32 89.79,78.97 89.29,78.47 89.29,78.1 88.93,77.74 88.47,77.74 88.31,77.89 88.07,77.89 87.94,77.75 87.78,77.6 87.78,77.32 87.07,76.61 v4(86.71,76.61)
  S8 w0.102: 92.26,92.96 92.26,94.26 92.79,94.79 95.76,94.79 97.16,96.19 97.16,99.9 99.82,102.57 103.48,102.57 103.58,102.46 v3(103.58,102.03)
SATA3_C_RX1_P: length 41.6
  TOP w0.127: C37.2 v3(103.58,103.3) ; U9.BV32 v4(87.2,77.46)
  S8 w0.089: 92.06,92.96 92.06,92.94 92.06,92.93 92.06,91.95 91.12,91.01 91.12,90.6 90.34,89.82 90.34,89.11 90.11,88.88 90.11,88.39 90.56,87.93 90.56,87.61 90.11,87.15 90.11,86.66 90.56,86.2 90.56,85.91 90.11,85.45 90.11,84.93 90.59,84.45 90.59,84.2 90.11,83.72 90.11,83.23 90.59,82.75 90.59,82.48 90.11,81.99 90.11,81.51 90.59,81.02 90.59,80.77 90.08,80.27 90.08,79.89 89.6,79.4 89.6,79.05 89.1,78.55 89.1,78.18 88.85,77.93 88.54,77.93 88.39,78.08 88,78.08 87.8,77.88 87.38,77.46 v4(87.2,77.46)
  S8 w0.102: v3(103.58,103.3) 103.58,102.87 103.48,102.77 99.74,102.77 96.95,99.98 96.95,96.27 95.67,95 95.31,95 95.21,95.1 95.21,95.28 95.1,95.38 94.7,95.38 94.6,95.28 94.6,95.1 94.49,95 93.84,95 93.74,95.1 93.74,95.2 93.64,95.3 93.23,95.3 93.13,95.2 93.13,95.1 93.03,95 92.71,95 92.06,94.34 92.06,92.96
SATA3_C_TX0_N: length 146
  TOP w0.127: U9.BV28 v4(87.2,79.18)
  S8 w0.089: v4(87.2,79.18) 87.2,80.09 87.33,80.21 87.82,80.71 87.82,81.1 87.31,81.61 87.31,81.91 87.82,82.42 87.82,82.81 87.31,83.31 87.31,83.64 87.8,84.12 87.8,84.56 87.31,85.04 87.31,85.34 87.8,85.82 87.8,86.26 87.31,86.74 87.31,87.07 87.8,87.55 87.8,87.99 87.31,88.47 87.31,88.81 87.54,89.04 87.54,89.79 88.53,90.78 88.53,93.14 88.54,93.14 88.54,93.16
  S8 w0.102: v3(182.91,85.64) 182.44,86.11 180.23,86.11 159.87,106.47 159.87,108.68 153.23,115.32 145.85,115.32 140.31,120.85 127.97,120.85 125.61,118.49 116.57,118.49 114.88,116.81 114.88,112.69 112.66,110.46 112.28,110.46 111.44,109.63 107.5,109.63 105.62,107.75 99.88,107.75 99.42,107.28 99.42,106.65 99.67,106.4 99.67,105.76 99.08,105.17 97.24,105.17 96.37,104.29 95.03,104.29 93.98,103.24 93.98,101.35 88.54,95.9 88.54,93.16
  BOTTOM w0.127: C277.1 v3(182.91,85.64)
SATA3_C_TX0_P: length 146.1
  TOP w0.127: U9.BW26 86.36,80.24 v4(86.71,80.04)
  S8 w0.089: v4(86.71,80.04) 86.88,80.04 87.63,80.79 87.63,81.03 87.12,81.53 87.12,81.99 87.63,82.5 87.63,82.73 87.12,83.24 87.12,83.72 87.6,84.2 87.6,84.48 87.12,84.96 87.12,85.42 87.6,85.9 87.6,86.18 87.12,86.66 87.12,87.15 87.6,87.63 87.6,87.91 87.12,88.39 87.12,88.89 87.35,89.12 87.35,89.87 88.34,90.86 88.34,93.14 88.33,93.14 88.33,93.16
  S8 w0.102: 88.33,93.16 88.33,95.99 93.78,101.43 93.78,103.33 94.95,104.5 96.28,104.5 97.16,105.37 99,105.37 99.47,105.84 99.47,106.32 99.21,106.57 99.21,107.37 99.8,107.95 105.54,107.95 107.42,109.83 111.35,109.83 112.19,110.67 112.57,110.67 114.68,112.77 114.68,116.89 116.48,118.69 125.53,118.69 127.89,121.06 140.39,121.06 145.93,115.52 153.31,115.52 160.07,108.76 160.07,106.55 180.31,86.31 180.66,86.31 180.83,86.49 181.06,86.49 181.24,86.31 181.47,86.31 181.65,86.49 181.88,86.49 182.05,86.31 182.31,86.31 v3(182.91,86.91)
  BOTTOM w0.127: C276.1 v3(182.91,86.91)
SATA3_C_TX1_N: length 188.6
  TOP w0.127: U9.BT28 v4(88.2,79.18)
  S8 w0.089: v4(88.2,79.18) 88.2,80.09 88.32,80.21 88.81,80.71 88.81,81.1 88.3,81.61 88.3,81.91 88.81,82.42 88.81,82.81 88.3,83.31 88.3,83.64 88.79,84.12 88.79,84.56 88.3,85.04 88.3,85.34 88.79,85.82 88.79,86.26 88.3,86.74 88.3,87.07 88.79,87.55 88.79,87.99 88.3,88.47 88.3,88.77 88.56,89.02 88.56,89.81 89.52,90.78 89.52,93.14 89.53,93.14 89.53,93.16
  S8 w0.102: 89.53,93.16 89.53,95.6 94.82,100.89 94.82,102.58 95.41,103.17 98.06,103.17 100.76,105.88 100.76,106.34 101.02,106.6 107.78,106.6 108.42,107.24 109.43,107.24 109.43,107.24 114.38,107.24 116.16,109.01 120.75,109.01 123.22,111.48 123.22,114.93 128.35,120.07 139.62,120.07 145.23,114.45 152.52,114.45 157.12,109.85 157.12,106.54 161.69,101.98 163.31,101.98 180.66,84.63 186.7,84.63 187.46,85.4 187.46,90.78 185.82,92.42 185.82,101.71 191.47,107.36 191.47,111.54 195.66,115.72 195.66,119.39 v3(196.19,119.92)
  BOTTOM w0.127: C282.1 v3(196.19,119.92)
SATA3_C_TX1_P: length 188.6
  TOP w0.127: U9.BU26 v4(87.7,80.04)
  S8 w0.089: v4(87.7,80.04) 87.87,80.04 88.62,80.79 88.62,81.03 88.11,81.53 88.11,81.99 88.62,82.5 88.62,82.73 88.11,83.24 88.11,83.72 88.6,84.2 88.6,84.48 88.11,84.96 88.11,85.42 88.6,85.9 88.6,86.18 88.11,86.66 88.11,87.15 88.6,87.63 88.6,87.91 88.11,88.39 88.11,88.85 88.37,89.1 88.37,89.89 89.33,90.86 89.33,93.14 89.33,93.14 89.33,93.16
  S8 w0.102: 89.33,93.16 89.33,95.68 89.88,96.24 89.88,96.49 90.03,96.63 90.27,96.63 90.42,96.77 90.42,97.02 90.56,97.16 90.81,97.16 90.95,97.31 90.95,97.55 91.09,97.7 91.34,97.7 91.48,97.84 91.48,98.08 91.62,98.23 91.87,98.23 94.61,100.97 94.61,102.67 95.33,103.38 97.97,103.38 100.56,105.96 100.56,106.43 100.94,106.81 107.7,106.81 108.33,107.44 109.52,107.44 114.3,107.44 116.08,109.22 120.66,109.22 123.01,111.56 123.01,115.01 128.27,120.27 139.7,120.27 145.31,114.66 152.6,114.66 157.33,109.93 157.33,106.63 161.77,102.18 163.4,102.18 180.75,84.84 186.61,84.84 187.26,85.48 187.26,90.69 185.62,92.34 185.62,101.79 191.27,107.45 191.27,111.63 195.45,115.81 195.45,119.38 v3(194.92,119.92)
  BOTTOM w0.127: C281.1 v3(194.92,119.92)
SATA3_RX0_N: length 127.5
  TOP w0.127: C32.1 v3(106.12,104.57) ; CONN6.25 190.55,87.83 190.82,87.56 190.82,87.02 v3(190.31,86.52)
  S8 w0.102: v3(190.31,86.52) 190.83,87.04 190.83,87.82 191.2,88.19 192.75,88.19 193.45,87.49 193.45,84.96 191.79,83.29 178.44,83.29 177.11,84.62 177.11,87.1 168.15,96.06 162.98,96.06 160.86,98.19 160.86,101.55 156.11,106.3 156.11,109.44 151.91,113.64 144.67,113.64 139.01,119.3 128.94,119.3 124.34,114.71 124.34,110.86 120.01,106.53 114.76,106.53 113.33,105.11 106.22,105.11 106.12,105 v3(106.12,104.57)
SATA3_RX0_P: length 127.5
  TOP w0.127: C26.1 v3(106.12,105.84) ; v3(191.58,86.52) 191.08,87.02 191.08,87.56 191.35,87.83 CONN6.23
  S8 w0.102: v3(191.58,86.52) 191.03,87.07 191.03,87.73 191.29,87.99 192.67,87.99 193.25,87.41 193.25,86.99 193.15,86.89 192.98,86.89 192.88,86.78 192.88,86.58 192.98,86.48 193.15,86.48 193.25,86.38 193.25,86.17 193.15,86.07 192.98,86.07 192.88,85.97 192.88,85.77 192.98,85.67 193.15,85.67 193.25,85.56 193.25,85.04 191.7,83.5 178.53,83.5 177.32,84.71 177.32,87.18 168.23,96.27 163.07,96.27 161.06,98.27 161.06,101.63 156.31,106.38 156.31,109.52 151.99,113.84 144.75,113.84 139.09,119.51 128.85,119.51 124.14,114.79 124.14,110.95 119.92,106.73 114.67,106.73 113.25,105.31 106.22,105.31 106.12,105.41 v3(106.12,105.84)
SATA3_RX1_N: length 163
  TOP w0.127: C40.1 v3(106.12,102.03)
  S8 w0.102: v3(196.41,112.93) 196.85,112.93 196.95,113.03 196.95,114.01 196.55,114.41 195.86,114.41 194.07,112.62 194.07,112.23 194.18,112.12 194.26,112.12 194.37,112.02 194.37,111.82 194.26,111.72 194.18,111.72 194.07,111.62 194.07,101.11 196.27,98.92 196.27,83.89 193.6,81.23 178.44,81.23 176.15,83.52 176.15,86.81 168.77,94.18 162.68,94.18 159.89,96.97 159.89,101.24 154.94,106.19 154.94,109.29 151.27,112.95 142.99,112.95 137.38,118.57 129.7,118.57 127.3,116.17 127.3,108.58 126.44,107.72 122.58,107.72 118.92,104.06 108.95,104.06 107.45,102.57 106.22,102.57 106.12,102.46 v3(106.12,102.03)
  BOTTOM w0.127: CONN13.43 196.8,114.12 196.92,114.01 196.92,113.43 v3(196.41,112.93)
SATA3_RX1_P: length 163
  TOP w0.127: C37.1 v3(106.12,103.3)
  S8 w0.102: v3(197.68,112.93) 197.25,112.93 197.15,113.03 197.15,114.09 196.63,114.61 195.78,114.61 193.87,112.71 193.87,101.03 196.07,98.83 196.07,83.98 193.52,81.43 178.52,81.43 176.35,83.6 176.35,86.89 168.86,94.39 162.76,94.39 160.1,97.05 160.1,101.32 155.14,106.27 155.14,109.37 151.36,113.16 143.08,113.16 137.46,118.77 129.62,118.77 127.1,116.26 127.1,108.67 126.36,107.92 122.5,107.92 118.84,104.27 108.86,104.27 107.37,102.77 106.22,102.77 106.12,102.87 v3(106.12,103.3)
  BOTTOM w0.127: CONN13.41 197.3,114.12 197.18,114.01 197.18,113.43 v3(197.68,112.93)
SATA3_TX0_N: length 6.3
  TOP w0.127: v3(185.33,85.64) 185.83,86.14 187.51,86.14 187.88,86.51 187.88,87.56 188.15,87.83 CONN6.31
  BOTTOM w0.127: C277.2 v3(185.33,85.64)
SATA3_TX0_P: length 6.2
  TOP w0.127: v3(185.33,86.91) 185.33,86.62 185.55,86.4 186.14,86.4 186.42,86.69 186.68,86.69 186.96,86.4 187.4,86.4 187.62,86.62 187.62,87.56 187.35,87.83 CONN6.33
  BOTTOM w0.127: C276.2 v3(185.33,86.91)
SATA3_TX1_N: length 3
  BOTTOM w0.127: C282.2 195.68,117.25 195.68,116.09 195.8,115.97 CONN13.47
SATA3_TX1_P: length 3
  BOTTOM w0.127: CONN13.49 195.3,115.97 195.42,116.09 195.42,117.25 C281.2
SF100_IO3: length 92
  TOP w0.114: CONN3.8 v2(48.3,114.86)
  S8 w0.102: v2(48.3,114.86) 52.59,119.15 79.71,119.15 80.77,118.08 85.97,118.08 86.73,118.85 91.74,118.85 96.24,114.35 97.99,114.35 98.4,113.94 98.4,113.39 99.3,112.5 100.6,112.5 102.2,114.09 111.45,114.09 111.79,114.43 v2(112.39,114.43)
  BOTTOM w0.114: v1(45.31,112.24) 45.68,112.24 v2(48.3,114.86) ; Q1.G 114.12,105.61 115.06,106.55 115.06,110.87 114.3,111.63 R934.2 114.61,113.08 114.76,113.24 114.76,114.34 114.35,114.76 112.72,114.76 v2(112.39,114.43)
SLB_GND: length 4.5
  TOP w0.114: v2(176.43,21.97) 176.56,21.84 U17.25
  BOTTOM w0.114: v2(176.43,21.97) 176.43,23.14 176.98,23.7 R1082.2
SLB_GPIO: length 5.7
  TOP w0.114: U17.6 170.79,20.54 v2(170.78,20.53)
  BOTTOM w0.114: 171.89,20.75 171.42,21.22 171.42,22 v1(170.87,22.56) 170.89,22.58 R249.2 ; 171.89,20.75 171.1,20.75 170.87,20.53 v2(170.78,20.53) ; 171.89,20.75 R955.2
SLB_NC-RST: length 10.2
  TOP w0.114: U17.9 170.86,18.58 170.43,18.16 v2(170.43,17.14) 170.43,13.97 170.94,13.46 R1055.1
SLB_TPM: length 5.8
  TOP w0.114: v2(175.77,24.51) 176.49,23.79 U17.28 177.76,24.93 R1085.2
  BOTTOM w0.114: v2(175.77,24.51) 176.23,24.97 v1(176.78,24.97)
SLB_VDD_1: length 5.3
  TOP w0.114: U17.5 170.64,21.19 v2(169.8,22.02)
  BOTTOM w0.114: v2(169.8,22.02) R1083.2 169.52,22.91 168.66,23.78 v1(168.66,24.13)
SLB_VDD_3: length 4
  TOP w0.114: U17.19 177.79,17.91 179.07,17.91 v2(179.27,17.71) v1(180.47,17.71)
  BOTTOM w0.114: v1(180.47,17.71) v2(179.27,17.71)
SMB_10GBE_ALERT: length 23.3
  TOP w0.108: U9.AN71 98.1,59.72 v4(98.1,59.15)
  TOP w0.114: R285.1 v2(96.57,40.69)
  S10 w0.102: v4(98.1,59.15) 98.1,58.7 98.25,58.55 98.25,58.12 95.71,55.58 95.71,45.36 96.34,44.73 96.34,43.94 96.09,43.69 96.09,42.8 96.57,42.32 v2(96.57,40.69)
  BOTTOM w0.114: v2(96.57,40.69) 96.65,40.77 v1(96.65,42.42)
SMB_10GBE_CLK: length 6.5
  TOP w0.114: R237.1 98.8,53.78 98.35,54.23 98.35,54.97 98.73,55.35 98.73,56.17 98.49,56.4 98.49,56.71 98.84,57.05 U9.AM75
SMB_10GBE_DATA: length 11.9
  TOP w0.114: v2(98.8,47.24) R250.1 99.08,48 99.51,48.44 99.51,53.41 99.33,53.59 99.33,53.84 98.65,54.53 98.65,54.91 99.03,55.29 99.03,56.37 U9.AM77
  BOTTOM w0.114: v2(98.8,47.24) 98.48,47.24 v1(97.64,48.08)
SMB_9548_I_SCL: length 3.6
  BOTTOM w0.114: U33.22 R497.2 v1(26.11,99.11)
SMB_9548_I_SDA: length 3.9
  BOTTOM w0.114: R498.2 v1(27.56,98.12) 26.59,98.12 25.76,97.29 U33.23
SMB_9548_SCL0: length 225
  S8 w0.102: v2(21.64,86.06) 22.58,87 24.18,87 24.43,86.74 24.43,86.56 24.39,86.51 24.39,86.14 24.43,86.09 24.43,85.39 22,82.96 22,50.98 25.93,47.04 25.93,19.92 26.31,19.55 26.57,19.29 26.57,19.29 30.36,15.49 31.08,15.49 38.63,15.49 42.37,11.76 45.22,11.76 v2(46.77,10.21) 46.77,9.38 48.43,7.72 50.19,7.72 50.83,7.09 50.83,5.89 52.63,4.09 55.67,4.09 56.41,3.35 58.32,3.35 58.33,3.34 64.16,3.34 64.37,3.13 64.47,3.22 64.85,3.22 65.05,3.02 69,3.02 69.4,3.43 75.37,3.43 75.87,2.93 75.87,2.55 76.14,2.29 77.6,2.29 78.49,3.17 82.24,3.17 84.95,5.89 84.95,7.93 85.42,8.4 85.42,9.74 85.69,10.01 87.03,10.01 87.63,10.61 88.83,10.61 93.14,10.61 93.49,10.96 94.39,10.96 95.03,10.32 95.03,9.03 97.33,6.73 100.2,6.73 101.7,5.23 105.5,5.23 111.43,5.23 113.05,3.61 118.81,3.61 119.14,3.94 119.14,4.27 119.38,4.51 122.27,4.51 123.64,3.14 123.86,3.14 124.84,2.16 127.27,2.16 127.76,1.68 144.91,1.68 146.6,3.37 v3(146.6,3.78)
  BOTTOM w0.114: v1(47.87,10.31) 47.77,10.21 v2(46.77,10.21) ; R531.2 21.21,86.48 v2(21.64,86.06) 21.17,85.58 19.12,85.58 18.98,85.72 18.98,85.72 16.97,87.74 R786.2
  BOTTOM w0.127: CONN16.50 v3(146.6,3.78)
SMB_9548_SCL1: length 227.7
  S5 w0.102: v2(120.51,2.23) 120.51,3.64 122.25,5.38 123.41,5.38 124.47,5.38 124.55,5.46 124.62,5.53 124.63,5.53 126.02,5.53 126.02,5.53 126.44,5.12 129.3,5.12 130,5.82 v2(132.99,5.82)
  S8 w0.102: v2(18.19,88.04) 18.19,86.11 20.95,83.34 20.95,37.79 21.23,37.51 21.23,36.1 20.95,35.82 20.95,23.77 20.95,23.77 20.95,23.43 24.89,19.49 24.89,19.49 25.87,18.51 26.14,18.24 29.96,14.43 30.3,14.43 30.48,14.43 30.48,14.43 38.14,14.43 41.15,11.42 41.15,6.57 46.52,1.19 73.69,1.19 73.79,1.09 74.9,1.09 75,1.19 81.73,1.19 82.1,1.57 85.99,5.46 85.99,5.8 85.99,7.5 88.06,9.57 93.02,9.57 96.48,6.11 96.48,4.25 97.56,3.18 99.23,3.18 99.88,2.53 100.18,2.53 100.7,3.05 101.94,3.05 102.66,2.34 105.03,2.34 105.65,2.95 106.13,2.95 106.79,2.29 120.46,2.29 v2(120.51,2.23)
  BOTTOM w0.114: CONN16.87 137.1,6.29 136.85,6.04 134.88,6.04 134.66,5.82 v2(132.99,5.82) ; v1(19.96,101.78) 19.96,101.77 ; 19.96,101.77 19.63,101.45 17.02,101.45 16.13,100.56 16.13,91.21 16.69,90.65 R791.2 17.12,89.61 18.19,88.54 v2(18.19,88.04) ; 19.96,101.77 R493.2
SMB_9548_SDA0: length 229.3
  S5 w0.102: v3(148.46,4.9) 146.33,2.77 128.67,2.77 127.24,4.19 126.47,4.19 125.76,4.9 124.89,4.9 124.65,4.66 123.76,3.77 122.53,3.77 122.27,3.51 122.27,2.42 v2(122.18,2.34)
  S8 w0.102: v2(122.18,2.34) 121.4,3.12 112.96,3.12 111.26,4.83 104.95,4.83 104.06,3.94 97.7,3.94 97.12,4.52 97.12,6.37 94.63,8.86 94.63,10.15 94.22,10.55 93.66,10.55 93.31,10.21 87.8,10.21 85.36,7.76 85.36,5.72 81.46,1.83 74.74,1.83 74.63,1.73 74.06,1.73 73.96,1.83 73.32,1.83 73.3,1.85 53,1.85 50.77,4.09 49.24,4.09 48.56,4.76 48.56,4.79 46.79,6.56 46.79,6.72 45.06,8.45 v2(45.06,11.04) 44.87,11.23 42.28,11.23 38.45,15.06 30.22,15.06 26.4,18.88 26.14,19.15 25.53,19.76 25.53,46.87 21.59,50.81 21.59,83.5 v2(23.72,85.64)
  BOTTOM w0.114: v1(45.78,9.86) 45.78,10.33 v2(45.06,11.04) ; CONN16.48 147.1,3.67 148.34,4.9 v3(148.46,4.9) ; R534.2 23.93,85.84 v2(23.72,85.64) 23.15,85.06 19.05,85.06 18.92,85.19 17.27,86.85 R788.2
SMB_9548_SDA1: length 214
  S5 w0.102: v2(136.86,5.54) 135.86,5.54 135.69,5.36 130.18,5.36 129.44,4.62 126.36,4.62 125.86,5.13 125.85,5.13 124.79,5.13 124.79,5.13 124.64,4.97 122.42,4.97 121.38,3.93 v2(121.38,2.26)
  S8 w0.102: v2(19.36,86.15) 19.36,85.51 21.36,83.51 21.36,37.95 21.64,37.68 21.64,35.93 21.36,35.65 21.36,23.6 25.3,19.66 26.04,18.92 26.31,18.65 30.13,14.83 30.32,14.83 38.35,14.83 42.56,10.62 v2(44.25,10.62) 44.25,8.94 45.39,7.8 45.39,6.62 45.9,6.11 45.9,5.65 49.95,1.6 73.86,1.6 73.96,1.5 74.73,1.5 74.83,1.6 81.56,1.6 85.59,5.63 85.59,7.67 87.9,9.98 93.4,9.98 93.75,10.33 94.13,10.33 94.4,10.06 94.4,9.68 94.13,9.41 94.13,9.04 96.89,6.28 96.89,4.42 97.61,3.71 104.16,3.71 104.82,4.37 111.39,4.37 112.87,2.89 120.74,2.89 v2(121.38,2.26)
  BOTTOM w0.114: v2(136.86,5.54) 136.94,5.54 137.4,5.99 138.46,5.99 138.6,6.13 CONN16.81 ; R792.2 16.89,88.68 18.44,87.12 R529.2 v2(19.36,86.15) ; v2(44.25,10.62) 44.25,9.67 v1(45.48,8.44)
SMB_CLK_CPLD: length 6.7
  TOP w0.114: R900.2 v2(195.61,64.59) ; U12.C10 v3(198.09,60.61)
  BOTTOM w0.114: v2(195.61,64.59) 195.61,64.57 196.47,63.7 v1(196.49,63.7) 197.54,62.66 197.54,61.16 v3(198.09,60.61)
SMB_DATA_CPLD: length 155.6
  TOP w0.114: U12.C9 v3(197.09,60.61)
  S3 w0.102: v3(197.09,60.61) 197.47,60.99 197.47,61.77 197.33,61.9 197.33,66.27 194.78,68.83 194.78,79.67 185.21,89.24 180.67,89.24 175.58,94.33 175.58,101.06 170.19,106.45 162.1,106.45 155.83,112.73 139.34,112.73 134.01,118.06 113.54,118.06 112.39,119.2 108.01,119.2 107.93,119.28 106.54,119.28 105.83,119.99 84.71,119.99 v2(83.26,118.54)
  BOTTOM w0.114: v1(196.29,60.96) 196.74,60.96 v3(197.09,60.61) ; R488.2 v2(83.26,118.54)
SMB_FRU_PCU_CLK_P3V3: length 18.4
  TOP w0.114: U19.6 v2(184.25,21.62)
  S5 w0.102: v2(184.25,21.62) 184.91,20.95 186.98,20.95 187.31,21.29 189.94,21.29 190.83,20.4 197.46,20.4 v2(198.45,21.39)
  BOTTOM w0.114: R650.2 198.45,20.39 v2(198.45,21.39)
SMB_FRU_PCU_DATA_P3V3: length 31.1
  TOP w0.114: U19.5 v2(181.61,22.89)
  S5 w0.102: v2(206.35,22.83) 205.92,22.4 196.37,22.4 194.13,24.64 183.36,24.64 v2(181.61,22.89)
  BOTTOM w0.114: v2(206.35,22.83) 207.14,22.05 R671.2
SMB_LM75BD_CLK_P3V3: length 153.8
  TOP w0.114: v2(138.18,107.95) 138.62,107.5 139.15,107.5 140.21,108.56 140.21,111.25 139.83,111.63 R297.2
  S8 w0.102: v2(138.18,107.95) 137.41,107.95 135.13,105.66 135.13,104.27 134.34,103.48 134.34,95.66 133.43,94.74 133.43,80.77 135.69,78.51 139.7,78.51 140.36,77.85 140.36,69.06 139.98,68.67 139.98,63.16 141.35,61.79 v2(141.35,61.47)
  BOTTOM w0.114: v2(138.18,107.95) 138.1,108.03 v1(138.1,108.89) ; R666.2 R674.1 201.04,23.79 197.23,27.6 192.05,27.6 189.13,30.52 189.13,37.77 187.3,39.6 182.6,39.6 178.84,43.36 178.84,46.83 178.06,47.61 171.17,47.61 170.75,48.03 170.75,49.07 168.97,50.85 168.97,55.09 167.68,56.39 159.68,56.39 158.78,57.29 147.47,57.29 144.93,59.83 143.54,59.83 142.28,61.09 141.73,61.09 v2(141.35,61.47)
SMB_LM75BD_DATA_P3V3: length 154.2
  TOP w0.114: U20.1 139.32,112.9 140.45,111.77 140.45,108.46 139.25,107.26 138.48,107.26 138.3,107.44 v2(137.67,107.44)
  S8 w0.102: v2(142.11,61.59) 141.87,61.59 140.21,63.26 140.21,68.58 140.59,68.96 140.59,77.98 139.83,78.74 135.78,78.74 133.65,80.87 133.65,94.59 134.59,95.53 134.59,103.41 135.36,104.17 135.36,105.57 137.23,107.44 v2(137.67,107.44)
  BOTTOM w0.114: R669.2 R668.1 204.09,21.47 197.72,27.84 192.15,27.84 189.37,30.62 189.37,37.87 187.4,39.84 182.7,39.84 179.08,43.46 179.08,46.93 178.16,47.85 171.27,47.85 170.99,48.13 170.99,49.17 169.21,50.95 169.21,55.19 167.77,56.64 159.77,56.64 158.88,57.53 147.57,57.53 145.03,60.07 143.64,60.07 v2(142.11,61.59) ; v2(137.67,107.44) 137.2,107.44 v1(136.83,107.08)
SMB_LVC3_ALERT: length 170.7
  TOP w0.114: R13.2 v2(85.54,115.26)
  S3 w0.102: v2(85.54,115.26) 86.82,116.53 89.25,116.53 90.78,118.06 93.37,118.06 94.97,116.46 97.92,116.46 98.35,116.89 102.74,116.89 108.53,111.1 113.52,111.1 114.66,109.96 114.66,108.17 116.09,106.73 120.4,106.73 122.61,108.94 131.75,108.94 132.72,109.91 148.19,109.91 149.71,108.38 150.94,108.38 154.17,105.16 169.08,105.16 173.74,100.5 173.74,91.99 193.5,72.23 193.5,67.53 v2(193.67,67.36) 193.67,66.89 194.56,66 194.56,47.4 194.23,47.06 194.23,46.2 193.64,45.61 193.64,44.56 v2(194.01,44.2)
  BOTTOM w0.114: v1(193.4,42.62) 193.4,43.59 v2(194.01,44.2) ; R13.2 v2(85.54,115.26) ; v2(193.67,67.36) 194.28,66.75 R230.2
SMB_LVC3_ALERT_R: length 6.9
  TOP w0.114: U12.D8 v3(195.09,59.61)
  BOTTOM w0.114: R230.1 194.28,64.03 v1(194.44,63.88) 194.44,62.97 194.61,62.79 194.61,60.08 v3(195.09,59.61)
SMB_PCU_CD_P3V3_INT-IN: length 224.4
  TOP w0.114: R1076.2 v2(183.39,55.75)
  S8 w0.102: v2(150.19,116.46) 149.63,117.02 146.75,117.02 141.83,121.95 114.79,121.95 112.35,119.51 107.46,119.51 105.65,117.7 102.3,117.7 98.74,121.27 41.48,121.27 39.73,119.51 39.73,118.24 37.27,115.79 35.52,115.79 34.19,114.45 34.19,111.68 30.84,108.33 v2(29.72,108.33)
  S10 w0.102: v2(29.72,108.33) 31.7,108.33 v2(34.37,105.66) ; v2(150.19,116.46) 152.58,114.07 155.14,114.07 160.58,108.63 160.58,105.25 168.03,97.8 168.03,90.78 183.72,75.1 183.72,57.19 183.39,56.86 v2(183.39,55.75)
  BOTTOM w0.114: v1(183.39,57.35) v2(183.39,55.75) ; v2(34.37,105.66) 34.37,106.81 34.82,107.26 R1077.1 35.43,107.49 35.71,107.77 37.05,107.77 37.54,108.26 R1089.2 37.72,108.51 R1113.2
SMB_PCU_CD_P3V3_INT-IN_R: length 10.9
  TOP w0.114: v3(192.1,51.64) 192.57,52.11 U12.L5 ; R1076.1 v2(186.03,55.75)
  S10 w0.102: v3(192.1,51.64) 191.59,52.15 189.64,52.15 v2(186.03,55.75)
  BOTTOM w0.114: v1(184.53,55.75) v2(186.03,55.75)
SMB_PCU_CD_P3V3_SW_INT1: length 234.6
  TOP w0.114: R1091.2 46.1,110.16 45.85,110.41 45.85,111.81 R1079.2 46.92,112.32 47.68,113.08 47.68,118.06 46.99,118.75 43.28,118.75 42.67,119.35 42.67,120.78 41.61,121.84 v2(33.45,121.84) ; R1074.2 v2(182.98,48.77)
  S8 w0.102: v2(33.45,121.84) 34.02,122.41 99.22,122.41 99.22,122.4 142.02,122.4 146.94,117.47 151.1,117.47 v2(152.1,116.48)
  S10 w0.102: v2(152.1,116.48) 153.75,114.83 155.02,114.83 161.04,108.82 161.04,105.44 168.49,97.99 168.49,90.97 184.18,75.29 184.18,49.96 v2(182.98,48.77)
  BOTTOM w0.114: v2(182.98,48.77) 183.51,48.77 v1(184.18,49.43) ; R1112.2 33.86,120.58 33.45,120.98 v2(33.45,121.84)
SMB_PCU_CD_P3V3_SW_INT1_R: length 6.4
  TOP w0.114: R1074.1 v2(185.8,48.77) 186.64,49.61 189.08,49.61 U12.N2
  BOTTOM w0.114: v1(186.89,49.48) 186.51,49.48 v2(185.8,48.77)
SMB_PCU_CLK_I2C_BUS: length 3.2
  BOTTOM w0.114: U45.13 40.57,112.12 39.75,111.3 R1105.1
SMB_PCU_CLK_I2C_MUX: length 61.5
  S3 w0.102: v2(39.4,105.33) 38.46,106.27 34.09,106.27 33.2,105.38 33.2,104.93 32.28,104.01 v2(31.57,104.01)
  S8 w0.102: v2(31.57,104.01) 29.87,102.31 29.87,84.05 29.74,83.93 29.74,79.81 30.02,79.53 30.02,77.3 29.67,76.95 28.85,76.14 28.85,71.39 29.36,70.89 29.36,59.3 v2(28.68,58.62)
  BOTTOM w0.114: v2(28.68,58.62) 29.12,58.18 U40.4 ; v1(38.76,103.2) 38.51,103.45 38.51,104.44 v2(39.4,105.33) 39.5,105.44 R1106.1
SMB_PCU_CLK_P3V3: length 479.7
  TOP w0.114: v2(198.04,23.6) 198.04,24.33 192.1,30.28 189.46,30.28 184.99,34.75 184.99,41.66 184.03,42.61 178.2,42.61 174.12,38.53 v2(174.12,38.23) ; R900.1 195.61,66.94 v2(195.2,67.35)
  S3 w0.102: v2(188.85,82.42) 188.85,81.58 194.14,76.29 194.14,69.09 194.14,68.41 v2(195.2,67.35) 195.61,66.94 195.61,66.4 195.71,66.3 195.71,65.67 196.22,65.16 196.22,63.08 196.32,62.98 196.32,46.78 195.13,45.59 194.82,45.59 194.49,45.26 194.49,44.15 194.97,43.66 194.97,42.06 195.62,41.41 195.62,26.85 198.04,24.43 v2(198.04,23.6) ; v2(122.8,31.84) 121.56,33.07 101.65,33.07 99.69,31.11 99.69,27.82 94,22.12 90.12,22.12 89.74,21.74 89.08,21.74 88.51,22.32 87.6,22.32 87.05,21.77 83.64,21.77 83.23,21.36 78.87,21.36 77.86,22.38 72.47,22.38 72.37,22.48 69.29,22.48 69.19,22.38 68.68,22.38 67.26,20.95 66.28,20.95 65.93,20.6 61.7,20.6 60.71,21.59 56.9,21.59 56.01,20.7 54.53,20.7 51.05,17.22 v2(50.8,17.22)
  S5 w0.102: v2(39.24,104.44) 39.24,103.5 38.46,102.72 33.88,102.72 33.3,102.13 30.71,102.13 27.93,99.35 26.6,99.35 v2(25.93,100.02) 22.17,103.78 21.23,103.78 16.54,108.48 16.54,113.92 16.72,114.11 16.72,116.06 v2(17.12,116.46)
  S8 w0.102: v2(174.12,38.23) 174.12,37.31 173.76,36.96 173.2,36.96 172.95,37.21 171.6,37.21 170.79,36.4 164.8,36.4 159.21,30.81 135.79,30.81 132.72,33.88 124.66,33.88 122.8,32.02 v2(122.8,31.84)
  S10 w0.102: v2(17.12,116.46) 16.72,116.06 16.72,114.11 16.51,113.89 16.51,105.21 19.49,102.23 19.49,99.99 30.71,88.76 30.71,81.27 30.89,81.09 30.89,80.71 30.71,80.53 30.71,70.7 28.96,68.95 26.79,68.95 26.29,68.45 26.29,67.13 25.93,66.78 25.93,65.3 26.24,64.99 26.24,62.08 26.64,61.68 26.64,60.48 27.66,59.46 27.66,54.07 26.19,52.6 21.6,52.6 20.22,51.22 20.22,50.04 9.98,39.8 9.98,19.16 18.53,10.62 34.99,10.62 37.69,7.92 37.69,6.73 38.54,5.89 v2(38.54,5.62) 38.99,6.07 40.11,6.07 41.86,7.82 46.48,7.82 48.56,9.91 48.56,15.42 50.37,17.22 v2(50.8,17.22)
  BOTTOM w0.114: R1105.2 39.75,107.52 R1106.2 ; R497.1 v2(25.93,100.02) ; R1106.2 39.85,107.26 39.96,107.15 39.96,105.16 v2(39.24,104.44) v1(40.34,103.35) ; R1106.2 R1067.1 ; v1(198.37,24.56) 198.37,23.93 v2(198.04,23.6) 198.04,22 197.61,21.56 197.61,20.62 197.35,20.36 197.35,19.31 197.63,19.03 R650.1 R653.1 R666.1 ; R159.1 v2(188.85,82.42) ; v2(17.12,116.46) 18.54,116.46 19.66,117.58 R425.2 ; v2(38.54,5.62) 38.46,5.53 R763.2
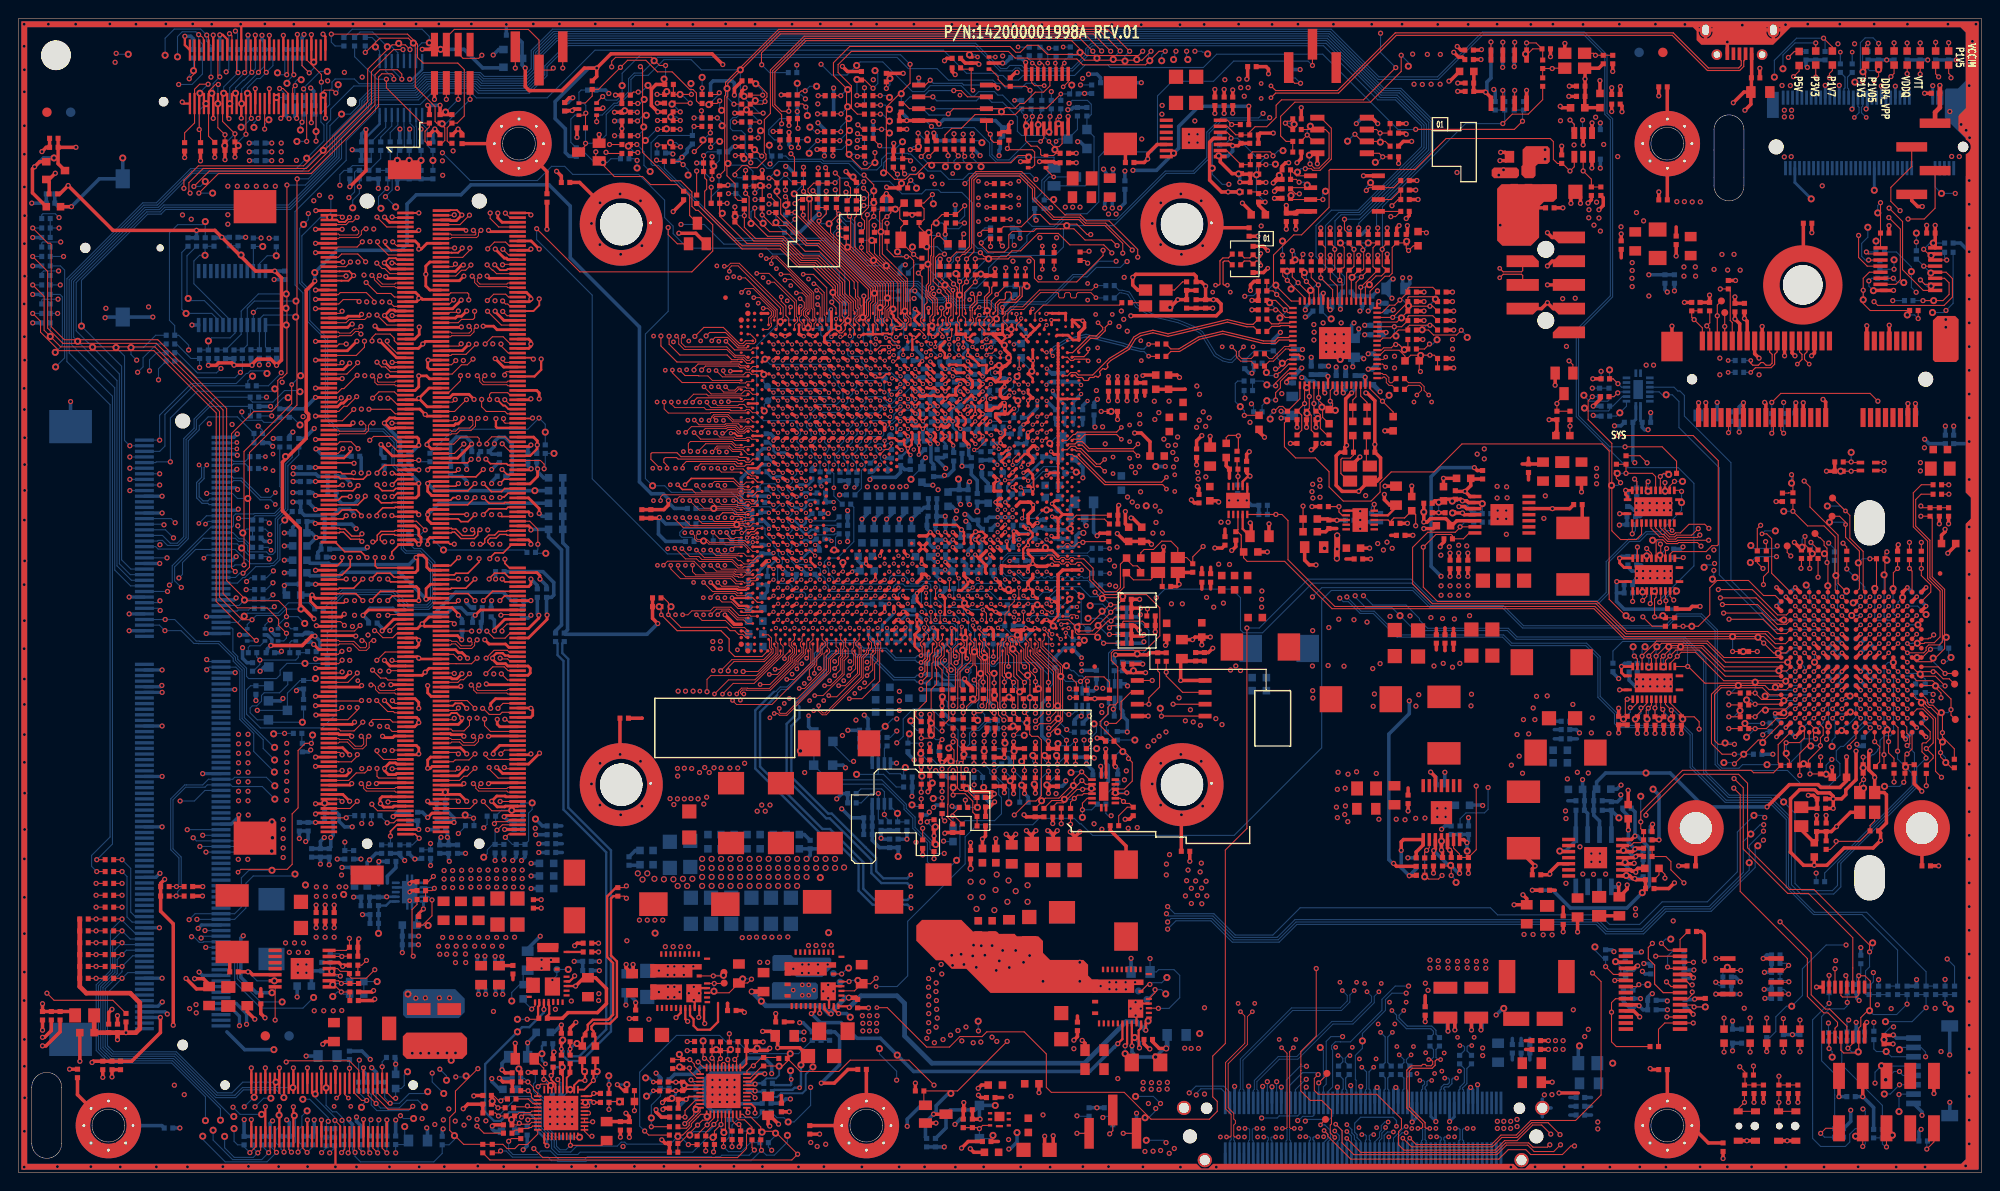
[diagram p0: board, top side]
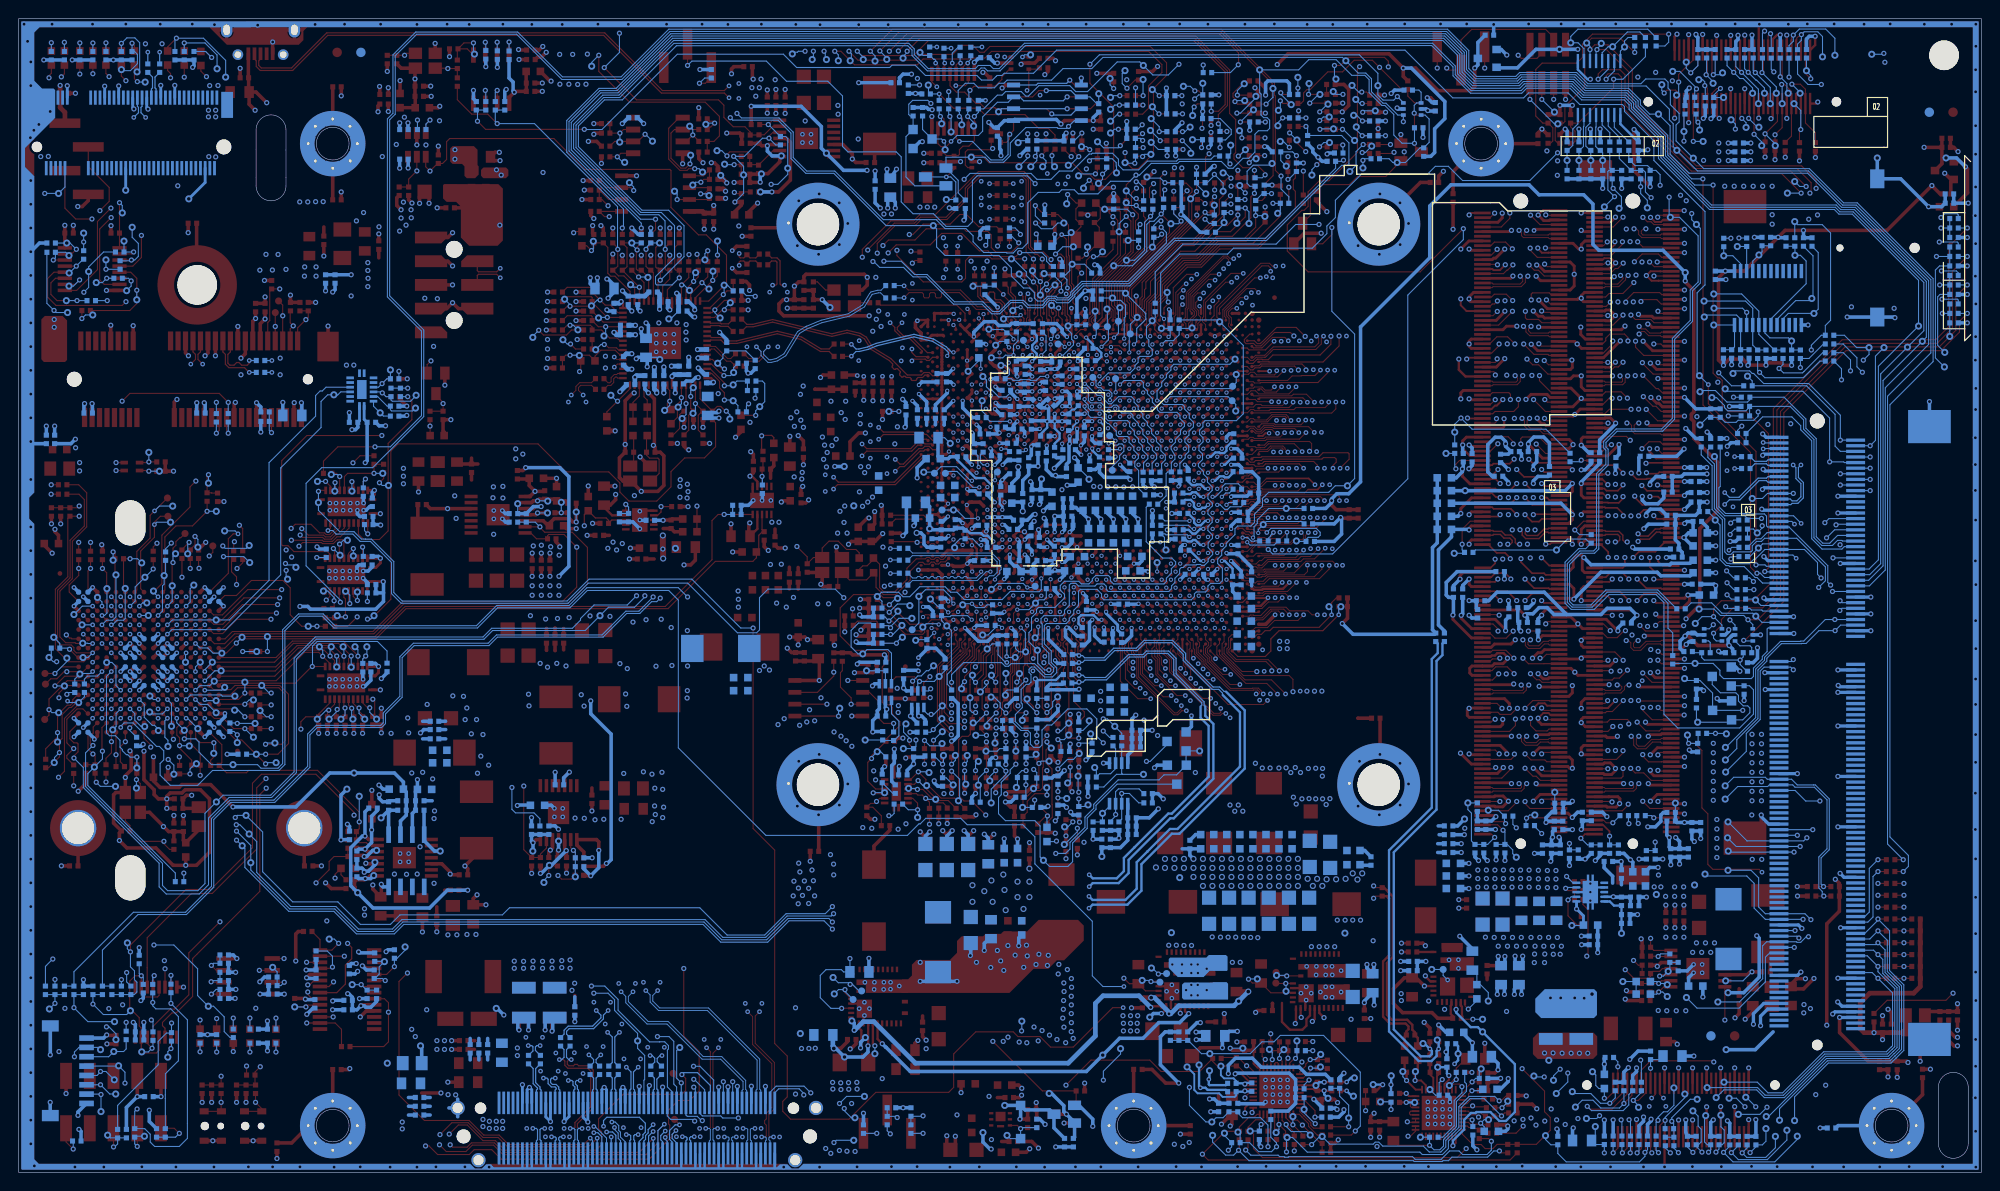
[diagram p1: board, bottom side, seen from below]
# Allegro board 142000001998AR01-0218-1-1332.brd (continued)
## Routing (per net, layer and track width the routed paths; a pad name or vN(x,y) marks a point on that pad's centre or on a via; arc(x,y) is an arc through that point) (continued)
SMB_PCU_CLK_P3V3_SWITCH: length 112.7
  TOP w0.114: R45.2 v2(85.5,110.44)
  S3 w0.102: v2(4.8,98.04) 10.59,103.84 29.74,103.84 30.51,104.6 v2(32.18,104.6)
  S8 w0.102: v2(32.18,104.6) 32.18,105.28 37.6,110.69 47.27,110.69 52.91,116.33 69.97,116.33 70.17,116.54 76.28,116.54 76.58,116.84 78,116.84 78.43,116.4 78.58,116.26 84.31,116.26 84.73,115.84 84.73,111.2 v2(85.5,110.44)
  BOTTOM w0.114: R1101.1 R1102.1 ; R1101.1 R942.2 4.47,97.03 4.91,96.58 4.91,87.19 v1(3.95,86.22) ; R1101.1 v2(4.8,98.04) ; v1(84.58,109.09) 84.58,109.52 v2(85.5,110.44)
SMB_PCU_CLK_P3V3_SWITCH_R: length 28.5
  TOP w0.114: U9.BN11 89.48,87.02 v4(89.68,86.91) ; R45.1 v2(87.86,110.44)
  S10 w0.102: v2(87.86,110.44) 87.86,108.31 86.9,107.34 86.9,104.37 86.84,104.32 86.84,98.99 89.64,96.19 89.64,90.53 90.31,89.85 90.31,89.3 90.07,89.05 90.07,88.37 89.79,88.09 89.79,87.02 v4(89.68,86.91)
  BOTTOM w0.114: v2(87.86,110.44) 87.86,110.49 v1(88.9,111.53)
SMB_PCU_CLK_SW_I2C_BUS: length 52.6
  TOP w0.114: v2(18.34,104.83) 18.21,104.95 18.21,105.94 19.74,107.47 30.77,107.47 37.74,114.44 37.74,117.83 40.11,120.19 v2(41.12,120.19)
  S3 w0.102: v2(18.34,104.83) 9.73,104.83 v2(4.5,99.59)
  BOTTOM w0.114: R1102.2 2.47,99.48 2.58,99.59 v2(4.5,99.59) ; v1(40.66,120.86) 40.66,120.73 41.12,120.27 v2(41.12,120.19) 41.22,120.1 U45.5
SMB_PCU_CLK_SW_I2C_MUX: length 61.8
  TOP w0.114: v2(1.5,98.04) 3.1,96.44 3.1,90.37 4.72,88.75 14.73,88.75 21.87,81.6 21.87,61.95 23.39,60.43 26.57,60.43 27.81,59.18 27.81,58.55 v2(28.65,57.71)
  BOTTOM w0.114: U40.1 28.36,56.88 28.65,57.18 v2(28.65,57.71) ; R1101.2 v2(1.5,98.04)
SMB_PCU_DATA_I2C_BUS: length 3.4
  BOTTOM w0.114: R1107.1 38.73,110.82 39.92,112 U45.14
SMB_PCU_DATA_I2C_MUX: length 76
  S3 w0.102: v2(18.47,102.03) 32.04,102.03 35.06,105.05 35.99,105.05 v2(36.45,105.51)
  S10 w0.102: v2(26.9,59.13) 26.06,59.97 26.06,61.69 25.84,61.91 25.84,64.82 25.53,65.13 25.53,66.95 25.88,67.3 25.88,69.21 26.63,69.96 29.05,69.96 30.3,71.21 30.3,80.38 29.97,80.71 29.97,81.09 30.28,81.39 30.28,88.62 18.47,100.43 v2(18.47,102.03)
  BOTTOM w0.114: v1(35.74,103.25) 35.74,104.06 36.45,104.78 v2(36.45,105.51) R1108.1 ; v2(26.9,59.13) 26.35,58.58 U41.4
SMB_PCU_DATA_P3V3: length 537.9
  TOP w0.114: v2(198.93,82.55) 198.1,83.39 188.54,83.39 v2(187.58,82.42) ; v2(79.5,118.57) 79.48,118.59 79.48,119.84 81.51,121.87 114.99,121.87 v2(116.84,120.02)
  S3 w0.102: v2(116.84,120.02) 116.84,119.56 117.4,119 140.42,119 145.74,113.69 160.45,113.69 165.68,108.46 169.66,108.46 176.45,101.66 192.51,101.66 195.94,98.23 195.94,86 198.93,83.01 v2(198.93,82.55) 198.93,79.87 200.91,77.89 200.91,67.96 200.42,67.47 200.42,65.23 199.69,64.51 199.69,61.87 199.7,61.86 199.7,61.36 199.69,61.35 199.69,60.89 199.62,60.82 199.62,47.98 201.12,46.48 201.12,45.72 201.55,45.29 201.55,44.83 201.12,44.4 201.12,25.03 197.94,21.86 197.94,18.14 197.26,17.45 197.26,15.32 196.22,14.28 185.49,14.28 184.3,15.47 184.3,17.23 v2(184.63,17.56)
  S5 w0.102: v2(35.33,104.34) 34.52,103.53 30.33,103.53 v2(26.8,100) 22.6,104.19 21.4,104.19 17.04,108.55 17.04,112.93 18.16,114.05 18.16,115.89 19.52,117.25 v2(20.57,117.25) ; v2(206.12,18.08) 206.12,17.58 205.51,16.97 187.91,16.97 187.31,17.56 v2(184.63,17.56)
  S8 w0.102: v2(20.57,117.25) 21.69,118.36 34.24,118.36 v2(34.85,117.75)
  S10 w0.102: v2(37.69,5.63) 37.69,5.97 36.45,7.21 36.45,7.89 34.13,10.21 18.36,10.21 9.58,18.99 9.58,39.97 19.81,50.21 19.81,51.39 21.43,53.01 21.95,53.01 24.84,55.91 24.84,57.19 25.78,58.13 25.78,61.65 25.61,61.82 25.61,64.73 25.3,65.04 25.3,67.04 25.65,67.4 25.65,68.19 25.65,69.47 26.42,70.23 27.94,70.23 28.17,70.46 29.23,70.46 30.05,71.28 30.05,75.14 30.07,75.17 30.07,75.74 30.05,75.76 30.05,80.31 29.74,80.61 29.74,81.18 30.05,81.49 30.05,88.4 14.5,103.95 14.5,115.57 16.69,117.75 20.07,117.75 v2(20.57,117.25) ; v2(34.85,117.75) 35.03,117.93 51.61,117.93 52.96,119.28 78.79,119.28 v2(79.5,118.57)
  BOTTOM w0.114: R670.1 R671.1 ; R670.1 R669.1 ; R670.1 v2(206.12,18.08) v1(206.72,17.49) ; R488.1 80.34,117.73 v2(79.5,118.57) ; v2(35.33,104.34) 35.94,104.95 35.94,107.06 36.14,107.26 R1108.2 R1068.1 38.73,108.53 R1107.2 ; v2(37.69,5.63) 37.54,5.48 R762.2 ; R158.1 v2(187.58,82.42) ; R426.2 v2(20.57,117.25) ; R498.1 v2(26.8,100)
SMB_PCU_DATA_P3V3_SWITCH: length 104.1
  TOP w0.114: R40.2 v2(76.65,110.74)
  S3 w0.102: v2(17.53,102.49) 6.99,91.95 v2(4.17,91.95)
  S10 w0.102: v2(17.53,102.49) 16.1,103.91 16.1,114.06 16.32,114.28 16.32,116.3 17.54,117.53 18.52,117.53 21.44,114.6 33.45,114.6 35,113.06 48.59,113.06 51.13,115.59 52.18,115.59 52.69,116.1 71.92,116.1 73.56,114.47 73.56,113.37 76.19,110.74 v2(76.65,110.74)
  BOTTOM w0.114: R1104.1 R1103.1 ; R1103.1 R943.2 v1(3.38,89.48) ; R1103.1 v2(4.17,91.95)
SMB_PCU_DATA_P3V3_SWITCH_R: length 34.5
  TOP w0.114: R40.1 v2(79.12,110.74) ; U9.BJ13 90.88,86.34 v4(91.17,86.05)
  S5 w0.102: v2(79.12,110.74) 79.12,109.91 81.13,107.91 81.13,106.8 81.78,106.15 82.04,106.15 82.65,105.54 82.65,103.95 82.6,103.9 82.6,100.46 84.2,98.86 85.25,98.86 86.02,98.08 89.9,94.21 90.59,94.21 90.93,93.87 90.93,92.08 92.38,90.63 92.38,88.19 92.56,88.01 92.56,87.35 92.2,87 92.2,86.72 91.54,86.05 v4(91.17,86.05)
  BOTTOM w0.114: v1(79.38,111.51) 79.12,111.25 v2(79.12,110.74)
SMB_PCU_DATA_SW_I2C_BUS: length 60.3
  TOP w0.114: v2(41.87,120.19) 41.36,120.7 39.95,120.7 37.34,118.09 37.34,114.6 30.49,107.75 19.23,107.75 17.68,106.2 v2(17.68,105.33)
  S3 w0.102: v2(17.68,105.33) 9.36,105.33 3.78,99.76 3.78,93.88 4.19,93.47 v2(4.21,93.47)
  BOTTOM w0.114: U45.6 v2(41.87,120.19) 41.87,120.54 v1(42.23,120.89) ; R1104.2 2.47,93.37 2.57,93.47 v2(4.21,93.47)
SMB_PCU_DATA_SW_I2C_MUX: length 52.9
  TOP w0.114: v2(25.43,56.95) 25.3,56.95 21.13,61.11 21.13,81.3 14.47,87.96 4.32,87.96 2.34,89.94 2.34,91.11 v2(1.5,91.95)
  BOTTOM w0.114: R1103.2 v2(1.5,91.95) ; v2(25.43,56.95) 25.36,56.88 U41.1
SMB_PWR_ALERT_N: length 189.6
  TOP w0.114: R194.1 v2(202.31,67.44) ; R31.2 v2(76.61,112.44)
  S3 w0.102: v2(202.31,67.44) 202.31,68.72 201.83,69.2 201.83,78.27 201.29,78.81 200.32,79.78 200.32,87.26 199.32,88.26 199.32,98.8 195.24,102.88 176.59,102.88 172.36,107.11 172.36,108.85 169.78,111.43 165.61,111.43 165.3,111.74 164.19,111.74 161.05,114.88 149.34,114.88 148.63,115.6 145.46,115.6 140.1,120.95 69.33,120.95 68.17,119.8 68.17,118.13 71.37,114.94 74.07,114.94 74.75,114.25 75.28,114.25 76,113.53 76,113.06 v2(76.61,112.44)
  BOTTOM w0.114: R31.2 v2(76.61,112.44)
SMB_PWR_ALERT_N_R: length 34.5
  TOP w0.114: R31.1 v2(79.28,112.44) ; U9.BC9 93.39,88.05 v4(93.12,87.78)
  S5 w0.102: v4(93.12,87.78) 92.75,88.16 92.75,88.56 93.18,88.99 93.18,90.11 91.16,92.13 91.16,94.55 85.17,100.54 85.17,102.52 82.88,104.8 82.88,105.63 82.14,106.38 81.88,106.38 81.61,106.64 81.61,108.52 79.63,110.5 79.63,112.09 v2(79.28,112.44)
  BOTTOM w0.114: v1(77.88,113.74) 77.98,113.74 v2(79.28,112.44)
SMB_PWR_ALERT_R_N: length 3.6
  TOP w0.114: R194.2 v2(202.31,64.64) 202.59,64.37 U12.A15
SMB_VR_P1V2_SCL: length 19.2
  TOP w0.114: U29.20 55.54,4.09 54.42,2.98 53.52,2.98 53.09,2.54 52.26,2.54 51.81,2.99 R403.1 R770.1 47.62,2.99 46.12,4.49 46.12,5.88 46.73,6.48 46.73,8.7 v2(49.13,11.1)
SMB_VR_P1V2_SDA: length 3.1
  TOP w0.114: R392.1 53.11,4.52 R398.1 53.89,4.69 54.5,4.69 54.61,4.79 54.83,4.79 54.99,4.95 U29.19
SMB_VR_SCL: length 167.9
  TOP w0.114: R403.2 51.36,2.09 v2(51.56,2.29) ; v2(79.48,2.36) 79.4,2.44 R397.2
  S5 w0.102: v2(79.48,2.36) 80.75,1.09 125.42,1.09 126.53,2.21 127.43,2.21 128.26,1.38 147,1.38 147.83,2.21 165.21,2.21 166.83,3.84 169.66,3.84 172.03,6.21 172.03,8.52 173.93,10.42 174.86,10.42 176.05,11.61 178.87,11.61 179.41,12.16 180.43,12.16 184.13,15.85 184.13,17.91 185.29,19.08 187.03,19.08 187.67,18.44 192.58,18.44 193.42,19.28 197.66,19.28 v2(199.01,20.62)
  BOTTOM w0.114: v1(82.25,3.96) 82.25,3.24 80.85,1.84 80,1.84 v2(79.48,2.36) 78.36,1.24 60.77,1.24 60.68,1.16 57.68,1.16 57.6,1.24 57.02,1.24 56.64,1.63 52.82,1.63 52.16,2.29 v2(51.56,2.29) ; R653.2 v2(199.01,20.62)
SMB_VR_SDA: length 192
  TOP w0.114: v2(78.71,2.39) 78.46,2.64 R396.2 ; R398.2 52.71,3.61 v2(52.43,3.33)
  S3 w0.102: v2(52.43,3.33) 42.4,3.33 41.25,4.48 41.25,5.67 v2(40.85,6.07)
  S5 w0.102: v2(78.71,2.39) 79.15,2.82 81.45,2.82 82.92,1.35 125.35,1.35 126.44,2.44 127.53,2.44 128.35,1.61 146.91,1.61 147.74,2.44 165.11,2.44 166.79,4.11 169.62,4.11 171.81,6.3 171.81,8.62 173.84,10.65 174.76,10.65 175.96,11.84 178.77,11.84 179.32,12.39 180.34,12.39 183.9,15.95 183.9,18.56 183.39,19.07 183.39,22.89 183.89,23.38 194.7,23.38 196.11,21.97 204.8,21.97 v2(206.12,20.65)
  BOTTOM w0.114: v1(42.25,5.76) 41.16,5.76 v2(40.85,6.07) ; v2(52.43,3.33) 52.43,2.36 52.5,2.3 52.67,2.12 52.89,1.91 55.5,1.91 55.88,2.29 56.9,2.29 57.78,1.4 60.58,1.4 60.86,1.68 74.1,1.68 74.15,1.62 74.54,1.62 74.59,1.68 75.08,1.68 75.24,1.84 78.16,1.84 v2(78.71,2.39) ; R670.2 v2(206.12,20.65)
SML0_ALERT_N_R: length 10.2
  TOP w0.114: U9.BL7 v4(90.67,88.63)
  BOTTOM w0.114: v4(90.67,88.63) 90.37,88.92 90.37,90.35 89.41,91.31 89.41,91.95 v1(91.57,94.11) 91.82,94.36 R485.2
SML0_CLK: length 104.5
  TOP w0.114: R8.1 73.13,115.39 v2(73.13,116.08)
  S3 w0.102: v2(28.19,84.58) 28.19,84.07 30.38,81.89 31.6,81.89 32.28,81.2 32.28,67.13 29.46,64.31 29.46,62.23 28.6,61.37 27.66,61.37 v2(27.2,61.82)
  S5 w0.102: v2(28.19,84.58) 29.97,86.36 29.97,100.2 31.27,101.5 57.75,101.5 62.46,106.2 71.47,106.2 72.03,106.76 72.03,108.37 72.75,109.08 72.75,110.57 71.49,111.83 71.49,113.27 73.13,114.91 v2(73.13,116.08)
  BOTTOM w0.114: R8.1 73.13,115.39 v2(73.13,116.08) v1(73.13,117.22) ; R581.2 26.74,61.36 v2(27.2,61.82)
SML0_CLK_R: length 39
  TOP w0.114: R8.2 74.78,115.39 v2(74.96,115.57) ; U9.BR7 88.4,88.91 v4(88.69,88.63)
  S5 w0.102: v2(74.96,115.57) 74.93,115.57 74.17,114.81 74.17,113.92 74.63,113.46 74.99,113.46 75.36,113.1 75.36,112.32 76.19,111.49 76.19,108.68 77.19,107.69 77.19,102.23 77.46,101.96 78.43,101.96 79.81,100.58 80.27,100.58 81.85,99 83.4,97.46 84.59,97.46 88.29,93.76 88.29,90.78 89.33,89.74 89.33,89.18 88.78,88.63 v4(88.69,88.63)
  BOTTOM w0.114: v1(73.84,114.3) 74.96,115.42 v2(74.96,115.57)
SML0_DATA: length 113
  TOP w0.114: R25.1 v2(85.47,113.31)
  S8 w0.102: v2(85.47,113.31) 86,113.84 86,115.45 84.96,116.48 78.67,116.48 78.18,116.98 78.09,117.07 76.49,117.07 76.18,116.76 70.07,116.76 69.87,116.56 52.56,116.56 48.57,112.57 37.41,112.57 31.95,107.11 31.95,105.7 29.64,103.39 29.64,84.15 29.51,84.02 29.51,79.72 29.79,79.44 29.79,77.65 29.44,77.29 28.63,76.48 28.63,71.05 28.88,70.79 28.88,62.08 v2(27.36,60.55)
  BOTTOM w0.114: R585.2 27.17,60.37 v2(27.36,60.55) ; R25.1 v2(85.47,113.31)
SML0_DATA_R: length 34.9
  TOP w0.114: v4(89.68,83.47) 89.39,83.76 U9.BN18 ; R25.2 v2(87.99,113.31)
  S10 w0.102: v4(89.68,83.47) 89.68,84.55 90.14,85.01 90.14,85.39 90.58,85.83 90.58,86.23 91.05,86.71 91.05,87.1 90.79,87.37 90.79,88.07 91.05,88.34 91.05,96.45 88.44,99.06 88.44,103.99 89.03,104.57 89.03,109.39 89,109.42 89,112.29 v2(87.99,113.31)
  BOTTOM w0.114: v1(88.7,114.07) 88.7,114.02 v2(87.99,113.31)
SML1_ALERT: length 7.2
  TOP w0.114: v4(91.71,89.25) 92.05,88.91 U9.BF7
  BOTTOM w0.114: v4(91.71,89.25) 91.71,91.48 91.57,91.62 91.57,92.84 92.08,93.34 92.71,93.34 v1(92.96,93.6) 94.03,93.6 R483.2
SML1_CLK: length 114
  S8 w0.102: v2(27.25,64.38) 27.26,64.38 27.67,64.8 27.67,69.63 28.22,70.18 28.22,83.95 29.16,84.89 29.16,103.23 31.67,105.75 31.67,107.16 37.31,112.8 48.25,112.8 52.23,116.79 69.78,116.79 69.98,116.99 76,116.99 76.13,117.13 76.36,117.35 78.13,117.35 78.77,116.71 85.06,116.71 86.44,115.33 86.44,113.76 v2(89.74,110.46)
  BOTTOM w0.114: R790.2 90.5,110.67 R452.1 89.97,110.69 v2(89.74,110.46) ; v2(27.25,64.38) 27.25,64.38 26.52,63.65 R576.2
SML1_CLK_R: length 24.9
  TOP w0.114: v4(93.13,88.35) 92.99,88.49 92.25,88.49 91.81,88.05 U9.BG9
  S10 w0.102: v2(90.58,108.03) 89.94,107.39 89.94,103.1 90.22,102.82 90.22,102.05 93.01,99.25 93.01,94.44 93.18,94.27 93.18,88.81 93.13,88.76 v4(93.13,88.35)
  BOTTOM w0.114: v1(91.62,108.09) 91.56,108.03 v2(90.58,108.03) 90.5,108.1 R790.1
SML1_DATA: length 116.8
  TOP w0.114: v2(89.79,112.14) 90.27,111.66 R789.2
  S8 w0.102: v2(27.21,63.11) 26.68,63.65 26.68,64.89 27.44,65.66 27.44,69.63 26.14,70.94 26.14,73.43 27.74,75.03 27.74,84.77 28,85.04 28.18,85.04 28.7,85.56 28.7,103.1 31.42,105.82 31.42,107.27 37.21,113.06 47.85,113.06 51.82,117.02 69.68,117.02 69.89,117.22 75.91,117.22 76.26,117.58 78.23,117.58 78.86,116.94 86.98,116.94 88.9,115.02 88.9,113.03 v2(89.79,112.14)
  BOTTOM w0.114: v2(89.79,112.14) 90.27,111.66 R789.2 ; v2(27.21,63.11) 26.47,62.38 R579.2
SML1_DATA_R: length 30.6
  TOP w0.114: R789.1 v2(92.33,111.66) ; U9.BB11 93.76,86.82 v4(93.56,86.82)
  S10 w0.102: v4(93.56,86.82) 94.03,87.29 94.03,87.71 94.55,88.24 94.55,93.93 96.43,95.81 96.46,95.81 96.72,96.08 96.72,102.25 92.89,106.09 92.89,111.1 v2(92.33,111.66)
  BOTTOM w0.114: v1(93.17,111.26) 92.78,111.66 v2(92.33,111.66)
SMP_TESTDDR01_VIEWDIG0: length 12.8
  TOP w0.114: R211.1 69.01,61.49 69.52,60.99 v3(69.52,59.68) 70.86,58.34 75.77,58.34 76.12,57.99 76.63,57.99 77.02,57.6 77.47,57.6 77.82,57.25 U9.CU76
  BOTTOM w0.114: v1(69.8,60.55) 69.52,60.27 v3(69.52,59.68)
SMP_TESTDDR01_VIEWDIG1: length 16.1
  TOP w0.114: v3(68.76,59.68) 68.73,59.71 R215.1 ; U9.CM78 79.55,55.22
  TOP w0.127: v3(68.76,59.68) 70.45,57.99 75.13,57.99 76.02,57.1 76.02,55.8 76.61,55.22 79.55,55.22
  BOTTOM w0.114: v3(68.76,59.68) 68.76,60.33 v1(68.53,60.55)
SOC_FPGA_CLK: length 126.7
  TOP w0.114: U12.C3 v3(190.09,60.61) ; R51.2 v2(102.03,111.18)
  S3 w0.102: v2(102.03,111.18) 102.77,110.44 105.6,110.44 107.45,108.58 107.47,108.58 108.42,107.63 111.01,107.63 115.06,103.58 115.06,103.49 116.47,102.08 117.12,102.08 122.32,96.88 130.48,96.88 131.27,96.09 133.88,96.09 134.67,96.88 135.51,97.71 155.7,97.71 156.99,99.01 160.5,99.01 163.09,101.6 165.85,101.6 170.89,96.56 170.89,87.02 188.62,69.29 188.62,64.64 189.64,63.62 189.64,61.06 v3(190.09,60.61)
  BOTTOM w0.114: v2(102.03,111.18) R51.2 102.8,110.44 103.01,110.23 v1(103.06,110.23)
SOC_FPGA_CLK_R: length 45.8
  TOP w0.114: R51.1 v2(102.03,108.81)
  TOP w0.254: v4(94.35,81.21) 94.35,81.22 94.36,81.23 94.36,81.24 94.71,81.59 U9.BA23
  S5 w0.102: v4(94.35,81.21) 94.75,80.81 99.31,80.81 99.57,81.07 99.57,82.17 100.3,82.91 100.3,84.49 101.41,85.6 101.69,85.6 101.95,85.86 101.95,87.84 101.68,88.11 101.68,88.67 101.95,88.94 101.95,89.36 99.33,91.97 95.83,91.97 94.41,93.39 94.41,98.41 100.58,104.58 100.58,105.53 100.56,105.56 100.56,106.13 101.7,107.27 101.7,108.48 v2(102.03,108.81)
  BOTTOM w0.114: v1(102.97,107.66) 102.03,108.6 v2(102.03,108.81)
SOC_FPGA_DIN: length 138.1
  TOP w0.114: R54.2 v2(96.24,111.25) ; U12.E3 v3(190.09,58.61)
  S3 w0.102: v2(96.24,111.25) 97.76,109.73 102.62,109.73 103.05,109.3 103.06,109.3 103.33,109.03 103.33,108.64 104.68,107.29 107.8,107.29 108.28,106.8 109.48,106.8 109.8,106.48 109.8,105.28 111.46,103.63 111.46,103.1 113.16,101.4 116.48,101.4 118.62,99.26 118.62,98.2 119.35,97.46 120.77,97.46 122.04,96.19 130.18,96.19 130.99,95.38 134.22,95.38 135.66,96.81 135.67,96.81 135.75,96.89 155.84,96.89 157.28,98.32 160.93,98.32 162.71,100.1 166.38,100.1 169.9,96.58 169.9,82.22 175.62,76.5 180.34,76.5 187.38,69.47 187.38,60.28 189.05,58.61 v3(190.09,58.61)
  BOTTOM w0.114: R456.1 97.08,110.41 v2(96.24,111.25)
SOC_FPGA_DIN_R: length 34.7
  TOP w0.114: U9.BB16 93.74,85 v4(93.44,85) ; R54.1 95.43,109.5 v2(95.4,109.47)
  S5 w0.102: v2(95.4,109.47) 95.4,109.07 96.22,108.25 96.22,106.26 92.46,102.5 92.46,101.41 92.53,101.33 92.53,92.79 94.83,90.5 96.35,90.5 97.28,89.58 97.28,89.26 97.13,89.11 97.13,88.27 97.03,88.16 96.92,88.16 96.7,87.94 96.7,87.81 96.3,87.41 96.3,86.4 96.32,86.39 96.32,85.84 96.08,85.6 95.76,85.6 94.99,84.83 93.6,84.83 v4(93.44,85)
  BOTTOM w0.114: v1(96.28,109.8) 95.73,109.8 v2(95.4,109.47)
SOC_FPGA_DOUT: length 218.2
  TOP w0.114: U12.E13 v3(201.09,58.61) ; v2(68.33,109.98) 68.89,109.98 R61.2
  S3 w0.102: v3(201.09,58.61) 201.63,58.06 203.12,58.06 205.26,60.2 205.26,67.79 204.52,68.53 204.52,81.37 201.69,84.2 201.69,92.47 202.06,92.84 202.06,98.64 196.36,104.33 191.24,104.33 186.55,109.03 186.55,114.15 183.64,117.05 176.26,117.05 171.54,121.77 164.36,121.77 162.97,120.37 157.34,120.37 156.7,119.74 155.83,119.74 155.14,119.04 144.18,119.04 140.89,122.33 140.67,122.33 140.66,122.33 140.29,122.33 68.76,122.33 65.84,119.41 65.84,115.46 66.18,115.11 66.7,115.11 67.81,114 68.55,114 68.83,113.71 68.83,110.49 v2(68.33,109.98)
  BOTTOM w0.114: v1(199.59,63.96) 199.59,59.46 199.95,59.11 200.59,59.11 v3(201.09,58.61) ; R461.1 68.3,109.96 v2(68.33,109.98)
SOC_FPGA_DOUT_R: length 46.2
  TOP w0.114: v4(94.35,81.99) 94.35,81.97 93.97,81.59 U9.BB23 ; R61.1 v2(70.82,109.78)
  S3 w0.102: v4(94.35,81.99) 94.19,82.14 93.17,82.14 92.74,82.58 92.74,82.8 92.18,83.36 92.18,83.57 91.67,84.07 91.67,84.43 91.26,84.84 91.26,85.42 91.57,85.72 91.57,86.23 91.26,86.54 91.26,87.2 91.57,87.5 91.57,88.11 91.26,88.42 91.26,89.46 91.85,90.04 91.85,93.47 90.58,94.74 89.4,94.74 87.05,97.09 86.29,97.86 86.1,98.05 85.84,98.31 85.57,98.57 83.03,98.57 80.63,100.97 76.84,100.97 71.58,106.23 71.58,109.02 v2(70.82,109.78)
  BOTTOM w0.114: v1(69.75,110.24) 70.36,110.24 v2(70.82,109.78)
SPI_10GBE_1T45_DIR: length 3.5
  BOTTOM w0.114: Q9.5 117.26,53.66 R601.2 R602.2 v1(119.28,53.7)
SPI_10GBE_CLK: length 14.4
  TOP w0.114: R273.2 v2(113.08,43.69) ; R1053.1 117.7,38.17 118.61,39.09 R1052.2 118.84,39.5 118.41,39.5 v2(118.21,39.7) 117.87,40.04 U18.11
  S5 w0.102: v2(118.21,39.7) 115.62,39.7 114.81,40.51 113.64,40.51 113.08,41.07 v2(113.08,43.69)
SPI_10GBE_CLK_LVC3V3: length 21
  TOP w0.127: U16.6 v2(123.52,50.11)
  S5 w0.102: v2(116.89,38.18) 117.47,38.18 117.55,38.25 119,38.25 119.76,39.01 119.76,45.27 123.52,49.04 v2(123.52,50.11)
  BOTTOM w0.114: R640.1 116.33,38.42 116.57,38.18 v2(116.89,38.18)
SPI_10GBE_CLK_LVC3V3_R: length 4.6
  TOP w0.114: U18.6 114.33,40.04 113.82,39.52 v2(113.82,38.81)
  BOTTOM w0.114: v1(113.82,38) v2(113.82,38.81) 114.81,38.81 R640.2
SPI_10GBE_CLK_R: length 25
  TOP w0.114: U9.M67 107.8,61.44 v4(107.51,61.73) ; R273.1 v2(113.08,46.23)
  S10 w0.102: v2(113.08,46.23) 113.08,47.27 112.73,47.62 112.73,47.64 111.91,48.45 111.91,54.99 112.78,55.85 112.78,58.45 112.47,58.75 112.22,58.75 111.61,58.14 110.95,58.14 110.77,58.32 110.77,58.98 109.93,59.82 109.93,60.17 109.63,60.48 107.82,60.48 107.49,60.81 107.49,61.71 v4(107.51,61.73)
  BOTTOM w0.114: v2(113.08,46.23) 112.52,45.66 111.44,45.66 v1(111.2,45.9)
SPI_10GBE_CS_N: length 47.5
  TOP w0.109: v4(107.04,62.59) 107.02,62.56 U9.P67
  TOP w0.114: v2(115.16,62.1) 115.75,61.52 117.5,61.52 117.83,61.85 120.68,61.85 122.1,60.43 122.1,57.43 120.55,55.88 117.2,55.88 116.91,55.59 116.91,54.79 117.6,54.1 117.6,50.33 117.31,50.04 116.79,50.04 116.54,49.78 116.54,49.07 115.71,48.25 115.71,47.84 117.19,46.36 R1051.2 118.75,44.6 v2(118.75,44.3) 119.15,43.89 119.15,41.88 118.31,41.04 U18.13
  S5 w0.102: v4(107.04,62.59) 107.5,63.04 113.94,63.04 114.88,62.1 v2(115.16,62.1)
  BOTTOM w0.114: v2(118.75,44.3) 118.75,44.42 v1(118.14,45.03) 117.78,45.03 R628.1
SPI_10GBE_CS_N_LVC3V3: length 26.9
  TOP w0.114: U16.1 v2(121.28,52.65) ; R301.1 R300.2 v2(111.55,37.31)
  S5 w0.102: v2(121.28,52.65) 118.06,49.43 118.06,42.79 118.33,42.52 118.82,42.52 119.02,42.32 119.02,39.43 118.61,39.01 115.44,39.01 114.73,38.3 112.54,38.3 v2(111.55,37.31)
SPI_10GBE_CS_N_LVC3V3_R: length 6.1
  TOP w0.114: R301.2 110.65,39.12 111.07,39.55 111.81,39.55 113.26,40.99 v2(113.84,40.99) 113.89,41.04 U18.4
  BOTTOM w0.114: v1(114.78,41.1) 113.95,41.1 v2(113.84,40.99)
SPI_10GBE_DIR_1: length 9.4
  TOP w0.114: U18.2 114.58,42.04 v2(113.74,42.88) 112.93,42.06 112.93,41.68 111.3,40.06 109.86,40.06 R283.1
  BOTTOM w0.114: v2(113.74,42.88) 113.74,42.88 112.68,42.88 v1(112.6,42.8)
SPI_10GBE_DIR_2: length 7.7
  TOP w0.114: U18.3 114.16,41.54 v2(113.77,41.94) 111.63,39.8 110.54,39.8 R287.1
  BOTTOM w0.114: v1(112.85,41.4) 113.23,41.4 v2(113.77,41.94)
SPI_10GBE_MISO: length 13.5
  TOP w0.114: U9.D74 111.82,58.27 v4(112.32,58.27) ; R1048.2 120.25,59 118.21,59 118.13,58.92 R220.1 116.94,58.52 v2(116.71,58.29)
  S8 w0.102: v4(112.32,58.27) 116.69,58.27 v2(116.71,58.29)
  BOTTOM w0.114: v1(114.43,59.31) 115.82,59.31 116.71,58.42 v2(116.71,58.29) 116.94,58.52 R589.2
SPI_10GBE_MISO_LVC3V3: length 8
  BOTTOM w0.114: v1(119.43,46.28) R618.2 117.5,46.23 R619.2 116.31,46.23 115.82,46.72 115.82,48.29 116.61,49.09 Q9.3
SPI_10GBE_MISO_LVC3V3_R: length 6.6
  TOP w0.114: v2(116.38,48.06) 117.42,48.06 117.96,48.59 117.96,50.37 118.97,51.38 U16.2
  BOTTOM w0.114: R619.1 v2(116.38,48.06)
SPI_10GBE_MISO_R: length 12.9
  BOTTOM w0.114: R589.1 118.81,58.8 120.14,58.8 120.93,58.01 120.93,56.24 120.19,55.5 v1(119.68,55.5) 119.23,55.96 116.99,55.96 116.61,55.58 Q9.4
SPI_10GBE_MOSI: length 19.7
  TOP w0.114: U18.12 118.33,40.54 118.41,40.62 v2(118.57,40.62) ; R236.2 v2(112.47,50.82)
  S5 w0.102: v2(112.47,50.82) 113.75,50.82 115.42,49.15 115.42,47.62 115.85,47.19 115.85,44.63 116.43,44.04 116.43,42.7 118.51,40.62 v2(118.57,40.62)
  BOTTOM w0.114: R1049.1 116.46,40.57 R1050.2 117.6,40.89 v1(117.35,40.64) 118.54,40.64 118.56,40.62 v2(118.57,40.62)
SPI_10GBE_MOSI_LVC3V3: length 25.1
  TOP w0.114: R302.1 v2(112.55,37.26)
  TOP w0.127: v2(122.28,48.83) 122.39,48.83 122.4,48.84 U16.5
  S5 w0.102: v2(122.28,48.83) 121.68,48.83 119.27,46.43 119.27,39.21 118.85,38.79 115.53,38.79 114.82,38.07 113.36,38.07 v2(112.55,37.26)
  BOTTOM w0.114: v1(122.15,49.68) 122.28,49.56 v2(122.28,48.83)
SPI_10GBE_MOSI_LVC3V3_R: length 4.4
  TOP w0.114: R302.2 112.55,39.62 v2(112.95,40.03) 113.31,40.39 113.79,40.39 113.94,40.54 U18.5
  BOTTOM w0.114: v1(111.89,39.93) 112.85,39.93 v2(112.95,40.03)
SPI_10GBE_MOSI_R: length 12.1
  TOP w0.114: U9.C73 111.66,58.75 v4(111.56,58.65) ; v2(112.5,53.06) 113.17,52.39 R236.1
  S10 w0.102: v4(111.56,58.65) 112.09,59.18 112.6,59.18 113.16,58.62 113.16,55.63 112.5,54.97 v2(112.5,53.06)
  BOTTOM w0.114: v4(111.56,58.65) 111.63,58.72 112.9,58.72 v1(113.26,58.37)
SPI_CS_SELECT: length 389.5
  TOP w0.114: U12.M9 v3(197.09,50.61) ; R33.2 60.65,113.36 ; 60.65,113.36 60.48,113.18 U2.6 ; 60.65,113.36 v2(60.68,113.39)
  S3 w0.102: v2(97.17,14.34) 95.46,12.62 88.01,12.62 86.43,11.05 79.67,11.05 79.04,10.41 73.89,10.41 72.44,8.97 71.92,8.97 70.05,7.1 70.05,6.88 69.19,6.02 66.77,6.02 66.39,5.64 63.13,5.64 62.24,6.53 61.48,6.53 59.59,8.42 54.84,8.42 54.7,8.28 54.32,8.28 53.28,9.32 44.27,9.32 42.95,10.64 33.67,10.64 31.18,13.13 25.85,13.13 25.17,12.45 11.17,12.45 4.85,18.77 4.85,22.81 3.33,24.33 3.33,101.99 8.29,106.96 30.54,106.96 30.73,106.96 34,110.23 34.04,110.26 34.04,114.1 34.85,114.91 34.85,116.12 37.4,118.67 58.41,118.67 60.68,116.4 v2(60.68,113.39)
  S8 w0.102: v3(197.09,50.61) 196.15,50.61 195.58,50.04 195.58,48.47 193.98,46.87 193.98,45.91 193.07,45 191.86,45 189.38,42.52 189.38,40.65 187.5,38.77 187.5,32.56 182.12,27.18 178.34,27.18 176.59,25.43 170.68,25.43 169.03,23.77 150.55,23.77 147.81,21.03 115.18,21.03 111.49,17.35 105.21,17.35 104.91,17.04 100.65,17.04 98.03,14.42 97.25,14.42 v2(97.17,14.34)
  BOTTOM w0.114: v1(195.06,47.3) 195.07,47.31 195.07,47.46 195.47,47.85 195.71,47.85 196.57,48.71 196.57,50.09 v3(197.09,50.61) ; v2(60.68,113.39) 60.68,114.23 60.42,114.48 U32.6 59.94,115.62 60.18,115.86 R429.2
SPI_MUX_OE_N: length 14.1
  TOP w0.114: v3(109.73,116.33) 108.71,116.33 108.39,116.64 U43.15
  S5 w0.102: v3(111,110.36) 110.82,110.54 110.82,114.45 109.73,115.54 v3(109.73,116.33)
  BOTTOM w0.114: v1(110.87,109.47) 110.87,110.24 v3(111,110.36) 111.25,110.62 Q16.D 113.28,111.63 R932.2
SPI_NIC1_NVM_CS: length 19.9
  TOP w0.114: v2(135.23,98.2) 135.25,98.17 R811.2 ; v2(146.81,102.31) 147.32,102.31 R816.1 U39.1
  S3 w0.102: v2(146.81,102.31) 146.53,102.59 140.16,102.59 138.33,100.76 138.33,99.97 136.55,98.2 v2(135.23,98.2)
  BOTTOM w0.114: v2(135.23,98.2) v1(135.23,99.69)
SPI_NIC1_NVM_CS_R_N: length 5.3
  TOP w0.114: U6.15 137.59,93.62 v2(135.74,95.48) 135.25,95.96 R811.1
  BOTTOM w0.114: v1(135.71,96.47) 135.74,96.44 v2(135.74,95.48)
SPI_NIC1_NVM_SCK: length 12.5
  TOP w0.114: R812.2 137.29,98.15 v2(137.41,98.27) ; v2(137.03,104.75) 136.62,104.75 R815.1 136.22,105.41 U39.6
  S8 w0.102: v2(137.03,104.75) 137.36,104.75 138.05,104.06 138.05,98.91 v2(137.41,98.27)
  BOTTOM w0.114: v1(136.14,104.56) 136.32,104.75 v2(137.03,104.75)
SPI_NIC1_NVM_SCK_R: length 4.9
  TOP w0.114: R812.1 137.29,95.86 v2(137.78,95.36) 138.59,94.55 U6.13
  BOTTOM w0.114: v2(137.78,95.36) 137.78,96.1 v1(137.57,96.32)
SPI_NIC1_NVM_SI: length 14.5
  TOP w0.114: v2(137.01,105.99) 136.7,106.3 R813.1 R1046.1 136.73,106.68 U39.5 ; R809.2 138.3,98.22 v2(138.28,98.25)
  S8 w0.102: v2(137.01,105.99) 137.01,105.42 138.28,104.15 v2(138.28,98.25)
  BOTTOM w0.114: v2(137.01,105.99) 137.57,105.99 v1(137.87,105.69)
SPI_NIC1_NVM_SI_R: length 4.7
  TOP w0.114: R809.1 138.3,95.78 139.06,95.02 v2(139.06,95) 139.09,94.97 U6.12
  BOTTOM w0.114: v2(139.06,95) 138.81,95 v1(138.23,94.41)
SPI_NIC1_NVM_SO: length 20.2
  TOP w0.114: R989.2 v2(136.27,98.65) ; v2(146.94,103.48) 147.6,104.14 R814.1 R1047.1 146.87,104.14 U39.2
  S3 w0.102: v2(146.94,103.48) 146.28,102.82 140.03,102.82 138.1,100.89 138.1,100.48 v2(136.27,98.65)
  BOTTOM w0.114: v1(136.58,97.69) 136.58,98.35 v2(136.27,98.65)
SPI_NIC1_NVM_SO_R: length 5.1
  TOP w0.114: U6.14 138.09,94.04 v2(136.89,95.24) 136.27,95.86 R989.1
  BOTTOM w0.114: v2(136.89,95.24) 136.82,95.24 v1(136.14,94.56)
SRDS_SIG_DET: length 125.2
  TOP w0.114: v2(149.99,85.72) 149.86,85.85 R972.1 ; v2(202.06,45.69) 202.08,45.72 202.18,45.72 202.35,45.88 202.35,46.7 202.03,47.02 202.03,47.67 U12.R14
  S8 w0.102: v2(143.89,61.72) 143.89,62.23 147.83,66.17 147.83,81.28 148.34,81.79 148.34,84.33 149.73,85.72 v2(149.99,85.72)
  BOTTOM w0.114: v2(143.89,61.72) 144.88,60.73 148.44,60.73 149.89,59.28 149.89,59.11 150.75,58.24 159.39,58.24 160.32,57.31 178.26,57.31 180.53,55.04 180.53,42.87 183.03,40.37 188.13,40.37 v1(188.85,39.65) 190.07,38.43 190.07,30.91 190.83,30.15 194.06,30.15 194.61,30.71 194.61,33.07 202.84,41.3 202.84,44.91 v2(202.06,45.69)
SRDS_SIG_DET_R: length 9.9
  TOP w0.114: U6.54 145.69,87.52 146.18,88.01 147.7,88.01 148.34,87.38 R972.2 148.95,87.48 v2(151,87.48) 151.46,87.48 R970.1 R920.1
  BOTTOM w0.114: v2(151,87.48) 150.04,87.48 v1(150.01,87.45)
SUSCLK_32K_CPLD: length 157.3
  TOP w0.114: v2(89.75,111.19) 89.92,111.02 90.19,111.02 R41.1 ; U12.H5 v3(192.09,55.61)
  S3 w0.102: v2(89.75,111.19) 89.23,111.71 89.23,115.49 91.17,117.42 93.1,117.42 94.7,115.82 98.18,115.82 98.61,116.26 101.07,116.26 101.93,115.39 102.51,115.39 108,109.91 112.99,109.91 113.92,108.98 113.92,108.01 115.83,106.1 120.66,106.1 122.75,108.18 131.89,108.18 132.98,109.27 147.93,109.27 149.45,107.75 150.68,107.75 154.08,104.34 169,104.34 173.1,100.24 173.1,91.08 177.32,86.86 177.32,83.6 183.62,77.29 184.86,77.29 192.71,69.44 192.71,64.9 193.29,64.32 193.29,63.08 193.47,62.9 193.47,61.31 193.52,61.26 193.52,56.5 193.01,55.99 192.47,55.99 v3(192.09,55.61)
  BOTTOM w0.114: v1(192.15,54.61) 192.15,55.55 v3(192.09,55.61)
SVID_ALERT: length 87.7
  TOP w0.114: R369.2 50.8,8.23 51.38,7.65 v2(51.59,7.65) 51.78,7.85 R370.2 ; R286.1 v2(98.8,40.77) ; R401.2 v2(71.65,2.97)
  S10 w0.102: v2(98.8,40.77) 98.34,40.31 98.34,39.81 98.48,39.67 98.48,38.88 97.79,38.19 97.79,37.14 98.4,36.53 98.4,31.8 99.06,31.14 99.06,25.4 95.25,21.59 95.25,14.07 92.1,10.92 88.74,10.92 81.53,3.71 75,3.71 74.98,3.73 74.24,3.73 74.22,3.71 72.39,3.71 v2(71.65,2.97)
  BOTTOM w0.114: R286.1 v2(98.8,40.77) ; v2(71.65,2.97) 70.78,3.84 v1(70.53,3.84) 69.71,3.02 65.07,3.02 64.85,3.23 64.47,3.23 64.05,2.81 59.7,2.81 59.07,2.17 57.84,2.17 57.3,2.71 57.3,3.41 55.91,4.8 55.91,7.03 54.8,8.13 52.06,8.13 v2(51.59,7.65)
SVID_ALERT_DDR_R: length 2.5
  TOP w0.114: U29.13 55.03,7.35 54.53,7.85 R370.1
SVID_ALERT_VCORE: length 4
  TOP w0.114: U28.13 74.41,5.84 v2(73.66,5.09) 72.59,4.01 R401.1
  BOTTOM w0.114: v2(73.66,5.09) v1(73.66,5.97)
SVID_CLK: length 117
  TOP w0.114: R399.1 v2(73.51,2.29) ; R374.1 50.9,7.29 v2(51.28,6.91) R376.2
  S10 w0.102: v2(102.23,41.48) 102.04,41.48 100.36,39.8 99.84,39.8 99.06,39.03 99.06,38.78 98.5,38.22 98.5,37.38 98.84,37.04 99.23,37.04 99.54,36.73 99.54,25 95.94,21.39 95.94,13.42 92.92,10.41 89.18,10.41 86.38,7.62 86.38,3.8 87.04,3.13 87.04,2.67 86.64,2.27 84.79,2.27 84.51,2.55 84.4,2.55 83.91,3.03 83.83,3.11 82.86,3.11 82.3,2.55 81.22,2.55 81.03,2.36 81.03,2.17 80.76,1.91 78.55,1.91 78.32,2.14 75.21,2.14 74.94,2.41 74.94,2.43 74.93,2.43 74.93,2.45 74.61,2.77 74.1,2.77 73.95,2.62 73.84,2.62 v2(73.51,2.29) 73.11,2.29 72.59,1.76 71.11,1.76 70.59,2.28 65,2.28 64.9,2.18 64.42,2.18 64.32,2.28 64.09,2.28 62.38,3.99 62.38,15.01 60.79,16.6 58.58,16.6 58.24,16.94 52.85,16.94 52.65,16.74 51.14,16.74 51.04,16.64 50.47,16.64 49.71,15.88 49.71,8.48 v2(51.28,6.91)
  BOTTOM w0.114: v2(51.28,6.91) 50.67,7.52 v1(50.67,7.62) ; R639.2 102.23,40.33 v2(102.23,41.48) R634.1
SVID_CLK_DDR_R: length 2.7
  TOP w0.114: R376.1 53.06,7.01 54.33,7.01 v2(54.43,7.11) 54.6,6.95 U29.14
SVID_CLK_VCORE: length 6
  TOP w0.114: U28.14 74.81,5.55 v2(74.38,5.12) 73.51,4.25 R399.2
  BOTTOM w0.114: v2(74.38,5.12) 74.38,4.91 73.83,4.36 72.19,4.36 v1(71.81,3.99)
SVID_DATA: length 92.8
  TOP w0.114: v2(74.35,2.18) 74.44,2.27 74.44,2.97 R400.2 ; v2(99.09,37.62) 98.8,37.91 R304.1 ; R385.2 v2(51.33,6.03) 51.01,6.35 R379.1
  S10 w0.102: v2(99.09,37.62) 99.19,37.52 99.43,37.52 100.03,36.93 100.03,24.8 96.67,21.44 96.67,13.48 92.59,9.39 88.92,9.39 87.03,7.5 87.03,3.83 87.53,3.33 87.53,2.47 86.84,1.79 84.58,1.79 84.48,1.79 84.2,2.07 84.19,2.07 83.63,2.63 83.06,2.63 82.5,2.07 82.04,2.07 81.62,1.65 81.19,1.65 80.96,1.42 78.35,1.42 78.12,1.65 74.72,1.65 74.35,2.03 v2(74.35,2.18)
  BOTTOM w0.114: v2(99.09,37.62) 98.8,37.91 R304.1 ; v2(51.33,6.03) 53.19,7.89 54.7,7.89 55.65,6.94 55.65,4.72 57.02,3.34 57.02,2.54 57.66,1.91 59.82,1.91 60.07,2.16 72.12,2.16 73.69,3.73 v1(74.28,3.73) 74.35,3.67 v2(74.35,2.18)
SVID_DATA_CORE: length 3.6
  TOP w0.114: U28.15 75.21,5.21 75.16,5.16 75.16,5.13 v2(75.15,5.12) 74.44,4.42 R400.1
  BOTTOM w0.114: v1(75.46,4.25) 75.15,4.56 v2(75.15,5.12)
SVID_DATA_DDR_R: length 2.7
  TOP w0.114: R385.1 53.2,6.03 53.57,6.4 54.76,6.4 54.91,6.55 U29.15
SW1_OE_N: length 4
  TOP w0.114: U7.15 204.33,98.31 v2(203.83,98.81)
  BOTTOM w0.114: R848.2 v1(204.86,99.48) 204.5,99.48 v2(203.83,98.81)
SW1_SYS_RESET_N: length 4
  TOP w0.114: R714.2 v2(184.66,7.49) 183.99,6.82 SW1.4 SW1.3
SW2_SYS_RESET_N: length 3.8
  TOP w0.114: SW2.3 SW2.4 188.34,6.56 v2(188.34,7.49) R389.2
SW_VDDQ_CH01: length 3.9
  TOP w0.249: QFN1.6 R335.1
  BOTTOM w0.381: C594.1 54.46,23.93 v2(55.8,25.27)
SYS_CPLD_INT_CPU: length 376.1
  TOP w0.114: v2(195.88,45.52) 195.88,45.76 196.59,46.47 U12.T9 ; R19.1 v2(76.53,114.35)
  S5 w0.102: v2(195.88,45.52) 195.88,45.06 196.15,44.79 196.15,39.68 188.12,31.65 187.82,31.65 181.62,25.45 180.53,25.45 180.26,25.18 180.26,24.85 178.28,22.86 178.28,15.87 176.72,14.31 173.48,14.31 169.51,10.35 161.89,10.35 157.73,6.19 140.63,6.19 140.26,5.82 140.26,3.48 140.64,3.1 145.24,3.1 145.82,3.68 145.82,4.98 146.23,5.38 v3(146.53,5.38)
  S8 w0.102: v3(146.53,5.38) 146.18,5.38 145.8,5 145.8,4.5 145.59,4.29 145.59,3.84 144.42,2.67 128.62,2.67 126.16,5.13 122.87,5.13 122.62,5.37 115.58,5.37 110.12,10.83 95.74,10.83 94.75,11.82 93.13,11.82 92.78,11.48 89.19,11.48 87.27,11.48 86.67,10.87 85.33,10.87 84.75,10.29 84.18,10.29 81.99,8.1 81.99,4.87 81.16,4.04 77.91,4.04 77.86,3.99 76.59,3.99 76.29,4.29 70.89,4.29 70.79,4.39 67.86,4.39 67.42,3.96 66.79,3.96 65.4,5.35 62.59,5.35 62.08,5.87 60.89,5.87 59.53,4.51 56.58,4.51 56.2,4.9 56.2,6 54.6,7.59 54.03,7.59 52.79,8.84 49.64,8.84 47.83,10.65 47.83,12.65 45.14,15.34 41.8,15.34 40.78,16.36 30.78,16.36 26.93,20.21 26.93,53.95 28.8,55.82 28.8,56.2 30.3,57.7 30.3,76.36 30.71,76.77 30.71,80.37 30.89,80.54 30.89,101.05 31.84,102.01 32.33,102.01 33.86,103.53 33.86,105.99 37.83,109.96 47.76,109.96 51.48,113.68 56.6,113.68 57.07,113.21 59.79,113.21 60.99,114.4 65.62,114.4 66.05,113.97 66.43,113.97 66.47,114 68.52,114 69.43,114.91 73.55,114.91 74.22,114.25 76.43,114.25 v2(76.53,114.35)
  BOTTOM w0.114: v1(75.79,116.03) 75.79,115.09 v2(76.53,114.35) ; v3(146.53,5.38) 146.18,5.38 145.8,5 145.8,4.48 145.61,4.3 145.61,3.78 145.1,3.27 CONN16.56
SYS_CPLD_INT_CPU_R: length 44.7
  TOP w0.114: v4(94.36,85.22) 94.33,85.22 U9.BB14 ; R19.2 79.58,114.35 v2(79.86,114.63) 79.86,114.91 80.07,115.12 80.07,115.51 78.74,116.84 R905.2
  S5 w0.102: v2(79.86,114.63) 80.26,114.63 82.07,112.83 83.69,112.83 84.73,111.79 84.73,107.12 85.52,106.33 85.52,104.95 86.62,103.85 86.62,100.22 91.85,95 91.85,92.31 94.49,89.67 94.49,89.66 94.55,89.6 94.55,89.23 95.43,88.35 95.43,87.89 95.21,87.66 95.21,87.35 95.55,87 95.55,85.85 94.92,85.22 v4(94.36,85.22)
  BOTTOM w0.114: v1(78.82,114.73) 79.76,114.73 v2(79.86,114.63)
SYS_PWRBTN_N: length 62.2
  TOP w0.114: v2(188.34,10.29) R389.1 C252.1 R390.2 ; U12.K14 v3(202.09,52.61)
  S8 w0.102: v3(202.09,52.61) 202.09,52.43 203.76,50.76 203.76,50.45 203.76,50.15 204.39,49.52 205,49.52 206.86,47.66 206.86,29.54 201.6,24.28 201.6,12.98 198.91,10.29 v2(188.34,10.29)
SYSLED: length 3.6
  TOP w0.114: Q5.D 165.35,83.18 164.59,82.42 v2(164.59,82.3) R164.1 R163.2
SYSLED_R: length 1.7
  TOP w0.114: LED11.C 165.98,79.87 v2(165.99,79.88) R163.1
TEST_NET1: length 13.7
  TOP w0.114: U12.A10 197.36,62.34 197.36,66.47 195.94,67.89 195.94,70.33 v3(195.47,70.8) TP60.1
  BOTTOM w0.114: v1(193.52,71.32) 194.94,71.32 v3(195.47,70.8)
TEST_NET2: length 11.8
  TOP w0.114: U12.A9 196.95,62.47 196.95,66.51 195.48,67.98 v3(195.48,69.34) 195.48,69.6 194.84,70.23 TP61.1
  BOTTOM w0.114: v3(195.48,69.34) 195.22,69.6 v1(193.75,69.6)
TEST_NOA_COMP: length 21.1
  TOP w0.114: R260.2 v2(105.46,46.89) ; U9.AA66 103.75,62.3 v4(104.03,62.58)
  S10 w0.102: v2(105.46,46.89) 105.94,47.37 105.94,52.81 105.11,53.64 104.57,53.64 103.68,54.53 103.68,57.15 104.19,57.66 104.19,58.6 104.01,58.78 103.84,58.78 103.66,58.95 103.66,59.69 104.06,60.1 104.06,60.2 104.55,60.68 104.55,62.67 104.41,62.81 104.27,62.81 v4(104.03,62.58)
  BOTTOM w0.114: v2(105.46,46.89) 105.54,46.81 v1(105.54,45.95)
TEST_RCIN_N: length 55
  TOP w0.114: v4(95.16,79.58) 95.15,79.58 94.75,79.98 U9.BA27 ; R14.1 v2(71.86,114.46)
  S3 w0.102: v4(95.16,79.58) 95.71,79.58 96.37,80.24 96.37,86.31 95.76,86.92 95.41,86.92 95.16,87.17 95.16,88.93 95.33,89.1 95.33,90.37 93.4,92.3 93.4,94.13 90.78,96.75 89.13,96.75 86.17,99.72 83.5,99.72 81.29,101.92 81.29,106.13 81.08,106.35 81.08,107.92 79.43,109.58 78.98,109.58 76.61,111.94 76.23,111.94 75.77,112.39 75.77,113.44 75.21,114 74.63,114 73.96,114.66 72.06,114.66 v2(71.86,114.46)
  BOTTOM w0.114: v2(71.86,114.46) 70.92,115.39 v1(70.76,115.39)
TGND_VDDQ_CH01: length 2.5
  BOTTOM w0.114: v3(57.11,20.59) 57.58,21.07 TP33.1 v1(58.8,21.72)
TP_ADR_COMPLETE: length 5.8
  TOP w0.114: v4(102.08,62.6) 101.77,62.3 U9.AF66
  BOTTOM w0.114: v1(105.92,62.41) 105.28,63.04 102.51,63.04 v4(102.08,62.6) 101.38,62.6 TP31.1
TP_BDX_CPU_RESET_N: length 5
  TOP w0.114: U9.BU7 v4(87.7,88.63)
  BOTTOM w0.114: v4(87.7,88.63) 87.3,89.03 86.46,89.03 85.83,89.66 R517.2 84.5,90.34 v1(84.45,90.39)
TP_BDX_GP50: length 9.3
  TOP w0.114: v4(87.2,82.62) 86.92,82.9 U9.BV20
  BOTTOM w0.114: v1(79.78,81.5) 79.78,82.21 TP24.1 80.59,83.03 86.79,83.03 v4(87.2,82.62)
TP_DDR_VREFDQ_0: length 10.4
  TOP w0.114: U9.CV51 77.11,68.73 76.69,68.73 v3(76.45,68.49)
  BOTTOM w0.114: v3(76.45,68.49) 76.02,68.93 71.15,68.93 70.74,68.52 70.74,68.2 70.96,67.98 72.02,67.98 72.26,67.74 C431.1 73.23,67.54 v1(73.28,67.59)
TP_DDR_VREFDQ_1: length 7.1
  TOP w0.114: v4(77.37,68.44) 77.54,68.44 77.93,68.83 78.44,68.83 U9.CT51
  BOTTOM w0.114: v4(77.37,68.44) 77.37,68.81 v1(76.83,69.34) 76.51,69.67 72.71,69.67 C454.1
TP_GPIO54: length 8.9
  TOP w0.114: v4(86.7,83.45) 86.39,83.76 U9.BW18
  BOTTOM w0.114: v4(86.7,83.45) 86.25,83.9 80.37,83.9 TP23.1 79.72,84.54 v1(79.72,85.41)
TP_HDA_SYNC: length 1.4
  TOP w0.114: U9.AN7 98.1,88.39 v4(98.08,88.37)
  BOTTOM w0.114: v4(98.08,88.37) 98.38,88.67 TP20.1
TP_KR_EPHY_DFTDIG_1: length 9.4
  TOP w0.114: U9.F69 110.28,60.58 v4(109.98,60.88)
  BOTTOM w0.114: TP32.1 113.68,58.81 v1(113.68,61.66) 112.99,62.36 111.02,62.36 110.15,61.49 110.15,61.05 v4(109.98,60.88)
TP_LDRQ0_N: length 2.2
  TOP w0.114: v4(99.55,89.2) 99.83,89.49 U9.AK4
  BOTTOM w0.114: TP18.1 99.31,89.44 v4(99.55,89.2)
TP_PE_HSCLK_DN: length 4.7
  TOP w0.114: U9.C49 112.75,69.93 113.17,70.34 R196.2
TP_PE_HSCLK_DP: length 3.5
  TOP w0.114: R199.2 116.18,69.93 U9.A49
TP_PMTEST_RST: length 5.6
  TOP w0.114: v4(94.14,88.37) 93.96,88.54 93.52,88.54 U9.BD7
  BOTTOM w0.114: v4(94.14,88.37) 93.4,89.11 93.4,90.41 TP16.1 93.51,92.38 v1(93.55,92.41)
TP_SATA_PLLOBS0: length 6.8
  TOP w0.114: v4(93.37,78.03) 93.37,77.72 93.04,77.39 92.71,77.39 92.21,76.89 U9.BF33
  BOTTOM w0.114: TP26.1 92.99,75.54 92.2,76.33 92.2,76.73 91.74,77.19 91.74,77.77 91.95,77.98 92.28,77.98 92.41,77.85 92.81,77.85 92.99,78.03 v4(93.37,78.03)
TP_SATA_PLLOBS1: length 1.4
  TOP w0.114: v4(92.65,78.32) 92.65,78.31 U9.BE32
  BOTTOM w0.114: TP25.1 93.2,78.87 v4(92.65,78.32)
TP_SLP_A_N: length 5
  TOP w0.114: v4(92.8,89.35) 93.27,89.35 93.71,88.91 U9.BB7
  BOTTOM w0.114: v4(92.8,89.35) 92.33,89.82 TP14.1 92.33,92.41 v1(92.18,92.57)
TP_SLP_SUS_N: length 3.5
  TOP w0.108: v4(94.93,89.43) 95.13,89.23 U9.AY7
  BOTTOM w0.114: v1(94.82,92.19) 94.82,90.69 TP15.1 94.71,89.65 v4(94.93,89.43)
TP_TEST_PE_AMONI: length 5.3
  TOP w0.114: U9.N43 107.51,73.03 v4(107.21,73.33)
  BOTTOM w0.114: v4(107.21,73.33) 107.9,73.33 109.6,75.03 110.64,75.03 TP29.1
TP_TEST_PE_AMONV: length 5.1
  TOP w0.114: v4(107.37,70) 107.51,70.15 U9.N47
  BOTTOM w0.114: v4(107.37,70) 108.74,70 109.64,70.91 v1(109.98,70.91) TP30.1
TP_TEST_PE_DFX_DN: length 2.4
  TOP w0.114: U9.R39 106.75,74.52 106.35,74.12 105.56,74.12 v4(105.54,74.09)
  BOTTOM w0.114: TP27.1 105.54,74.74 v4(105.54,74.09)
TP_TEST_PE_DFX_DP: length 6.7
  TOP w0.114: U9.N39 107.72,74.32 v4(108.01,74.03)
  BOTTOM w0.114: v1(113.16,74.96) 112.12,74.96 TP28.1 111.32,75.54 109.65,75.54 108.14,74.03 v4(108.01,74.03)
TP_USB2_PLLMON_DN: length 1.5
  TOP w0.114: v4(102.06,88.37) 102.37,88.05 U9.AD9
  BOTTOM w0.114: v4(102.06,88.37) 102.49,88.8 TP17.1
TP_USB2_PLLMON_DP: length 0.6
  TOP w0.114: U9.AC11 102.87,87.19 v4(102.57,87.5)
TP_VCCRTCEXT: length 16.6
  TOP w0.254: U9.AW16 v4(95.94,84.41)
  BOTTOM w0.114: C366.2 87.71,75.13 87.71,75.87 87.31,76.26 87.31,76.78 87.78,77.25 87.78,77.75 88.27,78.23 88.27,78.59 88.77,79.1 88.77,79.53 89.23,79.98 89.23,80.29 89.71,80.77 89.71,81.18 90.22,81.69 90.22,82.02 90.65,82.45 90.65,82.75 90.93,83.03 92.32,83.03 93.08,82.28 93.4,82.28 93.85,82.73 93.85,82.84 94.19,83.18 94.61,83.18 95.84,84.41 v4(95.94,84.41)
TP_VCCSST: length 13.3
  TOP w0.254: v4(95.95,82.77) 95.95,82.79 U9.AW19
  BOTTOM w0.114: C368.2 89.64,75 89.64,75.94 89.18,76.4 89.18,76.73 89.74,77.29 89.74,77.75 90.17,78.18 90.17,78.51 90.63,78.97 90.63,79.35 91.14,79.86 91.14,80.24 91.36,80.47 93.42,80.47 93.65,80.7 93.65,81.13 94.12,81.6 94.99,81.6 95,81.59 95.32,81.59 95.56,81.83 95.56,82.15 95.95,82.54 v4(95.95,82.77)
TP_VCCSUS_1P05: length 16.4
  TOP w0.254: U9.AU16 96.75,84.39 v4(96.76,84.39)
  BOTTOM w0.114: v4(96.76,84.39) 96.36,84 96.14,84 96.12,83.98 95.79,83.98 95.55,83.74 95.55,82.63 95.29,82.37 94.19,82.37 93.71,81.9 93.06,81.9 92.83,82.13 92.51,82.13 92.28,81.9 92.28,81.58 91.98,81.29 91.01,81.29 90.78,81.06 90.78,80.77 90.2,80.19 90.2,79.96 89.71,79.48 89.71,79.02 89.2,78.51 89.2,78.16 88.7,77.65 88.7,77.32 88.24,76.86 88.24,76.4 88.72,75.92 88.72,75.03 C367.2
TP_VCCUSB3SUS: length 2.2
  TOP w0.305: U9.AP28 98.12,79.02 98.12,78.66 97.95,78.49 U9.AP30
  TOP w0.33: U9.AP30 v4(98.35,77.99)
  BOTTOM w0.114: v4(98.35,77.99) 98.35,77.44 C337.2
TPM_DET_N: length 277.3
  TOP w0.114: U12.F10 v3(198.09,57.61)
  S3 w0.102: v2(16.13,62.87) 16.65,62.34 16.65,55.97 20.17,52.45 24.41,52.45 26.34,50.52 26.34,32.79 31.96,27.17 34.97,27.17 35.6,26.54 42.19,26.54 43.81,24.92 43.81,22.92 50.8,15.93 56.55,15.93 57.9,17.27 71.68,17.27 72.47,18.06 86.64,18.06 88.39,19.81 89.03,19.81 90.47,21.26 94.43,21.26 98.18,25 122.87,25 123.62,25.75 123.62,26.87 v2(122.81,27.69)
  S5 w0.102: v3(198.09,57.61) 197.71,57.23 197.71,55.69 196.63,54.61 187.86,54.61 184.84,51.59 184.84,41.08 185.22,40.7 185.22,38.71 v2(186.72,37.21)
  BOTTOM w0.114: R948.2 27.94,73.42 28.08,73.28 28.08,71.25 27.35,70.53 25.2,70.53 25.16,70.48 23.22,70.48 22.98,70.25 22.98,69.21 22.85,69.08 CONN14.33 20.57,69.08 16.43,64.94 16.43,63.16 v2(16.13,62.87) ; v2(186.72,37.21) 186.33,37.21 v1(185.34,36.22) 184.53,35.41 184.53,32.1 180.89,28.45 176.06,28.45 173.65,26.04 170.01,26.04 169,27.06 136.57,27.06 134.66,25.15 130.07,25.15 127.79,27.44 123.06,27.44 v2(122.81,27.69)
TPM_RESET_N: length 45.2
  TOP w0.114: R1055.2 175.46,15.31 176.13,15.98 U17.16 ; R229.2 v2(200.66,41.78)
  TOP w0.127: U17.16 v2(179.18,15.98)
  S8 w0.102: v2(200.66,41.78) 200.66,40.39 199.44,39.17 199.44,37.82 197.23,35.61 195.88,35.61 193.52,33.25 193.52,28.24 187.15,21.87 185.81,21.87 185.11,21.16 181.37,21.16 180.24,20.03 180.24,17.04 v2(179.18,15.98)
TPM_RESET_R_N: length 4.9
  TOP w0.114: R229.1 200.66,44.32 200.08,44.91 v2(200.08,46.1) 200.08,47.62 U12.R12
U10_DIR: length 2.3
  TOP w0.114: U10.2 v2(172.65,68.35)
  BOTTOM w0.114: v2(172.65,68.35) 173,68.7 R563.1
U10_OE_N: length 2.4
  TOP w0.114: U10.22 173.15,73.97 v2(172.9,74.22)
  BOTTOM w0.114: R556.2 173.13,73.99 v2(172.9,74.22)
U13_DIR: length 2
  TOP w0.114: v2(172.69,61.11) 172.69,61.31 172.7,61.32 U13.2
  BOTTOM w0.114: v2(172.69,61.11) R577.1
U13_OE_N: length 2.2
  TOP w0.114: U13.22 v2(173.2,66.93)
  BOTTOM w0.114: v2(173.2,66.93) 173.13,66.85 R573.2
U14_DIR: length 2.6
  TOP w0.114: R203.1 171.91,49.02 171.91,50.45 v2(172.11,50.65) U14.2
U14_OE_N: length 3.2
  TOP w0.114: U14.22 173.2,54.94 v2(172.87,55.27)
  BOTTOM w0.114: v1(172.75,56.26) 172.75,55.4 v2(172.87,55.27) 173.18,54.96 R575.2
UART_BDX_RX0: length 117.7
  TOP w0.114: U9.AG77 100.55,56.56 100.03,56.03 100.03,55.41 v3(100.2,55.23) ; v2(175.67,67.25) 175.7,67.22 U13.17
  S3 w0.102: v3(100.2,55.23) 99.86,54.89 99.85,54.89 99.75,54.79 99.75,54.32 99.36,53.94 99.36,51.72 98.02,50.38 98.02,48.84 97.43,48.26 97.16,48.26 94.69,45.8 94.69,43.26 95.86,42.09 103.91,42.09 104.55,41.45 114.5,41.45 116.56,43.51 116.56,44.05 118.12,45.61 v2(120.85,45.61)
  S8 w0.102: v2(120.85,45.61) 120.85,46.76 123.07,48.98 123.07,49.59 122.83,49.83 122.83,50.45 123.87,51.49 124.9,51.49 129.72,56.31 155.24,56.31 155.72,55.83 165.3,55.83 169.85,60.38 169.85,66.07 171.6,67.82 175.1,67.82 v2(175.67,67.25)
  BOTTOM w0.114: v1(174.83,67.67) 175.25,67.67 v2(175.67,67.25)
UART_BDX_RX1: length 115.5
  TOP w0.114: v2(100.3,54.56) 100.63,54.89 100.63,55.52 U9.AH78 ; U13.16 176.2,66.65 v2(176.33,66.78)
  S3 w0.102: v2(100.3,54.56) 100.3,53.24 99.75,52.68 99.75,51.77 98.25,50.27 98.25,48.43 97.85,48.03 97.25,48.03 94.92,45.7 94.92,43.35 95.85,42.42 114,42.42 115.9,44.32 116.51,44.32 118.02,45.83 119.67,45.83 120.04,46.2 v2(121.46,46.2)
  S8 w0.102: v2(176.33,66.78) 176.23,66.67 175.06,66.67 174.14,67.59 171.69,67.59 170.08,65.98 170.08,60.28 165.4,55.6 155.63,55.6 155.15,56.08 129.82,56.08 125,51.26 123.97,51.26 123.06,50.35 123.06,49.92 123.3,49.69 123.3,48.89 121.46,47.05 v2(121.46,46.2)
  BOTTOM w0.114: v2(176.33,66.78) v1(175.62,66.07)
UART_BDX_TX0: length 125
  TOP w0.114: R797.1 R796.2 102.09,38.55 102.09,39.71 101.26,40.54 100.13,40.54 v2(99.98,40.39) R288.1 ; v2(180.82,67.67) 177.51,67.67 177.39,67.54 176.43,67.54 175.94,68.03 175.58,68.03 174.65,68.96 U10.6
  S8 w0.102: v2(99.98,40.39) 100.13,40.39 100.66,39.86 100.66,37.39 103.12,34.92 123.51,34.92 124.02,35.43 131.95,35.43 138.65,42.14 155.73,42.14 159.44,45.85 178.89,45.85 180.67,47.62 180.67,63.2 179.96,63.91 179.96,65.99 180.7,66.73 180.7,66.91 181.1,67.31 181.1,67.42 180.86,67.67 v2(180.82,67.67)
  BOTTOM w0.114: v2(99.98,40.39) 99.98,41.14 100,41.16 v1(100,41.17)
UART_BDX_TX1: length 140.2
  TOP w0.114: R257.1 v2(99.98,46.76) 99.98,46.73 100.44,46.27 100.44,44.11 100.37,44.03 100.37,43.37 100.44,43.3 100.44,41.14 100.71,40.87 101.47,40.87 101.97,40.37 101.98,40.37 102.21,40.13 R799.1 R798.2 ; U10.7 175.15,68.99 175.87,68.28 176.04,68.28 176.53,67.79 177.29,67.79 177.48,67.97 179.63,67.97 v2(179.88,68.22)
  S3 w0.102: v2(115.9,36.73) 114.59,36.73 112.36,38.95 102.35,38.95 100.46,37.06 97.74,37.06 v2(96.01,35.33)
  S5 w0.102: v2(96.01,35.33) 96.01,39.47 96.11,39.57 96.11,40.59 95.83,40.87 95.83,43.41 96.6,44.17 97.94,44.17 99.21,45.44 99.21,46 v2(99.98,46.76)
  S8 w0.102: v2(115.9,36.73) 116.54,36.73 117.08,36.2 117.2,36.07 123.69,36.07 123.74,36.12 131.01,36.12 138.68,43.79 156.38,43.79 160.22,47.62 176.24,47.62 179.37,50.76 179.37,68 179.65,68.28 179.83,68.28 v2(179.88,68.22)
UART_CPLD_B2B_RX0: length 24.4
  TOP w0.114: v3(202.09,56.61) U12.G15 203.09,56.61 203.88,56.61 203.96,56.7 204.97,56.7 205.59,57.32 205.59,62.22 204.26,63.55 204.26,67.56 202.72,69.1 202.72,72.75 203.58,73.61 R871.2
  BOTTOM w0.114: v1(203.15,56.64) 202.61,56.64 202.58,56.61 v3(202.09,56.61)
UART_CPLD_B2B_TX0: length 24.9
  TOP w0.114: U12.G14 v3(202.09,55.61) 203.84,55.61 204.1,55.87 204.1,56.18 204.37,56.46 205.52,56.46 205.83,56.77 205.83,62.32 204.5,63.65 204.5,67.66 202.98,69.18 202.98,72.02 203.55,72.59 R872.2
  BOTTOM w0.114: v1(203.12,55.11) 202.59,55.11 v3(202.09,55.61)
UART_CPLD_BMC_RX0: length 236.3
  TOP w0.114: U12.R1 186.76,46.28 186.13,46.28 v2(183.58,43.73) ; R321.1 v2(8.28,29.66)
  S5 w0.102: v2(8.28,29.66) 8.86,29.08 12.89,29.08 14.01,27.96 14.01,14.81 21.38,7.44 21.38,3.48 23.69,1.17 60.11,1.17 61.85,2.91 62.27,2.91 62.66,3.3 65.14,3.3 65.15,3.29 65.53,3.29 65.53,3.3 65.84,3.3 66.23,2.91 69.01,2.91 69.75,3.65 71.94,3.65 72.21,3.38 75.08,3.38 75.13,3.43 77.37,3.43 77.42,3.38 82.69,3.38 83.02,3.05 83.47,3.05 89.06,8.65 94.39,8.65 95.32,9.57 95.32,11.75 96.41,12.84 96.41,20.58 97.06,21.23 v2(98.77,21.23)
  S8 w0.102: v2(183.58,43.73) 183.19,43.34 178.02,43.34 176.3,41.62 176.3,37.44 176.17,37.31 175.74,36.88 173.92,35.06 172.04,35.06 171.53,34.55 171.53,31.97 170.52,30.96 166.84,30.96 166.27,31.52 165.12,31.52 164.53,30.93 161.36,30.93 157.89,27.46 149.23,27.46 146.82,25.04 99.98,25.04 99.24,24.3 99.24,21.69 v2(98.77,21.23)
  BOTTOM w0.114: v1(182.46,43.86) 183.45,43.86 v2(183.58,43.73)
UART_CPLD_BMC_TX0: length 245.6
  TOP w0.114: U12.M1 187.35,51.11 186.58,51.88 182.17,51.88 181.46,51.17 181.46,46.23 181.86,45.82 v2(183.59,45.82) ; R315.1 v2(8.28,30.93)
  S5 w0.102: v2(97.8,21.7) 97.21,21.7 96.18,20.67 96.18,12.93 95.09,11.85 95.09,9.67 94.3,8.87 88.97,8.87 83.37,3.28 83.12,3.28 82.79,3.61 77.52,3.61 77.47,3.66 72.6,3.66 72.29,3.96 67.82,3.96 67.36,3.51 66.26,3.51 65.47,4.29 63.33,4.29 62.17,3.14 61.75,3.14 60.01,1.39 23.79,1.39 21.61,3.57 21.61,7.53 14.23,14.91 14.23,28.05 12,30.29 8.92,30.29 v2(8.28,30.93)
  S8 w0.102: v2(97.8,21.7) 97.98,21.89 97.98,23.69 99.53,25.23 99.79,25.5 146.63,25.5 149.04,27.91 157.7,27.91 161.17,31.39 164.34,31.39 164.93,31.98 166.46,31.98 167.03,31.42 170.33,31.42 171.07,32.16 171.07,34.9 171.68,35.51 173.73,35.51 175.29,37.07 175.84,37.63 175.84,41.81 177.83,43.8 181.56,43.8 v2(183.59,45.82)
  BOTTOM w0.114: v2(183.59,45.82) 183.45,45.96 v1(182.59,45.96)
UART_TXD_R_0: length 18.8
  TOP w0.108: v4(100.91,58.41) 100.82,58.32 U9.AG75
  TOP w0.114: R288.2 v2(99.98,43)
  S10 w0.102: v4(100.91,58.41) 100.76,58.26 100.76,53.42 100.51,53.16 100.51,45.8 99.98,45.27 v2(99.98,43)
  BOTTOM w0.114: v1(101.24,57.23) 100.91,57.56 v4(100.91,58.41)
UART_TXD_R_1: length 11.9
  TOP w0.114: U9.AH76 100.82,57.06 101.17,56.71 101.17,56.39 100.94,56.16 100.94,54.23 100.48,53.77 100.48,49.73 v2(99.98,49.22) R257.2
  BOTTOM w0.114: v1(98.83,50.9) 99.36,50.37 99.36,49.83 v2(99.98,49.22)
UCD9090_ALERT_L: length 123.2
  TOP w0.114: v3(139.67,4.47) 140.08,4.06 140.08,3.86 142.53,1.41 158.37,1.41 159.39,2.43 161.26,2.43 161.78,1.91 165.18,1.91 166.09,2.82 v2(166.47,2.82) ; v2(205.74,42.29) 205.1,42.93 205.1,48.59 U12.N16
  S5 w0.102: v2(166.47,2.82) 170.13,2.82 171.73,1.22 179.54,1.22 179.57,1.19 181.44,1.19 182.28,2.03 205.87,2.03 207.92,4.09 207.92,40.11 v2(205.74,42.29)
  BOTTOM w0.127: CONN16.78 139.6,3.15 140.08,3.63 140.08,4.06 v3(139.67,4.47)
UIM_PWR: length 2.4
  BOTTOM w0.305: v1(198.55,105.13) CONN13.36
USB1_PWRFAULT: length 413.3
  TOP w0.114: U12.D14 v3(202.09,59.61)
  S5 w0.102: v2(30.43,80.9) 29.41,79.88 v2(25.63,79.88)
  S8 w0.102: v3(202.09,59.61) 202.47,59.99 202.47,63.09 202,63.56 194.12,63.56 193.3,62.74 191.41,62.74 189.04,65.11 182.57,65.11 181.82,65.86 v2(180.8,65.86) ; v3(146.25,4.8) 146.28,4.78 146.28,4.62 145.82,4.17 145.82,3.71 144.55,2.44 128.22,2.44 125.76,4.9 122.78,4.9 122.53,5.15 115.49,5.15 110.03,10.6 95.65,10.6 94.66,11.6 93.22,11.6 92.88,11.25 89.1,11.25 87.37,11.25 86.76,10.64 85.42,10.64 84.56,9.78 84.45,9.78 84.05,9.38 84.05,6.61 81.25,3.81 78.01,3.81 77.96,3.76 76.5,3.76 76.19,4.06 70.8,4.06 70.7,4.17 67.95,4.17 67.52,3.73 66.7,3.73 65.88,4.55 59.89,4.55 59.63,4.28 56.49,4.28 55.99,4.78 53.4,4.78 52.27,5.91 52.27,7.94 51.6,8.61 49.54,8.61 47.6,10.55 47.6,12.56 45.05,15.11 41.7,15.11 40.69,16.13 30.69,16.13 26.7,20.11 26.7,55.01 27.93,56.24 28.33,56.24 30.07,57.98 30.07,76.46 30.48,76.86 30.48,79.72 30.43,79.77 v2(30.43,80.9) 30.43,100.91 31.75,102.23 32.16,102.23 32.87,102.95 32.87,105.32 37.73,110.19 47.66,110.19 51.68,114.2 60.46,114.2 61.2,114.94 62.07,114.94 62.29,114.71 63.89,114.71 64.12,114.94 68.58,114.94 69.5,115.85 72.38,115.85 72.84,115.39 73.41,115.39 74.05,116.03 76.68,116.03 77.33,115.38 78.31,115.38 81.13,112.56 81.13,111.91 81.92,111.12 81.92,108.36 81.61,108.05 81.61,107.29 v2(82.07,106.83)
  S10 w0.102: v2(180.8,65.86) 180.37,65.43 180.37,56.2 181,55.57 181,43.75 176.07,38.82 176.07,35.1 175.06,34.09 175.06,31.5 167.51,23.95 167.51,16.57 166.5,15.56 166.5,11.31 164.21,9.02 159.73,9.02 157.96,7.24 149.1,7.24 146.66,4.8 v3(146.25,4.8)
  BOTTOM w0.114: v3(146.25,4.8) 146.25,4.6 145.85,4.2 145.85,3.64 145.6,3.39 CONN16.54 ; R939.2 26.08,79.43 v2(25.63,79.88) ; v1(81.13,105.03) 81.13,105.89 v2(82.07,106.83) 82.07,106.71 82.83,105.94 R471.1
USB1_VBUS: length 509.5
  TOP w0.114: v3(148.84,3.66) 149.53,2.97 157.58,2.97 158.6,3.99 160.24,3.99 161.8,5.55 166.59,5.55 169.31,8.27 169.31,20.43 v2(168.4,21.34) ; U12.P9 v3(197.09,48.61) ; R29.2 v2(68.35,112.6)
  S3 w0.102: v2(100.5,15.18) 100.5,14.72 97.49,11.71 88.38,11.71 86.76,10.08 85.76,10.08 85.42,9.74 85.42,8.81 83.65,7.04 77.44,7.04 76.91,6.5 70.65,6.5 69.48,5.33 67.05,5.33 66.46,4.74 56.68,4.74 55.7,5.71 55.7,6.49 54.6,7.59 54.03,7.59 52.99,8.64 43.1,8.64 43,8.53 41.69,8.53 40.26,9.96 31.46,9.96 30.35,11.07 30.35,11.19 29.27,12.27 26.24,12.27 25.73,11.76 11.64,11.76 10.77,11.76 4.17,18.36 4.17,22.52 2.64,24.05 2.64,102.28 3.2,102.83 8.06,107.7 30.5,107.7 33.32,110.52 33.32,115.57 33.48,115.72 33.48,115.73 33.74,116 33.76,116 37.14,119.38 38.73,119.38 40.82,121.46 61.86,121.46 65.15,118.17 65.15,115.82 66.09,114.88 66.43,114.88 67.27,114.05 67.27,113.72 68.35,112.64 v2(68.35,112.6)
  S5 w0.102: v2(27.08,80.98) 26.06,81.99 26.06,83.17 26.21,83.32 26.21,86.92 29.34,90.04 29.34,100.08 30.99,101.73 51.94,101.73 54.61,104.39 60.33,104.39 62.36,106.43 71.38,106.43 71.81,106.86 71.81,109.42 71.27,109.96 71.27,109.97 71,110.24 70.99,110.24 68.63,112.6 v2(68.35,112.6)
  S8 w0.102: v2(100.5,15.18) 100.5,15.51 101.12,16.13 105.29,16.13 105.59,16.43 112.07,16.43 114.28,18.64 123.6,18.64 126.11,16.13 142.07,16.13 143.8,14.4 147.29,14.4 153.01,20.12 162.55,20.12 164,21.56 168.17,21.56 v2(168.4,21.34) 168.55,21.49 172.34,21.49 172.77,21.06 174.06,21.06 178.83,25.83 178.83,25.83 178.99,25.98 183,25.98 187.65,30.63 188.42,31.4 188.42,38.02 192.84,42.44 193.95,42.44 194.49,42.98 194.49,45.03 194.97,45.52 195.17,45.52 196.2,46.54 196.2,47.05 197.09,47.94 v3(197.09,48.61)
  BOTTOM w0.114: R938.2 v2(27.08,80.98)
  BOTTOM w0.127: CONN16.42 148.6,3.42 v3(148.84,3.66)
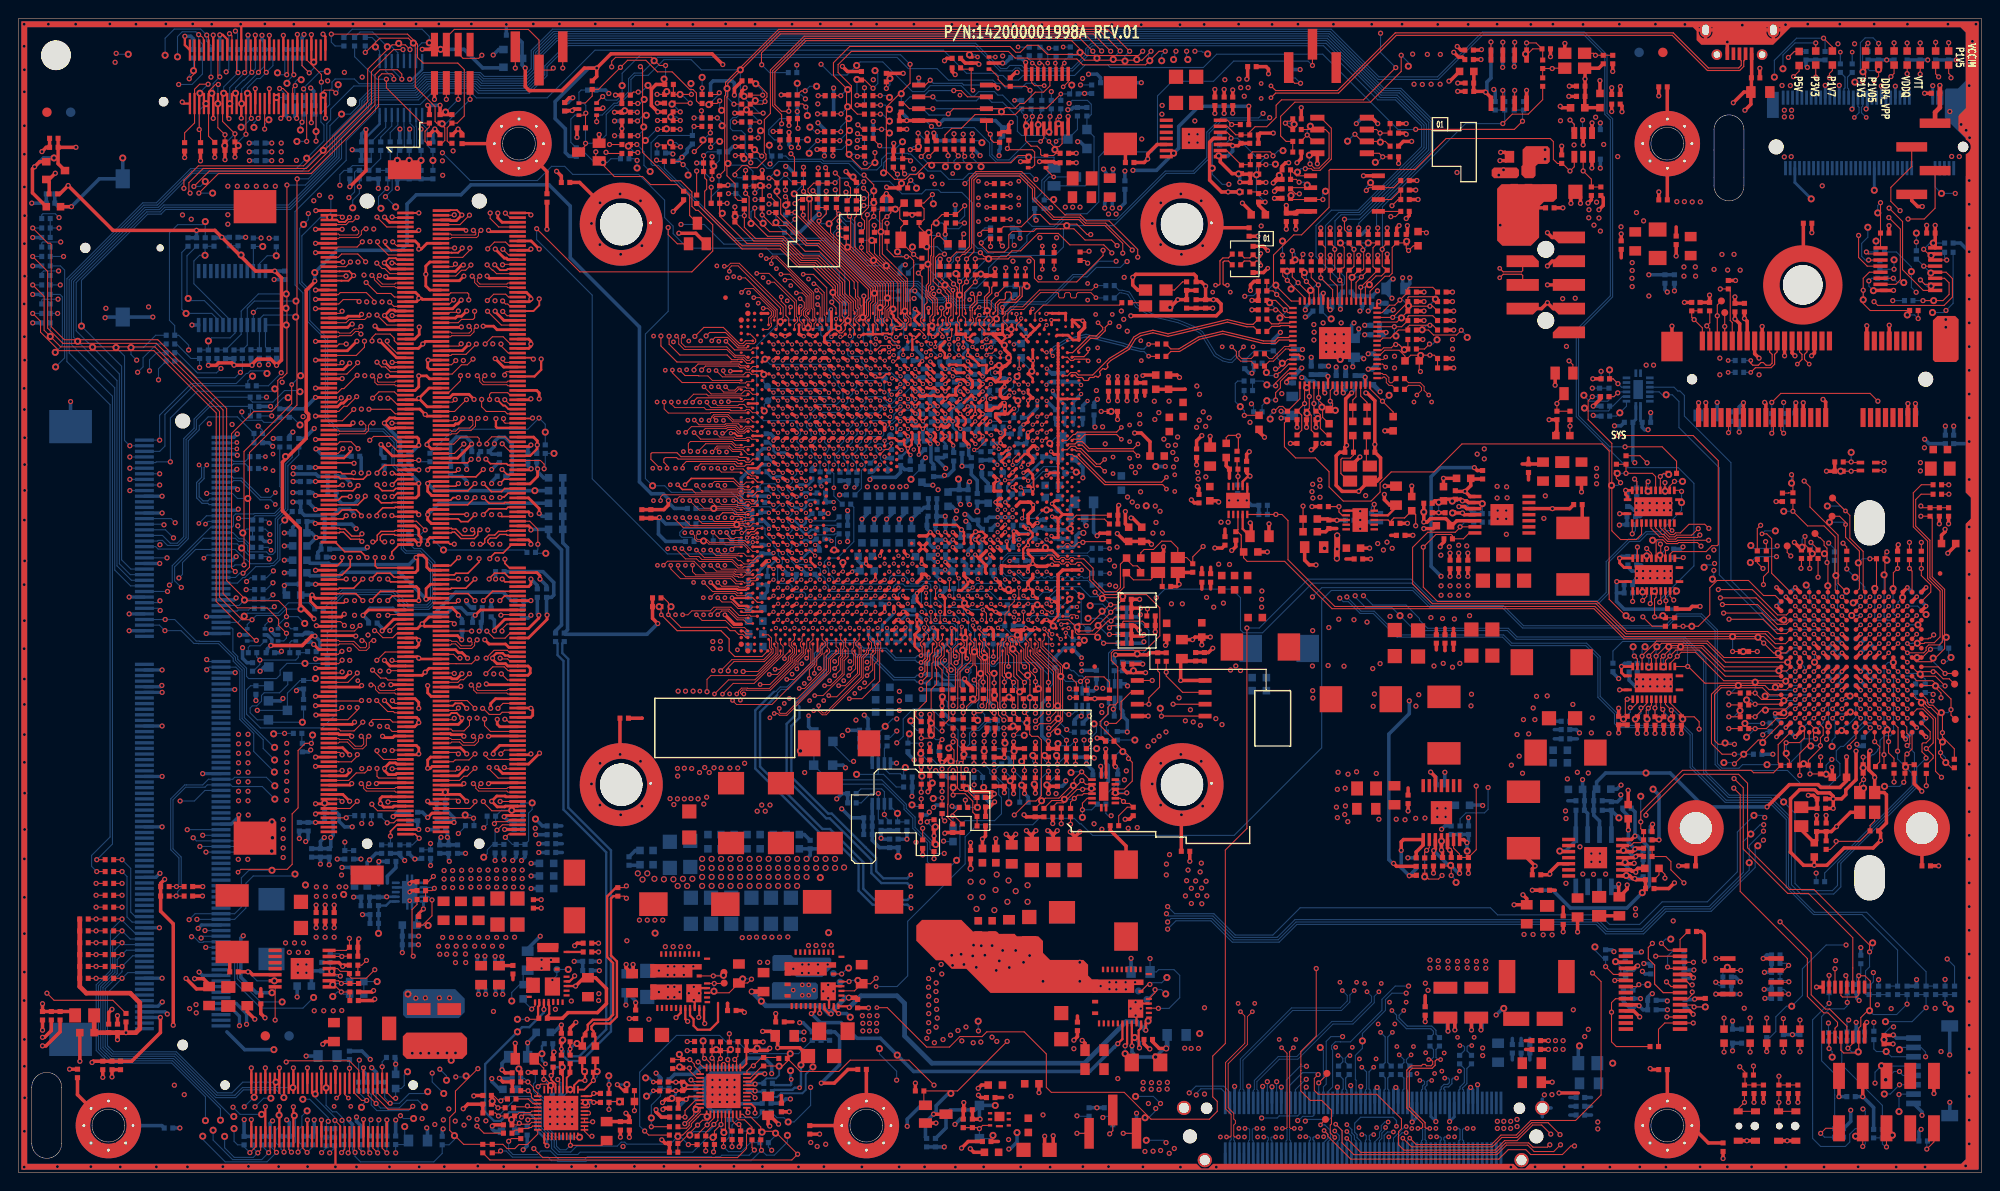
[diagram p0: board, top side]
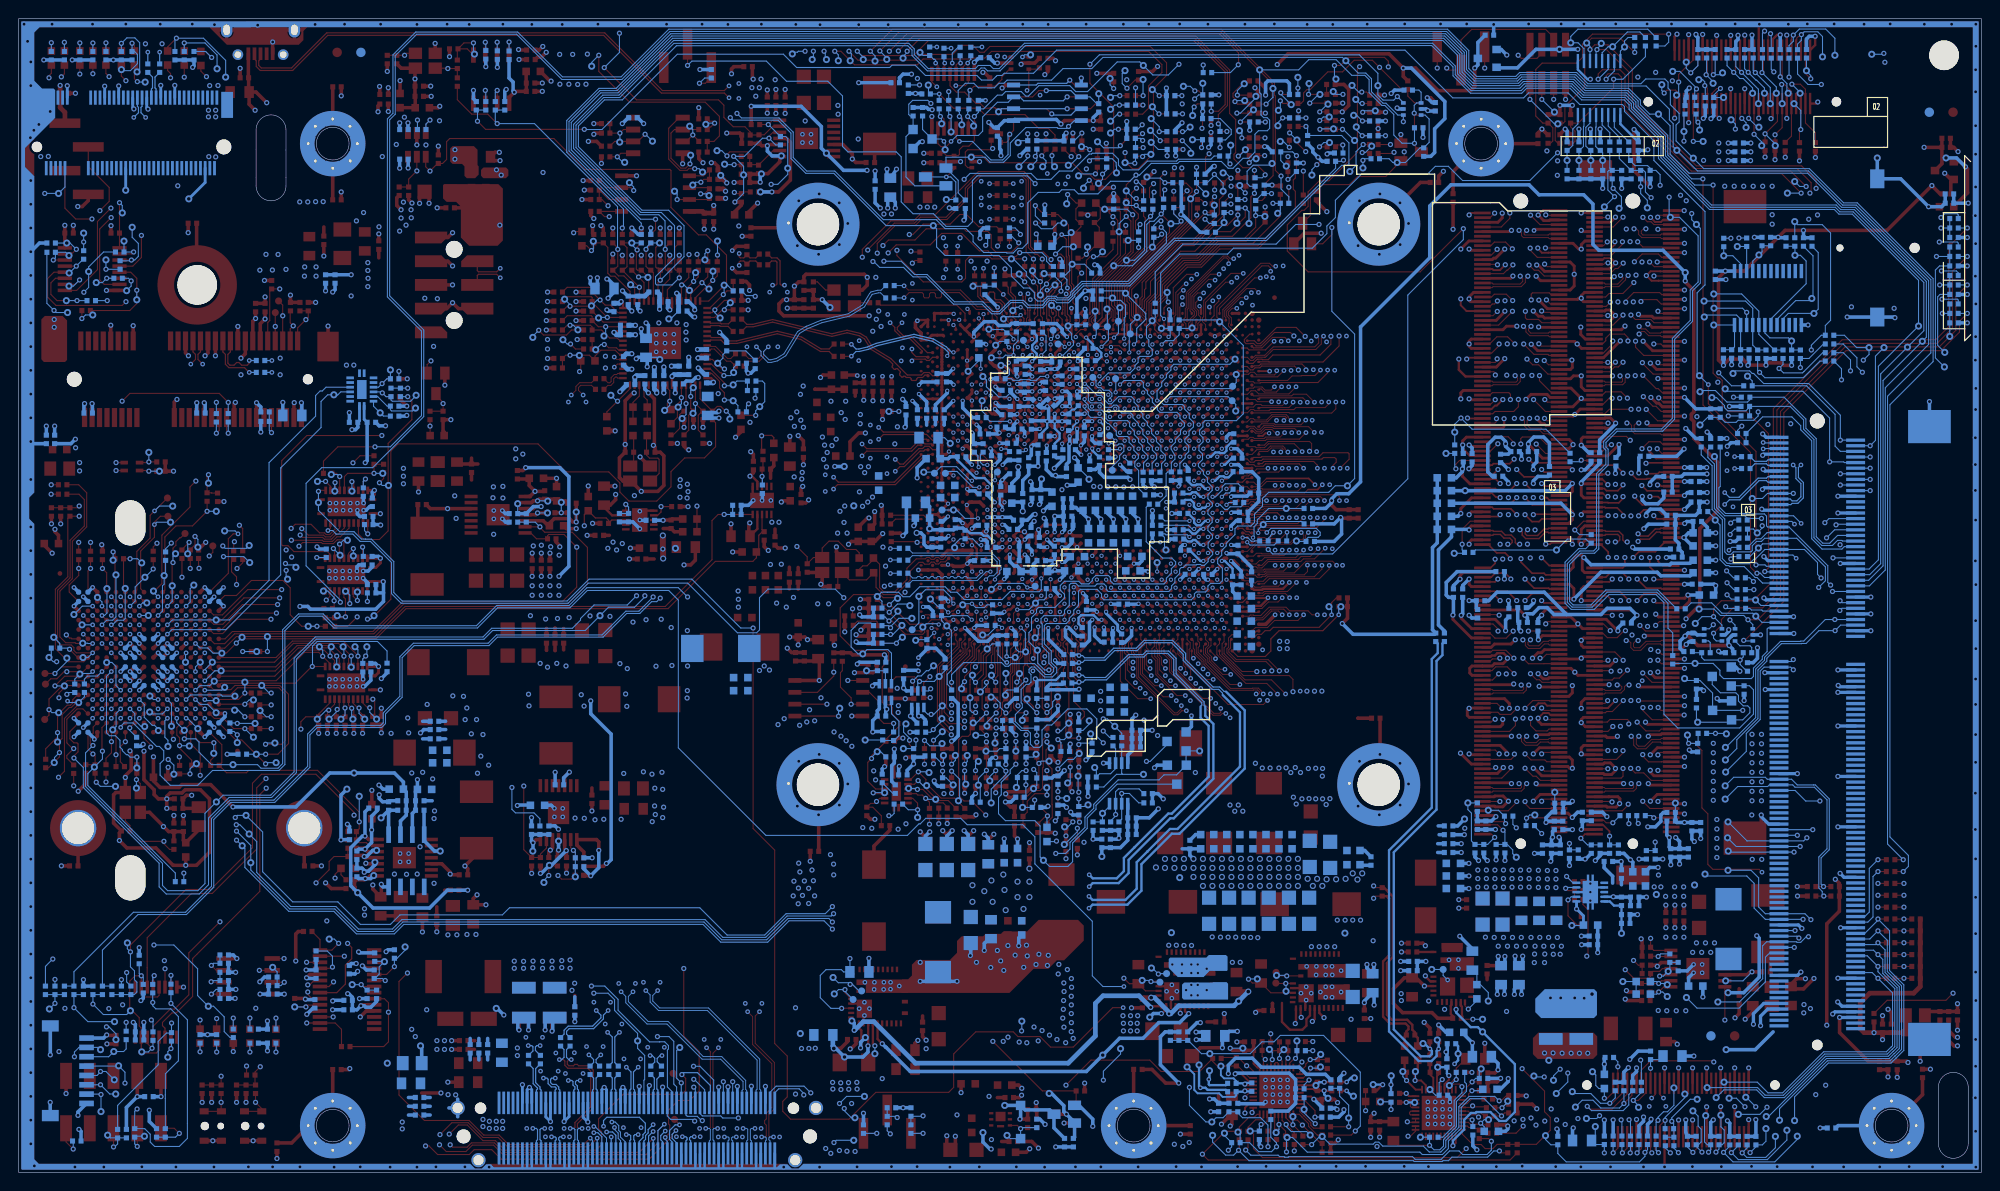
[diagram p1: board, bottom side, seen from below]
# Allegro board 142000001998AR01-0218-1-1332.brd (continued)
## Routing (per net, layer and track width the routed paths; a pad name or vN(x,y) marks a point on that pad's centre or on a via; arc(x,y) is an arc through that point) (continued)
USB1_VBUS_R: length 48.4
  TOP w0.114: R29.1 v2(70.79,112.6) ; v4(94.35,82.79) 94.33,82.77 94.32,82.77 U9.BB21
  S3 w0.102: v4(94.35,82.79) 93.88,83.26 93.88,85.91 93.11,86.68 93.11,87.1 92.61,87.59 92.61,88.09 92.3,88.4 92.3,93.88 90.93,95.25 89.66,95.25 85.88,99.03 83.22,99.03 80.59,101.65 77.14,101.65 73.64,105.15 73.64,106.39 74.73,107.48 74.73,110.13 74.35,110.52 73.67,110.52 73.18,111 72.21,111 71.58,111.63 71.58,112.12 71.09,112.6 v2(70.79,112.6)
  BOTTOM w0.114: v2(70.79,112.6) 70.41,112.98 v1(69.77,112.98)
USB2_DEBUG_DN: length 116.6
  TOP w0.127: v4(99.59,88.62) U9.AK9 ; v3(133.99,115.04) 134.49,115.54 141.23,115.54 147.41,121.72 176.93,121.72 180.69,117.96 184.15,117.96 184.58,118.39 184.58,118.99 184.77,119.18 CONN1.2
  S8 w0.102: v3(133.99,115.04) 133.99,115.37 134.09,115.47 134.51,115.47 134.8,115.18 134.8,112.99 128.57,106.76 122.63,106.76 116.99,101.12 100.58,101.12 97.92,98.45 97.92,95.69 97.16,94.93 97.16,94.5 96.55,93.89 96.55,91.92 97.26,91.21 99.21,91.21 99.95,90.47 99.95,88.98 v4(99.59,88.62)
USB2_DEBUG_DP: length 116.7
  TOP w0.127: v3(133.99,116.31) 134.49,115.8 141.12,115.8 147.3,121.98 177.04,121.98 180.8,118.22 184.04,118.22 184.32,118.5 184.32,118.99 184.12,119.18 CONN1.3 ; v4(100.56,88.62) 100.56,88.07 U9.AH9
  S8 w0.102: v3(133.99,116.31) 133.99,115.87 134.2,115.67 134.59,115.67 135,115.27 135,112.9 128.65,106.55 122.72,106.55 117.08,100.91 100.67,100.91 98.12,98.37 98.12,95.61 97.36,94.84 97.36,94.41 96.75,93.8 96.75,92.01 97.34,91.41 99.3,91.41 100.15,90.56 100.15,89.03 v4(100.56,88.62)
USB2_DN_3: length 171.2
  TOP w0.114: U9.AG7 v5(101.07,88.31)
  S3 w0.102: v5(101.07,88.31) 101.07,89.5 100.91,89.66 100.91,92.83 97.87,95.88 97.87,97.18 97.67,97.37 97.67,102.5 98.5,103.34 98.5,105.49 v3(98.82,105.8)
  S5 w0.102: v3(19.3,75.73) 19.63,76.06 19.63,78.14 22.1,80.6 22.1,86.24 21.89,86.45 21.89,96.76 13.88,104.77 13.88,104.94 13.88,115.64 17.19,118.95 24.18,118.95 24.85,119.62 30.24,119.62 30.28,119.66 35.42,119.66 35.95,119.13 50.94,119.13 51.55,119.74 95.78,119.74 98.81,116.71 98.81,113.32 99.31,112.82 99.31,112.01 98.79,111.49 98.79,107.9 98.48,107.59 98.48,106.15 v3(98.82,105.8)
  BOTTOM w0.127: v3(19.3,75.73) 19.57,75.45 19.57,74.38 19.04,73.85 19.04,72.2 19.63,71.62 20.24,71.62 20.38,71.48 CONN14.25
USB2_DP_3: length 169.1
  TOP w0.114: v5(100.52,89.22) 100.21,88.91 U9.AJ7
  S3 w0.102: v5(100.52,89.22) 100.71,89.41 100.71,92.75 97.66,95.8 97.66,97.09 97.46,97.29 97.46,102.59 98.3,103.42 98.3,105.51 v3(98.01,105.8)
  S5 w0.102: v3(98.01,105.8) 98.27,106.07 98.27,107.67 98.59,107.99 98.59,111.58 99.11,112.1 99.11,112.73 98.6,113.24 98.6,116.63 95.7,119.53 51.63,119.53 51.02,118.92 35.86,118.92 35.33,119.46 30.36,119.46 30.32,119.42 24.93,119.42 24.26,118.75 17.27,118.75 14.08,115.56 14.08,104.85 22.1,96.84 22.1,86.53 22.3,86.33 22.3,80.52 19.84,78.05 19.84,76.02 v3(20.13,75.73)
  BOTTOM w0.127: v3(20.13,75.73) 19.84,75.43 19.84,74.27 19.3,73.74 19.3,72.31 19.74,71.88 20.24,71.88 20.44,72.08 CONN14.23
USB2_EUSB_DN: length 84.5
  TOP w0.102: U9.AE4 101.81,90.71 102.16,91.06 102.16,91.39 102.02,91.53 102.02,92.25 102.05,92.28 102.05,92.3
  TOP w0.127: 102.05,92.3 102.05,92.55 102.55,93.05 102.55,93.78 v3(102.82,94.06) ; CONN5.4 160.93,96.53 160.8,96.4 158.84,96.4 v3(158.47,96.78)
  S8 w0.102: v3(158.47,96.78) 158.07,96.37 157.78,96.37 157.53,96.62 157.53,102.54 152.63,107.44 146.53,107.44 144.32,109.65 132.76,109.65 131.9,108.8 131.9,105.72 129.98,103.81 129.98,100.05 126.76,96.82 112.77,96.82 109.36,93.42 102.64,93.42 102.51,93.55 102.51,93.75 v3(102.82,94.06)
USB2_EUSB_DP: length 84.6
  TOP w0.102: U9.AE2 101.81,92.25 101.78,92.28 101.78,92.3
  TOP w0.127: CONN5.6 160.93,96.01 160.8,96.14 158.84,96.14 v3(158.47,95.76) ; 101.78,92.3 101.78,92.66 102.28,93.16 102.28,93.78 v3(102.01,94.06)
  S8 w0.102: v3(102.01,94.06) 102.31,93.75 102.31,93.46 102.56,93.22 109.45,93.22 112.85,96.62 126.85,96.62 130.19,99.96 130.19,103.72 132.11,105.64 132.11,108.71 132.84,109.45 144.24,109.45 146.45,107.24 152.54,107.24 157.33,102.46 157.33,101.57 157.15,101.39 157.15,101.16 157.33,100.99 157.33,100.76 157.15,100.58 157.15,100.35 157.33,100.17 157.33,99.95 157.15,99.77 157.15,99.54 157.33,99.36 157.33,99.13 157.15,98.95 157.15,98.73 157.33,98.55 157.33,98.32 157.15,98.14 157.15,97.91 157.33,97.74 157.33,97.51 157.15,97.33 157.15,97.1 157.33,96.92 157.33,96.54 157.7,96.17 158.07,96.17 v3(158.47,95.76)
USB2_FRONT_DN: length 132.4
  TOP w0.127: v4(102.79,91.77) 102.44,91.41 102.44,90.85 U9.AD3
  S10 w0.102: v4(102.79,91.77) 103.05,92.02 104.03,92.02 108.07,87.99 109.18,87.99 110.22,89.03 113.51,89.03 113.77,89.28 119.41,89.28 119.72,89.59 121.07,89.59 121.97,88.69 121.97,85.36 125.3,82.03 125.3,73.25 125.98,72.57 131.39,72.57 135.1,68.85 135.1,23.29 146.02,12.37 146.02,8.66 144.88,7.52 139.49,7.52 138.25,6.28 138.25,3.91 138.15,3.81 v3(137.72,3.81)
  BOTTOM w0.127: CONN16.84 138.1,3.37 138.22,3.49 138.22,3.68 138.09,3.81 v3(137.72,3.81) ; v4(102.79,91.77) 102.97,91.59 104.39,91.59 v1(104.62,91.36)
USB2_FRONT_DP: length 131.4
  TOP w0.127: v4(102.79,92.61) 102.67,92.61 102.31,92.25 U9.AD1
  S10 w0.102: v4(102.79,92.61) 103.17,92.23 104.11,92.23 108.15,88.19 109.09,88.19 110.13,89.23 113.43,89.23 113.68,89.48 119.33,89.48 119.63,89.79 121.16,89.79 122.17,88.77 122.17,85.45 125.5,82.12 125.5,73.33 126.06,72.77 131.47,72.77 135.31,68.94 135.31,23.37 146.23,12.45 146.23,8.58 144.97,7.32 139.57,7.32 138.45,6.2 138.45,3.91 138.56,3.81 v3(138.99,3.81)
  BOTTOM w0.127: v3(138.99,3.81) 138.61,3.81 138.49,3.68 138.49,3.49 138.6,3.37 CONN16.82 ; v1(103.63,92.25) 103.28,92.61 v4(102.79,92.61)
USB2_OC0_REAR_N: length 4
  TOP w0.114: R80.1 v2(83.97,107.59)
  BOTTOM w0.114: v2(83.97,107.59) R80.1 R471.2 83.97,105.77 82.98,104.78 v1(82.98,104.75)
USB2_OC0_REAR_R_N: length 19.3
  TOP w0.102: 91.67,93.09 91.42,92.84 U9.BH1
  TOP w0.114: R79.2 R80.2 v2(83.97,105) 84.48,104.5 84.48,101.96 91.67,94.77 91.67,93.09
  BOTTOM w0.114: v1(84.61,104.22) 83.97,104.85 v2(83.97,105)
USB3_OC1_REAR_N: length 3.3
  TOP w0.114: R90.1 89.64,104.01 R112.1 90.19,104.01 v2(90.42,104.24)
  BOTTOM w0.114: v2(90.42,104.24) 90.67,104.24 v1(91.49,105.07)
USB3_OC1_REAR_R_N: length 16.8
  TOP w0.102: 93.32,92.71 92.9,92.29 U9.BE2
  TOP w0.114: v2(90.42,103.5) 90.02,103.1 R112.2 89.64,102.36 89.46,102.18 89.46,99.06 93.32,95.2 93.32,92.71
  BOTTOM w0.114: R112.2 90.02,103.1 v2(90.42,103.5) 91.2,103.5 v1(91.49,103.8)
VENDER1: length 3
  TOP w0.114: TP2.1 v2(182.55,90.55) 182.55,90.2 182.55,90.2 CONN6.45
VENDER2: length 4.5
  TOP w0.114: TP1.1 181.75,92.84 v2(181.75,91.69) CONN6.47
VR_P1V2_VDDQ_PWRGD: length 195.3
  TOP w0.114: U12.L10 v3(198.09,51.61) ; v2(55.58,9.17) 55.85,9.45 56.49,9.45 56.64,9.3 U29.9
  S5 w0.102: v3(198.09,51.61) 198.09,51.61 197.61,51.13 197.61,49.43 197.37,49.18 196.63,49.18 194.85,47.4 192.16,47.4 190.98,46.22 190.98,45.19 190.53,44.75 189.08,43.29 189.08,35.14 180.31,26.37 180.15,26.37 179.35,25.56 179.35,25.41 177.27,23.33 177.27,16.19 176.34,15.27 173.11,15.27 169.13,11.29 161.48,11.29 157.31,7.12 139.12,7.12 138.27,7.98 130.83,7.98 129.85,7 128.69,7 127.88,7.81 126.74,7.81 126.69,7.75 125.35,7.75 125.13,7.97 123.43,7.97 122.81,7.35 122.19,7.35 v2(122.17,7.37)
  S8 w0.102: v2(55.58,9.17) 59.2,9.17 61.34,7.02 61.72,7.02 62.06,7.37 66.89,7.37 68.01,6.25 69.1,6.25 70.21,7.36 73.79,7.36 74.05,7.1 76.67,7.1 78.28,5.49 79.14,5.49 80.06,6.4 80.06,9.33 82.41,11.68 84.2,11.68 84.76,12.24 86.1,12.24 86.71,12.85 89.76,12.85 92.21,12.85 92.56,13.2 95.32,13.2 96.31,12.2 110.83,12.2 114.65,8.38 121.28,8.38 122.17,7.49 v2(122.17,7.37)
  BOTTOM w0.114: R758.1 57.63,3.76 56.4,4.99 56.4,7.69 55.58,8.52 v2(55.58,9.17) ; v2(122.17,7.37) 121.41,8.13 v1(119.51,8.13)
VR_P1V2_VDDQ_PWRGD_LED6: length 62.5
  TOP w0.114: U12.B9 v3(197.09,61.61) ; LED6.C v2(202.06,117.61)
  S5 w0.102: v2(202.06,117.61) 202.06,108.34 204.37,106.04 204.37,102.56 203.47,101.66 203.47,101.09 204.52,100.04 204.52,90.79 200.36,86.62 200.36,66.1 199.14,64.88 199.14,63.66 v3(197.09,61.61)
VR_P1V2_VDDQ_PWRGD_R: length 35.8
  TOP w0.114: LED6.A v2(202.06,120.9)
  S10 w0.102: v2(202.06,120.9) 201.52,120.35 201.52,112.4 198.04,108.93 192.55,108.93 182.25,98.63 v2(182.25,98.26)
  BOTTOM w0.114: R410.2 v2(202.06,120.9)
VR_P1V05_PCH_VRHOT_N: length 160.2
  TOP w0.114: U12.N12 v3(200.09,49.61)
  S3 w0.102: v2(80.57,2.36) 80.98,2.36 88.95,10.34 100.01,10.34 v2(104.15,14.47)
  S8 w0.102: v3(200.09,49.61) 200.09,49.59 200.53,49.15 200.53,47.05 200.92,46.67 200.92,46.04 200.31,45.44 200.31,44.45 199.03,43.18 198.03,43.18 197.82,42.97 196.79,42.97 195.42,41.6 195.42,39.46 190.63,34.67 190.63,27.15 188.04,24.56 179.6,24.56 177.93,22.89 177.93,21.71 177.23,21.01 177.23,20.01 176.69,19.47 176.22,19.47 174.77,18.02 174.77,16.25 170.13,11.61 160.46,11.61 156.29,7.44 138.19,7.44 131.36,14.27 119.72,14.27 118.93,15.06 106.16,15.06 105.83,14.73 104.41,14.73 v2(104.15,14.47)
  BOTTOM w0.114: v2(80.57,2.36) 80.21,2.72 R777.1 80.99,3.95 v1(80.99,4.19)
VR_P1V05_PCH_VSP_NC: length 2.5
  TOP w0.305: v4(86.96,89.44) 87.25,89.73 U9.BT5
  BOTTOM w0.114: v1(87.73,90.35) C285.2 86.79,89.61 v4(86.96,89.44)
VR_P3V3_CPLD_EN: length 55.7
  TOP w0.114: U12.F6 v3(193.09,57.61)
  S8 w0.102: v3(193.09,57.61) 192.53,58.17 184.45,58.17 181.38,55.09 181.38,47.36 179.21,45.19 179.2,45.19 179.18,45.16 159.77,45.16 157.23,42.62 v2(157.23,41.2)
  BOTTOM w0.114: v2(157.23,41.2) 157.23,38.86 156.84,38.48 154.86,38.48 154.23,37.85 R732.1
VR_P5V_STBY_EN: length 103.1
  TOP w0.114: U4.7 129.33,112.63 v2(129.79,112.17) R34.1 ; U12.D4 v3(191.09,59.61)
  S3 w0.102: v3(191.09,59.61) 190.53,60.17 190.53,60.85 190.47,60.9 190.47,63.11 188.85,64.73 188.85,69.39 171.15,87.09 171.15,93.45 171.12,93.47 171.12,96.65 165.94,101.83 162.76,101.83 161.57,103.02 149.63,103.02 146.84,105.82 138.46,105.82 137.82,106.45 130.18,106.45 v2(129.49,105.77)
  BOTTOM w0.114: v2(129.49,105.77) 128.78,105.77 127.71,106.83 v1(127.71,107.49) 127.71,110.67 127.94,110.89 R455.2 129.77,112.17 v2(129.79,112.17)
VR_PVCCIN_EN: length 151.3
  TOP w0.114: U12.N9 v3(197.09,49.61) ; R395.2 v2(76.33,2.74)
  S3 w0.102: v2(98.91,14.21) 98.91,14 97.08,12.17 88.19,12.17 86.57,10.54 85.55,10.54 85.45,10.44 85.45,10.44 84.73,9.73 v2(84.73,9.09)
  S8 w0.102: v2(98.91,14.21) 98.91,14.64 100.86,16.59 105.1,16.59 105.4,16.89 111.88,16.89 114.09,19.1 114.47,19.1 114.47,19.1 140.09,19.1 140.42,18.77 146.2,18.77 150.72,23.29 169.34,23.29 171.02,24.97 176.78,24.97 178.53,26.72 182.12,26.72 182.31,26.72 187.96,32.38 187.96,38.21 193.27,43.52 193.27,44.5 194.74,45.97 194.98,45.97 195.74,46.73 195.74,47.24 196.24,47.74 196.24,49.22 196.63,49.61 v3(197.09,49.61)
  BOTTOM w0.114: v2(84.73,9.09) 84.73,7.16 82.96,5.39 v1(82.33,5.39) 81.88,5.84 81.14,5.84 R747.1 R746.1 79.56,6.35 79.04,5.84 77.11,5.84 76.33,5.05 v2(76.33,2.74)
VR_PVCCIN_VRHOT_N: length 173.1
  TOP w0.114: U12.P12 v3(200.09,48.61) ; R394.2 v2(75.41,2.74)
  S3 w0.102: v2(102.95,13.94) 99.57,10.57 88.86,10.57 81.24,2.95 78.11,2.95 77.42,2.26 75.9,2.26 v2(75.41,2.74)
  S8 w0.102: v2(102.95,13.94) 102.97,13.94 103.99,14.96 105.74,14.96 106.07,15.29 119.03,15.29 119.36,14.96 119.38,14.96 119.84,14.5 131.45,14.5 138.28,7.67 156.2,7.67 160.36,11.84 170.04,11.84 172.44,14.24 172.44,18.5 173.04,19.11 173.79,19.11 174.38,19.7 176.6,19.7 177,20.1 177,21.11 177.66,21.77 177.66,23.04 179.41,24.79 187.95,24.79 190.4,27.24 190.4,36.91 195.73,42.24 195.73,42.24 196.69,43.2 197.72,43.2 197.93,43.41 198.94,43.41 200.08,44.55 200.08,45.53 200.69,46.14 200.69,46.57 200.09,47.17 v3(200.09,48.61)
  BOTTOM w0.114: R750.1 76.02,3.76 75.41,3.15 v2(75.41,2.74) 75.95,2.21 77.33,2.21 78.29,3.17 R777.2 79.3,4.07 v1(79.54,4.3)
VR_PWREN_PVDDR: length 189.6
  TOP w0.114: U12.N11 v3(199.09,49.61) ; v2(54.48,5.61) 54.62,5.75 U29.17
  S3 w0.102: v2(54.48,5.61) 54.63,5.61 56.23,4.01 59.98,4.01 61.88,2.11 72.06,2.11 73.43,3.48 81.45,3.48 88.76,10.79 99.06,10.79 v2(102.13,13.87)
  S8 w0.102: v3(199.09,49.61) 199.52,49.18 199.52,45.32 199.09,44.88 199.09,43.88 198.84,43.64 197.84,43.64 197.63,43.43 196.59,43.43 190.17,37.01 190.17,27.34 187.88,25.04 179.34,25.04 177.41,23.11 177.41,21.84 176.77,21.2 176.77,20.2 176.5,19.93 174.29,19.93 173.75,19.39 173,19.39 172.21,18.6 172.21,16.97 167.3,12.06 160.27,12.06 156.1,7.9 139.29,7.9 138.23,8.97 138.23,10.15 137.96,10.41 135.94,10.41 131.6,14.75 120.05,14.75 119.29,15.52 105.97,15.52 105.64,15.19 103.45,15.19 v2(102.13,13.87)
  BOTTOM w0.114: v1(199.94,47.38) 199.92,47.38 199.58,47.72 199.58,49.12 v3(199.09,49.61) ; v2(54.48,5.61) 54.41,5.54 R755.1
VTT_REFIN: length 5
  BOTTOM w0.254: U37.1 39.75,29 39.31,28.56 R699.2 R700.1 C588.2 v1(38.5,25.58)
VTT_REFOUT: length 2.4
  TOP w0.114: v2(44.37,31.67) 43.81,31.11 C155.2
  BOTTOM w0.114: v2(44.37,31.67) 43.7,31 U37.6
WAKEL_DIR: length 4.6
  TOP w0.114: R802.2 R982.2 168.28,106.32 v2(167.4,107.2) U38.5
WATCHDOG_IND: length 150.8
  TOP w0.114: U9.AM4 99.34,90.22 99.69,90.58 99.69,90.86 99.49,91.06 99.49,91.49 99.75,91.74 99.75,94.07 99.55,94.26 99.55,94.3 98.09,95.76 98.09,97.91 98.48,98.3 v2(99.06,98.3) ; R153.2 R155.1 R885.1 203.71,71.15 v2(203.53,71.33)
  S3 w0.102: v2(156.82,76.38) 156.57,76.12 153.56,76.12 150.94,78.74 136.17,78.74 130.23,84.68 126.7,84.68 124.66,86.72 124.66,88.37 123.13,89.9 121.48,89.9 114.88,96.49 114.88,97.69 114.55,98.02 114.35,98.02 111.61,100.76 105.22,100.76 105.02,100.97 102.39,100.97 102.03,100.61 102.03,99.54 101.47,98.98 99.75,98.98 v2(99.06,98.3)
  S8 w0.102: v2(203.53,71.33) 201.5,73.36 179.7,73.36 175.53,77.53 173.49,77.53 171.98,79.04 171.98,85.17 170.92,86.23 168.76,86.23 166.9,84.38 166.9,79.12 164.16,76.38 v2(156.82,76.38)
  BOTTOM w0.114: v1(97.16,99.09) 98.27,99.09 v2(99.06,98.3)
XDP_CPU_MBP<2>: length 131.3
  TOP w0.114: CONN11.9 26.89,2.25 v2(26.75,2.11) ; U9.N78 107.26,54.49 v2(107.63,54.11)
  S5 w0.102: v2(107.63,54.11) 106.76,53.24 99.43,53.24 97.17,50.98 96.53,50.98 95.43,49.87 95.43,48.69 94.61,47.88 93.85,47.88 93.14,47.17 93.14,31.78 92.35,30.99 92.35,25.88 90.07,23.59 90.07,20.69 88.98,19.61 88.35,19.61 86.7,17.96 79.97,17.96 78.67,16.66 74.19,16.66 73.56,17.3 69.14,17.3 66.96,15.11 57.15,15.11 55.4,13.36 36.34,13.36 34.57,11.59 34.57,9.93 v2(26.75,2.11)
  BOTTOM w0.114: R773.1 26,2.86 v2(26.75,2.11) 26,1.36 22.9,1.36 20.8,3.45 v1(20.8,4.51)
XDP_CPU_MBP<3>: length 137.7
  TOP w0.102: 107.96,55.27 107.96,56.22 108.09,56.35 108.09,56.7 107.75,57.04 U9.M75
  TOP w0.114: v2(108.79,49.15) 109.37,49.73 109.37,53.86 107.96,55.27 ; CONN11.11 27.39,2.33 v2(27.58,2.13)
  S5 w0.102: v2(108.79,49.15) 107.16,47.52 107.16,45.42 104.9,43.15 104.9,42.01 99.65,36.76 98.9,36.76 98.42,36.28 98.42,28.97 93.85,24.4 93.85,14.5 91.46,12.11 77.69,12.11 76.15,10.57 71.5,10.57 69.01,13.06 61.47,13.06 57.12,8.71 55.39,8.71 54.88,9.22 54.23,9.22 53.85,8.84 50.88,8.84 48.23,6.2 48.23,5.92 48.18,5.87 v2(48.18,5.82)
  S10 w0.102: v2(48.18,5.82) 47.9,6.1 45.66,6.1 45.41,6.35 43.09,6.35 40.8,4.06 29.51,4.06 v2(27.58,2.13)
  BOTTOM w0.114: v1(19.69,3.87) 19.69,3.52 22.1,1.12 26.57,1.12 v2(27.58,2.13) 26.91,2.81 R774.1
XDP_CPU_MBP<4>: length 147.2
  TOP w0.102: U9.J78 111.21,53.85
  TOP w0.114: 111.21,53.85 111.21,48.83 110.41,48.03 109.25,48.03 v2(108.81,47.6) ; CONN11.15 v2(28.39,2.16)
  S5 w0.102: v2(108.81,47.6) 107.62,46.41 107.62,44.16 106.93,43.48 106.93,40.33 106.59,39.98 105.78,39.98 104.58,38.77 102.31,38.77 99.77,36.23 99.77,36.01 99.77,36.01 99.77,29.67 94.31,24.21 94.31,14.31 91.55,11.55 88.74,11.55 85.41,8.23 83.49,8.23 82.95,8.76 82.2,8.76 81.65,8.21 81.02,8.21 80.12,7.32 77.76,7.32 77.54,7.1 74.05,7.1 72.67,8.48 72.64,8.48 68.53,12.6 61.66,12.6 57.31,8.26 55,8.26 54.79,8.05 54.22,8.05 53.89,8.38 51.31,8.38 49.99,7.06 v2(49.99,5.51)
  S10 w0.102: v2(28.39,2.16) 27.8,1.57 24.23,1.57 23.75,2.06 23.75,3.2 25.3,4.75 40.51,4.75 43.05,7.29 48.21,7.29 v2(49.99,5.51)
  BOTTOM w0.114: v1(27.86,6.12) 27.86,4.88 27.51,4.52 27.51,3.17 27.73,2.95 R766.1 28.07,2.49 v2(28.39,2.16)
XDP_CPU_MBP<5>: length 137.6
  TOP w0.102: 111.7,54.21 109.58,56.33 109.58,56.85 109.73,57 U9.H75
  TOP w0.114: v2(110.21,46.84) 111.7,48.32 111.7,54.21 ; CONN11.17 28.89,2.45 v2(29.18,2.16)
  S5 w0.102: v2(43.16,5.76) 43.16,4.46 43.81,3.81 51.15,3.81 52.14,4.8 55.97,4.8 56.49,4.28 59.63,4.28 61.75,6.4 61.91,6.4 62.69,7.18 66.43,7.18 67.82,5.79 69.43,5.79 70.52,6.88 72.97,6.88 73.69,6.17 76.94,6.17 77.67,5.44 79.24,5.44 79.43,5.24 79.68,5.24 80.08,5.64 80.66,5.64 81.63,6.61 81.92,6.61 82.26,6.94 82.64,6.94 82.97,6.61 85.09,6.61 89.11,10.64 92.59,10.64 95.27,13.31 95.27,23.87 100.69,29.29 100.69,35.63 100.69,35.64 100.69,35.85 102.69,37.86 104.96,37.86 106.16,39.07 108.51,39.07 109.47,40.03 109.47,44.01 110.64,45.18 110.64,46.41 v2(110.21,46.84)
  S10 w0.102: v2(29.18,2.16) 30.86,3.84 41.24,3.84 v2(43.16,5.76)
  BOTTOM w0.114: v1(29.49,6.07) 29.62,5.94 29.62,3.25 29.31,2.95 R767.1 28.96,2.39 v2(29.18,2.16)
XDP_CPU_MBP<6>: length 140.1
  TOP w0.102: U9.K75 108.74,57.04 109.09,56.69 109.09,56.21 108.95,56.07 108.95,55.66 109.25,55.37 109.35,55.37 110.97,53.75
  TOP w0.114: CONN11.21 v2(29.89,2.16) ; 110.97,53.75 110.97,49.28 v2(110.21,48.51)
  S5 w0.102: v2(45.44,5.61) 46.79,4.27 50.96,4.27 52.02,5.33 52.02,7.04 52.85,7.87 53.76,7.87 54.03,7.59 55.02,7.59 56.43,6.19 56.43,4.99 56.68,4.74 59.44,4.74 61.56,6.86 61.72,6.86 62.53,7.67 66.59,7.67 68.01,6.25 69.24,6.25 70.33,7.34 73.16,7.34 73.87,6.63 77.13,6.63 77.86,5.89 79.69,5.89 79.89,6.1 80.47,6.1 81.44,7.06 81.74,7.06 82.12,7.45 82.12,8.04 82.39,8.31 82.76,8.31 83.88,7.19 85.02,7.19 88.92,11.09 92.4,11.09 94.78,13.48 94.78,24.03 100.23,29.48 100.23,35.82 100.23,35.82 100.23,36.04 102.5,38.32 104.77,38.32 105.97,39.52 107.57,39.52 108.08,40.03 108.08,46.13 108.46,46.51 108.85,46.51 109.65,47.31 109.65,47.75 110.21,48.31 v2(110.21,48.51)
  S10 w0.102: v2(45.44,5.61) 43.71,5.61 41.71,3.61 31.34,3.61 v2(29.89,2.16)
  BOTTOM w0.114: v1(30.86,6.58) 30.3,6.02 30.3,4.95 29.97,4.62 29.97,3.25 30.27,2.95 R768.1 30.51,2.78 v2(29.89,2.16)
XDP_CPU_MBP<7>: length 131.8
  TOP w0.102: 111.46,54.1 109.37,56.19 109.37,56.92 U9.J76
  TOP w0.114: CONN11.23 30.39,2.6 v2(30.86,2.13) ; v2(110.21,47.55) 110.39,47.55 111.46,48.62 111.46,54.1
  S5 w0.102: v2(110.21,47.55) 109.7,47.04 109.7,46.12 108.31,44.72 108.31,39.94 107.66,39.29 106.07,39.29 104.86,38.09 102.6,38.09 100.46,35.95 100.46,35.73 100.46,35.73 100.46,29.39 95.04,23.97 95.04,13.41 92.5,10.86 89.02,10.86 84.99,6.84 83.07,6.84 82.73,7.17 82.16,7.17 81.83,6.84 81.54,6.84 80.57,5.87 79.99,5.87 79.78,5.66 77.77,5.66 77.03,6.4 73.78,6.4 73.07,7.11 70.43,7.11 69.34,6.02 67.91,6.02 66.49,7.44 62.63,7.44 61.82,6.63 61.65,6.63 59.53,4.51 56.58,4.51 56.2,4.9 56.2,5.87 55.57,6.49 53.51,6.49 51.05,4.04 45.35,4.04 44.52,4.87 v2(44.52,5.12)
  S10 w0.102: v2(44.52,5.12) 44.52,4.42 43.48,3.38 32.11,3.38 v2(30.86,2.13)
  BOTTOM w0.114: R769.1 31.45,2.72 v2(30.86,2.13)
XDP_CPU_PRDY_N: length 135.3
  TOP w0.102: U9.L78 108.25,55.35
  TOP w0.114: CONN11.5 25.89,2.39 v2(25.59,2.08) ; v2(108.79,48.31) 109.61,49.14 109.61,53.99 108.25,55.35
  S5 w0.102: v2(49.05,5.66) 49.05,6.57 51.09,8.61 53.99,8.61 54.32,8.28 54.7,8.28 54.9,8.48 57.22,8.48 61.56,12.83 68.92,12.83 71.41,10.34 76.24,10.34 77.79,11.88 91.56,11.88 94.08,14.4 94.08,24.3 99.54,29.76 99.54,36.11 99.54,36.11 99.54,36.33 102.22,39 104.48,39 105.97,40.49 105.97,43.31 107.39,44.73 107.39,46.91 v2(108.79,48.31)
  S10 w0.102: v2(49.05,5.66) 48.39,6.32 45.77,6.32 45.51,6.58 43,6.58 40.71,4.29 27.8,4.29 v2(25.59,2.08)
  BOTTOM w0.114: R772.1 25.06,2.61 v2(25.59,2.08) 25.1,1.6 23.06,1.6 22.03,2.63 v1(22.03,3.85)
XDP_CPU_PREQ_N: length 142.4
  TOP w0.102: 110.72,53.6 108.74,55.58 108.74,56.55 U9.K77
  TOP w0.114: v2(110.19,49.2) 110.72,49.73 110.72,53.6 ; CONN11.3 25.39,2.76 v2(24.74,2.11)
  S5 w0.102: v2(46.02,6.78) 46.02,5.44 46.96,4.5 50.86,4.5 51.79,5.42 51.79,7.14 52.81,8.15 53.8,8.15 54.13,7.82 54.89,7.82 55.09,8.03 57.41,8.03 61.75,12.37 68.43,12.37 72.55,8.25 72.57,8.25 73.96,6.87 74.66,6.87 74.68,6.86 77.62,6.86 77.85,7.09 80.21,7.09 81.11,7.99 81.74,7.99 82.29,8.53 82.86,8.53 83.41,7.99 85.49,7.99 88.83,11.32 91.65,11.32 94.54,14.22 94.54,24.11 100,29.58 100,35.92 100,35.92 100,36.14 102.41,38.54 104.67,38.54 105.88,39.75 106.68,39.75 107.16,40.23 107.16,43.38 107.85,44.07 107.85,46.22 108.36,46.74 108.75,46.74 109.42,47.41 109.42,48.44 v2(110.19,49.2)
  S10 w0.102: v2(24.74,2.11) 24.74,3.87 25.39,4.52 40.61,4.52 42.9,6.81 46,6.81 v2(46.02,6.78)
  BOTTOM w0.114: v2(24.74,2.11) 24.12,2.73 R771.1 23.43,2.94 23.04,3.32 v1(23.04,4.68)
XDP_CPU_PRESENT_N: length 125
  TOP w0.102: U9.M77 107.75,55.09
  TOP w0.114: v2(108.76,53.72) 108.76,54.08 107.75,55.09 ; CONN11.60 39.39,8.56 40.03,7.92 v2(40.34,7.92)
  S5 w0.102: v2(108.76,53.72) 108.08,53.04 105.28,53.04 104.83,52.58 104.83,52.21 104.55,51.93 98.44,51.93 97.22,50.7 96.58,50.7 95.66,49.78 95.66,48.08 94.19,46.61 93.7,46.61 93.37,46.28 93.37,31.68 92.58,30.89 92.58,25.78 90.3,23.5 90.3,20.6 89.08,19.38 88.45,19.38 86.8,17.73 80.06,17.73 76.68,14.35 73.78,14.35 72.43,15.7 70.3,15.7 69.49,14.88 57.24,14.88 55.09,12.73 48.44,12.73 48.01,12.29 38.8,12.29 38.25,12.85 36.38,12.85 35.92,12.38 35.92,8.2 37.31,6.81 38.63,6.81 38.99,7.16 38.99,7.49 39.42,7.92 v2(40.34,7.92)
  BOTTOM w0.114: v1(41.61,10.77) 41.25,10.41 41.25,9.3 40.92,8.97 R730.1 v2(40.34,7.92)
XDP_CPU_PWRBTN_N: length 16.6
  TOP w0.114: CONN11.41 34.89,2.46 v2(34.54,2.11)
  S3 w0.102: v2(34.54,2.11) 32.65,4 27.55,4 25.29,6.26 v2(25.29,7.02)
  BOTTOM w0.114: v2(34.54,2.11) 34.8,2.36 R759.1 ; v1(26.99,7.93) 26.21,7.93 v2(25.29,7.02)
XDP_CPU_SDA: length 10.4
  TOP w0.114: CONN4.51 20.32,121.54 v2(20.12,121.74)
  BOTTOM w0.114: v1(15.67,119.59) 15.67,121.41 16.65,122.39 19.47,122.39 v2(20.12,121.74) 20.12,121.08 20.57,120.62 R426.1
XDP_CPU_TCK0: length 110.5
  TOP w0.114: R255.2 108.18,47.37 108.18,46.86 108.2,46.86 108.39,46.67 109.06,46.67 109.42,46.3 109.42,40.32 108.85,39.75 108.03,39.75 v2(106.53,38.25) ; v2(39.39,2.08) 38.89,2.58 CONN11.57
  S5 w0.102: v2(39.39,2.08) 40.18,2.87 52.65,2.87 53.12,3.34 57.04,3.34 57.95,2.43 60.22,2.43 60.88,3.1 60.88,4.05 61.15,4.32 62.71,4.32 63.14,4.75 65.66,4.75 66.45,3.96 67.17,3.96 67.63,4.42 72.48,4.42 72.79,4.11 77.66,4.11 77.71,4.06 83.51,4.06 88.78,9.33 94.11,9.33 94.64,9.86 94.64,12.03 95.72,13.12 95.72,23.66 101.12,29.06 101.12,29.08 101.14,29.1 101.14,35.44 101.14,35.45 101.14,35.66 102.88,37.4 105.68,37.4 v2(106.53,38.25)
  BOTTOM w0.114: R764.1 v2(39.39,2.08)
XDP_CPU_TDI: length 113.5
  TOP w0.114: v2(39.75,7.39) 39.5,7.39 38.39,8.5 CONN11.56 ; R248.2 v2(105.46,49.94)
  S5 w0.102: v2(39.75,7.39) 40.84,7.39 41.75,6.48 42.42,6.48 45.47,9.53 51.79,9.53 53.85,11.58 55.56,11.58 56.4,12.42 59,12.42 60.33,13.74 69.97,13.74 70.78,14.55 71.96,14.55 73.3,13.21 77.28,13.21 77.68,12.8 91.14,12.8 93.17,14.83 93.17,24.68 93.73,25.24 93.73,30.42 94.51,31.21 94.51,40.84 95.33,41.66 95.33,46.02 96.57,47.27 97.49,47.27 99.42,49.2 99.42,50.32 99.69,50.6 104.8,50.6 v2(105.46,49.94)
  BOTTOM w0.114: R739.1 39.17,7.98 v2(39.75,7.39) 40.74,7.39 41.78,8.43 43.56,8.43 v1(43.76,8.64)
XDP_CPU_TDO: length 117.6
  TOP w0.114: v2(107.61,49.91) 107.62,49.91 107.49,50.04 R243.1 ; CONN11.52 37.39,8.21 v2(38.24,7.37)
  S5 w0.102: v2(107.61,49.91) 107.62,49.91 106.48,51.05 98.54,51.05 98.04,50.56 98.04,48.79 97.01,47.75 96.3,47.75 94.87,46.32 94.87,41.85 94.06,41.03 94.06,31.4 93.64,30.98 93.27,30.61 93.27,25.5 91.03,23.27 91.03,18.92 90.14,18.03 90.14,17.46 85.94,13.26 82.97,13.26 80.66,15.57 79.32,15.57 77.42,13.67 73.49,13.67 72.15,15.01 70.59,15.01 69.78,14.2 57.53,14.2 55.37,12.04 48.87,12.04 48.39,11.56 41.4,11.56 39.41,9.56 39.41,8.53 v2(38.24,7.37)
  BOTTOM w0.114: R738.1 v2(38.24,7.37) 38.72,6.88 40.72,6.88 41.55,7.72 42.7,7.72 v1(43.43,6.99)
XDP_CPU_TMS: length 109.2
  TOP w0.114: CONN11.58 v2(38.89,11.3) ; R242.2 v2(108.79,49.89)
  S5 w0.102: v2(38.89,11.3) 39.15,11.05 40.51,11.05 41.27,11.81 48.26,11.81 48.72,12.27 55.28,12.27 57.43,14.43 69.68,14.43 70.49,15.24 72.24,15.24 73.59,13.89 77.32,13.89 79.23,15.8 80.85,15.8 83.16,13.49 85.85,13.49 89.92,17.56 89.92,18.13 90.81,19.02 90.81,23.36 93.04,25.6 93.04,30.7 93.47,31.14 93.83,31.49 93.83,41.13 94.64,41.94 94.64,46.42 96.11,47.89 96.11,49.59 96.77,50.24 97.41,50.24 98.45,51.28 107.4,51.28 v2(108.79,49.89)
  BOTTOM w0.114: R726.1 38.89,11.84 v2(38.89,11.3)
XDP_CPU_TRST_N: length 116.9
  TOP w0.114: R246.1 106.32,50.04 v2(106.45,49.91) ; v2(42.16,7.06) 41.86,6.76 39.52,6.76 37.89,8.39 CONN11.54
  S5 w0.102: v2(42.16,7.06) 46.41,11.3 48.51,11.3 49.02,11.81 55.46,11.81 57.62,13.97 69.87,13.97 70.68,14.78 72.05,14.78 73.4,13.44 78.21,13.44 79.32,14.55 81.36,14.55 82.88,13.03 91.03,13.03 92.94,14.94 92.94,24.85 93.5,25.41 93.5,30.51 93.8,30.81 94.28,31.3 94.28,40.94 95.1,41.75 95.1,46.23 96.39,47.52 97.1,47.52 98.27,48.69 98.27,50.46 98.64,50.83 105.54,50.83 v2(106.45,49.91)
  BOTTOM w0.114: v2(42.16,7.06) 41.71,6.6 38.33,6.6 37.72,7.21 37.72,8.32 R737.1
XDP_NOA0_PCH: length 65.8
  TOP w0.114: R79.1 83.01,108.66 v2(82.63,109.04) ; v2(32.38,116.71) 32.38,117.53 30.82,119.09 CONN4.9
  S5 w0.102: v2(32.38,116.71) 32.38,115.6 34.39,113.59 48.56,113.59 51.08,116.1 68.05,116.1 68.17,115.98 70.26,115.98 70.82,116.54 73.84,116.54 74.29,116.08 76.78,116.08 78.96,113.89 79.8,113.89 81.08,112.61 81.08,111.91 82.21,110.78 82.21,109.46 v2(82.63,109.04)
  BOTTOM w0.114: v1(32.6,115.32) 32.51,115.32 32.38,115.44 v2(32.38,116.71)
XDP_NOA1_PCH: length 91.7
  TOP w0.114: CONN4.11 30.32,118.48 v2(31.09,117.7)
  S5 w0.102: v2(90.42,106.05) 90.88,105.59 90.88,103.3 90.35,102.77 90.35,102.11 90.47,101.98 90.47,101.28 89.17,99.97 87.52,99.97 87.25,100.24 87.25,103.96 87.86,104.57 87.86,107.29 88.44,107.87 88.44,113.65 85.15,116.94 78.86,116.94 78.79,117.02 76.02,117.02 76,116.99 74.67,116.99 74.22,117.45 70.44,117.45 70.01,117.02 44.79,117.02 44.21,116.44 44.08,116.31 35.22,116.31 33.5,118.03 31.92,118.03 31.59,117.7 v2(31.09,117.7)
  BOTTOM w0.114: R480.1 89.64,105.43 90.25,106.05 v2(90.42,106.05) ; v1(31.57,118.85) 31.57,118.19 v2(31.09,117.7) 30.33,118.46 R416.1
XDP_NOA2_PCH: length 74.8
  TOP w0.114: v2(29.44,117.5) 29.32,117.62 CONN4.15 ; R83.1 86.51,107.37 v2(86.33,107.54)
  S5 w0.102: v2(29.44,117.5) 29.92,117.02 30.63,117.02 30.75,116.89 31.43,116.89 31.55,117.02 32.07,117.53 33.36,117.53 34.77,116.12 35.04,115.85 38.87,115.85 38.87,115.85 39.82,115.85 39.82,115.85 44.27,115.85 44.67,116.25 44.97,116.56 70.19,116.56 70.63,116.99 74.03,116.99 74.48,116.54 76.19,116.54 76.21,116.56 78.6,116.56 78.67,116.48 84.96,116.48 87.12,114.32 87.12,109.86 87.58,109.41 87.58,108.33 86.79,107.54 v2(86.33,107.54)
  BOTTOM w0.114: R415.1 29.39,117.55 v2(29.44,117.5) 28.7,116.76 v1(28.7,116.59)
XDP_NOA3_PCH: length 73
  TOP w0.114: CONN4.17 28.82,117.64 v2(28.68,117.5) ; v2(84.99,105.08) 85.45,104.62 R102.1
  S5 w0.102: v2(28.68,117.5) 29.39,116.79 30.53,116.79 30.66,116.66 31.52,116.66 31.65,116.79 32.16,117.3 33.26,117.3 34.54,116.02 34.94,115.62 38.77,115.62 38.78,115.62 39.91,115.62 39.92,115.62 44.36,115.62 45.07,116.33 70.29,116.33 70.72,116.76 73.93,116.76 74.39,116.31 76.87,116.31 79.03,114.15 80.42,114.15 81.97,112.6 83.2,112.6 84.51,111.29 84.51,105.56 v2(84.99,105.08)
  BOTTOM w0.114: R414.1 28.48,117.7 v2(28.68,117.5) 27.89,117.5 v1(27.69,117.7)
XDP_NOA4_PCH: length 84
  TOP w0.114: R111.1 89,104.36 89,105.41 v2(88.57,105.84) ; CONN4.27 26.32,117.93 v2(26.49,117.75)
  S5 w0.102: v2(88.57,105.84) 88.98,106.25 88.98,114.94 86.75,117.17 78.96,117.17 78.88,117.25 75.93,117.25 75.9,117.22 74.77,117.22 74.31,117.68 70.34,117.68 69.91,117.25 44.69,117.25 43.99,116.54 35.35,116.54 33.6,118.29 30.85,118.29 30.75,118.19 26.92,118.19 v2(26.49,117.75)
  BOTTOM w0.114: R421.1 27.21,118.47 v2(26.49,117.75) 25.83,117.09 25.48,117.09 24.47,116.08 v1(24.47,115.52)
XDP_NOA4_PCH_R: length 22.2
  TOP w0.102: 93.07,92.81 92.69,92.44 92.69,91.52 92.55,91.38 92.55,91.07
  TOP w0.114: 92.55,91.07 92.9,90.72 U9.BE4 ; R111.2 88.65,102.59 v2(88.9,102.34) 89.03,102.21 89.03,99.14 93.07,95.1 93.07,92.81
  BOTTOM w0.114: v1(91.47,97.64) 90.6,97.64 89.53,98.7 89.53,101.7 v2(88.9,102.34) 88.65,102.59 R111.2
XDP_NOA5_PCH: length 84.4
  TOP w0.114: v2(87.38,106.98) 87.86,106.5 87.86,104.55 R104.1 ; v2(25.65,117.75) 25.82,117.92 CONN4.29
  S5 w0.102: v2(25.65,117.75) 26.11,117.3 27.3,117.3 27.97,117.96 29.94,117.96 30.65,117.25 30.72,117.25 30.85,117.12 31.33,117.12 31.46,117.25 31.97,117.76 33.45,117.76 35,116.21 35.13,116.08 44.18,116.08 44.44,116.35 44.88,116.79 70.1,116.79 70.53,117.22 74.12,117.22 74.58,116.76 76.09,116.76 76.12,116.79 78.69,116.79 78.77,116.71 85.06,116.71 87.35,114.42 87.35,109.96 87.8,109.5 87.8,107.9 87.38,107.47 v2(87.38,106.98)
  BOTTOM w0.114: R420.1 26.27,118.37 v2(25.65,117.75) 23.85,115.95 v1(23.85,114.4)
XDP_NOA6_PCH: length 88.6
  TOP w0.114: CONN4.33 24.82,117.88 v2(24.94,117.75)
  S5 w0.102: v2(24.94,117.75) 25.6,118.41 30.65,118.41 30.75,118.52 34.82,118.52 35.53,117.81 52.3,117.81 52.63,117.47 69.82,117.47 70.25,117.91 74.41,117.91 74.86,117.45 75.81,117.45 75.84,117.47 78.98,117.47 79.05,117.4 86.84,117.4 89.2,115.04 89.2,103.84 88.39,103.02 88.39,102.46 v2(87.78,101.85)
  BOTTOM w0.114: v1(23.2,115.52) 23.2,116.08 24.03,116.92 24.1,116.92 v2(24.94,117.75) 25.33,118.14 R419.1 ; R489.1 88.55,101.37 88.06,101.85 v2(87.78,101.85)
XDP_NOA7_PCH: length 91.7
  TOP w0.114: CONN4.35 24.32,117.86 v2(24.18,117.73)
  S5 w0.102: v2(90.02,101.47) 89.94,101.55 89.94,108.08 90.25,108.38 90.25,115.35 87.97,117.63 79.15,117.63 79.07,117.7 75.74,117.7 75.72,117.68 74.96,117.68 74.5,118.14 70.15,118.14 69.82,117.81 66.43,117.81 65.52,118.72 65.36,118.8 51.9,118.8 51.32,118.21 35.45,118.21 34.92,118.75 30.66,118.75 30.61,118.69 25.22,118.69 24.25,117.73 v2(24.18,117.73)
  BOTTOM w0.114: R418.1 24.41,117.96 v2(24.18,117.73) 22.58,116.13 v1(22.58,114.4) ; R490.1 90.17,101.32 v2(90.02,101.47)
XDP_NOA8_PCH: length 22.2
  TOP w0.114: R98.1 77.4,98.85 81.49,98.85 83.44,96.9 84.96,96.9 87.12,94.74 87.12,93.7 87.86,92.96 87.86,91.31 U9.BR2
XDP_NOA8_PCH_R: length 54.1
  TOP w0.114: CONN4.10 v2(30.82,110.36) ; R98.2 v2(72.54,107.19)
  S10 w0.102: v2(30.82,110.36) 31.25,109.93 47.9,109.93 47.9,109.93 48.09,109.93 48.7,110.54 51.84,113.68 56,113.68 58.27,111.4 60.25,111.4 61.14,110.52 66.62,110.52 67.67,109.47 70.34,109.47 70.61,109.19 71.08,109.19 72.01,108.27 72.01,107.72 v2(72.54,107.19)
  BOTTOM w0.114: v1(29.77,110.36) v2(30.82,110.36)
XDP_NOA9_PCH: length 79.3
  TOP w0.114: U9.BT3 87.46,91.36 v4(87.45,91.36)
  S5 w0.102: v2(30.48,115.98) 36.75,109.7 44.78,109.7 v2(45.34,109.14)
  BOTTOM w0.114: R441.1 30.66,114.33 R433.1 30.66,115.79 v2(30.48,115.98) 30.48,116.08 32.26,117.86 v1(33.02,117.86) ; v2(45.34,109.14) 48.31,106.17 55.5,106.17 57.02,107.7 58.42,107.7 59.28,106.83 66.34,106.83 69.11,104.06 69.11,102.21 70.03,101.3 70.03,100.49 71.58,98.93 80.01,98.93 80.64,98.3 85.78,98.3 87.81,96.27 87.81,91.72 v4(87.45,91.36)
XDP_NOA9_PCH_R: length 3.9
  TOP w0.114: CONN4.12 v2(30.32,112.42)
  BOTTOM w0.114: v1(30.14,111.58) 30.14,112.24 v2(30.32,112.42) 30.53,112.63 R441.2
XDP_NOA10_PCH: length 61.1
  TOP w0.114: R38.1 v2(80.72,111.43) ; v2(29.59,116.33) 29.32,116.06 CONN4.16
  S10 w0.102: v2(80.72,111.43) 79.64,111.43 77.39,113.68 77.39,115.15 76.29,116.26 74.96,116.26 73.97,117.25 52.22,117.25 51.71,116.74 50.66,116.74 49.77,115.85 36.47,115.85 36.06,116.26 33.64,116.26 32.89,115.52 30.29,115.52 29.59,116.22 v2(29.59,116.33)
  BOTTOM w0.114: v1(30.23,116.97) 29.81,116.97 29.59,116.74 v2(29.59,116.33) 29.54,116.28 R437.1
XDP_NOA11_PCH: length 67.6
  TOP w0.114: v2(80.34,104.55) 81.03,103.86 R115.1 ; CONN4.18 28.82,115.51 28.3,116.03 v2(27.91,116.03)
  S10 w0.102: v2(27.91,116.03) 29.11,114.83 33.54,114.83 35.09,113.28 48.5,113.28 51.03,115.82 52.09,115.82 52.6,116.33 72.02,116.33 75.51,112.84 75.51,112.24 76.33,111.43 76.6,111.43 77.24,110.79 77.24,110.04 78.79,108.49 78.79,106.1 v2(80.34,104.55)
  BOTTOM w0.114: v1(27.59,115.06) R436.1 28.63,115.32 v2(27.91,116.03)
XDP_NOA14_PCH: length 56.1
  TOP w0.114: CONN4.34 24.82,112.9 v2(24.89,112.83)
  S10 w0.102: v2(24.89,112.83) 25.35,112.37 26.19,112.37 27.39,113.57 33.83,113.57 34.81,112.6 48.81,112.6 51.27,115.05 56.58,115.05 56.71,114.92 58.7,112.93 60.87,112.93 61.47,113.53 61.47,113.55 62.32,114.4 64.49,114.4 65,114.91 70.37,114.91 71.93,113.35 71.93,113.21 v2(72.26,112.88)
  BOTTOM w0.114: v2(24.89,112.83) 23.95,111.89 v1(23.8,111.89) ; R444.1 v2(72.26,112.88)
XDP_PCH_CPU_PWRGD: length 360.2
  TOP w0.114: U12.M6 v3(193.09,50.61) ; CONN4.46 21.82,112.5 v2(23.14,111.18) R56.1
  S3 w0.102: v3(193.09,50.61) 192.63,51.06 192.63,51.64 192.26,52.02 189.28,52.02 187.22,49.96 187.22,45.97 185.47,44.21 185.47,37.17 171.4,23.09 171.4,11.15 166.76,6.51 166.76,4.09 165.16,2.49 161.93,2.49 161.58,2.84 159.6,2.84 158.54,1.78 128.63,1.78 127.57,2.84 125.82,2.84 125.77,2.79 124.06,2.79 123.84,3.01 123.46,3.01 123.18,2.73 122.58,2.73 120.66,4.65 103.91,4.65 103.48,4.22 97.9,4.22 92.87,9.24 88.18,9.24 80.84,1.91 75.49,1.91 74.65,2.74 73.02,2.74 72.15,1.88 61.79,1.88 59.88,3.78 56.14,3.78 55.12,4.8 51.92,4.8 49.23,7.49 48.41,7.49 47.98,7.92 41.64,7.92 40.73,8.84 31.14,8.84 30.83,8.53 20.7,8.53 17.98,11.25 10.92,11.25 3.94,18.23 3.94,22.43 2.41,23.95 2.41,106.67 7.95,112.21 22.11,112.21 v2(23.14,111.18)
  BOTTOM w0.114: v1(22.05,109.91) 22.05,110.08 v2(23.14,111.18)
XDP_PCH_PWRBTN_N: length 18.3
  TOP w0.114: CONN4.41 22.82,121.66 22.58,121.89 v2(22.56,121.89)
  S5 w0.102: v2(10.43,119.79) 12.96,122.31 22.14,122.31 v2(22.56,121.89)
  BOTTOM w0.114: v2(22.56,121.89) 22.48,121.82 R423.1 ; v2(10.43,119.79) 10.53,119.69 v1(11.72,119.69)
XDP_PCH_PWRGD: length 361.2
  TOP w0.114: U12.N5 v3(192.09,49.61)
  S3 w0.102: v2(23.19,122.17) 22.96,122.4 13.89,122.4 v2(10.32,118.83) 10.32,115.32 1.96,106.96 1.96,23.76 3.48,22.24 3.48,18.03 10.72,10.79 11.45,10.79 11.45,10.79 17.79,10.79 20.51,8.07 31.02,8.07 31.33,8.38 40.52,8.38 41.71,7.2 41.71,6.87 41.97,6.6 42.37,6.6 43.03,7.26 47.99,7.26 48.22,7.04 48.32,7.04 49.53,5.83 49.53,5.32 50.51,4.34 54.93,4.34 55.95,3.33 57.05,3.33 58.96,1.42 81.01,1.42 88.37,8.78 92.68,8.78 97.71,3.76 103.67,3.76 104.1,4.19 106.72,4.19 109.57,1.34 124.97,1.34 126.01,2.38 127.38,2.38 128.44,1.32 158.73,1.32 159.79,2.38 161.39,2.38 161.74,2.03 166.33,2.03 167.29,3 167.29,6.39 171.86,10.96 171.86,22.9 185.93,36.98 185.93,43.96 187.68,45.71 187.68,47.81 189.91,50.04 191.66,50.04 v3(192.09,49.61)
  BOTTOM w0.114: v2(23.19,122.17) 23.42,121.95 R424.2
XDP_PCH_PWRGD_R: length 6.9
  TOP w0.114: v2(23.47,117.73) 23.32,117.88 CONN4.39
  BOTTOM w0.114: v1(21.93,115.52) 21.93,116.19 v2(23.47,117.73) 23.42,117.78 R424.1
XDP_PCH_RSMRST: length 361.6
  TOP w0.114: v2(21.52,117.27) 21.32,117.47 CONN4.47 ; v3(193.05,49.54) 193.05,49.54 193.59,50.08 U12.N6
  S3 w0.102: v2(21.52,117.27) 21.08,117.7 13.13,117.7 2.18,106.76 2.18,23.86 3.71,22.33 3.71,18.14 10.82,11.02 11.35,11.02 17.88,11.02 20.61,8.3 30.92,8.3 31.24,8.61 40.63,8.61 41.55,7.7 47.88,7.7 48.31,7.26 49.13,7.26 51.82,4.57 55.03,4.57 56.04,3.56 59.79,3.56 61.69,1.65 80.91,1.65 88.27,9.01 92.78,9.01 97.8,3.99 103.57,3.99 104,4.42 106.82,4.42 109.67,1.57 124.88,1.57 125.92,2.61 127.47,2.61 128.54,1.55 158.64,1.55 159.7,2.61 161.48,2.61 161.84,2.26 165.26,2.26 166.99,3.99 166.99,6.42 171.63,11.06 171.63,23 185.7,37.07 185.7,44.12 187.45,45.87 187.45,49.87 188.58,50.99 192.25,50.99 192.66,50.58 192.66,49.94 v3(193.05,49.54)
  BOTTOM w0.114: R422.1 v2(21.52,117.27) 20.8,116.56 20.8,115.66 v1(20.66,115.52)
XDP_PCH_SCL: length 26.7
  TOP w0.114: v2(38.4,2.08) 37.89,2.6 CONN11.53
  S3 w0.102: v2(38.4,2.08) 37.67,1.35 24.45,1.35 23.36,2.44 23.36,6.54 v2(22.93,6.97)
  BOTTOM w0.114: R763.1 38.46,2.13 v2(38.4,2.08) ; v2(22.93,6.97) 23.69,6.21 v1(25.99,6.21)
XDP_PCH_SDA: length 23.5
  TOP w0.114: v2(37.57,2.08) 37.39,2.26 CONN11.51
  S3 w0.102: v2(24.14,7.02) 23.59,6.47 23.59,2.53 24.55,1.58 37.06,1.58 v2(37.57,2.08)
  BOTTOM w0.114: v2(24.14,7.02) 25.15,8.03 v1(25.2,8.03) ; v2(37.57,2.08) 37.54,2.11 R762.1
XDP_PCH_SYSRST_N: length 356.6
  TOP w0.114: CONN11.48 36.39,10.93 35.38,11.94 28.75,11.94 v2(28.63,11.81) ; CONN4.48 21.31,114.41 21.31,111.84 v2(22.07,111.07) R55.1 ; U12.M11 v3(199.09,50.61)
  S3 w0.102: v2(100.91,14.07) 98.09,11.25 88.57,11.25 81.28,3.96 66.25,3.96 65.75,4.47 56.62,4.47 55.47,5.62 55.47,5.86 54.96,6.38 53.84,6.38 52.11,8.11 49.27,8.11 48.88,7.72 48.5,7.72 48.07,8.15 41.74,8.15 40.16,9.73 31.37,9.73 30.12,10.97 30.12,11.09 29.4,11.81 v2(28.63,11.81)
  S8 w0.102: v3(199.09,50.61) 198.63,50.15 198.63,48.54 198.08,47.99 197.95,47.99 197.64,47.67 197.64,44.92 197.82,44.74 197.82,44.26 197.44,43.88 196.39,43.88 188.87,36.37 188.87,31.21 183.19,25.53 179.18,25.53 174.25,20.6 172.58,20.6 172.16,21.02 169.36,21.02 168.94,20.6 163.68,20.6 162.74,19.66 153.2,19.66 147.48,13.94 143.61,13.94 141.88,15.67 125.8,15.67 125.5,15.98 105.78,15.98 105.48,15.67 102.51,15.67 v2(100.91,14.07)
  S10 w0.102: v2(22.07,111.07) 18.14,111.07 16.92,109.86 16.92,105.37 19.89,102.4 19.89,100.61 30.91,89.59 30.91,89.14 31.11,88.93 31.11,81.43 31.29,81.26 31.29,80.54 31.11,80.36 31.11,69.34 29.72,67.94 27.81,67.94 27.33,67.46 27.33,67.35 27.05,67.07 26.8,67.07 26.34,66.61 26.34,65.47 26.66,65.15 27.28,65.15 27.71,64.72 27.71,62.1 28.73,61.09 29.41,61.09 30.18,60.33 30.18,58.28 28.63,56.73 28.63,54.41 26.42,52.2 21.77,52.2 20.62,51.05 20.62,49.48 10.39,39.24 10.39,19.38 17.83,11.94 28.5,11.94 v2(28.63,11.81)
XDP_PCH_TCK0: length 80.6
  TOP w0.114: v2(18.25,117.07) 18.82,117.64 CONN4.57
  S10 w0.102: v2(78.79,104.14) 77.8,104.14 76.96,104.97 76.96,105.61 75.84,106.72 75.84,109.38 74.57,110.65 74.57,111.35 73.5,112.42 72.07,112.42 71.68,112.82 71.68,113.28 70.98,113.98 67.09,113.98 67.08,113.97 64.9,113.97 64.7,114.17 63.45,114.17 62.59,113.31 61.67,113.31 61.06,112.7 58.79,112.7 58.6,112.7 56.48,114.82 51.36,114.82 48.91,112.37 34.71,112.37 33.74,113.34 27.62,113.34 26.42,112.14 20.86,112.14 18.25,114.75 v2(18.25,117.07)
  BOTTOM w0.114: R417.1 v1(18.71,117.93) 18.71,117.88 18.25,117.42 v2(18.25,117.07) ; R476.1 v2(78.79,104.14)
XDP_PCH_TDI: length 75.8
  TOP w0.114: CONN4.56 v2(19.32,111.63) 19.46,111.49 R60.1 ; R116.2 v2(76.63,103.35)
  S10 w0.102: v2(19.32,111.63) 24.87,111.63 25.27,111.23 33.15,111.23 33.5,110.87 48.06,110.87 51.55,114.37 56.29,114.37 58.52,112.14 60.86,112.14 60.99,112.01 62.23,112.01 63.22,113 64.64,113 65.56,112.09 67.44,112.09 67.46,112.11 71.05,112.11 72.69,110.46 73.95,110.46 75.39,109.03 75.39,106.22 75.34,106.17 75.34,103.54 75.6,103.28 76.56,103.28 v2(76.63,103.35)
  BOTTOM w0.114: v2(19.32,111.63) 19.32,113.68 v1(20.04,114.4)
XDP_PCH_TDO: length 79.8
  TOP w0.114: R58.1 20.32,110.92 CONN4.52 20.32,115.72 21.06,116.46 v2(21.36,116.46) ; R88.1 v2(82.04,105.16)
  S10 w0.102: v2(21.36,116.46) 21.62,116.71 28.24,116.71 29.67,115.29 33.02,115.29 33.76,116.03 35.97,116.03 36.38,115.62 49.86,115.62 50.75,116.51 51.8,116.51 52.31,117.02 73.87,117.02 74.87,116.03 75.15,116.03 76.32,114.86 76.67,114.86 77.17,114.36 77.17,113.39 79.6,110.95 79.6,109.77 81.46,107.92 81.46,105.74 v2(82.04,105.16)
  BOTTOM w0.114: v1(21.31,114.4) 21.31,116.41 v2(21.36,116.46)
XDP_PCH_TMS: length 83.7
  TOP w0.114: v2(20.27,116.48) 19.36,116.48 18.82,115.94 CONN4.58 18.82,112.34 17.75,111.28 R59.1 ; R106.2 83.49,104.14 v2(83.06,103.71)
  S10 w0.102: v2(20.27,116.48) 20.75,116 22.35,116 22.83,116.48 28.14,116.48 29.57,115.06 33.64,115.06 35.19,113.51 48.4,113.51 50.94,116.05 51.99,116.05 52.5,116.56 73.29,116.56 74.07,115.78 74.07,114.63 75.76,112.93 75.76,112.32 76.42,111.66 76.7,111.66 77.47,110.89 77.47,110.13 81,106.6 81,104.84 82.13,103.71 v2(83.06,103.71)
  BOTTOM w0.114: v2(20.27,116.48) 19.39,115.61 v1(19.39,115.52)
XDP_PCU_SCL: length 8.5
  TOP w0.114: CONN4.53 19.81,120.15 19.81,121.21 19.75,121.27 19.75,121.41 19.57,121.6 19.53,121.6 19.33,121.79 v2(19.25,121.79)
  BOTTOM w0.114: v1(16.99,119.42) 16.99,121.59 17.5,122.09 18.95,122.09 v2(19.25,121.79) 19.25,121.18 19.66,120.78 R425.1
XDP_SC_PWRGD_R: length 6.6
  TOP w0.114: CONN11.39 34.39,5 v2(33.83,5.56)
  BOTTOM w0.114: R754.1 33.83,4.68 v2(33.83,5.56) 33.83,5.88 31.72,7.99 v1(31.72,8.38)
N21811685: length 6.5
  TOP w0.114: v2(131.14,81.03) 131.15,81.04 LED18.C
  BOTTOM w0.114: v2(131.14,81.03) 131.14,81.53 v1(130.71,81.97) 130.18,82.5 130.18,84.45 130.43,84.71 R868.2
N22142198: length 13
  BOTTOM w0.114: CONN14.53 23.41,63.08 24,63.67 24.2,63.67 25.37,64.85 26.92,64.85 27.02,64.95 27.32,64.95 27.95,65.58 27.95,69.3 v1(28.47,69.82) 28.47,69.95 R1056.1

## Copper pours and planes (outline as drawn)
AGND_V3P3 on S8: 147.07,32.28 147.6,31.75 157.45,31.75 157.68,31.98 157.68,39.17 157.25,39.6 147.55,39.6 147.07,39.12
AGND_VDDQ on S10: 50.72,16.31 58.39,16.31 59.87,14.83 59.87,4.52 59.4,4.05 50.68,4.05 50.29,4.44 50.29,5.13 50.7,5.54 51.65,5.54 52.06,5.95 52.06,8.03 51.7,8.39 51.21,8.39 50.22,9.38 50.22,15.8
GND on TOP (solid shape): 57.88,22.41 56.88,22.41 56.88,21.57 54.3,21.57 54.3,23.01 57.88,23.01
GND on TOP (solid shape): 73.09,21.7 72.09,21.7 72.09,20.85 67.58,20.85 67.58,22.3 73.09,22.3
GND on TOP (solid shape): 87.46,21.9 86.47,21.9 86.47,21.06 81.96,21.06 81.96,22.5 87.46,22.5
GND on TOP (solid shape): 47.98,14.38 47.98,12.65 47.47,12.14 41.53,12.14 41.1,12.57 41.1,14.55 41.5,14.96 47.4,14.96
GND on TOP (solid shape): 207.58,91.31 207.58,87.03 207.3,86.75 205.04,86.75 204.82,86.97 204.82,91.2 205.3,91.68 207.2,91.68
GND on TOP (solid shape): 102.11,25.78 104.65,25.78 104.9,25.53 106.55,25.53 106.81,25.27 109.09,25.27 109.6,24.77 109.6,23.5 110.36,22.73 113.92,22.73 114.43,22.23 114.43,21.07 114.85,20.64 120.36,20.64 120.36,20.04 119.36,20.04 119.36,19.2 103.99,19.2 101.41,21.78 99.83,21.78 98.91,22.7 98.14,22.7 96.04,24.8 96.04,26.42 96.65,27.03 100.86,27.03
GND on TOP (solid shape): outline of 171 points within 0.28,0.28 209.73,123.22
GND on BOTTOM (solid shape): 82.93,22.99 86.79,22.99 86.94,22.83 86.94,21.87 85.98,20.9 83.21,20.9 82.55,21.56 80.72,21.56 80.64,21.64 80.64,23.09 80.82,23.27 82.65,23.27
GND on BOTTOM (solid shape): 185.67,123.22 209.68,123.22 209.73,123.16 209.73,0.36 209.65,0.28 0.33,0.28 0.3,0.29 0.29,0.3 0.28,0.33 0.28,0.91 126.04,0.91 126.54,0.41 127.29,0.41 127.74,0.86 128.55,0.86 128.86,0.55 159.15,0.55 159.46,0.86 159.98,0.86 160.44,0.41 161.18,0.41 161.68,0.91 185.09,0.91 207.85,0.91 208.33,1.4 208.33,69.42 208.87,69.96 208.87,72.23 208.33,72.77 208.33,106.64 209.32,107.64 209.32,109.37 209.32,109.37 209.32,109.65 206.09,112.88 206.09,115.85 206.27,116.03 207.5,116.03 208.33,116.86 208.33,122.02 207.77,122.58 188.15,122.58 188.03,122.46 188.03,122.08 187.93,121.98 187.55,121.98 187.47,122.05 187.47,122.47 187.36,122.58 185.09,122.58 185.09,122.59 180.87,122.59 180.76,122.48 180.76,122.02 180.74,121.99 180.34,121.99 180.29,122.04 180.29,122.44 180.14,122.59 0.91,122.59 0.91,0.91 0.28,0.91 0.28,123.17 0.29,123.2 0.3,123.21 0.33,123.22 185.67,123.22
GND on S3 (solid shape): outline of 84 points within 0.28,0.28 209.73,123.22
GND on S5 (solid shape): outline of 84 points within 0.28,0.28 209.73,123.22
GND on S8 (solid shape): outline of 84 points within 0.28,0.28 209.73,123.22
GND on S10 (solid shape): outline of 84 points within 0.28,0.28 209.73,123.22
GND on TOP: 172.87,51.31 172.87,53.29 173.05,53.47 177.83,53.47 177.98,53.31 177.98,50.55 177.65,50.22 177.09,50.22 177.04,50.27 177.04,51.08 176.89,51.23 172.95,51.23
GND on TOP: 187.19,116.76 189.69,116.76 190.15,116.3 190.15,112.83 189.69,112.38 187.61,112.38 186.82,113.17 186.82,116.39
GND on TOP: 162.66,14.61 166.93,14.61 167.97,13.56 167.97,8.2 167.74,7.98 162.71,7.98 162.36,8.33 162.36,14.3
GND on TOP: 44.88,27.53 53.95,27.53 54.46,27.03 54.46,25.35 52.73,23.62 48.74,23.62 48.26,23.14 48.26,22.15 47.73,21.62 44.63,21.62 43.97,22.28 43.97,26.62
GND on TOP: outline of 184 points within 78.41,55.6 94.23,77.28
GND on TOP: 154.68,42.11 154.68,37.67 154.18,37.16 145.19,37.16 144.6,37.74 144.6,39.7 144.86,39.95 147.93,39.95 148.16,39.73 149.15,39.73 149.25,39.83 152.91,39.83 153.29,40.21 153.29,42.11 153.41,42.24 154.56,42.24
GND on TOP: 172.95,65.13 178.08,65.13 178.33,64.87 178.33,62.26 177.88,61.8 177.09,61.8 176.99,61.9 176.99,62.69 176.83,62.84 173.02,62.84 172.82,63.04 172.82,65
GND on TOP: 73.58,10.62 77.24,10.62 77.29,10.57 77.29,8.41 77.47,8.23 78.31,8.23 78.33,8.2 78.33,7.62 78.31,7.59 77.42,7.59 77.32,7.49 77.32,6.86 77.27,6.81 73.56,6.81 73.51,6.86 73.51,10.54
GND on TOP: 31.67,23.37 31.67,20.57 31.52,20.42 28.98,20.42 28.75,20.65 28.75,22.53 28.4,22.89 26.82,22.89 26.72,22.99 26.72,26.77 26.97,27.03 33.83,27.03 34.16,26.7 34.16,24.97 33.66,24.46 32.77,24.46
GND on TOP: 76.62,56.58 76.63,56.59 76.63,56.96 77.11,57.44 77.4,57.44 77.58,57.26 77.58,57.05 77.81,56.82 78.08,56.82 78.36,57.1 78.36,58.32 79.35,59.31 79.73,59.31 79.98,59.05 79.98,58.17 79.86,58.04 79.48,58.04 79.25,57.81 79.25,57.1 79.71,56.64 79.71,55.75 79.5,55.55 76.83,55.55 76.62,55.76
GND on TOP: 114.43,105.03 119.46,105.03 119.86,104.62 119.86,103.05 119.13,102.31 114.66,102.31 114.27,102.69 114.27,104.88
GND on TOP: 22.86,38.73 28.14,38.73 28.75,38.13 28.75,33.32 28.42,32.99 23.19,32.99 22.63,33.55 22.63,38.51
GND on TOP: 59.99,8.18 59.99,4.55 59.84,4.39 58.17,4.39 58.04,4.27 58.04,3.43 57.96,3.35 56.57,3.35 56.49,3.43 56.49,4.22 56.34,4.37 56.21,4.37 56.11,4.47 56.11,8.2 56.21,8.31 59.87,8.31
GND on TOP: 115.52,41.81 115.67,41.96 116.56,41.96 116.89,42.29 116.89,43.76 117.02,43.89 118.24,43.89 118.87,43.26 118.87,42.01 118.24,41.38 116.92,41.38 116.76,41.22 116.76,38.63 116.61,38.48 115.6,38.48 115.52,38.56
GND on TOP: 67.54,16.71 64.82,16.71 64.57,16.46 64.57,13.61 64.87,13.31 66.65,13.31 66.85,13.51 66.85,15.52 67.13,15.8 67.69,15.8 67.69,16.56
GND on TOP: 172.11,99.19 173.56,99.19 173.74,99.01 173.74,94.87 173.1,94.23 171.55,94.23 170.74,95.05 170.74,98.12 170.87,98.25 171.86,98.25 171.96,98.35 171.96,99.03
GND on TOP: 74.88,47.73 87.71,47.73 88.8,46.63 88.8,41.25 87.93,40.39 79.83,40.39 78.36,38.91 73.79,38.91 72.64,37.77 70.38,37.77 69.34,38.81 69.34,44.27 67.34,46.28 67.34,47.4 66.19,48.54 66.19,51.64 67.18,52.63 72.69,52.63 73.23,52.1 73.23,49.38
GND on TOP: 111.02,56.31 111.02,56.59 111.12,56.69 111.89,56.69 112.57,57.38 112.9,57.38 112.93,57.35 112.93,57.07 113.13,56.87 113.87,56.87 114.38,56.36 114.38,53.54 114,53.16 113.13,53.16 112.52,53.77 112.52,55.19 112.22,55.5 112.09,55.62 110.54,55.62 110.41,55.75 110.41,56.06 110.46,56.11 110.82,56.11
GND on TOP: 57.94,18.52 57.94,17.07 57.84,16.97 57.2,16.97 57.05,17.12 57.05,18.54 57.12,18.62 57.84,18.62
GND on TOP: outline of 86 points within 74.98,75.46 92.3,96.17
GND on TOP: 157.33,68.68 157.33,76.25 158.17,77.09 163.63,77.09 163.83,76.89 163.83,75.64 163.65,75.46 160.6,75.46 160.05,74.9 160.05,69.44 160.17,69.32 162.28,69.32 162.36,69.24 162.36,65.68 162.03,65.35 151.87,65.35 151.41,65.81 151.41,67.06 151.79,67.44 156.08,67.44
GND on TOP: 114.68,13.54 114.68,9.68 114.35,9.35 110.72,9.35 110.49,9.58 110.49,14.94 110.66,15.1 114.41,15.1 114.66,14.86 114.66,13.56
GND on TOP: 134.75,58.37 134.49,58.12 134.49,54.31 134.98,53.82 138.68,53.82 138.81,53.95 138.81,58.24 138.68,58.37
GND on TOP: 177.47,104.57 180.04,104.57 180.34,104.27 180.34,100.15 179.81,99.62 178.03,99.62 177.85,99.8 177.85,100.63 177.67,100.81 176.96,100.81 176.83,100.94 176.83,103.17 177.06,103.4 177.06,104.17
GND on TOP: 59.54,19.2 59.54,18.19 59.39,18.03 58.85,18.03 58.62,18.26 58.62,18.44 58.45,18.62 58.32,18.62 58.22,18.72 58.22,19.56 58.32,19.66 59.08,19.66
GND on TOP: 138.58,91.31 142.01,91.31 142.54,90.78 142.54,87.17 142.34,86.97 138.96,86.97 138.15,87.78 138.15,90.88
GND on TOP: 98.73,74.17 98.74,74.18 98.74,79.22 98.9,79.38 99,79.38 99.42,78.97 99.42,78.61 99.29,78.49 99.29,78.28 99.67,77.9 99.67,77.65 99.85,77.47 100.28,77.47 100.43,77.62 100.43,77.9 100.05,78.28 100.05,78.59 100.13,78.67 100.73,78.67 100.99,78.41 100.99,77.27 101.83,76.43 101.83,69.57 101.6,69.34 100.86,69.34 100.51,69.7 98.93,69.7 98.73,69.9
GND on TOP: 39.47,109.32 43.74,109.32 43.75,109.31 45.12,109.31 45.87,108.56 45.87,106.32 45.54,105.99 39.52,105.99 39.32,106.2 39.32,109.17
GND on TOP: 126.7,65.94 129.95,65.94 130.81,65.07 131.9,65.07 132.08,64.9 132.08,63.58 131.95,63.45 128.27,63.45 127.91,63.8 126.36,63.8 126.31,63.86 126.31,65.56
GND on TOP: 22.25,106.1 27.66,106.1 28.09,105.66 28.09,101.57 27.53,101.02 22.2,101.02 21.69,101.52 21.69,105.54
GND on TOP: 172.9,72.4 178.03,72.4 178.28,72.14 178.28,69.53 177.83,69.07 177.04,69.07 176.96,69.14 176.96,70.03 176.88,70.11 172.97,70.11 172.77,70.31 172.77,72.27
GND on TOP: 126.82,108.15 124.31,108.15 124.03,108.44 124.03,111.31 123.63,111.7 122.03,111.7 121.97,111.76 121.97,114.53 122.73,115.29 126.7,115.29 127.33,114.66 127.33,113.9 127.49,113.74 130.39,113.74 130.51,113.63 130.51,113.18 130.31,112.99 127.36,112.99 127.09,112.72 127.09,108.43
GND on TOP: 143.26,57.33 142.49,56.57 142.49,49.23 141.94,48.67 139.37,48.67 139.09,48.95 139.09,59.46 139.7,60.07 167.23,60.07 168.88,58.42 168.88,52.86 168.28,52.25 166.12,52.25 165.46,52.91 165.46,56.39 164.52,57.33
GND on TOP: 32.16,34.21 38.56,34.21 39.37,33.4 39.37,31.06 39.09,30.78 35.15,30.78 33.45,32.49 32.13,32.49 31.7,32.92 31.7,33.76
GND on TOP: 165.02,34.85 165.02,36.42 165.18,36.58 165.18,42.24 165.61,42.67 166.07,42.67 166.37,42.98 166.37,46.94 165.61,47.7 165.61,50.11 166.12,50.62 169.34,50.62 170.51,49.45 170.51,33.05 169.95,32.49 167.28,32.49 167.08,32.69 167.08,34.26 166.62,34.72 165.15,34.72
GND on TOP: 204.97,78.88 205.27,78.58 205.27,76.88 205.13,76.74 203.91,76.74 203.52,77.13 203.52,78.66 203.75,78.88
GND on TOP: 57.94,23.04 57.94,22.38 57.86,22.3 57.18,22.3 57.02,22.15 57.02,21.51 56.95,21.44 54.23,21.44 53.8,21.87 52.45,21.87 52.17,21.59 48.62,21.59 48.44,21.77 48.44,23.04 48.82,23.42 55.3,23.42 55.65,23.06 57.91,23.06
GND on BOTTOM: 157.58,16.15 165.71,16.15 166.32,15.54 166.32,13.59 165.51,12.78 163.09,12.78 161.82,14.05 159.44,14.05 159.28,13.89 159.28,13.36 159.16,13.23 157.56,13.23 157.4,13.39 157.4,15.98
